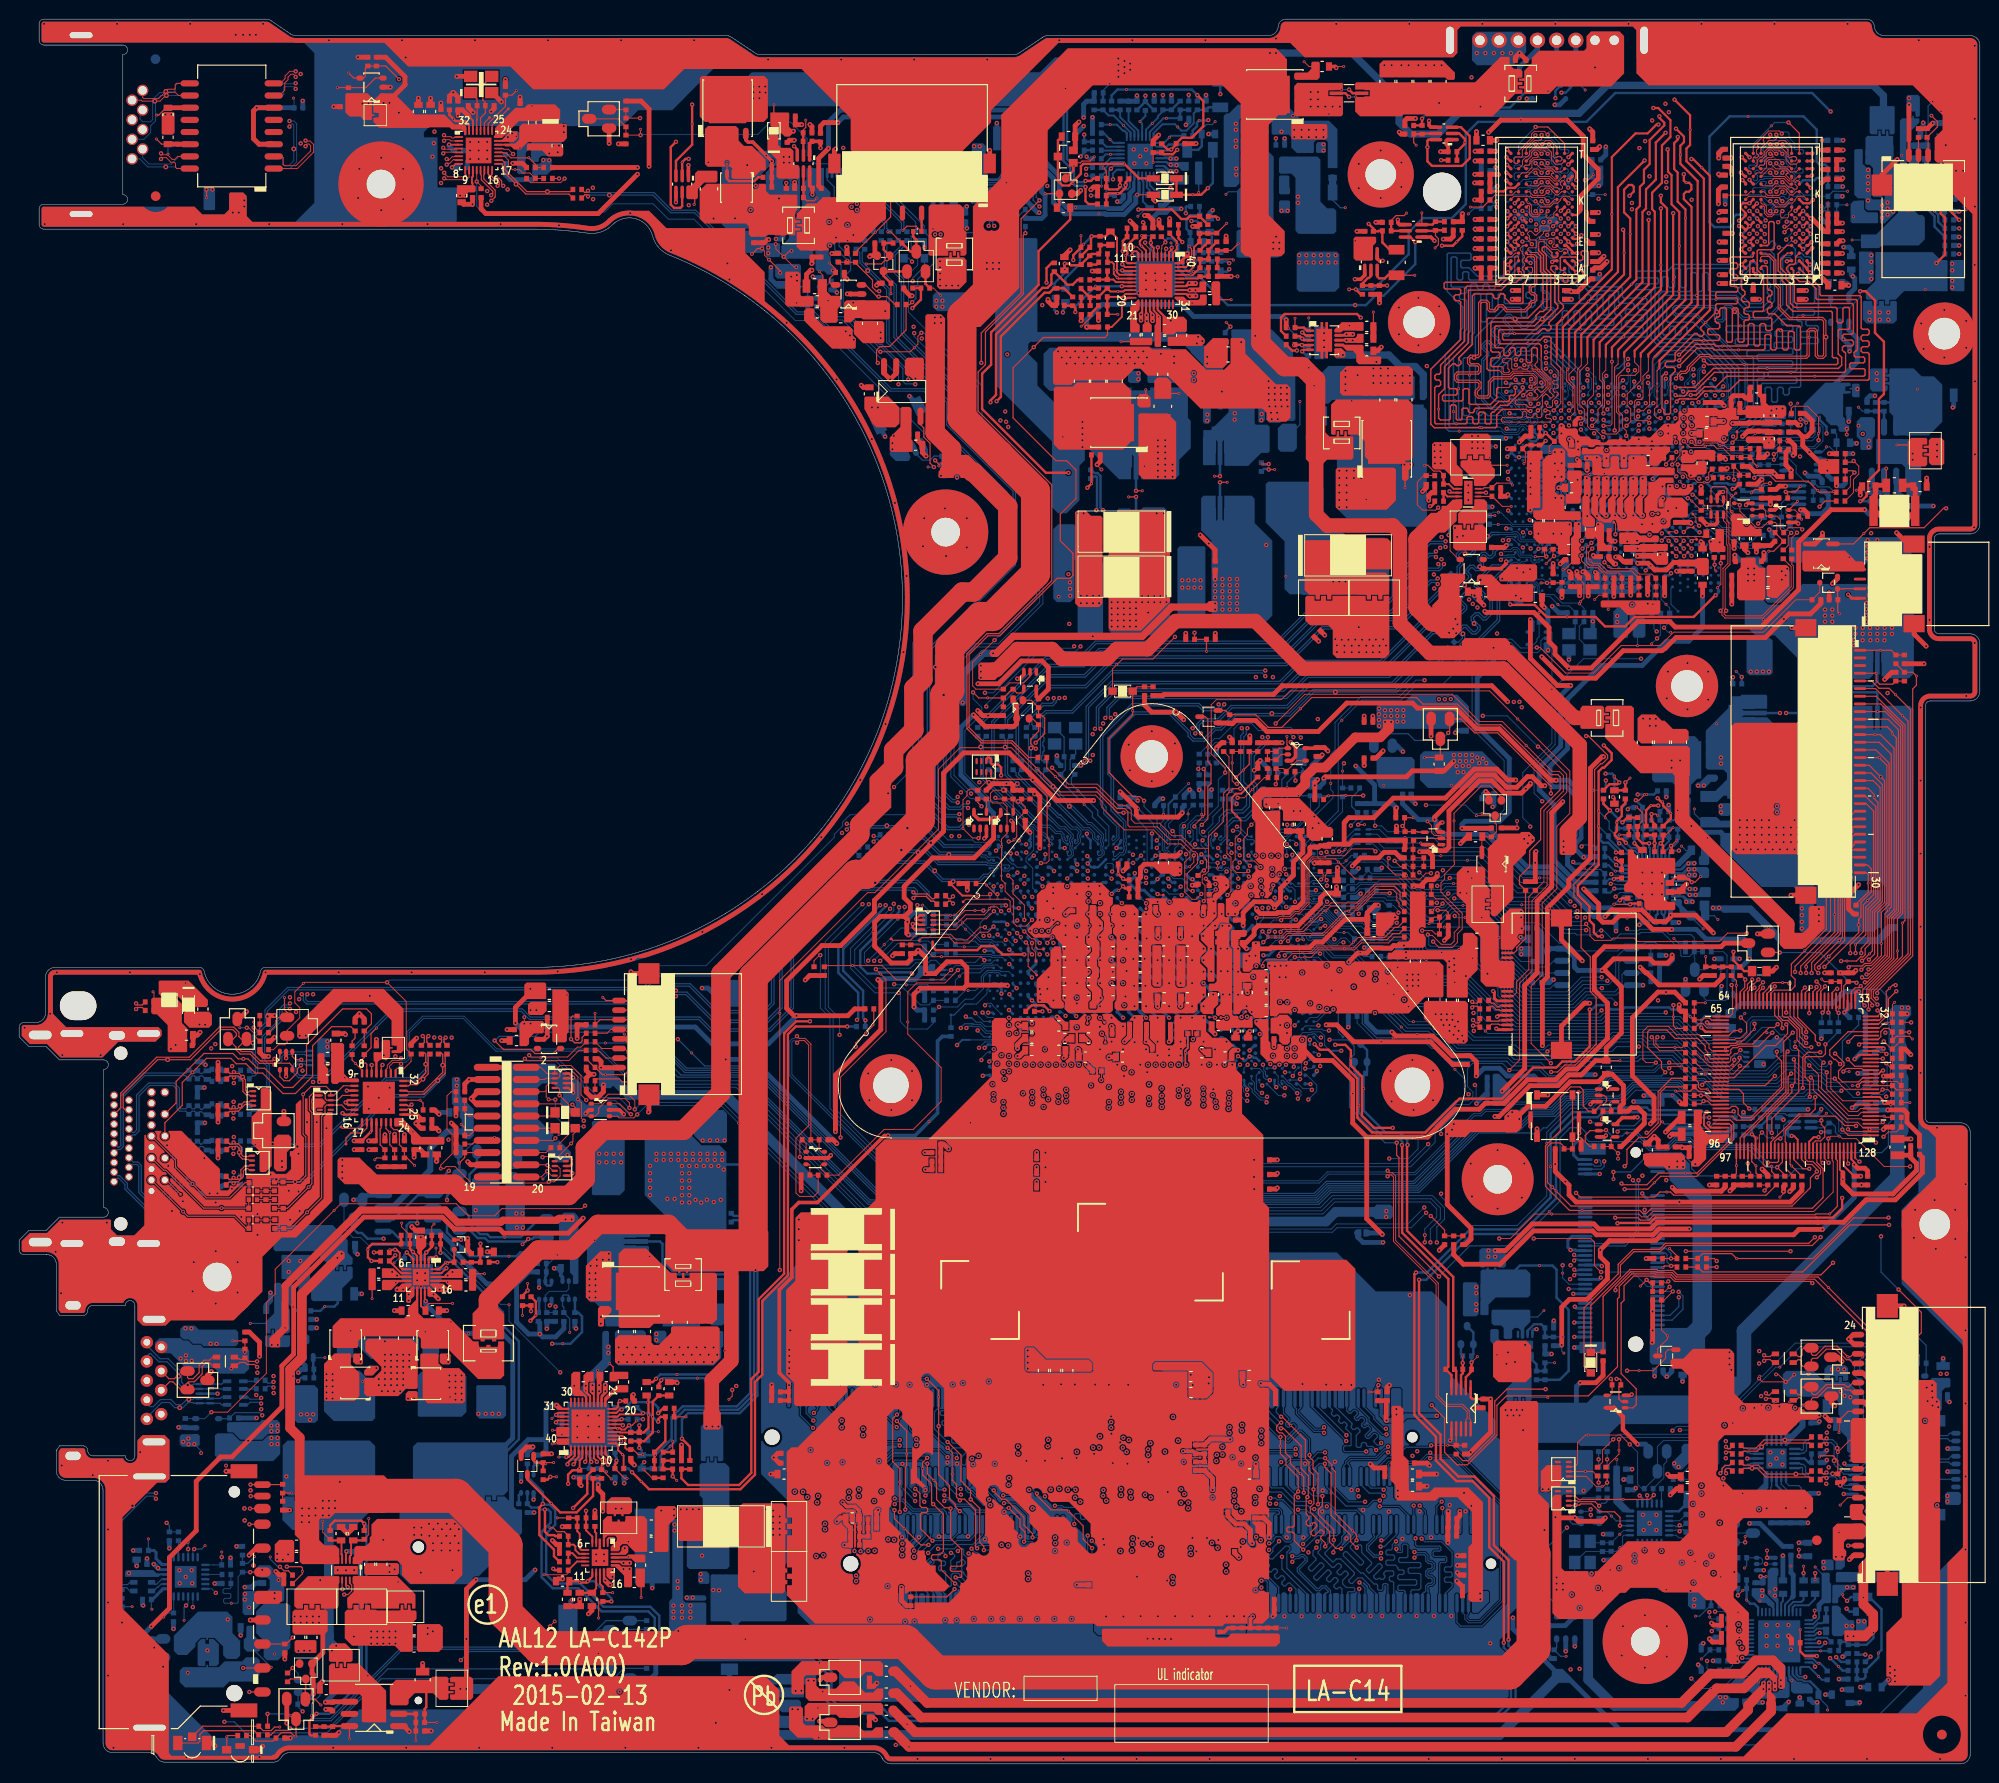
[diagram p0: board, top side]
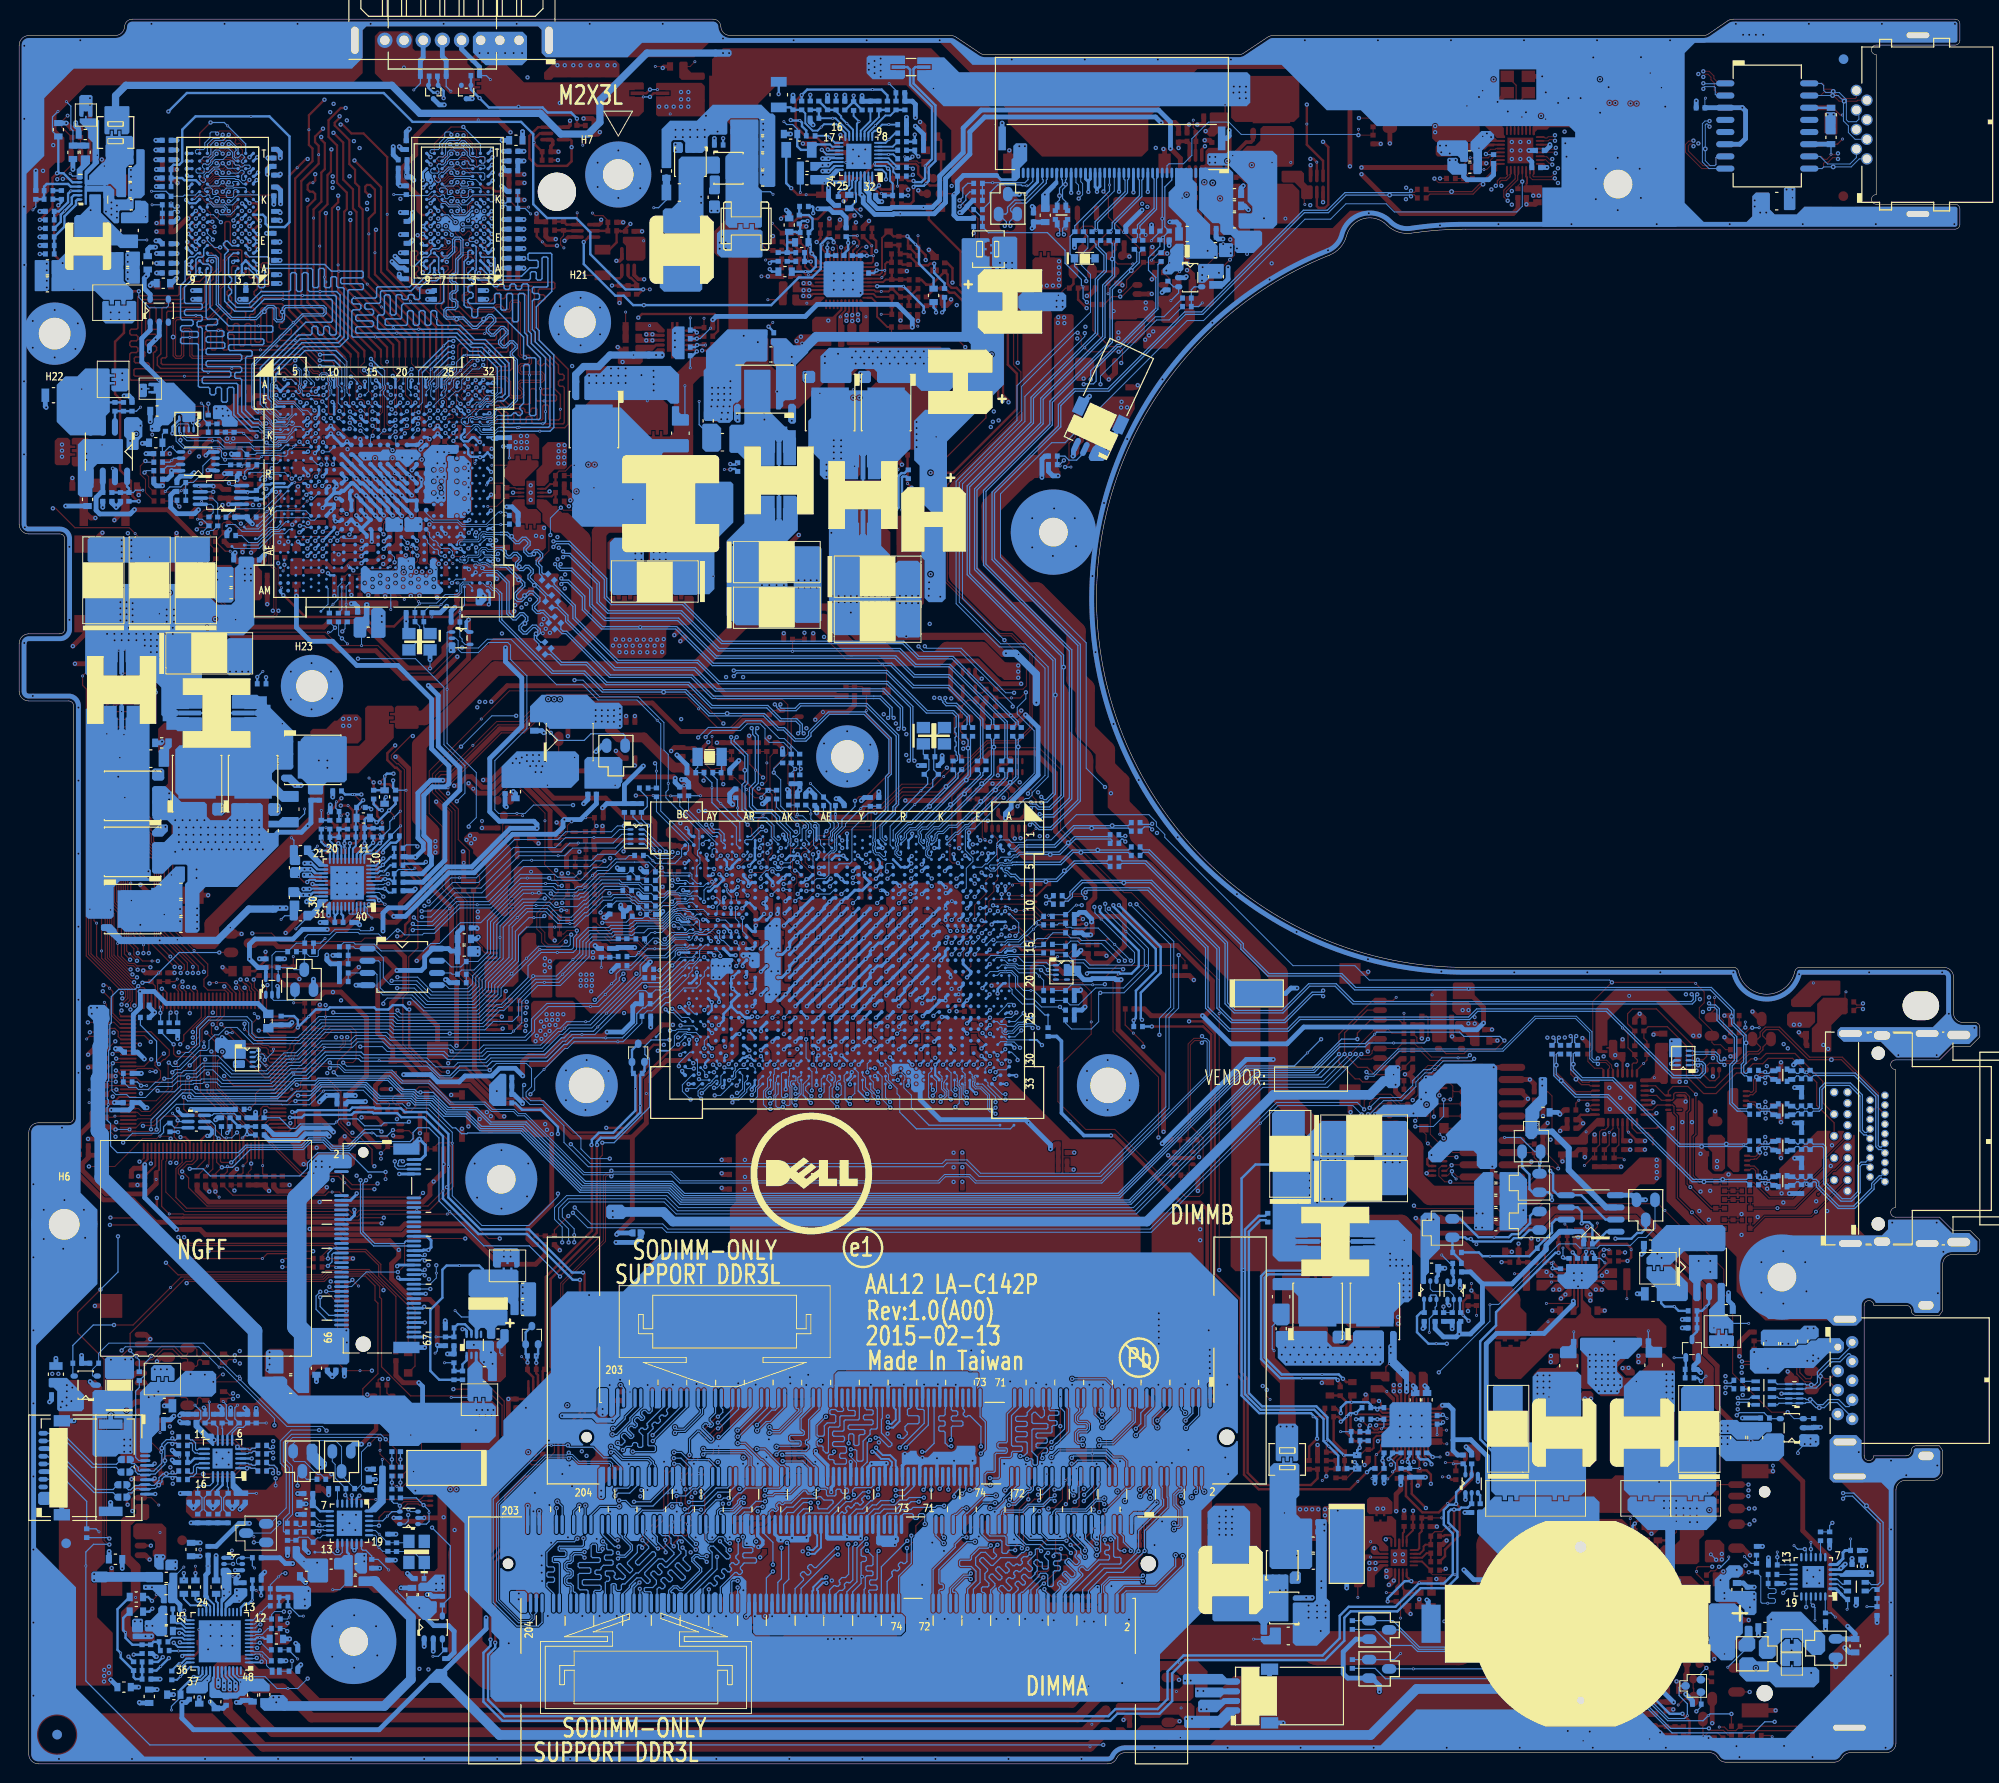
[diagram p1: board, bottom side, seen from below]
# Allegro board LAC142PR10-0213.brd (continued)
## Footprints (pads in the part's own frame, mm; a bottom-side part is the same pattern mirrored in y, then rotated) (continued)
ACES_50208-01001-001_10P
  oval 0.508x0.991 smd: 1(0,0) 2(0.8,0) 3(1.6,0) 4(2.4,0) 5(3.2,0) 6(4,0) 7(4.8,0) 8(5.6,0) 9(6.4,0) 10(7.2,0)
  rect 1.194x1.702 smd: 11(-1.3,-1.95) 12(8.5,-1.95)
ACES_50224-0030N-001_3P-T
  oval 0.61x1.549 smd: 1(0,0) 2(1,0) 3(2,0)
  rect 1.194x1.803 smd: 4(3.3,-3.875) 5(-1.3,-3.875)
ACES_50224-0040N-001_4P-T
  oval 0.61x1.549 smd: 1(0,0) 2(1,0) 3(2,0) 4(3,0)
  rect 1.194x1.803 smd: 5(-1.3,-3.875) 6(4.3,-3.875)
ACES_50458-00601-001_6P-T
  oval 0.559x1.6 smd: 1(0,0) 2(2,0) 3(4,0) 4(6,0) 5(8,0) 6(10,0)
  rect 1.295x2.057 smd: 7(-3.1,-5.175) 8(13.1,-5.175)
ACES_50524-00401-P01_4P
  oval 0.305x1.295 smd: 1(0,0) 2(1,0) 3(2,0) 4(3,0)
  rect 1.803x2.21 smd: 5(5.65,-5.65) 6(-2.65,-5.65)
ACES_51510-0304N-P01_30P
  oval 0.305x1.295 smd: 1(0,0) 2(0.8,0) 3(1.6,0) 4(2.4,0) 5(3.2,0) 6(4,0) 7(4.8,0) 8(5.6,0) 9(6.4,0) 10(7.2,0) 11(8,0) 12(8.8,0) 13(9.6,0) 14(10.4,0) 15(11.2,0) 16(12,0) 17(12.8,0) 18(13.6,0) 19(14.4,0) 20(15.2,0) 21(16,0) 22(16.8,0) 23(17.6,0) 24(18.4,0) 25(19.2,0) 26(20,0) 27(20.8,0) 28(21.6,0) 29(22.4,0) 30(23.2,0)
  rect 1.803x2.21 smd: 31(25.55,-5.65) 32(-2.35,-5.65)
ACES_51519-02001-001_20P-T
  oval 0.305x1.295 smd: 1(0,0) 2(0.5,0) 3(1,0) 4(1.5,0) 5(2,0) 6(2.5,0) 7(3,0) 8(3.5,0) 9(4,0) 10(4.5,0) 11(5,0) 12(5.5,0) 13(6,0) 14(6.5,0) 15(7,0) 16(7.5,0) 17(8,0) 18(8.5,0) 19(9,0) 20(9.5,0)
  rect 1.803x2.21 smd: 21(11.65,-5.65) 22(-2.15,-5.65)
ACES_51524-0240N-001_24P
  oval 0.61x1.295 smd: 1(0,0) 2(1,0) 3(2,0) 4(3,0) 5(4,0) 6(5,0) 7(6,0) 8(7,0) 9(8,0) 10(9,0) 11(10,0) 12(11,0) 13(12,0) 14(13,0) 15(14,0) 16(15,0) 17(16,0) 18(17,0) 19(18,0) 20(19,0) 21(20,0) 22(21,0) 23(22,0) 24(23,0)
  rect 2.489x2.21 smd: 25(-3,-3.05) 26(26,-3.05)
ACES_51540-04001-P01_40P-T
  oval 0.305x1.092 smd: 1(0,0) 2(0.5,0) 3(1,0) 4(1.5,0) 5(2,0) 6(2.5,0) 7(3,0) 8(3.5,0) 9(4,0) 10(4.5,0) 11(5,0) 12(5.5,0) 13(6,0) 14(6.5,0) 15(7,0) 16(7.5,0) 17(8,0) 18(8.5,0) 19(9,0) 20(9.5,0) 21(10,0) 22(10.5,0) 23(11,0) 24(11.5,0) 25(12,0) 26(12.5,0) 27(13,0) 28(13.5,0) 29(14,0) 30(14.5,0) 31(15,0) 32(15.5,0) 33(16,0) 34(16.5,0) 35(17,0) 36(17.5,0) 37(18,0) 38(18.5,0) 39(19,0) 40(19.5,0)
  rect 0.787x2.489 smd: 41(21.2,-3.6) 42(-1.7,-3.6)
ACES_51625-01201-001_12P-T
  oval 0.305x1.092 smd: 1(0,0) 2(0.5,0) 3(1,0) 4(1.5,0) 5(2,0) 6(2.5,0) 7(3,0) 8(3.5,0) 9(4,0) 10(4.5,0) 11(5,0) 12(5.5,0)
  rect 0.991x2.489 smd: 13(7.3,-3.6) 14(-1.8,-3.6)
ADM1032ARMZ_MSOP8
  oval 0.381x1.626 smd: 1(0,0) 2(0.65,0) 3(1.3,0) 4(1.95,0) 5(1.95,4.3) 6(1.3,4.3) 7(0.65,4.3) 8(0,4.3)
ALC3234-CG_MQFN48_6X6
  oval 0.203x0.889 smd: 1(0,0) 2(0.4,0) 3(0.8,0) 4(1.2,0) 5(1.6,0) 6(2,0) 7(2.4,0) 8(2.8,0) 9(3.2,0) 10(3.6,0) 11(4,0) 12(4.4,0) 25(4.4,6.1) 26(4,6.1) 27(3.6,6.1) 28(3.2,6.1) 29(2.8,6.1) 30(2.4,6.1) 31(2,6.1) 32(1.6,6.1) 33(1.2,6.1) 34(0.8,6.1) 35(0.4,6.1) 36(0,6.1)
  oval 0.889x0.203 smd: 13(5.25,0.85) 14(5.25,1.25) 15(5.25,1.65) 16(5.25,2.05) 17(5.25,2.45) 18(5.25,2.85) 19(5.25,3.25) 20(5.25,3.65) 21(5.25,4.05) 22(5.25,4.45) 23(5.25,4.85) 24(5.25,5.25) 37(-0.85,5.25) 38(-0.85,4.85) 39(-0.85,4.45) 40(-0.85,4.05) 41(-0.85,3.65) 42(-0.85,3.25) 43(-0.85,2.85) 44(-0.85,2.45) 45(-0.85,2.05) 46(-0.85,1.65) 47(-0.85,1.25) 48(-0.85,0.85)
  rect 4.394x4.394 smd: 49(2.2,3.05)
AO3416_SOT23-3
  oval 1.016x1.524 smd: 1(0,0) 2(0.965,2.083) 3(-0.965,2.083)
AO4430L_SO8
  oval 0.635x1.854 smd: 1(0,0) 2(1.27,0) 3(2.54,0) 4(3.81,0) 5(3.81,5.165) 6(2.54,5.165) 7(1.27,5.165) 8(0,5.165)
AON6970_DFN5X6D-8-7
  oval 0.66x0.635 smd: 1(0,0) 3(3.81,5.67) 4(2.54,5.67) 5(1.27,5.67) 6(0,5.67)
  custom 0.485x0.485 smd: 2(1.905,0.655)
  rect 3.988x2.667 smd: 7(1.905,3.62)
AP2138N-1P5TRG1_SOT23-3
  oval 1.016x1.524 smd: 1(0,0) 2(0.965,2.083) 3(-0.965,2.083)
APL3512ABI-TRG_SOT23-5
  oval 0.61x1.041 smd: 1(0,0) 2(0.95,0) 3(1.9,0) 4(1.9,2.7) 5(0,2.7)
APL5336KAI-TRL_SOP8P8
  oval 0.635x1.854 smd: 1(0,0) 2(1.27,0) 3(2.54,0) 4(3.81,0) 5(3.81,5.165) 6(2.54,5.165) 7(1.27,5.165) 8(0,5.165)
  rect 2.87x2.489 smd: 9(1.905,2.582)
APL5930KAI-TRG_SO8
  oval 0.635x1.854 smd: 1(0,0) 2(1.27,0) 3(2.54,0) 4(3.81,0) 5(3.81,5.165) 6(2.54,5.165) 7(1.27,5.165) 8(0,5.165)
  rect 2.87x2.489 smd: 9(1.905,2.582)
AZ5125-02SPR7G_SOT23-3
  oval 1.016x1.524 smd: 1(0,0) 2(0.965,2.083) 3(-0.965,2.083)
BAS40-04_SOT23-3
  oval 1.016x1.524 smd: 1(0,0) 2(0.965,2.083) 3(-0.965,2.083)
BAT54C-7-F_SOT23-3
  oval 1.016x1.524 smd: 1(0,0) 2(0.965,2.083) 3(-0.965,2.083)
C-K_80461-5K1-152_15P-T-S
  round 0.889 hole 0.61: 1(0,0) 2(2.29,0) 3(4.58,0) 4(6.87,0) 5(9.16,0) 6(-1.145,0) 7(1.145,0) 8(3.435,0) 9(5.725,0) 10(8.015,0) 11(0,1.4) 12(2.29,1.4) 13(4.58,1.4) 14(6.87,1.4) 15(9.16,1.4)
  oval 1.016x2.692 hole 0.711x2.388: 16(15.28,-8.3) 17(15.28,-0.3) 18(-6.62,-0.3) 19(-6.62,-8.3)
C-K_96067-3K28-192-124_19P-T
  round 1.397 hole 1.397 unplated: (-4.4,0.7) (13.4,0.7)
  round 0.813 hole 0.559: 1(0,0) 2(0.5,1.55) 3(1,0) 4(1.5,1.55) 5(2,0) 6(2.5,1.55) 7(3,0) 8(3.5,1.55) 9(4,0) 10(4.5,1.55) 11(5,0) 12(5.5,1.55) 13(6,0) 14(6.5,1.55) 15(7,0) 16(7.5,1.55) 17(8,0) 18(8.5,1.55) 19(9,0)
  oval 1.194x2.692 hole 0.889x2.388: 20(15.3,-7.7) 23(-6.3,-7.7)
  oval 1.194x2.007 hole 0.889x1.702: 21(15.25,0.3) 22(-6.25,0.3)
C_0402
  rect 0.508x0.559 smd: 1(0,0) 2(0.914,0)
C_0603
  rect 0.635x0.889 smd: 1(0,0) 2(1.397,0)
C_0805
  rect 0.813x1.397 smd: 1(0,0) 2(1.702,0)
C_1206
  rect 1.016x1.651 smd: 1(0,0) 2(2.667,0)
C_B15G
  rect 1.6x2.692 smd: 1(0,0) 2(3,0)
C_D2
  rect 2.388x2.794 smd: 1(0,0) 2(6.4,0)
C_D3
  rect 2.388x2.794 smd: 1(0,0) 2(6.4,0)
C_VSS330M1ETR-0604
  oval 3.505x1.6 smd: 1(0,0) 2(-5.4,0)
CHILI_SBY100505T-470Y-N_2P
  rect 0.457x0.508 smd: 1(0,0) 2(0.85,0)
CY7C65211-24LTXI_QFN24_4X4
  oval 0.254x0.889 smd: 1(0,0) 2(0.5,0) 3(1,0) 4(1.5,0) 5(2,0) 6(2.5,0) 13(2.5,4.1) 14(2,4.1) 15(1.5,4.1) 16(1,4.1) 17(0.5,4.1) 18(0,4.1)
  oval 0.889x0.254 smd: 7(3.3,0.8) 8(3.3,1.3) 9(3.3,1.8) 10(3.3,2.3) 11(3.3,2.8) 12(3.3,3.3) 19(-0.8,3.3) 20(-0.8,2.8) 21(-0.8,2.3) 22(-0.8,1.8) 23(-0.8,1.3) 24(-0.8,0.8)
  rect 2.642x2.642 smd: 25(1.25,2.05)
CYNTE_PCMB053T-1R0MS_2P
  rect 1.905x2.794 smd: 1(0,0) 2(4.1,0)
CYNTE_PCMB104T-1R0MH_2P
  rect 3.81x3.988 smd: 1(0,0) 2(9.2,0)
DAN05-67406-0100_67P-T
  round 1.092 hole 1.092 unplated: (-0.75,-5.275)
  round 1.6 hole 1.6 unplated: (19.25,-5.275)
  oval 0.305x1.549 smd: 1(0,0) 2(0.25,-7.55) 3(0.5,0) 4(0.75,-7.55) 5(1,0) 6(1.25,-7.55) 7(1.5,0) 8(3.75,-7.55) 9(4,0) 10(4.25,-7.55) 11(4.5,0) 12(4.75,-7.55) 13(5,0) 14(5.25,-7.55) 15(5.5,0) 16(5.75,-7.55) 17(6,0) 18(6.25,-7.55) 19(6.5,0) 20(6.75,-7.55) 21(7,0) 22(7.25,-7.55) 23(7.5,0) 24(7.75,-7.55) 25(8,0) 26(8.25,-7.55) 27(8.5,0) 28(8.75,-7.55) 29(9,0) 30(9.25,-7.55) 31(9.5,0) 32(9.75,-7.55) 33(10,0) 34(10.25,-7.55) 35(10.5,0) 36(10.75,-7.55) 37(11,0) 38(11.25,-7.55) 39(11.5,0) 40(11.75,-7.55) 41(12,0) 42(12.25,-7.55) 43(12.5,0) 44(12.75,-7.55) 45(13,0) 46(13.25,-7.55) 47(13.5,0) 48(13.75,-7.55) 49(14,0) 50(14.25,-7.55) 51(14.5,0) 52(14.75,-7.55) 53(15,0) 54(15.25,-7.55) 55(15.5,0) 56(15.75,-7.55) 57(16,0) 58(16.25,-7.55) 59(16.5,0) 60(16.75,-7.55) 61(17,0) 62(17.25,-7.55) 63(17.5,0) 64(17.75,-7.55) 65(18,0) 66(18.25,-7.55) 67(18.5,0)
  rect 1.194x2.743 smd: 68(-1.1,-0.775) 69(19.6,-0.775)
DB2J31400L_SOD323-2
  rect 0.991x1.092 smd: 1(0,0)
  rect 0.991x0.889 smd: 2(2.1,0)
DMN66D0LDW-7_SOT363-6
  oval 0.432x0.61 smd: 1(0,0) 2(0.65,0) 3(1.3,0) 4(1.3,1.9) 5(0.65,1.9) 6(0,1.9)
DTA144EUA_SC70-3
  rect 0.813x0.914 smd: 1(0,0) 2(0.65,1.6) 3(-0.65,1.6)
DTC115EUA_SC70-3
  oval 0.813x0.914 smd: 1(0,0) 2(0.65,1.6) 3(-0.65,1.6)
EMC1403-2-AIZL-TR_MSOP10
  oval 0.254x1.626 smd: 1(0,0) 2(0.5,0) 3(1,0) 4(1.5,0) 5(2,0) 6(2,4.3) 7(1.5,4.3) 8(1,4.3) 9(0.5,4.3) 10(0,4.3)
EMIST-SQ-26G_1P
  rect 5.105x2.794 smd: 1(0,0)
EMIST_SQ-55G_1P
  rect 7.798x3.658 smd: 1(0,0)
F_1206L150PR
  rect 0.991x1.803 smd: 1(0,0) 2(2.8,0)
F_1812L075-24DR
  rect 0.889x3.15 smd: 1(0,0) 2(4.35,0)
FDV301N_NL_SOT23-3
  oval 1.016x1.524 smd: 1(0,0) 2(0.965,2.083) 3(-0.965,2.083)
FIDUCIAL_C40M80
  round 1.016 smd: 1(0,0)
FOX_AS0A621-J4RB-7H_204P
  round 1.092 hole 1.092 unplated: (-65.05,-4.1)
  round 1.6 hole 1.6 unplated: (1.75,-4.1)
  oval 0.356x2.007 smd: 1(0,0) 2(-0.3,-8.2) 3(-0.6,0) 4(-0.9,-8.2) 5(-1.2,0) 6(-1.5,-8.2) 7(-1.8,0) 8(-2.1,-8.2) 9(-2.4,0) 10(-2.7,-8.2) 11(-3,0) 12(-3.3,-8.2) 13(-3.6,0) 14(-3.9,-8.2) 15(-4.2,0) 16(-4.5,-8.2) 17(-4.8,0) 18(-5.1,-8.2) 19(-5.4,0) 20(-5.7,-8.2) 21(-6,0) 22(-6.3,-8.2) 23(-6.6,0) 24(-6.9,-8.2) 25(-7.2,0) 26(-7.5,-8.2) 27(-7.8,0) 28(-8.1,-8.2) 29(-8.4,0) 30(-8.7,-8.2) 31(-9,0) 32(-9.3,-8.2) 33(-9.6,0) 34(-9.9,-8.2) 35(-10.2,0) 36(-10.5,-8.2) 37(-10.8,0) 38(-11.1,-8.2) 39(-11.4,0) 40(-11.7,-8.2) 41(-12,0) 42(-12.3,-8.2) 43(-12.6,0) 44(-12.9,-8.2) 45(-13.2,0) 46(-13.5,-8.2) 47(-13.8,0) 48(-14.1,-8.2) 49(-14.4,0) 50(-14.7,-8.2) 51(-15,0) 52(-15.3,-8.2) 53(-15.6,0) 54(-15.9,-8.2) 55(-16.2,0) 56(-16.5,-8.2) 57(-16.8,0) 58(-17.1,-8.2) 59(-17.4,0) 60(-17.7,-8.2) 61(-18,0) 62(-18.3,-8.2) 63(-18.6,0) 64(-18.9,-8.2) 65(-19.2,0) 66(-19.5,-8.2) 67(-19.8,0) 68(-20.1,-8.2) 69(-20.4,0) 70(-20.7,-8.2) 71(-21,0) 72(-21.3,-8.2) 73(-24,0) 74(-24.3,-8.2) 75(-24.6,0) 76(-24.9,-8.2) 77(-25.2,0) 78(-25.5,-8.2) 79(-25.8,0) 80(-26.1,-8.2) 81(-26.4,0) 82(-26.7,-8.2) 83(-27,0) 84(-27.3,-8.2) 85(-27.6,0) 86(-27.9,-8.2) 87(-28.2,0) 88(-28.5,-8.2) 89(-28.8,0) 90(-29.1,-8.2) 91(-29.4,0) 92(-29.7,-8.2) 93(-30,0) 94(-30.3,-8.2) 95(-30.6,0) 96(-30.9,-8.2) 97(-31.2,0) 98(-31.5,-8.2) 99(-31.8,0) 100(-32.1,-8.2) 101(-32.4,0) 102(-32.7,-8.2) 103(-33,0) 104(-33.3,-8.2) 105(-33.6,0) 106(-33.9,-8.2) 107(-34.2,0) 108(-34.5,-8.2) 109(-34.8,0) 110(-35.1,-8.2) 111(-35.4,0) 112(-35.7,-8.2) 113(-36,0) 114(-36.3,-8.2) 115(-36.6,0) 116(-36.9,-8.2) 117(-37.2,0) 118(-37.5,-8.2) 119(-37.8,0) 120(-38.1,-8.2) 121(-38.4,0) 122(-38.7,-8.2) 123(-39,0) 124(-39.3,-8.2) 125(-39.6,0) 126(-39.9,-8.2) 127(-40.2,0) 128(-40.5,-8.2) 129(-40.8,0) 130(-41.1,-8.2) 131(-41.4,0) 132(-41.7,-8.2) 133(-42,0) 134(-42.3,-8.2) 135(-42.6,0) 136(-42.9,-8.2) 137(-43.2,0) 138(-43.5,-8.2) 139(-43.8,0) 140(-44.1,-8.2) 141(-44.4,0) 142(-44.7,-8.2) 143(-45,0) 144(-45.3,-8.2) 145(-45.6,0) 146(-45.9,-8.2) 147(-46.2,0) 148(-46.5,-8.2) 149(-46.8,0) 150(-47.1,-8.2) 151(-47.4,0) 152(-47.7,-8.2) 153(-48,0) 154(-48.3,-8.2) 155(-48.6,0) 156(-48.9,-8.2) 157(-49.2,0) 158(-49.5,-8.2) 159(-49.8,0) 160(-50.1,-8.2) 161(-50.4,0) 162(-50.7,-8.2) 163(-51,0) 164(-51.3,-8.2) 165(-51.6,0) 166(-51.9,-8.2) 167(-52.2,0) 168(-52.5,-8.2) 169(-52.8,0) 170(-53.1,-8.2) 171(-53.4,0) 172(-53.7,-8.2) 173(-54,0) 174(-54.3,-8.2) 175(-54.6,0) 176(-54.9,-8.2) 177(-55.2,0) 178(-55.5,-8.2) 179(-55.8,0) 180(-56.1,-8.2) 181(-56.4,0) 182(-56.7,-8.2) 183(-57,0) 184(-57.3,-8.2) 185(-57.6,0) 186(-57.9,-8.2) 187(-58.2,0) 188(-58.5,-8.2) 189(-58.8,0) 190(-59.1,-8.2) 191(-59.4,0) 192(-59.7,-8.2) 193(-60,0) 194(-60.3,-8.2) 195(-60.6,0) 196(-60.9,-8.2) 197(-61.2,0) 198(-61.5,-8.2) 199(-61.8,0) 200(-62.1,-8.2) 201(-62.4,0) 202(-62.7,-8.2) 203(-63,0) 204(-63.3,-8.2)
  rect 3.505x4.597 smd: 205(1.15,7.9) 206(-64.45,7.9)
FOX_AS0A621-J4SB-7H_204P
  round 1.6 hole 1.6 unplated: (-1.75,4.1)
  round 1.092 hole 1.092 unplated: (65.05,4.1)
  oval 0.356x2.007 smd: 1(0,0) 2(0.3,8.2) 3(0.6,0) 4(0.9,8.2) 5(1.2,0) 6(1.5,8.2) 7(1.8,0) 8(2.1,8.2) 9(2.4,0) 10(2.7,8.2) 11(3,0) 12(3.3,8.2) 13(3.6,0) 14(3.9,8.2) 15(4.2,0) 16(4.5,8.2) 17(4.8,0) 18(5.1,8.2) 19(5.4,0) 20(5.7,8.2) 21(6,0) 22(6.3,8.2) 23(6.6,0) 24(6.9,8.2) 25(7.2,0) 26(7.5,8.2) 27(7.8,0) 28(8.1,8.2) 29(8.4,0) 30(8.7,8.2) 31(9,0) 32(9.3,8.2) 33(9.6,0) 34(9.9,8.2) 35(10.2,0) 36(10.5,8.2) 37(10.8,0) 38(11.1,8.2) 39(11.4,0) 40(11.7,8.2) 41(12,0) 42(12.3,8.2) 43(12.6,0) 44(12.9,8.2) 45(13.2,0) 46(13.5,8.2) 47(13.8,0) 48(14.1,8.2) 49(14.4,0) 50(14.7,8.2) 51(15,0) 52(15.3,8.2) 53(15.6,0) 54(15.9,8.2) 55(16.2,0) 56(16.5,8.2) 57(16.8,0) 58(17.1,8.2) 59(17.4,0) 60(17.7,8.2) 61(18,0) 62(18.3,8.2) 63(18.6,0) 64(18.9,8.2) 65(19.2,0) 66(19.5,8.2) 67(19.8,0) 68(20.1,8.2) 69(20.4,0) 70(20.7,8.2) 71(21,0) 72(21.3,8.2) 73(24,0) 74(24.3,8.2) 75(24.6,0) 76(24.9,8.2) 77(25.2,0) 78(25.5,8.2) 79(25.8,0) 80(26.1,8.2) 81(26.4,0) 82(26.7,8.2) 83(27,0) 84(27.3,8.2) 85(27.6,0) 86(27.9,8.2) 87(28.2,0) 88(28.5,8.2) 89(28.8,0) 90(29.1,8.2) 91(29.4,0) 92(29.7,8.2) 93(30,0) 94(30.3,8.2) 95(30.6,0) 96(30.9,8.2) 97(31.2,0) 98(31.5,8.2) 99(31.8,0) 100(32.1,8.2) 101(32.4,0) 102(32.7,8.2) 103(33,0) 104(33.3,8.2) 105(33.6,0) 106(33.9,8.2) 107(34.2,0) 108(34.5,8.2) 109(34.8,0) 110(35.1,8.2) 111(35.4,0) 112(35.7,8.2) 113(36,0) 114(36.3,8.2) 115(36.6,0) 116(36.9,8.2) 117(37.2,0) 118(37.5,8.2) 119(37.8,0) 120(38.1,8.2) 121(38.4,0) 122(38.7,8.2) 123(39,0) 124(39.3,8.2) 125(39.6,0) 126(39.9,8.2) 127(40.2,0) 128(40.5,8.2) 129(40.8,0) 130(41.1,8.2) 131(41.4,0) 132(41.7,8.2) 133(42,0) 134(42.3,8.2) 135(42.6,0) 136(42.9,8.2) 137(43.2,0) 138(43.5,8.2) 139(43.8,0) 140(44.1,8.2) 141(44.4,0) 142(44.7,8.2) 143(45,0) 144(45.3,8.2) 145(45.6,0) 146(45.9,8.2) 147(46.2,0) 148(46.5,8.2) 149(46.8,0) 150(47.1,8.2) 151(47.4,0) 152(47.7,8.2) 153(48,0) 154(48.3,8.2) 155(48.6,0) 156(48.9,8.2) 157(49.2,0) 158(49.5,8.2) 159(49.8,0) 160(50.1,8.2) 161(50.4,0) 162(50.7,8.2) 163(51,0) 164(51.3,8.2) 165(51.6,0) 166(51.9,8.2) 167(52.2,0) 168(52.5,8.2) 169(52.8,0) 170(53.1,8.2) 171(53.4,0) 172(53.7,8.2) 173(54,0) 174(54.3,8.2) 175(54.6,0) 176(54.9,8.2) 177(55.2,0) 178(55.5,8.2) 179(55.8,0) 180(56.1,8.2) 181(56.4,0) 182(56.7,8.2) 183(57,0) 184(57.3,8.2) 185(57.6,0) 186(57.9,8.2) 187(58.2,0) 188(58.5,8.2) 189(58.8,0) 190(59.1,8.2) 191(59.4,0) 192(59.7,8.2) 193(60,0) 194(60.3,8.2) 195(60.6,0) 196(60.9,8.2) 197(61.2,0) 198(61.5,8.2) 199(61.8,0) 200(62.1,8.2) 201(62.4,0) 202(62.7,8.2) 203(63,0) 204(63.3,8.2)
  rect 3.505x4.597 smd: 205(-1.15,16.1) 206(64.45,16.1)
FP4_BGA_968P-T
  round 0.406 smd: A2(0.9,0) A3(1.8,0) A31(24,0) A32(24.9,0) AB5(3.2,-16.9) AB6(4,-16.9) AB7(4.8,-16.9) AB8(5.6,-16.9) AB9(6.4,-16.9) AB10(7.5,-16.9) AB12(8.7,-16.9) AB13(9.9,-16.9) AB15(11.1,-16.9) AB16(12.3,-16.9) AB18(13.5,-16.9) AB19(14.7,-16.9) AB21(15.9,-16.9) AB22(17.1,-16.9) AB24(18.3,-16.9) AB25(19.4,-16.9) AB26(20.2,-16.9) AB27(21,-16.9) AB28(21.8,-16.9) AB29(22.6,-16.9) AD5(3.2,-18.1) AD6(4,-18.1) AD7(4.8,-18.1) AD8(5.6,-18.1) AD9(6.4,-18.1) AD10(7.5,-18.1) AD12(8.7,-18.1) AD13(9.9,-18.1) AD15(11.1,-18.1) AD16(12.3,-18.1) AD18(13.5,-18.1) AD19(14.7,-18.1) AD21(15.9,-18.1) AD22(17.1,-18.1) AD24(18.3,-18.1) AD25(19.4,-18.1) AD26(20.2,-18.1) AD27(21,-18.1) AD28(21.8,-18.1) AD29(22.6,-18.1) AE5(3.2,-19.3) AE6(4,-19.3) AE7(4.8,-19.3) AE8(5.6,-19.3) AE9(6.4,-19.3) AE10(7.5,-19.3) AE12(8.7,-19.3) AE13(9.9,-19.3) AE15(11.1,-19.3) AE16(12.3,-19.3) AE18(13.5,-19.3) AE19(14.7,-19.3) AE21(15.9,-19.3) AE22(17.1,-19.3) AE24(18.3,-19.3) AE25(19.4,-19.3) AE26(20.2,-19.3) AE27(21,-19.3) AE28(21.8,-19.3) AE29(22.6,-19.3) AG5(3.2,-20.5) AG6(4,-20.5) AG7(4.8,-20.5) AG8(5.6,-20.5) AG9(6.4,-20.5) AG10(7.5,-20.5) AG12(8.7,-20.5) AG13(9.9,-20.5) AG15(11.1,-20.5) AG16(12.3,-20.5) AG18(13.5,-20.5) AG19(14.7,-20.5) AG21(15.9,-20.5) AG22(17.1,-20.5) AG24(18.3,-20.5) AG25(19.4,-20.5) AG26(20.2,-20.5) AG27(21,-20.5) AG28(21.8,-20.5) AG29(22.6,-20.5) AH5(3.2,-21.7) AH6(4,-21.7) AH7(4.8,-21.7) AH8(5.6,-21.7) AH9(6.4,-21.7) AH10(7.5,-21.7) AH12(8.7,-21.7) AH13(9.9,-21.7) AH15(11.1,-21.7) AH16(12.3,-21.7) AH18(13.5,-21.7) AH19(14.7,-21.7) AH21(15.9,-21.7) AH22(17.1,-21.7) AH24(18.3,-21.7) AH25(19.4,-21.7) AH26(20.2,-21.7) AH27(21,-21.7) AH28(21.8,-21.7) AH29(22.6,-21.7) AK5(3.2,-22.9) AK6(4,-22.9) AK7(4.8,-22.9) AK8(5.6,-22.9) AK9(6.4,-22.9) AK10(7.5,-22.9) AK12(8.7,-22.9) AK13(9.9,-22.9) AK15(11.1,-22.9) AK16(12.3,-22.9) AK18(13.5,-22.9) AK19(14.7,-22.9) AK21(15.9,-22.9) AK22(17.1,-22.9) AK24(18.3,-22.9) AK25(19.4,-22.9) AK26(20.2,-22.9) AK27(21,-22.9) AK28(21.8,-22.9) AK29(22.6,-22.9) AL5(3.2,-24.1) AL6(4,-24.1) AL7(4.8,-24.1) AL8(5.6,-24.1) AL9(6.4,-24.1) AL10(7.5,-24.1) AL12(8.7,-24.1) AL13(9.9,-24.1) AL15(11.1,-24.1) AL16(12.3,-24.1) AL18(13.5,-24.1) AL19(14.7,-24.1) AL21(15.9,-24.1) AL22(17.1,-24.1) AL24(18.3,-24.1) AL25(19.4,-24.1) AL26(20.2,-24.1) AL27(21,-24.1) AL28(21.8,-24.1) AL29(22.6,-24.1) AN5(3.2,-25.3) AN6(4,-25.3) AN7(4.8,-25.3) AN8(5.6,-25.3) AN9(6.4,-25.3) AN10(7.5,-25.3) AN12(8.7,-25.3) AN13(9.9,-25.3) AN15(11.1,-25.3) AN16(12.3,-25.3) AN18(13.5,-25.3) AN19(14.7,-25.3) AN21(15.9,-25.3) AN22(17.1,-25.3) AN24(18.3,-25.3) AN25(19.4,-25.3) AN26(20.2,-25.3) AN27(21,-25.3) AN28(21.8,-25.3) AN29(22.6,-25.3) AP5(3.2,-26.5) AP6(4,-26.5) AP7(4.8,-26.5) AP8(5.6,-26.5) AP9(6.4,-26.5) AP10(7.5,-26.5) AP12(8.7,-26.5) AP13(9.9,-26.5) AP15(11.1,-26.5) AP16(12.3,-26.5) AP18(13.5,-26.5) AP19(14.7,-26.5) AP21(15.9,-26.5) AP22(17.1,-26.5) AP24(18.3,-26.5) AP25(19.4,-26.5) AP26(20.2,-26.5) AP27(21,-26.5) AP28(21.8,-26.5) AP29(22.6,-26.5) AR5(3.2,-27.7) AR6(4,-27.7) AR7(4.8,-27.7) AR8(5.6,-27.7) AR9(6.9,-27.4) AR11(8.1,-27.4) AR12(9.3,-27.4) AR14(10.5,-27.4) AR15(11.7,-27.4) AR17(12.9,-27.4) AR19(14.1,-27.4) AR20(15.3,-27.4) AR22(16.5,-27.4) AR23(17.7,-27.4) AR25(18.9,-27.4) AR26(20.2,-27.7) AR27(21,-27.7) AR28(21.8,-27.7) AR29(22.6,-27.7) AT9(6.9,-28.2) AT11(8.1,-28.2) AT12(9.3,-28.2) AT14(10.5,-28.2) AT15(11.7,-28.2) AT17(12.9,-28.2) AT19(14.1,-28.2) AT20(15.3,-28.2) AT22(16.5,-28.2) AT23(17.7,-28.2) AT25(18.9,-28.2) AU5(3.2,-28.9) AU6(4,-28.9) AU7(4.8,-28.9) AU8(5.7,-29) AU9(6.9,-29) AU11(8.1,-29) AU12(9.3,-29) AU14(10.5,-29) AU15(11.7,-29) AU17(12.9,-29) AU19(14.1,-29) AU20(15.3,-29) AU22(16.5,-29) AU23(17.7,-29) AU25(18.9,-29) AU26(20.1,-29) AU27(21,-28.9) AU28(21.8,-28.9) AU29(22.6,-28.9) AV5(3.2,-30.1) AV7(4.5,-29.8) AV8(5.7,-29.8) AV9(6.9,-29.8) AV11(8.1,-29.8) AV12(9.3,-29.8) AV14(10.5,-29.8) AV15(11.7,-29.8) AV17(12.9,-29.8) AV19(14.1,-29.8) AV20(15.3,-29.8) AV22(16.5,-29.8) AV23(17.7,-29.8) AV25(18.9,-29.8) AV26(20.1,-29.8) AV27(21.3,-29.8) AV29(22.6,-30.1) AW7(4.5,-30.6) AW8(5.7,-30.6) AW9(6.9,-30.6) AW11(8.1,-30.6) AW12(9.3,-30.6) AW14(10.5,-30.6) AW15(11.7,-30.6) AW17(12.9,-30.6) AW19(14.1,-30.6) AW20(15.3,-30.6) AW22(16.5,-30.6) AW23(17.7,-30.6) AW25(18.9,-30.6) AW26(20.1,-30.6) AW27(21.3,-30.6) B1(0,-0.9) B2(0.9,-0.9) B32(24.9,-0.9) B33(25.8,-0.9) BA1(0,-32) BA33(25.8,-32) BB1(0,-32.9) BB2(0.9,-32.9) BB32(24.9,-32.9) BB33(25.8,-32.9) BC2(0.9,-33.8) BC3(1.8,-33.8) BC31(24,-33.8) BC32(24.9,-33.8) C1(0,-1.8) C33(25.8,-1.8) E7(4.5,-3.2) E8(5.7,-3.2) E9(6.9,-3.2) E11(8.1,-3.2) E12(9.3,-3.2) E14(10.5,-3.2) E15(11.7,-3.2) E17(12.9,-3.2) E19(14.1,-3.2) E20(15.3,-3.2) E22(16.5,-3.2) E23(17.7,-3.2) E25(18.9,-3.2) E26(20.1,-3.2) E27(21.3,-3.2) F5(3.2,-3.7) F7(4.5,-4) F8(5.7,-4) F9(6.9,-4) F11(8.1,-4) F12(9.3,-4) F14(10.5,-4) F15(11.7,-4) F17(12.9,-4) F19(14.1,-4) F20(15.3,-4) F22(16.5,-4) F23(17.7,-4) F25(18.9,-4) F26(20.1,-4) F27(21.3,-4) F29(22.6,-3.7) G5(3.2,-4.9) G6(4,-4.9) G7(4.8,-4.9) G8(5.7,-4.8) G9(6.9,-4.8) G11(8.1,-4.8) G12(9.3,-4.8) G14(10.5,-4.8) G15(11.7,-4.8) G17(12.9,-4.8) G19(14.1,-4.8) G20(15.3,-4.8) G22(16.5,-4.8) G23(17.7,-4.8) G25(18.9,-4.8) G26(20.1,-4.8) G27(21,-4.9) G28(21.8,-4.9) G29(22.6,-4.9) H9(6.9,-5.6) H11(8.1,-5.6) H12(9.3,-5.6) H14(10.5,-5.6) H15(11.7,-5.6) H17(12.9,-5.6) H19(14.1,-5.6) H20(15.3,-5.6) H22(16.5,-5.6) H23(17.7,-5.6) H25(18.9,-5.6) J5(3.2,-6.1) J6(4,-6.1) J7(4.8,-6.1) J8(5.6,-6.1) J9(6.9,-6.4) J11(8.1,-6.4) J12(9.3,-6.4) J14(10.5,-6.4) J15(11.7,-6.4) J17(12.9,-6.4) J19(14.1,-6.4) J20(15.3,-6.4) J22(16.5,-6.4) J23(17.7,-6.4) J25(18.9,-6.4) J26(20.2,-6.1) J27(21,-6.1) J28(21.8,-6.1) J29(22.6,-6.1) K5(3.2,-7.3) K6(4,-7.3) K7(4.8,-7.3) K8(5.6,-7.3) K9(6.4,-7.3) K10(7.5,-7.3) K12(8.7,-7.3) K13(9.9,-7.3) K15(11.1,-7.3) K16(12.3,-7.3) K18(13.5,-7.3) K19(14.7,-7.3) K21(15.9,-7.3) K22(17.1,-7.3) K24(18.3,-7.3) K25(19.4,-7.3) K26(20.2,-7.3) K27(21,-7.3) K28(21.8,-7.3) K29(22.6,-7.3) L5(3.2,-8.5) L6(4,-8.5) L7(4.8,-8.5) L8(5.6,-8.5) L9(6.4,-8.5) L10(7.5,-8.5) L12(8.7,-8.5) L13(9.9,-8.5) L15(11.1,-8.5) L16(12.3,-8.5) L18(13.5,-8.5) L19(14.7,-8.5) L21(15.9,-8.5) L22(17.1,-8.5) L24(18.3,-8.5) L25(19.4,-8.5) L26(20.2,-8.5) L27(21,-8.5) L28(21.8,-8.5) L29(22.6,-8.5) N5(3.2,-9.7) N6(4,-9.7) N7(4.8,-9.7) N8(5.6,-9.7) N9(6.4,-9.7) N10(7.5,-9.7) N12(8.7,-9.7) N13(9.9,-9.7) N15(11.1,-9.7) N16(12.3,-9.7) N18(13.5,-9.7) N19(14.7,-9.7) N21(15.9,-9.7) N22(17.1,-9.7) N24(18.3,-9.7) N25(19.4,-9.7) N26(20.2,-9.7) N27(21,-9.7) N28(21.8,-9.7) N29(22.6,-9.7) P5(3.2,-10.9) P6(4,-10.9) P7(4.8,-10.9) P8(5.6,-10.9) P9(6.4,-10.9) P10(7.5,-10.9) P12(8.7,-10.9) P13(9.9,-10.9) P15(11.1,-10.9) P16(12.3,-10.9) P18(13.5,-10.9) P19(14.7,-10.9) P21(15.9,-10.9) P22(17.1,-10.9) P24(18.3,-10.9) P25(19.4,-10.9) P26(20.2,-10.9) P27(21,-10.9) P28(21.8,-10.9) P29(22.6,-10.9) T5(3.2,-12.1) T6(4,-12.1) T7(4.8,-12.1) T8(5.6,-12.1) T9(6.4,-12.1) T10(7.5,-12.1) T12(8.7,-12.1) T13(9.9,-12.1) T15(11.1,-12.1) T16(12.3,-12.1) T18(13.5,-12.1) T19(14.7,-12.1) T21(15.9,-12.1) T22(17.1,-12.1) T24(18.3,-12.1) T25(19.4,-12.1) T26(20.2,-12.1) T27(21,-12.1) T28(21.8,-12.1) T29(22.6,-12.1) U5(3.2,-13.3) U6(4,-13.3) U7(4.8,-13.3) U8(5.6,-13.3) U9(6.4,-13.3) U10(7.5,-13.3) U12(8.7,-13.3) U13(9.9,-13.3) U15(11.1,-13.3) U16(12.3,-13.3) U18(13.5,-13.3) U19(14.7,-13.3) U21(15.9,-13.3) U22(17.1,-13.3) U24(18.3,-13.3) U25(19.4,-13.3) U26(20.2,-13.3) U27(21,-13.3) U28(21.8,-13.3) U29(22.6,-13.3) W5(3.2,-14.5) W6(4,-14.5) W7(4.8,-14.5) W8(5.6,-14.5) W9(6.4,-14.5) W10(7.5,-14.5) W12(8.7,-14.5) W13(9.9,-14.5) W15(11.1,-14.5) W16(12.3,-14.5) W18(13.5,-14.5) W19(14.7,-14.5) W21(15.9,-14.5) W22(17.1,-14.5) W24(18.3,-14.5) W25(19.4,-14.5) W26(20.2,-14.5) W27(21,-14.5) W28(21.8,-14.5) W29(22.6,-14.5) Y5(3.2,-15.7) Y6(4,-15.7) Y7(4.8,-15.7) Y8(5.6,-15.7) Y9(6.4,-15.7) Y10(7.5,-15.7) Y12(8.7,-15.7) Y13(9.9,-15.7) Y15(11.1,-15.7) Y16(12.3,-15.7) Y18(13.5,-15.7) Y19(14.7,-15.7) Y21(15.9,-15.7) Y22(17.1,-15.7) Y24(18.3,-15.7) Y25(19.4,-15.7) Y26(20.2,-15.7) Y27(21,-15.7) Y28(21.8,-15.7) Y29(22.6,-15.7)
  round 0.305 smd: A4(2.5,-0.4) A5(3.3,0) A6(4.1,-0.4) A7(4.9,0) A8(5.7,-0.4) A9(6.5,0) A10(7.3,-0.4) A11(8.1,0) A12(8.9,-0.4) A13(9.7,0) A14(10.5,-0.4) A15(11.3,0) A16(12.1,-0.4) A17(12.9,0) A18(13.7,-0.4) A19(14.5,0) A20(15.3,-0.4) A21(16.1,0) A22(16.9,-0.4) A23(17.7,0) A24(18.5,-0.4) A25(19.3,0) A26(20.1,-0.4) A27(20.9,0) A28(21.7,-0.4) A29(22.5,0) A30(23.3,-0.4) AA1(0,-16.1) AA2(0.8,-16.1) AA3(1.6,-16.1) AA4(2.4,-16.1) AA30(23.4,-16.1) AA31(24.2,-16.1) AA32(25,-16.1) AA33(25.8,-16.1) AB1(0.4,-16.9) AB2(1.2,-16.9) AB4(2.4,-16.9) AB30(23.4,-16.9) AB32(24.6,-16.9) AB33(25.4,-16.9) AC1(0,-17.7) AC2(0.8,-17.7) AC3(1.6,-17.7) AC4(2.4,-17.7) AC30(23.4,-17.7) AC31(24.2,-17.7) AC32(25,-17.7) AC33(25.8,-17.7) AD1(0.4,-18.5) AD2(1.2,-18.5) AD4(2.4,-18.5) AD30(23.4,-18.5) AD32(24.6,-18.5) AD33(25.4,-18.5) AE1(0,-19.3) AE2(0.8,-19.3) AE3(1.6,-19.3) AE4(2.4,-19.3) AE30(23.4,-19.3) AE31(24.2,-19.3) AE32(25,-19.3) AE33(25.8,-19.3) AF1(0.4,-20.1) AF2(1.2,-20.1) AF4(2.4,-20.1) AF30(23.4,-20.1) AF32(24.6,-20.1) AF33(25.4,-20.1) AG1(0,-20.9) AG2(0.8,-20.9) AG3(1.6,-20.9) AG4(2.4,-20.9) AG30(23.4,-20.9) AG31(24.2,-20.9) AG32(25,-20.9) AG33(25.8,-20.9) AH1(0.4,-21.7) AH2(1.2,-21.7) AH4(2.4,-21.7) AH30(23.4,-21.7) AH32(24.6,-21.7) AH33(25.4,-21.7) AJ1(0,-22.5) AJ2(0.8,-22.5) AJ3(1.6,-22.5) AJ4(2.4,-22.5) AJ30(23.4,-22.5) AJ31(24.2,-22.5) AJ32(25,-22.5) AJ33(25.8,-22.5) AK1(0.4,-23.3) AK2(1.2,-23.3) AK4(2.4,-23.3) AK30(23.4,-23.3) AK32(24.6,-23.3) AK33(25.4,-23.3) AL1(0,-24.1) AL2(0.8,-24.1) AL3(1.6,-24.1) AL4(2.4,-24.1) AL30(23.4,-24.1) AL31(24.2,-24.1) AL32(25,-24.1) AL33(25.8,-24.1) AM1(0.4,-24.9) AM2(1.2,-24.9) AM4(2.4,-24.9) AM30(23.4,-24.9) AM32(24.6,-24.9) AM33(25.4,-24.9) AN1(0,-25.7) AN2(0.8,-25.7) AN3(1.6,-25.7) AN4(2.4,-25.7) AN30(23.4,-25.7) AN31(24.2,-25.7) AN32(25,-25.7) AN33(25.8,-25.7) AP1(0.4,-26.5) AP2(1.2,-26.5) AP4(2.4,-26.5) AP30(23.4,-26.5) AP32(24.6,-26.5) AP33(25.4,-26.5) AR1(0,-27.3) AR2(0.8,-27.3) AR3(1.6,-27.3) AR4(2.4,-27.3) AR30(23.4,-27.3) AR31(24.2,-27.3) AR32(25,-27.3) AR33(25.8,-27.3) AT1(0.4,-28.1) AT2(1.2,-28.1) AT4(2.4,-28.1) AT30(23.4,-28.1) AT32(24.6,-28.1) AT33(25.4,-28.1) AU1(0,-28.9) AU2(0.8,-28.9) AU3(1.6,-28.9) AU4(2.4,-28.9) AU30(23.4,-28.9) AU31(24.2,-28.9) AU32(25,-28.9) AU33(25.8,-28.9) AV1(0.4,-29.7) AV2(1.2,-29.7) AV4(2.4,-29.7) AV30(23.4,-29.7) AV32(24.6,-29.7) AV33(25.4,-29.7) AW1(0,-30.5) AW2(0.8,-30.5) AW3(1.6,-30.5) AW4(2.4,-30.5) AW30(23.4,-30.5) AW31(24.2,-30.5) AW32(25,-30.5) AW33(25.8,-30.5) AY1(0.4,-31.3) AY2(1.2,-31.3) AY4(2.5,-31.4) AY5(3.3,-31.4) AY6(4.1,-31.4) AY7(4.9,-31.4) AY8(5.7,-31.4) AY9(6.5,-31.4) AY10(7.3,-31.4) AY11(8.1,-31.4) AY12(8.9,-31.4) AY13(9.7,-31.4) AY14(10.5,-31.4) AY15(11.3,-31.4) AY16(12.1,-31.4) AY17(12.9,-31.4) AY18(13.7,-31.4) AY19(14.5,-31.4) AY20(15.3,-31.4) AY21(16.1,-31.4) AY22(16.9,-31.4) AY23(17.7,-31.4) AY24(18.5,-31.4) AY25(19.3,-31.4) AY26(20.1,-31.4) AY27(20.9,-31.4) AY28(21.7,-31.4) AY29(22.5,-31.4) AY30(23.3,-31.4) AY32(24.6,-31.3) AY33(25.4,-31.3) B4(2.5,-1.2) B5(3.3,-0.8) B6(4.1,-1.2) B7(4.9,-0.8) B8(5.7,-1.2) B9(6.5,-0.8) B10(7.3,-1.2) B11(8.1,-0.8) B12(8.9,-1.2) B13(9.7,-0.8) B14(10.5,-1.2) B15(11.3,-0.8) B16(12.1,-1.2) B17(12.9,-0.8) B18(13.7,-1.2) B19(14.5,-0.8) B20(15.3,-1.2) B21(16.1,-0.8) B22(16.9,-1.2) B23(17.7,-0.8) B24(18.5,-1.2) B25(19.3,-0.8) B26(20.1,-1.2) B27(20.9,-0.8) B28(21.7,-1.2) B29(22.5,-0.8) B30(23.3,-1.2) BA3(1.7,-32.2) BA5(3.3,-32.2) BA7(4.9,-32.2) BA9(6.5,-32.2) BA11(8.1,-32.2) BA13(9.7,-32.2) BA15(11.3,-32.2) BA17(12.9,-32.2) BA19(14.5,-32.2) BA21(16.1,-32.2) BA23(17.7,-32.2) BA25(19.3,-32.2) BA27(20.9,-32.2) BA29(22.5,-32.2) BA31(24.1,-32.2) BB4(2.5,-32.6) BB5(3.3,-33) BB6(4.1,-32.6) BB7(4.9,-33) BB8(5.7,-32.6) BB9(6.5,-33) BB10(7.3,-32.6) BB11(8.1,-33) BB12(8.9,-32.6) BB13(9.7,-33) BB14(10.5,-32.6) BB15(11.3,-33) BB16(12.1,-32.6) BB17(12.9,-33) BB18(13.7,-32.6) BB19(14.5,-33) BB20(15.3,-32.6) BB21(16.1,-33) BB22(16.9,-32.6) BB23(17.7,-33) BB24(18.5,-32.6) BB25(19.3,-33) BB26(20.1,-32.6) BB27(20.9,-33) BB28(21.7,-32.6) BB29(22.5,-33) BB30(23.3,-32.6) BC4(2.5,-33.4) BC5(3.3,-33.8) BC6(4.1,-33.4) BC7(4.9,-33.8) BC8(5.7,-33.4) BC9(6.5,-33.8) BC10(7.3,-33.4) BC11(8.1,-33.8) BC12(8.9,-33.4) BC13(9.7,-33.8) BC14(10.5,-33.4) BC15(11.3,-33.8) BC16(12.1,-33.4) BC17(12.9,-33.8) BC18(13.7,-33.4) BC19(14.5,-33.8) BC20(15.3,-33.4) BC21(16.1,-33.8) BC22(16.9,-33.4) BC23(17.7,-33.8) BC24(18.5,-33.4) BC25(19.3,-33.8) BC26(20.1,-33.4) BC27(20.9,-33.8) BC28(21.7,-33.4) BC29(22.5,-33.8) BC30(23.3,-33.4) C3(1.7,-1.6) C5(3.3,-1.6) C7(4.9,-1.6) C9(6.5,-1.6) C11(8.1,-1.6) C13(9.7,-1.6) C15(11.3,-1.6) C17(12.9,-1.6) C19(14.5,-1.6) C21(16.1,-1.6) C23(17.7,-1.6) C25(19.3,-1.6) C27(20.9,-1.6) C29(22.5,-1.6) C31(24.1,-1.6) D1(0.4,-2.5) D2(1.2,-2.5) D4(2.5,-2.4) D5(3.3,-2.4) D6(4.1,-2.4) D7(4.9,-2.4) D8(5.7,-2.4) D9(6.5,-2.4) D10(7.3,-2.4) D11(8.1,-2.4) D12(8.9,-2.4) D13(9.7,-2.4) D14(10.5,-2.4) D15(11.3,-2.4) D16(12.1,-2.4) D17(12.9,-2.4) D18(13.7,-2.4) D19(14.5,-2.4) D20(15.3,-2.4) D21(16.1,-2.4) D22(16.9,-2.4) D23(17.7,-2.4) D24(18.5,-2.4) D25(19.3,-2.4) D26(20.1,-2.4) D27(20.9,-2.4) D28(21.7,-2.4) D29(22.5,-2.4) D30(23.3,-2.4) D32(24.6,-2.5) D33(25.4,-2.5) E1(0,-3.3) E2(0.8,-3.3) E3(1.6,-3.3) E4(2.4,-3.3) E30(23.4,-3.3) E31(24.2,-3.3) E32(25,-3.3) E33(25.8,-3.3) F1(0.4,-4.1) F2(1.2,-4.1) F4(2.4,-4.1) F30(23.4,-4.1) F32(24.6,-4.1) F33(25.4,-4.1) G1(0,-4.9) G2(0.8,-4.9) G3(1.6,-4.9) G4(2.4,-4.9) G30(23.4,-4.9) G31(24.2,-4.9) G32(25,-4.9) G33(25.8,-4.9) H1(0.4,-5.7) H2(1.2,-5.7) H4(2.4,-5.7) H30(23.4,-5.7) H32(24.6,-5.7) H33(25.4,-5.7) J1(0,-6.5) J2(0.8,-6.5) J3(1.6,-6.5) J4(2.4,-6.5) J30(23.4,-6.5) J31(24.2,-6.5) J32(25,-6.5) J33(25.8,-6.5) K1(0.4,-7.3) K2(1.2,-7.3) K4(2.4,-7.3) K30(23.4,-7.3) K32(24.6,-7.3) K33(25.4,-7.3) L1(0,-8.1) L2(0.8,-8.1) L3(1.6,-8.1) L4(2.4,-8.1) L30(23.4,-8.1) L31(24.2,-8.1) L32(25,-8.1) L33(25.8,-8.1) M1(0.4,-8.9) M2(1.2,-8.9) M4(2.4,-8.9) M30(23.4,-8.9) M32(24.6,-8.9) M33(25.4,-8.9) N1(0,-9.7) N2(0.8,-9.7) N3(1.6,-9.7) N4(2.4,-9.7) N30(23.4,-9.7) N31(24.2,-9.7) N32(25,-9.7) N33(25.8,-9.7) P1(0.4,-10.5) P2(1.2,-10.5) P4(2.4,-10.5) P30(23.4,-10.5) P32(24.6,-10.5) P33(25.4,-10.5) R1(0,-11.3) R2(0.8,-11.3) R3(1.6,-11.3) R4(2.4,-11.3) R30(23.4,-11.3) R31(24.2,-11.3) R32(25,-11.3) R33(25.8,-11.3) T1(0.4,-12.1) T2(1.2,-12.1) T4(2.4,-12.1) T30(23.4,-12.1) T32(24.6,-12.1) T33(25.4,-12.1) U1(0,-12.9) U2(0.8,-12.9) U3(1.6,-12.9) U4(2.4,-12.9) U30(23.4,-12.9) U31(24.2,-12.9) U32(25,-12.9) U33(25.8,-12.9) V1(0.4,-13.7) V2(1.2,-13.7) V4(2.4,-13.7) V30(23.4,-13.7) V32(24.6,-13.7) V33(25.4,-13.7) W1(0,-14.5) W2(0.8,-14.5) W3(1.6,-14.5) W4(2.4,-14.5) W30(23.4,-14.5) W31(24.2,-14.5) W32(25,-14.5) W33(25.8,-14.5) Y1(0.4,-15.3) Y2(1.2,-15.3) Y4(2.4,-15.3) Y30(23.4,-15.3) Y32(24.6,-15.3) Y33(25.4,-15.3)
G993P1UF_SOP8
  oval 0.635x1.854 smd: 1(0,0) 2(1.27,0) 3(2.54,0) 4(3.81,0) 5(3.81,5.165) 6(2.54,5.165) 7(1.27,5.165) 8(0,5.165)
H_3P0
  round 3.505 hole 2.997: 1(0,0)
H_3P0X3P8N
  oval 2.997x3.81 hole 2.997x3.81 unplated: (0,0)
H_3P2
  round 3.708 hole 3.2: 1(0,0)
H_3P3
  round 3.81 hole 3.302: 1(0,0)
H_3P4
  round 3.912 hole 3.404: 1(0,0)
H_3P7
  round 4.216 hole 3.708: 1(0,0)
H_4P0N
  round 3.988 hole 3.988 unplated: (0,0)
INPAQ_HCM2012GA900AE_4P
  rect 0.762x0.508 smd: 1(0,0) 2(1.85,0) 3(1.85,-0.9) 4(0,-0.9)
IP4292CZ10-TBR_XSON10_2P5X1
  oval 0.254x0.889 smd: 1(0,0)
  oval 0.254x0.838 smd: 2(0.5,-0.025) 3(1,-0.025) 4(1.5,-0.025) 5(2,-0.025) 6(2,1.125) 7(1.5,1.125) 8(1,1.125) 9(0.5,1.125) 10(0,1.125)
ISL62771HRTZ-T_TQFN40_5X5
  oval 0.203x1.016 smd: 1(0,0) 2(0.4,0) 3(0.8,0) 4(1.2,0) 5(1.6,0) 6(2,0) 7(2.4,0) 8(2.8,0) 9(3.2,0) 10(3.6,0) 21(3.6,4.975) 22(3.2,4.975) 23(2.8,4.975) 24(2.4,4.975) 25(2,4.975) 26(1.6,4.975) 27(1.2,4.975) 28(0.8,4.975) 29(0.4,4.975) 30(0,4.975)
  oval 1.016x0.203 smd: 11(4.288,0.688) 12(4.288,1.088) 13(4.288,1.488) 14(4.288,1.888) 15(4.288,2.288) 16(4.288,2.688) 17(4.288,3.088) 18(4.288,3.488) 19(4.288,3.888) 20(4.288,4.288) 31(-0.688,4.288) 32(-0.688,3.888) 33(-0.688,3.488) 34(-0.688,3.088) 35(-0.688,2.688) 36(-0.688,2.288) 37(-0.688,1.888) 38(-0.688,1.488) 39(-0.688,1.088) 40(-0.688,0.688)
  rect 3.505x3.505 smd: 41(1.8,2.488)
ISL95812HRZ-T_QFN32_4X4
  oval 0.203x0.914 smd: 1(0,0) 2(0.4,0) 3(0.8,0) 4(1.2,0) 5(1.6,0) 6(2,0) 7(2.4,0) 8(2.8,0) 17(2.8,4.077) 18(2.4,4.077) 19(2,4.077) 20(1.6,4.077) 21(1.2,4.077) 22(0.8,4.077) 23(0.4,4.077) 24(0,4.077)
  oval 0.914x0.203 smd: 9(3.438,0.639) 10(3.438,1.039) 11(3.438,1.438) 12(3.438,1.838) 13(3.438,2.239) 14(3.438,2.639) 15(3.438,3.039) 16(3.438,3.438) 25(-0.639,3.438) 26(-0.639,3.039) 27(-0.639,2.639) 28(-0.639,2.239) 29(-0.639,1.838) 30(-0.639,1.438) 31(-0.639,1.039) 32(-0.639,0.639)
  rect 2.642x2.642 smd: 33(1.4,2.039)
JUMP_43X39
  custom 0.191x0.191 smd: 1(0,0) 2(0.914,0)
JUMP_43X79
  custom 0.188x0.188 smd: 1(0,0) 2(1.1,0)
JUMP_43X79-NPM
  custom 0.188x0.188 smd: 1(0,0) 2(1.1,0)
JUMP_43X118
  custom 0.187x0.187 smd: 1(0,0) 2(1.1,0)
JUMP_43X118-NPM
  custom 0.187x0.187 smd: 1(0,0) 2(1.1,0)
JXT_FP202DH-004M10M_4P
  oval 0.61x1.448 smd: 1(0,0) 2(1,0) 3(2,0) 4(3,0)
  rect 2.159x2.21 smd: 5(-2.825,-3.125) 6(5.825,-3.125)
JXT_FP202DH-008M10M_8P
  oval 0.61x1.448 smd: 1(0,0) 2(1,0) 3(2,0) 4(3,0) 5(4,0) 6(5,0) 7(6,0) 8(7,0)
  rect 2.159x2.21 smd: 9(-2.825,-3.125) 10(9.825,-3.125)
K4W1G1646E-HC12_FBGA_96P
  round 0.343 smd: A1(0,0) A2(0.8,0) A3(1.6,0) A7(4.801,0) A8(5.601,0) A9(6.401,0) B1(0,-0.8) B2(0.8,-0.8) B3(1.6,-0.8) B7(4.801,-0.8) B8(5.601,-0.8) B9(6.401,-0.8) C1(0,-1.6) C2(0.8,-1.6) C3(1.6,-1.6) C7(4.801,-1.6) C8(5.601,-1.6) C9(6.401,-1.6) D1(0,-2.4) D2(0.8,-2.4) D3(1.6,-2.4) D7(4.801,-2.4) D8(5.601,-2.4) D9(6.401,-2.4) E1(0,-3.2) E2(0.8,-3.2) E3(1.6,-3.2) E7(4.801,-3.2) E8(5.601,-3.2) E9(6.401,-3.2) F1(0,-4) F2(0.8,-4) F3(1.6,-4) F7(4.801,-4) F8(5.601,-4) F9(6.401,-4) G1(0,-4.801) G2(0.8,-4.801) G3(1.6,-4.801) G7(4.801,-4.801) G8(5.601,-4.801) G9(6.401,-4.801) H1(0,-5.601) H2(0.8,-5.601) H3(1.6,-5.601) H7(4.801,-5.601) H8(5.601,-5.601) H9(6.401,-5.601) J1(0,-6.401) J2(0.8,-6.401) J3(1.6,-6.401) J7(4.801,-6.401) J8(5.601,-6.401) J9(6.401,-6.401) K1(0,-7.201) K2(0.8,-7.201) K3(1.6,-7.201) K7(4.801,-7.201) K8(5.601,-7.201) K9(6.401,-7.201) L1(0,-8.001) L2(0.8,-8.001) L3(1.6,-8.001) L7(4.801,-8.001) L8(5.601,-8.001) L9(6.401,-8.001) M1(0,-8.801) M2(0.8,-8.801) M3(1.6,-8.801) M7(4.801,-8.801) M8(5.601,-8.801) M9(6.401,-8.801) N1(0,-9.601) N2(0.8,-9.601) N3(1.6,-9.601) N7(4.801,-9.601) N8(5.601,-9.601) N9(6.401,-9.601) P1(0,-10.401) P2(0.8,-10.401) P3(1.6,-10.401) P7(4.801,-10.401) P8(5.601,-10.401) P9(6.401,-10.401) R1(0,-11.201) R2(0.8,-11.201) R3(1.6,-11.201) R7(4.801,-11.201) R8(5.601,-11.201) R9(6.401,-11.201) T1(0,-12.002) T2(0.8,-12.002) T3(1.6,-12.002) T7(4.801,-12.002) T8(5.601,-12.002) T9(6.401,-12.002)
KB9012QF-A2_LQFP128_14X14
  oval 0.203x1.753 smd: 1(0,0) 2(0.4,0) 3(0.8,0) 4(1.2,0) 5(1.6,0) 6(2,0) 7(2.4,0) 8(2.8,0) 9(3.2,0) 10(3.6,0) 11(4,0) 12(4.4,0) 13(4.8,0) 14(5.2,0) 15(5.6,0) 16(6,0) 17(6.4,0) 18(6.8,0) 19(7.2,0) 20(7.6,0) 21(8,0) 22(8.4,0) 23(8.8,0) 24(9.2,0) 25(9.6,0) 26(10,0) 27(10.4,0) 28(10.8,0) 29(11.2,0) 30(11.6,0) 31(12,0) 32(12.4,0) 65(12.4,15.654) 66(12,15.654) 67(11.6,15.654) 68(11.2,15.654) 69(10.8,15.654) 70(10.4,15.654) 71(10,15.654) 72(9.6,15.654) 73(9.2,15.654) 74(8.8,15.654) 75(8.4,15.654) 76(8,15.654) 77(7.6,15.654) 78(7.2,15.654) 79(6.8,15.654) 80(6.4,15.654) 81(6,15.654) 82(5.6,15.654) 83(5.2,15.654) 84(4.8,15.654) 85(4.4,15.654) 86(4,15.654) 87(3.6,15.654) 88(3.2,15.654) 89(2.8,15.654) 90(2.4,15.654) 91(2,15.654) 92(1.6,15.654) 93(1.2,15.654) 94(0.8,15.654) 95(0.4,15.654) 96(0,15.654)
  oval 1.753x0.203 smd: 33(14.027,1.627) 34(14.027,2.027) 35(14.027,2.427) 36(14.027,2.827) 37(14.027,3.227) 38(14.027,3.627) 39(14.027,4.027) 40(14.027,4.427) 41(14.027,4.827) 42(14.027,5.227) 43(14.027,5.627) 44(14.027,6.027) 45(14.027,6.427) 46(14.027,6.827) 47(14.027,7.227) 48(14.027,7.627) 49(14.027,8.027) 50(14.027,8.427) 51(14.027,8.827) 52(14.027,9.227) 53(14.027,9.627) 54(14.027,10.027) 55(14.027,10.427) 56(14.027,10.827) 57(14.027,11.227) 58(14.027,11.627) 59(14.027,12.027) 60(14.027,12.427) 61(14.027,12.827) 62(14.027,13.227) 63(14.027,13.627) 64(14.027,14.027) 97(-1.627,14.027) 98(-1.627,13.627) 99(-1.627,13.227) 100(-1.627,12.827) 101(-1.627,12.427) 102(-1.627,12.027) 103(-1.627,11.627) 104(-1.627,11.227) 105(-1.627,10.827) 106(-1.627,10.427) 107(-1.627,10.027) 108(-1.627,9.627) 109(-1.627,9.227) 110(-1.627,8.827) 111(-1.627,8.427) 112(-1.627,8.027) 113(-1.627,7.627) 114(-1.627,7.227) 115(-1.627,6.827) 116(-1.627,6.427) 117(-1.627,6.027) 118(-1.627,5.627) 119(-1.627,5.227) 120(-1.627,4.827) 121(-1.627,4.427) 122(-1.627,4.027) 123(-1.627,3.627) 124(-1.627,3.227) 125(-1.627,2.827) 126(-1.627,2.427) 127(-1.627,2.027) 128(-1.627,1.627)
KC_FBMA-L11-160808-800LMT_2P
  rect 0.889x1.092 smd: 1(0,0) 2(1.5,0)
KC_FBMA-L11-201209-121LMA50_2P
  rect 0.991x1.702 smd: 1(0,0) 2(1.5,0)
KC_FBMA-L11-201209-221LMA30_2P
  rect 0.838x1.397 smd: 1(0,0) 2(1.65,0)
L30ESDL5V0C3-2_SOT23-3
  oval 1.016x1.524 smd: 1(0,0) 2(0.965,2.083) 3(-0.965,2.083)
L_5X5X3_M_2P
  rect 2.159x2.794 smd: 1(0,0) 2(4.35,0)
L_7X7X3_M_2P
  rect 2.362x3.505 smd: 1(0,0) 2(6.05,0)
LANKO_LF-H1201P-2_16P
  oval 0.635x1.905 smd: 1(0,0) 2(1.27,0) 3(2.54,0) 4(3.81,0) 5(5.08,0) 6(6.35,0) 7(7.62,0) 8(8.89,0) 9(8.89,8.763) 10(7.62,8.763) 11(6.35,8.763) 12(5.08,8.763) 13(3.81,8.763) 14(2.54,8.763) 15(1.27,8.763) 16(0,8.763)
LED_12-21C-T3D-CM2P1B18X-2C_3P
  rect 0.991x0.787 smd: 1(0,0) 2(-2.8,0)
  rect 0.991x0.61 smd: 3(-1.4,0.4)
LED_12-22A-S2ST3D-C30-2C_3P
  rect 0.991x1.499 smd: 1(0,0) 3(-3,0)
  rect 0.889x0.889 smd: 2(-1.5,-0.65)
LM393DR_SO8
  oval 0.635x1.854 smd: 1(0,0) 2(1.27,0) 3(2.54,0) 4(3.81,0) 5(3.81,5.165) 6(2.54,5.165) 7(1.27,5.165) 8(0,5.165)
LOTES_AAA-BAT-054-K01_2P
  round 0.787 hole 0.787 unplated: (-14.5,-8)
  round 1.194 hole 1.194 unplated: (-14.5,8)
  rect 2.007x3.988 smd: 1(0,0) 2(-30.1,0)
MC74VHC1G08DFT2G_SC70-5
  oval 0.381x0.711 smd: 1(0,0) 2(0.65,0) 3(1.3,0) 4(1.3,1.9) 5(0,1.9)
MC74VHC1G09DFT2G_SC70-5
  oval 0.406x0.508 smd: 1(0,0) 2(0.65,0) 3(1.3,0) 4(1.3,1.9) 5(0,1.9)
MESS138W-G_SOT323-3
  oval 0.711x0.889 smd: 1(0,0) 2(-0.65,-1.9) 3(0.65,-1.9)
MMBT3904_NL_SOT23-3
  oval 1.016x1.524 smd: 1(0,0) 2(0.965,2.083) 3(-0.965,2.083)
MMST3904-7-F_SOT323-3
  oval 0.711x0.889 smd: 1(0,0) 2(0.65,1.9) 3(-0.65,1.9)
MURAT_BLM15AG102SN1D_2P
  rect 0.457x0.508 smd: 1(0,0) 2(0.85,0)
MURAT_BLM15BB221SN1D_2P
  rect 0.508x0.762 smd: 1(0,0) 2(0.75,0)
MURAT_BLM18AG601SN1D_L0603_2P
  rect 0.66x1.041 smd: 1(0,0) 2(1.2,0)
MURAT_BLM41PG600SN1L_2P
  rect 1.194x2.108 smd: 1(0,0) 2(3.8,0)
MURAT_DLW21SN670HQ2L_4P
  rect 0.889x0.406 smd: 1(0,0) 2(1.7,0) 3(1.7,0.8) 4(0,0.8)
MURAT_LQM2MPN2R2NG0L_2P
  rect 0.787x1.803 smd: 1(0,0) 2(1.6,0)
NC7SZ08P5X_NL_SC70-5
  oval 0.457x0.711 smd: 1(-0.65,-0.925) 2(0,-0.925) 3(0.65,-0.925) 4(0.65,0.925) 5(-0.65,0.925)
PESD5V0U2BT_SOT23-3
  oval 1.016x1.524 smd: 1(0,0) 2(0.965,2.083) 3(-0.965,2.083)
PESD24VS2UT_SOT23-3
  oval 1.016x1.524 smd: 1(0,0) 2(0.965,2.083) 3(-0.965,2.083)
PS8520BTQFN20GTR2_TQFN20_4X4
  oval 0.254x1.194 smd: 1(0,0) 2(0.5,0) 3(1,0) 4(1.5,0) 5(2,0) 11(2,3.8) 12(1.5,3.8) 13(1,3.8) 14(0.5,3.8) 15(0,3.8)
  oval 1.194x0.254 smd: 6(2.9,0.9) 7(2.9,1.4) 8(2.9,1.9) 9(2.9,2.4) 10(2.9,2.9) 16(-0.9,2.9) 17(-0.9,2.4) 18(-0.9,1.9) 19(-0.9,1.4) 20(-0.9,0.9)
  rect 2.108x2.108 smd: 21(1,1.9)
R0402_0OHM
  rect 0.508x0.559 smd: 1(0,0) 2(0.914,0)
R0603_0OHM
  rect 0.635x0.889 smd: 1(0,0) 2(1.397,0)
R0805_0OHM
  rect 0.813x1.397 smd: 1(0,0) 2(1.702,0)
R_0402
  rect 0.508x0.559 smd: 1(0,0) 2(0.914,0)
R_0402-NPM
  rect 0.508x0.559 smd: 1(0,0) 2(0.914,0)
R_0603
  rect 0.635x0.889 smd: 1(0,0) 2(1.397,0)
R_0805
  rect 0.813x1.397 smd: 1(0,0) 2(1.702,0)
R_1206
  rect 1.016x1.651 smd: 1(0,0) 2(2.667,0)
R_1206_4P
  custom 0.476x0.476 smd: 1(0,0) 4(5.08,0)
  rect 1.397x0.381 smd: 2(1.206,0) 3(3.873,0)
RB551V-30_SOD323-2
  rect 0.559x0.813 smd: 1(0,0) 2(2.3,0)
RB751V-40_SOD323-2
  rect 0.787x0.889 smd: 1(0,0) 2(2.14,0)
RB751V-40TE17_SOD323-2
  rect 0.787x0.889 smd: 1(0,0) 2(0,-2.1)
RHU002N06_SOT323-3
  oval 0.813x0.914 smd: 1(0,0) 2(0.65,1.6) 3(-0.65,1.6)
RP_0804_8P4R
  oval 0.66x0.254 smd: 1(0,0) 2(0,-0.5) 3(0,-1) 4(0,-1.5) 5(1.15,-1.5) 6(1.15,-1) 7(1.15,-0.5) 8(1.15,0)
RT8207MZQW_WQFN20_3X3
  oval 0.203x0.889 smd: 1(0,0) 2(0.4,0) 3(0.8,0) 4(1.2,0) 5(1.6,0) 11(1.6,3.1) 12(1.2,3.1) 13(0.8,3.1) 14(0.4,3.1) 15(0,3.1)
  oval 0.889x0.203 smd: 6(2.35,0.75) 7(2.35,1.15) 8(2.35,1.55) 9(2.35,1.95) 10(2.35,2.35) 16(-0.75,2.35) 17(-0.75,1.95) 18(-0.75,1.55) 19(-0.75,1.15) 20(-0.75,0.75)
  rect 1.702x1.702 smd: 21(0.8,1.55)
RTD2168-CG_QFN32_5X5
  oval 0.889x0.254 smd: 1(0,0) 2(0,-0.5) 3(0,-1) 4(0,-1.5) 5(0,-2) 6(0,-2.5) 7(0,-3) 8(0,-3.5) 17(5.1,-3.5) 18(5.1,-3) 19(5.1,-2.5) 20(5.1,-2) 21(5.1,-1.5) 22(5.1,-1) 23(5.1,-0.5) 24(5.1,0)
  oval 0.254x0.889 smd: 9(0.8,-4.3) 10(1.3,-4.3) 11(1.8,-4.3) 12(2.3,-4.3) 13(2.8,-4.3) 14(3.3,-4.3) 15(3.8,-4.3) 16(4.3,-4.3) 25(4.3,0.8) 26(3.8,0.8) 27(3.3,0.8) 28(2.8,0.8) 29(2.3,0.8) 30(1.8,0.8) 31(1.3,0.8) 32(0.8,0.8)
  rect 3.353x3.353 smd: 33(2.55,-1.75)
RTL8106EUS-CG_QFN32_4X4
  oval 0.203x0.889 smd: 1(0,0) 2(0.4,0) 3(0.8,0) 4(1.2,0) 5(1.6,0) 6(2,0) 7(2.4,0) 8(2.8,0) 17(2.8,4.1) 18(2.4,4.1) 19(2,4.1) 20(1.6,4.1) 21(1.2,4.1) 22(0.8,4.1) 23(0.4,4.1) 24(0,4.1)
  oval 0.889x0.203 smd: 9(3.45,0.65) 10(3.45,1.05) 11(3.45,1.45) 12(3.45,1.85) 13(3.45,2.25) 14(3.45,2.65) 15(3.45,3.05) 16(3.45,3.45) 25(-0.65,3.45) 26(-0.65,3.05) 27(-0.65,2.65) 28(-0.65,2.25) 29(-0.65,1.85) 30(-0.65,1.45) 31(-0.65,1.05) 32(-0.65,0.65)
  rect 2.692x2.692 smd: 33(1.4,2.05)
RTS5179-GR_QFN24_4X4
  oval 0.254x0.889 smd: 1(0,0) 2(0.5,0) 3(1,0) 4(1.5,0) 5(2,0) 6(2.5,0) 13(2.5,4.1) 14(2,4.1) 15(1.5,4.1) 16(1,4.1) 17(0.5,4.1) 18(0,4.1)
  oval 0.889x0.254 smd: 7(3.3,0.8) 8(3.3,1.3) 9(3.3,1.8) 10(3.3,2.3) 11(3.3,2.8) 12(3.3,3.3) 19(-0.8,3.3) 20(-0.8,2.8) 21(-0.8,2.3) 22(-0.8,1.8) 23(-0.8,1.3) 24(-0.8,0.8)
  rect 2.261x2.261 smd: 25(1.25,2.05)
SAMTE_ASP-136446-07-B_20P-T
  oval 0.737x2.794 smd: 1(0,0) 2(0,4.07) 3(1.27,0) 4(1.27,4.07) 5(2.54,0) 6(2.54,4.07) 7(3.81,0) 8(3.81,4.07) 9(5.08,0) 10(5.08,4.07) 11(6.35,0) 12(6.35,4.07) 13(7.62,0) 14(7.62,4.07) 15(8.89,0) 16(8.89,4.07) 17(10.16,0) 18(10.16,4.07) 19(11.43,0) 20(11.43,4.07)
SANTA_130456-661_8P-T
  round 1.194 hole 0.889: 1(0,0) 2(1.02,1.1) 3(2.04,0) 4(3.06,1.1) 5(4.08,0) 6(5.1,1.1) 7(6.12,0) 8(7.14,1.1)
  oval 1.092x2.794 hole 0.61x2.388: 9(12.895,-5.32) 10(-5.755,-5.32)
SDMK0340L-7-F_SOD323-2
  rect 1.346x0.66 smd: 1(0,0) 2(2.4,0)
SHORTPADS
  custom 0.19x0.19 smd: 1(-0.483,0) 2(0.483,0)
SI3456BDV-T1-E3_TSOP6
  oval 0.508x1.448 smd: 1(0,0) 2(1,0) 3(2,0) 4(2,2.425) 5(1,2.425) 6(0,2.425)
SIR472DP-T1-GE3_POWERPAK8-5
  oval 0.61x1.27 smd: 1(0,0) 2(1.27,0) 3(2.54,0) 4(3.81,0)
  custom 1.105x1.105 smd: 5(1.905,3.36)
SIS412DN-T1-GE3_POWERPAK8-5
  oval 0.406x0.991 smd: 1(0,0) 2(0.66,0) 3(1.32,0) 4(1.98,0)
  custom 0.559x0.559 smd: 5(0.99,2.247)
SN74LVC1G06DCKR_SC70-5
  oval 0.381x0.864 smd: 1(0,0) 2(0.65,0) 3(1.3,0) 4(1.3,1.74) 5(0,1.74)
SN74LVC1G07DCKR_SC70-5
  oval 0.381x0.864 smd: 1(0,0) 2(0.65,0) 3(1.3,0) 4(1.3,1.74) 5(0,1.74)
SN74LVC2T45DCTR_SM8
  oval 0.381x0.914 smd: 1(0,0) 2(0.65,0) 3(1.3,0) 4(1.95,0) 5(1.95,3.6) 6(1.3,3.6) 7(0.65,3.6) 8(0,3.6)
SSM3K7002FU_SC70-3
  oval 0.508x0.991 smd: 1(0,0) 2(0.65,1.9) 3(-0.65,1.9)
SUYIN_020053GR009M221ZL_9P-T
  round 1.295 hole 0.711: 1(0,0) 2(-2.5,0) 3(-4.5,0) 4(-7,0) 5(-7.5,-1.5) 6(-5.5,-1.5) 7(-3.5,-1.5) 8(-1.5,-1.5) 9(0.5,-1.5)
  oval 1.295x2.997 hole 0.711x2.388: 10(2.9,-0.75) 11(-9.9,-0.75)
  oval 1.499x2.21 hole 0.889x1.6: 12(4.35,-9.2) 13(-11.35,-9.2)
SUYIN_200277GR008M270ZR_8P-T
  round 1.6 hole 0.991: 1(0,0) 2(2,0) 3(4,0) 4(6,0) 5(8,0) 6(10,0) 7(12,0) 8(14,0)
  oval 1.397x3.454 hole 0.787x2.845: 9(17.125,0) 10(-3.125,0)
SW_SMT1-05-A_4P
  rect 0.61x0.991 smd: 1(0,0) 2(0,-4.4) 3(3.7,0) 4(3.7,-4.4)
  rect 0.457x0.991 smd: 5(-0.675,-2.2) 6(4.375,-2.2)
SY6288C20AAC_SOT23-5
  oval 0.559x0.787 smd: 1(0,0) 2(0.95,0) 3(1.9,0) 4(1.9,2.4) 5(0,2.4)
SY6288D20AAC_SOT23-5
  oval 0.559x0.787 smd: 1(0,0) 2(0.95,0) 3(1.9,0) 4(1.9,2.4) 5(0,2.4)
SY8003DFC_DFN8_2X2
  oval 0.254x0.787 smd: 1(0,0) 2(0.5,0) 3(1,0) 4(1.5,0) 5(1.5,2.2) 6(1,2.2) 7(0.5,2.2) 8(0,2.2)
  rect 1.549x0.838 smd: 9(0.75,1.1)
SYX198DQNC_QFN10_3X3
  oval 0.254x0.61 smd: 1(0,0) 2(0.45,0) 3(0.9,0) 4(1.35,0) 5(1.8,0) 6(2.25,0)
  rect 1.168x0.254 smd: 7(2.19,-0.675)
  rect 0.914x2.007 smd: 8(2.065,-2)
  custom 0.482x0.482 smd: 9(1.103,-1.775)
  rect 0.787x1.143 smd: 10(0.113,-1.6)
TAI_PSDATG-11GLBS1NN4H0_11P-T
  round 1.194 hole 1.194 unplated: (-18.375,-2.925)
  round 1.702 hole 1.702 unplated: (2.625,-2.925)
  oval 0.991x1.753 smd: 1(0,0) 2(-2.5,0) 3(-5,0) 4(-7.5,0) 5(-10,0) 6(-12.5,0) 7(-15,0) 8(-16.63,0) 9(2.5,0)
  oval 0.711x1.753 smd: 10(-17.93,0) 11(-19.13,0)
  rect 1.473x2.794 smd: 12(-20.525,-1.925) 15(4.425,-1.925)
  oval 1.194x3.912 hole 0.61x3.404: 13(-19.975,-11.775) 14(6.225,-11.775)
TAIYO_NRS4018T1R0NDGJ_2P
  rect 1.194x3.708 smd: 1(0,0) 2(2.8,0)
TOKO_FDUM0640J-H-R36M-P3_4P
  custom 0.686x0.686 smd: 1(0,0) 4(8.509,0)
  rect 2.362x0.508 smd: 2(1.448,0) 3(7.061,0)
TPC12
  round 0.305 smd: 1(0,0)
TPS22966DPUR_SON14_2X3
  oval 0.203x0.762 smd: 1(0,0) 2(0.4,0) 3(0.8,0) 4(1.2,0) 5(1.6,0) 6(2,0) 7(2.4,0) 8(2.4,2.05) 9(2,2.05) 10(1.6,2.05) 11(1.2,2.05) 12(0.8,2.05) 13(0.4,2.05) 14(0,2.05)
  rect 2.489x0.889 smd: 15(1.2,1.025)
TPS51212DSCR_SON10_3X3
  oval 0.279x0.838 smd: 1(0,0) 2(0.5,0) 3(1,0) 4(1.5,0) 5(2,0) 6(2,2.95) 7(1.5,2.95) 8(1,2.95) 9(0.5,2.95) 10(0,2.95)
  custom 0.412x0.412 smd: 11(1,1.475)
TPS51285BRUKR_QFN20_3X3
  oval 0.203x1.016 smd: 1(0,0) 2(0.4,0) 3(0.8,0) 4(1.2,0) 5(1.6,0) 11(1.6,2.975) 12(1.2,2.975) 13(0.8,2.975) 14(0.4,2.975) 15(0,2.975)
  oval 1.016x0.203 smd: 6(2.288,0.688) 7(2.288,1.088) 8(2.288,1.488) 9(2.288,1.888) 10(2.288,2.288) 16(-0.688,2.288) 17(-0.688,1.888) 18(-0.688,1.488) 19(-0.688,1.088) 20(-0.688,0.688)
  rect 1.702x1.702 smd: 21(0.8,1.488)
TVNST52302AB0_SOT523-3
  oval 0.508x0.559 smd: 1(0,0) 2(-0.5,-1.4) 3(0.5,-1.4)
W25Q64DWSSIG_SO8
  oval 0.635x1.676 smd: 1(0,0) 2(1.27,0) 3(2.54,0) 4(3.81,0) 5(3.81,7.25) 6(2.54,7.25) 7(1.27,7.25) 8(0,7.25)
Y_7V25000014_4P
  rect 1.397x1.194 smd: 1(0,0) 2(2.2,0) 3(2.2,1.7) 4(0,1.7)
Y_7V27000011_4P
  rect 1.397x1.194 smd: 1(0,0) 2(2.2,0) 3(2.2,1.7) 4(0,1.7)
Y_CM31532768DZFT_2P
  rect 1.092x1.905 smd: 1(0,0) 2(2.5,0)
Y_CRG3201212_4P
  rect 1.397x1.194 smd: 1(0,0) 2(2.2,0) 3(2.2,1.6) 4(0,1.6)
Y_X3S048000D81H-W_4P
  rect 1.397x1.194 smd: 1(0,0) 2(2.2,0) 3(2.2,1.7) 4(0,1.7)

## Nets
0.95VS_GATE: C16.1 Q84.1 R1674.2 U4.4
0.95VS_PWR_EN#: Q83.2 Q84.2 UE1.99
0.95VSDGPU_ON: C983.2 R438.2 U15.3
0.95VSDGPU_OUT: J11.1 U15.13 U15.14
0.775VALW_GATE: Q2514.2 Q2515.2 R128.2 R130.2
0.775VALW_GATE_BUFF: R54.1 R128.1 U2.7
0.775VALW_GATE_CC: Q2507.2 Q2507.3 R130.1 R917.1
3VS: J511.2 U2301.8 U2301.9
3VS_GATE: C2322.1 R2318.2 U2301.5
5VS: J509.2 J510.2 U2301.13 U2301.14
5VS_GATE: C2309.1 R2313.2 U2301.3
+0.95VALW: C940.1 C1118.1 C1119.1 PJP301.2 PJP302.2 R645.2 U4.5 U4.6 U4.7 U4.8 U15.1 U15.2 UC1.AN12 UC1.AP12
+0.95VALW_ON: C987.2 R437.2 U15.5
+0.95VALWP: PC307.1 PC310.1 PJP301.1 PJP302.1 PL302.2 PR307.2
+0.95VS: C46.1 C934.1 C935.1 C939.1 L22.2 R96.2 R1671.1 U4.1 U4.2 U4.3
+0.95VS_APU_GFX: C203.1 C245.1 C949.1 C950.1 C951.1 C1080.1 C1083.1 C1099.1 C1147.1 C1148.1 L22.1 R73.2 R404.1 R542.1 UC1.AE5 UC1.AE6 UC1.AU17 UC1.AU19 UC1.AV17 UC1.AV19 UC1.AW17 UC1.AW19
+0.95VSDGPU: CV54.1 CV55.1 CV56.1 CV57.1 CV58.1 CV59.1 CV60.1 CV197.1 CV198.1 J11.2 LV8.1 RV1.2 RV3.2 RV30.1 RV31.2 UV1.L23 UV1.L24 UV1.L25 UV1.L26 UV1.M22 UV1.N22 UV1.N23 UV1.N24 UV1.R22 UV1.T22 UV1.U22 UV1.V22
+0.675VS: C124.1 C126.1 C130.2 C131.1 C132.2 C133.1 CD76.1 CD77.1 CD78.1 CD79.1 JDIMM1.203 JDIMM1.204 JDIMM2.203 JDIMM2.204 PJP203.1
+0.675VSP: PC205.1 PC211.1 PJP203.2 PU200.2 PU200.20
+0.775VALW: C2619.1 PJP802.1 Q2515.1 Q2516.6
+1.5VS: C1005.1 C1006.1 C1007.1 PJP402.2 PR508.1 PR1028.1 R11.2 RA8.1 UA1.9
+1.5VSP: PC404.1 PC405.1 PJP402.1 PR402.1 PU400.3 PU400.4
+1.8V_ALW: C24.2 C623.2 C1085.1 C1086.1 PJP602.2 R3.1 R346.1 R347.1 R1672.1 RE69.1 U15.6 U15.7 U75.5 UC1.AP10 UC1.AR9
+1.8V_ALWP: PC603.1 PC604.1 PC605.1 PJP602.1 PL601.2 PR604.1
+1.8VGS: C622.2 CV38.1 CV39.1 CV46.1 CV170.2 CV196.1 LV2.1 LV3.1 LV6.1 LV7.1 PJP1202.2 PR1113.1 RV8.1 RV11.1 RV15.1 RV27.1 RV28.1 RV81.2 RV82.2 RV84.2 RV87.2 RV152.2 U1.8 U75.1 UV1.AM30
+1.8VGSP: PC1204.1 PC1205.1 PJP1202.1 PR1202.1 PU1200.3 PU1200.4
+1.8VS: C26.2 C1100.1 C1101.1 C1102.1 J10.2 JHDT1.1 JHDT1.19 PR506.1 PR1023.1 Q79.2 Q79.5 Q2509.2 Q2509.5 QC1.2 R2.1 R4.1 R7.1 R9.1 R10.1 R13.1 R14.1 R15.1 R80.1 R82.1 R117.2 R155.2 R159.1 R955.1 R956.1 R1675.1 RC8.2 RH45.1 RP25.6 RP25.7 RP25.8 RP27.7 RP28.5 RP28.6 RP28.7 RP28.8 U64.5 U65.5 UC1.AP16 UC1.AP18
+1.8VS_LS: J10.1 U15.8 U15.9
+1.35V: C109.2 C110.2 C111.2 C112.1 C113.1 C114.2 C115.2 C116.1 C117.2 C118.1 C125.1 C127.1 C138.1 C144.1 C149.1 C150.1 C151.1 C152.1 C155.1 C156.1 C158.1 C162.1 C164.1 C165.1 C1008.1 C1057.1 C1058.1 C1059.1 C1060.1 C1061.1 C1062.1 C1063.1 C1064.1 C1065.1 C1066.1 C1087.1 C1088.1 C1089.1 C1090.1 C1091.1 C1092.1 C1093.1 C1111.1 C1112.1 C1113.1 C1114.1 C1115.1 C1116.1 CD66.1 CD67.1 CD68.1 CD69.1 CD70.1 CD71.1 CD72.1 CD73.1 CD74.1 CD75.1 JDIMM1.75 JDIMM1.76 JDIMM1.81 JDIMM1.82 JDIMM1.87 JDIMM1.88 JDIMM1.93 JDIMM1.94 JDIMM1.99 JDIMM1.100 JDIMM1.105 JDIMM1.106 JDIMM1.111 JDIMM1.112 JDIMM1.117 JDIMM1.118 JDIMM1.123 JDIMM1.124 JDIMM2.75 JDIMM2.76 JDIMM2.81 JDIMM2.82 JDIMM2.87 JDIMM2.88 JDIMM2.93 JDIMM2.94 JDIMM2.99 JDIMM2.100 JDIMM2.105 JDIMM2.106 JDIMM2.111 JDIMM2.112 JDIMM2.117 JDIMM2.118 JDIMM2.123 JDIMM2.124 PJP200.2 PJP201.2 R5.2 R6.1 R55.2 R57.2 R75.2 UC1.AB24 UC1.AB27 UC1.AB30 UC1.AB33 UC1.AD25 UC1.AD28 UC1.AD30 UC1.AE24 UC1.AE27 UC1.AF30 UC1.AF33 UC1.AG25 UC1.AG28 UC1.AH24 UC1.AH27 UC1.AH30 UC1.AK25 UC1.AK28 UC1.AK30 UC1.AK33 UC1.AL27 UC1.AM30 UC1.P25 UC1.P28 UC1.T24 UC1.T27 UC1.U25 UC1.U28 UC1.V30 UC1.V33 UC1.W24 UC1.W27 UC1.Y25 UC1.Y28 UC1.Y30
+1.35V_MEM_GFX: CV40.1 CV41.1 CV42.1 CV43.1 CV44.1 CV45.1 CV47.1 CV48.1 CV49.1 CV50.1 CV51.1 CV52.1 CV53.1 CV103.1 CV104.1 CV105.1 CV106.1 CV107.1 CV108.1 CV109.1 CV110.1 CV111.1 CV112.1 CV113.1 CV114.1 CV115.1 CV116.1 CV117.1 CV118.1 CV119.1 CV120.1 CV121.1 CV122.1 CV123.1 CV124.1 CV125.1 CV126.1 CV127.1 CV128.1 CV129.1 CV130.1 CV131.1 CV132.1 CV136.1 CV137.1 CV138.1 CV139.1 CV140.1 CV141.1 CV142.1 CV143.1 CV144.1 CV145.1 CV146.1 CV147.1 CV148.1 CV149.1 CV150.1 CV151.1 CV152.1 CV153.1 CV154.1 CV155.1 CV156.1 CV157.1 CV158.1 CV159.1 CV160.1 CV161.1 CV162.1 CV163.1 CV164.1 CV165.1 CV171.1 CV172.1 CV173.1 CV174.1 CV175.1 CV176.1 CV177.1 CV178.1 CV179.1 CV180.1 CV181.1 CV182.1 CV183.1 PJP1401.2 RV32.1 RV33.1 RV42.1 RV43.1 RV50.1 RV51.1 UV1.H13 UV1.H16 UV1.H19 UV1.J9 UV1.J10 UV1.J23 UV1.J24 UV1.K9 UV1.K10 UV1.K23 UV1.K24 UV1.L11 UV1.L12 UV1.L13 UV1.L20 UV1.L21 UV1.L22 UV5.A1 UV5.A8 UV5.B2 UV5.C1 UV5.C9 UV5.D2 UV5.D9 UV5.E9 UV5.F1 UV5.G7 UV5.H2 UV5.H9 UV5.K2 UV5.K8 UV5.N1 UV5.N9 UV5.R1 UV5.R9 UV6.A1 UV6.A8 UV6.B2 UV6.C1 UV6.C9 UV6.D2 UV6.D9 UV6.E9 UV6.F1 UV6.G7 UV6.H2 UV6.H9 UV6.K2 UV6.K8 UV6.N1 UV6.N9 UV6.R1 UV6.R9 UV7.A1 UV7.A8 UV7.B2 UV7.C1 UV7.C9 UV7.D2 UV7.D9 UV7.E9 UV7.F1 UV7.G7 UV7.H2 UV7.H9 UV7.K2 UV7.K8 UV7.N1 UV7.N9 UV7.R1 UV7.R9 UV8.A1 UV8.A8 UV8.B2 UV8.C1 UV8.C9 UV8.D2 UV8.D9 UV8.E9 UV8.F1 UV8.G7 UV8.H2 UV8.H9 UV8.K2 UV8.K8 UV8.N1 UV8.N9 UV8.R1 UV8.R9
+1.35VGPUP: PC1408.1 PC1409.1 PC1410.1 PC1411.1 PC1412.1 PJP1401.1 PL1402.2 PR1406.1
+1.35VP: PC213.1 PC214.2 PJP200.1 PJP201.1 PL200.1 PR207.2 PU200.5 PU200.19
+3VALW: C1124.1 C1126.1 C2316.1 C2318.1 CH14.1 CL39.1 JP3.2 JPWR.1 PC802.1 PJP100.2 PJP102.2 PJP401.1 PJP601.1 PJP801.1 PJP1201.1 PJP1402.1 PR3.2 PR16.2 PR28.1 PR37.1 PR756.2 PU800.5 PU800.6 PU800.7 PU800.8 R21.1 R151.1 R348.1 R654.2 R685.1 R686.1 R905.1 R916.2 R928.1 R930.1 R931.1 R932.1 R942.1 R943.1 R944.1 R949.1 R951.1 R954.1 R1673.1 R2634.2 RA10.1 RE13.1 RE17.2 RE19.1 RE20.2 RE21.1 RE23.2 RE61.1 RE62.1 RE63.1 RE70.1 RE75.1 RE330.1 RL40.1 RM10.1 RPE1.1 RPE1.2 RV94.1 U2301.6 U2301.7 UC1.AP15 UC1.AR15 UH1.5 UL3.5
+3VALW_EC: CE3.1 CE4.1 CE10.2 CE13.2 CE14.1 CE17.1 LE3.1 RE4.2 RE13.2 RE64.1 U61.5 U62.5 U63.5 UE1.9 UE1.22 UE1.33 UE1.96 UE1.125
+3VALWP: PC101.1 PC102.1 PJP100.1 PJP102.1 PL100.2 PR109.1 PR115.1
+3VGS: C621.2 CV10.1 CV166.2 JP2.1 LV4.1 PR1115.1 QV1.2 QV1.5 RP34.1 RP34.2 RP34.3 RV5.1 RV6.1 RV58.2 RV71.2 RV72.2 RV79.2 RV91.2 RV93.1 RV146.1 RV147.1 RV148.1 RV154.1 RV162.1 U1.1 U74.1 UV2.5 UV11.1
+3VLP: JP12.1 JP14.1 PC109.1 PU100.3 RE4.1 RE14.2 RE30.1 RE49.1
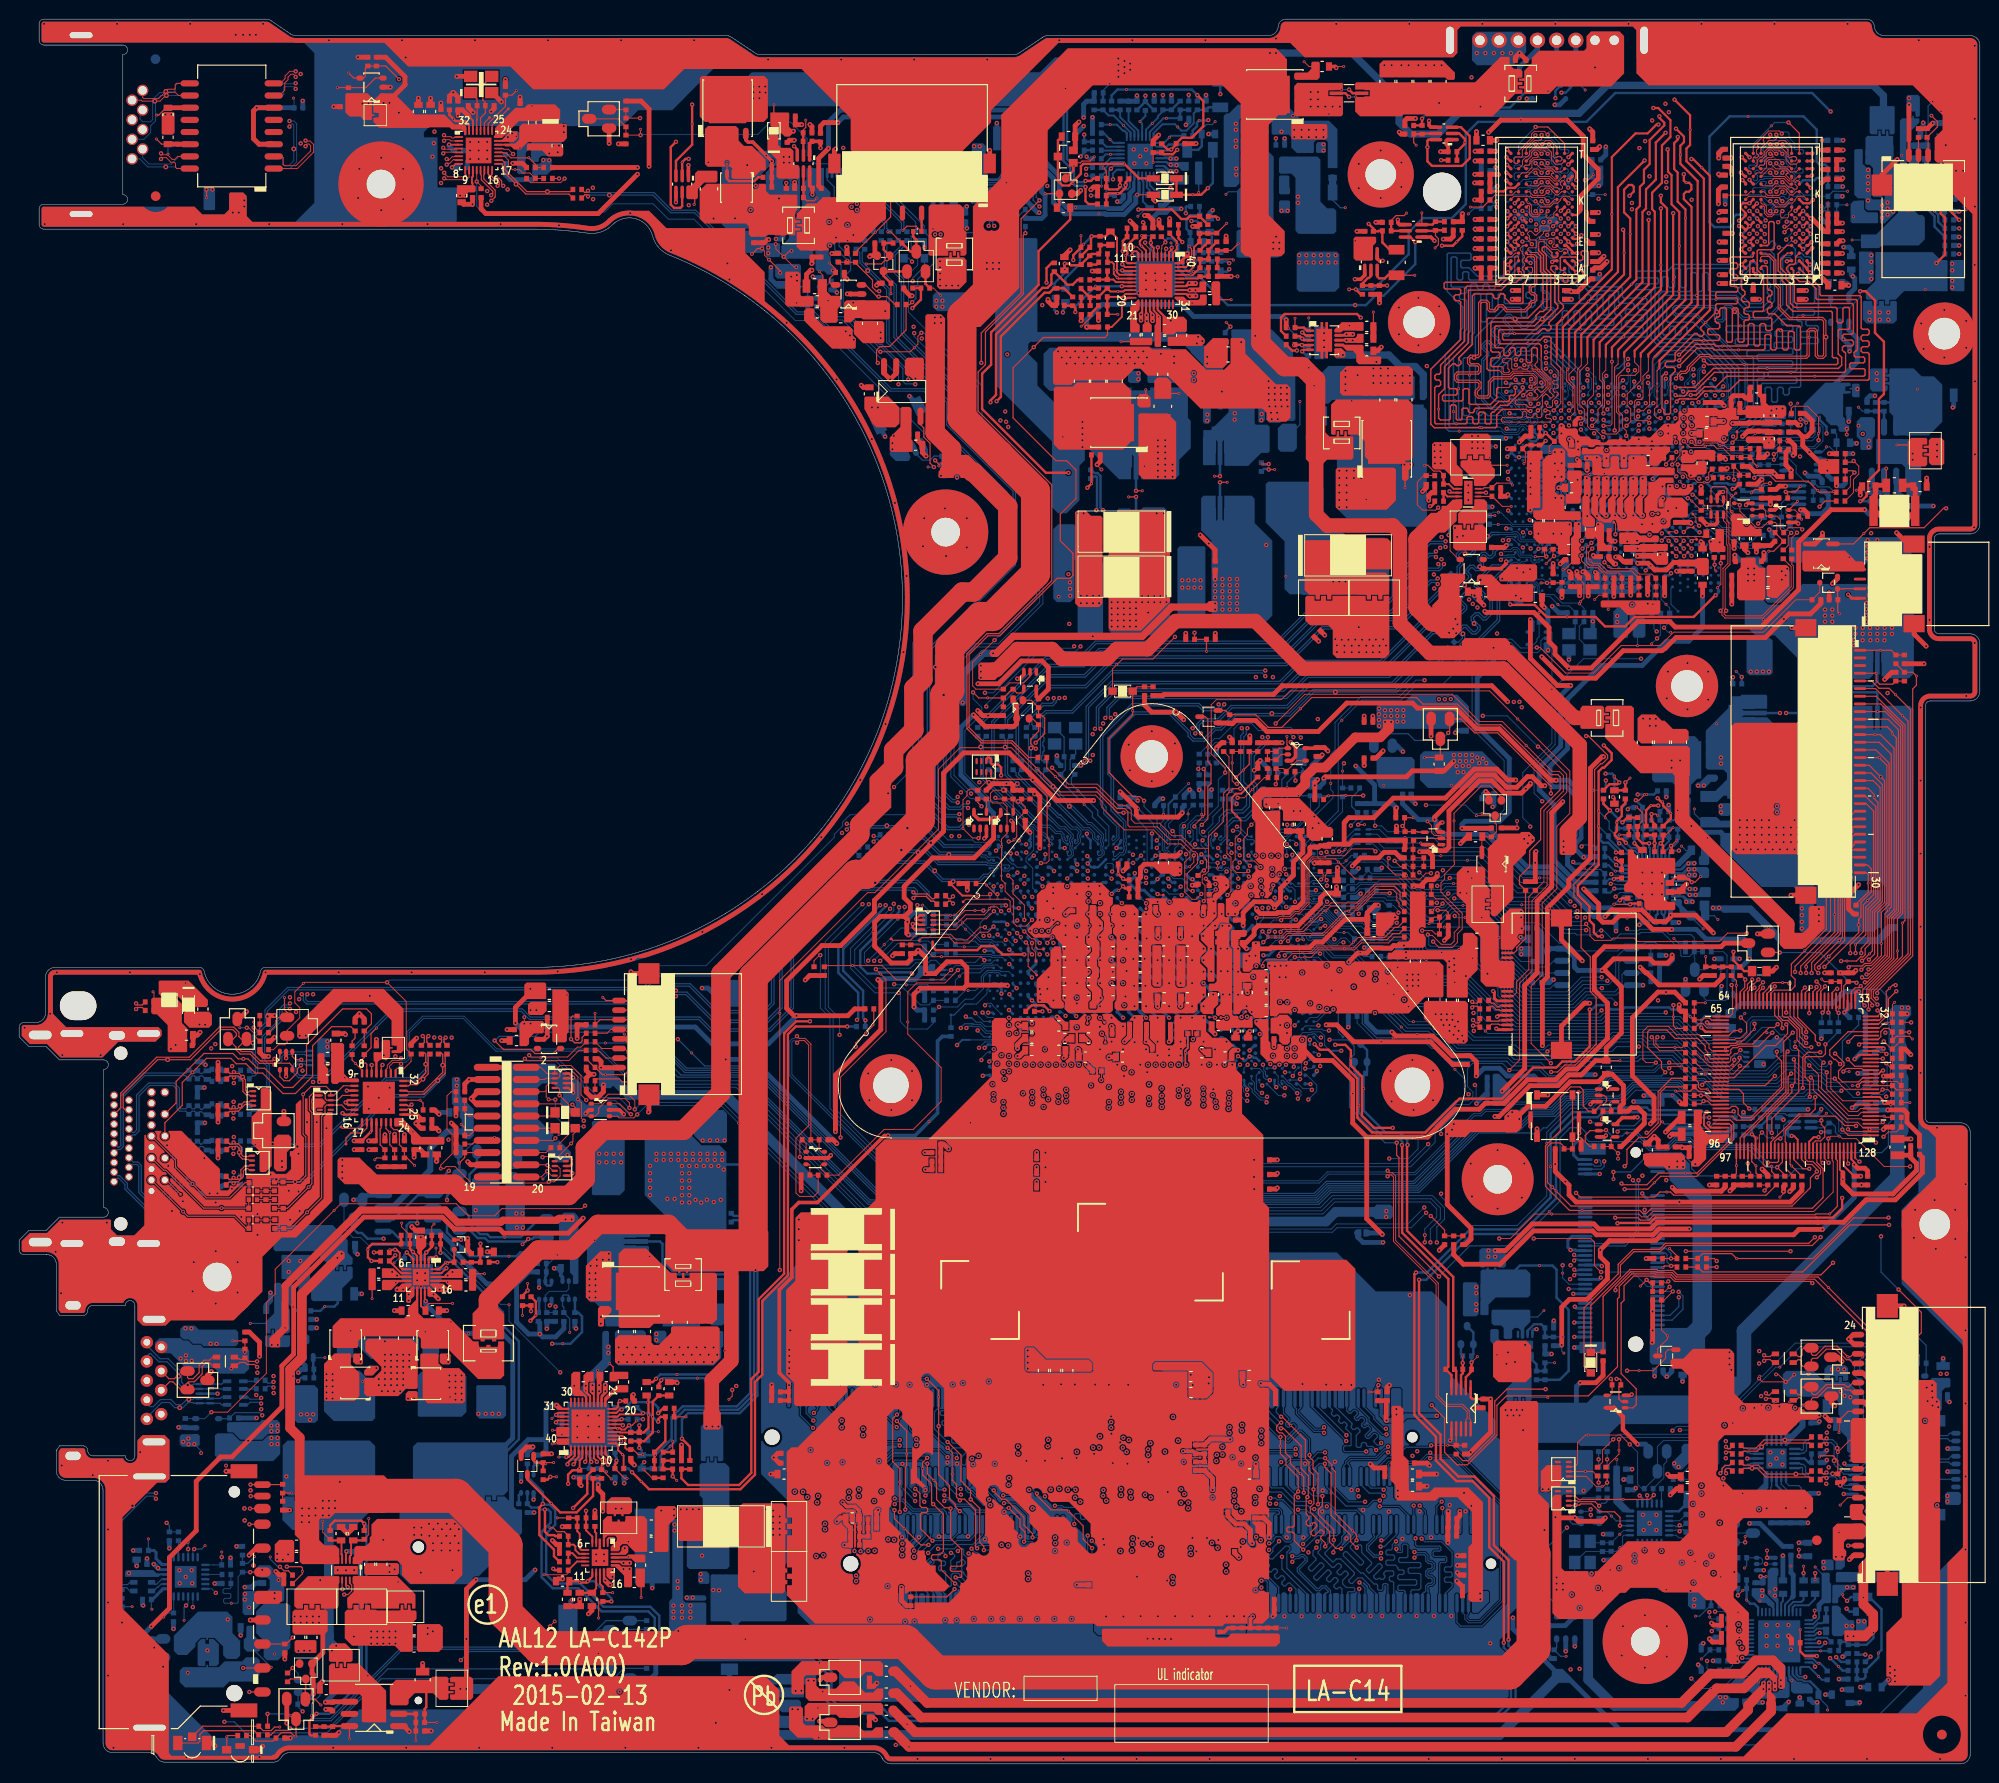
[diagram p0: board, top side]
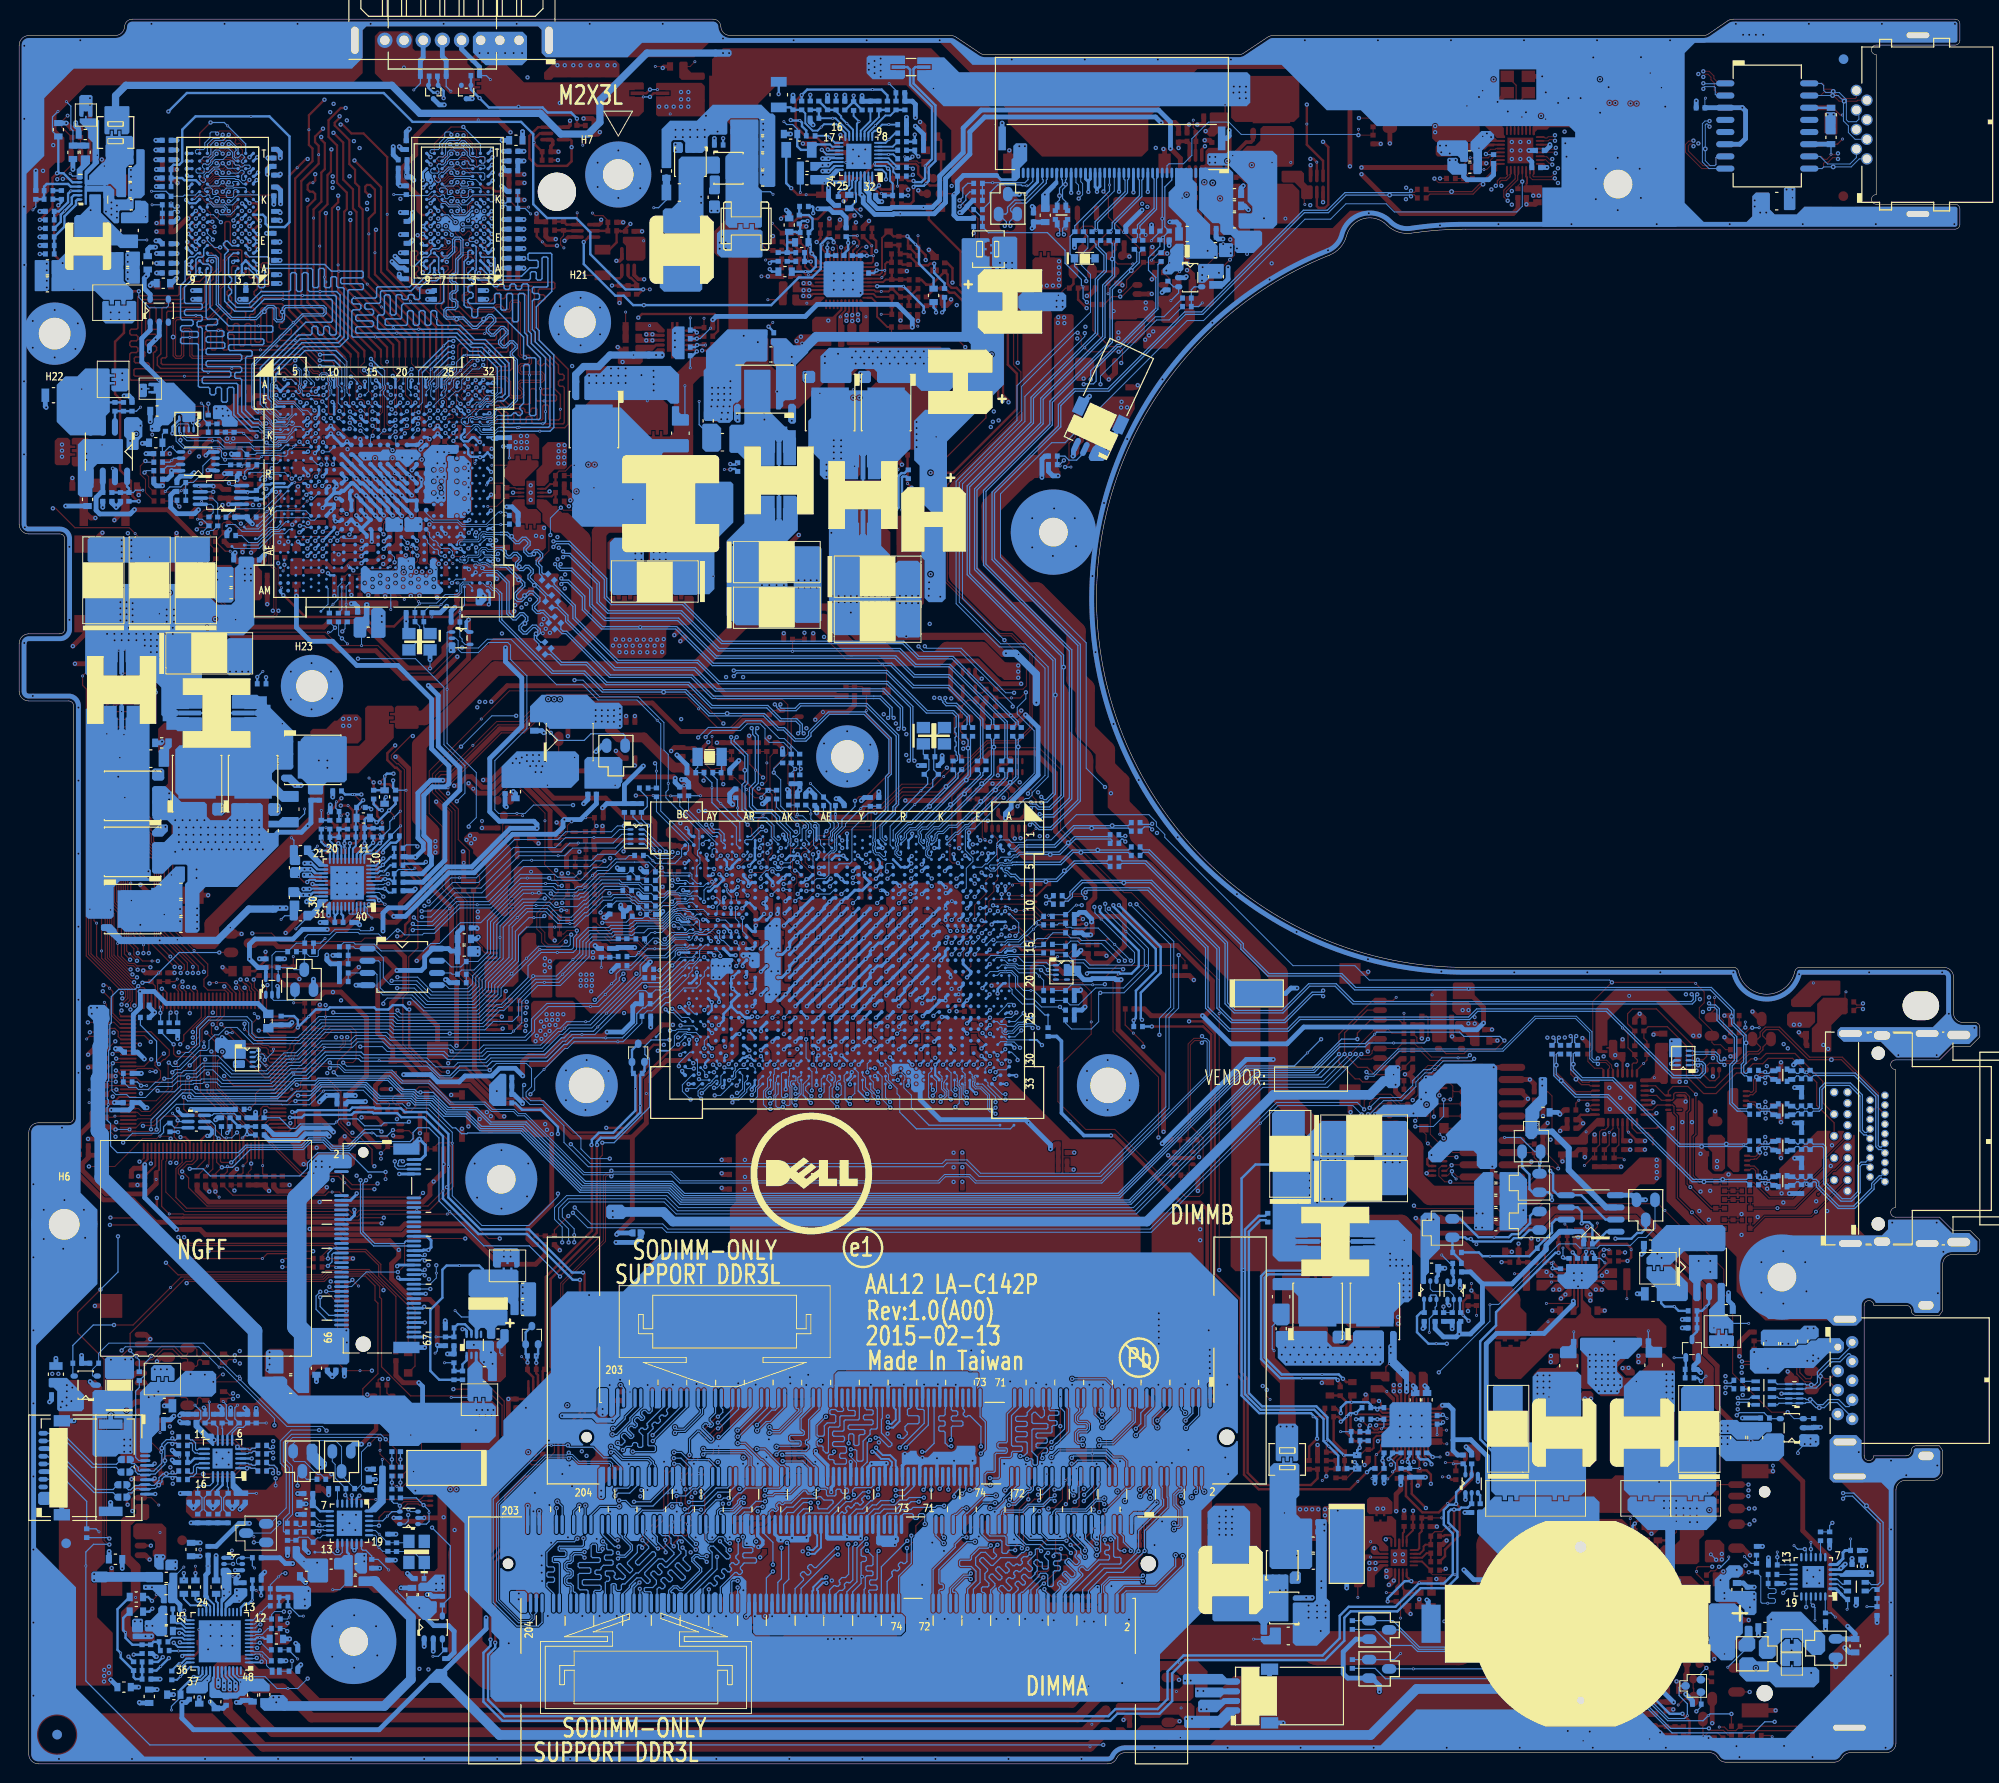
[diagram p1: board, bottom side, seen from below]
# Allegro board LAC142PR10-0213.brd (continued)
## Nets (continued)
+3VS: C136.1 C140.1 C620.2 C944.2 C945.2 C2323.1 C2324.1 C2498.1 CA57.1 CA58.1 CA59.1 CA60.1 CA66.1 CA70.1 CE45.1 CR1.1 CR2.1 CS27.1 CS42.1 CX1.1 CX7.1 J511.1 JDIMM1.199 JDIMM2.199 JP2.2 JP15.1 PR302.1 PR505.1 PR511.1 PR1021.1 PR1070.1 PR1112.1 PR1119.1 PR1407.1 Q87.2 Q2505.2 Q2505.5 Q6103.2 QH1.2 QM1.2 QX3.2 QX4.2 QX4.5 QX5.1 R16.1 R17.1 R119.1 R120.2 R134.1 R158.1 R160.1 R384.1 R618.1 R676.1 R677.1 R690.1 R693.2 R902.1 R904.1 R925.1 R934.1 R935.1 R936.1 R937.1 R938.1 R941.1 R1160.2 R1161.2 R2448.1 R6110.1 RA13.2 RC7.2 RE25.1 RE32.1 RE68.2 RE72.1 RE331.1 RH40.1 RH41.1 RH42.1 RH43.1 RH44.1 RH55.2 RL33.1 RL37.2 RM7.1 RP24.6 RP24.7 RP24.8 RP63.7 RP63.8 RPE1.3 RPE1.4 RS19.1 RS20.1 RS25.1 RS26.1 RS27.1 RS28.1 RS29.1 RS30.1 RS33.2 RS34.2 RS38.2 RX10.1 RX12.1 RX13.1 RX16.2 RX27.1 RX30.1 U5.5 U66.5 U74.5 U2407.1 UA1.1 UA1.36 UE3.5 UR1.4 UX4.5
+3VS_2168: CZ1.1 CZ2.1 JP15.2 R156.2 R157.2 RZ1.1 RZ3.1 RZ5.1 UZ1.5 UZ1.20
+3VS_2168_AV: CZ5.1 CZ24.1 R157.1 UZ1.24
+3VS_2168_DA: CZ3.1 CZ4.1 CZ26.1 R156.1 UZ1.9
+3VS_APU: C1137.1 R119.2 UC1.AP19 UC1.AP21
+3VS_CAM: JEDP.32 RX27.2
+3VS_TOUCH: C523.2 CE58.1 JTP.1 Q92.2 R18.2 R19.2 RE340.1 RE341.1 RP20.6 RP20.7 RP20.8 U78.1
+3VS_WLAN_NGFF: CM4.1 CM5.1 CM6.1 CM7.1 CM8.1 CM9.1 CM10.1 CM11.1 JNGFF.2 JNGFF.4 JNGFF.64 JNGFF.66 RM7.2 RM8.1 RM10.2
+5V_HDD: CS5.1 CS6.1 CS7.1 JHDD1.1 JHDD1.2 JHDD1.3 JHDD2.1 JHDD2.2 JP13.1
+5V_PVDD: CA53.1 CA54.1 CA55.1 CA56.1 RA1110.2 UA1.41 UA1.46
+5V_USB_PWR1: CI1.1 CI2.1 CI5.1 CI40.1 JUSB1.1 UI5.1
+5V_USB_PWR2: CI48.1 JIO1.11 JIO1.12 JIO1.13 JIO1.14 JIO1.15 UI7.1
+5VA: CA51.1 CA71.1 RA1111.2 UA1.26
+5VALW: C2305.1 C2306.1 CI12.1 CI14.1 CI18.1 CI44.1 CI45.1 PC306.1 PC402.1 PC1111.1 PC1202.1 PJP101.2 PJP103.2 PR8.1 PR206.1 PR210.2 PR1114.2 PU300.7 PU400.6 PU500.31 PU1100.26 PU1100.31 PU1200.6 Q6101.3 Q6102.3 R53.2 R54.2 R917.2 R918.2 R1674.1 R2635.2 RE504.2 RZ10.2 RZ19.2 U2.8 U15.4 U2301.1 U2301.2 U2301.4 UI5.5 UI7.5
+5VALWP: PC107.1 PC108.2 PJP101.1 PJP103.1 PL101.2 PR104.2 PU100.14
+5VS: C2307.1 C2308.1 CE27.1 CE56.1 CS15.1 D5501.2 FE1.2 J509.1 J510.1 JP7.1 JP13.2 PC503.1 PC1055.1 PR507.2 PR1026.2 PU500.12 PU500.26 PU1001.12 PU1001.26 Q20.2 Q6104.3 QS2.1 QS2.2 QS2.5 QS2.6 R138.1 R5409.1 RA1110.1 RA1111.1 RE26.1 RE59.1 RE60.1 RE73.2 RX29.1 UE6.1 UE6.2
+5VS_KBL: CE57.1 FE1.1 JKBBL.1 RE59.2
+5VS_ODD: CS10.1 CS11.1 CS12.1 JODD.10 JODD.11 JODD.12 JODD.13 JODD.14 JODD.15 JP7.2 QS2.4
+17.4V_BATT+: PC7.1 PC761.1 PC766.1 PC775.1 PC776.1 PC777.1 PJP3.2 PL3.1 PQ710.3 PR745.2 PR765.4 PR780.2
+17.4V_BATT++: PBATT1.7 PBATT1.8 PC8.1 PJP3.1 PL3.2
+19V_ADPIN: PC1.1 PC2.1 PJP1.2 PJPDC1.5 PJPDC1.6 PL1.1
+19V_VIN: PC3.1 PC4.1 PC742.2 PD704.2 PJP1.1 PL1.2 PQ740.5 PR5.1 PR7.2 PR31.2 PR721.1 PR729.1 PR739.2 PR744.2
+19VB: PD706.1 PJP104.1 PJP204.2 PJP303.1 PJP501.1 PJP701.1 PJP1001.1 PJP1101.1 PJP1403.2 PL102.1 PL201.1 PL301.2 PL501.2 PL704.1 PL1001.2 PL1101.2 PL1401.1 PQ709.4 PQ717.5 PR34.2 PR703.4 RS6.2 RX4.1
+19VB_1.35V: PC201.1 PC206.1 PC208.1 PC212.1 PJP204.1 PL201.2 PQ200.5 PR208.1
+19VB_1.35VGPU: PC1401.1 PC1405.1 PC1406.1 PC1407.1 PJP1403.1 PL1401.2 PU1400.8
+19VB_3/5V: PC105.1 PC112.1 PC113.1 PC114.1 PC115.1 PJP104.2 PL102.2 PQ101.5 PQ103.5 PU100.12
+19VB_APU: PC1000.1 PC1001.1 PC1002.1 PC1003.1 PC1005.1 PC1039.1 PC1056.1 PC1067.1 PC1069.1 PC1070.1 PC1071.1 PC1072.1 PJP1001.2 PL1001.1 PQ1001.2 PQ1007.5
+19VB_GPU: PC1103.1 PC1104.1 PC1105.1 PC1106.1 PC1107.1 PC1112.1 PC1113.1 PC1114.1 PC1115.1 PC1116.1 PJP1101.2 PL1101.1 PQ1101.5 PQ1104.5
+19VB_VDDP_ALWP: PC302.1 PC303.1 PC304.1 PC308.1 PJP303.2 PL301.1 PQ301.5
+V18R: CE44.1 RE64.2 RE69.2 UE1.124
+VBUS: C666.2 C831.2 R138.2 R149.2 U69.15
+VCC_3IN1: CR7.1 CR8.1 JREAD.4 UR1.5
+VCCK_V12: CZ6.1 CZ7.1 CZ8.1 UZ1.19 UZ1.25
+VDD_CT: CV61.1 CV62.1 CV63.1 LV3.2 UV1.AA20 UV1.AA21 UV1.AB20 UV1.AB21
+VDD_TOUCH: CX49.1 CX50.1 JEDP.40 RX28.1 RX35.1 UX3.1
+VDDCI: CV87.1 CV88.1 CV89.1 CV90.1 LV25.1 LV26.1 UV1.M13 UV1.M15 UV1.M16 UV1.M17 UV1.M18 UV1.M20 UV1.M21 UV1.N20
+VDDCR_FCH_ALW: C431.1 C432.1 C1108.1 C1109.1 C1110.1 C2620.1 C2621.1 C2622.1 Q2513.1 Q2514.1 UC1.AP13 UC1.AR12
+VDDD: C665.2 C828.2 R153.1 U69.24
+VDDD_M: R139.1 R146.2 U69.2
+VDDD_M_M: C836.1 R146.1 U69.7
+VDDR3: CV64.1 CV65.1 CV66.1 CV192.1 LV4.2 UV1.AA17 UV1.AA18 UV1.AB17 UV1.AB18
GND: C16.2 C24.1 C26.1 C27.2 C29.2 C30.1 C31.1 C32.1 C33.2 C34.2 C41.2 C43.2 C46.2 C62.2 C73.2 C109.1 C110.1 C111.1 C112.2 C113.2 C114.1 C115.1 C116.2 C117.1 C118.2 C119.2 C120.2 C124.2 C125.2 C126.2 C127.2 C130.1 C131.2 C132.1 C133.2 C134.2 C135.2 C136.2 C137.2 C138.2 C139.2 C140.2 C141.2 C142.2 C143.2 C144.2 C145.2 C146.2 C147.2 C148.2 C149.2 C150.2 C151.2 C152.2 C155.2 C156.2 C157.2 C158.2 C159.2 C160.2 C161.2 C162.2 C163.2 C164.2 C165.2 C166.2 C167.1 C168.2 C174.1 C179.1 C180.1 C183.2 C186.2 C203.2 C228.2 C229.2 C245.2 C343.1 C349.1 C431.2 C432.2 C523.1 C551.2 C553.2 C615.2 C620.1 C621.1 C622.1 C623.1 C635.2 C636.2 C665.1 C666.1 C667.2 C668.1 C682.2 C686.2 C796.2 C797.2 C828.1 C831.1 C836.2 C912.2 C923.2 C934.2 C935.2 C936.2 C939.2 C940.2 C944.1 C945.1 C949.2 C950.2 C951.2 C983.1 C987.1 C999.1 C1000.1 C1005.2 C1006.2 C1007.2 C1008.2 C1009.2 C1010.2 C1011.2 C1015.2 C1016.2 C1052.2 C1053.2 C1054.2 C1055.2 C1056.2 C1057.2 C1058.2 C1059.2 C1060.2 C1061.2 C1062.2 C1063.2 C1064.2 C1065.2 C1066.2 C1067.2 C1068.2 C1069.2 C1070.2 C1071.2 C1072.2 C1073.2 C1074.2 C1075.2 C1076.2 C1077.2 C1078.2 C1079.2 C1080.2 C1081.2 C1082.2 C1083.2 C1084.2 C1085.2 C1086.2 C1087.2 C1088.2 C1089.2 C1090.2 C1091.2 C1092.2 C1093.2 C1095.2 C1096.2 C1097.2 C1098.2 C1099.2 C1100.2 C1101.2 C1102.2 C1108.2 C1109.2 C1110.2 C1111.2 C1112.2 C1113.2 C1114.2 C1115.2 C1116.2 C1117.2 C1118.2 C1119.2 C1120.2 C1121.2 C1122.2 C1123.2 C1124.2 C1125.2 C1126.2 C1127.2 C1128.2 C1129.2 C1130.2 C1131.2 C1132.2 C1133.2 C1134.2 C1135.2 C1136.2 C1137.2 C1138.2 C1139.2 C1140.2 C1141.2 C1142.2 C1143.2 C1144.2 C1145.2 C1146.2 C1147.2 C1148.2 C1149.2 C1274.2 C1275.2 C1280.2 C2305.2 C2306.2 C2307.2 C2308.2 C2309.2 C2316.2 C2318.2 C2322.2 C2323.2 C2324.2 C2498.2 C2618.2 C2619.2 C2620.2 C2621.2 C2622.2 C5216.2 C5217.2 CA21.2 CA22.2 CA25.1 CA29.2 CA30.2 CA31.2 CA32.2 CA53.2 CA54.2 CA55.2 CA56.2 CA57.2 CA58.2 CA59.2 CA60.2 CA64.1 CA66.2 CA69.2 CA70.2 CD66.2 CD67.2 CD68.2 CD69.2 CD70.2 CD71.2 CD72.2 CD73.2 CD74.2 CD75.2 CD76.2 CD77.2 CD78.2 CD79.2 CE3.2 CE4.2 CE10.1 CE13.1 CE14.2 CE17.2 CE20.2 CE23.2 CE24.2 CE25.2 CE26.2 CE27.2 CE28.2 CE29.2 CE30.2 CE33.2 CE37.2 CE39.2 CE40.1 CE41.2 CE42.2 CE44.2 CE45.2 CE46.2 CE47.2 CE56.2 CE57.2 CE58.2 CH14.2 CH15.2 CH16.2 CH23.2 CI1.2 CI2.2 CI5.2 CI12.2 CI13.2 CI14.2 CI15.2 CI18.2 CI40.2 CI44.2 CI45.2 CI46.2 CI47.2 CI48.2 CL3.2 CL4.2 CL5.2 CL6.2 CL7.2 CL8.2 CL9.2 CL10.2 CL12.2 CL13.2 CL14.2 CL15.2 CL16.2 CL17.2 CL19.2 CL33.2 CL36.2 CL37.2 CL39.2 CL41.1 CLIP1.1(TP-1) CLIP2.1(TP-1) CLIP4.1(TP-1) CLRP1.2 CM4.2 CM5.2 CM6.2 CM7.2 CM8.2 CM9.2 CM10.2 CM11.2 CR1.2 CR2.2 CR3.1 CR4.1 CR5.2 CR6.2 CR7.2 CR8.2 CR9.2 CR11.2 CS5.2 CS6.2 CS7.2 CS10.2 CS11.2 CS12.2 CS15.2 CS16.2 CS27.2 CS42.2 CV10.2 CV11.2 CV15.2 CV17.2 CV18.2 CV19.2 CV20.2 CV21.2 CV22.2 CV26.2 CV27.2 CV28.2 CV29.2 CV30.2 CV33.2 CV34.2 CV35.2 CV38.2 CV39.2 CV40.2 CV41.2 CV42.2 CV43.2 CV44.2 CV45.2 CV46.2 CV47.2 CV48.2 CV49.2 CV50.2 CV51.2 CV52.2 CV53.2 CV54.2 CV55.2 CV56.2 CV57.2 CV58.2 CV59.2 CV60.2 CV61.2 CV62.2 CV63.2 CV64.2 CV65.2 CV66.2 CV67.2 CV68.2 CV69.2 CV70.2 CV71.2 CV72.2 CV73.2 CV74.2 CV75.2 CV76.2 CV77.2 CV78.2 CV79.2 CV80.2 CV81.2 CV82.2 CV84.2 CV85.2 CV86.2 CV87.2 CV88.2 CV89.2 CV90.2 CV91.2 CV92.2 CV93.2 CV94.2 CV95.2 CV96.2 CV97.2 CV100.2 CV101.2 CV102.2 CV103.2 CV104.2 CV105.2 CV106.2 CV107.2 CV108.2 CV109.2 CV110.2 CV111.2 CV112.2 CV113.2 CV114.2 CV115.2 CV116.2 CV117.2 CV118.2 CV119.2 CV120.2 CV121.2 CV122.2 CV123.2 CV124.2 CV125.2 CV126.2 CV127.2 CV128.2 CV129.2 CV130.2 CV131.2 CV132.2 CV133.2 CV134.2 CV135.2 CV136.2 CV137.2 CV138.2 CV139.2 CV140.2 CV141.2 CV142.2 CV143.2 CV144.2 CV145.2 CV146.2 CV147.2 CV148.2 CV149.2 CV150.2 CV151.2 CV152.2 CV153.2 CV154.2 CV155.2 CV156.2 CV157.2 CV158.2 CV159.2 CV160.2 CV161.2 CV162.2 CV163.2 CV164.2 CV165.2 CV166.1 CV167.1 CV168.1 CV169.1 CV170.1 CV171.2 CV172.2 CV173.2 CV174.2 CV175.2 CV176.2 CV177.2 CV178.2 CV179.2 CV180.2 CV181.2 CV182.2 CV183.2 CV192.2 CV193.2 CV194.1 CV195.2 CV196.2 CV197.2 CV198.2 CV199.2 CV200.2 CV201.2 CV202.2 CV203.2 CV204.2 CV205.2 CV206.2 CV207.2 CV208.2 CV209.2 CV210.2 CV211.2 CV212.2 CV213.2 CV214.2 CV215.2 CV216.2 CV217.2 CV218.2 CV357.2 CV358.2 CV359.2 CV360.2 CV361.2 CV362.2 CV363.2 CV364.2 CVT90.1 CX1.2 CX2.2 CX3.2 CX5.2 CX6.2 CX7.2 CX8.2 CX11.2 CX20.2 CX21.2 CX22.2 CX23.2 CX24.2 CX25.2 CX26.2 CX27.2 CX28.2 CX29.2 CX30.2 CX49.2 CX50.2 CX51.2 CX52.2 CZ1.2 CZ2.2 CZ3.2 CZ4.2 CZ5.2 CZ6.2 CZ7.2 CZ8.2 CZ18.2 CZ19.2 CZ20.2 CZ21.2 CZ22.2 CZ23.2 CZ24.2 CZ26.2 CZ27.2 CZ28.2 CZ29.2 CZ33.2 CZ34.2 D20.1 DA13.1 DA14.1 DI1.3 DI1.8 DI2.1 DI3.1 DI4.1 DX2.1 EC6104.2 H1.1(TP-1) H2.1(TP-1) H4.1(TP-1) H5.1(TP-1) H6.1(TP-1) H7.1(TP-1) H14.1(TP-1) H21.1(TP-1) H22.1(TP-1) H23.1(TP-1) H31.1(TP-1) H32.1(TP-1) H33.1(TP-1) HDLED1.1 JCRT.5 JCRT.6 JCRT.7 JCRT.8 JCRT.10 JCRT.16 JCRT.17 JCRT.18 JCRT.19 JDIMM1.2 JDIMM1.3 JDIMM1.8 JDIMM1.9 JDIMM1.13 JDIMM1.14 JDIMM1.19 JDIMM1.20 JDIMM1.25 JDIMM1.26 JDIMM1.31 JDIMM1.32 JDIMM1.37 JDIMM1.38 JDIMM1.43 JDIMM1.44 JDIMM1.48 JDIMM1.49 JDIMM1.54 JDIMM1.55 JDIMM1.60 JDIMM1.61 JDIMM1.65 JDIMM1.66 JDIMM1.71 JDIMM1.72 JDIMM1.127 JDIMM1.128 JDIMM1.133 JDIMM1.134 JDIMM1.138 JDIMM1.139 JDIMM1.144 JDIMM1.145 JDIMM1.150 JDIMM1.151 JDIMM1.155 JDIMM1.156 JDIMM1.161 JDIMM1.162 JDIMM1.167 JDIMM1.168 JDIMM1.172 JDIMM1.173 JDIMM1.178 JDIMM1.179 JDIMM1.184 JDIMM1.185 JDIMM1.189 JDIMM1.190 JDIMM1.195 JDIMM1.196 JDIMM1.197 JDIMM1.201 JDIMM1.205 JDIMM1.206 JDIMM2.2 JDIMM2.3 JDIMM2.8 JDIMM2.9 JDIMM2.13 JDIMM2.14 JDIMM2.19 JDIMM2.20 JDIMM2.25 JDIMM2.26 JDIMM2.31 JDIMM2.32 JDIMM2.37 JDIMM2.38 JDIMM2.43 JDIMM2.44 JDIMM2.48 JDIMM2.49 JDIMM2.54 JDIMM2.55 JDIMM2.60 JDIMM2.61 JDIMM2.65 JDIMM2.66 JDIMM2.71 JDIMM2.72 JDIMM2.127 JDIMM2.128 JDIMM2.133 JDIMM2.134 JDIMM2.138 JDIMM2.139 JDIMM2.144 JDIMM2.145 JDIMM2.150 JDIMM2.151 JDIMM2.155 JDIMM2.156 JDIMM2.161 JDIMM2.162 JDIMM2.167 JDIMM2.168 JDIMM2.172 JDIMM2.173 JDIMM2.178 JDIMM2.179 JDIMM2.184 JDIMM2.185 JDIMM2.189 JDIMM2.190 JDIMM2.195 JDIMM2.196 JDIMM2.201 JDIMM2.205 JDIMM2.206 JEDP.13 JEDP.16 JEDP.19 JEDP.23 JEDP.24 JEDP.25 JEDP.26 JEDP.29 JEDP.36 JEDP.41 JEDP.42 JFAN.3 JFAN.4 JFAN.5 JHDD1.6 JHDD1.9 JHDD1.12 JHDD1.13 JHDD1.14 JHDD2.5 JHDD2.8 JHDD2.11 JHDD2.12 JHDMI.2 JHDMI.5 JHDMI.8 JHDMI.11 JHDMI.17 JHDMI.20 JHDMI.21 JHDMI.22 JHDMI.23 JHDT1.3 JHDT1.5 JHDT1.7 JHDT1.17 JIO1.17 JIO1.20 JIO1.23 JIO1.24 JIO1.25 JIO1.26 JKB.31 JKB.32 JKBBL.5 JKBBL.6 JLAN.9 JLAN.10 JNGFF.1 JNGFF.7 JNGFF.10 JNGFF.18 JNGFF.25 JNGFF.31 JNGFF.37 JNGFF.43 JNGFF.49 JNGFF.55 JNGFF.61 JNGFF.67 JNGFF.68 JNGFF.69 JODD.1 JODD.4 JODD.7 JODD.18 JODD.19 JODD.20 JODD.21 JODD.22 JPWR.4 JPWR.5 JPWR.6 JREAD.3 JREAD.6 JREAD.12 JREAD.13 JREAD.14 JREAD.15 JRTC.2 JSPK.5 JSPK.6 JTP.4 JTP.9 JTP.10 JUSB1.4 JUSB1.7 JUSB1.10 JUSB1.11 JUSB1.12 JUSB1.13 LE4.1 LED1.3 PBATT1.1 PBATT1.2 PBATT1.3 PBATT1.9 PBATT1.10 PC1.2 PC2.2 PC3.2 PC4.2 PC5.2 PC6.2 PC7.2 PC8.2 PC13.1 PC15.2 PC100.2 PC101.2 PC103.2 PC105.2 PC106.2 PC107.2 PC109.2 PC111.2 PC112.2 PC113.2 PC114.2 PC115.2 PC201.2 PC202.2 PC203.2 PC204.1 PC205.2 PC206.2 PC208.2 PC209.2 PC210.2 PC211.2 PC212.2 PC213.2 PC301.2 PC302.2 PC303.2 PC304.2 PC306.2 PC307.2 PC308.2 PC309.2 PC310.2 PC401.2 PC402.2 PC403.2 PC405.2 PC501.2 PC502.2 PC503.2 PC504.2 PC505.2 PC506.2 PC507.2 PC508.2 PC509.1 PC511.2 PC514.2 PC518.2 PC519.2 PC521.2 PC522.2 PC523.2 PC601.2 PC602.2 PC604.2 PC605.2 PC606.2 PC705.2 PC711.1 PC745.1 PC746.1 PC748.2 PC749.1 PC751.1 PC752.1 PC753.1 PC757.1 PC758.2 PC759.2 PC760.2 PC761.2 PC762.2 PC763.2 PC764.2 PC765.2 PC766.2 PC767.2 PC768.1 PC769.1 PC775.2 PC776.2 PC777.2 PC801.1 PC802.2 PC803.2 PC804.2 PC805.2 PC836.2 PC837.2 PC838.2 PC839.2 PC953.2 PC954.2 PC955.2 PC956.2 PC959.2 PC960.2 PC967.2 PC968.2 PC969.2 PC1000.2 PC1001.2 PC1002.2 PC1003.2 PC1004.1 PC1005.2 PC1010.1 PC1013.2 PC1014.2 PC1018.1 PC1037.2 PC1039.2 PC1054.2 PC1055.2 PC1056.2 PC1058.2 PC1059.2 PC1062.1 PC1063.2 PC1064.2 PC1065.2 PC1067.2 PC1069.2 PC1070.2 PC1071.2 PC1072.2 PC1101.2 PC1103.2 PC1104.2 PC1105.2 PC1106.2 PC1107.2 PC1109.2 PC1110.2 PC1111.2 PC1112.2 PC1113.2 PC1114.2 PC1115.2 PC1116.2 PC1117.1 PC1121.2 PC1124.2 PC1128.2 PC1129.2 PC1131.2 PC1201.2 PC1202.2 PC1203.2 PC1205.2 PC1401.2 PC1402.2 PC1403.2 PC1405.2 PC1406.2 PC1407.2 PC1409.2 PC1410.2 PC1411.2 PC1412.2 PC1413.2 PC1414.2 PD2.1 PD3.1 PD101.1 PH501.1 PH1001.1 PH1002.1 PH1101.1 PJP2.1 PJPDC1.7 PJPDC1.8 PL4.2 PQ1.1 PQ1.4 PQ2.1 PQ2.4 PQ3.1 PQ3.4 PQ4.1 PQ4.4 PQ5.3 PQ102.1 PQ102.2 PQ102.3 PQ104.1 PQ104.2 PQ104.3 PQ201.1 PQ201.2 PQ201.3 PQ302.1 PQ302.2 PQ302.3 PQ502.1 PQ502.2 PQ502.3 PQ503.1 PQ503.2 PQ503.3 PQ504.3 PQ707.1 PQ707.4 PQ708.1 PQ708.2 PQ708.3 PQ711.3 PQ801.3 PQ1001.3 PQ1001.4 PQ1001.5 PQ1008.1 PQ1008.2 PQ1008.3 PQ1009.1 PQ1009.2 PQ1009.3 PQ1102.1 PQ1102.2 PQ1102.3 PQ1103.1 PQ1103.2 PQ1103.3 PQ1105.1 PQ1105.2 PQ1105.3 PQ1106.1 PQ1106.2 PQ1106.3 PR2.2 PR9.1 PR10.1 PR26.1 PR29.2 PR32.2 PR33.1 PR35.2 PR105.2 PR106.2 PR107.1 PR108.2 PR110.2 PR114.2 PR203.2 PR204.2 PR304.1 PR306.2 PR308.2 PR403.2 PR404.2 PR501.1 PR502.1 PR503.1 PR504.1 PR510.1 PR512.1 PR515.1 PR520.2 PR531.2 PR602.2 PR605.2 PR727.2 PR731.2 PR732.2 PR738.2 PR746.1 PR751.1 PR752.1 PR753.1 PR755.1 PR779.1 PR803.2 PR1005.2 PR1018.1 PR1067.2 PR1076.1 PR1078.2 PR1081.1 PR1086.1 PR1087.1 PR1101.1 PR1105.1 PR1106.1 PR1111.1 PR1117.1 PR1120.1 PR1130.2 PR1203.2 PR1204.2 PR1403.2 PR1408.2 PR1410.2 PU100.21 PU200.1 PU200.3 PU200.14 PU200.21 PU300.11 PU400.1 PU500.41 PU600.4 PU600.8 PU600.9 PU703.33 PU800.2 PU800.9 PU1001.41 PU1100.41 PU1200.1 PU1400.9 Q52.1 Q52.4 Q83.3 Q84.3 Q89.3 Q91.3 Q93.3 Q2507.1 Q2507.4 Q2516.4 QE4.3 QE5.4 QS3.3 QV8.1 QV8.4 QX3.3 R8.1 R28.1 R30.1 R40.1 R41.1 R42.1 R49.1 R51.1 R52.1 R56.1 R59.1 R90.2 R118.2 R148.2 R154.2 R365.2 R366.2 R400.2 R401.2 R452.1 R541.2 R616.1 R637.2 R638.2 R641.2 R644.2 R688.1 R689.1 R691.1 R692.1 R694.1 R695.1 R696.1 R709.1 R903.2 R926.2 R927.2 R929.2 R950.2 R952.2 R953.2 R1563.2 R2636.1 RA19.2 RA29.2 RA30.2 RA31.2 RA32.2 RA81.1 RA1113.1 RE22.1 RE24.1 RE46.2 RE48.2 RE58.2 RE67.1 RH1.1 RH26.1 RH46.1 RI1.2 RI2.2 RL27.1 RL31.1 RL35.2 RM9.2 RP27.5 RP27.6 RP30.1 RP30.2 RP30.3 RP30.4 RP34.4 RP45.1 RP45.2 RP62.1 RP62.2 RP62.3 RR1.2 RS18.2 RS21.2 RS22.1 RS23.2 RS24.2 RS31.2 RS35.2 RS36.2 RS37.2 RV2.1 RV4.2 RV9.2 RV12.2 RV13.2 RV16.2 RV17.1 RV21.1 RV29.1 RV34.2 RV35.2 RV38.2 RV39.1 RV40.1 RV41.1 RV44.2 RV45.2 RV46.2 RV47.2 RV52.2 RV53.2 RV56.2 RV57.2 RV59.1 RV73.1 RV74.1 RV83.2 RV88.1 RV89.1 RV151.1 RV160.2 RV163.2 RX9.2 RX11.2 RX13.2 RX14.2 RX24.1 RX26.2 RX34.2 RX36.2 RZ2.2 RZ4.2 RZ6.2 RZ21.2 RZ42.2 RZ45.2 RZ591.2 SW1.1 SW1.2 SW1.5 SW1.6 U1.4 U2.4 U5.3 U15.11 U15.15 U56.4 U61.3 U62.3 U63.3 U64.3 U65.3 U66.3 U69.3 U69.13 U69.16 U69.17 U69.25 U74.2 U75.2 U78.2 U101.2 U2301.11 U2301.15 U2407.6 UA1.49 UC1.A8 UC1.A12 UC1.A16 UC1.A20 UC1.A24 UC1.A28 UC1.A32 UC1.AB1 UC1.AB2 UC1.AB4 UC1.AB10 UC1.AB13 UC1.AB16 UC1.AB19 UC1.AB22 UC1.AD4 UC1.AD9 UC1.AD12 UC1.AD15 UC1.AD18 UC1.AD21 UC1.AD24 UC1.AE10 UC1.AE13 UC1.AE16 UC1.AE19 UC1.AE22 UC1.AF1 UC1.AF4 UC1.AG9 UC1.AG12 UC1.AG15 UC1.AG18 UC1.AG21 UC1.AH4 UC1.AH10 UC1.AH13 UC1.AH16 UC1.AH19 UC1.AH22 UC1.AK1 UC1.AK4 UC1.AK12 UC1.AK15 UC1.AK18 UC1.AK21 UC1.AL10 UC1.AL16 UC1.AL19 UC1.AL22 UC1.AM4 UC1.AN9 UC1.AN10 UC1.AN15 UC1.AN18 UC1.AN21 UC1.AN25 UC1.AN28 UC1.AP1 UC1.AP2 UC1.AP4 UC1.AP7 UC1.AP22 UC1.AP27 UC1.AP30 UC1.AP33 UC1.AR6 UC1.AR25 UC1.AR28 UC1.AT4 UC1.AT19 UC1.AT22 UC1.AT30 UC1.AU5 UC1.AU8 UC1.AU11 UC1.AU14 UC1.AU20 UC1.AU23 UC1.AU27 UC1.AV4 UC1.AV7 UC1.AV9 UC1.AV12 UC1.AV15 UC1.AV25 UC1.AV30 UC1.AV33 UC1.AW22 UC1.AY4 UC1.AY6 UC1.AY8 UC1.AY10 UC1.AY12 UC1.AY14 UC1.AY16 UC1.AY20 UC1.AY22 UC1.AY24 UC1.AY26 UC1.AY28 UC1.AY30 UC1.B2 UC1.B8 UC1.B12 UC1.B33 UC1.BB1 UC1.BB33 UC1.BC4 UC1.BC8 UC1.BC12 UC1.BC16 UC1.BC20 UC1.BC24 UC1.BC28 UC1.BC32 UC1.C3 UC1.D4 UC1.D6 UC1.D8 UC1.D10 UC1.D12 UC1.D14 UC1.D16 UC1.D18 UC1.D20 UC1.D22 UC1.D24 UC1.D26 UC1.D28 UC1.D30 UC1.F1 UC1.F2 UC1.F4 UC1.F9 UC1.F19 UC1.F22 UC1.F25 UC1.F30 UC1.F33 UC1.G7 UC1.G17 UC1.G20 UC1.G23 UC1.G26 UC1.H4 UC1.H30 UC1.J5 UC1.J15 UC1.J19 UC1.J22 UC1.J25 UC1.J28 UC1.K1 UC1.K2 UC1.K4 UC1.K10 UC1.K22 UC1.K27 UC1.K30 UC1.K33 UC1.L5 UC1.L12 UC1.L15 UC1.L18 UC1.L21 UC1.L24 UC1.L25 UC1.L28 UC1.M4 UC1.M30 UC1.N10 UC1.N13 UC1.N16 UC1.N19 UC1.N22 UC1.N27 UC1.P1 UC1.P2 UC1.P4 UC1.P5 UC1.P12 UC1.P15 UC1.P18 UC1.P21 UC1.P30 UC1.P33 UC1.T4 UC1.T10 UC1.T13 UC1.T16 UC1.T19 UC1.T22 UC1.T30 UC1.U5 UC1.U12 UC1.U15 UC1.U18 UC1.U21 UC1.U24 UC1.V1 UC1.V2 UC1.V4 UC1.W10 UC1.W13 UC1.W16 UC1.W19 UC1.W22 UC1.Y4 UC1.Y5 UC1.Y12 UC1.Y15 UC1.Y18 UC1.Y21 UC1.Y24 UE1.11 UE1.24 UE1.35 UE1.94 UE1.113 UE3.3 UE6.5 UE6.6 UE6.7 UE6.8 UH1.3 UI5.2 UI7.2 UL1.33 UL3.2 UL4.2 UR1.25 US2.3 US2.21 UV1.A3 UV1.A30 UV1.AA11 UV1.AA13 UV1.AA16 UV1.AA27 UV1.AB6 UV1.AB10 UV1.AB15 UV1.AB24 UV1.AB32 UV1.AC9 UV1.AC17 UV1.AC24 UV1.AC26 UV1.AC27 UV1.AD6 UV1.AD8 UV1.AD25 UV1.AD32 UV1.AE7 UV1.AE14 UV1.AE27 UV1.AF32 UV1.AG12 UV1.AG27 UV1.AH10 UV1.AH28 UV1.AH32 UV1.B6 UV1.B8 UV1.B10 UV1.B12 UV1.B14 UV1.B16 UV1.B18 UV1.B20 UV1.B22 UV1.B24 UV1.B26 UV1.C1 UV1.C32 UV1.E28 UV1.F2 UV1.F6 UV1.F8 UV1.F10 UV1.F12 UV1.F14 UV1.F16 UV1.F18 UV1.F20 UV1.F22 UV1.F24 UV1.F26 UV1.G8 UV1.G10 UV1.G27 UV1.G31 UV1.H2 UV1.H6 UV1.H14 UV1.H17 UV1.H20 UV1.J7 UV1.J27 UV1.J31 UV1.K2 UV1.K6 UV1.K11 UV1.K22 UV1.K28 UV1.K32 UV1.L27 UV1.M6 UV1.M12 UV1.M32 UV1.N11 UV1.N13 UV1.N16 UV1.N18 UV1.N21 UV1.N25 UV1.N27 UV1.P6 UV1.P9 UV1.P25 UV1.P32 UV1.R11 UV1.R12 UV1.R15 UV1.R17 UV1.R20 UV1.R27 UV1.T6 UV1.T11 UV1.T13 UV1.T16 UV1.T18 UV1.T21 UV1.T25 UV1.T32 UV1.U9 UV1.U15 UV1.U17 UV1.U20 UV1.U25 UV1.U27 UV1.V11 UV1.V13 UV1.V16 UV1.V18 UV1.V32 UV1.W25 UV1.W26 UV1.W27 UV1.Y10 UV1.Y15 UV1.Y17 UV1.Y20 UV1.Y25 UV1.Y32 UV2.3 UV4.3 UV5.A9 UV5.B1 UV5.B3 UV5.B9 UV5.D1 UV5.D8 UV5.E1 UV5.E2 UV5.E8 UV5.F9 UV5.G1 UV5.G8 UV5.G9 UV5.J2 UV5.J8 UV5.M1 UV5.M9 UV5.P1 UV5.P9 UV5.T1 UV5.T9 UV6.A9 UV6.B1 UV6.B3 UV6.B9 UV6.D1 UV6.D8 UV6.E1 UV6.E2 UV6.E8 UV6.F9 UV6.G1 UV6.G8 UV6.G9 UV6.J2 UV6.J8 UV6.M1 UV6.M9 UV6.P1 UV6.P9 UV6.T1 UV6.T9 UV7.A9 UV7.B1 UV7.B3 UV7.B9 UV7.D1 UV7.D8 UV7.E1 UV7.E2 UV7.E8 UV7.F9 UV7.G1 UV7.G8 UV7.G9 UV7.J2 UV7.J8 UV7.M1 UV7.M9 UV7.P1 UV7.P9 UV7.T1 UV7.T9 UV8.A9 UV8.B1 UV8.B3 UV8.B9 UV8.D1 UV8.D8 UV8.E1 UV8.E2 UV8.E8 UV8.F9 UV8.G1 UV8.G8 UV8.G9 UV8.J2 UV8.J8 UV8.M1 UV8.M9 UV8.P1 UV8.P9 UV8.T1 UV8.T9 UV11.5 UX3.2 UX4.2 UZ1.11 UZ1.13 UZ1.14 UZ1.16 UZ1.33 YL2.2 YL2.4 YV1.2 YV1.4
GNDA: CA23.1 CA51.2 CA61.2 CA62.1 CA63.1 CA71.2 CA74.2 JIO1.1 JIO1.9 QA6.1 QA6.4 RA12.1 RA29.1 RA30.1 RA31.1 RA32.1 RA83.2 RA84.2 UA1.25 UA1.38
V18: CR4.2 UR1.24
VCCSENSE_VGA: PR1138.2 RV159.2 RV161.1
VDD_1.35V: PC209.1 PR205.1 PR206.2 PU200.11
VDD_CHG: PC768.2 PR741.1 PR749.2 PR750.2 PR760.1 PU703.19
VDDCR_FCH_S5: PC804.1 PJP802.2 PU800.4
VDDIO_APU: PC1064.1 PR1023.2 PR1028.2 PU1001.6
VDDIO_AUDIO: R11.1 UC1.AR19
VDDIO_GFX: PC501.1 PR506.2 PR508.2 PU500.6
VDDIO_VGA: PC1101.1 PR1113.2 PR1115.2 PU1100.6
VDDP_CHG: PC769.2 PR760.2 PU703.20
VDDR4: UV1.U12 UV1.V12 UV1.Y12
VSS_MECH: UV1.A32 UV1.AM1 UV1.AM32
VSSSENSE_VGA: PR1139.2 RV158.2 RV160.1
0.95_1.8VALW_PWREN: PR301.1 PR601.2 RE46.1 UE1.127
0.775PW_EN: PR801.1 UE1.17
32K_X1: C686.1 R914.2 UC1.AT1 Y3.1
32K_X2: C682.1 R914.1 UC1.AT2 Y3.2
48M_X1: C797.1 R939.2 UC1.T2 Y2.1
48M_X2: C796.1 R939.1 UC1.T1 Y2.3
+0.775MOS: Q2516.1 R2636.2 U2.2 U2.5
+A_VCC: RA10.2 UA1.20
+APU_CORE: C1009.1 C1010.1 C1011.1 C1015.1 C1016.1 C1052.1 C1053.1 C1054.1 C1055.1 C1068.1 C1117.1 C1120.1 C1121.1 C1122.1 C1123.1 C1125.1 C1127.1 C1128.1 PC953.1 PC954.1 PC955.1 PC956.1 PL1004.4 PR1051.2 UC1.AB7 UC1.AB9 UC1.AB12 UC1.AB15 UC1.AB18 UC1.AB21 UC1.AD6 UC1.AD10 UC1.AD13 UC1.AD16 UC1.AD19 UC1.AD22 UC1.AE7 UC1.AE12 UC1.AE15 UC1.AE18 UC1.AE21 UC1.AG6 UC1.AG10 UC1.AG13 UC1.AG16 UC1.AG19 UC1.AG22 UC1.AH7 UC1.AH12 UC1.AH15 UC1.AH18 UC1.AH21 UC1.AK6 UC1.AK9 UC1.AK10 UC1.AK13 UC1.AK16 UC1.AK19 UC1.AK22 UC1.AL7 UC1.AN6 UC1.U8 UC1.W7 UC1.W12 UC1.W15 UC1.W18 UC1.W21 UC1.Y8 UC1.Y10 UC1.Y13 UC1.Y16 UC1.Y19 UC1.Y22
+APU_CORE_GFX: C1056.1 C1069.1 C1070.1 C1071.1 C1072.1 C1073.1 C1074.1 C1075.1 C1076.1 C1077.1 C1130.1 C1131.1 C1132.1 C1133.1 C1134.1 C1135.1 C1136.1 C1138.1 C1149.1 PC967.1 PC968.1 PC969.1 PL502.4 PR527.2 UC1.F12 UC1.F15 UC1.G11 UC1.G14 UC1.J8 UC1.J9 UC1.J11 UC1.K7 UC1.K12 UC1.K13 UC1.K15 UC1.K16 UC1.K19 UC1.L8 UC1.L13 UC1.L16 UC1.L19 UC1.L22 UC1.N7 UC1.N12 UC1.N15 UC1.N18 UC1.N21 UC1.P8 UC1.P13 UC1.P16 UC1.P19 UC1.P22 UC1.T7 UC1.T12 UC1.T15 UC1.T18 UC1.T21 UC1.U13 UC1.U16 UC1.U19 UC1.U22
+APU_CORE_NB: C1067.1 C1078.1 C1079.1 C1081.1 C1082.1 C1084.1 C1095.1 C1096.1 C1097.1 C1098.1 C1139.1 C1140.1 C1141.1 C1142.1 C1143.1 C1144.1 C1145.1 C1146.1 C2618.1 PC959.1 PC960.1 PL1002.4 PR1002.1 Q135.1 U2.3 UC1.AL12 UC1.AL13 UC1.AL15 UC1.AL18 UC1.AL21 UC1.AN13 UC1.AN16 UC1.AN19 UC1.AN22
+BIF_VDDC: CV168.2 CV194.2 CV195.1 RV31.1 UV1.R21 UV1.U21
+CHGRTC: D101.3 JP12.2
+CODEC_AVDD2: CA61.1 RA8.2 UA1.40
+DP_VDDC: CV30.1 CV33.1 CV34.1 RV30.2 UV1.AD14
+DP_VDDR: CV26.1 CV27.1 CV35.1 RV27.2 UV1.AF14
+EC_VCCA: CE21.1 LE3.2 PR24.2 UE1.67
+FAN_POWER: CE28.1 CE29.1 JFAN.1 UE6.3
+FBA_VREF0: CV100.1 RV42.2 RV44.1 UV5.H1 UV5.M8
+FBA_VREF1: CV101.1 RV43.2 RV45.1 UV6.H1 UV6.M8
+FBA_VREF2: CV133.1 RV50.2 RV52.1 UV7.H1 UV7.M8
+FBA_VREF3: CV134.1 RV51.2 RV53.1 UV8.H1 UV8.M8
+INV_PWR_SRC: CX5.1 CX6.1 JEDP.1 JEDP.2 RX4.2
+LAN_REGOUT: CL3.1 LL1.1 RL1.2 UL1.24
+LAN_VDD10: CL4.1 CL5.1 CL6.1 CL7.1 CL8.1 CL9.1 CL10.1 LL1.2 RL1.1 UL1.3 UL1.8 UL1.22 UL1.30
+LAN_VDD33: CL12.1 CL13.1 CL14.1 CL15.1 CL19.1 JP3.1 RL6.1 RL34.1 RL38.2 RL39.1 UL1.11 UL1.32 UL3.1
+LAN_VDDREG: CL16.1 CL17.1 RL6.2 UL1.23
+LCDVDD: LX1.1 UX4.1
+LCDVDD_CONN: CX2.1 CX3.1 CX8.1 CX11.1 JEDP.4 JEDP.5 JEDP.6 JEDP.7 LX1.2
+MEM_VREF: C29.1 C30.2 R5.1 R8.2 UC1.T32
+MIC2-VREFO: RA53.2 RA1109.2 UA1.29
+MPLL_PVDD: CV81.1 CV82.1 CV193.1 LV6.2 UV1.L8
+MVREFDA: CV94.1 RV33.2 RV34.1 UV1.K26
+MVREFSA: CV95.1 RV32.2 RV35.1 UV1.J26
+RTC_APU: C119.1 R93.2 U101.3
+RTC_APU_R: C166.1 C923.1 C1129.1 CLRP1.1 Q91.1 R93.1 UC1.AR17
+RTCBATT: JRTC.1 R31.2
+RTCVCC: C120.1 D101.1 JP14.2 RA5.1 U101.1
+SPI_VCC: C635.1 R634.2 R635.2 R636.2 R639.2 R640.2 R642.2 R1672.2 R1673.2 R1675.2 U56.8
+SPLL_PVDD: CV84.1 CV85.1 CV86.1 LV7.2 UV1.H7
+SPLL_VDDC: CV91.1 CV92.1 CV93.1 LV8.2 UV1.H8
+TPUSB_VCC: R147.1 R149.1 R152.1 R153.2 UL4.1
+TPUSB_VCC_IN: C41.1 R44.1 R151.2 R152.2 R160.2 UL4.5
+TSVDD: CV19.1 CV20.1 CV21.1 LV2.2 UV1.AD17
+V_DAC: CL41.2 TL1.3 TL1.6 TL2.3 TL2.6
+V_EC: RE25.2 RE26.2 RE27.1 RE28.1
+V_TP: C1280.1 RE330.2 RE331.2 U78.5
+V_TS: CX51.1 RX28.2 RX29.2 RX30.2 UX3.5
+V_UV4: CV22.1 RV93.2 RV94.2 UV4.5
+VDISPLAY_VCC: CX21.1 CX22.1 FX1.1 JCRT.9 JHDMI.18 RP63.5 RP63.6 RZ54.1 RZ55.1
+VGA_CORE: CV67.1 CV68.1 CV69.1 CV70.1 CV71.1 CV72.1 CV73.1 CV74.1 CV75.1 CV76.1 CV77.1 CV78.1 CV79.1 CV80.1 CV199.1 CV200.1 CV201.1 CV202.1 CV203.1 CV204.1 CV205.1 CV206.1 CV207.1 CV208.1 CV209.1 CV210.1 CV211.1 CV212.1 CV213.1 CV214.1 CV215.1 CV216.1 CV217.1 CV218.1 LV25.2 LV26.2 PC836.1 PC837.1 PC838.1 PC839.1 PL1102.4 PL1103.4 RV60.2 RV161.2 RV254.1 RV255.1 UV1.AA12 UV1.AA15 UV1.AB13 UV1.AC14 UV1.M11 UV1.N12 UV1.N15 UV1.N17 UV1.R13 UV1.R16 UV1.R18 UV1.T10 UV1.T12 UV1.T15 UV1.T17 UV1.T20 UV1.U10 UV1.U11 UV1.U13 UV1.U16 UV1.U18 UV1.V15 UV1.V17 UV1.V20 UV1.V21 UV1.W9 UV1.W10 UV1.Y9 UV1.Y13 UV1.Y16 UV1.Y18 UV1.Y21
+VREF_CA: C134.1 C139.1 C145.1 C147.1 C148.1 C159.1 C167.2 C174.2 C186.1 JDIMM1.126 JDIMM2.126 R55.1 R56.2
+VREF_DQ: C135.1 C137.1 C142.1 C143.1 C146.1 C161.1 C179.2 C180.2 C183.1 JDIMM1.1 JDIMM2.1 R57.1 R59.2 RZ1049.1
A_MIC_CLK: CA22.1 JEDP.27 LA1.2
A_MIC_DATA: JEDP.28 UA1.2
ACIN: CE40.2 PQ707.5 PR1.1 PR731.1 PR741.2 PU703.2 RV149.1 UE1.110 UV4.1
ACIN_65W: QV8.2 RE80.2 RV92.2 RV149.2 UV4.2
ACIN_CHG: PC711.2 PD706.2 PR729.2 PR732.1 PU703.1
ACLIM: PR722.1 PR749.1 PR751.2 PU703.16
ACOFF: PQ707.2 UE1.27
AD_BID0: CE39.1 RE20.1 RE22.2 UE1.66
AD_I_HW1: PQ4.2 UE1.117
AD_I_HW2: PQ4.5 UE1.107
ADP_I: PC748.1 PR23.2 PR774.1 UE1.65
AGPIO4: R931.2 UC1.AL6
AGPIO8: R22.1 R932.2 UC1.AJ4
AGPIO11: R953.1 R954.2 UC1.AN5
AGPIO25: R661.1 UC1.BC2
AGPIO64: R934.2 UC1.AW15
AGPIO65: R692.2 R693.1 UC1.AU15
AGPIO66: R935.2 UC1.AT15
AGPIO69: R936.2 UC1.AT14
APU_ALERT#: R134.2 RP25.2 UC1.B17
APU_COREGFX_SEN_H: PR527.1 PR529.2 UC1.H11
APU_COREGFX_SEN_L: PR530.2 PR531.1 R20.2
APU_DBRDY: JHDT1.14 UC1.C13
APU_DBREQ#: R672.2 RP28.4 UC1.A11
APU_DBREQ#_R: JHDT1.16 R672.1
APU_DP1_TXN0: CZ30.1 UC1.A3
APU_DP1_TXN0_VGA: CV185.1 CZ30.2 RZ1046.2
APU_DP1_TXN1: CZ31.1 UC1.A4
APU_DP1_TXN1_VGA: CV187.1 CZ31.2 RZ1048.2
APU_DP1_TXN2: CV189.1 UC1.C5
APU_DP1_TXN3: CV191.1 UC1.B5
APU_DP1_TXP0: CZ25.1 UC1.A2
APU_DP1_TXP0_VGA: CV184.1 CZ25.2 RZ1045.2
APU_DP1_TXP1: CZ32.1 UC1.B4
APU_DP1_TXP1_VGA: CV186.1 CZ32.2 RZ1047.2
APU_DP1_TXP2: CV188.1 UC1.D5
APU_DP1_TXP3: CV190.1 UC1.A5
APU_FCH_POK: RH52.1 UE1.32
APU_FCH_PWRGD: C1000.2 CH23.1 R347.2 R348.2 RH51.2 RH52.2 RH53.2 U61.2
APU_FCH_PWRGD_R: R3.2 R21.2 RH53.1 U61.4 UC1.BC9
APU_HDMI_CLK: QX4.1 R704.2 RP63.1
APU_HDMI_CLK_C: CZ17.2 R704.1 UC1.F7
APU_HDMI_DATA: QX4.4 R705.2 RP63.2
APU_HDMI_DATA_C: CZ16.2 R705.1 UC1.E7
APU_I2C0_SCL_TP: Q2509.4 R709.2 R955.2 UC1.BB10
APU_I2C0_SDA_TP: Q2509.1 R691.2 R956.2 UC1.BB9
APU_I2C1_SCL: R689.2 UC1.BB7
APU_I2C1_SDA: R688.2 UC1.BC7
APU_MAB_VREFDQ: RZ1049.2 T45.1(TP-1) UC1.A19
APU_PCIE_RST#: RH27.1 RH28.2 RH30.1 RH31.1 RH32.1 UH1.4 UV2.1
APU_PCIE_RST#_C: C912.1 R907.1 RH25.1 RH30.2
APU_PCIE_RST#_R: R907.2 UC1.AN7
APU_PCIE_WAKE#: R930.2 RE56.1 RL34.2 UC1.AG2 UL1.21
APU_PWRGD: D31.2 PU500.9 PU1001.9 R4.2 R82.2 R663.2 RH54.1 U62.4 UC1.C19
APU_PWRGD_BUF: D31.1 JHDT1.10
APU_PWRGD_EC: RH54.2 U62.2 UE1.108
APU_PWRGD_R: C32.2 R663.1 UC1.AH1
APU_RST#: D32.2 R7.2 R80.2 R662.2 RH57.1 U63.4 UC1.D15
APU_RST#_BUF: D32.1 JHDT1.12
APU_RST#_EC: RH57.2 U63.2 UE1.118
APU_RST#_R: C31.2 R662.1 UC1.AJ3
APU_SCLK0: JDIMM1.202 JDIMM2.202 R676.2 UC1.BA15
APU_SCLK1: R135.1 R685.2 UC1.AG5
APU_SDATA0: JDIMM1.200 JDIMM2.200 R677.2 UC1.AY17
APU_SDATA1: R136.1 R686.2 UC1.AG4
APU_SIC: Q79.4 R679.2 RP25.3 UC1.B18
APU_SID: Q79.1 R680.2 RP25.1 UC1.C17
APU_SPI_CLK: C27.1 R106.1 R617.1 R1691.2 U56.6
APU_SPI_CLK_R: R106.2 UC1.BC6
APU_SPI_CS1#: R107.1 R636.1 R637.1 R639.1 R1693.2 U56.1 UC1.BB8
APU_SPI_CS1#_R: R107.2 UC1.AW7
APU_SPI_HOLD#: R634.1 R642.1 U56.7 UC1.BA7
APU_SPI_MISO: R1692.2 U56.2 UC1.BA9
APU_SPI_MOSI: R1694.2 U56.5 UC1.AY7
APU_SPI_TPMCS#: R638.1 UC1.AW12
APU_SPI_WP#: R635.1 R640.1 U56.3 UC1.AW11
APU_SPKR: CH15.1 DA8.3 UC1.BA17
APU_SVC: PU1001.3 R9.2 R669.1
APU_SVC_R: R669.2 UC1.D17
APU_SVD: PU1001.5 R10.2 R670.1
APU_SVD_R: R670.2 UC1.D19
APU_SVT: PU1001.7 R2.2 R673.1
APU_SVT_R: R673.2 UC1.C15
APU_TCK: JHDT1.2 RP28.1 UC1.D13
APU_TDI: JHDT1.6 RP28.3 UC1.H15
APU_TDO: JHDT1.8 UC1.H14
APU_TEST0: R40.2 UC1.AH6
APU_TEST1: R41.2 UC1.AK8
APU_TEST2: R42.2 UC1.AE3
APU_TEST4: T34.1(TP-1) UC1.P24
APU_TEST5: T35.1(TP-1) UC1.N24
APU_TEST6: T36.1(TP-1) UC1.AN24
APU_TEST9: T38.1(TP-1) UC1.AB8
APU_TEST10: T39.1(TP-1) UC1.Y9
APU_TEST11: RP30.5 UC1.B11
APU_TEST14: RP30.8 UC1.B10
APU_TEST15: T40.1(TP-1) UC1.D11
APU_TEST16: RP30.7 UC1.A10
APU_TEST17: RP30.6 UC1.C11
APU_TEST18: JHDT1.20 RP27.4 UC1.A14
APU_TEST19: JHDT1.18 RP27.3 UC1.B14
APU_TEST28_H: T43.1(TP-1) UC1.A13
APU_TEST28_L: T42.1(TP-1) UC1.B13
APU_TEST31: T41.1(TP-1) UC1.P26
APU_TEST36: R120.1 R154.1 R155.1 UC1.E11
APU_TEST37: R117.1 R118.1 UC1.A17
APU_TEST410: T32.1(TP-1) UC1.AK24
APU_TEST411: T33.1(TP-1) UC1.AL24
APU_TMS: JHDT1.4 RP28.2 UC1.G15
APU_TRST#: C141.1 R671.1 RP27.2 UC1.J14
APU_TRST#_R: C936.1 JHDT1.9 R671.2
APU_VDD_RUN_FB_L: PR1067.1 PR1069.2 R20.1 UC1.H12
APU_VDD_SEN: PR1051.1 PR1075.2 T46.1(TP-1) UC1.G12
APU_VDDNB_SEN: PR1002.2 PR1006.1 T44.1(TP-1) UC1.J12
ASGATE: PR762.2 PU703.30
AUD_HP_OUT_L_CN: JIO1.8 LA8.1
AUD_HP_OUT_R_CN: JIO1.7 LA9.1
BA: PD705.2 PQ710.1 PR780.1
BAT_AMBER: LED1.1 R6103.1
BAT_WHITE: LED1.2 R6107.1
BATT_I: PC749.2 PR775.1 UE1.75
BATT_LOW_LED: Q6101.1 R6103.2
BATT_LOW_LED#: R6105.1 UE1.93
BATT_LOW_LED_R#: Q6101.2 R6105.2
BATT_PRS: PBATT1.4 PR15.1
BATT_TEMP: CE43.2 PC14.1 PC753.2 PD3.2 PR15.2 PR16.1 PR37.2 PR756.1 PR764.1 UE1.63
BEEP#: DA8.2 UE1.23
BKOFF#: DX1.2 U5.1 UE1.105
BP_0: RV82.1 UV1.U1
BP_1: RV81.1 UV1.U3
BST1_APU: PR1082.1 PU1001.21
BST1_GFX: PR514.1 PU500.21
BST1_VGA: PR1123.1 PU1100.21
BST2_VGA: PR1103.1 PU1100.30
BST_1.35V: PR200.2 PU200.18
BST_1.35V_R: PC200.1 PR200.1
BST_1.35VGPU: PR1405.1 PU1400.6
BST_3V: PR103.2 PU100.9
BST_5V: PR111.1 PU100.17
BST_NB: PR1008.1 PU1001.31
BST_VDDP_ALWP: PR303.1 PU300.10
BT_ON#: JNGFF.46 RH41.2 UC1.AU12
CAPS_LED: R27.1 R29.1 UE1.91
CAPS_LED_R: JKB.1 R27.2 R28.2
CCLIM: PR750.1 PR752.2 PU703.11
CLK_PCIE_LAN: UC1.U1 UL1.15
CLK_PCIE_LAN#: UC1.U2 UL1.16
CLK_PCIE_WLAN: JNGFF.39 UC1.W4
CLK_PCIE_WLAN#: JNGFF.41 UC1.W3
CLK_PEG_VGA: UC1.U4 UV1.AK30
CLK_PEG_VGA#: UC1.U3 UV1.AK32
CLK_SMB: PBATT1.6 PR18.1
CMSRC: PR763.2 PU703.29
COMP: PC751.2 PR754.2 PU703.10
CORE_NB_GATE: Q135.2 Q2513.2 R127.2 R129.2
CORE_NB_GATE_BUFF: R53.1 R127.1 U2.1 U2.6
CORE_NB_GATE_CC: Q93.1 Q2507.6 R129.1 R918.1
CORETYPE: R654.1 UC1.K24
CPU_DPB_CTRLCLK_R: D20.3 JHDMI.15 QX4.6 RP63.4
CPU_DPB_CTRLDAT_R: D20.2 JHDMI.16 QX4.3 RP63.3
CRT_B: CZ29.1 RP62.8 RZ53.1 UZ1.10
CRT_B_2: CZ23.1 JCRT.3 LZ3.2
CRT_B_C: CZ20.1 LZ3.1 RZ53.2
CRT_CLK: JCRT.15 RZ54.2 UZ1.4
CRT_DATA: JCRT.12 RZ55.2 UZ1.6
CRT_G: CZ28.1 RP62.7 RZ52.1 UZ1.12
CRT_G_2: CZ22.1 JCRT.2 LZ2.2
CRT_G_C: CZ19.1 LZ2.1 RZ52.2
CRT_HSYNC: CZ34.1 JCRT.13 RZ47.2
CRT_R: CZ27.1 RP62.6 RZ51.1 UZ1.15
CRT_R_2: CZ21.1 JCRT.1 LZ1.2
CRT_R_C: CZ18.1 LZ1.1 RZ51.2
CRT_VSYNC: CZ33.1 JCRT.14 RZ49.2
CS1_5V: PR105.1 PU100.1
CS2_3V: PR108.1 PU100.5
CS_1.35V: PR205.2 PU200.13
DAT_SMB: PBATT1.5 PR20.1
DBC_EN: RX23.1 UE1.89
DBC_EN_R: JEDP.8 RX23.2 RX36.1
DDI1_AUX_C_DN: CZ16.1 UZ1.27
DDI1_AUX_C_DP: CZ17.1 UZ1.26
DDRA_CLK0: JDIMM1.101 UC1.AE33
DDRA_CLK0#: JDIMM1.103 UC1.AE32
DDRA_CLK1: JDIMM1.102 UC1.AE30
DDRA_CLK1#: JDIMM1.104 UC1.AE31
DDRA_ODT0: JDIMM1.116 UC1.AL30
DDRA_ODT1: JDIMM1.120 UC1.AM32
DDRA_SCS0#: JDIMM1.114 UC1.AJ33
DDRA_SCS1#: JDIMM1.121 UC1.AL32
DDRAB_CKE0: JDIMM1.73 JDIMM2.73 UC1.U32
DDRAB_CKE1: JDIMM1.74 JDIMM2.74 UC1.U33
DDRAB_SBS0#: JDIMM1.109 JDIMM2.109 UC1.AH32
DDRAB_SBS1#: JDIMM1.108 JDIMM2.108 UC1.AG33
DDRAB_SBS2#: JDIMM1.79 JDIMM2.79 UC1.W31
DDRAB_SCAS#: JDIMM1.115 JDIMM2.115 UC1.AK32
DDRAB_SDM0: JDIMM1.11 JDIMM2.11 UC1.D25
DDRAB_SDM1: JDIMM1.28 JDIMM2.28 UC1.D29
DDRAB_SDM2: JDIMM1.46 JDIMM2.46 UC1.E33
DDRAB_SDM3: JDIMM1.63 JDIMM2.63 UC1.J33
DDRAB_SDM4: JDIMM1.136 JDIMM2.136 UC1.AR30
DDRAB_SDM5: JDIMM1.153 JDIMM2.153 UC1.AW30
DDRAB_SDM6: JDIMM1.170 JDIMM2.170 UC1.BC30
DDRAB_SDM7: JDIMM1.187 JDIMM2.187 UC1.BC26
DDRAB_SDQ0: JDIMM1.5 JDIMM2.5 UC1.A25
DDRAB_SDQ1: JDIMM1.7 JDIMM2.7 UC1.C25
DDRAB_SDQ2: JDIMM1.15 JDIMM2.15 UC1.C27
DDRAB_SDQ3: JDIMM1.17 JDIMM2.17 UC1.D27
DDRAB_SDQ4: JDIMM1.4 JDIMM2.4 UC1.B24
DDRAB_SDQ5: JDIMM1.6 JDIMM2.6 UC1.B25
DDRAB_SDQ6: JDIMM1.16 JDIMM2.16 UC1.B27
DDRAB_SDQ7: JDIMM1.18 JDIMM2.18 UC1.A27
DDRAB_SDQ8: JDIMM1.21 JDIMM2.21 UC1.A29
DDRAB_SDQ9: JDIMM1.23 JDIMM2.23 UC1.C29
DDRAB_SDQ10: JDIMM1.33 JDIMM2.33 UC1.B32
DDRAB_SDQ11: JDIMM1.35 JDIMM2.35 UC1.D32
DDRAB_SDQ12: JDIMM1.22 JDIMM2.22 UC1.B28
DDRAB_SDQ13: JDIMM1.24 JDIMM2.24 UC1.B29
DDRAB_SDQ14: JDIMM1.34 JDIMM2.34 UC1.A31
DDRAB_SDQ15: JDIMM1.36 JDIMM2.36 UC1.C31
DDRAB_SDQ16: JDIMM1.39 JDIMM2.39 UC1.E30
DDRAB_SDQ17: JDIMM1.41 JDIMM2.41 UC1.E31
DDRAB_SDQ18: JDIMM1.51 JDIMM2.51 UC1.G33
DDRAB_SDQ19: JDIMM1.53 JDIMM2.53 UC1.G32
DDRAB_SDQ20: JDIMM1.40 JDIMM2.40 UC1.C33
DDRAB_SDQ21: JDIMM1.42 JDIMM2.42 UC1.D33
DDRAB_SDQ22: JDIMM1.50 JDIMM2.50 UC1.G30
DDRAB_SDQ23: JDIMM1.52 JDIMM2.52 UC1.G31
DDRAB_SDQ24: JDIMM1.57 JDIMM2.57 UC1.J30
DDRAB_SDQ25: JDIMM1.59 JDIMM2.59 UC1.J31
DDRAB_SDQ26: JDIMM1.67 JDIMM2.67 UC1.L33
DDRAB_SDQ27: JDIMM1.69 JDIMM2.69 UC1.L32
DDRAB_SDQ28: JDIMM1.56 JDIMM2.56 UC1.H32
DDRAB_SDQ29: JDIMM1.58 JDIMM2.58 UC1.H33
DDRAB_SDQ30: JDIMM1.68 JDIMM2.68 UC1.L30
DDRAB_SDQ31: JDIMM1.70 JDIMM2.70 UC1.L31
DDRAB_SDQ32: JDIMM1.129 JDIMM2.129 UC1.AN31
DDRAB_SDQ33: JDIMM1.131 JDIMM2.131 UC1.AP32
DDRAB_SDQ34: JDIMM1.141 JDIMM2.141 UC1.AT32
DDRAB_SDQ35: JDIMM1.143 JDIMM2.143 UC1.AU32
DDRAB_SDQ36: JDIMM1.130 JDIMM2.130 UC1.AN33
DDRAB_SDQ37: JDIMM1.132 JDIMM2.132 UC1.AN32
DDRAB_SDQ38: JDIMM1.140 JDIMM2.140 UC1.AR31
DDRAB_SDQ39: JDIMM1.142 JDIMM2.142 UC1.AT33
DDRAB_SDQ40: JDIMM1.147 JDIMM2.147 UC1.AU30
DDRAB_SDQ41: JDIMM1.149 JDIMM2.149 UC1.AV32
DDRAB_SDQ42: JDIMM1.157 JDIMM2.157 UC1.BA33
DDRAB_SDQ43: JDIMM1.159 JDIMM2.159 UC1.AY32
DDRAB_SDQ44: JDIMM1.146 JDIMM2.146 UC1.AU33
DDRAB_SDQ45: JDIMM1.148 JDIMM2.148 UC1.AU31
DDRAB_SDQ46: JDIMM1.158 JDIMM2.158 UC1.AW31
DDRAB_SDQ47: JDIMM1.160 JDIMM2.160 UC1.AY33
DDRAB_SDQ48: JDIMM1.163 JDIMM2.163 UC1.BC31
DDRAB_SDQ49: JDIMM1.165 JDIMM2.165 UC1.BB30
DDRAB_SDQ50: JDIMM1.175 JDIMM2.175 UC1.BB28
DDRAB_SDQ51: JDIMM1.177 JDIMM2.177 UC1.AY27
DDRAB_SDQ52: JDIMM1.164 JDIMM2.164 UC1.BB32
DDRAB_SDQ53: JDIMM1.166 JDIMM2.166 UC1.BA31
DDRAB_SDQ54: JDIMM1.174 JDIMM2.174 UC1.BC29
DDRAB_SDQ55: JDIMM1.176 JDIMM2.176 UC1.BB29
DDRAB_SDQ56: JDIMM1.181 JDIMM2.181 UC1.BB27
DDRAB_SDQ57: JDIMM1.183 JDIMM2.183 UC1.BB26
DDRAB_SDQ58: JDIMM1.191 JDIMM2.191 UC1.BB24
DDRAB_SDQ59: JDIMM1.193 JDIMM2.193 UC1.AY23
DDRAB_SDQ60: JDIMM1.180 JDIMM2.180 UC1.BA27
DDRAB_SDQ61: JDIMM1.182 JDIMM2.182 UC1.BC27
DDRAB_SDQ62: JDIMM1.192 JDIMM2.192 UC1.BC25
DDRAB_SDQ63: JDIMM1.194 JDIMM2.194 UC1.BB25
DDRAB_SDQS0: JDIMM1.12 JDIMM2.12 UC1.B26
DDRAB_SDQS0#: JDIMM1.10 JDIMM2.10 UC1.A26
DDRAB_SDQS1: JDIMM1.29 JDIMM2.29 UC1.B30
DDRAB_SDQS1#: JDIMM1.27 JDIMM2.27 UC1.A30
DDRAB_SDQS2: JDIMM1.47 JDIMM2.47 UC1.F32
DDRAB_SDQS2#: JDIMM1.45 JDIMM2.45 UC1.E32
DDRAB_SDQS3: JDIMM1.64 JDIMM2.64 UC1.K32
DDRAB_SDQS3#: JDIMM1.62 JDIMM2.62 UC1.J32
DDRAB_SDQS4: JDIMM1.137 JDIMM2.137 UC1.AR32
DDRAB_SDQS4#: JDIMM1.135 JDIMM2.135 UC1.AR33
DDRAB_SDQS5: JDIMM1.154 JDIMM2.154 UC1.AW32
DDRAB_SDQS5#: JDIMM1.152 JDIMM2.152 UC1.AW33
DDRAB_SDQS6: JDIMM1.171 JDIMM2.171 UC1.BA29
DDRAB_SDQS6#: JDIMM1.169 JDIMM2.169 UC1.AY29
DDRAB_SDQS7: JDIMM1.188 JDIMM2.188 UC1.BA25
DDRAB_SDQS7#: JDIMM1.186 JDIMM2.186 UC1.AY25
DDRAB_SMA0: JDIMM1.98 JDIMM2.98 UC1.AG31
DDRAB_SMA1: JDIMM1.97 JDIMM2.97 UC1.AC30
DDRAB_SMA2: JDIMM1.96 JDIMM2.96 UC1.AC31
DDRAB_SMA3: JDIMM1.95 JDIMM2.95 UC1.AB32
DDRAB_SMA4: JDIMM1.92 JDIMM2.92 UC1.AA32
DDRAB_SMA5: JDIMM1.91 JDIMM2.91 UC1.AA33
DDRAB_SMA6: JDIMM1.90 JDIMM2.90 UC1.AA31
DDRAB_SMA7: JDIMM1.86 JDIMM2.86 UC1.Y33
DDRAB_SMA8: JDIMM1.89 JDIMM2.89 UC1.AA30
DDRAB_SMA9: JDIMM1.85 JDIMM2.85 UC1.W32
DDRAB_SMA10: JDIMM1.107 JDIMM2.107 UC1.AG32
DDRAB_SMA11: JDIMM1.84 JDIMM2.84 UC1.Y32
DDRAB_SMA12: JDIMM1.83 JDIMM2.83 UC1.W33
DDRAB_SMA13: JDIMM1.119 JDIMM2.119 UC1.AL31
DDRAB_SMA14: JDIMM1.80 JDIMM2.80 UC1.W30
DDRAB_SMA15: JDIMM1.78 JDIMM2.78 UC1.V32
DDRAB_SRAS#: JDIMM1.110 JDIMM2.110 UC1.AH33
DDRAB_SWE#: JDIMM1.113 JDIMM2.113 UC1.AJ31
DDRB_CLK0: JDIMM2.101 UC1.AD32
DDRB_CLK0#: JDIMM2.103 UC1.AD33
DDRB_CLK1: JDIMM2.102 UC1.AC33
DDRB_CLK1#: JDIMM2.104 UC1.AC32
DDRB_ODT0: JDIMM2.116 UC1.AJ32
DDRB_ODT1: JDIMM2.120 UC1.AM33
DDRB_SA0: JDIMM2.197 R690.2
DDRB_SCS0#: JDIMM2.114 UC1.AJ30
DDRB_SCS1#: JDIMM2.121 UC1.AL33
DEVSLP0_HDD: RH40.2 RS8.1 RS45.1 UC1.AT17
DEVSLP0_HDD_R: JHDD2.4 RS45.2
DEW1: RS34.1 RS36.1 US2.16
DEW2: RS33.1 RS35.1 US2.6
DGPU_PWROK: PR1122.2 UE1.18
DIR: CV167.2 CV169.2 RV79.1 U1.5
DISPOFF#: DX1.1 JEDP.21 RD16.1 RX9.1 U5.4
DP0_HPD: Q20.3 R384.2 R407.1 RC10.2 U66.2
DP1_HPD: QX5.3 RX14.1 RZ42.1 UC1.F5 UZ1.1
DP1_TXN0_C: CV185.2 CX18.2
DP1_TXN0_CRT: RZ1046.1 UZ1.30
DP1_TXN1_C: CV187.2 CX16.2
DP1_TXN1_CRT: RZ1048.1 UZ1.32
DP1_TXN2_C: CV189.2 CX14.2
DP1_TXN3_C: CV191.2 CX12.2
DP1_TXP0_C: CV184.2 CX19.2
DP1_TXP0_CRT: RZ1045.1 UZ1.29
DP1_TXP1_C: CV186.2 CX17.2
DP1_TXP1_CRT: RZ1047.1 UZ1.31
DP1_TXP2_C: CV188.2 CX15.2
DP1_TXP3_C: CV190.2 CX13.2
DP_AUX_ZVSS: R401.1 UC1.B9
DP_VSSR: UV1.AF19 UV1.AF20 UV1.AF23 UV1.AG14 UV1.AG23 UV1.AH14 UV1.AM14 UV1.AM16 UV1.AM18 UV1.AM20 UV1.AM22 UV1.AM24
DP_ZVSS: R400.1 UC1.A9
DRAM_RST: RV36.1 UV5.T2 UV6.T2 UV7.T2 UV8.T2
DRAM_RST_G: CV97.1 RV37.1 RV38.1 UV1.L10
E51_RX1: JNGFF.32 R24.2
E51_RX2: JNGFF.60 R26.2
E51_TX1: JNGFF.30 R23.2 RM9.1
E51_TX2: JNGFF.58 R25.2
EC_ENVDD: RX8.2 UE1.71
EC_I2C_TPCLK: R124.1 UE1.85
EC_I2C_TPDAT: R125.1 UE1.86
EC_LID_OUT#: CE42.1 R943.2 RE71.2 UC1.AK5
EC_LID_OUT#_R: RE71.1 UE1.101
EC_MUTE#: UA1.47 UE1.83
EC_ON: PR102.1 UE1.112
EC_PME#: RE21.2 RE56.2 UE1.29
EC_RSMRST#: CE41.1 D3.1 RE48.1 UE1.100
EC_RSMRST#_R: C999.2 D3.2 R346.2 UC1.AE4
EC_RST#: CE23.1 RE17.1 UE1.37
EC_RX: R24.1 R26.1 UE1.31
EC_SCI#: RE32.2 RE61.2 UC1.AD7 UE1.20
EC_SMB_CK1: PD2.3 PR18.2 PR770.1 RE31.1
EC_SMB_CK1_R: RE31.2 RPE1.8 UE1.77
EC_SMB_CK2: Q79.3 QV1.6 R16.2 R679.1 RE42.1 RV166.1 U2407.10 UZ1.2
EC_SMB_CK2_R: RE42.2 RPE1.6 UE1.79
EC_SMB_DA1: PD2.2 PR20.2 PR769.1 RE33.1
EC_SMB_DA1_R: RE33.2 RPE1.7 UE1.78
EC_SMB_DA2: Q79.6 QV1.3 R17.2 R680.1 RE35.1 RV167.1 U2407.9 UZ1.3
EC_SMB_DA2_R: RE35.2 RPE1.5 UE1.80
EC_SMI#: RE19.2 RE55.1 UC1.BB13
EC_SMI#_R: RE55.2 UE1.15
EC_SPI_CLK: R1691.1 UE1.126
EC_SPI_CS1#: R1693.1 UE1.128
EC_SPI_MISO: R1692.1 UE1.119
EC_SPI_MOSI: R1694.1 UE1.120
EC_TP_INT#: RE338.1 RE340.2 UE1.106
EC_TX: R23.1 R25.1 UE1.30
ECAGND: CE21.2 CE43.1 LE4.2 PH1.2 UE1.69
EDP_AUXN: C4322.2 UC1.E8
EDP_AUXN_C: C4322.1 JEDP.12 R618.2
EDP_AUXP: C4321.2 UC1.F8
EDP_AUXP_C: C4321.1 JEDP.11 R616.2
EDP_HPD: JEDP.9 Q20.1 R365.1 R407.2
EDP_HPD_R: R366.1 RC8.1 RC10.1 U66.4 UC1.G8
EDP_TXN0: C4311.2 UC1.E1
EDP_TXN0_C: C4311.1 JEDP.14
EDP_TXN1: C4313.2 UC1.E4
EDP_TXN1_C: C4313.1 JEDP.17
EDP_TXP0: C4312.2 UC1.E2
EDP_TXP0_C: C4312.1 JEDP.15
EDP_TXP1: C4314.2 UC1.E3
EDP_TXP1_C: C4314.1 JEDP.18
EN_0.675VSP: PC203.1 PR202.2 PU200.7
EN_1.8V_ALWP: PC601.1 PR601.1 PR602.1 PU600.7
EN_1.35V: PC202.1 PR201.2 PU200.8
EN_1.35VGPU: PC1402.1 PR1402.1 PR1403.1 PU1400.1
EN_3V: PD101.2 PR100.1 PU100.6
EN_5V: PD101.3 PR101.1 PU100.20
EN_DFAN1: UE1.70 UE6.4
EN_GFX: PQ504.1 PR509.1 PR532.2
EN_VDDP_ALWP: PC301.1 PR301.2 PU300.3
ENABLE_APU: PR1085.2 PU1001.8
ENABLE_GFX: PR509.2 PU500.8
ENABLE_VGA: PR1116.2 PU1100.8
ENVDD: R683.2 R1160.1 RX7.2 U64.4
ENVDD_R: R683.1 RP45.7 U64.2 UC1.G6
ENVDD_RE: RX7.1 RX8.1 UX4.4
ERP_LOT6: PC5.1 PQ1.2 PR1.2 PR2.1 UE1.73
FAN_SPEED1: CE26.1 CE37.1 JFAN.2 RE72.2 UE1.28
FB_1.8V_ALWP: PC603.2 PR604.2 PR605.1 PU600.1
FB_1.35V: PC214.1 PR204.1 PR207.1 PU200.6
FB_1.35VGPU: PR1406.2 PR1409.2 PR1410.1 PU1400.4
FB_3V: PC102.2 PR107.2 PR109.2 PU100.4
FB_5V: PC108.1 PR104.1 PR106.1 PU100.2
FB_GND: RV158.1 UV1.AD20
FB_VDDC: RV159.1 UV1.AC20
FB_VDDCI: T222.1(TP-1) UV1.W1
FB_VDDP_ALWP: PR307.1 PR308.1 PU300.4
GATEA20: R937.2 UC1.BC19 UE1.1
GFX_PWRGD: PR511.2 PR1070.2 PU500.20 PU1001.20 Q93.2 R664.2 RH51.1 UE1.74
GFX_PWRGD_APU: R664.1 UC1.AG8
GFX_SVC: PU500.3 R14.2 R675.1
GFX_SVC_R: R675.2 UC1.B16
GFX_SVD: PU500.5 R15.2 R681.1
GFX_SVD_R: R681.2 UC1.A18
GFX_SVT: PU500.7 R13.2 R682.1
GFX_SVT_R: R682.2 UC1.B15
GFX_VR_ON: PR533.1 UC1.AD8
GPIO19_CTF: RV151.2 RV152.1 UV1.M2
GPIO28: RV21.2 UV1.R5
GPU_AC_LIGHT: RE80.1 UE1.68
GPU_VID1: RV76.1 RV168.1 UV1.P8
GPU_VID1_GPIO_20: RV72.1 RV74.2 RV76.2 U1.3
GPU_VID3: RV75.1 RV169.1 UV1.N1
GPU_VID3_GPIO_15: RV71.1 RV73.2 RV75.2 U1.2
H_PROCHOT#: CE46.1 PQ2.6 PQ3.3 PQ3.6 PR505.2 PR777.1 PR1021.2 PU500.4 PU1001.4 Q89.1 R158.2 R159.2 R661.2 R1690.2 RE66.2 UC1.A15 UE3.4
HDA_BITCLK: RP13.5 UC1.AU6
HDA_BITCLK_AUDIO: RA1112.1 RP13.4 UA1.6
HDA_RST#: RP13.8 UC1.AU9
HDA_RST#_AUDIO: RA6.1 RP13.1 UA1.11
HDA_SDIN0: RA130.1 UC1.AR8
HDA_SDIN1: R695.2 UC1.AP6
HDA_SDIN2: R696.2 UC1.AR5
HDA_SDOUT: RP13.6 UC1.AR7
HDA_SDOUT_AUDIO: RP13.3 UA1.5
HDA_SYNC: RP13.7 UC1.AT9
HDA_SYNC_AUDIO: RP13.2 UA1.10
HDD_A0_PRE0: RS24.1 RS27.2 US2.9
HDD_A0_PRE1: RS23.1 RS30.2 US2.19
HDD_B0_EQ: RS37.1 RS38.1 US2.13
HDD_B0_PRE0: RS21.1 RS28.2 US2.8
HDD_B0_PRE1: RS18.1 RS29.2 US2.17
HDD_REXT_SATA0: RS26.2 RS31.1 US2.20
HDMI_HPLUG: CX20.1 JHDMI.19 RX15.2 RX34.1
HPOUT-L: RA55.1 UA1.32
HPOUT-R: RA56.1 UA1.33
HPOUT-R-L: LA8.2 RA55.2 RA80.2 RA83.1 RA165.2
HPOUT-R-R: LA9.2 RA56.2 RA82.2 RA84.1 RA166.2
HSYNC: RZ47.1 UZ1.8
HVB_FUNCTION: RH44.2 RH45.2 RH46.2 UC1.BB14
I2C1_SCL_TP_R: JTP.3 R142.2 R145.2 RE337.2
I2C1_SDA_TP_R: JTP.2 R143.2 R144.2 RE336.2
I2C_CLK: Q2505.6 R122.2 R135.2 R145.1 RP20.2
I2C_CLK_TP: Q2509.3 RE337.1
I2C_DAT: Q2505.3 R123.2 R136.2 R144.1 RP20.1
I2C_DAT_TP: Q2509.6 RE336.1
ILMT_1.35VGPU: PR1401.2 PR1408.1 PU1400.3
IMON_APU: PC1062.2 PR1076.2 PU1001.10
IMON_GFX: PC509.2 PR510.2 PU500.10
IMON_NB: PC1018.2 PR1018.2 PU1001.2
IMON_VGA: PC1117.2 PR1117.2 PU1100.10
INT-SPK-L+: LA5.1 UA1.42
INT-SPK-L-: LA6.1 UA1.43
INT-SPK-R+: LA3.1 UA1.45
INT-SPK-R-: LA4.1 UA1.44
INVTPWM: JEDP.20 R703.2 R1161.1 RX26.1 U65.4
INVTPWM_R: R703.1 U65.2 UC1.F11
ISEN1_VGA: PC1120.2 PR1124.1 PU1100.13
ISEN2_VGA: PC1119.2 PR1104.1 PU1100.12
ISOLATEB: RL33.2 RL35.1 UL1.20
JACK_SENSE#: JIO1.2 RA34.2
JHDD_P10: JHDD1.5 RS8.2
JTAG_TCK: RP34.5 UV1.L3
JTAG_TDI: RP34.7 UV1.L5
JTAG_TDO: T86.1(TP-1) UV1.K4
JTAG_TMS: RP34.6 UV1.L1
JTAG_TRSTB: RP34.8 UV1.L6
KB_BL_PWM: JKBBL.4 QE5.1 QE5.2 QE5.5 QE5.6
KB_CAPS_PWR: JKB.4 R29.2 RE73.1
KB_DET: JKBBL.2 QE4.2 RE58.1
KB_DET#: QE4.1 RE68.1 UC1.BB2
KB_LED_PWM: QE5.3 UE1.25
KB_RST#: R941.2 UC1.AY15 UE1.2
KSI0: JKB.22 UE1.55
KSI1: JKB.24 UE1.56
KSI2: JKB.26 UE1.57
KSI3: JKB.23 UE1.58
KSI4: JKB.27 UE1.59
KSI5: JKB.25 UE1.60
KSI6: JKB.28 UE1.61
KSI7: JKB.29 UE1.62
KSO0: JKB.13 UE1.39
KSO1: JKB.15 RE62.2 UE1.40
KSO2: JKB.14 RE63.2 UE1.41
KSO3: JKB.16 UE1.42
KSO4: JKB.20 UE1.43
KSO5: JKB.21 UE1.44
KSO6: JKB.18 UE1.45
KSO7: JKB.19 UE1.46
KSO8: JKB.17 UE1.47
KSO9: JKB.7 UE1.48
KSO10: JKB.5 UE1.49
KSO11: JKB.6 UE1.50
KSO12: JKB.12 UE1.51
KSO13: JKB.9 UE1.52
KSO14: JKB.8 UE1.53
KSO15: JKB.10 UE1.54
KSO16: JKB.11 UE1.81
LAN_CLKREQ#: RL37.1 UC1.BC15 UL1.12
LCD_TEST: RX2.1 UE1.72
LCD_TST_C: JEDP.10 RX2.2
LDO_3V_1.35VGPU: PC1413.1 PR1401.1 PU1400.5
LDO_EN: RZ5.2 RZ6.1 UZ1.21
LG1_APU: PQ1008.4 PQ1009.4 PU1001.24
LG1_GFX: PQ502.4 PQ503.4 PU500.24
LG1_VGA: PQ1105.4 PQ1106.4 PU1100.24
LG2_VGA: PQ1102.4 PQ1103.4 PU1100.27
LG_1.35V: PQ201.4 PU200.15
LG_3V: PQ102.4 PU100.11
LG_5V: PQ104.4 PU100.15
LG_NB: PQ1001.6 PU1001.34
LG_VDDP_ALWP: PQ302.4 PU300.6
LGATE_CHG: PQ708.4 PU703.21
LID_SW#: C33.1 D4.1 JPWR.3 RE75.2 UE1.115
LINE1-L: CA67.1 UA1.22
LINE1-R: CA68.1 UA1.21
LINE1-VREFO-L: RA165.1 UA1.31
LINE1-VREFO-R: RA166.1 UA1.30
LPC_AD0: UC1.BB11 UE1.10
LPC_AD1: UC1.BA11 UE1.8
LPC_AD2: UC1.AY11 UE1.7
LPC_AD3: UC1.BA13 UE1.5
LPC_CLK0_EC: CE30.1 R449.1 R904.2 R926.1 RE16.1 UE1.12
LPC_CLK1: R450.1 R925.2 R927.1
LPC_FRAME#: R902.2 R903.1 UC1.AV14 UE1.4
LPC_RST_A#: R602.2 UC1.BB12
LX1_APU: PC1038.2 PL1004.1 PQ1007.1 PQ1007.2 PQ1007.3 PQ1008.5 PQ1009.5 PR1074.1 PU1001.23
LX1_GFX: PC510.2 PL502.1 PQ501.1 PQ501.2 PQ501.3 PQ502.5 PQ503.5 PR516.1 PU500.23
LX1_VGA: PC1118.2 PL1103.1 PQ1104.1 PQ1104.2 PQ1104.3 PQ1105.5 PQ1106.5 PR1125.1 PU1100.23
LX2_VGA: PC1108.2 PL1102.1 PQ1101.1 PQ1101.2 PQ1101.3 PQ1102.5 PQ1103.5 PR1107.1 PU1100.28
LX_1.8V_ALWP: PL601.1 PR603.1 PU600.6
LX_1.35V: PC200.2 PC207.1 PL200.2 PQ200.1 PQ200.2 PQ200.3 PQ201.5 PU200.16
LX_1.35VGPU: PC1404.2 PL1402.1 PR1404.1 PU1400.10
LX_3V: PC104.1 PL100.1 PQ101.1 PQ101.2 PQ101.3 PQ102.5 PR113.1 PU100.8
LX_5V: PC110.2 PL101.1 PQ103.1 PQ103.2 PQ103.3 PQ104.5 PR112.1 PU100.18
LX_NB: PC1009.2 PL1002.1 PQ1001.7 PR1010.1 PU1001.33
LX_VDDP_ALWP: PC305.2 PL302.1 PQ301.1 PQ301.2 PQ301.3 PQ302.5 PR305.1 PU300.8
M_BA0: UV1.J16 UV5.M2 UV6.M2 UV7.M2 UV8.M2
M_BA1: UV1.L15 UV5.N8 UV6.N8 UV7.N8 UV8.N8
M_BA2: UV1.G11 UV5.M3 UV6.M3 UV7.M3 UV8.M3
M_CAS#0: UV1.G19 UV5.K3 UV6.K3
M_CAS#1: UV1.G16 UV7.K3 UV8.K3
M_CKE0: UV1.K20 UV5.K9 UV6.K9
M_CKE1: UV1.J17 UV7.K9 UV8.K9
M_CLK0: RV48.1 UV1.H26 UV5.J7 UV6.J7
M_CLK1: RV54.1 UV1.G9 UV7.J7 UV8.J7
M_CLK#0: RV49.1 UV1.H25 UV5.K7 UV6.K7
M_CLK#1: RV55.1 UV1.H9 UV7.K7 UV8.K7
M_CS#0: UV1.H22 UV5.L2 UV6.L2
M_CS#1: UV1.G13 UV7.L2 UV8.L2
M_DA0: UV1.K27 UV5.A2
M_DA1: UV1.J29 UV5.C2
M_DA2: UV1.H30 UV5.A3
M_DA3: UV1.H32 UV5.C3
M_DA4: UV1.G29 UV5.C8
M_DA5: UV1.F28 UV5.D7
M_DA6: UV1.F32 UV5.A7
M_DA7: UV1.F30 UV5.B8
M_DA8: UV1.C30 UV6.D7
M_DA9: UV1.F27 UV6.C8
M_DA10: UV1.A28 UV6.A7
M_DA11: UV1.C28 UV6.B8
M_DA12: UV1.E27 UV6.C2
M_DA13: UV1.G26 UV6.A3
M_DA14: UV1.D26 UV6.C3
M_DA15: UV1.F25 UV6.A2
M_DA16: UV1.A25 UV5.G2
M_DA17: UV1.C25 UV5.E3
M_DA18: UV1.E25 UV5.H3
M_DA19: UV1.D24 UV5.H8
M_DA20: UV1.E23 UV5.H7
M_DA21: UV1.F23 UV5.F2
M_DA22: UV1.D22 UV5.F8
M_DA23: UV1.F21 UV5.F7
M_DA24: UV1.E21 UV6.F8
M_DA25: UV1.D20 UV6.H7
M_DA26: UV1.F19 UV6.H8
M_DA27: UV1.A19 UV6.F7
M_DA28: UV1.D18 UV6.G2
M_DA29: UV1.F17 UV6.H3
M_DA30: UV1.A17 UV6.E3
M_DA31: UV1.C17 UV6.F2
M_DA32: UV1.E17 UV7.H8
M_DA33: UV1.D16 UV7.H7
M_DA34: UV1.F15 UV7.G2
M_DA35: UV1.A15 UV7.F8
M_DA36: UV1.D14 UV7.F7
M_DA37: UV1.F13 UV7.F2
M_DA38: UV1.A13 UV7.E3
M_DA39: UV1.C13 UV7.H3
M_DA40: UV1.E11 UV7.B8
M_DA41: UV1.A11 UV7.D7
M_DA42: UV1.C11 UV7.A7
M_DA43: UV1.F11 UV7.C8
M_DA44: UV1.A9 UV7.C3
M_DA45: UV1.C9 UV7.C2
M_DA46: UV1.F9 UV7.A2
M_DA47: UV1.D8 UV7.A3
M_DA48: UV1.E7 UV8.G2
M_DA49: UV1.A7 UV8.E3
M_DA50: UV1.C7 UV8.H3
M_DA51: UV1.F7 UV8.F2
M_DA52: UV1.A5 UV8.H7
M_DA53: UV1.E5 UV8.F7
M_DA54: UV1.C3 UV8.F8
M_DA55: UV1.E1 UV8.H8
M_DA56: UV1.G7 UV8.C2
M_DA57: UV1.G6 UV8.A2
M_DA58: UV1.G1 UV8.A3
M_DA59: UV1.G3 UV8.C3
M_DA60: UV1.J6 UV8.D7
M_DA61: UV1.J1 UV8.B8
M_DA62: UV1.J3 UV8.A7
M_DA63: UV1.J5 UV8.C8
M_DQM0: UV1.E32 UV5.D3
M_DQM1: UV1.E30 UV6.D3
M_DQM2: UV1.A21 UV5.E7
M_DQM3: UV1.C21 UV6.E7
M_DQM4: UV1.E13 UV7.E7
M_DQM5: UV1.D12 UV7.D3
M_DQM6: UV1.E3 UV8.E7
M_DQM7: UV1.F4 UV8.D3
M_DQS0: UV1.H28 UV5.C7
M_DQS1: UV1.C27 UV6.C7
M_DQS2: UV1.A23 UV5.F3
M_DQS3: UV1.E19 UV6.F3
M_DQS4: UV1.E15 UV7.F3
M_DQS5: UV1.D10 UV7.C7
M_DQS6: UV1.D6 UV8.F3
M_DQS7: UV1.G5 UV8.C7
M_DQS#0: UV1.H27 UV5.B7
M_DQS#1: UV1.A27 UV6.B7
M_DQS#2: UV1.C23 UV5.G3
M_DQS#3: UV1.C19 UV6.G3
M_DQS#4: UV1.C15 UV7.G3
M_DQS#5: UV1.E9 UV7.B7
M_DQS#6: UV1.C5 UV8.G3
M_DQS#7: UV1.H4 UV8.B7
M_MA0: UV1.K17 UV5.N3 UV6.N3 UV7.N3 UV8.N3
M_MA1: UV1.J20 UV5.P7 UV6.P7 UV7.P7 UV8.P7
M_MA2: UV1.H23 UV5.P3 UV6.P3 UV7.P3 UV8.P3
M_MA3: UV1.G23 UV5.N2 UV6.N2 UV7.N2 UV8.N2
M_MA4: UV1.G24 UV5.P8 UV6.P8 UV7.P8 UV8.P8
M_MA5: UV1.H24 UV5.P2 UV6.P2 UV7.P2 UV8.P2
M_MA6: UV1.J19 UV5.R8 UV6.R8 UV7.R8 UV8.R8
M_MA7: UV1.K19 UV5.R2 UV6.R2 UV7.R2 UV8.R2
M_MA8: UV1.J14 UV5.T8 UV6.T8 UV7.T8 UV8.T8
M_MA9: UV1.K14 UV5.R3 UV6.R3 UV7.R3 UV8.R3
M_MA10: UV1.J11 UV5.L7 UV6.L7 UV7.L7 UV8.L7
M_MA11: UV1.J13 UV5.R7 UV6.R7 UV7.R7 UV8.R7
M_MA12: UV1.H11 UV5.N7 UV6.N7 UV7.N7 UV8.N7
M_MA13: UV1.G20 UV5.T3 UV6.T3 UV7.T3 UV8.T3
M_MA14: UV1.G14 UV5.T7 UV6.T7 UV7.T7 UV8.T7
M_MA15: UV1.L17 UV5.M7 UV6.M7 UV7.M7 UV8.M7
M_RAS#0: UV1.G22 UV5.J3 UV6.J3
M_RAS#1: UV1.G17 UV7.J3 UV8.J3
M_WE#0: UV1.G25 UV5.L3 UV6.L3
M_WE#1: UV1.H10 UV7.L3 UV8.L3
MCT0: RL19.1 TL1.11
MCT1: RL20.1 TL1.14
MCT2: RL41.1 TL2.14
MCT3: RL42.1 TL2.11
MDI0+: TL1.8 UL1.1
MDI0-: TL1.7 UL1.2
MDI1+: TL1.2 UL1.4
MDI1-: TL1.1 UL1.5
MDI2+: TL2.1 UL1.6
MDI2-: TL2.2 UL1.7
MDI3+: TL2.7 UL1.9
MDI3-: TL2.8 UL1.10
MDO0+: JLAN.1 TL1.9
MDO0-: JLAN.2 TL1.10
MDO1+: JLAN.3 TL1.15
MDO1-: JLAN.6 TL1.16
MDO2+: JLAN.4 TL2.16
MDO2-: JLAN.5 TL2.15
MDO3+: JLAN.7 TL2.10
MDO3-: JLAN.8 TL2.9
MEM_MAB_EVENT#: JDIMM1.198 JDIMM2.198 R6.2 UC1.AG30
MEM_MAB_RST#: C1274.1 C1275.1 JDIMM1.30 JDIMM2.30 UC1.T33
MEM_MAB_ZVDDIO: R75.1 UC1.AF32
MEM_VOLT_SEL: R928.2 R929.1 UC1.AL5
MIC1-L: CA74.1 UA1.19
MIC_CLK_C: LA1.1 UA1.3
MS_CLK_SD_WP: CR5.1 JREAD.11 R810.1 RR3.2
MS_CLK_SD_WP_R: RR3.1 UR1.8
MS_D1_SD_D3: JREAD.1 UR1.20
MS_D2_SD_CLK: CR6.1 JREAD.5 R809.1 RR2.2
MS_D2_SD_CLK_R: RR2.1 UR1.15
OCP_L: PR1112.2 PU1100.4 RV90.2
ODD_DA#: C229.1 JODD.17 QH1.3 RH55.1
ODD_DA#_FCH: QH1.1 UC1.AJ1
ODD_DETECT#: C228.1 JODD.8 UC1.AG3
ODD_EN: CS16.1 QS2.3 QS3.1 RS6.1
ODD_EN#: QS3.2 UC1.AY5
ON/OFF: C34.1 CE20.1 JPWR.2 RE49.2 SW1.3 SW1.4 UE1.114
P_ZVDDP: R404.2 R542.2 UC1.U7
P_ZVSS: R73.1 R541.1 UC1.U6
PACIN#: QV8.5 QV8.6 RV147.2
PANEL_BKLEN: QC1.1 RC7.1 RC9.2 RD16.2 U5.2 UE1.76
PANEL_BKLEN_EC: QC1.3 RC9.1 RP45.8 UC1.G5
PANEL_SIZE_ID: RX3.1 RX11.1 RX16.1 UC1.BC13
PANEL_SIZE_ID_CONN: JEDP.22 RX3.2
PBTN_OUT#: R942.2 UC1.AE1 UE1.122
PC_BEEP: DA8.1 RA19.1 RA79.2
PCC_GPIO_6: CVT90.2 RV90.1 RV91.1 UV1.T8
PCIE_ARX_DTX_N0: CL31.1 UC1.U9
PCIE_ARX_DTX_N0_C: CL31.2 UL1.18
PCIE_ARX_DTX_N1: JNGFF.35 UC1.T5
PCIE_ARX_DTX_P0: CL30.1 UC1.U10
PCIE_ARX_DTX_P0_C: CL30.2 UL1.17
PCIE_ARX_DTX_P1: JNGFF.33 UC1.T6
PCIE_ATX_C_DRX_N0: C225.2 UL1.14
PCIE_ATX_C_DRX_N1: C227.2 JNGFF.29
PCIE_ATX_C_DRX_P0: C224.2 UL1.13
PCIE_ATX_C_DRX_P1: C226.2 JNGFF.27
PCIE_ATX_DRX_N0: C225.1 UC1.R2
PCIE_ATX_DRX_N1: C227.1 UC1.R3
PCIE_ATX_DRX_P0: C224.1 UC1.R1
PCIE_ATX_DRX_P1: C226.1 UC1.R4
PEG_CLKREQ#: RH56.2 RV153.1
PEG_CLKREQ#_G: RV153.2 UV1.N7
PEG_CLKREQ#_R: RH56.1 UC1.BB16
PEG_GTX_C_HRX_N0: CV2.1 UC1.P9
PEG_GTX_C_HRX_N1: CV4.1 UC1.N5
PEG_GTX_C_HRX_N2: CV6.1 UC1.N8
PEG_GTX_C_HRX_N3: CV8.1 UC1.L6
PEG_GTX_C_HRX_P0: CV1.1 UC1.P10
PEG_GTX_C_HRX_P1: CV3.1 UC1.N6
PEG_GTX_C_HRX_P2: CV5.1 UC1.N9
PEG_GTX_C_HRX_P3: CV7.1 UC1.L7
PEG_GTX_HRX_N0: CV2.2 UV1.AG31
PEG_GTX_HRX_N1: CV4.2 UV1.AF28
PEG_GTX_HRX_N2: CV6.2 UV1.AF26
PEG_GTX_HRX_N3: CV8.2 UV1.AD26
PEG_GTX_HRX_P0: CV1.2 UV1.AH30
PEG_GTX_HRX_P1: CV3.2 UV1.AG29
PEG_GTX_HRX_P2: CV5.2 UV1.AF27
PEG_GTX_HRX_P3: CV7.2 UV1.AD27
PEG_HTX_C_GRX_N0: C176.2 UV1.AE31
PEG_HTX_C_GRX_N1: C178.2 UV1.AD28
PEG_HTX_C_GRX_N2: C177.2 UV1.AC31
PEG_HTX_C_GRX_N3: C175.2 UV1.AB28
PEG_HTX_C_GRX_P0: C185.2 UV1.AF30
PEG_HTX_C_GRX_P1: C215.2 UV1.AE29
PEG_HTX_C_GRX_P2: C223.2 UV1.AD30
PEG_HTX_C_GRX_P3: C196.2 UV1.AC29
PEG_HTX_GRX_N0: C176.1 UC1.M1
PEG_HTX_GRX_N1: C178.1 UC1.L2
PEG_HTX_GRX_N2: C177.1 UC1.L3
PEG_HTX_GRX_N3: C175.1 UC1.J2
PEG_HTX_GRX_P0: C185.1 UC1.M2
PEG_HTX_GRX_P1: C215.1 UC1.L1
PEG_HTX_GRX_P2: C223.1 UC1.L4
PEG_HTX_GRX_P3: C196.1 UC1.J1
PGOOD_1.35VGPU: PR1407.2 PU1400.2
PHASE_CHG: PC721.2 PL700.1 PQ704.1 PQ704.2 PQ704.3 PQ708.5 PR766.1 PU703.22
PID0: CE47.1 RE23.1 RE24.2 UE1.97
PLL_ANALOG_IN: T221.1(TP-1) UV1.AA1
PLL_ANALOG_OUT: RV83.1 UV1.AA3
PLT_RST#: C615.1 R602.1 RH1.2 RH27.2 RH29.1 RM6.2 UE1.13
PLT_RST#_R: RH29.2 RH31.2 UL1.19
PLT_RST#_RW: JNGFF.44 RH32.2 RM6.1
PLT_RST_VGA#: RV4.1 UV1.AL27 UV2.4
PM_SLP_S3#: CE25.1 RE53.1 UC1.AK7
PM_SLP_S3#_R: RE53.2 UE1.6
PM_SLP_S5#: CE33.1 PR781.1 RE54.1 UC1.AH5
PM_SLP_S5#_R: RE54.2 UE1.14
POK: PR115.2 PU100.7 UE1.34
POL1_SDA: RZ1.2 RZ2.1 UZ1.22
POL2_SCL: RZ3.2 RZ4.1 UZ1.23
PROG: PR753.2 PU703.9
PS_0: CV29.1 RV8.2 RV9.1 UV1.AC19
PS_1: CV28.1 RV11.2 RV12.1 UV1.AD19
PS_2: CV11.1 RV13.1 RV28.2 UV1.AE17
PS_3: CV15.1 RV15.2 RV16.1 UV1.AE20
PS_ID: PR3.1 PR4.2 UE1.16
PSID: PJPDC1.3 PL2.2
PSID-1: PQ5.2 PR6.1 PR9.2
PSID-2: PQ5.1 PQ6.2 PR8.2
PSID-3: PQ6.3 PR4.1
PTP_DIS#: JTP.6 RE15.2 RE341.2
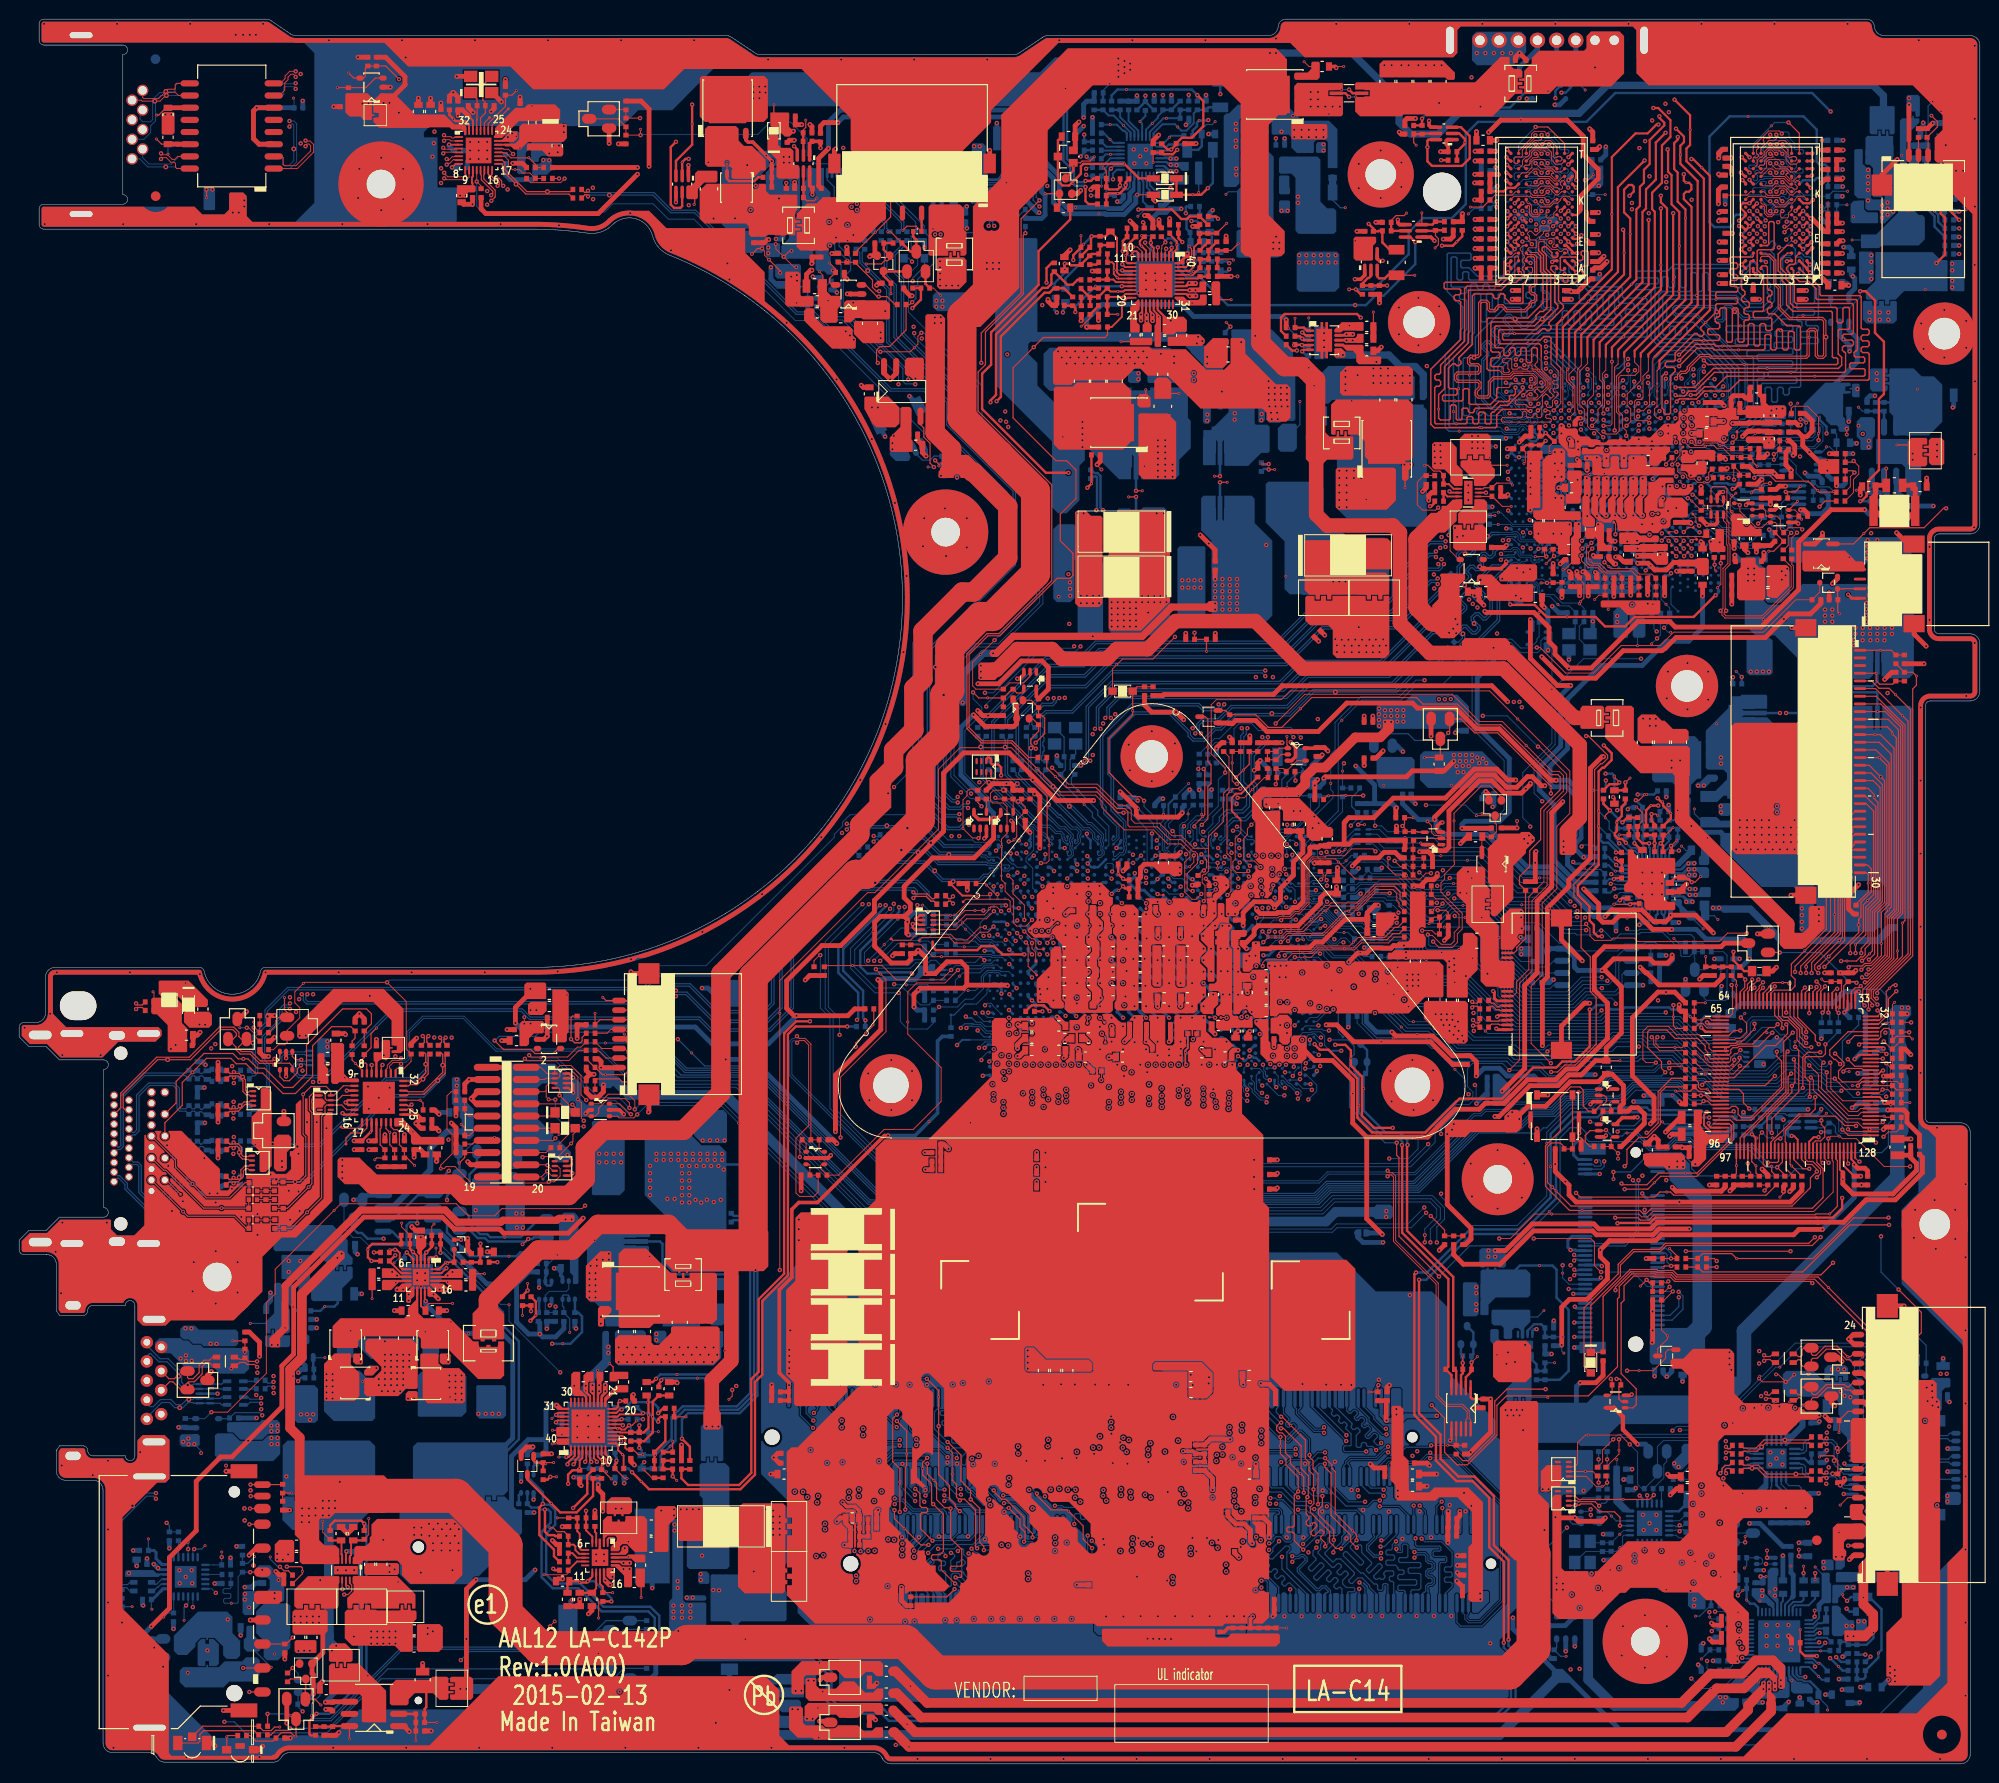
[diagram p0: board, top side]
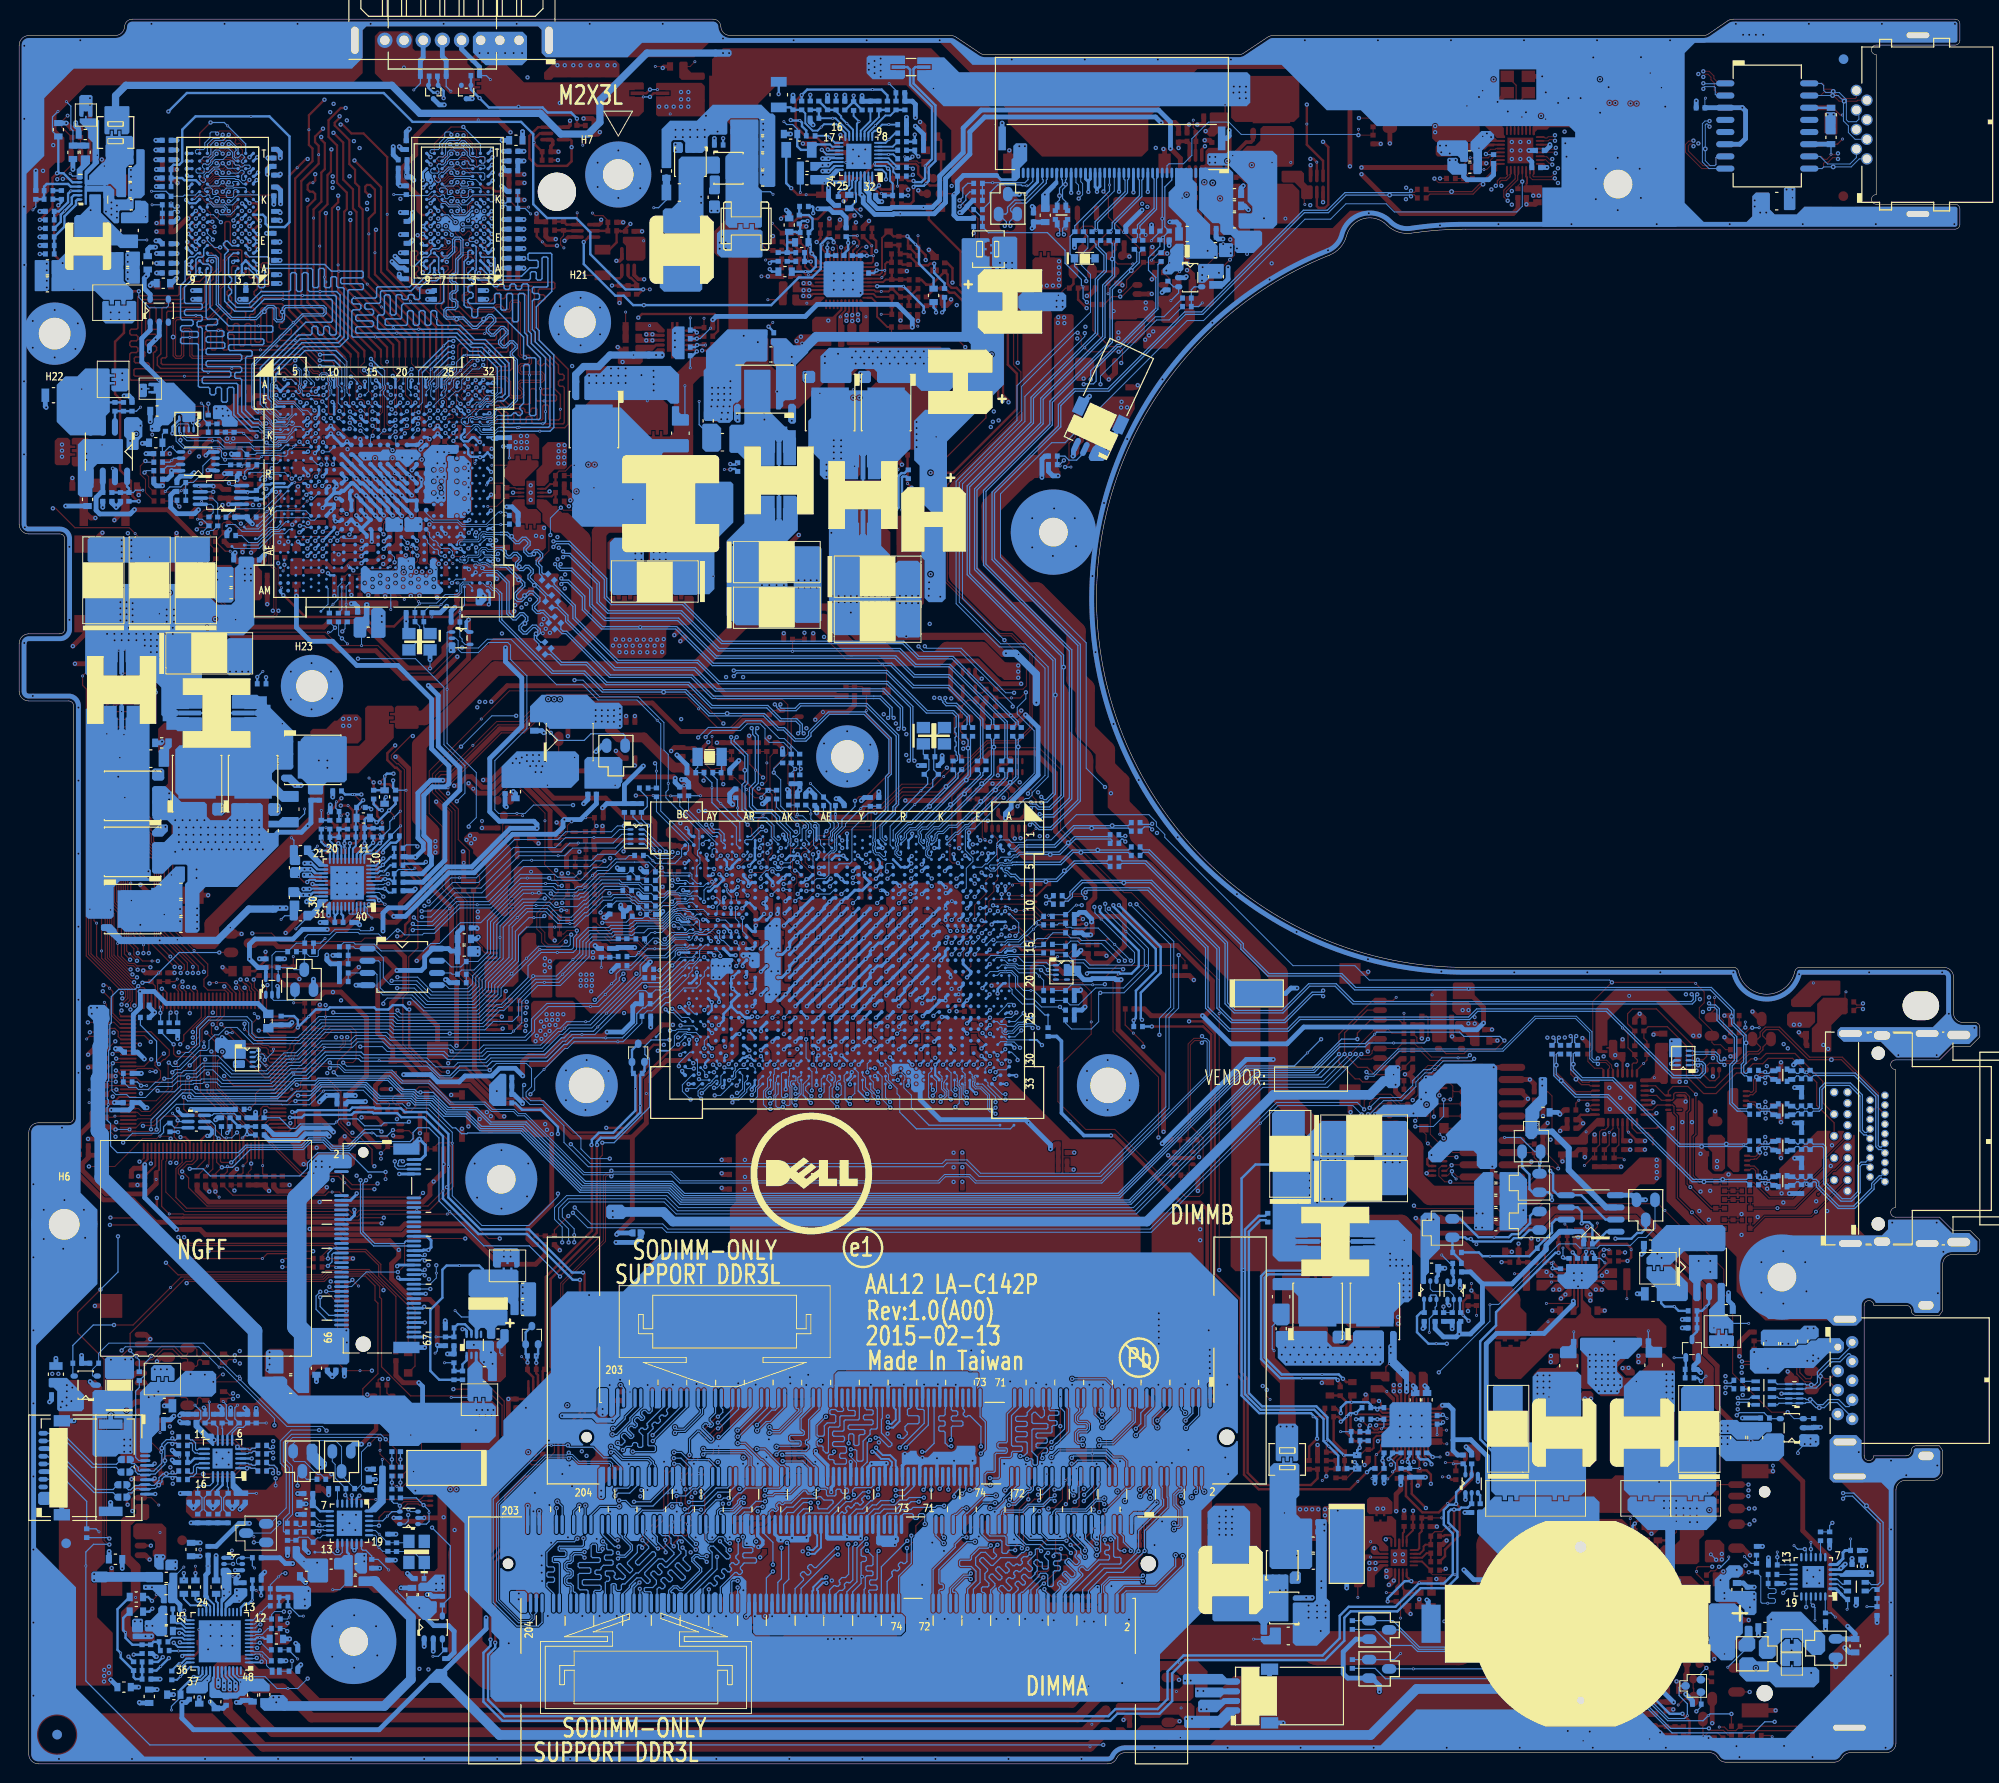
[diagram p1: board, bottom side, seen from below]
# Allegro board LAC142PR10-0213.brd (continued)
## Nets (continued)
PTP_DIS#_R: RE15.1 UE1.38
PWR_PWM_LED: Q6102.1 R6107.2
PWR_PWM_LED#: R6104.1 UE1.92
PWR_PWM_LED_R#: Q6102.2 Q6105.1 R6104.2
PWRGD_VGA: PR1119.2 PR1122.1 PU1100.9 PU1100.20 UC1.BC17
PX_EN: T218.1(TP-1) UV1.AB16
PXS_PWREN: PR1116.1 PR1201.1 PR1402.2 R438.1 R938.2 U74.4 U75.4 UC1.BB6
PXS_RST#: UC1.AR14 UV2.2
REMOTE1+: C2500.1 C2502.1 Q2407.1 Q2407.2 U2407.2
REMOTE1-: C2500.2 C2502.2 Q2407.3 U2407.3
REMOTE2+: C2504.1 C2505.1 Q2408.1 Q2408.2 U2407.4
REMOTE2-: C2504.2 C2505.2 Q2408.3 U2407.5
RF_VDDP_ALWP: PR306.1 PU300.5
RING2: LA10.2 RA1109.1 UA1.17
RING2_R: JIO1.3 JIO1.4 LA10.1
RREF: RR1.1 UR1.1
RTC_CLK: R949.2 R950.1 UC1.AG7
RTC_DIS: Q91.2 R1563.1 UE1.36
S0A3: R694.2 R944.2 UC1.AE8
S5_MUX_CTRL: Q2507.5 Q2516.5 R916.1 R2634.1 UC1.AH8
SATA_ACT#: Q6103.3 Q6105.3 R6106.1 RD19.1 RH43.2 UC1.BB15
SATA_ACT#_RR: RD15.2 RD19.2 UE1.26
SATA_ARX_C_DTX_N0: CS33.2 US2.4
SATA_ARX_C_DTX_P0: CS35.2 US2.5
SATA_ARX_DTX_N0: CS33.1 RS44.1 UC1.AV1
SATA_ARX_DTX_N1: CS14.1 UC1.AW4
SATA_ARX_DTX_N1_C: CS14.2 JODD.5
SATA_ARX_DTX_P0: CS35.1 RS43.1 UC1.AV2
SATA_ARX_DTX_P1: CS13.1 UC1.AW3
SATA_ARX_DTX_P1_C: CS13.2 JODD.6
SATA_ARX_RC_DTX_N0: CS31.1 US2.12
SATA_ARX_RC_DTX_N0_C: CLRP4.1 CS31.2 CS41.2 JHDD1.8
SATA_ARX_RC_DTX_N0_C_R: CLRP4.2 JHDD2.9
SATA_ARX_RC_DTX_P0: CS34.1 US2.11
SATA_ARX_RC_DTX_P0_C: CLRP5.1 CS34.2 CS40.2 JHDD1.7
SATA_ARX_RC_DTX_P0_C_R: CLRP5.2 JHDD2.10
SATA_ATX_C_DRX_N0: CS36.2 US2.2
SATA_ATX_C_DRX_P0: CS37.2 US2.1
SATA_ATX_DRX_N0: CS36.1 RS42.1 UC1.AU4
SATA_ATX_DRX_N1: CS9.1 UC1.AY1
SATA_ATX_DRX_N1_C: CS9.2 JODD.3
SATA_ATX_DRX_P0: CS37.1 RS41.1 UC1.AU3
SATA_ATX_DRX_P1: CS8.1 UC1.AY2
SATA_ATX_DRX_P1_C: CS8.2 JODD.2
SATA_ATX_RC_DRX_N0: CS32.1 US2.14
SATA_ATX_RC_DRX_N0_C: CLRP3.1 CS32.2 CS39.2 JHDD1.10
SATA_ATX_RC_DRX_N0_C_R: CLRP3.2 JHDD2.7
SATA_ATX_RC_DRX_P0: CS30.1 US2.15
SATA_ATX_RC_DRX_P0_C: CLRP2.1 CS30.2 CS38.2 JHDD1.11
SATA_ATX_RC_DRX_P0_C_R: CLRP2.2 JHDD2.6
SATA_LED: EC6104.1 Q6104.1 R6108.1
SATA_LED#_B: Q6103.1 Q6104.2 R6106.2
SATA_LED#_R: Q6105.2 R6110.2 RD15.1
SATA_LED_R: HDLED1.2 R6108.2
SATA_RX_N0: CS41.1 RS44.2
SATA_RX_P0: CS40.1 RS43.2
SATA_TX_N0: CS39.1 RS42.2
SATA_TX_P0: CS38.1 RS41.2
SATA_ZVDD: R96.1 UC1.AW2
SATA_ZVSS: R90.1 UC1.AW1
SD_CD#: CR9.1 JREAD.10 UR1.13
SD_CMD: CR11.1 JREAD.2 UR1.18
SD_D0: JREAD.7 UR1.11
SD_D1: JREAD.8 UR1.10
SD_D2: JREAD.9 UR1.21
SERIRQ: UC1.BC14 UE1.3
SLEEVE: LA7.2 QA6.3 RA53.1 UA1.18
SLEEVE_R: JIO1.5 JIO1.6 LA7.1
SNB_1.35VGPU: PC1403.1 PR1404.2
SPK_L+_CONN: CA30.1 DA13.3 JSPK.3 LA5.2
SPK_L-_CONN: CA29.1 DA13.2 JSPK.4 LA6.2
SPK_R+_CONN: CA32.1 DA14.3 JSPK.1 LA3.2
SPK_R-_CONN: CA31.1 DA14.2 JSPK.2 LA4.2
SUSP: Q52.6 RZ10.1
SUSP#: PR202.1 PR401.1 Q52.2 R437.1 R2313.1 R2318.1 RZ591.1 UE1.116
SVI2_SVC: PU1100.3 RV78.2 RV84.1 RV89.2 RV157.2 RV168.2
SVI2_SVD: PU1100.5 RV77.2 RV87.1 RV88.2 RV155.2 RV169.2
SVI2_SVT: PU1100.7 RV156.2
SYS_RESET_L: R951.2 R952.1 UC1.AF2
SYSON: PR201.1 Q52.5 RZ21.1 UE1.95
SYSON#: Q52.3 RZ19.1
T-GND_L: CL33.1 RL19.2 RL20.2 RL41.2 RL42.2
TEMPIN0: T28.1(TP-1) UC1.E15
TEMPIN1: T29.1(TP-1) UC1.E14
TEMPIN2: T30.1(TP-1) UC1.E12
TEMPINRETURN: T31.1(TP-1) UC1.F14
TESTEN: RV17.2 RV154.2 UV1.K7
THM_ALERT#: RV146.2 UV1.R6 UV11.6
TMDS_L_TX0N: CX25.1 JHDMI.9 LX3.2 RX37.2 RX44.1
TMDS_L_TX0P: CX26.1 JHDMI.7 LX3.3 RX38.2 RX44.2
TMDS_L_TX1N: CX27.1 JHDMI.6 LX4.2 RX39.2 RX45.1
TMDS_L_TX1P: CX28.1 JHDMI.4 LX4.3 RX40.2 RX45.2
TMDS_L_TX2N: CX29.1 JHDMI.3 LX5.2 RX42.2 RX46.2
TMDS_L_TX2P: CX30.1 JHDMI.1 LX5.3 RX41.2 RX46.1
TMDS_L_TXCN: CX23.1 JHDMI.12 LX2.2 RX31.2 RX43.1
TMDS_L_TXCP: CX24.1 JHDMI.10 LX2.3 RX32.2 RX43.2
TMDS_TX0N: CV359.1 CX14.1 LX3.1 RP59.1 RX37.1
TMDS_TX0P: CV360.1 CX15.1 LX3.4 RP59.2 RX38.1
TMDS_TX1N: CV361.1 CX16.1 LX4.1 RP58.1 RX39.1
TMDS_TX1P: CV362.1 CX17.1 LX4.4 RP58.2 RX40.1
TMDS_TX2N: CV363.1 CX18.1 LX5.1 RP58.3 RX42.1
TMDS_TX2P: CV364.1 CX19.1 LX5.4 RP58.4 RX41.1
TMDS_TXCN: CV357.1 CX12.1 LX2.1 RP59.3 RX31.1
TMDS_TXCP: CV358.1 CX13.1 LX2.4 RP59.4 RX32.1
TON_1.35V: PR208.2 PU200.9
TP_CLK: C553.1 JTP.8 R18.1 RE28.2 UE1.87
TP_DATA: C551.1 JTP.7 R19.1 RE27.2 UE1.88
TP_EN: U78.4 UE1.82
TP_I2C_CLK: Q2505.1 R122.1 R124.2 RP24.1 U69.21
TP_I2C_DAT: Q2505.4 R123.1 R125.2 RP24.2 U69.22
TP_I2C_EN: R30.2 UE1.123 UL4.4
TP_I2C_INT#: JTP.5 Q87.1 Q92.3 R126.2 R150.2 RE338.2 RP20.3
TP_I2C_INT#_APU: Q92.1 R12.2 R22.2 R150.1
TP_I2C_INT#_D: Q87.3 R126.1 RP24.3 U69.4
TPUSB_X1: C62.1 R452.2 R940.1 U69.19 Y9.1
TPUSB_X2: C73.1 R940.2 U69.20 Y9.3
TRIP_VDDP_ALWP: PR304.2 PU300.2
TS_EN: RX20.1 UE1.19 UX3.3
TS_EN_R: D4.2 RX18.2 RX20.2 RX25.2 RX35.2
TS_EN_RR: JEDP.37 RX25.1
TS_INT#: RX18.1 UC1.AD5
TS_RST#: RX17.1 UC1.AL8
TS_RST#_EC: RX19.1 UE1.21
TS_RST#_R: JEDP.38 RX17.2 RX19.2 RX24.2
UG1_APU: PQ1007.4 PU1001.22
UG1_GFX: PQ501.4 PU500.22
UG1_VGA: PQ1104.4 PU1100.22
UG2_VGA: PQ1101.4 PU1100.29
UG_1.35V: PQ200.4 PU200.17
UG_3V: PQ101.4 PU100.10
UG_5V: PQ103.4 PU100.16
UG_NB: PQ1001.1 PU1001.32
UG_VDDP_ALWP: PQ301.4 PU300.9
UGATE_CHG: PR761.1 PU703.23
USB3RN1_JUSB1: LI1.1 UC1.Y7
USB3RN1_JUSB1_R: DI1.1 DI1.10 JUSB1.5 LI1.2
USB3RP1_JUSB1: LI1.4 UC1.Y6
USB3RP1_JUSB1_R: DI1.2 DI1.9 JUSB1.6 LI1.3
USB3TN1_JUSB1: CI3.2 UC1.AC2
USB3TN1_JUSB1_C: CI3.1 LI3.1
USB3TN1_JUSB1_R: DI1.4 DI1.7 JUSB1.8 LI3.2
USB3TP1_JUSB1: CI4.2 UC1.AC1
USB3TP1_JUSB1_C: CI4.1 LI3.4
USB3TP1_JUSB1_R: DI1.5 DI1.6 JUSB1.9 LI3.3
USB20_CAM_N7: LX6.4 RX21.1 UC1.AJ2
USB20_CAM_N7_R: JEDP.30 LX6.3 RX21.2
USB20_CAM_P7: LX6.1 RX22.1 UC1.AK2
USB20_CAM_P7_R: JEDP.31 LX6.2 RX22.2
USB20_CR_N0: LR2.1 R808.1 UC1.AR1
USB20_CR_N0_R: LR2.2 UR1.2
USB20_CR_P0: LR2.4 UC1.AR2
USB20_CR_P0_R: LR2.3 UR1.3
USB20_JUSB1_N6: LI2.4 R811.1 UC1.AL4
USB20_JUSB1_N6_R: DI2.2 JUSB1.2 LI2.3
USB20_JUSB1_P6: LI2.1 UC1.AL3
USB20_JUSB1_P6_R: DI2.3 JUSB1.3 LI2.2
USB20_JUSB2_N1: LI7.1 UC1.AR4
USB20_JUSB2_N1_R: DI3.2 JIO1.22 LI7.2
USB20_JUSB2_P1: LI7.4 UC1.AR3
USB20_JUSB2_P1_R: DI3.3 JIO1.21 LI7.3
USB20_JUSB3_N2: LI8.4 UC1.AN1
USB20_JUSB3_N2_R: DI4.3 JIO1.18 LI8.3
USB20_JUSB3_P2: LI8.1 UC1.AN2
USB20_JUSB3_P2_R: DI4.2 JIO1.19 LI8.2
USB20_MINI1_N4: JNGFF.5 UC1.AM2
USB20_MINI1_P4: JNGFF.3 UC1.AM1
USB20_N3: R141.1 U69.11 UC1.AN4
USB20_N3_R: R141.2 R142.1
USB20_P3: R140.1 U69.10 UC1.AN3
USB20_P3_R: R140.2 R143.1
USB20_TOUCH_N5: DX2.3 JEDP.34 UC1.AL1
USB20_TOUCH_P5: DX2.2 JEDP.35 UC1.AL2
USB_EN#: CI13.1 CI46.1 RE504.1 UE1.84 UI5.4 UI7.4
USB_OC0#: CI15.1 R905.2 UC1.AH9 UI5.3
USB_OC1#: CI47.1 UC1.AG1 UI7.3
USB_ZVSS: R641.1 UC1.AP5
USBSS_ZVDD: R645.1 UC1.AD1
USBSS_ZVSS: R644.1 UC1.AD2
VCIN0_PH: PH1.1 PR24.1 UE1.109
VCIN1_BATT_DROP: PR36.2 UE1.64
VCIN1_PH: PC13.2 PR23.1 PR26.2 PR27.2 PR38.2 RE30.2 UE1.102
VCOUT0: RE39.2 UE1.104
VCOUT0_PH#: PC100.1 PR100.2 PR101.2 PR102.2 PR110.1 R2450.2 RE39.1
VCOUT1_PH: PR30.1 Q89.2 R1690.1 RE65.2 RE67.2 UE1.103 UE3.2
VGA_AC__BATT: QV8.3 RV92.1 RV148.2 UV1.T9 UV4.4
VGA_DMINUS: CV9.2 UV1.T2 UV11.3
VGA_DPLUS: CV9.1 UV1.T4 UV11.2
VGA_SMB_CK3: QV1.1 RV6.2 RV164.2 RV166.2 UV1.U7
VGA_SMB_CK3_R: RV164.1 UV11.8
VGA_SMB_DA3: QV1.4 RV5.2 RV165.2 RV167.2 UV1.U8
VGA_SMB_DA3_R: RV165.1 UV11.7
VL: PC106.1 PU100.13
VR_ON: PR532.1 PR1085.1 UE1.121
VRAM_ODT0: UV1.L18 UV5.K1 UV6.K1
VRAM_ODT1: UV1.K16 UV7.K1 UV8.K1
VSUM+_APU: PC1053.1 PC1066.1 PR1071.1 PR1079.1 PR1084.1 PU1001.14
VSUM+_GFX: PC516.1 PC517.1 PR517.1 PR523.1 PR524.1 PU500.14
VSUM+_VGA: PC1125.1 PC1126.1 PR1108.1 PR1126.1 PR1131.1 PR1132.1 PU1100.14
VSUM-_APU: PC1053.2 PC1065.1 PC1066.2 PH1003.2 PR1066.1 PR1068.1 PR1071.2 PR1072.1
VSUM-_GFX: PC516.2 PC517.2 PC519.1 PH502.2 PR518.1 PR524.2 PR526.1 PR528.1
VSUM-_VGA: PC1119.1 PC1120.1 PC1125.2 PC1126.2 PC1129.1 PH1102.2 PR1110.1 PR1128.1 PR1132.2 PR1136.1 PR1137.1
VSUMN_NB: PC1011.2 PC1012.2 PC1014.1 PH1000.2 PR1011.2 PR1013.1 PR1014.1 PR1015.1
VSUMP_NB: PC1011.1 PC1012.1 PR1009.1 PR1011.1 PR1012.1 PU1001.40
VSYNC: RZ49.1 UZ1.7
VTTREF_1.35V: PC210.1 PU200.4
WAKEB: RV162.2 RV163.1 UV1.AJ27
WL_OFF#: QM1.3 RH42.2 UC1.AT12
WL_OFF#_R: JNGFF.48 QM1.1 RM8.2
WLAN_CLKREQ#: JNGFF.45 UC1.BB17
WLAN_WAKE#: JNGFF.47 RE70.2 UE1.90
WOL_EN: RL27.2 RL38.1 UE1.98 UL3.4
XTALIN: CV17.1 RV20.1 UV1.AM28 YV1.1
XTALIN_2168: T4933.1(TP-1) UZ1.17
XTALOUT: CV18.1 RV20.2 UV1.AK28 YV1.3
XTALOUT_2168: T4934.1(TP-1) UZ1.18
XTLI: CL36.1 UL1.29 YL2.1
XTLO: CL37.1 UL1.28 YL2.3
N71037: RA130.2 UA1.8
N71249: CA62.2 RA12.2 UA1.27
N71261: CA63.2 UA1.39
N71273: CA64.2 UA1.7
N71383: CA24.1 UA1.37
N71395: CA24.2 UA1.35
N71399: CA25.2 UA1.34
N71447: CA23.2 UA1.28
N71539: CA65.2 CA69.1 RA79.1 RA81.2
N71593: CA65.1 UA1.12
N76526: RA1113.2 UA1.4
N16741803: RV29.2 UV1.AC22
N16751834: T203.1(TP-1) UV1.AE9
N16751842: T211.1(TP-1) UV1.AB9
N16751844: T207.1(TP-1) UV1.AC10
N16751854: T210.1(TP-1) UV1.AC7
N16751856: T204.1(TP-1) UV1.Y11
N16754176: T212.1(TP-1) UV1.AB8
N16754178: T209.1(TP-1) UV1.AC8
N16754180: T205.1(TP-1) UV1.AE8
N16754182: T208.1(TP-1) UV1.AD7
N16754186: T201.1(TP-1) UV1.N9
N16754188: T215.1(TP-1) UV1.AB2
N16754190: T214.1(TP-1) UV1.AB4
N16754196: T206.1(TP-1) UV1.AD9
N16754198: T202.1(TP-1) UV1.L9
N16754200: T216.1(TP-1) UV1.Y8
N16754202: T213.1(TP-1) UV1.AB7
N16754208: T217.1(TP-1) UV1.Y7
N16754270: RV59.2 UV1.AB22
N16784339: RV77.1 U1.7
N16784342: RV78.1 U1.6
N16808781: RV157.1 UV1.AJ11
N16808782: RV155.1 UV1.AK12
N16808783: RV156.1 UV1.AL11
N16814221: RV60.1 UV1.AC11 UV1.AC13
N16855208: R2448.2 R2450.1 U2407.7
N17019894: RV56.1 UV7.L8
N17020058: RV57.1 UV8.L8
N17040769: JIO1.10 RI2.1
N17072999: C5216.1 U2301.12
N17073002: C5217.1 U2301.10
N17205184: RS19.2 US2.7
N17205187: RS20.2 RS22.2 US2.18
N17205206: RS25.2 US2.10
N17242539: RV58.1 UV11.4
N17253873: R12.1 UC1.BC3
N17283477: PC204.2 PR210.1 PU200.12
N17382836: PC803.1 PQ801.1 PR802.2 PR803.1 PU800.3
N17382859: PC801.2 PJP801.2 PR802.1 PU800.1
N17384371: RX10.2 UX4.3
N17415515: PJP2.2 PJPDC1.1 PJPDC1.2 PL4.1
N17438484: CA21.1 RA1112.2
N17446620: RZ45.1 UZ1.28
N17451409: PC504.1 PC505.1 PC506.1 PC507.1 PC508.1 PC522.1 PJP501.2 PL501.1 PQ501.5
N17481633: PC705.1 PC760.1 PC762.1 PC763.1 PC764.1 PC765.1 PJP701.2 PL704.2 PQ704.5
N17485857: PC523.1 PQ504.2 PR533.2
N17511335: RA13.1 RA34.1 UA1.13
N17511724: C168.1 R811.2
N17580597: CX52.1 UX3.4
N17734490: Q135.3 Q2513.3
N17734492: Q2514.3 Q2515.3
N17735595: Q2516.2 Q2516.3 R2635.1
N17854431: T4935.1(TP-1) UV1.AL9
N17885105: T223.1(TP-1) UV1.R1
N17885106: T224.1(TP-1) UV1.R3
N18390627: PQ710.2 PQ711.1
N18459489: PQ4.3 PR38.1
N19105477: JCRT.11 T27.1(TP-1)
N19198957: D5501.1 FX1.2 R5409.2
N19609367: QX5.2 RX15.1
N19646239: QA6.2 RA6.2
N19800719: QA6.5 QA6.6 RA5.2
N20135010: PC1130.2 PR1136.2 PU1100.15
N20135022: PC1130.1 PR1137.2
N20135024: PC1110.1 PR1114.1 PU1100.25
N20135039: PR1121.2 PU1100.11
N20135040: PC1122.1 PC1124.1 PR1133.1 PR1138.1 PU1100.16
N20135043: PC1131.1 PR1139.1 PU1100.17
N20135074: PC1121.1 PR1125.2
N20135096: PL1103.2 PR1124.2 PR1126.2
N20135098: PL1103.3 PR1128.2
N20135126: PH1101.2 PR1120.2 PR1121.1
N20135134: PC1123.1 PR1129.2 PR1133.2 PR1134.1 PR1135.1 PU1100.18
N20135137: PC1122.2 PR1129.1
N20135139: PC1128.1 PR1135.2
N20135141: PC1123.2 PC1127.2 PR1130.1 PU1100.19
N20135144: PC1127.1 PR1134.2
N20135171: PH1102.1 PR1131.2
N20135184: PL1102.2 PR1104.2 PR1108.2
N20135197: PC1109.1 PR1107.2
N20135219: PL1102.3 PR1110.2
N20135248: PU1100.39 PU1100.40
N20135251: PU1100.36 PU1100.37 PU1100.38
N20135257: PR1101.2 PU1100.1
N20135258: PR1111.2 PU1100.2
N20135263: PR1105.2 PU1100.34
N20135264: PR1106.2 PU1100.32 PU1100.33
N20141258: PR1016.2 PU1001.1
N20141272: PH1002.2 PR1080.1 PR1087.2
N20141325: PC1007.2 PR1007.1
N20141337: PC1008.1 PR1000.2 PR1003.2 PR1004.1 PR1007.2 PU1001.37
N20141361: PC1007.1 PC1010.2 PR1003.1 PR1006.2 PU1001.38
N20141372: PC1061.2 PR1066.2 PU1001.15
N20141380: PC1015.1 PR1015.2
N20141402: PC1061.1 PR1072.2
N20141406: PC1063.1 PR1026.1 PU1001.25
N20141448: PC1015.2 PR1013.2 PU1001.39
N20141457: PL1002.2 PR1012.2
N20141459: PL1002.3 PR1014.2
N20141467: PL1004.3 PR1068.2
N20141469: PL1004.2 PR1084.2
N20141477: PC1013.1 PR1010.2
N20141501: PR1080.2 PU1001.11
N20141511: PC1059.1 PC1060.1 PR1047.1 PR1075.1 PU1001.16
N20141517: PC1058.1 PR1069.1 PU1001.17
N20141713: PC1006.2 PC1008.2 PR1005.1 PU1001.36
N20141719: PC1054.1 PR1074.2
N20141862: PC1006.1 PR1004.2
N20141864: PC1004.2 PR1000.1
N20141906: PC1068.1 PR1047.2 PR1065.1 PR1073.2 PR1077.1 PU1001.18
N20141912: PC1060.2 PR1073.1
N20141916: PC1037.1 PR1065.2
N20141920: PC1057.2 PC1068.2 PR1078.1 PU1001.19
N20141926: PC1057.1 PR1077.2
N20142021: PH1000.1 PR1009.2
N20142108: PH1003.1 PR1079.2
N20142189: PH1001.2 PR1016.1 PR1086.2
N20265233: T173.1(TP-1) UC1.U30
N20265234: T12.1(TP-1) UC1.U31
N20265235: T13.1(TP-1) UC1.AN30
N20272982: PC520.2 PR526.2 PU500.15
N20272994: PC520.1 PR528.2
N20272996: PC502.1 PR507.1 PU500.25
N20273008: PL502.3 PR518.2
N20273009: PL502.2 PR517.2
N20273011: PR513.2 PU500.11
N20273012: PC512.1 PC514.1 PR521.1 PR529.1 PU500.16
N20273015: PC521.1 PR530.1 PU500.17
N20273032: PR515.2 PU500.13
N20273046: PC511.1 PR516.2
N20273098: PH501.2 PR512.2 PR513.1
N20273106: PC513.1 PR519.2 PR521.2 PR522.1 PR525.1 PU500.18
N20273109: PC512.2 PR519.1
N20273111: PC518.1 PR525.2
N20273113: PC513.2 PC515.2 PR520.1 PU500.19
N20273116: PC515.1 PR522.2
N20273143: PH502.1 PR523.2
N20273220: PU500.39 PU500.40
N20273223: PU500.36 PU500.37 PU500.38
N20273229: PR501.2 PU500.1
N20273230: PR504.2 PU500.2
N20273235: PR502.2 PU500.34
N20273236: PR503.2 PU500.32 PU500.33
N20277821: PR302.2 PU300.1
N20277901: PC309.1 PR305.2
N20355294: R449.2 UC1.AW14
N20391319: PC401.1 PR401.2 PR403.1 PU400.8
N20391329: PC404.2 PR402.2 PR404.1 PU400.2
N20391331: PC403.1 PJP401.2 PU400.5 PU400.9
N20394063: PC1201.1 PR1201.2 PR1203.1 PU1200.8
N20394073: PC1204.2 PR1202.2 PR1204.1 PU1200.2
N20394075: PC1203.1 PJP1201.2 PU1200.5 PU1200.9
N20395535: PC602.1 PJP601.2 PU600.3
N20395548: PC606.1 PR603.2
N20557240: R44.2 UL4.3
N20623473: D101.2 R31.1
N20654206: JKB.30 RE60.2
N21016181: PR769.2 PU703.3
N21016217: PR770.2 PU703.4
N21016253: PR777.2 PU703.5
N21016293: PR774.2 PU703.6
N21016335: PR775.2 PU703.7
N21017384: PC721.1 PR771.2
N21017467: PQ711.2 PR781.2
N21021316: PC305.1 PR303.2
N21022260: PC1009.1 PR1008.2
N21022300: PC1038.1 PR1082.2
N21023084: PC510.1 PR514.2
N21023991: PC1404.1 PR1405.2
N21024525: PC1108.1 PR1103.2
N21024549: PC1118.1 PR1123.2
N23700319: PL2.1 PQ6.1 PR6.2
N26062389: CA68.2 RA82.1
N26062391: CA67.2 RA80.1
N26148842: RL40.2 UL3.3
N26156452: RL39.2 UL1.26
N26156532: T94.1(TP-1) UL1.25
N26156534: T95.1(TP-1) UL1.27
N26156585: RL31.2 UL1.31
N27266810: PC742.1 PC744.1 PQ709.6 PQ718.4 PR762.1 PR778.2
N27284163: PQ709.5 PR739.1 PR746.2
N27286227: PD704.1 PD705.1 PR743.2
N27352133: JHDT1.13 R49.2
N27352135: JHDT1.15 R51.2
N27352149: JHDT1.11 R52.2
N27367990: C636.1 R617.2
N27535100: RE14.1 UE1.111
N27535635: CE24.1 RE16.2
N27539530: CH16.1 RH25.2 RH26.2 RH28.1 UH1.1 UH1.2
N27594046: RE65.1 RE66.1
N27653670: RV254.2 UV1.AB12
N27653677: RV255.2 UV1.AB11
N27700813: QX3.1 RP58.5 RP58.6 RP58.7 RP58.8 RP59.5 RP59.6 RP59.7 RP59.8
N27705118: Q83.1 R1671.2
N27707965: C349.2 U15.10
N27708054: C343.2 U15.12
N27738679: C43.1 R139.2 R147.2 U69.12
N27738786: C668.2 U69.6
N27738791: T26.1(TP-1) U69.14
N27738995: R148.1 U69.18
N27739014: C667.1 U69.9
N27920326: PR1081.2 PU1001.13
N28237059: PC1414.1 PJP1402.2 PU1400.7
N28237408: PC1408.2 PR1409.1
N28407026: UC1.AY18 VDDP_SENSE.1(TP-1)
N28452649: C157.1 R808.2
N28452851: C160.1 R809.2
N28452956: C163.1 R810.2
N28483985: PQ1.3 PR5.2
N28484391: PC16.1 PQ2.3 PR28.2
N28484395: PC16.2 PQ2.2 PR29.1
N28484412: PQ2.5 PR31.1 PR33.2
N28484439: PC14.2 PQ3.5 PR32.1
N28484451: PQ1.5 PQ1.6 PR7.1 PR10.2
N28484508: PC15.1 PQ3.2 PR30.2
N28484561: PQ4.6 PR27.1
N28484610: PC6.1 PR34.1 PR35.1 PR36.1
N28714507: PC744.2 PQ709.1 PQ718.1 PQ718.2 PQ718.3 PQ740.1 PQ740.2 PQ740.3 PR737.1 PR763.1
N28714524: PC750.1 PU703.27
N28714534: PC752.2 PR754.1
N28714554: PR727.1 PU703.8
N28714572: PC757.2 PR743.1 PU703.18
N28714582: PR755.2 PU703.12
N28714583: PC708.1 PC759.1 PR776.1 PU703.14
N28714585: PC708.2 PC758.1 PR742.1 PU703.15
N28714598: PC746.2 PC747.1 PR740.2 PU703.31
N28714599: PC745.2 PC747.2 PR772.2 PU703.32
N28714601: PC750.2 PU703.28
N28714604: PR773.1 PU703.25
N28714606: PQ704.4 PR761.2
N28714608: PR745.1 PU703.26
N28714612: PR771.1 PU703.24
N28714614: PR757.2 PU703.17
N28714617: PQ718.5 PR703.1
N28714625: PR757.1 PR779.2
N28714637: PC779.2 PQ717.4 PR773.2
N28714684: PQ707.6 PR721.2
N28714693: PC779.1 PL700.2 PQ717.1 PQ717.2 PQ717.3 PR765.1
N28714721: PR742.2 PR765.2
N28714724: PR765.3 PR776.2
N28714743: PQ709.2 PR737.2 PR738.1
N28714752: PR703.2 PR772.1
N28714753: PR703.3 PR740.1
N28714782: PC767.1 PR766.2
N28858046: PQ709.3 PR744.1
N28858050: PQ707.3 PR722.2
N28895147: PC805.1 PQ801.2 PR801.2
N29144266: JIO1.16 RI1.1
N29189918: PR764.2 PU703.13
N37640332: RV2.2 UV1.N10
N37640410: RV3.1 UV1.AA22
N37817724: RV1.1 UV1.Y22
N38023415: CV96.1 RV36.2 RV37.2
N38028869: CV98.2 UV1.K8
N38028873: CV99.2 UV1.L7
N38028878: CV98.1 RV40.2
N38028880: CV99.1 RV41.2
N38039273: RV46.1 UV5.L8
N38046520: CV102.1 RV48.2 RV49.2
N38049955: RV47.1 UV6.L8
N38097860: CV135.1 RV54.2 RV55.2
N38342282: RV39.2 UV1.K25
N40812716: CR3.2 UR1.6
N43437408: R450.2 UC1.AY13
N47415217: PC104.2 PR103.1
N47415258: PC103.1 PR113.2
N47415272: PC111.1 PR112.2
N47415370: PC110.1 PR111.2
N47420895: PC207.2 PR203.1
N47445410: PR114.1 PU100.19
N55201771: JHDMI.13 RX12.2
N208512623: PQ740.4 PR778.1

Pads without a net: FD1 1; FD2 1; FD3 1; FD4 1; FD5 1; FD6 1; HDLED1 3; JCRT 4; JDIMM1 77 122 125; JDIMM2 77 122 125; JEDP 3 33 39; JHDD1 4; JHDD2 3; JHDMI 14; JKB 2 3; JKBBL 3; JNGFF 6 8 9 11 12 13 14 15 16 17 19 20 21 22 23 24 26 28 34 36 38 40 42 50 51 52 53 54 56 57 59 62 63 65; JODD 9 16; PD3 3; PJPDC1 4; PU200 10; PU400 7; PU500 27 28 29 30 35; PU600 2 5; PU1001 27 28 29 30 35; PU1100 35; PU1200 7; RP20 4 5; RP24 4 5; RP25 4 5; RP27 1 8; RP45 3 4 5 6; RP62 4 5; TL1 4 5 12 13; TL2 4 5 12 13; U61 1; U62 1; U63 1; U64 1; U65 1; U66 1; U69 1 5 8 23; U74 3; U75 3; U78 3; U2407 8; UA1 14 15 16 23 24 48; UC1 A6 A7 A21 A22 A23 AA1 AA2 AA3 AA4 AB5 AB6 AB25 AB26 AB28 AB29 AC3 AC4 AD26 AD27 AD29 AE2 AE9 AE25 AE26 AE28 AE29 AG24 AG26 AG27 AG29 AH2 AH25 AH26 AH28 AH29 AK26 AK27 AK29 AL9 AL25 AL26 AL28 AL29 AN8 AN26 AN27 AN29 AP8 AP9 AP24 AP25 AP26 AP28 AP29 AR11 AR20 AR22 AR23 AR26 AR27 AR29 AT11 AT20 AT23 AT25 AU1 AU2 AU7 AU22 AU25 AU26 AU28 AU29 AV5 AV8 AV11 AV20 AV22 AV23 AV26 AV27 AV29 AW8 AW9 AW20 AW23 AW25 AW26 AW27 AY9 AY19 AY21 B1 B6 B7 B19 B20 B21 B22 B23 BA1 BA3 BA5 BA19 BA21 BA23 BB4 BB5 BB18 BB19 BB20 BB21 BB22 BB23 BC5 BC10 BC11 BC18 BC21 BC22 BC23 C1 C7 C9 C21 C23 D1 D2 D7 D9 D21 D23 E9 E17 E19 E20 E22 E23 E25 E26 E27 F17 F20 F23 F26 F27 F29 G1 G2 G3 G4 G9 G19 G22 G25 G27 G28 G29 H1 H2 H9 H17 H19 H20 H22 H23 H25 J3 J4 J6 J7 J17 J20 J23 J26 J27 J29 K5 K6 K8 K9 K18 K21 K25 K26 K28 K29 L9 L10 L26 L27 L29 M32 M33 N1 N2 N3 N4 N25 N26 N28 N29 N30 N31 N32 N33 P6 P7 P27 P29 P32 R30 R31 R32 R33 T8 T9 T25 T26 T28 T29 U26 U27 U29 W1 W2 W5 W6 W8 W9 W25 W26 W28 W29 Y1 Y2 Y26 Y27 Y29; UE3 1; UR1 7 9 12 14 16 17 19 22 23; UV1 AA5 AA6 AA29 AA31 AB23 AB25 AB26 AB27 AB30 AC1 AC3 AC5 AC6 AC16 AC23 AC25 AD2 AD4 AD10 AD11 AD13 AD16 AD22 AD23 AD24 AE1 AE3 AE5 AE6 AE10 AE11 AE13 AE16 AE19 AE22 AE23 AE24 AE25 AE26 AF2 AF4 AF6 AF7 AF8 AF9 AF10 AF11 AF13 AF16 AF17 AF22 AF24 AF25 AG1 AG3 AG5 AG6 AG7 AG8 AG9 AG10 AG11 AG13 AG15 AG16 AG17 AG18 AG19 AG20 AG21 AG22 AG24 AG25 AG26 AH1 AH3 AH5 AH6 AH8 AH12 AH16 AH18 AH20 AH22 AH24 AH26 AJ7 AJ9 AJ13 AJ15 AJ17 AJ19 AJ21 AJ23 AJ25 AK1 AK3 AK5 AK6 AK8 AK10 AK14 AK16 AK18 AK20 AK22 AK24 AK26 AL7 AL13 AL15 AL17 AL19 AL21 AL23 AL25 AM3 AM5 AM6 AM8 AM10 AM12 AM26 J8 J22 J25 K13 K30 L16 L29 L31 M4 M27 M28 M30 N3 N5 N6 N8 N26 N29 N31 P2 P4 P7 P10 P23 P24 P26 P27 P28 P30 R29 R31 T7 T23 T24 T26 T27 T28 T30 U5 U6 U23 U24 U26 U29 U31 V2 V4 V6 V27 V28 V30 W3 W5 W6 W7 W8 W23 W24 W29 W31 Y2 Y4 Y6 Y23 Y24 Y26 Y27 Y28 Y30; UV5 J1 J9 L1 L9; UV6 J1 J9 L1 L9; UV7 J1 J9 L1 L9; UV8 J1 J9 L1 L9; Y2 2 4; Y9 2 4

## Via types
v1: diameter 0.305, hole 0.152, TOP to BOTTOM, 787 vias
v2: diameter 0.457, hole 0.203, TOP to BOTTOM, 5057 vias
v3: diameter 0.508, hole 0.254, TOP to BOTTOM, 80 vias
v4: diameter 0.406, hole 0.203, TOP to BOTTOM, 140 vias

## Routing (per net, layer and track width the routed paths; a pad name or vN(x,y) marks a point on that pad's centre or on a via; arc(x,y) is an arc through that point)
0.95VS_GATE:
  vias: v1(142.37,102.06)
0.95VS_PWR_EN#: length 80.1
  TOP w0.127: UE1.99 179.95,65.39 184.55,69.99 184.55,71.68 v2(184.87,72) ; v2(159.8,101.22) v1(159.8,101.8) 159.8,101.97 154.25,107.53 151.86,107.53 150.4,108.99 Q83.2 149.23,107.67 v2(149.09,107.53)
  IN1 w0.127: v2(159.8,101.22) 159.8,99.69 161.55,97.94 161.55,94.77 161.25,94.47 161.25,88.55 169.73,80.07 173.28,80.07 175.62,77.74 176.28,77.74 178.53,75.49 179.95,75.49 180.97,74.46 180.97,73.18 181.75,72.4 183.61,72.4 184.02,72 v2(184.87,72)
  BOTTOM w0.127: v2(149.09,107.53) 148.3,106.74 145.6,106.74 144.9,107.44 141.53,107.44 141.33,107.24 Q84.2
0.95VSDGPU_ON: length 5.1
  TOP w0.127: v1(146.64,135.43) 146.97,135.43 147.57,134.84 148.23,134.84 148.6,134.47 R438.2
  TOP w0.203: C983.2 149.15,133.48 149.64,132.99 U15.3
  TOP w0.254: R438.2 C983.2
0.95VSDGPU_OUT: length 1.8
  TOP w0.102: 154.33,135.45 v1(155.24,135.45)
  TOP w0.127: 153.41,135.45 154.33,135.45
0.775VALW_GATE: length 13.7
  TOP w0.102: v4(52.52,54.19) 53.07,54.74 v2(53.1,54.74)
  BOTTOM w0.254: Q2514.2 47,55.68 47.84,54.83 48.6,54.83 48.95,54.48 52.85,54.48 v2(53.1,54.74) 53.52,54.74 53.7,54.91 Q2515.2 55.02,53.37 R128.2 54.08,52.43 R130.2
0.775VALW_GATE_BUFF: length 13.3
  BOTTOM w0.254: R128.1 52.27,53.34 51.87,52.95 v1(51.09,52.95) 47,52.95 R54.1 46.17,53.89 44.63,55.42 44.63,56.39 44.25,56.77 U2.7
0.775VALW_GATE_CC: length 4.8
  BOTTOM w0.127: v1(56.14,53.07) 55.26,52.2 R130.1
  BOTTOM w0.254: Q2507.3 55.54,50 55.43,49.89 55.07,49.89 54.89,50.07 Q2507.2 54.89,50.82 55,50.93 R917.1 R130.1
3VS:
  vias: v4(31.4,19.15)
3VS_GATE: length 5.5
  TOP w0.102: R2318.2 32.4,23.42 31.67,24.16 v1(31.67,25.3)
  TOP w0.203: U2301.5 33.69,21.79 33.62,21.86 33.62,23.27 C2322.1
  TOP w0.254: C2322.1 32.56,23.3 R2318.2
5VS:
  vias: v1(39.53,18.97)
5VS_GATE: length 5.8
  TOP w0.102: v1(36.47,25.58) 36.47,23.9 36,23.43 R2313.2
  TOP w0.203: C2309.1 34.63,23.08 34.63,21.78 34.49,21.65 U2301.3
  TOP w0.254: R2313.2 35.88,23.3 C2309.1
+0.95VALW: length 46
  TOP w1.016: 129.28,98.68 129.11,98.84 129.11,100.74 129.72,101.35 133.34,101.35 134.17,102.17 134.17,102.92 135.16,103.91 136.24,103.91 139.39,107.06 141.99,107.06 142.79,107.86
  IN1 w0.508: v2(119.32,100.66) 122.37,103.71 122.37,105.14 127.17,109.94 138.18,109.94
  BOTTOM w0.254: UC1.AN12 126.13,88.45 v2(126.13,88.65) ; v2(126.84,88.65) 126.84,88.62 127.45,88.02 UC1.AP12
  BOTTOM w0.508: R645.2 118.51,99.99 118.51,100.15 119.02,100.66 v2(119.32,100.66)
  vias: v2(137.31,117.31) v2(137.47,116.65) v2(137.47,115.96) v2(137.98,117.25) v2(138.26,116.62) v2(138.26,115.94) v2(138.68,117.25) v2(139.02,116.62) v2(139.02,115.94) v2(139.39,117.26) v2(139.78,116.62) v2(139.78,115.94) v2(140.1,117.25) v2(140.54,116.62) v2(140.54,115.94) v2(140.86,117.25) v2(141.24,116.61) v2(141.23,115.94) v2(141.53,117.26) v2(141.88,110.06) v2(141.87,109.47) v2(141.87,108.89) v2(141.88,108.25) v2(141.93,116.61) v2(141.92,115.95) v2(142.31,117.28) v2(142.49,109.89) v2(142.5,109.3) v2(142.5,108.67) v2(142.6,116.64) v2(143.13,109.89) v2(143.14,109.3) v2(143.14,108.67) v2(143.76,109.89) v2(143.77,109.3) v2(143.77,108.71) v2(144.41,109.91) v2(144.41,109.3) v2(144.41,108.71) v2(147.66,137.54) v2(147.66,136.91) v2(147.69,136.27) v2(147.69,135.64) v2(148.27,137.54) v2(148.27,136.91) v2(148.3,136.27) v2(148.3,135.64) v4(139.76,118.55)
+0.95VALW_ON: length 2.6
  TOP w0.203: C987.2 149,132.19 U15.5
  TOP w0.254: C987.2 R437.2
+0.95VALWP: length 28.5
  TOP w0.254: PR307.2 132.8,147.41 v2(133.3,147.41)
  IN2 w0.254: v2(137.09,127.13) 132.49,127.13 131.44,128.18 131.44,136.07 134.6,139.23 134.6,145.88 133.3,147.19 v2(133.3,147.41)
  vias: v1(132.15,123.86) v2(137.09,126.36) v2(137.09,125.6) v2(137.09,124.84) v2(137.09,124.08) v2(137.09,123.32) v2(137.72,127.13) v2(137.72,126.36) v2(137.72,125.6) v2(137.72,124.84) v2(137.72,124.08) v2(137.72,123.32) v2(138.36,127.13) v2(138.36,126.36) v2(138.36,125.6) v2(138.36,124.84) v2(138.36,124.08) v2(138.36,123.32)
+0.95VS: length 15.4
  TOP w0.508: v2(136.11,102.79) 136.26,102.95 144.72,102.95 145.34,103.57 R1671.1 148.66,103.57 v2(149.68,104.58)
  BOTTOM w0.508: v2(136.11,102.79) 136.11,102.36 R96.2
  vias: v1(149.43,102.07) v2(147.78,78.18) v2(148.36,78.18) v2(148.36,77.6) v2(148.6,77.05) v2(148.95,78.18) v2(148.95,77.6) v2(149.22,77.06) v2(149.22,76.44) v2(149.53,78.18) v2(149.53,77.6) v2(149.68,105.22) v2(149.65,76.04) v2(149.79,76.9) v2(149.97,104.05) v2(150.08,103.43) v2(150.07,75.62) v2(150.11,77.42) v2(150.17,76.45) v2(150.31,105.22) v2(150.31,104.58) v2(150.55,75.95) v2(150.61,104.08) v2(150.68,103.44) v2(150.68,75.37) v2(150.95,105.22) v2(150.95,104.58) v2(151.24,104.06) v2(151.58,105.22) v2(151.58,104.58) v2(152.11,104.97) v2(152.33,104.39) v2(152.7,104.84) v2(153.07,104.38)
+0.95VS_APU_GFX: length 6
  TOP w0.508: R404.1 R542.1 R73.2 116.98,92.47 116.98,93.43 117.38,93.83 118.55,93.83
  BOTTOM w0.254: v2(121.09,92.9) 120.91,92.72 UC1.AE6 ; UC1.AE5 121.07,93.52 v2(121.11,93.48)
  vias: v2(130.42,83.25) v2(131.01,83.18) v2(131.5,82.04) v2(131.6,83.25) v2(132.14,82.04) v2(132.2,83.25) v2(144.8,82.32) v2(144.8,81.74) v2(144.8,81.15) v2(144.87,80.57) v2(145.38,82.32) v2(145.38,81.74) v2(145.38,81.15) v2(145.97,82.32) v2(145.97,81.74) v2(145.97,81.15) v4(136.92,80.67)
+0.95VSDGPU: length 41.3
  TOP w0.508: v2(185.84,139.65) 185.58,139.65 185.32,139.91 LV8.1 ; RV30.1 167.39,125.38 166.89,125.87 v2(166.56,125.87)
  IN2 w0.508: v2(160.89,132.02) 160.89,131.96 163.7,129.16 163.7,128.59 166.41,125.87 v2(166.56,125.87) ; v2(185.84,139.65) 185.31,139.65 183.31,137.64 180.14,137.64 179.2,136.69 175.38,136.69 173.6,134.91 172.18,134.91 170.55,133.29 161.31,133.29
  BOTTOM w0.508: v2(153.69,131.1) 153.13,131.1 152.5,130.47 RV1.2 152.5,129.31 RV3.2
  vias: v1(160.55,134.89) v2(151.57,138.49) v2(151.58,137.86) v2(151.58,137.22) v2(152.16,137.86) v2(152.16,137.22) v2(152.2,138.49) v2(152.75,137.86) v2(152.75,137.22) v2(160.22,136.82) v2(160.22,135.62) v2(160.22,134.23) v2(160.26,132.04) v2(160.91,136.83) v2(160.92,135.65) v2(160.91,134.23)
+0.675VS: length 103.6
  IN2 w1.016: 63.81,26.61 65.53,26.61 67.2,28.28 71.94,28.28 73.45,26.77 73.45,22.52 79.77,16.2 94.03,16.2 98.56,11.67 149.65,11.67 152.46,14.48 152.46,16.26
  BOTTOM w0.356: JDIMM1.203 v2(151.5,26.9)
  vias: v2(62.25,26.62) v2(62.85,26.62) v2(143.68,37.01) v2(143.68,36.42) v2(143.83,28.5) v2(143.84,27.88) v2(152.42,17.77) v2(152.44,17.16) v4(150.74,28.26)
+0.675VSP:
  vias: v1(63.56,23.16)
+0.775VALW: length 38.4
  TOP w0.762: 26.66,44.39 v1(27.74,45.47) 27.74,49.86 35.64,57.76 44.44,57.76 45.7,56.5 50.27,56.5 50.46,56.69 56.08,56.69 56.24,56.86
  vias: v2(26.35,43.69) v2(26.98,43.69) v2(57,56.78) v2(57.64,56.78)
+1.5VS: length 393.9
  TOP w0.508: v2(154.72,70.17) 157.06,72.51 157.06,81.19 158.36,82.49 158.36,89.98 159.89,91.5 159.89,99.2 v2(161.04,100.35) ; v2(60.89,26.35) 60.89,28.13 60.41,28.61 v2(60.41,29.1) ; v2(47.64,19.2) 46.67,18.22 v4(46.67,13.02) v2(46.67,7.81)
  IN1 w0.508: v2(121.23,162.19) 121.78,162.74 125.2,162.74 126.93,161.01 126.93,158.09 133.53,151.49 140.17,151.49 142.28,149.38 142.28,148.65 144.33,146.61 146.04,146.61 v2(146.86,145.79) ; v2(187.57,6.4) 184.51,9.46 179.6,9.46 178.56,10.5 178.56,13.03 v2(179.44,13.92) ; v2(154.72,70.17) 154.68,70.13 154.68,66.81 150.26,62.39 150.26,59.58 151.28,58.57 151.28,44.68 157.6,38.36 157.6,35.88 157.08,35.36 157.08,16.48 v2(155.84,15.24)
  IN2 w0.508: v2(53.83,20.23) 54.77,20.23 v2(60.89,26.35) ; v2(146.86,145.79) 148.8,143.85 148.8,140.37 150.29,138.89 150.29,134.57 150.46,134.39 150.46,131 147.01,127.55 147.01,122.35 147.4,121.96 147.95,121.96 148.49,122.5 152.14,122.5 157.42,117.22 157.42,115.89 159.73,113.58 159.73,102.25 160.39,101.59 160.39,101.01 v2(161.04,100.35)
  BOTTOM w0.203: UA1.9 179.59,13.78 v2(179.44,13.92)
  BOTTOM w0.508: 160.27,9.65 155.84,14.08 v2(155.84,15.24) ; PR508.1 60.41,29.87 v2(60.41,29.1) ; PR1028.1 118.28,161.27 118.8,161.8 119.63,161.8 120.02,162.19 v2(121.23,162.19) ; v2(53.83,20.23) 52.8,19.2 v2(47.64,19.2) ; RA8.1 187.14,6.4 v2(187.57,6.4) 187.57,4.76 186.37,3.56 167,3.56 161.41,9.14
  BOTTOM w1.016: 160.27,8.83 154.45,3.01 63.56,3.01 58.76,7.81 47.62,7.81
  vias: v2(46.03,7.81)
+1.5VSP: length 5.1
  TOP w0.102: v1(43.59,4.32) PR402.1
  TOP w0.254: PR402.1 PC404.1 42.3,5.73 42.48,5.91 42.48,7.53 PC405.1
+1.8V_ALW: length 207.6
  TOP w0.508: v2(153.98,53.53) 155.06,53.53 157.84,56.31 164.28,56.31 164.81,55.79 170.21,55.79 170.9,56.49 187.68,56.49 187.68,56.49 190.34,56.49 192.68,58.83 195.74,58.83 198.56,61.65 198.56,63.26 RE69.1 ; 138.23,95.92 138.76,95.92 139.16,96.32 C24.2 R3.1 144.58,95.45 R347.1 ; 138.23,95.92 138.23,98.16 138.33,98.26 138.33,98.3 138.73,98.69 141.33,98.69 143.36,100.72 148.79,100.72 151.82,103.75 154.15,103.75 155.29,102.62 v2(156.14,102.62) ; 138.23,95.92 136.61,95.92 C1085.1 135.71,95.76 135.57,95.62 C1086.1 134.72,95.62 134.65,95.55 134.65,94.92 133.95,94.22 133.95,89.93 133.34,89.32 132.95,89.32 132.43,88.8 131.31,88.8 131.2,88.68 129.47,88.68 129.11,89.05 v2(129.11,89.22) ; v2(155.29,110.78) 153.63,112.45 131.77,112.45 130.85,111.53 119.43,111.53 119.33,111.43 R346.1
  TOP w2.032: 148.32,119.13 147.43,119.13 145.94,120.61 145.94,127.7 147.71,129.46
  IN1 w1.524: 155.38,83.21 156,82.59 156.01,82.59 157.74,80.86 157.74,69.33 159.94,67.13 159.94,54.81 158.44,53.31 155.42,53.31 155.37,53.37
  IN1 w2.032: 156.14,101.04 156.14,100.32 153.57,97.75 153.57,91.22 ; 156.09,103.96 156.09,108.9
  IN2 w2.032: 150.84,117.35 155.96,112.23 155.96,111.95
  BOTTOM w0.254: v2(129.11,89.22) 128.67,89.66 UC1.AR9 128.64,89.79 128.34,89.79 UC1.AP10
  vias: v2(149.18,117.97) v2(149.61,118.39) v2(149.84,119.41) v2(150.04,118.85) v2(153.28,53.53) v2(153.28,52.9) v2(153.98,52.9) v2(155.94,110.76) v2(156.52,110.77) v2(156.76,110.2) v2(156.71,85.03) v2(156.71,84.44) v4(149.92,117.92)
+1.8V_ALWP: length 20
  BOTTOM w0.254: 156.17,50.93 156.17,51.57 156.56,51.97 v1(158.62,51.97) 159.96,51.97 160.39,51.54 160.39,48.62 161.65,47.36 161.65,40.98 160.72,40.06 PR604.1 PC603.1
+1.8VGS: length 122.4
  TOP w0.508: LV3.1 161.21,125.59 v2(160.77,125.15) ; RV27.1 v2(175.62,121.81) ; v2(178.03,136.07) 177.83,136.27 LV6.1 ; 187.95,135.61 v4(186.77,136.8) 186.07,137.49 186.07,138.42 ; RV152.2 186.31,140.85 187.06,140.09 187.06,139 186.48,138.42 186.07,138.42 ; 186.07,138.42 185.58,138.91 LV7.1
  IN1 w0.508: v2(188.65,134.88) 188.65,134.89 187.89,135.65 181.19,135.65 180.78,136.07 v2(178.03,136.07)
  IN2 w0.508: 176.55,122.68 177.42,122.68 179.67,124.94 179.67,127.44 180.25,128.02 180.25,129.29 v2(180.22,129.32) 180.22,129.4 178.89,130.73 178.89,132.21 179.56,132.88 179.56,134.94 178.43,136.07 v2(178.03,136.07)
  IN2 w1.016: 192.59,144.4 190.66,144.4 189.59,143.33 189.59,138.61 187.42,136.44 187.42,132.89 186.98,132.45 186.98,127.9 184.43,125.36 183.1,125.36 181.96,124.22 181.96,123.09 180.94,122.07 177.97,122.07
  BOTTOM w0.381: v2(188.65,134.88) U1.8
  BOTTOM w0.508: PR1113.1 162.49,92.84 161.54,93.79 161.54,94.63 161.72,94.81 161.72,96.2 162.34,96.82 162.34,101 161.44,101.9 160.04,101.9 159.71,102.24 159.71,104.07 161.52,105.88 161.52,111.05 165.04,114.57 169.33,114.57 171.85,117.08 174.17,117.08 175.62,118.53 v2(175.62,121.81) ; v2(188.65,134.88) 188.65,134.43 189.1,133.98 CV170.2 ; LV2.1 169.24,120.68 169.56,121.01 v2(169.91,121.01) ; RV82.2 182.05,130.04 RV81.2 180.74,129.85 v2(180.22,129.32)
  vias: v2(156.14,121.85) v2(156.67,121.54) v2(193.8,145.03) v2(193.8,144.34)
+1.8VGSP: length 1.6
  BOTTOM w0.254: 195.28,142 PC1204.1 PR1202.1
  vias: v1(198.02,143.38)
+1.8VS: length 440.2
  TOP w0.254: RP28.8 57.37,72 v2(57.79,71.58) 57.71,71.5 RP28.7 ; RP28.6 57.67,71 57.83,70.84 57.83,70.05 v2(57.79,70.02) 57.31,70.5 RP28.5 ; v2(57.21,63.5) 57.64,63.07 57.64,62.53 57.46,62.35 RP27.7
  TOP w0.381: U65.5 102.4,98.96 102.09,98.64 v2(101.66,98.64) 101.52,98.5 100.11,98.5 99.61,99 U64.5 ; Q2509.5 62.64,68.2 v2(63.08,67.75)
  TOP w0.406: v2(59.09,67.83) 59.45,68.2 Q2509.2
  TOP w0.432: Q79.2 Q79.5 84.38,63.18 v2(84.68,63.47)
  TOP w0.508: PR1023.1 118.28,160.99 117.77,161.49 v2(117.4,161.49) ; 129.09,84.96 129.13,85 130.49,85 130.61,85.13 134.63,85.13 135.21,85.71 135.97,85.71 138.33,88.07 C1101.1 ; 98.86,81.22 103.05,81.22 v2(103.1,81.17) ; 98.86,81.22 98.55,80.9 93.99,80.9 v2(93.81,80.72) 93.35,80.26 v2(93.35,78.94) ; 98.86,81.22 98.86,83.06 98.27,83.65 96.8,83.65 95.56,82.42 v2(94.56,82.42) 94.56,84.14 93.85,84.85 v2(93.78,84.85) 93.44,84.51 R117.2 93.02,83.92 92.63,83.53 91,83.53 89.25,85.28 89.25,87.8 89.85,88.39 92.35,88.39 ; v2(106.48,95.5) 106.48,100.9 105.84,101.55 R155.2 ; 92.35,88.39 92.39,88.39 92.97,88.98 92.97,89.7 92.33,90.34 92.33,91.51 95.31,94.49 99.62,94.49 101.66,96.52 v2(101.66,98.64) ; 92.35,88.39 92.67,88.07 v2(92.67,87.82) 92.6,87.76 92.6,86.63 v2(92.77,86.46) ; v2(50.86,62.29) 50.86,61.72 50.35,61.21 JHDT1.19 ; RH45.1 150.88,54.15 151.47,54.74 151.47,55.87 148.99,58.34 v2(148.99,65.68) ; RC8.2 103.69,110.81 104.05,110.44 QC1.2 104.05,108.48 103.78,108.2 100.77,108.2 v2(99.56,109.41) ; C1101.1 140.65,88.77 141.44,89.57 v2(141.79,89.57) ; C1101.1 C1100.1 ; R4.1 167.15,64.39 169.55,66.79 169.55,67.77 168.89,68.43 168.19,68.43 167.84,68.07 R7.1 167.01,68.53 167.37,68.89 167.37,70.75 166.17,71.95 R1675.1 164.78,71.15 161.81,71.15 159.24,68.58 157.41,68.58 156.51,67.68 v2(156.51,67.25) ; JHDT1.1 v2(50.72,72.64) ; v2(89.59,81.79) 89.6,81.79 89.9,81.5 89.9,76.58 85.16,71.84 v2(85.16,65.93)
  TOP w1.27: 155.59,66.52 150.73,66.52
  IN1 w0.508: v2(57.84,29.9) 57.41,29.9 56.33,30.98 56.33,34.86 57.4,35.93 57.4,37.21 55.84,38.77 55.84,42.91 56.19,43.27 56.19,46.1 54.78,47.51 54.78,48.09 55.59,48.91 55.59,50.89 54.95,51.53 54.95,57.72 55.96,58.73 55.96,62.26 v2(57.21,63.5) ; v2(63.08,67.75) 63.08,68.74 67.75,73.41 67.75,76.2 68.93,77.38 70.69,77.38 88.91,95.61 89.39,95.61 91.13,97.35 100.36,97.35 v2(101.66,98.64) 102.2,98.64 103.74,97.1 104.54,97.1 105.15,96.49 105.49,96.49 v2(106.48,95.5)
  IN1 w1.27: 146.54,76.86 146.54,75.8 149.34,73 149.34,68.03 149.64,67.73 ; 148.63,109.99 146.22,107.58 146.22,104.38 149.52,101.08 149.52,96.71 146.87,94.06 145.74,94.06 145,93.32 145,92.49 146.83,90.67 146.83,88.81 147.58,88.06 148.75,88.06 149.47,87.34 150.84,87.34 152.65,85.53 152.65,83.17 155.78,80.04 155.78,73.55
  IN2 w0.508: v2(117.4,161.49) 118.13,162.22 118.17,162.18 120.33,162.18 121,161.51 121,160.76 123.32,158.43 128.23,158.43 133.84,152.82 139.74,152.82 142.77,149.79 142.77,149.16 145.5,146.43 147.08,146.43 149.41,144.11 149.41,140.65 150.89,139.17 150.89,134.9 151.82,133.98 151.82,130.94 v2(149.79,128.91) ; v2(84.68,63.47) 84.14,64.01 84.14,65.16 84.91,65.93 v2(85.16,65.93) ; v2(103.1,81.17) 103.46,81.17 105.52,83.22 106.94,83.22 108.13,84.42 115.77,84.42 115.98,84.63 116.92,84.63 117.14,84.85 120.9,84.85 121.32,84.43 126.54,84.43 127.2,83.76 v2(128.02,83.76)
  BOTTOM w0.508: 141.5,88.95 141.79,89.24 v2(141.79,89.57) ; 141.5,88.95 141.2,88.95 R956.1 ; 141.5,88.95 R955.1 ; v2(99.56,109.41) 98.25,108.1 98.25,103.13 101.06,100.32 101.06,99.74 101.66,99.14 v2(101.66,98.64) ; v2(89.59,81.79) 90.14,81.79 90.25,81.9 92.6,81.9 92.72,81.79 93.47,81.79 93.97,82.3 93.97,82.42 ; v2(92.77,86.46) 93.45,86.46 93.67,86.68 R159.1 ; R80.1 R82.1 93.68,78.61 v2(93.35,78.94) ; v2(92.67,87.82) 92.66,87.82 92.66,88.11 93.35,88.8 93.94,88.8 94.16,88.57 R2.1 R13.1 ; v2(93.81,80.72) 93.88,80.64 R15.1 R10.1 ; v2(93.78,84.85) 94.23,84.4 R9.1 R14.1 ; PR506.1 v2(57.84,29.9)
  vias: v2(128.33,84.27) v2(128.99,84.29) v2(148.12,111.03) v2(148.74,111.04) v2(149.36,111.05) v2(149.49,66.13) v2(149.68,66.73) v2(150.02,127.97) v2(150.63,128.08) v2(151.26,121.44) v2(151.66,120.98) v2(152.14,120.61) v2(155.34,67.55) v2(155.76,67.97) v4(129.01,85.59)
+1.8VS_LS: length 1.1
  TOP w0.102: 152.84,130.2 v1(153.96,130.2)
+1.35V: length 90.7
  TOP w0.508: C1112.1 v2(107.07,62.22) ; C1114.1 v2(128.83,62.99) ; C1116.1 v2(128.85,59.94) ; C1111.1 v2(107.07,63.74) ; C1115.1 129.08,61.47 v2(128.83,61.21) ; C1113.1 v2(107.07,60.69)
  BOTTOM w0.229: v2(119.97,73.89) 119.77,73.69 UC1.AD30 ; v2(115.26,71.74) 115.25,71.74 115.25,71.75 114.97,71.48 UC1.V33 ; UC1.AF30 121.37,73.68 v2(121.17,73.89) ; v2(126.56,72.92) 126.17,73.32 UC1.AM30 ; v2(123.36,72.92) 122.97,73.32 UC1.AH30 ; UC1.Y30 116.57,73.32 v2(116.96,72.92) ; UC1.V30 114.97,73.32 v2(114.57,72.92) ; v2(124.96,72.92) 124.57,73.32 UC1.AK30 ; v2(118.77,73.89) 118.2,73.32 UC1.AB30 ; UC1.AB33 117.79,71.7 117.79,72.04 v2(117.68,72.14) ; v2(121.37,70.8) UC1.AF33 ; UC1.AK33 124.57,70.37 v2(124.58,70.36)
  BOTTOM w0.254: UC1.AH24 v2(122.37,77.82)
  BOTTOM w0.305: UC1.U25 114.77,77.32 v2(115.17,76.92) ; v2(124.77,74.52) 124.37,74.92 UC1.AK28 ; v2(113.97,77.82) 113.37,78.42 UC1.T24 ; UC1.AG28 121.55,74.92 v2(121.2,74.57) ; UC1.W24 115.77,78.42 v2(116.37,77.82) 116.87,77.32 UC1.Y25 ; v2(118.77,75.32) 118.37,75.72 UC1.AB27 ; UC1.W27 115.92,75.72 v2(116.37,75.27) ; v2(117.57,74.52) 117.17,74.92 UC1.Y28 ; UC1.P28 112.37,74.92 v2(112.77,74.52) ; v2(112.75,76.87) 112.74,76.87 112.74,76.94 112.37,77.32 UC1.P25 ; UC1.AE24 120.57,78.42 v2(121.17,77.82) 121.66,77.32 UC1.AG25 ; UC1.AE27 120.77,75.72 v2(121.17,75.32) ; UC1.AB24 118.17,78.42 v2(118.77,77.82) 119.26,77.32 UC1.AD25 ; v2(123.57,77.82) 124.06,77.32 UC1.AK25 ; UC1.T27 113.57,75.72 v2(113.97,75.32) ; UC1.AL27 125.57,75.72 v2(125.97,75.32) ; UC1.AD28 119.57,74.92 v2(119.97,74.52) ; UC1.AH27 123.17,75.72 v2(123.57,75.32) ; UC1.U28 114.77,74.92 v2(115.17,74.52)
  BOTTOM w0.356: v2(112.15,32.33) 112.15,31.37 112.4,31.12 JDIMM2.100 ; JDIMM2.123 119.3,39.46 119.23,39.52 ; JDIMM1.118 v2(126,15.39) ; v2(106.84,39.54) 106.7,39.4 JDIMM2.81 ; JDIMM1.105 122.1,23.88 v2(122.41,23.57) ; 105.21,39.57 104.9,39.26 JDIMM2.75 ; v2(114.09,31.36) 114.2,31.25 JDIMM2.106 ; JDIMM2.124 119.6,29.05 119.83,28.82 v2(119.83,28.35) ; v2(105.08,31.6) 105.2,31.48 JDIMM2.76 ; JDIMM1.124 v2(127.8,15.39) ; JDIMM1.88 v2(117,15.39) ; v2(115.62,31.31) 116,30.93 JDIMM2.112 ; v2(127.44,22.62) 127.25,22.62 126.97,22.9 126.97,23.28 127.5,23.81 JDIMM1.123 ; v2(123.92,23.56) 123.9,23.58 JDIMM1.111 ; JDIMM1.100 v2(120.6,15.39) ; JDIMM1.81 114.9,23.38 114.36,22.85 v2(113.19,22.85) ; v2(115.2,15.37) JDIMM1.82 ; v2(108.71,39.59) 108.5,39.38 JDIMM2.87 ; JDIMM1.87 116.7,23.6 v2(116.77,23.53) ; JDIMM2.94 110.6,31.09 110.32,31.37 v2(110.32,31.92) ; JDIMM1.112 v2(124.2,15.39) ; JDIMM1.106 v2(122.4,15.39) ; JDIMM2.105 113.9,39.32 v2(113.68,39.54) ; JDIMM1.99 120.3,23.79 120.07,23.56 118.28,23.56 v2(118.18,23.65) 118.5,23.97 JDIMM1.93 ; v2(110.14,39.56) 110.3,39.4 JDIMM2.93 ; JDIMM2.99 112.1,39.4 v2(112.26,39.56) ; JDIMM2.88 v2(108.8,31.87) ; JDIMM2.117 117.5,39.54 ; JDIMM1.94 v2(118.8,15.39) ; v2(125.1,23.34) 125.7,23.94 JDIMM1.117 ; v2(113.1,23.44) JDIMM1.75 ; JDIMM1.76 v2(113.4,15.37) ; JDIMM2.118 v2(117.8,31.48) ; JDIMM2.82 107,31.59 v2(107.02,31.61) ; JDIMM2.111 v2(115.7,39.54)
  vias: v2(113.93,36.23) v2(113.95,34.43) v2(114.86,33.53) v2(119.77,19.12) v2(122.8,22.16) v2(126.72,15.41) v4(116.62,19.52)
+1.35V_MEM_GFX: length 136.4
  TOP w0.229: v2(187.13,163.12) 186.79,162.77 186.12,162.77 UV7.K2 ; UV6.K8 v2(156.03,162.77) ; UV7.K8 v2(180.52,162.77) 179.83,162.77 179.63,162.57 179.63,162.23 180.12,161.74 UV7.H9
  TOP w0.254: UV6.N1 v2(161.64,165.19) ; v2(155.15,165.97) 155.23,165.97 UV6.N9 ; UV7.E9 180.02,159.17 v2(179.63,159.56) ; UV7.B2 185.72,156.77 186.52,155.98 UV7.A1 186.52,155.85 v2(186.84,155.54) ; UV7.N1 186.93,165.57 v2(187.04,165.68) ; v2(155.15,157.97) 155.55,157.57 UV6.C9 ; UV7.N9 180.03,165.57 v2(179.63,165.97) ; UV7.C9 180.03,157.57 v2(179.63,157.97) 180.04,158.37 UV7.D9 ; v2(162.54,157.57) UV6.C1 162.03,157.75 161.41,158.37 UV6.D2 ; v2(187.06,167.18) 187.06,167.17 UV7.R1 ; UV7.D2 185.72,158.36 v2(186.11,157.97) ; UV6.H2 161.23,161.58 v2(161.62,161.97) ; v2(156.58,155.49) 156.43,155.64 UV6.A8 ; v2(155.24,159.56) UV6.E9 ; v2(155.17,167.57) 155.57,167.17 UV6.R9 ; UV7.G7 v2(181.32,161.17) ; v2(179.43,160.96) 179.58,160.96 180.12,161.49 UV7.H9 ; UV6.H9 v2(155.25,161.19) ; UV7.H2 185.72,161.58 v2(186.11,161.97) ; UV6.B2 161.24,156.77 162.03,155.98 UV6.A1 162.04,155.97 v2(162.45,155.56) ; v2(161.62,166.81) 161.98,167.17 UV6.R1 ; v2(156.02,157.98) 155.64,158.37 UV6.D9 ; UV7.A8 180.92,155.62 v2(181.2,155.34) ; v2(179.72,167.57) UV7.R9 ; UV6.F1 v2(162.43,159.57) ; UV7.F1 v2(186.92,159.57) ; UV7.C1 187.05,158.1 v2(187.06,158.1) ; UV6.G7 v2(156.83,161.17) ; v2(161.63,162.77) UV6.K2
  TOP w0.508: v2(155.77,153.67) 155.77,153.67 CV172.1 ; v2(177.35,158.74) 177.36,158.72 CV148.1 ; CV142.1 177.45,161.92 v2(177.33,161.8) ; v2(164.89,168.67) 164.6,168.37 CV129.1 ; CV136.1 188.72,154.36 v2(188.14,154.93) ; v2(178.59,167.5) 178.58,167.48 CV149.1 ; v2(154.03,168.2) CV128.1 ; v2(154.03,167.18) CV173.1 ; v2(190.22,159.81) RV50.1 ; CV118.1 154.14,169.34 v2(154.16,169.35) ; v2(164.79,157.6) CV119.1 ; v2(186.46,153.67) CV147.1 ; CV51.1 178.6,140.97 CV49.1 178.6,142.45 178.85,142.7 179.86,142.7 180.11,142.45 CV44.1 180.56,143.49 CV174.1 ; v2(154.03,156) CV125.1 CV121.1 ; v2(154.03,159.05) CV127.1 ; v2(177.35,157.73) CV141.1 ; CV124.1 161.81,153.67 v2(161.92,153.55) 162.59,153.55 v1(162.95,153.92) 163.92,154.89 CV122.1 ; v2(188.1,168.32) CV138.1 ; v2(154.03,157.02) CV130.1 ; v2(154.03,161.08) CV117.1 ; v2(154.03,158.04) CV126.1 ; v2(188.08,167.31) CV144.1 ; v2(188.1,166.29) CV145.1 ; v2(188.03,164.88) 188.42,165.28 CV139.1 ; RV33.1 v2(155.25,137.16) ; v2(188.08,156.51) CV146.1 ; v2(163.52,158.92) 163.84,158.59 CV179.1 ; v2(188.08,157.53) CV150.1 ; v2(188.08,155.56) 188.64,155.56 CV181.1 ; v2(180.9,154.29) CV140.1 ; v2(178.66,165.81) 178.66,166.38 178.42,166.62 CV143.1 ; v2(151.86,165.78) RV43.1 ; v2(154.03,160.07) CV131.1 ; v2(164.78,161.82) 164.75,161.8 CV132.1 ; v2(177.34,154.4) CV137.1 ; v2(188.08,158.54) CV180.1
  IN1 w0.254: v2(164.1,140.23) 164.05,140.23 163.62,139.8 163.62,138.44 163.09,137.92 v2(162.62,137.92) ; v2(180.52,162.77) 180.95,163.2 181.48,163.2 181.77,162.91 181.77,161.63 v2(181.32,161.17) ; v2(184.4,160.85) 184.65,161.1 184.65,162.23 184.97,162.54 185.54,162.54 v2(186.11,161.97)
  IN1 w0.508: v2(156.03,162.77) 156.03,163.04 156.35,163.37 157.12,163.37 157.43,163.05 157.43,161.66 156.95,161.17 v2(156.83,161.17)
  BOTTOM w0.229: v2(187.13,163.12) 186.79,162.77 186.12,162.77 UV7.K2 ; UV7.K8 v2(180.52,162.77) ; UV6.K8 v2(156.03,162.77)
  BOTTOM w0.254: v2(186.92,159.57) 186.52,159.18 UV8.E9 ; UV7.N1 186.93,165.57 v2(187.04,165.68) ; v2(155.24,159.56) 155.22,159.56 UV5.F1 ; UV1.K10 171.69,138.41 v2(172.04,138.76) ; v2(162.43,159.57) 162.03,159.18 UV5.E9 ; v2(161.23,155.38) UV5.A8 ; UV5.D2 156.41,158.37 v2(156.02,157.98) 155.63,157.59 UV6.C9 155.55,157.57 v2(155.15,157.97) ; v2(155.33,155.57) 155.63,155.87 UV5.A1 UV5.B2 ; v2(186.11,161.97) 186.51,161.57 UV8.H9 ; UV7.C9 180.03,157.57 v2(179.63,157.97) ; v2(179.63,159.56) 179.77,159.56 180.12,159.91 UV8.F1 ; UV5.D9 162.37,158.37 v2(162.54,158.54) ; UV5.H2 v2(156.83,161.17) ; UV7.N9 180.03,165.57 v2(179.63,165.97) ; v2(187.06,158.1) 187.05,158.1 UV7.C1 ; UV1.J10 171.69,139.21 v2(172.04,139.56) ; UV8.D9 186.51,158.37 v2(186.11,157.97) ; v2(179.63,155.56) 180.05,155.97 UV8.A1 UV8.B2 181.32,156.37 181.32,155.46 v2(181.2,155.34) ; UV8.A8 185.72,155.55 v2(185.58,155.41) ; v2(187.06,167.18) 187.06,167.17 UV7.R1 ; v2(180.52,157.97) 180.92,158.36 UV8.D2 ; UV8.H2 v2(181.32,161.17) ; UV1.H13 169.49,140.01 169.92,140.44 v2(170.05,140.44) ; UV6.R1 161.98,167.17 v2(161.62,166.81) ; UV6.R9 155.57,167.17 v2(155.17,167.57) ; UV1.J24 160.49,139.16 v2(160.89,139.56) UV1.J23 ; UV6.C1 v2(162.54,157.57) ; v2(179.72,167.57) UV7.R9 ; UV6.N9 155.23,165.97 v2(155.15,165.97) ; v2(184.4,160.85) 184.84,160.85 UV8.G7 ; UV6.N1 v2(161.64,165.19) ; UV5.H9 162.02,161.57 v2(161.62,161.97) ; v2(161.63,162.77) UV6.K2
  BOTTOM w0.305: v2(172.04,138.76) 172.44,138.36 UV1.K9 ; UV1.L12 169.96,137.56 v2(170.34,137.94) 170.72,137.56 UV1.L11 UV1.K10 ; v2(168.97,138.16) 168.89,138.08 UV1.L13 ; UV1.H16 167.09,140.03 167.29,140.23 v2(167.7,140.23) ; UV1.J9 172.44,139.16 v2(172.04,139.56) ; UV1.H19 164.42,140.23 v2(164.1,140.23) ; UV1.K24 160.49,138.36 v2(160.89,138.76) UV1.K23
  BOTTOM w0.381: v2(162.66,137.09) 162.18,137.56 UV1.L22 ; UV1.L20 UV1.L21 162.97,137.56 v2(162.62,137.92)
  BOTTOM w0.508: v2(155.77,153.67) 155.77,153.67 CV172.1 ; v2(154.03,168.2) CV128.1 ; v2(188.08,169.34) CV165.1 ; v2(188.08,156.51) CV146.1 ; v2(165.53,168.67) 165.53,167.83 RV42.1 ; CV181.1 188.64,155.56 v2(188.08,155.56) ; v2(163.52,158.92) 163.84,158.59 CV179.1 ; v2(154.03,157.02) CV130.1 ; CV149.1 178.58,167.48 v2(178.59,167.5) ; v2(154.03,156) CV125.1 ; CV143.1 178.34,166.62 178.66,166.31 v2(178.66,165.81) ; v2(154.03,161.08) CV117.1 ; CV142.1 177.45,161.92 v2(177.33,161.8) ; v2(161.92,153.55) 161.36,153.55 CV124.1 ; v2(164.9,155.38) 164.9,155.13 164.66,154.89 CV122.1 ; v2(164.79,157.6) CV119.1 ; v2(180.9,154.29) CV140.1 ; CV148.1 177.36,158.72 v2(177.35,158.74) ; v2(154.03,159.05) CV127.1 ; v2(164.89,168.67) 164.6,168.37 CV129.1 ; v2(177.34,154.4) CV137.1 ; v2(177.35,157.73) CV141.1 ; v2(188.08,157.53) CV150.1 ; v2(164.78,161.82) 164.75,161.8 CV132.1 ; v2(154.03,167.18) CV173.1 ; v2(190.24,166.29) RV51.1 ; v2(186.46,153.67) CV147.1 ; v2(188.1,168.32) CV138.1 ; v2(154.03,158.04) CV126.1 ; CV118.1 154.14,169.34 v2(154.16,169.35) ; v2(177.98,162.66) CV164.1 ; CV151.1 188.65,154.43 v2(188.14,154.93) ; v2(154.03,160.07) CV131.1 ; v2(188.08,167.31) CV144.1 ; v2(188.08,158.54) CV180.1 ; v2(154.04,166.51) 154.04,166.39 153.82,166.16 CV109.1
  vias: v2(159.68,160.85) v2(193.05,151.38) v2(193.05,150.62) v2(194.11,151.38) v2(194.11,150.62) v2(195,151.38) v2(195,150.62)
+1.35VGPUP: length 8.2
  TOP w0.254: v2(200.02,156.53) 200.91,157.42 200.91,161.26 200.46,161.71 v2(200.46,162.56)
  BOTTOM w0.254: v2(200.46,162.56) 200.15,162.88 PC1408.1 201.02,163.18 PR1406.1
  vias: v1(198.85,153.8)
+1.35VP: length 43.3
  TOP w0.203: v2(59.14,26.39) PR207.2 PC214.2 59.14,24.36 59.8,23.7 PU200.5
  IN1 w0.762: v2(63.18,22.49) 63.18,24.69 65.77,27.28 77.21,27.28 v2(77.93,26.56)
  IN2 w0.254: v2(59.14,26.39) 59.99,27.25 60.5,27.25 62.07,28.82 63.3,28.82 64.01,29.53 73.91,29.53 76.88,26.56 v2(77.93,26.56)
  vias: v2(78.02,25.78) v2(78.02,25.15) v2(78.02,24.51) v2(78.02,23.88) v2(78.66,26.42) v2(78.66,25.78) v2(78.66,25.15) v2(78.66,24.51) v2(78.66,23.88) v2(79.34,25.79) v2(79.34,25.16) v2(79.34,24.52) v2(79.34,23.89) v4(76.64,20.07)
+3VALW: length 1205.3
  TOP w0.305: JPWR.1 197.15,169.36 197.16,169.37
  TOP w0.381: CH14.1 135.25,105.93 UH1.5
  TOP w0.508: v2(162.86,39.75) 164.49,39.75 165.25,40.51 RE75.1 ; C1124.1 137.43,90.77 ; 137.43,90.77 v2(137.43,91.48) ; 137.43,90.77 137.39,90.8 136.25,90.8 135.76,90.31 135.76,89.76 133.41,87.41 129.25,87.41 128.83,86.99 128.83,86.49 128.01,85.66 C1126.1 127.6,85.47 v2(128.05,85.02) ; v2(124.92,105.91) 124.92,105.98 125.44,106.5 R905.1 ; RE20.2 172.73,80.49 v2(171.81,80.49) 170.97,80.49 168.31,77.83 168.31,71.75 170.57,69.49 170.57,67.13 v2(170.19,66.75) ; v2(136.53,105.64) 136.18,105.99 CH14.1 ; R654.2 87.17,78.74 86.45,78.03 v2(81.1,78.03) 80.84,78.03 80.07,78.8 80.07,81.67 83.74,85.34 85.72,85.34 89.23,88.85 89.23,90.06 96.44,97.27 96.44,103.34 98.55,105.45 103.29,105.45 108.26,100.48 v2(112.1,100.48) ; v2(197.36,72.63) 197.29,72.69 RE61.1 ; 53.59,80.25 53.13,80.25 51.77,78.89 v2(51.77,77.27) ; v2(93.16,153.11) 92.97,153.11 92.3,153.78 PR3.2 ; v2(128.39,107.23) 128.39,106.57 R928.1 R954.1 ; RE21.1 v2(196.97,78.23) ; PR37.1 144.57,171.4 144.78,171.61 v2(145.67,171.61) ; R21.1 143.62,99.63 v2(143.69,99.71) ; 197.16,169.37 v2(197.16,173.04) ; v2(139.09,93.64) 139.94,94.49 141.81,94.49 142.4,95.07 143.54,95.07 144.13,94.49 R348.1 ; v2(150.58,161.68) 150.55,161.66 PR16.2 150.54,160.85 PR28.1 ; v2(121.34,99.19) 120.9,98.74 116.81,98.74 116.55,99 116.55,99.69 v2(114.86,101.38) ; v2(171.76,65.9) 173.3,67.44 RE13.1 ; RE23.2 177.98,60.13 177.58,59.73 172.87,59.73 v2(172.46,60.13) ; RV94.1 179.98,126.7 v2(180.36,126.32) ; RE17.2 v2(188.35,82.5) ; R944.1 v2(124.78,117.92)
  TOP w1.016: 29.27,29.34 29.27,34.02 28.26,35.03 28.26,41.14 29.5,42.37 29.5,49 32.57,52.07
  TOP w3.556: 157.83,22.01 157.99,21.84 157.99,12.08 155.44,9.52 95.61,9.52 92.42,12.71 69.73,12.71 69.08,12.06 54.39,12.06 50.74,15.71 50.74,22.77 45.56,27.95 37.39,27.95
  IN1 w0.508: 145.67,172.97 v2(145.67,171.61) ; 145.67,172.97 149.43,176.73 193.07,176.73 196.77,173.04 v2(197.16,173.04) ; 145.67,172.97 140.94,177.7 122.06,177.7 v2(118.42,174.05) 117.69,173.33 110.2,173.33 109.34,172.47 109.34,169.1 104.7,164.47 96.5,164.47 93.85,161.81 93.85,153.8 v2(93.16,153.11) ; v2(121.34,99.19) 121.97,99.19 v2(124.4,101.62) 124.4,102.54 124.26,102.68 124.26,105.26 124.91,105.91 ; v2(193.21,128.36) 189.62,128.36 188.65,127.39 183.98,127.39 183.78,127.6 181.63,127.6 v2(180.36,126.32) ; v2(180.52,25.08) 179.66,25.95 179.66,33.53 180.42,34.29 180.42,38.11 177.53,41 177.53,42.64 173.88,46.29 173.88,52.18 172.46,53.61 v2(172.46,60.13) 172.46,61.09 171.6,61.95 171.6,65.74 v2(171.76,65.9) 171.76,65.99 170.99,66.76 170.2,66.76 v2(170.19,66.75) 170.17,66.76 168.63,66.76 167.38,68.01 167.25,68.01 164.6,70.66 163.54,70.66 161.22,72.98 161.22,76.33 158.97,78.58 158.97,81.21 157.3,82.88 157.3,85.59 v2(156.65,86.23) ; v2(51.77,77.27) 47.67,77.27 44.39,73.99 44.39,65.67 44.2,65.48 44.2,62.59 41.87,60.26 41.87,58.24 40.01,56.39 36.39,56.39 33.65,53.64 v2(33.65,53.21) ; 124.91,105.91 125.14,106.13 127.3,106.13 v2(128.39,107.23) 128.78,107.62 128.78,108.62 129.5,109.33 135.12,109.33 v2(135.49,108.97) 135.49,106.68 v2(136.53,105.64) 138.22,105.64 139.43,104.42 v2(139.43,104.08) ; 124.91,105.91 v2(124.92,105.91) ; v2(139.09,93.64) 139.09,93.78 141.9,96.6 144.21,96.6 145.09,97.47 145.09,98.31 v2(143.69,99.71) ; v2(196.97,78.23) 196.59,77.85 196.59,72.9 196.84,72.64 197.34,72.64 v2(197.36,72.63)
  IN1 w1.016: 139.06,91.54 139.06,89.95 139.49,89.52 140.13,89.52 140.98,88.67 142.12,88.67 143.32,89.88 144.24,89.88 144.84,89.28 144.84,87.22 147.19,84.87 150.05,84.87 150.56,84.35 150.56,81.72 152.48,79.81 152.48,78.68 152.62,78.54 152.62,74.63 152.88,74.37 152.88,68.07 151.49,66.69 151.49,64.84 149.4,62.74 149.4,59.23 150.21,58.41 150.21,44.53 155.07,39.66 155.07,37.91
  IN2 w0.508: 190.18,75.21 190.18,75.02 190.76,74.43 191.86,74.43 192.26,74.04 192.26,72.47 v2(191.81,72.03) ; 190.18,75.21 189.76,75.63 v2(188.02,75.63) 187.51,76.14 187.51,76.72 ; 190.18,75.21 190.18,75.67 192.04,77.53 194.16,77.53 194.68,78.05 196.08,78.05 ; 187.51,76.72 187.51,79.06 189.03,80.58 189.03,81.81 v2(188.35,82.5) 188.68,82.5 189.08,82.91 189.08,84.54 188.4,85.23 186.7,85.23 186.52,85.41 180,85.41 178.14,87.27 174.68,87.27 173.15,85.74 173.15,83.96 171.81,82.63 v2(171.81,80.49) ; 187.51,76.72 187.12,77.11 185.93,77.11 185.67,76.85 185.67,75.9 185.3,75.53 183.63,75.53 v2(183.38,75.78) ; v2(193.21,128.36) 193.8,128.94 193.8,131.38 198.75,136.33 v2(200.08,136.33) ; v2(124.78,117.92) 129.13,117.92 135.49,111.56 v2(135.49,108.97) ; v2(164.71,18.35) 162.62,18.35 160.27,20.7 160.27,23.24 v2(159.12,24.38) ; v2(150.58,161.68) 150.96,162.06 150.96,167.91 148.66,170.21 146.67,170.21 145.67,171.2 v2(145.67,171.61) ; v2(33.65,53.21) 33.67,53.21 37.62,57.16 48.94,57.16 53.65,52.45 53.65,48.53 55.05,47.13 v2(55.05,45.38) ; v2(114.86,101.38) 113.01,101.38 v2(112.1,100.48)
  IN2 w1.016: 36.63,174.12 39.99,177.47 69.22,177.47 70.91,175.78 78.52,175.78 79.36,174.94 115.69,174.94 118.29,177.55 134.03,177.55 134.71,178.23 139.15,178.23 141.23,176.15 150.36,176.15 150.98,176.77 151.94,176.77 152.34,176.36 195.23,176.36 196.97,174.62 ; 196.43,172.31 191.97,167.84 191.97,156.69 192.33,156.32 192.33,154.53 193.63,153.24 195.75,153.24 195.88,153.24 197.14,151.98 197.14,151.85 197.14,151.85 197.14,151.2 197.14,147.24 200.08,144.3 200.08,138.56
  IN2 w1.524: 196.85,81.03 196.85,115.32 197.76,116.24 197.76,130.97 200.59,133.79 200.59,135.32
  BOTTOM w0.305: UC1.AP15 127.77,85.31 v2(128.05,85.02) UC1.AR15
  BOTTOM w0.508: R930.1 124.9,105.68 124.92,105.71 v2(124.92,105.91) ; R943.1 R931.1 R932.1 ; R943.1 141.41,102.1 v2(139.43,104.08) ; R943.1 143.25,100.15 v2(143.69,99.71) ; RE70.1 178.83,66.47 177.99,65.63 175.7,65.63 175.01,66.32 172.18,66.32 v2(171.76,65.9) ; R2634.2 R916.2 v2(55.05,45.38) ; v2(124.4,101.62) 124.26,101.48 R951.1 ; v2(188.02,75.63) RE63.1 RE62.1 ; v2(162.86,39.75) 162.46,39.36 162.46,37.07 ; v2(191.81,72.03) 191.83,72.01 RE19.1 ; R151.1 v2(164.71,18.35) ; v2(51.77,77.27) 52.47,76.57 53.83,76.57 54.11,76.85 70.53,76.85 72.28,75.1 78.16,75.1 v2(81.1,78.03) ; RA10.1 184,22.68 181.6,25.08 v2(180.52,25.08) ; v2(156.65,86.23) 156.84,86.04 R1673.1 ; v2(121.34,99.19) 121.34,99.75 R942.1 ; PR756.2 v2(118.42,174.05) ; R949.1 v2(114.86,101.38)
  BOTTOM w1.016: 32.31,13.14 32.31,24.76
  BOTTOM w1.524: 179.63,39.69 179.94,39.99 179.94,45.15 195.94,61.15 195.94,65.63 196.34,66.02 196.34,71.45 196.14,71.64 196.14,74.79 196.02,74.92 196.02,77.48 196.08,77.55 195.87,77.76
  vias: v2(29.48,25.21) v2(29.52,26.64) v2(29.52,25.88) v2(30.23,26.63) v2(30.23,25.87) v2(30.24,25.21) v2(30.92,26.67) v2(30.92,25.91) v2(31.68,27.43) v2(31.68,26.67) v2(31.68,25.91) v2(32.31,27.43) v2(32.31,26.67) v2(32.31,25.91) v2(32.63,11.81) v2(32.95,27.43) v2(32.95,26.67) v2(33.08,12.32) v2(33.2,52.77) v2(35.81,173.16) v2(36.44,173.18) v2(155.07,36.91) v2(155.26,36.33) v2(155.66,36.91) v2(155.9,36.33) v2(156.24,36.91) v2(156.53,36.33) v2(156.83,36.91) v2(196.42,78.87) v2(197.06,78.85) v2(197.16,173.74) v2(200.08,137.6) v2(200.08,136.97) v4(33.46,29.4) v4(53.33,80.84) v4(156.9,34.8)
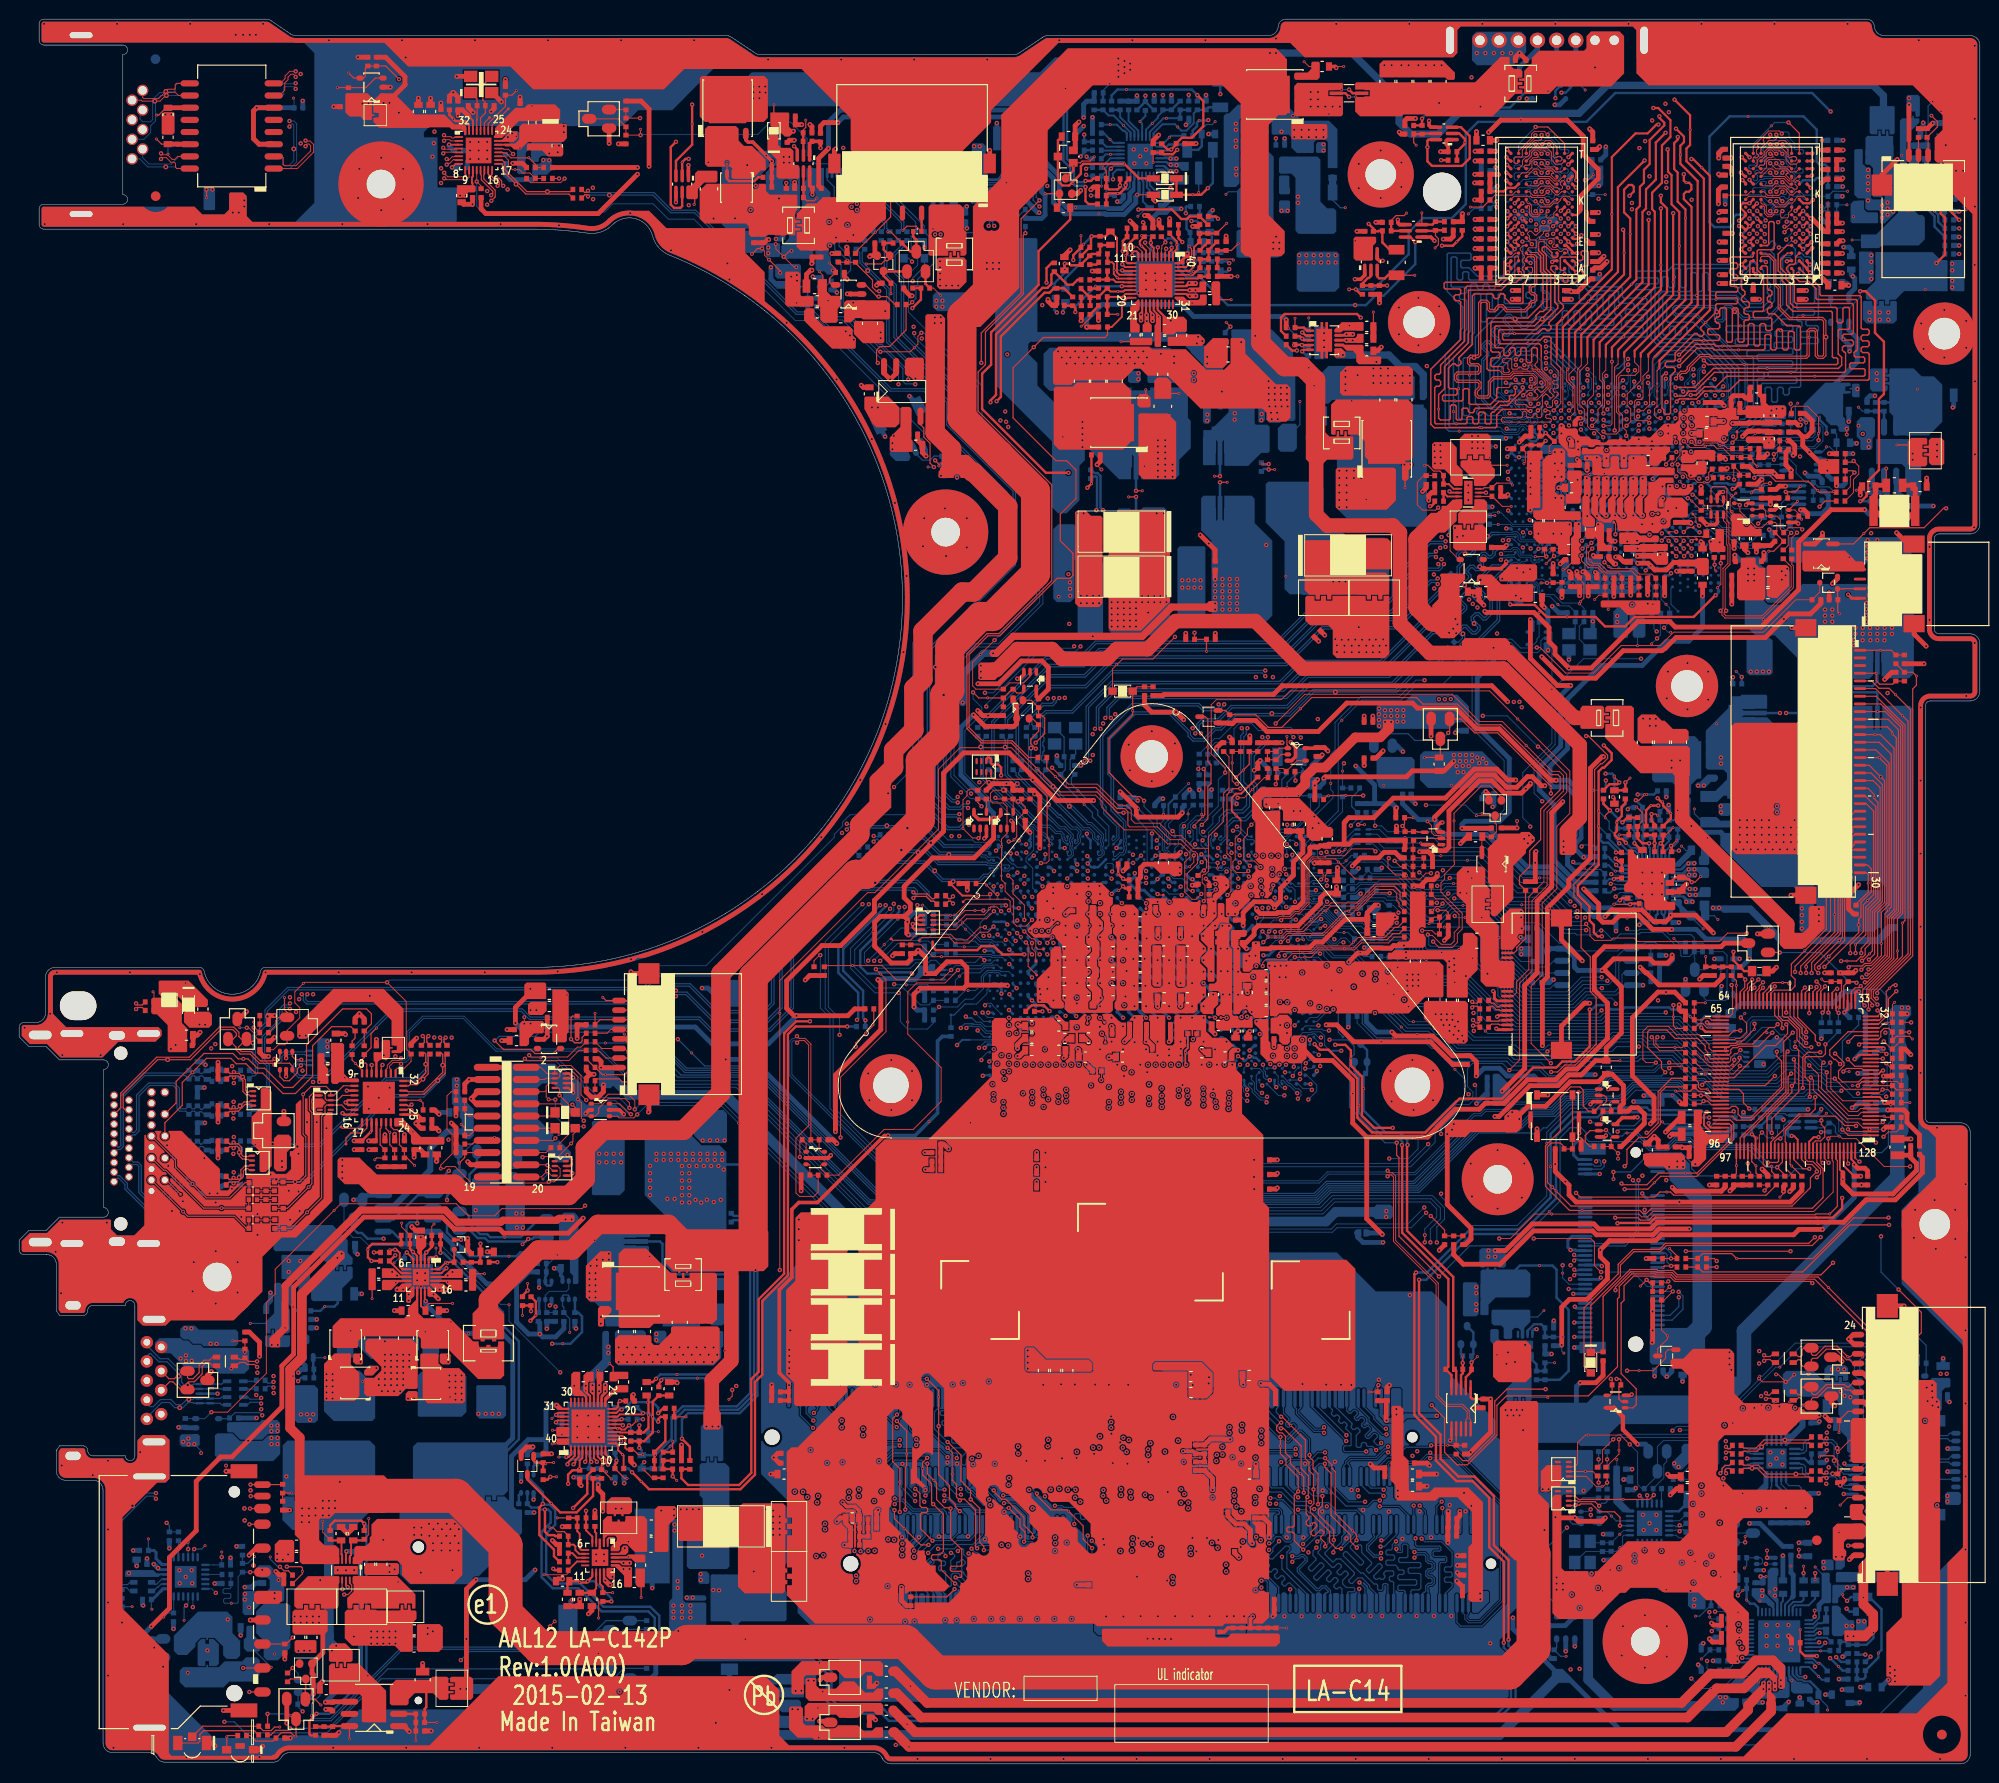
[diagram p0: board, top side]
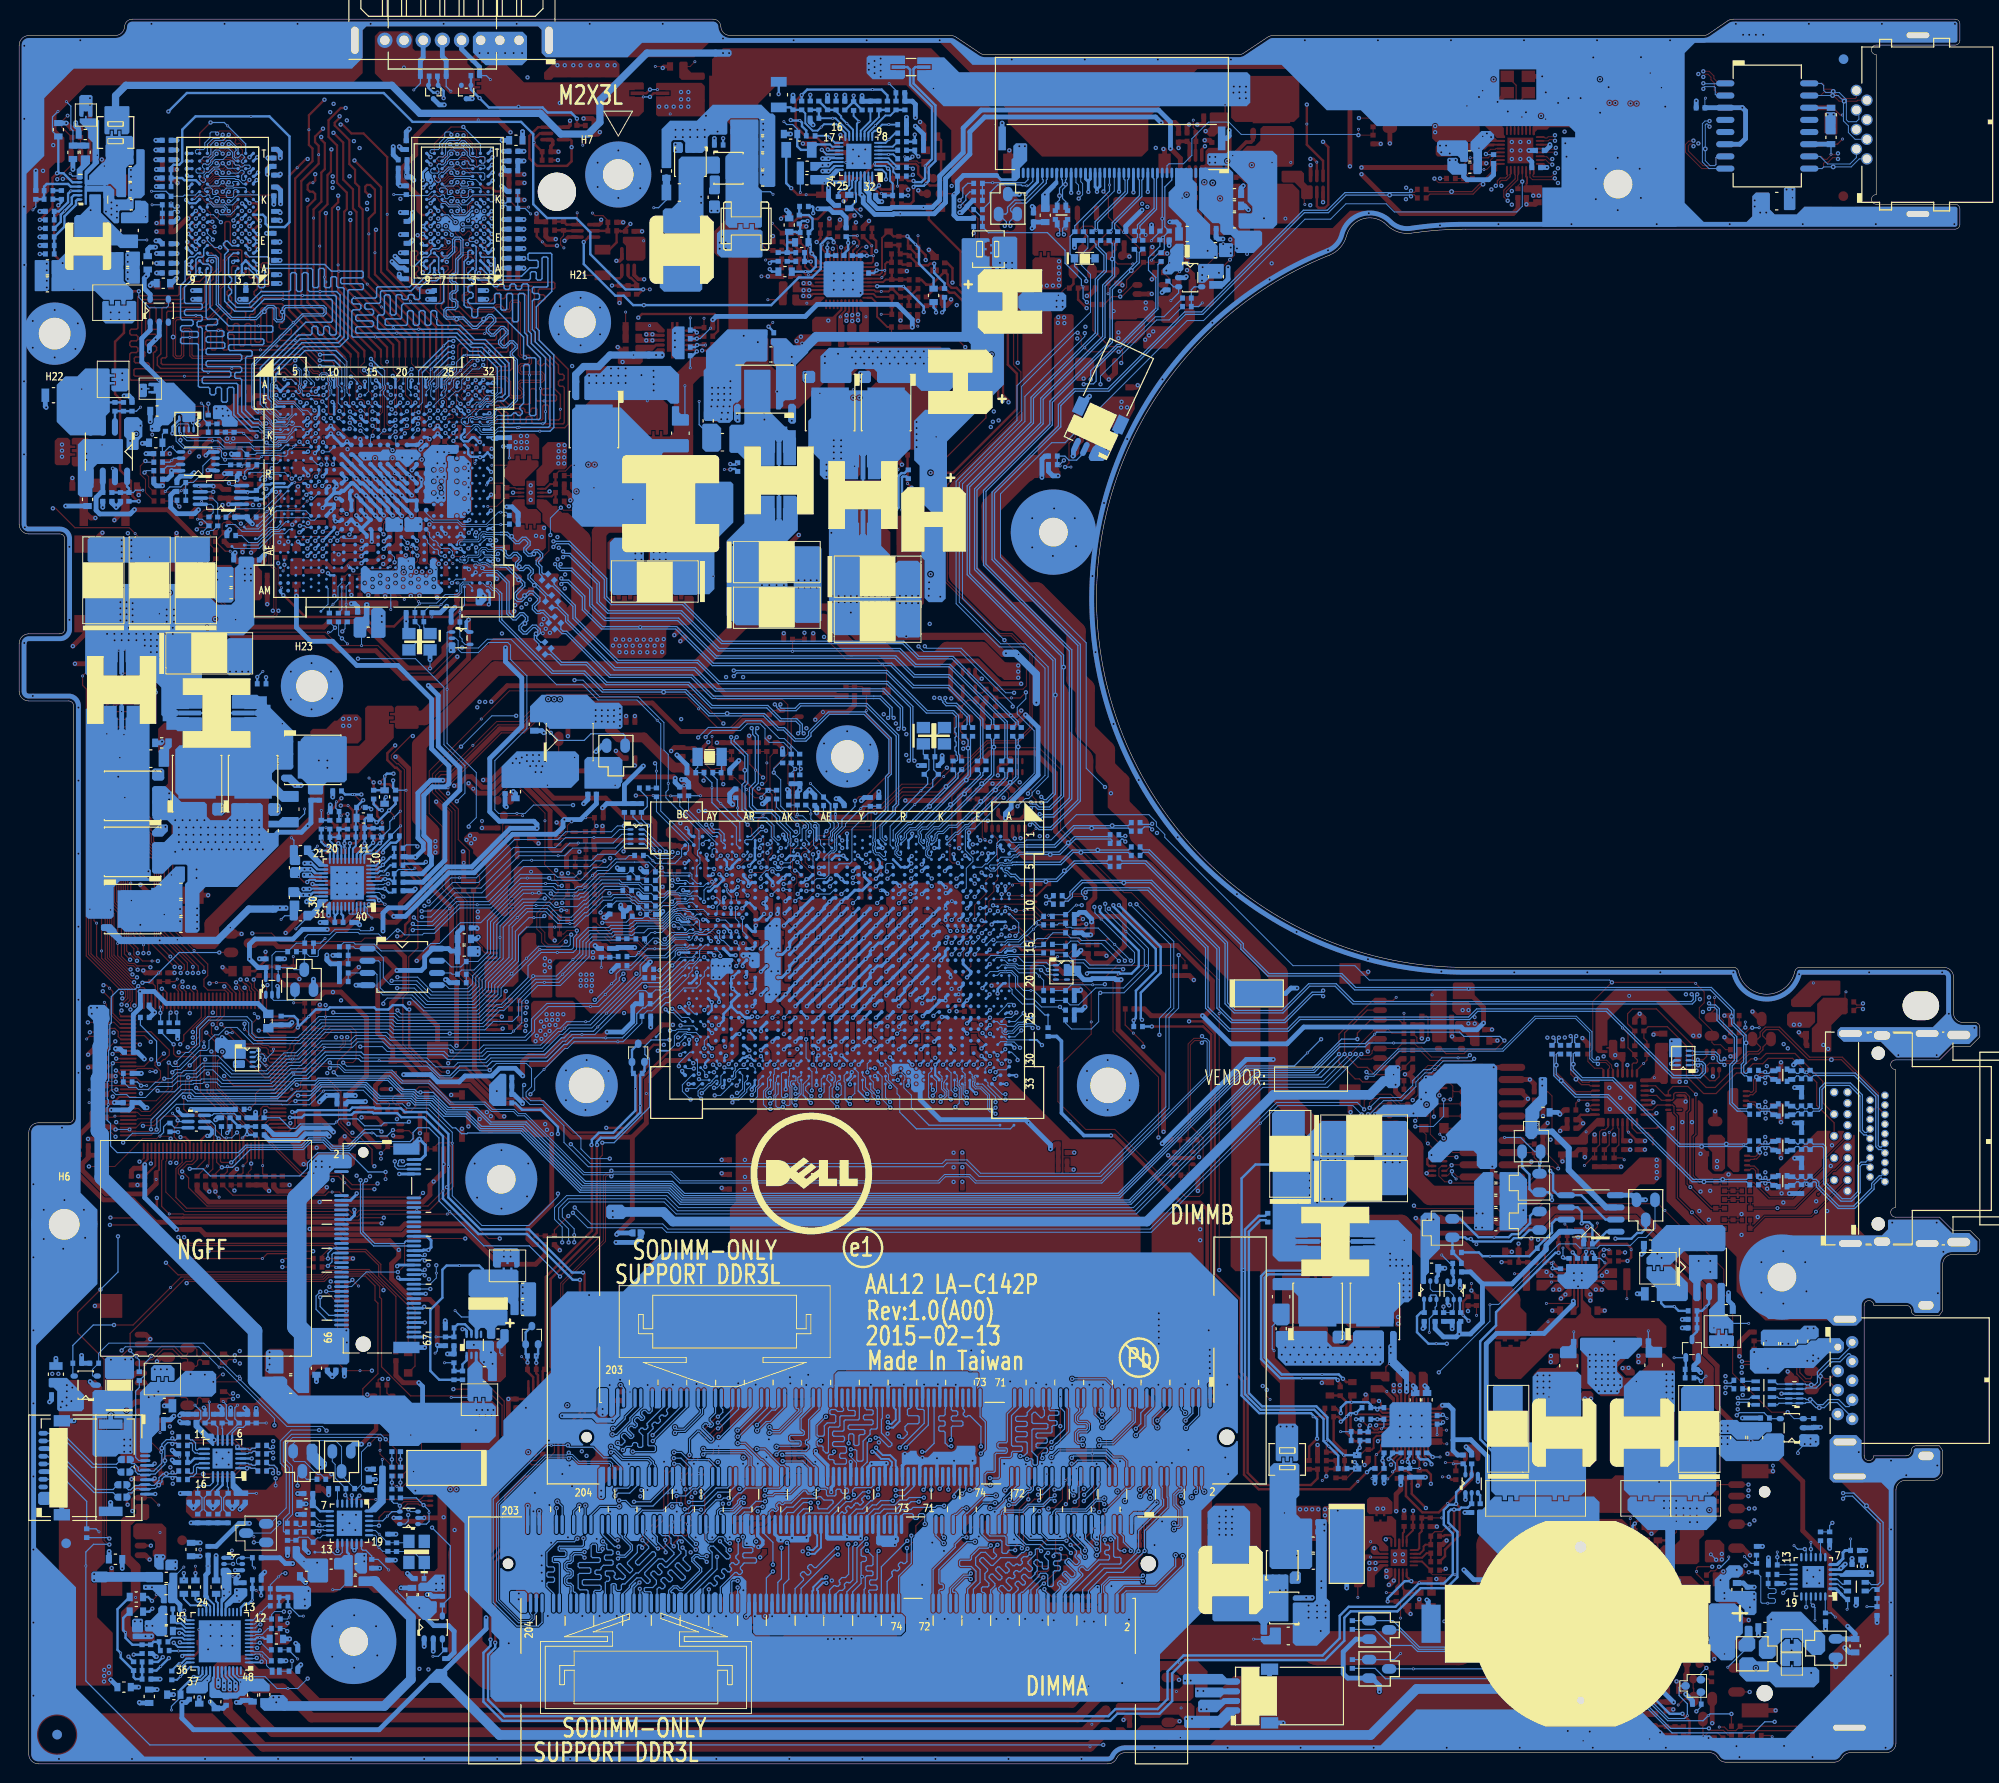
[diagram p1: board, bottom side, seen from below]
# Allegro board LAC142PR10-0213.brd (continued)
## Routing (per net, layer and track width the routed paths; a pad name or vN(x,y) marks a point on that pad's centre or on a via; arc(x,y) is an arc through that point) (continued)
+3VALW_EC: length 159.5
  TOP w0.203: UE1.125 190.35,62.39 CE3.1 ; v2(191.93,80.56) 191.65,80.56 191.55,80.46 UE1.33 ; UE1.22 191.94,73.96 v2(191.49,73.51) ; v2(191.22,68.43) 191.54,68.76 UE1.9
  TOP w0.381: U62.5 167.25,67.4 168.46,67.4 168.5,67.44 168.82,67.44 v2(168.83,67.43) ; U61.5 147.45,95.87 148.07,95.25 ; U63.5 v2(165.77,70.37)
  TOP w0.508: 148.07,95.25 148.82,95.25 149.16,95.59 149.16,99.37 152.32,102.53 153.65,102.53 154.94,101.24 156.72,101.24 v4(157.18,101.7) 157.66,102.19 v2(157.66,102.27) ; RE64.1 198.25,65.61 196.96,66.9 196.96,67.86 196.62,68.2 v2(194.94,68.2) ; CE3.1 v2(192.13,61.29)
  IN1 w0.508: v2(191.22,68.43) 191.22,69.29 190.94,69.57 190.94,72.36 191.49,72.92 v2(191.49,73.51) ; v2(168.83,67.43) 167.9,68.36 167.9,68.59 166.12,70.37 v2(165.77,70.37) 164.87,71.27 163.79,71.27 161.97,73.09 161.97,76.71 159.63,79.04 159.63,81.41 157.91,83.14 157.91,85.84 157.41,86.33 157.41,89.92 155.29,92.04 155.29,97.53 157.51,99.75 157.51,102.03 157.66,102.19 v2(157.66,102.27)
  IN2 w0.508: v2(168.83,67.43) 168.87,67.46 170.55,67.46 171.1,66.92 171.1,65.73 173.22,63.61 173.81,63.61 v2(174.87,62.55) 175.44,62.55 177.01,60.99 177.01,59.64 179.91,56.74 190.34,56.74 195.08,61.49 195.08,68.06 v2(194.94,68.2) ; v2(191.22,68.43) 192.58,67.06 192.58,61.74 v2(192.13,61.29)
  BOTTOM w0.508: v2(194.94,68.2) 193.1,68.2 192.77,68.53 CE13.2 191.95,68.96 191.42,68.43 v2(191.22,68.43) ; LE3.1 179.65,79.31 189.22,79.31 190.47,80.56 v2(191.93,80.56) 191.9,80.53 CE4.1 191.9,78.89 192.64,78.15 CE10.2 192.21,74.23 v2(191.49,73.51)
+3VALWP: length 33.7
  TOP w0.254: PR115.1 v2(36.76,52.45) 36.38,52.83 v1(36.38,53.62) 36.38,53.78 36.82,54.23 PC102.1 PR109.1
  IN2 w0.254: v2(27.87,29.97) 27.87,36.58 30.54,39.24 30.54,47.12 35.87,52.45 v2(36.76,52.45)
+3VGS: length 115.8
  TOP w0.102: v2(190.67,139.25) v4(190.67,138.64)
  TOP w0.381: v2(177.76,132.66) 177.5,132.66 177.16,132.32 QV1.2 ; v2(176.06,129.24) 176.96,129.24 177.16,129.44 QV1.5
  TOP w0.508: v2(182.71,131.37) 182.7,131.38 CV10.1 ; RV154.1 184.32,136.81 184.32,135.48 v2(184.87,134.93) 184.85,134.91 CV166.2 ; CV10.1 182.7,132.01 RV58.2 ; CV10.1 183.58,132.01 RV146.1 ; v2(181.24,126.38) RV93.1 182.73,127.08 RV148.1 ; v2(161.87,112.47) 160.48,112.47 157.66,115.29 v2(157.66,119.34) ; RV91.2 181.25,133.47 181.72,133.93 v2(181.81,133.93) ; v2(185.85,130.8) 186.2,130.8 186.58,130.42 RV147.1 ; v2(164.22,126.05) 164.35,125.91 LV4.1 ; RV5.1 175.49,129.82 v2(176.06,129.24) ; RV6.1 175.48,133.21 v2(175.46,133.23) ; v2(160.95,121.65) RV162.1
  IN1 w0.508: v2(185.79,136.36) 187.5,136.36 190.39,139.25 v2(190.67,139.25) ; v2(177.76,132.66) 177.76,132.21 179.29,130.68 182.03,130.68 v2(182.71,131.37) ; v2(164.22,126.05) 163.72,125.54 163.72,123.51 163.28,123.08 162.38,123.08 v2(160.95,121.65) 158.83,121.65 157.68,120.5 157.68,119.35 v2(157.66,119.34)
  IN2 w0.508: 177.26,129.68 178.12,128.82 178.12,124.53 177.18,123.6 166.22,123.6 164.22,125.6 v2(164.22,126.05)
  BOTTOM w0.381: U1.1 184.11,134.93 v2(184.87,134.93) ; v2(157.66,119.34) 157.9,119.1 157.9,118.25 157.71,118.05 UV2.5 ; UV11.1 v2(182.71,131.37)
  BOTTOM w0.508: v2(181.81,133.93) 181.81,134.36 RV71.2 ; PR1115.1 162.44,91.95 160.14,94.24 160.14,100.01 158.58,101.57 158.58,103.89 160.83,106.13 160.83,111.43 v2(161.87,112.47) ; 189.2,143.66 191.19,145.66 191.2,145.66 191.76,146.22 191.76,148.67 190.88,149.55 U74.1 ; v2(185.85,130.8) 186.25,130.39 188.08,130.39 188.74,131.05 188.74,132.32 188.35,132.71 RV72.2
+3VLP: length 313
  TOP w0.508: RE4.1 172.41,65.66 v2(172.21,65.46) ; RE49.1 v4(160.25,62.55) 160.25,61.79 v2(161.31,60.73) 161.7,60.34 161.7,59.34 162.44,58.6 v2(173.21,58.6) 184.78,58.6 185.98,59.8 RE14.2
  IN1 w0.508: v2(172.21,65.46) 172.32,65.34 172.32,62.09 173.48,60.93 173.48,58.86 v2(173.21,58.6) ; v2(41.9,54.93) 42.94,55.97 47.58,55.97 51.36,52.18 51.36,45.99 52.15,45.2 52.15,30.76 55.53,27.38 63.51,27.38 64.17,28.04 78.03,28.04 80.17,25.91 80.17,18.53 82.53,16.17 99.47,16.17 101.47,14.17 155.94,14.17 157.69,15.93 157.69,34.84 158.53,35.68 158.53,39.56 158.98,40.02 158.98,51.92 161.31,54.24 v2(161.31,60.73)
  IN2 w0.508: v2(41.9,54.93) 39.2,54.93 38.4,54.13 35.45,54.13 29.81,48.49 29.81,39.34 27.35,36.88 27.07,36.88 25.48,35.29 24.28,35.29 15.59,26.61 12.95,26.61 10.56,24.22 10.56,16.37 13.58,13.35 18.12,13.35 v2(19.64,11.82)
  BOTTOM w0.508: RE30.1 178.42,65.02 175.37,65.02 174.68,65.71 172.46,65.71 v2(172.21,65.46)
+3VS: length 1156.4
  TOP w0.254: C2498.1 151.62,38.05 151.42,38.24 U2407.1
  TOP w0.381: QX4.2 v2(27.85,71.69) ; RC7.2 106.12,111.31 U66.5 ; QX4.5 v2(27.85,73.61)
  TOP w0.457: U5.5 166.39,37.13 167.32,36.21 167.32,34.86 v2(168.84,33.34)
  TOP w0.508: v2(65.72,166.62) 65.72,172.59 64.88,173.43 R384.1 ; RX12.1 26.23,75.37 v2(26.64,75.79) ; v2(143.22,76.33) 143.62,75.92 147.46,75.92 149.52,73.86 R119.1 151.39,73.86 152.04,73.22 152.04,71.78 v2(152.01,71.75) ; R134.1 R158.1 82.47,82.22 v2(82,81.76) ; QH1.2 125.1,108.56 126.24,108.56 RH55.2 126.6,108.51 126.92,108.83 129.01,108.83 130.17,107.67 135.53,107.67 138.5,110.64 145.36,110.64 145.89,110.11 149.87,110.11 152.03,107.95 154.42,107.95 159.78,102.59 v2(160.35,102.59) ; v2(30.68,7.26) 30.68,9.31 30.55,9.43 Q6103.2 31.68,11.58 31.68,13.84 ; C944.2 149.97,23.78 C136.1 150,24.7 C945.2 150.3,25.87 v2(150.3,26.34) ; R120.2 R1161.2 103.69,102.03 103.48,102.24 v2(103,102.24) 101.58,102.24 R1160.2 ; PR1021.1 118.91,160.45 v2(118.91,161.05) ; RH44.1 149.66,53.11 150.67,52.11 154.5,52.11 157.98,55.59 164.15,55.59 164.55,55.18 170.46,55.18 171.07,55.79 v2(174.24,55.79) ; v2(100.02,112.65) 102.16,112.65 104.55,115.03 106.71,115.03 107.37,114.36 107.37,112.09 RC7.2 ; R690.1 141.75,37.88 C140.1 142.61,37.78 142.61,35.86 v2(142.65,35.81) ; RX16.2 86.37,158.17 v2(86.33,158.2) ; v2(64.08,38.51) 64,38.44 64,38.05 PR511.1 ; R2448.1 151.24,32.31 v2(151.44,32.51) 153.51,34.58 v2(153.51,38.05) C2498.1 ; R16.1 v2(81.58,59.76) ; R938.1 146.79,133.1 v2(146.41,132.71) ; v2(172.41,87.03) 170.42,87.03 168.99,88.46 166.92,88.46 166.25,87.78 165.22,87.78 164.79,88.21 164.79,89.69 v2(163.23,91.25) ; R17.1 84.92,65.09 v2(85.3,64.71) ; v2(138.7,83.63) 139.63,84.56 140.57,84.56 141.1,85.09 143.14,85.09 143.39,85.35 v2(144.47,85.35) ; PR505.1 58.48,29.17 v2(58.63,29.02) ; v2(165.47,25.65) 165.11,25.29 162.66,25.29 v2(162.3,25.65) 160.33,25.65 v2(160.27,25.72) ; RL33.1 v2(64.51,166.5) ; RE68.2 187.97,121.03 186.87,119.94 184.64,119.94 v2(184.11,119.41) 182.17,117.47 172.85,117.47 171.7,116.33 171.37,116.1 167.34,116.1 164.47,113.23 161.08,113.23 v2(158.84,115.47) ; RE32.1 RH43.1 196.77,74.55 v2(197.36,73.96) ; PR302.1 v2(132.19,150.62) ; RL37.2 48.19,162.19 48.69,161.7 60.41,161.7 v2(64.51,165.8) ; PR1070.1 111.36,149.86 v2(111.37,149.85)
  TOP w2.032: 97.28,136.1 97.28,137.16 95.56,138.87 95.56,148.95 ; 89.78,102.49 91.23,103.94 91.23,105.71 93.34,107.82 93.34,112.17 94.29,113.12 94.29,118.12 98.39,122.23 99.58,122.23 103.14,125.79 103.14,131.16 99.57,134.72 99.43,134.72 ; 73.21,77.22 73.21,82.42 87.69,96.9 87.69,97.93 89.78,100.02 ; 73.21,71.88 73.21,69.98 69.31,66.08 60.9,66.08 59.06,64.24 59.06,61.01 57.33,59.28 46.59,59.28 45.42,60.45 36.89,60.45 36,61.34
  IN1 w0.508: v2(100.17,102.37) 93.29,102.37 92.14,101.23 v2(90.65,101.23) ; v2(192.33,138.72) 192.33,141.88 191.78,142.44 v2(191.78,143.4) 191.78,152.5 191.37,152.91 191.37,153.86 191.51,154 191.51,154.43 191.31,154.64 v2(191.31,155.14) 192.03,155.14 193.29,153.89 198.96,153.89 200.78,155.7 200.78,158.53 v2(202.39,160.15) ; v2(150.3,26.34) 150.3,27.37 151.44,28.51 v2(151.44,32.51) 151.44,34.29 149.43,36.3 v2(147.9,36.3) ; v2(179.25,10.67) 179.51,10.41 180.46,10.41 181.1,11.05 185.73,11.05 186.56,10.22 187.27,10.22 v2(187.36,10.13) ; v2(98.88,160.16) 100.03,160.16 103.69,163.82 106.51,163.82 v2(107.27,164.58) ; v2(178.43,42.93) 174.72,46.63 174.72,53.45 174.21,53.96 174.21,55.77 v2(174.24,55.79) 174.21,55.82 174.21,62.28 174.29,62.36 174.29,64.34 170.62,68.01 169.5,68.01 v2(168.43,69.08) 168.43,69.44 166,71.88 v2(164.43,71.88) 162.58,73.74 162.58,77.15 160.9,78.83 160.9,81.98 158.51,84.37 158.51,86.09 158.02,86.59 158.02,90.17 155.9,92.29 155.9,96.38 157.02,97.5 157.02,98.39 158.21,99.59 158.21,101.88 159.15,102.82 160.12,102.82 v2(160.35,102.59) ; v2(158.84,115.47) 158.54,115.77 157.39,115.77 154.64,118.52 151.56,118.52 149.73,120.35 147.29,120.35 145.68,121.96 145.68,130.81 146.41,131.55 v2(146.41,132.71) ; v2(163.23,94.58) v2(163.23,91.25) ; v2(64.08,38.51) 65.38,37.21 74.8,37.21 77.51,39.93 77.51,48.76 80.24,51.49 80.24,58.43 v2(81.58,59.76)
  IN1 w1.016: 31.3,75.44 31.3,76.2 34.73,79.63 51.49,79.63 52.51,78.61
  IN1 w2.54: 160.58,16.51 160.58,14.54 156.05,10.01 98,10.01 95.71,12.29 59.83,12.29 55.18,16.94 35.47,16.94 34.53,16 32.99,16
  IN1 w3.048: 30.28,61.85 31.24,60.9 31.24,51.45 22.88,43.09 22.88,33 26.01,29.88 26.01,25.49 29.9,21.59 29.9,17.4
  IN2 w0.508: v2(181.98,72.96) 181.98,77.9 179.5,80.39 179.5,82.92 v2(180.52,83.95) ; v2(81.58,59.76) 83.96,62.14 84.96,62.14 85.8,62.98 85.8,63.86 85.3,64.36 v2(85.3,64.71) ; 118.01,160.15 116.78,158.92 116.78,156.38 116.77,156.36 116.77,153.89 114.89,152.01 112.68,152.01 111.37,150.7 v2(111.37,149.85) ; 118.01,160.15 111.69,160.15 v2(107.27,164.58) ; 118.01,160.15 v2(118.91,161.05) ; v2(188.83,35.19) 189.01,35.19 190.15,36.33 190.15,37.52 188.5,39.16 188.5,52.71 196.64,60.84 196.64,73.25 v2(197.36,73.96) ; v2(103,102.24) 102.96,102.28 100.27,102.28 v2(100.17,102.37) ; v2(192.33,138.72) 192.33,134.37 191.38,133.41 191.38,127.6 184.11,120.32 v2(184.11,119.41) ; v2(143.22,76.33) 143.26,76.37 143.26,80.21 143.52,80.47 143.52,85.03 143.84,85.35 v2(144.47,85.35) ; v2(58.63,29.02) 58.63,29.4 59.71,30.48 62.28,30.48 62.99,31.19 62.99,32.55 61.92,33.62 61.92,34.05 62.35,34.48 65.14,34.48 65.84,35.18 65.84,36.7 64.08,38.47 v2(64.08,38.51) ; v2(150.3,26.34) 150.3,26.07 150.65,25.72 v2(160.27,25.72) ; v2(100.02,112.65) 99.99,112.67 99.09,112.67 90.65,104.23 v2(90.65,101.23) ; v2(158.84,115.47) 160.34,113.97 160.34,102.59 v2(160.35,102.59) ; v2(73.72,73.47) v2(82,81.76) ; v2(168.84,33.34) 167.02,35.15 155.39,35.15 153.51,37.04 v2(153.51,38.05)
  IN2 w0.762: 28.06,15.05 25.3,15.05 24.42,15.94 23.55,15.94 21.67,17.82 21.67,19.2 19.72,21.15 16.31,21.15 14.79,19.62 11.72,19.62 v2(11.45,19.89)
  BOTTOM w0.203: v2(179.25,10.67) 179.35,10.58 UA1.1 ; UA1.36 187.07,10.58 187.36,10.29 v2(187.36,10.13)
  BOTTOM w0.254: 32.22,73.01 v2(32.21,73.01) ; 32.22,73.01 32.22,73.01 31.86,73.37 RP63.7 ; 32.22,73.01 32.08,72.87 RP63.8 ; PR1407.1 v2(202.39,160.15)
  BOTTOM w0.356: JDIMM2.199 142.1,36.37 v2(142.65,35.81) ; JDIMM1.199 v2(150.3,26.34)
  BOTTOM w0.381: UE3.5 178.82,82.55 178.81,82.56 CE45.1 ; Q2505.2 v2(162.3,25.65) ; Q2505.5 v2(165.47,25.65)
  BOTTOM w0.508: v2(87.41,162.06) 89.1,160.38 R618.1 ; v2(73.72,73.47) 76.53,73.47 85.29,64.71 v2(85.3,64.71) ; v2(168.84,33.34) 169.66,33.34 169.95,33.05 Q87.2 ; v2(111.37,149.85) 111.37,150.63 112.96,152.22 121.28,152.22 122.54,150.96 131.84,150.96 v2(132.19,150.62) ; v2(188.59,31.69) 188.33,31.43 RS38.2 ; v2(183.64,37.27) 183.38,37.02 RS28.1 RS27.1 ; v2(98.88,160.16) 98.74,160.3 CX1.1 98.71,160.81 RX27.1 ; v2(160.35,102.59) 161.62,102.59 162.95,101.26 162.95,96.57 162.39,96.01 162.39,95.36 163.18,94.58 v2(163.23,94.58) 163.24,94.59 164.14,94.59 164.17,94.61 PR1119.1 ; PR1112.1 163.42,91.06 v2(163.23,91.25) ; v2(164.43,71.88) 161.64,71.88 160.89,71.13 158.64,71.13 158.03,71.74 155.24,71.74 154.44,72.54 152.8,72.54 v2(152.01,71.75) ; v2(187.8,36.33) 187.65,36.49 187.41,36.49 187.38,36.46 CS42.1 RS25.1 ; RS26.1 181.86,27.1 v2(182.31,26.64) 182.75,27.08 RS30.1 ; R925.1 144.16,85.04 v2(144.47,85.35) ; v2(147.9,36.3) 144.67,36.3 144.21,35.84 142.68,35.84 v2(142.65,35.81) ; v2(181.02,37.12) 180.71,36.82 RS33.2 RS19.1 ; R676.1 139.28,83.06 v2(138.7,83.63) ; v2(30.68,7.26) 29.98,6.57 R6110.1 ; RS20.1 183.89,27.11 v2(184.33,26.67) 184.78,27.11 RS29.1 ; v2(85.31,153.47) 85.05,153.73 RX10.1 ; RE25.1 170.25,69.06 168.45,69.06 v2(168.43,69.08) ; RS34.2 185.92,27.11 v2(186.37,26.67) 186.81,27.11 CS27.1 ; C620.2 191.14,155.31 v2(191.31,155.14) 191.5,154.95 191.5,153.87 190.88,153.26 U74.5 ; RA13.2 179.3,19.63 v2(178.94,20) ; CE45.1 179.62,83.05 v2(180.52,83.95) 180.52,85.47 179.97,86.03 175.98,86.03 174.97,87.03 v2(172.41,87.03) ; v2(96.17,134.34) 96.7,134.34 97.16,134.8 RE72.1 ; R941.1 R937.1 140.24,79.28 140.54,78.99 140.54,77.4 141.61,76.33 v2(143.22,76.33)
  vias: v2(27.41,62.87) v2(27.43,62.24) v2(28.73,15.37) v2(28.73,14.73) v2(29.27,75.95) v2(29.37,15.37) v2(29.37,14.73) v2(29.9,75.95) v2(30,15.37) v2(30,14.73) v2(30.64,15.37) v2(30.64,14.73) v2(31.29,15.35) v2(31.29,14.72) v2(33.7,61.72) v2(33.71,62.99) v2(33.71,62.36) v2(33.71,61.09) v2(53.35,78.61) v2(53.96,78.61) v2(80.55,155.12) v2(81.13,155.28) v2(81.15,154.7) v2(86.85,162.39) v2(87.39,162.71) v2(95.54,150.86) v2(95.51,150.27) v2(96.15,150.89) v2(96.18,150.29) v2(160.39,19.43) v2(160.39,18.8) v2(160.39,18.16) v2(161.05,18.8) v2(161.05,18.16) v2(178.43,42.29) v2(178.43,41.66) v2(178.63,41.1) v4(36.58,80.1)
+3VS_2168: length 7.2
  TOP w0.254: UZ1.20 37.27,65.1 CZ1.1
  TOP w0.508: CZ1.1 v2(36.46,64.97) ; R157.2 43.57,62.86 v2(43.54,62.84) ; v2(34.04,76.06) 33.94,76.16 R156.2 ; v2(37.42,62.28) RZ5.1 RZ1.1 RZ3.1
  vias: v2(38.04,73.91)
+3VS_2168_AV:
  vias: v1(41.08,65.91)
+3VS_2168_DA:
  vias: v1(33.97,71.56)
+3VS_APU: length 32.7
  TOP w0.508: C1137.1 128.11,80.47 v2(128.14,80.44) ; R119.2 149.57,72.95 147.21,75.31 v1(142.09,75.31) 139.24,75.31 137.47,77.08 v2(136.35,77.08)
  IN2 w0.508: v2(136.35,77.08) 136.33,77.08 135.74,77.66 130.74,77.66 129.79,76.71 128.95,76.71 128.44,77.22 127.25,77.22 126.87,77.6 126.87,78.93 128.14,80.21 v2(128.14,80.44)
  BOTTOM w0.305: v2(128.14,80.44) 128.12,80.46 128.12,80.46 UC1.AP21 UC1.AP19
+3VS_CAM:
  vias: v4(97.54,163.68)
+3VS_TOUCH: length 140.3
  TOP w0.102: v2(52.7,77.2) v4(52.7,77.88)
  TOP w0.508: JTP.1 60.71,72.61 v2(60.71,72.61) 60.71,73.24 60.42,73.53 R19.2 ; RE341.1 59.15,77.08 RE340.1 v2(58.21,75.65) ; R18.2 59.16,70.08 59.7,69.55 60.41,69.55 60.95,70.09 v2(60.95,70.83)
  IN2 w1.016: 158.38,29.18 156.98,29.18 150.31,35.85 150.31,39.69 143.15,46.85 143.15,55.36 ; 171.65,31.75 167.51,31.75 166.29,30.53 162.13,30.53 161.26,29.65
  BOTTOM w1.016: 61.79,71.21 62.2,71.21 63.63,69.77 73.68,69.77 86.9,56.56 136.34,56.56 137.34,57.56 141.46,57.56
  vias: v2(53.36,77.22) v2(142.63,57.66) v2(142.61,57.04) v2(158.93,28.64) v2(159.57,28.64) v2(172.66,31.34) v2(173.12,30.96)
+3VS_WLAN_NGFF: length 21.6
  TOP w0.508: v2(170.36,43.95) 170.41,44 v4(170.41,45.2) v4(170.41,47.18) RM8.1
  BOTTOM w2.032: 174.68,44.7 175.58,45.61 175.58,58.94 173.77,60.76
  vias: v2(172.98,62.84) v2(172.98,62.26) v2(173.59,62.86) v2(173.59,62.26) v4(172.14,62.26)
+5V_HDD: length 42.3
  TOP w0.102: v2(184.3,39.84) 183.52,40.61 v4(183.29,40.61) ; v2(184.3,39.84) 181.86,39.84 v4(181.51,40.18) ; v2(184.3,39.84) 184.43,39.84 v4(185.18,40.59)
  IN1 w0.508: v2(200.46,40.68) v2(201.1,40.68) 201.99,39.79 201.99,27.89 201.45,27.36 v2(201.17,27.36)
  IN2 w0.508: v2(201.17,27.94) 201.99,28.75 201.99,39.79 v2(201.1,40.68)
  IN2 w1.524: 199.21,40.98 192.45,40.98 191.12,39.66
  vias: v2(190.04,38.84) v2(190.44,38.39) v2(191.04,38.24) v4(186.67,40.64)
+5V_PVDD:
  vias: v1(181.45,8.53)
+5V_USB_PWR1: length 1.2
  BOTTOM w0.102: v4(18.98,32.41) 18.98,32.64 v2(18.27,33.35)
  vias: v2(16.85,42.28) v2(17.11,33.59) v2(17.39,42.61) v2(17.41,42.01) v2(17.66,33.92) v2(17.67,33.32) v2(18,42.04) v4(22.12,41.22) v4(23.54,42.95)
+5V_USB_PWR2: length 2.6
  TOP w0.102: JIO1.13 190.98,33.76 v4(189.73,32.51)
  vias: v2(192.96,33.82) v2(192.96,33.19) v2(192.96,32.55) v2(193.59,33.82) v2(193.59,33.19) v2(193.59,32.55)
+5VA: length 5.3
  BOTTOM w0.102: RA1111.2 188.45,19.44 v1(187.37,20.52)
  BOTTOM w0.203: UA1.26 187.15,14.58 187.78,15.2 187.78,16.07
  BOTTOM w0.508: CA51.1 188.27,17.07 187.78,16.58 187.78,16.07
+5VALW: length 627.6
  TOP w0.203: v2(34.14,22.16) 34.09,22.11 U2301.4 ; v2(149.22,132.71) 149.35,132.59 U15.4
  TOP w0.508: v2(165.47,88.39) 166.14,89.07 169.31,89.07 170.52,87.86 171.8,87.86 172.27,88.33 v2(172.27,88.52) 174.9,88.52 v2(176.75,86.66) ; v2(58.49,17.17) 58.48,17.16 PR210.2 PR206.1 ; v2(173.95,91.76) 173.41,91.23 173.41,91.06 173.28,90.93 PC1111.1 ; v2(159.17,102.01) 158.8,102.01 157.86,102.96 157.35,102.96 156.24,101.85 155.19,101.85 153.9,103.14 152.07,103.14 147.67,98.74 v2(147.67,98.49) ; v2(152.9,120.22) 153.03,120.09 158.03,120.09 159.61,118.52 159.61,117.04 160.23,116.42 160.23,115.73 161.66,114.3 164.03,114.3 168.87,119.14 172.21,119.14 172.78,118.57 181.74,118.57 185.64,122.47 185.64,127.42 189.03,130.81 v2(192.53,130.81) ; PR8.1 89.67,154.43 v2(89.45,154.22) ; v2(31.95,6.43) PC1202.1 32.75,6.48 PU400.6
  IN1 w0.508: v2(43.17,22.25) 42.26,21.34 39.93,21.34 39.11,22.16 v2(34.14,22.16) ; v2(58.49,17.17) 57.51,18.15 57,18.15 56.24,18.91 52.99,18.91 49.65,22.25 v2(45.84,22.25) ; v2(56.06,37.4) 54.31,39.15 v2(54.31,44.83) ; v2(172.27,88.52) 172.27,90.09 v2(173.95,91.76) ; v2(141.6,146.22) 142.99,146.22 143.82,145.39 145.34,145.39 149.22,141.52 v2(149.22,132.71) 148.62,132.12 148.62,130.69 146.91,128.97 146.91,122.45 147.79,121.56 150.23,121.56 151.83,119.96 152.65,119.96 v2(152.9,120.22) ; v2(154.18,117.89) 154.04,117.89 153.46,117.31 149.01,117.31 144.29,122.03 137.45,122.03 136.21,123.27 136.21,125.03 135.15,126.09 130.31,126.09 128.82,127.58 112.38,127.58 111.75,128.21 111.75,131.99 111.28,132.47 107.17,132.47 104.26,135.38 104.26,145.83 v2(103.09,147)
  IN1 w1.524: v2(186.62,68.26) 186.63,68.25 186.63,63.59 185.67,62.63 185.67,61.07 186.26,60.47 186.26,55.35 186.25,55.34 186.25,52.63 198.37,40.52 198.37,40.32
  IN1 w2.032: 39.81,24.64 39.05,24.64 30.45,33.24 28.59,33.24
  IN2 w0.508: v2(186.62,68.26) 181.85,68.26 174.43,75.68 174.43,83.31 176.75,85.64 v2(176.75,86.66) ; v2(89.45,154.22) 89.97,154.22 94.38,149.81 94.94,149.81 95.64,149.11 100.91,149.11 103.02,147 v2(103.09,147) ; v2(152.9,120.22) 154.18,118.94 v2(154.18,117.89) 154.26,117.89 159.04,113.12 159.04,102.15 v2(159.17,102.01)
  IN2 w4.064: 44.34,19.35 44.34,18 54.81,7.53 v2(62.64,7.53) 69.23,7.53 72.26,10.55 80.1,10.55 80.93,11.38 90.22,11.38 98.3,3.3 193.34,3.3 194.71,4.67
  BOTTOM w0.203: PU1100.26 173.86,91.68 v2(173.95,91.76)
  BOTTOM w0.508: R2635.2 56.83,45.39 55.96,44.53 54.62,44.53 v2(54.31,44.83) ; R917.2 53.14,51.31 51.89,50.06 ; 51.89,50.06 51.89,46.08 53.14,44.83 v2(54.31,44.83) ; 51.89,50.06 48.81,50.06 45.26,53.61 R54.2 45.26,54.1 43.86,55.5 U2.8 42.28,55.5 42.26,55.52 41.56,55.52 41.29,55.26 41.29,54.56 41.33,54.52 R53.2 ; 54.96,33.76 54.91,33.81 53.1,33.81 51.36,32.07 51.36,26.9 ; 54.96,33.76 54.96,32.69 54.48,32.21 RZ10.2 ; 54.96,33.76 54.96,36.92 55.44,37.4 v2(56.06,37.4) ; v2(186.62,68.26) 186.61,68.25 182.01,68.25 RE504.2 ; R918.2 54.31,46 v2(54.31,44.83) ; v2(34.14,22.16) 34.85,22.16 35.62,21.4 35.62,10.1 v2(31.95,6.43) ; R1674.1 144.33,100.14 145.98,98.49 v2(147.67,98.49) 147.81,98.35 147.81,97.73 148.58,96.95 153.07,96.95 157.08,92.94 159.72,92.94 164.27,88.39 v2(165.47,88.39) ; v2(192.53,130.81) 192.97,130.37 196.14,130.37 196.53,130.75 196.53,132.08 196.01,132.6 PC402.1 PU1200.6 ; Q6102.3 65.09,13 66.41,11.68 66.41,9.41 65.94,8.94 Q6101.3 63.4,8.94 62.64,8.18 v2(62.64,7.53)
  vias: v2(26.32,33.99) v2(26.32,33.35) v2(26.96,33.99) v2(26.96,33.35) v2(41.2,24.64) v2(41.2,23.88) v2(41.97,24.64) v2(41.97,23.88) v2(42.75,25.03) v2(42.79,23.77) v2(43.17,23.01) v2(43.21,24.47) v2(43.68,25.06) v2(43.68,23.77) v2(44.06,23.01) v2(44.06,22.25) v2(44.1,24.47) v2(44.57,23.77) v2(44.61,25.03) v2(44.99,24.47) v2(44.95,23.01) v2(44.95,22.25) v2(45.45,25.04) v2(45.46,23.77) v2(45.88,24.47) v2(45.84,23.01) v2(195.18,10.15) v2(195.18,9.47) v2(195.67,9.79) v2(195.69,9.17) v2(195.7,8.59) v2(199,39.24) v2(199.1,37.83) v2(199.57,39.5) v2(199.57,38.86) v2(199.6,38.21) v2(199.61,37.38) v2(200.06,37.78) v2(200.21,37.2) v4(37.99,23.36) v4(41.9,19.94) v4(45.21,20.19)
+5VALWP: length 49.7
  TOP w0.203: PU100.14 42.32,48.35 v2(42.41,48.26)
  TOP w0.254: v2(43.95,53.3) 43.96,53.31 PC108.2 PR104.2
  BOTTOM w0.254: v2(43.95,53.3) 44.28,53.3 50.47,47.11 50.47,45.73 52.13,44.07 52.13,33.85 50.86,32.58
  BOTTOM w0.508: v2(42.41,48.26) 42.41,47.94 45.46,44.89 v1(46.87,44.89) 50.41,44.89 51.49,43.81 51.49,33.97 50.79,33.27
+5VS: length 485.1
  TOP w0.203: v2(62.79,33.66) 62.63,33.82 PU500.12 ; v2(115.09,156.4) 115.37,156.11 PU1001.12
  TOP w0.508: v2(196.6,129.95) 197.08,129.95 FE1.2 197.81,133.02 CE56.1 197.48,133.35 RE59.1 ; RE60.1 191.4,88.63 190.86,89.17 190.86,90.65 v2(191.9,91.69) ; Q20.2 v2(61.55,169.01) ; Q6104.3 v2(27.92,4.24) ; RE73.2 195.36,113.85 v2(194.62,113.11)
  TOP w1.524: 161.51,97.36 162.81,98.66 162.81,106.26 154.84,114.24 133.91,114.24 128.96,119.19 120.64,119.19 117.72,116.27 114.48,116.27 113.47,115.25 108.77,115.25 107.75,116.27 104.13,116.27 101.97,114.11 101.53,114.11
  IN1 w0.508: v2(120.14,150.53) 119.79,150.53 116.22,154.1 116.22,155.73 115.55,156.4 v2(115.09,156.4) ; v2(85.97,168.54) 85.93,168.54 82.77,171.7 78.5,171.7 77.5,170.7 63.24,170.7 v2(61.55,169.01) 61.55,166.42 64.18,163.79 72.98,163.79 75.76,161.01 75.76,157.76 81.02,152.5 85.3,152.5 85.96,151.84 85.96,150.18 ; v2(62.79,33.66) 62.03,34.42 62.03,36.83 61.46,37.4 58.54,37.4 57.91,38.04 v2(57.91,39.43)
  IN1 w1.016: 20.26,77.14 22,77.14 24,75.14 24,61.82 26.17,59.65 26.17,50.85 24.95,49.63 24.95,48.18 22.36,45.59 20.33,45.59 19.13,44.4 19.13,30.68 10.53,22.08 10.53,19.19 11.68,18.05 11.68,9.65 18.52,2.81 20.58,2.81
  IN1 w1.524: 90.34,140.5 90.41,140.5 92.26,138.65 92.26,134.75 94.98,132.03 98.54,132.03 101.02,129.54 101.02,120.37 99.85,119.2 99.85,115.63 99.87,115.62
  IN2 w0.508: v2(39.26,13.8) 39.26,15.06 36.67,17.65 36.67,22.99 39.41,25.73 50.01,25.73 51.7,24.03 54.09,24.03 58.06,28 60.37,28 61.25,28.88 61.25,29.19 61.92,29.86 62.52,29.86 63.6,30.94 63.6,32.85 v2(62.79,33.66) ; v2(170.97,79.63) 170.97,84.51 174.35,87.88 183.79,87.88 185.85,89.94 190.15,89.94 v2(191.9,91.69) 192.42,92.21 194.32,92.21 195.6,93.5 195.6,112.13 v2(194.62,113.11) 195.6,114.08 195.6,116.34 196.65,117.39 196.65,129.9 v2(196.6,129.95) ; v2(115.09,156.4) 115.09,156.41 113.12,158.37 111.09,158.37 110.22,159.25 110.22,160.76 101.99,168.99 101.13,168.99 100.61,169.51 86.85,169.51 85.97,168.63 v2(85.97,168.54)
  BOTTOM w0.508: v2(57.91,39.43) 57.67,39.2 PC503.1 ; RE26.1 169.52,69.72 v2(169.49,69.69)
  BOTTOM w1.016: 167.76,19.05 167.38,19.05 167.38,18.94 163.68,15.24 163.68,8.8 166.45,6.03 176.85,6.03 ; 190.94,19.49 195.66,19.49
  vias: v2(18.8,77.1) v2(19.4,77.09) v2(36.72,13.8) v2(36.72,13.17) v2(36.72,12.53) v2(37.36,13.8) v2(37.36,13.17) v2(37.36,12.53) v2(37.99,13.8) v2(37.99,13.17) v2(37.99,12.53) v2(38.63,13.8) v2(38.63,13.17) v2(38.63,12.53) v2(39.26,13.17) v2(39.26,12.53) v2(86.24,149.4) v2(86.67,148.98) v2(87.08,148.54) v2(88.97,141.48) v2(89.54,142.06) v2(89.59,141.47) v2(100.32,114.55) v2(100.32,113.92) v2(100.32,113.28) v2(157.02,96.47) v2(157.4,96.01) v2(157.51,96.82) v2(157.88,96.37) v2(161.12,96.23) v2(161.12,95.65) v2(161.12,95.06) v2(177.45,6.95) v2(177.73,6.41) v2(178.03,6.93) v2(189.13,41.15) v2(189.77,41.15) v2(190.4,41.15) v2(196.73,19.79) v2(196.73,19.16) v4(34.92,13.27)
+5VS_KBL: length 19.3
  TOP w0.102: v4(194.79,135.1) RE59.2
  TOP w0.305: v2(190.81,121.95) 191.19,121.57 JKBBL.1
  TOP w0.508: RE59.2 193.8,133.35 CE57.1 193.67,132.38 193.46,132.18 FE1.1 193.66,130.68 v2(194.62,129.72)
  IN2 w0.508: v2(190.81,121.95) 190.81,123.89 191.57,124.65 194.01,124.65 194.62,125.26 v2(194.62,129.72)
+5VS_ODD:
  vias: v4(150.34,90.86) v4(151.15,93.05) v4(153.18,82.41)
+17.4V_BATT+: length 60.4
  TOP w0.508: PQ710.3 110.17,168.48 PR780.2 110.17,170.85 v2(110.56,171.25)
  IN1 w0.508: v2(110.56,171.25) 110.28,171.53 110.28,172.09 110.66,172.47 117.49,172.47 118.18,171.78 118.18,169.37 118.64,168.91 118.64,165.2 119.47,164.36 v2(120.11,164.36)
  IN2 w0.508: v2(120.11,164.36) 120.83,163.64 124.39,163.64 127.35,160.68 134.44,160.68 137.43,163.68 137.43,167.28 140.6,170.45 142.21,170.45 144.99,173.23 v2(148.14,173.23)
  BOTTOM w0.508: PR745.2 119.48,162.55 120.11,163.18 v2(120.11,164.36)
  vias: v4(152.46,172.85)
+17.4V_BATT++:
  vias: v4(164.41,176.94)
+19V_ADPIN:
  vias: v4(85.3,161.16) v4(85.22,159.19) v4(87.03,159.46)
+19V_VIN: length 81.1
  TOP w0.102: PD704.2 v4(116.63,163.66)
  TOP w0.254: v2(140.79,160.62) 141.28,160.12 PR7.2 141.8,159.84 141.85,159.89 PR31.2 142.22,158.69 142.98,157.92 PR5.1
  TOP w0.508: v2(80.87,169.34) 80.36,169.34 PR729.1 ; v2(118.53,162.99) 118.34,163.18 PD704.2
  IN1 w0.508: v2(79.27,163.27) 79.17,163.37 79.17,168.63 79.86,169.33 80.85,169.33 v2(80.87,169.34)
  IN2 w0.254: v2(118.53,162.99) 118.68,163.14 121.84,163.14 124.58,160.4 126.41,160.4 126.74,160.07 134.69,160.07 135.23,160.62 v2(140.79,160.62)
  IN2 w0.508: v2(118.53,162.99) 116.29,162.99 115.59,162.29 113.3,162.29 113.14,162.13 110.58,162.13 103.11,169.6 101.38,169.6 100.86,170.12 86.6,170.12 85.94,169.46 84.69,169.46 84.66,169.43 83.05,169.43 82.96,169.34 v2(80.87,169.34)
  vias: v4(72.45,161.18) v4(74.68,161.2)
+19VB: length 362.7
  TOP w0.508: RS6.2 153.56,97.57 v2(150.53,97.57) ; PR34.2 177.73,82.07 176.9,81.24 171.08,81.24 169.82,82.5 169.71,82.5 v2(169.12,83.09)
  TOP w1.524: 72.26,36.39 72.26,39.99 74.29,42.03 74.29,52.7 74.26,52.73 ; 151.8,115.86 147.16,115.86 144.05,118.97 144.05,128.42 143.31,129.16 136.45,129.16 135.31,130.3 135.31,136.08 ; 163.69,109.09 162.28,109.09 155.41,115.96 154.83,115.96
  TOP w2.032: PL102.1 48.95,48.39 54.16,53.59 57.71,53.59 60.38,56.26 67.75,56.26 69.23,54.78 ; 135.25,138.18 135.25,144.34 133.85,145.73 132.01,145.73 129.55,148.2 129.55,157.4 128.71,158.24
  TOP w3.048: 98.71,151.42 98.35,151.07 98.35,140.39 102.21,136.54 106.04,132.71 106.04,124.17 101.53,119.66 100.29,119.66 97.08,116.46 97.08,111.98 96.56,111.46 96.56,107.18 94.01,104.62 94.01,98.43 88.35,92.77 87.3,92.77 76.57,82.05 76.57,55.18
  IN2 w0.508: v2(166.59,86.86) 166.59,85.62 v2(169.12,83.09)
  BOTTOM w0.508: v2(153.82,116.41) 153.82,114.97 152.11,113.27 152.11,108.2 155.45,104.86 155.45,99.3 154.46,98.31 150.84,98.31 150.53,97.99 v2(150.53,97.57) 153.31,97.57 157.33,93.55 159.97,93.55 164.24,89.28 166.05,89.28 166.59,88.73 v2(166.59,86.86)
  BOTTOM w0.762: 131.88,178.44 139.06,178.44 143.96,173.53 143.96,171.21 145.18,169.99 148.04,169.99 150.2,172.15 162.74,172.15 165.66,175.07 193.41,175.07 194.49,173.99 PL1401.1
  vias: v2(71.68,35.18) v2(72.32,35.18) v2(72.95,35.18) v2(79.76,167.6) v2(79.77,167) v2(80.35,167.6) v2(80.36,167) v2(100.96,156.55) v2(100.96,155.92) v2(101.59,156.55) v2(101.59,155.92) v2(102.23,156.55) v2(102.23,155.92) v2(114.67,177.86) v2(114.67,177.23) v2(114.67,176.59) v2(114.67,175.96) v2(115.31,177.61) v2(115.31,176.97) v2(115.31,176.34) v2(115.91,177.33) v2(115.91,176.7) v2(130.49,178.44) v2(130.84,158.67) v2(130.83,158.03) v2(131.12,178.44) v2(131.13,159.28) v2(131.46,158.66) v2(131.46,158.03) v4(76.83,51.5)
+19VB_1.35V: length 19.1
  TOP w0.254: PR208.1 55.87,20.19 v2(55.72,20.35)
  IN2 w0.254: v2(55.72,20.35) 59.89,24.51 66.99,24.51 67.82,23.67 69.28,23.67 v2(71.24,21.72)
  vias: v1(72.55,26.16)
+19VB_1.35VGPU:
  vias: v1(195.66,166.65)
+19VB_3/5V:
  vias: v1(45.05,46.1)
+19VB_APU: length 17.7
  BOTTOM w1.016: 122.87,147.38 121.41,148.84 105.78,148.84
  vias: v1(108.88,138.4) v2(110.93,139.95) v2(110.93,139.32) v2(110.93,138.68) v2(110.93,138.05) v2(110.93,137.34) v2(123.95,146.75) v2(123.95,146.05)
+19VB_GPU: length 21.6
  TOP w1.524: 173.48,103.31 173.48,98.55 184.46,87.57 184.46,86.23
  vias: v1(188.66,92.71) v2(172.4,104.65) v2(172.4,103.89) v2(173.28,104.65) v2(187.76,89.15) v2(187.76,88.52) v2(187.76,87.88)
+19VB_VDDP_ALWP:
  vias: v1(139.02,142.16)
+V18R: length 16.9
  TOP w0.203: 190.26,61.67 189.95,61.98 UE1.124
  TOP w0.508: RE69.2 197.25,63.47 CE44.1 ; RE69.2 RE64.2 ; RE69.2 197.34,63.22 197.95,62.61 197.95,61.9 195.48,59.44 191.32,59.44 190.26,60.5 v1(190.26,60.96) 190.26,61.67
+VBUS: length 3.8
  BOTTOM w0.102: v1(171.84,18.16) 171.09,18.16 170.2,19.05 R138.2
  BOTTOM w0.254: C666.2 170.15,21.88 170.34,22.07 U69.15
+VCC_3IN1: length 13.4
  IN1 w1.016: 22.66,17.78 19.93,20.51 19.93,22.48 18.62,23.8 15.47,23.8 14.25,22.58 14.25,21.7
  vias: v2(14.04,20.82) v2(14.49,20.42) v2(23.55,17.72) v2(23.54,17.13) v2(26.65,17.82) v2(26.64,17.23) v4(23.98,16.32) v4(25.36,20.23) v4(27.06,19.16)
+VCCK_V12: length 14.6
  TOP w0.254: CZ7.1 41.64,67.69 40.57,67.69 40.54,67.72 UZ1.25 ; CZ6.1 v1(36.66,65.89) 36.77,66 UZ1.19
  TOP w0.508: CZ7.1 41.78,67.18 v2(41.4,66.8) 41.9,66.29 CZ8.1 ; v2(34.93,64.97) CZ6.1
  IN2 w0.508: v2(41.4,66.8) 36.76,66.8 v2(34.93,64.97)
+VDD_CT: length 1.6
  TOP w0.102: LV3.2 161.25,124.56 v1(161.07,124.56)
  vias: v2(162.71,129.3)
+VDD_TOUCH: length 13.2
  BOTTOM w0.305: JEDP.40 100.3,165.58 100.65,165.23 102.12,165.23 102.56,165.67
  BOTTOM w0.508: RX35.1 105.01,161.19 106.67,161.19 107.03,161.55 107.03,163.6 106.67,163.96 106.67,165.04 106.04,165.67 102.56,165.67
  vias: v2(87.01,152.41) v2(87.01,151.79) v2(99.62,168.72) v2(100.21,168.72) v4(90.35,151.52)
+VDDCI:
  vias: v1(165.39,134.58) v2(163.59,136.19) v2(164.59,136.25) v2(168.42,136.19)
+VDDCR_FCH_ALW: length 244.5
  TOP w0.508: C1108.1 C1109.1 133.66,96.58 133.93,96.32 133.93,95.06 132.94,94.07 132.94,92.67 v4(132.27,92) 131.59,91.33 131.59,90.03 131.08,89.52 130.96,89.52 ; 127.69,88.01 v2(127.69,87.44) ; 127.69,88.01 C1110.1 ; 127.69,88.01 127.69,88.77 128.83,89.92 130.56,89.92 130.96,89.52 ; 130.96,89.52 v2(130.96,89.29)
  IN1 w0.508: 132.91,89 136.02,89 138.13,86.89 143.93,86.89 148.01,82.81 148.01,81.72 150.55,79.18 150.55,77.98 150.97,77.57 150.97,76.74 151.14,76.57 151.14,76.19 151.57,75.76 151.57,75.26 150.33,74.02 150.33,68.5 150.63,68.2 150.63,65.38 147.57,62.32 147.57,59.05 148.99,57.63 148.99,38.65 152.33,35.31 152.33,20.07 149.17,16.9 82.84,16.9 80.9,18.84 80.9,26.21 78.34,28.78 63.86,28.78 63.32,28.23 55.72,28.23 52.89,31.06 52.89,45.51 52.1,46.3 52.1,52.49 47.62,56.97 v2(47.62,57.75)
  BOTTOM w0.305: UC1.AR12 128.07,86.82 UC1.AP13 127.77,87.36 v2(127.69,87.44)
+VDDD: length 1
  BOTTOM w0.102: R153.1 v1(166.67,31.75)
+VDDD_M: length 16.5
  IN1 w0.508: v2(175.5,28.19) 174.29,28.19 173.53,27.42 169.6,27.42 169.06,27.97 v2(169.06,27.97)
  IN2 w0.508: v2(174.36,22.02) 174.8,22.46 174.8,26.15 175.51,26.86 175.51,28.18 v2(175.5,28.19)
  BOTTOM w0.254: v2(169.06,27.97) 169.34,27.69 U69.2
  BOTTOM w0.508: v2(174.36,22.02) 174.8,22.46 R139.1 ; R146.2 v2(175.5,28.19)
+VDDD_M_M: length 3.2
  BOTTOM w0.254: U69.7 173.15,26.34 C836.1
  BOTTOM w0.508: R146.1 173.92,28.19 C836.1
+VDDR3:
  vias: v2(164.73,129.28)
GND: length 2388.6
  TOP w0.102: 179.6,140.96 CV51.2 ; v4(112.91,135) 112.45,135.46 v2(112.45,135.51) ; v2(156.27,97.61) v4(156.27,98.34) ; v2(126.43,155.14) v4(127.11,155.14)
  TOP w0.203: UE1.94 176.5,66.36 176.26,66.6 v2(176.26,66.83) ; v2(61.98,23.41) 61.83,23.56 61.54,23.56 61.4,23.42 PU200.1 ; v2(34.27,18.44) 34.09,18.62 U2301.11 ; UE1.24 194.33,74.75 v2(194.49,74.59) ; v2(184.92,65.49) 185.16,65.49 185.55,65.1 UE1.113 ; U15.11 v2(153.03,132.59) ; UE1.11 194.1,69.56 194.62,69.04 v2(194.62,68.97) ; UE1.35 190.75,78.7 v2(190.42,78.37)
  TOP w0.254: UV6.M9 155.52,164.77 v2(155.15,165.15) ; UV7.E8 v2(180.52,158.77) UV7.D8 ; v2(187,158.73) 186.64,158.37 UV7.D1 ; UV7.G9 180.14,160.77 v2(180.53,160.38) ; RP30.1 93.96,88.51 v2(93.57,88.11) 93.67,88.01 RP30.2 ; v2(186.92,164.37) UV7.M1 ; v2(149.28,33.72) 149.42,33.86 U2407.6 ; UV6.P1 162.44,165.97 v2(162.44,165.19) ; v2(161.63,160.37) UV6.G1 ; v2(160.83,161.97) UV6.J2 ; v2(161.64,167.58) 162.03,167.97 UV6.T1 ; v2(184.41,156.72) 184.47,156.77 UV7.B3 ; UV6.F9 155.68,159.97 v2(156.04,160.34) 156.43,160.72 UV6.G8 ; RP27.5 57.47,61.35 v2(57.71,61.59) 57.46,61.85 RP27.6 ; UZ1.14 34.32,68.72 v2(34.05,68.99) 34.29,69.22 UZ1.13 ; RP30.4 93.45,87.01 93.22,87.24 v2(93.22,87.59) 93.25,87.62 93.74,87.62 93.86,87.51 RP30.3 ; UV6.E8 v2(156.03,158.77) UV6.D8 ; v2(179.78,165.19) 180.12,164.85 UV7.M9 ; v2(33.74,67.87) 33.89,67.72 UZ1.16 ; UV6.E1 162.15,159.05 162.59,159.05 v2(162.98,159.44) ; UV6.A9 155.63,156.05 v2(155.32,156.36) 155.63,156.68 UV6.B9 ; v2(186.12,160.37) UV7.G1 ; v2(156.83,162.77) UV6.J8 ; v2(181.29,162.75) UV7.J8 ; RP45.2 100.89,104.81 101.03,104.95 101.23,104.95 101.39,104.79 RP45.1 101.39,104.37 101.52,104.24 102.14,104.24 102.44,103.94 v2(102.44,103.1) ; UV7.E1 v2(186.12,158.77) UV7.E2 ; v2(162.4,164.41) UV6.M1 ; UV7.B9 180.09,156.77 v2(179.7,156.38) 179.71,156.38 UV7.A9 ; v2(180.52,165.97) 180.12,166.37 UV7.P9 ; v2(185.32,161.97) UV7.J2 ; UV7.P1 187.06,166.37 v2(187.07,166.37) ; UV7.G8 v2(180.53,160.38) ; v2(180.53,160.38) UV7.F9 179.69,160.4 v2(179.43,160.4) ; UV6.D1 162.03,158.37 v2(161.63,158.77) UV6.E2 ; v2(159.94,156.65) 160.06,156.77 UV6.B3 ; v2(187.06,167.97) UV7.T1 ; RP62.1 30.82,69.71 30.69,69.58 v2(30.69,69.08) ; v2(180.52,167.57) UV7.T9 ; v2(155.23,160.37) UV6.G9 ; UV6.B1 162.16,156.77 v2(162.5,156.43) ; R41.1 124.15,91.98 123.81,92.32 v2(123.81,92.32) ; v2(186.82,156.37) 186.52,156.68 UV7.B1 ; v2(155.23,168.37) UV6.T9 ; v2(155.23,166.77) UV6.P9 ; UZ1.11 v2(34.18,70.22)
  TOP w0.305: v2(154.2,77.93) 154.34,78.08 JODD.4 ; JODD.1 154.22,76.57 v2(154.11,76.68) ; JODD.7 154.17,79.57 153.9,79.84 153.9,80.47 v2(153.78,80.59)
  TOP w0.381: UV4.3 180.33,131.48 v2(180.16,131.3) ; PQ1.4 141.68,157.01 141.92,156.77 v2(142.25,156.77) ; v2(165.54,65.53) 165.4,65.39 U62.3 ; U61.3 148.1,97.17 147.94,97.33 147.94,97.8 148.32,98.18 v2(148.48,98.18) ; v2(147.08,171.37) 147.08,170.89 147.27,170.7 PQ3.4 ; U66.3 104.82,113.61 104.39,113.18 v2(104.13,113.18) ; UH1.3 132.76,104.63 133.15,105.03 133.15,106.07 v2(132.66,106.57) ; v2(163.92,68.79) 164.21,69.07 U63.3 ; v2(168.23,38.52) 168.15,38.43 U5.3 ; PQ2.4 144.01,160.54 143.83,160.72 v2(143.83,161.05) ; PQ3.1 149,169.4 148.89,169.29 148.89,168.91 149.08,168.72 PC15.2 ; v2(147.66,158.85) 147.26,159.24 PQ2.1 ; PQ707.4 v2(68.52,162.88) ; v2(183.34,131.3) 183.34,130.96 183.16,130.78 QV8.1 ; U75.2 154.6,124.66 155.14,125.2 v2(155.14,125.41) ; PQ707.1 v2(69.82,166.74) ; v2(103.5,98.36) 103.7,98.16 U65.3 ; v2(139.35,154.84) 139.95,154.84 140.38,155.27 PQ1.1 ; QV8.4 185.48,129.48 v2(185.6,129.36) ; U64.3 100.91,96.74 v2(100.68,96.51)
  TOP w0.457: v2(148.68,85.88) 149.09,86.29 CE30.2 ; SW1.6 162.73,65.79 v2(162.74,65.78) ; CV47.2 162.32,140.04 162.64,140.36 v2(162.89,140.36) ; SW1.5 v2(157.68,66.48)
  TOP w0.508: EC6104.2 v2(28.3,2.69) ; C2322.2 33.58,24.68 v2(34.26,24) 34.85,24.6 C2309.2 ; v2(130.1,100.08) 130.42,100.39 C1118.2 ; C523.1 v2(50.34,75.44) ; DA14.1 84.49,4.44 v2(83.5,4.44) ; v2(53.6,33.06) 52.95,33.06 52.37,32.47 PQ504.3 ; v2(41.46,75.69) 40.89,75.12 RZ42.2 ; 59.56,71.92 59.16,72.31 C551.2 ; 59.56,71.92 59.16,71.53 C553.2 ; 59.56,71.92 v2(59.98,71.92) ; v2(127.16,76.42) 126.91,76.17 C1098.2 ; PC106.2 v2(44.61,47.27) ; v2(68.64,39.74) 68.57,39.81 PC519.2 ; CE23.2 R1563.2 191.37,82.5 191.61,82.74 v2(191.61,82.75) ; U78.2 54.76,75.56 v2(55.06,75.87) 55.1,75.91 C1280.2 ; CV89.2 163.58,134.94 v2(163.58,134.93) ; v2(100.01,109.85) 100.53,109.33 v4(101.09,109.33) R366.2 ; C1089.2 118.22,74.9 117.8,75.32 v2(117.57,75.32) 117.6,75.36 117.6,76.09 117.61,76.1 C1093.2 ; CV133.2 RV52.2 v2(190.22,160.7) ; v2(124.5,28.57) 124.5,29.78 123.69,30.6 C139.2 122.74,30.6 C174.1 ; RX34.2 CX20.2 v2(26.65,78.04) ; CA66.2 172.91,28.7 v2(172.26,28.05) ; v2(121.49,108.9) v4(120.69,109.7) 118.14,109.7 117.4,110.44 C999.1 ; v2(131.26,61.59) 131.13,61.47 C1115.2 ; v2(69.09,33.26) PC518.2 PC514.2 ; C1138.2 109.52,88.98 v2(109.17,88.62) ; PR2.2 PC5.2 v2(141.92,152.37) ; C159.2 122.75,33.26 C186.2 123.66,33.27 124.28,33.88 125.67,33.88 125.71,33.84 v2(126.33,33.84) ; JHDT1.7 47.68,68.83 v2(47.15,69.37) 47.89,70.1 JHDT1.5 ; CV142.2 177.38,161.01 v2(177.3,160.93) ; v2(118.82,86.21) 118.81,86.22 C1121.2 ; CZ1.2 v2(36.48,64.06) ; CD77.2 146.87,31.37 v2(147.12,31.11) ; v2(175.46,127.48) 175.62,127.31 CV27.2 ; v2(161.94,152.75) CV124.2 ; PC210.2 v2(60.06,26.42) ; CV49.2 179.52,141.86 CV51.2 ; v2(165.65,156.68) 165,156.03 164.4,156.03 CV122.2 ; v2(89.34,4.58) 89.05,4.88 CA32.2 CA31.2 ; v2(159.11,120.62) 158.87,120.86 CV38.2 ; v2(123.22,128.17) v4(124.1,127.29) 124.77,126.62 C1082.2 ; CD75.2 79.15,32.38 v2(78.72,31.95) 79.3,31.37 CD74.2 ; v2(40.7,3.37) 40.13,3.94 PU400.1 ; v2(115.32,75.35) 115.85,75.87 C1090.2 115.85,77.1 C1091.2 ; CV29.2 168.13,122.77 RV9.2 v2(168.13,121.9) ; v2(20.75,73.16) CV359.2 CV360.2 ; v2(107.33,152.74) 107.33,152.57 107.78,152.12 PC1058.2 108.26,152.27 PR1067.2 ; v2(150.37,96) 151.08,96.71 CS16.2 ; v2(155.76,152.75) CV172.2 ; RX13.2 v2(29.14,63.63) ; R400.2 R401.2 v2(98.91,91.12) ; v2(104.15,74.62) 104.15,75.02 104.82,75.69 104.96,75.69 ; C1057.2 123.75,74.17 v2(123.37,74.55) ; v2(156.5,137.86) 157.13,138.49 CV95.2 RV35.2 ; v2(63.81,82.61) 63.99,82.43 JTP.10 ; PC8.2 157.21,177.75 v2(156.52,178.44) 156.09,178 PC7.2 ; C131.2 v2(146.87,28.96) ; v2(190.21,155.5) CV181.2 ; v2(151.9,156.01) 151.9,156 CV125.2 CV121.2 ; v2(151.9,161.09) 151.9,161.08 CV117.2 ; C144.2 129.03,31.29 v2(129.03,31.29) ; CZ19.2 25.71,57.96 CZ22.2 v2(24.86,57.34) ; UX3.2 86.76,153.3 86.75,153.31 v2(86.39,153.31) ; C1128.2 123.55,89.29 123.55,88.6 v2(123.5,88.56) ; RZ2.2 v2(39.17,65.67) ; CV119.2 164.79,156.69 v2(165.33,157.24) ; v2(130.42,23.64) 130.42,25.07 C113.2 C118.2 ; CR11.2 v2(27.71,10.93) ; CV129.2 164.16,170.21 v2(163.85,170.52) ; CA58.2 CA60.2 176.66,12.7 v2(176.33,13.03) ; JPWR.5 194.32,165.73 v2(195.93,167.34) ; CA25.1 184.89,13.03 v2(184.59,13.33) ; v2(25.39,1.84) 25.02,1.46 HDLED1.1 ; v2(109.09,75.32) 109.44,75.67 C1008.2 ; UL3.2 v2(38.73,174.88) ; v2(127.25,21.54) 126.8,21.98 C109.1 ; v2(142.3,105.65) 141.55,104.9 C1081.2 ; v2(124.77,76.12) 124.41,76.48 C1097.2 ; C983.1 C987.1 147.35,132.59 147.05,132.28 v2(147.05,131.79) ; C1078.2 v2(141.23,109.28) ; R365.2 v2(62.5,168.96) ; JREAD.3 24.11,15 v2(24.11,14.99) ; RE58.2 v2(188.83,122.15) ; v2(43.81,67.75) 43.36,68.2 RZ45.2 ; v2(118.77,79.02) 118.76,79.02 C1053.2 ; CE58.2 v2(50.89,76.58) ; v2(195.87,128.41) 197.06,127.22 JKBBL.5 ; v2(142.11,147.76) 141.73,147.38 PC306.2 ; CV45.2 177.8,140.01 v2(177.82,140.03) ; CA30.2 CA29.2 89.13,8.08 v2(89.48,8.42) ; CZ2.2 v2(37.27,75.56) ; v2(129.47,104.65) 129.22,104.39 R641.2 ; v2(190.42,29.77) 190.42,29.57 190.17,29.32 RI2.2 ; PC745.1 PC746.1 112.08,164.47 v2(111.8,164.19) ; CE27.2 88.07,143.57 v2(87.85,143.79) ; v2(178.74,159.64) CV148.2 ; C168.2 24.01,45.03 25.08,43.97 v2(25.08,42.51) ; v2(148.29,168.15) PC15.2 ; CE20.2 162.95,65.01 v2(162.79,65.16) ; CZ7.2 CZ8.2 43.53,66.29 43.78,66.04 v2(43.78,66.01) ; CV22.2 178.91,126.78 v2(178.92,126.77) ; CL39.2 v2(32.82,172.85) ; v2(26.76,20.07) 27.13,19.7 27.59,19.7 C5216.2 C5217.2 ; PR403.2 PC401.2 33.06,2.97 v2(33.36,3.26) ; CV43.2 174.51,138.77 v2(174.48,138.79) ; PC1.2 PC2.2 82.72,157.14 82.72,156.51 v2(82.68,156.48) ; v2(155.31,132.37) 155.14,132.21 C349.1 C343.1 ; v2(24.86,55.17) 24.87,55.18 CZ21.2 25.7,55.86 CZ18.2 ; v2(178.67,120.95) CV213.2 CV206.2 CV204.2 ; C1116.2 131.13,59.94 v2(131.26,60.07) ; v2(105.45,97.14) 104.96,97.64 R154.2 ; CE33.2 195.36,71.73 v2(194.49,71.73) ; RL27.1 v2(35.35,178) ; v2(121.17,86.22) 121.15,86.23 C1120.2 ; CV212.2 178.99,125.49 v2(178.99,126.07) ; v2(126.27,107.09) 126.55,106.81 R953.2 ; v2(190.29,167.31) CV144.2 CV145.2 ; C126.2 v2(150.04,21.72) ; v2(23.72,78.46) 22.94,77.68 D20.1 ; CV168.1 CV194.1 162.74,135.83 v2(162.55,136.03) ; CL6.2 45.78,173.84 v2(45.28,174.33) 44.89,173.94 RL31.1 ; 179.6,140.96 180.33,140.96 CV92.2 ; RI1.2 188.86,35.81 v2(188.41,36.26) ; PR746.1 v2(80.91,164.96) ; v2(150.04,19.94) 150.3,19.69 C124.2 ; JIO1.17 192.42,37.76 v2(193.35,36.83) ; CZ33.2 36,77.72 v2(35.49,78.23) 35.05,77.79 CZ34.2 ; v2(151.9,157.02) 151.9,157.02 CV130.2 ; CV210.2 182.03,125.68 v2(182.03,126.33) ; v2(190.21,156.51) CV146.2 ; CV126.2 151.9,158.04 v2(151.9,158.04) ; PC403.2 31.36,8.32 v2(31.64,8.6) ; 104.96,74.42 104.36,73.82 v2(104.15,73.82) ; RE46.2 v2(192.21,60.38) CE3.2 ; CD78.2 150.58,17.55 CD79.2 v2(150,19.07) ; CE57.2 192.08,133.03 v2(192.08,132.33) ; C229.2 C228.2 v4(158.17,93.98) 158.17,95.08 v2(158.25,95.16) ; RZ6.2 v2(38.16,65.62) ; v2(115.89,160.92) 116.49,160.32 PR1087.1 ; PR204.2 v2(56.65,24.74) ; v2(111.57,75.29) 111.16,75.7 C1062.2 ; v2(178.48,59.75) 178.87,60.15 CE47.2 RE48.2 CE41.2 ; CL13.2 46.37,162.66 v2(47.3,162.66) CL12.2 ; v2(148.57,159.03) 149.33,159.03 149.61,159.31 PR29.2 ; CV166.1 183.45,134.25 v2(183.13,134.57) 182.91,134.8 181.02,134.8 180.49,135.34 CVT90.1 ; v2(113.7,73.69) 113.73,73.72 C1064.2 ; CX51.2 82.14,155.36 82.57,155.79 v2(82.71,155.79) ; RX11.2 v2(84.78,157.53) ; v2(163.52,161.8) 163.52,161.17 163.81,160.88 CV132.2 ; PH1002.1 112.78,135.84 v2(112.45,135.51) ; JODD.21 160.9,85.93 v2(163.07,83.76) ; CE25.2 194.75,66.42 v2(194.49,66.17) ; CV363.2 CV364.2 v2(20.68,59.5) ; v2(177.31,167.49) 177.31,167.98 177.73,168.4 CV149.2 ; v2(118.88,169.89) 118.31,169.32 PC769.1 ; PR738.2 82.71,170.76 v2(82.49,170.98) ; v2(86.38,154.84) 86.09,155.13 CX52.2 ; v2(128.64,22.99) 128.64,23.03 128.45,23.22 128.45,24.38 127.81,25.03 126.9,25.03 126.1,25.83 C112.2 ; CV357.2 CV358.2 v2(20.75,66.93) ; v2(137.53,93.47) 137.53,92.24 C1124.2 ; R28.1 v2(198.73,114.74) ; C30.1 v2(94.48,63.75) ; v2(111.37,72.92) 111.99,72.3 C1274.2 ; C1088.2 120.11,76.06 C1087.2 120.11,75.47 v2(119.97,75.32) ; v2(88.73,157.21) 88.82,157.3 PQ5.3 89.27,157.54 PR9.1 ; v2(109.65,157.91) 109.05,157.31 PC1065.2 ; JIO1.23 191.41,43.76 v2(190.87,44.3) 191.34,44.76 JIO1.24 ; v2(181.83,62.04) 182.43,61.44 CE42.2 ; v2(86.1,22.82) R59.1 86.74,22.82 C146.2 C137.2 86.22,25.12 C135.2 85.68,25.65 v2(85.31,25.29) ; v2(190.29,168.32) CV138.2 ; v2(45.09,66.84) 45.57,66.36 R52.1 R49.1 R51.1 ; CV11.2 171.65,122.78 RV13.2 171.67,121.84 v2(171.67,121.83) ; v2(110.78,150.51) 110.81,150.55 PC1037.2 ; v2(122.43,160.35) 122.97,160.35 PC1010.1 ; RV17.1 184.73,138.01 185.24,137.5 185.24,136.63 v2(185.08,136.47) ; v2(108.29,77.9) 109.15,77.04 C1066.2 ; v2(181.55,152.75) CV140.2 ; SW1.1 v2(159.48,69.76) ; QE5.4 187.35,127.24 188.13,128.02 v2(188.13,128.37) ; PC100.2 v2(48.82,53.4) ; v2(189.19,123.1) 189.7,123.62 QE4.3 ; v2(177.35,155.32) CV137.2 ; C26.1 154.95,126.87 v2(155.16,127.09) ; CM8.2 CM5.2 171,65.03 v2(170.59,65.44) 169.86,64.71 CM6.2 ; v2(171.98,30.21) 172.22,29.97 CA70.2 ; PR1005.2 126.44,155.15 v2(126.43,155.14) ; CV361.2 CV362.2 v2(20.75,63.18) ; C2498.2 v2(151.68,37.13) ; v2(136.2,117.73) 135.76,118.17 C1084.2 ; CV118.2 152.04,170.23 v2(152.04,170.23) ; JTP.9 65.7,68.03 v2(65.65,67.97) ; C1112.2 v2(106.15,62.23) ; CL19.2 v2(41.65,173.74) ; v2(199.64,171.13) 199.07,170.56 C33.2 199.03,170.55 C34.2 ; v2(49.24,172.34) 49.55,172.64 CL37.2 ; v2(118.77,88.62) 118.57,88.81 C1127.2 ; v2(148.15,53.57) 148.71,54.13 RH46.1 ; v2(63.85,74.31) 63.85,75.1 63.33,75.61 JTP.4 ; v2(163.86,79.34) 163.29,79.34 160.9,76.95 JODD.22 ; C1063.2 109.15,73.8 v2(108.98,73.63) ; PC1059.2 v2(111.94,155.7) ; CD68.2 CD69.2 131.07,38.96 130.44,39.6 129.62,39.6 v2(129.53,39.69) ; CZ27.2 v2(28.27,56.75) ; v2(115.17,93.12) 115.58,93.53 R541.2 ; CH14.2 135.79,105.08 v2(135.93,105.23) ; C125.2 v2(78.42,30.23) ; R8.1 C29.2 v2(94.54,61.98) ; v2(91.12,84.28) 91.34,84.51 R118.2 ; CE24.2 194.63,68.96 v2(194.62,68.97) ; CE44.2 v2(197.36,65.18) ; v2(83.55,8.76) 83.8,9.02 DA13.1 ; v2(143.97,170.19) 144.17,169.99 PR32.2 ; v2(190.87,154.2) 190.85,154.23 CV136.2 ; PQ711.3 110.41,163.77 v2(110.75,164.11) ; PR1078.2 v2(112.6,150.55) ; v2(151.9,159.05) 151.9,159.05 CV127.2 ; PC1004.1 v2(125.91,159.35) ; CV66.2 165.85,125.71 166.42,125.15 v2(166.57,125.15) ; JREAD.15 v2(21.31,5.57) ; C163.2 v2(28.21,26.47) ; CZ6.2 v2(34.94,64.06) ; v2(149.1,26.34) 149.09,26.33 C945.1 149.09,24.7 C136.2 149.05,24.66 C944.1 v2(149.05,23.06) ; v2(59.39,15.63) 59.75,15.99 PC204.1 ; v2(190.25,165.4) 190.13,165.28 CV139.2 ; CV35.2 CV26.2 v2(172.91,124.39) ; LED1.3 20.12,2.17 v2(20.43,1.87) ; v2(56.7,19.28) 56.23,19.28 PC209.2 ; v2(164.44,124.28) 164.59,124.13 RV160.2 ; v2(40.96,56.02) 40.97,56.02 41.36,55.63 PC109.2 ; v2(169.89,121.91) RV12.2 CV28.2 ; PR110.2 46.79,53.61 PD101.1 v2(46.79,54.8) ; v2(184.93,118.5) JKB.32 ; CL14.2 v2(42.92,173.74) ; CV175.2 161.95,137.95 v2(161.74,138.16) ; JHDT1.3 v2(46.95,71.37) 46.49,70.92 C141.2 ; PC1202.2 32.53,5.68 v2(31.98,5.68) ; v2(78.51,39.54) C161.2 78.51,37.93 C183.2 ; v2(151.9,160.07) 151.9,160.07 CV131.2 ; CE56.2 v2(199,134.11) ; v2(121.16,95.08) 120.77,94.69 C1148.2 119.39,94.69 C1147.2 ; RL35.2 52.5,166.94 v2(51.49,166.94) ; RV21.1 178.1,135.04 v2(178.19,135.13) ; v2(189.41,37.34) 189.06,37.69 DI4.1 ; CV195.2 v2(160.61,133.1) ; v2(198.95,116.57) 197.7,117.83 JKBBL.6 ; v2(151.89,167.18) CV173.2 ; PC405.2 v2(42.09,10.48) ; CZ28.2 27.52,58.88 CZ29.2 v2(28.13,59.77) ; v2(184.71,59.69) 185.1,60.07 CE40.1 ; v2(151.84,164.89) RV45.2 ; v2(127.17,74.43) 126.69,74.43 126.49,74.23 C1061.2 ; UE6.7 91.5,145.02 v2(90.87,144.4) 90.23,145.05 UE6.8 ; CD70.2 CD71.2 130.94,15.53 v2(130.8,15.39) ; CV15.2 166.37,122.78 RV16.2 v2(166.37,121.77) ; v2(18.88,76.3) 18.58,76 CX22.2 18.14,75.03 CX21.2 ; v2(78.2,158.98) 78.06,158.98 77.73,158.65 PC4.2 PC3.2 ; v2(47.35,172.26) 46.86,172.75 CL36.2 ; v2(177.34,156.82) CV141.2 ; v2(41.2,63.27) CZ5.2 41.85,64.06 CZ24.2 ; JIO1.25 v2(194.9,20.42) ; CM11.2 173.44,64.34 v2(173.51,64.26) CE17.2 CE14.2 ; QS3.3 153.33,101.08 v2(153,101.41) ; R40.1 122.9,91.65 v2(122.38,91.65) ; CL15.2 v2(44,173.23) ; YL2.4 v2(45.66,176) ; v2(46.79,62.8) 47.11,62.48 JHDT1.17 ; v2(171.49,131.97) 171.3,131.78 CV201.2 ; CL3.2 v2(52.25,173.85) ; SW1.2 v2(158.35,66.23) ; RM9.2 v2(169.73,52.7) ; v2(135.45,102.65) 135.17,102.37 v4(135.17,102.04) R695.1 ; QX3.3 v2(27.62,68.06) ; RZ4.2 v2(40.19,65.63) ; CE39.2 RE22.1 173.36,78.49 173.18,78.66 v2(173.18,79.17) ; v2(92.04,18.41) 92.04,17.03 92.58,16.5 C1275.2 ; PR732.2 PC711.1 v2(81.64,170.97) ; v2(147.94,92.86) 147.94,92.58 147.57,92.21 146.84,92.21 146.41,91.78 R903.2 R692.1 ; RV88.1 v2(189.59,133.3) ; v2(94.61,136.4) 94.23,136.78 CE29.2 93.73,138.04 CE28.2 ; v2(142.94,39.5) 142.71,39.27 C140.2 ; v2(176.56,14.68) 176.76,14.48 CA57.2 CA59.2 ; PR1086.1 v2(120.03,161.17) ; v2(131.76,106.5) CH16.2 RH26.1 R929.2 ; C936.2 v2(45.57,67.58) ; v2(20.05,40.92) 19.64,40.51 DI2.1 ; R926.2 CE30.2 ; v2(135.12,93.94) 135.16,93.98 R689.1 R688.1 ; PC105.2 v2(39.14,47.27) ; C1095.2 128.21,76.23 v2(128.39,76.41) ; v2(89.61,26.48) 89.46,26.33 C179.1 89.46,24.61 C142.2 ; C24.1 v2(143.69,97.82) ; PR33.1 v2(141.53,160.78) ; v2(140.95,31.27) 141.36,30.86 CD76.2 C132.1 ; v2(177.27,162.71) 177.27,164.17 177.56,164.46 RV56.2 ; C1059.2 110.55,74.43 v2(110.46,74.52) ; v2(151.84,163.12) RV47.2 CV101.2 ; Q83.3 v2(147.3,107.19) ; v2(85.17,168.43) 85.05,168.3 PJPDC1.8 ; C130.1 v2(150.04,20.7) ; CV205.2 CV211.2 174.32,129.49 174.39,129.41 v2(174.42,129.41) ; CV65.2 165.88,128.61 CV64.2 166.07,127.52 v2(166.5,127.52) ; PC202.2 PC203.2 56.06,22.86 v2(55.63,23.29) ; JIO1.20 192.34,40.76 193.21,39.89 v2(193.21,39.67) ; RV89.1 v2(188.84,136.65) ; PC523.2 v2(55.54,32.33) ; CV180.2 189.92,158.85 v2(190.28,158.85) ; C1113.2 v2(106.15,60.71) ; RV41.1 181.5,136.26 RV40.1 182.03,136.26 v2(182.41,136.63) ; v2(175.32,81.85) 175.69,82.22 PC6.2 PR35.2 ; 104.96,76.96 104.32,76.96 v2(104.2,77.09) ; PR515.1 63.81,31.54 v2(64.18,31.17) ; C623.1 152.28,122.26 C622.1 152.29,121.36 v2(152.8,120.85) ; JREAD.12 v2(21.59,30.52) ; Q91.3 v2(181.35,86.56) ; PJPDC1.7 v2(101.25,168.29) ; C133.2 v2(147.88,30.23) ; v2(177.88,141.67) 177.56,142 CV48.2 175.94,142 CV50.2 ; v2(156.27,97.61) CS15.2 ; PR404.2 v2(42.98,3.43) ; PC768.1 v2(122.78,168.99) ; YL2.2 49.35,174.3 v2(50.31,173.34) ; v2(190.21,157.53) CV150.2 ; CV91.2 181.96,141.9 CV44.2 181.56,142.85 CV174.2 ; v2(177.3,165.81) 177.4,165.71 CV143.2 ; v2(121.17,79.02) 121.2,79.05 C1054.2 ; C1111.2 v2(106.15,63.75) ; C114.1 v2(110.34,18.67) ; LE4.1 182.92,82.68 v2(183.33,83.08) ; v2(184.28,133.26) 183.63,133.26 183.29,132.92 CV10.2 ; v2(26.01,73.79) 25.5,73.79 25.1,74.18 RX14.2 ; v2(164.78,159.51) CV179.2 ; v2(23.98,21.76) 24.72,22.5 JREAD.6 ; v2(146.11,95.14) 147.02,95.14 147.45,94.7 C1000.1 CH23.2 ; C150.2 127.63,39.63 v2(127.71,39.55) ; RV163.2 v2(160.03,125.19) ; v2(190.18,41.97) 189.73,42.42 DI3.1 ; v2(151.89,168.2) CV128.2 ; JIO1.26 v2(196.65,47.76) ; PR10.1 v2(139.57,159.84) ; R694.1 v2(121.71,117.92) ; RE24.1 v2(176.35,60.38) ; C1114.2 v2(131.26,62.99) ; JKB.31 v2(184.84,90.6) ; v2(186.44,152.75) CV147.2 ; v2(113.97,76.92) 114.02,76.87 C1092.2
  VCC w0.203: H7.1 143.54,167.26 ; H7.1 144.08,165.77 ; H7.1 140.02,165.77 ; H7.1 142.05,167.8 ; H7.1 143.54,164.28 ; H7.1 140.56,164.28 ; H7.1 142.05,163.74 ; H7.1 140.56,167.26 ; 198.77,149.17 H22.1 ; H22.1 202.37,150.69 ; H22.1 202.93,149.17 ; H22.1 200.85,147.09 ; H22.1 199.33,147.65 ; H22.1 199.33,150.69 ; H22.1 200.85,151.25 ; H22.1 202.37,147.65 ; H2.1 22.07,49.35 ; H2.1 20.65,52.7 ; H2.1 18.72,50.77 ; H2.1 22.07,52.19 ; H2.1 22.58,50.77 ; H2.1 19.23,52.19 ; H2.1 20.65,48.84 ; H2.1 19.23,49.35 ; JHDMI.22 11.38,54.47 ; JHDMI.22 9.02,55.25 ; JHDMI.22 11.38,55.25 ; JHDMI.22 10.2,53.69 ; JHDMI.22 9.02,53.69 ; JHDMI.22 11.38,53.69 ; JHDMI.22 9.02,54.47 ; JHDMI.22 10.2,55.25 ; 2.2,53.64 JHDMI.23 ; JHDMI.23 0.68,53.64 ; JHDMI.23 2.2,55.2 ; JHDMI.23 3.72,54.42 ; JHDMI.23 3.72,55.2 ; JHDMI.23 3.72,53.64 ; JHDMI.23 0.68,54.42 ; 14.18,37.11 JUSB1.4 ; JUSB1.4 15.45,35.84 ; JUSB1.4 15.65,36.47 ; JUSB1.4 14.82,37.3 ; JUSB1.4 15.45,37.11 ; JUSB1.4 14.18,35.84 ; JUSB1.4 14.82,35.64 ; 171.92,112.42 H23.1 ; H23.1 175.52,113.94 ; H23.1 175.52,110.9 ; H23.1 172.48,113.94 ; H23.1 176.08,112.42 ; H23.1 174,110.34 ; H23.1 172.48,110.9 ; H4.1 171.07,11.35 ; H4.1 168.23,11.35 ; H4.1 171.07,14.19 ; H4.1 169.65,10.84 ; H4.1 167.72,12.77 ; H4.1 168.23,14.19 ; H4.1 169.65,14.7 ; H4.1 171.58,12.77 ; 198.36,54.78 H6.1 ; H6.1 201.88,56.27 ; H6.1 201.34,54.78 ; H6.1 197.82,56.27 ; H6.1 201.34,57.76 ; H6.1 199.85,58.3 ; H6.1 199.85,54.24 ; H6.1 198.36,57.76 ; 10.99,61.68 JHDMI.2 ; JHDMI.2 12.03,61.22 ; JHDMI.2 11.45,60.64 ; JHDMI.2 10.87,61.22 ; JHDMI.2 11.91,60.76 ; JHDMI.2 10.99,60.76 ; JHDMI.2 11.91,61.68 ; 9.02,75.97 JHDMI.21 ; JHDMI.21 11.38,75.97 ; JHDMI.21 10.2,75.19 ; JHDMI.21 9.02,75.19 ; JHDMI.21 11.38,75.19 ; JHDMI.21 11.38,76.75 ; JHDMI.21 10.2,76.75 ; JHDMI.21 9.02,76.75 ; JCRT.17 15.02,75.48 ; JCRT.17 13.5,76.86 ; JCRT.17 15.02,76.86 ; JCRT.17 15.02,76.17 ; JCRT.17 11.98,75.48 ; JCRT.17 11.98,76.86 ; JCRT.17 11.98,76.17 ; JCRT.17 13.5,75.48 ; 4.34,32.12 JUSB1.13 ; JUSB1.13 6.9,31.19 ; JUSB1.13 6.9,32.12 ; JUSB1.13 4.34,31.19 ; JUSB1.13 5.62,31.19 ; 4.88,161.65 JLAN.10 ; JLAN.10 6.46,160.92 ; JLAN.10 8.04,160.92 ; JLAN.10 8.04,161.65 ; JLAN.10 4.88,160.92 ; 153.42,179.77 PBATT1.2 ; PBATT1.2 154.4,178.79 ; PBATT1.2 154.4,180.75 ; PBATT1.2 153.66,179.03 ; PBATT1.2 155.14,179.03 ; PBATT1.2 155.14,180.51 ; PBATT1.2 153.66,180.51 ; PBATT1.2 155.38,179.77 ; 146.05,148.29 H21.1 ; H21.1 147.57,148.85 ; H21.1 147.57,151.89 ; H21.1 143.97,150.37 ; H21.1 144.53,148.85 ; H21.1 146.05,152.45 ; H21.1 144.53,151.89 ; 4.88,180.3 JLAN.9 ; JLAN.9 6.46,181.02 ; JLAN.9 8.04,180.3 ; JLAN.9 4.88,181.02 ; JLAN.9 8.04,181.02 ; JCRT.10 14.29,69.4 ; JCRT.10 13.18,68.9 ; JCRT.10 14.29,68.41 ; JCRT.10 13.31,69.4 ; JCRT.10 14.42,68.9 ; JCRT.10 13.31,68.41 ; JHDMI.8 11.91,64.68 ; JHDMI.8 11.91,63.76 ; JHDMI.8 10.99,63.76 ; JHDMI.8 12.03,64.22 ; JHDMI.8 10.99,64.68 ; JHDMI.8 10.87,64.22 ; JUSB1.10 14.07,47.2 ; JUSB1.10 14.07,45.54 ; JUSB1.10 15.75,45.54 ; JUSB1.10 15.75,46.37 ; JUSB1.10 15.75,47.2 ; JUSB1.7 13.32,40.8 ; JUSB1.7 13.95,40.6 ; JUSB1.7 13.95,39.33 ; JUSB1.7 12.49,39.97 ; JUSB1.7 12.68,39.33 ; JUSB1.7 13.32,39.14 ; JUSB1.7 14.15,39.97 ; JUSB1.7 12.68,40.6 ; 148.4,177.86 PBATT1.10 ; PBATT1.10 150.15,179.77 ; PBATT1.10 148.4,179.77 ; PBATT1.10 150.15,177.86 ; PBATT1.10 149.27,177.86 ; PBATT1.3 157.14,179.03 ; PBATT1.3 155.66,179.03 ; PBATT1.3 155.66,180.51 ; PBATT1.3 155.42,179.77 ; PBATT1.3 157.38,179.77 ; PBATT1.3 156.4,178.79 ; PBATT1.3 157.14,180.51 ; PBATT1.3 156.4,180.75 ; H1.1 39.17,166.19 ; H1.1 37.75,162.84 ; H1.1 36.33,166.19 ; H1.1 37.75,166.7 ; H1.1 35.82,164.77 ; H1.1 39.68,164.77 ; H1.1 39.17,163.35 ; H1.1 36.33,163.35 ; JUSB1.11 15.75,33.57 ; JUSB1.11 15.75,34.4 ; JUSB1.11 14.07,32.74 ; JUSB1.11 14.07,34.4 ; JUSB1.11 15.75,32.74 ; 9.44,68.26 JHDMI.17 ; JHDMI.17 10.36,69.18 ; JHDMI.17 10.48,68.72 ; JHDMI.17 10.36,68.26 ; JHDMI.17 9.44,69.18 ; JHDMI.17 9.32,68.72 ; 4.34,47.82 JUSB1.12 ; JUSB1.12 4.34,48.75 ; JUSB1.12 5.62,48.75 ; JUSB1.12 6.9,47.82 ; JUSB1.12 6.9,48.75 ; 13.31,70.54 JCRT.5 ; JCRT.5 13.18,70.05 ; JCRT.5 13.31,69.56 ; JCRT.5 14.42,70.05 ; JCRT.5 13.8,70.67 ; JCRT.5 14.29,69.56 ; JCRT.5 14.29,70.54 ; 13.31,64.82 JCRT.8 ; JCRT.8 13.18,64.32 ; JCRT.8 14.29,63.83 ; JCRT.8 14.42,64.32 ; JCRT.8 13.31,63.83 ; JCRT.8 14.29,64.82 ; 143.06,70.77 H33.1 ; H33.1 147.02,72.44 ; H33.1 145.35,68.48 ; H33.1 147.64,70.77 ; H33.1 143.68,72.44 ; H33.1 145.35,73.06 ; H33.1 143.68,69.1 ; H33.1 147.02,69.1 ; JCRT.18 13.5,54.96 ; JCRT.18 13.5,53.58 ; JCRT.18 11.98,53.58 ; JCRT.18 11.98,54.96 ; JCRT.18 15.02,53.58 ; JCRT.18 11.98,54.27 ; JCRT.18 15.02,54.96 ; JCRT.18 15.02,54.27 ; JREAD.13 15.73,29.2 ; JREAD.13 11.47,29.2 ; JREAD.13 11.47,30.75 ; JREAD.13 13.6,29.2 ; JREAD.13 13.6,30.75 ; JREAD.13 15.73,29.97 ; JREAD.13 11.47,29.97 ; JREAD.13 15.73,30.75 ; JCRT.19 5.5,54.96 ; JCRT.19 7.02,53.58 ; JCRT.19 5.5,53.58 ; JCRT.19 7.02,54.27 ; JCRT.19 3.98,53.58 ; JCRT.19 3.98,54.96 ; JCRT.19 3.98,54.27 ; JCRT.19 7.02,54.96 ; 152.32,60.97 H5.1 ; H5.1 152.83,62.39 ; H5.1 154.25,62.9 ; H5.1 154.25,59.04 ; H5.1 152.83,59.55 ; H5.1 155.67,59.55 ; H5.1 155.67,62.39 ; H5.1 156.18,60.97 ; 13.18,62.03 JCRT.7 ; JCRT.7 14.29,61.54 ; JCRT.7 14.29,62.53 ; JCRT.7 13.31,62.53 ; JCRT.7 13.31,61.54 ; JCRT.7 14.42,62.03 ; H14.1 96.65,130.4 ; H14.1 98.58,128.47 ; H14.1 94.72,128.47 ; H14.1 98.07,127.05 ; H14.1 98.07,129.89 ; H14.1 95.23,129.89 ; H14.1 95.23,127.05 ; H14.1 96.65,126.54 ; 9.44,63.18 JHDMI.5 ; JHDMI.5 10.36,62.26 ; JHDMI.5 9.44,62.26 ; JHDMI.5 10.36,63.18 ; JHDMI.5 9.32,62.72 ; JHDMI.5 10.48,62.72 ; 9.44,65.26 JHDMI.11 ; JHDMI.11 10.36,66.18 ; JHDMI.11 9.44,66.18 ; JHDMI.11 9.32,65.72 ; JHDMI.11 10.48,65.72 ; JHDMI.11 10.36,65.26 ; H32.1 93.24,70.77 ; H32.1 89.28,69.1 ; H32.1 92.62,72.44 ; H32.1 90.95,68.48 ; H32.1 88.66,70.77 ; H32.1 90.95,73.06 ; H32.1 92.62,69.1 ; H32.1 89.28,72.44 ; 168.65,179.77 PBATT1.9 ; PBATT1.9 170.4,179.77 ; PBATT1.9 168.65,177.86 ; PBATT1.9 170.4,177.86 ; PBATT1.9 169.52,177.86 ; 3.98,76.86 JCRT.16 ; JCRT.16 3.98,76.17 ; JCRT.16 5.5,75.48 ; JCRT.16 7.02,76.17 ; JCRT.16 5.5,76.86 ; JCRT.16 7.02,76.86 ; JCRT.16 3.98,75.48 ; JCRT.16 7.02,75.48 ; PBATT1.1 153.14,180.51 ; PBATT1.1 151.66,179.03 ; PBATT1.1 153.38,179.77 ; PBATT1.1 153.14,179.03 ; PBATT1.1 152.4,180.75 ; PBATT1.1 151.42,179.77 ; PBATT1.1 152.4,178.79 ; PBATT1.1 151.66,180.51 ; 11.47,2.99 JREAD.14 ; JREAD.14 15.73,3.77 ; JREAD.14 11.47,3.77 ; JREAD.14 11.47,4.55 ; JREAD.14 13.6,2.99 ; JREAD.14 15.73,2.99 ; JREAD.14 15.73,4.55 ; JREAD.14 13.6,4.55 ; 2.2,75.24 JHDMI.20 ; JHDMI.20 0.68,76.8 ; JHDMI.20 3.72,76.02 ; JHDMI.20 2.2,76.8 ; JHDMI.20 0.68,76.02 ; JHDMI.20 3.72,76.8 ; JHDMI.20 3.72,75.24 ; JCRT.6 14.29,59.25 ; JCRT.6 14.29,60.24 ; JCRT.6 13.31,59.25 ; JCRT.6 13.8,59.12 ; JCRT.6 13.18,59.74 ; JCRT.6 13.31,60.24 ; JCRT.6 14.42,59.74
  GND w0.203: JCRT.17 15.02,75.48 ; JCRT.17 13.5,75.48 ; JCRT.17 11.98,75.48 ; JCRT.17 11.98,76.86 ; JCRT.17 15.02,76.17 ; JCRT.17 15.02,76.86 ; JCRT.17 13.5,76.86 ; JCRT.17 11.98,76.17 ; H7.1 144.08,165.77 ; H7.1 140.56,167.26 ; H7.1 143.54,164.28 ; H7.1 140.56,164.28 ; H7.1 140.02,165.77 ; H7.1 142.05,167.8 ; H7.1 142.05,163.74 ; H7.1 143.54,167.26 ; 10.2,75.19 JHDMI.21 ; JHDMI.21 9.02,75.97 ; JHDMI.21 11.38,76.75 ; JHDMI.21 10.2,76.75 ; JHDMI.21 11.38,75.19 ; JHDMI.21 9.02,76.75 ; JHDMI.21 11.38,75.97 ; JHDMI.21 9.02,75.19 ; PBATT1.1 152.4,180.75 ; PBATT1.1 151.42,179.77 ; PBATT1.1 152.4,178.79 ; PBATT1.1 151.66,180.51 ; PBATT1.1 153.14,179.03 ; PBATT1.1 153.14,180.51 ; PBATT1.1 151.66,179.03 ; PBATT1.1 153.38,179.77 ; 199.85,54.24 H6.1 ; H6.1 199.85,58.3 ; H6.1 198.36,54.78 ; H6.1 201.88,56.27 ; H6.1 197.82,56.27 ; H6.1 198.36,57.76 ; H6.1 201.34,54.78 ; H6.1 201.34,57.76 ; H1.1 39.68,164.77 ; H1.1 39.17,163.35 ; H1.1 39.17,166.19 ; H1.1 36.33,166.19 ; H1.1 37.75,166.7 ; H1.1 35.82,164.77 ; H1.1 37.75,162.84 ; H1.1 36.33,163.35 ; JCRT.16 5.5,76.86 ; JCRT.16 7.02,75.48 ; JCRT.16 3.98,76.86 ; JCRT.16 5.5,75.48 ; JCRT.16 7.02,76.17 ; JCRT.16 7.02,76.86 ; JCRT.16 3.98,75.48 ; JCRT.16 3.98,76.17 ; JCRT.10 14.42,68.9 ; JCRT.10 13.31,68.41 ; JCRT.10 14.29,68.41 ; JCRT.10 14.29,69.4 ; JCRT.10 13.18,68.9 ; JCRT.10 13.31,69.4 ; H5.1 155.67,62.39 ; H5.1 154.25,62.9 ; H5.1 152.32,60.97 ; H5.1 152.83,62.39 ; H5.1 155.67,59.55 ; H5.1 156.18,60.97 ; H5.1 152.83,59.55 ; H5.1 154.25,59.04 ; 11.47,2.99 JREAD.14 ; JREAD.14 15.73,3.77 ; JREAD.14 13.6,2.99 ; JREAD.14 15.73,4.55 ; JREAD.14 15.73,2.99 ; JREAD.14 13.6,4.55 ; JREAD.14 11.47,4.55 ; JREAD.14 11.47,3.77 ; H31.1 118.15,107.2 ; H31.1 116.59,106.63 ; H31.1 118.15,102.94 ; H31.1 116.59,103.51 ; H31.1 120.28,105.07 ; H31.1 119.71,103.51 ; H31.1 119.71,106.63 ; H31.1 116.02,105.07 ; 148.4,177.86 PBATT1.10 ; PBATT1.10 149.27,177.86 ; PBATT1.10 148.4,179.77 ; PBATT1.10 150.15,179.77 ; PBATT1.10 150.15,177.86 ; JCRT.19 7.02,54.96 ; JCRT.19 5.5,53.58 ; JCRT.19 7.02,53.58 ; JCRT.19 7.02,54.27 ; JCRT.19 5.5,54.96 ; JCRT.19 3.98,54.96 ; JCRT.19 3.98,53.58 ; JCRT.19 3.98,54.27 ; JUSB1.11 14.07,34.4 ; JUSB1.11 15.75,34.4 ; JUSB1.11 15.75,32.74 ; JUSB1.11 15.75,33.57 ; JUSB1.11 14.07,32.74 ; JUSB1.4 15.45,37.11 ; JUSB1.4 14.82,35.64 ; JUSB1.4 14.18,37.11 ; JUSB1.4 14.82,37.3 ; JUSB1.4 14.18,35.84 ; JUSB1.4 15.45,35.84 ; JUSB1.4 15.65,36.47 ; 4.34,32.12 JUSB1.13 ; JUSB1.13 6.9,32.12 ; JUSB1.13 4.34,31.19 ; JUSB1.13 6.9,31.19 ; JUSB1.13 5.62,31.19 ; H14.1 98.07,129.89 ; H14.1 95.23,127.05 ; H14.1 94.72,128.47 ; H14.1 96.65,130.4 ; H14.1 98.58,128.47 ; H14.1 95.23,129.89 ; H14.1 98.07,127.05 ; H14.1 96.65,126.54 ; 9.02,53.69 JHDMI.22 ; JHDMI.22 11.38,53.69 ; JHDMI.22 9.02,54.47 ; JHDMI.22 11.38,55.25 ; JHDMI.22 11.38,54.47 ; JHDMI.22 10.2,53.69 ; JHDMI.22 9.02,55.25 ; JHDMI.22 10.2,55.25 ; JHDMI.2 12.03,61.22 ; JHDMI.2 10.99,60.76 ; JHDMI.2 11.91,60.76 ; JHDMI.2 11.45,60.64 ; JHDMI.2 10.99,61.68 ; JHDMI.2 10.87,61.22 ; JHDMI.2 11.91,61.68 ; JHDMI.20 3.72,76.8 ; JHDMI.20 3.72,75.24 ; JHDMI.20 3.72,76.02 ; JHDMI.20 2.2,76.8 ; JHDMI.20 2.2,75.24 ; JHDMI.20 0.68,76.8 ; JHDMI.20 0.68,76.02 ; JCRT.8 14.42,64.32 ; JCRT.8 14.29,63.83 ; JCRT.8 13.31,63.83 ; JCRT.8 13.18,64.32 ; JCRT.8 14.29,64.82 ; JCRT.8 13.31,64.82 ; JLAN.9 8.04,181.02 ; JLAN.9 6.46,181.02 ; JLAN.9 8.04,180.3 ; JLAN.9 4.88,180.3 ; JLAN.9 4.88,181.02 ; JUSB1.10 15.75,45.54 ; JUSB1.10 14.07,45.54 ; JUSB1.10 15.75,47.2 ; JUSB1.10 15.75,46.37 ; JUSB1.10 14.07,47.2 ; 143.68,72.44 H33.1 ; H33.1 145.35,68.48 ; H33.1 147.02,72.44 ; H33.1 143.68,69.1 ; H33.1 145.35,73.06 ; H33.1 143.06,70.77 ; H33.1 147.02,69.1 ; H33.1 147.64,70.77 ; JCRT.6 14.29,60.24 ; JCRT.6 13.8,59.12 ; JCRT.6 14.29,59.25 ; JCRT.6 13.31,59.25 ; JCRT.6 13.18,59.74 ; JCRT.6 14.42,59.74 ; JCRT.6 13.31,60.24 ; 10.99,63.76 JHDMI.8 ; JHDMI.8 11.91,64.68 ; JHDMI.8 10.87,64.22 ; JHDMI.8 11.91,63.76 ; JHDMI.8 12.03,64.22 ; JHDMI.8 10.99,64.68 ; JHDMI.17 10.36,68.26 ; JHDMI.17 9.32,68.72 ; JHDMI.17 10.48,68.72 ; JHDMI.17 9.44,68.26 ; JHDMI.17 10.36,69.18 ; JHDMI.17 9.44,69.18 ; PBATT1.9 170.4,177.86 ; PBATT1.9 170.4,179.77 ; PBATT1.9 168.65,177.86 ; PBATT1.9 169.52,177.86 ; PBATT1.9 168.65,179.77 ; JLAN.10 8.04,161.65 ; JLAN.10 8.04,160.92 ; JLAN.10 4.88,160.92 ; JLAN.10 6.46,160.92 ; JLAN.10 4.88,161.65 ; 9.44,62.26 JHDMI.5 ; JHDMI.5 9.44,63.18 ; JHDMI.5 9.32,62.72 ; JHDMI.5 10.36,62.26 ; JHDMI.5 10.36,63.18 ; JHDMI.5 10.48,62.72 ; 153.42,179.77 PBATT1.2 ; PBATT1.2 153.66,179.03 ; PBATT1.2 153.66,180.51 ; PBATT1.2 155.14,180.51 ; PBATT1.2 155.14,179.03 ; PBATT1.2 154.4,178.79 ; PBATT1.2 155.38,179.77 ; PBATT1.2 154.4,180.75 ; H2.1 20.65,52.7 ; H2.1 20.65,48.84 ; H2.1 22.58,50.77 ; H2.1 22.07,49.35 ; H2.1 19.23,52.19 ; H2.1 18.72,50.77 ; H2.1 22.07,52.19 ; H2.1 19.23,49.35 ; PBATT1.3 157.14,180.51 ; PBATT1.3 157.14,179.03 ; PBATT1.3 155.66,180.51 ; PBATT1.3 155.66,179.03 ; PBATT1.3 156.4,178.79 ; PBATT1.3 156.4,180.75 ; PBATT1.3 155.42,179.77 ; PBATT1.3 157.38,179.77 ; JHDMI.23 3.72,55.2 ; JHDMI.23 3.72,54.42 ; JHDMI.23 0.68,53.64 ; JHDMI.23 2.2,53.64 ; JHDMI.23 3.72,53.64 ; JHDMI.23 2.2,55.2 ; JHDMI.23 0.68,54.42 ; H32.1 92.62,72.44 ; H32.1 92.62,69.1 ; H32.1 88.66,70.77 ; H32.1 89.28,69.1 ; H32.1 89.28,72.44 ; H32.1 93.24,70.77 ; H32.1 90.95,68.48 ; H32.1 90.95,73.06 ; 169.65,10.84 H4.1 ; H4.1 171.07,11.35 ; H4.1 171.58,12.77 ; H4.1 171.07,14.19 ; H4.1 169.65,14.7 ; H4.1 167.72,12.77 ; H4.1 168.23,11.35 ; H4.1 168.23,14.19 ; 4.34,48.75 JUSB1.12 ; JUSB1.12 6.9,47.82 ; JUSB1.12 5.62,48.75 ; JUSB1.12 4.34,47.82 ; JUSB1.12 6.9,48.75 ; H23.1 175.52,110.9 ; H23.1 174,114.5 ; H23.1 175.52,113.94 ; H23.1 171.92,112.42 ; H23.1 172.48,110.9 ; H23.1 174,110.34 ; H23.1 172.48,113.94 ; H23.1 176.08,112.42 ; JCRT.7 14.42,62.03 ; JCRT.7 13.31,62.53 ; JCRT.7 13.18,62.03 ; JCRT.7 13.31,61.54 ; JCRT.7 14.29,62.53 ; JCRT.7 14.29,61.54 ; 146.05,148.29 H21.1 ; H21.1 144.53,148.85 ; H21.1 147.57,148.85 ; H21.1 146.05,152.45 ; H21.1 143.97,150.37 ; H21.1 147.57,151.89 ; H21.1 148.13,150.37 ; H21.1 144.53,151.89 ; JUSB1.7 13.95,39.33 ; JUSB1.7 12.68,39.33 ; JUSB1.7 12.49,39.97 ; JUSB1.7 13.32,40.8 ; JUSB1.7 13.95,40.6 ; JUSB1.7 12.68,40.6 ; JUSB1.7 13.32,39.14 ; JUSB1.7 14.15,39.97 ; H22.1 200.85,151.25 ; H22.1 200.85,147.09 ; H22.1 199.33,150.69 ; H22.1 199.33,147.65 ; H22.1 202.37,147.65 ; H22.1 202.93,149.17 ; H22.1 202.37,150.69 ; H22.1 198.77,149.17 ; JREAD.13 13.6,30.75 ; JREAD.13 15.73,29.97 ; JREAD.13 15.73,29.2 ; JREAD.13 13.6,29.2 ; JREAD.13 11.47,30.75 ; JREAD.13 11.47,29.97 ; JREAD.13 15.73,30.75 ; JREAD.13 11.47,29.2 ; 11.98,54.96 JCRT.18 ; JCRT.18 15.02,54.27 ; JCRT.18 15.02,53.58 ; JCRT.18 15.02,54.96 ; JCRT.18 13.5,54.96 ; JCRT.18 11.98,54.27 ; JCRT.18 11.98,53.58 ; JCRT.18 13.5,53.58 ; 9.44,65.26 JHDMI.11 ; JHDMI.11 10.36,65.26 ; JHDMI.11 10.48,65.72 ; JHDMI.11 9.44,66.18 ; JHDMI.11 10.36,66.18 ; JHDMI.11 9.32,65.72 ; 13.18,70.05 JCRT.5 ; JCRT.5 14.29,69.56 ; JCRT.5 14.42,70.05 ; JCRT.5 13.31,70.54 ; JCRT.5 14.29,70.54 ; JCRT.5 13.8,70.67 ; JCRT.5 13.31,69.56
  BOTTOM w0.102: v2(177.79,29.78) v4(177.79,29.02) ; v2(161.68,115.17) v4(161.68,114.26) ; v4(28.06,21.84) 27.51,21.3 v2(27.51,21.29) ; v2(21.59,30.52) 21.58,30.52 v4(21.58,31.1) ; v2(194.49,66.17) v4(193.03,66.17)
  BOTTOM w0.203: v2(155.49,140.87) 155.6,140.76 UV1.G31
  BOTTOM w0.229: UC1.K2 UC1.K1 ; UC1.F4 105.78,94.73 v2(105.85,94.73) ; v2(100.53,71.76) 100.59,71.82 UC1.A32 ; UC1.D22 103.31,80.18 v2(103.31,80.26) ; v2(101.55,70.89) 101.76,70.89 101.79,70.92 UC1.B33 ; UC1.BC4 134.95,93.94 v2(135.12,93.94) ; UC1.AM4 125.87,94.61 v2(125.79,94.61) ; v2(103.27,78.62) 103.67,78.22 UC1.D24 ; UC1.V1 114.88,96.24 114.88,96.04 114.48,95.64 v2(114.48,95.52) ; UC1.AP33 127.82,71.27 127.82,70.78 128.12,70.49 v2(128.12,70.32) ; UC1.D6 103.81,92.62 v2(104.15,92.96) ; UC1.AY14 132.67,86.09 132.39,85.81 v2(132.38,85.81) ; v2(132.27,74.62) 132.66,75.02 UC1.AY28 ; UC1.U5 114.76,93.71 114.76,94.11 UC1.V4 ; v2(104.72,69.93) 104.79,69.93 105.37,70.52 105.37,71.26 105.37,71.26 105.37,71.26 105.37,71.27 UC1.F33 ; UC1.D30 103.72,73.42 104.12,73.82 v2(104.15,73.82) ; v2(104.15,74.62) 103.75,75.02 UC1.D28 ; UC1.P2 UC1.P1 111.39,96.7 v2(111.39,97.01) ; UC1.M30 110.17,73.32 v2(110.57,72.92) ; UC1.AV33 130.97,70.81 131.15,70.63 v2(131.15,70.58) ; v2(121.16,95.08) 121.16,94.53 UC1.AF4 ; UC1.AY30 132.67,73.42 132.97,73.12 v2(132.97,72.7) ; UC1.AF1 121.37,97.64 v2(121.53,97.8) ; UC1.BB33 134.69,70.92 v2(134.71,70.89) ; v2(135.65,78.94) 135.5,78.94 134.79,78.22 UC1.BC24 ; UC1.K33 108.57,71.41 108.98,71.82 108.98,72.91 v2(108.97,72.92) UC1.K30 ; v2(124.85,96.91) 124.73,96.78 124.73,96.48 UC1.AK1 ; UC1.A28 101.06,75.02 v2(100.72,74.68) ; v2(111.83,70.76) 111.77,70.82 UC1.P33 ; v2(101.09,78.35) 101.54,78.35 UC1.A24 ; UC1.F2 105.54,95.7 105.54,96.14 UC1.F1 105.51,96.47 105.51,97.08 v2(105.45,97.14) ; v2(103.27,77.06) 103.67,76.66 UC1.D26 ; UC1.H4 107.03,94.38 107.03,94.83 v2(107.07,94.87) ; UC1.K4 108.57,94.32 v2(108.17,94.72) ; v2(103.96,85.83) 103.67,86.13 UC1.D14 ; UC1.Y4 116.64,94.32 v2(117.04,94.72) ; v2(130.8,73.85) 130.8,73.85 130.97,73.68 UC1.AV30 ; UC1.AP30 127.9,73.32 v2(128.37,73.78) ; v2(134.66,75.51) 134.65,75.51 134.65,75.04 UC1.BC28 ; UC1.H30 v2(107.37,72.92) ; v2(104.06,80.9) 104.06,80.94 103.67,81.33 UC1.D20 ; UC1.F30 v2(105.77,72.92) ; v2(104.1,91.45) 104.1,91.45 UC1.D8 ; v2(135.28,91.12) 135.18,91.02 UC1.BC8 ; v2(132.04,84.33) 132.33,84.62 UC1.AY16 ; UC1.G7 106.37,91.92 v2(106.77,91.52) ; v2(132.29,79.43) 132.29,78.59 UC1.AY24 ; UC1.AB2 UC1.AB1 118.17,97.01 v2(118.18,97.03) ; v2(132.27,76.22) 132.63,76.59 UC1.AY26
  BOTTOM w0.254: v2(155.25,136.33) 155.68,136.76 UV1.M32 156.12,136.33 156.42,136.33 v2(156.47,136.28) 156.47,136.28 156.52,136.33 157.42,136.33 157.71,136.61 157.71,137.18 UV1.L27 ; v2(172.33,124.18) 172.11,123.96 UV1.AH10 ; UC1.A20 101.87,81.42 102.48,80.81 v2(102.48,80.34) ; UC1.N22 110.67,79.91 v2(110.34,79.91) 109.77,80.49 UC1.L21 ; v2(128.4,93.66) 127.77,94.3 UC1.AP4 127.79,94.35 127.79,95.49 UC1.AP2 UC1.AP1 ; UC1.D16 103.6,84.62 103.29,84.92 v2(103.29,84.92) ; UV1.F18 165.21,141.56 164.81,141.96 v2(164.81,141.97) ; v2(111.37,72.92) 111.76,73.32 UC1.P30 ; UC1.AB4 118.17,94.32 v2(118.56,94.72) 119.37,94.72 UC1.AD4 ; v2(161.72,141.88) 162.04,141.56 UV1.F22 ; v2(181.29,162.75) 181.26,162.75 180.93,162.42 180.93,162.35 180.92,162.36 UV7.J8 ; v2(186.12,160.37) UV8.G8 ; UV1.P32 155.69,135.12 v2(155.31,134.75) ; v2(158.79,144.07) 158.89,143.97 UV1.B26 ; UV7.M9 180.12,164.85 v2(179.78,165.19) ; UV1.F14 168.58,141.56 168.92,141.91 168.91,141.91 168.91,141.9 v2(168.92,141.9) ; UV1.AB10 171.69,128.76 UV1.AC9 172.86,127.59 v2(172.88,127.59) ; v2(168.86,125.96) 168.46,126.36 UV1.AE14 ; v2(160.35,142.03) 160.35,141.7 UV1.F24 ; UV1.AD8 173.29,127.12 v2(173.66,126.76) ; UV1.AG27 157.79,124.76 v2(157.63,124.6) ; v2(187.07,166.37) 187.06,166.37 UV7.P1 ; v2(167.38,141.95) 166.99,141.56 UV1.F16 ; v2(155.19,139.26) 155.29,139.16 UV1.J31 ; v2(128.37,73.78) 128.66,73.78 128.8,73.64 129.05,73.64 UC1.AT30 ; v2(155.23,168.37) UV6.T9 ; UC1.AY4 132.82,94.38 v2(132.82,94.81) ; UC1.AU8 130.03,91.02 v2(129.58,91.47) ; UV8.D8 v2(186.12,158.77) 185.72,159.17 UV7.E2 ; v2(161.74,138.16) 161.94,138.36 UV1.K22 ; UV5.B3 157.28,156.77 157.51,156.54 v2(157.69,156.54) ; v2(174.45,140.35) 174.84,139.96 UV1.H6 ; v2(163.21,141.97) 163.21,141.95 163.61,141.56 UV1.F20 ; UC1.AT4 129.51,94.32 130.17,93.66 UC1.AU5 130.35,93.33 130.72,93.33 v2(130.72,93.34) 130.72,94.07 UC1.AV4 ; UV1.Y32 155.69,130.37 v2(155.34,130.72) ; U69.3 v2(169.84,28.01) ; v2(185.32,161.97) UV7.J2 ; UV1.B20 163.69,144.19 163.61,144.27 163.61,144.28 v2(163.6,144.29) ; UV1.AH32 155.08,123.96 154.72,123.61 v2(154.72,123.6) ; UV1.J27 158.09,138.88 158.46,138.51 158.46,138.21 158.19,137.94 157.71,137.94 UV1.K28 157.09,138.36 156.58,137.86 v2(156.5,137.86) ; v2(160.89,128.29) 160.55,127.96 UV1.AC24 ; UV1.H17 165.51,139.96 v2(165.3,140.17) ; UV1.F2 177.77,141.56 v2(177.88,141.67) ; UC1.T4 112.57,93.52 UC1.P5 111.87,93.52 v2(111.48,93.91) 111.77,94.2 UC1.P4 111.77,94.35 v2(111.44,94.68) ; v2(100.72,84.81) 101.48,84.81 UC1.A16 ; UC1.C3 102.93,94.96 v2(103.44,94.96) 103.44,94.44 UC1.D4 ; v2(162.44,165.19) 162.44,165.97 UV6.P1 ; v2(131.5,92.77) 131.07,92.34 UC1.AV7 131.74,91.54 131.96,91.54 132.48,91.02 UC1.AY8 ; v2(103.29,83.42) 103.67,83.04 UC1.D18 ; UV1.AG12 169.98,124.76 v2(169.69,124.47) ; UV1.AC27 158.15,127.96 v2(158.49,128.3) 158.84,127.96 UV1.AC26 ; UC1.AY22 132.67,79.81 v2(132.29,79.43) ; UC1.G26 106.07,76.58 v2(105.66,76.17) ; UV6.M9 155.52,164.77 v2(155.15,165.15) ; v2(155.14,125.41) 155.47,125.41 155.62,125.56 UV1.AF32 ; UC1.AV12 130.99,87.42 v2(130.4,86.83) 130.27,86.7 UC1.AU14 ; UV1.B16 166.91,143.58 166.91,143.89 v2(167.32,144.3) ; v2(157.6,129.74) 157.77,129.56 UV1.AA27 ; UC1.B2 102.17,95.51 v2(101.91,95.25) ; v2(174.54,141.91) 174.89,141.56 UV1.F6 ; UV1.K32 155.22,138.36 v2(155.11,138.25) ; UV7.P9 180.12,166.37 v2(180.52,165.97) ; UC1.AK4 124.17,94.72 123.48,94.72 v2(123.33,94.86) 122.99,94.52 122.99,94.34 UC1.AH4 ; v2(175.32,128.45) 175.2,128.45 UV1.AB6 ; v2(135.72,84.51) 135.61,84.62 UC1.BC16 ; UV1.AE27 158.15,126.36 v2(158.51,126.72) 158.54,126.75 159.06,126.75 159.47,127.16 UV1.AD25 ; UV8.F9 186.52,159.99 v2(186.9,160.37) 186.52,160.76 UV7.G1 ; U69.13 v2(171.34,22.2) ; UC1.T30 113.71,73.66 113.71,73.67 v2(113.7,73.69) ; UC1.AY20 131.87,80.62 UC1.AW22 131.54,79.89 v2(131.54,79.46) ; v2(131.56,77.06) 131.07,77.54 UC1.AV25 131.07,78.22 UC1.AU23 129.61,78.36 129.36,78.36 128.82,77.82 UC1.AR25 ; v2(20.69,38.61) DI1.8 DI1.3 ; UC1.B8 v2(102.47,91.52) ; UV1.B6 174.7,143.75 v2(174.7,144.1) ; UV6.G1 162.03,160.76 v2(162.42,160.37) 162.03,159.99 UV5.F9 ; v2(160.83,161.97) UV6.J2 ; UV1.J7 174.11,139.16 v2(174.48,138.79) 174.89,138.38 UV1.K6 ; UV7.B1 186.52,156.68 v2(186.82,156.37) 186.52,156.07 UV8.A9 ; v2(174.4,134.38) 174.4,134.53 174.89,135.02 UV1.P6 ; UV1.F12 170.13,141.56 v2(170.49,141.92) ; v2(128.48,91.55) 128.48,92.08 128.97,92.56 UC1.AR6 ; UC1.D12 103.98,87.82 v2(104.13,87.96) ; v2(156.13,144.36) 156.13,144.32 UV1.A30 ; UV1.AH28 157.25,123.96 v2(156.93,124.28) ; U69.17 169.34,22.5 v2(169.58,22.26) 169.84,22.53 U69.16 ; v2(162.09,144.52) 162.16,144.45 162.16,143.63 UV1.B22 ; UV1.AB32 155.6,128.85 v2(155.15,128.85) ; US2.3 v2(180.29,31.85) ; UV1.AD32 155.68,127.17 155.24,127.17 v2(155.16,127.09) ; RP34.4 187.85,140.18 188.56,139.47 v2(188.56,138.77) ; UV1.F26 158.49,141.16 v2(158.45,141.16) 158.45,141.12 UV1.G27 ; UV1.F8 173.26,141.53 173.26,140.79 UV1.G8 173.29,140.7 v2(173.64,140.35) ; UV8.D1 v2(179.72,158.77) UV8.E1 ; v2(132.18,92.79) 132.35,92.62 UC1.AY6 ; v2(187.06,167.97) UV7.T1 ; v2(133.19,88.05) 133.19,88.06 132.88,88.06 132.67,87.84 UC1.AY12 ; v2(155.23,166.77) UV6.P9 ; UV1.AB24 160.49,128.74 v2(160.06,128.31) ; UC1.M4 110.17,94.03 v2(110.39,93.81) ; v2(155.33,134.01) 155.69,133.65 UV1.T32 ; v2(174.47,125.99) 174.1,126.36 UV1.AE7 ; v2(135.83,88.11) 135.72,88.11 135.41,87.81 134.68,87.81 UC1.BC12 ; v2(165.58,144.77) 165.58,144.73 165.29,144.44 UV1.B18 ; v2(158.3,45.34) 158.04,45.34 157.87,45.16 PU600.8 ; UV1.T6 174.69,133.56 v2(174.4,133.27) ; UC1.AP27 127.77,75.78 v2(128.39,76.41) ; v2(104.28,89.25) 103.84,89.25 UC1.D10 ; UV6.B1 162.16,156.77 v2(162.5,156.43) 162.04,155.97 UV5.A9 ; v2(171.8,144.47) 171.8,144.47 171.69,144.37 UV1.B10 ; v2(169.94,144.04) 170.07,143.9 170.07,143.58 UV1.B12 ; UC1.A12 UC1.B12 102.82,87.82 v2(103.1,87.54) ; v2(174.42,136.87) 174.52,136.76 UV1.M6 ; UV1.B8 173.29,143.44 v2(173.6,143.13) ; UC1.BB1 134.36,96.72 134.7,97.07 134.7,97.36 v2(134.94,97.6) ; v2(171.86,142.04) 171.69,141.87 UV1.F10 UV1.G10 ; v2(179.7,156.38) 180.09,156.77 UV7.B9 ; UV6.B9 155.63,156.68 v2(155.32,156.36) ; UV5.E1 v2(155.23,158.77) UV5.D1 ; UC1.BC20 134.43,81.42 133.86,82 v2(133.86,82.54) ; UC1.A8 v2(101.67,91.53) ; v2(175.46,127.48) 175.14,127.16 UV1.AD6 ; v2(166.5,127.52) 166.02,128.01 165.84,128.01 UV1.AC17 ; UV1.K2 177.75,138.36 v2(177.87,138.24) ; v2(156.83,162.77) UV6.J8 ; UV5.D8 v2(161.63,158.77) 161.23,159.17 UV6.E2 ; v2(155.31,132.37) 155.69,131.99 UV1.V32 ; v2(114.48,95.52) UC1.V2 ; UV1.C32 155.2,143.16 v2(155.15,143.11) ; v2(161.63,160.37) UV5.G8 ; v2(160.18,144.78) 160.17,144.79 160.17,144.8 160.49,144.47 UV1.B24 ; v2(177.78,143.67) 177.29,143.17 UV1.C1 UV1.A3 ; UV1.H2 177.75,139.96 v2(177.82,140.03) ; UV7.G9 180.14,160.77 v2(180.53,160.38) ; UV1.E28 157.29,142.26 v2(157.69,141.86) ; UV7.T9 v2(180.52,167.57) ; v2(180.52,158.77) UV7.E8 ; UC1.AY10 132.63,89.38 v2(132.19,89.38) ; UV6.T1 162.03,167.97 v2(161.64,167.58) ; v2(182.23,156.64) 182.1,156.77 UV8.B3 ; v2(156.03,158.77) UV6.E8 ; v2(162.4,164.41) UV6.M1 ; v2(186.92,164.37) UV7.M1 ; v2(109.07,95.52) UC1.K2 ; UC1.AT19 129.53,82.62 v2(130.1,82.04) 130.27,81.88 UC1.AU20 130.27,81 v2(130.1,80.84) 129.49,80.22 UC1.AT22 ; UV1.B14 v2(168.49,144.17) ; v2(155.23,160.37) UV6.G9
  BOTTOM w0.305: UC1.K10 v2(109.17,88.62) UC1.L12 v2(110.37,87.42) 110.97,86.82 UC1.N13 v2(111.57,86.22) 112.17,85.62 UC1.P15 UC1.T16 v2(113.97,83.82) 114.57,83.22 UC1.U18 115.01,83.22 v2(115.53,82.7) 115.77,82.46 UC1.W19 116.32,81.46 v2(116.32,81.15) 116.65,80.82 UC1.Y21 116.97,80.82 UC1.AB22 118.17,79.62 v2(118.77,79.02) UC1.AD24 119.37,78.42 v2(119.97,77.82) ; 93,165.02 93,165.09 92.8,165.3 JEDP.25 ; 93,165.02 93.3,165.32 JEDP.26 ; 93,165.02 v2(93,163.96) ; v2(110.28,77.99) 109.85,78.42 UC1.L24 109.61,78.42 108.57,79.47 UC1.K22 108.57,79.62 v2(107.9,79.62) 107.9,79.99 UC1.J22 ; 92.11,164.22 91.8,164.53 JEDP.23 ; 92.11,164.22 92.11,164.29 92.3,164.48 JEDP.24 ; 92.11,164.22 v2(92.11,163.97) ; UC1.AV9 131.08,89.83 131.08,90.27 131.01,90.35 v2(130.98,90.35) ; UC1.K27 108.69,75.72 v2(109.09,75.32) ; UC1.AL10 125.37,88.74 v2(125.46,88.65) ; v2(128.48,91.55) 128.12,91.92 UC1.AP7 ; UC1.Y5 117.17,93.52 v2(117.57,93.12) ; v2(129.81,84.33) 130.38,84.33 UC1.AV15 ; v2(128.36,74.41) 128.88,74.92 UC1.AR28 ; v2(130.33,89.29) 130.27,89.22 UC1.AU11 ; UC1.AN28 126.68,74.92 v2(127.17,74.43) ; v2(169.58,57.78) 169.58,57.21 170.01,56.78 JNGFF.18 ; UC1.G20 106.07,81.22 v2(106.47,80.82) ; JHDD1.6 190.61,31.13 v2(190.42,31.32) ; UC1.AL19 124.97,82.02 v2(124.36,82.63) 124.17,82.82 UC1.AK18 123.57,83.82 v2(123.57,83.82) 122.97,84.42 UC1.AH16 122.97,84.42 121.77,85.62 UC1.AG15 v2(121.17,86.22) 120.57,86.82 UC1.AE13 120.57,86.82 UC1.AD12 v2(118.77,88.62) UC1.AB10 ; UV1.H14 168.48,139.96 168.9,140.38 v2(168.9,140.54) ; v2(110.46,74.52) 110.06,74.92 UC1.L28 ; v2(190.42,29.77) 190.56,29.63 JHDD1.9 ; UC1.F22 105.27,80.02 v2(105.67,79.62) 106.07,79.22 UC1.G23 ; UC1.J25 107.75,77.9 v2(108.29,77.9) ; v2(128.09,77.94) 128.21,77.82 UC1.AR25 ; UC1.AN9 126.57,90.09 v2(126.9,89.75) 126.57,89.42 UC1.AN10 ; v2(105.67,77.22) 105.27,77.62 UC1.F25 ; JNGFF.55 162.45,47.52 v2(162.29,47.68) ; UC1.N27 111.14,75.72 v2(111.57,75.29) ; JNGFF.25 162,55.03 161.58,54.6 161.58,53.87 v2(161.85,53.59) 162.38,53.59 162.44,53.52 JNGFF.31 ; JEDP.29 v2(94.8,163.87) ; JNGFF.37 165,52.03 v2(165.12,51.9) ; UC1.L25 109.97,77.32 110.33,76.96 v2(110.33,76.82) ; UC1.T10 v2(113.97,88.62) 114.57,88.02 UC1.U12 v2(115.17,87.42) UC1.W13 115.77,86.79 v2(116.44,86.12) 116.94,85.62 UC1.Y15 116.97,85.62 UC1.AB16 118.17,84.42 v2(118.77,83.82) UC1.AD18 119.37,83.22 120.57,82.02 UC1.AE19 120.57,82.02 v2(121.17,81.42) UC1.AG21 121.77,80.82 122.96,79.62 UC1.AH22 122.97,79.62 v2(123.57,79.02) ; JEDP.16 v2(88.3,163.91) ; UV1.P9 172.49,134.68 v2(172.88,134.29) ; UV1.AA11 171.06,129.59 v2(171.54,129.59) 171.69,129.74 UV1.Y10 ; JNGFF.49 v2(162.14,49.03) ; UC1.L15 UC1.N16 v2(111.57,83.82) 112.17,83.22 UC1.P18 UC1.T19 113.37,82.02 v2(113.97,81.42) 114.57,80.82 UC1.U21 114.63,80.82 v2(115.41,80.04) 115.77,79.68 UC1.W22 115.77,79.62 v2(116.37,79.02) 116.97,78.42 UC1.Y24 116.97,78.42 v2(117.57,77.82) ; UC1.AD9 119.61,90.32 v2(120.02,89.91) 120.57,89.36 UC1.AE10 v2(121.17,88.62) UC1.AG12 121.77,88.02 122.97,86.82 UC1.AH13 123.04,86.82 v2(123.51,86.35) 124.17,85.69 UC1.AK15 124.17,85.19 v2(124.34,85.01) 124.94,84.42 UC1.AL16 ; JEDP.13 v2(86.8,163.96) ; UV1.K11 171.09,138.76 v2(171.24,138.76) ; UC1.AN15 126.57,85.62 v2(127.17,85.02) ; JNGFF.67 v2(162.24,44.52) ; UC1.BC32 135.38,72.14 v2(135.38,72.26) ; UC1.AL22 125.21,79.62 v2(124.58,80.25) 124.17,80.66 UC1.AK21 124.16,80.82 v2(123.57,81.42) 122.97,82.02 UC1.AH19 122.97,82.02 121.77,83.22 UC1.AG18 v2(121.17,83.82) 120.57,84.42 UC1.AE16 120.57,84.42 119.37,85.62 UC1.AD15 119.31,85.62 118.82,86.12 v2(118.82,86.21) 118.72,86.21 118.17,86.77 UC1.AB13 UC1.Y12 116.97,88.02 v2(116.37,88.62) UC1.W10 ; JHDD1.12 190.37,28.13 v2(190.35,28.14) ; UC1.U24 114.57,78.42 v2(115.17,77.82) ; v2(127.16,76.42) 127.16,76.73 UC1.AN25 ; UC1.F9 105.27,89.62 v2(105.67,89.22) ; JNGFF.10 169.97,58.78 169.34,59.41 v2(169.34,59.5) ; JEDP.36 98.3,164.99 v2(99.57,163.72) ; UC1.J19 107.38,82.33 v2(107.38,82.05) ; UC1.AG9 121.82,90.32 122.92,89.22 UC1.AH10 122.97,89.09 v2(123.5,88.56) 123.5,88.56 124.04,88.02 UC1.AK12 124.17,88.02 v2(124.77,87.42) ; UC1.T22 113.09,79.62 v2(112.82,79.89) 112.17,80.54 UC1.P21 112.17,80.82 v2(111.57,81.42) 110.97,82.02 UC1.N19 110.97,82.02 UC1.L18 ; JNGFF.1 162.65,63.03 162.17,63.5 162.17,64.54 v2(162.79,65.16) ; UC1.J15 107.67,85.02 107.93,84.76 107.93,84.32 108.36,83.89 v2(108.36,83.81) ; UC1.AT22 130.27,79.42 UC1.AU23 ; v2(105.67,82.02) 105.27,82.42 UC1.F19 106.07,83.42 UC1.G17 ; UC1.AP22 127.77,79.31 v2(128.05,79.02) ; UV1.H20 163.49,140.12 163.25,140.36 v2(162.89,140.36) ; v2(110.37,93.12) 109.97,93.52 UC1.L5 ; JEDP.19 89.8,163.99 v2(89.81,163.98) ; v2(107,74.52) 107,74.56 UC1.J28 ; UC1.AN18 126.57,83.22 v2(127.17,82.62) ; JNGFF.61 v2(162.24,46.03) ; v2(107.97,93.12) 107.57,93.52 UC1.J5 ; v2(127.17,80.22) 126.57,80.82 UC1.AN21 ; v2(129.42,76.12) 129.73,76.12 130.13,75.72 UC1.AU27 ; UC1.U5 114.77,93.52 v2(115.17,93.12) ; UC1.N10 v2(111.57,88.62) UC1.P12 v2(112.77,87.42) UC1.T13 v2(113.97,86.22) 114.57,85.62 UC1.U15 114.9,85.62 v2(115.51,85.01) 115.77,84.75 UC1.W16 115.77,84.42 v2(116.24,83.95) UC1.Y18 UC1.AB19 118.17,82.02 v2(118.77,81.42) UC1.AD21 120.57,79.62 UC1.AE22 120.57,79.62 v2(121.17,79.02) ; JNGFF.43 164.82,50.52 v2(165.01,50.71)
  BOTTOM w0.33: JNGFF.7 v2(164.9,61.52) ; v2(185.29,37.15) 185.16,37.02 RS24.2
  BOTTOM w0.356: JDIMM1.31 97.5,24.08 97.06,23.63 96.04,23.63 v2(95.96,23.71) 95.7,23.97 JDIMM1.25 ; JDIMM2.139 v2(124.1,39.68) 124.15,39.73 125.53,39.73 125.9,39.36 JDIMM2.145 ; JDIMM2.2 80.6,31.32 79.96,31.95 v2(78.72,31.95) ; v2(89.7,31.56) 89.6,31.46 JDIMM2.32 ; v2(97.4,39.56) 96.89,39.56 96.5,39.17 JDIMM2.55 ; JDIMM1.178 v2(144,15.42) ; JDIMM1.196 v2(149.4,15.42) ; JDIMM1.38 v2(99.6,15.11) ; JDIMM2.134 122.6,29.09 123.91,27.77 v2(124.5,27.77) ; v2(96.84,31.42) 96.6,31.42 96.2,31.02 JDIMM2.54 ; JDIMM2.201 142.7,39.26 v2(142.94,39.5) ; JDIMM2.127 120.5,39.33 v2(120.71,39.54) ; JDIMM1.72 v2(109.8,15.11) ; v2(93.88,23.64) 93.9,23.66 JDIMM1.19 ; JDIMM1.189 v2(147.3,23.62) ; v2(132.24,23.62) 132.3,23.68 JDIMM1.139 ; JDIMM1.20 94.2,15.63 v2(93.42,14.85) ; JDIMM2.3 80.9,40.11 v2(80.32,40.69) ; JDIMM2.150 127.4,31.23 v2(127.49,31.31) ; JDIMM2.133 122.3,39.38 v2(122.43,39.51) ; JDIMM1.133 130.5,23.71 v2(130.42,23.64) ; JDIMM2.66 99.8,30.97 v2(99.52,31.24) ; JDIMM1.9 90.9,26.02 90.58,26.34 89.75,26.34 v2(89.61,26.48) 89.53,26.48 89.1,26.05 JDIMM1.3 ; v2(97.85,31.3) 97.85,31.31 98,31.15 JDIMM2.60 ; v2(126.59,31.98) 126.59,31.83 125.6,30.84 JDIMM2.144 ; JDIMM1.168 v2(141,15.42) ; v2(91.47,39.56) 91.1,39.19 JDIMM2.37 ; JDIMM2.26 87.8,30.96 87.31,31.46 v2(85.9,31.46) 86,31.36 JDIMM2.20 ; JDIMM2.161 130.7,39.26 130.27,39.69 v2(129.53,39.69) ; JDIMM1.150 v2(135.6,15.39) ; JDIMM1.61 106.5,23.96 106.94,23.52 ; JDIMM2.13 83.9,39.27 84.17,39.54 v2(85.7,39.54) JDIMM2.19 ; JDIMM2.179 136.1,39.29 v2(136.36,39.55) ; JDIMM2.151 127.71,38.18 v2(127.71,39.55) 128.53,39.55 128.9,39.18 JDIMM2.155 ; JDIMM1.172 v2(142.2,15.42) ; JDIMM1.138 v2(132,15.39) ; JDIMM1.2 88.8,15.08 v2(88.77,15.05) ; JDIMM1.144 v2(133.8,15.39) ; JDIMM1.55 104.7,23.97 v2(104.44,23.71) ; v2(138.98,39.51) 139.09,39.51 139.1,39.51 JDIMM2.189 ; v2(139.01,28.56) 139.01,28.66 139.4,29.06 JDIMM2.190 ; v2(136,28.51) 136,28.54 135.8,28.73 JDIMM2.178 ; JDIMM2.9 82.7,39.4 v2(82.9,39.6) ; JDIMM1.145 134.1,23.73 v2(133.98,23.61) ; JDIMM1.190 v2(147.6,15.42) ; v2(140.21,26.48) 140.7,25.99 JDIMM1.167 ; JDIMM1.185 v2(146.1,26.34) ; v2(102.77,26.29) 102.9,26.16 JDIMM1.49 ; JDIMM1.14 92.4,14.87 v2(92.43,14.83) ; JDIMM1.66 v2(108,15.11) ; JDIMM2.61 98.3,39.56 v2(98.46,39.72) 98.97,39.72 99.5,39.18 JDIMM2.65 ; JDIMM2.25 87.5,39.61 v2(87.5,39.61) ; JDIMM2.172 134,30.83 134.16,30.99 v2(134.16,31.29) 134.07,31.38 133.03,31.38 132.8,31.16 JDIMM2.168 ; JDIMM1.155 137.1,25.91 136.71,26.3 v2(135.95,26.3) 135.9,26.26 JDIMM1.151 ; JDIMM1.54 v2(104.4,15.11) ; JDIMM1.37 99.3,24.04 v2(98.99,23.73) ; JDIMM1.48 v2(102.6,15.11) ; v2(121.5,31.5) 121.36,31.5 120.8,30.94 JDIMM2.128 ; JDIMM2.31 v2(89.3,39.54) ; JDIMM1.71 109.5,23.29 v2(109.29,23.08) ; JDIMM2.14 84.2,31.29 v2(84.29,31.38) ; v2(138.48,23.51) 138.9,23.94 JDIMM1.161 ; JDIMM1.134 v2(130.8,15.39) ; JDIMM2.184 137.6,31.18 v2(137.27,31.51) ; JDIMM1.60 v2(106.2,15.11) ; JDIMM1.128 v2(129,18.1) ; JDIMM2.173 134.3,39.37 134.05,39.61 v2(133.89,39.61) 132.71,39.61 132.5,39.4 JDIMM2.167 ; JDIMM1.13 92.1,23.66 v2(92.12,23.64) ; v2(82.57,32.74) 82.4,32.57 JDIMM2.8 ; JDIMM2.38 91.4,31.02 91.66,31.28 v2(92.14,31.28) 92.95,31.28 93.2,31.04 JDIMM2.44 ; JDIMM2.156 129.2,30.95 129.03,31.12 v2(129.03,31.29) 129.05,31.32 130.77,31.32 131,31.08 JDIMM2.162 ; v2(142.89,26.3) 142.5,25.91 JDIMM1.173 ; v2(124.5,28.57) 124.31,28.57 123.8,29.09 JDIMM2.138 ; JDIMM2.195 140.9,39.93 141.03,40.06 v2(141.86,40.06) ; JDIMM2.43 v2(92.9,39.54) ; JDIMM1.179 v2(144.3,23.46) ; JDIMM1.8 v2(90.6,18.54) ; 107.7,24.09 JDIMM1.65 ; v2(101.16,39.88) 101.3,39.74 JDIMM2.71 ; v2(108.07,22.2) 107.38,22.89 ; JDIMM1.44 v2(101.4,15.11) ; v2(94.54,28.54) 94.4,28.69 JDIMM2.48 ; v2(150.9,26.34) JDIMM1.201 ; JDIMM2.72 101.6,31.11 v2(101.78,31.29) ; JDIMM1.32 v2(97.8,14.97) ; JDIMM1.195 v2(149.1,26.34) ; JDIMM2.49 v2(94.7,39.54) ; v2(140.95,31.27) 141.2,31.02 JDIMM2.196 ; JDIMM1.156 v2(137.4,15.39) ; JDIMM2.185 v2(137.9,39.54) ; JDIMM1.43 101.1,23.75 v2(100.76,23.41) ; JDIMM1.26 96,15.59 v2(96.61,14.97) ; JDIMM1.162 v2(139.2,15.39) ; JDIMM1.184 v2(145.8,15.42)
  BOTTOM w0.381: v2(169.37,130.21) 168.92,129.76 UV1.AA13 ; PQ4.1 187.51,67.64 188,68.14 v2(188,68.29) ; v2(169.36,132.29) 168.89,131.81 UV1.V13 UV1.Y15 167.89,130.69 167.39,130.19 v2(167.37,130.19) 167.37,130.17 166.96,129.76 UV1.AA16 ; C2619.2 56.51,50.93 56.68,50.75 Q2516.4 ; PQ4.4 184.67,66.34 184.44,66.1 184.44,65.75 184.69,65.49 v2(184.92,65.49) ; Q2507.1 v2(54.24,49.66) ; v2(167.77,127.49) 167.77,128.64 UV1.AB15 ; v2(163.58,132.31) 164.04,132.76 UV1.U20 164.89,133.56 UV1.T18 165.14,133.56 v2(165.63,134.05) 166.09,134.51 UV1.R17 166.89,135.36 UV1.N16 ; v2(185.08,136.47) 184.73,136.83 U1.4 ; v2(163.6,130.14) 163.6,130.27 UV1.Y20 UV1.V18 v2(165.62,132.29) UV1.U17 UV1.T16 v2(167.35,134.02) UV1.R15 UV1.N13 168.89,135.71 169.74,136.56 UV1.M12 ; UV1.U9 172.49,132.96 v2(172.23,133.23) ; UV1.T11 170.87,133.56 v2(170.42,134.01) 170.89,134.48 UV1.R11 ; v2(163.58,134.93) 163.09,135.42 UV1.N21 ; v2(165.58,130.2) 166.09,130.72 UV1.Y17 166.09,130.96 UV1.V16 166.9,131.76 v2(167.39,132.24) 167.89,132.75 UV1.U15 168.69,133.56 UV1.T13 168.89,133.56 v2(169.38,134.05) UV1.R12 UV1.N11 ; v2(184.28,133.26) 184.34,133.32 UV11.5 ; Q2507.4 55.54,48 v2(55.36,47.82) ; v2(177.61,81.12) 177.52,81.03 UE3.3 ; v2(171.49,131.97) 171.1,131.97 UV1.V11 ; UV1.T21 163.09,133.63 v2(163.55,134.08) 164.02,134.56 UV1.R20 UV1.N18
  BOTTOM w0.432: Q52.1 v2(53.67,27.56) ; Q52.4 v2(52.37,29.44)
  BOTTOM w0.508: PC1109.2 189.77,106.49 v2(189.64,106.62) ; v2(192.02,6.4) 191.96,6.34 RA31.2 ; v2(162.79,65.16) 163.83,64.13 JNGFF.68 ; v2(153,101.41) 152.77,101.18 C939.2 ; CV117.2 151.9,161.08 v2(151.9,161.09) ; CM4.2 v2(173.54,39.88) ; v2(149.82,107.54) 150.03,107.76 C940.2 ; v2(153.73,99.81) 153.85,99.94 C46.2 ; v2(198.04,42.6) CI46.2 CI47.2 ; v2(143.54,88.29) 143.37,88.29 143.03,88.63 R691.1 ; v2(89.48,8.42) 89.03,8.87 JDIMM1.205 ; CV135.2 188.36,160.83 v2(187.98,161.21) ; CV132.2 163.92,160.88 163.52,161.27 v2(163.52,161.8) ; JSPK.5 v2(72.68,4.27) ; C160.2 v2(22.68,22.68) ; v2(190.28,158.85) 189.92,158.85 CV180.2 ; CV102.2 153.65,164.01 v2(154.2,164.55) ; v2(14.09,12.12) 13.6,11.62 C119.2 ; C32.1 123.12,102.22 C31.1 123.11,101.6 v2(123.12,101.59) 123.37,101.33 R952.2 ; CV131.2 151.9,160.07 v2(151.9,160.07) ; CE26.2 97.53,136.4 97.85,136.08 v2(97.85,134.18) ; C27.2 141.98,93.29 v2(142.15,93.46) ; v2(165.65,156.68) 164.99,156.02 164.38,156.02 CV122.2 ; v2(23.54,18.43) CR7.2 24.68,18.86 CR8.2 ; PR779.1 v2(132.02,169.53) ; v2(194.95,36.4) 195,36.36 JHDD1.14 ; v2(142.28,54.39) 142.27,54.38 140.2,54.38 139.66,54.93 CLRP1.2 ; v2(186.62,25.13) RS36.2 RS18.2 RS22.1 RS23.2 ; CV109.2 CV173.2 v2(151.89,167.18) ; v2(111.05,170.81) 110.2,169.96 PC749.1 PC748.2 ; PC759.2 v2(120.21,174.05) ; C828.1 v2(167.38,29.65) ; v2(168.65,28.77) 168.46,28.57 C665.1 ; C686.2 130.41,103.71 v2(129.47,104.65) ; C635.2 156.81,87.19 v2(156.76,87.13) ; CV149.2 177.63,168.4 177.31,168.08 v2(177.31,167.49) ; RV151.1 182.36,136.58 v2(182.41,136.63) ; CX23.2 CX26.2 v2(19.32,70.54) ; R638.2 142.18,83.25 v2(142.79,82.64) ; CX27.2 CX24.2 v2(19.37,66.85) ; v2(181.9,6.41) 181.48,6.41 181.27,6.62 CA56.2 180.32,6.62 CA55.2 ; v2(12.93,16.52) 12.87,16.59 RR1.2 ; CX1.2 98.74,162.31 v2(98.86,162.43) ; CS42.2 186.96,35.57 187.66,35.57 v2(187.8,35.71) ; RA29.2 v2(185.67,23.05) ; JSPK.6 v2(74.1,7.71) ; JFAN.5 v2(90.34,138.43) ; PC1121.2 177.53,97.17 175.1,97.17 v4(174.45,97.82) 174.11,98.16 PC1115.2 PC1106.2 ; v2(189.59,133.3) 190.25,133.3 190.51,133.55 CV170.1 ; v2(169.03,87.5) 169.28,87.76 PR1105.1 ; v2(178.99,126.07) 179.09,125.97 179.09,125.97 CV214.2 ; R148.2 v2(166.94,20.41) ; v2(84.51,160.82) 83.81,160.82 83.55,160.55 CX8.2 ; v2(197.15,39.87) 196.78,39.5 UI7.2 ; v2(71.24,80.91) 71.86,80.91 72.41,80.36 CLIP1.1 ; JEDP.41 v2(102,171.13) ; v2(151.9,157.02) 151.9,157.02 CV130.2 ; v2(188.41,36.26) 188.77,35.9 CS6.2 189.51,35 CS5.2 ; v2(13.34,21.41) 13.33,21.41 CR1.2 ; CE45.2 v2(179.48,83.96) ; C1007.2 C1006.2 C1005.2 152.94,69.82 152.04,68.92 v2(152.04,68.86) ; R950.2 116.38,100.79 v2(116.69,100.47) ; v2(153.47,12.57) 152.95,12.05 JDIMM1.206 ; PR731.2 115.2,163.27 114.86,162.94 v2(114.56,162.94) ; v2(19.32,63.17) CX28.2 CX29.2 ; CL41.1 29.58,172.73 v2(29.58,173.44) ; PC802.2 35.05,53.4 v2(35.3,53.15) ; PC1203.2 v2(199.7,131.19) ; v2(181.55,152.75) CV140.2 ; Q89.3 v2(173.84,81.84) ; v2(165.33,157.24) 164.79,156.69 CV119.2 ; CX6.2 76.71,162.5 v2(76.31,162.09) ; CV18.2 v2(164.18,119.16) 164.18,118.18 YV1.2 ; PC801.1 v2(35.74,49.02) ; C2618.2 44,67.94 v2(43.81,67.75) ; CV127.2 151.9,159.05 v2(151.9,159.05) ; PR602.2 160.09,45.96 160.1,45.97 v2(160.1,46.22) ; v2(187.74,28.22) 187.72,28.21 CS27.2 ; CI44.2 v2(200.72,42.29) ; v2(177.35,155.32) CV137.2 ; v2(178.74,159.64) CV148.2 ; C912.2 126.93,100.13 v2(127.02,100.13) ; v2(159.94,120.74) 160.62,120.06 CV17.2 ; RA1113.1 v2(176.71,10.74) ; v2(159.87,42.75) PR605.2 PC601.2 ; CL7.2 46.74,167.08 v2(47.05,167.39) ; JFAN.3 94.56,136.92 94.56,136.45 v2(94.61,136.4) ; C621.1 v2(190.87,139.99) ; PC803.2 v2(31.04,46.35) ; CR6.2 v2(20.4,18.81) ; CX2.2 CX11.2 79.47,159.04 v2(78.96,159.04) ; CR9.2 v2(22.05,21.49) ; v2(78.43,156.1) 78.43,154.85 79.03,154.25 CX7.2 ; v2(193.6,142.68) 193.1,142.68 192.78,142.37 PR1204.2 ; v2(190.21,157.53) CV150.2 ; v2(176.55,21.72) C43.2 ; v2(164.04,19.85) 163.51,19.32 R452.1 ; C797.2 v2(110.77,104.12) ; v2(190.29,167.31) CV144.2 ; v2(19.87,59.49) CX30.2 ; v2(190.96,147.33) 190.96,147.93 v4(190.32,148.58) 189.93,148.96 U74.2 ; v2(124.52,162.05) 124.22,161.75 PC1014.2 ; CL8.2 v2(47.05,168.27) ; JHDD2.11 v2(200.1,26.97) ; v2(130.1,100.08) 130.14,100.08 130.42,100.36 130.42,101.16 129.91,101.68 R696.1 ; v2(179.89,67.97) PC13.1 PR26.1 ; CLIP4.1 v2(66.05,18.33) ; C73.2 v2(165.24,23.96) ; CE4.2 190.99,78.94 v2(190.42,78.37) 190.94,77.85 CE37.2 ; v2(121.72,170.94) 122.04,171.25 PC758.2 ; v2(194.49,74.59) 194.46,74.56 194.02,74.56 193.69,74.23 CE10.1 ; v2(194.62,68.97) 194.61,68.96 CE13.1 ; CR3.1 v2(11.89,22.25) ; v2(164.78,159.51) CV179.2 ; RA30.2 195.17,21.36 v2(195.17,22.15) ; PC1205.2 201.82,141.57 v2(201.73,141.48) ; U2.4 36.3,59.31 Q93.3 v2(34.88,58.83) ; JHDD2.5 v2(201.18,30.48) ; RV44.2 CV100.2 165,164.79 v2(164.8,164.59) RV46.2 ; C668.1 v2(172.26,28.05) ; CV216.2 182.16,126.19 v2(182.03,126.33) ; PR1106.1 v2(173.16,87.76) ; v2(135.45,102.65) 135.03,102.65 134.71,102.34 R90.2 ; v2(190.33,158.19) 190.9,158.19 191.14,157.95 C620.1 ; RX26.2 RX9.2 94.46,158.85 v2(94.46,158.15) ; C667.2 v2(175.55,26.01) ; v2(151.9,158.04) 151.9,158.04 CV126.2 ; RS21.2 v2(182.49,37.13) ; PR727.2 PR753.1 v2(111.98,171.74) ; v2(161.98,17.65) 161.66,17.65 161.49,17.48 C41.2 R30.1 ; PC1402.2 v2(202.39,159.26) ; v2(177.3,160.93) 177.38,161.01 CV142.2 ; PC1128.2 v2(172.09,100.01) ; v2(181.51,26.56) 180.97,27.1 RS31.2 ; v2(111.05,171.72) 111.05,173.09 111.37,173.42 PC751.1 112.14,174.26 PC752.1 ; CV118.2 152.04,170.23 v2(152.04,170.23) ; v2(82.8,155.12) 82.91,155.01 UX4.2 ; CV151.2 190.65,154.43 v2(190.87,154.2) ; CV125.2 151.9,156 v2(151.9,156.01) ; v2(190.21,156.51) CV146.2 ; JEDP.42 78.57,169.53 78.31,169.79 v2(78.31,170.36) ; PR751.1 v2(123.82,174.05) ; v2(182.58,128.73) 182.88,128.43 RV83.2 ; CA64.1 v2(176.33,13.03) ; RE67.1 183.84,67.39 v2(184.05,67.17) ; v2(177.34,156.82) CV141.2 ; PR531.2 v2(63.11,29.27) ; CV143.2 177.4,165.71 v2(177.3,165.81) ; C62.2 v2(165.3,21.25) ; R42.1 122.48,101.22 v2(122.1,101.6) 121.55,101.04 R644.2 ; PC804.2 25.77,47.85 26.22,48.3 v2(26.22,49.14) ; v2(186.44,152.75) CV147.2 ; v2(57.69,17.09) 57.55,16.95 57.55,16.55 57.25,16.25 JRTC.2 ; v2(177.27,162.71) 177.27,164.1 177.64,164.46 RV56.2 ; C2619.2 v2(55.81,51.69) ; PC1201.2 193.99,131.51 v2(194.43,131.06) 194.87,131.51 PR1203.2 ; PH1101.1 v2(171.84,100.84) ; R709.1 137.72,88.59 v2(137.4,88.91) ; PC1413.2 v2(199.64,171.13) ; C157.2 v2(10.72,14.73) ; CM10.2 v2(170.62,40.44) ; R616.1 v2(86.42,160.52) ; RV73.1 v2(183.13,134.57) ; CX25.2 19.11,73.23 v2(19.44,72.9) ; v2(191.7,137.73) 191.06,137.73 CV169.1 ; v2(155.76,152.75) CV172.2 ; JDIMM2.205 79.15,44.37 v2(80.34,43.18) ; C120.2 v2(23.11,13.4) ; PC402.2 v2(195.83,131.06) ; v2(198.65,171.17) 198.65,170.81 198.34,170.51 PC1414.2 ; C796.2 108.26,104.52 v2(108.26,105.16) ; JHDD1.13 195,27.23 v2(195.03,27.25) ; CM7.2 171.51,40.77 v2(171.89,40.39) 172.4,40.89 CM9.2 ; v2(135.93,105.23) 134.88,104.17 C682.2 ; v2(195,8.76) 194.3,8.06 RA32.2 ; JFAN.4 v2(92.88,142.65) ; JHDD2.12 v2(198.84,35.78) ; CE46.2 v2(176.85,83.96) ; C636.2 159.63,81.47 159.95,81.79 v2(160.08,81.79) ; RZ591.2 v2(53.73,26.21) ; v2(175.7,12.57) 175.48,12.36 CA21.2 ; v2(186.3,134.66) 186.66,134.3 187.72,134.3 188.09,133.93 RV74.1 ; v2(190.29,168.32) CV138.2 ; CR5.2 v2(15.67,22.48) ; RX36.2 v2(84.58,158.37) ; PR1408.2 v2(202.39,161.92) ; RS37.2 188.21,32.32 v2(188.59,32.7) ; CV165.2 v2(190.29,169.34) ; v2(16.63,35.1) CI15.2 17.38,35.05 UI5.2 ; CX5.2 77.07,164.36 v2(76.84,164.59) ; v2(12.27,20.64) 12.25,20.66 CR2.2 ; CR4.1 v2(16.1,14.07) ; PR803.2 v2(31.04,45.47) ; PD3.1 v2(157.28,173.67) ; RX24.1 105.06,163.07 105.66,162.47 105.66,162.39 106.25,161.8 v2(106.42,161.8) ; PR1403.2 v2(202.39,158.37) ; C16.2 145.22,100.58 v2(145.66,100.14) ; v2(151.89,168.2) CV128.2 ; v2(190.22,163.5) RV57.2 ; v2(53.6,33.06) 53.02,32.47 RZ21.2 ; v2(161.94,152.75) CV124.2 ; RS35.2 v2(179.83,37.08) ; RV4.2 159.49,120.24 v2(159.11,120.62) ; PC757.1 v2(124.07,169.99) ; U101.2 v2(15.02,10.12) ; v2(190.21,155.5) CV181.2 ; CA22.2 175.48,10.02 v2(175.16,10.34) ; v2(201.38,37.74) 201.17,37.95 CI45.2 ; JHDD2.8 v2(201.19,32.88) ; v2(144.37,105.58) 143.74,106.2 Q84.3 ; R2636.1 57.97,45.53 v2(58.1,45.4) ; CV129.2 164.16,170.21 v2(163.85,170.52) ; CH15.2 v2(138.66,76.83) ; U56.4 v2(169.41,81.22) ; R927.2 142.14,85.04 C615.2 RH1.1 v2(140.33,85.14) ; JNGFF.69 v2(162.24,43.43) ; UL4.2 v2(161.35,11.75) ; CA54.2 183.27,5.79 CA53.2 184.03,5.89 v2(184.61,6.46) ; CV167.1 v2(191.32,136.65) ; v2(29.11,40.81) 29.46,41.15 PC805.2 29.83,41.54 29.38,41.99 PQ801.3 ; v2(100.21,163.72) 100.21,163.73 DX2.1 ; CI13.2 v2(24.77,36.07) ; R637.2 v2(171.82,84.33) ; v2(190.25,164.51) CV134.2 ; JDIMM2.206 144.75,48.55 v2(145.09,48.89) ; v2(190.25,165.4) RV53.2 ; RV39.1 154.67,138.32 154.73,138.25 v2(155.11,138.25) ; YV1.4 v2(161.68,115.17) ; C836.2 v2(174.62,27.11) ; PR1410.2 v2(202.81,166.15) ; PD2.1 160.71,173.04 v2(160.2,173.04) ; v2(116.61,174) PC753.1 115.75,173.41 PR755.1 115.74,173.42 PR752.1 ; CS7.2 v2(189.41,37.34) ; PH501.1 v2(62.16,29.27)
  vias: v2(0.56,76.77) v2(2.6,181.48) v2(2.66,160.59) v2(3.23,78.23) v2(3.8,53.4) v2(3.93,82.55) v2(4.37,49.09) v2(4.44,31.11) v2(4.5,73.91) v2(4.5,56.45) v2(7.68,30.1) v2(8.5,73.91) v2(9.14,56.45) v2(9.26,31.62) v2(9.26,24.45) v2(9.26,16.83) v2(9.26,9.21) v2(9.84,1.68) v2(10.22,181.48) v2(10.85,160.59) v2(11.55,82.55) v2(12.63,32.51) v2(15.42,64.52) v2(15.55,62.36) v2(15.93,57.66) v2(16.71,20.19) v2(16.75,18.84) v2(17.07,58.67) v2(17.34,45.43) v2(17.37,19.5) v2(17.46,0.7) v2(17.84,181.48) v2(17.96,45.42) v2(18,20.2) v2(18.09,49.28) v2(18.05,18.83) v2(18.22,52.32) v2(18.47,160.59) v2(18.85,82.36) v2(19.97,43.81) v2(20.5,58.55) v2(20.5,53.47) v2(20.5,48.01) v2(20.59,43.8) v2(22.19,59.98) v2(22.28,161.8) v2(22.22,72.77) v2(22.4,71.01) v2(22.37,69.05) v2(22.35,67.31) v2(22.4,65.38) v2(22.35,63.63) v2(22.38,61.7) v2(22.6,180.34) v2(22.79,52.32) v2(22.79,49.15) v2(22.92,161.8) v2(23.17,57.04) v2(23.36,180.34) v2(23.49,163.07) v2(23.49,162.43) v2(23.5,26.64) v2(23.53,25.39) v2(24.06,180.34) v2(24.14,28.53) v2(24.44,20.69) v2(24.69,180.34) v2(24.73,38.47) v2(24.85,40.79) v2(25.08,0.7) v2(25.25,36.98) v2(25.46,181.48) v2(25.71,82.55) v2(26.09,160.59) v2(26.22,61.47) v2(26.3,35.28) v2(26.31,34.7) v2(26.54,40.44) v2(26.55,38.67) v2(26.94,35.29) v2(26.96,34.71) v2(26.92,21.89) v2(26.92,21.31) v2(28.12,52.45) v2(28.12,51.31) v2(28.25,79.95) v2(28.89,78.42) v2(29.14,59.69) v2(29.13,11.77) v2(29.2,79.76) v2(29.27,57.66) v2(29.37,176.25) v2(29.37,169.01) v2(29.33,52.45) v2(29.39,36.45) v2(29.56,72.3) v2(29.72,11.8) v2(30.03,66.93) v2(30.03,36.45) v2(30.35,35.88) v2(30.32,11.8) v2(30.66,80.26) v2(30.66,71.12) v2(30.66,36.45) v2(31.04,66.93) v2(31.32,71.13) v2(32.06,66.29) v2(32.31,179.77) v2(32.76,1.68) v2(33.23,20.21) v2(33.33,82.55) v2(33.71,160.59) v2(34.09,20.19) v2(34.94,20.21) v2(35.36,163.32) v2(35.49,166.37) v2(36.39,70.64) v2(36.48,68.33) v2(37.52,69.47) v2(37.52,40.13) v2(37.52,39.5) v2(37.78,167.51) v2(37.78,162.05) v2(37.84,38.86) v2(38.16,42.67) v2(38.16,42.04) v2(38.16,41.4) v2(38.16,40.77) v2(38.16,40.13) v2(38.16,39.5) v2(38.47,38.86) v2(38.65,70.52) v2(38.6,68.29) v2(38.65,20.66) v2(38.64,20) v2(38.79,42.67) v2(38.79,42.04) v2(38.79,41.4) v2(38.79,40.77) v2(38.79,40.13) v2(38.79,39.5) v2(39.11,38.86) v2(39.17,20.28) v2(39.25,73.79) v2(39.43,42.67) v2(39.43,42.04) v2(39.43,41.4) v2(39.43,40.77) v2(39.43,40.13) v2(39.43,39.5) v2(39.74,38.86) v2(39.93,179.77) v2(40.06,166.37) v2(40.06,163.19) v2(40.06,42.67) v2(40.06,42.04) v2(40.06,41.4) v2(40.06,40.77) v2(40.06,40.13) v2(40.06,39.5) v2(40.38,1.68) v2(40.7,42.67) v2(40.7,42.04) v2(40.7,41.4) v2(40.95,82.55) v2(41.52,51.18) v2(41.52,50.42) v2(42.35,51.18) v2(42.35,50.42) v2(42.6,160.59) v2(42.63,14.16) v2(42.61,13.54) v2(43.12,167.63) v2(43.15,13.82) v2(43.25,169.02) v2(43.33,170.24) v2(43.3,75.76) v2(44.01,166.42) v2(44.01,164.88) v2(45.12,75.74) v2(47.05,169.16) v2(47.55,179.77) v2(47.94,169.16) v2(47.94,168.27) v2(47.94,167.39) v2(47.91,36.51) v2(48,1.68) v2(48.57,82.55) v2(48.67,36.51) v2(48.82,169.16) v2(48.82,168.27) v2(48.82,167.39) v2(48.82,164.05) v2(48.82,162.62) v2(49.37,36.51) v2(50.04,36.5) v2(50.22,160.59) v2(50.96,164.21) v2(51.87,57.4) v2(51.92,55.93) v2(52.51,57.4) v2(52.56,55.93) v2(55.17,179.77) v2(55.3,167.96) v2(55.68,168.78) v2(55.62,1.68) v2(56.18,82.64) v2(56.32,168.78) v2(56.32,160.46) v2(58.22,36.32) v2(58.22,35.18) v2(58.22,34.04) v2(59.37,36.32) v2(59.37,35.18) v2(59.37,34.04) v2(59.85,164.39) v2(59.87,163.19) v2(60.19,21.84) v2(60.19,21.15) v2(60.51,63.63) v2(60.51,62.74) v2(60.51,36.32) v2(60.51,35.18) v2(60.51,34.04) v2(61.02,21.84) v2(61.02,21.15) v2(61.14,19.11) v2(61.27,63.63) v2(61.27,62.74) v2(61.65,18.67) v2(62.03,63.63) v2(62.03,62.74) v2(62.54,43.43) v2(62.54,41.91) v2(62.79,179.77) v2(62.79,63.63) v2(62.79,62.74) v2(63.05,42.67) v2(63.24,1.68) v2(63.43,43.43) v2(63.43,41.91) v2(63.75,161.73) v2(63.84,83.92) v2(63.94,42.67) v2(64.32,43.43) v2(64.32,41.91) v2(64.83,42.67) v2(65.21,43.43) v2(65.21,41.91) v2(65.72,42.67) v2(66.1,41.91) v2(66.6,42.67) v2(66.99,41.91) v2(67.49,42.67) v2(67.87,41.91) v2(68,157.86) v2(68,43.43) v2(68.26,16.51) v2(68.26,15.88) v2(68.26,15.24) v2(68.38,42.67) v2(68.32,26.54) v2(68.32,25.91) v2(68.38,24.96) v2(68.38,24.32) v2(68.76,41.91) v2(68.7,19.05) v2(68.7,18.35) v2(68.89,43.43) v2(69.02,26.54) v2(69.14,16.51) v2(69.14,15.88) v2(69.14,15.24) v2(69.27,42.67) v2(69.65,41.91) v2(69.65,26.54) v2(69.78,43.43) v2(70.03,16.51) v2(70.03,15.88) v2(70.03,15.24) v2(70.16,42.67) v2(70.29,26.54) v2(70.41,179.77) v2(70.54,41.91) v2(70.67,43.43) v2(70.86,1.68) v2(70.92,26.54) v2(71.05,42.67) v2(71.28,86.77) v2(71.3,65.02) v2(71.43,41.91) v2(71.56,43.43) v2(71.94,42.67) v2(72.07,65.02) v2(72.32,41.91) v2(72.45,43.43) v2(72.83,65.02) v2(72.83,42.67) v2(73.59,65.02) v2(73.88,156.5) v2(74.1,154.81) v2(77.5,90.72) v2(78.14,177.76) v2(78.15,158.15) v2(78.15,157.56) v2(78.48,1.68) v2(80.07,150.3) v2(80.34,42.54) v2(80.34,41.91) v2(80.34,41.27) v2(81.34,56.77) v2(81.34,55.75) v2(81.34,54.61) v2(83.69,96.65) v2(85.27,144.4) v2(85.65,46.99) v2(85.65,46.35) v2(85.65,45.72) v2(85.65,45.08) v2(85.65,44.45) v2(85.65,43.81) v2(85.76,177.76) v2(85.85,97.09) v2(86.1,1.68) v2(87.75,102.62) v2(88.58,72.01) v2(88.7,69.21) v2(88.96,138.18) v2(89.87,149.3) v2(89.87,148.69) v2(90.38,108.46) v2(90.99,73.41) v2(90.99,68.2) v2(91.37,131.51) v2(92.26,115.95) v2(92.58,123.89) v2(93.15,72.26) v2(93.15,69.21) v2(93.38,177.76) v2(93.5,144.49) v2(93.72,0.51) v2(94.29,127) v2(94.42,129.92) v2(95.69,152.6) v2(95.69,151.97) v2(96.07,156.72) v2(96.07,156.08) v2(96.07,155.45) v2(96.07,154.81) v2(96.07,154.18) v2(96.32,152.6) v2(96.32,151.97) v2(96.58,130.94) v2(96.7,154.18) v2(96.7,125.98) v2(97.34,154.18) v2(97.97,154.18) v2(98.86,129.92) v2(98.86,126.87) v2(101,177.76) v2(101.34,0.51) v2(105.22,43.12) v2(105.22,42.48) v2(105.22,41.85) v2(105.22,41.21) v2(106.48,79.63) v2(107.27,80.84) v2(107.31,111.12) v2(108.39,147.32) v2(108.51,179.77) v2(108.77,146.69) v2(108.96,0.51) v2(109.09,111.19) v2(109.28,147.32) v2(109.28,146.05) v2(109.66,146.69) v2(109.62,123.23) v2(109.63,122.55) v2(109.66,121.83) v2(110.17,147.32) v2(110.17,146.05) v2(110.42,130.43) v2(110.55,146.69) v2(110.76,121.82) v2(110.76,121.06) v2(111.05,147.32) v2(111.05,146.05) v2(111.05,130.43) v2(111.4,121.82) v2(111.4,121.06) v2(111.44,146.69) v2(111.94,147.32) v2(111.94,146.05) v2(111.99,107.39) v2(112.03,121.82) v2(112.03,121.06) v2(112.01,105.22) v2(112.32,146.69) v2(112.67,121.82) v2(112.67,121.06) v2(112.83,147.32) v2(112.83,146.05) v2(113.09,108.51) v2(113.21,146.69) v2(113.72,147.32) v2(113.72,146.05) v2(114.1,146.69) v2(114.36,109.47) v2(114.61,147.32) v2(114.61,146.05) v2(114.99,146.69) v2(115.5,147.32) v2(115.5,146.05) v2(115.75,106.3) v2(115.88,146.69) v2(115.88,103.63) v2(116.13,179.77) v2(116.28,168.38) v2(116.35,166.92) v2(116.39,147.32) v2(116.39,146.05) v2(116.58,0.51) v2(116.77,146.69) v2(116.95,167.67) v2(117.28,147.32) v2(117.28,146.05) v2(117.55,168.37) v2(117.56,155.48) v2(117.55,154.74) v2(117.57,153.78) v2(117.6,166.92) v2(117.66,146.69) v2(117.72,13.06) v2(118.17,107.7) v2(118.17,102.49) v2(118.32,13.04) v2(118.5,155.47) v2(118.56,154.71) v2(118.54,153.76) v2(118.93,13.03) v2(119.55,155.45) v2(119.56,154.69) v2(119.57,153.75) v2(119.55,13.02) v2(120.17,13.02) v2(120.33,103.5) v2(120.49,146.79) v2(120.49,146.1) v2(120.58,106.43) v2(121.34,123.44) v2(121.34,122.68) v2(121.98,123.44) v2(121.98,122.68) v2(122.23,40.58) v2(122.42,108.01) v2(122.61,123.44) v2(122.61,122.68) v2(122.99,148.84) v2(123.25,123.44) v2(123.25,122.68) v2(123.44,148.4) v2(123.75,179.77) v2(124.14,40.32) v2(124.2,0.51) v2(126.93,171.07) v2(126.93,170.43) v2(126.93,169.29) v2(126.93,168.66) v2(126.97,166.38) v2(126.97,165.75) v2(127.49,148.29) v2(128.58,78.42) v2(129.03,113.35) v2(130.35,144.21) v2(130.36,143.52) v2(130.36,142.89) v2(130.36,142.25) v2(130.44,141.58) v2(130.6,140.92) v2(130.68,140.25) v2(130.8,113.35) v2(130.99,143.52) v2(130.99,142.89) v2(130.99,142.25) v2(131.07,141.58) v2(131.12,179.96) v2(131.24,140.92) v2(131.31,140.25) v2(131.69,170.24) v2(131.63,143.52) v2(131.63,142.89) v2(131.63,142.25) v2(131.71,141.58) v2(131.82,0.51) v2(132.26,143.52) v2(132.26,142.89) v2(132.26,142.25) v2(132.34,141.58) v2(132.96,99.38) v2(133.03,170.43) v2(133.03,169.67) v2(133.66,99.38) v2(133.79,170.43) v2(133.79,169.67) v2(134.55,170.43) v2(134.55,169.67) v2(135.31,170.43) v2(135.31,169.67) v2(135.57,98.11) v2(136.07,170.43) v2(136.07,169.67) v2(136.14,149.22) v2(136.14,148.46) v2(136.14,147.76) v2(136.44,91.59) v2(137.41,181.48) v2(138.37,145.3) v2(138.36,144.65) v2(138.36,143.89) v2(138.36,143.24) v2(139.44,0.51) v2(139.63,127.51) v2(139.63,126.87) v2(139.63,126.24) v2(139.63,125.6) v2(139.76,166.88) v2(139.76,164.34) v2(140.26,127.51) v2(140.26,126.87) v2(140.26,126.24) v2(140.26,125.6) v2(141.28,145.54) v2(141.28,144.78) v2(141.28,144.02) v2(142.04,168.27) v2(142.04,163.32) v2(142.04,145.54) v2(142.04,144.78) v2(142.04,144.02) v2(142.42,177.16) v2(142.8,145.54) v2(142.8,144.78) v2(142.8,144.02) v2(143.06,72.26) v2(143.19,177.16) v2(143.19,69.09) v2(143.57,144.78) v2(143.57,144.02) v2(143.95,151.89) v2(143.95,149.1) v2(144.2,177.16) v2(144.2,167) v2(144.2,164.47) v2(144.33,144.78) v2(144.33,144.02) v2(144.68,84.66) v2(144.68,84.07) v2(144.96,177.16) v2(145.03,181.48) v2(145.09,144.78) v2(145.09,144.02) v2(145.34,73.41) v2(145.47,68.2) v2(145.98,177.16) v2(145.98,152.91) v2(145.98,147.95) v2(146.74,177.16) v2(147.06,0.51) v2(147.59,124.05) v2(147.5,72.33) v2(147.5,69.21) v2(147.63,177.16) v2(147.63,122.59) v2(148.14,152.02) v2(148.27,149.1) v2(148.25,126.83) v2(148.39,177.16) v2(148.39,127.95) v2(148.38,125.64) v2(149.19,83.71) v2(149.19,83.08) v2(149.24,26.99) v2(149.7,84.01) v2(149.73,83.32) v2(149.71,82.66) v2(151.19,133.35) v2(151.19,132.59) v2(151.19,131.83) v2(151.44,62.61) v2(151.57,59.18) v2(151.73,78.31) v2(151.76,76.44) v2(152.08,178.44) v2(152.01,49.72) v2(152.01,49.09) v2(152.01,47.94) v2(152.01,47.31) v2(152.65,181.48) v2(152.96,178.44) v2(153.85,178.44) v2(154.23,64.01) v2(154.23,57.91) v2(154.68,0.51) v2(154.74,178.44) v2(155.16,41.72) v2(155.33,42.91) v2(155.63,178.44) v2(156.06,41.91) v2(156.7,88.89) v2(156.7,88.29) v2(156.77,59.05) v2(157.03,62.61) v2(157.12,43.7) v2(157.66,134.84) v2(157.66,134.11) v2(157.66,133.14) v2(157.68,132.45) v2(157.65,130.77) v2(157.7,135.61) v2(159.51,116.17) v2(160.27,181.48) v2(161.75,129.27) v2(161.8,50.55) v2(161.85,52.01) v2(162.3,0.51) v2(163.21,28.49) v2(165.6,136.17) v2(166.72,119.72) v2(166.72,119.1) v2(167.19,11.3) v2(167.32,14.35) v2(167.43,136.19) v2(167.89,181.48) v2(167.95,61.28) v2(168.55,21.72) v2(168.55,21.12) v2(168.79,127.57) v2(169.35,92.96) v2(169.35,91.82) v2(169.35,90.68) v2(169.35,61.34) v2(169.41,25.97) v2(169.47,24.38) v2(169.6,15.49) v2(169.6,10.03) v2(169.92,0.51) v2(170.09,25.09) v2(170.12,108.99) v2(170.11,108.27) v2(170.3,137.11) v2(170.36,92.96) v2(170.36,91.82) v2(170.36,90.68) v2(170.76,108.99) v2(170.74,108.27) v2(170.81,25.97) v2(170.81,24.38) v2(171.22,126.14) v2(171.38,92.96) v2(171.38,91.82) v2(171.38,90.68) v2(171.49,75.78) v2(171.89,111.12) v2(171.89,14.35) v2(171.89,11.18) v2(172.01,113.92) v2(172.41,72.05) v2(174.05,114.81) v2(174.05,109.98) v2(174.77,17.14) v2(174.73,16.48) v2(175.51,181.48) v2(176.21,113.92) v2(176.21,111) v2(177.54,0.51) v2(178.05,33.66) v2(178.05,31.88) v2(179.13,95.38) v2(179.51,98.42) v2(179.51,97.66) v2(179.51,96.9) v2(179.51,96.14) v2(179.89,95.38) v2(180.27,98.42) v2(180.27,97.66) v2(180.27,96.9) v2(180.27,96.14) v2(180.65,113.92) v2(180.65,95.38) v2(181.03,98.42) v2(181.03,97.66) v2(181.03,96.9) v2(181.03,96.14) v2(181.29,113.92) v2(181.41,95.38) v2(181.54,43.05) v2(181.53,41.76) v2(181.79,98.42) v2(181.79,97.66) v2(181.79,96.9) v2(181.79,96.14) v2(181.73,38.35) v2(181.92,113.92) v2(182.17,95.38) v2(182.21,138.23) v2(182.3,14.48) v2(182.3,13.33) v2(182.3,12.32) v2(182.56,113.92) v2(182.56,98.42) v2(182.56,97.66) v2(182.56,96.9) v2(182.56,96.14) v2(182.69,32.48) v2(182.69,31.21) v2(182.7,140.61) v2(182.85,138.23) v2(182.94,95.38) v2(183.13,181.48) v2(183.29,140.59) v2(183.34,141.34) v2(183.32,97.66) v2(183.32,96.9) v2(183.32,96.14) v2(183.33,31.85) v2(183.44,14.48) v2(183.44,13.33) v2(183.44,12.32) v2(183.7,95.38) v2(183.89,124.38) v2(183.89,123.51) v2(183.97,141.35) v2(183.96,32.48) v2(183.96,31.21) v2(184.08,97.66) v2(184.08,96.9) v2(184.08,96.14) v2(184.28,123.95) v2(184.46,95.38) v2(184.59,14.48) v2(184.84,97.66) v2(184.84,96.9) v2(184.84,96.14) v2(184.84,11.94) v2(185.16,0.51) v2(185.22,98.42) v2(185.22,95.38) v2(185.6,97.66) v2(185.6,96.9) v2(185.6,96.14) v2(185.98,98.42) v2(185.98,95.38) v2(185.98,89.22) v2(185.98,88.52) v2(185.98,87.82) v2(185.98,87.12) v2(186.05,93.28) v2(186.05,92.39) v2(186.37,97.66) v2(186.37,96.9) v2(186.37,96.14) v2(186.75,98.42) v2(186.75,95.38) v2(187.13,97.66) v2(187.13,96.9) v2(187.13,96.14) v2(187.51,98.42) v2(187.51,95.38) v2(187.89,97.66) v2(187.89,96.9) v2(187.89,96.14) v2(188.27,98.42) v2(188.59,34.54) v2(188.52,29.21) v2(188.78,30.92) v2(188.91,101.22) v2(188.91,100.58) v2(188.91,99.95) v2(190.75,181.48) v2(192.78,0.51) v2(192.89,166.24) v2(192.88,165.54) v2(192.88,164.85) v2(192.88,164.15) v2(192.88,163.06) v2(192.84,127.63) v2(192.84,127) v2(192.84,126.36) v2(192.84,125.73) v2(192.86,42.19) v2(192.97,137.99) v2(192.96,137.34) v2(193.22,157.35) v2(193.22,156.65) v2(193.22,155.57) v2(193.22,154.88) v2(193.49,42.18) v2(193.86,127.63) v2(193.86,127) v2(193.86,126.36) v2(193.86,125.73) v2(194.35,162.53) v2(194.35,161.9) v2(194.35,161.26) v2(194.93,162.85) v2(194.93,162.22) v2(194.93,161.58) v2(194.98,42.15) v2(195.5,161.9) v2(197.67,54.86) v2(197.8,57.78) v2(198.18,179.77) v2(198.37,110.17) v2(198.37,102.55) v2(198.37,94.93) v2(198.37,87.31) v2(198.37,79.69) v2(198.37,72.07) v2(198.43,150.24) v2(198.68,147.57) v2(199.31,126.94) v2(199.31,119.32) v2(199.83,58.8) v2(199.95,53.72) v2(200.08,66.36) v2(200.4,0.51) v2(200.84,151.64) v2(200.84,146.69) v2(201,168.83) v2(201.67,156.46) v2(201.67,155.77) v2(201.67,154.69) v2(201.67,153.99) v2(201.99,57.78) v2(201.99,54.74) v2(202.06,166.15) v2(203.07,60.45) v2(203.07,52.83) v2(203.07,45.21) v2(203.07,37.59) v2(203.07,29.97) v2(203.07,22.35) v2(203.07,14.73) v2(203.07,7.11) v2(203.13,150.5) v2(203.13,147.7) v2(203.13,111.38) v2(203.96,128.97) v2(204.02,179.2) v2(204.02,171.58) v2(204.04,162.42) v2(204.02,156.34) v2(204.04,144.2) v2(204.04,136.58) v2(204.02,116.9) v4(38.16,44.07) v4(40.33,177.98) v4(41.92,49.8) v4(56.19,168.08) v4(66.99,26.42) v4(68.76,13.86) v4(80.45,45.21) v4(106.55,80.26) v4(108.45,121.73) v4(116.77,153.42) v4(119.12,147.07) v4(122.87,148.15) v4(125.47,143.13) v4(128.96,148.95) v4(132.9,171.89) v4(135.12,98.81) v4(139.63,144.84) v4(150.93,82.17) v4(156.27,124.71) v4(169.42,109.02) v4(174.36,18.03) v4(182.81,141.16) v4(184.46,124.65) v4(188.27,95.12) v4(191.89,139.57)
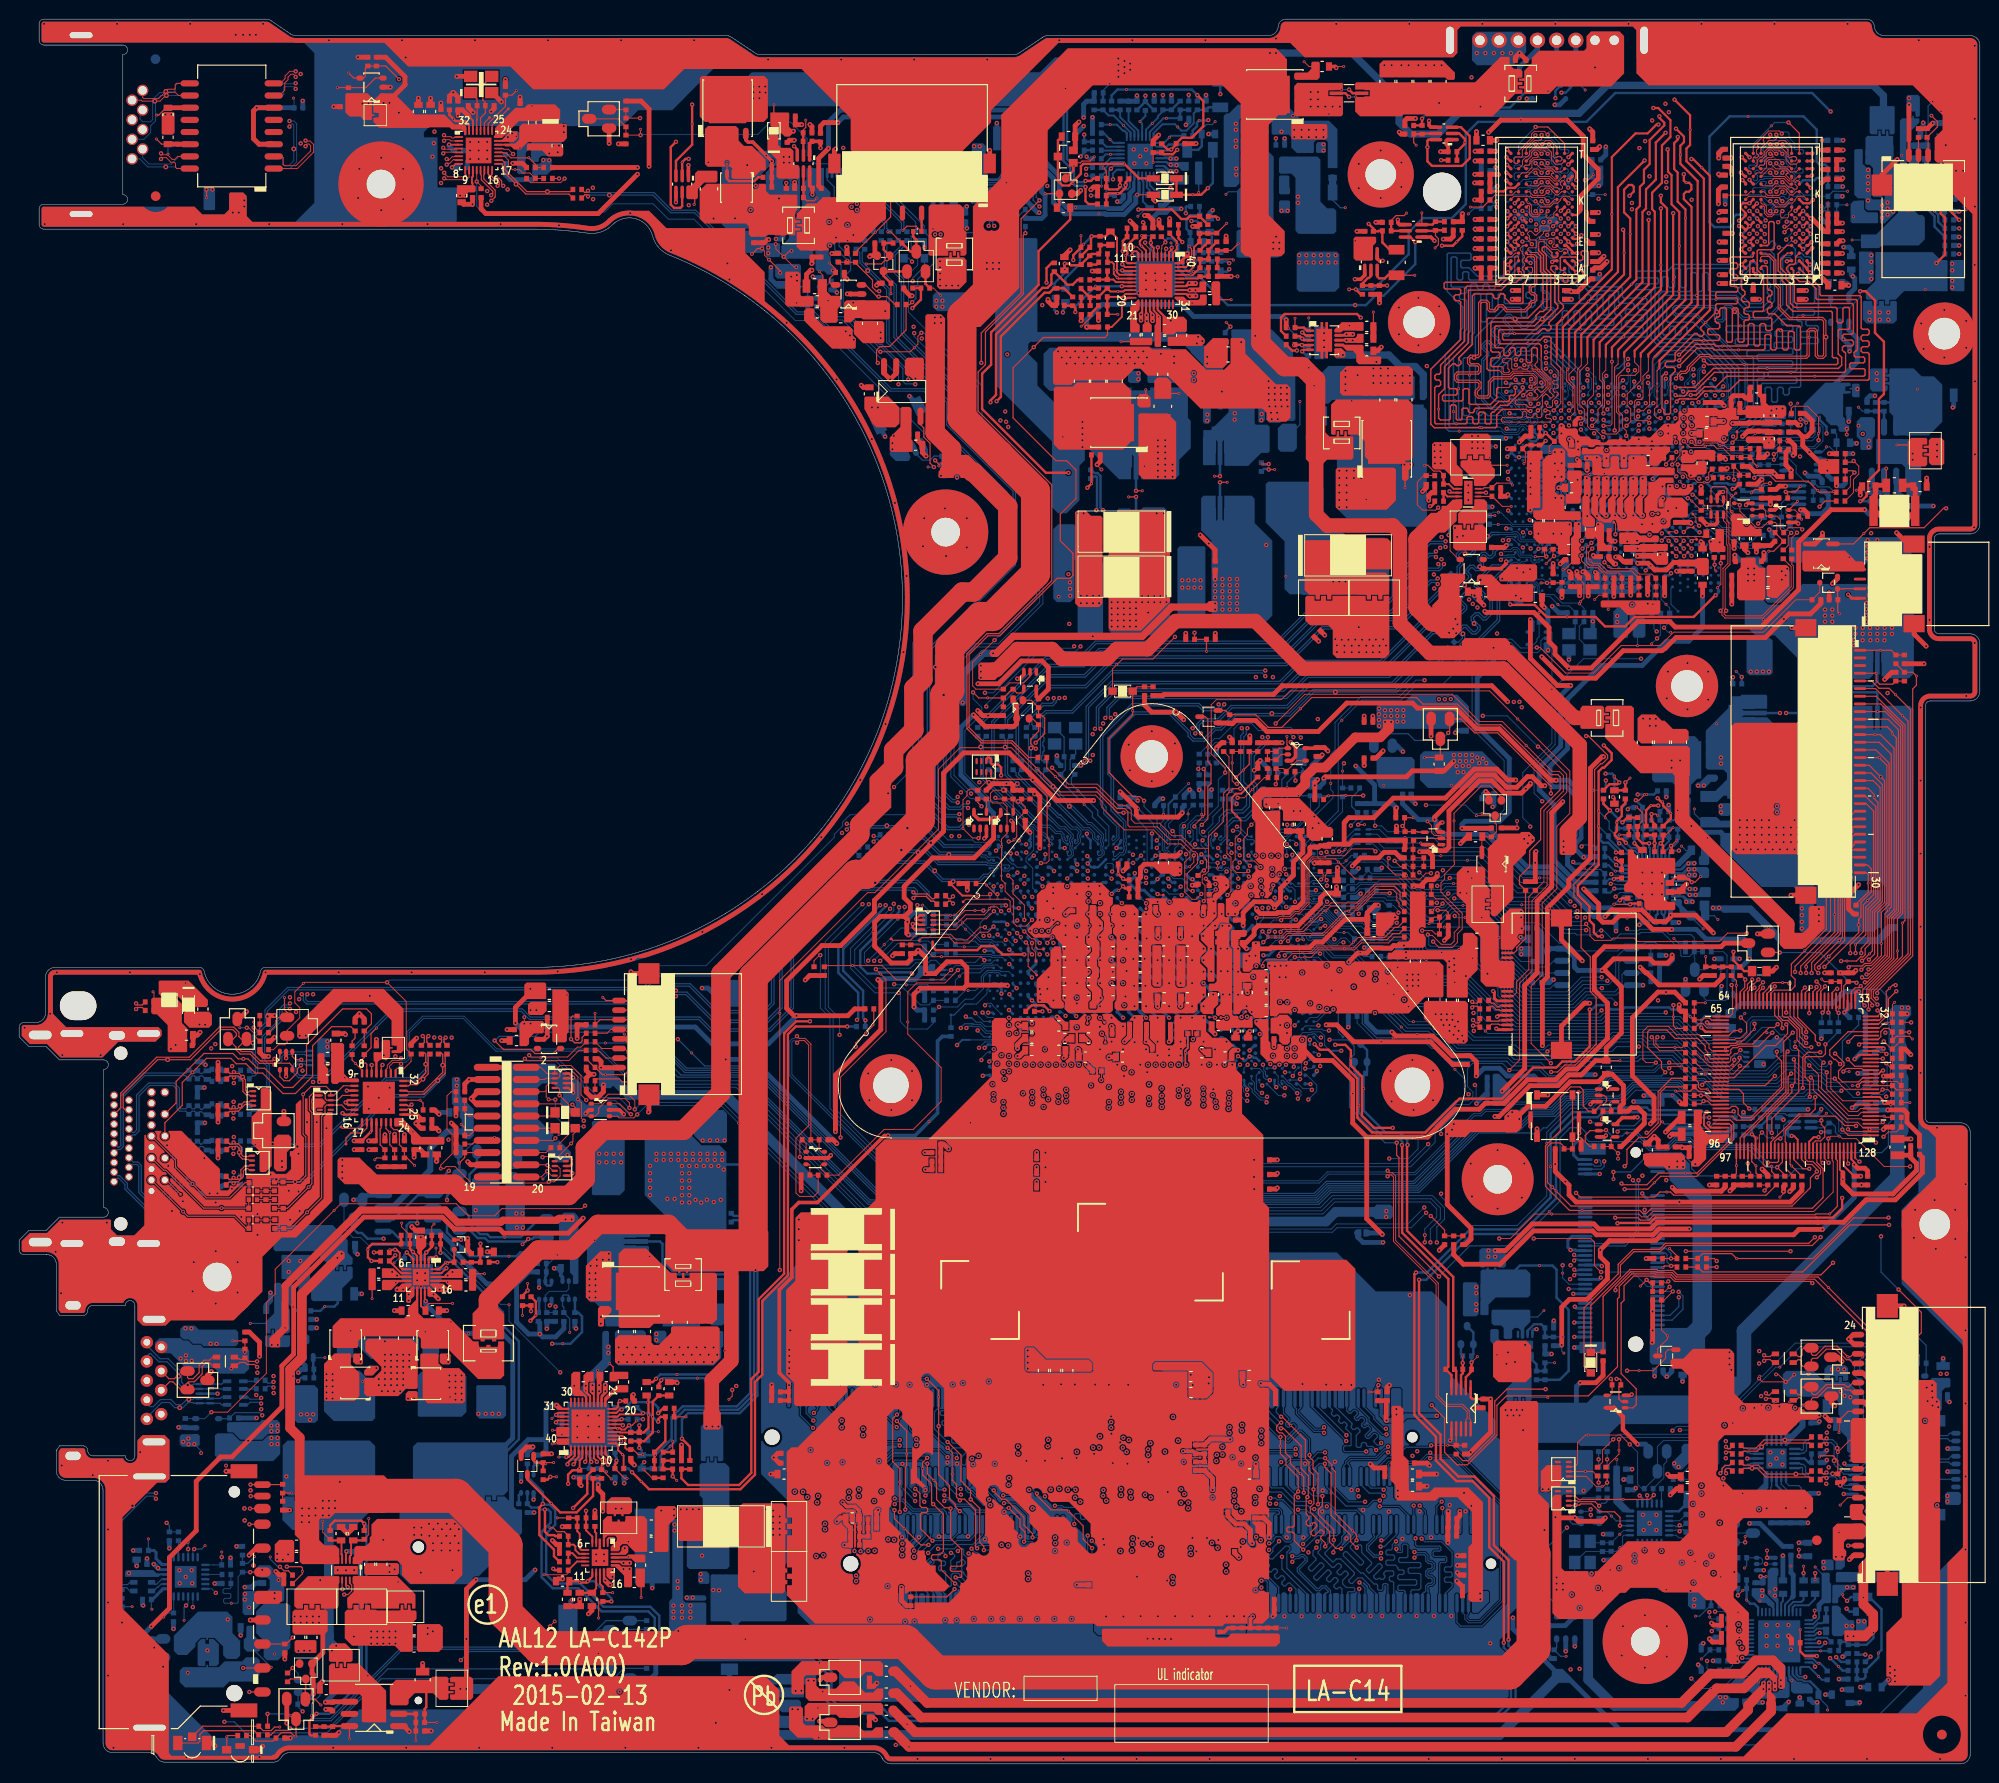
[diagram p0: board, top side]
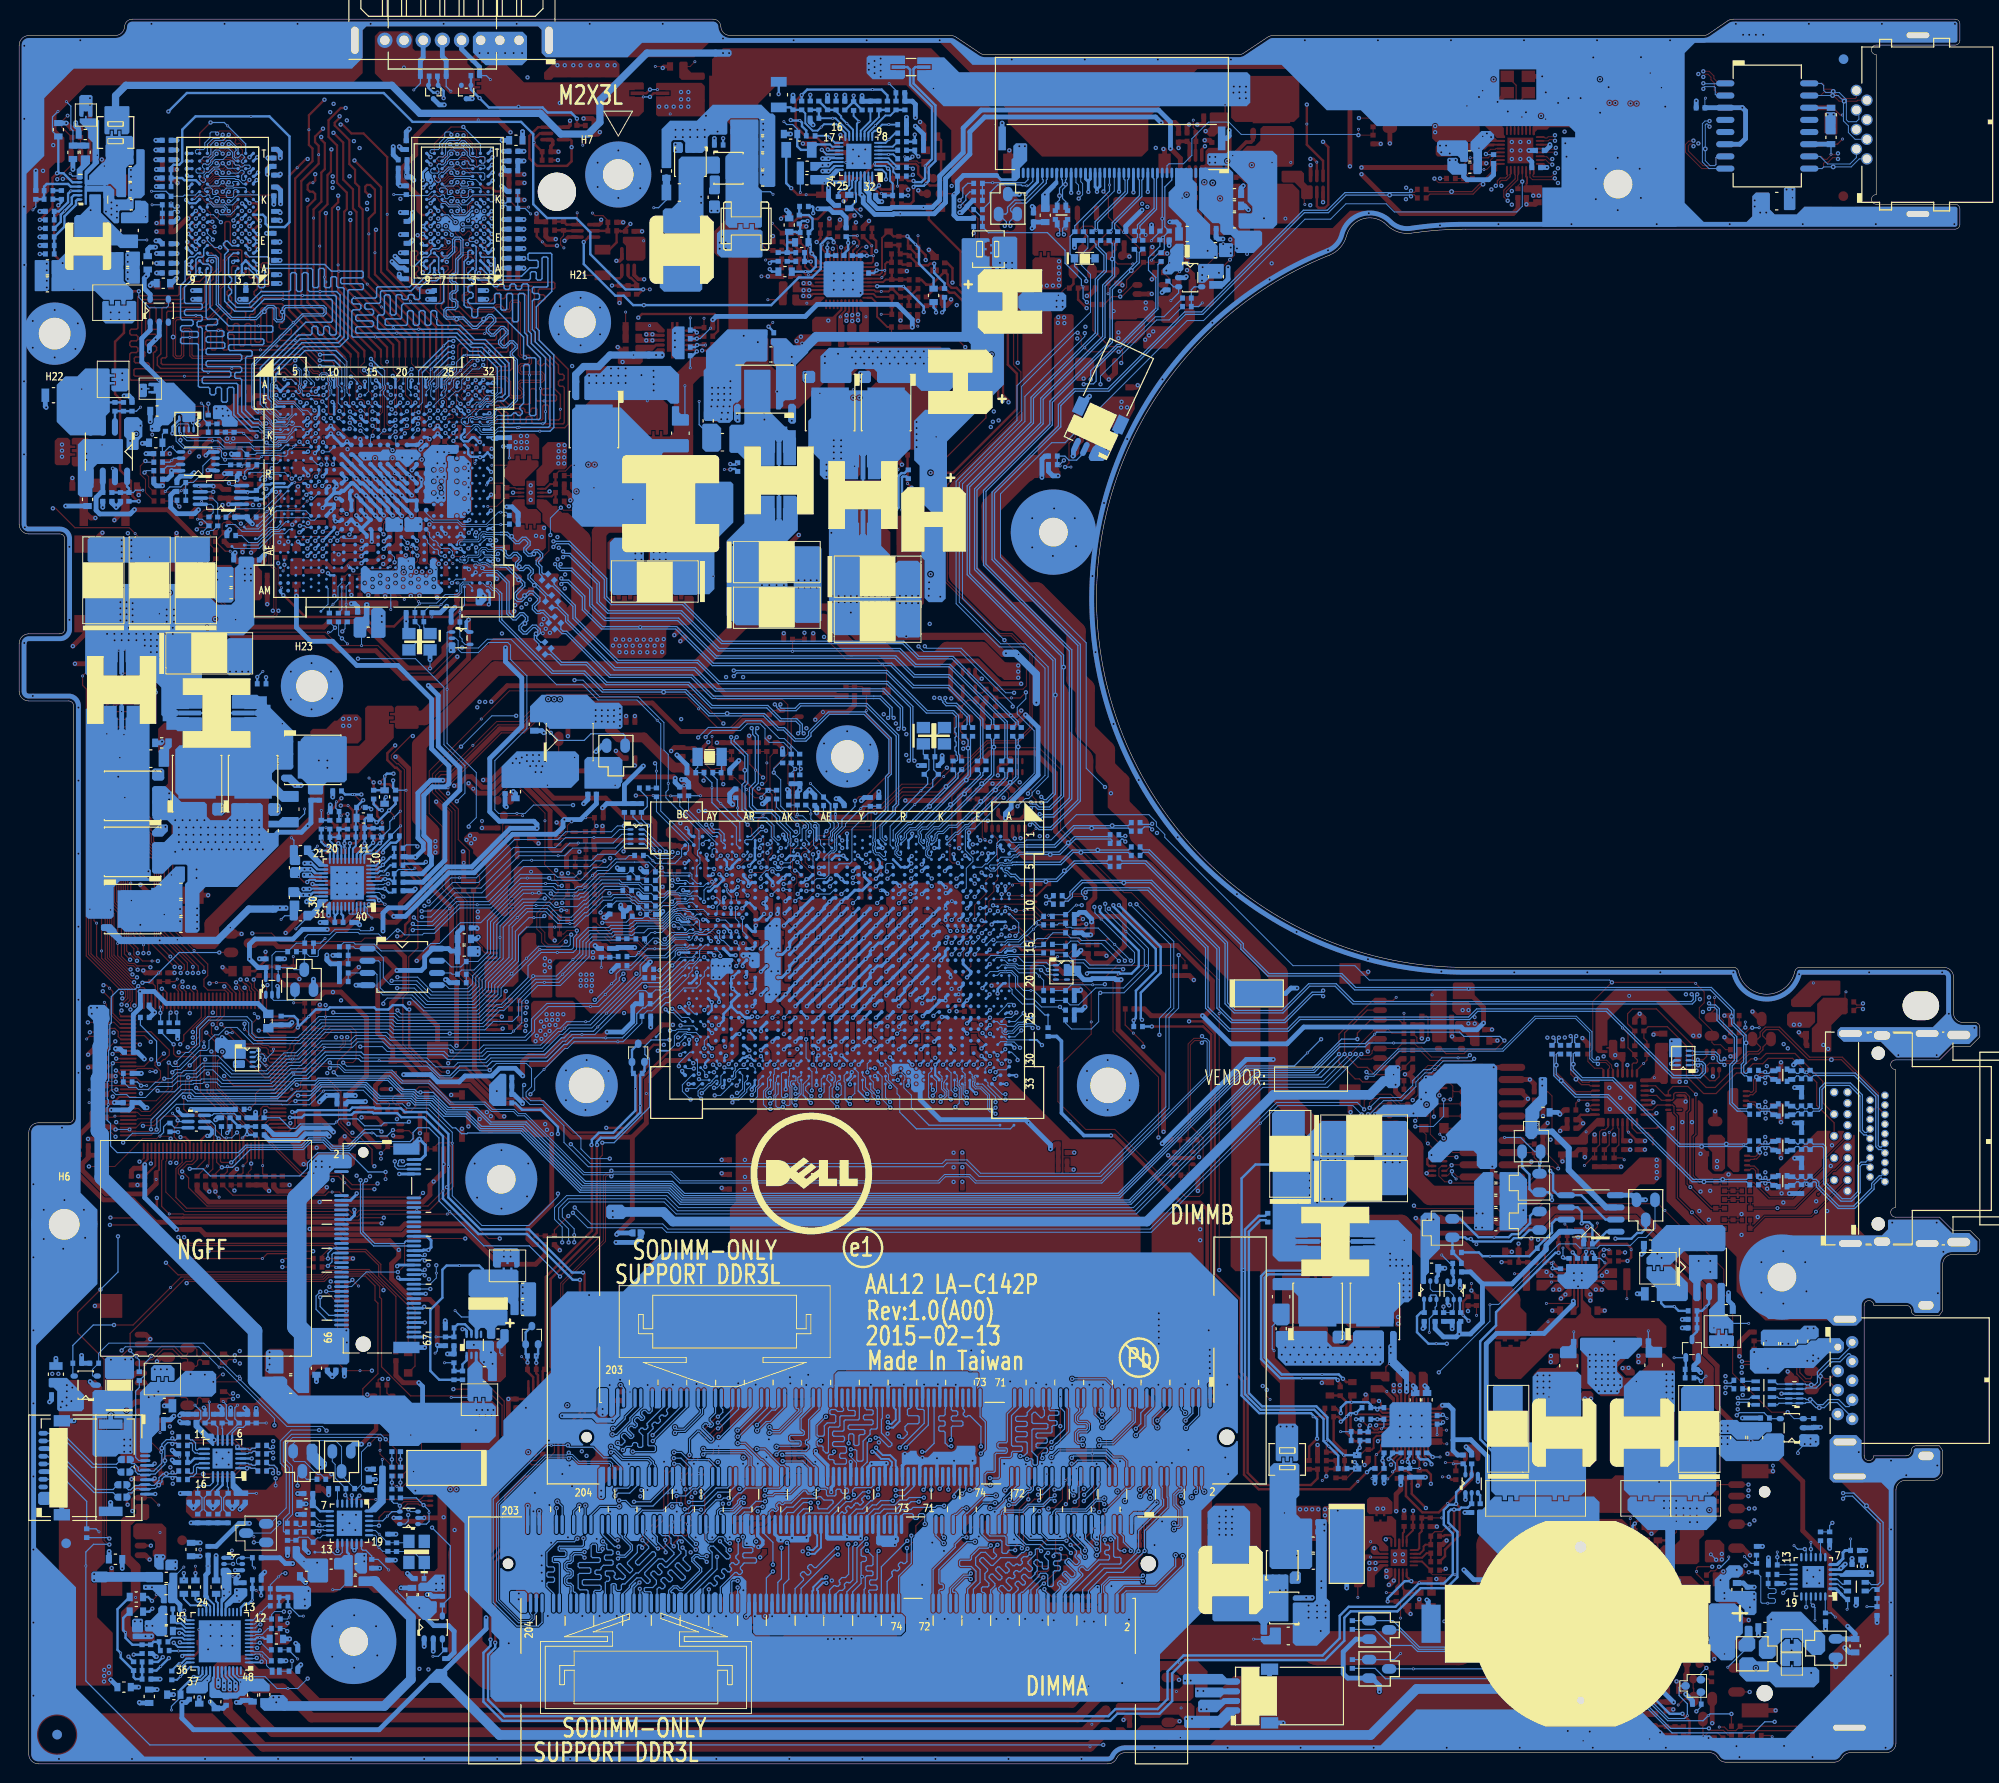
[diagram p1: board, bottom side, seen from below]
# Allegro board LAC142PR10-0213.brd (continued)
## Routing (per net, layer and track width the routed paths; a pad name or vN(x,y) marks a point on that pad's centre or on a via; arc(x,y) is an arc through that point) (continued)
GNDA: length 17.2
  TOP w0.102: v2(182.35,21.49) v4(182.35,22.25) ; v2(187.32,15.35) v4(187.32,15.99) ; v2(185.67,21.65) v4(185.67,22.34)
  TOP w0.508: JIO1.9 192.71,29.76 192.78,29.69 v2(192.83,29.69) ; JIO1.1 191.39,21.76 v2(190.94,21.31)
  BOTTOM w0.203: UA1.38 185.42,9.35 185.7,9.08 186.32,9.08 v2(186.34,9.06) ; v2(187.32,15.35) 187.32,15.28 187.02,14.98 UA1.25
  BOTTOM w0.406: QA6.1 v2(182.35,21.49) ; QA6.4 v2(182.02,20.19)
  BOTTOM w0.457: RA84.2 190.64,11.51 190.31,11.18 v2(190.23,11.18)
  BOTTOM w0.508: RA29.1 v2(185.67,21.65) ; CA74.2 v2(184,21.72) ; RA30.1 v2(193.8,20.38) ; CA61.2 v2(185.76,6.93) ; RA32.1 v2(192.08,8) ; RA83.2 v2(189.85,8.84) ; RA31.1 v2(190.16,7.74) ; CA63.1 v2(188.44,7.22)
  vias: v2(190.7,18.41) v2(190.65,14.39) v2(191.24,14.39) v2(191.33,18.41)
V18: length 2.9
  BOTTOM w0.102: UR1.24 16.12,15.76 CR4.2
  BOTTOM w0.127: v1(15.08,15.3) 15.51,15.74 CR4.2
VCCSENSE_VGA: length 30.5
  TOP w0.254: v2(171,99.95) v1(170.24,99.95) 169.73,99.44 PR1138.2
  TOP w0.508: RV161.1 161.9,122.77 RV159.2 v2(162.79,121.85)
  IN1 w0.254: v2(162.79,121.85) 163.68,120.96 163.68,120.87 167.96,116.59 167.96,103.42 170.48,100.91 170.48,100.09 170.62,99.95 v2(171,99.95)
VDD_1.35V: length 8.8
  TOP w0.203: PU200.11 59.8,19.53 59.62,19.35
  TOP w0.254: PR205.1 v2(61.78,16.94) ; PR206.2 57.21,18.86 PC209.1 58.35,19.05 v1(58.49,18.91) 59.18,18.91 v2(59.32,19.05) 59.62,19.35
  BOTTOM w0.254: v2(61.78,16.94) 61.78,17.27 60,19.05 v2(59.32,19.05)
VDD_CHG: length 34.8
  TOP w0.254: v2(122.91,174.05) 123.54,173.43 123.54,170.8 122.34,169.6 121.31,169.6 PC768.2 120.69,168.88 v2(120.19,168.38) 119.8,168.38 PR760.1
  IN2 w0.254: v2(111.82,163.58) 112.07,163.58 113.16,164.67 113.16,167.94 114.52,169.3 118.56,169.3 119.49,168.38 v2(120.19,168.38)
  BOTTOM w0.203: v2(120.19,168.38) 120.08,168.27 PU703.19
  BOTTOM w0.254: PR749.2 v2(122.91,174.05) 122.34,174.62 v1(115.53,174.62) 114.57,174.62 113.97,174.02 PR750.2 ; PR741.1 v2(111.82,163.58)
VDDCR_FCH_S5: length 1.9
  BOTTOM w0.127: 25.96,45.94 v1(24.11,45.94)
VDDIO_APU: length 5.8
  TOP w0.203: PU1001.6 118.36,158.12 118.06,158.42 v2(118.06,158.64) 118.06,159.07 PR1023.2
  BOTTOM w0.127: PR1028.2 118.18,159.38 v1(117.1,159.38)
  BOTTOM w0.254: PR1028.2 118.06,159.07 v2(118.06,158.64) 118.06,157.94 118.5,157.5 PC1064.1
VDDIO_AUDIO: length 38.2
  TOP w0.254: v2(143.3,66.33) 141.34,66.33 140.09,67.59 140.09,71.68 138.93,72.83 v1(138.93,73.58) 138.93,74.41 138.35,74.99 v2(137.29,74.99)
  IN1 w0.254: v2(143.3,66.33) 147.71,66.33 v2(148.34,65.7)
  IN2 w0.254: v2(137.29,74.99) 137.29,77.2 136.38,78.12 136.15,78.12 136,78.27 134.37,78.27 131.22,81.42 129.42,81.42 v2(128.75,82.09)
  BOTTOM w0.254: v2(148.34,65.7) 148.34,66.43 150.14,68.22 152.09,68.22 152.8,68.94 R11.1
  BOTTOM w0.305: UC1.AR19 128.65,82.61 128.65,82.19 v2(128.75,82.09)
VDDIO_GFX: length 5
  TOP w0.203: v2(59.68,31.5) 59.56,31.62 PU500.6
  BOTTOM w0.127: PR506.2 v1(58.44,30.81)
  BOTTOM w0.254: PC501.1 59.49,32.07 59.68,31.88 v2(59.68,31.5) 59.49,31.31 PR506.2 PR508.2
VDDIO_VGA: length 6.8
  TOP w0.254: PC1101.1 166.49,92.39 v2(166.38,92.28)
  BOTTOM w0.127: PR1113.2 164.98,93.28 163.4,93.28 v1(163.26,93.42)
  BOTTOM w0.203: PR1113.2 PR1115.2 165.55,91.95 165.88,92.28 v2(166.38,92.28) 166.58,92.28 166.78,92.08 PU1100.6
VDDP_CHG: length 5.8
  TOP w0.127: PC769.2 v1(118.31,167.03)
  TOP w0.254: v2(120.81,168.34) 120.36,167.88 119.38,167.88 PR760.2 PC769.2
  BOTTOM w0.203: v2(120.81,168.34) 120.34,167.87 PU703.20
VDDR4: length 2.1
  BOTTOM w0.381: UV1.U12 170.05,132.6 170.05,131.92 UV1.V12 UV1.Y12
VSS_MECH: length 51.3
  TOP w0.254: v2(176.99,121.89) 176.96,121.89 174.69,119.62 168.54,119.62 167.55,118.64 165.44,118.64 164.46,119.62 v1(161.5,119.62) 159.37,119.62 158.11,120.88 155.61,120.88 v2(155.56,120.93)
  IN1 w0.254: v2(155.56,120.93) 155.44,121.04 155.44,122.11 156.33,123 156.33,134.87 155.82,135.38 155.31,135.38 154.54,136.16 154.54,143.5 v2(155.1,144.06)
  BOTTOM w0.254: v2(155.56,120.93) 155.47,121.02 155.47,122.14 UV1.AM32 ; v2(176.99,121.89) 177.29,122.18 UV1.AM1 ; UV1.A32 155.2,143.96 v2(155.1,144.06)
VSSSENSE_VGA: length 29.8
  TOP w0.254: PR1139.2 172.31,98.6 v1(172.31,99.15) 171.51,99.95 171.51,100.14 v2(170.94,100.71)
  TOP w0.508: RV160.1 164.59,122.77 RV158.2 v2(163.69,121.81)
  IN1 w0.254: v2(170.94,100.71) 170.94,100.96 168.32,103.57 168.32,116.79 164.2,120.91 164.2,121.31 v2(163.69,121.81)
0.95_1.8VALW_PWREN: length 179.7
  TOP w0.203: v2(191.45,62.5) 191.45,62.75 191.15,63.05 UE1.127
  TOP w0.254: PR301.1 131.64,149.45 131.64,150.84 132.02,151.22 139.58,151.22 v2(139.96,150.84)
  TOP w0.508: RE46.1 192.84,61.84 192.56,62.12 191.82,62.12 v2(191.45,62.5) ; v2(160.93,43.69) 160.93,47.64 161.73,48.44 163.56,48.44 165.7,50.58 165.7,52.15 164.95,52.89 v2(164.95,53.61) 165.92,54.57 170.71,54.57 171.32,55.18 185.12,55.18 185.68,55.74 v2(188.13,55.74) ; v2(165.29,105.04) 165.12,105.04 163.93,103.84 163.93,94.45 161.66,92.19 161.66,91.5 159.44,89.27 159.44,82.06 158.92,81.54 v2(158.92,74.9)
  IN1 w0.508: v2(164.95,53.61) 164.95,59.19 163.84,60.31 163.84,63.13 164.47,63.77 164.47,67.35 164.08,67.74 162.75,67.74 158.86,71.63 158.86,74.84 v2(158.92,74.9) ; v2(139.96,150.84) 141.52,149.28 141.52,147.52 142.22,146.82 143.25,146.82 144.07,146 145.6,146 149.83,141.77 149.83,135.9 151.91,133.82 151.91,130.94 153.13,129.72 153.13,121.75 155.07,119.82 155.66,119.82 157.23,118.25 158.94,118.25 160.6,116.6 160.6,114.74 166.11,109.23 166.11,105.85 v2(165.29,105.04)
  BOTTOM w0.127: v1(161.16,42.84) 160.93,43.07 v2(160.93,43.69)
  BOTTOM w0.508: v2(188.13,55.74) 191.45,59.05 v2(191.45,62.5) ; PR601.2 160.85,43.61 v2(160.93,43.69)
0.775PW_EN: length 261
  TOP w0.203: v2(194.46,72.31) 194.34,72.31 193.98,71.96 UE1.17
  TOP w0.254: v2(190.18,59.02) 190.18,57.92 189.24,56.97 187.48,56.97 187.48,56.97 170.7,56.97 170.15,56.41 166.78,56.41 v2(166.74,56.38)
  IN1 w0.254: v2(29.1,39.92) 28.63,40.39 28.63,46.01 34.55,51.93 43.68,51.93 44.43,52.68 48.41,52.68 50.2,50.89 50.2,45.51 50.98,44.72 50.98,24.72 54.37,21.34 55.68,21.34 60,17.02 60,15.59 61.52,14.07 96.38,14.07 98.72,11.73 155.15,11.73 158.86,15.44 158.86,23.12 160.89,25.15 160.89,32.31 163.99,35.4 163.99,46.04 166.07,48.12 166.07,50.32 166.74,50.99 v2(166.74,56.38) ; v2(190.18,59.02) 190.18,62.67 192.97,65.46 192.97,69.98 193.34,70.35 193.34,71.3 194.35,72.31 v2(194.46,72.31)
  BOTTOM w0.127: v1(28.57,40.44) 29.09,39.92 v2(29.1,39.92)
  BOTTOM w0.254: PR801.1 29.44,40.26 v2(29.1,39.92)
32K_X1: length 10.8
  BOTTOM w0.102: 129.63,98.43 129.37,98.17 UC1.AT1
  BOTTOM w0.127: 129.63,98.43 v1(131.34,100.15) 131.73,100.53 131.73,102.65 132.19,103.11 R914.2 C686.1 131.27,103.43 Y3.1
32K_X2: length 12
  BOTTOM w0.102: UC1.AT2 129.72,95.88 129.72,97.71 130.44,98.43
  BOTTOM w0.127: 130.44,98.43 132.28,100.27 v1(132.28,101.8) 132.28,102.32 133.1,103.15 R914.1 C682.1 133.97,103.74 133.77,103.94 Y3.2
48M_X1: length 13.2
  BOTTOM w0.102: UC1.T2 113.68,95.84 113.68,97.79 113.04,98.43
  BOTTOM w0.127: Y2.1 110.22,105.33 R939.2 109.65,104.75 109.65,103.7 C797.1 109.77,102.85 109.77,102.2 v1(110.47,101.5) 112.53,99.44 112.53,98.95 113.04,98.43
48M_X2: length 14.4
  BOTTOM w0.102: UC1.T1 113.37,97.37 112.31,98.43
  BOTTOM w0.127: 112.31,98.43 111.97,98.77 111.97,99.2 v1(111.11,100.06) 109.24,101.93 109.24,102.63 C796.1 109.14,103.69 109.14,104.92 R939.1 109.02,107.08 Y2.3
+0.775MOS: length 40.6
  IN1 w0.254: v2(55.61,43.81) 55.61,46 54.29,47.31 54.29,48.29 54.7,48.69 54.7,51.1 54.47,51.33 54.47,52.71 45.33,61.85 v2(44.82,61.85)
  BOTTOM w0.254: v2(44.82,61.85) 44.52,61.54 44.52,59.83 44,59.31 U2.5 41.59,59.31 39.05,56.77 U2.2 ; Q2516.1 57.98,47.08 R2636.2 58.32,47.07 58.72,46.67 58.72,45.02 57.51,43.81 v1(56.71,43.81) v2(55.61,43.81)
+A_VCC: length 6.4
  BOTTOM w0.203: UA1.20 184.22,16.61 184.98,17.37
  BOTTOM w0.508: RA10.2 v1(184.84,20.62) 184.84,19.94 185.08,19.7 185.08,17.48 184.98,17.37
+APU_CORE: length 106.7
  TOP w0.254: v2(107.18,154.5) 107.18,156.01 107.73,156.55 PR1051.2
  IN2 w0.254: v2(109.56,118.9) 110.17,119.51 110.17,129.86 109.92,130.1 109.92,130.91 110.62,131.61 110.62,134.27 109.38,135.51 109.38,143.39 106.4,146.36 106.4,149.39 107.45,150.43 107.45,151.8 107.92,152.27 107.92,153.76 v2(107.18,154.5)
  BOTTOM w0.254: v2(119.88,92.33) 120.29,91.92 UC1.AE7 ; UC1.AH7 122.75,91.92 v2(122.4,92.27)
  BOTTOM w0.305: UC1.AK6 124.5,92.72 v2(124.83,92.38) 124.9,92.38 UC1.AL7 ; UC1.AD6 119.19,92.72 v2(118.76,92.28) 118.39,91.92 UC1.AB7 ; v2(122.4,92.27) 122.22,92.27 UC1.AG6 ; v2(116.39,92.9) 116.39,92.54 UC1.W7 116.57,91.12 UC1.Y8 117.37,91.12 UC1.AB9 118.36,90.32 v2(118.77,89.91) 119.37,89.31 UC1.AD10 119.42,89.22 v2(120.02,88.63) 120.57,88.08 UC1.AE12 120.57,88.02 UC1.AG13 121.87,86.82 v2(122.37,86.32) 122.97,85.72 UC1.AH15 122.97,85.62 v2(123.57,85.02) UC1.AK16 ; UC1.W21 115.77,80.82 116.97,79.62 UC1.Y22 116.97,79.62 v2(117.57,79.02) ; UC1.AG10 v2(122.37,88.62) UC1.AH12 122.97,88.02 v2(123.57,87.42) UC1.AK13 ; v2(122.37,79.02) 121.77,79.62 UC1.AG22 121.76,79.62 120.57,80.82 UC1.AE21 120.57,80.82 v2(119.97,81.42) 119.37,82.02 UC1.AD19 118.17,83.22 UC1.AB18 v2(117.41,83.97) UC1.Y16 116.97,84.42 UC1.W15 ; UC1.AK19 v2(123.57,82.62) 122.97,83.22 UC1.AH18 122.97,83.22 v2(122.37,83.82) 121.77,84.42 UC1.AG16 120.57,85.62 UC1.AE15 120.57,85.62 v2(119.97,86.22) 119.37,86.82 UC1.AD13 UC1.AB12 v2(117.57,88.62) UC1.Y10 ; v2(119.97,79.02) 119.37,79.62 UC1.AD22 118.17,80.82 UC1.AB21 117.83,80.82 v2(117.49,81.15) 117.49,81.49 UC1.Y19 116.97,82.02 115.77,83.22 UC1.W18 ; UC1.W12 116.97,86.82 UC1.Y13 116.97,86.8 117.63,86.14 v2(117.63,86.09) 118.09,85.62 UC1.AB15 118.17,85.62 UC1.AD16 119.37,84.42 v2(119.97,83.82) 120.57,83.22 UC1.AE18 120.57,83.22 UC1.AG19 121.77,82.02 v2(122.37,81.42) 122.96,80.82 UC1.AH21 122.97,80.82 v2(123.57,80.22) 123.57,80.22 UC1.AK22 ; v2(124.6,89.97) 124.24,90.32 UC1.AK9 ; UC1.AN6 126.57,92.65 125.93,92.02 v2(125.93,91.64) ; UC1.U8 114.37,91.12 v2(113.99,90.74) ; UC1.AK10 v2(124.68,88.7)
  vias: v2(113.98,122.43) v2(113.98,121.79) v2(113.98,121.16) v2(113.98,120.52) v2(113.98,119.89) v2(113.98,119.25) v2(113.98,118.62) v2(114.61,122.43) v2(114.61,121.79) v2(114.61,121.16) v2(114.61,120.52) v2(114.61,119.89) v2(114.61,119.25) v2(114.61,118.62) v2(115.25,122.43) v2(115.25,121.79) v2(115.25,121.16) v2(115.25,120.52) v2(115.25,119.89) v2(115.25,119.25) v2(115.25,118.62) v2(115.88,122.43) v2(115.88,121.79) v2(115.88,121.16) v2(115.88,120.52) v2(115.88,119.89) v2(115.88,119.25) v2(115.88,118.62) v2(116.52,121.79) v2(116.52,121.16) v2(116.52,120.52) v2(116.52,119.89) v2(116.52,119.25) v2(116.52,118.62) v2(117.15,121.79) v2(117.15,121.16) v2(117.79,121.79) v2(117.79,121.16) v2(118.42,121.79) v2(118.42,121.16) v2(118.67,130.43) v2(119.06,121.79) v2(119.06,121.16) v2(119.44,130.43) v2(119.69,121.79) v2(119.69,121.16) v2(119.82,129.16) v2(119.82,128.4) v4(117.79,120.08)
+APU_CORE_GFX: length 70.6
  TOP w0.254: PR527.2 69.97,33.08 v2(69.14,33.91)
  BOTTOM w0.254: v2(69.14,33.91) 69.14,35.94 69.78,36.58 75.18,36.58 77.02,38.42 77.02,61.06 75.57,62.51 73.7,62.51 ; UC1.L22 109.36,79.62 v2(109.09,79.89) ; v2(111.57,80.22) 110.97,80.82 UC1.N21
  BOTTOM w0.305: UC1.P13 v2(112.77,86.22) ; UC1.L19 v2(110.37,81.42) ; UC1.T21 113.4,80.82 v2(114.08,80.14) ; UC1.U13 v2(115.17,86.22) ; UC1.P16 v2(112.77,83.82) ; UC1.J8 107.67,90.82 v2(107.88,90.82) ; v2(115.29,79.12) 114.8,79.62 UC1.U22 ; UC1.L13 v2(110.37,86.22) ; UC1.N12 v2(111.57,87.42) ; UC1.K7 108.39,91.92 v2(107.89,91.42) ; v2(105.48,86.88) 105.27,87.09 UC1.F12 ; UC1.L8 109.97,91.12 v2(110.37,90.72) ; UC1.K19 v2(109.17,81.42) ; UC1.F15 105.27,84.82 v2(105.67,84.42) ; v2(114.09,82.62) 113.49,83.22 UC1.T18 ; v2(107.9,88.02) 107.9,88.42 107.7,88.62 UC1.J11 ; v2(115.17,81.42) 114.57,82.02 UC1.U19 ; v2(114.09,85.02) 113.49,85.62 UC1.T15 ; UC1.P19 112.17,82.02 v2(112.77,81.42) ; v2(112.71,91.57) 113.06,91.92 UC1.T7 ; UC1.P22 112.17,79.62 v2(112.77,79.02) ; UC1.J9 107.9,89.59 v2(107.9,89.22) ; v2(115.17,83.82) 114.57,84.42 UC1.U16 ; v2(109.03,85) 108.57,85.47 UC1.K15 ; UC1.G11 106.07,88.42 v2(106.47,88.02) ; v2(109.17,86.43) 108.78,86.82 UC1.K13 ; UC1.N18 v2(111.57,82.62) ; UC1.G14 106.07,86.02 v2(106.47,85.62) ; UC1.N15 v2(111.57,85.02) ; UC1.L16 v2(110.37,83.82) ; v2(112.77,90.72) 112.37,91.12 UC1.P8 ; UC1.T12 v2(113.97,87.42) ; v2(111.57,91.52) 111.17,91.92 UC1.N7 ; UC1.K12 v2(109.17,87.42) ; UC1.K16 v2(109.17,83.82)
  vias: v2(65.82,62.37) v2(65.82,61.61) v2(65.82,60.85) v2(65.82,60.08) v2(65.82,59.32) v2(66.48,63.63) v2(66.48,62.99) v2(67.24,63.63) v2(67.24,62.99) v2(67.62,58.93) v2(68,63.63) v2(68,62.99) v2(68.38,58.93) v2(68.76,63.63) v2(68.76,62.99) v2(69.14,62.36) v2(69.14,61.59) v2(69.14,60.83) v2(69.14,60.07) v2(69.14,59.31) v2(69.14,58.55) v2(69.53,63.63) v2(69.53,62.99) v2(69.91,62.36) v2(69.91,61.59) v2(69.91,60.83) v2(69.91,60.07) v2(69.91,59.31) v2(69.91,58.55) v2(70.29,63.63) v2(70.29,62.99) v2(70.55,58.83) v2(70.67,62.36) v2(71.05,63.63) v2(71.05,62.99) v2(71.15,58.53) v2(71.43,62.36) v2(71.75,58.83) v2(71.81,63.63) v2(71.81,62.99) v2(72.19,62.36) v2(72.47,58.6) v2(72.57,63.63) v2(72.57,62.99) v2(72.95,62.36) v2(73.2,58.83) v2(73.34,63.63) v2(73.34,62.99) v2(73.5,61.99) v2(110.34,79.31) v4(107.24,89.98)
+APU_CORE_NB: length 164.4
  TOP w0.254: v2(125.07,161.16) 124.84,161.4 PR1002.1
  TOP w0.508: v2(135.57,117.09) 135.13,117.53 C1084.1 ; C1078.1 v2(140.32,109.28) ; C1081.1 140.32,104.14 v2(140.33,104.13) ; C1082.1 v2(124.77,123.57)
  TOP w0.762: v2(101.61,115.83) 101.94,115.83 103.71,117.6 v4(112.01,117.6) 117.18,117.6 120.22,120.65 124.01,120.65
  IN1 w0.254: v2(125.07,161.16) 125.07,158.72 131.53,152.26 131.53,148.29 135.44,144.37 135.44,135.92 130.1,130.58 v2(130.1,127.13)
  IN1 w0.508: v2(126.28,80.23) 126.28,80.1
  IN1 w0.762: 46.48,70.61 50.22,70.61 50.41,70.8 58.1,70.8 58.86,70.04 61.44,70.04 61.89,70.5 61.89,76.7 66.86,81.66 71.56,81.66 87.06,97.17 87.06,97.7 88.83,99.47 88.83,102.22 95.56,108.95 96.69,108.95 v2(98.43,110.69)
  BOTTOM w0.635: Q135.1 44.62,65.94 42.89,64.2 42.89,61.94 38.98,58.04 U2.3
  BOTTOM w0.762: v2(101.61,115.83) 100.6,115.83 98.43,113.67 v2(98.43,110.69)
  vias: v2(45.65,71.37) v2(45.65,70.74) v2(124.77,122.94) v2(124.77,122.3) v2(124.77,121.67) v2(124.77,121.03) v2(124.77,120.4) v2(125.35,85.04) v2(125.38,82.68) v2(125.53,123.57) v2(125.53,122.94) v2(125.53,122.3) v2(125.53,121.67) v2(125.53,121.03) v2(125.53,120.4) v2(125.52,87.41) v2(125.58,80.25) v2(126.05,85.02) v2(126.08,82.66) v2(126.29,123.57) v2(126.29,122.94) v2(126.29,122.3) v2(126.29,121.67) v2(126.29,121.03) v2(126.29,120.4) v2(126.22,87.4) v2(127.06,123.57) v2(127.06,122.94) v2(127.06,122.3) v2(127.06,121.67) v2(127.06,121.03) v2(127.06,120.4)
+BIF_VDDC: length 3.3
  TOP w0.102: CV194.2 163.81,134.52 v1(163.85,134.48)
  BOTTOM w0.254: UV1.U21 162.58,133.27 v2(162.58,133.92) 162.58,134.05 UV1.R21
+CHGRTC:
  vias: v4(17.6,9.49)
+CODEC_AVDD2:
  vias: v1(184.93,8.69)
+DP_VDDC: length 0.7
  BOTTOM w0.305: UV1.AD14 168.43,127.16 v2(168.85,126.74)
+DP_VDDR: length 6.1
  TOP w0.508: CV26.1 172.62,125.31 171.84,124.52 170.64,124.52 v1(170.22,124.95) 169.94,125.22 v2(168.84,125.22)
  BOTTOM w0.305: UV1.AF14 168.51,125.56 v2(168.84,125.22)
+EC_VCCA: length 27.9
  TOP w0.102: v2(184.08,59.69) 184.08,59.5 v1(183.69,59.11)
  TOP w0.203: v2(176.09,77.32) 176.26,77.16 UE1.67
  TOP w0.508: PR24.2 184.08,60.25 v2(184.08,59.69)
  IN1 w0.508: v2(176.09,77.32) 178.34,75.07 179.77,75.07 180.56,74.29 180.56,73.01 184.64,68.92 184.64,66.85 184.32,66.53 184.32,64.81 184.09,64.58 184.09,59.7 v2(184.08,59.69)
  BOTTOM w0.508: LE3.2 178.2,77.08 CE21.1 176.34,77.08 v2(176.09,77.32)
+FAN_POWER:
  vias: v2(91.1,137.74) v2(91.1,137.11) v4(91.26,138.51)
+FBA_VREF0: length 17.9
  TOP w0.102: v2(163.38,165.18) 163.66,165.18 v1(164.23,165.75)
  IN1 w0.254: 160.43,164.72 160.09,164.72 159.82,164.45 157.47,164.45 157.24,164.68 157.24,165.2 157.49,165.44 160.19,165.44 160.43,165.2 160.43,164.72 ; 160.43,164.72 160.45,164.72
  IN1 w0.508: 157.24,164.68 156.42,164.68 155.26,163.53 v2(155.26,161.94) ; v2(161.61,164.4) 160.76,164.4 160.45,164.72
  BOTTOM w0.254: UV5.H1 v2(155.26,161.94) ; UV5.M8 161.6,164.4 v2(161.61,164.4)
  BOTTOM w0.508: RV42.2 RV44.1 CV100.1 163.73,165.53 v2(163.38,165.18)
+FBA_VREF1: length 32.4
  TOP w0.254: UV6.H1 162.06,161.54 162.52,161.54 162.87,161.89 162.87,162.06 ; CV101.1 154.88,164.01 155.25,164.37 156.03,164.37 UV6.M8
  TOP w0.508: v2(154.31,165.75) 154.28,165.78 RV43.2 RV45.1 CV101.1 ; v2(153.3,170.17) 154.59,171.46 v1(156.66,171.46) 161.47,171.46 163.18,169.76 163.18,167.86 164.74,166.29 164.74,165.35 162.87,163.49 162.87,162.06
  IN1 w0.508: v2(153.3,170.17) 153.3,166.36 153.9,165.75 v2(154.31,165.75)
+FBA_VREF2: length 15.3
  TOP w0.102: CV133.1 v1(188.7,162.8)
  TOP w0.254: v2(180.52,165.21) 180.52,165.17 UV7.M8 ; v2(186.92,161.17) UV7.H1
  TOP w0.508: v2(186.92,161.17) 187.03,161.17 188.39,159.81 RV50.2 RV52.1 CV133.1
  IN1 w0.254: v2(186.92,161.17) 186.92,162.44 184.87,164.49 182.2,164.49 181.49,165.21 v2(180.52,165.21)
+FBA_VREF3: length 36.5
  BOTTOM w0.254: RV53.1 RV51.2 188.7,166.52 188.44,166.79 187.85,166.79 187.53,167.11 187.53,170.45 186.15,171.83 v1(180.37,171.83) 178.44,171.83 176.35,169.74 176.35,160.79 176.85,160.29 178.5,160.29 178.85,160.63 178.85,161.29 179.13,161.57 UV8.H1 ; RV53.1 187.54,165.4 187.32,165.17 186.12,165.17 UV8.M8 ; RV53.1 CV134.1
+INV_PWR_SRC: length 4.6
  TOP w0.102: v4(78.23,156.88) 77.77,157.34 77.77,157.78 v2(77.5,158.05)
  TOP w0.127: v4(78.23,156.88) 79.38,155.73 v4(79.38,155.51) ; v2(77.5,158.05) 77.02,158.05 v4(76.45,157.48)
+LAN_REGOUT:
  vias: v1(53.51,172.92)
+LAN_VDD10: length 7.3
  TOP w0.203: v2(44.85,168.88) 44.86,168.87 UL1.3 ; v2(45.17,166.51) 45.53,166.87 UL1.8 ; UL1.30 47.34,171.41 46.92,171.83
  TOP w0.508: v2(45.78,171.88) CL6.1 46.23,172.52 46.92,171.83
  BOTTOM w0.508: v2(44.85,168.88) 44.85,168.73 45.3,168.27 CL8.1 ; CL7.1 45.18,166.5 v2(45.17,166.51)
  vias: v1(52.25,168.52) v2(56.83,170.81) v2(56.83,170.18)
+LAN_VDD33: length 47.4
  TOP w0.203: UL1.11 47.34,165.57 47.24,165.47 47.24,164.9 47.3,164.83 CL12.1
  TOP w0.508: 39.05,173.91 40.25,175.12 40.25,175.97 38.22,178 RL38.2 ; RL39.1 v2(50.73,175.69)
  IN1 w1.016: 46.37,164.52 46.37,165.19 47.17,165.99 53.77,165.99 54.28,166.5
  IN2 w0.508: v2(50.73,175.69) 51.11,175.31 51.11,171.58 50.41,170.88 47.17,170.88 45.97,169.67
  IN2 w1.016: 39.55,173.23 40.9,173.23 41.26,172.87 42.4,172.87 43.05,172.22 43.87,172.22 45.97,170.13 45.97,166.9 46.35,166.51 46.35,164.43
  BOTTOM w0.508: RL34.1 50.73,165.73 51.24,165.23 53.52,165.23 53.84,165.54 53.84,166.31
  vias: v2(38.03,173.23) v2(38.63,173.24) v2(46.01,163.56) v2(46.6,163.56) v2(54.69,167.28) v2(55.3,167.26) v4(39.62,172.21)
+LAN_VDDREG:
  vias: v1(51.86,169.75) v2(50.98,169.67) v2(51.43,170.05)
+LCDVDD:
  vias: v4(84.87,155.75)
+LCDVDD_CONN: length 4.5
  TOP w0.102: v2(79.76,157.19) 80.38,157.81 v4(80.56,157.81) ; v2(79.76,157.19) 78.94,158.01 v4(78.94,158.51) ; v2(79.76,157.19) 80.84,156.11 v4(81.08,156.11)
+MEM_VREF: length 20.9
  TOP w0.508: C29.1 R8.2 C30.2 R5.1 96.45,64.64 v2(96.96,64.13)
  BOTTOM w0.508: v2(96.96,64.13) 96.96,64.58 v1(99.24,66.87) 99.56,67.18 108.45,67.18 110.55,69.28 110.55,70.49
+MIC2-VREFO: length 15.1
  TOP w0.102: v2(181.68,19.55) v1(182.25,19.55)
  IN2 w0.508: v2(187.84,13.64) 187.84,13.89 185.89,15.84 181.83,15.84 180.65,17.02 180.65,18.52 v2(181.68,19.55)
  BOTTOM w0.203: v2(187.84,13.64) 187.55,13.64 187.28,13.38 UA1.29
  BOTTOM w0.508: RA1109.2 RA53.2 181.93,19.29 v2(181.68,19.55)
+MPLL_PVDD: length 0.8
  BOTTOM w0.254: UV1.L8 173.29,137.11 v2(173.69,136.71)
+MVREFDA: length 5
  TOP w0.102: RV33.2 157.13,136.88 157.13,135.78 v1(156.99,135.64)
  TOP w0.254: v2(159.25,137.99) 158.82,137.55 CV94.1 RV34.1 157.24,137.55 RV33.2
  BOTTOM w0.089: UV1.K26 158.89,138.35 v2(159.25,137.99)
+MVREFSA: length 4.8
  TOP w0.102: v1(159.71,136.78) 159.63,136.86 159.63,137.4 160.17,137.94 RV32.2
  TOP w0.254: RV32.2 160.12,137.94 v2(159.25,138.81) 158.93,138.49 CV95.1 RV35.1
  BOTTOM w0.254: UV1.J26 158.9,139.16 v2(159.25,138.81)
+RTC_APU: length 167.1
  TOP w0.508: v2(58.85,56.92) 57.27,55.35 50.55,55.35 50.13,55.76 45.4,55.76 44.14,57.02 35.95,57.02 28.63,49.7 28.63,42.73 27.4,41.5 27.4,37.21 v4(23.89,33.7) 22.2,32.02 21.02,32.02 18.47,29.46 18.47,24.32 15.68,21.53 15.68,16.23 v2(13.79,14.34) ; R93.2 v2(130.91,74.8)
  IN2 w0.508: v2(130.91,74.8) 128.8,74.8 128.58,75.02 126.51,75.02 126.17,74.68 125.74,74.68 125,75.41 124.45,75.41 123.55,76.31 121.62,76.31 121.24,75.93 113.66,75.93 113.26,75.54 112.5,75.54 112.03,76.01 106.68,76.01 105.97,75.31 99.84,75.31 98.67,74.14 92.79,74.14 92.79,74.15 87.47,74.15 77.72,64.39 59.49,64.39 58.32,63.22 58.32,57.44 v2(58.85,56.92)
  BOTTOM w0.508: v2(13.79,14.34) 13.01,13.56 C119.1 13.85,13.02 13.86,13.03 U101.3
+RTC_APU_R: length 88.3
  TOP w0.508: Q91.1 177.93,85.6 177.56,85.23 165.41,85.23 164.33,84.15 164.33,80.72 165.7,79.35 165.7,75.65 162.52,72.47 161.4,72.47 160.29,71.35 157.36,71.35 154.91,68.9 152.95,68.9 152.33,68.28 149.84,68.28 146.93,65.37 140.58,65.37 ; 140.58,65.37 139.12,66.83 v1(139.12,69.91) 139.12,71.27 137.04,73.36 135.15,73.36 133.86,74.65 ; 140.58,65.37 140.58,56.85 v2(142.21,55.22)
  IN2 w0.508: v2(129.07,83.2) 128.76,83.2 128.15,82.58 128.15,81.3 129.17,80.28 129.17,77.49 v2(129.09,77.42)
  BOTTOM w0.254: v2(129.07,83.2) 129.07,83.42 UC1.AR17
  BOTTOM w0.508: CLRP1.1 142.06,55.37 v2(142.21,55.22)
+RTCBATT:
  vias: v1(26.64,11.46)
+RTCVCC: length 168.4
  TOP w0.102: v4(55.87,14.86) 55.39,14.37 v2(55.39,14.34)
  IN1 w0.508: v2(161.85,9.84) 163.61,11.6 163.61,12.96 171.02,20.37 175.49,20.37 v2(176.02,20.89) ; v2(55.39,14.34) 50.99,14.34 50.01,15.32 36.15,15.32 34.69,13.86 24.26,13.86 23.06,15.06 v2(21.76,15.06)
  IN2 w0.508: v2(55.39,14.34) 56.53,13.2 79.01,13.2 79.84,14.02 91.31,14.02 96.06,9.27 161.28,9.27 v2(161.85,9.84)
  BOTTOM w0.508: v2(176.02,20.89) 176.78,20.89 177.38,21.49 RA5.1
+SPI_VCC: length 88.9
  TOP w0.127: v1(167,73.34) R1675.2
  TOP w0.508: v2(172.45,84.35) 172.45,84 171.96,83.52 170.58,83.52 170.13,83.96 166.35,83.96 v2(165.14,82.75) 165.45,82.75 167.15,81.05 167.15,76.24 165.58,74.66 R1675.2 164.45,73.34 162.96,71.86 162.44,71.86 162.18,71.86 161.66,71.86 160.54,70.74 157.61,70.74 154.4,67.53 v2(153.96,67.53)
  IN1 w0.508: v2(139.73,93.4) 139.95,93.18 v2(139.95,90.75) 140.28,90.75 141.17,91.64 143.7,91.64 145.7,89.64 145.7,88.49 147.14,87.06 148.33,87.06 149.05,86.33 149.98,86.33 151.59,84.72 151.59,81.93 153.34,80.18 153.34,79.04 153.49,78.9 153.49,75.12 153.74,74.87 153.74,67.74 v2(153.96,67.53)
  BOTTOM w0.508: R1672.2 158.82,84.76 R642.2 ; R1672.2 159.51,84.77 159.76,85.03 U56.8 161.39,85.03 162.25,84.17 162.25,83.11 162.61,82.75 v2(165.14,82.75) ; R1672.2 R1673.2 158.81,86.69 C635.1 ; R634.2 139.37,93.03 v2(139.73,93.4) ; v2(139.95,90.75) 139.56,90.37 R636.2 ; v2(172.45,84.35) 172.45,83.83 172.05,83.44 R639.2 R640.2 R635.2
+SPLL_PVDD: length 10.5
  TOP w0.508: LV7.2 183.69,138.91 CV84.1 182.48,139 CV85.1 181.46,139 CV86.1 180.35,139 v2(179.8,138.45)
  IN2 w0.508: v2(179.8,138.45) 179.08,139.17 174.94,139.17 v2(174.5,139.61)
  BOTTOM w0.254: UV1.H7 174.16,139.96 v2(174.5,139.61)
+SPLL_VDDC: length 9.7
  TOP w0.508: LV8.2 CV91.1 182.51,139.87 CV93.1 180.51,139.87 CV92.1 180.46,139.82 178.79,139.82 v2(178.77,139.8)
  IN1 w0.508: 175.23,140.43 175.6,140.79 178.02,140.79 178.79,140.03 178.79,139.82 v2(178.77,139.8)
  BOTTOM w0.254: UV1.H8 173.29,139.91 v2(173.64,139.56)
+TPUSB_VCC: length 30.1
  IN1 w0.508: v2(162.3,12.25) 162.3,12.51 170.77,20.98 v2(173.47,20.98)
  IN2 w0.508: v2(168.27,30.73) 167.96,30.43 167.96,23.81 168.79,22.99 171.46,22.99 v2(173.47,20.98)
  BOTTOM w0.508: UL4.1 v2(162.3,12.25) ; R153.2 v2(168.27,30.73)
  vias: v1(174.83,21.11)
+TPUSB_VCC_IN: length 23.2
  IN2 w0.508: v2(162.81,16.26) 164.15,17.6 166.06,17.6 167.36,18.9 v2(174.68,18.9)
  BOTTOM w0.127: R151.2 164.1,16.95 v1(165.18,18.03)
  BOTTOM w0.508: UL4.5 161.29,14.41 159.76,14.41 159.17,13.83 159.17,11.61 159.81,10.97 R44.1 ; R152.2 175.25,19.47 v2(174.68,18.9)
+TSVDD: length 9.3
  IN1 w0.508: v2(168.29,120.9) 165.97,123.21 165.97,126.4 166.29,126.72 v2(166.52,126.72)
  BOTTOM w0.102: CV19.1 v1(168.83,116.63)
  BOTTOM w0.254: UV1.AD17 166.08,127.16 v2(166.52,126.72)
+V_DAC: length 18.2
  TOP w0.508: TL2.3 25.03,168.93 24.44,169.52 24.44,172.4 v2(24.78,172.74) TL2.6
  BOTTOM w0.102: v1(28.62,173.74) 28.68,173.67 CL41.2
  BOTTOM w0.508: CL41.2 28.67,172.74 TL2.6 v2(24.78,172.74) 24.44,172.4 24.44,169.52 25.03,168.93 TL2.3
+V_EC: length 4.6
  TOP w0.508: RE28.1 RE27.1 173.41,68.83 v2(173.21,69.04)
  BOTTOM w0.508: RE25.2 RE26.2 v1(172.46,69.72) 172.52,69.72 v2(173.21,69.04)
+V_TP:
  vias: v1(57.14,80.2)
+V_TS: length 1.6
  TOP w0.102: CX51.1 83.84,155.27 v1(83.48,155.63)
+V_UV4: length 2.8
  TOP w0.102: v1(179.1,132.54) 178.5,131.94 178.5,130.6 178.92,130.18 UV4.5
+VDISPLAY_VCC: length 16.6
  TOP w0.102: RZ54.1 14.06,80.42 v1(13.96,80.52)
  IN1 w1.016: 15.1,73.74 12.54,71.19 12.54,70.17
  IN2 w1.016: 31.24,76.33 30.54,77.04 26.51,77.04 25.24,75.77 21.18,75.77
  vias: v2(15.83,74.56) v2(16.33,74.98) v2(20.03,74.63) v2(20.47,75.07) v2(32.15,75.36) v2(32.15,74.78)
+VGA_CORE: length 46.3
  TOP w0.508: RV161.2 161.89,124.17 v2(161.69,124.37)
  IN1 w0.508: v2(161.69,124.37) 161.69,127.22 v2(164.61,130.15)
  BOTTOM w0.305: v2(172.88,130.99) 172.51,131.36 UV1.W9
  BOTTOM w0.381: UV1.N17 UV1.R18 165.09,134.53 v2(164.62,134.06) 164.12,133.56 UV1.T20 ; UV1.U10 171.69,132.98 v2(171.44,133.23) 171.44,133.51 UV1.T10 ; UV1.U10 172.49,131.76 UV1.W9 UV1.W10 171.69,131 v2(172.02,130.67) 172.49,130.2 UV1.Y9 ; UV1.U10 171.09,132.56 UV1.U11 170.69,132.76 UV1.T12 169.69,133.56 UV1.U13 168.83,132.76 168.39,132.32 v2(168.39,132.28) 168.35,132.28 167.89,131.82 UV1.V15 UV1.Y16 166.89,130.59 v2(166.5,130.21) ; UV1.N15 UV1.R16 166.89,134.46 v2(166.49,134.06) 166.09,133.66 UV1.T17 165.29,132.76 UV1.U18 v2(164.63,132.3) UV1.V20 UV1.V21 UV1.Y21 ; v2(170.38,129.32) 169.94,129.76 UV1.AA12 169.41,129.28 v2(169.3,129.28) 168.89,128.87 UV1.AB13 ; UV1.Y13 168.89,130.69 168.41,130.21 v2(168.4,130.21) 168.4,130.2 167.96,129.76 UV1.AA15 UV1.AB13 ; UV1.AB13 168.29,128.16 UV1.AC14 ; v2(164.61,130.15) 165.09,130.62 UV1.Y18 UV1.V17 166.09,131.89 v2(166.5,132.29) 166.89,132.69 UV1.U16 167.09,132.76 UV1.T15 167.91,133.56 v2(168.39,134.03) 168.89,134.54 UV1.R13 UV1.N12 UV1.M11
  vias: v1(181.97,119.34) v2(176.48,127.47) v2(177.41,127.41) v2(180.37,124.68) v2(180.37,124.04) v2(180.37,123.41) v2(181.01,124.68) v2(181.01,124.04) v2(181.01,123.41) v2(186.04,115.76) v2(186.04,115.11) v2(188.4,120.4) v2(188.4,119.76) v2(188.4,119.13) v2(188.52,118.49) v2(188.52,117.86) v2(189.16,120.4) v2(189.16,119.76) v2(189.16,119.13) v2(189.29,118.49) v2(189.29,117.86) v2(189.54,117.22) v2(189.54,116.59) v2(189.54,115.95) v2(189.86,115.37) v2(190.05,118.49) v2(190.05,117.86) v2(190.18,117.22) v2(190.18,116.59) v2(190.18,115.95) v2(190.53,115.38) v2(190.81,118.49) v2(190.81,117.86) v2(190.81,117.22) v2(190.81,116.59) v2(190.81,115.95) v2(191.45,117.22) v2(191.45,116.64) v2(191.57,118.49) v2(191.57,117.86) v2(192.33,118.49) v2(192.33,117.86) v2(192.32,117.2) v2(192.72,121.06) v2(192.72,120.43) v2(192.72,119.79) v2(192.72,119.13) v2(192.97,121.92) v2(193.05,122.68) v2(193.1,118.49) v2(193.1,117.86) v2(193.13,117.2) v2(193.35,121.16) v2(193.35,120.52) v2(193.35,119.89) v2(193.35,119.25) v2(193.73,122.68) v2(193.73,121.92) v2(193.86,118.49) v2(193.86,117.86) v2(193.86,117.2) v2(193.99,121.16) v2(193.99,120.52) v2(193.99,119.89) v2(193.99,119.25) v2(194.37,122.68) v2(194.37,121.92) v2(194.6,117.18) v2(194.62,118.49) v2(194.62,117.86) v2(195.13,122.68) v2(195.13,121.92) v2(195.38,118.49) v2(195.38,117.86) v2(195.89,122.68) v2(195.89,121.92)
+VREF_CA: length 39.3
  TOP w0.102: v1(132.24,14.17) C147.1
  TOP w0.381: C148.1 R56.2 C145.1 126.12,14.17 125.71,13.77 R55.1 ; C148.1 128.45,15.11 v2(128.71,15.37) ; C148.1 C134.1 C167.2 C147.1 ; C174.2 123.64,31.51 C139.1 123.66,31.53 C186.1 122.75,32.35 C159.1 122.47,32.61 121.44,32.61 v2(121.44,32.61)
  IN2 w0.381: v2(128.71,15.37) 128.2,15.88 128.2,19.69 126.23,21.65 124.45,21.65 123.4,22.71 123.4,24.81 122.49,25.72 122.49,28.94 122.04,29.39 121.47,29.39 120.82,30.04 120.82,32 v2(121.44,32.61)
  BOTTOM w0.381: v2(121.44,32.61) 121.44,32.38 120.2,31.14 JDIMM2.126 ; JDIMM1.126 128.4,15.67 v2(128.71,15.37)
+VREF_DQ: length 80.1
  TOP w0.381: C183.1 80.29,37.9 ; 80.29,37.9 80.29,37.91 C180.2 ; 80.29,37.9 C143.1 ; C146.1 C137.1 87.66,25.61 C135.1 87.62,26.42 87.19,26.85 86.32,26.85 v2(85.9,27.26) ; C146.1 88.52,23.71 R57.1 88.56,24.59 C142.1 88.55,24.61 C179.2 ; C146.1 87.66,22.82 R59.2 ; C161.1 80.27,38.79 C180.2 ; C180.2 80.29,39.47 v2(80.32,39.5) 80.32,39.75 79.3,40.77 79.3,49.45 80.61,50.75 80.61,57.82 81.34,58.55 83.28,58.55 90.27,65.53 v2(90.65,65.53)
  IN2 w0.381: v2(80.32,39.5) 81.39,39.5 84.97,35.93 84.97,32.12 85.15,31.94 85.15,27.94 85.82,27.26 v2(85.9,27.26)
  BOTTOM w0.356: v2(85.9,27.26) 87.05,26.11 88.19,26.11 88.5,25.81 JDIMM1.1 ; JDIMM2.1 80.3,39.48 v2(80.32,39.5)
  BOTTOM w0.381: v2(90.65,65.53) 93.47,65.53 v1(94.92,66.99) 95.81,67.88 95.81,75.37 96.31,75.87 RZ1049.1
A_MIC_CLK: length 307
  IN1 w0.102: v2(74.81,39.41) 74.22,39.41 73.37,38.56 66.15,38.56 63.56,41.15 58.21,41.15 57.59,41.77 57.59,53.02 56.25,54.36 56.25,57.29 58.63,59.68 58.63,64.86 61.74,67.97 61.74,68.73 63.04,70.02 63.04,76.22 65.66,78.84 70.41,78.84 88.2,96.63 88.2,97.23 90.02,99.04 90.02,101.79 95.95,107.72 97.3,107.72 100.34,110.76 100.34,111.84 102.55,114.05 102.55,130.17 99.17,133.55 95.61,133.55 93.78,135.38 93.78,139.28 90.04,143.03 90.04,144.38 88.65,145.76 88.65,148.85 88.86,149.06 88.86,154.22 92.54,157.9 92.54,161.79 v2(94.01,163.26)
  IN2 w0.102: v2(74.81,39.41) 75.96,39.41 80.06,35.31 80.06,33.07 79.65,32.66 79.65,26.97 81.22,25.39 81.22,21.47 84.72,17.98 96.07,17.98 100.21,13.84 148.39,13.84 150.21,15.66 150.21,17.26 151.88,18.94 155.37,18.94 158.65,15.65 163.08,15.65 164.43,16.99 171.47,16.99 174.92,13.54 174.92,11.9 v2(176.09,10.73)
  BOTTOM w0.102: JEDP.27 93.8,165.02 93.61,164.82 93.61,163.66 v2(94.01,163.26) ; LA1.2 CA22.1 176.09,9.97 v2(176.09,10.73)
A_MIC_DATA: length 312.1
  TOP w0.102: v1(74.05,38.01) 74.39,38.35 v2(74.39,39)
  IN1 w0.102: v2(74.39,39) 73.54,38.15 65.99,38.15 63.4,40.74 58.04,40.74 57.18,41.6 57.18,52.85 55.84,54.19 55.84,57.46 58.22,59.84 58.22,65.02 61.33,68.14 61.33,68.9 62.63,70.19 62.63,76.39 65.49,79.25 70.24,79.25 87.8,96.8 87.8,97.4 89.57,99.17 89.57,101.91 95.85,108.19 97.08,108.19 99.9,111.02 99.9,111.99 102.14,114.22 102.14,130.01 99,133.15 95.44,133.15 93.38,135.21 93.38,139.11 89.63,142.86 89.63,144.21 88.25,145.59 88.25,149.02 88.45,149.22 88.45,154.41 92.13,158.09 92.13,161.98 v2(94.02,163.87)
  IN2 w0.102: v2(179.76,11.05) 179.61,11.2 179.09,11.2 177.54,9.65 176.54,9.65 174.51,11.67 174.51,13.37 171.3,16.59 164.6,16.59 163.25,15.24 158.49,15.24 155.2,18.53 152.05,18.53 150.62,17.09 150.62,15.49 148.56,13.44 100.04,13.44 95.91,17.57 84.55,17.57 80.82,21.31 80.82,25.22 79.24,26.8 79.24,32.83 79.65,33.24 79.65,35.14 76.1,38.7 75.79,39 v2(74.39,39)
  BOTTOM w0.102: v2(179.76,11.05) 179.83,10.98 UA1.2 ; v2(94.02,163.87) 94.02,164.66 94.3,164.93 JEDP.28
ACIN: length 311.5
  TOP w0.102: v2(181.42,129.36) 181.76,129.7 RV149.1 181.18,130.18 181.18,130.18 UV4.1
  TOP w0.127: CE40.2 184.35,62.04 UE1.110 184.35,64.77 184.24,64.87 184.24,66.01 185.78,67.55 189.49,67.55 190.47,66.57 191.6,66.57 v2(191.64,66.54) ; v2(139.45,153.78) v4(138.75,153.78)
  TOP w0.254: v2(68.52,169.18) 67.98,168.63 67.98,162.64 68.32,162.29 68.99,162.29 69.17,162.47 PQ707.5 ; v2(139.45,153.78) 139.96,153.28 PR1.1
  IN1 w0.127: v2(191.64,66.54) 192.22,67.12 192.22,68.88 191.36,69.74 191.36,72.19 191.94,72.78 191.94,73.77 191.32,74.4 191.32,75.31 194.26,78.26 194.26,80.52 194.2,80.58 194.2,82.81 194.26,82.87 194.26,111.97 196.84,114.55 196.84,126.51 194.32,129.03 187.34,129.03 186.13,127.81 184.15,127.81 182.6,129.36 v2(181.42,129.36)
  IN1 w0.254: v2(139.45,153.78) 132.33,153.78 127.81,158.31 127.81,161.61 125.91,163.5 118.34,163.5 115.46,166.38 v2(113.9,166.38)
  IN2 w0.127: v2(181.42,129.36) 181.42,130.6 180.33,131.69 180.33,134.92 181.03,135.62 182.72,135.62 184.97,137.86 186.52,137.86 187.76,139.1 187.76,147.73 189.11,149.08 189.11,172.21 v2(188.98,172.34)
  IN2 w0.254: v2(113.9,166.38) 113.9,166.34 114.62,165.62 114.62,165.13 114.18,164.68 114.18,164.49 112.31,162.62 110.76,162.62 103.28,170.1 101.57,170.1 101.08,170.6 86.4,170.6 85.74,169.94 82.87,169.94 82.77,169.84 79.98,169.84 79.32,169.18 v2(68.52,169.18)
  BOTTOM w0.203: PR741.2 113.42,164.83 113.69,165.1 113.69,166.17 v2(113.9,166.38) 114.19,166.67 PU703.2
  BOTTOM w0.254: v2(188.98,172.34) 187.05,174.27 166.52,174.27 163.51,171.26 152.19,171.26 150.92,169.99 150.92,162.67 149.47,161.23 146.44,161.23 144.96,159.75 144.96,157.45 141.29,153.78 v2(139.45,153.78) ; PR731.1 PR741.2
ACIN_65W: length 109.2
  TOP w0.102: UV4.2 181.49,130.83 RV149.2 182.21,130.64 182.21,130.25 182.33,130.13 QV8.2 183.39,130.13 183.74,129.78 183.74,128.77 RV92.2 184.6,128.93 185.85,128.93 v2(186.02,128.75)
  TOP w0.127: v2(172.58,79.14) v1(172.58,77.9) 172.58,76.95 172.83,76.71 RE80.2
  IN1 w0.127: v2(191.84,69.91) 192.42,70.5 192.42,73.62 191.55,74.49 191.55,75.22 194.49,78.16 194.49,80.62 194.43,80.68 194.43,82.71 194.49,82.77 194.49,111.81 197.07,114.38 197.07,126.61 194.41,129.26 187.25,129.26 186.74,128.75 v2(186.02,128.75)
  IN2 w0.127: v2(172.58,79.14) 172.58,76.94 181.71,67.81 188.46,67.81 190.57,69.91 v2(191.84,69.91)
ACIN_CHG: length 41.1
  TOP w0.127: PD706.2 78.73,173.02 v1(78.75,173.04)
  IN2 w0.381: v2(80.77,170.29) 80.88,170.41 85.62,170.41 86.23,171.02 101.25,171.02 101.75,170.52 103.54,170.52 111.02,163.04 112.13,163.04 113.7,164.6 113.7,164.85 v2(114.12,165.27)
  BOTTOM w0.203: PU703.1 114.51,166.27 114.1,165.86 114.1,165.29 v2(114.12,165.27)
ACLIM: length 9.6
  BOTTOM w0.203: PU703.16 118.35,170.09 119.28,171.01 120.58,171.01 v1(120.88,170.72) 121.25,170.35 121.77,170.35 122.54,171.11 122.54,172.14 PR749.1
  BOTTOM w0.254: PR749.1 123.81,172.51 PR751.2 124.07,172.77 PR722.1
ACOFF: length 182.6
  TOP w0.127: UE1.27 191.48,75.96 v2(190.82,75.3)
  TOP w0.254: PQ707.2 v1(69.17,167.06) 69.51,167.4 v2(69.84,167.4)
  IN1 w0.127: v2(93.31,149.89) 94.06,149.89 94.71,149.24 94.71,143.69 111.69,126.71 128.46,126.71 134.15,121.02 144.07,121.02 150.27,114.81 157.53,114.81 164.34,108 164.34,99.35 165.65,98.05 165.65,91.07 165.88,90.84 166.9,90.84 167.51,90.23 167.51,89.6 168.27,88.84 168.75,88.84 169.42,88.16 169.42,86.52 170.83,85.12 173.72,85.12 176.6,82.24 177.41,82.24 178.01,81.64 178.01,80.99 178.55,80.45 179.54,80.45 182.12,77.87 182.12,76.48 183.22,75.39 184.11,75.39 185.1,74.4 185.81,74.4 186.42,73.79 188.25,73.79 189.76,75.3 v2(190.82,75.3)
  IN2 w0.127: v2(69.84,167.4) 70.29,166.95 70.29,166.17 76.17,160.29 79.68,160.29 80.96,159 80.96,157.01 82.28,155.69 82.28,154.24 86.02,150.5 90.78,150.5 91.39,149.89 v2(93.31,149.89)
AD_BID0: length 5.9
  TOP w0.127: UE1.66 176.58,77.56 176.35,77.79 175.81,77.79 175.62,77.6 CE39.1 RE22.2 RE20.1 v1(175.91,79.37)
AD_I_HW1: length 6.3
  TOP w0.127: v2(188.02,67.11) 188.02,66.69 188.37,66.33 188.37,65.39 187.95,64.97 187.39,64.97 187.15,64.73 UE1.117
  BOTTOM w0.127: v1(188.55,67.86) 188.02,67.32 v2(188.02,67.11) 187.9,66.99 PQ4.2
AD_I_HW2: length 4.5
  TOP w0.127: v2(183.74,65.21) 183.44,65.21 183.15,64.92 UE1.107
  BOTTOM w0.127: v2(183.74,65.21) 184.08,65.56 184.08,66.56 184.51,66.99 PQ4.5
ADP_I: length 174.3
  TOP w0.127: v2(182.85,65.8) 182.85,67.3 185.65,70.1 185.65,74.41 v2(185.27,74.79) ; v2(178.65,81.23) 178.75,81.13 178.75,78.23 178.47,77.96 UE1.65
  IN1 w0.127: v2(110.74,167.65) 109.17,167.65 108.25,166.73 108.25,160.66 99.97,152.38 99.97,139.08 111.88,127.17 128.65,127.17 134.34,121.48 144.26,121.48 150.46,115.27 157.72,115.27 164.8,108.19 164.8,99.54 166.17,98.17 166.17,93.64 166.44,93.37 167.05,93.37 167.38,93.04 167.38,91.26 169.88,88.76 169.88,86.71 171.02,85.57 173.91,85.57 176.51,82.98 177.32,82.98 178.65,81.64 v2(178.65,81.23) 179.45,81.23 182.68,77.99 182.68,77.03 184.09,75.63 184.44,75.63 v2(185.27,74.79)
  BOTTOM w0.127: v2(185.27,74.79) v1(185.27,75.31)
  BOTTOM w0.254: PR23.2 182.56,66.09 v2(182.85,65.8) ; v2(110.74,167.65) 111.12,168.03 PC748.1 PR774.1
AGPIO4: length 19.9
  TOP w0.127: v2(139.69,97.96) v1(140.35,97.96)
  IN1 w0.102: 136.73,96.78 130.61,96.78 129.37,95.53 129.37,94.42 129.15,94.21 128.26,94.21 128.02,93.97 128.02,93.48 127.43,92.89 126.9,92.89 126.71,93.08 v2(125.97,93.08)
  IN1 w0.107: 136.73,96.78 137.74,96.78 138.42,97.46 139.24,97.46 139.69,97.91 v2(139.69,97.96)
  BOTTOM w0.102: v2(125.97,93.08) 125.61,92.72 UC1.AL6
  BOTTOM w0.127: R931.2 140.52,98.78 v2(139.69,97.96)
AGPIO8: length 24.5
  TOP w0.102: v2(125.03,93.97) v1(125.03,93.43)
  IN1 w0.102: 136.73,97.66 135.59,97.66 135.08,97.15 128.9,97.15 127.72,95.97 127.72,93.46 127.35,93.09 126.98,93.09 126.61,93.46 125.54,93.46 v2(125.03,93.97)
  IN1 w0.127: 136.73,97.66 137.85,97.66 138.04,97.85 v2(138.93,97.85)
  BOTTOM w0.102: UC1.AJ4 124.11,93.97 v2(125.03,93.97)
  BOTTOM w0.127: R22.1 139.85,101.61 139.02,100.79 139.02,99.85 R932.2 139.63,98.55 v2(138.93,97.85)
AGPIO11: length 15
  TOP w0.102: v2(127.05,102.21) 126.87,102.21 126.55,102.53 v1(126.55,104.39) R953.1 R954.2
  IN1 w0.102: v2(127.05,102.21) 126.55,101.71 126.55,98.42 125.76,97.63 125.76,95.28 126.1,94.93 126.1,94.86 126.63,94.34 126.63,93.99 v2(127.13,93.49)
  BOTTOM w0.102: UC1.AN5 127.09,93.52 v2(127.13,93.49)
AGPIO25: length 6
  BOTTOM w0.102: UC1.BC2 135.44,95.45 135.44,94.61 136.12,93.93 138.17,93.93 138.22,93.98
  BOTTOM w0.127: 138.22,93.98 v1(138.43,94.19) 138.98,94.74 R661.1
AGPIO64: length 15.8
  TOP w0.102: 140.12,86.19 139.69,86.19 v1(139.19,85.69) 138.8,85.31 135.39,85.31 134.8,84.72 131.58,84.72 131.4,84.55 v2(131.4,84.25)
  TOP w0.127: R934.2 144.51,87.92 143.83,87.25 143.51,87.25 142.45,86.19 140.12,86.19
  BOTTOM w0.102: v2(131.4,84.25) 131.4,84.56 UC1.AW15
AGPIO65: length 18.4
  TOP w0.102: v2(131.59,86.78) 131.82,87.01 133.74,87.01 v1(134.82,88.09) 136.26,89.53 136.61,89.53 136.87,89.8 139.56,89.8 140.44,90.68 140.44,90.74 141.45,91.76 142.15,91.76
  TOP w0.127: 142.15,91.76 144.32,91.76 R692.2 R693.1
  BOTTOM w0.102: v2(131.59,86.78) 131.48,86.66 131.48,86.12 131.22,85.86 131.08,85.86 130.27,85.05 UC1.AU15
AGPIO66: length 19.4
  TOP w0.102: R935.2 143.95,89.46 143.95,89.86 143.72,90.09 143.72,90.78 143.31,91.19 141.52,91.19 139.59,89.26 139.04,89.26 138.72,88.93 v1(138.72,88.93) 138.31,88.93 135.98,86.6 132.29,86.6 131.83,86.14 130.25,86.14 v2(129.8,85.7)
  BOTTOM w0.102: v2(129.8,85.7) 129.47,85.36 UC1.AT15
AGPIO69: length 19
  TOP w0.102: v2(129.71,86.82) 130.19,86.35 131.71,86.35 132.16,86.8 133.97,86.8 136.11,88.95 v1(136.31,88.95) 136.82,89.46 139.51,89.46 141.58,91.53 142.15,91.53
  TOP w0.127: 142.15,91.53 143.45,91.53 144.06,90.92 144.06,90.23 R936.2
  BOTTOM w0.102: UC1.AT14 129.47,86.58 v2(129.71,86.82)
APU_ALERT#: length 20.4
  TOP w0.102: R134.2 84.13,83.26 v1(86.94,83.26) 90.02,83.26 91.51,81.78 96.21,81.78 v2(97.23,82.8)
  BOTTOM w0.102: RP25.2 v2(97.23,82.8) 97.68,83.25 100.27,83.25 100.46,83.44 101.37,83.44 101.46,83.53 101.75,83.82 UC1.B17
APU_COREGFX_SEN_H: length 91.2
  TOP w0.254: PR527.1 69.96,30.73 PR529.2 69.09,29.77 69.78,29.08 75.11,29.08 76.38,30.35 76.38,40.13 77.15,40.89 77.15,48.45 79.81,51.12 79.81,76.2 81.06,77.44 v2(82.5,77.44)
  IN2 w0.102: 100.23,87.92 100.27,87.96 103.48,87.96 103.93,87.5 106.75,87.5 v2(107.27,88.02)
  IN2 w0.254: 100.23,87.92 99.79,87.48 99.18,87.48 95.14,83.44 93.29,83.44 92.45,82.6 92.45,81.84 91.47,80.86 90.71,80.86 90.6,80.98 86.26,80.98 82.73,77.44 v2(82.5,77.44)
  BOTTOM w0.102: v2(107.27,88.02) 106.87,88.42 UC1.H11
APU_COREGFX_SEN_L: length 78
  TOP w0.254: v2(86.38,76.9) 81.02,76.9 80.19,76.08 80.19,50.93 77.53,48.26 77.53,40.58 76.76,39.81 76.76,30.16 75.24,28.64 65.72,28.64 v1(64.89,29.46) v2(63.94,30.42)
  IN1 w0.254: v2(65.08,35.94) 64.57,35.94 64.19,35.56 64.19,34.16 63.84,33.81 63.84,32.61 64.75,31.69 64.75,30.78 64.38,30.42 v2(63.94,30.42)
  BOTTOM w0.254: R20.2 87.35,76.9 v2(86.38,76.9) ; PR531.1 63.54,30.81 v2(63.94,30.42) ; PR530.2 v2(65.08,35.94)
APU_DBRDY: length 63.3
  TOP w0.102: v2(55.94,65.24) 55.72,65.02 JHDT1.14
  IN2 w0.102: v2(55.94,65.24) 55.89,65.29 55.89,67.68 56.37,68.17 57.48,69.28 58.53,69.28 58.86,69.61 59.35,69.61 60.17,68.79 75.36,68.79 78.57,72 80.47,72 87.35,78.88 92.19,78.88 93.32,80.01 94.11,80.01 94.82,80.72 95.28,80.72 95.57,81.01 98.68,81.01 100.67,83 100.67,83.14 103.3,85.78 v2(103.3,86.59)
  BOTTOM w0.102: v1(56.34,65.67) 55.94,65.27 v2(55.94,65.24) ; UC1.C13 102.87,87.02 v2(103.3,86.59)
APU_DBREQ#: length 63.5
  TOP w0.102: R672.2 56.39,64.73 57.33,65.67 57.33,68.77 v2(56.38,69.72) 56.38,70.36 56.24,70.5 RP28.4
  IN2 w0.102: v2(56.38,69.72) 57.51,70.85 59.56,70.85 60.64,69.78 74.95,69.78 78.16,72.99 80.06,72.99 86.94,79.87 91.77,79.87 93.62,81.71 94.86,81.71 95.15,82 98.27,82 99.83,83.56 99.83,85.13 100.62,85.92 v2(100.62,86.36)
  BOTTOM w0.102: UC1.A11 101.16,88.62 100.27,87.73 100.27,86.71 v2(100.62,86.36)
APU_DBREQ#_R: length 2.8
  TOP w0.102: JHDT1.16 54.97,63.75 R672.1
APU_DP1_TXN0: length 14.1
  BOTTOM w0.102: UC1.A3 101.27,95.09 101.18,95.18 100.63,95.18 100.2,95.62 99.41,95.62 99.4,95.61 99.39,95.61
  BOTTOM w0.127: 99.39,95.61 96.43,95.61 94.44,97.6 v3(92.67,97.6) 88.84,97.6 CZ30.1
APU_DP1_TXN0_VGA: length 65.3
  TOP w0.127: RZ1046.2 44.06,75.26 44.06,75.59 v2(43.91,75.74)
  IN2 w0.127: v2(86.35,97.46) 86.35,97.49 86.65,97.79 89.85,97.79 90.49,97.14 90.49,95.01 86.23,90.74 80.64,90.74 71.62,81.73 67.83,81.73 67.27,81.17 67.27,81.13 66.96,80.83 48.13,80.83 44.12,76.81 44.12,75.96 43.91,75.75 v2(43.91,75.74)
  BOTTOM w0.127: v2(43.91,75.74) 44.06,75.59 44.06,75.26 RZ1046.2 ; CZ30.2 87.17,97.72 86.61,97.72 v2(86.35,97.46)
APU_DP1_TXN1: length 12.8
  BOTTOM w0.102: 99.39,94.84 99.43,94.84 99.44,94.86 100.13,94.86 100.42,94.57 100.73,94.57 101.13,94.17 101.28,94.17 101.31,94.2 101.31,94.29 101.36,94.35 101.61,94.35 101.67,94.29 UC1.A4
  BOTTOM w0.127: 99.39,94.84 v3(96.98,94.84) 95.97,94.84 94.93,95.89 94.35,96.46 90.66,96.46 90.54,96.34 90.54,96.2 CZ31.1
APU_DP1_TXN1_VGA: length 61
  TOP w0.127: v2(42.11,75.91) 42.27,75.74 42.27,75.25 RZ1048.2
  IN2 w0.127: v2(42.11,75.91) 42.28,76.08 42.28,76.59 47.43,81.74 66.46,81.74 67.27,82.55 71.07,82.55 80.22,91.7 85.99,91.7 89.7,95.4 89.7,96.37 89.61,96.45 89.41,96.45 v2(89.15,96.19)
  BOTTOM w0.127: v2(89.15,96.19) 89.41,96.45 89.53,96.45 89.82,96.16 CZ31.2 ; RZ1048.2 42.27,75.24 42.27,75.74 v2(42.11,75.91)
APU_DP1_TXN2: length 16.3
  BOTTOM w0.102: 101.02,93.96 101.49,93.96 101.55,93.9 101.77,93.9 101.86,93.98 102.28,93.98 102.51,93.75 103.22,93.75 103.3,93.67 103.3,93.53 103.12,93.35 102.94,93.35 UC1.C5
  BOTTOM w0.127: 101.02,93.96 100.93,94.04 100.47,94.04 95.96,94.04 94.69,95.31 v3(92.03,95.31) 88.84,95.31 CV189.1
APU_DP1_TXN3: length 12.9
  BOTTOM w0.102: 101.03,92.53 101.05,92.53 101.05,92.52 101.14,92.52 101.14,92.52 101.55,92.94 101.71,92.94 101.93,93.15 101.93,93.28 UC1.B5
  BOTTOM w0.127: CV191.1 91.05,93.92 94.38,93.92 95.33,92.96 96.27,92.02 v3(97.44,92.02) 100.23,92.02 100.73,92.53 101.03,92.53
APU_DP1_TXP0: length 14.2
  BOTTOM w0.102: 99.39,95.86 99.4,95.85 100.29,95.85 100.73,95.42 101.07,95.42 101.27,95.61 UC1.A2
  BOTTOM w0.127: 99.39,95.86 96.54,95.86 94.55,97.85 v3(90.52,97.85) 88.84,97.85 CZ25.1
APU_DP1_TXP0_VGA: length 65.4
  TOP w0.127: v2(44.49,75.74) 44.32,75.57 44.32,75.26 RZ1045.2
  IN2 w0.127: v2(44.49,75.74) 44.38,75.86 44.38,76.71 48.24,80.57 67.07,80.57 67.53,81.03 67.53,81.06 67.94,81.47 71.73,81.47 80.75,90.49 86.34,90.49 90.75,94.9 90.75,97.25 89.95,98.04 v2(86.35,98.04)
  BOTTOM w0.127: v2(44.49,75.74) 44.32,75.57 44.32,75.26 RZ1045.2 ; v2(86.35,98.04) 86.41,97.98 87.42,97.98 CZ25.2
APU_DP1_TXP1: length 12.8
  BOTTOM w0.102: 99.39,95.1 99.4,95.1 99.41,95.09 100.23,95.09 100.51,94.8 100.83,94.8 101.07,94.56 102.12,94.56 UC1.B4
  BOTTOM w0.127: CZ32.1 90.92,96.71 94.46,96.71 v3(95.11,96.07) 96.07,95.1 99.39,95.1
APU_DP1_TXP1_VGA: length 61.1
  TOP w0.127: v2(42.69,75.91) 42.53,75.74 42.53,75.27 RZ1047.2
  IN2 w0.127: v2(89.15,96.77) 89.21,96.71 89.72,96.71 89.96,96.47 89.96,95.3 86.1,91.44 80.32,91.44 71.18,82.29 67.38,82.29 66.56,81.48 47.54,81.48 42.54,76.48 42.54,76.06 v2(42.69,75.91)
  BOTTOM w0.127: v2(42.69,75.91) 42.53,75.74 42.53,75.27 RZ1047.2 ; v2(89.15,96.77) 89.21,96.71 89.63,96.71 CZ32.2
APU_DP1_TXP2: length 16.3
  BOTTOM w0.102: UC1.D5 103.51,93.42 103.21,93.12 102.74,93.12 102.42,93.44 102.42,93.51 102.34,93.59 102.18,93.75 101.95,93.75 101.87,93.67 101.45,93.67 101.39,93.72 100.93,93.72
  BOTTOM w0.127: CV188.1 88.84,95.06 v3(93.78,95.06) 94.58,95.06 95.86,93.79 100.58,93.79 100.58,93.79 100.86,93.79 100.93,93.72
APU_DP1_TXP3: length 12.9
  BOTTOM w0.102: 101.03,92.78 101.04,92.79 101.06,92.79 101.12,92.85 101.13,92.85 101.45,93.17 101.62,93.17 101.69,93.24 101.69,93.37 101.61,93.46 101.31,93.46 UC1.A5
  BOTTOM w0.127: 101.03,92.78 100.62,92.78 100.12,92.28 96.38,92.28 v3(95.51,93.15) 94.49,94.17 91.05,94.17 CV190.1
APU_FCH_POK: length 65.3
  TOP w0.102: v2(193.87,78.57) 193.99,78.57 194.09,78.47 194.09,78.19 193.85,77.96 UE1.32 ; v2(143.49,94.18) 144.08,93.6 RH52.1 ; v2(180.23,86.61) 180.2,86.65 178.23,86.65 177.34,85.76 168.86,85.76 168.49,86.13 166.31,86.13 166.07,85.89 164.34,85.89 163.87,86.36 163.87,87.11 163.48,87.5 v2(163.48,87.6)
  IN2 w0.102: v2(180.23,86.61) 180.41,86.44 180.41,86.42 180.89,85.94 192.54,85.94 194.48,84 194.48,79.19 v2(193.87,78.57)
  BOTTOM w0.102: v2(163.48,87.6) 163.32,87.44 161.41,87.44 v1(159.62,89.23) 158.92,89.93 155.6,89.93 151.94,93.58 145.01,93.58 144.41,94.18 v2(143.49,94.18)
APU_FCH_PWRGD: length 11.4
  TOP w0.102: R348.2 R347.2 145.42,96.27 RH53.2 145.68,96.52 U61.2 148.37,96.72 148.27,96.82 147.66,96.82 147.35,97.13 147.35,97.87 v4(146.92,98.3) ; R348.2 RH52.2 RH51.2 ; R348.2 C1000.2 CH23.1
APU_FCH_PWRGD_R: length 18.6
  TOP w0.127: U61.4 145.94,97.17 145.88,97.23 RH53.1 R3.2 144.58,97.55 v2(144.32,97.82) 144.53,98.03 R21.2 v1(145.43,98.68)
  IN1 w0.102: v2(136.45,89.92) 136.45,91.05 136.84,91.44 136.84,92.05 137.86,93.07 137.86,93.28 138.56,93.98
  IN1 w0.127: v2(144.32,97.82) 144.32,97.5 143.96,97.14 141.73,97.14 138.56,93.98
  BOTTOM w0.102: v2(136.45,89.92) 136.45,89.93 136.16,90.22 UC1.BC9
APU_HDMI_CLK: length 88.8
  TOP w0.127: v2(29.39,72.85) 29.04,72.5 29.04,72.1 28.19,71.25 27.63,71.25 27.2,71.68 QX4.1 ; v2(93.3,90.31) 93.46,90.47 94.64,90.47 95.14,89.98 95.42,89.98 R704.2
  BOTTOM w0.112: v2(29.39,72.85) 29.54,73 29.79,73 29.91,72.87 RP63.1
  BOTTOM w0.127: v2(93.3,90.31) 93.72,90.74 93.72,91.06 93.4,91.38 86.7,91.38 80.52,85.21 80.52,78.93 78.26,76.66 72.24,76.66 71.01,77.89 53.34,77.89 52.49,78.74 38.86,78.74 31.92,71.81 29.26,71.81 28.89,72.18 28.89,72.84 29.04,73 29.25,73 v2(29.39,72.85)
APU_HDMI_CLK_C: length 12
  TOP w0.127: v2(97.42,89.73) 97.17,89.98 96.97,89.98 R704.1
  IN2 w0.114: v2(104.86,91.8) 104.57,92.09 104.57,92.1 103.9,92.1 103.63,91.82 102.76,91.82 102.48,92.1 99.39,92.1
  IN2 w0.127: 99.39,92.1 99.09,92.1 98.23,91.24 98.23,90.21 97.97,89.95 97.64,89.95 v2(97.42,89.73)
  BOTTOM w0.102: UC1.F7 105.27,92.21 v2(104.86,91.8)
  BOTTOM w0.127: R704.1 96.97,89.98 97.17,89.98 v2(97.42,89.73)
APU_HDMI_DATA: length 85.9
  TOP w0.127: R705.2 95.42,90.23 95.24,90.23 94.75,90.73 93.46,90.73 v2(93.3,90.9) ; v2(29.43,73.44) 28.84,73.44 28.5,73.78 QX4.4
  BOTTOM w0.112: RP63.2 29.91,73.37 29.79,73.25 29.61,73.25 v2(29.43,73.44)
  BOTTOM w0.127: v2(93.3,90.9) 93.07,91.12 86.8,91.12 80.78,85.1 80.78,78.82 78.37,76.4 72.13,76.4 70.9,77.64 53.24,77.64 52.39,78.49 38.96,78.49 32.03,71.55 29.16,71.55 28.63,72.08 28.63,72.95 28.94,73.25 29.25,73.25 v2(29.43,73.44)
APU_HDMI_DATA_C: length 12
  TOP w0.127: R705.1 96.96,90.25 97.19,90.25 v2(97.42,90.48)
  IN2 w0.114: v2(104.87,92.62) 104.59,92.34 103.8,92.34 103.52,92.06 102.86,92.06 102.58,92.34 99.5,92.34 99.49,92.35 99.42,92.35 99.41,92.36 99.39,92.36
  IN2 w0.127: v2(97.42,90.48) 97.42,90.47 97.68,90.21 97.87,90.21 97.97,90.32 97.97,91.35 98.98,92.36 99.39,92.36
  BOTTOM w0.102: UC1.E7 104.47,92.22 v2(104.87,92.62)
  BOTTOM w0.127: v2(97.42,90.48) 97.18,90.24 96.97,90.24 R705.1
APU_I2C0_SCL_TP: length 138.1
  TOP w0.102: Q2509.4 62.4,67.55 62.58,67.37 64.13,67.37 v2(64.48,67.73)
  IN2 w0.102: v2(143.72,87.72) 143.72,87.72 143.94,87.5 143.94,87.13 145.48,85.59 145.48,83.68 144.86,83.06 144.38,82.58 144.38,80.11 144.12,79.85 144.12,76.49 148.57,72.05 148.57,69.07 146.61,67.12 146.61,64.44 147.05,64.01 147.05,58.8 146.98,58.73 146.98,57.68 v2(146.78,57.47)
  BOTTOM w0.102: v2(146.78,57.47) 145.23,55.92 137.48,55.92 137.01,55.45 86.43,55.45 v1(75.06,66.81) 73.22,68.66 65.41,68.66 v2(64.48,67.73) ; UC1.BB10 133.87,89.42 134.3,89.85 134.72,89.85 134.86,89.71 135.82,89.71 136.21,89.32 136.33,89.32 137.52,88.14 138.64,88.14 R709.2 139.51,88.17 140.36,88.17 R955.2 141.2,87.78 143.66,87.78 v2(143.72,87.72)
APU_I2C0_SDA_TP: length 142.1
  TOP w0.102: v2(64.23,68.26) 64.23,68.26 64.23,69.17 63.56,69.84 61.45,69.84 60.46,68.85 Q2509.1
  IN2 w0.102: v2(146.59,58.03) 146.6,58.03 146.65,58.08 146.65,63.83 146.14,64.34 146.14,65.39 141.96,69.58 141.96,73.4 143.79,75.24 143.79,79.99 144.05,80.25 144.05,82.72 145.15,83.82 145.15,85.45 143.6,86.99 143.6,87.12 142.94,87.78 142.94,88.54 143.19,88.79 v2(143.9,88.79)
  BOTTOM w0.102: v2(143.9,88.79) 143.9,88.99 143.34,89.55 R691.2 142.7,89.55 142.26,89.99 140.8,89.99 140.56,89.75 140.41,89.75 R956.2 139.65,89.29 139.41,89.04 137.85,89.04 137.37,89.53 136.3,89.53 135.91,89.92 134.94,89.92 134.64,90.22 UC1.BB9 ; v2(146.59,58.03) 144.87,56.31 137.41,56.31 136.87,55.78 86.57,55.78 73.36,68.99 64.96,68.99 v2(64.23,68.26)
APU_I2C1_SCL: length 2.8
  TOP w0.102: R689.2 136.04,92.79 136.04,92.45 v2(135.82,92.23)
  BOTTOM w0.102: v2(135.82,92.23) 135.72,92.13 134.92,92.13 134.61,91.82 UC1.BB7
APU_I2C1_SDA: length 2.6
  TOP w0.102: R688.2 136.26,92.68 136.26,92.31 v2(136.4,92.17)
  BOTTOM w0.102: UC1.BC7 136.05,91.82 v2(136.4,92.17)
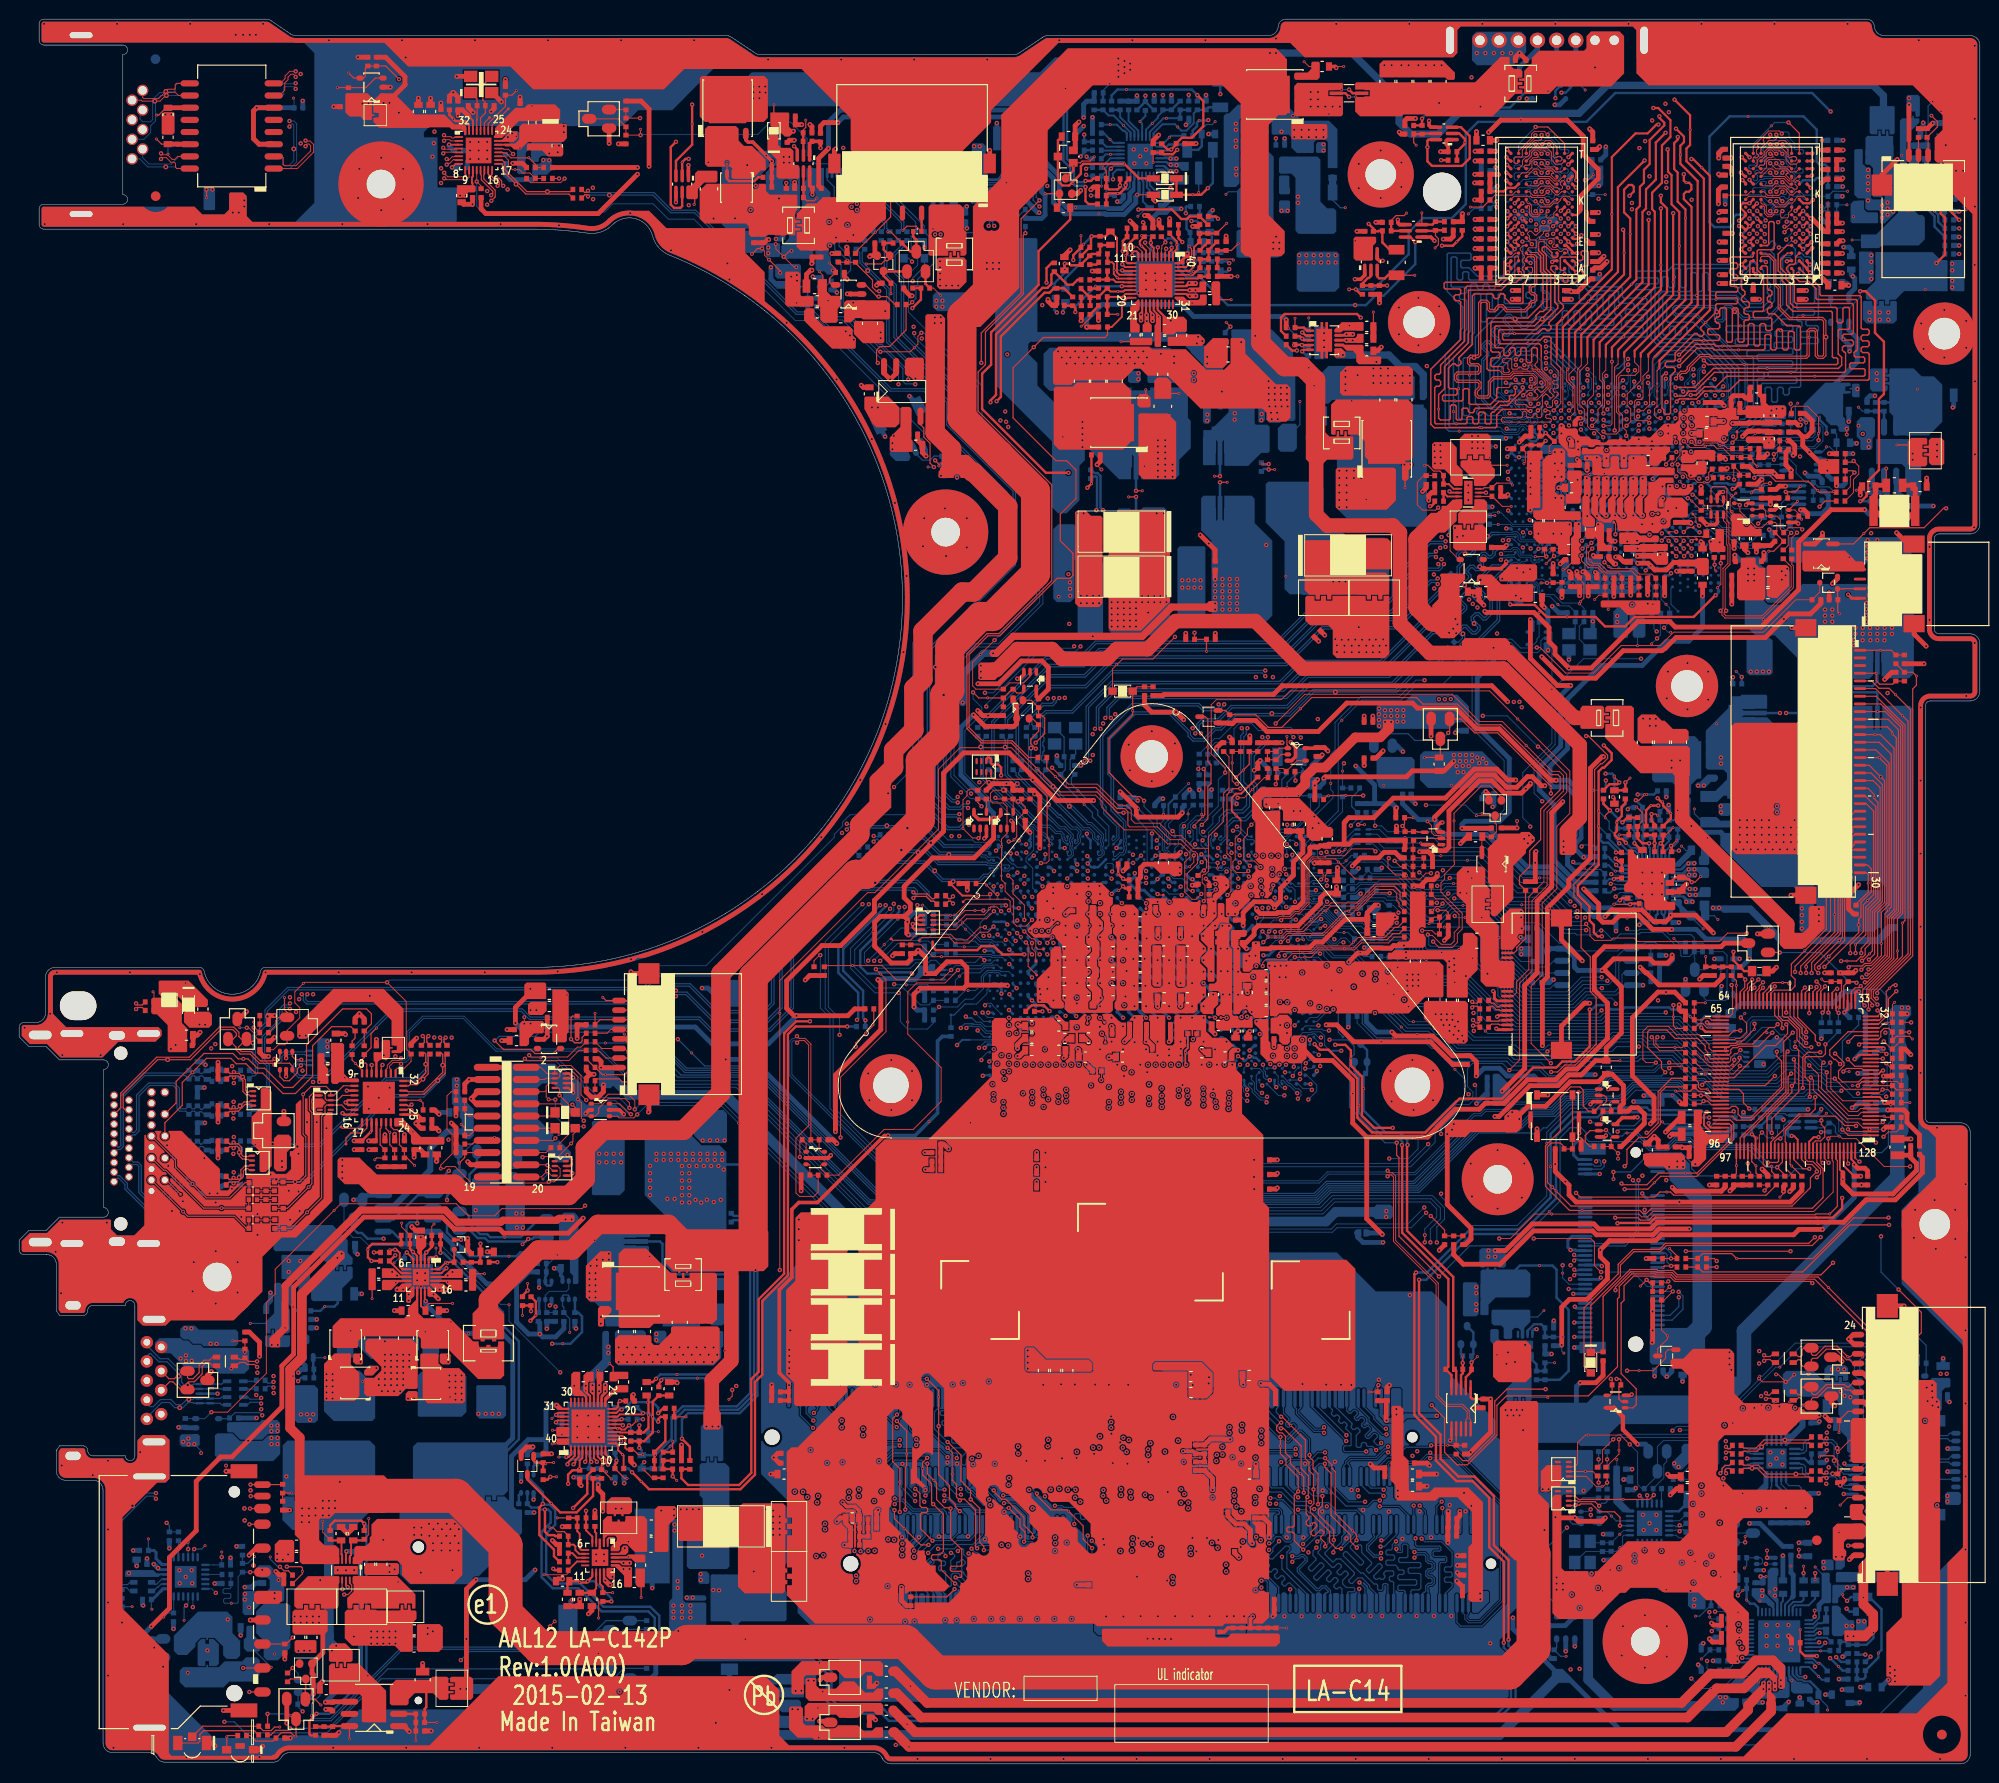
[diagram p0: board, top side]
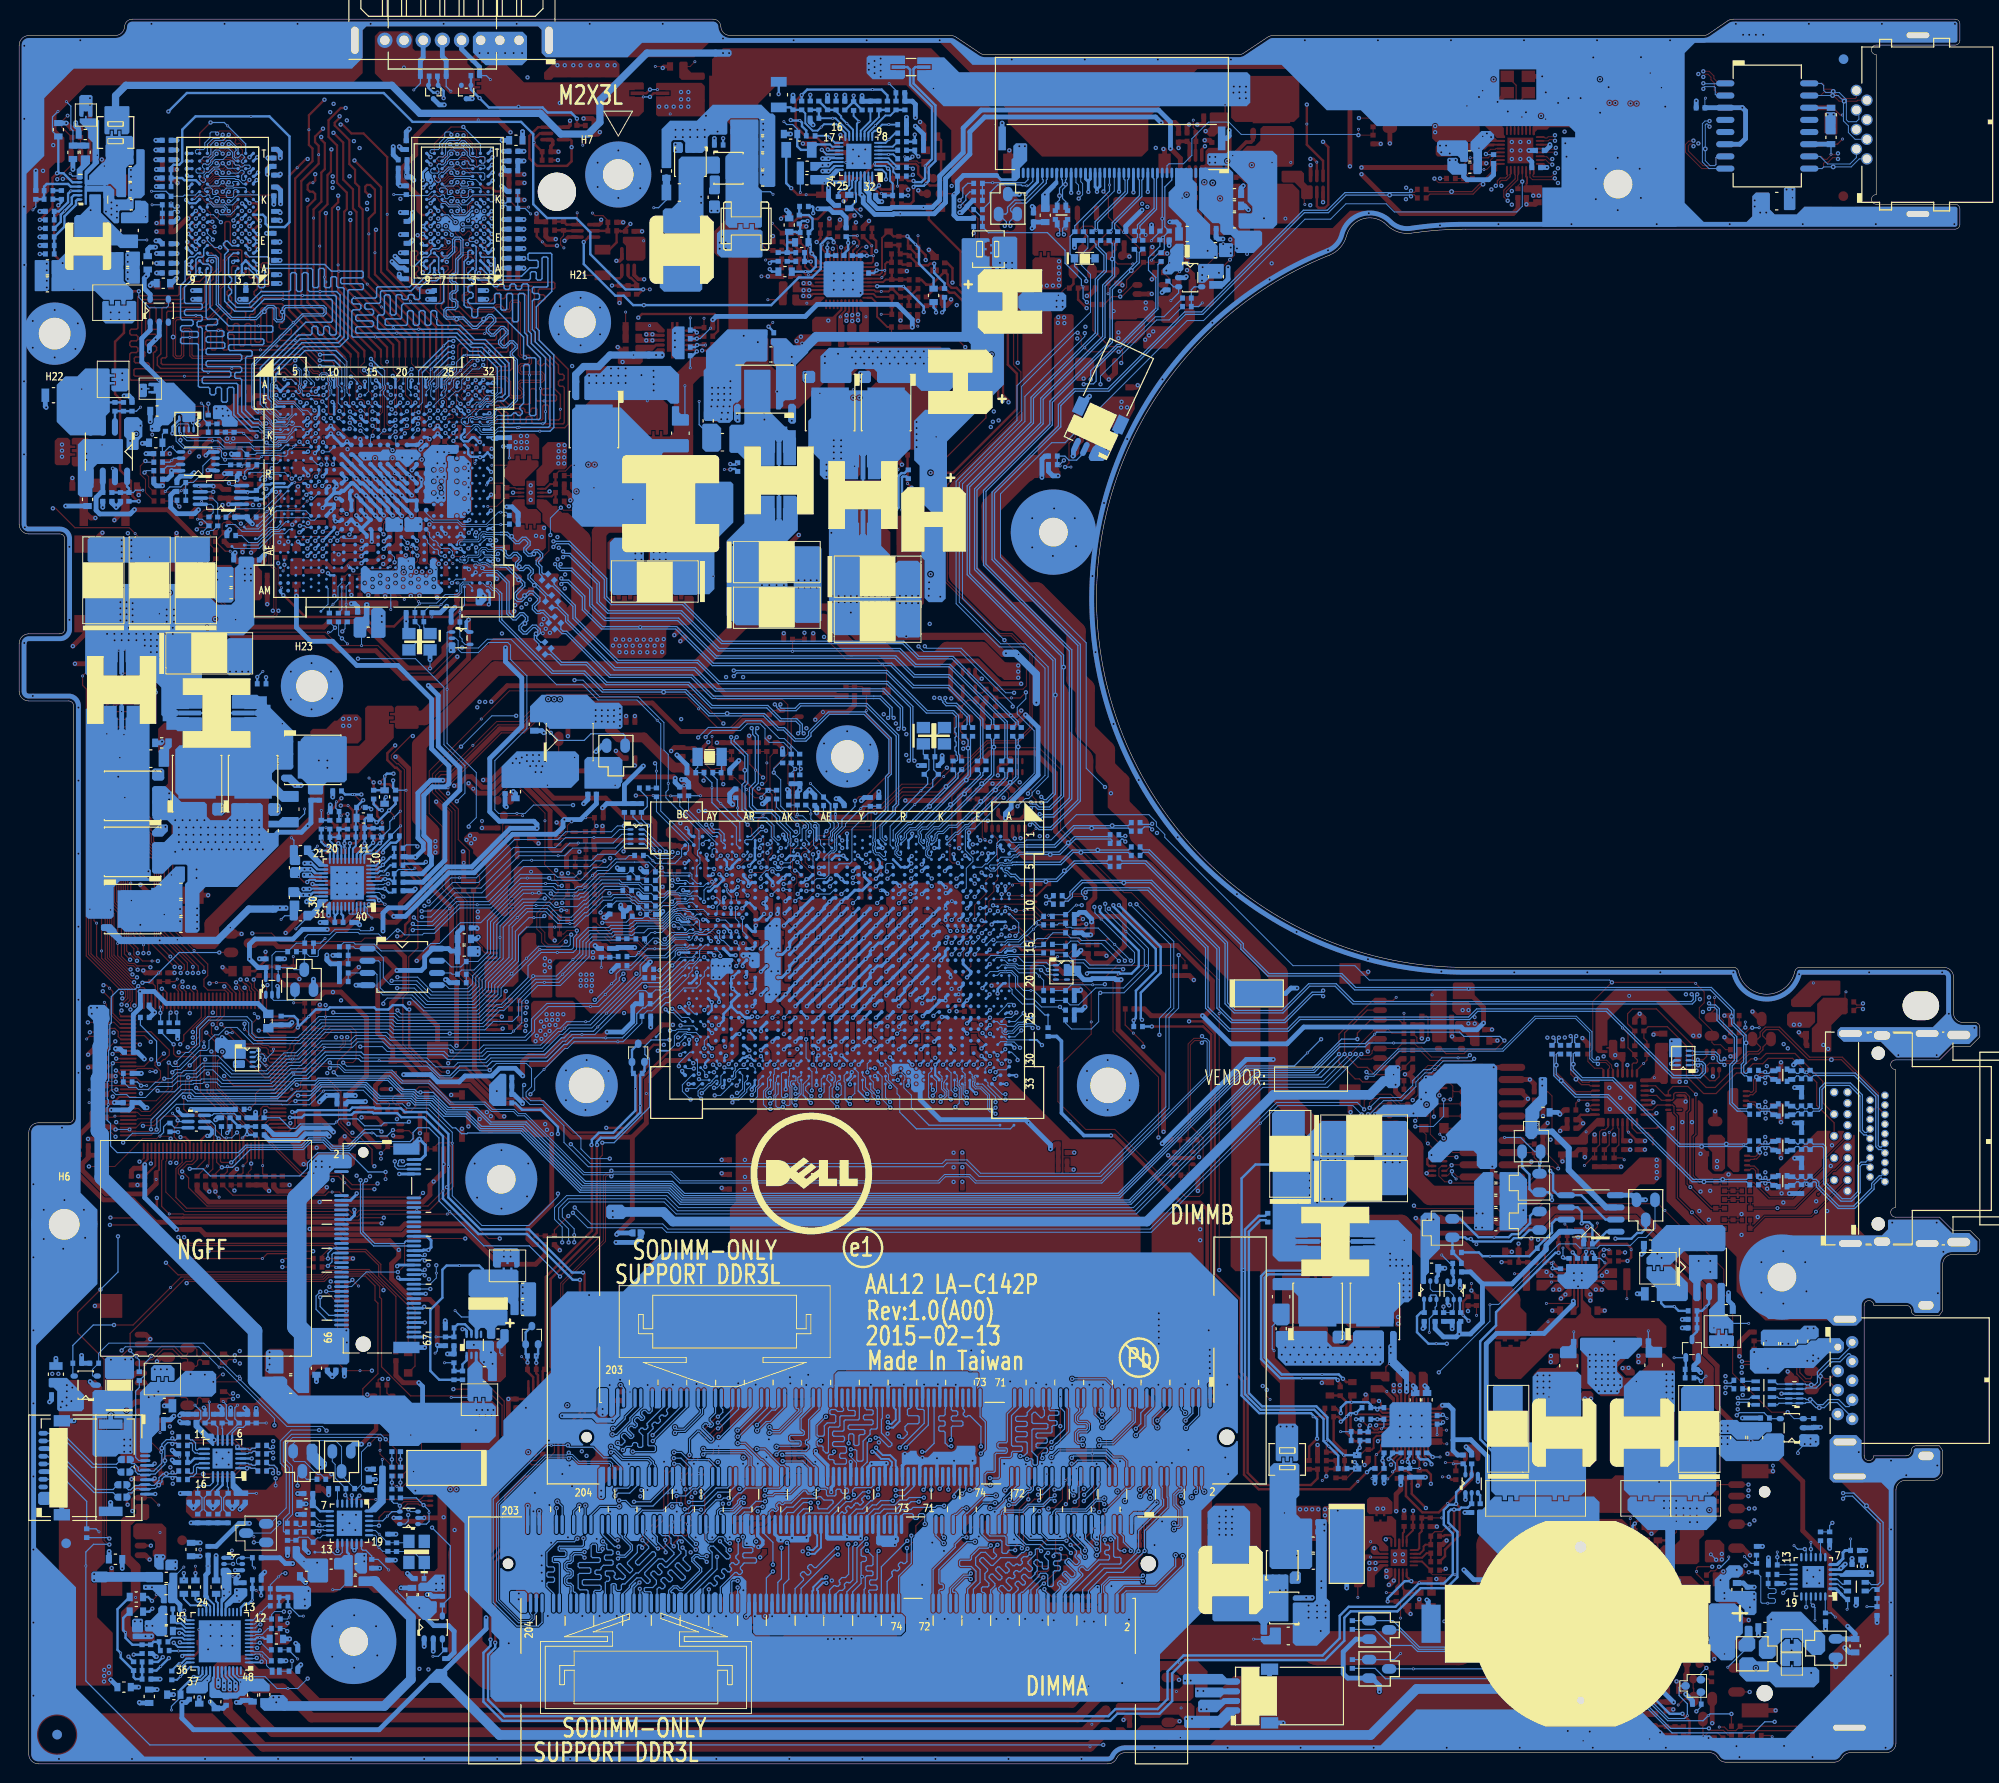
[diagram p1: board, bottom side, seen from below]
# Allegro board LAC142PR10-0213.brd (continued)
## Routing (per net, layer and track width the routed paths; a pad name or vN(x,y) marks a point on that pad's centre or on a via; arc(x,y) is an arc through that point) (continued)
APU_MAB_VREFDQ: length 8
  BOTTOM w0.102: UC1.A19 101.27,81.05 100.96,80.75 100.96,80.33 99.88,79.25 99.39,79.25
  BOTTOM w0.127: 99.39,79.25 98.68,79.25 97.54,78.1 T45.1 RZ1049.2
APU_PCIE_RST#: length 241.6
  TOP w0.102: v2(172.18,49.75) 171.71,49.28 RH32.1 ; v2(131.1,102.18) 131.2,102.29 RH30.1 131.12,102.95 RH28.2 131.88,103.81 RH27.1 133.32,104.63 UH1.4 ; v2(56.9,165.34) 56.48,164.92 53.37,164.92 RH31.1
  IN2 w0.102: v2(172.18,49.75) 173.12,50.69 173.12,54.9 167.82,60.2 167.82,60.71 167.07,61.46 167.07,62.88 163.8,66.16 163.8,66.24 163.51,66.54 163.51,68.02 161.51,70.01 161.51,70.82 160.22,72.11 160.22,79.13 159.45,79.9 159.45,90.01 158.98,90.48 158.98,96.69 157.92,97.75 v2(157.65,97.75) 157.65,97.89 154.13,101.42 154.13,105.04 152.7,106.46 148.18,106.46 146.91,105.19 136.82,105.19 136.46,104.84 135.4,104.84 134.45,103.89 133.85,103.89 132.66,102.69 131.6,102.69 v2(131.1,102.18) 128.87,102.18 128.39,102.67 128.39,106.48 127.05,107.82 127.05,110.68 123.7,114.03 109.57,114.03 106.55,117.06 106.55,142.13 100.63,148.05 87.02,148.05 79.28,155.78 79.28,156.51 78.67,157.12 77.88,157.12 69.81,165.19 57.05,165.19 v2(56.9,165.34)
  BOTTOM w0.102: UV2.1 159.85,118.05 159.91,117.99 v1(159.91,112.08) 159.91,106.44 156.86,103.39 156.86,98.69 157.65,97.9 v2(157.65,97.75)
APU_PCIE_RST#_C: length 7
  TOP w0.102: RH25.1 130.28,103.76 RH30.2 129.91,102.87 v1(128.68,101.63) 127.81,100.76 v2(127.12,100.76)
  BOTTOM w0.102: R907.1 C912.1 127.12,100.85 v2(127.12,100.76)
APU_PCIE_RST#_R: length 13
  IN2 w0.102: v2(123.52,97.21) 123.52,96.9 123.84,96.57 123.84,95.61 124.08,95.38 124.08,94.19 124.77,93.49 124.77,93.22 125.77,92.22 126.55,92.22 127.17,91.6 v2(127.17,91.45)
  BOTTOM w0.102: v2(123.52,97.21) 123.69,97.21 124.53,98.06 124.53,98.8 125.53,99.8 R907.2 ; UC1.AN7 126.85,91.92 127.17,91.6 v2(127.17,91.45)
APU_PCIE_WAKE#: length 283.8
  TOP w0.102: v2(125.82,103.39) 125.82,103.89 124.36,105.35 124.36,110.46 124.9,111 131.68,111 132.59,111.91 153.4,111.91 v1(156.34,108.98) 161.77,103.55 161.77,99.13 160.42,97.78 160.42,91.28 158.9,89.76 158.9,82.27 157.74,81.12 157.74,75.13 v2(159.8,73.08) ; RE56.1 197.37,77.34 v2(197.38,77.33) ; UL1.21 50.48,168.48 50.55,168.4 51.04,168.4 v2(51.53,167.91)
  IN1 w0.102: v2(159.8,73.08) 159.84,73.08 161.83,71.08 162.36,71.08 163.32,70.13 164.36,70.13 167,67.49 167.15,67.49 168.41,66.23 170.02,66.23 170.17,66.09 170.17,64.91 170.54,64.53 170.54,62.18 v2(171.84,60.88) ; v2(69.86,162.57) 69.74,162.46 67.57,162.46 66.77,163.26 63.91,163.26 58.83,168.34 51.96,168.34 v2(51.53,167.91)
  IN2 w0.102: v2(125.82,103.39) 125.85,103.39 126.21,103.75 126.21,106.37 125.88,106.7 125.88,108.48 122.31,112.05 108.75,112.05 104.57,116.23 104.57,141.3 100.25,145.62 86.99,145.62 70.06,162.55 69.83,162.55 v2(69.86,162.57) ; v2(171.84,60.88) 175.01,60.88 179.69,56.21 190.56,56.21 195.61,61.27 195.61,72.27 195.19,72.69 194.25,72.69 193.92,73.02 193.92,74.59 194.31,74.98 196.43,74.98 197.55,76.1 197.55,77.16 v2(197.38,77.33)
  BOTTOM w0.102: UC1.AG2 122.17,96.09 122.47,96.39 122.47,97.31 122.2,97.58 122.2,97.92 122.7,98.42 123.63,98.42 125.1,99.9 125.1,102.64 125.82,103.37 v2(125.82,103.39) 125.82,103.77 125.2,104.39 R930.2 ; v2(51.53,167.91) 51.47,167.84 RL34.2
APU_PWRGD: length 325.6
  TOP w0.102: U62.4 166.16,65.39 166.05,65.28 166.05,64.95 166.1,64.9 R4.2 ; v2(116.17,158.22) 116.65,158.22 117.16,157.7 PU1001.9 ; R4.2 166.81,63.68 ; R4.2 RH54.1 ; v2(166.81,63.69) 166.81,63.68 ; 166.81,63.68 v4(166.81,63.12) ; v2(57.71,68.76) 58.01,68.47 58.01,67.94 D31.2
  TOP w0.203: PU500.9 60.76,32.2 61.18,31.78 61.18,31.46 v2(61.44,31.2)
  IN1 w0.102: v2(106.74,152.15) 106.74,152.88 108.08,154.23 108.08,157.05 111.05,160.02 114.36,160.02 v2(116.17,158.22)
  IN2 w0.102: v2(106.74,152.15) 105.43,150.84 105.43,146.27 108.69,143.01 108.69,117.94 v2(110.06,116.56) 110.46,116.17 124.82,116.17 132.14,108.85 132.14,107.88 v2(132.94,107.09) 133.69,106.34 134.65,106.34 134.96,106.03 147.28,106.03 148.04,106.79 152.83,106.79 154.46,105.17 154.46,101.68 159.31,96.83 159.31,90.61 159.78,90.14 159.78,82.66 160.55,81.9 160.55,72.25 161.84,70.95 161.84,70.15 163.02,68.97 164.28,67.71 164.28,66.25 166.81,63.73 v2(166.81,63.69) ; v2(100.76,111.71) 100.15,111.71 99.71,112.14 99.32,112.14 91.66,104.48 91.66,94.18 88.64,91.17 v2(88.64,89.66) ; v2(61.44,31.2) 60.66,31.98 58.58,31.98 55.4,35.15 55.4,41.19 57.66,43.44 57.66,52.63 54.55,55.74 54.55,60.88 54.91,61.24 55.32,61.24 55.93,61.85 55.93,64.5 56.37,64.94 56.37,65.49 56.22,65.65 56.22,67.55 56.6,67.93 57.43,68.76 v2(57.71,68.76) 57.8,68.85 59.12,68.85 61.13,66.84 74.34,66.84 78.84,71.34 80.89,71.34 v2(85.59,76.03) 86.05,76.03 86.52,76.5 93.53,76.5 v2(95.97,78.94)
  BOTTOM w0.102: v2(110.06,116.56) 109.86,116.36 106.27,116.36 101.62,111.71 v2(100.76,111.71) ; v2(88.64,89.66) 84.42,85.44 84.42,78.92 85.59,77.76 v2(85.59,76.03) ; v2(132.94,107.09) 132.25,107.77 129.3,107.77 128.61,108.47 127.24,108.47 126.74,107.97 126.74,106.97 126.31,106.54 124.8,106.54 124.01,105.75 R663.2 ; UC1.C19 102.85,82.23 102.48,82.23 102.19,82.52 101.94,82.52 101.93,82.51 101.46,82.51 101.44,82.53 101.07,82.53 100.61,82.07 100.61,80.87 99.5,79.76 98.7,79.76 97.89,78.94 v2(95.97,78.94) 95.63,78.61 95.39,78.61 R82.2
APU_PWRGD_BUF: length 3.2
  TOP w0.102: D31.1 55.52,67.56 JHDT1.10
APU_PWRGD_EC: length 25.7
  TOP w0.127: RH54.2 163.89,64.39 163.38,64.9 163.38,65.53 163.89,66.04 U62.2 165.49,66.04 v2(165.55,66.1) ; v2(182.43,62.73) 183.43,62.73 183.55,62.84 UE1.108
  BOTTOM w0.127: v2(165.55,66.1) 166.18,65.48 167.24,65.48 167.56,65.8 v1(167.75,65.8) 168.56,65.8 170.16,64.2 171.91,64.2 172.77,65.06 174.24,65.06 175.01,64.3 180.82,64.3 182.39,62.73 v2(182.43,62.73)
APU_PWRGD_R: length 9.7
  TOP w0.102: 123.12,98.43 122.6,97.91 v2(122.6,97.77)
  TOP w0.127: v2(123.58,103.77) 123.69,103.65 123.69,99 v1(123.49,98.79) 123.12,98.43
  BOTTOM w0.102: UC1.AH1 122.87,96.42 122.87,97.51 v2(122.6,97.77)
  BOTTOM w0.127: R663.1 124.01,104.19 v2(123.58,103.77) 124,103.35 C32.2
APU_RST#: length 237.8
  TOP w0.102: U63.4 166.09,69.07 165.92,68.9 165.92,68.64 166.1,68.47 R7.2 RH57.1 165.14,67.97 v2(165.14,67.25) ; v2(54.6,63.27) 54.68,63.35 56.23,63.35 v4(57.59,64.71) 57.77,64.89 57.77,65.64 58,65.87 D32.2
  IN2 w0.102: v2(165.14,67.25) 164.66,67.72 164.66,68.6 160.88,72.39 160.88,82.04 160.11,82.8 160.11,90.28 159.64,90.75 159.64,96.96 154.79,101.82 154.79,105.31 152.97,107.12 147.91,107.12 147.14,106.36 135.1,106.36 134.79,106.67 134.09,106.67 v2(133.71,107.05) 133.71,107.75 124.91,116.55 v2(110.72,116.55) ; v2(102.92,85.93) 102.92,86.36 102.4,86.88 100.45,86.88 100.12,86.55 100.12,85.71 99.62,85.22 99.62,83.83 98.13,82.33 95.01,82.33 94.72,82.04 93.39,82.04 v2(91.76,80.42) 87.02,80.42 79.92,73.32 78.02,73.32 74.81,70.11 60.77,70.11 59.7,71.18 57.3,71.18 54.6,68.48 v2(54.6,63.27) ; v2(90.87,89.18) 90.87,91.43 93.03,93.6 93.03,102.21 100.89,110.07 v2(100.89,110.27)
  BOTTOM w0.102: v2(110.72,116.55) 110.2,116.03 106.41,116.03 100.89,110.52 v2(100.89,110.27) ; UC1.D15 103.66,85.42 103.15,85.93 v2(102.92,85.93) ; v2(90.87,89.18) 90.87,89.18 86.73,85.05 86.73,82.97 89.29,80.42 v2(91.76,80.42) 91.93,80.25 91.93,77.41 92.69,76.64 94.76,76.64 95.38,77.27 R80.2 ; R662.2 123.12,105.33 124.73,106.95 125.25,106.95 127.1,108.8 128.74,108.8 129.44,108.1 132.66,108.1 v2(133.71,107.05)
APU_RST#_BUF: length 3
  TOP w0.102: JHDT1.12 D32.1
APU_RST#_EC: length 54.9
  TOP w0.127: U63.2 165.35,69.72 165.6,69.47 165.6,69.09 165.22,68.71 164.95,68.71 RH57.2 163.71,68.07 163.18,68.61 163.18,70.27 162.84,70.6 161.86,70.6 160.79,69.53 160.79,66.03 159.24,64.48 159.24,60.22 161.74,57.72 v1(163.06,57.72) 169.08,57.72 169.41,57.39 169.74,57.39 170.3,57.95 187.08,57.95 188.19,59.07 188.19,62.08 187.55,62.73 UE1.118
APU_RST#_R: length 11.2
  IN2 w0.102: 122.03,98.43 122.03,97.79 123.46,96.37 v2(123.46,96.33)
  IN2 w0.127: 122.03,98.43 122.03,100.13 122.7,100.8 122.7,103.46 v2(123.01,103.77)
  BOTTOM w0.102: UC1.AJ3 123.77,95.35 123.31,95.81 123.31,96.18 v2(123.46,96.33)
  BOTTOM w0.127: C31.2 123.11,103.68 v2(123.01,103.77) 123.12,103.88 R662.1
APU_SCLK0: length 94.4
  IN2 w0.102: v2(147.21,31.87) 147.41,32.07 148.08,32.07 148.67,32.66 148.67,38.88 139.38,48.18 139.38,54.93 139.15,55.16 139.15,75.67 138.28,76.53 138.28,77.33 138.46,77.51 138.46,79.54 137.75,80.25 v2(137.75,82.78)
  BOTTOM w0.102: R676.2 138.27,82.78 v2(137.75,82.78) 137.59,82.78 136.11,84.26 136.11,84.68 135.87,84.91 134.76,84.91 134.61,85.06 133.82,85.06 UC1.BA15 ; JDIMM1.202 151.2,15.67 151.04,15.51 151.04,15.19 151.3,14.94 152.38,14.94 154.52,17.09 154.52,27.05 149.59,31.99 147.33,31.99 v2(147.21,31.87) 147.03,32.04 146.92,32.04 146.21,31.33 142.98,31.33 142.86,31.2 142.86,31.05 143,30.91 JDIMM2.202
APU_SCLK1: length 114.2
  IN2 w0.102: 146.83,88.71 145.35,90.2 142.51,90.2 142.43,90.28 141.46,90.28 140.49,89.31 137.26,89.31 136.87,88.93 135.12,88.93 134.91,88.71 132.81,88.71 132.53,88.43 130.9,88.43 130.32,87.86 128.64,87.86 127.42,89.08 126.53,89.08 126.4,89.2 124.37,89.2 124.01,89.56 124.01,90.59 122.87,91.73 122.87,93.65 121.73,94.79 v2(121.73,94.87)
  IN2 w0.127: v2(164.78,31.75) 165.7,32.68 169.09,32.68 169.53,33.11 169.53,37.86 162.83,44.56 162.83,53.31 160.77,55.36 151.44,55.36 147.72,59.08 147.72,66.81 149.57,68.66 149.57,72.46 145.13,76.91 145.13,79.29 146.69,80.85 146.69,84.26 148.06,85.62 148.06,87.33 146.83,88.56 146.83,88.71
  BOTTOM w0.102: UC1.AG5 121.73,93.55 v2(121.73,94.87)
  BOTTOM w0.127: R685.2 v2(164.78,31.75) R135.1
APU_SDATA0: length 105.7
  TOP w0.102: v2(133.09,84.14) 133.1,84.13 v1(134.13,84.13) 134.79,84.13 135.57,84.9 139.3,84.9 140.02,85.62 142.84,85.62 143.45,86.23 R677.2
  IN2 w0.102: v2(147.21,32.45) 147.36,32.3 147.99,32.3 148.44,32.76 148.44,38.79 139.15,48.08 139.15,54.83 138.92,55.06 138.92,75.57 138.06,76.44 138.06,77.43 138.23,77.6 138.23,79.45 133.54,84.14 v2(133.09,84.14)
  BOTTOM w0.102: UC1.AY17 132.77,83.82 v2(133.09,84.14) ; JDIMM1.200 150.6,15.75 150.81,15.54 150.81,15.1 151.2,14.71 152.47,14.71 154.75,16.99 154.75,27.15 149.69,32.21 147.45,32.21 v2(147.21,32.45) 147.03,32.27 146.83,32.27 146.11,31.56 142.89,31.56 142.63,31.3 142.63,31.05 142.4,30.82 JDIMM2.200
APU_SDATA1: length 113.4
  TOP w0.102: v1(122.11,93.58) 122.54,94.02 v2(122.54,94.75)
  IN2 w0.102: v2(122.54,94.75) 122.54,94.34 123.07,93.81 123.07,91.82 124.21,90.68 124.21,89.65 124.45,89.41 126.49,89.41 126.61,89.28 127.77,89.28 128.42,88.64 132.45,88.64 132.72,88.91 134.82,88.91 135.03,89.13 136.79,89.13 137.17,89.52 140.31,89.52 141.28,90.48 142.12,90.48 142.15,90.51
  IN2 w0.127: v2(165.66,31.75) 166.36,32.45 169.19,32.45 169.75,33.01 169.75,37.95 163.06,44.65 163.06,53.4 160.87,55.59 151.53,55.59 147.95,59.17 147.95,66.71 149.8,68.56 149.8,72.56 145.35,77 145.35,79.19 146.92,80.76 146.92,84.16 148.29,85.53 148.29,87.51 147.09,88.7 147.09,88.77 145.45,90.41 142.6,90.41 142.5,90.51 142.15,90.51
  BOTTOM w0.102: v2(122.54,94.75) 122.17,94.38 UC1.AG4
  BOTTOM w0.127: R686.2 v2(165.66,31.75) R136.1
APU_SIC: length 42.5
  TOP w0.102: Q79.4 83.76,62.53 83.6,62.37 83.6,62.08 R679.2 85.47,61.4 90.24,66.17 93.27,66.17 96.18,69.08 96.18,72.63 92.7,76.11 v1(92.7,77.38) 92.7,80.52 93.63,81.45 96.59,81.45 v2(97.94,82.8)
  BOTTOM w0.102: UC1.B18 102.35,83.02 102.04,83.32 101.54,83.32 101.45,83.24 100.67,83.24 100.36,82.92 98.07,82.92 v2(97.94,82.8) 97.44,82.3 RP25.3
APU_SID: length 45.4
  TOP w0.102: Q79.1 82.1,64.67 R680.2 81.45,64.86 v2(81.45,63.29) ; v2(85.69,65.33) 85.69,71.62 90.43,76.36 90.43,81.83 v1(89.88,82.37) v2(89.38,82.88)
  IN2 w0.102: v2(81.45,63.29) 82.06,62.67 84.74,62.67 85.27,63.2 85.27,63.64 84.68,64.23 84.68,64.94 85.06,65.33 v2(85.69,65.33)
  BOTTOM w0.102: v2(89.38,82.88) 89.48,82.98 92.97,82.98 93.53,83.54 94.83,83.54 95.09,83.81 95.64,83.81 96.14,83.3 RP25.1 97.1,83.3 97.39,83.6 99.74,83.6 100.35,84.2 101.37,84.2 101.46,84.11 101.88,84.11 101.89,84.12 102.24,84.12 102.26,84.11 102.57,84.11 UC1.C17
APU_SPI_CLK: length 29.3
  BOTTOM w0.102: U56.6 159.51,82.49 159.38,82.36 R617.1 158.39,82.79 157.11,82.79 155.38,84.52 155.38,87.81 152.03,91.16 148.94,91.16 148.64,90.86 146.48,90.86 146.17,91.16 145.78,91.16 v1(145.51,91.43) 144.1,92.85 141.09,92.85 C27.1 140.65,93.03 R1691.2 139.34,92.4 R106.1
APU_SPI_CLK_R: length 3.7
  BOTTOM w0.102: UC1.BC6 137.7,92.62 R106.2
APU_SPI_CS1#: length 50.8
  BOTTOM w0.102: R639.1 R637.1 R107.1 169.67,85.22 169.47,85.03 U56.1 167.53,85.03 166.56,84.05 166.56,82 165.85,81.29 163.15,81.29 161.72,79.86 157.37,79.86 156.25,80.97 156.25,81.77 154.06,83.97 154.06,87.26 151.78,89.53 v1(150.63,89.53) 149.32,89.53 148.08,88.3 146.96,88.3 145.59,89.68 145.4,89.68 143.55,91.53 141.09,91.53 R1693.2 140.48,91.27 139.88,91.27 139.41,90.8 138.61,90.8 R636.1 137.29,90.37 136.81,90.84 135.66,90.84 135.56,90.74 134.82,90.74 134.77,90.7 134.56,90.7 134.24,91.02 UC1.BB8
APU_SPI_CS1#_R: length 46
  IN2 w0.102: v2(147.94,91.58) 146.49,91.58 145.76,92.31 140.56,92.31 138.61,90.36 137.12,90.36 136.96,90.51 136.21,90.51 135.84,90.14 133.34,90.14 v2(133.1,89.9)
  BOTTOM w0.102: v2(133.1,89.9) 133.1,91.13 132.79,91.44 132.47,91.44 131.87,92.05 UC1.AW7 ; v2(147.94,91.58) 148.35,91.58 148.6,91.82 v1(149.64,91.82) 152.3,91.82 156.39,87.73 158.52,87.73 160.69,85.56 161.61,85.56 162.39,84.79 166.78,84.79 167.49,85.5 169.49,85.5 169.64,85.65 170.71,85.65 R107.2
APU_SPI_HOLD#: length 35.8
  BOTTOM w0.102: U56.7 160.1,83.76 159.47,83.12 158.46,83.12 R642.1 156.68,83.68 155.71,84.66 155.71,87.95 152.16,91.49 148.8,91.49 148.5,91.19 146.61,91.19 146.31,91.49 145.92,91.49 v1(144.74,92.67) 144.23,93.18 143.07,93.18 142.2,94.05 140.35,94.05 140.35,94.05 138.86,94.05 138.17,93.36 R634.1 137.3,93.03 137.19,92.92 134.54,92.92 134.36,92.75 134.36,92.35 133.84,91.82 UC1.BA7
APU_SPI_MISO: length 47.5
  BOTTOM w0.102: U56.2 167.06,83.76 166.89,83.58 166.89,80.94 166.47,80.53 163.41,80.53 162.08,79.2 157.09,79.2 155.59,80.7 155.59,81.5 153.12,83.98 153.12,87.27 151.51,88.87 149.59,88.87 148.36,87.64 v1(147.08,87.64) 146.69,87.64 145.56,88.77 145.37,88.77 143.72,90.42 142.82,90.42 142.59,90.66 140.9,90.66 140.66,90.42 140.34,90.42 139.84,89.92 138.62,89.92 R1692.2 137.83,89.48 136.67,90.64 135.74,90.64 135.64,90.54 134.9,90.54 134.86,90.49 134.43,90.49 134.39,90.52 133.77,90.52 UC1.BA9
APU_SPI_MOSI: length 37.1
  BOTTOM w0.102: U56.5 160.06,81.22 159.7,80.85 157.78,80.85 157.24,81.38 157.24,82.18 155.05,84.38 155.05,87.67 151.92,90.8 v1(151.01,90.8) 149.7,90.8 149.09,90.2 146.13,90.2 145.93,90.4 145.61,90.4 143.82,92.19 141.93,92.19 141.68,91.93 139.77,91.93 139.54,91.7 138.61,91.7 R1694.2 137.63,90.73 137.21,90.73 136.89,91.05 136.07,91.05 135.61,91.52 133.16,91.52 132.85,91.82 UC1.AY7
APU_SPI_TPMCS#: length 11.3
  BOTTOM w0.102: UC1.AW12 131.87,87.33 132.48,86.72 132.61,86.72 132.82,86.5 133.67,86.5 133.75,86.58 134,86.58 134.32,86.25 134.32,86.12 134.54,85.9 134.84,85.9 134.94,86 136.07,86 137.06,85.01 v1(138.25,85.01) 138.99,85.01 140.75,83.25 R638.1
APU_SPI_WP#: length 53.9
  IN2 w0.102: v2(149.76,88.43) 149.52,88.67 149.52,89.81 148.33,91 148.33,91.77 148.08,92.02 146.52,92.02 145.9,92.64 140.45,92.64 138.37,90.56 137.2,90.56 137.05,90.71 136.12,90.71 135.77,90.36 v2(132.19,90.36)
  BOTTOM w0.102: v2(132.19,90.36) 131.76,90.36 131.44,90.04 131.44,89.73 131.74,89.42 131.74,88.74 UC1.AW11 ; R635.1 R640.1 U56.3 167.38,82.49 167.22,82.33 167.22,80.81 166.61,80.2 163.55,80.2 162.22,78.87 156.96,78.87 155.26,80.56 155.26,81.36 152.79,83.84 152.79,86.83 151.36,88.26 v1(150.86,88.26) 149.93,88.26 v2(149.76,88.43)
APU_SPKR: length 90.6
  IN2 w0.109: v2(173.26,34.81) 170.95,37.12 170.95,38.92 164.15,45.72 164.15,53.92 161.34,56.73 151.92,56.73 149.48,59.18 149.48,64.04 151.21,65.78 v2(151.21,69.84)
  BOTTOM w0.099: DA8.3 178.35,25.03 176.69,26.69 176.69,30.75 177.31,31.37 177.31,33.67 176.17,34.81 v2(173.26,34.81) ; v2(151.21,69.84) 150.77,70.28 150.77,71.45 v1(149.79,72.43) 147.61,74.61 147.35,74.61 146.65,75.31 141.55,75.31 139.58,77.28 CH15.1 139.02,78.54 138.55,78.54 137.14,79.95 136.86,79.95 134.69,82.12 134.69,82.37 134.33,82.73 134.33,83.04 133.55,83.82 UC1.BA17
APU_SVC: length 108.6
  TOP w0.102: v2(119.66,158.03) 119.66,157.91 119.56,157.81 PU1001.3
  IN1 w0.102: v2(102.96,139.98) 102.96,140.27 102.49,140.75 102.49,142.2 101.78,142.9 101.78,152.55 110.24,161.01 114.78,161.01 116.4,159.38 118.44,159.38 118.85,158.97 118.85,158.84 v2(119.66,158.03)
  IN2 w0.102: v2(92.38,89.37) 92.38,91.22 94.23,93.07 94.23,101.72 103.14,110.63 103.14,138.29 102.8,138.63 102.8,139.81 v2(102.96,139.98)
  BOTTOM w0.102: v2(92.38,89.37) 92.33,89.32 92.33,88.76 v1(91.67,88.11) 88.18,84.62 88.18,83.6 88.47,83.31 92.83,83.31 93.39,83.87 94.69,83.87 95.22,84.4 R9.2 95.56,84.58 R669.1
APU_SVC_R: length 6.3
  BOTTOM w0.102: UC1.D17 103.17,84.32 102.34,84.32 102.33,84.33 101.81,84.33 101.79,84.32 101.54,84.32 101.45,84.4 97.85,84.4 R669.2
APU_SVD: length 110.3
  TOP w0.102: PU1001.5 118.76,158.14 v2(118.8,158.17)
  IN1 w0.102: v2(102.87,141.05) 102.87,142.34 102.11,143.09 102.11,152.37 110.42,160.68 114.64,160.68 116.27,159.05 118.3,159.05 118.52,158.83 118.52,158.44 v2(118.8,158.17)
  IN2 w0.102: v2(102.87,141.05) 102.6,141.05 101.92,140.37 101.92,138.16 102.28,137.81 102.28,110.99 93.36,102.08 93.36,93.46 91.25,91.34 v2(91.25,89.7)
  BOTTOM w0.102: v2(91.25,89.7) 91.25,88.99 v1(89.09,86.84) 87.17,84.91 87.17,83.08 89.33,80.92 92.25,80.92 92.69,80.48 92.7,80.48 94.02,79.16 94.91,79.16 R10.2 R670.1
APU_SVD_R: length 8
  BOTTOM w0.102: UC1.D19 103.26,82.63 102.42,82.63 102.32,82.73 101.81,82.73 101.79,82.72 101.54,82.72 101.52,82.73 100.98,82.73 100.37,82.12 100.37,81.26 99.76,80.66 v1(99,80.66) 98.7,80.66 R670.2
APU_SVT: length 91.8
  TOP w0.102: v2(117.46,158.67) 117.46,158.48 117.96,157.98 PU1001.7
  IN1 w0.102: v2(103.18,139.43) 103.69,139.94 103.69,142 102.44,143.24 102.44,152.18 110.61,160.35 114.5,160.35 116.18,158.67 v2(117.46,158.67)
  IN2 w0.102: v2(103.18,139.43) 103.47,139.14 103.47,110.5 94.56,101.58 94.56,90.42 v2(93.69,89.56)
  BOTTOM w0.102: R673.1 96.58,88.57 R2.2 95.33,88.57 94.34,89.56 v1(94.25,89.56) v2(93.69,89.56)
APU_SVT_R: length 6.4
  BOTTOM w0.102: R673.2 98.09,87.97 98.28,87.97 99.66,86.59 99.7,86.59 100.31,85.98 101.45,85.98 101.7,85.72 102.56,85.72 UC1.C15
APU_TCK: length 65.1
  TOP w0.102: v4(104.51,86.23) 104.11,86.63 v2(104.11,86.64) ; JHDT1.2 54.41,72.64 55.06,72 RP28.1 55.87,72.28 56.42,72.83 57.58,72.83 58.62,71.79 58.62,69.77 v2(59.16,69.23)
  IN2 w0.102: v2(59.16,69.23) 59.21,69.23 61.2,67.24 74.27,67.24 78.7,71.67 80.61,71.67 87.49,78.55 92.33,78.55 93.46,79.68 94.25,79.68 94.96,80.39 95.43,80.39 95.73,80.68 98.82,80.68 100.87,82.74 100.87,83.06 103.5,85.69 103.5,86.03 v2(104.11,86.64)
  BOTTOM w0.102: UC1.D13 103.74,87.02 v2(104.11,86.64)
APU_TDI: length 69.4
  TOP w0.102: 54.98,70.23 54.98,69.56 v4(55.24,69.3) 55.26,69.28 v2(55.94,69.28) ; 54.98,70.23 54.86,70.1 JHDT1.6 ; 54.98,70.23 54.98,70.69 55.29,71 RP28.3
  IN2 w0.102: v2(58.89,66.48) 59.94,65.43 74.87,65.43 79.45,70.02 81.9,70.02 87.07,75.18 96.04,75.18 98.09,77.23 100.89,77.23 101.85,78.19 101.85,80.74 103.49,82.38 103.68,82.38 104.85,83.55 105.21,83.55 105.46,83.8 106.65,83.8 v2(107.27,84.42)
  BOTTOM w0.102: v2(107.27,84.42) 106.87,84.82 UC1.H15 ; v2(55.94,69.28) 55.94,67.55 57.01,66.48 v2(58.89,66.48)
APU_TDO: length 66.5
  TOP w0.102: v4(107.8,86.21) 107.27,85.67 v2(107.27,85.62) ; JHDT1.8 56.49,68.83 56.97,68.35 56.97,67.51 v2(56.95,67.5)
  IN2 w0.102: v2(107.27,85.62) 106.65,85 105.42,85 105.22,84.8 104.71,84.8 104.49,84.58 104.49,84.05 103.43,82.99 102.94,82.99 98.77,78.83 98.09,78.83 95.43,76.17 86.66,76.17 81.49,71.01 78.98,71.01 74.48,66.51 60.99,66.51 58.98,68.52 58.1,68.52 57.08,67.5 v2(56.95,67.5)
  BOTTOM w0.102: UC1.H14 106.87,86.02 v2(107.27,85.62)
APU_TEST0: length 3.1
  TOP w0.102: R40.2 123.5,93.17 v2(123.6,93.17) 123.87,93.43 123.87,94.29 v1(123.69,94.46)
  BOTTOM w0.102: v2(123.6,93.17) 123.42,93.17 UC1.AH6
APU_TEST1: length 1.6
  TOP w0.102: R41.2 124.32,90.69 v2(124.83,91.2)
  BOTTOM w0.102: v2(124.83,91.2) 124.25,91.2 UC1.AK8
APU_TEST2: length 5.8
  BOTTOM w0.102: UC1.AE3 120.57,95.49 120.94,95.87 120.94,96.33 121.1,96.48 121.1,97.91 121.37,98.18 121.58,98.18 121.95,98.55 v1(121.95,99.07) 121.95,99.47 R42.2
APU_TEST4: length 1.5
  TOP w0.102: v2(112.77,77.82) 113.21,77.37 T34.1
  BOTTOM w0.102: v2(112.77,77.82) 112.17,78.42 UC1.P24
APU_TEST5: length 1.5
  TOP w0.102: T35.1 111.44,77.7 v2(111.57,77.82)
  BOTTOM w0.102: v2(111.57,77.82) 110.97,78.42 UC1.N24
APU_TEST6: length 1.9
  TOP w0.102: T36.1 127.53,78 v2(127.53,77.89)
  BOTTOM w0.102: v2(127.53,77.89) 127.1,77.89 UC1.AN24
APU_TEST9: length 1.4
  TOP w0.102: T38.1 118.87,90.61 v2(118.77,90.72)
  BOTTOM w0.102: UC1.AB8 118.37,91.12 v2(118.77,90.72)
APU_TEST10: length 1.4
  TOP w0.102: T39.1 117.55,89.76 v2(117.57,89.77)
  BOTTOM w0.102: UC1.Y9 117.02,90.32 v2(117.57,89.77)
APU_TEST11: length 7.6
  TOP w0.102: RP30.5 97.72,87.01 v1(98.41,87.7) 98.85,88.14 100.89,88.14 v2(101.69,88.94)
  BOTTOM w0.102: UC1.B11 102.02,88.62 101.69,88.95 v2(101.69,88.94)
APU_TEST14: length 8.6
  TOP w0.102: RP30.8 v1(97.15,88.51) 97.62,88.51 98.78,89.67 102.82,89.67 v2(102.94,89.54)
  BOTTOM w0.102: v2(102.94,89.54) 102.83,89.42 UC1.B10
APU_TEST15: length 6.7
  TOP w0.102: T40.1 98.74,90.17 103.18,90.17 103.38,89.97 103.38,89.14 v2(103.27,89.02)
  BOTTOM w0.102: UC1.D11 103.27,89.02 v2(103.27,89.02)
APU_TEST16: length 6.9
  TOP w0.102: RP30.7 97.67,88.01 98.66,89 v1(99.71,89) v2(100.59,89)
  BOTTOM w0.102: UC1.A10 101.39,89.42 100.97,89 v2(100.59,89)
APU_TEST17: length 8.7
  TOP w0.102: RP30.6 97.69,87.51 98.74,88.56 100.69,88.56 101.23,89.09 v1(101.23,89.2) 101.4,89.38 102,89.38 v2(102.44,88.94)
  BOTTOM w0.102: UC1.C11 102.76,88.62 102.44,88.94 v2(102.44,88.94)
APU_TEST18: length 67
  TOP w0.102: RP27.4 55.53,61.35 v2(55.07,61.81) 54.48,61.21 JHDT1.20
  IN2 w0.102: v2(101.2,86.39) 100.98,86.17 100.98,85.97 100.03,85.01 100.03,83.3 98.41,81.67 95.29,81.67 95,81.38 93.75,81.38 91.91,79.54 87.08,79.54 80.2,72.66 78.29,72.66 75.09,69.45 60.44,69.45 59.5,70.4 57.63,70.4 55.07,67.84 55.07,63.16 54.72,62.8 54.72,62.17 v2(55.07,61.81)
  BOTTOM w0.102: v1(54.64,61) 55.07,61.43 v2(55.07,61.81) ; v2(101.2,86.39) 101.37,86.22 UC1.A14
APU_TEST19: length 65.4
  TOP w0.102: RP27.3 55.69,61.85 v2(55.11,62.43) 55.11,62.45 55.07,62.48 JHDT1.18
  IN2 w0.102: v2(102.07,86.5) 101.85,86.5 101.19,85.83 101.14,85.83 100.23,84.93 100.23,83.04 98.54,81.34 95.43,81.34 95.14,81.05 94.68,81.05 93.97,80.34 93.19,80.34 92.05,79.21 87.22,79.21 80.33,72.33 78.43,72.33 75.22,69.12 60.31,69.12 59.49,69.94 58.58,69.94 58.25,69.61 57.34,69.61 55.56,67.82 55.56,62.88 v2(55.11,62.43)
  BOTTOM w0.102: v2(102.07,86.5) 102.07,86.5 102.35,86.22 UC1.B14
APU_TEST28_H: length 11.5
  TOP w0.102: T43.1 91.12,85.9 92.98,85.9 93.61,86.53 97.17,86.53 97.76,85.94 98.91,85.94 100.23,87.26 v2(100.75,87.26)
  BOTTOM w0.102: v2(100.75,87.26) 100.99,87.02 UC1.A13
APU_TEST28_L: length 9.4
  TOP w0.102: v2(101.65,87.33) 101.06,86.74 100.21,86.74 99.08,85.61 97.62,85.61 97.03,86.19 94.21,86.19 T42.1
  BOTTOM w0.102: UC1.B13 101.96,87.02 101.65,87.33 v2(101.65,87.33)
APU_TEST31: length 2
  TOP w0.102: v2(112.96,76.16) 113.32,75.8 T41.1
  BOTTOM w0.102: v2(112.96,76.16) 112.6,76.52 UC1.P26
APU_TEST36: length 25.2
  TOP w0.102: v2(103.18,92.65) 103.69,92.14 103.69,90.74 104.87,89.56 v2(104.87,88.02) ; v2(103.24,96.2) 103.59,96.2 v1(103.8,96.41) 104.07,96.69 104.07,98.42 104.96,99.31 R154.1 104.96,99.82 104.58,100.2 R120.1 R155.1
  IN1 w0.102: v2(103.24,96.2) 103.12,96.08 98.76,96.08 v2(98.08,96.76)
  IN2 w0.102: v2(103.18,92.65) 103.03,92.8 101.38,92.8 98.08,96.1 v2(98.08,96.76)
  BOTTOM w0.102: v2(104.87,88.02) 104.47,88.42 UC1.E11
APU_TEST37: length 9.8
  TOP w0.102: R118.1 R117.1 94.09,85.42 95.32,84.19 v1(96.22,84.19) 100.33,84.19 v2(100.69,83.82)
  BOTTOM w0.102: UC1.A17 v2(100.69,83.82)
APU_TEST410: length 1.5
  TOP w0.102: v2(124.77,77.82) 124.72,77.87 T32.1
  BOTTOM w0.102: UC1.AK24 124.17,78.42 v2(124.77,77.82)
APU_TEST411: length 1.5
  TOP w0.102: v2(125.97,77.82) 125.95,77.84 T33.1
  BOTTOM w0.102: v2(125.97,77.82) 125.37,78.42 UC1.AL24
APU_TMS: length 69.4
  TOP w0.102: JHDT1.4 54.82,71.37 54.94,71.5 RP28.2 56.21,71.5 56.41,71.69 56.41,72.15 56.76,72.5 57.44,72.5 58.29,71.66 v4(58.29,69.31) 58.65,68.95 58.65,67.32 v2(58.91,67.07)
  IN2 w0.102: v2(58.91,67.07) 60.19,65.79 74.76,65.79 79.31,70.35 81.77,70.35 86.94,75.51 95.91,75.51 97.95,77.56 100.93,77.56 101.64,78.27 101.64,80.83 103.4,82.59 103.6,82.59 104.77,83.76 105.13,83.76 105.37,84 106.05,84 v2(106.47,84.42)
  BOTTOM w0.102: v2(106.47,84.42) 106.07,84.82 UC1.G15
APU_TRST#: length 92.2
  TOP w0.102: R671.1 C141.1 45.08,70.1 44.63,69.66 44.63,66.19 45.17,65.66 45.17,63.63 43.99,62.45 v4(43.99,62.09) 44.34,62.09 44.54,62.29 45.47,62.29 47.19,60.58 55.12,60.58 v2(55.25,60.71) 55.82,60.71 56.43,61.32 56.43,62.09 56.17,62.35 RP27.2
  IN2 w0.102: v2(55.25,60.71) 56.42,61.87 56.42,64.52 56.88,64.97 56.88,65.66 58.67,67.45 59.35,67.45 60.62,66.18 74.62,66.18 79.11,70.68 81.63,70.68 86.8,75.84 95.57,75.84 98.23,78.5 99.03,78.5 103.32,82.79 103.52,82.79 104.68,83.96 105.04,83.96 105.29,84.2 105.29,84.58 105.51,84.8 107.08,84.8 v2(107.9,85.62)
  BOTTOM w0.102: UC1.J14 107.67,85.85 v2(107.9,85.62)
APU_TRST#_R: length 3.7
  TOP w0.102: JHDT1.9 46.91,67.56 46.49,67.98 C936.1 R671.2
APU_VDD_RUN_FB_L: length 114.7
  TOP w0.254: v2(101.97,142.13) 102.42,142.57 102.42,148.89 106.97,153.44 107.49,153.44 107.95,153.9 PR1067.1 109.01,153.9 PR1069.2
  IN2 w0.102: 104.6,85.23 104.6,85.84 104.93,86.17 105.97,86.17 106.69,86.88 v2(106.69,86.88)
  IN2 w0.254: v2(101.97,142.13) 101.97,141.04 101.44,140.51 101.44,125.3 101.15,125.01 101.15,115.09 101.85,114.4 101.85,111.34 101.24,110.73 99.83,110.73 92.6,103.5 92.6,93.78 90.39,91.57 90.39,89.57 v2(90.4,89.56) ; v2(88.28,77.55) 93.61,77.55 95.56,79.49 95.89,79.49 96.06,79.65 98.91,79.65 101.9,82.64 101.9,83.02 102.94,84.06 103.68,84.06 104.16,84.55 104.16,84.8 104.59,85.23 104.6,85.23
  BOTTOM w0.102: v2(106.69,86.88) 106.69,87.25 UC1.H12
  BOTTOM w0.254: R20.1 88.27,77.53 v2(88.28,77.55) 88.06,77.77 88.06,77.86 88.04,77.87 88.04,80.64 85.97,82.71 85.97,85 90.39,89.42 90.39,89.55 v2(90.4,89.56)
APU_VDD_SEN: length 117.4
  TOP w0.254: PR1075.2 110.42,154.79 T46.1 109.35,154.28 PR1051.1 107.69,155.33 107.69,154.36 107.28,153.95 106.76,153.95 101.91,149.1 101.91,142.78 101.34,142.21 v2(101.34,142.01)
  IN2 w0.102: v2(106.07,86.87) 105.63,86.44 104.76,86.44 104.34,86.02 104.34,85.54 104.05,85.25 104.05,85.22
  IN2 w0.254: v2(87.41,77.6) 87.88,78.07 93.41,78.07 95.31,79.96 95.65,79.96 95.85,80.16 98.91,80.16 101.47,82.72 101.47,83.2 102.69,84.42 103.49,84.42 103.81,84.74 103.81,84.98 104.05,85.22 ; v2(101.34,142.01) 101.47,141.88 101.47,141.25 100.93,140.72 100.93,125.51 100.64,125.22 100.64,114.88 101.34,114.18 101.34,111.55 101.03,111.24 99.62,111.24 92.09,103.71 92.09,93.99 89.81,91.71 89.81,89.56 v2(89.81,89.56)
  BOTTOM w0.102: v2(106.07,86.87) UC1.G12
  BOTTOM w0.254: v2(89.81,89.56) 85.46,85.21 85.46,82.5 87.53,80.43 87.53,77.72 v2(87.41,77.6)
APU_VDDNB_SEN: length 129
  TOP w0.102: v2(107.39,86.86) 108.21,87.68 T44.1
  TOP w0.254: v2(116.77,162.12) 116.78,162.13 120.25,162.13 121.25,161.13 121.86,161.13 122.13,161.4 PR1002.2 123.16,161.4 PR1006.1
  IN1 w0.254: v2(116.77,162.12) 116.1,161.44 110.03,161.44 101.35,152.77 101.35,143.01 100.83,142.49 100.83,141.5 102.22,140.12 v2(102.37,140.12)
  IN2 w0.102: v2(107.39,86.86) 106.95,87.3 103.8,87.3 103.66,87.16 102.8,87.16 102.23,87.73 100.58,87.73 100.01,87.16 100.01,87.13 99.96,87.08
  IN2 w0.254: v2(102.37,140.12) 102.37,138.44 102.71,138.1 102.71,110.81 93.8,101.9 93.8,93.26 91.79,91.25 v2(91.79,89.34) ; 99.96,87.08 99.78,86.91 99.32,86.91 95.35,82.93 93.66,82.93 v2(93.15,82.42)
  BOTTOM w0.102: UC1.J12 107.67,87.14 v2(107.39,86.86)
  BOTTOM w0.254: v2(93.15,82.42) 93.02,82.55 89.81,82.55 89.68,82.42 88.49,82.42 87.75,83.16 87.75,84.81 91.79,88.85 v2(91.79,89.34)
ASGATE: length 47.6
  TOP w0.508: PR762.2 83.41,164.59 83.41,167.46 v2(84.44,168.49)
  BOTTOM w0.508: v2(84.44,168.49) 84.44,171.25 85.68,172.49 104.18,172.49 106.06,170.61 106.06,168.06 108.51,165.61 108.51,163.11 109.28,162.34 v1(110.22,162.34) 113.51,162.34 113.63,162.22 115.03,162.22 115.87,163.06 115.87,163.7
AUD_HP_OUT_L_CN: length 16.2
  TOP w0.102: v2(190.7,16.99) 190.25,17.44 v1(190.25,17.64)
  TOP w0.254: JIO1.8 192.33,28.76 193.31,27.77 193.31,27.1 v2(193.24,27.03)
  IN1 w0.254: v2(190.7,16.99) 191.47,16.99 193.15,18.68 193.15,26 193.31,26.16 193.31,26.95 v2(193.24,27.03)
  BOTTOM w0.254: v2(190.7,16.99) 191.1,17.4 LA8.1
AUD_HP_OUT_R_CN: length 17.4
  TOP w0.102: JIO1.7 190.76,27.76 v1(189.99,26.99)
  TOP w0.254: v2(192.74,26.37) 192.78,26.4 192.78,27.55 192.57,27.76 JIO1.7
  IN1 w0.254: v2(190.66,16.18) 190.18,16.66 190.18,17.25 190.44,17.51 191.27,17.51 192.58,18.82 192.58,26.19 192.74,26.35 v2(192.74,26.37)
  BOTTOM w0.254: LA9.1 190.96,15.88 v2(190.66,16.18)
BA: length 17
  TOP w0.254: PR780.1 108.38,169.33 PQ710.1 108.38,165.1 108.86,164.62 109.54,164.62 110.76,165.84 110.76,166.62 111.02,166.88 v1(115.31,166.88) 116.82,165.37 PD705.2
BAT_AMBER: length 9.6
  TOP w0.127: LED1.1 18.66,2.17 18.85,2.36 18.85,3.06 19.25,3.45 24.54,3.45 R6103.1
BAT_WHITE: length 9.9
  TOP w0.127: LED1.2 19.16,3.92 R6107.1 25.46,3.47 26.28,3.47 26.65,3.84 v1(27.18,3.84)
BATT_I: length 164.5
  TOP w0.127: UE1.75 178.38,73.96 178.56,74.14 178.56,74.48 178.78,74.7 179.26,74.7 179.41,74.84 181.49,74.84 v2(182.9,76.26)
  IN1 w0.127: v2(182.9,76.26) 182.35,76.81 182.35,77.96 179.48,80.83 178.49,80.83 178.24,81.08 178.24,81.73 177.22,82.75 176.41,82.75 173.82,85.34 170.93,85.34 169.65,86.62 169.65,88.67 167.15,91.17 167.15,92.95 166.96,93.14 166.35,93.14 165.94,93.54 165.94,98.08 164.57,99.45 164.57,108.1 157.63,115.04 150.37,115.04 144.16,121.25 134.24,121.25 128.55,126.94 111.79,126.94 99.74,138.98 99.74,152.48 108.02,160.76 108.02,166.83 v2(111.12,169.93)
  BOTTOM w0.127: v2(182.9,76.26) v1(182.32,76.26)
  BOTTOM w0.254: v2(111.12,169.93) PC749.2 PR775.1
BATT_LOW_LED: length 38.6
  TOP w0.127: R6103.2 26.27,3.01 26.75,3.49 28.06,3.49 v2(28.26,3.7)
  BOTTOM w0.127: Q6101.1 v1(59.1,9.91) 38.47,9.91 32.26,3.7 v2(28.26,3.7)
BATT_LOW_LED#: length 263.3
  TOP w0.127: v2(167.16,60.53) 167.29,60.4 169.82,60.4 171.02,61.61 v1(173.82,61.61) 175.04,61.61 178.62,65.19 178.62,66.55 178.41,66.76 UE1.93
  IN1 w0.127: v2(21.41,4.38) 22.26,4.38 28.61,10.73 32.16,10.73 36.29,14.86 46.55,14.86 50.55,10.86 95.12,10.86 97.4,8.57 156.65,8.57 165.96,17.88 165.96,26.95 165.21,27.7 165.21,33.11 165.07,33.25 165.07,45.42 167.67,48.03 167.67,58.44 166.76,59.35 166.76,60.12 v2(167.16,60.53)
  BOTTOM w0.127: R6105.1 63.09,9.96 62.01,8.88 37.77,8.88 32.12,3.23 23.59,3.23 22.43,4.38 v2(21.41,4.38)
BATT_LOW_LED_R#: length 5.3
  BOTTOM w0.127: R6105.2 Q6101.2 61.07,10.87 v1(60.43,11.51)
BATT_PRS: length 5.8
  BOTTOM w0.127: v1(155.39,175.67) 155.81,176.09 PR15.1
  BOTTOM w0.508: PBATT1.4 158.4,178.85 156.52,176.97 156.52,176.1 PR15.1
BATT_TEMP: length 190.7
  TOP w0.127: UE1.63 179.55,80.51 180.02,80.98 180.02,81.73 v2(180.08,81.8) 180.08,81.85 179.71,82.22 CE43.2
  TOP w0.254: v2(148.44,158.34) 149.57,158.34 v1(149.97,158.74) 150.55,159.32 PR16.1 ; PR37.2 145.5,170.89 PC14.1 v2(146.36,171.59)
  IN1 w0.127: v2(180.08,81.8) 180.08,81.81 175.63,86.26 171.31,86.26 170.57,87 170.57,89.8 169.84,90.53 169.84,91.01 169.55,91.3 168.85,91.3 168.4,91.76 168.4,93.77 169.63,95 169.63,98.97 170.19,99.53 170.19,100.79 167.67,103.3 167.67,116.23 164.16,119.74 163.56,119.74 162.72,118.9 157.5,118.9 155.93,120.47 155.46,120.47 153.78,122.15 153.78,129.99 152.56,131.21 152.56,134.09 150.48,136.17 150.48,143.09 146.31,147.26 144.59,147.26 142.93,148.92 142.93,151.73 148.45,157.25 148.45,158.35 v2(148.44,158.34)
  IN1 w0.254: v2(156.52,173.74) 155.38,173.74 152.58,170.94 152.58,164.57 149.1,161.09 149.1,160.53 148.11,159.54 148.11,158.67 v2(148.44,158.34)
  IN2 w0.254: v2(117.49,173.99) 119.89,176.39 139.33,176.39 141.28,174.43 149.42,174.43 150.12,173.74 v2(156.52,173.74)
  BOTTOM w0.254: PR764.1 116.62,172.5 PC753.2 ; PR764.1 v2(117.49,173.99) ; PR764.1 118.37,172.5 PR756.1 ; PR15.2 157.42,176.08 PD3.2 157.42,174.63 v2(156.52,173.74) 155.54,172.76 149.94,172.76 149.42,172.24 146.97,172.24 146.36,171.63 v2(146.36,171.59)
BEEP#: length 65.7
  TOP w0.099: v2(180.07,23.1) v1(180.07,23.7) ; UE1.23 194,74.36 194.14,74.22 194.63,74.22 v2(194.81,74.04)
  IN2 w0.109: v2(194.81,74.04) 195.32,73.53 195.32,73.14 196.03,72.43 196.03,61.1 187.89,52.96 187.89,37.4 188.82,36.47 188.82,36.07 187.75,35 187.75,29.26 188.13,28.88 188.13,26.1 186.3,24.27 181.24,24.27 v2(180.07,23.1)
  BOTTOM w0.099: DA8.2 v2(180.07,23.1)
BKOFF#: length 214.3
  TOP w0.127: U5.1 168.37,37.13 168.7,37.47 168.7,39.12 167.13,40.69 167.13,48.04 167.43,48.35 167.43,49.87 168.43,50.87 170.56,50.87 170.66,50.77 172.26,50.77 172.72,50.32 186.9,50.32 v2(187.08,50.14) ; v2(185.15,73.47) 185.26,73.36 185.26,71.03 v2(184.94,70.71) 184.94,70.06 182.35,67.46 UE1.105
  IN1 w0.127: v2(184.94,70.71) 185.29,70.37 185.29,66.01 185.56,65.73 185.56,63.83 184.74,63.02 184.74,60.68 184.89,60.53 185.34,60.09 185.34,57.64 185.32,57.63 185.32,51.89 v2(187.08,50.14) ; v2(185.15,73.47) 184.98,73.63 183.45,73.63 180.65,76.44 180.65,77.69 179.04,79.3 177.58,79.3 175.65,81.23 175.06,81.23 174.47,81.82 174.47,82.19 173.41,83.25 170.71,83.25 167.12,86.84 167.12,87.99 164.33,90.78 164.33,97.43 162.97,98.79 162.97,106.11 162.57,106.51 162.57,107.84 156.97,113.44 149.7,113.44 143.5,119.65 133.58,119.65 127.89,125.34 111.11,125.34 99.58,136.87 93.29,143.15 93.29,143.15 92.36,144.09 92.36,155.89 v2(93.15,156.68)
  BOTTOM w0.127: v2(93.15,156.68) 92.8,157.02 DX1.2
BP_0: length 6.9
  BOTTOM w0.102: RV82.1 182.09,130.91 178.96,130.91 177.29,132.58 UV1.U1
BP_1: length 4.5
  BOTTOM w0.102: RV81.1 179.29,130.04 v1(178.7,130.63) 176.57,132.76 UV1.U3
BST1_APU:
  vias: v1(116.21,150.93)
BST1_GFX:
  vias: v1(61.87,38.85)
BST1_VGA: length 1.2
  BOTTOM w0.127: PR1123.1 173.91,95.25 v1(173.44,95.72)
BST2_VGA: length 1.9
  BOTTOM w0.127: PR1103.1 174.49,88.28 v1(175.69,87.08)
BST_1.35V:
  vias: v1(63.56,21.56)
BST_1.35V_R: length 1.6
  TOP w0.127: PC200.1 v1(64.89,17.35)
BST_1.35VGPU: length 0.9
  BOTTOM w0.127: 198.48,165.61 198.99,165.61 199.23,165.85 v1(199.23,165.86)
BST_3V:
  vias: v1(39.29,50.19)
BST_5V:
  vias: v1(44.7,50.24)
BST_NB:
  vias: v1(122.37,152.35)
BST_VDDP_ALWP:
  vias: v1(138.78,150.01)
BT_ON#: length 84.9
  TOP w0.102: v2(131.66,88) 131.84,88.19 132.68,88.19 133.2,88.71 133.6,88.71 134.26,89.38 134.56,89.67 134.56,93.97 134.98,94.39 137.32,94.39 v1(137.63,94.08) 139.43,92.28 146.15,92.28 146.77,92.9 v2(147.29,92.9) ; v2(158.01,54.79) 158.01,54.79 163.96,54.79 164.34,54.41 164.34,51.97 165.02,51.3 v2(165.04,51.3) ; RH41.2 147.9,89.79 v2(147.91,89.8)
  IN1 w0.102: v2(158.01,54.79) 158.64,55.42 158.64,63.93 157.22,65.35 157.22,68.38 156.7,68.9 156.7,80.42 153.56,83.55 153.56,86.09 150.45,89.2 148.37,89.2 147.91,89.66 v2(147.91,89.8) 147.91,90.96 147.3,91.57 147.3,92.89 v2(147.29,92.9)
  BOTTOM w0.102: JNGFF.46 169.86,49.78 168.34,51.3 v2(165.04,51.3) ; v2(131.66,88) 130.85,88 UC1.AU12
CAPS_LED: length 62.8
  TOP w0.127: UE1.91 178.72,67.56 179.14,67.13 180.7,67.13 184.09,70.53 184.09,75.32 v2(185.03,76.26) ; v2(193.84,80.39) 193.84,80.56 197.55,84.27 197.55,112.11 197.94,112.5 v1(197.94,113.46) 197.55,113.85 R29.1 195.8,114.73 R27.1
  IN1 w0.127: v2(193.84,80.39) 192.38,80.39 191.51,79.51 191.51,78.54 190.02,77.05 185.82,77.05 v2(185.03,76.26)
CAPS_LED_R: length 4.8
  TOP w0.127: JKB.1 v1(194.15,116.15) 195.3,116.15 R27.2 R28.2
CCLIM: length 4.3
  BOTTOM w0.203: PR752.2 114.86,171.76 116.35,170.27 PU703.11
  BOTTOM w0.254: PR750.1 PR752.2
CLK_PCIE_LAN: length 143.4
  TOP w0.127: v2(49.92,164.59) 50.08,164.75 50.08,164.99 49.92,165.15 49.39,165.15 49,165.54 49,165.72 49,165.73 49,165.77 48.94,165.84 UL1.15
  IN2 w0.127: v2(125.13,110.5) 125.27,110.64 125.27,110.87 123.21,112.93 109.11,112.93 105.44,116.6 105.44,141.67 100.55,146.56 86.86,146.56 69.45,163.97 61.71,163.97 60.26,162.51 51.68,162.51 50.04,164.15 50.04,164.46 v2(49.92,164.59)
  BOTTOM w0.102: UC1.U1 114.01,96.57 114.01,96.38 114.1,96.29 114.18,96.29 114.51,96.62 114.51,97.76 114.16,98.11 114.11,98.16 114.09,98.16 114.08,98.17
  BOTTOM w0.127: v2(125.13,110.5) 125.26,110.37 125.26,110.3 125.06,110.1 123.6,110.1 123.1,110.59 116.1,110.59 112.8,107.29 112.8,100.06 113.15,99.71 113.15,99.11 114.08,98.17
CLK_PCIE_LAN#: length 143.4
  TOP w0.127: UL1.16 49.34,165.8 49.26,165.72 49.26,165.64 49.5,165.4 50.03,165.4 50.34,165.1 50.34,164.75 v2(50.5,164.59)
  IN2 w0.127: v2(125.72,110.5) 125.53,110.69 125.53,110.97 123.32,113.18 109.22,113.18 105.7,116.7 105.7,141.77 100.66,146.81 86.97,146.81 69.56,164.22 61.61,164.22 60.15,162.77 51.79,162.77 50.3,164.25 50.3,164.39 v2(50.5,164.59)
  BOTTOM w0.102: 114.19,98.43 114.28,98.34 114.28,98.32 114.33,98.27 114.74,97.86 114.74,96.53 114.17,95.95 UC1.U2
  BOTTOM w0.127: v2(125.72,110.5) 125.52,110.3 125.52,110.2 125.16,109.84 123.5,109.84 123,110.34 116.2,110.34 113.05,107.18 113.05,100.17 113.4,99.82 113.4,99.22 114.19,98.43
CLK_PCIE_WLAN: length 83.4
  IN2 w0.127: v2(116.21,93.97) 116.35,94.11 116.35,94.3 116.24,94.41 115.87,94.41 115.64,94.18 115.64,93.89 115.97,93.55 116.88,93.55 117.14,93.81 118.32,93.81 119.44,92.69 119.44,87.99 120.71,86.72 120.71,86.1 121.11,85.7 128.32,85.7 129.04,84.99 134.05,84.99 135.04,84 137.78,84 138.56,83.22 138.56,80.95 139.92,79.59 139.92,67.26 144.51,62.68 144.51,56.62 145.81,55.32 148.07,55.32 152.01,51.37 162.07,51.37 v2(162.24,51.54)
  BOTTOM w0.102: v2(116.21,93.97) 116.17,93.93 115.86,93.93 115.68,94.11 115.68,94.23 UC1.W4
  BOTTOM w0.127: v2(162.24,51.54) 162.39,51.39 162.52,51.39 162.66,51.52 JNGFF.39
CLK_PCIE_WLAN#: length 83.4
  IN2 w0.127: v2(162.24,50.96) 162.08,51.12 151.9,51.12 147.96,55.06 145.71,55.06 144.25,56.51 144.25,62.57 139.67,67.16 139.67,79.49 138.31,80.85 138.31,83.11 137.67,83.74 134.93,83.74 133.94,84.73 128.93,84.73 128.22,85.45 121,85.45 120.45,86 120.45,86.62 119.18,87.89 119.18,92.59 118.21,93.56 117.25,93.56 116.99,93.29 115.87,93.29 115.38,93.78 115.38,94.29 115.76,94.67 116.05,94.67 v2(116.2,94.82)
  BOTTOM w0.102: UC1.W3 115.9,95.12 v2(116.2,94.82)
  BOTTOM w0.127: JNGFF.41 162.66,51.03 162.55,51.13 162.42,51.13 v2(162.24,50.96)
CLK_PEG_VGA: length 67.7
  BOTTOM w0.089: UV1.AK30 156.17,123.16 155.78,122.78 155.57,122.78 155.37,122.58 155.18,122.39 154.86,122.39 154.76,122.29 154.56,122.09 154.56,122.06 154.55,122.05
  BOTTOM w0.102: 115.13,98.58 115.14,98.57 115.14,98.56 115.19,98.5 115.45,98.24 115.45,96.58 115.5,96.54 115.5,96.1 115.45,96.05 115.45,95.79 115.5,95.74 115.5,95.3 115.45,95.25 115.45,95.05 115.19,94.8 114.88,94.8 114.4,94.32 UC1.U4
  BOTTOM w0.127: 115.13,98.58 114.17,99.54 114.17,102.98 113.82,103.33 113.82,106.87 116.41,109.46 120.02,109.46 121.94,107.54 121.94,107.19 122.46,106.66 123.66,106.66 124.81,107.82 125.42,107.82 126.9,109.3 132.58,109.3 135.07,111.79 v3(137.32,111.79) 143.72,111.79 145.66,113.73 148.96,113.73 154.45,119.22 154.45,121.95 154.55,122.05
CLK_PEG_VGA#: length 67.7
  BOTTOM w0.089: 154.37,122.23 154.38,122.24 154.4,122.24 154.45,122.29 154.61,122.44 154.61,122.45 154.77,122.61 155.09,122.61 155.35,122.87 155.35,122.97 155.28,123.04 155.28,123.2 155.39,123.31 155.55,123.31 UV1.AK32
  BOTTOM w0.102: 114.95,98.4 114.96,98.39 114.97,98.39 115.03,98.34 115.22,98.14 115.22,96.49 115.27,96.44 115.27,96.2 115.22,96.14 115.22,95.7 115.27,95.64 115.27,95.4 115.22,95.34 115.22,95.14 115.1,95.03 114.78,95.03 114.38,94.62 114.26,94.62 114.17,94.72 UC1.U3
  BOTTOM w0.127: 154.37,122.23 154.19,122.06 154.19,119.33 148.85,113.98 145.55,113.98 143.61,112.04 134.97,112.04 132.48,109.55 v3(130.69,109.55) 126.79,109.55 125.32,108.08 124.71,108.08 123.55,106.92 122.57,106.92 122.2,107.29 122.2,107.64 120.12,109.72 116.3,109.72 113.56,106.97 113.56,103.22 113.91,102.87 113.91,99.44 114.95,98.4
CLK_SMB: length 5.6
  BOTTOM w0.127: PR18.1 162.69,175.27 v1(163.38,174.59)
  BOTTOM w0.508: PR18.1 162.69,177.67 162.4,177.97 PBATT1.6
CMSRC: length 42.2
  TOP w0.508: PR763.2 83.6,170.81 83.97,171.18 v2(85.41,171.18)
  BOTTOM w0.508: v2(85.41,171.18) 86,171.77 103.82,171.77 105.37,170.22 105.37,167.9 107.91,165.36 107.91,162.85 109.09,161.67 v1(112.63,161.67) 113.32,161.67 113.38,161.61 115.28,161.61 116.49,162.82 116.49,163.42
COMP: length 5.2
  BOTTOM w0.203: PU703.10 115.95,170.14 v1(115.22,170.88) 114.18,171.92 113.66,171.92 PR754.2
  BOTTOM w0.254: PC751.2 112.14,172.51 PR754.2
CORE_NB_GATE: length 27
  TOP w0.102: R127.2 v1(52.51,46.77)
  TOP w0.254: R127.2 R129.2 53.4,47.22 v2(53.4,47.22)
  IN1 w0.254: v2(53.4,47.22) 53.5,47.32 53.5,53.18 47.88,58.8 v2(44.63,58.8)
  BOTTOM w0.254: v2(44.63,58.8) 44.63,59.25 45,59.61 Q2513.2 46.65,59.61 46.98,59.94 46.98,61.47 47.76,62.24 Q135.2
CORE_NB_GATE_BUFF: length 27.2
  TOP w0.127: v2(53.04,49.36) v1(53.04,50.1)
  TOP w0.254: R127.1 52.51,48.83 v2(53.04,49.36)
  IN2 w0.254: v2(41.54,56.38) 41.84,56.68 48.74,56.68 53.04,52.38 v2(53.04,49.36)
  BOTTOM w0.254: U2.6 41.97,58.04 41.54,57.61 v2(41.54,56.38) 41.42,56.49 40.76,56.49 40.42,56.15 R53.1 40.21,54.23 38.94,55.5 U2.1
CORE_NB_GATE_CC: length 33.4
  TOP w0.254: R129.1 53.9,48.21 v1(53.9,46.78) v2(53.34,46.21)
  IN2 w0.254: v2(38.02,54.78) 38.65,55.41 41.43,55.41 42.35,56.32 48.59,56.32 52.58,52.33 52.58,46.97 v2(53.34,46.21)
  BOTTOM w0.254: Q2507.6 54.24,47.15 R918.1 54.16,47.03 v2(53.34,46.21) ; v2(38.02,54.78) 36.34,54.78 35.74,55.37 35.3,55.37 34.85,55.82 Q93.1
CORETYPE: length 29
  TOP w0.127: v2(87.27,74.79) 87.27,75.18 v1(88.32,76.22) 89.16,77.06 R654.1
  IN2 w0.102: 99.13,75.92 100.31,75.92 101.03,76.64 106,76.64 106.52,77.17 108.78,77.17 109.17,77.55 v2(109.17,78.01)
  IN2 w0.127: 99.13,75.92 97.59,75.92 96.46,74.79 87.27,74.79 v2(87.27,74.79)
  BOTTOM w0.102: UC1.K24 108.76,78.42 v2(109.17,78.01)
CPU_DPB_CTRLCLK_R: length 31
  TOP w0.112: 26.79,73.38 v2(26.64,73.53)
  TOP w0.127: JHDMI.15 10.47,68.29 10.47,68.31 10.6,68.43 10.6,69.96 14.34,73.7 17.75,73.7 20.89,76.84 22.39,76.84 22.92,76.31 22.92,75.85 23.17,75.6 D20.3 22.88,74.76 22.88,74.58 23.17,74.29 24.19,74.29 25.16,73.32 26.43,73.32 v2(26.64,73.53) ; QX4.6 27.2,73.53 27.04,73.38 26.79,73.38
  BOTTOM w0.112: v2(26.64,73.53) 26.86,73.31 27.04,73.31 27.15,73.42 27.15,73.85 27.55,74.25 29.79,74.25 29.91,74.37 RP63.4
CPU_DPB_CTRLDAT_R: length 31.2
  TOP w0.127: QX4.3 28.5,72.78 28.2,73.08 26.82,73.08 v2(26.64,72.9) 26.48,73.06 25.06,73.06 24.08,74.04 23.06,74.04 22.63,74.48 22.63,74.76 D20.2 22.31,75.6 22.66,75.95 22.66,76.2 22.28,76.58 21.01,76.58 17.87,73.44 v3(15.49,73.44) 14.45,73.44 10.85,69.85 10.85,68.44 11.07,68.22 JHDMI.16
  BOTTOM w0.112: v2(26.64,72.9) 26.8,73.05 27.14,73.05 27.41,73.32 27.41,73.75 27.65,74 29.79,74 29.91,73.87 RP63.3
CRT_B: length 18.9
  TOP w0.127: RZ53.1 CZ29.1 29.26,60.68 29.9,61.33 29.9,65.39 29.62,65.67 v4(29.62,69.83) 30.44,70.65 32.02,70.65 32.51,70.16 RP62.8 32.82,69.71 33.83,70.72 UZ1.10
CRT_B_2: length 14.8
  TOP w0.127: JCRT.3 16.31,62.96 16.31,62.24 v4(18.08,60.48) 19.53,59.03 21.98,59.03 23.58,60.63 CZ23.1 23.98,60.63 LZ3.2
CRT_B_C: length 1.8
  TOP w0.127: RZ53.2 CZ20.1 25.74,59.76 LZ3.1
CRT_CLK: length 57.7
  TOP w0.127: UZ1.4 37.77,72.77 v2(37.9,72.9) ; RZ54.2 12.83,79.15 12.36,79.15 v2(12.19,79.31)
  IN2 w0.127: JCRT.15 15.97,69.28 15.97,67.12 16.2,66.89 16.83,66.89 17.13,67.19 17.13,75.88 15.2,77.8 11.69,77.8 11.32,78.17 11.32,78.79 11.6,79.07 11.95,79.07 v2(12.19,79.31) 12.36,79.15 13.16,79.15 13.72,79.71 19.5,79.71 20.4,78.81 21.14,78.07 24.25,78.07 27.4,81.22 33.69,81.22 34.79,80.12 34.79,76.7 37.39,74.09 37.39,73.41 v2(37.9,72.9)
CRT_DATA: length 57.4
  TOP w0.127: v2(12.19,78.73) 12.36,78.89 12.83,78.89 RZ55.2 ; UZ1.6 v2(36.77,72.89)
  IN2 w0.127: JCRT.12 15.94,63.92 15.94,66.41 16.17,66.64 16.94,66.64 17.38,67.08 17.38,75.98 15.31,78.05 11.8,78.05 11.58,78.27 11.58,78.69 11.7,78.82 12.1,78.82 v2(12.19,78.73) 12.36,78.89 13.26,78.89 13.82,79.45 19.4,79.45 21.04,77.81 24.35,77.81 27.5,80.96 33.58,80.96 34.54,80.01 34.54,76.59 37.14,73.99 37.14,73.26 v2(36.77,72.89)
CRT_G: length 19.9
  TOP w0.127: RZ52.1 27.54,57.94 CZ28.1 27.99,57.94 v4(30.2,60.15) 30.54,60.49 30.54,67.94 30.28,68.2 30.28,69.59 30.71,70.02 31.77,70.02 31.93,69.85 31.93,69.37 32.09,69.21 RP62.7 33.22,69.21 33.72,69.72 UZ1.12
CRT_G_2: length 13.2
  TOP w0.127: LZ2.2 23.96,57.97 CZ22.1 v4(21.11,57.96) 19.25,57.96 15.3,61.91 15.07,61.91 JCRT.2
CRT_G_C: length 1.8
  TOP w0.127: LZ2.1 25.73,58.84 CZ19.1 26.63,58.85 RZ52.2
CRT_HSYNC: length 33.6
  TOP w0.127: JCRT.13 15.2,66.86 17.01,68.67 17.01,71.06 v4(18.08,72.12) 19.54,73.58 22.08,73.58 22.64,73.02 23.66,73.02 24.64,72.04 25.39,72.04 27.52,69.91 28.81,69.91 30.15,71.26 30.61,71.72 30.61,74.89 32.1,76.38 32.6,76.89 34.6,76.89 CZ34.1 35.05,75.69 34.73,75.37 RZ47.2
CRT_R: length 19.2
  TOP w0.127: UZ1.15 34.15,68.22 33.66,68.71 RP62.6 32.06,68.71 31.91,68.55 31.91,67.89 31.55,67.54 31.55,59.04 v4(30.04,57.52) 28.35,55.84 CZ27.1 27.59,55.84 RZ51.1
CRT_R_2: length 13.1
  TOP w0.127: LZ1.2 23.96,55.87 CZ21.1 23.69,55.86 22.45,57.11 17.58,57.11 v4(17.1,57.59) JCRT.1
CRT_R_C: length 1.9
  TOP w0.127: LZ1.1 25.74,56.73 CZ18.1 26.65,56.73 RZ51.2
CRT_VSYNC: length 36
  TOP w0.127: JCRT.14 16.38,68.94 16.38,71.18 19.28,74.09 22.29,74.09 22.85,73.53 v4(23.39,73.53) 23.87,73.53 24.85,72.55 25.6,72.55 27.61,70.55 28.55,70.55 29.98,71.98 29.98,74.98 33.74,78.74 36.24,78.74 36.75,78.23 36.75,77.19 CZ33.1 RZ49.2
CS1_5V: length 2.9
  TOP w0.203: PU100.1 42.72,52.69 42.86,52.84 v2(43.49,52.84)
  BOTTOM w0.127: v2(43.49,52.84) v1(43.49,53.8)
  BOTTOM w0.254: v2(43.49,52.84) 43.37,52.72 PR105.1
CS2_3V: length 3.4
  TOP w0.203: PU100.5 41.12,52.66 v2(40.44,53.34)
  BOTTOM w0.127: v1(39.11,52.25) 39.58,52.72 PR108.1
  BOTTOM w0.254: v2(40.44,53.34) 40.19,53.09 PR108.1
CS_1.35V: length 3.2
  TOP w0.127: PR205.2 v1(61.92,17.86)
  TOP w0.203: PU200.13 60.6,18.77 60.89,18.48 PR205.2
DAT_SMB: length 5.7
  BOTTOM w0.127: PR20.1 160,174.96 v1(159.51,174.46)
  BOTTOM w0.508: PBATT1.5 160.4,178.07 160,177.67 PR20.1
DBC_EN: length 158.7
  TOP w0.127: UE1.89 178.43,68.36 178.66,68.58 179.09,68.58 179.33,68.34 179.33,67.76 179.69,67.4 180.64,67.4 183.86,70.62 183.86,73.29 183.37,73.79 v2(183.37,74.28)
  IN1 w0.127: v2(93.49,143.89) 93.49,143.61 111.3,125.79 128.08,125.79 133.77,120.1 143.69,120.1 149.89,113.9 157.15,113.9 163.04,108.01 163.04,106.81 163.43,106.42 163.43,98.98 164.79,97.62 164.79,90.97 168.18,87.58 168.18,86.8 171.27,83.71 174.16,83.71 176.59,81.28 176.59,80.94 177.77,79.76 179.26,79.76 181.44,77.58 181.44,76.14 183.03,74.54 183.1,74.54 v2(183.37,74.28)
  BOTTOM w0.127: v2(93.49,143.89) 93.45,143.93 92.47,143.93 92.2,144.21 92.2,145.53 89.91,147.82 89.65,147.82 85.74,151.72 85.74,156.38 RX23.1
DBC_EN_R: length 10.5
  BOTTOM w0.127: v1(86.4,156.83) 85.62,157.62 RX23.2 85.08,157.95 85.08,159.36 RX36.1 85.03,160.32 85.03,164.47 84.3,165.2 JEDP.8
DDI1_AUX_C_DN: length 75.4
  TOP w0.127: UZ1.27 40.47,68.72 40.58,68.61 40.79,68.61 v2(40.94,68.76)
  IN2 w0.127: v2(40.94,68.76) 41.1,68.59 43.85,68.59 44.65,69.39 44.65,73.63 51.01,80 67.59,80 68.08,80.49 68.35,80.49 v2(68.51,80.65)
  BOTTOM w0.127: v2(68.51,80.65) 68.68,80.49 69.66,80.49 72.58,77.57 77.98,77.57 79.34,78.94 79.34,85.1 86.39,92.15 93.72,92.15 94.93,90.95 94.93,90.53 95.22,90.23 95.42,90.23 CZ16.1
DDI1_AUX_C_DP: length 75.4
  TOP w0.127: UZ1.26 40.46,68.22 40.6,68.35 40.76,68.35 v2(40.94,68.17)
  IN2 w0.127: v2(68.51,80.07) 68.35,80.23 68.18,80.23 67.7,79.74 51.12,79.74 44.9,73.53 44.9,69.29 43.95,68.34 41.1,68.34 v2(40.94,68.17)
  BOTTOM w0.127: CZ17.1 95.42,89.98 95.12,89.98 94.67,90.43 94.67,90.85 93.62,91.9 v3(89.31,91.9) 86.5,91.9 79.6,85 79.6,78.83 78.08,77.32 72.47,77.32 69.56,80.23 68.68,80.23 v2(68.51,80.07)
DDRA_CLK0: length 74.3
  IN2 w0.102: 121.79,68.08 121.82,68.11 121.82,68.2 121.21,68.8 121.21,69.21 120.98,69.44 v2(120.98,69.66)
  IN2 w0.216: v2(122.23,21.9) 122.16,21.97 121.93,21.97 121.47,22.43 121.47,24.69 120.31,25.84 120.31,28.49 120.06,28.75 118.45,30.35 118.45,38.87 118.31,39.02 118.31,48.51 118.09,48.73 116.41,48.73 116.02,49.12 116.02,50.16 116.41,50.54 118.09,50.54 118.31,50.76 118.31,51.34 118.09,51.55 116.4,51.55 115.92,52.03 115.92,52.89 116.4,53.37 118.09,53.37 118.31,53.58 118.31,54.08 118.09,54.3 116.4,54.3 115.92,54.77 115.92,55.64 116.4,56.11 118.09,56.11 118.31,56.33 118.31,56.82 118.09,57.04 116.4,57.04 115.92,57.51 115.92,58.38 116.4,58.85 118.09,58.85 118.31,59.07 118.31,59.57 118.09,59.78 117.45,59.78 117.06,60.17 117.06,61.21 117.45,61.6 118.09,61.6 118.31,61.81 118.31,62.4 121.79,65.88 121.79,68.08
  BOTTOM w0.102: v2(120.98,69.66) 120.57,70.08 UC1.AE33
  BOTTOM w0.196: JDIMM1.101 120.9,22.56 121.56,21.9 v2(122.23,21.9)
DDRA_CLK0#: length 74.1
  IN2 w0.102: v2(120.98,70.27) 121.42,69.83 121.42,69.47 121.55,69.34 121.55,68.83 121.55,68.83 121.55,68.79 121.8,68.54 121.91,68.54 122.23,68.22 122.23,68.08
  IN2 w0.216: v2(122.23,22.49) 122.16,22.42 122.11,22.42 121.91,22.61 121.91,24.87 120.76,26.03 120.76,28.68 120.5,28.93 118.9,30.54 118.9,39.06 118.75,39.2 118.75,48.7 118.27,49.17 116.59,49.17 116.47,49.3 116.47,49.97 116.59,50.1 118.27,50.1 118.75,50.58 118.75,51.52 118.27,52 116.58,52 116.36,52.21 116.36,52.71 116.58,52.92 118.27,52.92 118.75,53.4 118.75,54.26 118.27,54.74 116.58,54.74 116.36,54.96 116.36,55.45 116.58,55.67 118.27,55.67 118.75,56.14 118.75,57.01 118.27,57.48 116.58,57.48 116.36,57.7 116.36,58.19 116.58,58.41 118.27,58.41 118.75,58.89 118.75,59.75 118.27,60.23 117.63,60.23 117.51,60.35 117.51,61.03 117.63,61.15 118.27,61.15 118.75,61.63 118.75,62.22 122.23,65.7 122.23,68.08
  BOTTOM w0.102: v2(120.98,70.27) 120.87,70.38 120.87,71.41 UC1.AE32
  BOTTOM w0.196: v2(122.23,22.49) 122.05,22.3 121.72,22.3 121.3,22.73 121.3,23.83 121.5,24.03 JDIMM1.103
DDRA_CLK1: length 76.6
  IN2 w0.102: v2(120.96,72.92) 120.67,72.62 120.67,70.79 120.6,70.72 120.6,68.96 120.86,68.7 120.86,68.08
  IN2 w0.216: v2(120.34,18.87) 120.4,18.92 121.13,18.92 121.58,19.38 121.58,20.96 120.54,22 120.54,24.3 119.13,25.71 119.13,28.16 117.29,30 117.29,38.66 116.86,39.09 115.23,39.09 115.11,39.22 115.11,40.36 115.23,40.48 116.9,40.48 117.38,40.96 117.38,41.82 116.9,42.3 115.2,42.3 114.98,42.51 114.98,43.01 115.2,43.23 116.9,43.23 117.38,43.7 117.38,44.57 116.9,45.04 115.2,45.04 114.98,45.26 114.98,45.75 115.2,45.97 116.9,45.97 117.38,46.44 117.38,47.31 116.9,47.78 115.2,47.78 114.98,48 114.98,60.48 120.86,66.36 120.86,68.08
  BOTTOM w0.102: UC1.AE30 120.57,73.32 v2(120.96,72.92)
  BOTTOM w0.196: v2(120.34,18.87) 120.38,18.91 120.66,18.91 121.3,18.27 121.3,18.11 121.2,18.01 JDIMM1.102
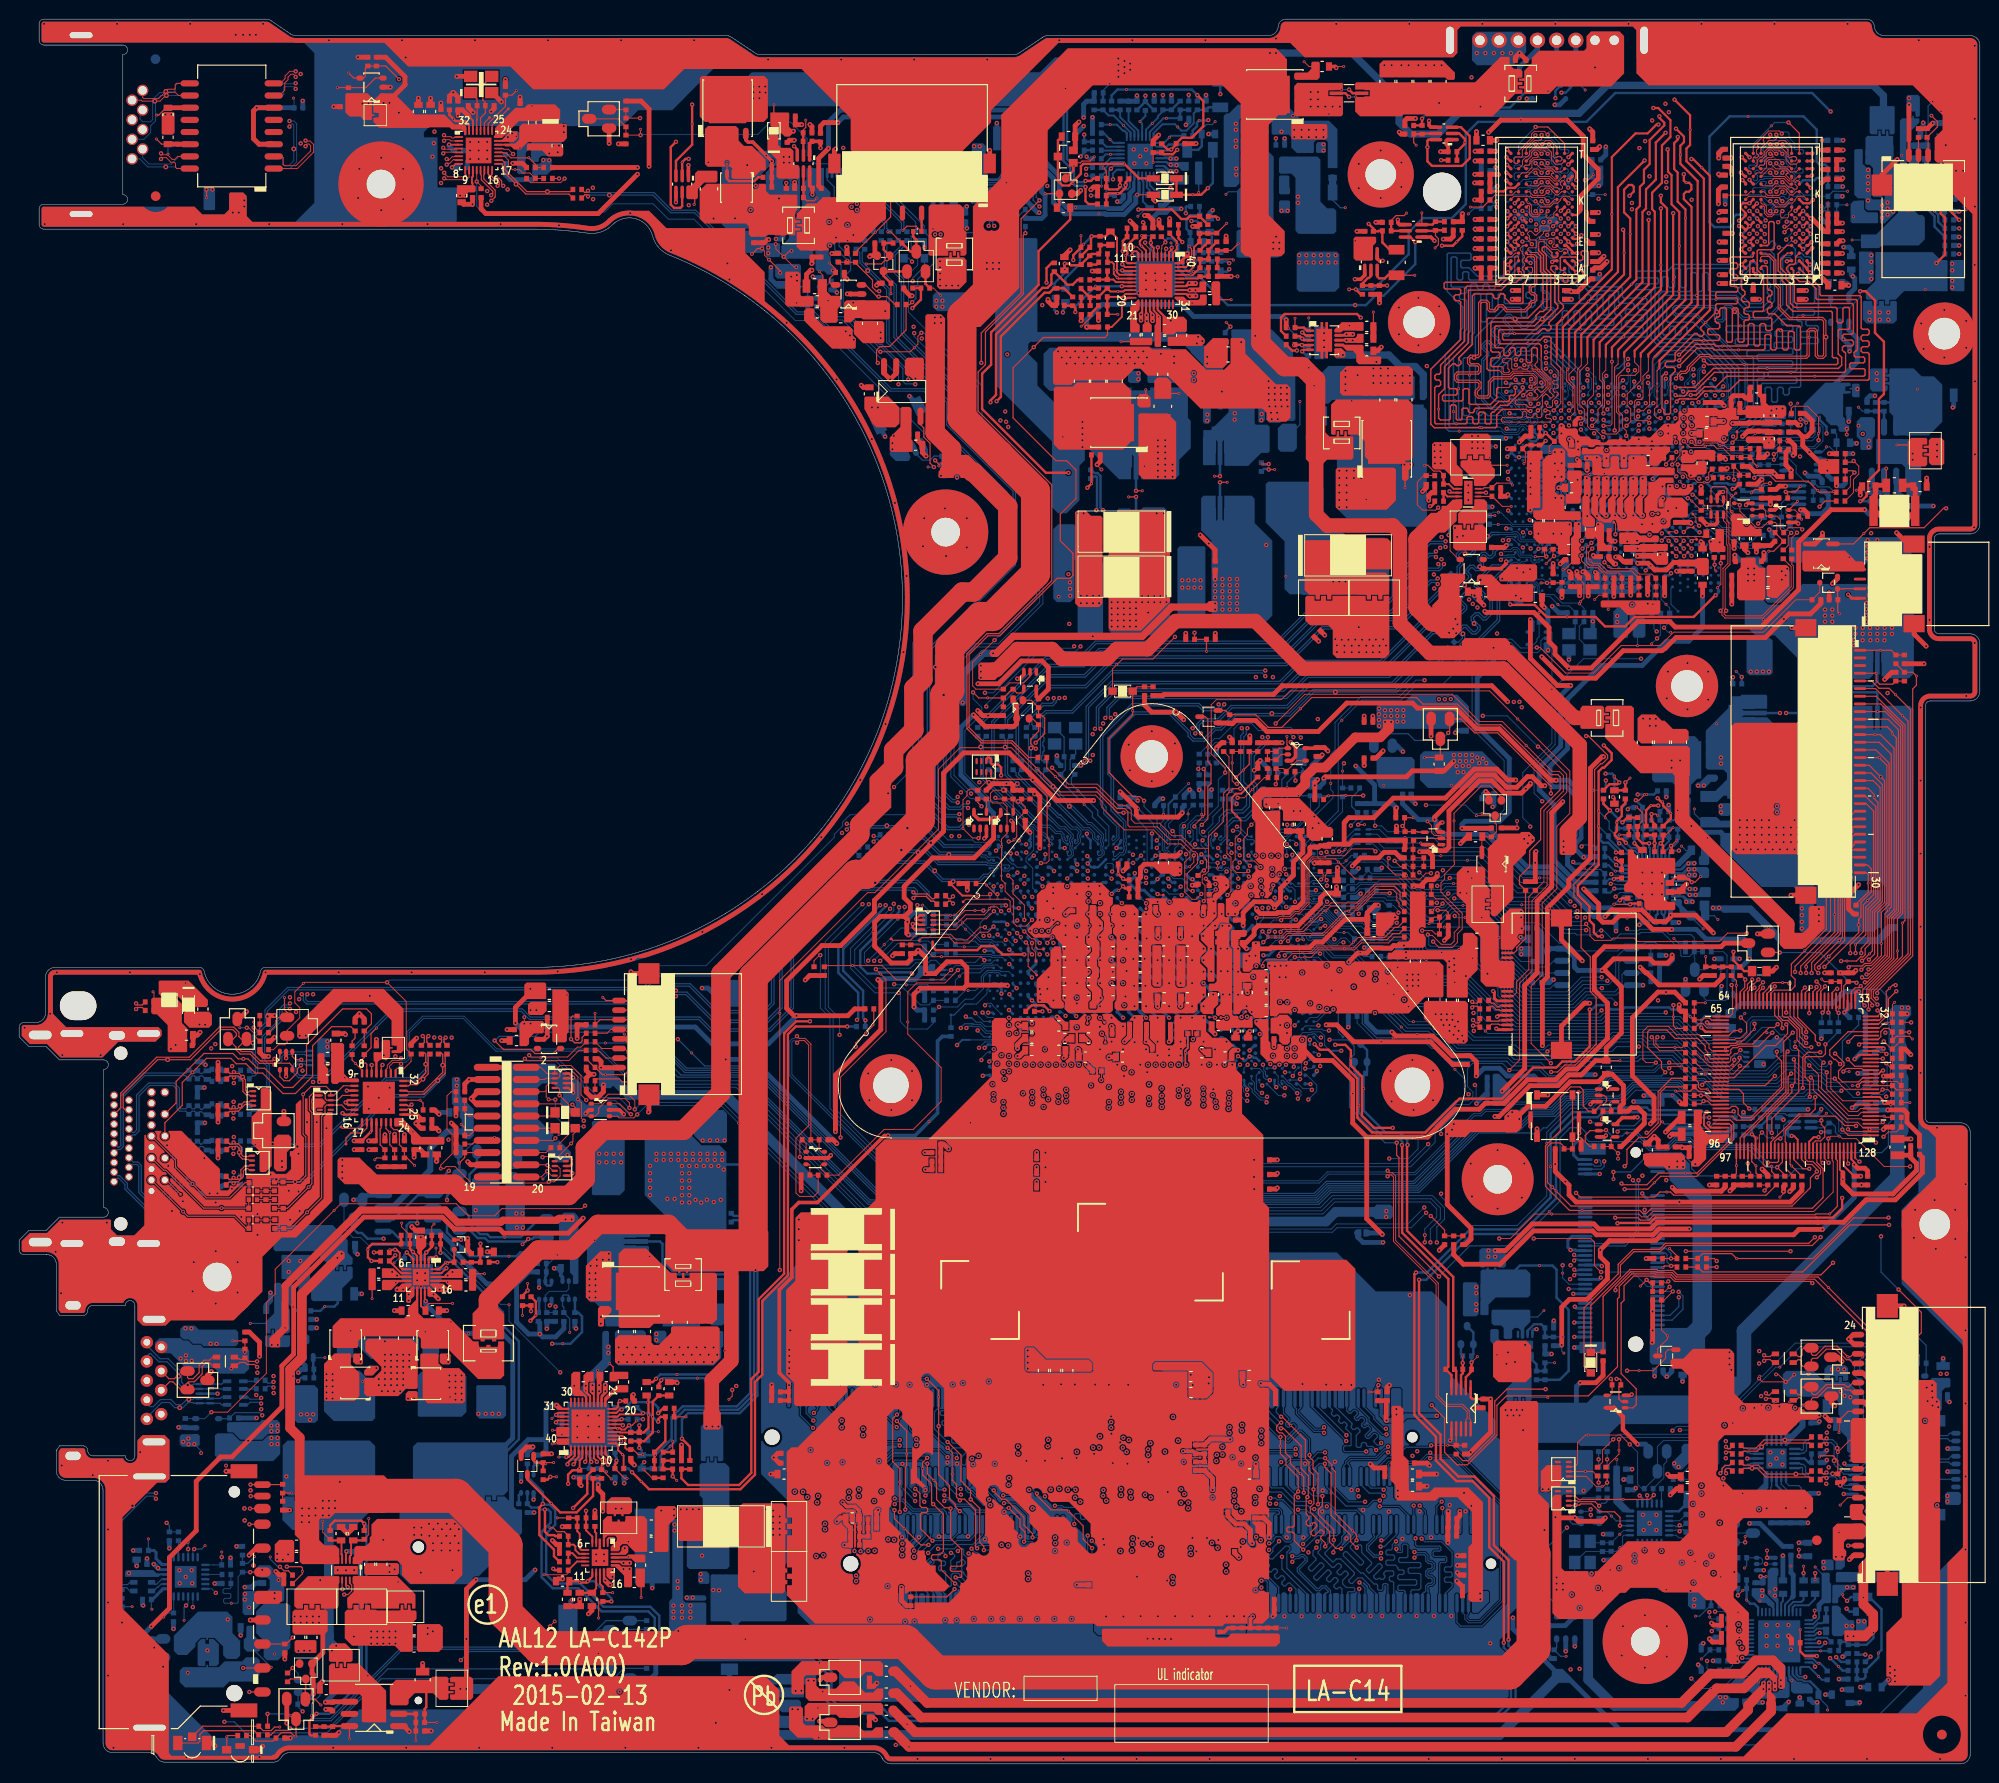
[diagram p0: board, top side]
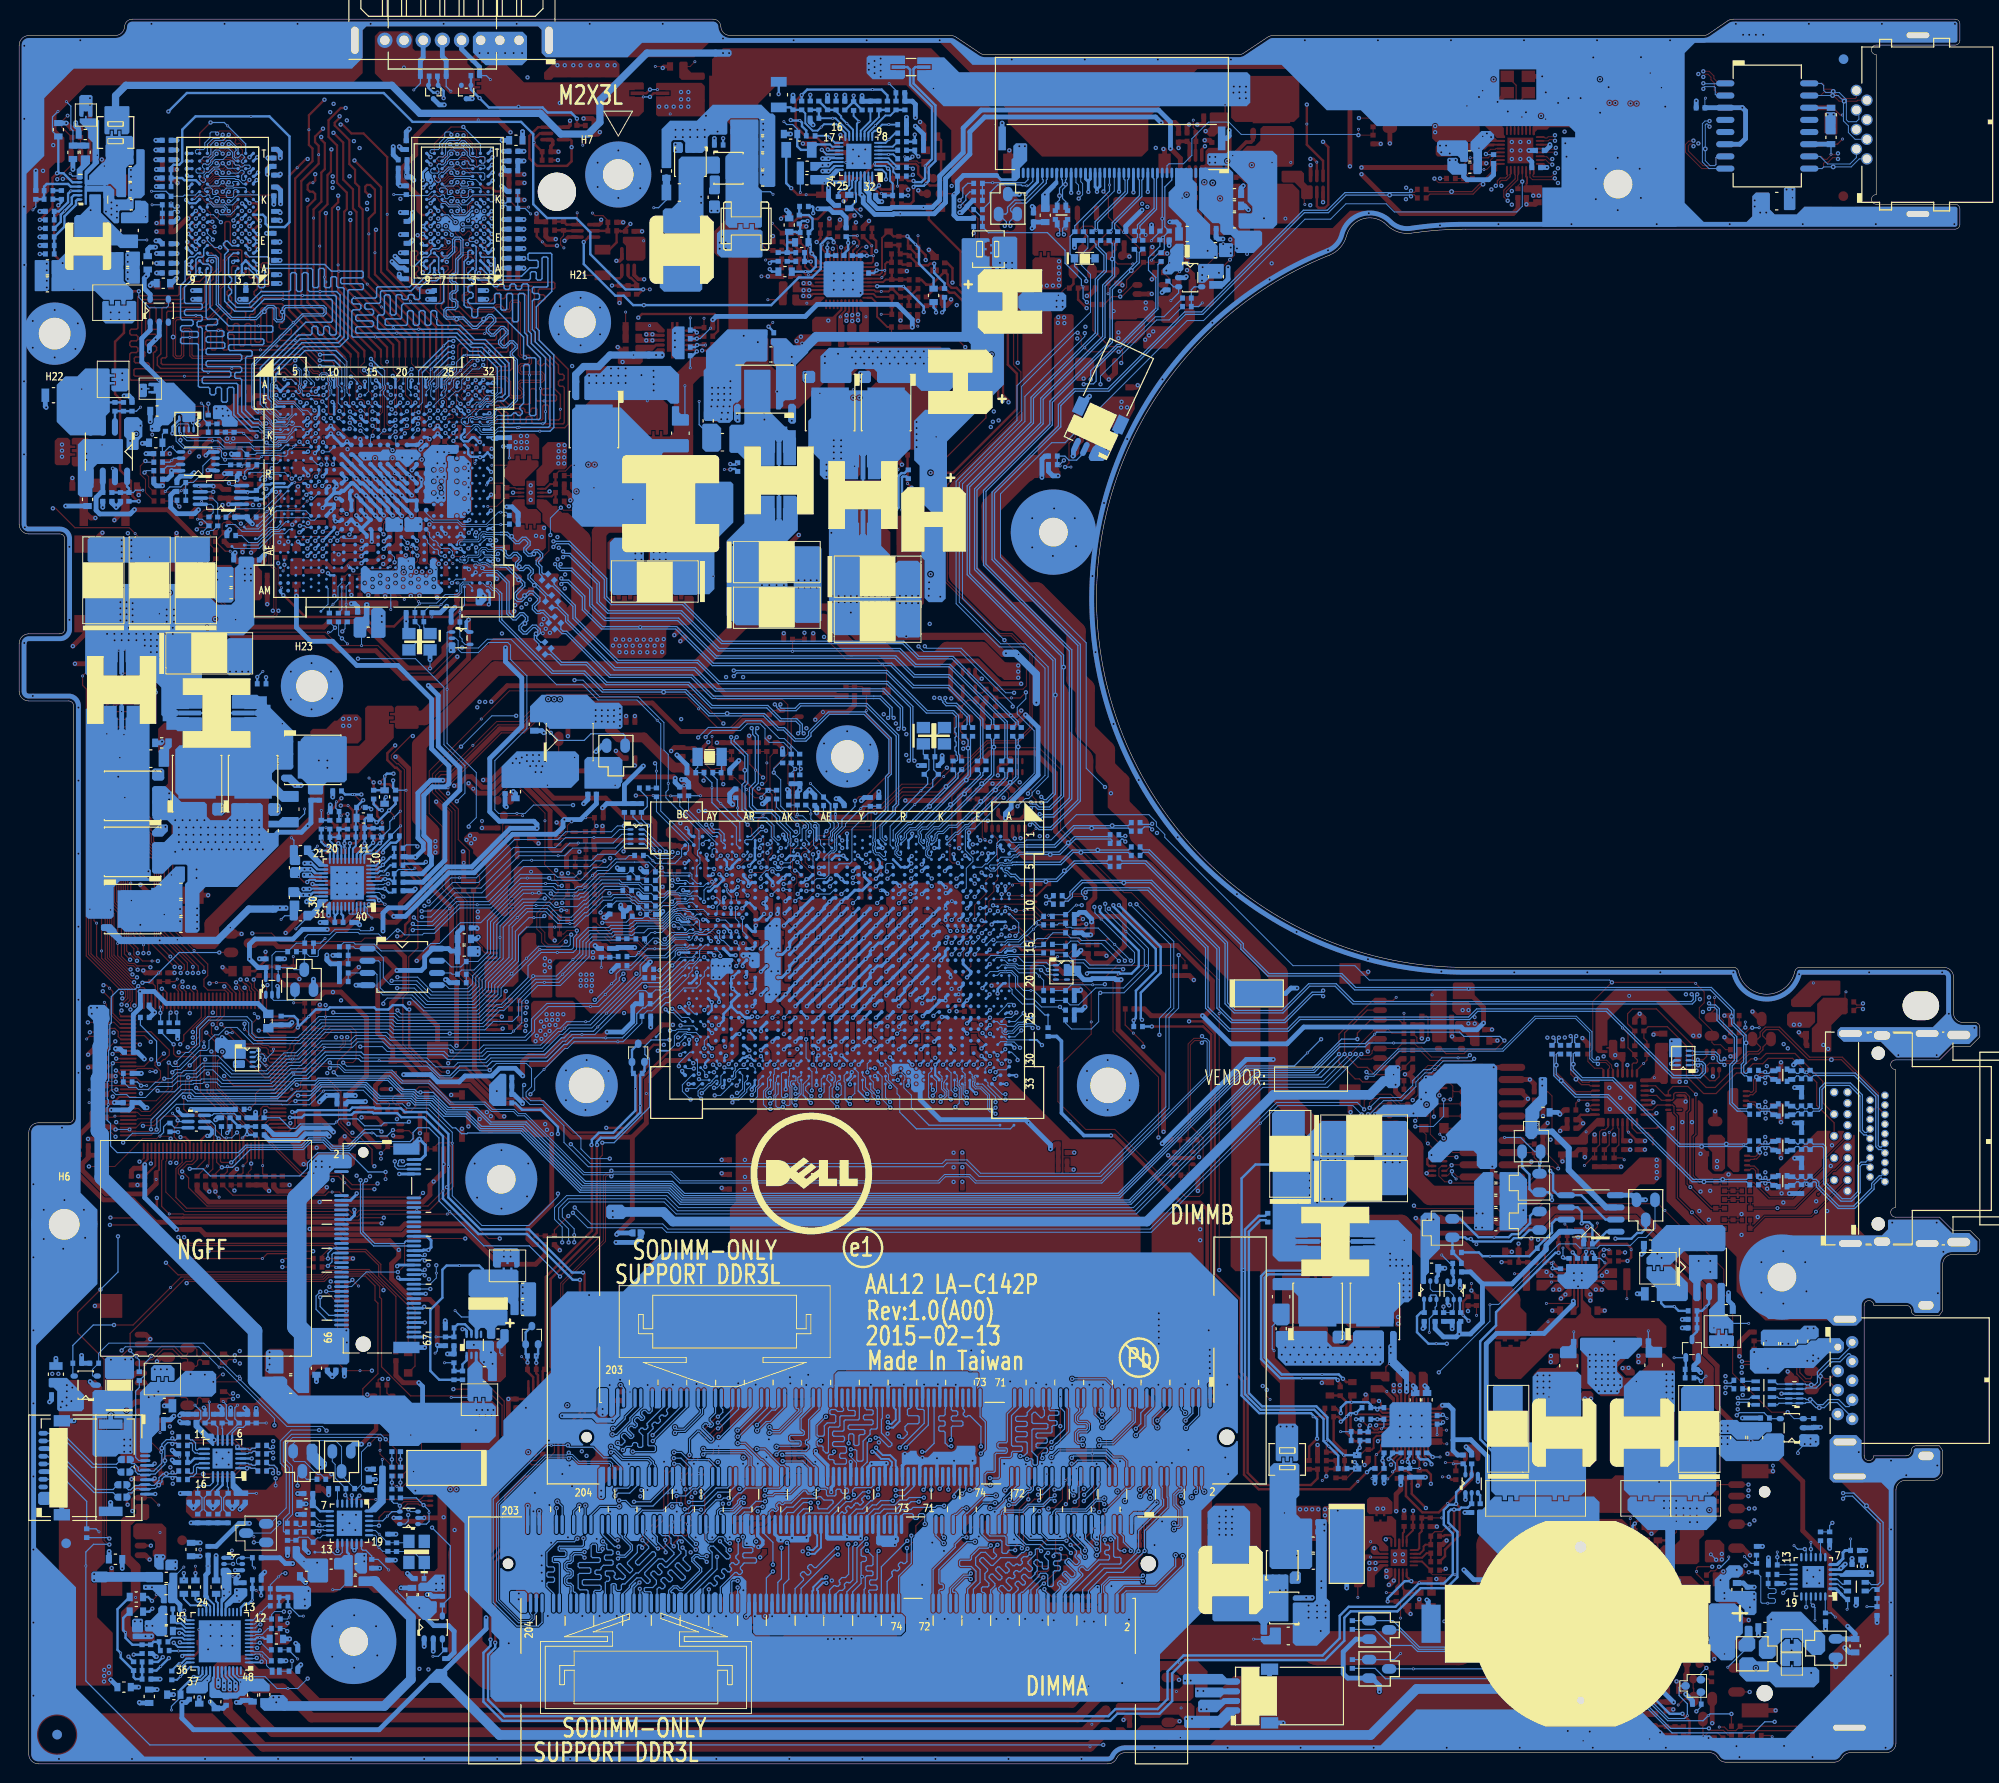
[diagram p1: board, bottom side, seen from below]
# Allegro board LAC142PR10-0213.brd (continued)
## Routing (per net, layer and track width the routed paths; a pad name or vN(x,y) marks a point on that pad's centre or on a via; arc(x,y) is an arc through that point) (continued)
DDRA_CLK1#: length 76.5
  IN2 w0.102: 120.41,68.19 120.53,68.3 120.53,68.64 120.39,68.78 120.39,70.81 120.46,70.88 120.46,72.62 v2(120.16,72.92)
  IN2 w0.216: v2(120.34,19.45) 120.42,19.37 120.94,19.37 121.14,19.56 121.14,20.78 120.1,21.82 120.1,24.12 118.69,25.53 118.69,27.98 116.85,29.82 116.85,38.47 116.67,38.65 115.05,38.65 114.66,39.03 114.66,40.54 115.05,40.93 116.72,40.93 116.93,41.14 116.93,41.64 116.72,41.85 115.01,41.85 114.53,42.33 114.53,43.19 115.01,43.67 116.72,43.67 116.93,43.89 116.93,44.38 116.72,44.6 115.01,44.6 114.53,45.07 114.53,45.94 115.01,46.41 116.72,46.41 116.93,46.63 116.93,47.12 116.72,47.34 115.01,47.34 114.53,47.82 114.53,60.66 120.41,66.54 120.41,68.19
  BOTTOM w0.102: v2(120.16,72.92) 120.56,72.52 UC1.AE31
  BOTTOM w0.196: v2(120.34,19.45) 120.49,19.31 120.83,19.31 121.7,18.43 121.7,18.11 121.8,18.01 JDIMM1.104
DDRA_ODT0: length 72.8
  IN1 w0.216: v2(125.76,72.92) 125.76,72.09 127.26,70.59 127.26,69.39 128.16,68.49 128.18,68.49 129.3,67.37 129.3,59.18 129.61,58.87 129.61,46.5 129.48,46.38 128.34,46.38 128.15,46.19 128.15,45.94 128.34,45.75 129.48,45.75 129.61,45.63 129.61,45.33 129.43,45.15 128.31,45.15 128.12,44.97 128.12,44.71 128.31,44.53 129.43,44.53 129.61,44.34 129.61,44.09 129.43,43.9 128.31,43.9 128.12,43.72 128.12,43.46 128.31,43.28 129.43,43.28 129.61,43.1 129.61,42.84 129.43,42.66 128.31,42.66 128.12,42.48 128.12,42.22 128.31,42.04 129.43,42.04 129.61,41.85 129.61,41.6 129.43,41.41 128.5,41.41 128.3,41.21 128.3,38.01 125.85,35.56 125.85,35.24 124.06,33.45 124.06,26 124.3,25.76 125.04,25.76 125.6,25.2 125.6,23.11 v2(125.02,22.54)
  BOTTOM w0.102: v2(125.76,72.92) 125.37,73.32 UC1.AL30
  BOTTOM w0.127: JDIMM1.116 125.4,18.93 125.02,19.3 v2(125.02,22.54)
DDRA_ODT1: length 69.8
  IN1 w0.216: v2(126.18,68.31) 126.78,68.31 127.35,67.75 127.35,58.92 128.05,58.22 128.05,50.84 127.92,50.71 126.65,50.71 126.52,50.58 126.52,40.75 126.22,40.45 126.22,38.14 125.07,36.99 124.29,36.21 124.29,35.89 122.5,34.1 122.5,25.44 120.86,23.8 120.86,22.67 120.68,22.49 120.08,22.49 119.96,22.36 119.96,21.99 120.08,21.87 120.68,21.87 120.86,21.68 120.86,21.39 120.68,21.2 119.75,21.2 119.63,21.08 119.63,20.71 119.75,20.58 120.68,20.58 120.86,20.4 120.86,20.19 120.99,20.07 v2(125.91,20.07)
  BOTTOM w0.102: v2(126.18,68.31) 126.45,68.31 126.9,68.77 126.9,70.17 126.47,70.6 126.47,71.49 126.17,71.79 UC1.AM32
  BOTTOM w0.127: v2(125.91,20.07) 126.6,19.38 JDIMM1.120
DDRA_SCS0#: length 73.1
  IN1 w0.216: v2(123.55,70.44) 124.01,70.89 126.51,70.89 126.94,70.46 126.94,69.2 127.97,68.17 128.05,68.17 128.39,67.83 128.39,59.35 129.09,58.65 129.09,49.66 128.91,49.48 127.77,49.48 127.59,49.3 127.59,49.04 127.77,48.86 128.96,48.86 129.09,48.73 129.09,48.36 128.96,48.23 127.77,48.23 127.59,48.05 127.59,47.7 127.77,47.52 128.96,47.52 129.09,47.39 129.09,47.02 128.96,46.9 127.77,46.9 127.59,46.71 127.59,40.35 127.26,40.02 127.26,37.71 126.42,36.86 125.33,35.78 125.33,35.46 123.54,33.67 123.54,25.33 123.67,25.2 124.51,25.2 124.98,24.73 124.98,23.91 124.83,23.76 124.49,23.76 124.33,23.91 124.33,24.47 124.21,24.58 123.11,24.58 122.92,24.38 122.92,24.07 123.1,23.89 123.24,23.89 123.42,23.71 123.42,23.27 123.64,23.05 v2(124.45,23.05)
  BOTTOM w0.102: UC1.AJ33 123.55,70.7 v2(123.55,70.44)
  BOTTOM w0.127: v2(124.45,23.05) 124.26,22.86 124.26,19.24 124.8,18.7 JDIMM1.114
DDRA_SCS1#: length 70.8
  IN1 w0.216: v2(126.19,68.87) 126.71,68.87 127.87,67.72 127.87,59.13 128.57,58.44 128.57,50.3 128.39,50.12 127.25,50.12 127.07,49.94 127.07,40.56 126.74,40.23 126.74,37.92 125.52,36.7 125.52,36.7 124.81,35.99 124.81,35.68 123.02,33.88 123.02,25.22 121.99,24.19 121.99,23.88 121.89,23.77 121.57,23.77 121.38,23.58 121.38,23.27 121.56,23.09 121.6,23.09 121.79,22.9 121.79,22.65 121.6,22.46 121.56,22.46 121.38,22.28 121.38,20.74 121.53,20.59 121.95,20.59 122.13,20.77 122.13,21.28 122.32,21.46 122.57,21.46 122.76,21.28 122.76,20.77 122.94,20.59 123.2,20.59 123.38,20.77 123.38,21.41 123.51,21.54 123.87,21.54 124,21.41 124,20.77 124.18,20.59 124.44,20.59 124.62,20.77 124.62,21.54 124.75,21.67 125.12,21.67 125.25,21.54 125.25,20.71 125.37,20.59 125.79,20.59 125.91,20.71 v2(125.91,20.76)
  BOTTOM w0.102: UC1.AL32 125.55,71.54 125.55,71.17 125.67,71.05 125.67,69.85 125.81,69.71 125.81,69.25 v2(126.19,68.87)
  BOTTOM w0.127: v2(125.91,20.76) 125.91,23.1 126.9,24.09 JDIMM1.121
DDRAB_CKE0: length 75
  IN1 w0.102: v2(113.68,70.6) 112.83,69.75 112.39,69.75 110.57,67.93
  IN1 w0.127: v2(110.08,25.02) 109.25,25.85 109.25,25.85 108.61,26.49 107.25,26.49 105.77,27.97 105.77,28.74 104.23,30.28 v2(104.23,32.36)
  IN1 w0.216: v2(104.23,32.36) 103.69,32.36 103.55,32.22 103.55,31.38 103.38,31.22 103.05,31.22 102.91,31.36 102.91,31.95 102.17,32.7 102.17,49.44 102.39,49.65 103.1,49.65 103.23,49.78 103.23,50.15 103.1,50.27 102.39,50.27 102.2,50.45 102.2,50.71 102.39,50.89 103.38,50.89 103.56,51.08 103.56,51.33 103.38,51.52 102.39,51.52 102.2,51.7 102.2,52.07 102.34,52.2 103.37,52.2 103.59,52.43 103.59,53.61 107.61,57.63 107.61,64.97 110.57,67.93
  BOTTOM w0.102: UC1.U32 114.17,71.35 113.69,70.87 113.69,70.6 v2(113.68,70.6)
  BOTTOM w0.127: v2(104.23,32.36) 103.75,32.84 103.75,35.65 104.3,36.2 JDIMM2.73 ; v2(110.08,25.02) 110.08,25.96 110.22,26.1 110.61,26.1 110.74,25.97 110.74,25.62 110.87,25.49 111.14,25.49 111.27,25.62 111.27,25.97 111.4,26.1 112.26,26.1 112.5,25.86 JDIMM1.73
DDRAB_CKE1: length 81.4
  IN1 w0.102: v2(113.7,69.03) 113.68,69.02 113.52,69.02 113.28,68.78 112.45,67.95
  IN1 w0.216: v2(111.47,23.8) 111.25,23.8 110.89,24.16 110.89,24.41 111.08,24.6 111.08,25.43 108.08,28.44 108.08,28.91 108.2,29.03 108.2,29.16 107.84,29.51 107.68,29.51 107.45,29.29 107.27,29.29 106.97,29.58 106.97,29.76 107.19,29.98 107.19,30.16 106.89,30.47 106.71,30.47 106.51,30.26 106.27,30.26 106.04,30.49 106.04,30.71 106.24,30.91 106.24,31.03 106.04,31.23 106.04,32.62 105.78,32.88 105.78,33.73 105.31,34.2 103.88,34.2 103.74,34.34 103.74,45.3 103.95,45.51 104.97,45.51 105.16,45.69 105.16,52.96 109.85,57.66 109.85,58.67 109.98,58.8 110.95,58.8 111.07,58.93 111.07,59.36 110.95,59.49 109.98,59.49 109.85,59.62 109.85,59.99 109.98,60.11 110.95,60.11 111.07,60.24 111.07,60.61 110.95,60.73 109.98,60.73 109.85,60.86 109.85,61.23 109.98,61.36 110.89,61.36 111.07,61.54 111.07,66.22 112.45,67.6 112.45,67.95
  IN2 w0.127: v2(105.37,28.57) 107,28.57 107.44,28.14 107.84,28.14 108.16,27.83 108.32,27.83 110.06,26.09 110.44,26.09 111.47,25.06 v2(111.47,23.8)
  BOTTOM w0.102: v2(113.7,69.03) 114.17,69.5 UC1.U33
  BOTTOM w0.127: v2(105.37,28.57) 105.02,28.57 104.6,29 JDIMM2.74 ; v2(111.47,23.8) 111.47,20.89 112.8,19.57 JDIMM1.74
DDRAB_SBS0#: length 81.2
  IN1 w0.127: v2(121.96,26.65) 121.96,25.58 121.59,25.2 121.15,25.2 121.02,25.07 121.02,24.85 120.38,24.2 120.38,23.15 120.25,23.03 119.88,23.03 119.75,23.15 119.75,24.47 119.01,25.21 119.01,28.75 118.63,29.12 118.63,29.46 118.42,29.68 118.42,30.52 118.22,30.71 118.22,32.36 v2(117.79,32.8)
  IN1 w0.216: v2(117.79,32.8) 117.49,33.1 117.49,34 117.6,34.11 118.03,34.11 118.15,34.24 118.15,34.57 118.03,34.7 117.82,34.7 117.7,34.82 117.7,35.17 117.82,35.29 118.78,35.29 118.91,35.42 118.91,35.75 118.78,35.88 118.15,35.88 118.02,36.01 118.02,36.38 118.15,36.5 119.01,36.5 119.2,36.69 119.2,36.94 119.01,37.13 118.35,37.13 118.17,37.31 118.17,37.57 118.35,37.75 119.08,37.75 119.21,37.87 119.21,38.24 119.08,38.37 118.35,38.37 118.17,38.55 118.17,38.83 118.35,39.01 119.08,39.01 119.21,39.14 119.21,39.51 119.08,39.64 118.35,39.64 118.17,39.82 118.17,40.12 118.31,40.26 119.19,40.26 119.32,40.39 119.32,40.76 119.19,40.89 118.95,40.89 118.76,41.07 118.76,41.5 118.92,41.66 119.34,41.66 119.72,41.27 119.93,41.27 120.14,41.48 120.14,42.27 123.39,45.52 123.39,67.4 123.63,67.64 123.63,68.14 124.01,68.52 124.01,69.87 123.88,70 123.67,70 v2(123.55,69.88)
  BOTTOM w0.102: UC1.AH32 122.97,71.78 123.09,71.65 123.22,71.65 123.32,71.56 123.32,71.09 123.17,70.95 123.17,69.96 123.26,69.88 v2(123.55,69.88)
  BOTTOM w0.127: v2(121.96,26.65) 122.02,26.59 122.73,26.59 123.3,26.02 JDIMM1.109 ; v2(117.79,32.8) 117.75,32.77 117.29,32.77 117.16,32.64 117.16,31.7 117.04,31.57 116.63,31.57 116.5,31.7 116.5,33.66 115.78,34.38 115.78,34.39 115.78,34.79 115.65,34.92 115.15,34.92 115.02,35.05 115.02,37.08 115.1,37.15 JDIMM2.109
DDRAB_SBS1#: length 80
  IN1 w0.216: v2(119.13,21.83) 118.79,21.49 117.39,21.49 117.27,21.36 117.27,20.13 117.14,20 116.76,20 116.63,20.13 116.63,22.09 116.76,22.21 118.15,22.21 118.65,22.71 118.65,23.85 117.56,24.94 117.56,25.24 116.99,25.81 116.99,29.92 116.07,30.84 116.07,31.53 115.79,31.81 115.6,31.81 114.56,32.86 114.56,33.17 114.34,33.39 114.34,34.15 114.5,34.3 114.5,36.28 113.42,37.36 113.42,37.89 114.69,39.16 114.69,46.23 119.81,51.35 119.81,55.66 120.77,56.62 120.77,68.38 121.89,69.5 v2(121.89,69.64)
  IN2 w0.127: v2(119.13,21.83) 118.59,22.38 118.59,23.82 115.39,27.02 115.39,28.7 115.26,28.83 115.08,28.83 114.95,28.7 v2(114.95,28.65)
  BOTTOM w0.102: UC1.AG33 122.5,70.58 122.5,70.25 v2(121.89,69.64)
  BOTTOM w0.127: v2(114.95,28.65) 114.8,28.8 JDIMM2.108 ; v2(119.13,21.83) 119.44,21.83 122.98,18.29 122.98,17.55 123,17.53 JDIMM1.108
DDRAB_SBS2#: length 78.7
  IN1 w0.102: 111.07,67.7 112.86,69.48 113.11,69.48 114.55,70.93 114.55,71.81 v2(115.28,72.54)
  IN1 w0.127: v2(108.05,26.92) 107.42,26.92 106.61,27.74 106.61,28.51 104.67,30.46 104.67,31.92 104.82,32.07 104.82,32.49 v2(104.21,33.1)
  IN1 w0.216: v2(104.21,33.1) 104.05,32.94 102.95,32.94 102.69,33.2 102.69,47.04 102.91,47.26 103.98,47.26 104.11,47.38 104.11,48.06 103.98,48.18 102.91,48.18 102.69,48.4 102.69,49 102.82,49.13 103.99,49.13 104.11,49.26 104.11,53.39 108.13,57.41 108.13,57.91 108.38,58.15 108.67,58.15 108.79,58.28 108.79,58.96 108.67,59.09 108.26,59.09 108.13,59.21 108.13,59.89 108.26,60.01 108.69,60.01 108.81,60.14 108.81,60.81 108.69,60.94 108.26,60.94 108.13,61.07 108.13,61.74 108.26,61.87 109,61.87 109.13,61.99 109.13,62.67 109,62.8 108.26,62.8 108.13,62.93 108.13,63.62 108.26,63.75 109.8,63.75 110.01,63.97 110.01,64.46 109.8,64.68 109.02,64.68 108.9,64.81 108.9,65.52 109.02,65.65 109.91,65.65 110.03,65.77 110.03,66.66 111.07,67.7
  BOTTOM w0.102: UC1.W31 115.31,72.52 v2(115.28,72.54)
  BOTTOM w0.127: JDIMM1.79 114.3,25.83 113.99,26.14 112.83,26.14 112.44,26.53 111.5,26.53 111.28,26.75 109,26.75 108.82,26.92 v2(108.05,26.92) ; JDIMM2.79 106.1,37.06 105.93,36.88 105.93,36.7 106.05,36.58 106.05,36.4 105.85,36.2 105.67,36.2 105.55,36.33 105.37,36.33 104.21,35.17 v2(104.21,33.1)
DDRAB_SCAS#: length 86.4
  IN1 w0.102: 125.19,68.08 125.28,68.17 125.28,69.2 124.75,69.73 v2(124.52,69.73)
  IN1 w0.127: v2(119.54,32.56) 119.2,32.56 119.09,32.45 119.09,31.07 119.25,30.91 120.31,30.91 120.47,30.75 120.47,30.47 120.34,30.34 119.63,30.34 119.5,30.21 119.5,29.51 119.63,29.39 119.86,29.39 119.98,29.51 119.98,29.69 120.11,29.82 120.34,29.82 120.47,29.69 120.47,29.19 120.31,29.03 120.31,28.1 120.19,27.97 120,27.97 119.87,27.84 119.87,26.82 120,26.7 120.34,26.7 120.47,26.82 120.47,27.5 120.59,27.62 120.78,27.62 121.18,27.23 v2(121.2,27.23)
  IN1 w0.216: 125.19,68.08 125.19,66.99 124.95,66.76 124.95,44.87 124.61,44.53 124.61,44.22 124.95,43.87 124.95,43.26 124.55,42.86 124.55,42.41 124.95,42.01 124.95,41.39 124.66,41.1 124.66,39.57 124.5,39.42 124.5,39.16 124.64,39.02 124.64,38.77 124.45,38.58 124.2,38.58 124.01,38.76 123.83,38.76 123.57,38.5 123.57,38.32 123.76,38.14 123.76,37.88 123.57,37.7 123.32,37.7 123.17,37.85 122.99,37.85 122.73,37.59 122.73,37.41 122.88,37.26 122.88,37 121.81,35.94 121.55,35.94 121.42,36.08 121.16,36.08 121,35.92 121,34.81 120.26,34.07 120.26,33.27 120,33.01 120,32.74 119.82,32.56 v2(119.54,32.56)
  BOTTOM w0.102: UC1.AK32 124.9,72.12 125.02,71.99 125.02,69.62 124.9,69.49 124.64,69.49 124.52,69.62 v2(124.52,69.73)
  BOTTOM w0.127: v2(121.2,27.23) 121.23,27.2 121.23,26.7 121.13,26.59 120.25,26.59 119.63,27.22 119.63,27.39 119.74,27.51 120.58,27.51 120.94,27.86 121.19,27.86 121.37,27.69 122.9,27.69 123.82,26.77 124.49,26.77 125.1,26.16 JDIMM1.115 ; JDIMM2.115 116.9,35.99 117.02,35.87 118.37,35.87 118.5,35.74 118.5,34.82 118.62,34.7 119.56,34.7 119.69,34.57 119.69,34.29 119.56,34.16 118.57,34.16 118.45,34.04 118.45,33.73 118.57,33.6 119.56,33.6 119.69,33.48 119.69,33.23 119.56,33.1 118.37,33.1 118.24,32.98 118.24,32.52 118.37,32.4 118.83,32.4 118.95,32.27 118.95,31.99 118.83,31.86 118.37,31.86 118.24,31.74 118.24,31.38 118.36,31.27 119.41,31.27 119.54,31.39 119.54,31.6 119.67,31.73 120,31.73 120.12,31.85 120.12,32.13 120,32.26 119.67,32.26 119.54,32.39 v2(119.54,32.56)
DDRAB_SDM0: length 96.6
  IN1 w0.216: v2(103.27,77.82) 103.27,77.8 102.63,77.16 99.85,77.16 99.64,77.37 98.04,77.37 96.34,75.67 96.34,67.34 93.92,64.92 93.92,59.41 85.15,50.64 85.15,43.92 84.96,43.74 83.37,43.74 83.24,43.61 83.24,43.24 83.37,43.11 84.18,43.11 84.31,42.99 84.31,42.62 84.18,42.49 83.53,42.49 83.35,42.31 83.35,32.14 83.08,31.88 83.08,30.72 83.35,30.45 83.35,27.93 v2(83.34,27.94)
  IN2 w0.127: v2(82.91,36.6) 83.86,35.65 83.86,33.88 83.99,33.75 84.04,33.75 84.17,33.63 84.17,33.35 84.04,33.22 83.99,33.22 83.86,33.09 83.86,32.81 83.99,32.69 84.04,32.69 84.17,32.56 84.17,32.28 84.04,32.15 83.99,32.15 83.34,31.51 83.34,31.06 83.47,30.93 84.26,30.93 84.38,30.8 84.38,30.52 84.26,30.4 83.47,30.4 83.34,30.27 83.34,29.99 83.47,29.86 84.26,29.86 84.38,29.74 84.38,29.46 84.26,29.33 83.47,29.33 83.34,29.2 83.34,28.92 83.47,28.8 84.26,28.8 84.38,28.67 84.38,28.39 84.26,28.26 83.47,28.26 83.34,28.14 v2(83.34,27.94) 84.97,26.31 86.16,26.31 89.16,23.31 89.16,22.95 90.35,21.76 v2(92.13,21.76)
  BOTTOM w0.102: UC1.D25 103.67,77.42 v2(103.27,77.82)
  BOTTOM w0.127: JDIMM2.11 83.3,36.99 v2(82.91,36.6) ; JDIMM1.11 91.5,24.03 91.73,23.8 91.73,22.15 92.12,21.76 v2(92.13,21.76)
DDRAB_SDM1: length 80.8
  TOP w0.127: v2(94.86,22.83) 94.06,22.83 93.44,23.45 v1(92.32,24.57) 91.32,25.57 v2(91.32,26.45)
  IN1 w0.102: v2(103.27,73.82) 103.27,73.62 102.16,72.52 102.16,71.53 103.22,70.47 103.22,67.95
  IN1 w0.216: v2(94.86,22.83) 94.86,23 94.35,23.52 94.35,23.79 92.96,25.17 92.96,28.89 93.15,29.09 93.15,35.73 95.83,38.41 95.83,51.59 102.87,58.63 102.87,66.34 103.22,66.7 103.22,67.95
  BOTTOM w0.102: UC1.D29 103.66,74.22 v2(103.27,73.82)
  BOTTOM w0.127: JDIMM2.28 88.4,29.02 88.68,28.74 89.07,28.74 89.8,28.02 89.8,27.91 91.26,26.45 v2(91.32,26.45) ; JDIMM1.28 96.6,17.68 95.99,18.29 95.99,18.47 96.22,18.69 96.22,18.87 96.02,19.07 95.84,19.07 95.53,18.76 95.35,18.76 95.15,18.96 95.15,19.14 95.71,19.69 95.71,19.87 95.51,20.07 95.33,20.07 94.78,19.52 94.58,19.52 94.42,19.69 94.42,19.94 95.44,20.96 95.44,21.14 95.16,21.42 94.98,21.42 94.35,20.79 94.17,20.79 93.98,20.99 93.98,21.17 94.39,21.58 94.39,21.76 94.24,21.91 94.24,22.21 v2(94.86,22.83)
DDRAB_SDM2: length 82
  IN1 w0.127: v2(94.42,27.33) 94.42,26.73 97.55,23.6 97.55,22.58 v2(97.94,22.2)
  IN2 w0.216: v2(97.94,22.2) 97.94,22.69 97.51,23.12 97.51,24.31 94.9,26.92 94.9,27.55 95.22,27.87 95.22,28.92 93.47,30.67 93.47,31.56 92.46,32.57 92.46,33.92 93.11,34.57 93.11,36.35 92.72,36.74 92.72,38.98 92.43,39.26 92.43,39.96 92.21,40.18 92.21,55.17 98.53,61.49 98.53,61.75 98.13,62.15 98.13,62.41 98.31,62.59 98.57,62.59 98.97,62.19 99.23,62.19 99.41,62.37 99.41,62.63 99.01,63.03 99.01,63.29 99.19,63.47 99.45,63.47 99.85,63.07 99.85,63.07 100.07,63.28 100.07,66.95 102.13,69.02 v2(102.69,69.02)
  BOTTOM w0.102: UC1.E33 104.55,70.91 104.05,70.91 102.69,69.55 v2(102.69,69.02)
  BOTTOM w0.127: v2(94.42,27.33) 93.97,27.78 93.97,28.93 93.8,29.1 JDIMM2.46 ; JDIMM1.46 102,17.82 102.36,18.18 102.36,18.36 102.12,18.6 101.94,18.6 101.39,18.05 101.21,18.05 101,18.26 101,18.4 101.57,18.96 101.57,19.18 101.33,19.42 101.15,19.42 101.05,19.32 100.83,19.32 100.67,19.48 100.67,19.66 100.79,19.78 100.79,19.96 100.59,20.15 100.41,20.15 100.29,20.04 100.11,20.04 99.76,20.39 99.76,20.42 99.58,20.42 99.22,20.06 99.04,20.06 98.84,20.26 98.84,20.44 99.29,20.89 99.29,21.08 98.54,21.84 98.54,22.33 98.43,22.44 98.18,22.44 v2(97.94,22.2)
DDRAB_SDM3: length 77.5
  IN1 w0.127: v2(100.09,32.11) 100.4,31.8 100.4,31.18 102.98,28.6 103.77,28.6 v2(105.72,26.64)
  IN2 w0.102: 107.51,67.95 107.51,69.14 v2(107.35,69.3)
  IN2 w0.216: 107.51,67.95 107.51,66.06 105.63,64.18 105.63,56.15 104.48,55 104.48,52.22 100.98,48.72 100.98,48.32 100.86,48.21 100.42,48.21 100.3,48.33 100.3,48.68 100.17,48.81 99.73,48.81 99.61,48.68 99.61,47.71 99.73,47.58 100.79,47.58 100.97,47.4 100.97,47.14 100.79,46.96 99.79,46.96 99.61,46.78 99.61,46.52 99.79,46.34 100.79,46.34 100.97,46.16 100.97,45.9 100.79,45.72 99.79,45.72 99.61,45.53 99.61,45.28 99.79,45.09 100.79,45.09 100.97,44.91 100.97,44.65 100.79,44.47 99.79,44.47 99.61,44.29 99.61,44.03 99.79,43.85 100.79,43.85 100.97,43.67 100.97,43.41 100.79,43.23 99.79,43.23 99.61,43.04 99.61,40.91 99.94,40.58 99.94,32.26 v2(100.09,32.11)
  BOTTOM w0.102: UC1.J33 107.77,70.41 107.57,70.21 107.57,69.52 v2(107.35,69.3)
  BOTTOM w0.127: v2(105.72,26.64) 106.14,26.64 106.76,26.02 106.93,26.02 107.1,25.85 JDIMM1.63 ; v2(100.09,32.11) 99.73,32.11 99.38,32.45 99.38,33.46 99.51,33.58 100.46,33.58 100.59,33.71 100.59,33.99 100.46,34.12 99.51,34.12 99.38,34.24 99.38,34.52 99.51,34.65 100.46,34.65 100.59,34.78 100.59,35.06 100.46,35.18 99.51,35.18 99.38,35.31 99.38,35.59 99.51,35.72 100.46,35.72 100.59,35.84 100.59,36.12 100.46,36.25 99.51,36.25 99.38,36.38 99.38,36.64 98.9,37.12 JDIMM2.63
DDRAB_SDM4: length 85.3
  IN1 w0.127: v2(126.79,27.97) 126.79,27.95 128.67,26.07 128.67,24.05 v2(129.05,23.67)
  IN2 w0.102: v2(128.96,72.92) 128.96,68.02 128.77,67.82 128.77,67.57
  IN2 w0.216: 128.77,67.57 128.77,64.9 123.67,59.8 123.67,51.01 123.48,50.83 122.21,50.83 122.03,50.65 122.03,50.39 122.21,50.21 123.48,50.21 123.67,50.02 123.67,49.77 123.48,49.58 122.21,49.58 122.03,49.4 122.03,48.86 122.21,48.68 123.24,48.68 123.42,48.49 123.42,48.24 123.24,48.05 122.21,48.05 122.03,47.87 122.03,42.14 123.27,40.89 124.18,40.89 124.63,40.45 124.63,35.23 125.53,34.33 125.53,33.81 126.06,33.28 126.06,31.67 126.28,31.45 126.28,30.6 127.74,29.14 127.74,27.48 129.03,26.19 129.03,23.7 v2(129.05,23.67)
  BOTTOM w0.102: v2(128.96,72.92) 128.57,73.32 UC1.AR30
  BOTTOM w0.127: v2(129.05,23.67) 129.05,22.67 128.93,22.55 128.14,22.55 128.01,22.42 128.01,22.14 128.14,22.01 128.93,22.01 129.05,21.89 129.05,21.61 128.93,21.48 127.76,21.48 127.63,21.35 127.63,21.07 127.76,20.95 128.93,20.95 129.05,20.82 129.05,20.77 129.31,20.52 129.31,20.34 129.1,20.13 129.1,19.95 129.3,19.75 129.48,19.75 129.69,19.96 129.87,19.96 131.4,18.43 JDIMM1.136 ; v2(126.79,27.97) 126.78,27.97 125.94,27.97 125.72,28.18 124.1,28.18 123.2,29.08 JDIMM2.136
DDRAB_SDM5: length 81.5
  TOP w0.127: v2(133.97,22.34) 133.03,23.28 133.03,24.03 132.9,24.16 132.39,24.16 132.26,24.29 132.26,24.57 132.39,24.69 132.9,24.69 133.03,24.82 133.03,28 v2(133.43,28.41) 133.43,29.89 132.16,31.16 132.16,31.78 131.58,32.36 v1(131.58,33.15) v2(131.58,34.09)
  IN2 w0.102: v2(131.48,72.93) 131.48,72.15 131.9,71.74 132.05,71.74 133.39,70.4 133.94,70.4 135.23,69.1 135.23,67.6 135.2,67.57
  IN2 w0.216: 135.2,67.57 135.2,59.85 133.13,57.78 133.13,55.14 133.27,55 134.88,55 135.01,54.88 135.01,54.51 134.88,54.38 133.21,54.38 133.09,54.25 133.09,53.89 133.21,53.76 134.87,53.76 135,53.63 135,53.26 134.87,53.14 133.21,53.14 133.09,53.01 133.09,52.64 133.21,52.51 133.44,52.51 133.57,52.39 133.57,51.4 134.37,50.6 134.37,40.11 134.59,39.88 134.59,34.22 134.41,34.04 134.25,34.04 134.07,33.86 134.07,33.6 134.25,33.42 134.41,33.42 134.59,33.24 134.59,32.9 134.16,32.46 134.16,31.91 134.59,31.47 134.59,31.11 134.29,30.81 133.7,30.81 133.43,30.54 133.43,28.42 v2(133.43,28.41)
  BOTTOM w0.102: v2(131.48,72.93) 131.77,73.21 UC1.AW30
  BOTTOM w0.127: v2(133.97,22.34) 135.43,23.8 136.22,23.8 136.5,24.08 JDIMM1.153 ; v2(131.58,34.09) 131.39,34.09 128.3,37.17 JDIMM2.153
DDRAB_SDM6: length 78.5
  TOP w0.127: v2(135.97,27.94) 135.96,27.93 135.96,26.91 135.54,26.49 135.54,26.01 v1(136.33,25.21) 137.14,24.41 137.14,23.36 v2(137.15,23.34)
  IN1 w0.102: 133.42,67.57 133.42,68.4 133.65,68.63 134.38,68.63 134.94,69.2 134.94,69.46 134.21,70.19 134.21,71.08 134.55,71.42 134.55,72.75 v2(134.22,73.08)
  IN1 w0.216: 133.42,67.57 133.42,53.75 133.24,53.57 132.76,53.57 132.58,53.39 132.58,53.13 132.76,52.95 133.24,52.95 133.42,52.76 133.42,52.51 133.24,52.32 132.76,52.32 132.58,52.14 132.58,51.88 132.76,51.7 133.24,51.7 133.42,51.52 133.42,51.26 133.24,51.08 132.76,51.08 132.58,50.9 132.58,37.55 133.76,36.37 133.76,34.82 135.65,32.93 135.65,29.5 136.54,28.61 136.54,27.7 137.21,27.04 137.21,23.39 v2(137.15,23.34)
  BOTTOM w0.102: UC1.BC30 134.57,73.42 v2(134.22,73.08)
  BOTTOM w0.127: JDIMM2.170 133.4,29.09 133.81,28.68 134.25,28.68 134.98,27.94 v2(135.97,27.94) ; v2(137.15,23.34) 137.15,22.95 136.24,22.04 136.24,21.85 137.01,21.08 137.12,21.08 137.41,21.37 137.87,21.37 139.29,19.95 139.29,19.74 138.73,19.18 138.73,19 138.91,18.82 139.09,18.82 139.66,19.4 140.1,19.4 140.89,18.61 140.89,18.43 141.6,17.71 JDIMM1.170
DDRAB_SDM7: length 85.1
  IN1 w0.216: v2(136.65,76.48) 137.31,76.48 139.16,74.63 139.16,53.89 138.98,53.7 138.98,52.95 139.16,52.76 140.06,52.76 140.19,52.64 140.19,52.27 140.06,52.14 139.16,52.14 138.98,51.96 138.98,51.56 139.16,51.38 141.55,51.38 141.68,51.26 141.68,50.89 141.55,50.76 139.16,50.76 138.98,50.58 138.98,50.32 139.16,50.14 141.55,50.14 141.68,50.01 141.68,49.64 141.55,49.52 139.16,49.52 138.98,49.33 138.98,49.02 139.12,48.87 141.21,48.87 141.34,48.74 141.34,48.39 141.16,48.21 140.51,48.21 140.33,48.02 140.33,47.77 140.51,47.58 141.16,47.58 141.34,47.4 141.34,39.35 142.09,38.6 v2(142.09,33.46)
  IN2 w0.127: v2(142.09,33.46) 142.13,33.5 142.94,33.5 144.35,32.1 144.35,31.36 145.93,29.78 145.93,27.11 v2(146.11,26.94)
  BOTTOM w0.102: UC1.BC26 135.93,76.62 136.07,76.48 v2(136.65,76.48)
  BOTTOM w0.127: v2(142.09,33.46) 141.88,33.25 141.67,33.25 141.36,33.57 141.36,33.73 141.71,34.08 141.71,34.26 141.51,34.46 141.33,34.46 140.81,33.94 140.63,33.94 140.44,34.13 140.44,34.31 140.96,34.84 140.96,35.01 140.76,35.21 140.58,35.21 140.44,35.06 140.26,35.06 140.06,35.26 140.06,35.44 140.35,35.73 140.35,35.91 140.15,36.11 139.97,36.11 139.68,35.82 139.5,35.82 139.3,36.02 139.3,36.19 139.6,36.49 139.6,36.67 139.4,36.87 139.22,36.87 138.93,36.57 138.75,36.57 138.5,36.82 JDIMM2.187 ; v2(146.11,26.94) 146.7,26.34 JDIMM1.187
DDRAB_SDQ0: length 93.4
  IN1 w0.216: v2(99.75,78.3) 99.59,78.47 97.65,78.47 95.3,76.12 95.3,67.77 92.88,65.35 92.88,59.84 84.08,51.04 84.08,47.56 83.95,47.43 82.01,47.43 81.88,47.31 81.88,46.87 82.01,46.75 83.94,46.75 84.07,46.62 84.07,46.29 83.89,46.11 82.07,46.11 81.88,45.93 81.88,37.34 81.51,36.97 81.51,29.26 82.23,28.55 v2(82.23,27.81)
  IN2 w0.127: v2(82.82,35.04) 81.92,35.04 81.77,34.89 81.77,33.31 81.9,33.18 82.87,33.18 83,33.06 83,32.38 82.87,32.26 81.84,32.26 81.72,32.13 81.72,31.85 81.84,31.72 82.18,31.72 82.23,31.67 v2(82.23,27.81) 82.23,27.47 84.98,24.71 86.08,24.71 88.24,22.55 88.59,22.21 v2(88.59,22.2)
  BOTTOM w0.102: UC1.A25 100.63,77.42 v2(99.75,78.3)
  BOTTOM w0.127: JDIMM2.5 81.5,36.36 v2(82.82,35.04) ; JDIMM1.5 89.7,24.03 89.35,23.69 89.35,23.11 88.59,22.35 v2(88.59,22.2)
DDRAB_SDQ1: length 94.7
  IN1 w0.216: v2(83.25,27.27) 82.75,27.77 82.75,28.77 82.04,29.48 82.04,36.75 82.4,37.12 82.4,44.12 82.59,44.31 84.42,44.31 84.6,44.49 84.6,44.75 84.42,44.93 82.7,44.93 82.57,45.06 82.57,45.42 82.7,45.55 84.42,45.55 84.6,45.73 84.6,50.83 93.4,59.63 93.4,65.13 95.82,67.55 95.82,75.89 97.88,77.95 v2(98.77,77.95)
  IN2 w0.127: v2(82.86,35.8) 82.86,35.76 83.43,35.19 83.43,34.73 83.31,34.61 82.37,34.61 82.24,34.48 82.24,33.74 82.37,33.62 82.71,33.62 82.81,33.72 82.81,34.02 82.86,34.07 83.31,34.07 83.43,33.94 83.43,32.21 82.82,31.6 82.82,27.7 v2(83.25,27.27) 84.64,25.88 85.96,25.88 88.67,23.17 88.67,22.8 v2(89.25,22.22)
  BOTTOM w0.102: 99.39,77.79 99.84,77.35 100.35,77.35 100.78,76.92 101.44,76.92 101.63,77.11 102.2,77.11 102.51,77.42 UC1.C25
  BOTTOM w0.127: v2(89.25,22.22) 89.72,22.22 89.93,22.43 89.93,23.65 90.3,24.01 JDIMM1.7 ; v2(82.86,35.8) 82.1,36.56 JDIMM2.7
  BOTTOM w0.196: 99.39,77.79 98.92,77.79 v2(98.77,77.95)
DDRAB_SDQ2: length 91.9
  IN1 w0.216: v2(86.58,28.37) 86.86,28.65 86.86,31.34 87.51,31.99 87.51,35.34 87.96,35.79 87.96,37.48 89.92,39.45 89.92,40.28 89.76,40.45 89.33,40.45 89.2,40.58 89.2,41.11 89.33,41.24 90.82,41.24 90.94,41.37 90.94,41.74 90.82,41.86 89.33,41.86 89.2,41.99 89.2,42.36 89.33,42.48 91.27,42.48 91.4,42.61 91.4,42.98 91.27,43.11 89.33,43.11 89.2,43.23 89.2,43.6 89.33,43.73 91.27,43.73 91.4,43.86 91.4,44.22 91.27,44.35 90.54,44.35 90.42,44.48 90.42,44.85 90.54,44.97 91.21,44.97 91.4,45.16 91.4,52.36 99.32,60.28 99.32,69.01 99.2,69.13 99.2,74.19 99.6,74.59 99.6,75.04 99.88,75.32 102.78,75.32 103.27,75.81 v2(103.27,76.15)
  IN2 w0.127: v2(92.14,22.97) 92.11,22.94 90.53,22.94 90.05,23.41 90.05,23.64 87.16,26.53 87.16,27.79 v2(86.58,28.37) 86.58,28.65 86.81,28.88 86.81,32.25 86.68,32.37 86.37,32.37 86.24,32.5 86.24,32.78 86.37,32.91 86.68,32.91 86.81,33.03 86.81,33.31 86.68,33.44 86.37,33.44 86.24,33.57 86.24,33.85 86.37,33.97 86.68,33.97 86.81,34.1 86.81,35.64 86.64,35.8 v2(85.81,35.8)
  BOTTOM w0.102: UC1.C27 102.94,75.82 v2(103.27,76.15)
  BOTTOM w0.127: JDIMM1.15 92.7,23.53 v2(92.14,22.97) ; JDIMM2.15 84.5,37.11 v2(85.81,35.8)
DDRAB_SDQ3: length 93.1
  IN1 w0.216: v2(104.04,76.23) 103.68,76.59 102.9,76.59 102.69,76.8 101.75,76.8 100.77,75.82 99.74,75.82 99.2,75.27 99.2,74.82 98.8,74.42 98.8,60.5 90.87,52.58 90.87,48.22 90.69,48.04 90.25,48.04 90.13,47.91 90.13,47.54 90.25,47.41 90.75,47.41 90.87,47.29 90.87,46.92 90.75,46.79 89.12,46.79 88.99,46.66 88.99,46.3 89.12,46.17 90.75,46.17 90.87,46.04 90.87,45.67 90.75,45.55 88.86,45.55 88.68,45.36 88.68,45.06 88.86,44.87 89.77,44.87 89.9,44.75 89.9,44.38 89.77,44.25 88.86,44.25 88.68,44.07 88.68,38.94 86.99,37.25 86.99,32.21 86.34,31.56 86.34,29.98 85.99,29.63 85.99,28.04 86.28,27.75 v2(86.54,27.75)
  IN2 w0.127: v2(92.13,22.39) 92.01,22.5 90.35,22.5 89.62,23.23 89.62,23.46 86.73,26.35 86.73,27.54 86.54,27.72 v2(86.54,27.75) 85.99,28.31 85.99,29.64 86.1,29.76 86.25,29.76 86.38,29.88 86.38,30.22 86.25,30.34 86.04,30.34 85.91,30.47 85.91,30.75 86.04,30.88 86.25,30.88 86.38,31 86.38,31.75 85.81,32.32 85.81,34.27 85.93,34.4 86.24,34.4 86.37,34.52 86.37,35.24 86.24,35.37 85.93,35.37 85.81,35.24 v2(85.81,35.09)
  BOTTOM w0.102: UC1.D27 103.67,75.82 104.04,76.2 v2(104.04,76.23)
  BOTTOM w0.127: v2(92.13,22.39) 92.22,22.39 93.3,23.47 JDIMM1.17 ; v2(85.81,35.09) 86.24,35.52 86.24,36.03 85.1,37.17 JDIMM2.17
DDRAB_SDQ4: length 90.6
  IN1 w0.216: v2(83.17,21.67) 81.9,22.93 81.9,26.63 80.47,28.05 80.47,37.4 80.84,37.77 80.84,49.28 91.84,60.27 91.84,65.78 94.26,68.2 94.26,76.55 97.22,79.51 100.38,79.51 v2(100.77,79.12)
  IN2 w0.127: v2(83.17,21.67) 82.49,22.34 82.49,25.98 80.91,27.56 v2(80.91,28.38)
  BOTTOM w0.102: UC1.B24 102.44,78.22 101.57,79.08 101.57,79.15 101.39,79.32 100.97,79.32 v2(100.77,79.12)
  BOTTOM w0.127: JDIMM1.4 89.4,17.69 89.06,18.03 85.85,18.03 83.17,20.71 v2(83.17,21.67) ; v2(80.91,28.38) 81.2,28.67 JDIMM2.4
DDRAB_SDQ5: length 89.4
  IN1 w0.216: v2(83.9,21.76) 82.45,23.21 82.45,26.82 81.35,27.91 81.35,28.69 80.99,29.04 80.99,37.19 81.36,37.55 81.36,49.06 92.36,60.06 92.36,65.56 94.78,67.98 94.78,76.33 97.43,78.99 99.89,78.99 v2(100.51,78.36)
  IN2 w0.127: v2(83.9,21.76) 82.92,22.73 82.92,26.16 81.53,27.55 81.53,28.11 v2(81.79,28.36)
  BOTTOM w0.102: v2(100.51,78.36) 100.51,78.36 101.02,77.85 101.64,77.85 UC1.B25
  BOTTOM w0.127: JDIMM1.6 90,17.73 89.22,18.51 85.98,18.51 83.9,20.59 v2(83.9,21.76) ; v2(81.79,28.36) 81.64,28.51 81.64,28.92 81.8,29.08 JDIMM2.6
DDRAB_SDQ6: length 90.2
  IN1 w0.216: v2(97.84,74.97) 97.76,74.88 97.76,60.93 87.6,50.77 87.6,45.67 87.47,45.54 87.1,45.54 86.97,45.42 86.97,45.05 87.1,44.92 87.51,44.92 87.64,44.79 87.64,44.43 87.51,44.3 87.1,44.3 86.97,44.17 86.97,43.8 87.1,43.68 87.42,43.68 87.6,43.49 87.6,42.99 87.42,42.8 86.53,42.8 86.4,42.68 86.4,42.31 86.53,42.18 87.51,42.18 87.64,42.06 87.64,41.69 87.51,41.56 85.53,41.56 85.4,41.43 85.4,41.06 85.53,40.94 87.51,40.94 87.64,40.81 87.64,40.44 87.51,40.32 86.36,40.32 86.18,40.13 86.18,37.91 84.9,36.63 84.9,26.78 87.14,24.54 v2(87.14,22.2)
  BOTTOM w0.102: 99.13,75.51 101.43,75.51 101.74,75.82 UC1.B27
  BOTTOM w0.127: JDIMM2.16 84.8,27.82 84.72,27.74 84.72,26.74 87.14,24.32 v2(87.14,22.2) 89.37,19.97 91.08,19.97 93,18.05 JDIMM1.16
  BOTTOM w0.196: v2(97.84,74.97) 98.38,75.51 99.13,75.51
DDRAB_SDQ7: length 90.5
  IN1 w0.216: v2(87.78,22.17) 88.44,22.83 88.44,23.98 85.42,27 85.42,32.16 86.47,33.21 86.47,37.47 88.16,39.15 88.16,47.33 88.34,47.51 89.42,47.51 89.6,47.69 89.6,47.95 89.42,48.13 88.25,48.13 88.12,48.26 88.12,48.63 88.25,48.75 90.23,48.75 90.35,48.88 90.35,49.24 90.23,49.37 88.31,49.37 88.19,49.5 88.19,49.86 88.31,49.99 90.17,49.99 90.35,50.17 90.35,50.52 90.17,50.7 89.65,50.7 89.52,50.83 89.52,51.2 89.65,51.32 90.17,51.32 90.35,51.51 90.35,52.79 98.28,60.72 98.28,74.68 98.65,75.05 98.65,75.48 99.44,76.27 99.77,76.27 v2(99.99,76.49)
  BOTTOM w0.102: UC1.A27 100.67,75.82 v2(99.99,76.49)
  BOTTOM w0.127: JDIMM2.18 85.4,28.93 85.3,28.83 85.3,27.71 85.15,27.56 85.15,26.92 87.78,24.3 v2(87.78,22.17) 89.55,20.4 91.37,20.4 93.6,18.17 JDIMM1.18
DDRAB_SDQ8: length 80.3
  IN1 w0.102: v2(100.39,73.41) 100.07,73.09 100.07,70.32 101.4,69 101.4,68.2
  IN1 w0.216: 101.4,68.2 101.4,59.31 94.41,52.31 94.41,50.53 94.19,50.32 93.61,50.32 93.48,50.19 93.48,49.77 93.61,49.65 94.28,49.65 94.41,49.52 94.41,49.15 94.28,49.02 93.66,49.02 93.48,48.84 93.48,48.58 93.66,48.4 94.28,48.4 94.41,48.27 94.41,47.91 94.28,47.78 93.66,47.78 93.48,47.6 93.48,39.47 93.2,39.19 93.2,38.75 93.34,38.61 93.34,38.43 93.03,38.13 92.85,38.13 92.51,38.47 92.49,38.47 92.47,38.49 92.29,38.49 92.03,38.23 92.03,38.05 92.46,37.63 92.46,37.45 92.2,37.19 92.02,37.19 91.54,37.67 91.36,37.67 91.1,37.41 91.1,37.23 91.17,37.15 91.17,36.89 90.66,36.38 90.66,31.15 89.97,30.47 v2(89.97,28.41)
  IN2 w0.127: v2(88.06,34.28) 88.06,31.74 89.97,29.82 v2(89.97,28.41) 89.97,26.93 90.21,26.7 90.21,25.93 91.57,24.56 92.36,24.56 93.36,23.56 v2(93.36,22.23)
  BOTTOM w0.102: UC1.A29 101.01,74.22 100.39,73.59 v2(100.39,73.41)
  BOTTOM w0.127: JDIMM2.21 86.3,37.16 87.1,36.36 87.1,35.23 v2(88.06,34.28) ; v2(93.36,22.23) 93.36,22.57 94.5,23.7 JDIMM1.21
DDRAB_SDQ9: length 80.6
  IN1 w0.102: 100.88,68.2 100.88,68.98 99.87,69.99 99.87,73.44 100.23,73.79 102.38,73.79 v2(102.48,73.9)
  IN1 w0.216: 100.88,68.2 100.88,59.52 92.96,51.6 92.96,40.27 90.14,37.45 90.14,37.03 89.96,36.85 89.82,36.85 89.69,36.72 89.69,36.35 89.82,36.23 90.01,36.23 90.14,36.1 90.14,35.73 90.01,35.6 89.82,35.6 89.69,35.48 89.69,35.11 89.82,34.98 90.01,34.98 90.14,34.85 90.14,34.49 90.01,34.36 89.82,34.36 89.69,34.23 89.69,33.86 89.82,33.74 89.96,33.74 90.14,33.55 90.14,31.37 89.15,30.38 89.15,28.05 89.2,28 v2(89.2,27.41)
  IN2 w0.127: v2(88.06,34.95) 87.6,34.49 87.6,31.21 89.2,29.61 v2(89.2,27.41) 89.2,26.33 91.4,24.13 92.18,24.13 92.75,23.56 92.75,22.19 93.36,21.59 v2(93.36,21.59)
  BOTTOM w0.102: v2(102.48,73.9) 102.8,74.22 UC1.C29
  BOTTOM w0.127: JDIMM2.23 86.9,37.24 87.53,36.6 87.53,35.47 v2(88.06,34.95) ; JDIMM1.23 95.1,23.69 94.3,22.9 93.81,22.4 93.81,22.03 v2(93.36,21.59)
DDRAB_SDQ10: length 79.4
  TOP w0.127: v2(95.29,23.27) 95.3,23.26 94.03,24.53 94.03,26.07 94.16,26.2 94.65,26.2 94.77,26.33 94.77,26.61 94.65,26.74 94.16,26.74 93.97,26.92 93.97,28.2 v2(93.49,28.68)
  IN1 w0.102: v2(102.8,71.44) 103.75,70.48 103.75,68.53 103.74,68.52 103.74,67.95
  IN1 w0.216: v2(93.49,28.68) 93.92,28.68 95.22,29.98 95.22,32.05 94.28,32.99 94.28,36.12 96.35,38.19 96.35,48.92 96.48,49.05 98.09,49.05 98.22,49.17 98.22,49.61 98.09,49.74 96.51,49.74 96.39,49.86 96.39,50.23 96.51,50.36 98.95,50.36 99.08,50.49 99.08,50.88 98.9,51.07 97.79,51.07 97.61,51.25 97.61,51.51 97.79,51.69 98.9,51.69 99.08,51.87 99.08,53.92 103.39,58.23 103.39,66.13 103.74,66.48 103.74,67.95
  IN2 w0.127: v2(93.49,28.68) 93.49,29.13 91.75,30.86 91.75,31.81 90.85,32.72 90.85,34.42 v2(91.55,35.12)
  BOTTOM w0.102: v2(102.8,71.44) 102.42,71.82 UC1.B32
  BOTTOM w0.127: v2(91.55,35.12) 89.9,36.76 JDIMM2.33 ; v2(95.29,23.27) 95.31,23.29 97.2,23.29 98.1,24.19 JDIMM1.33
DDRAB_SDQ11: length 81
  TOP w0.127: v2(98.13,26.35) 97.68,26.8 97.68,27.01 97.05,27.64 97.05,29.03 95.93,30.15 v2(95.93,35.22) v1(95.93,38.29) 95.93,38.93 v2(94.7,40.16)
  IN1 w0.102: v2(103.27,73.02) 105.31,70.98 105.31,67.95
  IN1 w0.216: v2(95.93,35.22) 99.26,38.55 99.26,40.04 99.13,40.17 98.48,40.17 98.35,40.3 98.35,40.75 98.48,40.88 100.2,40.88 100.32,41.01 100.32,41.41 100.2,41.54 98.48,41.54 98.35,41.67 98.35,42.04 98.48,42.16 100.53,42.16 100.71,42.35 100.71,42.6 100.53,42.79 98.48,42.79 98.35,42.91 98.35,43.28 98.48,43.41 100.53,43.41 100.71,43.59 100.71,43.85 100.53,44.03 98.48,44.03 98.35,44.16 98.35,44.52 98.48,44.65 100.53,44.65 100.71,44.83 100.71,53.34 104.95,57.58 104.95,65.48 105.31,65.84 105.31,67.95
  BOTTOM w0.102: UC1.D32 103.77,72.52 v2(103.27,73.02)
  BOTTOM w0.127: JDIMM1.35 98.7,25.94 98.29,26.35 v2(98.13,26.35) ; v2(94.7,40.16) 91.19,40.16 90.5,39.46 JDIMM2.35
DDRAB_SDQ12: length 79.4
  IN1 w0.102: v2(100.14,74.68) 99.46,74.01 99.46,69.38 99.84,69 99.84,68.2
  IN1 w0.216: 99.84,68.2 99.84,60.07 91.92,52.15 91.92,41.61 90.44,40.13 90.44,39.23 88.65,37.44 88.65,32.08 88.11,31.54 88.11,26.6 90.67,24.05 v2(90.67,23.41)
  IN2 w0.127: v2(90.67,23.41) 90.67,23.64 88,26.31 88,27.53 v2(87.6,27.93)
  BOTTOM w0.102: UC1.B28 102.16,75.32 101.54,75.32 101.51,75.29 100.75,75.29 v2(100.14,74.68)
  BOTTOM w0.127: v2(87.6,27.93) 86.6,28.92 JDIMM2.22 ; JDIMM1.22 94.8,17.8 91.77,20.83 89.73,20.83 89.6,20.96 89.6,21.41 89.73,21.54 90.24,21.54 90.37,21.67 90.37,23.28 90.49,23.41 v2(90.67,23.41)
DDRAB_SDQ13: length 79
  IN1 w0.102: 100.36,68.2 100.36,68.99 99.67,69.68 99.67,73.52 100.14,74 101.13,74 v2(101.68,74.54)
  IN1 w0.216: 100.36,68.2 100.36,59.85 92.44,51.93 92.44,41.39 90.96,39.92 90.96,39.01 89.17,37.22 89.17,31.86 88.63,31.32 88.63,26.82 91.29,24.16 91.29,23.38 v2(91.28,23.37)
  IN2 w0.127: v2(91.28,23.37) 91.28,23.63 88.43,26.49 88.43,27.82 v2(87.63,28.62)
  BOTTOM w0.102: v2(101.68,74.54) 101.68,74.48 101.94,74.22 UC1.B29
  BOTTOM w0.127: v2(91.28,23.37) 91.28,22.94 91.15,22.82 90.93,22.82 90.8,22.69 90.8,22.41 90.93,22.28 91.17,22.28 91.29,22.16 91.29,21.93 91.17,21.81 90.93,21.81 90.8,21.68 90.8,21.39 90.93,21.26 91.95,21.26 93.04,20.18 93.22,20.18 93.57,20.53 93.75,20.53 93.95,20.33 93.95,20.15 93.59,19.8 93.59,19.62 95.4,17.81 JDIMM1.24 ; JDIMM2.24 87.2,29.05 v2(87.63,28.62)
DDRAB_SDQ14: length 82.8
  TOP w0.127: v2(97.64,18.8) 96.2,20.25 96.2,21.15 96.07,21.27 95.31,21.27 95.18,21.4 95.18,21.68 95.31,21.81 96.07,21.81 96.42,22.16 96.42,26.02 v2(95.35,27.09) 95.19,27.25 95.19,29.19 94.25,30.13 v1(94.25,30.78) 94.25,31.43 v2(94.74,31.92)
  IN1 w0.102: v2(102.69,72.14) 102.82,72.14 103.96,70.99 103.96,69.2 104.26,68.89 104.26,67.95
  IN1 w0.216: v2(95.35,27.09) 95.33,27.11 95.33,28.61 95.74,29.02 95.74,32.27 94.8,33.21 94.8,35.91 96.87,37.97 96.87,47.13 97,47.26 99,47.26 99.13,47.38 99.13,47.78 99,47.9 97,47.9 96.87,48.03 96.87,48.4 97,48.52 99.5,48.52 99.62,48.65 99.62,53.73 103.91,58.01 103.91,65.91 104.26,66.27 104.26,67.95
  BOTTOM w0.102: UC1.A31 101.6,72.39 102.43,72.39 v2(102.69,72.14)
  BOTTOM w0.127: JDIMM2.34 90.2,31.11 91.19,32.11 94.54,32.11 v2(94.74,31.92) ; JDIMM1.34 98.4,18.13 97.72,18.8 v2(97.64,18.8)
DDRAB_SDQ15: length 81.2
  TOP w0.127: v2(97.69,19.44) 98.25,19.44 98.33,19.52 98.33,19.95 98.21,20.08 97.28,20.08 97.15,20.21 97.15,20.49 97.28,20.61 98.21,20.61 98.33,20.74 98.33,22.36 97.17,23.52 v2(97.17,26.63) 97.09,26.71 96.56,26.71 95.71,27.56 95.71,29.28 v1(95.43,29.56) 94.75,30.24 v2(94.75,31.31)
  IN1 w0.102: v2(103.27,72.22) 103.42,72.38 103.63,72.38 105.1,70.9 105.1,68.27 104.79,67.95
  IN1 w0.216: 104.79,67.95 104.79,66.05 104.43,65.7 104.43,57.8 100.16,53.52 100.16,46.86 100.03,46.74 97.96,46.74 97.83,46.61 97.83,46.21 98.02,46.03 99.36,46.03 99.49,45.9 99.49,45.53 99.36,45.4 98.02,45.4 97.83,45.22 97.83,38.2 95.41,35.78 95.41,33.33 96.26,32.48 96.26,29.76 97.02,28.99 97.02,26.78 v2(97.17,26.63)
  BOTTOM w0.102: UC1.C31 102.87,72.62 v2(103.27,72.22)
  BOTTOM w0.127: v2(97.69,19.44) 99,18.14 JDIMM1.36 ; v2(94.75,31.31) 94.51,31.31 94.14,31.68 91.37,31.68 90.8,31.1 JDIMM2.36
DDRAB_SDQ16: length 83.9
  TOP w0.127: v2(91.57,36.42) 91.55,36.42 91.13,36.01 91.13,31.53 91.88,30.78 v1(91.88,29.4) v2(91.88,26.26)
  IN1 w0.127: v2(94.82,22) 94.32,22 91.87,24.45 91.87,26.26 91.87,26.26 v2(91.88,26.26)
  IN2 w0.102: v2(104.97,72.92) 104.97,72.65 102.8,70.48 101.97,70.48 101.79,70.31 100.92,70.31 99.13,68.52
  IN2 w0.216: v2(91.88,26.26) 91.88,28.14 91.13,28.88 91.13,30.07 90.15,31.05 90.15,31.93 89.38,32.7 89.38,38.54 89.92,39.08 89.92,56.45 90.66,57.19 90.92,57.19 91.02,57.09 91.28,57.09 91.46,57.28 91.46,57.53 91.36,57.63 91.36,57.89 91.54,58.07 91.8,58.07 91.9,57.97 92.16,57.97 92.34,58.16 92.34,58.42 92.24,58.51 92.24,58.77 92.42,58.95 92.68,58.95 92.78,58.86 93.04,58.86 93.22,59.04 93.22,59.3 93.12,59.39 93.12,59.65 93.3,59.83 93.56,59.83 93.66,59.74 93.92,59.74 94.1,59.92 94.1,60.18 94,60.27 94,60.53 94.18,60.71 94.44,60.71 94.54,60.62 94.8,60.62 94.98,60.8 94.98,61.06 94.88,61.16 94.88,61.41 98.51,65.04 98.51,67.89 99.13,68.52
  BOTTOM w0.102: UC1.E30 v2(104.97,72.92)
  BOTTOM w0.127: JDIMM2.39 91.7,37.2 91.87,37.03 91.87,36.66 91.64,36.42 v2(91.57,36.42) ; JDIMM1.39 99.9,24.02 99.18,23.3 97.83,23.3 97.38,22.86 95.66,22.86 94.82,22.02 v2(94.82,22)
DDRAB_SDQ17: length 83.5
  TOP w0.127: v2(91.56,35.75) 92.59,34.72 v1(92.59,32.32) 92.59,31.08 92.45,30.94 v2(92.45,26.52)
  IN1 w0.127: v2(92.45,26.52) 92.45,24.47 94.5,22.43 95.18,22.43 95.24,22.49 95.8,22.49 v2(95.87,22.43)
  IN2 w0.102: v2(104.09,72.97) 104.09,72.06 102.77,70.74 101.93,70.74 101.7,70.51 100.32,70.51 99.13,69.32
  IN2 w0.216: v2(92.45,26.52) 92.45,26.12 92.06,25.73 91.12,25.73 90.75,26.1 90.75,26.93 90.61,27.06 90.61,29.86 88.86,31.6 88.86,56.91 97.95,66 97.95,68.14 99.13,69.32
  BOTTOM w0.102: UC1.E31 104.53,72.52 v2(104.09,72.97)
  BOTTOM w0.127: v2(91.56,35.75) 91.57,35.75 92.3,36.48 JDIMM2.41 ; JDIMM1.41 100.5,23.89 99.49,22.87 98,22.87 97.56,22.43 96.77,22.43 96.76,22.42 95.87,22.42 v2(95.87,22.43)
DDRAB_SDQ18: length 83
  TOP w0.127: v2(99.94,22.48) 99.78,22.64 99.78,26.45 98.62,27.61 98.27,27.61 v2(98.14,27.48) 97.78,27.84 97.78,29.13 97.34,29.58 v1(97.34,30.23) 97.34,32.47 v2(96.86,32.95)
  IN2 w0.216: v2(98.14,27.48) 98.51,27.48 98.75,27.73 98.75,29.01 96.92,30.83 96.81,30.83 96.41,31.24 96.41,36.51 95.66,37.26 95.66,40.61 95.32,40.94 95.32,52.92 98.23,55.83 98.49,55.83 98.82,55.49 99,55.49 99.26,55.76 99.26,55.94 98.93,56.27 98.93,56.53 99.11,56.71 99.37,56.71 100.18,55.89 100.44,55.89 100.62,56.08 100.62,56.33 99.81,57.15 99.81,57.41 99.99,57.59 100.25,57.59 101.06,56.77 101.32,56.77 101.5,56.96 101.5,57.21 100.69,58.03 100.69,58.29 100.87,58.47 101.13,58.47 101.97,57.63 102.15,57.63 102.41,57.89 102.41,58.07 101.57,58.91 101.57,59.17 102.51,60.11 102.51,65.47 104.33,67.3 104.33,68.17 105.65,69.48 v2(105.69,69.48)
  BOTTOM w0.102: UC1.G33 106.17,70.92 106.07,70.82 106.07,69.87 v2(105.69,69.48)
  BOTTOM w0.127: JDIMM1.51 103.5,23.99 103.27,23.76 101.72,23.76 101.59,23.63 101.59,22.9 101.47,22.77 100.09,22.77 99.94,22.62 v2(99.94,22.48) ; JDIMM2.51 95.3,37.25 95.06,37.01 95.06,34.68 96.3,33.44 96.37,33.44 v2(96.86,32.95)
DDRAB_SDQ19: length 83.2
  TOP w0.127: v2(96.86,33.56) 96.9,33.56 98.25,32.21 98.25,29.53 99.26,28.52 99.26,27.72 99.27,27.71 v2(99.27,27.58) 100.21,26.64 100.21,23.11 100.64,22.68 v2(100.64,22.29)
  IN2 w0.216: v2(105.69,68.9) 104.85,68.07 104.85,67.08 103.03,65.26 103.03,57.49 99.72,54.19 99.47,54.19 98.99,54.66 98.81,54.66 98.55,54.4 98.55,54.22 99.02,53.75 99.02,53.49 98.84,53.31 98.58,53.31 97.71,54.19 97.45,54.19 97.27,54 97.27,53.75 98.14,52.87 98.14,52.61 97.96,52.43 97.7,52.43 96.83,53.31 96.57,53.31 96.39,53.12 96.39,52.87 97.26,51.99 97.26,51.73 97.08,51.55 96.82,51.55 96.28,52.09 96.1,52.09 95.84,51.83 95.84,51.65 96.38,51.11 96.38,50.85 96.08,50.55 96.08,40.92 96.18,40.82 96.18,37.47 97.3,36.35 97.3,31.19 99.27,29.22 99.27,27.59 v2(99.27,27.58)
  BOTTOM w0.102: v2(105.69,68.9) 106.27,69.48 106.27,70.41 106.28,70.42 106.28,70.6 106.49,70.81 106.49,71.08 106.46,71.11 106.46,71.23 106.17,71.52 UC1.G32
  BOTTOM w0.127: JDIMM2.53 95.9,37.13 95.49,36.72 95.49,34.93 v2(96.86,33.56) ; JDIMM1.53 104.1,23.98 103.45,23.33 102.15,23.33 102.03,23.2 102.03,22.07 101.9,21.95 101.53,21.95 101.4,22.07 101.4,22.16 101.28,22.29 v2(100.64,22.29)
DDRAB_SDQ20: length 81.6
  IN1 w0.127: v2(96.64,21.67) 96.64,22.48 95.57,23.55 93.47,25.65 93.47,27.42 v2(93.48,27.41)
  IN2 w0.216: v2(96.64,21.67) 96.64,22.38 96.47,22.55 96.47,23.88 94.25,26.09 93.49,26.09 93.01,26.57 93.01,28.18 92.27,28.93 92.27,29.67 90.67,31.27 90.67,32.14 89.9,32.91 89.9,38.32 90.8,39.22 90.8,55.87 95.83,60.9 95.83,61.04 95.67,61.21 95.67,61.46 99.03,64.82 99.03,67.58 100.08,68.63 100.08,68.77 101.15,69.84 v2(101.66,69.84)
  BOTTOM w0.102: v2(101.66,69.84) 101.98,69.84 UC1.C33
  BOTTOM w0.127: JDIMM1.40 100.2,17.67 99.97,17.9 99.85,17.9 98.14,19.6 98.14,19.73 98,19.88 97.43,19.88 97.24,19.69 97.24,18.62 97.11,18.49 96.79,18.49 96.67,18.62 96.67,20.01 96.54,20.13 96.06,20.13 95.93,20.26 95.93,20.54 96.06,20.67 96.51,20.67 96.64,20.79 96.64,21.03 96.51,21.16 95.98,21.16 95.85,21.29 95.85,21.86 95.98,21.98 96.51,21.98 96.64,21.86 v2(96.64,21.67) ; v2(93.48,27.41) 92.77,28.12 92.77,28.13 92,28.9 JDIMM2.40
DDRAB_SDQ21: length 82.2
  IN1 w0.127: v2(93.45,28.06) 93.9,27.61 93.9,26.43 97.12,23.2 97.12,22.09 v2(97.21,22)
  IN2 w0.216: v2(101.66,69.28) 99.55,67.17 99.55,64.61 97.31,62.37 97.31,62.11 97.73,61.69 97.73,61.44 97.54,61.25 97.29,61.25 96.87,61.67 96.61,61.67 96.43,61.49 96.43,61.23 96.85,60.81 96.85,60.56 96.66,60.37 96.19,60.37 91.33,55.51 91.33,40.33 91.91,39.74 91.91,39.05 92.2,38.76 92.2,34.81 91.33,33.94 91.33,32.97 92.95,31.34 92.95,30.46 93.97,29.43 93.97,27.11 96.99,24.09 96.99,22.9 97.21,22.68 v2(97.21,22)
  BOTTOM w0.102: UC1.D33 103.48,71.03 103.48,70.74 102.01,69.28 v2(101.66,69.28)
  BOTTOM w0.127: v2(97.21,22) 97.35,22 97.59,21.76 97.59,21.59 97.19,21.18 97.19,20.45 97.31,20.32 97.68,20.32 97.81,20.45 97.81,20.98 97.86,21.03 98.04,21.03 98.3,21.29 98.48,21.29 98.69,21.07 98.69,20.9 98.34,20.55 98.34,20.14 98.58,19.91 98.58,19.78 98.98,19.38 99.22,19.38 99.6,19.76 99.78,19.76 99.98,19.56 99.98,19.38 99.57,18.98 99.57,18.8 99.71,18.66 99.89,18.66 100.26,19.03 100.44,19.03 100.64,18.83 100.64,18.65 100.33,18.34 100.33,18.16 100.8,17.68 JDIMM1.42 ; JDIMM2.42 92.6,28.91 v2(93.45,28.06)
DDRAB_SDQ22: length 81.9
  IN1 w0.127: v2(99.04,21.95) 97.99,23 97.99,23.78 94.86,26.91 94.86,27.68 v2(94.55,27.99)
  IN2 w0.216: v2(99.04,21.95) 99,21.95 98.6,22.35 98.6,22.76 98.03,23.33 98.03,24.52 96.73,25.83 96.73,26.81 97.1,27.18 97.1,29.07 95.36,30.81 95.36,32.25 94.86,32.75 94.86,36.59 94.11,37.34 94.11,53.21 101.47,60.57 101.47,65.9 103.17,67.6 103.17,69.52 v2(106.57,72.92)
  BOTTOM w0.102: UC1.G30 v2(106.57,72.92)
  BOTTOM w0.127: JDIMM2.50 95,28.44 94.55,27.99 v2(94.55,27.99) ; JDIMM1.50 103.2,18.12 102.75,18.56 102.75,18.81 103.35,19.41 103.35,19.59 103.16,19.79 102.98,19.79 102.38,19.18 102.2,19.18 102.02,19.35 102.02,19.53 102.65,20.16 102.65,20.34 102.46,20.54 102.28,20.54 101.65,19.91 101.47,19.91 101.27,20.11 101.27,20.29 101.63,20.65 101.63,20.83 101.43,21.03 101.25,21.03 100.89,20.66 100.71,20.66 100.55,20.83 100.37,20.83 100.27,20.72 100.09,20.72 99.89,20.92 99.89,21.1 100,21.2 100,21.38 99.78,21.6 99.38,21.6 v2(99.04,21.95)
DDRAB_SDQ23: length 81.1
  IN1 w0.127: v2(99.36,22.44) 99.32,22.44 98.42,23.34 98.42,24.32 96.11,26.63 96.11,28.17 v2(96.54,28.6)
  IN2 w0.216: v2(105.69,70.07) 105.57,70.07 103.81,68.31 103.81,67.51 101.99,65.69 101.99,60.32 94.8,53.14 94.8,40.73 95.14,40.39 95.14,37.04 95.38,36.8 95.38,32.97 95.88,32.46 95.88,31.02 97.62,29.29 97.62,26.73 97.68,26.67 97.68,25.95 97.85,25.77 98.44,25.77 98.57,25.9 98.57,26.12 98.69,26.25 99.12,26.25 99.25,26.12 99.25,25.25 99.12,25.12 98.69,25.12 98.56,24.98 98.56,23.55 99.36,22.74 v2(99.36,22.44)
  BOTTOM w0.102: v2(105.69,70.07) 105.81,70.07 105.87,70.12 105.87,70.79 105.86,70.79 105.86,71.05 105.87,71.05 105.87,71.59 105.86,71.59 105.86,71.85 105.87,71.85 105.87,71.95 106.17,72.25 UC1.G31
  BOTTOM w0.127: JDIMM1.52 103.8,17.76 103.9,17.86 104.03,17.86 104.16,17.99 104.16,18.33 104.03,18.45 103.52,18.45 103.39,18.58 103.39,18.83 103.8,19.24 103.8,19.85 103.52,20.13 103.52,20.31 104.34,21.13 104.34,21.31 104.14,21.51 103.96,21.51 103.14,20.69 102.96,20.69 102.15,21.5 100.49,21.5 99.96,22.03 99.76,22.03 v2(99.36,22.44)
  BOTTOM w0.196: JDIMM2.52 95.6,28.95 95.95,28.6 v2(96.54,28.6)
DDRAB_SDQ24: length 79.1
  IN1 w0.127: v2(97.81,31.89) 97.83,31.89 101.19,28.54 101.19,28.37 101.77,27.79 101.77,27.56 102.14,27.19 v2(102.74,27.19)
  IN2 w0.102: 105.43,67.95 105.43,68.1 106.08,68.75 106.08,70.64 108.17,72.73 v2(108.17,72.92)
  IN2 w0.216: 105.43,67.95 105.43,66.92 103.55,65.04 103.55,57.28 97.47,51.19 97.47,48.1 97.28,47.92 96.88,47.92 96.7,47.74 96.7,47.48 96.88,47.3 97.28,47.3 97.47,47.11 97.47,46.86 97.28,46.67 96.88,46.67 96.7,46.49 96.7,46.23 96.88,46.05 97.28,46.05 97.47,45.87 97.47,45.61 97.28,45.43 96.88,45.43 96.7,45.25 96.7,44.99 96.88,44.81 97.28,44.81 97.47,44.63 97.47,44.37 97.28,44.19 96.88,44.19 96.7,44 96.7,43.75 96.88,43.56 97.28,43.56 97.47,43.38 97.47,43.12 97.28,42.94 96.88,42.94 96.7,42.76 96.7,42.5 96.88,42.32 97.28,42.32 97.47,42.14 97.47,41.88 97.28,41.7 96.88,41.7 96.7,41.51 96.7,41.26 96.88,41.07 97.28,41.07 97.47,40.89 97.47,40.63 97.28,40.45 96.88,40.45 96.7,40.27 96.7,39.56 97.82,38.44 97.82,31.9 v2(97.81,31.89)
  BOTTOM w0.102: UC1.J30 v2(108.17,72.92)
  BOTTOM w0.127: JDIMM1.57 105.3,25.87 103.98,27.19 v2(102.74,27.19) ; v2(97.81,31.89) 97.88,31.97 97.88,32.3 97.76,32.42 97.4,32.42 97.27,32.55 97.27,32.83 97.4,32.96 98.34,32.96 98.46,33.08 98.46,33.32 98.34,33.45 97.42,33.45 97.29,33.58 97.29,33.86 97.42,33.99 98.34,33.99 98.46,34.11 98.46,34.38 98.34,34.51 96.91,34.51 96.8,34.62 96.8,35.17 96.67,35.29 96.39,35.29 96.27,35.42 96.27,35.67 96.39,35.8 97.05,35.8 97.18,35.93 97.18,36.22 97.05,36.35 96.21,36.35 96.08,36.48 96.08,36.7 96.21,36.83 96.97,36.83 97.1,36.96 JDIMM2.57
DDRAB_SDQ25: length 78.5
  IN1 w0.127: v2(102.66,27.99) 102.24,28.41 102.24,28.73 99.97,31 99.97,31.35 99.51,31.81 v2(99.41,31.81)
  IN2 w0.102: v2(106.87,69.74) 106.84,69.71 106.84,69.15 107.26,68.73 107.26,68.22 106.99,67.95
  IN2 w0.216: 106.99,67.95 106.99,66.27 105.11,64.39 105.11,56.59 103.96,55.44 103.96,52.51 103.71,52.25 103.45,52.25 102.92,52.78 102.74,52.78 102.48,52.52 102.48,52.34 103.01,51.81 103.01,51.56 102.83,51.37 102.57,51.37 101.43,52.51 101.25,52.51 100.99,52.25 100.99,52.07 102.13,50.93 102.13,50.67 101.95,50.49 101.69,50.49 100.55,51.63 100.37,51.63 100.11,51.37 100.11,51.19 101.25,50.05 101.25,49.79 101.07,49.61 100.81,49.61 100.43,49.99 100.18,49.99 99.09,48.89 99.09,40.7 99.42,40.36 99.42,35.02 99.38,34.99 99.38,31.84 v2(99.41,31.81)
  BOTTOM w0.102: UC1.J31 107.77,72.52 107.33,72.08 107.33,70.27 106.87,69.81 v2(106.87,69.74)
  BOTTOM w0.127: JDIMM1.59 105.9,25.94 105.72,26.12 105.66,26.12 105.13,26.65 105.13,26.65 103.79,27.99 v2(102.66,27.99) ; v2(99.41,31.81) 98.92,31.81 98.79,31.69 98.79,31.28 98.67,31.16 98.44,31.16 98.32,31.28 98.32,32 98.89,32.58 98.89,34.81 98.77,34.94 97.36,34.94 97.23,35.06 97.23,35.37 97.36,35.5 98.76,35.5 98.89,35.62 98.89,36.46 98.69,36.66 98.51,36.66 97.96,36.11 97.82,36.11 97.59,36.33 97.59,36.88 97.7,36.99 JDIMM2.59
DDRAB_SDQ26: length 77.6
  IN2 w0.216: v2(109.23,70.3) 109.28,70.3 110.55,69.03 110.55,56.49 107.5,53.44 107.5,46.63 107.32,46.45 106.16,46.45 105.97,46.27 105.97,46.01 106.16,45.83 107.32,45.83 107.5,45.65 107.5,45.27 107.32,45.09 104.53,45.09 104.35,44.91 104.35,44.65 104.53,44.47 107.32,44.47 107.5,44.29 107.5,44.03 107.32,43.85 104.53,43.85 104.35,43.66 104.35,40.24 102.94,38.83 102.94,32.35 103.28,32.01 v2(103.28,29.8) 103.92,29.16 103.92,28.84 105.28,27.48 105.28,26.39 v2(108.07,23.6)
  BOTTOM w0.102: v2(109.23,70.3) 109.37,70.43 UC1.L33
  BOTTOM w0.127: v2(108.07,23.6) 108.3,23.83 JDIMM1.67 ; v2(103.28,29.8) 102.42,29.8 102.29,29.93 102.29,31.83 102.16,31.95 101.2,31.95 101.02,32.13 101.02,32.47 100.89,32.59 100.01,32.59 99.88,32.72 99.88,33 100.01,33.13 100.89,33.13 101.02,33.25 101.02,36.32 100.1,37.24 JDIMM2.67
DDRAB_SDQ27: length 78.5
  IN2 w0.216: v2(108.1,23.01) 107.92,23.01 104.76,26.17 104.76,27.27 103.4,28.63 103.4,28.95 v2(103.23,29.11) 102.75,29.59 102.75,31.8 102.42,32.13 102.42,39.05 103.42,40.05 103.42,45.63 103.6,45.81 105.27,45.81 105.45,45.99 105.45,46.25 105.27,46.43 103.89,46.43 103.77,46.56 103.77,46.93 103.89,47.05 106.85,47.05 106.98,47.18 106.98,47.55 106.85,47.68 105.56,47.68 105.43,47.8 105.43,48.23 105.56,48.36 106.73,48.36 106.91,48.54 106.91,53.59 110,56.68 110,68.96 109.27,69.69 v2(109.23,69.69)
  BOTTOM w0.102: v2(109.23,69.69) 109.23,69.76 108.85,70.14 108.85,71.2 UC1.L32
  BOTTOM w0.127: JDIMM2.69 100.7,37.25 101.45,36.5 101.45,33.61 101.58,33.48 102.32,33.48 102.44,33.36 102.44,33.08 102.32,32.95 101.58,32.95 101.45,32.82 101.45,32.55 101.62,32.38 102.6,32.38 102.72,32.26 102.72,30.53 102.85,30.4 103.55,30.4 103.78,30.18 103.78,29.2 103.69,29.11 v2(103.23,29.11) ; JDIMM1.69 108.9,23.82 v2(108.1,23.01)
DDRAB_SDQ28: length 75.5
  IN1 w0.127: v2(102.5,22.85) 102.5,23.71 98.55,27.66 98.55,27.78 v2(98.25,28.08)
  IN2 w0.216: v2(106.87,68.51) 106.47,68.11 106.47,66.49 104.59,64.61 104.59,56.85 101.94,54.19 101.94,53.94 102.38,53.49 102.38,53.31 102.12,53.05 101.94,53.05 101.5,53.5 101.24,53.5 98.56,50.82 98.56,40.48 98.89,40.15 98.89,39.48 98.86,39.45 98.86,31.1 100.31,29.65 100.31,25.49 102.5,23.3 v2(102.5,22.85)
  BOTTOM w0.102: UC1.H32 106.97,72.1 106.69,71.82 106.69,71.48 106.66,71.45 106.66,71.19 106.69,71.16 106.69,70.73 106.48,70.51 106.48,70.33 106.48,70.33 106.48,68.91 v2(106.87,68.51)
  BOTTOM w0.127: v2(98.25,28.08) 97.75,28.08 96.8,29.02 JDIMM2.56 ; JDIMM1.56 105,18.21 104.3,18.91 104.3,20.27 104.77,20.74 104.77,21.49 104.2,22.06 103.74,22.06 103.07,21.39 102.88,21.39 102.58,21.68 102.58,21.79 102.89,22.1 102.89,22.45 v2(102.5,22.85)
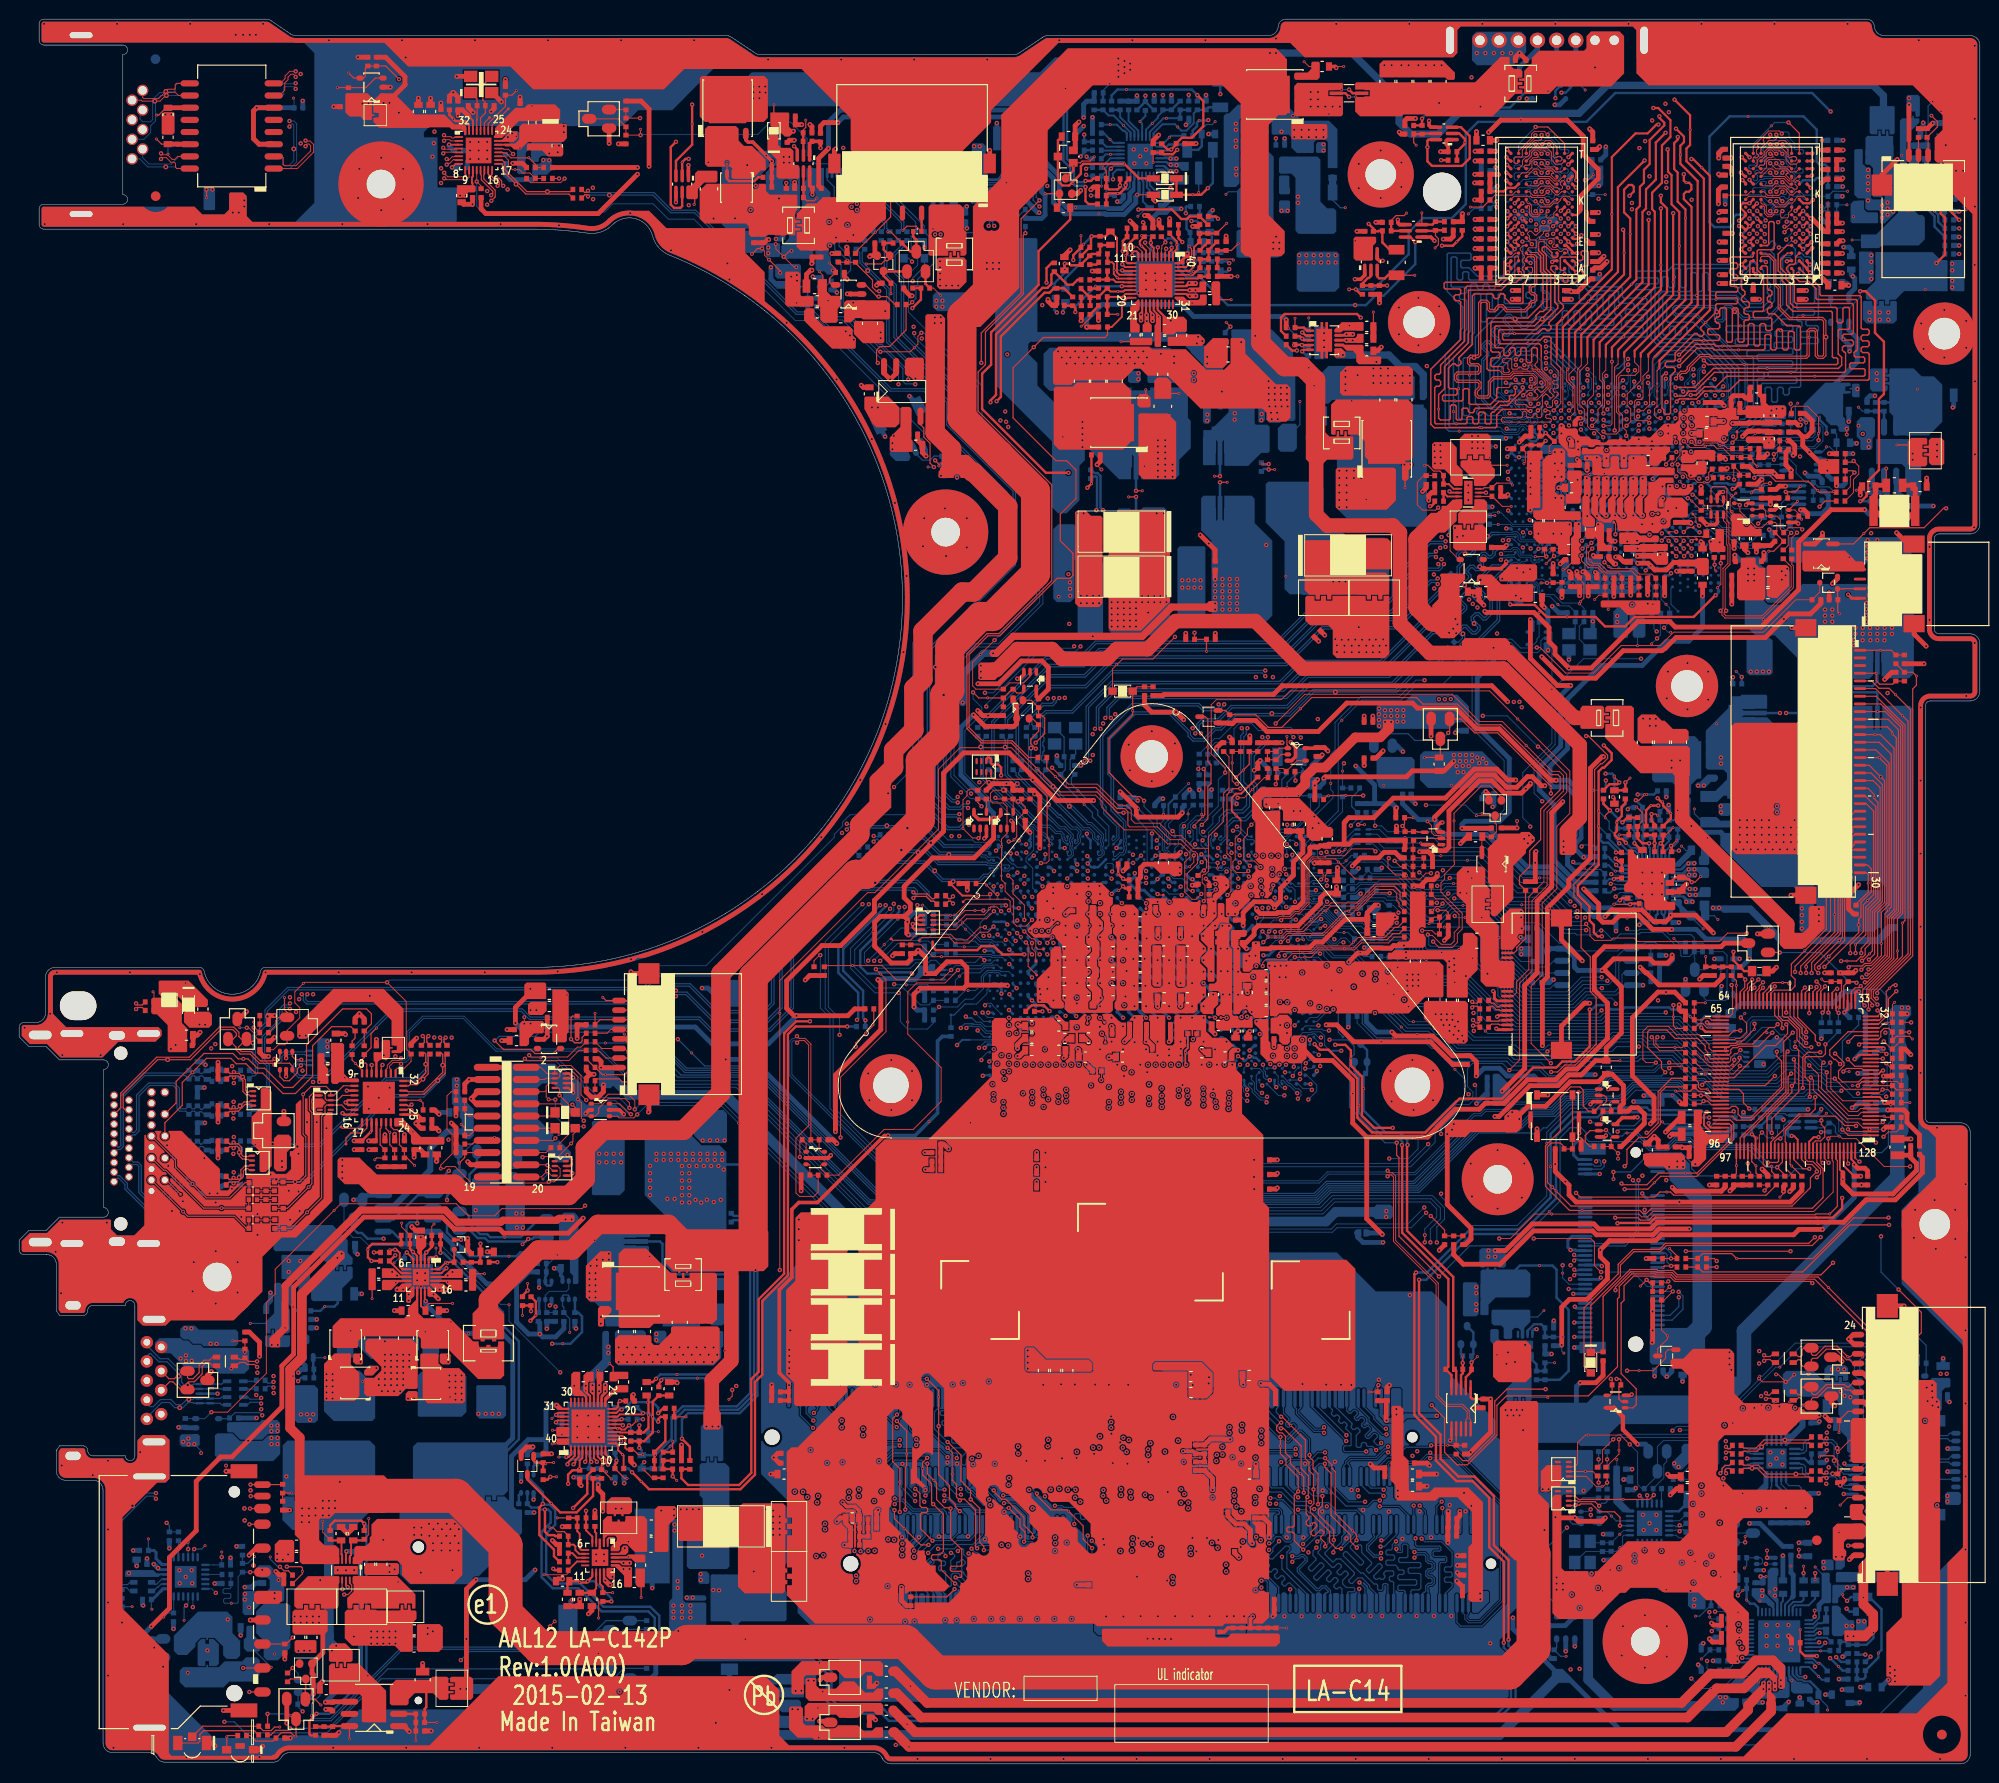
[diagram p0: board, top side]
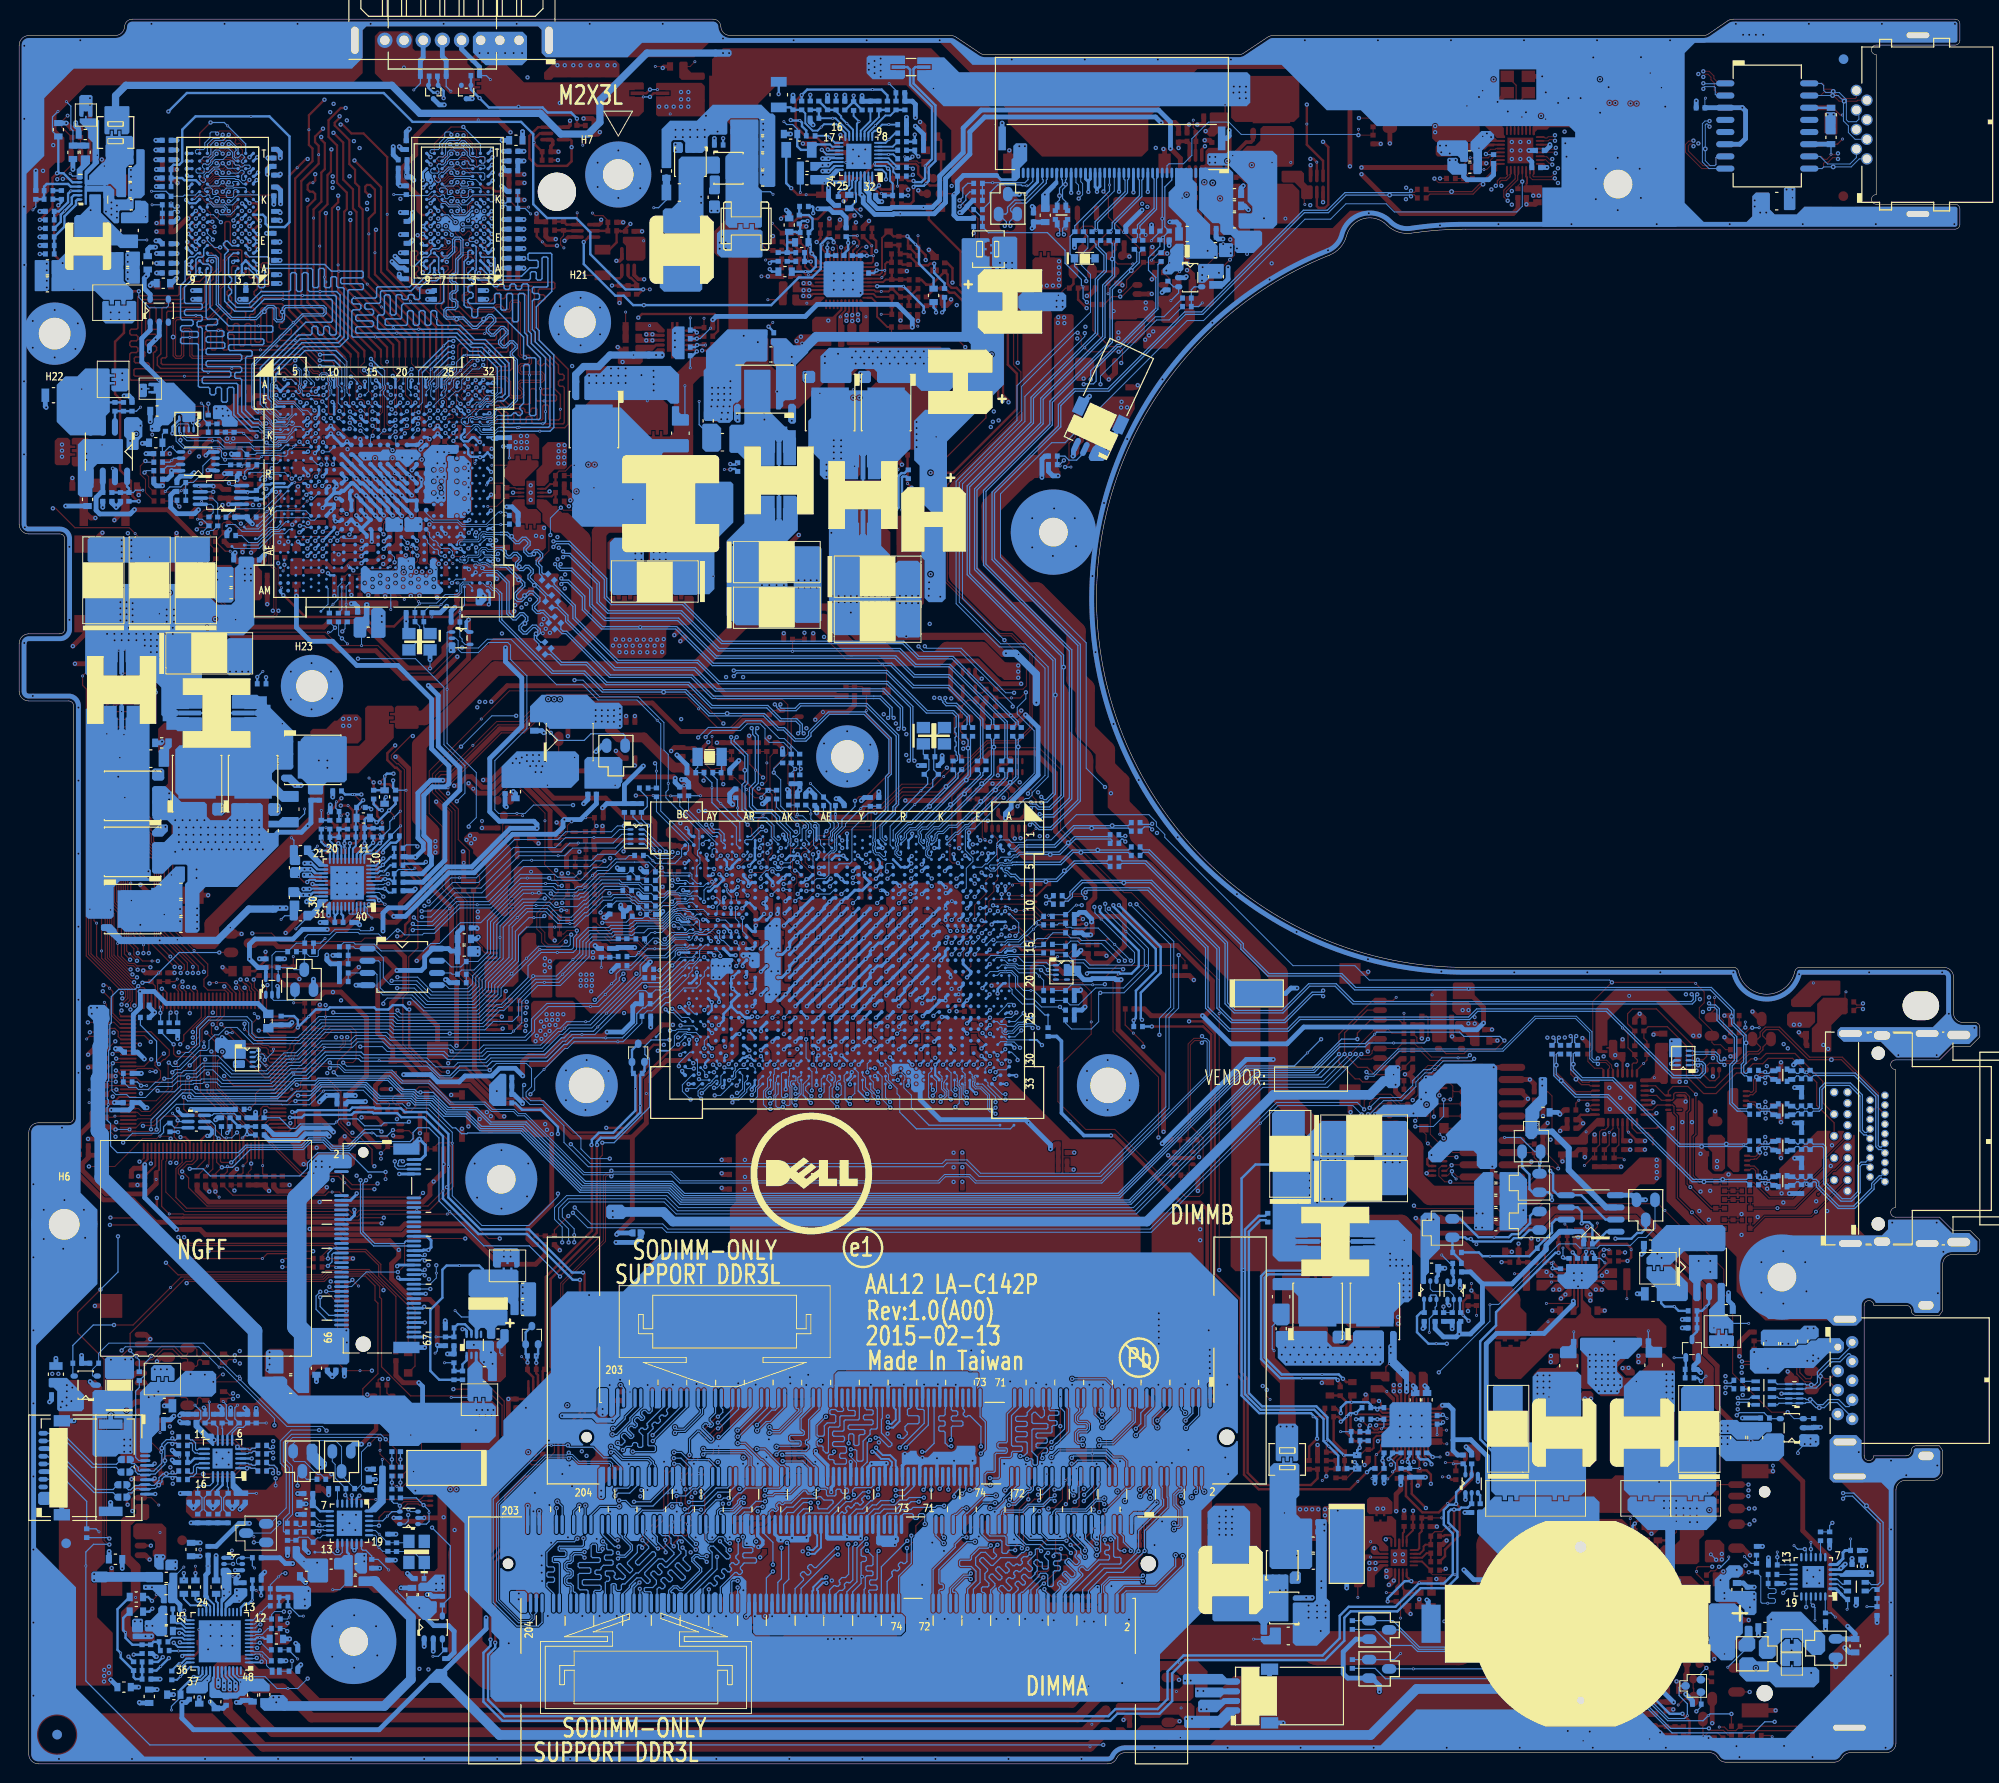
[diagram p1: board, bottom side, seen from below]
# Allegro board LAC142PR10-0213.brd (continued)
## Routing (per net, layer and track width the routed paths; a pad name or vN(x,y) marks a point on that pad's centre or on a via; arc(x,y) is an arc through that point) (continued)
DDRAB_SDQ29: length 75.9
  IN1 w0.127: v2(103.18,22.78) 103.18,24.27 98.77,28.68 v2(98.23,28.68)
  IN2 w0.102: 105.95,67.95 105.95,68.34 106.28,68.67 106.28,69.76 v2(106.86,70.34)
  IN2 w0.216: 105.95,67.95 105.95,66.7 104.07,64.82 104.07,57.06 98.02,51.01 98.02,39.53 98.34,39.21 98.34,30.89 99.79,29.44 99.79,25.18 101.31,23.66 101.31,23.29 102.28,22.33 102.74,22.33 103.18,22.77 v2(103.18,22.78)
  BOTTOM w0.102: v2(106.86,70.34) 106.97,70.45 UC1.H33
  BOTTOM w0.127: v2(103.18,22.78) 103.47,22.49 104.38,22.49 104.93,21.94 105.2,21.67 105.2,21.36 105.33,21.23 106.32,21.23 106.44,21.11 106.44,20.71 106.32,20.59 105.23,20.59 104.73,20.09 104.73,19.09 105.6,18.22 JDIMM1.58 ; v2(98.23,28.68) 97.77,28.68 97.4,29.05 JDIMM2.58
DDRAB_SDQ30: length 75.4
  TOP w0.127: v2(103.23,26.68) 104.4,25.51 104.4,24.71 104.94,24.17 104.94,23.27 v2(104.83,23.17)
  IN2 w0.102: 108.93,67.95 108.93,68.63 108.81,68.76 108.81,71.84 109.77,72.8 v2(109.77,72.92)
  IN2 w0.216: v2(104.83,23.17) 104.94,23.27 104.94,24.04 103.94,25.03 102.9,25.03 102.18,25.75 102.18,28.63 101.71,29.1 101.71,30.72 101.33,31.1 101.33,39.43 102.38,40.48 102.38,48.16 103.73,49.5 105.75,49.5 105.87,49.63 105.87,54.11 108.93,57.18 108.93,67.95
  BOTTOM w0.102: UC1.L30 v2(109.77,72.92)
  BOTTOM w0.127: JDIMM1.68 108.6,18.08 108.47,18.2 108.26,18.2 108.13,18.33 108.13,18.61 108.26,18.74 108.47,18.74 108.6,18.86 108.6,20.26 105.7,23.17 v2(104.83,23.17) ; JDIMM2.68 100.4,29.07 101.85,27.62 101.85,27.47 102.64,26.68 v2(103.23,26.68)
DDRAB_SDQ31: length 74.7
  TOP w0.127: v2(105.72,23.62) 105.72,24 104.83,24.89 104.83,25.69 102.93,27.59 102.5,27.59 101.67,28.42 v2(101.67,28.52)
  IN2 w0.216: v2(109.23,69.11) 109.48,68.86 109.48,56.9 106.39,53.81 106.39,49.11 106.27,48.98 103.94,48.98 103.82,48.85 103.82,48.49 103.94,48.36 104.62,48.36 104.81,48.18 104.81,47.92 104.62,47.74 103.08,47.74 102.9,47.55 102.9,40.27 101.9,39.26 101.9,31.92 102.23,31.58 102.23,29.32 102.79,28.76 102.79,28.5 104.23,27.05 104.23,25.81 105.72,24.32 v2(105.72,23.62)
  BOTTOM w0.102: v2(109.23,69.11) 109.68,69.55 109.68,71.95 109.37,72.26 UC1.L31
  BOTTOM w0.127: v2(105.72,23.62) 106.16,23.62 106.89,22.89 106.89,22.59 109.2,20.27 JDIMM1.70 ; v2(101.67,28.52) 101.56,28.52 101,29.08 JDIMM2.70
DDRAB_SDQ32: length 83
  IN1 w0.127: v2(126.99,26.82) 126.7,26.82 125.76,27.76 125.76,32.03 v2(125.54,32.25)
  IN2 w0.102: v2(127.36,72.92) 127.36,72.74 128.56,71.54 128.56,68.56 127.72,67.72
  IN2 w0.216: 127.72,67.72 127.72,65.35 122.09,59.72 121.83,59.72 121.47,60.08 121.21,60.08 120.99,59.86 120.99,40.68 121.74,39.93 121.74,39.2 121.86,39.07 123.21,39.07 123.34,38.94 123.34,38.54 123.21,38.42 121.91,38.42 121.79,38.29 121.79,37.92 121.91,37.8 123.46,37.8 123.59,37.67 123.59,37.16 123.46,37.03 123.04,37.03 122.92,36.91 122.92,36.51 123.04,36.39 123.46,36.39 123.59,36.26 123.59,35.85 123.46,35.73 123.04,35.73 122.91,35.6 122.91,35.24 123.04,35.12 123.46,35.12 123.59,34.99 123.59,34.65 123.46,34.52 123.04,34.52 122.92,34.39 122.92,34.13 123.04,34.01 124.33,34.01 124.45,33.88 124.45,33.51 124.33,33.38 123.52,33.38 123.34,33.2 123.34,32.88 123.52,32.7 124.14,32.7 124.26,32.57 124.26,32.2 124.14,32.08 123.78,32.08 123.62,31.92 123.62,31.56 125.55,29.63 125.73,29.63 126.03,29.93 126.03,30.11 125.48,30.67 125.48,32.2 v2(125.54,32.25)
  BOTTOM w0.102: v2(127.36,72.92) 126.97,72.52 UC1.AN31
  BOTTOM w0.127: JDIMM2.129 121.1,36.98 122.19,35.9 122.19,33.93 122.31,33.81 122.4,33.81 122.52,33.68 122.52,33.4 122.4,33.27 122.31,33.27 122.19,33.14 122.19,32.94 122.47,32.66 125.14,32.66 v2(125.54,32.25) ; JDIMM1.129 129.3,25.85 128.88,26.26 128.16,26.26 127.6,26.82 v2(126.99,26.82)
DDRAB_SDQ33: length 84.1
  IN1 w0.127: v2(126.74,27.39) 126.19,27.94 126.19,32.42 125.55,33.07 v2(125.53,33.07)
  IN2 w0.102: v2(128.16,72.92) 128.16,72.22 128.76,71.63 128.76,68.19 128.42,67.85
  IN2 w0.216: v2(125.53,33.07) 125.01,33.6 125.01,34.11 124.11,35.01 124.11,39.05 123.35,39.81 123.35,40.07 121.51,41.92 121.51,51.28 121.69,51.47 122.94,51.47 123.12,51.65 123.12,51.91 122.94,52.09 121.69,52.09 121.51,52.27 121.51,52.53 121.69,52.71 122.94,52.71 123.12,52.89 123.12,53.15 122.94,53.33 121.69,53.33 121.51,53.52 121.51,53.77 121.69,53.96 122.94,53.96 123.12,54.14 123.12,54.4 122.94,54.58 121.69,54.58 121.51,54.76 121.51,55.02 121.69,55.2 122.94,55.2 123.12,55.38 123.12,55.64 122.94,55.82 121.69,55.82 121.51,56 121.51,56.26 121.69,56.44 122.94,56.44 123.12,56.63 123.12,56.95 122.94,57.14 121.73,57.14 121.55,57.32 121.55,57.58 121.73,57.76 122.94,57.76 123.12,57.94 123.12,58.2 122.94,58.38 121.98,58.38 121.85,58.51 121.85,58.88 121.98,59 122.94,59 123.12,59.18 123.12,60.01 128.24,65.13 128.24,67.67 128.42,67.85
  BOTTOM w0.102: v2(128.16,72.92) 127.77,72.52 UC1.AP32
  BOTTOM w0.127: v2(126.74,27.39) 126.75,27.38 127.68,27.38 128.36,26.7 129.06,26.7 129.9,25.86 JDIMM1.131 ; JDIMM2.131 121.7,37.27 122.97,36 122.97,34.91 122.84,34.79 122.76,34.79 122.64,34.66 122.64,34.38 122.76,34.25 124.05,34.25 124.17,34.13 124.17,33.82 124.05,33.69 123.07,33.69 122.97,33.59 122.97,33.27 123.12,33.12 125.48,33.12 v2(125.53,33.07)
DDRAB_SDQ34: length 85.2
  IN1 w0.127: v2(127.56,34.76) 127.56,33.56 128.31,32.8 128.31,29.78 v2(129.41,28.68) 129.97,28.12 129.97,24.76 130.09,24.64 130.69,24.64 130.82,24.51 130.82,23.13 130.69,23 v2(130.41,23)
  IN2 w0.102: 130.17,67.57 130.17,68.02 130.73,68.58 130.73,69.58 130.33,69.97 v2(129.66,69.97)
  IN2 w0.216: v2(129.41,28.68) 129.41,29.44 128.09,30.76 128.09,35.46 127.53,36.03 127.53,37.54 127.4,37.67 126.33,37.67 126.21,37.8 126.21,38.24 126.39,38.42 126.85,38.42 127.03,38.61 127.03,38.86 126.85,39.05 126.45,39.05 126.24,39.26 126.24,41.08 125.72,41.6 125.72,54.37 125.91,54.55 127.03,54.55 127.21,54.73 127.21,54.99 127.03,55.17 125.91,55.17 125.72,55.36 125.72,55.61 125.91,55.8 127.03,55.8 127.21,55.98 127.21,56.24 127.03,56.42 125.91,56.42 125.72,56.6 125.72,56.86 125.91,57.04 127.03,57.04 127.21,57.22 127.21,57.48 127.03,57.66 125.91,57.66 125.72,57.85 125.72,58.1 125.91,58.29 127.03,58.29 127.21,58.47 127.21,58.73 127.03,58.91 125.91,58.91 125.72,59.09 125.72,59.47 125.85,59.6 126.88,59.6 127.04,59.77 127.04,60.1 126.86,60.28 126.73,60.28 126.6,60.41 126.6,60.78 126.73,60.9 126.86,60.9 127.04,61.08 127.04,61.22 128.29,62.47 128.93,62.47 129.53,63.07 129.53,63.57 130.17,64.2 130.17,67.57
  BOTTOM w0.102: v2(129.66,69.97) 129.5,69.97 129.08,70.39 129.08,70.93 129.08,70.93 129.08,71.17 129.06,71.19 129.06,71.82 UC1.AT32
  BOTTOM w0.127: JDIMM1.141 132.9,23.41 132.63,23.14 132.14,23.14 131.59,23.69 131.13,23.69 130.92,23.47 130.92,23.27 130.65,23 v2(130.41,23) ; v2(127.56,34.76) 126.62,35.7 126.22,35.7 124.7,37.22 JDIMM2.141
DDRAB_SDQ35: length 82.3
  IN1 w0.127: v2(127.59,35.34) 128,35.34 128.09,35.26 128.09,34.38 128.21,34.25 128.99,34.25 129.11,34.12 129.11,33.8 128.99,33.67 128.62,33.67 128.49,33.54 128.49,33.26 128.62,33.14 128.86,33.14 128.99,33.01 v2(128.99,31.94) 130.55,30.38 130.55,27.79 130.54,27.78 v2(130.54,27.72)
  IN2 w0.102: v2(129.76,72.92) 129.18,72.34 129.18,70.64 129.46,70.36 130.23,70.36 130.93,69.66 130.93,68.35 130.69,68.11 130.69,67.57
  IN2 w0.216: 130.69,67.57 130.69,63.98 130.05,63.35 130.05,62.85 129.14,61.95 128.51,61.95 127.74,61.18 127.74,54.18 127.56,54 126.43,54 126.24,53.81 126.24,53.56 126.43,53.37 127.56,53.37 127.74,53.19 127.74,52.93 127.56,52.75 126.43,52.75 126.24,52.57 126.24,52.31 126.43,52.13 127.56,52.13 127.74,51.95 127.74,51.6 127.56,51.42 126.43,51.42 126.24,51.24 126.24,50.98 126.43,50.8 127.56,50.8 127.74,50.61 127.74,50.36 127.56,50.17 126.43,50.17 126.24,49.99 126.24,49.73 126.43,49.55 127.56,49.55 127.74,49.37 127.74,49.11 127.56,48.93 126.43,48.93 126.24,48.75 126.24,48.49 126.43,48.31 127.56,48.31 127.74,48.13 127.74,47.87 127.56,47.69 126.43,47.69 126.24,47.5 126.24,47.25 126.43,47.06 127.56,47.06 127.74,46.88 127.74,46.62 127.56,46.44 126.43,46.44 126.24,46.26 126.24,41.81 126.76,41.29 126.76,39.88 128.05,38.6 128.05,36.24 128.61,35.68 128.61,32.73 128.99,32.35 v2(128.99,31.94)
  BOTTOM w0.102: UC1.AU32 130.03,71.86 130.03,72.18 129.84,72.36 129.84,72.84 v2(129.76,72.92)
  BOTTOM w0.127: JDIMM1.143 133.5,25.82 132.95,26.37 132.95,26.44 131.86,27.53 131.25,27.53 131.07,27.72 v2(130.54,27.72) ; v2(127.59,35.34) 126.04,36.89 125.66,36.89 125.3,37.25 JDIMM2.143
DDRAB_SDQ36: length 87
  IN1 w0.127: v2(124.95,32.23) 125.33,31.85 125.33,27.58 126.57,26.34 v2(127.5,26.34) 128.18,25.66 128.18,23.93 128.29,23.83 128.29,23.28 128.15,23.14 128.15,22.82 128.23,22.74 128.23,22.56 127.93,22.27 127.93,22.09 128.13,21.89 128.31,21.89 128.6,22.19 128.78,22.19 129.04,21.93 129.22,21.93 129.6,22.31 129.78,22.31 129.98,22.11 129.98,21.93 129.6,21.55 129.6,21.37 129.73,21.24 129.73,20.9 130.28,20.35 130.28,20.22 129.84,19.77 129.84,19.49 130.8,18.53 130.8,18.35 130.31,17.86 130.13,17.86 v2(129.6,18.39)
  IN2 w0.102: 127.2,67.76 128.12,68.67 v2(128.12,69.16)
  IN2 w0.216: 127.2,67.76 127.2,65.56 125.8,64.16 125.54,64.16 125.29,64.41 125.11,64.41 124.85,64.15 124.85,63.97 125.1,63.72 125.1,63.46 124.92,63.28 124.66,63.28 124.3,63.64 124.04,63.64 123.86,63.46 123.86,63.2 124.22,62.84 124.22,62.58 124.04,62.4 123.78,62.4 123.42,62.76 123.16,62.76 122.97,62.58 122.97,62.32 123.34,61.96 123.34,61.7 123.16,61.52 122.9,61.52 122.53,61.88 122.28,61.88 122.09,61.7 122.09,61.44 122.46,61.08 122.46,60.82 122.28,60.64 122.02,60.64 121.65,61 121.4,61 120.38,59.98 120.38,40.49 121.22,39.65 121.22,39.2 121.03,39.02 120.89,39.02 120.71,38.84 120.71,38.58 120.89,38.4 121.03,38.4 121.22,38.21 121.22,37.59 122.39,36.42 122.39,33.69 122.76,33.31 122.76,31.67 125.74,28.7 126.09,28.7 126.5,29.11 126.8,29.11 127.22,28.68 127.22,27.26 127.5,26.98 v2(127.5,26.34)
  BOTTOM w0.102: UC1.AN33 127.53,70.35 127.53,69.59 127.96,69.16 v2(128.12,69.16)
  BOTTOM w0.127: v2(129.6,18.39) 129.6,18.39 JDIMM1.130 ; v2(124.95,32.23) 124.84,32.12 122.71,32.12 121.66,31.06 121.53,31.06 121.4,30.93 JDIMM2.130
DDRAB_SDQ37: length 87.5
  IN1 w0.127: v2(129.6,19.09) 129.6,19 129.33,18.73 129.04,18.73 128.94,18.83 128.94,19.49 129.64,20.2 129.64,20.38 129.42,20.6 129.24,20.6 128.61,19.98 128.43,19.98 128.23,20.17 128.23,20.35 129.03,21.15 129.03,21.33 128.83,21.53 128.65,21.53 127.86,20.73 127.68,20.73 127.48,20.93 127.48,21.11 127.75,21.38 127.75,21.56 127.75,21.66 126.84,22.57 126.84,23.05 127.11,23.32 127.25,23.32 127.37,23.19 v2(127.67,23.19) 127.67,23.37 127.69,23.39 127.69,24.61 124.9,27.4 v2(124.9,31.58)
  IN2 w0.102: v2(128.12,69.77) 127.63,69.28 127.63,68.61 126.68,67.66
  IN2 w0.216: v2(127.67,23.19) 127.75,23.27 127.75,25.51 127.46,25.8 127.38,25.8 126.46,26.73 126.46,27.05 126.05,27.46 126.05,27.65 124.13,29.57 123.87,29.57 123.7,29.41 123.45,29.41 123.26,29.59 123.26,29.85 123.43,30.01 123.43,30.27 123.25,30.45 122.99,30.45 122.82,30.29 122.56,30.29 122.38,30.47 122.38,30.73 122.55,30.89 122.55,31.15 122.24,31.46 122.24,33.1 121.87,33.47 121.87,36.2 119.86,38.21 119.86,60.2 124.96,65.3 125.22,65.3 125.57,64.94 125.83,64.94 126.01,65.12 126.01,65.38 125.66,65.74 125.66,66 125.84,66.18 126.1,66.18 126.24,66.03 126.42,66.03 126.68,66.3 126.68,66.47 126.54,66.62 126.54,66.88 126.68,67.02 126.68,67.66
  BOTTOM w0.102: v2(128.12,69.77) 127.74,70.15 127.74,70.49 127.39,70.84 127.39,71.3 UC1.AN32
  BOTTOM w0.127: JDIMM1.132 130.2,18.99 130.1,19.09 v2(129.6,19.09) ; JDIMM2.132 122,30.8 122.79,31.58 v2(124.9,31.58)
DDRAB_SDQ38: length 91.1
  IN1 w0.127: v2(132.6,18.2) 132.26,17.86 132.08,17.86 131.82,18.11 131.82,18.29 133.72,20.19 133.72,20.37 133.5,20.6 133.32,20.6 131.52,18.79 131.17,18.79 130.47,19.48 130.47,19.66 130.67,19.86 130.85,19.86 131.23,19.48 131.45,19.48 132.56,20.59 132.56,20.77 132.33,21.01 132.15,21.01 131.3,20.16 131.12,20.16 130.93,20.36 130.93,20.54 131.46,21.07 131.46,21.25 131.26,21.45 131.08,21.45 130.54,20.91 130.36,20.91 130.17,21.11 130.17,21.29 130.7,21.83 130.7,22.01 v2(130.4,22.31) 129.98,22.73 129.98,24.08 129.53,24.52 129.53,27.91 127.88,29.56 127.88,32.55 v2(127.59,32.84)
  IN2 w0.102: 131.73,67.57 131.73,69.44 130.48,70.69 v2(130.48,71.3)
  IN2 w0.216: 131.73,67.57 131.73,62.7 131.39,62.36 131.07,62.36 129.95,61.24 129.95,60.95 129.33,60.32 129.33,59.81 128.82,59.3 128.82,40.28 129.09,40.02 129.09,36.67 129.65,36.11 129.65,35.34 130.08,34.91 130.08,30.24 130.47,29.85 130.47,28.27 130.07,27.87 130.07,25.21 130.86,24.41 130.86,22.78 v2(130.4,22.31)
  BOTTOM w0.102: v2(130.48,71.3) 130.38,71.4 130.02,71.4 129.79,71.63 129.79,72.13 129.4,72.52 UC1.AR31
  BOTTOM w0.127: JDIMM2.140 124.4,30.76 124.78,31.14 125.11,31.14 126.1,32.13 126.1,32.19 126.75,32.84 v2(127.59,32.84) ; JDIMM1.140 v2(132.6,18.2)
DDRAB_SDQ39: length 83.9
  IN1 w0.127: v2(129.53,23.33) 129.54,23.33 129.55,23.34 129.55,23.9 129.1,24.35 129.1,26.3 126.85,28.56 v2(126.73,28.56)
  IN2 w0.102: v2(129.69,70.74) 130.14,70.74 131.21,69.67 131.21,67.57
  IN2 w0.216: v2(129.53,23.33) 129.57,23.37 129.57,25.04 129.55,25.07 129.55,28.08 129.95,28.49 129.95,29.63 129.56,30.03 129.56,32.52 129.13,32.94 129.13,35.89 128.57,36.46 128.57,39.8 128.12,40.25 127.49,40.25 127.31,40.43 127.31,40.69 127.49,40.87 128.12,40.87 128.3,41.05 128.3,41.31 128.12,41.49 127.3,41.49 127.17,41.62 127.17,41.99 127.3,42.12 128.12,42.12 128.3,42.3 128.3,42.56 128.12,42.74 126.89,42.74 126.76,42.86 126.76,43.23 126.89,43.36 128.12,43.36 128.3,43.54 128.3,43.8 128.12,43.98 126.92,43.98 126.79,44.11 126.79,44.48 126.92,44.6 128.12,44.6 128.3,44.79 128.3,45.12 128.17,45.25 126.97,45.25 126.84,45.38 126.84,45.74 126.97,45.87 128.17,45.87 128.3,46 128.3,60.03 129.43,61.16 129.43,61.46 130.57,62.6 130.57,63.13 131.21,63.77 131.21,67.57
  BOTTOM w0.102: UC1.AT33 129.37,71.07 v2(129.69,70.74)
  BOTTOM w0.127: v2(126.73,28.56) 126.53,28.75 125.25,28.75 125,29.01 JDIMM2.142 ; JDIMM1.142 133.2,18.24 132.58,18.86 132.4,18.86 132.1,18.56 131.92,18.56 131.73,18.76 131.73,18.94 132.02,19.24 132.02,19.42 131.83,19.61 131.65,19.61 131.35,19.32 131.17,19.32 130.97,19.52 130.97,19.7 131.27,19.99 131.27,20.17 131.11,20.33 130.93,20.33 130.61,20.02 130.43,20.02 130.23,20.22 130.23,20.4 130.42,20.58 130.42,20.76 130.22,20.97 130.04,20.97 129.84,20.78 129.66,20.78 129.46,20.97 129.46,21.15 129.79,21.47 129.79,21.65 129.53,21.91 v2(129.53,23.33)
DDRAB_SDQ40: length 80.9
  IN1 w0.127: v2(129.58,34.12) 130.02,33.69 130.02,32.15 131.52,30.66 v2(131.52,27.93) 131.52,27.61 133.06,26.06 133.06,23.24 132.38,22.55 132.38,22.19 132.51,22.06 133.01,22.06 133.52,21.55 133.7,21.55 133.84,21.7 133.84,21.88 133.48,22.24 133.48,22.48 v2(133.94,22.94)
  IN2 w0.102: v2(130.53,72.99) 130.5,72.96 130.5,72.07 131.59,70.98 131.59,70.33 131.81,70.12 132.24,70.12 132.45,69.9 132.45,68.57 132.77,68.25 132.77,67.57
  IN2 w0.216: v2(131.52,27.93) 131.52,30.28 131.12,30.68 131.12,36.35 130.71,36.75 130.71,37.14 130.9,37.32 131.15,37.32 131.27,37.45 131.27,37.82 131.15,37.95 130.9,37.95 130.71,38.13 130.71,38.39 130.9,38.57 131.13,38.57 131.26,38.7 131.26,39.06 131.13,39.19 130.83,39.19 130.69,39.33 130.69,39.72 130.87,39.91 131.08,39.91 131.26,40.09 131.26,40.35 131.08,40.53 130.05,40.53 129.86,40.71 129.86,41.05 130.05,41.23 131.08,41.23 131.26,41.41 131.26,41.67 131.08,41.85 130.05,41.85 129.86,42.03 129.86,42.29 130.05,42.47 131.08,42.47 131.26,42.66 131.26,42.91 131.08,43.1 130.05,43.1 129.86,43.28 129.86,49.35 130.66,50.15 130.66,58.75 132.77,60.86 132.77,67.57
  BOTTOM w0.102: UC1.AU30 130.49,72.99 v2(130.53,72.99)
  BOTTOM w0.127: JDIMM1.147 134.7,23.7 v2(133.94,22.94) ; JDIMM2.147 126.5,37.13 129.52,34.11 129.57,34.11 v2(129.58,34.12)
DDRAB_SDQ41: length 76.5
  IN1 w0.127: v2(129.61,34.76) 130.45,33.92 130.45,32.69 v2(131.66,31.48) 131.95,31.19 131.95,27.98 v2(133.42,26.5)
  IN2 w0.102: 133.29,67.57 133.29,68.16 132.66,68.8 132.66,70.09 132.24,70.5 v2(132.06,70.5)
  IN2 w0.216: v2(131.66,31.48) 131.66,33.52 132.1,33.96 132.1,36.38 131.79,36.69 131.79,42.89 131.92,43.01 132.26,43.01 132.39,43.14 132.39,43.56 132.26,43.69 130.88,43.69 130.7,43.87 130.7,44.13 130.88,44.31 132.23,44.31 132.35,44.44 132.35,44.8 132.23,44.93 130.88,44.93 130.7,45.11 130.7,45.37 130.88,45.55 132.21,45.55 132.34,45.68 132.34,46.05 132.21,46.17 130.88,46.17 130.7,46.36 130.7,46.61 130.88,46.8 132.2,46.8 132.33,46.92 132.33,47.29 132.2,47.42 130.88,47.42 130.7,47.6 130.7,47.86 130.88,48.04 132.21,48.04 132.34,48.17 132.34,48.54 132.21,48.66 130.88,48.66 130.7,48.85 130.7,49.1 130.88,49.29 132.21,49.29 132.34,49.41 132.34,49.78 132.21,49.91 131.42,49.91 131.18,50.15 131.18,58.53 133.29,60.64 133.29,67.57
  BOTTOM w0.102: UC1.AV32 131.34,71.74 131.34,70.92 131.46,70.8 131.46,70.79 131.75,70.5 v2(132.06,70.5)
  BOTTOM w0.127: v2(133.42,26.5) 134.26,26.5 134.62,26.14 134.99,26.14 135.3,25.83 JDIMM1.149 ; JDIMM2.149 127.1,37.14 129.5,34.75 129.6,34.75 v2(129.61,34.76)
DDRAB_SDQ42: length 82
  TOP w0.127: v2(136.26,22.68) 136.26,23.03 135.79,23.5 135.79,23.68 136.12,24.01 136.12,24.19 135.93,24.39 135.75,24.39 135.15,23.79 134.97,23.79 134.77,23.99 134.77,24.17 135.37,24.77 135.37,24.95 135.18,25.15 135,25.15 v1(134.84,24.99) 134.66,24.81 134.48,24.81 134.27,25.02 134.27,25.27 134.55,25.56 134.55,25.77 134.27,26.06 134.27,27.7 v2(134.4,27.83) 134.49,27.91 134.49,30.06 133.75,30.79 133.75,33.14 131.9,34.99 v2(131.64,34.99)
  IN2 w0.216: v2(134.87,70.29) 136.24,68.92 136.24,57.04 136.11,56.91 135.74,56.91 135.62,56.78 135.62,56.31 135.74,56.18 136.11,56.18 136.24,56.06 136.24,55.02 136.11,54.89 136.11,52.18 135.98,52.05 135.01,52.05 134.88,51.93 134.88,51.56 135.01,51.43 135.98,51.43 136.11,51.3 136.11,50.96 135.93,50.77 135.6,50.77 135.41,50.59 135.41,50.33 135.6,50.15 135.93,50.15 136.11,49.97 136.11,49.71 135.93,49.53 135.6,49.53 135.41,49.35 135.41,49.09 135.6,48.91 135.93,48.91 136.11,48.72 136.11,48.47 135.93,48.28 135.6,48.28 135.41,48.1 135.41,47.84 135.6,47.66 135.93,47.66 136.11,47.48 136.11,47.22 135.93,47.04 135.6,47.04 135.41,46.86 135.41,46.6 135.6,46.42 135.93,46.42 136.11,46.23 136.11,45.98 135.93,45.79 135.6,45.79 135.41,45.61 135.41,40.53 135.64,40.31 135.64,39.23 136.25,38.61 136.25,35.98 135.69,35.42 135.69,34.08 135.88,33.9 136.21,33.9 136.34,33.77 136.34,33.4 136.21,33.28 135.88,33.28 135.76,33.15 135.76,30.98 135.88,30.85 136.25,30.85 136.37,30.73 136.37,30.36 136.25,30.23 135.19,30.23 135.06,30.1 135.06,29.73 135.19,29.6 135.39,29.6 135.52,29.48 135.52,28.14 135.2,27.83 v2(134.4,27.83)
  BOTTOM w0.102: v2(134.87,70.29) 134.74,70.43 133.93,70.43 133.44,70.92 UC1.BA33
  BOTTOM w0.127: v2(131.64,34.99) 131.5,34.99 129.5,36.99 JDIMM2.157 ; v2(136.26,22.68) 136.55,22.97 136.55,23.52 136.83,23.8 137.46,23.8 137.7,24.04 JDIMM1.157
DDRAB_SDQ43: length 80.8
  TOP w0.127: v2(134.02,28.28) 134.02,29.92 v1(133.65,30.28) 132.62,31.31 132.62,31.93 132.11,32.44 132.11,34.17 131.76,34.52 131.46,34.52 131.2,34.79 131.2,35.23 131.56,35.59 v2(131.66,35.59)
  IN2 w0.102: 135.72,67.57 135.72,68.9 134.01,70.61 133.46,70.61 132.06,72.01 v2(132.06,72.14)
  IN2 w0.127: v2(134.02,28.28) 133.9,28.17 133.9,27.31 134.28,26.93 134.28,24.56 134.85,24 134.85,22.36 135.18,22.02 137.06,22.02 v2(137.1,22.06)
  IN2 w0.216: 135.72,67.57 135.72,59.03 135.41,58.72 134.82,58.72 134.64,58.54 134.64,58.28 134.82,58.1 135.59,58.1 135.72,57.97 135.72,57.56 135.59,57.43 133.88,57.43 133.7,57.25 133.7,56.99 133.88,56.81 134.97,56.81 135.1,56.68 135.1,56.31 134.97,56.19 133.88,56.19 133.7,56 133.7,55.75 133.88,55.56 135.41,55.56 135.59,55.38 135.59,54.5 135.52,54.43 135.52,53.05 135.09,52.62 134.22,52.62 134.09,52.49 134.09,51.61 134.89,50.82 134.89,40.32 135.12,40.09 135.12,38.44 135.3,38.26 135.45,38.26 135.58,38.13 135.58,37.76 135.45,37.64 135.3,37.64 135.12,37.46 135.12,30.9 134.02,29.8 v2(134.02,28.28)
  BOTTOM w0.102: UC1.AY32 132.55,72.14 v2(132.06,72.14)
  BOTTOM w0.127: v2(131.66,35.59) 131.56,35.59 130.1,37.05 JDIMM2.159 ; JDIMM1.159 138.3,24.02 137.97,23.69 137.97,23.16 137.1,22.29 v2(137.1,22.06)
DDRAB_SDQ44: length 82.9
  IN1 w0.127: v2(131.74,21.59) 131.74,22.53 132.63,23.42 132.63,24.06 132.51,24.18 131.81,24.18 131.68,24.31 131.68,24.59 131.81,24.72 132.51,24.72 132.63,24.84 132.63,25.18 132.51,25.31 131.27,25.31 130.94,25.65 130.94,26.93 v2(131.13,27.13) 131.02,27.24 131.02,30.54 129.59,31.97 v2(129.59,33.44)
  IN2 w0.102: v2(131.99,69.72) 132.25,69.46 132.25,67.57
  IN2 w0.216: v2(131.13,27.13) 131,27.27 131,30.06 130.6,30.46 130.6,35.12 130.19,35.53 130.19,37.03 129.91,37.31 129.74,37.31 129.61,37.44 129.61,37.82 129.74,37.95 130.07,37.95 130.19,38.07 130.19,38.44 130.07,38.57 129.74,38.57 129.61,38.7 129.61,39.14 129.97,39.51 129.97,39.87 129.34,40.5 129.34,50.47 129.53,50.65 129.91,50.65 130.09,50.84 130.09,51.09 129.91,51.28 129.53,51.28 129.34,51.46 129.34,51.72 129.53,51.9 129.91,51.9 130.09,52.08 130.09,52.34 129.91,52.52 129.53,52.52 129.34,52.7 129.34,52.96 129.53,53.14 129.91,53.14 130.09,53.33 130.09,53.58 129.91,53.77 129.53,53.77 129.34,53.95 129.34,54.21 129.53,54.39 129.91,54.39 130.09,54.57 130.09,54.83 129.91,55.01 129.53,55.01 129.34,55.19 129.34,55.45 129.53,55.63 129.91,55.63 130.09,55.81 130.09,56.07 129.91,56.25 129.53,56.25 129.34,56.44 129.34,58.93 129.83,59.42 130.09,59.42 130.21,59.3 130.46,59.3 130.65,59.48 130.65,59.74 130.28,60.11 130.28,60.29 131.02,61.03 131.2,61.03 131.61,60.62 131.79,60.62 132.05,60.88 132.05,61.06 131.89,61.22 131.89,61.48 132.25,61.84 132.25,67.57
  BOTTOM w0.102: v2(131.99,69.72) 131.37,69.72 130.52,70.57 130.52,70.57 130.3,70.79 130.29,70.79 130.17,70.92 UC1.AU33
  BOTTOM w0.127: JDIMM1.146 134.4,17.65 131.74,20.31 v2(131.74,21.59) ; JDIMM2.146 126.2,30.93 127.01,31.74 127.12,31.74 128.81,33.43 129.58,33.43 v2(129.59,33.44)
DDRAB_SDQ45: length 78.8
  IN1 w0.127: v2(130.51,27.13) 130.51,25.47 131.25,24.73 131.25,23.41 v2(131.44,23.22)
  IN2 w0.102: 133.81,67.57 133.81,67.93 132.86,68.89 132.86,70.64 131.96,71.53 131.48,71.53 130.98,72.03 v2(130.98,72.64)
  IN2 w0.216: v2(131.44,23.22) 131.44,25.13 131.59,25.29 131.91,25.29 132.04,25.41 132.04,25.79 131.91,25.91 130.83,25.91 130.7,26.04 130.7,26.41 130.83,26.54 131.85,26.54 132.04,26.72 132.04,31.12 132.18,31.26 132.18,33.31 132.62,33.75 132.62,36.6 132.31,36.9 132.31,42.27 132.98,42.93 132.98,50.02 132.57,50.43 131.89,50.43 131.7,50.62 131.7,58.31 133.81,60.43 133.81,67.57
  BOTTOM w0.102: v2(130.98,72.64) 130.9,72.56 130.2,72.56 UC1.AU31
  BOTTOM w0.127: JDIMM1.148 135,17.66 132.26,20.41 132.26,22.07 132.57,22.38 132.57,22.56 132.42,22.71 132.11,22.71 130.77,21.37 130.52,21.37 130.37,21.52 130.37,21.73 130.79,22.14 130.79,22.53 131.44,23.18 v2(131.44,23.22) ; JDIMM2.148 126.8,29.1 127.13,28.77 128.72,28.77 129.24,28.24 129.5,28.24 130.11,27.63 130.11,27.52 v2(130.51,27.13)
DDRAB_SDQ46: length 83.2
  IN1 w0.127: v2(135.34,22.56) 135.71,22.56 135.86,22.71 135.86,25.82 v2(135.11,26.57)
  IN2 w0.102: v2(132.16,72.92) 132.76,72.32 133.21,72.32 133.28,72.39 133.76,72.39 133.97,72.18 134.39,71.75 135.27,71.75
  IN2 w0.216: 135.27,71.75 137.36,69.66 137.36,54.66 137.15,54.46 137.15,43.04 137.32,42.88 137.32,39.34 137.54,39.12 137.54,33.04 138.23,32.35 138.23,25.32 135.46,22.56 v2(135.34,22.56)
  BOTTOM w0.102: UC1.AW31 131.77,72.52 v2(132.16,72.92)
  BOTTOM w0.127: JDIMM2.158 129.8,29.03 130.49,28.35 131.65,28.35 133.07,26.93 134.44,26.93 134.8,26.57 135.11,26.57 v2(135.11,26.57) ; JDIMM1.158 138,18.23 137.83,18.4 137.69,18.4 137.55,18.26 137.37,18.26 137.17,18.46 137.17,18.64 137.58,19.05 137.58,19.23 137.39,19.43 137.21,19.43 136.78,18.99 136.6,18.99 136.4,19.19 136.4,19.37 136.86,19.83 136.86,20.01 136.66,20.21 136.48,20.21 135.44,19.17 135.26,19.17 135.06,19.36 135.06,19.54 136.1,20.58 136.1,20.76 135.91,20.96 135.73,20.96 134.9,20.13 134.72,20.13 134.52,20.33 134.52,20.51 135.28,21.27 135.28,21.44 134.98,21.74 134.98,22.2 v2(135.34,22.56)
DDRAB_SDQ47: length 80.2
  IN1 w0.127: v2(135.43,23.19) 135.43,25.62 134.68,26.37 v2(134.68,27.3)
  IN2 w0.216: v2(135.43,23.19) 135.43,23.41 137.71,25.69 137.71,32.13 137.02,32.82 137.02,38.81 136.8,39.03 136.8,40.61 136.67,40.74 136.15,40.74 135.97,40.92 135.97,41.18 136.15,41.36 136.67,41.36 136.8,41.48 136.8,41.85 136.67,41.98 136.15,41.98 135.97,42.16 135.97,42.42 136.15,42.6 136.51,42.6 136.63,42.73 136.63,43.1 136.51,43.22 136.06,43.22 135.93,43.35 135.93,43.72 136.06,43.85 136.45,43.85 136.63,44.03 136.63,44.29 136.45,44.47 136.06,44.47 135.93,44.6 135.93,44.96 136.06,45.09 136.45,45.09 136.63,45.27 136.63,54.67 136.76,54.8 136.76,69.52 134.87,71.42 v2(133.63,71.42)
  BOTTOM w0.102: v2(133.63,71.42) 133.53,71.32 UC1.AY33
  BOTTOM w0.127: v2(134.68,27.3) 134.61,27.37 133.25,27.37 131.83,28.78 130.66,28.78 130.4,29.04 JDIMM2.160 ; JDIMM1.160 138.6,17.87 138.68,17.95 139.24,17.95 139.34,18.05 139.34,18.29 139.24,18.39 138.45,18.39 138.07,18.77 138.07,19.13 138.65,19.71 138.65,19.89 138.45,20.09 138.27,20.09 137.9,19.72 137.7,19.72 137.5,19.92 137.5,20.08 137.94,20.51 137.94,20.69 137.74,20.89 137.56,20.89 137.16,20.49 136.98,20.49 135.52,21.96 135.52,22.12 135.77,22.38 135.77,22.89 135.9,23.01 135.9,23.18 135.72,23.36 135.59,23.36 v2(135.43,23.19)
DDRAB_SDQ48: length 78.9
  TOP w0.127: v2(131.65,36.21) 131.74,36.21 v1(132.64,35.31) 134.18,33.77 134.18,31.82 134.55,31.45 134.55,30.6 135.03,30.12 v2(135.03,28.63) 135.03,27.64 135.07,27.6 135.07,27.14 134.7,26.77 134.7,26.23 136.71,24.23 136.71,23.15 137.41,22.45 v2(137.9,22.45)
  IN1 w0.102: v2(134.17,72.52) 133.6,72.52 133.25,72.17 133.25,71.59 133.03,71.36 132.44,70.77 132.44,69.63 130.82,68.01 130.82,67.57
  IN1 w0.216: v2(135.03,28.63) 134.77,28.89 133.07,28.89 132.94,29.02 132.94,29.4 133.07,29.53 134.18,29.53 134.31,29.66 134.31,30.02 134.18,30.15 133.07,30.15 132.94,30.28 132.94,31.86 132.08,32.72 132.08,34.3 131.83,34.54 131.45,34.54 130.98,35.01 130.98,35.91 130.8,36.09 129.21,36.09 129.03,36.28 129.03,36.53 129.21,36.72 130.8,36.72 130.98,36.9 130.98,37.22 130.8,37.4 130.48,37.4 130.3,37.59 130.3,37.84 130.48,38.03 130.8,38.03 130.98,38.21 130.98,59.44 130.82,59.59 130.82,67.57
  BOTTOM w0.102: UC1.BC31 134.87,72.52 v2(134.17,72.52)
  BOTTOM w0.127: v2(137.9,22.45) 138.04,22.45 139.5,23.91 JDIMM1.163 ; v2(131.65,36.21) 131.6,36.21 131.15,36.66 131.15,36.98 131.3,37.13 JDIMM2.163
DDRAB_SDQ49: length 79.5
  TOP w0.127: v2(135.5,27.08) v1(135.5,29.59) 135.5,30.26 134.98,30.78 134.98,31.63 134.61,32 v2(134.61,32.21)
  IN1 w0.102: 132.38,68.48 132.38,68.95 132.64,69.21 132.64,69.89 134.04,71.29 134.04,71.57 v2(133.63,71.98)
  IN1 w0.216: 132.38,68.48 132.38,68.08 132.2,67.9 131.56,67.9 131.37,67.72 131.37,67.46 131.56,67.28 132.2,67.28 132.38,67.09 132.38,66.84 132.2,66.65 131.56,66.65 131.37,66.47 131.37,66.22 131.56,66.03 132.2,66.03 132.38,65.85 132.38,65.59 132.2,65.41 131.56,65.41 131.37,65.23 131.37,64.97 131.56,64.79 132.2,64.79 132.38,64.61 132.38,64.35 132.2,64.17 131.47,64.17 131.34,64.04 131.34,63.67 131.47,63.54 132.2,63.54 132.38,63.36 132.38,62.76 132.2,62.58 131.56,62.58 131.37,62.4 131.37,62.14 131.56,61.96 132.2,61.96 132.38,61.78 132.38,61.3 132.2,61.11 131.56,61.11 131.37,60.93 131.37,60.67 131.56,60.49 131.91,60.49 132.04,60.37 132.04,59.86 131.91,59.73 131.64,59.73 131.51,59.6 131.51,37.15 132.23,36.44 132.23,34.89 132.6,34.51 132.6,34.17 133.76,33.01 133.76,31.92 133.72,31.88 133.72,30.98 133.85,30.85 134.49,30.85 134.61,30.98 v2(134.61,32.21)
  BOTTOM w0.102: v2(133.63,71.98) 133.79,72.13 133.79,73.34 UC1.BB30
  BOTTOM w0.127: v2(134.61,32.21) 134.61,33.86 133.77,34.7 133.59,34.7 132.47,33.58 132.29,33.58 132.09,33.78 132.09,33.96 133.21,35.08 133.21,35.26 133.01,35.46 132.83,35.46 132.49,35.12 132.31,35.12 132.12,35.32 132.12,35.49 132.46,35.84 132.46,36.02 131.9,36.57 JDIMM2.165 ; JDIMM1.165 140.1,25.87 139.51,26.46 137.37,26.46 136.58,27.24 135.67,27.24 v2(135.5,27.08)
DDRAB_SDQ50: length 79.6
  IN1 w0.102: v2(133.86,75.52) 133.86,74.95 134.28,74.52 135.83,74.52 136.56,73.79 136.56,67.57
  IN1 w0.216: 136.56,67.57 136.51,67.52 136.51,54.91 136.37,54.78 136.37,46.51 136.02,46.16 136.02,45.89 136.37,45.54 136.37,45.21 136.19,45.02 135.75,45.02 135.57,44.84 135.57,44.58 135.75,44.4 136.19,44.4 136.37,44.22 136.37,43.96 136.19,43.78 135.75,43.78 135.55,43.58 135.55,40.97 135.89,40.63 135.89,38.75 139.49,35.15 139.49,29.84 140.26,29.06 140.26,28.3 139.87,27.9 v2(139.74,27.9)
  IN2 w0.127: v2(138.45,33.67) 138.45,33.41 140.07,31.79 140.07,28.23 v2(139.74,27.9) 139.74,25.68 140.17,25.25 140.17,25.07 139.68,24.59 139.68,24.41 139.88,24.21 140.06,24.21 141.05,25.2 141.23,25.2 141.37,25.05 141.37,24.87 140.69,24.19 140.69,24.01 140.89,23.81 141.07,23.81 141.64,24.38 141.82,24.38 142.06,24.14 142.06,23.96 141.81,23.71 141.81,23.61 v2(142.12,23.3)
  BOTTOM w0.102: v2(133.86,75.52) 133.87,75.51 UC1.BB28
  BOTTOM w0.127: v2(142.12,23.3) 142.39,23.3 143.1,24.02 JDIMM1.175 ; v2(138.45,33.67) 134.9,37.22 JDIMM2.175
DDRAB_SDQ51: length 79.3
  IN1 w0.102: v2(133.07,74.62) 133.37,74.32 135.74,74.32 136.31,73.75 136.31,68.45 135.98,68.13 135.98,67.57
  IN1 w0.216: 135.98,67.57 135.98,55.13 135.85,54.99 135.85,49.67 135.67,49.48 135.21,49.48 135.03,49.3 135.03,49.04 135.21,48.86 135.67,48.86 135.85,48.68 135.85,48.42 135.67,48.24 135.21,48.24 135.03,48.06 135.03,47.8 135.21,47.62 135.67,47.62 135.85,47.43 135.85,47.18 135.67,46.99 135.21,46.99 135.03,46.81 135.03,46.55 135.21,46.37 135.34,46.37 135.46,46.25 135.46,45.88 135.34,45.75 135.21,45.75 135.03,45.57 135.03,40.75 135.37,40.42 135.37,38.53 138.93,34.97 138.93,29.66 139.64,28.95 v2(139.64,28.55)
  IN2 w0.127: v2(138.47,34.28) 138.02,33.83 138.02,33.24 139.64,31.61 v2(139.64,28.55) 139.25,28.16 139.25,24.16 139.86,23.54 140.04,23.54 140.19,23.68 140.37,23.68 140.57,23.49 140.57,23.31 140.42,23.16 140.42,22.98 140.75,22.66 v2(142.03,22.66)
  BOTTOM w0.102: UC1.AY27 133.07,75.42 v2(133.07,74.62)
  BOTTOM w0.127: JDIMM1.177 143.7,23.92 142.44,22.66 v2(142.03,22.66) ; v2(138.47,34.28) 135.5,37.24 JDIMM2.177
DDRAB_SDQ52: length 80.8
  IN1 w0.102: 132.9,67.57 132.9,68.67 133.07,68.85 134.05,68.85 v2(134.5,69.29)
  IN1 w0.127: v2(139.8,18.25) 139.44,18.61 139.44,20.31 139.09,20.66 138.91,20.66 138.75,20.5 138.57,20.5 138.37,20.7 138.37,20.88 138.53,21.04 138.53,21.22 138.33,21.41 138.15,21.41 137.82,21.09 137.64,21.09 137.45,21.28 137.45,21.46 137.77,21.79 137.77,21.97 136.42,23.33 136.42,24.23 136.54,24.36 136.57,24.36 136.7,24.48 136.7,24.76 136.57,24.89 136.48,24.89 136.35,25.02 136.35,25.3 136.48,25.42 136.57,25.42 136.7,25.55 136.7,25.83 136.57,25.96 136.54,25.96 136.42,26.08 v2(136.42,26.85)
  IN1 w0.216: v2(136.42,26.85) 135.53,27.74 135.53,28.89 135.13,29.29 135.13,32.58 133.11,34.6 133.12,34.6 133.12,34.73 132.9,34.95 132.9,36.5 132.06,37.34 132.06,53.97 132.24,54.15 132.72,54.15 132.9,54.33 132.9,54.59 132.72,54.77 132.24,54.77 132.06,54.95 132.06,55.21 132.24,55.39 132.72,55.39 132.9,55.58 132.9,55.83 132.72,56.02 132.24,56.02 132.06,56.2 132.06,56.46 132.24,56.64 132.72,56.64 132.9,56.82 132.9,57.08 132.72,57.26 132.24,57.26 132.06,57.44 132.06,57.7 132.24,57.88 132.72,57.88 132.9,58.07 132.9,58.32 132.72,58.51 132.24,58.51 132.06,58.69 132.06,58.95 132.24,59.13 132.72,59.13 132.9,59.31 132.9,67.57
  IN2 w0.127: v2(136.42,26.85) 136.86,27.29 136.86,31.88 136.26,32.48 v2(136.23,32.48)
  BOTTOM w0.102: UC1.BB32 134.36,71.82 135.36,70.81 135.36,70.16 134.51,69.3 134.51,69.29 v2(134.5,69.29)
  BOTTOM w0.127: v2(136.23,32.48) 135.49,32.48 134.74,31.72 132.57,31.72 131.6,30.76 JDIMM2.164 ; v2(139.8,18.25) JDIMM1.164
DDRAB_SDQ53: length 77.3
  IN1 w0.102: v2(132.87,71.74) 131.72,71.74 131.53,71.55 131.53,69.25 130.3,68.03 130.3,67.57
  IN1 w0.216: 130.3,67.57 130.3,59.38 130.46,59.22 130.46,38.79 128.5,36.83 128.5,35.61 128.63,35.49 129.75,35.49 131.1,34.14 131.1,32.97 132.42,31.64 132.42,28.17 133.29,27.3 133.81,27.3 134.2,26.92 134.2,24.24 134.55,23.89 134.55,22.11 v2(134.5,22.06)
  IN2 w0.127: v2(133.43,27.8) 133.43,27.17 133.85,26.75 133.85,24.38 134.42,23.82 134.42,22.14 v2(134.5,22.06) 135.34,21.22 135.52,21.22 135.86,21.57 136.04,21.57 136.24,21.37 136.24,21.19 135.9,20.85 135.9,20.67 136.09,20.47 136.27,20.47 136.68,20.87 136.86,20.87 137.05,20.67 137.05,20.49 136.65,20.09 136.65,19.91 136.9,19.66 139.08,19.66 v2(139.83,18.91)
  BOTTOM w0.102: UC1.BA31 133.03,72.18 133.03,71.9 v2(132.87,71.74)
  BOTTOM w0.127: v2(133.43,27.8) 133.08,28.14 132.2,29.02 JDIMM2.166 ; v2(139.83,18.91) 140.4,18.34 JDIMM1.166
DDRAB_SDQ54: length 82.4
  TOP w0.127: v2(139.53,23.32) 139.53,23.89 v1(139.11,24.31) 137.3,26.12 137.3,30.48 136.95,30.82 136.95,31.18 v2(136.25,31.88)
  IN1 w0.102: v2(135.59,73.94) 136.11,73.42 136.11,68.93 135.46,68.29 135.46,67.57
  IN1 w0.216: 135.46,67.57 135.46,58.15 135.33,58.02 135.33,50.47 134.51,49.65 134.51,40.54 134.85,40.2 134.85,38.31 137.97,35.19 137.97,32.34 138.4,31.91 138.4,29.45 138.54,29.32 138.54,28.41 139.12,27.83 139.12,24.54 139.55,24.1 139.55,23.34 v2(139.53,23.32)
  BOTTOM w0.102: UC1.BC29 135.3,74.22 v2(135.59,73.94)
  BOTTOM w0.127: v2(139.53,23.32) 139.52,23.32 138.88,22.68 138.88,22.5 140.25,21.12 140.25,20.94 140.05,20.74 139.87,20.74 138.5,22.12 138.32,22.12 138.16,21.96 138.16,21.69 139.94,19.91 140.2,19.91 141.34,18.76 141.6,18.76 141.72,18.63 141.72,18.22 141.85,18.1 142.13,18.1 142.26,18.22 142.26,18.67 142.39,18.8 142.67,18.8 142.8,18.67 JDIMM1.174 ; JDIMM2.174 134.6,30.97 135.51,31.88 v2(136.25,31.88)
DDRAB_SDQ55: length 82.5
  TOP w0.127: v2(139.55,22.54) 138.91,23.19 138.91,23.86 136.87,25.9 v1(136.87,28.26) 136.87,30.3 136.22,30.94 v2(136.22,31.3)
  IN1 w0.102: 134.81,67.57 134.81,67.95 135.76,68.9 135.76,72.73 v2(135.73,72.77)
  IN1 w0.216: v2(139.55,22.54) 138.97,23.13 138.97,23.76 138.59,24.14 138.59,27.62 138.02,28.2 138.02,29.1 137.88,29.23 137.88,31.69 137.45,32.12 137.45,34.97 134.33,38.1 134.33,39.79 133.97,40.15 133.97,49.85 134.81,50.69 134.81,67.57
  BOTTOM w0.102: v2(135.73,72.77) 135.73,73.08 134.59,74.22 UC1.BB29
  BOTTOM w0.127: JDIMM2.176 135.2,30.87 135.63,31.3 v2(136.22,31.3) ; JDIMM1.176 143.4,18.91 143.27,19.04 143.07,19.04 142.94,19.17 142.94,19.44 143.07,19.57 143.27,19.57 143.4,19.7 143.4,20.02 143.3,20.12 142.58,20.12 142.37,19.9 142.37,19.72 142.48,19.61 142.48,19.43 142.28,19.24 142.1,19.24 141.99,19.35 141.81,19.35 141.7,19.24 141.52,19.24 141.33,19.44 141.33,19.62 142.19,20.48 142.19,20.66 142,20.86 141.82,20.86 140.88,19.93 140.79,19.93 140.56,20.16 140.56,20.31 141.09,20.84 141.09,21.01 140.06,22.03 140.06,22.71 139.93,22.83 139.68,22.83 139.55,22.71 v2(139.55,22.54)
DDRAB_SDQ56: length 84.8
  IN1 w0.216: v2(135.81,75.76) 135.93,75.64 135.93,75.63 137.6,73.96 137.6,54.53 137.41,54.35 137.41,42.89 137.24,42.72 136.78,42.72 136.59,42.54 136.59,42.28 136.78,42.1 139.65,42.1 139.78,41.97 139.78,41.61 139.65,41.48 137.14,41.48 137.01,41.35 137.01,40.93 137.14,40.81 139.65,40.81 139.78,40.68 139.78,40.1 139.65,39.98 137.54,39.98 137.41,39.85 137.41,39.23 137.68,38.96 139.65,38.96 139.78,38.84 139.78,38.42 139.65,38.29 138.55,38.29 138.37,38.11 138.37,37.85 138.55,37.67 140.35,37.67 140.53,37.49 140.53,37.14 140.35,36.96 139.8,36.96 139.62,36.77 139.62,36.52 139.8,36.33 140.35,36.33 140.53,36.15 v2(140.53,32.58)
  IN2 w0.127: v2(141.94,26.85) 141.08,27.71 141.08,29.22 140.53,29.77 v2(140.53,32.58)
  BOTTOM w0.102: v2(135.81,75.76) 135.56,75.76 135.18,76.14 134.96,76.14 134.88,76.07 134.51,76.07 UC1.BB27
  BOTTOM w0.127: v2(141.94,26.85) 143.96,26.85 144.9,25.91 JDIMM1.181 ; v2(140.53,32.58) 140.52,32.56 138.3,32.56 138.17,32.69 138.17,33.05 138.3,33.17 138.87,33.17 138.95,33.26 138.95,34.42 138.41,34.96 138.41,35.14 138.52,35.25 138.52,35.43 138.32,35.62 138.14,35.62 138.04,35.52 137.86,35.52 137.66,35.71 137.66,35.89 137.76,36 137.76,36.18 137.57,36.38 137.39,36.38 137.28,36.27 137.1,36.27 136.9,36.47 136.9,36.65 137.01,36.75 137.01,36.93 136.7,37.24 JDIMM2.181
DDRAB_SDQ57: length 84.5
  IN1 w0.216: v2(135.55,77.01) 135.55,76.9 136.49,75.96 137.08,75.96 138.64,74.4 138.64,54.1 138.45,53.92 138.45,48.53 138.64,48.35 139.64,48.35 139.77,48.22 139.77,47.85 139.64,47.72 138.64,47.72 138.45,47.54 138.45,47.18 138.58,47.06 140.59,47.06 140.77,46.87 140.77,46.62 140.59,46.43 138.58,46.43 138.45,46.31 138.45,45.88 138.59,45.75 140.69,45.75 140.82,45.62 140.82,45.21 140.69,45.08 138.67,45.08 138.49,44.9 138.49,44.64 138.67,44.46 140.64,44.46 140.82,44.28 140.82,44.02 140.64,43.84 138.67,43.84 138.49,43.65 138.49,43.4 138.67,43.21 140.64,43.21 140.82,43.03 140.82,39 141.57,38.25 v2(141.57,32.73)
  IN2 w0.127: v2(145.48,26.94) 145.48,28.82 v2(141.57,32.73)
  BOTTOM w0.102: UC1.BB26 133.87,76.65 134.19,76.97 135.51,76.97 v2(135.55,77.01)
  BOTTOM w0.127: v2(141.57,32.73) 141.19,33.11 140.69,33.11 140.56,33.24 140.56,33.38 140.43,33.5 140.15,33.5 140.03,33.38 140.03,33.13 139.9,33.01 139.62,33.01 139.49,33.13 139.49,34.25 139.87,34.63 139.87,34.81 139.67,35.02 139.49,35.02 139.34,34.87 139.16,34.87 138.96,35.07 138.96,35.25 139.05,35.33 139.05,35.51 137.3,37.25 JDIMM2.183 ; v2(145.48,26.94) 145.5,26.92 JDIMM1.183
DDRAB_SDQ58: length 82.9
  IN1 w0.216: v2(145.36,32.12) 146.2,32.12 146.81,32.73 146.81,40.94 146.62,41.12 144.84,41.12 144.66,41.31 144.66,41.56 144.84,41.75 146.62,41.75 146.81,41.93 146.81,42.19 146.62,42.37 144.84,42.37 144.63,42.58 144.63,42.88 144.81,43.07 145.56,43.07 145.74,43.25 145.74,43.51 145.56,43.69 144.81,43.69 144.63,43.87 144.63,54.16 142.11,56.68 142.11,76.46 138.32,80.25 135.62,80.25 v2(134.68,79.32)
  IN2 w0.127: v2(148.41,27.36) 148.41,28.4 146.29,30.51 146.11,30.51 146.07,30.47 145.89,30.47 145.69,30.67 145.69,30.85 145.73,30.89 145.73,31.07 145.36,31.45 v2(145.36,32.12) 145.36,32.17 144.82,32.7 144.82,32.7 143.16,34.37 v2(142.65,34.37)
  BOTTOM w0.102: UC1.BB24 134.09,78.22 134.68,78.81 v2(134.68,79.32)
  BOTTOM w0.127: JDIMM1.191 147.9,26.85 v2(148.41,27.36) ; v2(142.65,34.37) 142.23,34.37 140.84,35.76 140.84,36.09 139.7,37.23 JDIMM2.191
DDRAB_SDQ59: length 82.8
  IN1 w0.216: v2(145.85,32.6) 146.28,33.03 146.28,34.88 146.1,35.06 145.4,35.06 145.22,35.24 145.22,35.5 145.4,35.68 146.1,35.68 146.28,35.86 146.28,36.12 146.1,36.3 145.4,36.3 145.22,36.48 145.22,36.74 145.4,36.92 146.1,36.92 146.28,37.11 146.28,37.36 146.1,37.55 145.4,37.55 145.22,37.73 145.22,37.99 145.4,38.17 146.1,38.17 146.28,38.35 146.28,38.61 146.1,38.79 145.4,38.79 145.22,38.97 145.22,39.23 145.4,39.41 146.1,39.41 146.28,39.6 146.28,40.37 146.16,40.5 144.23,40.5 144.11,40.63 144.11,53.95 141.59,56.46 141.59,76.24 138.11,79.73 135.81,79.73 134.7,78.62 v2(133.07,78.62)
  IN2 w0.127: v2(148.47,26.68) 148.85,27.06 148.85,28.65 145.85,31.65 v2(145.85,32.6) 145.59,32.87 145.27,32.87 143.88,34.26 143.88,34.44 143.98,34.53 143.98,34.71 143.78,34.91 143.6,34.91 143.5,34.81 143.32,34.81 143.19,34.95 v2(142.59,34.95)
  BOTTOM w0.102: UC1.AY23 v2(133.07,78.62)
  BOTTOM w0.127: v2(142.59,34.95) 142.35,34.95 141.32,35.98 141.32,36.22 140.3,37.24 JDIMM2.193 ; v2(148.47,26.68) 148.5,26.65 JDIMM1.193
DDRAB_SDQ60: length 88.6
  IN1 w0.216: v2(143.64,23.2) 141.5,25.35 141.5,27.6 141.48,27.61 141.48,31.36 141.05,31.79 141.05,37.94 140.3,38.7 140.3,42.49 140.17,42.62 138.06,42.62 137.93,42.75 137.93,54.13 138.12,54.32 138.12,74.18 v2(137.92,74.37)
  IN2 w0.127: v2(141.95,27.47) 142.42,27.01 142.42,26.18 143.64,24.96 v2(143.64,23.2)
  BOTTOM w0.102: UC1.BA27 133.92,76.27 134.8,76.27 134.87,76.34 135.77,76.34 136.19,75.92 136.19,74.94 136.76,74.37 136.98,74.37
  BOTTOM w0.127: JDIMM1.180 144.6,17.97 144.47,18.1 143.96,18.1 143.83,18.22 143.83,18.5 143.96,18.63 145.67,18.63 145.8,18.76 145.8,19.09 145.67,19.22 143.96,19.22 143.83,19.34 143.83,19.62 143.96,19.75 144.35,19.75 144.48,19.88 144.48,20.09 144.35,20.22 143.96,20.22 143.83,20.35 143.83,20.47 143.59,20.71 142.72,20.71 142.59,20.84 142.59,21.12 142.72,21.25 143.36,21.25 143.49,21.37 143.49,21.65 143.36,21.78 142.73,21.78 142.6,21.91 142.6,22.19 142.73,22.31 143.12,22.31 143.25,22.44 143.25,22.86 143.59,23.2 v2(143.64,23.2) ; JDIMM2.180 136.4,28.91 138.42,26.89 140.67,26.89 141.26,27.47 v2(141.95,27.47)
  BOTTOM w0.196: 136.98,74.37 v2(137.92,74.37)
DDRAB_SDQ61: length 87
  IN1 w0.216: v2(135.8,75.02) 137.08,73.75 137.08,54.75 136.89,54.56 136.89,43.39 136.78,43.28 136.33,43.28 136.07,43.02 136.07,41.19 136.45,40.81 136.45,40.33 136.89,39.89 136.89,38.48 140.01,35.36 140.01,30.05 140.96,29.1 140.96,26.1 140.78,25.92 139.92,25.92 139.79,25.8 139.79,25.43 139.92,25.3 140.78,25.3 140.96,25.12 140.96,24.03 141.17,23.83 142.27,23.83 142.66,23.44 142.66,22.54 142.79,22.42 v2(143.68,22.42)
  IN2 w0.127: v2(140.41,27.33) 140.62,27.12 140.62,26.52 143.03,24.11 143.03,23.07 v2(143.68,22.42)
  BOTTOM w0.102: v2(135.8,75.02) 135.07,75.76 UC1.BC27
  BOTTOM w0.127: v2(140.41,27.33) 138.66,27.33 137,29 JDIMM2.182 ; v2(143.68,22.42) 143.68,22.17 143.81,22.04 144.23,22.04 144.32,22.13 144.32,22.8 144.43,22.91 144.72,22.91 144.87,22.76 144.87,21.63 144.75,21.51 144.05,21.51 143.92,21.38 143.92,21.12 144.05,21 146.11,21 146.23,20.87 146.23,20.57 146.11,20.45 145.04,20.45 144.91,20.32 144.91,19.99 145.04,19.86 146.11,19.86 146.23,19.74 146.23,18.34 146.05,18.15 145.33,18.15 145.2,18.02 JDIMM1.182
DDRAB_SDQ62: length 85.8
  IN1 w0.216: v2(137.11,78.69) 137.43,78.69 140.55,75.57 140.55,54.35 143.07,51.83 143.07,40 144.16,38.91 144.16,35.27 143.92,35.04 143.92,31.97 143.74,31.79 143.18,31.79 143,31.61 143,31.35 143.18,31.17 143.74,31.17 143.92,30.98 143.92,30.73 143.74,30.54 143.18,30.54 143,30.36 143,30.1 143.18,29.92 143.74,29.92 143.92,29.74 143.92,29.26 144.35,28.83 144.35,26.67 145.68,25.34 v2(145.68,23.52)
  IN2 w0.127: v2(145.68,23.52) 145.68,24.29 143,26.97 143,27.29 v2(142.35,27.94)
  BOTTOM w0.102: UC1.BC25 135.39,77.42 136.33,78.36 136.72,78.36 136.73,78.36
  BOTTOM w0.127: v2(142.35,27.94) 142.06,28.23 140.85,28.23 140,29.08 JDIMM2.192 ; v2(145.68,23.52) 145.68,22.83 145.81,22.71 148.19,22.71 148.32,22.58 148.32,22.31 148.19,22.19 147.64,22.19 147.52,22.06 147.52,21.76 147.64,21.63 148.8,21.63 148.93,21.5 148.93,21.12 148.8,20.99 148.32,20.99 148.2,20.88 JDIMM1.192
  BOTTOM w0.196: v2(137.11,78.69) 136.79,78.36 136.73,78.36
DDRAB_SDQ63: length 85.1
  IN1 w0.102: v2(136.43,78.74) 136.73,79.04
  IN1 w0.216: 136.73,79.04 136.9,79.21 137.65,79.21 141.07,75.78 141.07,54.56 143.59,52.05 143.59,40.22 144.68,39.13 144.68,35.06 144.44,34.82 144.44,29.48 144.87,29.04 144.87,26.89 146.31,25.45 v2(146.31,23.48)
  IN2 w0.127: v2(146.31,23.48) 146.31,24.27 143.48,27.1 143.48,27.46 v2(142.36,28.58)
  BOTTOM w0.102: v2(136.43,78.74) 136.3,78.74 135.41,77.85 134.7,77.85 UC1.BB25
  BOTTOM w0.127: JDIMM1.194 148.8,17.79 149.5,18.49 149.5,18.81 149.37,18.94 148.82,18.94 148.7,19.06 148.7,19.34 148.82,19.47 149.37,19.47 149.5,19.6 149.5,19.88 149.37,20 148.82,20 148.7,20.13 148.7,20.41 148.82,20.54 149.37,20.54 149.5,20.66 149.5,22.06 148.39,23.16 146.63,23.16 v2(146.31,23.48) ; JDIMM2.194 140.6,29.19 141.04,28.75 142.19,28.75 v2(142.36,28.58)
DDRAB_SDQS0: length 88
  IN1 w0.127: v2(87.31,19.64) 87.17,19.5 86,19.5 84.81,20.68 84.81,24.54 84.45,24.9 84.22,24.9 v2(84.08,25.04) 83.86,24.82 83.72,24.82 83.62,24.92 83.62,26.24 84.19,26.8 84.19,30.77 83.9,31.06 83.9,31.54 84.16,31.81 84.16,38.02 84.29,38.15 84.81,38.15 85.08,38.41 85.08,38.89 84.81,39.15 84.29,39.15 84.16,39.28 84.16,39.56 84.29,39.68 84.96,39.68 85.23,39.95 85.23,40.42 84.96,40.68 84.29,40.68 84.16,40.81 84.16,41.25 86.39,43.48 86.39,50.48 96.05,60.14 96.05,65.79 97.16,66.9 97.16,75.1 97.9,75.84 98.13,75.84 98.59,76.29 98.59,76.52 v2(98.82,76.75)
  BOTTOM w0.102: 99.39,76.93 99.43,76.93 99.47,76.89 100.15,76.89 100.84,76.2 101.32,76.2 101.44,76.08 101.8,76.08 102.01,76.29 102.01,76.73 102.11,76.83 102.25,76.83 UC1.B26
  BOTTOM w0.124: v2(98.82,76.75) 99,76.93 99.39,76.93
  BOTTOM w0.127: JDIMM1.12 91.8,17.67 91.64,17.83 91.64,18.66 90.84,19.46 87.49,19.46 v2(87.31,19.64) ; v2(84.08,25.04) 83.93,24.89 83.64,24.89 83.57,24.96 83.57,26.49 84.08,27 84.08,28.08 83.6,28.56 83.35,28.56 83.23,28.68 83.23,28.82 83.31,28.89 83.47,28.89 83.6,29.02 JDIMM2.12
DDRAB_SDQS0#: length 87.9
  IN1 w0.127: v2(98.24,76.75) 98.35,76.63 98.35,76.39 98.04,76.07 97.8,76.07 96.93,75.2 96.93,67 95.81,65.89 95.81,60.24 86.16,50.58 86.16,43.58 83.93,41.35 83.93,40.71 84.19,40.45 84.87,40.45 84.99,40.32 84.99,40.04 84.87,39.92 84.19,39.92 83.93,39.65 83.93,39.18 84.19,38.92 84.72,38.92 84.84,38.79 84.84,38.51 84.72,38.38 84.19,38.38 83.93,38.12 83.93,31.9 83.66,31.64 83.66,30.96 83.95,30.67 83.95,26.9 83.39,26.34 83.39,24.82 83.62,24.59 83.95,24.59 v2(84.08,24.46) 84.28,24.66 84.36,24.66 84.58,24.45 84.58,20.59 85.9,19.26 87.1,19.26 v2(87.31,19.05)
  BOTTOM w0.102: UC1.A26 101.81,76.48 101.81,76.38 101.75,76.31 101.54,76.31 101.42,76.43 100.94,76.43 100.25,77.13 99.57,77.13 99.53,77.17 99.5,77.17 99.49,77.18 99.41,77.18 99.4,77.19 99.39,77.19
  BOTTOM w0.124: v2(98.24,76.75) 98.24,76.8 98.63,77.19 99.39,77.19
  BOTTOM w0.127: v2(84.08,24.46) 83.88,24.66 83.55,24.66 83.34,24.87 83.34,26.59 83.85,27.09 83.85,27.99 83.51,28.33 83.26,28.33 83,28.59 JDIMM2.10 ; v2(87.31,19.05) 87.49,19.23 90.74,19.23 91.41,18.57 91.41,17.92 91.2,17.71 JDIMM1.10
DDRAB_SDQS1: length 76
  IN1 w0.127: v2(91.34,27.67) 91.15,27.48 91.05,27.48 90.89,27.63 90.89,28.33 90.82,28.4 90.82,28.89 91.74,29.81 91.74,32.13 92.45,32.84 92.45,33.25 92.14,33.55 92.09,33.55 v2(91.87,33.78) 91.69,33.6 91.61,33.6 91.47,33.74 91.47,34.15 92.46,35.14 92.46,35.86 94.29,37.69 94.29,40.57 94.42,40.7 94.99,40.7 95.25,40.96 95.25,41.43 94.99,41.7 94.42,41.7 94.29,41.82 94.29,42.1 94.42,42.23 94.99,42.23 95.25,42.49 95.25,42.97 94.99,43.23 94.42,43.23 94.29,43.36 94.29,43.64 94.42,43.76 94.99,43.76 95.25,44.03 95.25,44.5 94.99,44.76 94.42,44.76 94.29,44.89 94.29,45.17 94.42,45.3 94.99,45.3 95.25,45.56 95.25,46.03 94.99,46.3 94.42,46.3 94.29,46.43 94.29,46.71 94.42,46.83 94.95,46.83 95.22,47.1 95.22,51.87 102.29,58.94 102.29,69.29 102.67,69.67 102.67,70.23 102.41,70.5 100.88,70.5 100.72,70.66 100.72,71.06 101.26,71.59 101.26,72.08 101.59,72.41 101.59,73.03 101.71,73.15 101.91,73.15 v2(102.04,73.02)
  BOTTOM w0.102: v2(102.04,73.02) 102.07,73.02 UC1.B30
  BOTTOM w0.127: v2(91.87,33.78) 91.69,33.6 90.48,33.6 88.33,35.76 88.33,36.89 88.43,36.99 88.59,36.99 88.7,37.09 JDIMM2.29 ; v2(91.34,27.67) 91.4,27.62 92.25,27.62 93.29,26.58 96.39,26.58 96.73,26.24 96.73,26.07 96.9,25.9 JDIMM1.29
DDRAB_SDQS1#: length 75.9
  IN1 w0.127: v2(91.34,27.09) 91.19,27.24 90.95,27.24 90.66,27.53 90.66,28.23 90.59,28.3 90.59,28.99 91.5,29.9 91.5,32.23 92.22,32.94 92.22,33.15 92.11,33.26 91.93,33.26 v2(91.87,33.2) 91.7,33.36 91.52,33.36 91.24,33.65 91.24,34.25 92.23,35.24 92.23,35.95 94.06,37.78 94.06,40.67 94.32,40.93 94.89,40.93 95.02,41.06 95.02,41.34 94.89,41.46 94.32,41.46 94.06,41.73 94.06,42.2 94.32,42.46 94.89,42.46 95.02,42.59 95.02,42.87 94.89,43 94.32,43 94.06,43.26 94.06,43.73 94.32,44 94.89,44 95.02,44.12 95.02,44.4 94.89,44.53 94.32,44.53 94.06,44.79 94.06,45.27 94.32,45.53 94.89,45.53 95.02,45.66 95.02,45.94 94.89,46.06 94.32,46.06 94.06,46.33 94.06,46.8 94.32,47.07 94.86,47.07 94.98,47.19 94.98,51.96 102.06,59.04 102.06,69.39 102.44,69.77 102.44,70.14 102.31,70.26 100.79,70.26 100.48,70.57 100.48,71.15 101.02,71.69 101.02,72.17 101.35,72.5 101.35,73.12 v2(101.21,73.26)
  BOTTOM w0.102: v2(101.21,73.26) 101.21,73.32 101.4,73.51 101.58,73.51 UC1.A30
  BOTTOM w0.127: v2(91.87,33.2) 91.69,33.38 90.39,33.38 88.1,35.66 JDIMM2.27 ; JDIMM1.27 96.3,25.94 96.42,26.06 96.42,26.22 96.29,26.35 93.19,26.35 92.15,27.39 91.62,27.39 91.34,27.12 v2(91.34,27.09)
DDRAB_SDQS2: length 78.7
  IN2 w0.127: v2(102.69,67.8) 102.49,68 102.35,68 100.89,66.54 100.89,62.7 99.21,61.02 99.21,60.84 99.55,60.51 99.55,60.13 99.21,59.8 98.84,59.8 98.5,60.13 98.32,60.13 98.12,59.94 98.12,59.76 98.77,59.11 98.77,58.74 98.43,58.41 98.06,58.41 97.42,59.05 97.24,59.05 96.89,58.7 96.89,58.52 97.55,57.86 97.55,57.48 97.21,57.15 96.84,57.15 96.18,57.81 96,57.81 95.8,57.61 95.8,57.43 96.46,56.77 96.46,56.4 96.13,56.06 95.75,56.06 95.09,56.72 94.91,56.72 94.71,56.53 94.71,56.35 95.37,55.69 95.37,55.31 95.04,54.98 94.67,54.98 94.01,55.64 93.83,55.64 93.53,55.34 93.53,55.16 94.13,54.56 94.13,54.14 93.53,53.54 93.53,37.1 94.28,36.35 94.28,33.65 94.02,33.4 93.73,33.4 v2(93.59,33.25) 93.55,33.29 93.37,33.29 93.28,33.2 93.28,32.9 94.29,31.89 94.29,31 96.03,29.26 96.03,28.03 96.23,27.83 96.35,27.83 v2(96.52,28)
  BOTTOM w0.102: UC1.F32 105.12,71.88 105.12,71.72 105.13,71.56 105.03,71.46 105.03,71.18 105.07,71.14 105.07,71.13 105.07,71.13 105.07,70.71 104.77,70.4 104.24,70.4 103.51,69.68 103.51,68.24 103.27,68 102.89,68 102.84,67.95
  BOTTOM w0.127: v2(93.59,33.25) 93.76,33.43 94.09,33.43 94.35,33.68 94.35,34.54 94.04,34.85 93.24,34.85 93.12,34.97 93.12,35.35 93.26,35.48 94.09,35.48 94.35,35.74 94.35,36.33 93.91,36.76 93.91,37.05 94.1,37.24 JDIMM2.47 ; JDIMM1.47 102.3,25.84 102.08,26.06 102.08,26.26 101.87,26.47 99.93,26.47 99.31,27.09 97.73,27.09 97.06,27.76 96.76,27.76 v2(96.52,28) ; 102.84,67.95 v2(102.69,67.8)
DDRAB_SDQS2#: length 78.4
  IN2 w0.127: v2(96.52,27.42) 96.34,27.6 96.13,27.6 95.8,27.93 95.8,29.16 94.06,30.9 94.06,31.79 93.05,32.8 93.05,33.29 v2(93.59,33.84) 93.8,33.63 93.92,33.63 94.04,33.75 94.04,36.25 93.29,37 93.29,53.64 93.89,54.24 93.89,54.46 93.29,55.06 93.29,55.44 93.73,55.87 94.1,55.87 94.76,55.21 94.94,55.21 95.14,55.41 95.14,55.59 94.48,56.25 94.48,56.62 94.81,56.96 95.19,56.96 95.85,56.3 96.03,56.3 96.23,56.5 96.23,56.68 95.57,57.34 95.57,57.71 95.9,58.04 96.27,58.04 96.93,57.38 97.11,57.38 97.31,57.58 97.31,57.76 96.65,58.42 96.65,58.8 97.14,59.28 97.51,59.28 98.15,58.64 98.33,58.64 98.53,58.84 98.53,59.02 97.89,59.66 97.89,60.03 98.22,60.37 98.6,60.37 98.94,60.03 99.11,60.03 99.31,60.23 99.31,60.41 98.98,60.75 98.98,61.12 100.65,62.8 100.65,66.64 102.25,68.24 102.49,68.24 v2(102.69,68.43)
  BOTTOM w0.102: UC1.E32 104.67,71.82 104.82,71.82 104.92,71.71 104.92,71.64 104.83,71.54 104.83,71.1 104.87,71.05 104.87,71.05 104.87,71.05 104.87,70.79 104.68,70.61 104.15,70.61 103.31,69.76 103.31,68.33 103.18,68.2 102.92,68.2 v2(102.69,68.43)
  BOTTOM w0.127: JDIMM1.45 101.7,25.89 101.85,26.03 101.85,26.17 101.78,26.24 99.84,26.24 99.21,26.86 97.64,26.86 96.96,27.53 96.63,27.53 v2(96.52,27.42) ; JDIMM2.45 93.5,37.18 93.69,36.99 93.69,36.67 94.12,36.23 94.12,35.84 94,35.71 93.16,35.71 92.89,35.45 92.89,34.87 93.15,34.62 93.94,34.62 94.12,34.44 94.12,33.78 94,33.65 93.77,33.65 v2(93.59,33.84)
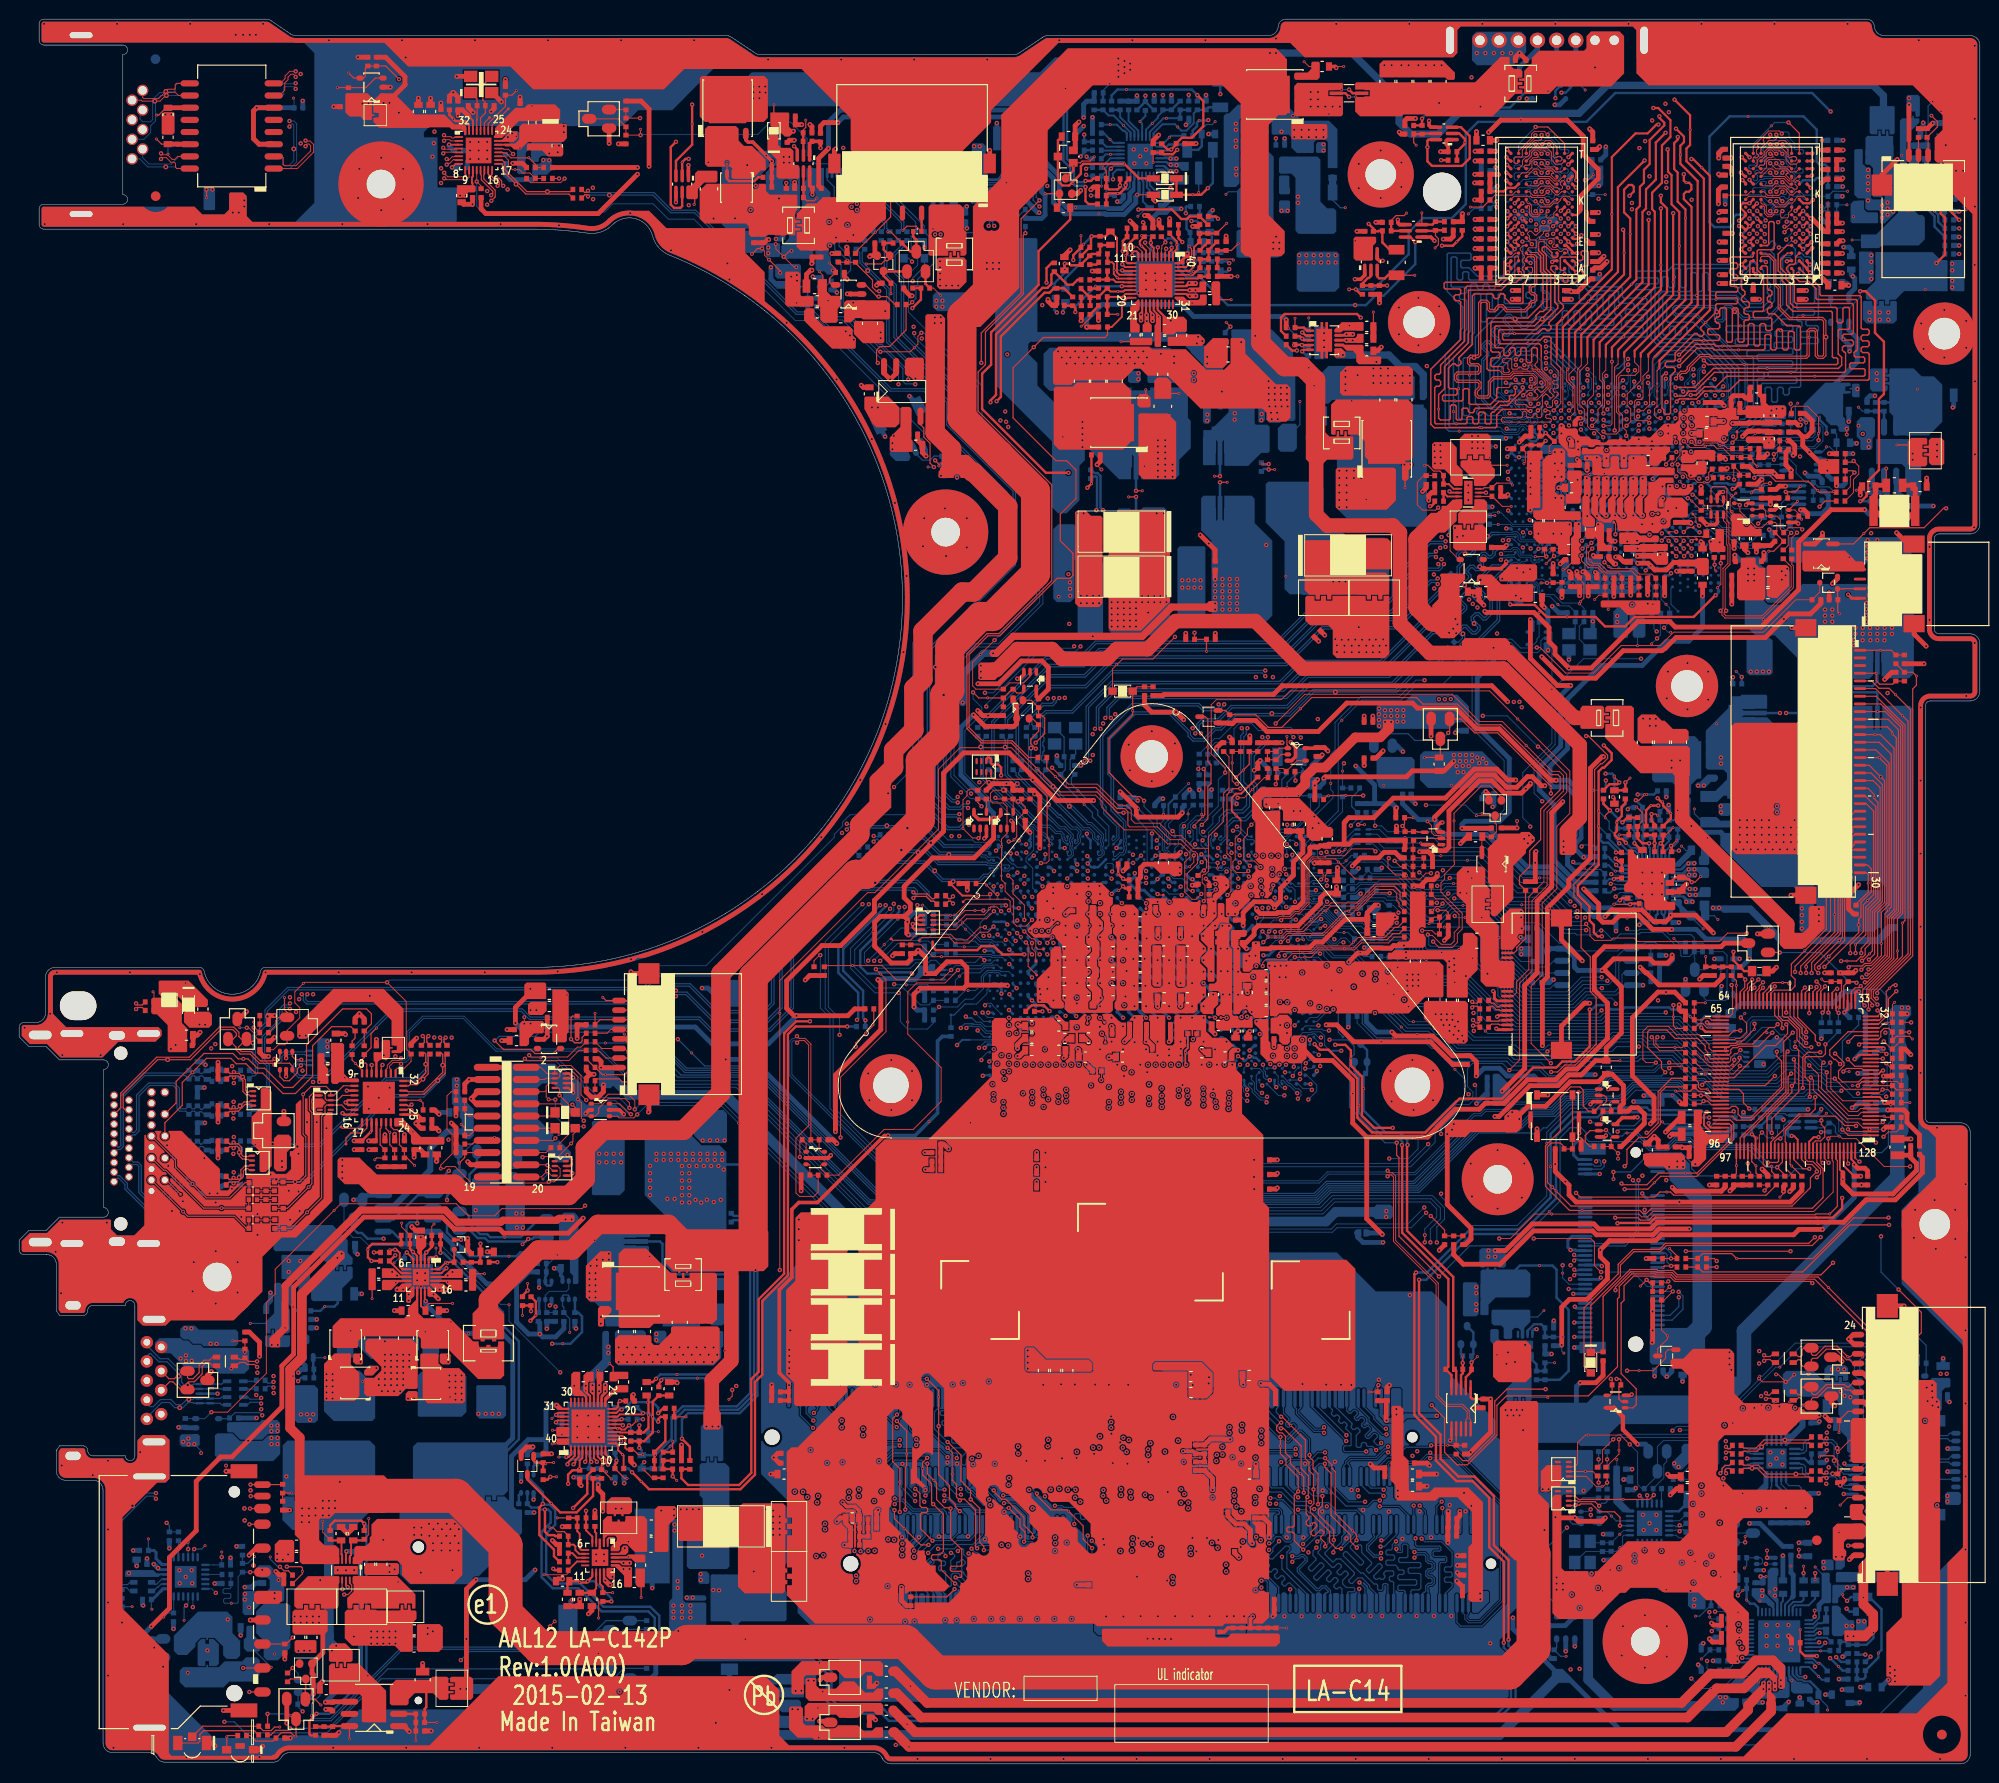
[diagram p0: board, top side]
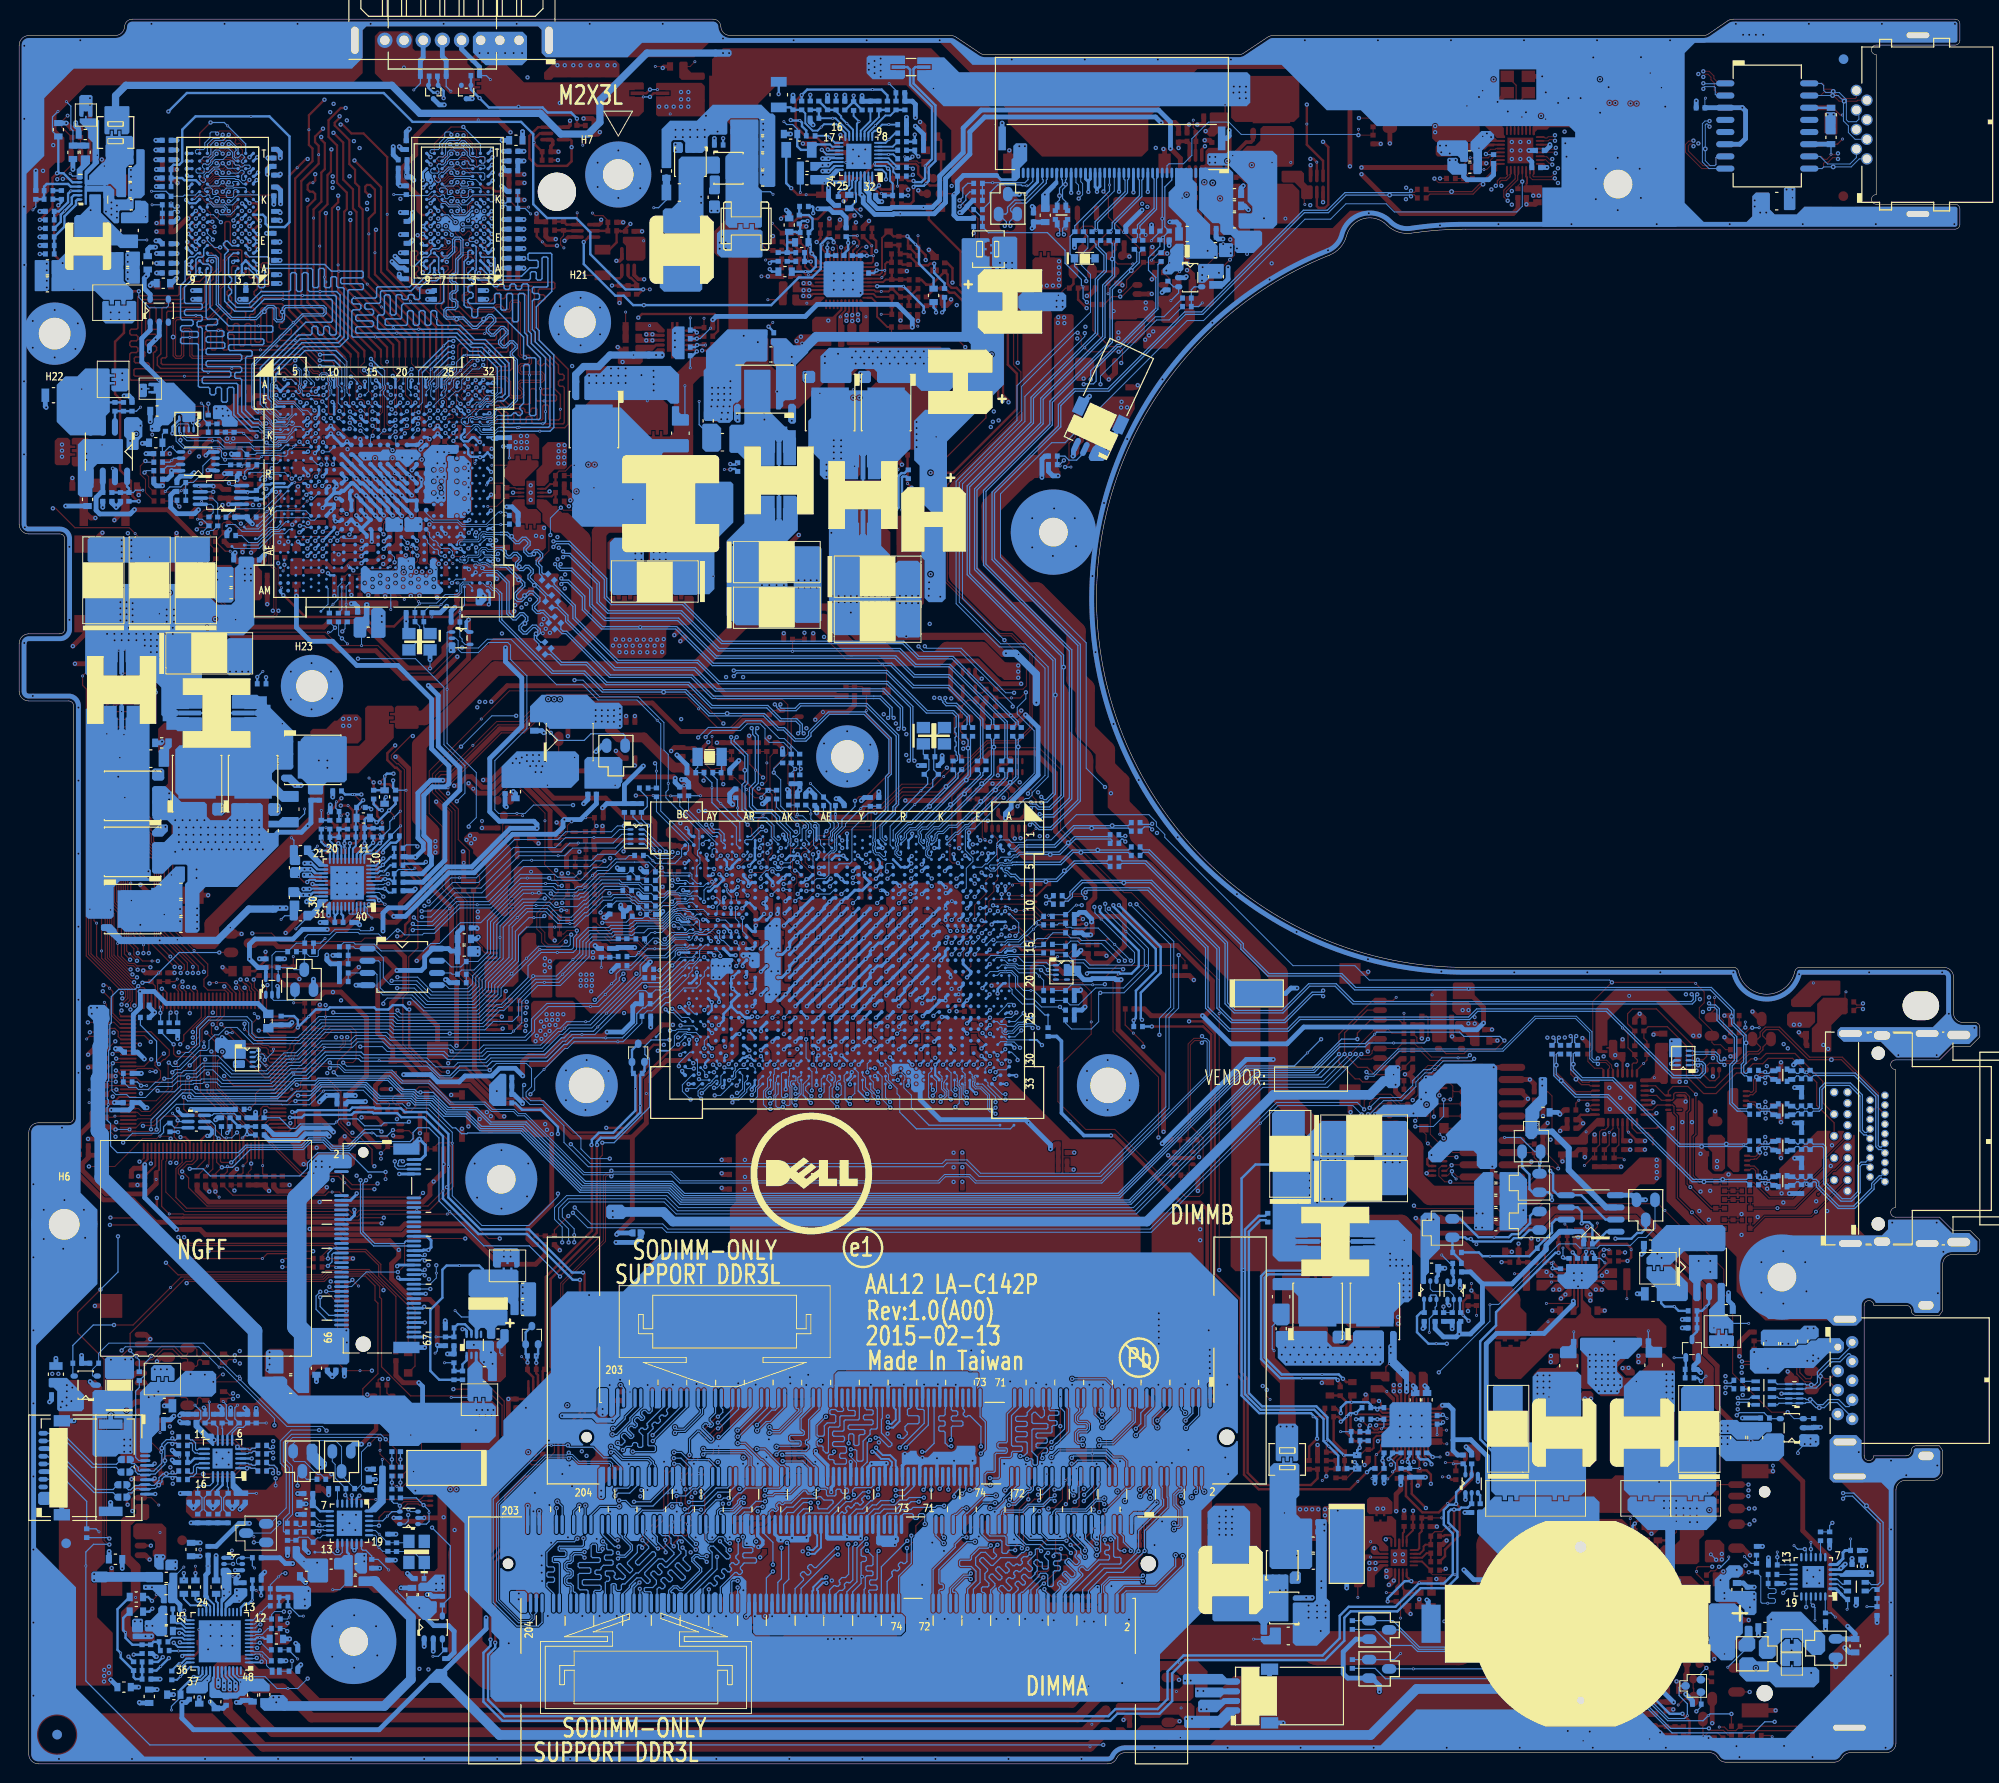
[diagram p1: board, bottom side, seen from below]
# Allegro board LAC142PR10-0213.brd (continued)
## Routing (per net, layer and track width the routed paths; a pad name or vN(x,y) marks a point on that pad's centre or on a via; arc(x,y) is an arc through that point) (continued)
DDRAB_SDQS3: length 70.4
  IN2 w0.127: v2(108.42,69.63) 108.25,69.45 108.07,69.45 107.79,69.18 107.79,68.48 108.1,68.17 108.1,65.83 107.84,65.56 107.84,57.54 105.06,54.76 105.06,51.98 101.56,48.48 101.56,42.78 101.42,42.65 100.78,42.65 100.52,42.38 100.52,41.91 100.78,41.65 101.42,41.65 101.55,41.52 101.55,41.24 101.42,41.11 100.78,41.11 100.52,40.85 100.52,30.77 100.89,30.4 100.89,28.4 101.3,28 101.3,27.68 v2(101.2,27.58) 100.89,27.28 100.89,25.89 105.77,21.01 105.77,19.85 105.6,19.68 105.44,19.68 v2(105.27,19.86)
  BOTTOM w0.102: UC1.K32 108.57,71.98 108.28,71.7 108.28,71.46 108.26,71.45 108.26,71.19 108.32,71.13 108.32,70.39 107.97,70.04 107.97,69.77 108.13,69.62 108.41,69.62 v2(108.42,69.63)
  BOTTOM w0.127: JDIMM2.64 99.2,29.03 98.96,28.79 98.96,28.67 99.12,28.51 99.39,28.51 100.65,27.25 101.02,27.25 101.2,27.43 v2(101.2,27.58) ; JDIMM1.64 107.4,18.29 106.01,19.68 105.44,19.68 v2(105.27,19.86)
DDRAB_SDQS3#: length 70.6
  IN2 w0.127: v2(108.42,69.04) 108.24,69.22 108.16,69.22 108.02,69.08 108.02,68.57 108.34,68.26 108.34,65.73 108.07,65.47 108.07,57.44 105.3,54.67 105.3,51.89 101.79,48.38 101.79,42.68 101.52,42.41 100.88,42.41 100.75,42.29 100.75,42.01 100.88,41.88 101.52,41.88 101.78,41.62 101.78,41.14 101.52,40.88 100.88,40.88 100.75,40.75 100.75,30.86 101.12,30.49 101.12,28.5 101.61,28.02 101.61,27.28 v2(101.31,26.98) 101.31,25.8 106.01,21.11 106.01,19.75 105.7,19.45 105.44,19.45 v2(105.27,19.27)
  BOTTOM w0.102: v2(108.42,69.04) 107.77,69.69 107.77,70.13 108.09,70.44 108.09,71.03 108.03,71.1 108.03,71.19 107.77,71.45 UC1.J32
  BOTTOM w0.127: JDIMM2.62 98.6,29.04 98.74,28.91 98.74,28.57 99.03,28.28 99.29,28.28 100.6,26.98 v2(101.31,26.98) ; v2(105.27,19.27) 105.44,19.45 105.91,19.45 107.17,18.19 107.17,17.97 107.09,17.89 106.89,17.89 106.8,17.8 JDIMM1.62
DDRAB_SDQS4: length 78.5
  IN2 w0.102: v2(130.19,69.58) 130.19,69.48 130.52,69.15 130.52,68.98 130.52,68.98 130.52,68.67 130.18,68.33 129.8,68.33 129.58,68.1 129.58,67.7 129.59,67.69 129.59,67.57
  IN2 w0.127: v2(128.95,27.79) 128.82,27.66 128.71,27.66 128.56,27.81 128.56,29.48 127.09,30.94 127.09,31.6 127.21,31.72 127.21,32.44 127.02,32.64 127.02,34.6 126.71,34.91 126.47,34.91 v2(126.27,35.11) 126.16,35 126.01,35 125.6,35.41 125.6,35.94 125.72,36.07 126.68,36.07 126.94,36.33 126.94,36.81 126.68,37.07 125.72,37.07 125.6,37.2 125.6,40.91 125.06,41.44 125.06,41.83 124.8,42.09 123.22,42.09 123.09,42.22 123.09,42.5 123.22,42.63 124.8,42.63 125.06,42.89 125.06,43.36 124.8,43.63 122.97,43.63 122.84,43.76 122.84,44.03 122.97,44.16 124.88,44.16 125.15,44.43 125.15,44.9 124.88,45.16 122.97,45.16 122.84,45.29 122.84,45.57 122.97,45.7 124.54,45.7 124.8,45.96 124.8,46.43 124.54,46.7 122.99,46.7 122.86,46.82 122.86,47.1 122.99,47.23 124.54,47.23 124.8,47.49 124.8,48.04 124.54,48.3 124.39,48.3 124.26,48.43 124.26,48.71 124.39,48.83 124.59,48.83 124.84,49.08 124.84,59.83 129.59,64.58 129.59,67.57
  BOTTOM w0.102: v2(130.19,69.58) 130.09,69.47 129.57,69.47 128.87,70.17 128.87,71.05 128.57,71.35 UC1.AR32
  BOTTOM w0.127: JDIMM2.137 123.5,37.12 123.44,37.06 123.28,37.06 123.21,36.98 123.21,36.82 125.28,34.76 125.94,34.76 126.27,35.08 v2(126.27,35.11) ; JDIMM1.137 131.7,26.37 131.44,26.63 130.17,26.63 129.61,27.19 129.61,27.41 129.35,27.67 129.06,27.67 v2(128.95,27.79)
DDRAB_SDQS4#: length 78.5
  IN2 w0.102: v2(130.14,68.99) 130.21,68.99 130.32,68.89 130.32,68.76 130.09,68.53 129.71,68.53 129.37,68.19 129.37,67.66 129.37,67.66 129.37,67.59 129.35,67.58 129.35,67.57
  IN2 w0.127: 129.35,67.57 129.35,64.67 124.61,59.93 124.61,49.18 124.49,49.07 124.29,49.07 124.03,48.8 124.03,48.33 124.29,48.07 124.44,48.07 124.57,47.94 124.57,47.59 124.44,47.46 122.89,47.46 122.63,47.2 122.63,46.73 122.89,46.46 124.44,46.46 124.57,46.34 124.57,46.06 124.44,45.93 122.87,45.93 122.61,45.67 122.61,45.19 122.87,44.93 124.78,44.93 124.91,44.8 124.91,44.52 124.78,44.4 122.87,44.4 122.61,44.13 122.61,43.66 122.87,43.39 124.7,43.39 124.83,43.27 124.83,42.99 124.7,42.86 123.12,42.86 122.86,42.6 122.86,42.12 123.12,41.86 124.7,41.86 124.83,41.73 124.83,41.34 125.36,40.81 125.36,37.1 125.63,36.84 126.58,36.84 126.71,36.71 126.71,36.43 126.58,36.3 125.63,36.3 125.36,36.04 125.36,35.31 125.91,34.76 126.03,34.76 v2(126.27,34.53) 126.42,34.68 126.61,34.68 126.79,34.51 126.79,32.54 126.98,32.35 126.98,31.81 126.86,31.69 126.86,30.84 128.32,29.38 128.32,27.72 128.61,27.43 128.73,27.43 v2(128.95,27.2)
  BOTTOM w0.102: UC1.AR33 128.48,71.01 128.33,71.01 128.22,70.9 128.22,70.76 128.64,70.34 128.64,70.07 129.47,69.24 129.97,69.24 130.14,69.07 v2(130.14,68.99)
  BOTTOM w0.127: JDIMM1.135 131.1,25.9 131.24,26.03 131.4,26.03 131.47,26.11 131.47,26.28 131.35,26.4 130.08,26.4 129.38,27.1 129.38,27.32 129.25,27.44 129.14,27.44 128.95,27.25 v2(128.95,27.2) ; v2(126.27,34.53) 125.18,34.53 122.98,36.73 122.98,37.13 122.9,37.21 JDIMM2.135
DDRAB_SDQS5: length 76.8
  IN2 w0.102: v2(133.41,69.38) 133.59,69.57 133.79,69.57 133.87,69.49 133.87,68.54 134.44,67.98 134.44,67.76 134.4,67.73 134.4,67.59 134.39,67.58 134.39,67.57
  IN2 w0.127: v2(132.82,21.65) 133.03,21.45 133.23,21.45 133.34,21.56 133.34,22.03 133.31,22.05 133.31,23.57 132.89,23.99 132.53,23.99 132.26,24.25 132.26,24.73 132.53,24.99 132.89,24.99 133.02,25.12 133.02,26.02 132.61,26.42 132.61,30.88 133.34,31.6 133.34,31.63 133.34,32.11 v2(133.18,32.27) 132.77,32.67 132.77,33.05 133.2,33.47 133.2,34.53 133.49,34.81 133.65,34.81 133.78,34.95 133.78,35.4 133.66,35.52 133.47,35.52 133.2,35.79 133.2,36.26 133.47,36.52 133.66,36.52 133.78,36.65 133.78,37.06 133.68,37.17 133.16,37.17 132.89,37.43 132.89,38.05 133.16,38.31 133.63,38.31 133.76,38.44 133.76,38.72 133.63,38.84 133.16,38.84 132.89,39.11 132.89,40.15 133.11,40.37 133.39,40.37 133.55,40.54 133.55,41.09 133.43,41.22 133.19,41.22 132.92,41.48 132.92,41.95 133.19,42.22 133.43,42.22 133.55,42.34 133.55,50.26 132.28,51.54 132.28,58.07 134.39,60.19 134.39,67.57
  BOTTOM w0.102: UC1.AW32 131.81,71.72 132.27,71.26 132.27,71.19 132.48,70.97 132.62,70.97 133.19,70.4 133.5,70.4 133.72,70.17 133.72,69.7 v2(133.41,69.38)
  BOTTOM w0.127: JDIMM1.154 136.8,18.09 136.32,18.57 135.87,18.57 135.59,18.29 135.42,18.29 133.57,20.13 133.57,20.32 134.37,21.12 134.37,21.49 134.03,21.83 133.66,21.83 133.47,21.64 132.83,21.64 v2(132.82,21.65) ; JDIMM2.154 128.6,30.96 128.41,31.14 128.41,31.94 128.92,32.44 133,32.44 v2(133.18,32.27)
DDRAB_SDQS5#: length 76.9
  IN2 w0.102: 134.62,67.57 134.62,67.65 134.65,67.68 134.65,68.07 134.08,68.63 134.08,69.57 133.88,69.77 133.51,69.77 v2(133.34,69.95)
  IN2 w0.127: v2(132.82,21.07) 132.97,21.22 133.33,21.22 133.57,21.46 133.57,22.12 133.55,22.15 133.55,23.67 132.99,24.22 132.62,24.22 132.5,24.35 132.5,24.63 132.62,24.76 132.99,24.76 133.25,25.02 133.25,26.11 132.85,26.52 132.85,30.78 133.57,31.51 133.57,31.53 133.57,32.46 v2(133.18,32.85) 133.18,33.12 133.43,33.38 133.43,34.43 133.58,34.58 133.74,34.58 134.02,34.85 134.02,35.49 133.75,35.76 133.56,35.76 133.44,35.88 133.44,36.16 133.56,36.29 133.75,36.29 134.02,36.55 134.02,37.16 133.78,37.4 133.25,37.4 133.13,37.53 133.13,37.95 133.25,38.08 133.73,38.08 133.99,38.34 133.99,38.81 133.73,39.08 133.25,39.08 133.13,39.2 133.13,40.05 133.21,40.14 133.49,40.14 133.79,40.44 133.79,41.19 133.52,41.45 133.28,41.45 133.16,41.58 133.16,41.86 133.28,41.98 133.52,41.98 133.79,42.25 133.79,50.36 132.51,51.64 132.51,57.98 134.62,60.09 134.62,67.57
  BOTTOM w0.102: UC1.AW33 131.65,71.04 131.65,71.23 131.72,71.3 131.85,71.3 132.05,71.11 132.05,71.08 132.39,70.74 132.52,70.74 133.21,70.05 133.24,70.05 v2(133.34,69.95)
  BOTTOM w0.127: v2(132.82,21.07) 133.17,21.41 133.57,21.41 133.76,21.6 133.94,21.6 134.14,21.4 134.14,21.22 133.34,20.41 133.34,20.04 135.32,18.06 135.68,18.06 135.96,18.34 136.23,18.34 136.57,17.99 136.57,17.93 136.48,17.84 136.32,17.84 136.2,17.73 JDIMM1.152 ; v2(133.18,32.85) 133,32.67 128.82,32.67 128.19,32.03 128.19,31.13 128,30.94 JDIMM2.152
DDRAB_SDQS6: length 72.4
  IN1 w0.102: v2(133.07,73.82) 132.92,73.96 132.81,73.96 132.67,73.83 132.67,73.52 132.87,73.32 133.4,73.32 133.74,73.66 134.6,73.66 134.96,73.3 134.96,71.48 135.46,70.98 135.46,69.07 134.23,67.85 134.23,67.57
  IN1 w0.127: 134.23,67.57 134.23,50.93 133.39,50.09 133.39,38 134.62,36.77 134.62,35.87 135.6,34.89 135.91,34.89 v2(136.13,35.11) 136.27,34.97 136.64,34.97 136.88,34.73 136.88,29.43 137.44,28.87 137.44,27.96 138.02,27.38 138.02,23.26 139.49,21.79 141.87,21.79 v2(142.08,22)
  BOTTOM w0.102: v2(133.07,73.82) 133.46,74.22 UC1.BA29
  BOTTOM w0.127: v2(142.08,22) 141.86,21.77 141.39,21.77 140.8,22.36 140.8,22.71 141.64,23.55 141.64,23.72 141.9,23.99 JDIMM1.171 ; v2(136.13,35.11) 135.93,34.9 135.2,34.9 133.49,36.61 133.49,36.91 133.7,37.12 JDIMM2.171
DDRAB_SDQS6#: length 73
  IN1 w0.102: v2(132.27,73.82) 132.46,73.63 132.46,73.43 132.78,73.11 133.49,73.11 133.49,73.11 133.49,73.12 133.83,73.46 134.51,73.46 134.75,73.21 134.75,71.39 135.25,70.89 135.25,69.16 134.02,67.93 134.02,67.67 134.01,67.66 134.01,67.59 134,67.58 134,67.57
  IN1 w0.127: v2(142.08,21.41) 141.94,21.55 139.4,21.55 137.78,23.16 137.78,27.28 137.2,27.86 137.2,28.77 136.64,29.33 136.64,34.64 136.54,34.73 136.34,34.73 v2(136.13,34.52) 136,34.65 135.51,34.65 134.38,35.78 134.38,36.67 133.16,37.9 133.16,50.18 134,51.02 134,67.57
  BOTTOM w0.102: v2(132.27,73.82) 132.27,73.82 132.67,74.22 UC1.AY29
  BOTTOM w0.127: v2(136.13,34.52) 136.13,34.53 136,34.66 135.62,34.66 135.6,34.67 135.1,34.67 133.26,36.52 133.26,37 133.27,37.01 133.1,37.18 JDIMM2.169 ; v2(142.08,21.41) 141.95,21.55 141.29,21.55 140.57,22.27 140.57,22.8 141.41,23.64 141.41,23.75 141.3,23.86 JDIMM1.169
DDRAB_SDQS7: length 82.4
  IN1 w0.127: v2(133.07,77.02) 133.07,77.04 132.94,77.17 132.8,77.17 132.67,77.04 132.67,76.73 132.94,76.46 133.84,76.46 135.59,78.2 136.74,78.2 139.97,74.97 139.97,54.11 142.49,51.59 142.49,39.4 143.16,38.73 143.16,36.21 143.33,36.04 143.33,33 143.02,32.7 v2(142.81,32.49) 142.64,32.66 142.48,32.66 142.39,32.56 142.39,29.44 143.43,28.39 143.43,28.33 143.44,28.32 143.44,26.67 144.45,25.66 144.45,24.34 144.95,23.84 144.95,22.02 145.07,21.9 145.38,21.9 v2(145.57,22.09)
  BOTTOM w0.102: UC1.BA25 v2(133.07,77.02)
  BOTTOM w0.127: v2(145.57,22.09) 145.62,22.03 146.67,22.03 146.97,21.73 146.97,21.25 147.1,21.12 147.37,21.12 147.63,20.86 147.63,20.39 147.37,20.13 147.1,20.13 146.97,20 146.97,19.72 147.1,19.6 147.38,19.6 147.64,19.34 147.64,18.87 147.38,18.61 147.1,18.61 146.97,18.48 146.97,18.03 147,18 JDIMM1.188 ; v2(142.81,32.49) 142.7,32.6 142.5,32.6 141.63,31.73 138.93,31.73 138.61,31.41 138.61,31.29 138.8,31.1 JDIMM2.188
DDRAB_SDQS7#: length 82.5
  IN1 w0.127: v2(132.27,77.02) 132.43,76.85 132.43,76.63 132.84,76.23 133.94,76.23 135.68,77.97 136.64,77.97 139.74,74.87 139.74,54.01 142.25,51.49 142.25,39.3 142.93,38.63 142.93,36.11 143.09,35.95 143.09,33.1 143,33.01 142.88,33.01 v2(142.81,33.08) 142.63,32.89 142.39,32.89 142.15,32.66 142.15,29.35 143.2,28.3 143.2,28.05 143.21,28.04 143.21,26.57 144.21,25.56 144.21,24.24 144.72,23.74 144.72,21.92 144.98,21.67 145.41,21.67 v2(145.57,21.51)
  BOTTOM w0.102: UC1.AY25 132.67,77.42 v2(132.27,77.02)
  BOTTOM w0.127: JDIMM2.186 138.2,31.1 138.39,31.29 138.39,31.51 138.84,31.96 141.54,31.96 142.41,32.83 142.57,32.83 v2(142.81,33.08) ; v2(145.57,21.51) 145.87,21.81 146.57,21.81 146.74,21.64 146.74,21.15 147,20.89 147.28,20.89 147.4,20.77 147.4,20.49 147.28,20.36 147,20.36 146.74,20.1 146.74,19.63 147,19.37 147.29,19.37 147.41,19.24 147.41,18.96 147.29,18.84 147,18.84 146.74,18.57 146.74,18.01 146.61,17.88 146.53,17.88 146.4,17.75 JDIMM1.186
DDRAB_SMA0: length 81.2
  IN1 w0.216: v2(121.85,70.23) 121.42,69.8 121.42,69.48 120.25,68.32 120.25,57.79 120.13,57.66 119.42,57.66 119.29,57.53 119.29,57.16 119.42,57.04 119.83,57.04 119.96,56.91 119.96,56.54 119.83,56.41 119.42,56.41 119.29,56.29 119.29,51.57 114.17,46.44 114.17,39.37 112.77,37.98 112.25,37.98 111.98,37.72 111.98,37.11 112.27,36.82 113.21,36.82 113.33,36.7 113.33,36.32 113.21,36.19 112.92,36.19 112.8,36.07 112.8,35.69 112.92,35.56 113.21,35.56 113.33,35.43 113.33,34.22 113.82,33.73 113.82,33.12 113.91,33.03 113.91,32.77 115.11,31.57 115.11,31.06 116.45,29.73 116.45,27.42 116.32,27.29 115.64,27.29 115.32,27.61 115.12,27.61 114.93,27.42 114.93,27.1 115.36,26.67 116.32,26.67 116.45,26.54 116.45,26.15 116.32,26.02 116.12,26.02 115.99,25.9 115.99,25.67 116.33,25.33 116.74,25.33 116.94,25.13 116.94,24.72 117.75,23.91 117.75,23.2 v2(118.05,22.9)
  IN2 w0.127: v2(113.12,28.55) 113.55,28.55 114.6,27.5 114.6,26.87 117.79,23.68 117.79,23.16 v2(118.05,22.9)
  BOTTOM w0.102: UC1.AG31 121.84,72.2 121.84,70.24 v2(121.85,70.23)
  BOTTOM w0.127: JDIMM2.98 111.8,28.97 112.23,28.55 v2(113.12,28.55) ; JDIMM1.98 120,18.14 119.56,18.59 119.38,18.59 119.3,18.51 119.12,18.51 118.92,18.71 118.92,18.89 119,18.97 119,19.15 118.71,19.43 118.34,19.43 118.01,19.76 118.01,22.86 v2(118.05,22.9)
DDRAB_SMA1: length 75.7
  IN1 w0.102: v2(119.36,72.92) 118.77,72.32 118.77,68.25 118.81,68.2 118.81,67.7
  IN1 w0.127: 112.76,34.16 112.76,34.09 113.35,33.5 113.35,32.93 113.44,32.84 113.44,32.57 114.64,31.37 114.64,30.87 115.94,29.57 v2(115.94,28.37)
  IN1 w0.216: v2(112.76,34.16) 112.76,34.16 112.74,34.15 112.74,35 112.06,35.68 112.06,36.29 111.46,36.89 111.46,37.93 112.03,38.5 112.56,38.5 113.25,39.19 113.25,39.72 113.65,40.12 113.65,46.66 113.87,46.89 113.87,47.19 113.66,47.4 113.66,47.7 114.01,48.06 114.27,48.06 114.48,47.85 114.83,47.85 115.18,48.19 115.18,48.5 114.19,49.49 114.19,49.79 114.54,50.14 114.84,50.14 115.83,49.15 116.14,49.15 116.49,49.5 116.49,49.81 116.36,49.93 116.36,50.11 116.84,50.59 117.02,50.59 117.14,50.46 117.45,50.46 118.77,51.78 118.77,58 118.95,58.18 119.55,58.18 119.73,58.36 119.73,58.92 119.51,59.14 118.99,59.14 118.78,59.35 118.78,59.85 118.99,60.06 119.51,60.06 119.73,60.28 119.73,60.77 119.51,60.99 118.99,60.99 118.78,61.21 118.78,61.7 118.99,61.92 119.51,61.92 119.73,62.13 119.73,62.63 119.51,62.84 118.99,62.84 118.78,63.06 118.78,63.55 118.99,63.77 119.51,63.77 119.73,63.99 119.73,64.48 119.51,64.7 118.99,64.7 118.78,64.91 118.78,65.41 118.99,65.62 119.51,65.62 119.73,65.84 119.73,66.43 119.6,66.56 118.94,66.56 118.81,66.69 118.81,67.7
  BOTTOM w0.102: UC1.AC30 118.97,73.32 v2(119.36,72.92)
  BOTTOM w0.127: JDIMM1.97 119.7,25.92 118.28,27.34 117.75,27.34 117.47,27.62 117.29,27.62 116.54,28.37 115.94,28.37 v2(115.94,28.37) ; v2(112.76,34.16) 112.54,33.95 112.31,33.95 111.89,34.36 111.89,34.57 112.13,34.81 112.13,35.17 111.84,35.47 110.79,35.47 110.66,35.6 110.66,36.18 110.79,36.31 111.75,36.31 111.88,36.43 111.88,36.93 111.75,37.06 111.63,37.06 111.5,37.19 JDIMM2.97
DDRAB_SMA2: length 80.5
  IN1 w0.102: v2(118.56,72.92) 118.56,70.87 118.11,70.41 117.63,70.41 117.17,69.96 117.17,69.18 116.93,68.94 116.93,68.5 117.21,68.22 117.21,67.7
  IN1 w0.216: v2(117.28,22.96) 117.21,23.03 117.21,23.71 115.34,25.58 115.34,25.95 114.41,26.89 114.41,27.86 114.08,28.19 114.08,29.53 111.71,31.9 111.71,32.58 111.5,32.79 111.5,33.13 111.18,33.45 111.18,34.35 110.5,35.03 110.5,35.64 108.43,37.72 108.43,38.02 108.64,38.24 108.89,38.24 109.43,37.71 109.61,37.71 109.86,37.96 109.86,38.14 109.45,38.55 109.45,38.81 109.64,38.99 110.31,38.99 112.08,40.76 112.08,48.6 111.96,48.73 111.07,48.73 110.94,48.86 110.94,52.12 117.21,58.38 117.21,67.7
  IN2 w0.127: v2(117.28,22.96) 117.36,23.05 117.36,23.5 114.17,26.69 114.17,27.32 113.39,28.09 113.22,28.09 v2(113.09,27.96)
  BOTTOM w0.102: UC1.AC31 118.96,72.52 v2(118.56,72.92)
  BOTTOM w0.127: JDIMM2.96 111.2,28.94 112.17,27.96 v2(113.09,27.96) ; v2(117.28,22.96) 117.58,22.66 117.58,19.17 117.86,18.89 118.04,18.89 118.08,18.93 118.26,18.93 118.46,18.73 118.46,18.55 118.42,18.51 118.42,18.33 118.66,18.08 118.98,18.08 119.4,17.66 JDIMM1.96
DDRAB_SMA3: length 82.1
  IN1 w0.127: v2(112.68,32.98) 113,32.66 113,31.89 115.35,29.55 115.35,28.35 115.91,27.78 v2(115.97,27.78)
  IN1 w0.216: v2(117.88,68.81) 118.25,68.45 118.25,56.64 118.03,56.43 117.66,56.43 117.53,56.3 117.53,55.93 117.66,55.8 118.03,55.8 118.25,55.59 118.25,54.62 118.08,54.45 117.89,54.45 116.87,55.47 116.69,55.47 116.42,55.2 116.42,55.03 118.25,53.2 118.25,53.02 117.99,52.76 117.75,52.76 115.96,54.56 115.78,54.56 115.46,54.24 115.46,54.06 117.75,51.76 117.75,51.51 117.57,51.32 117.31,51.32 115.74,52.89 115.56,52.89 115.27,52.61 115.27,52.43 116.47,51.23 116.47,50.96 115.77,50.25 115.51,50.25 115.3,50.47 115.3,50.69 115.63,51.01 115.63,51.19 115.32,51.5 115.14,51.5 113.35,49.72 113.35,49.5 113.86,49 113.86,48.64 113.12,47.9 113.12,40.33 112.72,39.93 112.72,39.4 112.34,39.02 111.81,39.02 110.94,38.15 110.94,37.55 110.64,37.25 110.64,36.98 111.54,36.07 111.54,35.47 112.22,34.79 112.22,33.93 112.68,33.48 v2(112.68,32.98)
  BOTTOM w0.102: 118.4,69.33 118.4,71.09 118.48,71.18 118.48,71.8 UC1.AB32
  BOTTOM w0.127: JDIMM2.95 110.9,37.1 110.77,36.97 110.26,36.97 110.13,36.84 110.13,35.51 112.66,32.98 v2(112.68,32.98) ; v2(115.97,27.78) 116.07,27.78 116.22,27.94 116.36,27.94 116.64,27.66 116.64,27.51 116.49,27.36 116.49,27.27 116.76,27 116.87,27 117.06,27.19 117.29,27.19 117.46,27.02 117.46,26.95 117.71,26.7 117.84,26.7 118.01,26.87 118.14,26.87 118.32,26.69 118.32,26.53 118.19,26.4 118.19,26.29 118.34,26.14 118.51,26.14 118.65,26.28 118.74,26.28 119.1,25.91 JDIMM1.95
  BOTTOM w0.157: 118.4,69.33 v2(117.88,68.81)
DDRAB_SMA4: length 77
  IN1 w0.102: 116.69,67.7 116.69,68.99 116.85,69.16 116.85,69.97 117.75,70.87 v2(117.88,70.87)
  IN1 w0.216: 116.69,67.7 116.69,58.6 110.42,52.33 110.42,48.33 110.55,48.21 111.44,48.21 111.56,48.08 111.56,41.32 110.45,40.21 110.05,40.21 108.95,39.1 108.5,39.1 107.91,38.51 107.91,37.5 109.98,35.43 109.98,34.82 110.66,34.14 110.66,33.24 110.98,32.92 110.98,32.58 111.19,32.37 111.19,31.68 113.17,29.7 113.17,29.15 113.29,29.03 113.42,29.03 113.56,28.89 113.56,27.97 113.89,27.64 113.89,27.19 113.71,27.01 113.71,26.85 113.93,26.63 113.93,26.37 114.07,26.23 114.32,26.23 114.82,25.74 114.82,25.37 114.97,25.21 114.97,24.97 114.78,24.78 114.78,24.65 115.12,24.31 115.24,24.31 115.47,24.54 115.65,24.54 115.91,24.28 115.91,24.09 115.68,23.86 115.68,23.75 115.92,23.51 v2(116.18,23.51)
  IN2 w0.127: v2(116.18,23.51) 116.18,24.07 111.66,28.59 v2(110.2,28.59)
  BOTTOM w0.102: UC1.AA32 117.88,71.21 v2(117.88,70.87)
  BOTTOM w0.127: JDIMM2.92 110,28.79 v2(110.2,28.59) ; JDIMM1.92 118.2,17.94 117.14,18.99 117.14,22.54 v2(116.18,23.51)
DDRAB_SMA5: length 76.9
  IN1 w0.127: v2(112.05,32.98) 112.57,32.46 112.57,31.71 114.55,29.73 114.55,28.44 v2(114.94,28.05)
  IN1 w0.163: v2(117.88,69.42) 117.83,69.42 117.44,69.04
  IN1 w0.216: 117.44,69.04 117.44,68.57 117.73,68.28 117.73,57.25 117.02,56.54 116.76,56.54 116.56,56.74 116.31,56.74 116.12,56.55 116.12,56.3 116.32,56.1 116.32,55.84 116.14,55.66 115.88,55.66 115.68,55.86 115.42,55.86 115.24,55.67 115.24,55.42 115.44,55.22 115.44,54.96 115.26,54.78 115,54.78 114.8,54.98 114.54,54.98 114.36,54.79 114.36,54.54 114.56,54.34 114.56,53.82 115.05,53.33 115.05,53.15 114.79,52.89 114.61,52.89 113.62,53.88 113.44,53.88 113.18,53.62 113.18,53.44 114.63,51.99 114.63,51.73 114.45,51.55 114.19,51.55 112.74,53 112.56,53 112.3,52.74 112.3,52.56 113.75,51.11 113.75,50.85 113.57,50.67 113.31,50.67 111.86,52.12 111.68,52.12 111.46,51.89 111.46,50.69 111.64,50.51 112.48,50.51 112.6,50.39 112.6,50.02 112.48,49.89 111.64,49.89 111.46,49.71 111.46,49.45 111.64,49.27 112.42,49.27 112.6,49.09 112.6,40.55 110.42,38.36 110.42,37.77 109.93,37.28 109.93,36.95 111.02,35.86 111.02,35.25 111.7,34.57 111.7,33.67 112.05,33.32 v2(112.05,32.98)
  BOTTOM w0.102: UC1.AA33 117.37,69.94 v2(117.88,69.42)
  BOTTOM w0.127: JDIMM1.91 117.9,25.9 117.23,26.57 116.58,26.57 115.72,27.43 115.56,27.43 v2(114.94,28.05) ; v2(112.05,32.98) 109.7,35.33 JDIMM2.91
DDRAB_SMA6: length 81.3
  IN1 w0.102: 115.64,67.7 115.64,68.83 v2(116.08,69.26)
  IN1 w0.216: 115.64,67.7 115.64,59.03 109.38,52.77 109.38,43.22 108.74,42.58 108.74,42.14 108.51,41.92 107.47,41.92 107.28,41.73 107.28,41.48 107.47,41.29 108.97,41.29 109.15,41.11 109.15,40.85 108.97,40.67 107.47,40.67 107.28,40.49 107.28,39.36 106.86,38.94 106.86,37.07 108.94,34.99 108.94,34.39 109.37,33.95 109.37,33.64 109.37,32.85 109.8,32.43 109.8,31.73 112.22,29.31 112.22,27.6 113.41,26.41 113.41,26.15 113.2,25.95 113.2,25.77 113.46,25.51 113.64,25.51 113.85,25.71 114.11,25.71 114.29,25.53 114.29,25.27 114,24.98 114,24.69 115.77,22.92 v2(116.13,22.92)
  IN2 w0.127: v2(109.4,28.59) 109.83,28.16 111.48,28.16 115.68,23.96 115.68,23.38 v2(116.13,22.92)
  BOTTOM w0.102: UC1.AA31 117.37,72.47 117.02,72.12 117.02,70.2
  BOTTOM w0.127: v2(116.13,22.92) 116.71,22.35 116.71,21.76 116.58,21.64 116.3,21.64 116.17,21.51 116.17,21.23 116.3,21.1 116.58,21.1 116.71,20.97 116.71,18.82 117.6,17.93 JDIMM1.90 ; JDIMM2.90 v2(109.4,28.59)
  BOTTOM w0.157: 117.02,70.2 v2(116.08,69.26)
DDRAB_SMA7: length 81.8
  IN1 w0.102: 115.12,67.7 115.12,68.59 115.39,68.86 115.39,69.18 v2(116.08,69.87)
  IN1 w0.216: 115.12,67.7 115.12,59.25 108.86,52.98 108.86,43.43 107.97,42.54 106.88,42.54 106.75,42.42 106.75,40.64 106.34,40.23 106.34,36.86 108.42,34.78 108.42,34.17 108.85,33.74 108.85,33.12 108.85,32.64 109.28,32.21 109.28,31.51 111.7,29.09 111.7,27.2 112.64,26.25 112.64,25.31 115.41,22.54 115.41,21.26 115.21,21.06 115,21.06 114.92,20.97 114.92,20.6 115.14,20.37 115.7,20.37 116.1,20.76 v2(116.1,22.24)
  IN2 w0.127: v2(116.1,22.24) 111.38,26.95 110.42,26.95 108.68,28.69 v2(108.51,28.69)
  BOTTOM w0.102: v2(116.08,69.87) 116.57,70.36 UC1.Y33
  BOTTOM w0.127: v2(116.1,22.24) 115.47,21.62 115.47,20.78 115.6,20.65 116.07,20.65 116.2,20.53 116.2,20.25 116.07,20.12 115.6,20.12 115.47,19.99 115.47,19.71 115.57,19.62 116.12,19.62 116.28,19.46 116.28,18.31 116.4,18.19 JDIMM1.86 ; v2(108.51,28.69) 108.2,29 JDIMM2.86
DDRAB_SMA8: length 76.9
  IN1 w0.102: v2(117.76,72.92) 117.19,72.34 117.19,71.11 116.65,70.58 116.65,69.25 116.17,68.76 116.17,67.7
  IN1 w0.127: v2(113.41,27.45) 113.05,27.45 112.69,27.8 112.69,29.5 110.71,31.49 110.71,32.17 v2(110.34,32.54)
  IN1 w0.216: v2(110.34,32.54) 110.34,32.82 110.14,33.02 110.14,33.92 109.46,34.6 109.46,35.21 107.38,37.29 107.38,38.73 107.8,39.15 107.8,40 107.95,40.15 109.26,40.15 109.67,40.56 109.67,40.66 109.85,40.84 110.34,40.84 110.47,40.97 110.47,41.33 110.34,41.46 109.54,41.46 109.42,41.59 109.42,41.96 109.54,42.09 110.92,42.09 111.04,42.21 111.04,42.53 110.86,42.71 110.08,42.71 109.9,42.89 109.9,43.15 110.08,43.33 110.86,43.33 111.04,43.51 111.04,43.77 110.86,43.95 110.08,43.95 109.9,44.14 109.9,44.39 110.08,44.58 110.86,44.58 111.04,44.76 111.04,45.02 110.86,45.2 110.08,45.2 109.9,45.38 109.9,45.64 110.08,45.82 110.86,45.82 111.04,46 111.04,46.26 110.86,46.44 110.08,46.44 109.9,46.62 109.9,46.88 110.08,47.06 110.86,47.06 111.04,47.25 111.04,47.5 110.86,47.69 110.08,47.69 109.9,47.87 109.9,52.55 116.17,58.82 116.17,67.7
  BOTTOM w0.102: UC1.AA30 117.37,73.32 v2(117.76,72.92)
  BOTTOM w0.127: v2(110.34,32.54) 109.99,32.54 109.1,33.43 JDIMM2.89 ; v2(113.41,27.45) 114.67,27.45 115.12,27 115.54,27 116.4,26.14 117.05,26.14 117.3,25.89 JDIMM1.89
DDRAB_SMA9: length 77.6
  IN1 w0.102: v2(114.95,70.11) 114.59,69.75 114.59,69.63 114.14,69.18 114.14,68.27 113.56,67.7
  IN1 w0.127: v2(110.16,27.76) 109.79,28.13 109.79,28.97 107.42,31.34 107.42,33.02 v2(107.31,33.13)
  IN1 w0.216: v2(107.31,33.13) 106.83,33.61 106.83,34.16 105.75,35.24 104.97,35.24 104.78,35.43 104.78,43.98 104.91,44.11 106.01,44.11 106.2,44.29 106.2,45.21 106.38,45.39 107.11,45.39 107.23,45.52 107.23,45.88 107.11,46.01 106.38,46.01 106.2,46.19 106.2,46.45 106.38,46.63 107.11,46.63 107.3,46.81 107.3,47.07 107.11,47.25 106.38,47.25 106.2,47.44 106.2,47.69 106.38,47.88 107.11,47.88 107.3,48.06 107.3,48.32 107.11,48.5 106.38,48.5 106.2,48.68 106.2,48.94 106.38,49.12 107.11,49.12 107.3,49.3 107.3,49.56 107.11,49.74 106.38,49.74 106.2,49.93 106.2,50.18 106.38,50.37 107.11,50.37 107.3,50.55 107.3,50.81 107.11,50.99 106.32,50.99 106.2,51.11 106.2,51.52 106.3,51.62 107.06,51.62 107.3,51.85 107.3,52.12 107.11,52.3 106.62,52.3 106.5,52.43 106.5,52.8 106.62,52.93 107.11,52.93 107.3,53.11 107.3,53.63 112.12,58.45 112.12,65.79 113.56,67.24 113.56,67.7
  BOTTOM w0.102: v2(114.95,70.11) 115.05,70.11 115.44,70.5 115.44,71.13 115.77,71.45 UC1.W32
  BOTTOM w0.127: JDIMM1.85 116.1,25.83 115.36,26.57 114.94,26.57 114.51,27 113.19,27 112.68,27.51 111.95,27.51 111.69,27.78 110.17,27.78 v2(110.16,27.76) ; v2(107.31,33.13) 107.61,33.13 107.95,33.46 107.95,34.57 108.07,34.7 108.49,34.7 108.62,34.82 108.62,35.1 108.49,35.23 108.07,35.23 107.95,35.36 107.95,35.64 108.07,35.76 108.49,35.76 108.62,35.89 108.62,36.17 108.49,36.3 108.07,36.3 107.95,36.42 107.95,37 107.9,37.05 JDIMM2.85
DDRAB_SMA10: length 76.6
  IN1 w0.127: v2(115.2,34.01) 115.2,33.76 115.97,32.98 115.97,32.31 116.55,31.73 116.55,31.04 117.47,30.12 117.47,28.94 118.05,28.36 v2(118.05,27.77)
  IN1 w0.216: v2(121.96,68.94) 121.29,68.28 121.29,56.11 121.11,55.93 120.82,55.93 120.69,55.8 120.69,55.43 120.82,55.31 121.11,55.31 121.29,55.12 121.29,54.87 121.11,54.68 120.53,54.68 120.35,54.5 120.35,54.25 120.53,54.06 121.11,54.06 121.29,53.88 121.29,53.62 121.11,53.44 120.53,53.44 120.35,53.26 120.35,53 120.53,52.82 121.11,52.82 121.29,52.64 121.29,52.27 121.17,52.15 120.46,52.15 120.33,52.02 120.33,51.14 120.33,50.88 121.28,49.93 121.28,49.67 121.1,49.49 120.84,49.49 119.89,50.44 119.63,50.44 119.45,50.25 119.45,50 120.4,49.05 120.4,48.79 120.22,48.61 119.96,48.61 119.01,49.56 118.75,49.56 118.57,49.37 118.57,49.12 119.52,48.17 119.52,47.91 119.34,47.73 119.08,47.73 118.13,48.68 117.87,48.68 115.21,46.01 115.21,38.94 113.99,37.72 113.99,37.53 115.02,36.5 115.02,34.19 v2(115.2,34.01)
  BOTTOM w0.102: 122.76,69.74 122.76,70.86 122.17,71.46 UC1.AG32
  BOTTOM w0.127: JDIMM1.107 122.7,25.92 122.46,26.16 120.07,26.16 118.46,27.77 v2(118.05,27.77) ; JDIMM2.107 114.5,36.02 114.59,35.93 114.59,34.51 113.51,33.43 113.51,33.25 113.68,33.08 113.86,33.08 114.84,34.06 115.14,34.06 v2(115.2,34.01)
  BOTTOM w0.157: 122.76,69.74 v2(121.96,68.94)
DDRAB_SMA11: length 81.4
  IN1 w0.216: v2(114.93,68.94) 114.6,68.61 114.6,60.3 114.45,60.15 114.45,59.92 114.6,59.77 114.6,59.46 114.4,59.26 114.14,59.26 113.6,59.79 113.42,59.79 113.16,59.53 113.16,59.35 113.7,58.82 113.7,58.56 108.34,53.2 108.34,43.65 107.75,43.07 106.47,43.07 106.23,42.82 106.23,40.86 105.82,40.45 105.82,36.64 107.9,34.56 107.9,33.95 108.33,33.52 108.33,31.72 111.18,28.88 111.18,26.98 112.12,26.03 112.12,25.1 113.66,23.56 113.66,21.87 113.86,21.67 114.69,21.67 114.89,21.87 v2(114.89,22.2)
  IN2 w0.127: v2(107.61,28.6) 107.99,28.6 108.34,28.26 108.5,28.26 110.24,26.52 110.62,26.52 114.94,22.2 v2(114.89,22.2)
  BOTTOM w0.102: UC1.Y32 116.57,71.82 116.25,71.51 116.25,70.59 115.58,69.92 115.58,69.59 v2(114.93,68.94)
  BOTTOM w0.127: JDIMM1.84 115.8,17.74 115.92,17.86 115.92,18.03 115.83,18.12 115.13,18.12 115.03,18.22 115.03,18.52 115.16,18.64 115.7,18.64 115.83,18.77 115.83,19.05 115.7,19.18 115.16,19.18 115.03,19.3 115.03,22.06 v2(114.89,22.2) ; v2(107.61,28.6) 107.6,28.61 JDIMM2.84
DDRAB_SMA12: length 77.9
  IN1 w0.102: 114.08,67.7 114.34,67.96 114.34,68.91 v2(114.96,69.52)
  IN1 w0.127: v2(110.7,27.34) 110.7,28.68 107.85,31.52 107.85,33.33 107.4,33.78 v2(107.36,33.78)
  IN1 w0.216: 114.08,67.7 114.08,66.74 113.9,66.56 113.62,66.56 113.49,66.43 113.49,66.07 113.62,65.94 113.9,65.94 114.08,65.76 114.08,65.5 113.9,65.32 112.84,65.32 112.66,65.13 112.66,64.88 112.84,64.69 113.9,64.69 114.08,64.51 114.08,64.25 113.9,64.07 112.84,64.07 112.66,63.89 112.66,63.63 112.84,63.45 113.9,63.45 114.08,63.27 114.08,63.01 113.9,62.83 112.84,62.83 112.66,62.64 112.66,62.39 112.84,62.2 113.9,62.2 114.08,62.02 114.08,61.76 113.9,61.58 112.84,61.58 112.66,61.4 112.66,61.14 112.84,60.96 113.9,60.96 114.08,60.78 114.08,60.52 113.9,60.34 112.84,60.34 112.64,60.14 112.64,58.23 107.82,53.41 107.82,44.99 107.69,44.87 106.98,44.87 106.8,44.68 106.8,44.43 106.98,44.24 107.52,44.24 107.65,44.12 107.65,43.71 107.52,43.59 105.84,43.59 105.71,43.46 105.71,41.07 105.3,40.67 105.3,35.97 105.5,35.76 105.96,35.76 107.36,34.37 v2(107.36,33.78)
  BOTTOM w0.102: v2(114.96,69.52) 115.38,69.94 115.38,70 115.71,70.33 115.71,70.86 UC1.W33
  BOTTOM w0.127: v2(110.7,27.34) 111.5,27.34 111.76,27.08 112.5,27.08 113.01,26.57 114.33,26.57 114.76,26.14 115.18,26.14 115.5,25.82 JDIMM1.83 ; JDIMM2.83 107.3,36.95 107.17,36.82 106.76,36.82 106.64,36.7 106.64,36.42 106.76,36.29 107.17,36.29 107.3,36.16 107.3,35.88 107.17,35.76 106.22,35.76 106.09,35.63 106.09,35.35 106.22,35.22 107.17,35.22 107.3,35.1 107.3,33.84 v2(107.36,33.78)
DDRAB_SMA13: length 84
  IN1 w0.102: 125.71,67.8 125.53,67.98 125.53,69.77 125.75,69.99 v2(126.25,69.99)
  IN1 w0.127: v2(120.91,33.71) 121.04,33.58 121.39,33.58 121.5,33.46 121.5,33.11 121.41,33.02 120.68,33.02 120.5,32.84 120.5,32.65 120.66,32.49 120.99,32.49 121.11,32.36 121.11,32.11 120.99,31.98 119.65,31.98 119.53,31.85 119.53,31.56 119.65,31.43 120.78,31.43 120.9,31.31 120.9,30.11 121.03,29.99 121.37,29.99 121.49,29.86 121.49,29.58 121.37,29.45 121.03,29.45 120.9,29.33 120.9,29.01 120.74,28.85 120.74,28.44 121.14,28.04 121.14,27.89 121.43,27.6 121.72,27.6 121.91,27.79 121.91,27.98 121.75,28.14 v2(121.55,28.14)
  IN1 w0.216: 125.71,67.8 125.89,67.62 125.95,67.62 126.13,67.44 126.13,67.18 125.95,67 125.89,67 125.71,66.81 125.71,66.55 125.9,66.36 126.11,66.36 126.29,66.17 126.29,65.92 126.11,65.73 125.66,65.73 125.47,65.55 125.47,65.29 125.66,65.11 126.11,65.11 126.29,64.93 126.29,64.67 126.11,64.49 125.66,64.49 125.47,64.31 125.47,64.05 125.66,63.87 126.11,63.87 126.29,63.69 126.29,63.43 126.11,63.25 125.66,63.25 125.47,63.06 125.47,62.81 125.66,62.62 126.11,62.62 126.29,62.44 126.29,62.18 126.11,62 125.66,62 125.47,61.82 125.47,61.56 125.66,61.38 126.11,61.38 126.29,61.2 126.29,60.94 126.11,60.76 125.66,60.76 125.47,60.57 125.47,60.32 125.66,60.13 126.11,60.13 126.29,59.95 126.29,59.69 126.11,59.51 125.66,59.51 125.47,59.33 125.47,59.07 125.66,58.89 126.11,58.89 126.29,58.71 126.29,58.45 126.11,58.27 125.66,58.27 125.47,58.08 125.47,57.81 125.66,57.63 126.16,57.63 126.28,57.5 126.28,57.13 126.16,57.01 125.66,57.01 125.47,56.82 125.47,41.18 125.18,40.88 125.18,38.57 123.6,37 123.25,36.64 123.25,36.32 120.91,33.99 v2(120.91,33.71)
  BOTTOM w0.102: v2(126.25,69.99) 125.87,70.37 125.87,71.16 125.85,71.19 125.85,71.86 125.77,71.93 125.77,72.46 125.71,72.52 UC1.AL31
  BOTTOM w0.127: JDIMM1.119 126.3,26.2 126.03,26.47 125.87,26.47 125.74,26.33 125.56,26.33 125.36,26.53 125.36,26.71 125.51,26.85 125.51,27.03 125.33,27.2 125.18,27.2 125.01,27.04 124.84,27.04 124.67,27.2 124,27.2 123.17,28.04 123.16,28.04 122.74,28.46 122.49,28.46 122.37,28.35 122.37,28.27 122.24,28.14 v2(121.55,28.14) ; v2(120.91,33.71) 121.16,33.71 121.29,33.58 121.29,33.27 121.16,33.15 120.81,33.15 120.68,33.02 120.68,32.72 120.39,32.42 120.21,32.42 120.12,32.51 120.12,35 120,35.13 119.07,35.13 118.93,35.27 118.93,36.17 118.8,36.3 117.4,36.3 117.33,36.37 117.33,36.76 117.43,36.86 118,36.86 118.1,36.96 JDIMM2.119
DDRAB_SMA14: length 79.8
  IN1 w0.102: v2(116.06,72.12) 116.06,71.95 111.81,67.7
  IN1 w0.216: v2(111.89,23.25) 111.05,23.25 110.27,24.04 110.27,24.52 110.56,24.82 110.56,25.22 107.63,28.14 107.4,28.14 107.11,28.44 107.11,28.69 105.52,30.28 105.52,32.4 105.26,32.66 105.26,33.26 104.84,33.68 103.61,33.68 103.21,34.08 103.21,45.84 103.41,46.04 104.49,46.04 104.64,46.18 104.64,53.18 109.33,57.88 109.33,61.46 109.75,61.88 110.43,61.88 110.55,62 110.55,62.39 110.43,62.51 110.15,62.51 110.03,62.64 110.03,63.14 110.15,63.26 110.43,63.26 110.55,63.39 110.55,66.44 111.81,67.7
  IN2 w0.127: v2(107.02,27.89) 107.19,27.71 107.66,27.71 107.98,27.39 108.14,27.39 109.88,25.65 110.04,25.65 111.04,24.65 111.04,23.62 111.41,23.25 v2(111.89,23.25)
  BOTTOM w0.102: v2(116.06,72.12) 116.07,72.14 116.07,73.02 UC1.W30
  BOTTOM w0.127: JDIMM2.80 106.4,28.77 107.02,28.16 v2(107.02,27.89) ; v2(111.89,23.25) 114.6,20.55 JDIMM1.80
DDRAB_SMA15: length 81.1
  TOP w0.127: v2(106.18,28.18) 106.18,27.98 107.68,26.48 109.34,26.48 v1(109.47,26.35) 111,24.82 111,23.43 v2(111.93,22.5)
  IN1 w0.102: 113.03,67.7 113.03,67.83 v2(113.66,68.46)
  IN1 w0.216: v2(111.93,22.5) 111.6,22.5 111.47,22.38 111.47,21.45 111.6,21.32 112.48,21.32 112.6,21.45 112.6,23.55 111.6,24.55 111.6,25.65 109.33,27.92 109.33,28.04 108.96,28.41 108.96,29.13 106.91,31.18 106.82,31.18 106.56,31.44 106.56,33.14 106.31,33.4 106.31,33.95 105.53,34.72 104.43,34.72 104.26,34.89 104.26,44.78 104.47,44.99 105.49,44.99 105.68,45.17 105.68,52.75 111.59,58.66 111.59,66.01 113.03,67.44 113.03,67.7
  BOTTOM w0.102: v2(113.66,68.46) 113.66,68.46 114.52,69.32 114.52,71.67 UC1.V32
  BOTTOM w0.127: JDIMM2.78 105.8,28.56 v2(106.18,28.18) ; JDIMM1.78 114,19.03 113.45,19.58 113.45,19.76 113.52,19.82 113.52,20 113.32,20.2 113.14,20.2 113.07,20.13 112.89,20.13 112.69,20.33 112.69,20.51 112.82,20.64 112.82,20.82 112.62,21.01 112.44,21.01 112.32,20.89 112.14,20.89 111.93,21.09 v2(111.93,22.5)
DDRAB_SRAS#: length 80.8
  IN1 w0.216: v2(119.17,22.49) 119.17,24.37 118.53,25.01 118.53,25.21 118.35,25.39 118.17,25.39 117.99,25.57 117.99,25.83 118.17,26.01 118.35,26.01 118.53,26.19 118.53,26.55 118.4,26.68 117.65,26.68 117.52,26.8 117.52,27.17 117.65,27.3 118.4,27.3 118.53,27.43 118.53,28.55 118.16,28.93 118.16,29.26 117.94,29.48 117.94,30.32 117.02,31.24 117.02,31.93 116.45,32.51 116.45,33.23 116.29,33.39 116.29,34.53 116.06,34.76 116.06,35.22 116.22,35.38 116.54,35.38 116.67,35.51 116.67,36.02 116.54,36.15 116.25,36.15 116.07,36.33 116.07,36.59 116.25,36.77 116.94,36.77 117.13,36.95 117.13,37.25 116.94,37.43 115.81,37.43 115.63,37.61 115.63,37.87 115.81,38.05 116.94,38.05 117.13,38.23 117.13,38.55 116.94,38.74 116.85,38.74 116.67,38.92 116.67,39.18 116.85,39.36 116.94,39.36 117.13,39.54 117.13,40.61 117.72,41.2 117.72,44.43 122.35,49.06 122.35,67.88 122.61,68.14 122.61,68.52 123.39,69.3 v2(123.55,69.3)
  IN2 w0.127: v2(119.17,22.49) 119.02,22.65 119.02,24.03 117.05,26 117.05,27.89 117.21,28.05 v2(117.47,28.05)
  BOTTOM w0.102: UC1.AH33 122.97,69.88 v2(123.55,69.3)
  BOTTOM w0.127: v2(117.47,28.05) 117.6,28.18 117.6,28.56 117.36,28.8 115.65,28.8 115.4,29.06 JDIMM2.110 ; JDIMM1.110 123.6,18.28 122.73,19.15 122.73,19.33 123.04,19.65 123.04,19.83 122.84,20.03 122.66,20.03 122.35,19.71 122.17,19.71 121.97,19.91 121.97,20.09 122.29,20.4 122.29,20.58 122.09,20.78 121.91,20.78 121.59,20.47 121.41,20.47 119.39,22.49 v2(119.17,22.49)
DDRAB_SWE#: length 83.2
  IN1 w0.102: v2(124.82,69.07) 124.38,69.07 124.31,68.99 124.31,68.23 124.15,68.08
  IN1 w0.127: v2(118.01,33.44) 118.26,33.19 118.26,32.94 118.65,32.54 118.65,30.89 118.85,30.69 118.85,29.85 119.07,29.64 119.07,29.3 119.44,28.93 119.44,26.37 119.56,26.24 120,26.24 120.12,26.11 120.12,25.83 120,25.71 119.56,25.71 119.44,25.58 119.44,25.39 120.03,24.79 120.35,24.79 120.54,24.98 120.54,25.39 120.78,25.63 121.38,25.63 121.51,25.76 121.51,26.07 121.38,26.2 121.13,26.2 121,26.32 121,26.6 121.05,26.66 121.32,26.66 121.61,26.95 121.61,27.05 121.71,27.15 121.88,27.15 v2(121.97,27.24)
  IN1 w0.216: 124.15,68.08 124.15,67.42 123.91,67.19 123.91,45.3 120.66,42.06 120.66,41 119.73,40.07 119.73,36.48 119.45,36.2 119.45,35.73 119.61,35.56 120.38,35.56 120.48,35.46 120.48,35.03 120.23,34.78 118.84,34.78 118.7,34.64 118.7,33.97 118.83,33.85 119.07,33.85 119.36,34.14 119.59,34.14 119.72,34.01 119.72,33.47 119.29,33.04 118.85,33.04 118.41,33.48 118.06,33.48 v2(118.01,33.44)
  BOTTOM w0.102: UC1.AJ31 124.09,72.52 124.17,72.44 124.17,71.77 124.26,71.68 124.26,71.19 124.27,71.18 124.27,70.71 124.14,70.57 124.14,68.77 124.25,68.66 124.49,68.66 124.82,68.99 v2(124.82,69.07)
  BOTTOM w0.127: v2(121.97,27.24) 121.99,27.26 122.72,27.26 123.77,26.21 124.38,26.21 124.5,26.09 JDIMM1.113 ; v2(118.01,33.44) 118.01,34.29 117.89,34.42 117.6,34.42 117.47,34.29 117.47,33.32 117.34,33.2 117.06,33.2 116.94,33.32 116.94,34.21 116.81,34.34 116.45,34.34 116.33,34.46 116.33,34.74 116.45,34.87 117.94,34.87 118.07,35 118.07,35.22 117.94,35.35 115.59,35.35 115.46,35.48 115.46,35.76 115.59,35.88 116.34,35.88 116.47,36.01 116.47,36.26 116.34,36.39 115.58,36.39 115.46,36.52 115.46,36.8 115.58,36.92 116.14,36.92 116.3,37.08 JDIMM2.113
DDRB_CLK0: length 68.7
  IN2 w0.102: 119.47,67.7 119.47,67.91 119.81,68.25 119.81,68.67 119.38,69.09 v2(119.2,69.09)
  IN2 w0.216: 119.47,67.7 119.47,66.98 113.56,61.07 113.56,48.57 113.08,48.09 112.36,48.09 112.24,47.96 112.24,47.29 112.36,47.16 113.08,47.16 113.56,46.69 113.56,45.82 113.08,45.35 110.9,45.35 110.78,45.22 110.78,44.55 110.9,44.42 113.08,44.42 113.56,43.94 113.56,43.08 113.08,42.6 110.89,42.6 110.76,42.48 110.76,41.8 110.89,41.68 113.08,41.68 113.56,41.2 113.56,40.22 113.18,39.84 113.18,39.15 112.6,38.58 111.16,38.58 111.03,38.46 111.03,35.06 111.16,34.93 111.84,34.93 111.97,35.06 111.97,37.03 112.3,37.36 115.44,37.36 115.83,36.98 115.83,35.52 115.37,35.06 v2(113.93,35.06)
  BOTTOM w0.102: v2(119.2,69.09) 119.73,69.63 119.73,70.44 119.55,70.62 119.55,71.08 119.4,71.23 119.4,71.76 UC1.AD32
  BOTTOM w0.196: JDIMM2.101 112.7,35.73 113.37,35.06 v2(113.93,35.06)
DDRB_CLK0#: length 68.8
  IN2 w0.102: 119.02,67.7 119.02,67.71 119.08,67.77 119.08,67.86 119.14,67.91 119.16,67.91 119.6,68.35 119.6,68.58 119.46,68.72 119.32,68.72 119.2,68.6 v2(119.2,68.51)
  IN2 w0.216: 119.02,67.7 119.02,67.16 113.11,61.25 113.11,48.75 112.9,48.54 112.18,48.54 111.79,48.15 111.79,47.11 112.18,46.72 112.9,46.72 113.11,46.5 113.11,46.01 112.9,45.79 110.72,45.79 110.33,45.4 110.33,44.36 110.72,43.98 112.9,43.98 113.11,43.76 113.11,43.26 112.9,43.05 110.71,43.05 110.32,42.66 110.32,41.62 110.71,41.23 112.9,41.23 113.11,41.02 113.11,40.41 112.73,40.02 112.73,39.34 112.42,39.03 110.97,39.03 110.58,38.64 110.58,34.88 110.97,34.49 112.03,34.49 112.41,34.88 112.41,36.85 112.48,36.92 115.26,36.92 115.39,36.79 115.39,35.71 115.19,35.51 114.06,35.51 v2(113.93,35.65)
  BOTTOM w0.102: v2(119.2,68.51) 120.04,69.35 120.04,70.57 119.86,70.75 119.86,70.9 120.3,71.35 120.3,71.49 120.22,71.56 120.22,71.79 120.14,71.88 119.96,71.88 119.65,71.57 119.65,71.43 UC1.AD33
  BOTTOM w0.196: JDIMM2.103 113.3,37.15 113.1,36.95 113.1,35.9 113.54,35.46 113.74,35.46 v2(113.93,35.65)
DDRB_CLK1: length 68.2
  IN2 w0.102: 118.01,67.7 118.01,67.71 117.89,67.83 117.89,67.96 118.69,68.76 118.69,69.9 118.85,70.07 119.51,70.07 119.59,69.99 119.59,69.79 119.47,69.68 v2(119.2,69.68)
  IN2 w0.216: 118.01,67.7 118.01,67.51 112.16,61.66 112.16,52.66 111.67,52.17 110.13,52.17 110,52.04 110,51.37 110.13,51.24 111.67,51.24 112.15,50.77 112.15,49.9 111.67,49.43 109.56,49.43 109.34,49.21 109.34,48.63 109.56,48.42 110.25,48.42 110.72,47.94 110.72,47.08 110.25,46.6 109.56,46.6 109.34,46.38 109.34,40.73 109.65,40.42 109.65,38.95 109.25,38.56 106.71,38.56 106.58,38.43 106.58,37.71 106.71,37.58 108.93,37.58 109.34,37.17 109.34,34.81 111.52,32.63 111.52,31.32 111.65,31.19 112.81,31.19 112.93,31.32 112.93,32.33 113.39,32.79 114.96,32.79 v2(115.15,32.97)
  BOTTOM w0.102: UC1.AC33 118.97,70.92 118.79,70.74 118.79,69.82 118.94,69.68 v2(119.2,69.68)
  BOTTOM w0.196: JDIMM2.102 113,30.95 113.1,31.05 113.1,31.63 113.67,32.2 114.46,32.2 115.15,32.89 v2(115.15,32.97)
DDRB_CLK1#: length 68.3
  IN2 w0.102: 117.57,67.7 117.57,67.71 117.69,67.83 117.69,68.04 118.48,68.84 118.48,70 118.8,70.32 119.06,70.32 v2(119.19,70.45)
  IN2 w0.216: 117.57,67.7 111.72,61.84 111.72,52.84 111.49,52.61 109.94,52.61 109.56,52.23 109.56,51.18 109.94,50.8 111.49,50.8 111.7,50.58 111.7,50.09 111.49,49.87 109.37,49.87 108.9,49.39 108.9,48.45 109.37,47.97 110.06,47.97 110.28,47.76 110.28,47.26 110.06,47.04 109.37,47.04 108.9,46.57 108.9,40.54 109.2,40.24 109.2,39.14 109.07,39 106.53,39 106.14,38.61 106.14,37.52 106.53,37.13 108.75,37.13 108.9,36.99 108.9,34.63 111.08,32.44 111.08,31.13 111.47,30.75 112.99,30.75 113.38,31.13 113.38,32.15 113.58,32.35 115.35,32.35 v2(115.54,32.55)
  BOTTOM w0.102: UC1.AC32 118.88,71.63 118.88,71.35 118.95,71.27 119.07,71.27 119.28,71.06 119.28,70.55 v2(119.19,70.45)
  BOTTOM w0.196: v2(115.54,32.55) 115.37,32.55 114.62,31.8 113.84,31.8 113.5,31.46 113.5,31.08 113.6,30.98 JDIMM2.104
DDRB_ODT0: length 65
  IN1 w0.216: v2(123.55,68.69) 123.48,68.76 123.3,68.76 123.11,68.57 123.11,67.87 122.87,67.63 122.87,48.75 122.73,48.62 122.73,48.45 122.84,48.34 122.84,48.06 122.64,47.85 122.45,47.85 122.29,48.01 122.04,48.01 121.85,47.83 121.85,47.57 122.87,46.56 122.87,46.2 122.69,46.03 122.51,46.03 121.41,47.13 121.15,47.13 120.97,46.95 120.97,46.69 122.31,45.35 122.31,45.17 122.05,44.91 121.87,44.91 120.53,46.25 120.27,46.25 120.09,46.07 120.09,45.81 121.43,44.47 121.43,44.29 121.17,44.03 120.99,44.03 119.59,45.43 119.45,45.43 119.16,45.13 119.16,44.98 120.55,43.59 120.55,43.41 120.29,43.15 120.11,43.15 118.72,44.54 118.56,44.54 118.24,44.22 118.24,44.04 118.42,43.87 118.42,43.58 118.24,43.4 118.24,43.1 118.46,42.89 118.61,42.89 118.99,43.27 119.12,43.27 119.42,42.96 119.42,42.81 118.88,42.27 118.41,42.27 118.24,42.1 118.24,40.99 117.65,40.39 117.65,36.74 117.19,36.28 117.19,35.29 116.97,35.06 116.97,32.73 117.48,32.22 v2(117.79,32.22)
  BOTTOM w0.102: v2(123.55,68.69) 123.7,68.69 123.93,68.92 123.93,70.65 124.07,70.79 124.07,71.12 123.96,71.23 123.58,71.23 123.52,71.29 123.52,71.68 123.55,71.72 UC1.AJ32 ; v2(117.79,32.22) 117.79,32.01 117.2,31.42 117.2,30.79
  BOTTOM w0.127: JDIMM2.116 117.2,30.79
DDRB_ODT1: length 67.1
  IN1 w0.102: 126.34,67.88 126,67.88 125.75,68.14 125.75,69.16 126.02,69.43 v2(126.23,69.43)
  IN1 w0.216: v2(121.22,28.63) 121.69,29.1 121.89,29.1 121.98,29.18 121.98,30.33 121.85,30.45 121.52,30.45 121.39,30.58 121.39,30.89 121.52,31.02 121.79,31.02 121.98,31.2 121.98,33.66 121.74,33.9 121.74,34.07 123.77,36.11 123.77,36.42 124.35,37.01 125.7,38.35 125.7,40.67 126,40.97 126,51.05 126.19,51.23 127.33,51.23 127.46,51.36 127.46,51.72 127.33,51.85 126.19,51.85 126,52.03 126,52.39 126.19,52.57 127.4,52.57 127.53,52.7 127.53,53.07 127.4,53.19 126.19,53.19 126,53.37 126,53.63 126.19,53.81 127.34,53.81 127.53,54 127.53,54.25 127.34,54.44 126.19,54.44 126,54.62 126,54.88 126.19,55.06 127.34,55.06 127.53,55.24 127.53,55.5 127.34,55.68 126.19,55.68 126,55.86 126,56.12 126.19,56.3 127.34,56.3 127.53,56.49 127.53,56.83 127.34,57.02 126.99,57.02 126.8,57.2 126.8,57.46 126.99,57.64 127.34,57.64 127.53,57.82 127.53,58 127.24,58.29 126.94,58.29 126.83,58.41 126.83,67.39 126.34,67.88
  BOTTOM w0.102: UC1.AM33 126.17,70.61 126.67,70.11 126.67,69.62 126.48,69.43 v2(126.23,69.43)
  BOTTOM w0.127: JDIMM2.120 118.4,28.83 118.31,28.74 118.15,28.74 118.03,28.61 118.03,28.32 118.14,28.21 118.64,28.21 118.8,28.37 118.8,28.54 118.91,28.65 119.21,28.65 119.34,28.52 119.34,28.07 119.46,27.94 120.2,27.94 120.33,28.07 120.33,28.51 120.45,28.63 v2(121.22,28.63)
DDRB_SA0: length 3.1
  TOP w0.127: v2(141.81,39.5) 141.75,39.44 R690.2 v1(140.82,38.79)
  BOTTOM w0.127: JDIMM2.197 141.5,39.2 v2(141.81,39.5)
DDRB_SCS0#: length 67
  IN1 w0.216: v2(115.77,33.78) 115.77,34.32 115.54,34.54 115.54,36.71 114.83,37.43 114.83,37.82 116.15,39.14 116.15,39.93 116.22,40 116.5,40 116.59,40.09 116.59,40.49 116.48,40.6 115.87,40.6 115.73,40.74 115.73,41.11 115.91,41.29 117.07,41.29 117.2,41.42 117.2,41.79 117.07,41.91 115.91,41.91 115.73,42.1 115.73,42.35 115.91,42.54 117.07,42.54 117.2,42.66 117.2,43.03 117.07,43.16 115.91,43.16 115.73,43.34 115.73,43.68 115.87,43.81 116.37,43.81 116.86,44.31 116.86,44.63 116.61,44.88 116.46,44.88 116.21,44.63 115.96,44.63 115.77,44.81 115.77,45.07 116.02,45.31 116.02,45.49 115.84,45.68 115.84,45.88 116.11,46.15 116.37,46.15 117.44,45.07 117.62,45.07 117.88,45.33 117.88,45.51 116.81,46.59 116.81,46.85 116.99,47.03 117.25,47.03 118.32,45.95 118.5,45.95 118.76,46.21 118.76,46.39 117.69,47.47 117.69,47.73 117.87,47.91 118.13,47.91 119.16,46.87 119.42,46.87 121.81,49.26 121.81,50.8 121.63,50.98 121.08,50.98 120.9,51.17 120.9,51.42 121.08,51.61 121.63,51.61 121.81,51.79 121.81,68.18 122.48,68.85 122.48,71.24 v2(124.16,72.92)
  BOTTOM w0.102: v2(124.16,72.92) 123.77,73.32 UC1.AJ30
  BOTTOM w0.127: JDIMM2.114 116.6,30.97 116.07,31.5 116.07,33.48 v2(115.77,33.78)
DDRB_SCS1#: length 72
  IN1 w0.216: v2(120.38,36.19) 120.25,36.32 120.25,36.65 120.43,36.84 121.96,36.84 122.09,36.96 122.09,37.33 121.96,37.46 120.36,37.46 120.25,37.57 120.25,38.06 120.35,38.17 122.55,38.17 122.75,38.37 122.75,38.65 122.61,38.79 120.43,38.79 120.25,38.97 120.25,39.85 120.54,40.14 120.79,40.14 121.57,39.36 121.75,39.36 122.01,39.62 122.01,39.8 121.16,40.65 121.16,40.76 121.42,41.02 121.42,41.28 121.2,41.51 121.2,41.69 121.46,41.95 121.64,41.95 122.91,40.68 122.91,39.28 123.06,39.13 123.44,39.13 123.6,39.29 123.6,40.45 123.72,40.57 123.72,40.75 122.03,42.43 122.03,42.69 122.22,42.87 122.47,42.87 123.99,41.35 124.17,41.35 124.43,41.61 124.43,41.79 122.91,43.31 122.91,43.57 123.1,43.75 123.35,43.75 123.94,43.17 124.12,43.17 124.43,43.48 124.43,43.66 123.87,44.22 123.87,44.53 124.43,45.09 124.43,66.97 124.67,67.21 124.67,68.29 v2(124.89,68.51)
  BOTTOM w0.102: v2(124.89,68.51) 124.96,68.44 125.43,68.44 125.61,68.62 125.61,69.62 125.37,69.86 UC1.AL33
  BOTTOM w0.127: JDIMM2.121 118.7,37.2 118.55,37.05 118.55,36.87 118.66,36.75 119.17,36.75 119.37,36.96 119.84,36.96 119.97,36.83 119.97,36.55 119.84,36.42 119.49,36.42 119.36,36.3 119.36,35.69 119.49,35.56 120.25,35.56 120.55,35.26 120.55,34.32 120.69,34.18 121.18,34.18 121.3,34.3 121.3,35.27 v2(120.38,36.19)
DEVSLP0_HDD: length 168.5
  TOP w0.102: v2(129.74,83.2) 129.74,83.58 130.03,83.87 132.19,83.87 132.84,84.52 134.89,84.52 135.48,85.1 139.2,85.1 140.06,85.97 140.12,85.97
  TOP w0.127: v2(195.14,23.5) 195.45,23.8 195.45,40.93 193.26,43.12 v2(192.97,43.12) 192.97,44.89 187.31,50.55 172.81,50.55 172.36,51 170.76,51 170.66,51.1 168.24,51.1 166.93,49.8 166.93,48.68 166.74,48.49 166.74,41.41 163.71,38.38 155.16,38.38 154.17,37.39 154.17,34.28 151.09,31.19 150.01,31.19 148.71,32.49 148.71,36.06 v2(147.36,37.4) ; RH40.2 143.97,86.59 143.32,86.59 142.7,85.97 140.12,85.97
  IN2 w0.127: v2(129.74,83.2) 130.45,82.49 133.21,82.49 133.64,82.06 135.13,82.06 137.89,79.3 137.89,77.75 137.71,77.57 137.71,76.21 138.58,75.35 138.58,54.91 138.8,54.69 138.8,47.94 147.36,39.38 v2(147.36,37.4)
  BOTTOM w0.102: v2(129.74,83.2) 129.47,83.48 UC1.AT17
  BOTTOM w0.127: v2(195.14,23.5) 195.24,23.6 RS45.1 ; v2(192.97,43.12) 192.97,43.07 v1(192.34,42.44) 192.02,42.11 RS8.1
DEVSLP0_HDD_R: length 9.8
  BOTTOM w0.127: JHDD2.4 199.81,29.68 197.5,27.37 RS45.2 196.54,24.51 v1(196.22,24.19)
DEW1: length 5.5
  BOTTOM w0.127: US2.16 184.33,29.34 184.65,29.02 185.67,29.02 185.92,28.77 RS34.1 185.48,27.76 185.48,26.49 RS36.1
DEW2: length 4.7
  BOTTOM w0.127: US2.6 182.33,34.5 181.74,35.09 181.17,35.09 RS33.1 RS35.1 v1(178.77,35.55)
DGPU_PWROK: length 48.1
  TOP w0.127: v2(190.31,72.2) 190.64,72.53 192.22,72.53 192.39,72.36 UE1.18
  IN1 w0.127: v2(190.31,72.2) 190.32,72.19 189.27,72.19 188.79,71.7 187.69,71.7 187.17,72.22 186.5,72.22 186.1,72.62 184.76,72.62 184.43,72.95 183.17,72.95 179.97,76.15 179.97,76.73 179.58,77.11 179.25,77.11 178.2,78.16 177.1,78.16 175.18,80.09 174.58,80.09 173.78,80.89 173.45,80.89 172.23,82.11 169.17,82.11 166.13,85.15 165.72,85.15 164.66,86.21 164.66,87.79 164.46,88 164.46,88.94 162.7,90.7 162.58,90.82 162.58,95.26 v2(163,95.68)
  BOTTOM w0.127: v2(190.31,72.2) v1(190.91,72.2) ; v2(163,95.68) 163.16,95.85 164.17,95.85 PR1122.2
DIR: length 5
  BOTTOM w0.127: RV79.1 189.6,138.67 CV169.2 189.6,136.66 CV167.2 188.88,137.36 v1(188.54,137.36) 188.54,137.25 188.12,136.83 U1.5
DISPOFF#: length 193.4
  TOP w0.127: v2(159.82,72.16) 160.51,72.16 161.23,72.88 162.34,72.88 164.52,75.06 164.52,79.94 163.91,80.55 163.91,84.15 162.96,85.11 162.96,89.7 162.2,90.45 162.2,91.77 164.36,93.93 164.36,103.68 164.98,104.31 165.15,104.31 165.72,104.87 165.72,105.2 163.72,107.2 v2(163.48,107.2) ; U5.4 165.94,38.43 166.19,38.68 RD16.1 166.19,40.02 v2(166.06,40.14)
  IN1 w0.127: v2(159.82,72.16) 159.82,71.91 162.17,69.56 164.12,69.56 166.76,66.92 166.92,66.92 168.17,65.66 168.28,65.66 169.74,64.2 169.74,60.79 168.59,59.63 168.59,47.65 166.06,45.12 v2(166.06,40.14) ; v2(93.22,154.65) 93.22,153.96 92.59,153.33 92.59,148.84 93.99,147.44 93.99,143.44 111.41,126.02 128.17,126.02 131.67,122.53 133.86,120.33 143.78,120.33 149.99,114.13 157.25,114.13 163.48,107.9 v2(163.48,107.2)
  BOTTOM w0.127: JEDP.21 v1(90.8,164.68) 90.8,164.03 94.42,160.42 RX9.1 94.91,159.31 94.91,157.49 DX1.1 94.45,156.19 93.22,154.97 v2(93.22,154.65)
DP0_HPD: length 96.3
  TOP w0.102: Q20.3 63.28,172.54 R384.2 R407.1 v2(64.78,171.65) ; U66.2 105.47,113.41 104.8,112.74 103.33,112.74 RC10.2 99.82,112.09 99.47,112.43 99.47,114.9 v1(100.29,115.72) 101.77,117.2 v2(101.76,117.2)
  IN2 w0.102: v2(93.38,149.22) 91.56,149.22 90.64,150.15 85.88,150.15 81.93,154.1 81.93,155.55 80.62,156.87 80.62,158.86 79.54,159.94 76.03,159.94 65.27,170.7 65.27,171.16 v2(64.78,171.65)
  BOTTOM w0.102: v2(101.76,117.2) 106.14,121.58 106.14,133.49 99.62,140.01 99.62,142.62 93.38,148.87 v2(93.38,149.22)
DP1_HPD: length 107.3
  TOP w0.102: RX14.1 26.52,74.48 27.05,75.01 27.72,75.01 27.95,75.24 QX5.3 27.95,76.49 29.27,77.81 29.27,78.87 28.76,79.37 28.76,80.52 v1(29.64,81.4) 29.75,81.51 v2(38.39,81.51) 40.38,79.51 40.38,74.55 40.89,74.04 RZ42.1 40.89,73.25 40.19,72.56 39.44,72.56 39.27,72.39 UZ1.1
  BOTTOM w0.102: v2(38.39,81.51) 38.63,81.75 63.7,81.75 65.2,83.25 71.65,83.25 85.03,96.63 85.03,96.94 85.91,97.82 85.91,98.22 86.68,99 94.25,99 96.89,96.36 99.47,96.36 99.71,96.11 101.02,96.11 101.27,96.36 102.21,96.36 102.56,96.01 102.56,94.85 103.55,93.86 103.76,93.86 104.1,93.52 UC1.F5
DP1_TXN0_C: length 27.5
  BOTTOM w0.127: CV185.2 43.87,74.16 44.02,74.16 44.19,73.99 44.19,71.88 42.11,69.8 38.75,69.8 29.91,60.96 v3(26.83,60.96) 24.33,60.96 CX18.2
DP1_TXN0_CRT: length 7.4
  TOP w0.127: RZ1046.1 43.85,74.13 44.05,74.13 44.19,73.99 v3(44.19,72.87) 44.19,72.14 42.15,70.1 40.58,70.1 40.46,70.22 UZ1.30
DP1_TXN1_C: length 23.9
  BOTTOM w0.127: CV187.2 42.12,74.18 42.28,74.18 42.41,74.05 42.41,72.52 41.46,71.57 38.21,71.57 31.29,64.64 v3(26.45,64.64) 24.33,64.64 CX16.2
DP1_TXN1_CRT: length 5.3
  TOP w0.127: RZ1048.1 42.12,74.18 42.26,74.18 42.41,74.03 v3(42.41,72.97) 42.41,72.05 41.45,71.1 40.77,71.1 40.65,71.22 UZ1.32
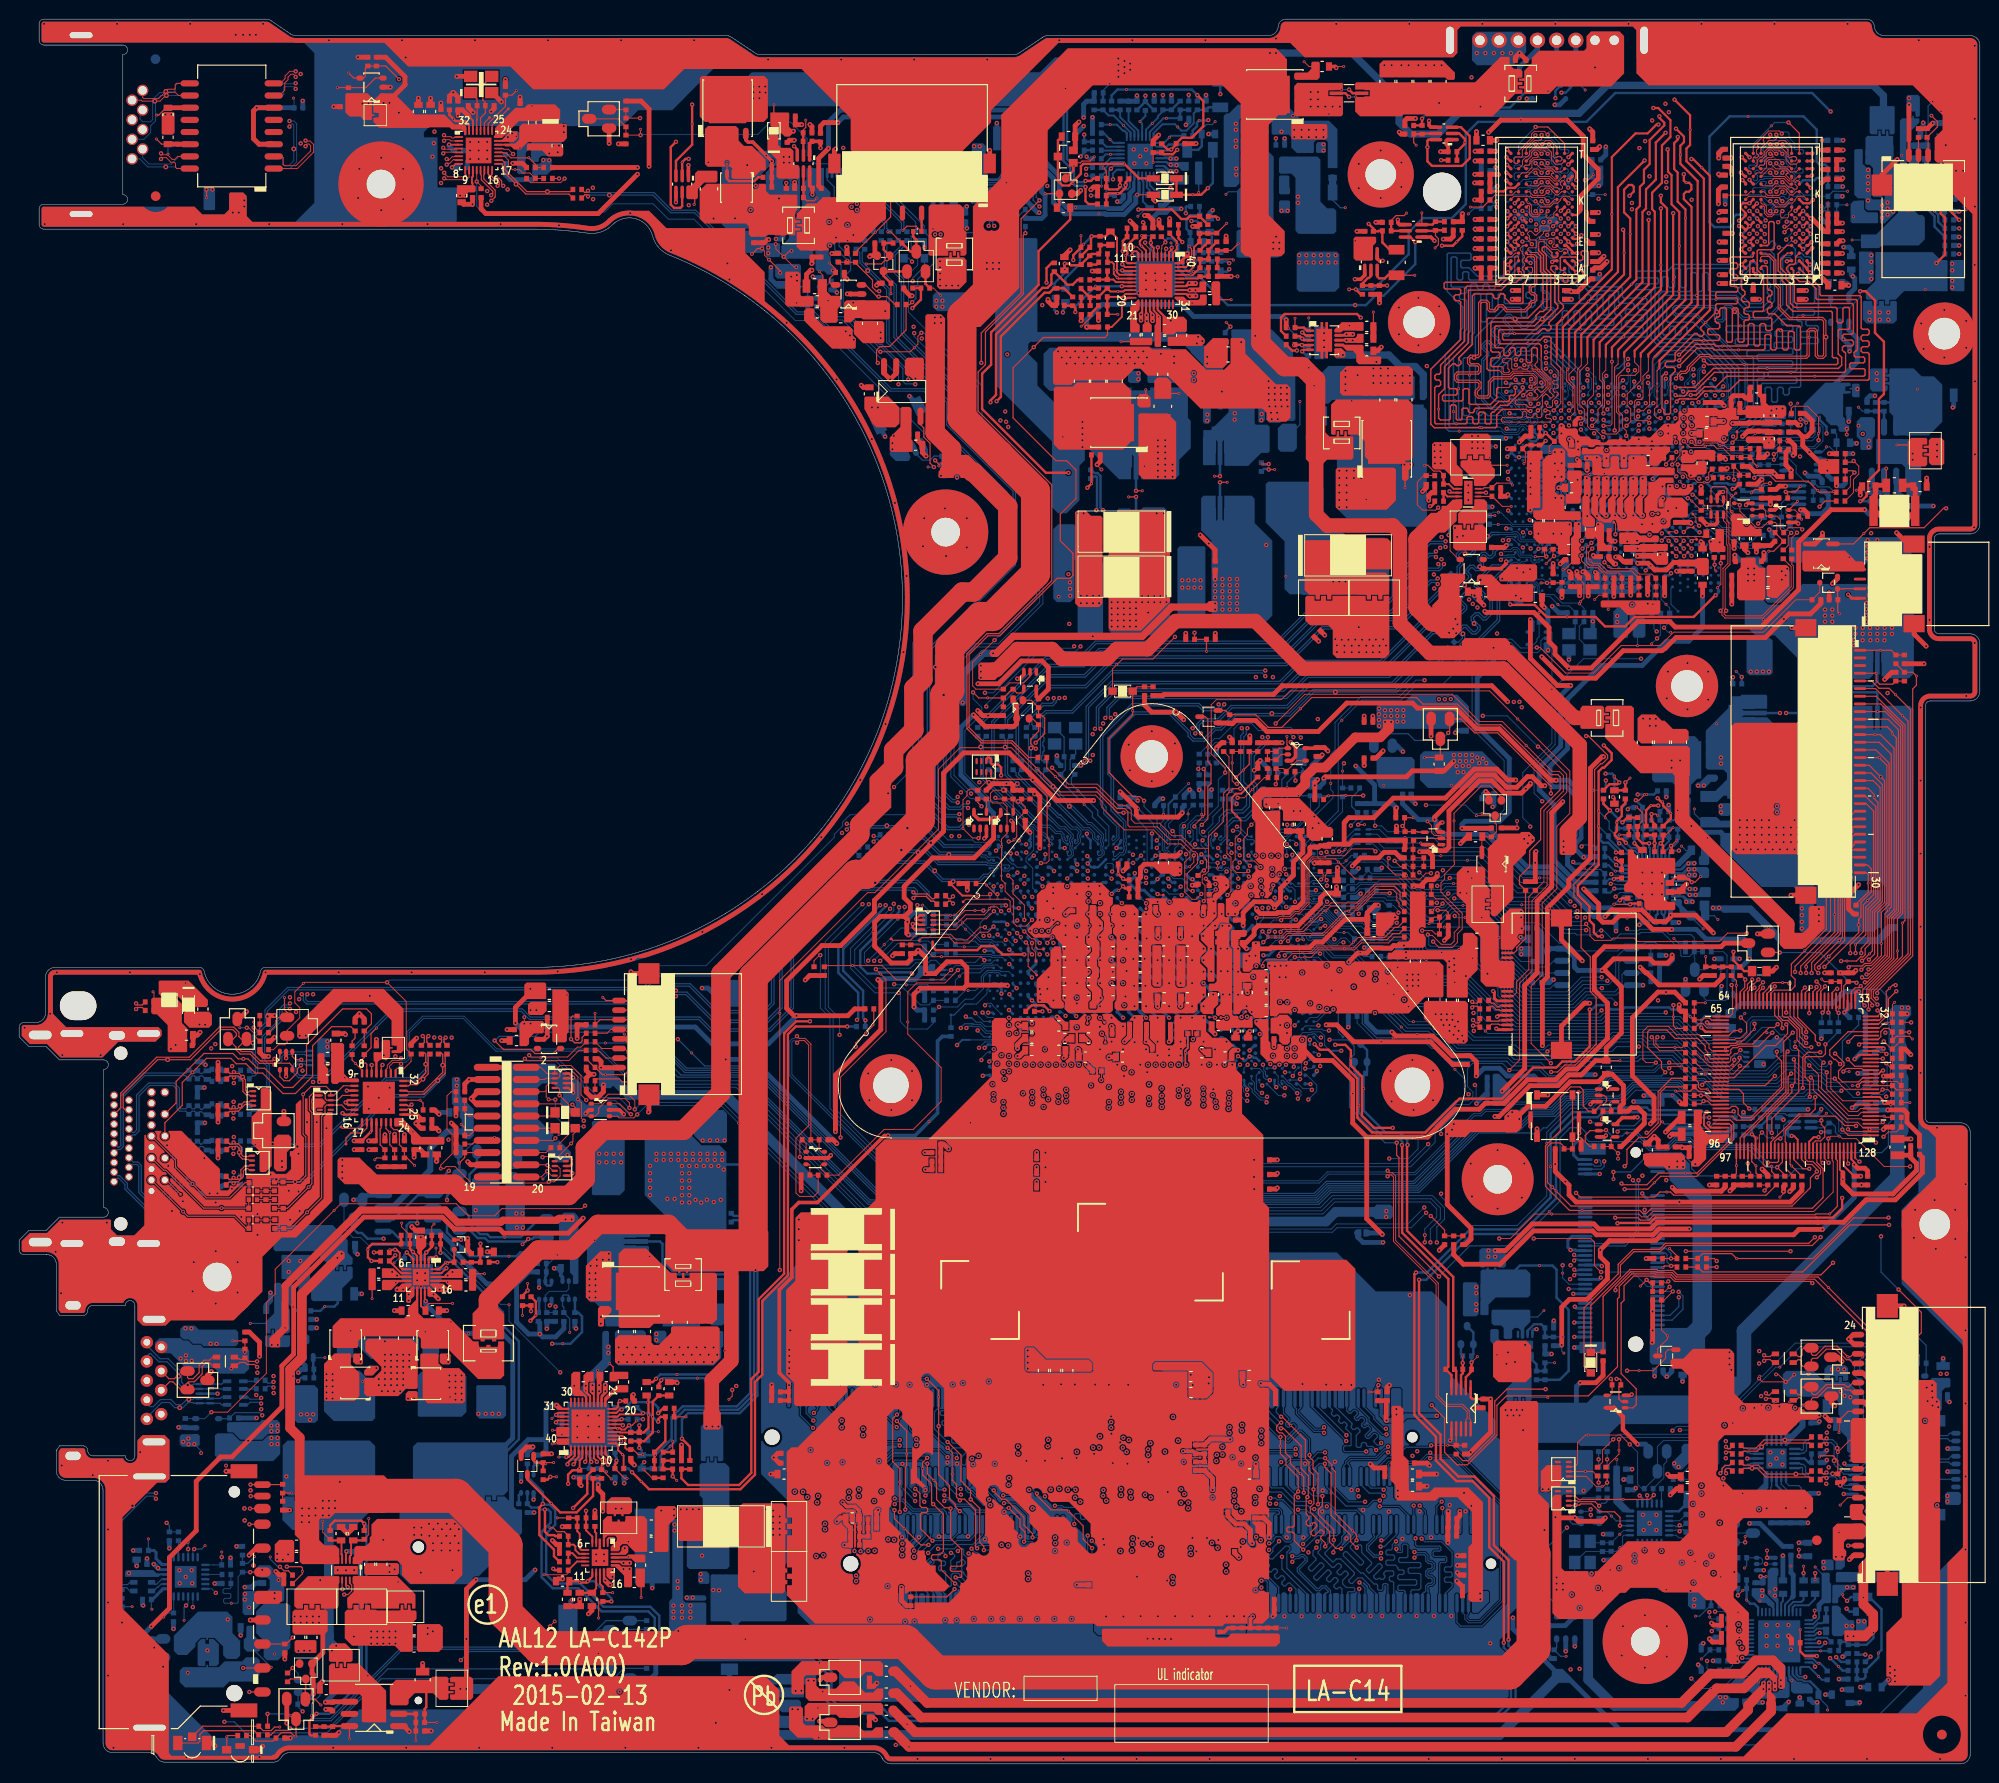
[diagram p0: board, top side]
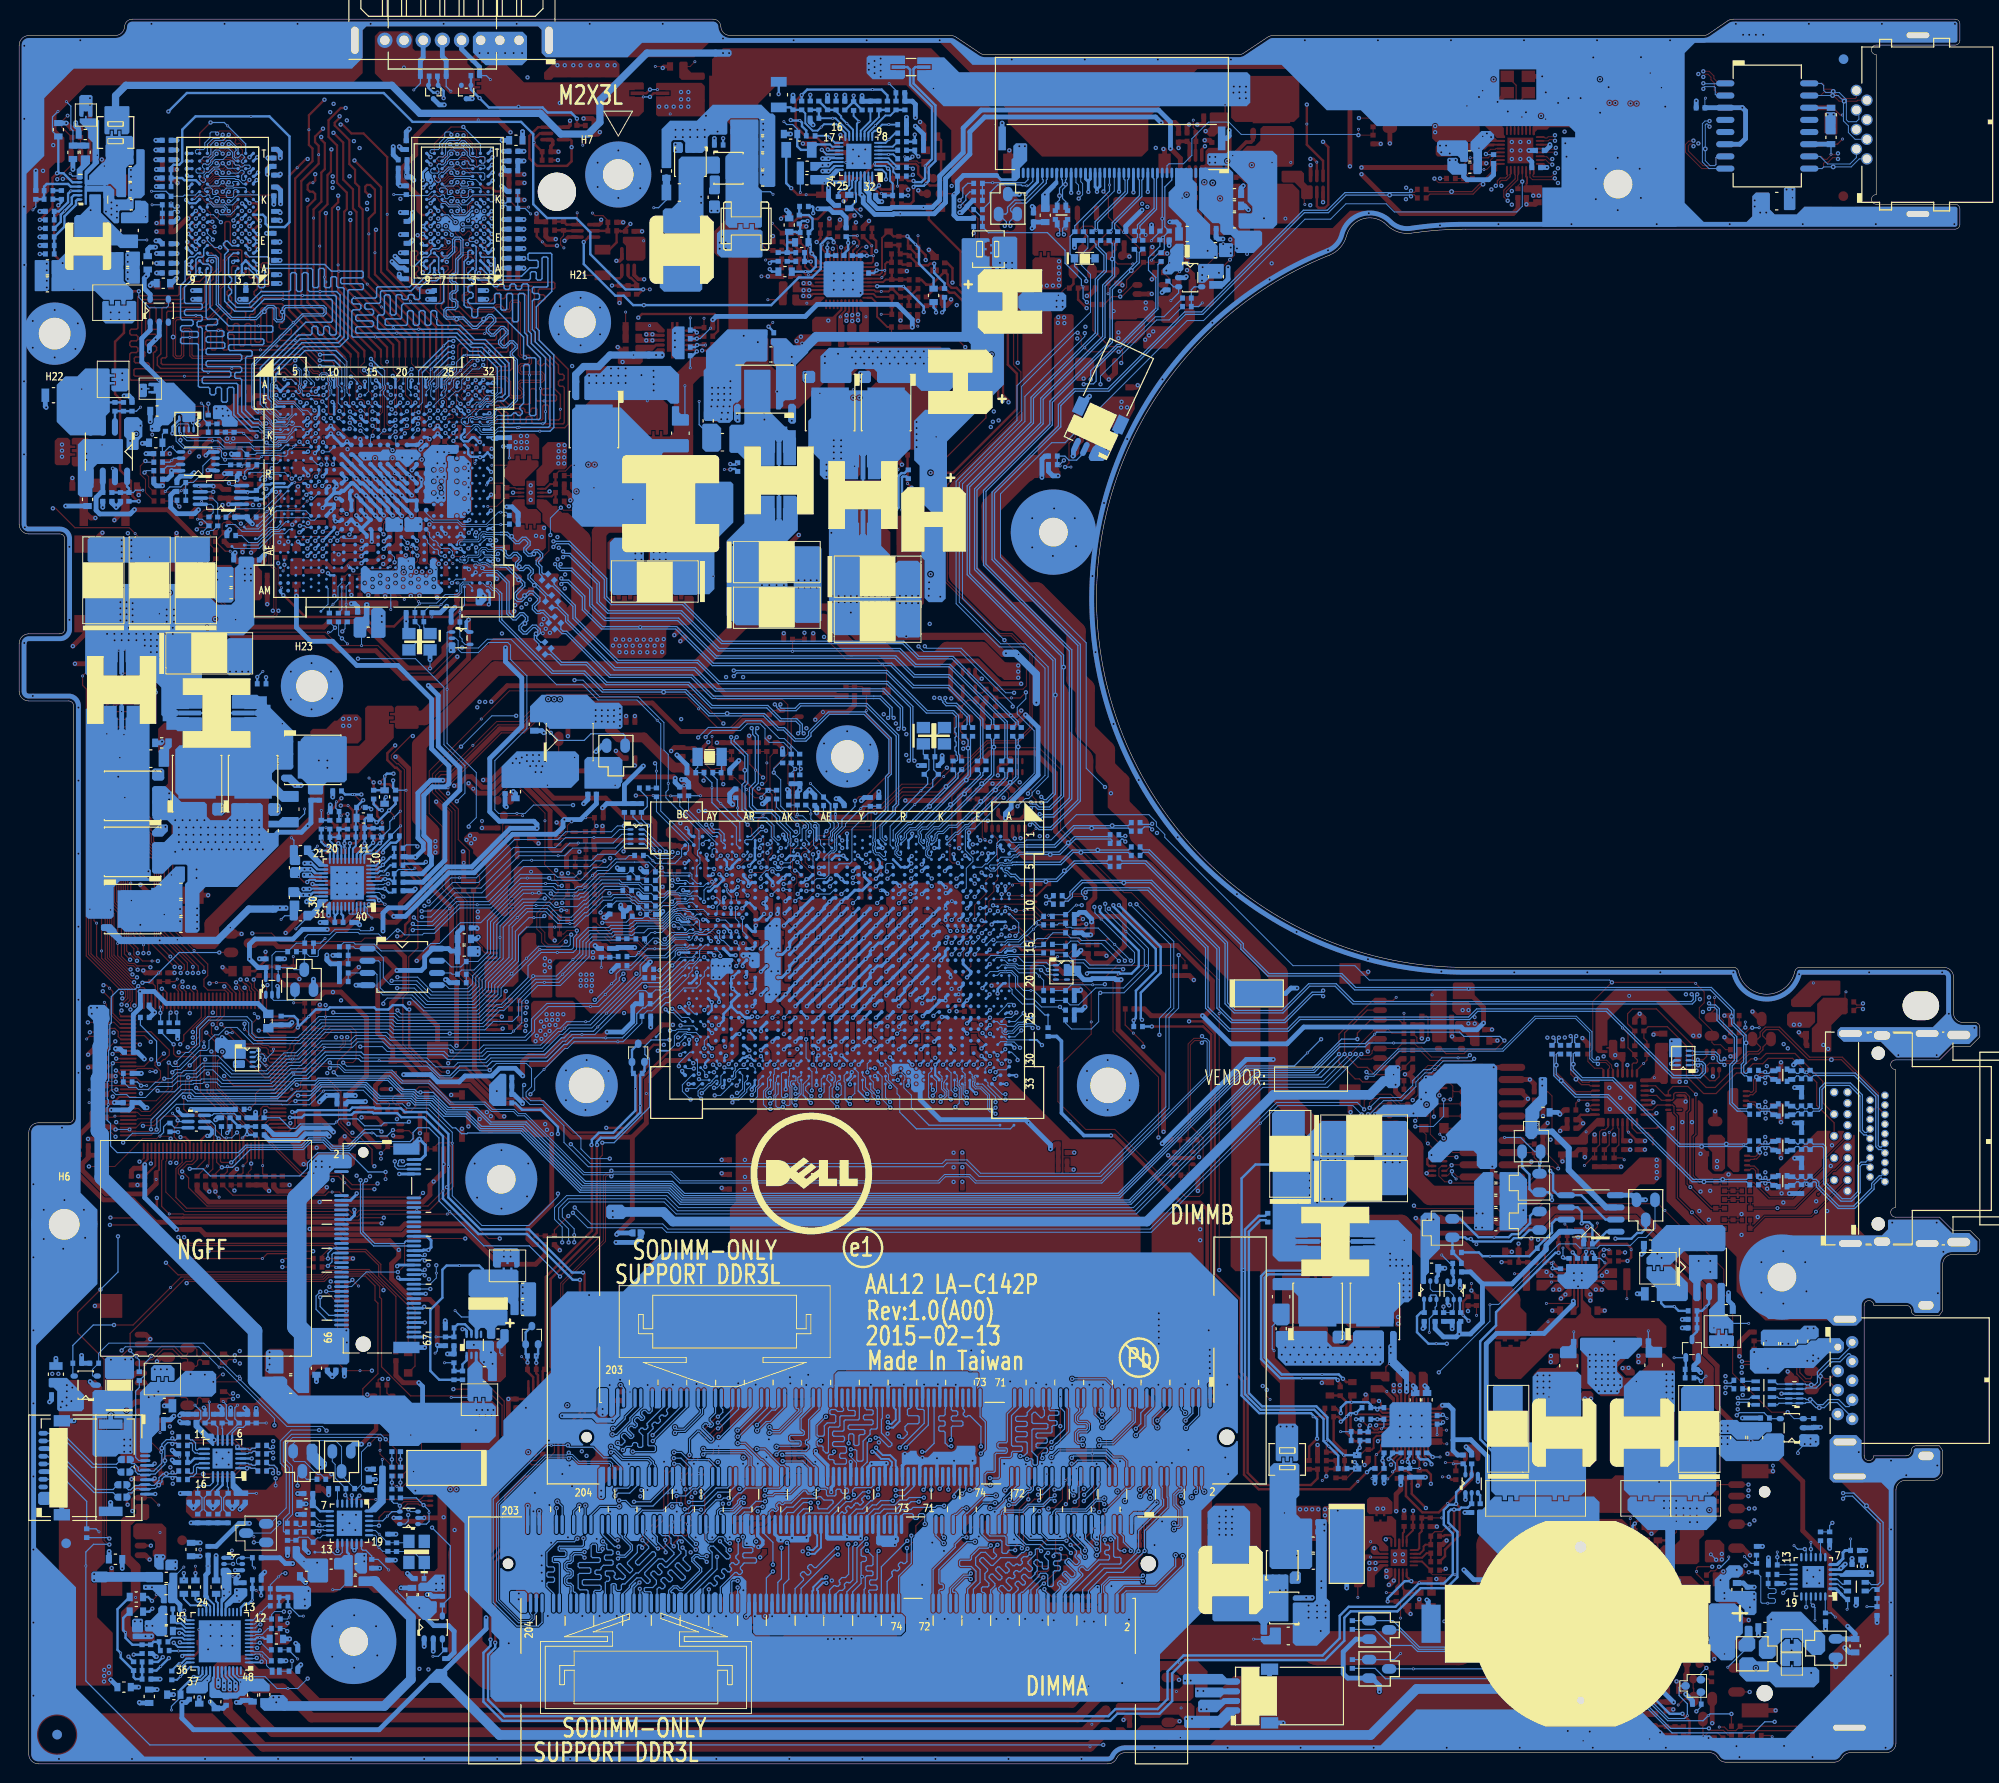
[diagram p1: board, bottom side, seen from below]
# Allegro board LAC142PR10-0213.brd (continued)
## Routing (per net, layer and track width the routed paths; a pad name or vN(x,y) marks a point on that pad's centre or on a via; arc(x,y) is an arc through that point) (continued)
DP1_TXN2_C: length 77.2
  BOTTOM w0.127: CV189.2 87.31,95.33 86.62,95.33 76.84,85.54 76.84,85.1 74.17,82.43 66.56,82.43 65.11,80.98 28,80.98 25.65,78.63 25.65,77.26 24.39,76 v3(24.39,75.2) 24.39,73.08 24.63,72.83 24.63,72.18 24.46,72.01 24.33,72.01 CX14.2
DP1_TXN3_C: length 90
  IN2 w0.127: v2(28.25,79.32) 28.45,79.12 29.3,79.12 29.65,79.46 29.65,80.1 v2(29.48,80.26)
  BOTTOM w0.127: CX12.2 24.33,68.33 25.2,68.33 25.84,68.96 25.84,72.79 25.36,73.27 25.36,75.84 27.17,77.66 27.17,78.75 27.58,79.16 28.09,79.16 v2(28.25,79.32) ; CV191.2 89.5,93.92 87.1,93.92 78.75,85.56 78.75,79.27 77.79,78.32 72.71,78.32 69.92,81.11 67.26,81.11 65.4,79.25 30,79.25 29.65,79.61 29.65,80.1 v2(29.48,80.26)
DP1_TXP0_C: length 27.5
  BOTTOM w0.127: CV184.2 44.45,73.84 44.45,71.78 42.21,69.54 38.85,69.54 30.01,60.7 v3(28.78,60.7) 24.33,60.7 CX19.2
DP1_TXP0_CRT: length 7.4
  TOP w0.127: UZ1.29 40.48,69.72 40.6,69.84 42.26,69.84 v3(43.67,71.26) 44.45,72.03 44.45,73.84 RZ1045.1
DP1_TXP1_C: length 23.8
  BOTTOM w0.127: CX17.2 24.33,64.39 v3(29.03,64.39) 31.4,64.39 38.32,71.31 41.57,71.31 42.67,72.41 42.67,73.84 CV186.2
DP1_TXP1_CRT: length 5.3
  TOP w0.127: RZ1047.1 42.67,73.84 42.67,71.95 v3(42.13,71.41) 41.56,70.84 40.77,70.84 40.65,70.72 UZ1.31
DP1_TXP2_C: length 77.2
  BOTTOM w0.127: CV188.2 87.28,95.07 86.73,95.07 77.1,85.44 77.1,84.99 74.27,82.17 66.67,82.17 65.22,80.72 28.11,80.72 25.9,78.52 v3(25.9,77.95) 25.9,77.16 24.64,75.89 24.64,73.19 24.89,72.94 24.89,72.08 24.57,71.75 24.33,71.75 CX15.2
DP1_TXP3_C: length 90
  IN2 w0.127: v2(28.25,78.74) 28.38,78.86 29.41,78.86 29.9,79.36 29.9,80.1 v2(30.07,80.26)
  BOTTOM w0.127: CX13.2 24.33,68.07 25.31,68.07 26.09,68.85 26.09,72.9 25.61,73.38 25.61,75.74 27.43,77.55 27.43,78.65 27.68,78.9 28.09,78.9 v2(28.25,78.74) ; CV190.2 89.5,94.17 86.99,94.17 78.49,85.67 78.49,79.38 77.69,78.58 72.81,78.58 70.02,81.37 67.15,81.37 65.3,79.51 30.11,79.51 29.9,79.72 29.9,80.1 v2(30.07,80.26)
DP_AUX_ZVSS: length 3.2
  TOP w0.102: v2(102.06,90.7) 101.87,90.7 v1(100.92,91.66) 100.76,91.82 R401.1
  BOTTOM w0.102: UC1.B9 102.07,90.69 v2(102.06,90.7)
DP_VSSR: length 1.9
  BOTTOM w0.089: 165.78,122.33 165.78,121.17
  BOTTOM w0.127: 165.78,121.17 v1(165.78,120.4)
DP_ZVSS: length 5.3
  TOP w0.102: v2(101.3,90.71) 101.14,90.55 v1(99.92,90.55) 99.39,90.55
  TOP w0.203: 99.39,90.55 98.41,90.55 R400.1
  BOTTOM w0.102: v2(101.3,90.71) 101.27,90.67 UC1.A9
DRAM_RST: length 81.8
  TOP w0.127: UV6.T2 161.23,168.99 159.49,170.73 v2(158.21,170.73) ; UV7.T2 185.72,170.06 v2(184.59,171.19)
  IN2 w0.127: v2(158.21,170.73) 158.52,170.73 162,174.21 181.57,174.21 v2(184.59,171.19) 186.91,171.19 188.77,169.34 188.77,149.3 184.82,145.36 184.82,141.87 v2(184.82,141.86)
  BOTTOM w0.102: RV36.1 184.82,141.85 v2(184.82,141.86)
  BOTTOM w0.127: v2(158.21,170.73) 156.43,168.95 UV5.T2 ; UV8.T2 180.92,168.96 v1(182.8,170.84) 183.15,171.19 v2(184.59,171.19)
DRAM_RST_G: length 14.3
  IN2 w0.102: v2(178.81,138.45) 178.1,137.73 176.5,137.73 175.91,138.32 174.26,138.32 174.07,138.13 174.07,137.81 173.1,136.84 v2(172.88,136.84)
  BOTTOM w0.102: v2(178.81,138.45) 179.21,138.05 180.41,138.05 v1(181.11,138.75) 181.24,138.88 CV97.1 183.03,138.88 RV38.1 183.91,138.89 RV37.1 ; v2(172.88,136.84) 172.21,136.84 UV1.L10
E51_RX1: length 4
  TOP w0.127: R24.2 172.8,51.97 172.38,51.97 v2(172.34,51.93) 171.63,51.93 v1(171.48,51.78)
  BOTTOM w0.127: JNGFF.32 171.76,53.27 171.91,53.12 171.91,52.36 v2(172.34,51.93)
E51_RX2: length 11.2
  TOP w0.127: R26.2 v2(177.09,51.82)
  IN2 w0.127: v2(177.09,51.82) 175.71,51.82 v2(173.13,49.24)
  BOTTOM w0.127: JNGFF.60 172.44,46.27 173.58,47.41 173.58,48.79 v2(173.13,49.24)
E51_TX1: length 5
  TOP w0.127: v1(172.18,53.75) 172.95,52.97 R23.2 v2(172.33,52.7) RM9.1
  BOTTOM w0.127: JNGFF.30 171.8,53.78 172.33,53.24 v2(172.33,52.7)
E51_TX2: length 11.5
  TOP w0.127: v2(177.09,52.45) 176.84,52.7 R25.2
  IN2 w0.127: v2(177.09,52.45) 177.6,51.94 177.6,51.61 177.36,51.37 175.88,51.37 173.17,48.67 v2(173.15,48.67)
  BOTTOM w0.127: v2(173.15,48.67) 173.15,47.69 172.23,46.78 JNGFF.58
EC_ENVDD: length 143.8
  TOP w0.102: UE1.71 178.99,75.56 179.07,75.64 179.53,75.64 180.21,76.32 180.21,77.26 v2(179.62,77.84)
  IN1 w0.102: v2(179.62,77.84) 178.73,78.73 177.34,78.73 175.42,80.66 174.82,80.66 174.02,81.46 173.69,81.46 172.47,82.68 170.15,82.68 167.27,85.56 166.85,85.56 165.86,86.56 165.86,87.41 165.03,88.23 165.03,89.27 163.76,90.54 163.76,97.19 162.4,98.55 162.4,105.65 161.93,106.12 161.93,107.66 156.73,112.87 149.47,112.87 143.26,119.08 133.34,119.08 127.65,124.76 110.88,124.76 99.34,136.3 98.19,136.3 91.74,142.74 v2(91.74,143.89)
  BOTTOM w0.102: v2(91.74,143.89) 91.74,144.74 85.88,150.6 84.57,150.6 RX8.2 ; v1(180.03,78.27) 179.62,77.86 v2(179.62,77.84)
EC_I2C_TPCLK: length 3.7
  TOP w0.127: UE1.85 176.52,69.96 v1(176.1,70.37) 175.41,70.37 175.19,70.59 175.19,71.07 R124.1
EC_I2C_TPDAT: length 5.3
  TOP w0.127: v1(172.81,70.17) 174.33,70.17 174.76,70.6 R125.1 175.27,70.1 175.83,70.1 176.38,69.56 UE1.86
EC_LID_OUT#: length 86.8
  TOP w0.102: v2(182.09,59.8) 182.43,60.13 CE42.1 RE71.2
  IN1 w0.102: v2(127.18,92.33) 127.37,92.14 128.71,92.14 129.09,92.52 129.8,92.52 130.26,92.98 130.26,93.55 130.52,93.81 132.73,93.81 134.74,95.82 138.45,95.82 139.38,96.75 140.37,96.75 v2(141.46,97.84)
  IN2 w0.102: v2(182.09,59.8) 181.79,59.8 166.94,74.64 166.94,81.59 163.94,84.6 163.94,88.48 162.47,89.95 v2(161.83,89.95)
  BOTTOM w0.102: 141.46,97.83 141.41,97.88 R943.2 ; 141.46,97.83 142.14,97.83 142.75,97.22 147.54,97.22 148.35,96.41 152.86,96.41 156.86,92.41 v1(158.62,92.41) 159.5,92.41 161.83,90.07 v2(161.83,89.95) ; 141.46,97.83 v2(141.46,97.84) ; UC1.AK5 124.75,93.52 125.1,93.16 125.51,93.16 125.82,93.47 126.11,93.47 126.42,93.16 126.63,93.16 127.18,92.61 v2(127.18,92.33)
EC_LID_OUT#_R: length 3
  TOP w0.127: UE1.101 180.75,62.82 v1(181.2,62.37) 181.2,61.63 RE71.1
EC_MUTE#: length 96.5
  TOP w0.127: v2(183.17,71.74) 182.18,70.76 UE1.83 ; v2(173.88,53.47) v2(184.8,53.47)
  IN1 w0.127: v2(174.45,8.89) 174.45,14.88 178.43,18.86 178.43,22.03 181.03,24.64 181.03,25.4 180.9,25.53 180.9,34.35 181.55,35 181.55,37.59 178.01,41.14 178.01,42.75 174.3,46.46 174.3,53.05 v2(173.88,53.47) ; v2(184.8,53.47) 185.1,53.76 185.1,57.72 185.11,57.73 185.11,59.99 184.51,60.59 184.51,63.11 185.33,63.93 185.33,65.64 185.06,65.91 185.06,69.1 183.17,70.99 v2(183.17,71.74)
  BOTTOM w0.102: v2(174.45,8.89) 175.49,7.86 v1(176.52,7.86) 177.66,7.86 178.89,9.09 181.59,9.09 181.82,9.33 UA1.47
EC_ON: length 220.4
  TOP w0.127: v2(186.76,62.06) 186.1,62.06 185.15,63.01 UE1.112 ; v2(166.33,61.73) v4(166.33,60.99)
  TOP w0.254: PR102.1 v2(49.89,52.32)
  IN1 w0.127: v2(49.89,52.32) 50.72,51.5 50.72,45.72 51.5,44.93 51.5,25.21 54.81,21.91 57.14,21.91 60.64,18.41 60.64,15.81 61.86,14.59 86,14.59 86.93,15.52 98.31,15.52 101.45,12.38 125.87,12.38 127.01,13.53 156.21,13.53 158.34,15.66 158.34,24.76 160.21,26.64 160.21,32.37 163.47,35.62 163.47,51.31 165.37,53.21 165.37,60.78 v2(166.33,61.73)
  BOTTOM w0.127: v2(166.33,61.73) 168.15,61.73 170.15,63.73 173.41,63.73 174.48,62.66 174.48,62.1 175.27,61.32 184.61,61.32 185.36,62.06 v2(186.76,62.06)
EC_PME#: length 4.7
  TOP w0.102: v1(195.66,79.43) 195.43,79.2 RE21.2 RE56.2 194.65,77.34 194.07,76.75 UE1.29
EC_RSMRST#: length 110.9
  TOP w0.102: RE48.1 CE41.1 180.65,61.69 180.35,62 v2(180.35,62.61) UE1.100 ; D3.1 114.07,114.2 v1(114.52,114.65) 115.09,115.23 118.27,115.23 v2(120.58,117.54)
  IN2 w0.102: v2(120.58,117.54) 120.73,117.39 128.7,117.39 133.11,112.97 133.11,110.54 135.79,107.86 145.87,107.86 146.06,108.05 146.06,108.05 146.45,108.45 146.82,108.82 153.45,108.82 156.52,105.75 156.52,102.21 161.63,97.11 161.63,91.26 164.27,88.62 164.27,84.73 167.27,81.73 167.27,74.78 172.06,69.99 172.8,69.99 175.46,67.32 175.46,66.59 179.44,62.61 v2(180.35,62.61)
EC_RSMRST#_R: length 24.4
  TOP w0.127: v2(117.35,100.44) 116.92,100.88 116.2,100.88 113.7,103.38 113.7,106.93 116.17,109.41 v1(116.17,109.85) D3.2 116.63,112.34 C999.2 R346.2
  BOTTOM w0.102: UC1.AE4 120.57,94.54 119.89,95.22 119.64,95.22 119.46,95.39 119.46,95.7 119.47,95.71 119.47,96.13 119.46,96.14 119.46,96.45 119.49,96.48 119.49,97 118.71,97.78 118.71,98.43
  BOTTOM w0.127: v2(117.35,100.44) 117.35,99.86 118.71,98.5 118.71,98.43
EC_RST#: length 4.1
  TOP w0.127: UE1.37 189.95,80.42 190.11,80.58 190.11,81.39 CE23.1 RE17.1 188.32,81.58 v1(188.05,81.85)
EC_RX: length 54.6
  TOP w0.127: R24.1 R26.1 175.62,51.31 186.07,51.31 190.98,56.21 v2(195.08,56.21) ; UE1.31 194.06,77.56 194.79,78.28 194.79,80.56 v1(195.13,80.9) 195.45,81.22 v2(195.76,81.22)
  IN1 w0.127: v2(195.08,56.21) 196.01,57.15 196.01,79.31 196.34,79.63 196.34,80.64 v2(195.76,81.22)
EC_SCI#: length 94.3
  TOP w0.102: RE32.2 RE61.2 195.16,72.69 v2(194.78,73.07) 194.7,73.16 UE1.20
  IN2 w0.102: v2(140.15,82.41) 139.13,83.43 139.13,83.74 138.28,84.59 136.39,84.59 135.68,85.31 129.44,85.31 128.54,86.21 124.28,86.21 123.69,86.79 122.23,86.79 120.72,88.3 120.72,89.78 119.97,90.54 v2(119.97,91.52)
  BOTTOM w0.102: v2(194.78,73.07) 194.87,72.98 194.87,70.22 194.46,69.8 193.33,69.8 193.02,69.49 191.38,69.49 190.23,70.64 188.58,70.64 188.02,71.21 186.59,71.21 186.52,71.29 185.65,71.29 185.51,71.43 183.86,71.43 183.4,70.97 178.23,70.97 176.37,72.83 176.05,72.83 176.04,72.84 175.13,72.84 172.9,75.07 169.9,75.07 169.34,75.63 166.47,75.63 165.81,74.97 159.52,74.97 159.03,74.47 156.58,74.47 156.09,74.97 150.15,74.97 148.4,76.72 148.12,76.72 147.43,77.41 v1(145.45,77.41) 145.08,77.41 140.19,82.3 140.19,82.33 140.15,82.37 v2(140.15,82.41) ; UC1.AD7 119.57,91.92 v2(119.97,91.52)
EC_SMB_CK1: length 218
  TOP w0.102: v2(170.91,75.79) 170.76,75.64 170.76,75.1 171.13,74.73 v1(172.74,74.73) 173.51,74.73 RE31.1
  IN2 w0.102: v2(111.31,166.37) 111.54,166.14 111.65,166.14 111.87,166.36 111.87,168.67 115.71,172.52 128.18,172.52 129.17,171.53 141.69,171.53 144.19,174.03 149.15,174.03 149.99,173.19 158.6,173.19 159.23,173.82 159.65,174.24 160.84,174.24 v2(160.9,174.31) 161.75,175.16 163.21,175.16 163.43,174.94 187.39,174.94 189.7,172.63 189.7,154.09 191.67,152.12 195.29,152.12 196.02,151.39 196.02,144.21 191.5,139.69 191.5,139.12 190.89,138.51 190.89,137.38 190.2,136.69 190.2,135.02 189.01,133.83 189.01,127.38 181.02,119.39 170.64,119.39 163.01,111.76 163.01,107.02 163.58,106.44 163.58,99.02 164.27,98.34 164.27,96.97 164.73,96.51 164.73,91.26 167.35,88.63 167.35,86.92 167.67,86.6 167.67,85.73 170.11,83.29 170.11,77.03 170.71,76.43 170.71,76 v2(170.91,75.79)
  BOTTOM w0.102: v2(111.31,166.37) 111.46,166.52 PR770.1
  BOTTOM w0.254: v2(160.9,174.31) 161.35,174.31 161.85,174.81 PD2.3 161.78,175.14 PR18.2
EC_SMB_CK1_R: length 7.2
  TOP w0.102: v2(179.57,74.45) 179.21,74.09 179,74.09 178.55,73.64 178.55,73.34 178.37,73.16 UE1.77 176.39,73.16 v1(176.04,73.51) 175.82,73.72 175.82,73.99 RE31.2
  BOTTOM w0.102: v2(179.57,74.45) 179.71,74.45 179.94,74.22 RPE1.8
EC_SMB_CK2: length 301.5
  TOP w0.102: v2(81.16,75.21) 81.39,75.44 81.91,75.44 82.37,74.98 82.37,66.56 81.04,65.23 81.04,59.55 81.4,59.18 82.91,59.18 83.36,59.63 R679.1 R16.2 82.49,62.43 82.39,62.53 Q79.3 ; RV166.1 184.93,125.13 185.1,124.96 185.1,122.68 181.93,119.51 177.97,119.51 177.64,119.84 177.64,120.13 v2(177.5,120.27) 177.76,120.52 177.76,124.68 178.26,125.19 178.26,127.03 178.14,127.16 178.14,129.32 177.81,129.66 QV1.6 ; v2(142.77,61.86) 142.98,61.65 143.27,61.65 143.6,61.31 143.6,54.58 148.05,50.13 148.05,38.39 148.93,37.5 150.58,37.5 151.29,36.8 151.29,36.01 151.42,35.87 U2407.10 ; v2(172.14,73.14) 172.27,73.01 173.58,73.01 RE42.1 ; v2(39.84,73) 39.69,73.15 39.02,73.15 38.64,72.77 38.64,72.58 38.77,72.45 UZ1.2
  IN2 w0.102: v2(177.5,120.27) 177.68,120.45 177.68,120.63 177.53,120.78 177.22,120.78 176.4,119.95 170.41,119.95 162.45,111.99 162.45,106.78 163.02,106.21 163.02,98.74 163.71,98.05 163.71,96.7 164.17,96.25 164.17,91.03 166.66,88.54 166.66,87.83 166.06,87.24 166.06,85.37 169.03,82.4 169.03,81.06 169.55,80.54 169.55,76.76 169.58,76.73 169.58,74.89 170.36,74.1 170.65,74.1 171.37,73.38 171.37,73.37 171.81,72.93 171.93,72.93 v2(172.14,73.14) ; v2(81.16,75.21) 81.15,75.21 80.94,75.43 79.32,75.43 75.67,71.78 64.19,71.78 v2(63.99,71.57)
  BOTTOM w0.102: v2(81.16,75.21) 80.96,75.41 80.75,75.41 80.61,75.27 80.61,71.88 85.01,67.49 91.69,60.81 104.7,60.81 105.37,61.47 108.01,61.47 108.67,60.81 135.55,60.81 136.48,61.73 142.64,61.73 v2(142.77,61.86) 142.96,61.67 145.58,61.67 151.72,67.82 152.44,67.82 152.89,68.26 155.19,68.26 155.95,69.02 159.54,69.02 161.73,71.22 164.53,71.22 165.66,72.35 170.54,72.35 171.11,72.93 171.93,72.93 v2(172.14,73.14) ; v2(63.99,71.57) 63.87,71.69 63.87,71.69 63.85,71.71 63.21,71.71 60.59,74.33 49.73,74.33 46.32,77.75 42.19,77.75 40.7,76.26 40.7,73.53 40.34,73.18 40.02,73.18 v2(39.84,73)
EC_SMB_CK2_R: length 7.9
  TOP w0.102: RE42.2 175.68,72.36 UE1.79 178.53,72.36 179.48,73.31 v2(179.48,73.65)
  BOTTOM w0.102: RPE1.6 179.91,73.22 v2(179.48,73.65) 179.48,73.42 178.9,72.83 v1(178.78,72.83)
EC_SMB_DA1: length 218
  TOP w0.102: v2(170.33,75.79) 170.53,75.59 170.53,75 171.15,74.38 173.63,74.38 RE33.1
  IN2 w0.102: v2(170.33,75.79) 170.48,75.94 170.48,76.33 169.88,76.93 169.88,83.19 167.44,85.63 167.44,86.51 167.13,86.82 167.13,88.53 164.5,91.16 164.5,96.42 164.04,96.88 164.04,98.24 163.35,98.93 163.35,106.35 162.78,106.92 162.78,111.85 170.55,119.62 180.92,119.62 188.78,127.48 188.78,133.92 189.97,135.12 189.97,136.78 190.66,137.47 190.66,138.6 191.27,139.21 191.27,139.78 195.79,144.3 195.79,151.3 195.19,151.89 191.57,151.89 189.47,154 189.47,172.54 187.29,174.71 161.88,174.71 160.9,173.74 v2(160.27,173.74) 160.19,173.66 159.39,173.66 158.69,172.96 149.89,172.96 149.05,173.8 144.28,173.8 141.78,171.3 129.08,171.3 128.09,172.29 115.8,172.29 112.1,168.58 112.1,166.27 111.72,165.89 111.46,165.89 v2(111.31,165.73)
  BOTTOM w0.102: v2(111.31,165.73) 111.44,165.61 PR769.1
  BOTTOM w0.254: v2(160.27,173.74) 160.27,174.49 PD2.2 160.85,175.62 160.92,175.69 PR20.2
EC_SMB_DA1_R: length 8.6
  TOP w0.102: v2(178.93,73.43) 178.93,73.23 178.46,72.75 UE1.78 176.33,72.75 174.91,74.17 RE33.2
  BOTTOM w0.102: RPE1.7 179.97,73.72 179.66,74.03 179.14,74.03 178.93,73.82 v2(178.93,73.43) 178.86,73.43 178.02,74.27 v1(178.02,74.55)
EC_SMB_DA2: length 298.7
  TOP w0.102: v2(142.77,61.28) 142.91,61.42 143.17,61.42 143.38,61.21 143.38,54.48 147.82,50.04 147.82,38.29 148.84,37.27 150.49,37.27 151.06,36.7 151.06,36.01 150.92,35.87 U2407.9 ; RV167.1 184.56,125.17 184.63,125.1 184.63,125.1 184.87,124.87 184.87,122.77 181.83,119.74 178.07,119.74 177.87,119.93 177.87,120.05 v2(178.09,120.27) 177.98,120.37 177.98,124.59 178.49,125.09 178.49,127.13 178.37,127.25 178.37,129.42 178.16,129.63 178.16,133.02 177.95,133.24 176.74,133.24 176.51,133 QV1.3 ; v2(81.15,75.9) 81.37,75.67 82,75.67 82.59,75.08 R680.1 R17.2 83.46,64.05 83.67,63.83 Q79.6 ; UZ1.3 38.27,72.43 38.41,72.56 38.41,72.86 38.93,73.38 39.64,73.38 v2(39.84,73.58) ; v2(172.14,72.56) 172.33,72.75 173.28,72.75 173.32,72.78 173.45,72.78 RE35.1
  IN2 w0.102: v2(178.09,120.27) 177.91,120.45 177.91,120.73 177.63,121.01 177.13,121.01 176.3,120.18 170.32,120.18 162.22,112.09 162.22,106.69 162.79,106.12 162.79,98.64 163.48,97.96 163.48,96.61 163.94,96.15 163.94,90.93 166.43,88.44 166.43,87.93 165.83,87.33 165.83,85.27 168.8,82.3 168.8,80.96 169.32,80.44 169.32,76.66 169.35,76.64 169.35,74.8 170.27,73.88 170.55,73.88 171.14,73.29 171.14,73.28 171.72,72.7 172.01,72.7 v2(172.14,72.56) ; v2(63.99,72.16) 64.14,72.01 75.58,72.01 79.22,75.65 80.91,75.65 v2(81.15,75.9)
  BOTTOM w0.102: v2(39.84,73.58) 40.02,73.41 40.25,73.41 40.47,73.63 40.47,76.35 42.09,77.98 46.41,77.98 49.83,74.56 60.69,74.56 63.31,71.94 63.77,71.94 v2(63.99,72.16) ; v2(172.14,72.56) 172.01,72.7 171.21,72.7 170.63,72.12 165.75,72.12 164.62,70.99 161.83,70.99 159.63,68.8 156.04,68.8 155.28,68.03 152.98,68.03 152.54,67.59 151.82,67.59 145.67,61.44 142.93,61.44 v2(142.77,61.28) 142.54,61.51 136.58,61.51 135.65,60.58 108.57,60.58 107.91,61.24 105.46,61.24 104.8,60.58 91.59,60.58 84.85,67.33 80.38,71.79 80.38,75.37 80.66,75.64 80.89,75.64 v2(81.15,75.9)
EC_SMB_DA2_R: length 6.1
  TOP w0.102: v2(179.52,72.8) 179.52,72.65 178.82,71.96 UE1.80 v1(175.9,71.96) 175.19,71.96 RE35.2
  BOTTOM w0.102: v2(179.52,72.8) 179.6,72.72 RPE1.5
EC_SMI#: length 70.3
  IN2 w0.102: v2(137.21,86) 137.38,86.18 138.39,86.18 141.37,83.2 141.37,82.55 v2(141.51,82.41)
  BOTTOM w0.102: v2(137.21,86) 136.51,86.7 134.94,86.7 134.63,87.02 UC1.BB13 ; v2(141.51,82.41) 141.51,82.41 141.94,81.98 141.94,81.71 v1(143.41,80.25) 144.34,79.31 149.49,79.31 151.11,77.69 151.11,76.48 151.79,75.79 165.7,75.79 166.2,76.29 172.61,76.29 175.39,73.51 176.3,73.51 176.32,73.49 176.64,73.49 178.51,71.63 182.51,71.63 183.64,72.76 185.3,72.76 186.09,71.97 187.12,71.97 187.34,71.75 187.95,71.75 188.61,71.08 190.34,71.08 191.1,70.32 192.11,70.32 192.34,70.55 193.12,70.55 RE55.1 RE19.2
EC_SMI#_R: length 3.2
  TOP w0.127: UE1.15 192.25,71.16 v2(191.83,70.74)
  BOTTOM w0.127: RE55.2 192.22,71.12 v2(191.83,70.74) v1(191.25,70.74)
EC_SPI_CLK: length 75.6
  TOP w0.102: UE1.126 190.75,62.67 v2(190.81,62.61)
  IN2 w0.102: v2(165.09,82.05) 165.09,81.51 165.8,80.8 165.8,74.39 181.91,58.27 187.17,58.27 190.81,61.91 v2(190.81,62.61) ; v2(149.1,90.78) 149.1,90.78 149.21,90.78 v2(149.72,90.27)
  BOTTOM w0.102: R1691.1 141.05,92.52 143.96,92.52 145.7,90.78 146.04,90.78 146.3,90.53 v1(146.69,90.53) 148.84,90.53 v2(149.1,90.78) ; v2(149.72,90.27) 149.79,90.2 152.06,90.2 154.72,87.54 154.72,84.24 156.91,82.05 156.91,81.24 157.64,80.52 161.45,80.52 162.98,82.05 v2(165.09,82.05)
EC_SPI_CS1#: length 76
  TOP w0.102: v2(192,62.81) 191.93,62.81 191.55,63.19 UE1.128
  IN2 w0.102: v2(192,62.81) 192,62.51 187.43,57.94 181.78,57.94 165.47,74.25 165.47,80.56 v2(165.12,80.91)
  BOTTOM w0.102: v2(165.12,80.91) 163.32,80.91 161.94,79.53 157.23,79.53 155.92,80.83 155.92,81.64 153.45,84.11 153.45,87.4 v1(152.59,88.27) 151.65,89.2 149.45,89.2 148.22,87.97 146.83,87.97 145.45,89.35 145.26,89.35 143.41,91.2 141.68,91.2 R1693.1
EC_SPI_MISO: length 72.5
  TOP w0.102: UE1.119 187.95,62.88 v2(188.16,62.67)
  IN2 w0.102: v2(166.56,79.27) 166.56,74.56 181.81,59.31 187.27,59.31 188.16,60.2 v2(188.16,62.67)
  BOTTOM w0.102: v2(166.56,79.27) 166.56,79.46 166.15,79.87 163.68,79.87 162.35,78.54 156.78,78.54 154.93,80.39 154.93,81.23 152.46,83.7 152.46,86.42 151.61,87.27 v1(148.68,87.27) 146.59,87.27 145.42,88.44 145.23,88.44 143.6,90.08 142.7,90.08 142.45,90.33 140.86,90.33 140.6,90.08 140.34,90.08 139.98,89.72 139.33,89.72 R1692.1
EC_SPI_MOSI: length 76.1
  TOP w0.102: UE1.120 188.35,63.12 v2(188.78,62.7)
  IN2 w0.102: v2(165.69,81.67) 166.18,81.18 166.18,74.47 181.98,58.67 187.11,58.67 188.78,60.35 v2(188.78,62.7)
  BOTTOM w0.102: R1694.1 139.46,91.27 139.92,91.73 141.84,91.73 141.97,91.86 143.69,91.86 145.47,90.07 145.66,90.07 146.32,89.41 148.15,89.41 148.24,89.32 148.63,89.32 149.18,89.87 151.92,89.87 154.39,87.4 v1(154.39,86.19) 154.39,84.11 156.58,81.91 156.58,81.11 157.5,80.19 161.58,80.19 163.07,81.67 v2(165.69,81.67)
EC_TP_INT#: length 156.3
  TOP w0.127: RE340.2 57.73,77.99 57.57,77.84 v2(57.57,75.59) 57.94,75.22 58.57,75.22 58.73,75.39 58.73,75.77 RE338.1 ; UE1.106 182.75,64.84 185.69,67.78 186.86,67.78 187.38,68.29 v2(187.38,69.54)
  BOTTOM w0.127: v2(187.38,69.54) 186.97,69.14 176.64,69.14 175.62,70.16 174.07,70.16 173.17,71.06 168.31,71.06 166.9,69.64 163.57,69.64 163.11,69.18 161.48,69.18 160.06,67.77 157.91,67.77 156.4,66.26 152.06,66.26 145.86,60.06 136.66,60.06 135.41,58.81 88.76,58.81 75.46,72.1 69.43,72.1 66.74,74.79 64.12,74.79 63.73,75.18 v1(61.16,75.18) 57.98,75.18 v2(57.57,75.59)
EC_TX: length 52.3
  TOP w0.127: UE1.30 193.98,77.16 195.01,78.19 195.01,79.77 v2(195.83,80.58) ; R23.1 R25.1 175.62,53.21 178.67,53.21 v1(179.18,52.7) 187.15,52.7 191.38,56.93 194.99,56.93 v2(195.03,56.97)
  IN1 w0.127: v2(195.83,80.58) 195.76,80.52 195.76,57.71 v2(195.03,56.97)
ECAGND: length 104.8
  TOP w0.254: PH1.2 v2(106.75,78.49) ; v2(135.15,75.06) 135.12,75.06 135.12,75.06 135.69,74.48 136.6,74.48 139.6,71.48 139.6,67.39 141.14,65.85 146.73,65.85 150.26,69.38 154.7,69.38 157.94,72.62 160.36,72.62 160.99,73.25 162.29,73.25 163.86,74.82 v2(163.86,78.68) ; v2(175.48,76.8) 175.92,76.36 UE1.69 ; v2(178.85,84.7) 178.85,83.79 CE43.1 179.97,82.68 LE4.2
  IN2 w0.254: v2(106.75,78.49) 106.85,78.49 107.32,78.02 107.73,78.02 108.2,78.49 111.85,78.49 112.26,78.08 112.26,77.55 112.46,77.34 113.02,77.34 113.28,77.09 113.28,76.92 113.79,76.42 121.04,76.42 121.42,76.8 125.2,76.8 126.5,75.5 128.79,75.5 128.98,75.31 133.03,75.31 133.28,75.06 134.47,75.06 134.47,75.06 134.85,75.06 134.85,75.06 135.12,75.06 135.12,75.06 v2(135.15,75.06) ; v2(175.48,76.8) 175.48,80.78 178.85,84.15 v2(178.85,84.7)
  BOTTOM w0.254: v2(163.86,78.68) 164.09,78.68 164.55,79.13 165.58,79.13 166.03,78.68 167.29,78.68 167.5,78.89 172.14,78.89 172.36,78.68 173.6,78.68 v1(174.33,77.95) v2(175.48,76.8) 175.48,77.6 175.88,77.99 CE21.2
EDP_AUXN: length 86.7
  IN2 w0.127: v2(104.87,90.42) 105.11,90.42 105.27,90.59 105.27,91.52 105.43,91.68 105.43,92.62 104.68,93.37 102.07,93.37 101.28,94.16 98.93,96.51 97.37,98.06 97.37,98.79 97.59,99.01 98.04,99.01 v2(98.09,99.06)
  BOTTOM w0.102: UC1.E8 104.47,90.82 v2(104.87,90.42)
  BOTTOM w0.127: v2(98.09,99.06) 98.04,99.01 96.72,99.01 94.99,100.73 94.99,116.08 103.94,125.03 103.94,132.83 97.02,139.75 97.02,142.11 90.75,148.38 90.75,153.88 88.71,155.92 87.95,156.68 87.95,157.71 C4322.2
EDP_AUXN_C: length 8.2
  BOTTOM w0.127: JEDP.12 86.3,165.45 86.15,165.3 86.15,162.24 87.89,160.5 87.89,160.14 R618.2 87.88,159.54 87.88,159.2 C4322.1
EDP_AUXP: length 86.7
  IN2 w0.127: 102.18,93.63 102.18,93.63 102.18,93.63 ; 102.18,93.63 104.79,93.63 105.69,92.73 105.69,91.57 105.53,91.41 105.53,90.58 v2(105.69,90.42) ; 102.18,93.63 100.03,95.77 99.32,96.48 98.91,96.89 98.27,97.53 97.63,98.17 97.63,98.68 97.7,98.75 97.81,98.75 v2(98.09,98.47)
  BOTTOM w0.102: v2(105.69,90.42) 105.27,90.84 UC1.F8
  BOTTOM w0.127: v2(98.09,98.47) 97.81,98.75 96.61,98.75 94.74,100.63 94.74,116.19 103.69,125.14 103.69,132.72 96.76,139.64 96.76,142.01 90.5,148.28 90.5,153.77 v3(88.53,155.74) 87.7,156.57 87.7,157.62 C4321.2
EDP_AUXP_C: length 8.2
  BOTTOM w0.127: C4321.1 87.62,159.19 87.62,159.54 R616.2 87.33,159.84 87.63,160.14 87.63,160.4 85.89,162.13 85.89,165.34 85.8,165.44 JEDP.11
EDP_HPD: length 31.4
  TOP w0.102: Q20.1 62.46,171.58 R407.2 R365.1 v2(64.83,169.88) v1(64.83,170.48)
  BOTTOM w0.102: v2(64.83,169.88) 64.9,169.95 77.06,169.95 78.34,171.23 80.47,171.23 82.21,169.5 82.21,167.76 83.08,166.89 84.58,166.89 84.8,166.67 JEDP.9
EDP_HPD_R: length 33.7
  TOP w0.127: v2(99.52,111.76) 100.11,111.18 v1(101.03,111.18) RC10.1 ; U66.4 104.82,111.81 104.7,111.7 104.08,111.7 RC8.1 103.59,112.09 RC10.1 ; RC10.1 R366.1
  BOTTOM w0.102: 103.97,98.43 104.88,97.52 105.67,97.52 105.84,97.36 105.84,95.29 105.05,94.5 105.05,94.1 105.74,93.41 105.74,91.35 UC1.G8 ; v2(99.52,111.76) 99.52,111.09 100.42,110.19 100.42,109.51 98.66,107.75 98.66,103.3 101.6,100.36 102.04,100.36 103.88,98.52
  BOTTOM w0.127: 103.97,98.43 103.88,98.52
EDP_TXN0: length 80.9
  IN2 w0.127: v2(104.29,96.32) 104.68,96.32 104.73,96.37 104.73,96.68 104.22,97.19 103.68,97.19 102.67,98.2 102.67,98.51 100.88,100.3 100.09,100.3 99.65,99.86 99.16,99.86 v2(98.99,99.7)
  BOTTOM w0.102: v2(104.29,96.32) 104.57,96.6 UC1.E1
  BOTTOM w0.127: C4311.2 90.26,158.57 90.26,155.12 91.26,154.13 91.26,148.78 97.72,142.32 97.72,139.77 104.62,132.87 104.62,124.68 95.59,115.64 v3(95.59,114.39) 95.59,100.92 96.97,99.54 98.24,99.54 98.55,99.85 98.84,99.85 v2(98.99,99.7)
EDP_TXN0_C: length 7.5
  BOTTOM w0.127: C4311.1 90.26,160.12 90.26,160.63 87.42,163.47 87.42,165.18 87.3,165.31 JEDP.14
EDP_TXN1: length 80.5
  IN2 w0.102: 103.82,95.36 104.33,95.36 104.42,95.27 104.42,95.1 104.3,94.96 v2(104.08,94.96)
  IN2 w0.127: 103.82,95.36 103.16,95.36 102.58,95.94 102.58,96.44 100.01,99.01 98.7,99.01 98.33,99.38 98.33,100.22 98.17,100.38 98.03,100.38 v2(97.92,100.27)
  BOTTOM w0.102: UC1.E4 104.57,94.47 v2(104.08,94.96)
  BOTTOM w0.127: C4313.2 91.95,158.66 91.95,158.29 91.13,157.46 91.13,155.66 92.03,154.76 92.03,149.13 98.73,142.43 98.73,139.84 105.39,133.18 105.39,124.14 96.45,115.19 v3(96.45,111.48) 96.45,101.16 97.3,100.3 97.88,100.3 v2(97.92,100.27)
EDP_TXN1_C: length 7.6
  BOTTOM w0.127: JEDP.17 88.8,165.31 88.92,165.18 88.92,163.87 92.04,160.75 92.04,160.12 C4313.1
EDP_TXP0: length 81
  IN2 w0.127: v2(105.06,95.9) 104.98,95.97 104.98,96.79 104.32,97.45 103.79,97.45 102.93,98.31 102.93,98.62 100.99,100.56 99.99,100.56 99.54,100.12 99.16,100.12 v2(98.99,100.28)
  BOTTOM w0.102: v2(105.06,95.9) 105.04,95.92 UC1.E2
  BOTTOM w0.127: v2(98.99,100.28) 98.82,100.1 98.44,100.1 98.13,99.8 97.07,99.8 95.84,101.03 95.84,115.53 104.88,124.57 104.88,132.97 97.97,139.88 97.97,142.43 91.52,148.89 91.52,154.23 90.52,155.23 v3(90.52,156.96) 90.52,158.57 C4312.2
EDP_TXP0_C: length 7.5
  BOTTOM w0.127: C4312.1 90.52,160.12 90.52,160.74 87.68,163.58 87.68,165.18 87.8,165.31 JEDP.15
EDP_TXP1: length 80.4
  IN2 w0.102: 103.82,95.62 103.83,95.62 103.84,95.61 103.92,95.61 103.93,95.59 104.43,95.59 104.65,95.37 104.65,95.15 104.75,95.06 v2(105.06,95.06)
  IN2 w0.127: v2(97.92,100.85) 97.92,100.78 98.06,100.64 98.28,100.64 98.59,100.33 98.59,99.48 98.81,99.26 100.12,99.26 102.84,96.55 102.84,96.05 103.27,95.62 103.82,95.62
  BOTTOM w0.102: v2(105.06,95.06) 105.01,95.01 104.68,95.01 UC1.E3
  BOTTOM w0.127: v2(97.92,100.85) 97.63,100.56 97.41,100.56 96.7,101.26 96.7,115.09 105.64,124.03 105.64,133.29 98.99,139.94 98.99,142.53 92.28,149.24 92.28,154.87 91.38,155.77 91.38,157.36 92.21,158.19 92.21,158.49 C4314.2
EDP_TXP1_C: length 7.6
  BOTTOM w0.127: JEDP.18 89.3,165.31 89.18,165.18 89.18,163.97 92.3,160.85 92.3,160.12 C4314.1
EN_0.675VSP: length 5.6
  TOP w0.127: PR202.2 57.28,23.8 56.86,24.22 56.1,24.22 55.7,24.63 v1(55.37,24.63)
  TOP w0.203: PU200.7 58.42,21.9 58.03,22.29 58.03,22.67 57.84,22.86 PC203.1 PR202.2
EN_1.8V_ALWP: length 5.4
  BOTTOM w0.127: PR601.1 v1(161.05,44.53)
  BOTTOM w0.254: PR601.1 PC601.1 159.18,44.54 PR602.1 158.79,45.85 158.04,45.85 157.37,45.17 PU600.7
EN_1.35V: length 2.8
  TOP w0.203: PU200.8 58.19,21.5 57.71,21.97 PC202.1 PR201.2
EN_1.35VGPU: length 6.9
  BOTTOM w0.254: PR1402.1 PR1403.1 PC1402.1 199.83,160.32 199.83,161.4 198.62,162.61 198.62,163 198.47,163.16 PU1400.1
EN_3V: length 12.4
  TOP w0.203: PR100.1 38.89,53.62 v2(39.22,53.62) 39.36,53.62 39.71,53.28 39.71,51.85 39.98,51.58 PU100.6
  TOP w0.254: PD101.2 v2(46.09,54.67)
  IN2 w0.254: v2(39.22,53.62) 39.49,53.89 42.7,53.89 43.74,54.93 45.82,54.93 v2(46.09,54.67)
  BOTTOM w0.127: v2(39.22,53.62) v1(38.68,53.62)
EN_5V: length 3.7
  TOP w0.203: PD101.3 45.38,53.65 PR101.1 v1(44.51,52.32) 44.51,52.29 43.8,51.58 PU100.20
EN_DFAN1: length 128.1
  TOP w0.127: UE6.4 94.04,139.67 94.38,139.33 94.38,138.38 95.03,137.74 95.03,135.66 v2(95.43,135.25) ; UE1.70 178.36,75.96 178.89,76.48 v2(179.56,76.48)
  IN1 w0.127: v2(95.43,135.25) 99.55,135.25 110.61,124.19 127.42,124.19 133.1,118.5 143.02,118.5 149.23,112.3 156.49,112.3 161.36,107.43 161.36,105.78 161.78,105.37 161.78,98.36 162.01,98.13 162.01,94.51 161.73,94.23 161.73,91.34 164.23,88.84 164.23,87.85 164.43,87.65 164.43,86.11 165.63,84.92 166.04,84.92 169.08,81.88 172.13,81.88 173.35,80.66 173.68,80.66 176.14,78.2 176.75,78.2 177.01,77.93 178.11,77.93 179.56,76.48 v2(179.56,76.48)
  BOTTOM w0.127: v2(95.43,135.25) v1(94.82,135.25)
EN_GFX: length 12.2
  TOP w0.254: PQ504.1 53.02,29.65 v1(55.52,27.15) 56.44,26.23 58.16,26.23 59.87,27.94 PR532.2 PR509.1
EN_VDDP_ALWP: length 4.3
  TOP w0.254: PU300.3 134.03,148.48 v2(133.85,148.65) 133.6,148.91 PR301.2
  BOTTOM w0.127: v1(132.42,149.75) 133.51,148.65 v2(133.85,148.65)
  BOTTOM w0.254: PC301.1 v2(133.85,148.65)
ENABLE_APU: length 2.5
  TOP w0.203: PU1001.8 117.56,157.84 v1(117.11,158.29) 116.91,158.49 116.91,158.82 PR1085.2
ENABLE_GFX: length 3.6
  TOP w0.127: PR509.2 60.8,30.68 v1(61.77,29.72)
  TOP w0.203: PR509.2 60.76,31.11 60.8,31.15 60.8,31.61 60.36,32.05 PU500.8
ENABLE_VGA: length 2.8
  BOTTOM w0.203: PU1100.8 167.16,92.88 166.93,93.11 v1(166.54,93.11) 166.44,93.11 165.83,93.73 PR1116.2
ENVDD: length 79.3
  TOP w0.102: U64.4 100.91,100.62 R1160.1 R683.2 100.01,100.27 v2(100.4,99.87) ; v2(94.13,149.26) 93.76,148.89 93.76,148.07 v1(93.38,147.69) 92.97,147.28 v2(89.85,147.28)
  BOTTOM w0.102: v2(94.13,149.26) 94.37,149.26 99.96,143.68 99.96,140.15 106.47,133.63 106.47,121.14 102.15,116.82 99.61,116.82 97.2,114.42 97.2,102.96 98.88,101.28 98.88,101.04 99.23,100.69 99.59,100.69 v2(100.4,99.87) ; RX7.2 83.18,152.87 85.12,150.93 86.02,150.93 89.67,147.28 v2(89.85,147.28)
ENVDD_R: length 20
  TOP w0.102: RP45.7 100.89,102.43 R683.1 99.89,101.66 99.12,101.66 98.89,101.43 98.89,100.96 98.47,100.55 v1(98.47,97.55) 99.45,96.57 100.06,96.57 v2(100.08,96.55) 100.26,96.72 U64.2
  IN2 w0.107: v2(100.08,96.55) 100.08,96.39 102.48,93.99 105.09,93.99 v2(106.77,92.32)
  BOTTOM w0.102: v2(106.77,92.32) 106.37,92.72 UC1.G6
ENVDD_RE: length 4.3
  BOTTOM w0.127: v1(81.12,152.37) 81.5,151.99 RX8.1 RX7.1 82.26,153.75 81.95,154.06 UX4.4
ERP_LOT6: length 115
  TOP w0.127: UE1.73 178.38,74.75 178.56,74.93 179.17,74.93 179.31,75.07 180.84,75.07 182.57,76.8 183.11,76.8 v2(183.46,77.14)
  TOP w0.254: PQ1.2 141.03,155.18 140.82,154.98 140.71,154.98 140.14,154.41 PR1.2 PR2.1 PC5.1 v2(142.7,154.19)
  IN1 w0.102: 154.42,121.17 154.33,121.27
  IN1 w0.127: 154.42,121.17 155.36,120.24 155.84,120.24 157.4,118.67 164.74,118.67 167.44,115.96 167.44,103.15 169.93,100.66 169.93,99.64 169.37,99.08 169.37,95.11 168.14,93.88 168.14,91.25 170.34,89.05 170.34,86.9 171.21,86.03 175.51,86.03 179.25,82.29 179.25,82.07 183.33,77.99 183.33,77.27 v2(183.46,77.14) ; v2(142.7,154.19) 142.7,148.82 144.5,147.03 146.22,147.03 150.25,143 150.25,136.08 152.33,133.99 152.33,131.11 153.55,129.89 153.55,122.05 154.33,121.27
FAN_SPEED1: length 150.9
  TOP w0.127: v2(189.97,72.99) 189.49,73.47 189.35,73.47 188.89,73.93 188.89,74.45 190.8,76.36 UE1.28 ; v1(95.94,135.38) 95.94,135.57 v2(95.56,135.95)
  IN1 w0.127: v2(189.97,72.99) 189.5,72.52 187.31,72.52 187.24,72.45 186.59,72.45 186.2,72.85 184.85,72.85 184.52,73.18 183.26,73.18 180.19,76.25 180.19,76.83 179.68,77.34 179.34,77.34 178.3,78.39 177.2,78.39 175.27,80.31 174.68,80.31 173.88,81.11 173.54,81.11 172.32,82.33 169.27,82.33 168.15,83.45 168.15,83.77 165.51,86.41 165.51,87.27 164.69,88.09 164.69,89.13 162.81,91.01 162.81,94.75 163.39,95.33 163.39,97.07 162.06,98.41 162.06,105.41 161.59,105.88 161.59,107.52 156.59,112.53 149.33,112.53 143.12,118.73 133.2,118.73 127.51,124.42 110.73,124.42 99.2,135.95 v2(95.56,135.95)
  BOTTOM w0.127: v2(189.97,72.99) 190.21,73.23 190.21,75.37 191.9,77.06 CE37.1 ; JFAN.2 93.79,136.41 94.23,135.98 95.03,135.98 95.45,136.4 CE26.1 RE72.2 96.01,135.51 v2(95.56,135.95)
FB_1.8V_ALWP: length 4.5
  BOTTOM w0.127: v1(160.18,41.83) PR605.1
  BOTTOM w0.254: PU600.1 157.87,42.1 158.3,41.67 PC603.2 PR604.2 PR605.1
FB_1.35V: length 6
  TOP w0.127: v1(56.14,25.65) PR204.1
  TOP w0.203: PR204.1 PR207.1 PC214.1 58.22,24.26 58.48,24 58.48,22.48 58.66,22.3 PU200.6
FB_1.35VGPU: length 7.3
  BOTTOM w0.127: PR1410.1 202.81,162.38 v1(203.12,162.08)
  BOTTOM w0.254: PU1400.4 199.17,164.51 199.45,164.78 201.67,164.78 201.95,164.5 PR1409.2 PR1406.2 201.96,163.18 PR1410.1
FB_3V: length 5.5
  TOP w0.102: PR109.2 40.77,55.13 39.9,56.01 39.9,56.39 v1(39.91,56.4)
  TOP w0.203: v2(41.08,53.4) 41.52,52.96 PU100.4
  TOP w0.254: PR109.2 PC102.2 40.77,53.71 v2(41.08,53.4)
  BOTTOM w0.254: PR107.2 v2(41.08,53.4)
FB_5V: length 5.3
  TOP w0.102: PR104.1 43.05,56.06 v1(43.29,56.3)
  TOP w0.203: v2(42.47,53.34) 42.32,53.18 PU100.2
  TOP w0.254: v2(42.47,53.34) 43.05,53.91 PC108.1 PR104.1
  BOTTOM w0.254: v2(42.47,53.34) 41.97,52.83 PR106.1
FB_GND: length 4.5
  TOP w0.508: RV158.1 163.69,123.94 163.3,124.33 v2(163.13,124.33)
  IN2 w0.508: v2(163.09,126.75) 163.27,126.75 163.58,126.45 163.58,124.78 v2(163.13,124.33)
  BOTTOM w0.254: UV1.AD20 163.5,127.16 v2(163.09,126.75)
FB_VDDC: length 7.7
  TOP w0.102: v1(162.88,121.22) 163.24,121.58 163.24,123.1 162.79,123.55 RV159.1
  TOP w0.508: RV159.1 162.52,123.96 162.52,124.34 v2(162.51,124.35)
  IN2 w0.508: v2(163.04,127.57) 162.41,126.94 162.41,125.79 162.51,125.68 v2(162.51,124.35)
  BOTTOM w0.254: v2(163.04,127.57) 163.43,127.96 UV1.AC20
FB_VDDCI: length 3.3
  BOTTOM w0.102: UV1.W1 177.69,131.16 T222.1
FB_VDDP_ALWP: length 3.3
  TOP w0.254: PR307.1 133.79,148.02 v2(133.83,147.98) PU300.4
  BOTTOM w0.127: v2(133.83,147.98) v1(132.95,147.98)
  BOTTOM w0.254: v2(133.83,147.98) 134.04,147.76 PR308.1
GATEA20: length 68
  TOP w0.127: v2(190.21,66.15) 190.81,65.56 UE1.1
  BOTTOM w0.102: UC1.BC19 135.32,82.22 136.73,80.81
  BOTTOM w0.127: v2(190.21,66.15) 190.19,66.18 190.19,67.28 187.5,69.97 186.64,69.97 186.27,69.6 177.68,69.6 175.8,71.48 174.43,71.48 172.35,73.56 169.16,73.56 168.88,73.28 162.16,73.28 160.65,71.77 159.61,71.77 158.59,72.78 155.69,72.78 155.2,73.28 149.45,73.28 147.7,75.03 147.42,75.03 146.73,75.72 v1(143.35,75.72) 141.62,75.72 140.12,77.22 140.12,78.23 139.51,78.84 139.28,78.84 138.83,79.28 R937.2 138.39,79.28 137.3,80.37 137.17,80.37 136.73,80.81
GFX_PWRGD: length 480.8
  TOP w0.102: RH51.1 143.57,92.71 142.8,93.47 142.8,94.37 v2(142.89,94.46) ; UE1.74 176.6,74.36 176.29,74.66 176.29,75.03 175.28,76.05 172.93,76.05 172.05,76.92 169.92,76.92 169.4,76.4 169.4,73.47 169.73,73.14 v2(170.75,73.14) ; v2(158.45,106.09) 158.57,106.09 161.44,103.22 161.44,101.32 161,100.88 159.4,99.29 159.4,91.59 157.83,90.02 157.83,82.72 156.53,81.42 156.53,73.41 v2(155.47,72.35)
  TOP w0.127: R664.2 105.34,104.97 103.6,106.71 100.48,106.71 99.1,108.08 99.1,115.69 101.07,117.65 102.31,117.65 108.31,123.66 109.65,123.66 109.94,123.95 109.94,126.25 108.62,127.57 108.62,130.34 110.25,131.98 110.25,134.94 109.28,135.92 108.16,135.92 103.69,140.39 103.69,145.61 v2(105.85,147.76) 106.85,148.77 113.28,148.77 113.54,149.03 PR1070.2
  TOP w0.203: PU500.20 62.22,37.02 62.49,37.29 62.49,37.66 v2(62.68,37.85) ; PU1001.20 115.63,152.91 115.04,152.32 115.04,150.93 113.98,149.86 PR1070.2
  TOP w0.254: PR511.2 v2(62.68,37.85)
  IN1 w0.102: v2(148.53,93.2) 149.05,93.73 150.55,93.73 152.04,95.21 152.04,99.58 154.63,102.17 154.63,107.3 152.7,109.23 v2(152.7,109.31)
  IN2 w0.102: v2(148.53,93.2) 147.09,94.64 143.07,94.64 v2(142.89,94.46) ; v2(56.44,40.83) 56.44,38.86 57.46,37.85 v2(62.68,37.85)
  IN2 w0.127: v2(62.68,37.85) 63.89,39.05 69.91,39.05 70.8,39.94 76.02,39.94 80.48,35.48 80.48,32.8 80.07,32.38 80.07,27.14 81.64,25.56 81.64,21.65 84.33,18.96 85.98,18.96 86.4,18.54 88.8,18.54 89.43,19.16 95.7,19.16 99.17,15.7 110.6,15.7 112.03,14.26 147.52,14.26 149.31,16.05 149.31,17.17 150.83,18.69 150.83,24.26 149.77,25.32 149.77,34.75 149.52,34.99 149.52,39.36 141.45,47.44 141.45,57.75 143.5,59.8 143.5,62.55 v2(142.93,63.12) ; v2(105.85,147.76) 105.85,146.33 109.03,143.15 109.03,118.74 110.11,117.67 118.87,117.67 120.45,119.25 129.85,119.25 131.53,117.57 133.82,117.57 140.26,111.12 144.84,111.12 146.61,109.35 152.66,109.35 v2(152.7,109.31)
  BOTTOM w0.102: v2(170.75,73.14) 170.37,72.76 161.94,72.76 160.72,71.54 159.43,71.54 158.62,72.35 v2(155.47,72.35) 154.77,73.05 151.63,73.05 151.1,72.52 151.1,70.62 151.67,70.05 151.67,69.64 151.19,69.16 149.85,69.16 145.94,65.26 145.94,64.15 144.92,63.12 v2(142.93,63.12) ; v2(56.44,40.83) 51.11,46.16 v1(51.11,47.88) 51.07,47.92 50.2,47.92 43.89,54.23 42.14,54.23 41.71,53.8 39.91,53.8 39.63,54.08 36.44,54.08 35.62,54.9 34.83,54.9 33.89,55.84 Q93.2 ; v2(158.45,106.09) 155.24,109.31 v2(152.7,109.31)
GFX_PWRGD_APU: length 26.8
  TOP w0.102: 115.67,98.43 115.67,97.9 115.85,97.73 118.74,97.73 120.07,96.39 121.21,96.39 122.47,95.14 122.7,95.14 122.93,94.91 122.93,93.93 121.85,92.85 121.85,91.38 122.19,91.03 v2(122.43,91.03)
  TOP w0.127: R664.1 107.21,103.87 v1(108.1,102.98) 109.25,101.83 112.33,101.83 114.53,99.63 115.35,99.63 115.67,99.31 115.67,98.43
  BOTTOM w0.102: v2(122.43,91.03) 122.34,91.12 UC1.AG8
GFX_SVC: length 93.4
  TOP w0.203: v2(57.84,31.24) 58.03,31.43 58.03,31.69 58.36,32.02 PU500.3
  IN2 w0.102: v2(57.84,31.24) 57.84,31.78 54.73,34.89 54.73,41.47 57,43.73 57,52.34 53.89,55.45 53.89,68.71 58.5,73.32 61,73.32 61.33,72.99 72.01,72.99 82.59,83.57 88.24,83.57 88.43,83.38 89.45,83.38 v2(89.82,83.74)
  BOTTOM w0.102: R675.1 95.57,85.47 R14.2 94.85,85.81 94.11,85.81 93.85,85.55 91.62,85.55 v2(89.82,83.74)
GFX_SVC_R: length 5.2
  BOTTOM w0.102: UC1.B16 102.1,84.62 101.63,85.09 100.97,85.09 100.85,85.22 v1(98.6,85.22) 97.92,85.22 R675.2
GFX_SVD: length 92.5
  TOP w0.203: PU500.5 59.16,31.61 v2(59.05,31.5)
  IN2 w0.102: v2(59.05,31.5) 58.59,31.5 55.07,35.02 55.07,41.32 57.33,43.58 57.33,52.5 54.22,55.6 54.22,68.57 58.64,72.99 60.87,72.99 61.2,72.66 72.15,72.66 82.73,83.24 88.11,83.24 88.92,82.42 90.16,82.42 91.28,81.31 v2(91.28,81.32)
  BOTTOM w0.102: v2(91.28,81.32) 91.34,81.25 v1(92.55,81.25) 94.77,81.25 R15.2 R681.1
GFX_SVD_R: length 5.6
  BOTTOM w0.102: R681.2 97.67,81.72 v1(98.12,82.17) 98.46,82.5 100.23,82.5 100.76,83.03 101.65,83.03 UC1.A18
GFX_SVT: length 97.9
  TOP w0.203: PU500.7 59.96,31.88 60.27,31.57 v2(60.27,31.5)
  IN2 w0.102: v2(88.58,83.77) 88.45,83.9 82.45,83.9 71.88,73.32 61.47,73.32 61.14,73.65 58.37,73.65 53.56,68.84 53.56,55.31 56.67,52.2 56.67,43.87 54.4,41.6 54.4,34.76 56.57,32.58 56.57,31.25 56.96,30.86 58.45,30.86 58.66,31.07 59.84,31.07 v2(60.27,31.5)
  BOTTOM w0.102: R682.1 96.25,87.5 96.07,87.68 R13.2 95.38,87.33 95.31,87.25 94.79,87.25 94.72,87.17 91.98,87.17 v1(90.25,85.45) v2(88.58,83.77)
GFX_SVT_R: length 5.3
  BOTTOM w0.102: UC1.B15 101.7,85.42 101.39,85.72 100.28,85.72 99.64,86.36 99.42,86.36 v1(98.72,87.06) 98.28,87.5 R682.2
GFX_VR_ON: length 174.4
  TOP w0.127: v2(55.42,29.93) v1(56.06,29.93)
  TOP w0.254: v2(55.42,29.93) 55.12,29.64 PR533.1
  IN1 w0.127: v2(44.79,65.1) 44.79,62.59 42.28,60.08 42.28,58.78 42.65,58.41 47.86,58.41 52.65,53.62 52.65,47.4 53.24,46.8 53.46,46.8 53.77,46.49 53.77,45.28 53.64,45.15 53.64,34.73 54.18,34.19 54.18,31.17 v2(55.42,29.93)
  IN2 w0.102: v2(121.28,90.61) 121.57,90.91 121.57,91.67 121.49,91.75 121.49,93.64 119.88,95.25 119.88,98.43
  IN2 w0.127: 119.88,98.43 119.88,101.03 122.48,103.64 122.48,105.31 123.73,106.55 123.73,107.59 122.84,108.48 116.5,108.48 115.08,109.9 110.96,109.9 110.02,108.97 104.98,108.97 96.7,100.69 96.7,89.23 93.85,86.37 93.24,86.37 92.91,86.04 92.63,86.04 91.61,87.06 80.41,87.06 70.39,77.04 57.08,77.04 50.41,70.37 50.41,69.55 45.97,65.1 v2(44.79,65.1)
  BOTTOM w0.102: UC1.AD8 119.57,91.12 119.97,90.72 121.17,90.72 v2(121.28,90.61)
GPIO19_CTF: length 18
  TOP w0.102: v2(187.72,138.06) v1(187.72,138.76) 187.72,140.44 186.57,141.59 185.09,141.59 184.9,141.4 RV152.1
  BOTTOM w0.089: UV1.M2 176.89,136.72 178.71,136.72
  BOTTOM w0.102: v2(187.72,138.06) 187.72,137.86 187.24,137.37 183.56,137.37 183.33,137.14 181.35,137.14 RV151.2 179.89,136.58
  BOTTOM w0.127: 179.89,136.58 179.75,136.72 178.71,136.72
GPIO28: length 1.7
  TOP w0.102: v2(176.11,134.06) 176.27,134.21 176.27,134.68 RV21.2
  BOTTOM w0.089: v2(176.11,134.06) 175.99,134.06 UV1.R5
GPU_AC_LIGHT: length 3.2
  TOP w0.127: RE80.1 175.27,77.22 175.64,77.22 176.1,76.75 UE1.68
GPU_VID1: length 20.4
  TOP w0.127: RV168.1 188.41,131.71 v2(187.83,131.13)
  IN1 w0.102: 178.71,135.51 177.62,135.51 176.93,134.82 175.47,134.82 174.58,133.93 173.88,133.93 v2(173.57,134.25)
  IN1 w0.107: 178.71,135.51 178.85,135.51 179.12,135.25 183.3,135.25 187.42,131.13 v2(187.83,131.13)
  BOTTOM w0.102: v2(173.57,134.25) 173.29,134.53 UV1.P8 ; RV76.1 188.08,131.38 v2(187.83,131.13)
GPU_VID1_GPIO_20: length 9
  BOTTOM w0.102: RV76.2 187.18,131.8 RV72.1 RV74.2 186.39,133.64 185.39,134.64 185.39,135.37 184.58,136.18 U1.3
  BOTTOM w0.127: v1(189.31,132.7) 188.83,133.18 187.69,133.18 187.23,133.64 RV74.2
GPU_VID3: length 14.2
  TOP w0.127: RV169.1 187.79,132.64 v1(187.64,132.79) 186.65,133.78 183.24,133.78 182.66,134.37 181.25,134.37 v2(181.02,134.14)
  BOTTOM w0.089: 178.66,135.64 177.61,135.64 UV1.N1
  BOTTOM w0.102: RV75.1 179.6,135.64 178.66,135.64
  BOTTOM w0.127: v2(181.02,134.14) 181.02,134.77 180.75,135.04 180.21,135.04 179.76,135.49 RV75.1
GPU_VID3_GPIO_15: length 3.4
  BOTTOM w0.102: RV75.2 181.59,135.49 RV71.1 RV73.2 182.53,135.53 U1.2
H_PROCHOT#: length 430.1
  TOP w0.102: v2(83.58,84.35) 83.51,84.35 82.92,83.77 R158.2 ; PR1021.2 119.58,158.87 v2(119.58,158.7) 119.21,158.33 119.21,158.05 119.16,158 PU1001.4
  TOP w0.203: PR505.2 58.48,31.62 58.76,31.91 PU500.4
  TOP w0.254: v2(57.27,29.21) 57.27,30.16 57.73,30.62 PR505.2 ; PQ3.3 150.41,170.7 151.33,169.79 151.33,167.46 150.54,166.67 147.39,166.67 146.92,167.14 v2(146.92,168.62) 146.92,169.29 147.03,169.4 PQ3.6 ; PQ2.6 145.13,159.24 v2(145.65,158.72)
  IN1 w0.254: v2(119.58,158.7) 119.44,158.84 119.44,161.29 117.23,163.5 113.71,163.5 112.46,164.74 112.46,166.26 111.36,167.36 v2(111.36,167.63)
  IN2 w0.102: v2(139.38,152.15) 139.66,152.15 142.23,149.57 142.23,148.68 148.27,142.65 148.27,139.21 149.75,137.73 149.75,134.21 149.93,134.04 149.93,131.39 146.45,127.91 146.45,114.71 147.43,113.73 147.43,110.98 147.9,110.5 153.17,110.5 158.5,105.16 158.5,101.92 162.62,97.81 162.62,94.64 162.85,94.41 162.85,91 165.04,88.81 165.04,86.93 v2(165.06,86.92) ; v2(151.87,70.8) 151.62,71.05 151.62,73.31 147.4,77.54 147.4,78.51 149.98,81.09 149.98,82.32 150.28,82.62 150.28,84.38 150.58,84.68 150.58,91.26 149.46,92.38 v2(149.25,92.38) ; v2(89.2,83.76) 89.2,83.83 88.68,84.35 v2(83.58,84.35) 82.44,84.35 71.74,73.65 61.61,73.65 61.28,73.98 58.23,73.98 53.23,68.98 53.23,55.17 56.34,52.07 56.34,44.01 54.07,41.74 54.07,34.62 56.24,32.45 56.24,30.24 v2(57.27,29.21)
  IN2 w0.254: v2(145.65,158.72) 145.65,165.02 146.92,166.29 v2(146.92,168.62)
  BOTTOM w0.102: v2(83.58,84.35) 83.58,78.83 84.59,77.83 84.59,68.38 91.7,61.26 104.39,61.26 105.79,62.66 107.74,62.66 108.12,62.28 145.18,62.28 147.72,64.82 147.72,66.56 149.91,68.76 151.25,68.76 152,69.5 152,70.68 v2(151.87,70.8) ; RE66.2 174.25,84.2 173.45,84.2 173.35,84.3 173.35,84.83 171.46,86.72 169.2,86.72 169.05,86.56 167.05,86.56 166.41,85.93 166.27,85.93 165.28,86.92 v2(165.06,86.92) 164.8,86.92 164.34,86.46 162.49,86.46 162.32,86.63 161.22,86.63 158.58,89.27 155.32,89.27 152.21,92.38 v1(151.54,92.38) v2(149.25,92.38) 149.02,92.15 145.98,92.15 144.62,93.51 143.21,93.51 142.34,94.38 141.28,94.38 140.91,94.74 R661.2 ; RE66.2 R1690.2 ; RE66.2 174.76,84.07 174.81,84.02 Q89.1 175.86,82.83 176.08,83.05 CE46.1 177.54,82.63 177.52,82.61 UE3.4 ; UC1.A15 100.11,85.42 99.72,85.81 98.62,85.81 98.34,86.08 97.29,86.08 96.69,86.68 R159.2 94.85,86.14 93.98,86.14 93.71,85.88 91.26,85.88 89.2,83.82 v2(89.2,83.76)
  BOTTOM w0.254: v2(145.65,158.72) 145.65,156.43 142.35,153.12 141.47,153.12 140.49,152.15 v2(139.38,152.15) 126.09,152.15 123.21,155.03 121.82,155.03 120.92,155.93 120.92,158.47 120.29,159.11 119.82,159.11 119.58,158.86 v2(119.58,158.7) ; v2(111.36,167.63) 111.58,167.41 PR777.1
HDA_BITCLK: length 12.3
  IN2 w0.109: v2(135.82,95.01) 135.82,93.97 135.19,93.34 133.02,93.34 132.64,93.72 131.74,93.72 v2(130.74,92.72)
  BOTTOM w0.099: v2(135.82,95.01) 136.39,94.43 137.97,94.43 138.57,95.03 138.57,95.21 139.32,95.96 RP13.5 ; UC1.AU6 v2(130.74,92.72)
HDA_BITCLK_AUDIO: length 124
  IN2 w0.109: v2(179.44,12.62) 179.46,12.62 180.51,13.67 180.51,14.97 178.4,17.07 178.4,23.65 179.45,24.69 184.94,24.69 187.34,27.09 187.34,29.19 187.34,29.2 187.34,45.63 173.42,59.55 172.43,59.55 171.35,60.62 171.35,64.12 170.2,65.27 170.2,66.05 170.02,66.23 168.99,66.23 167.9,67.32 167.9,70.13 164.24,73.79 164.24,83.25 163.1,84.39 163.1,88 v2(163.37,88.28)
  BOTTOM w0.099: RP13.4 141.25,95.96 142.34,94.87 144.19,94.87 144.82,94.24 v1(151.09,94.24) 151.99,94.24 155.85,90.39 158.93,90.39 161.49,87.83 162.93,87.83 163.37,88.28 v2(163.37,88.28) ; RA1112.1 178.57,11.89 179.29,12.61 179.43,12.61 v2(179.44,12.62) 179.49,12.58 UA1.6
HDA_RST#: length 14.1
  TOP w0.099: v1(130.65,91.15) 130.83,91.33 v2(130.83,91.63)
  IN2 w0.109: v2(130.83,91.63) 131.12,91.92 132.65,91.92 133.65,92.92 135.37,92.92 137.09,94.64 v2(137.09,95.14)
  BOTTOM w0.099: RP13.8 139.36,97.46 137.09,95.19 v2(137.09,95.14) ; UC1.AU9 130.27,90.48 130.7,90.92 130.7,91.5 v2(130.83,91.63)
HDA_RST#_AUDIO: length 120.2
  IN2 w0.109: v2(162.27,89.48) 161.62,88.83 161.62,83.43 162.41,82.64 162.41,72.98 166.66,68.73 166.66,66.8 168.78,64.68 168.95,64.68 170.11,63.52 170.11,60.09 171.9,58.3 172.35,58.3 172.86,57.8 173.41,57.8 186.09,45.12 186.09,28.86 185.01,27.78 180.79,27.78 177.16,24.16 177.16,16.79 177.16,16.79 177.16,16.1 v2(176.93,15.88)
  BOTTOM w0.099: UA1.11 179.98,14.58 179.45,15.11 RA6.1 178.22,15.27 178.21,15.27 178.21,15.57 177.91,15.88 v2(176.93,15.88) ; RP13.1 141.92,97.46 142.75,96.63 v1(144.58,96.63) 147.54,96.63 148.6,95.57 152.99,95.57 156.64,91.92 159.32,91.92 161.76,89.48 v2(162.27,89.48)
HDA_SDIN0: length 126.2
  IN2 w0.109: v2(128.55,90.57) 128.91,90.21 129.75,90.21 130.08,90.54 130.08,90.74 130.36,91.02 133.24,91.02 133.91,91.69 135.3,91.69 135.87,91.12 137.22,91.12 137.37,90.97 137.91,90.97 140.93,93.98 142.55,93.98 143.03,93.5 146.33,93.5 146.77,93.07 146.77,92.71 147.05,92.43 148.4,92.43 150.15,90.69 150.15,85.2 148.79,83.85 148.79,80.48 146.99,78.68 146.99,77.37 151.21,73.14 151.21,70.69 151.63,70.27 151.63,65.61 149.89,63.87 149.89,59.35 152.09,57.15 161.52,57.15 164.57,54.1 164.57,45.89 171.38,39.08 171.38,37.59 173.76,35.21 173.76,30.51 171.82,28.57 171.82,23.51 175.57,19.76 175.57,14.86 v2(176.59,13.84)
  BOTTOM w0.099: RA130.1 176.85,14.11 v2(176.59,13.84) ; UC1.AR8 128.97,90.99 v2(128.55,90.57)
HDA_SDIN1: length 23.7
  TOP w0.127: R695.2 136.49,100.99 v1(138.41,100.99) v2(140.21,100.99)
  IN1 w0.102: v2(128.29,92.54) 128.34,92.54 128.52,92.72 129.67,92.72 130.04,93.09 130.04,93.62 130.44,94.02 131.41,94.02 131.78,94.4 131.78,96.19 132.02,96.43 136.73,96.43
  IN1 w0.127: v2(140.21,100.99) 140.25,100.95 140.25,97.56 139.78,97.09 139.19,97.09 138.52,96.43 136.73,96.43
  BOTTOM w0.102: v2(128.29,92.54) 128.11,92.72 UC1.AP6
HDA_SDIN2: length 9.9
  TOP w0.102: v2(128.55,97.95) 128.14,97.54 128.14,96.9 127.76,96.52 127.76,94.36 127.95,94.17 128.87,94.17 v2(129.5,93.54)
  BOTTOM w0.102: UC1.AR5 128.98,93.54 v2(129.5,93.54)
  BOTTOM w0.127: R696.2 129.6,100.57 v1(129.6,99.69) 129.6,99 v2(128.55,97.95)
HDA_SDOUT: length 13.5
  IN2 w0.109: v2(136.39,95.11) 136.39,94.25 135.28,93.13 133.56,93.13 132.57,92.14 v2(129.54,92.14)
  BOTTOM w0.099: RP13.6 139.32,96.46 138.24,95.39 138.24,95.17 137.83,94.76 136.74,94.76 v2(136.39,95.11) ; UC1.AR7 129.18,92.14 v2(129.54,92.14)
HDA_SDOUT_AUDIO: length 121.1
  IN2 w0.109: v2(179.72,12.09) 179.25,12.09 178.99,12.36 178.99,12.74 180.09,13.84 180.09,14.77 177.99,16.87 177.99,23.82 179.65,25.48 183.88,25.48 186.92,28.52 186.92,45.45 173.25,59.13 172.26,59.13 170.94,60.45 170.94,63.86 169.3,65.51 169.12,65.51 167.49,67.14 167.49,69.96 163.47,73.97 163.47,82.75 162.54,83.68 v2(162.54,88.32)
  BOTTOM w0.099: RP13.3 141.4,96.46 142.35,95.52 146.81,95.52 147.61,94.72 v1(148.32,94.72) 152.41,94.72 156.28,90.84 159.07,90.84 161.59,88.32 v2(162.54,88.32) ; UA1.5 179.81,12.18 v2(179.72,12.09)
HDA_SYNC: length 14.6
  TOP w0.099: v2(137.71,95.17) 138.12,95.17 v1(138.33,95.38)
  IN2 w0.109: v2(137.71,95.17) 137.71,94.67 135.74,92.71 133.74,92.71 132.26,91.23 130.2,91.23 v2(129.68,90.71)
  BOTTOM w0.099: v2(137.71,95.17) 137.71,95.34 139.32,96.96 RP13.7 ; UC1.AT9 129.7,90.05 129.7,90.7 v2(129.68,90.71)
HDA_SYNC_AUDIO: length 118.7
  IN2 w0.109: v2(162.56,88.94) 162.12,88.51 162.12,83.51 162.93,82.7 162.93,73.92 167.08,69.78 167.08,66.97 168.95,65.09 169.12,65.09 170.53,63.69 170.53,60.27 172.08,58.72 172.52,58.72 173.03,58.21 173.58,58.21 186.51,45.29 186.51,28.69 185.18,27.37 180.96,27.37 177.58,23.99 177.58,16.69 179.38,14.88 v2(179.38,14.54)
  BOTTOM w0.099: v2(162.56,88.94) 161.62,88.94 159.23,91.34 156.38,91.34 152.6,95.12 148.01,95.12 147.1,96.04 v1(146.22,96.04) 142.59,96.04 141.67,96.96 RP13.2 ; UA1.10 179.91,14.18 179.55,14.54 v2(179.38,14.54)
HDD_A0_PRE0: length 5.3
  BOTTOM w0.127: v1(184.71,37.74) 184.71,36.02 185.16,35.57 RS24.1 RS27.2 183.83,35.11 US2.9
HDD_A0_PRE1: length 4.3
  BOTTOM w0.127: RS23.1 183.22,26.52 183.22,27.74 RS30.2 182.74,28.21 182.74,28.82 182.83,28.91 US2.19
HDD_B0_EQ: length 2.8
  BOTTOM w0.254: RS37.1 RS38.1 186.68,31.43 186.27,31.85 US2.13
HDD_B0_PRE0: length 5.3
  BOTTOM w0.127: US2.8 183.33,34.94 183.38,34.99 RS28.2 RS21.1 182.94,35.99 182.94,37.47 v1(183.27,37.8)
HDD_B0_PRE1: length 4.7
  BOTTOM w0.127: RS18.1 185.25,26.52 185.25,27.74 RS29.2 183.83,29.16 US2.17
HDD_REXT_SATA0: length 1.2
  BOTTOM w0.127: RS31.1 v1(179.8,28.21)
HDMI_HPLUG: length 22.9
  TOP w0.102: CX20.1 RX34.1 RX15.2 24.57,76.8 v2(24.47,76.8)
  IN1 w0.102: JHDMI.19 10.32,70.14 10.32,70.37 15.69,75.74 15.69,76.38 18.14,78.83 20.64,78.83 21.14,78.33 22.93,78.33 v2(24.47,76.8)
  BOTTOM w0.102: v2(24.47,76.8) v1(24.47,77.37)
HPOUT-L: length 5.4
  IN2 w0.254: v2(189.57,11.13) 188.42,12.27 v2(188.42,12.62)
  BOTTOM w0.203: v2(188.42,12.62) 187.98,12.18 UA1.32
  BOTTOM w0.254: RA55.1 190.06,10.63 v2(189.57,11.13)
HPOUT-R: length 2.2
  BOTTOM w0.203: RA56.1 188.87,11.78 v1(187.93,11.78) UA1.33
HPOUT-R-L: length 12.3
  BOTTOM w0.254: RA55.2 RA165.2 RA83.1 192.41,8.84 192.61,9.04 RA80.2 193.96,11.07 v1(193.96,11.56) 194.29,11.89 194.29,16.13 LA8.2
HPOUT-R-R: length 8
  BOTTOM w0.254: LA9.2 193.69,15.2 193.69,13.93 v1(193.45,13.69) 193.45,13.13 192.74,12.42 RA82.2 RA84.1 190.53,12.73 RA166.2 189.95,11.94 RA56.2
HSYNC: length 2.4
  TOP w0.127: RZ47.1 34.73,73.41 v1(35.08,73.06) 35.77,72.36 UZ1.8
HVB_FUNCTION: length 50.3
  TOP w0.102: v2(133.38,85.95) v1(134,85.95)
  TOP w0.127: v2(147.26,57.14) 148.71,55.69 RH46.2 RH44.2 RH45.2
  IN1 w0.127: v2(147.26,57.14) 147.26,58.22 143.58,61.9 143.58,63.7 142.79,64.49 142.79,66.61 143.63,67.45 146.93,67.45 148.54,69.05 148.54,72.67 144.37,76.83 142.92,76.83 v2(141.45,78.31)
  IN2 w0.102: 140.12,83.28 138.6,84.8 136.48,84.8 135.32,85.95 v2(133.38,85.95)
  IN2 w0.127: v2(141.45,78.31) 140.8,78.96 140.8,80.32 140.63,80.48 140.63,82.77 140.12,83.28
  BOTTOM w0.102: UC1.BB14 133.87,86.21 133.61,85.95 v2(133.38,85.95)
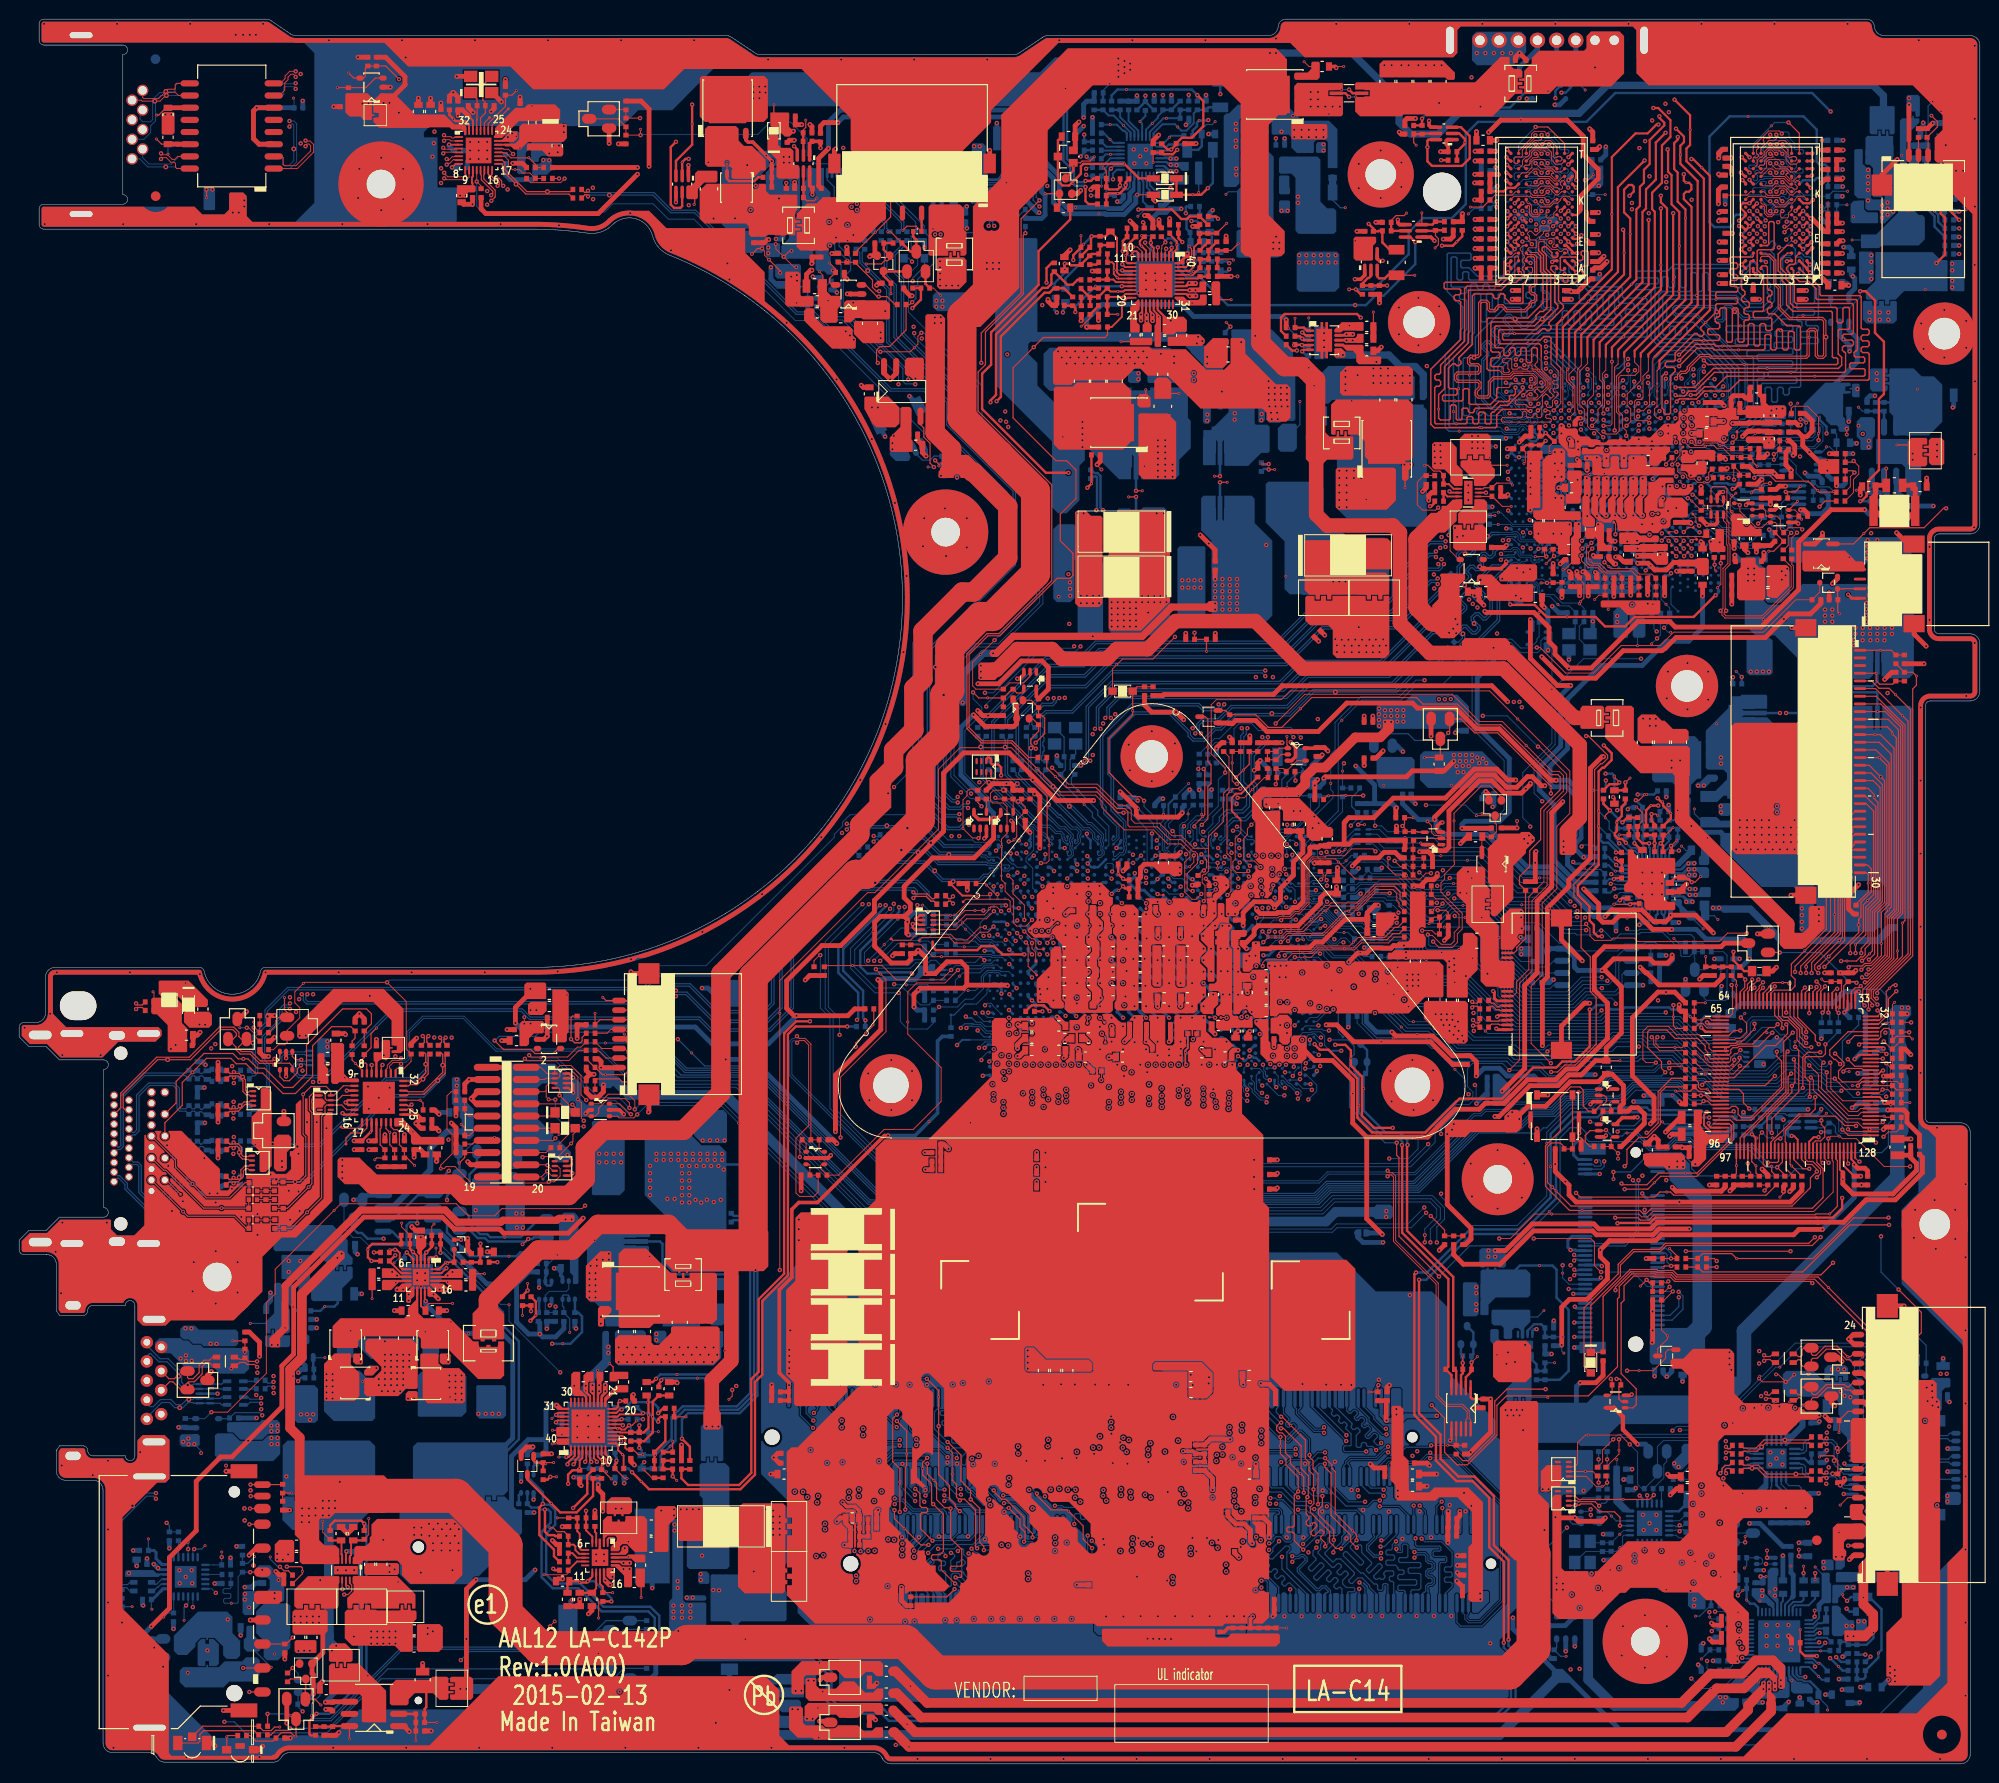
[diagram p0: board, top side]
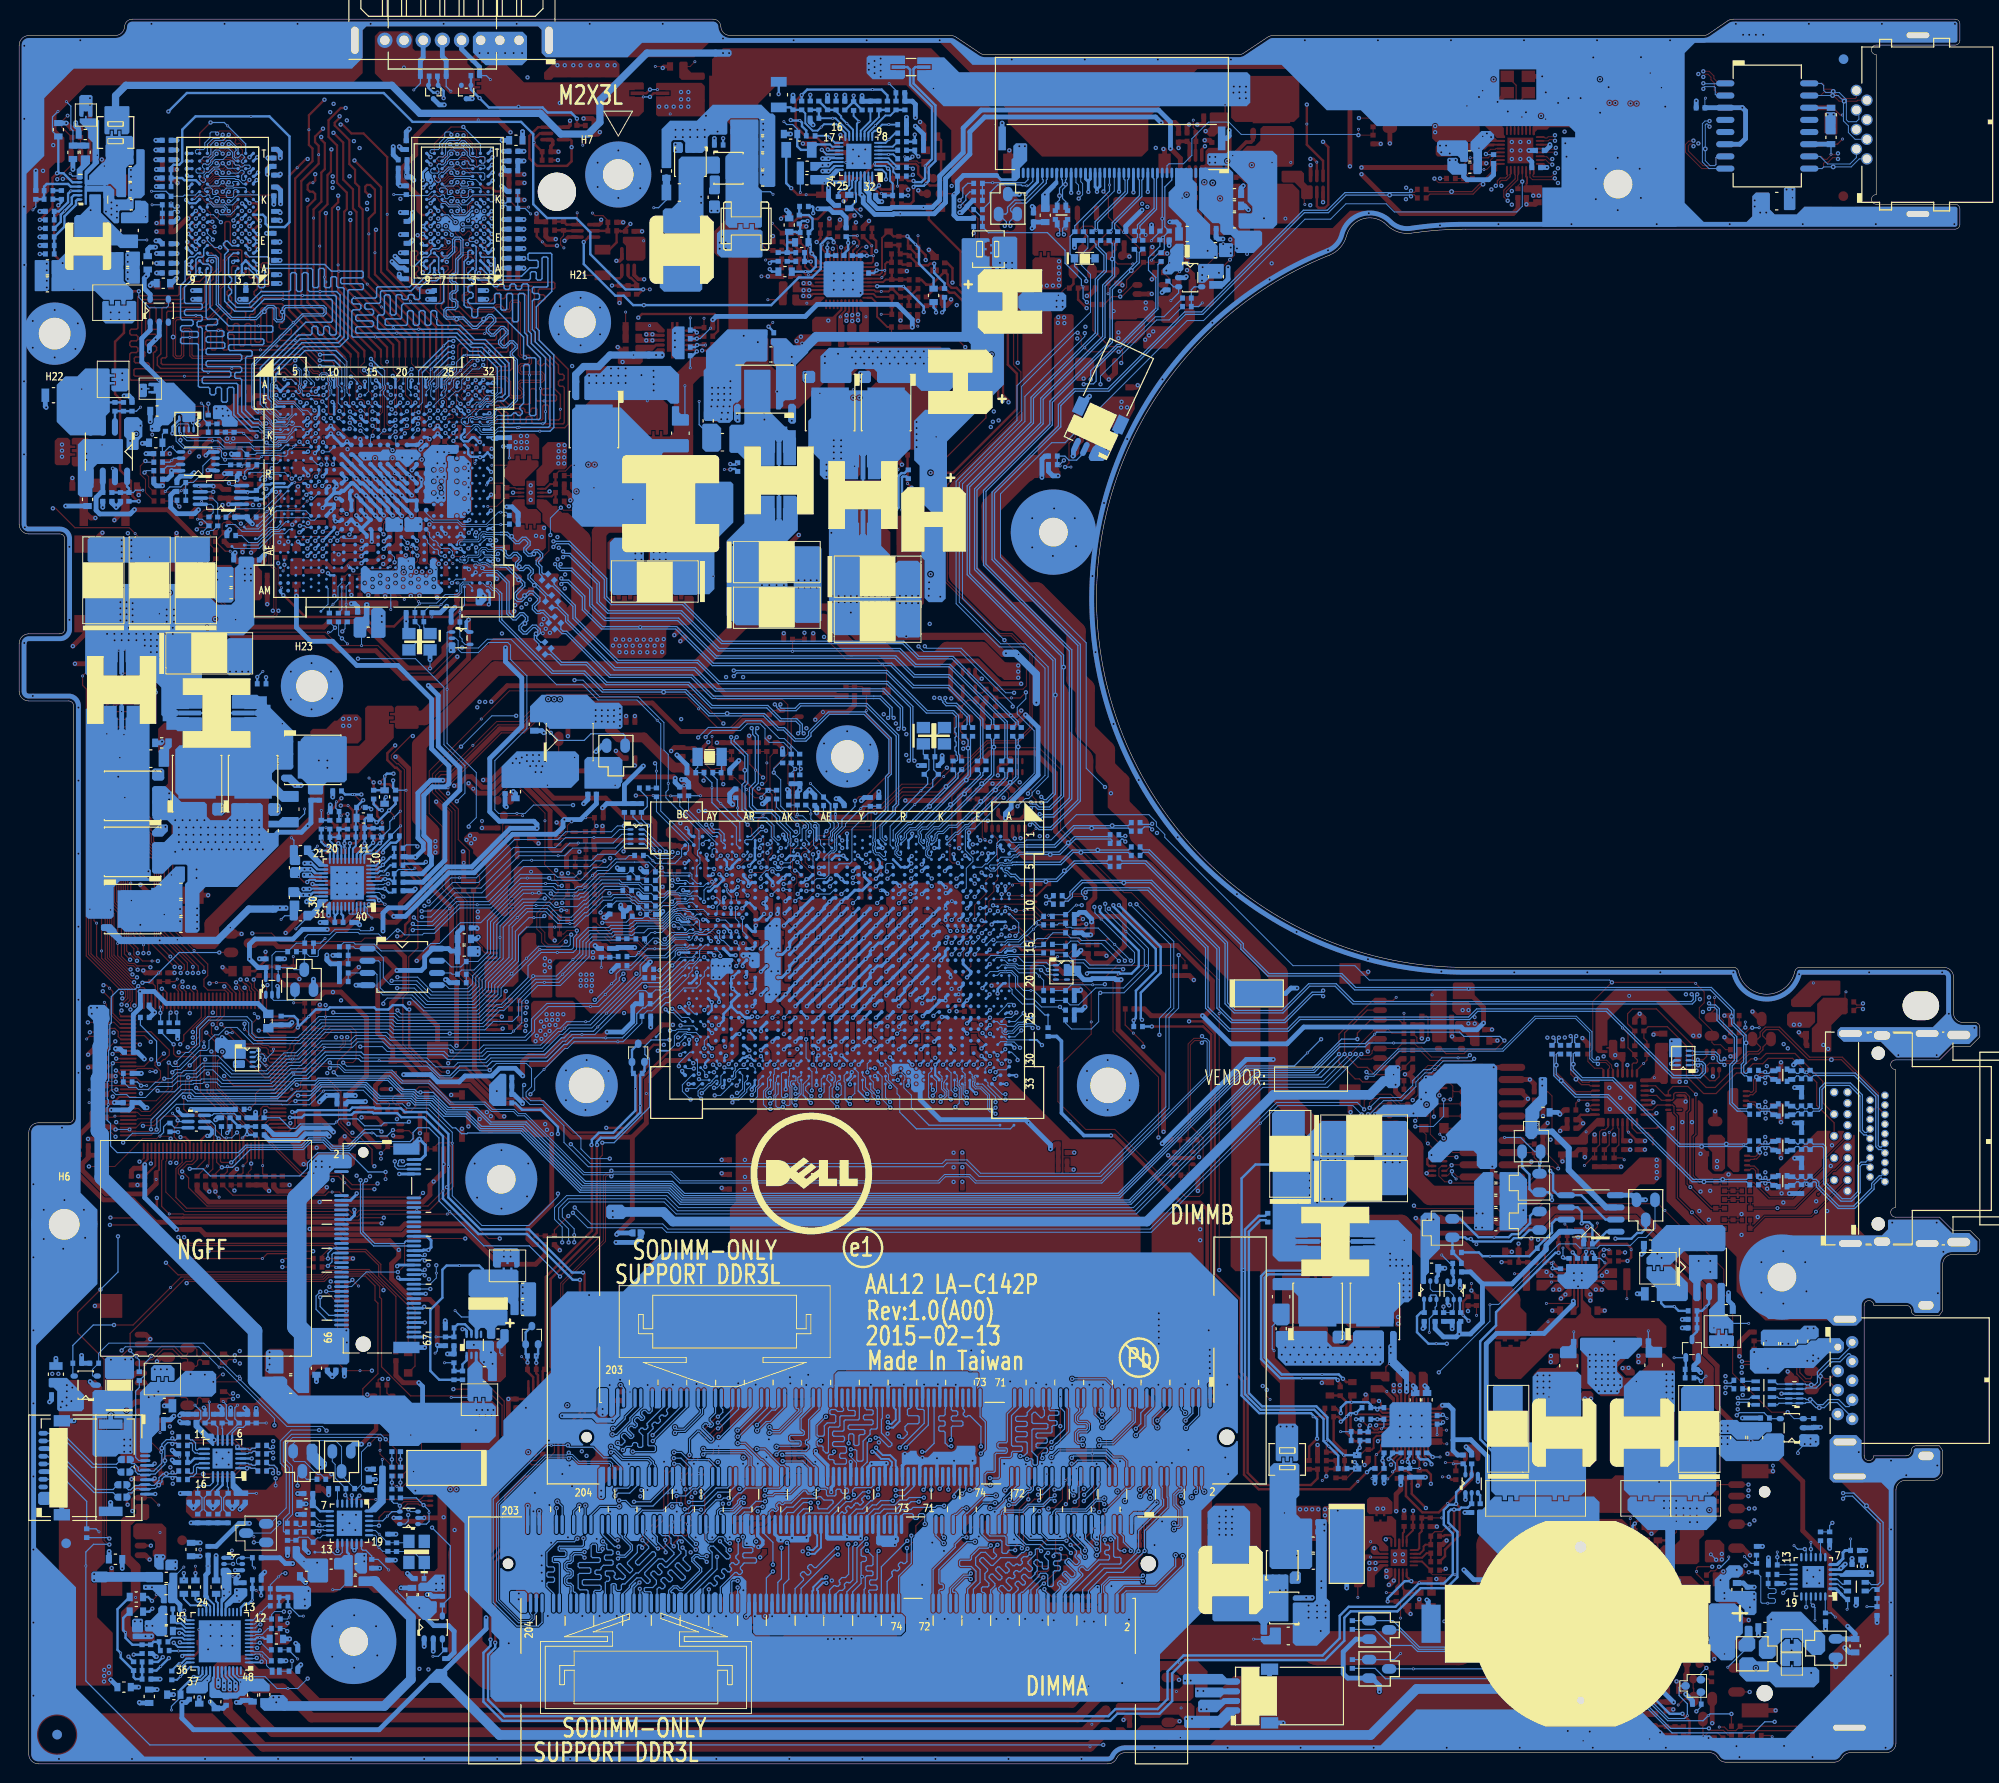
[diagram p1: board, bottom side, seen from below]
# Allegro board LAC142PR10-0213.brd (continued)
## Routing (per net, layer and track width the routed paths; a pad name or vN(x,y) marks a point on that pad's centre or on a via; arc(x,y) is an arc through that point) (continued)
I2C1_SCL_TP_R: length 161.5
  TOP w0.102: v2(166.31,33.85) 165.19,32.74 165.19,31.48 R145.2 ; RE337.2 60.78,74.61 JTP.3 63.15,74.61 63.4,74.36 63.4,74.13 63.66,73.88 64.37,73.88 v2(64.52,74.03) ; v2(146.65,54.39) v4(146.65,55.15)
  IN2 w0.102: v2(146.65,54.39) 146.65,44.5 152.32,38.83 152.32,36.54 155.01,33.85 v2(166.31,33.85)
  BOTTOM w0.102: v2(166.31,33.85) 166.83,34.37 176.15,34.37 176.99,33.53 176.99,31.51 176.36,30.89 176.36,26.15 176.99,25.53 176.99,24.26 176.9,24.18 R142.2 ; v2(146.65,54.39) 146.65,55.8 147.88,57.04 147.88,57.89 147.17,58.6 137.27,58.6 136.01,57.35 88,57.35 74.79,70.56 68.04,70.56 64.57,74.03 v2(64.52,74.03)
I2C1_SDA_TP_R: length 158.2
  TOP w0.102: R144.2 166.9,32.3 v1(166.9,32.7) v2(166.9,33.85) ; RE336.2 60.39,74.42 61.21,73.61 JTP.2 63.4,73.61 63.51,73.51 64.58,73.51 v2(65.11,74.03)
  IN2 w0.102: v2(147.23,54.39) 147.23,44.38 152.65,38.97 152.65,36.68 155.04,34.29 166.46,34.29 v2(166.9,33.85)
  BOTTOM w0.102: v2(65.11,74.03) 65.17,74.03 68.31,70.89 74.93,70.89 88.14,57.68 135.87,57.68 137.13,58.93 147.31,58.93 148.27,57.97 148.27,56.83 147.23,55.79 v2(147.23,54.39) ; v2(166.9,33.85) 167.1,34.04 176.01,34.04 176.63,33.42 176.63,31.62 176.03,31.02 176.03,26.02 176.58,25.47 R143.2
I2C_CLK: length 11
  TOP w0.102: v2(164.78,29.34) 164.78,29.9 R145.1 164.19,30.48 v1(163.4,30.48) RP20.2
  IN2 w0.102: v2(164.78,29.34) 163.57,28.13 163.57,26.36 v2(163.97,25.96)
  BOTTOM w0.102: Q2505.6 164.28,25 163.97,25.32 v2(163.97,25.96) ; R122.2 v2(164.78,29.34) R135.2
I2C_CLK_TP: length 25.4
  TOP w0.102: RE337.1 58.6,74.75 58.24,74.75 57.21,73.72 53.4,73.72 v2(53.21,73.91) ; Q2509.3 60.1,67.55 60.46,67.91 60.46,68.38 61.46,69.38 63.23,69.38 63.67,68.94 v2(63.67,68.41)
  BOTTOM w0.102: v2(63.67,68.41) 62.58,69.49 60.44,69.49 59.16,70.77 59.16,71.26 58.03,72.4 57.36,72.4 56.13,73.63 v1(54.43,73.63) 53.49,73.63 v2(53.21,73.91)
I2C_DAT: length 11.3
  TOP w0.102: RP20.1 163.47,29.98 164.51,28.94 v1(165.14,28.94) 165.27,28.94 v2(165.66,29.34) 165.66,29.9 R144.1
  IN2 w0.102: v2(163.95,26.54) 163.95,27.62 v2(165.66,29.34)
  BOTTOM w0.102: R136.2 v2(165.66,29.34) R123.2 ; v2(163.95,26.54) 163.71,26.3 Q2505.3
I2C_DAT_TP: length 23.3
  TOP w0.102: v2(52.76,73.53) 52.93,73.36 57.36,73.36 58.41,74.42 RE336.1 ; Q2509.6 62.65,68.85 63.75,67.75 v2(63.82,67.75)
  BOTTOM w0.102: v2(63.82,67.75) 63.62,67.75 62.21,69.16 60.31,69.16 58.83,70.64 58.83,71.12 57.89,72.07 57.23,72.07 v1(56.86,72.44) 55.99,73.3 52.99,73.3 v2(52.76,73.53)
ILMT_1.35VGPU: length 4.9
  BOTTOM w0.254: PR1401.2 PR1408.1 200.4,161.92 199.45,162.88 199.45,163.77 v1(199.16,164.06) PU1400.3
IMON_APU: length 3.7
  TOP w0.203: v2(116.12,157.3) 116.12,157.58 116.29,157.76 116.57,157.76 116.76,157.56 PU1001.10
  BOTTOM w0.127: v2(116.12,157.3) v1(115.43,157.3)
  BOTTOM w0.254: PR1076.2 116.78,157.31 PC1062.2 116.12,157.31 v2(116.12,157.3)
IMON_GFX: length 4.8
  TOP w0.203: v2(61.68,31.78) 61.68,31.8 61.16,32.32 PU500.10
  BOTTOM w0.127: v1(61.27,30.45) 60.98,30.75 60.98,31.37 61.39,31.78 v2(61.68,31.78)
  BOTTOM w0.254: PR510.2 PC509.2 61.27,32.27 61.68,31.86 v2(61.68,31.78)
IMON_NB: length 3.3
  TOP w0.203: v2(120.24,158.13) 120.24,157.95 119.96,157.68 PU1001.2
  BOTTOM w0.127: v1(120.16,158.64) 120.24,158.56 v2(120.24,158.13)
  BOTTOM w0.254: PR1018.2 119.38,157.32 PC1018.2 120.23,158.14 v2(120.24,158.13)
IMON_VGA: length 3.2
  TOP w0.254: PC1117.2 PR1117.2 166.82,94.17 v2(166.57,94.42)
  BOTTOM w0.203: v2(166.57,94.42) 166.88,94.11 166.9,94.11 167.32,93.68 PU1100.10
INT-SPK-L+: length 96
  TOP w1.016: LA5.1 91.43,9.65 v1(92.98,8.1) 94.73,6.35 173.42,6.35 176.47,9.4 179.76,9.4 181.16,10.79 182.94,10.79 183.7,10.03
  vias: v2(183.78,8.72) v2(183.78,8.1)
INT-SPK-L-: length 93.4
  TOP w1.016: LA6.1 91.56,7.37 94.1,4.83 174.06,4.83 177.1,7.87 179.93,7.87 181.58,9.52
  vias: v2(183.18,8.42) v2(183.18,7.81)
INT-SPK-R+: length 92.5
  TOP w1.016: 181.03,6.73 180.38,6.08 180.38,5.6 178.08,3.3 93.47,3.3 v1(92.64,4.13) LA3.1
  vias: v2(181.97,8.38) v2(181.97,7.8)
INT-SPK-R-: length 94.6
  TOP w1.016: LA4.1 91.31,3.3 v1(92.83,1.78) 179.09,1.78 182.77,5.46 182.77,6.29
  vias: v2(182.57,8.41) v2(182.56,7.79)
INVTPWM: length 84.8
  TOP w0.102: U65.4 103.7,100.62 R1161.1 R703.2 101.97,100.63 v2(101.85,100.76)
  IN2 w0.102: v2(99.31,101.19) 99.42,101.08 101.53,101.08 v2(101.85,100.76)
  BOTTOM w0.102: JEDP.20 90.3,164.05 93.53,160.82 RX26.1 93.06,159.33 93.06,158.1 93.73,157.43 93.73,156.31 92.78,155.36 92.78,151.41 100.45,143.74 100.45,140.12 106.8,133.77 106.8,121.01 102.29,116.49 99.74,116.49 97.53,114.28 97.53,103.09 99.27,101.35 99.27,101.23 v2(99.31,101.19)
INVTPWM_R: length 20.4
  TOP w0.102: v2(105.67,88.02) 105.02,87.38 104.07,87.38 103.75,87.7 103.75,90.11 102.86,91 102.86,91.82 102.48,92.2 v1(102.48,95.68) 102.48,96.46 103.05,97.03 U65.2 103.05,99.83 102.67,100.22 101.56,100.22 101.33,100.44 101.33,101.23 101.65,101.55 R703.1
  BOTTOM w0.102: v2(105.67,88.02) 105.27,88.42 UC1.F11
ISEN1_VGA: length 9
  TOP w0.254: PR1124.1 167.57,100.2 167.19,99.82 167.19,98.86 166.68,98.35 v1(166.68,98.16) 166.68,97.28 166.48,97.08 166.48,96.82 166.83,96.47 167.22,96.47 v2(167.63,96.07)
  BOTTOM w0.203: PC1120.2 v2(167.63,96.07) 168.15,95.54 168.68,95.54 169.34,94.89 PU1100.13
ISEN2_VGA: length 12.4
  IN2 w0.254: v2(166.72,99.47) 166.73,99.45 166.73,96.22 v2(166.93,96.01)
  BOTTOM w0.127: v1(164.79,99.36) 165.88,98.27 165.88,97.51 166.72,96.67 PC1119.2
  BOTTOM w0.203: PU1100.12 168.94,94.85 168.55,95.24 167.8,95.24 167.02,96.01 v2(166.93,96.01) 166.74,96.21 PC1119.2
  BOTTOM w0.254: PR1104.1 167.57,100.08 167,99.5 166.76,99.5 v2(166.72,99.47)
ISOLATEB: length 5.6
  TOP w0.127: UL1.20 50.43,168.08 50.49,168.02 50.78,168.02 51.29,167.51 v1(53.17,167.51) 53.85,166.83 RL35.1 RL33.2
JACK_SENSE#: length 17.3
  TOP w0.102: v1(179.83,18.1) 179.3,17.58 v2(179.3,17.56)
  TOP w0.254: JIO1.2 190.82,22.76 v2(190.81,22.76)
  IN2 w0.254: v2(190.81,22.76) 190.23,22.17 182,22.17 180.97,21.15 180.97,19.88 179.3,18.21 v2(179.3,17.56)
  BOTTOM w0.254: RA34.2 v2(179.3,17.56)
JHDD_P10: length 12.3
  BOTTOM w0.127: v1(190.77,42.46) 191.47,41.76 191.47,40.51 192,39.98 RS8.2 192.02,39.24 192.4,38.86 192.4,31.95 192.08,31.63 JHDD1.5
JTAG_TCK: length 12.7
  BOTTOM w0.102: RP34.5 187.85,138.8 187.05,138 v1(184.37,138) 183.81,138 183.16,137.35 180.36,137.35 179.98,136.97 177.32,136.97 176.73,137.56 UV1.L3
JTAG_TDI: length 17.9
  BOTTOM w0.102: RP34.7 186.85,139.65 186.96,139.75 187.88,139.75 188.18,139.45 188.18,137.96 187.39,137.17 183.65,137.17 183.45,136.98 183.45,136.34 183.23,136.12 179.48,136.12 v1(179.24,136.36) 179.14,136.46 177.41,136.46 177.34,136.39 176.73,136.39 176.52,136.59 176.52,136.96 176.33,137.16 176.09,137.16 UV1.L5
JTAG_TDO: length 4.4
  TOP w0.127: v2(178.74,137.81) 179.23,138.29 T86.1
  BOTTOM w0.102: v2(178.74,137.81) 178.52,137.58 177.69,137.58 177.42,137.85 176.63,137.85 176.13,138.36 UV1.K4
JTAG_TMS: length 11.2
  BOTTOM w0.102: UV1.L1 177.49,137.36 180.08,137.36 180.52,137.79 v1(182.53,137.79) 183.04,137.79 183.6,138.35 187.08,138.35 187.35,138.63 RP34.6
JTAG_TRSTB: length 14.4
  TOP w0.127: v4(186.43,139.89) 186.09,140.23 v2(185.84,140.23)
  IN2 w0.107: v2(175.3,137.9) 175.78,137.42 179.35,137.42 181.19,139.26 183.48,139.26 184.44,140.23 v2(185.84,140.23)
  BOTTOM w0.089: v2(175.3,137.9) 174.97,137.56 UV1.L6
  BOTTOM w0.102: v2(185.84,140.23) 186.35,139.71 RP34.8
KB_BL_PWM:
  vias: v1(190.94,125.86)
KB_CAPS_PWR: length 5.7
  TOP w0.127: R29.2 196.68,112.94 RE73.1 195.46,112.61 194.1,112.61 193.73,112.98 v1(193.73,113.75) JKB.4
KB_DET: length 5
  TOP w0.127: JKBBL.2 190.38,122.57 190.35,122.54 QE4.2 189.7,121.45 RE58.1 189.73,121.4 189.73,120.14 v1(189.92,119.95)
KB_DET#: length 74
  TOP w0.102: QE4.1 187.85,122.21 RE68.1 185.34,121.41 181.96,118.03 172.61,118.03 171.21,116.64 167.12,116.64 164.25,113.77 161.34,113.77 158.67,116.43 v2(158.34,116.43)
  BOTTOM w0.102: UC1.BB2 134.17,95.93 137.62,99.38 137.62,108.48 v1(137.99,108.85) 140.1,110.96 144.16,110.96 145.75,112.55 148.48,112.55 153.23,117.3 155.72,117.3 156.64,116.38 158.29,116.38 v2(158.34,116.43)
KB_LED_PWM: length 75.1
  TOP w0.127: QE5.3 191.37,127.24 v1(192.45,128.32) 193.06,128.93 198.74,128.93 200.75,130.95 v2(201.03,130.95) ; UE1.25 192.09,75.16 v2(191.95,75.02)
  IN1 w0.127: v2(191.95,75.02) 191.95,75.3 194.72,78.07 194.72,80.71 194.67,80.76 194.67,82.63 195.98,83.94 195.98,112.24 197.65,113.91 197.65,128.79 199.34,130.48 200.56,130.48 v2(201.03,130.95)
KB_RST#: length 71.3
  TOP w0.102: v2(190.79,66.18) 191.02,65.96 UE1.2
  BOTTOM w0.102: UC1.AY15 132.97,85.42 133.56,84.83 133.56,84.16 133.77,83.95 133.77,83.88 134.2,83.46 134.66,83.46 135.07,83.05 135.07,82.95 137.31,80.71 138.17,80.71 R941.2 139.2,80.64 139.91,80.64 144.5,76.06 v1(145.84,76.06) 146.87,76.06 147.56,75.37 147.84,75.37 149.59,73.62 155.34,73.62 155.83,73.13 158.78,73.13 159.22,72.69 161.09,72.69 162.01,73.62 168.74,73.62 169.02,73.9 172.49,73.9 174.57,71.82 175.95,71.82 177.83,69.94 186.12,69.94 186.5,70.31 187.64,70.31 190.79,67.16 v2(190.79,66.18)
KSI0: length 25.3
  TOP w0.127: UE1.55 182.75,80.37 183.08,80.7 184.85,80.7 185.27,81.11 185.27,81.83 184.88,82.22 184.88,83.41 v1(186.3,84.84) 188.52,87.06 188.52,94.23 190.53,96.24 190.53,97.13 190.81,97.41 190.81,98.62 191.55,99.35 JKB.22
KSI1: length 23.4
  TOP w0.127: UE1.56 182.35,80.33 183.11,81.09 v2(183.16,81.09) ; v2(185.86,82.49) 185.86,83.18 189.41,86.74 v1(189.41,88.58) 189.41,94.48 190.99,96.05 190.99,96.88 191.29,97.19 191.29,97.66 191.38,97.75 JKB.24
  IN1 w0.127: v2(183.16,81.09) 184.25,82.18 185.58,82.18 185.86,82.46 v2(185.86,82.49)
KSI2: length 23
  TOP w0.127: v2(187,82.49) 187,83.57 189.99,86.55 189.99,94.4 191.45,95.86 191.45,96.01 191.58,96.15 JKB.26 ; UE1.57 181.95,80.37 182.56,80.98 182.56,81.08 182.96,81.48 v1(183.98,81.48) 184.6,81.48 v2(184.69,81.39)
  IN1 w0.127: v2(184.69,81.39) 186.16,81.39 187,82.23 v2(187,82.49)
KSI3: length 24.7
  TOP w0.127: v2(185.27,82.6) 185.27,83.17 v1(188.05,85.95) 188.97,86.87 188.97,94.36 190.76,96.15 190.76,96.98 191.06,97.28 191.06,98.3 191.32,98.55 JKB.23 ; UE1.58 181.55,80.56 v2(181.93,80.94)
  IN1 w0.127: v2(185.27,82.6) 184.24,82.6 183.37,81.72 182.71,81.72 v2(181.93,80.94)
KSI4: length 24.3
  TOP w0.127: v2(181.93,81.51) 181.53,81.11 181.53,80.86 181.15,80.49 UE1.59 ; v2(187.7,82.49) 187.32,82.87 187.32,83.31 v4(189.89,85.88) 190.21,86.21 190.21,94.31 191.26,95.35 JKB.27
  IN1 w0.127: v2(181.93,81.51) 182.37,81.95 183.17,81.95 184.21,82.99 187.19,82.99 v2(187.7,82.49)
KSI5: length 25.2
  TOP w0.127: v2(186.43,82.49) v4(186.43,83.12) 186.43,83.38 189.76,86.7 189.76,94.5 191.22,95.96 191.22,96.67 191.49,96.95 JKB.25 ; UE1.60 180.75,80.67 v2(181.04,80.95)
  IN1 w0.127: v2(181.04,80.95) 181.66,80.33 182.99,80.33 184.59,81.93 185.87,81.93 v2(186.43,82.49)
KSI6: length 23.9
  TOP w0.127: JKB.28 190.78,94.55 190.44,94.21 190.44,85.86 v4(188.78,84.2) 187.76,83.18 v2(187.76,83.06) ; UE1.61 180.35,80.54 180.53,80.72 180.53,81 180.87,81.34 180.99,81.34 v2(181.45,81.81)
  IN1 w0.127: v2(187.76,83.06) 187.6,83.22 184.05,83.22 183.52,82.69 182.05,82.69 181.45,82.1 v2(181.45,81.81)
KSI7: length 24.6
  TOP w0.127: JKB.29 192.83,93.75 193.22,93.36 193.22,90.93 192.14,89.85 192.14,88.33 191.91,88.09 v4(191.91,87.5) 191.91,86.7 v2(188.33,83.12) ; v2(180.8,81.8) 180.3,81.3 180.3,80.87 179.95,80.52 UE1.62
  IN1 w0.127: v2(180.8,81.8) 181.41,82.41 182.57,83.57 187.83,83.57 188.27,83.12 v2(188.33,83.12)
KSO0: length 34.8
  TOP w0.127: v2(192.93,82.86) 193.17,82.86 194.66,84.35 194.66,88.68 195.01,89.04 v1(195.01,89.07) 195.31,89.36 195.31,105.31 194.07,106.55 JKB.13 ; UE1.39 189.15,80.44 189.54,80.84 v2(189.67,80.84)
  IN1 w0.127: v2(192.93,82.86) 192.74,82.86 192.23,83.37 192.1,83.37 191.76,83.71 190.6,83.71 190.14,83.24 190.14,81.31 v2(189.67,80.84)
KSO1: length 35.1
  TOP w0.127: JKB.15 v1(194.05,104.95) 194.85,104.15 194.85,89.75 193.88,88.79 193.88,84.23 193.14,83.48 192.54,83.48 192.27,83.22 191,83.22 v2(190.86,83.08) ; UE1.40 v2(188.75,78.36)
  IN1 w0.127: v2(190.86,83.08) 190.59,82.82 190.59,80.8 188.57,78.78 188.57,78.54 v2(188.75,78.36)
  BOTTOM w0.127: v2(188.75,78.36) 188.91,78.2 RE62.2
KSO2: length 37.1
  TOP w0.127: v2(188.14,78.36) 188.35,78.56 UE1.41 ; v2(192.19,82.82) 192.2,82.82 192.2,82.83 192.21,82.84 192.23,82.84 192.64,83.25 193.24,83.25 194.28,84.3 v1(194.28,85.57) 194.28,88.81 195.08,89.61 195.08,104.37 193.7,105.75 JKB.14
  IN1 w0.127: v2(188.14,78.36) 188.14,78.68 190.37,80.9 190.37,83.15 190.7,83.48 191.64,83.48 191.87,83.25 191.87,83.14 v2(192.19,82.82)
  BOTTOM w0.127: RE63.2 188.08,77.36 188.08,78.3 v2(188.14,78.36)
KSO3: length 31.6
  TOP w0.127: JKB.16 193.02,104.15 v4(194.21,102.96) 194.61,102.57 194.61,89.83 193.57,88.79 193.57,84.47 v2(192.98,83.88) ; v2(188.4,81.09) 188.4,81.02 187.95,80.57 UE1.42
  IN1 w0.127: v2(192.98,83.88) 192.69,84.16 190.53,84.16 190.33,84.36 189.82,84.36 189.45,83.99 189.45,82.02 188.52,81.09 v2(188.4,81.09)
KSO4: length 27.5
  TOP w0.127: JKB.20 192.59,100.95 193.69,99.85 193.69,90.39 192.65,89.34 192.65,86.49 v1(191.59,85.42) v2(191.59,84.56) ; v2(187.51,81.6) 187.95,81.15 187.95,80.9 187.55,80.5 UE1.43
  IN1 w0.127: v2(191.59,84.56) 191.59,84.62 191.26,84.95 189.64,84.95 188.97,84.28 188.97,82.23 188.53,81.79 187.7,81.79 v2(187.51,81.6)
KSO5: length 25.3
  TOP w0.127: v2(191.03,84.56) 191.03,85.43 192.4,86.8 192.4,89.6 v1(192.84,90.04) 193.47,90.67 193.47,99.38 192.69,100.15 JKB.21 ; v2(187.51,81.03) 187.51,80.9 187.15,80.54 UE1.44
  IN1 w0.127: v2(187.51,81.03) 188.04,81.56 188.63,81.56 189.22,82.16 189.22,84.1 189.71,84.58 191,84.58 v2(191.03,84.56)
KSO6: length 32.3
  TOP w0.127: v2(190.07,83.73) v1(190.68,83.73) 191.67,83.73 192.1,84.16 192.35,84.16 192.59,84.39 192.59,85.03 193.11,85.55 193.11,89.04 194.15,90.08 194.15,101.82 193.42,102.55 JKB.18 ; UE1.45 v2(186.75,78.3)
  IN1 w0.127: v2(186.75,78.3) 186.75,80.01 187.09,80.35 188.62,80.35 189.91,81.64 189.91,83.57 v2(190.07,83.73)
KSO7: length 29.7
  TOP w0.127: v2(186.94,81.03) 186.35,80.44 UE1.46 ; v2(192.17,84.56) 192.17,85.05 192.88,85.76 192.88,89.19 193.92,90.23 193.92,100.28 193.53,100.67 v1(193.53,100.79) 193.53,101.1 192.88,101.75 JKB.19
  IN1 w0.127: v2(186.94,81.03) 186.94,81.66 187.32,82.04 188.46,82.04 188.74,82.32 188.74,84.37 189.55,85.18 191.56,85.18 192.17,84.57 v2(192.17,84.56)
KSO8: length 32.7
  TOP w0.127: v2(186.3,80.96) 185.95,80.61 UE1.47 ; v2(192.26,83.76) 192.31,83.76 v1(193.02,84.47) 193.34,84.79 193.34,88.89 194.38,89.93 194.38,102.16 193.19,103.35 JKB.17
  IN1 w0.127: v2(186.3,80.96) 186.68,80.58 188.52,80.58 189.68,81.74 189.68,83.9 189.91,84.13 190.24,84.13 190.43,83.93 192.09,83.93 v2(192.26,83.76)
KSO9: length 50.3
  TOP w0.127: UE1.48 185.55,77.85 187.38,76.02 187.38,75.43 v2(187.75,75.06) ; JKB.7 193.73,111.35 196.74,108.34 196.74,87.95 v1(196.48,87.69) 196.48,84.23 192.99,80.74 192.99,79.64 193.32,79.31 v2(193.32,79.11)
  IN1 w0.127: v2(193.32,79.11) 193.34,79.09 193.34,78.52 192.8,77.98 192.79,77.98 190.63,75.82 189.9,75.82 188.69,74.61 188.19,74.61 v2(187.75,75.06)
KSO10: length 51.7
  TOP w0.127: v2(186.43,76.33) 186.43,76.64 185.15,77.92 UE1.49 ; v2(193.79,79.83) 193.61,79.83 193.44,80 193.44,80.55 197.31,84.42 197.31,109.96 v1(195.76,111.51) 195.09,112.18 194.04,112.18 193.27,112.95 JKB.5
  IN1 w0.127: v2(193.79,79.83) 193.77,79.85 192.17,79.85 191.74,79.42 191.74,78.45 190.11,76.82 186.92,76.82 v2(186.43,76.33)
KSO11: length 52.1
  TOP w0.127: v2(186.43,75.76) 185.98,76.2 185.98,76.71 184.75,77.94 UE1.50 ; v2(193.87,79.19) 193.22,79.85 193.22,80.65 197.06,84.49 197.06,108.75 v1(196.49,109.32) 193.66,112.15 JKB.6
  IN1 w0.127: v2(186.43,75.76) 187.27,76.59 190.21,76.59 191.97,78.35 191.97,79.33 192.26,79.62 193.44,79.62 v2(193.87,79.19)
KSO12: length 42
  TOP w0.127: UE1.51 v2(184.35,78.36) ; v2(192.73,82.34) 192.97,82.34 194.89,84.26 194.89,88.39 195.6,89.1 195.6,105.92 194.17,107.35 v1(193.62,107.35) JKB.12
  IN1 w0.127: v2(184.35,78.36) 184.92,77.79 188.74,77.79 189.16,78.21 189.16,79.05 190.82,80.71 190.82,81.87 191.31,82.35 191.76,82.35 191.84,82.43 192.64,82.43 v2(192.73,82.34)
KSO13: length 49.3
  TOP w0.127: v2(186.43,75.18) 185.76,75.86 185.76,76.61 184.52,77.85 184.14,77.85 183.95,78.04 UE1.52 ; v2(192.52,79.09) 192.33,79.28 192.33,80.74 195.57,83.97 195.57,88.11 196.28,88.82 196.28,108.15 194.68,109.75 v1(193.86,109.75) JKB.9
  IN1 w0.127: v2(186.43,75.18) 187.61,76.37 190.3,76.37 192.52,78.59 v2(192.52,79.09)
KSO14: length 51.6
  TOP w0.127: v2(186.96,74.74) 186.24,74.74 185.48,75.51 185.48,76.57 184.51,77.53 184.02,77.53 183.55,78 UE1.53 ; v2(192.94,78.68) 192.92,78.69 192.92,79.38 192.76,79.55 192.76,80.84 195.95,84.03 v1(195.95,84.79) 195.95,88.17 196.51,88.72 196.51,108.24 194.21,110.55 JKB.8
  IN1 w0.127: v2(192.94,78.68) 192.94,78.68 190.4,76.14 187.71,76.14 186.96,75.4 v2(186.96,74.74)
KSO15: length 48.2
  TOP w0.127: JKB.10 194.97,108.95 196.06,107.86 196.06,88.91 195.34,88.2 195.34,84.07 192.8,81.52 v2(192.56,81.52) ; UE1.54 183.15,78.08 183.9,77.32 183.9,76.79 v2(183.96,76.73)
  IN1 w0.127: v2(192.56,81.52) 192.21,81.52 191.83,81.9 191.5,81.9 191.28,81.68 191.28,78.68 189.88,77.28 185.39,77.28 184.84,76.73 v2(183.96,76.73)
KSO16: length 52.4
  TOP w0.127: v2(192.26,82.03) 192.26,82.03 192.38,81.91 192.87,81.91 195.12,84.16 195.12,88.3 195.83,89.01 195.83,107.01 v1(195.41,107.43) 195.41,107.65 194.9,108.15 JKB.11 ; UE1.81 178.91,71.56 182.26,74.9 183.23,74.9 184.49,76.16 184.49,77 v2(184.36,77.13)
  IN1 w0.127: v2(192.26,82.03) 192.16,82.13 191.4,82.13 191.05,81.78 191.05,80.61 189.39,78.95 189.39,78.07 188.87,77.56 184.85,77.56 184.42,77.13 v2(184.36,77.13)
LAN_CLKREQ#: length 240.4
  TOP w0.102: RL37.1 48.19,164.58 v2(47.74,165.03) UL1.12
  IN2 w0.102: v2(144.5,79.69) 144.45,79.64 144.45,76.63 148.9,72.18 148.9,68.93 147,67.03 v2(147,64.64) ; v2(91.27,101.88) 91.27,94.26 87.98,90.97 v2(87.98,89.66)
  BOTTOM w0.102: v2(87.98,89.66) 87.98,89.66 84.09,85.78 84.09,78.79 84.92,77.96 84.92,68.51 91.84,61.59 104.25,61.59 105.65,62.99 107.88,62.99 108.26,62.61 144.97,62.61 v2(147,64.64) ; v2(144.5,79.69) 144.43,79.69 v1(142.75,81.37) 142.27,81.85 142.27,82.38 141.84,82.82 140.72,82.82 139.25,84.29 137.2,84.29 136.09,85.4 135.08,85.4 UC1.BC15 ; v2(91.27,101.88) 93.23,103.84 93.23,116.92 102.17,125.86 102.17,132.45 96.83,137.79 95.43,137.79 82.7,150.53 80.98,150.53 70.4,161.11 67.74,161.11 66.13,162.71 61.93,162.71 61.08,161.86 48.32,161.86 47.74,162.44 v2(47.74,165.03)
LCD_TEST: length 150
  TOP w0.127: UE1.72 179.07,75.16 179.22,75.3 179.67,75.3 181.04,76.67 v2(181.04,77.19)
  IN1 w0.127: v2(181.04,77.19) 181.04,77.62 179.13,79.53 177.67,79.53 175.75,81.46 175.15,81.46 174.69,81.92 174.69,82.28 173.5,83.48 170.81,83.48 167.35,86.93 167.35,88.08 164.56,90.87 164.56,97.52 163.2,98.88 163.2,106.32 162.81,106.71 162.81,107.92 157.06,113.67 149.8,113.67 143.59,119.88 133.67,119.88 127.98,125.56 111.21,125.56 92.76,144.02 v2(92.76,144.39)
  BOTTOM w0.127: RX2.1 85.54,158.29 86.73,157.1 86.73,155.79 85.97,155.03 85.97,151.82 89.74,148.04 90.01,148.04 92.76,145.3 v2(92.76,144.39) ; v2(181.04,77.19) v1(181.04,76.61)
LCD_TST_C: length 7.5
  BOTTOM w0.127: v1(86.43,158.86) 86.43,158.92 85.54,159.8 RX2.2 85.3,160.11 JEDP.10
LDO_3V_1.35VGPU: length 16
  TOP w0.254: v2(202.39,161.04) 201.07,162.36 201.07,165.43 v2(200.6,165.9)
  BOTTOM w0.127: PC1413.1 200.54,169.74 201.07,170.27 201.07,171.78 v1(200.5,172.35)
  BOTTOM w0.254: PU1400.5 198.99,164.96 199.93,165.9 v2(200.6,165.9) 200.46,166.04 PC1413.1 ; PR1401.1 v2(202.39,161.04)
LDO_EN: length 5.1
  TOP w0.127: v1(37.1,63) 37.29,63.2 RZ5.2 RZ6.1 37.66,64.55 37.66,66.22 37.77,66.33 UZ1.21
LG1_APU: length 9.8
  IN1 w0.762: 122.42,145.8 122.42,146.43 118.8,150.05 ; 117.63,144.83 121.68,144.83
  vias: v2(116.77,145.03) v2(116.76,144.41) v2(118.23,151.1) v2(118.24,150.51) v2(122.55,145.03) v2(122.55,144.34)
LG1_GFX:
  vias: v1(60.33,41.03) v2(59.81,39.5) v2(59.81,38.86) v2(61.46,43.5) v2(61.46,42.86) v2(66.48,44.83) v2(66.48,44.2)
LG1_VGA: length 7.1
  IN2 w0.762: 177.54,98.49 177.54,93.98 176.14,92.58 175.57,92.58
  vias: v2(174.21,92.73) v2(174.82,92.72) v2(177.51,99.89) v2(177.54,99.25) v2(183.38,99.89) v2(183.38,99.25)
LG2_VGA: length 17.3
  IN2 w0.762: 189.54,97.03 189.54,95.12 188.65,94.23 180.59,94.23 177.79,91.44 175.63,91.44
  vias: v2(174.27,91.25) v2(174.87,91.24) v2(189.29,97.73) v2(189.73,103.57) v2(189.87,97.72) v2(190.32,103.56)
LG_1.35V: length 7.1
  IN1 w0.762: 68.89,17.53 65.08,17.53 63.05,19.56 62.6,19.56
  vias: v2(61.91,20.13) v2(61.91,19.49) v2(69.65,17.34) v2(70.28,17.34)
LG_3V: length 6.8
  IN1 w0.762: 40.63,47.4 37.14,43.91 37.14,42.04
  vias: v2(36.65,41.3) v2(37.27,41.27) v2(40.63,48.96) v2(40.63,48.32)
LG_5V: length 10
  IN1 w0.762: 41.01,38.86 41.01,40.13 41.97,41.08 41.97,45.02 43.36,46.42 43.36,47.88
  vias: v2(40.57,38.1) v2(41.2,38.1) v2(43.24,48.96) v2(43.69,48.54)
LG_NB: length 15.8
  IN1 w0.762: 123.44,154.62 123.75,154.62 124.87,153.5 124.87,152.69 128.77,148.79 128.77,142.37 129.6,141.54
  vias: v2(122.1,154.43) v2(122.71,154.43) v2(129.6,140.14) v2(129.62,140.78)
LG_VDDP_ALWP: length 9.2
  BOTTOM w0.762: 146.49,144.14 146.49,144.91 145.66,145.74 144.11,145.74 142.9,146.94 v1(140.46,146.94) 138.87,146.94
  vias: v2(137.47,146.94) v2(138.11,146.94)
LGATE_CHG: length 14.3
  IN2 w0.762: 121.44,167.58 127.5,167.58 128.45,168.53 135.31,168.53
  vias: v2(120.12,167.42) v2(120.72,167.43) v2(136.07,168.91) v2(136.07,168.27)
LID_SW#: length 210.1
  TOP w0.127: v4(199.5,171.91) 200.13,171.27 200.13,170.74 C33.1 199.15,169.54 JPWR.3 199.15,166.71 v2(200.58,165.28) ; v2(189.24,52.26) 187.98,51 173,51 172.55,51.46 170.95,51.46 170.85,51.56 168.05,51.56 165.25,48.75 RE75.2 165.2,42.92 D4.1 163.96,47.79 167.05,50.88 167.05,52 168.47,53.42 171.2,53.42 171.85,54.06 187.06,54.06 v2(187.94,54.94) ; v2(187.55,61.18) 187.94,61.57 187.94,62.01 187.13,62.83 186.58,62.83 186.35,63.06 UE1.115
  IN1 w0.127: v2(187.55,61.18) 187.57,61.15 187.57,55.31 v2(187.94,54.94) ; v2(200.58,165.28) 200.58,164.78 203.04,162.32 203.04,157.14 202.89,156.98 202.89,153.61 201.91,152.63 199.51,152.63 197.59,150.71 197.59,147.38 202.42,142.55 202.42,130.96 201.42,129.96 199.46,129.96 198.11,128.61 198.11,113.72 196.44,112.05 196.44,83.73 195.13,82.42 195.13,80.95 195.18,80.9 195.18,77.87 193.05,75.74 193.05,70.47 192.68,70.11 192.68,65.58 189.45,62.35 189.45,52.48 v2(189.24,52.26)
LINE1-L: length 3.7
  BOTTOM w0.203: CA67.1 187.37,17.21 186.7,16.54 185.24,16.54 185.02,16.32 UA1.22
LINE1-R: length 3
  BOTTOM w0.203: CA68.1 186.16,17.12 185.93,16.89 185.1,16.89 184.62,16.42 UA1.21
LINE1-VREFO-L: length 5.7
  IN2 w0.254: v2(187.79,12.67) 187.79,12.17 v2(188.93,11.02)
  BOTTOM w0.203: v2(187.79,12.67) 187.69,12.58 UA1.31
  BOTTOM w0.254: v2(188.93,11.02) v1(189.79,10.16) 190.23,9.73 RA165.1
LINE1-VREFO-R: length 2.6
  BOTTOM w0.203: UA1.30 187.35,12.98 187.53,13.16 188.6,13.16 RA166.1
LPC_AD0: length 73.8
  TOP w0.102: v2(188.94,73.14) 189.01,73.08 189.01,70.41 190.26,69.16 UE1.10
  BOTTOM w0.102: v2(188.94,73.14) 188.54,72.74 187.87,72.74 185.72,74.89 185.72,76.63 184.78,77.57 180.89,77.57 180.6,77.29 180.6,76.05 179.99,75.44 175.33,75.44 173.16,77.61 165.57,77.61 165.18,77.22 156.24,77.22 154.57,78.88 154.13,78.88 150.84,82.17 148.5,82.17 v1(146.77,83.89) 146.07,84.6 146.07,85.9 145.06,86.91 142.93,86.91 142.71,87.12 140.8,87.12 140.59,87.34 140.5,87.34 140.14,87.7 137.38,87.7 136.18,88.9 135.95,88.9 135.82,89.03 135.05,89.03 134.93,88.9 134.55,88.9 UC1.BB11
LPC_AD1: length 72.8
  TOP w0.102: UE1.8 192.1,68.36 191.78,68.03 190.91,68.03 188.58,70.37 v2(188.58,72.12)
  BOTTOM w0.102: UC1.BA11 133.84,88.62 134.15,88.3 134.38,88.3 134.49,88.4 134.84,88.4 134.94,88.3 135.18,88.3 135.58,88.7 136.1,88.7 137.43,87.37 140,87.37 140.36,87.01 140.45,87.01 140.65,86.8 140.67,86.8 140.67,86.79 142.57,86.79 142.79,86.58 144.93,86.58 145.74,85.76 145.74,84.46 v1(147.84,82.36) 148.36,81.84 150.7,81.84 153.99,78.55 154.43,78.55 156.1,76.89 165.32,76.89 165.71,77.28 173.02,77.28 175.19,75.11 180.13,75.11 181.82,76.81 182.96,76.81 183.74,76.03 184.16,76.03 184.75,75.44 184.75,74.64 184.98,74.41 185.73,74.41 187.73,72.41 188.29,72.41 v2(188.58,72.12)
LPC_AD2: length 77
  TOP w0.102: v2(188.25,73.14) 188.04,72.94 188.04,70.44 190.87,67.61 191.85,67.61 192.19,67.96 UE1.7
  BOTTOM w0.102: v2(188.25,73.14) 187.19,74.19 186.88,74.19 186.05,75.03 186.05,76.77 184.89,77.93 180.78,77.93 180.27,77.42 180.27,76.19 179.85,75.77 175.46,75.77 173.3,77.94 165.44,77.94 165.04,77.55 156.37,77.55 154.7,79.21 154.26,79.21 151.47,82.01 151.47,83.24 150.09,84.62 v1(148.41,84.62) 146.75,84.62 146.4,84.98 146.4,86.04 145.2,87.24 143.06,87.24 142.85,87.45 140.94,87.45 140.72,87.67 140.64,87.67 140.34,87.97 138.94,87.97 138.9,87.93 137.44,87.93 136.27,89.1 136.04,89.1 135.91,89.23 134.97,89.23 134.84,89.1 133.15,89.1 UC1.AY11
LPC_AD3: length 74.1
  TOP w0.102: v2(186.76,72.84) 187.71,71.89 187.71,70.28 190.71,67.28 192.18,67.28 192.31,67.16 UE1.5
  BOTTOM w0.102: v2(186.76,72.84) 185.75,73.85 183.8,73.85 182.24,72.29 178.78,72.29 176.91,74.16 176.59,74.16 176.58,74.17 175.66,74.17 172.88,76.95 165.85,76.95 165.45,76.56 155.96,76.56 155.09,77.43 153.08,77.43 152.44,78.07 152.44,79.63 150.57,81.51 v1(149.76,81.51) 148.22,81.51 145.41,84.32 145.41,85.63 144.79,86.25 142.65,86.25 142.44,86.46 140.81,86.46 140.74,86.39 140.62,86.39 140.53,86.47 140.52,86.47 140.31,86.68 139.38,86.68 138.94,87.11 137.4,87.11 136.01,88.49 135.67,88.49 135.27,88.1 134.85,88.1 134.75,88.2 134.58,88.2 134.47,88.1 134.07,88.1 133.97,88.2 133.82,88.2 133.56,87.95 133.56,87.12 UC1.BA13
LPC_CLK0_EC: length 68.6
  TOP w0.102: v2(146.37,86.91) 147.4,86.91 147.76,86.55 CE30.1 R926.1 R449.1 147.63,88.32 R904.2 ; UE1.12 194.04,69.96 v2(194.41,70.33) 194.96,70.33 RE16.1
  IN2 w0.102: v2(171.79,78.37) 171.79,76.89 179.39,69.28 179.39,67.91 180.27,67.03 183.57,67.03 183.94,66.66 188.41,66.66 190.72,68.97 192.02,68.97 193.37,70.33 v2(194.41,70.33)
  BOTTOM w0.102: v2(171.79,78.37) 171.69,78.27 165.3,78.27 164.9,77.88 156.51,77.88 154.27,80.11 154.27,80.9 v1(150.22,84.95) 146.89,84.95 146.73,85.11 146.73,86.18 146.37,86.53 v2(146.37,86.91)
LPC_CLK1: length 2.9
  BOTTOM w0.102: R450.1 142.13,84.12 R927.1 R925.2 v1(143.82,83.07)
LPC_FRAME#: length 102
  TOP w0.102: v2(146.96,86.49) 147.03,86.41 147.43,86.41 148.36,85.48 149.38,85.48 149.71,85.81 149.71,86.71 150.22,87.22 150.22,88.57 148.57,90.22 147.78,90.22 R902.2 R903.1 ; v2(194.43,66.93) 194.26,66.76 UE1.4
  IN2 w0.102: v2(194.43,66.93) 193.11,65.61 193.11,60.74 189.98,57.61 181.64,57.61 170.81,68.44 170.2,68.44 169.07,69.57 169.07,70.18 165.09,74.16 v2(165.09,78.59) ; v2(146.96,86.49) 146.94,86.5 146.18,86.5 145.8,86.88 145.8,87.58 144.18,89.2 143.12,89.2 142.21,88.29 140.45,88.29 139.04,86.88 136.11,86.88 135.83,87.16 131.38,87.16 v2(131.01,86.79)
  BOTTOM w0.102: v2(131.01,86.79) 130.99,86.77 130.99,86.3 UC1.AV14 ; v2(146.96,86.49) 147.06,86.39 147.06,85.43 147.21,85.28 150.36,85.28 v1(151.61,84.03) 154.6,81.04 154.6,80.25 156.65,78.21 164.71,78.21 v2(165.09,78.59)
LPC_RST_A#: length 6.5
  BOTTOM w0.102: R602.2 138.64,86.7 v1(138.22,86.7) 137.86,86.7 137.86,86.7 137.51,86.7 136.37,87.85 136.11,87.85 136,87.73 135.74,87.73 135.5,87.49 134.2,87.49 UC1.BB12
LX1_APU: length 11.9
  IN2 w0.762: 119.18,138.81 119.18,142.11 119.69,142.62 119.69,147.7 117.91,149.48 117.91,149.73
  vias: v1(117.39,135.34) v2(117.64,151.1) v2(117.65,150.48) v2(118.8,138.05) v2(118.8,137.41) v2(118.8,136.78) v2(118.8,136.14) v2(118.8,135.51) v2(118.8,134.87) v2(118.8,134.24) v2(119.56,138.05) v2(119.56,137.41) v2(119.56,136.78) v2(119.56,136.14) v2(119.56,135.51) v2(119.56,134.87) v2(119.56,134.24) v2(120.33,135.51) v2(120.33,134.87) v2(120.33,134.24)
LX1_GFX: length 8.6
  IN2 w0.762: 60.64,40.32 60.64,40.49 58.92,42.2 58.92,44.58 59.75,45.4 59.75,47.88
  vias: v1(60.05,54.6) v2(59.49,51.18) v2(59.49,50.55) v2(59.49,49.91) v2(59.49,49.28) v2(59.49,48.64) v2(59.62,51.94) v2(60.13,51.18) v2(60.13,50.55) v2(60.13,49.91) v2(60.13,49.28) v2(60.13,48.64) v2(60.25,52.58) v2(60.25,51.94) v2(60.51,39.5) v2(60.51,38.86) v2(60.89,52.58) v2(60.89,51.94) v2(61.52,53.21) v2(61.52,52.58) v2(61.52,51.94)
LX1_VGA: length 10.8
  IN2 w0.762: 177.54,103.63 177.54,102.04 175.57,100.08 175.57,93.6
  vias: v1(177.09,108.48) v2(174.18,93.3) v2(174.78,93.3) v2(177.54,104.97) v2(177.54,104.33)
LX2_VGA: length 15.5
  IN2 w0.762: 190.37,92.27 189.76,91.66 180.87,91.66 179.51,90.3 175.63,90.3
  vias: v1(197.17,89.14) v2(174.29,90.63) v2(174.91,90.63) v2(191.06,93.09) v2(191.06,92.46)
LX_1.8V_ALWP: length 3.7
  BOTTOM w0.127: PL601.1 158.41,46.61 v1(159.07,47.27)
LX_1.35V: length 8.1
  IN2 w0.762: 71.68,18.16 71.49,18.35 70.88,18.35 69.03,20.19 64.45,20.19
  vias: v2(63.05,20.32) v2(63.68,20.32) v2(72.41,18.12) v2(73.02,18.1)
LX_1.35VGPU: length 8.7
  IN2 w0.508: v2(198.94,166.31) 197.5,166.31 197.1,165.9 v2(197.1,162.05)
  BOTTOM w0.127: 193.03,158.94 v1(191.23,158.94)
  BOTTOM w0.508: PC1404.2 v2(198.94,166.31)
LX_3V: length 11.8
  IN2 w0.762: 38.66,50.61 38.54,50.48 38.54,49.4 32.44,43.31 32.44,41.4
  vias: v1(35.83,39.88) v2(32.06,40.64) v2(32.06,40) v2(32.06,39.37) v2(32.06,38.73) v2(32.06,38.1) v2(32.7,40.64) v2(32.7,40) v2(32.7,39.37) v2(32.7,38.73) v2(32.7,38.1) v2(38.92,51.31) v2(39.43,50.93)
LX_5V: length 10.1
  IN2 w0.762: 45.9,41.27 45.9,44.64 46.67,45.4 46.67,49.4 45.49,50.58
  vias: v1(44.95,38.27) v2(44.7,50.93) v2(44.89,40.51) v2(44.89,39.88) v2(44.89,39.24) v2(45.21,51.31) v2(45.52,40.51) v2(45.52,39.88) v2(45.52,39.24) v2(45.52,38.61) v2(45.52,37.97) v2(46.16,40.51) v2(46.16,39.88) v2(46.16,39.24) v2(46.16,38.61) v2(46.16,37.97)
LX_NB: length 12.6
  IN2 w0.762: 123.63,152.85 123.63,150.94 126.8,147.76 126.8,141.6
  vias: v2(122.13,153.7) v2(122.72,153.7) v2(126.82,140.87) v2(126.8,140.21)
LX_VDDP_ALWP: length 12.4
  IN2 w0.762: 139.44,135.64 139.44,147.19 138.87,147.76
  vias: v1(140.53,131.88) v2(137.72,134.87) v2(137.72,134.11) v2(137.72,133.35) v2(137.72,132.59) v2(137.72,131.83) v2(137.72,131.06) v2(138.49,148.46) v2(138.49,134.87) v2(138.49,134.11) v2(138.49,133.35) v2(138.49,132.59) v2(138.49,131.83) v2(138.49,131.06) v2(139.12,148.46) v2(139.25,134.87) v2(139.25,134.11) v2(140.01,134.87) v2(140.01,134.11)
M_BA0: length 75.4
  TOP w0.102: v2(183.95,164.96) 184.08,164.96 184.6,164.45 184.92,164.45 185.14,164.24 185.39,164.24 185.49,164.34 185.49,164.52 185.28,164.73 185.28,164.98 185.44,165.14 185.61,165.14 185.75,164.99 185.75,164.81 UV7.M2 ; v2(159.47,164.96) 159.6,164.96 160.11,164.45 160.44,164.45 160.65,164.24 160.9,164.24 161,164.34 161,164.52 160.79,164.73 160.79,164.98 160.95,165.14 161.12,165.14 161.26,164.99 161.26,164.81 UV6.M2 ; v2(167.69,139.56) 168.13,140 168.13,141.31 167.76,141.68 167.76,142.87 169.18,144.28 169.18,146.75
  TOP w0.234: v2(173.67,165.8) 173.67,165.14 v1(173.9,164.91) 174.22,164.91 174.45,164.68 174.45,164.21 174.22,163.97 173.9,163.97 173.67,163.74 173.67,163.2 174.48,162.39 174.48,152.43 169.18,147.13 169.18,146.75
  IN2 w0.102: 179.65,166.37 180.68,166.37 181.3,165.75 182.33,165.75 182.51,165.57 184.21,165.57 184.33,165.7 184.33,166.55 184.46,166.67 184.65,166.67 184.78,166.55 184.78,165.09 184.65,164.96 v2(183.95,164.96) ; v2(159.47,164.96) 160.42,164.96 161.25,165.79 162.25,165.79 162.48,166.01 162.57,166.01
  IN2 w0.127: 179.65,166.37 179.44,166.37 179.28,166.2 177.13,166.2 176.64,165.71 173.75,165.71 v2(173.67,165.8) 172.99,166.47 166.95,166.47 166.5,166.01 162.57,166.01
  BOTTOM w0.089: UV1.J16 167.2,139.27 167.4,139.27 v2(167.69,139.56)
  BOTTOM w0.102: v2(183.95,164.96) 183.57,165.34 182.06,165.34 181.96,165.25 181.66,165.25 181.19,164.77 UV8.M2 ; UV5.M2 156.91,165.25 157.47,165.25 157.57,165.34 159.08,165.34 v2(159.47,164.96)
M_BA1: length 83.9
  TOP w0.102: v2(183.95,166.95) 183.57,167.33 182.52,167.33 182.3,167.1 182.3,166.5 181.74,165.94 181.28,165.94 UV7.N8 ; UV6.N8 156.8,165.94 157.25,165.94 157.81,166.5 157.81,167.1 158.04,167.33 159.08,167.33 v2(159.47,166.95) ; v2(167.66,138.52) 167.66,139.03 167.28,139.42 167.28,140.65 166.87,141.05 166.87,144.61 167.09,144.82 168.57,144.82 168.97,145.22 168.97,145.75 168.54,146.19 168.54,146.75
  TOP w0.234: 168.54,146.75 168.54,147.39 173.84,152.7 v1(173.84,161.23) 173.84,162.13 173.03,162.94 173.03,165.97 172.67,166.33 172.67,169.04 173.04,169.42 v2(173.04,169.68)
  IN2 w0.102: v2(183.95,166.95) 184.74,166.95 184.87,167.07 184.87,167.83 184.74,167.96 184.52,167.96 184.4,167.83 184.4,167.68 184.27,167.55 181.65,167.55 180.84,168.36 180.66,168.36 180.02,169.01 ; 162.05,168.21 160.86,168.21 159.59,166.95 v2(159.47,166.95)
  IN2 w0.127: 180.02,169.01 179.8,169.23 173.94,169.23 173.48,169.68 v2(173.04,169.68) 165.51,169.68 165.14,169.32 164.46,169.32 163.75,168.61 162.44,168.61 162.05,168.21
  BOTTOM w0.089: UV1.L15 167.89,138.29 v2(167.66,138.52)
  BOTTOM w0.102: UV8.N8 185.72,165.25 185.42,164.95 185.24,164.95 185.1,165.1 185.1,165.28 185.26,165.44 185.26,165.72 184.98,166 184.78,166 184.24,166.54 183.8,166.54 183.68,166.66 183.68,166.83 183.8,166.95 v2(183.95,166.95) ; v2(159.47,166.95) 159.31,166.95 159.19,166.83 159.19,166.66 159.31,166.54 159.75,166.54 160.29,166 160.5,166 160.78,165.72 160.78,165.44 160.61,165.28 160.61,165.1 160.76,164.95 160.94,164.95 161.23,165.25 UV5.N8
M_BA2: length 67.8
  TOP w0.102: v2(158.2,164.96) 158.58,165.34 159.62,165.34 160.2,164.77 UV6.M3 ; UV7.M3 184.68,164.77 184.11,165.34 183.06,165.34 v2(182.68,164.96)
  IN1 w0.102: 170.44,146.75 170.44,145.31 170.77,144.98 170.77,142.71 171.14,142.34 v2(171.14,141.1)
  IN1 w0.26: v2(171.84,165.57) 172.4,165.57 174.02,163.96 174.02,162.52 174.15,162.39 174.15,152.7 170.44,148.99 170.44,146.75
  IN2 w0.102: 162.54,164.8 161.31,164.8 160.89,164.38 158.78,164.38 v2(158.2,164.96)
  IN2 w0.127: v2(182.68,164.96) 182.52,164.96 182.15,165.33 181.99,165.33 181.9,165.25 181.9,164.79 181.79,164.68 181.57,164.68 181.43,164.82 181.43,165.21 181.32,165.33 181.07,165.33 180.93,165.19 180.93,164.82 180.79,164.68 179.72,164.68 179.56,164.85 175.91,164.85 175.78,164.72 175.78,164.58 175.66,164.45 175.4,164.45 175.27,164.58 175.27,164.72 175.15,164.85 174.89,164.85 174.77,164.72 174.77,164.58 174.64,164.45 174.39,164.45 174.26,164.58 174.26,164.72 174.13,164.85 173.8,164.85 173.67,164.72 173.67,164.58 173.55,164.45 173.29,164.45 173.17,164.58 173.17,165.04 172.63,165.57 v2(171.84,165.57) 171.27,165.57 170.63,164.93 166.43,164.93 166.34,165.02 163.95,165.02 163.62,164.69 163,164.69 162.9,164.8 162.54,164.8
  BOTTOM w0.089: v2(171.14,141.1) 170.8,140.76 UV1.G11
  BOTTOM w0.102: v2(158.2,164.96) 158.34,164.96 158.48,164.82 158.48,164.66 158.38,164.56 157.77,164.56 157.68,164.65 157.68,164.74 157.79,164.86 157.79,164.97 157.73,165.04 157.26,165.04 157.17,164.95 157.17,164.84 UV5.M3 ; UV8.M3 181.66,164.84 181.66,164.95 181.74,165.04 182.21,165.04 182.28,164.97 182.28,164.86 182.16,164.74 182.16,164.65 182.26,164.56 182.86,164.56 182.96,164.66 182.96,164.82 182.82,164.96 v2(182.68,164.96)
M_CAS#0: length 47.5
  TOP w0.102: UV6.K3 160.2,163.17 159.62,162.6 159.21,162.6 v2(158.83,162.98)
  IN1 w0.102: 164.52,145.03 164.52,143.96 163.94,143.37 163.94,142.76 164.41,142.29 164.41,141.39 v2(164.09,141.08)
  IN1 w0.26: 164.52,145.03 164.98,145.5 164.98,147.77 165.92,148.7 165.92,150.88 166.58,151.53 166.58,151.9 166.18,152.3 166.18,152.66 166.55,153.03 166.92,153.03 167.31,152.64 167.68,152.64 168.15,153.11 168.15,153.47 167.75,153.87 167.75,154.23 168.4,154.89 168.4,158.17 168.01,158.57 168.01,159.12 168.4,159.52 168.4,162 v2(168.26,162.15)
  IN2 w0.102: v2(158.83,162.98) 158.68,162.98 158.56,162.86 158.56,162.72 158.68,162.6 160.92,162.6 161.47,163.15 161.81,163.15 162.05,162.91 162.05,162.57 162.25,162.37
  IN2 w0.127: v2(168.26,162.15) 168.04,162.37 167.82,162.37 167.7,162.24 167.7,161.57 167.57,161.44 167.32,161.44 167.19,161.57 167.19,162.24 167.06,162.37 166.81,162.37 166.68,162.24 166.68,161.57 166.55,161.44 166.3,161.44 166.17,161.57 166.17,162.24 166.05,162.37 165.79,162.37 165.67,162.24 165.67,161.57 165.54,161.44 165.3,161.44 165.17,161.57 165.17,162.24 165.04,162.37 164.51,162.37 164.38,162.24 164.38,161.57 164.26,161.44 164.04,161.44 163.92,161.57 163.92,162.24 163.79,162.37 162.25,162.37
  BOTTOM w0.089: UV1.G19 164.41,140.76 v2(164.09,141.08)
  BOTTOM w0.102: v2(158.83,162.98) 158.75,162.98 158.37,162.6 157.8,162.6 UV5.K3
M_CAS#1: length 48.5
  TOP w0.102: UV7.K3 184.68,163.17 184.11,162.6 183.7,162.6 v2(183.32,162.98)
  IN1 w0.26: v2(167.69,141.05) 167.62,141.05 166.81,141.87 166.81,147.19 167.61,148 167.61,150.16 170.46,153 170.46,153.58 170.12,153.91 170.12,154.43 170.46,154.77 170.46,155.48 170.12,155.81 170.12,156.52 170.46,156.85 170.46,157.56 170.12,157.89 170.12,158.6 170.46,158.93 170.46,161.29 v2(170.01,161.73)
  IN2 w0.102: v2(183.32,162.98) 183.32,163.05 183.01,163.36 181.87,163.36 181.67,163.56 180.48,163.56 179.93,163.01 179.93,162.66 179.84,162.57
  IN2 w0.127: 179.84,162.57 179.79,162.52 178.84,162.52 178.55,162.23 173.75,162.23 173.32,162.67 170.41,162.67 170.29,162.79 170.29,162.98 170.16,163.11 169.82,163.11 169.69,162.98 169.69,162.34 169.57,162.22 169.31,162.22 169.18,162.34 169.18,162.98 169.06,163.11 168.83,163.11 168.7,162.98 168.7,161.86 168.83,161.73 v2(170.01,161.73)
  BOTTOM w0.089: v2(167.69,141.05) 167.4,141.05 167.11,140.76 UV1.G16
  BOTTOM w0.102: v2(183.32,162.98) 183.23,162.98 182.85,162.6 182.29,162.6 UV8.K3
M_CKE0: length 52.3
  TOP w0.102: UV6.K9 155.95,163.5 157.69,163.5 157.81,163.38 159.07,163.38 v2(159.47,162.98)
  IN1 w0.102: 164.09,145.3 164.09,143.97 163.62,143.5 163.62,141.69 163.34,141.42 163.34,139.57 v2(162.93,139.17)
  IN1 w0.26: v2(168.26,162.8) 168.68,162.8 168.97,163.09 168.97,163.89 168.12,164.74 167.68,164.74 167.42,164.48 167.42,162.19 167.84,161.77 167.84,159.76 167.44,159.36 167.44,158.33 167.84,157.93 167.84,155.12 165.35,152.64 165.35,148.94 164.42,148 164.42,145.63 164.09,145.3
  IN2 w0.102: 162.6,162.8 162.45,162.8 161.89,163.36 160.95,163.36 160.85,163.26 160.85,162.9 160.75,162.8 160.55,162.8 160.45,162.9 160.45,163.25 160.34,163.35 160.14,163.35 160.04,163.25 160.04,162.9 159.94,162.8 159.65,162.8 v2(159.47,162.98)
  IN2 w0.127: v2(168.26,162.8) 166.77,162.8 166.64,162.93 166.64,163.11 166.51,163.24 166.26,163.24 166.13,163.11 166.13,162.93 166.01,162.8 165.8,162.8 165.68,162.93 165.68,163.04 165.55,163.17 165.29,163.17 165.17,163.04 165.17,162.93 165.04,162.8 162.6,162.8
  BOTTOM w0.089: v2(162.93,139.17) 163.49,138.61 UV1.K20
  BOTTOM w0.102: v2(159.47,162.98) 159.34,162.98 159.17,163.15 159.17,163.36 159.3,163.48 159.62,163.48 159.85,163.24 160.04,163.24 160.17,163.37 160.17,163.55 160.26,163.65 160.44,163.65 160.6,163.49 160.92,163.49 161.08,163.65 161.27,163.65 161.75,163.17 UV5.K9
M_CKE1: length 53.7
  TOP w0.102: UV7.K9 180.44,163.5 182.18,163.5 182.3,163.38 183.56,163.38 v2(183.95,162.98) ; 166.17,146.75 v4(166.17,146.24) 166.17,139.76 165.97,139.56 v2(165.29,139.56)
  TOP w0.234: 166.17,146.75 166.17,147.75 171.92,153.49 171.92,162.23 171.27,162.88 v2(171.27,163.56)
  IN2 w0.102: v2(183.95,162.98) 184.73,162.98 184.85,163.11 184.85,163.44 184.73,163.57 181.95,163.57 181.76,163.76 180.38,163.76 179.74,163.12
  IN2 w0.127: 179.74,163.12 176.98,163.12 176.52,162.66 173.93,162.66 173.5,163.1 170.78,163.1 170.66,163.23 170.66,163.43 170.78,163.56 v2(171.27,163.56)
  BOTTOM w0.089: v2(165.29,139.56) 165.48,139.56 165.83,139.21 165.84,139.21 UV1.J17
  BOTTOM w0.102: v2(183.95,162.98) 183.83,162.98 183.66,163.15 183.66,163.36 183.78,163.48 184.1,163.48 184.34,163.24 184.53,163.24 184.65,163.37 184.65,163.55 184.75,163.65 184.92,163.65 185.08,163.49 185.4,163.49 185.56,163.65 185.76,163.65 186.24,163.17 UV8.K9
M_CLK0: length 59.6
  TOP w0.102: v2(158.83,161.95) 158.65,161.77 158.65,161.57 158.44,161.36 157.89,161.36 157.56,161.69 157.56,162.46 157.5,162.53 157.38,162.53 UV6.J7
  IN1 w0.102: 160.91,145.56 160.91,145.53 160.92,145.52 160.92,144.45 158.93,142.46 157.25,142.46 156.92,142.13 156.92,140.87 157.28,140.51 159.17,140.51 159.66,140.02 159.66,139.51 159.51,139.36 159.3,139.36 159.22,139.44 v2(159.22,139.55) ; 159.93,162.38 159.91,162.38 159.9,162.39 158.64,162.39 158.56,162.31 158.56,162.07 158.68,161.95 v2(158.83,161.95)
  IN1 w0.127: 159.93,162.38 160.39,162.38 160.79,162.78 160.79,163.44 160.99,163.64 161.92,163.64 162.05,163.51 162.05,162.14 162.31,161.87 162.89,161.87 163.15,162.14 163.15,163.45 163.28,163.58 163.71,163.58 163.84,163.45 163.84,162.07 163.93,161.99 163.93,161.34 164.19,161.07 164.64,161.07 164.77,160.95 164.77,160.56 164.64,160.44 164.19,160.44 163.93,160.17 163.93,159.13 164.19,158.87 164.63,158.87 164.76,158.74 164.76,158.36 164.63,158.23 163.82,158.23 163.55,157.97 163.55,156.98 163.82,156.72 164.89,156.72 165.01,156.59 165.01,156.21 164.89,156.08 164.19,156.08 163.93,155.82 163.93,154.98 162.71,153.77 162.71,150.02 161.79,149.09 161.79,146.74 160.91,145.87 160.91,145.56
  IN2 w0.102: 155.02,162.55 155.05,162.55 155.06,162.57 155.28,162.57 155.87,163.16 157,163.16 157.28,162.87 157.28,161.93 157.91,161.3 158.39,161.3 158.63,161.54 158.63,161.75 v2(158.83,161.95)
  IN2 w0.127: 155.02,162.55 154.31,162.55 v2(154.14,162.38)
  BOTTOM w0.089: v2(159.22,139.55) 159.22,139.62 158.89,139.96 UV1.H26
  BOTTOM w0.102: UV5.J7 160.55,162.49 160.55,162.68 160.48,162.74 160.1,162.74 159.76,162.39 158.79,162.39 158.63,162.23 158.63,162.02 158.69,161.95 v2(158.83,161.95)
  BOTTOM w0.127: v2(154.14,162.38) 153.96,162.56 153.78,162.56 RV48.1
M_CLK1: length 59.6
  TOP w0.102: UV7.J7 181.83,162.48 181.99,162.48 182.07,162.4 182.07,161.71 182.42,161.37 182.84,161.37 183.08,161.61 183.08,161.79 183.25,161.95 v2(183.32,161.95)
  IN1 w0.102: v2(172.8,141.15) 172.88,141.07 172.88,140.87 172.75,140.74 172.55,140.74 172.37,140.92 172.37,141.51 172.46,141.6 172.46,142.41 172.31,142.56 172.31,143.62 172.46,143.78 172.46,145.52 172.47,145.53 172.47,145.56 ; v2(183.32,161.95) 183.1,161.74 183.1,161.48 182.9,161.28 182.44,161.28 182.05,161.67 182.05,163.03 181.19,163.89 179.55,163.89 179.53,163.88 179.51,163.88
  IN1 w0.127: 179.51,163.88 177.51,163.88 176.42,162.79 176.42,161.88 176.16,161.61 175.78,161.61 175.65,161.48 175.65,161.1 175.78,160.98 176.71,160.98 176.97,160.71 176.97,160.14 176.71,159.87 175.78,159.87 175.65,159.75 175.65,159.37 175.78,159.24 176.69,159.24 176.96,158.98 176.96,158.4 176.69,158.14 175.78,158.14 175.65,158.01 175.65,157.63 175.78,157.5 176.68,157.5 176.94,157.24 176.94,156.66 176.68,156.4 175.78,156.4 175.65,156.27 175.65,155.89 175.78,155.76 176.69,155.76 176.95,155.5 176.95,154.93 176.69,154.66 175.78,154.66 175.65,154.54 175.65,154.07 175.78,153.94 176.41,153.94 176.68,153.68 176.68,153.1 176.41,152.84 175.78,152.84 175.65,152.71 175.65,152.08 172.92,149.35 172.92,148.7 172.6,148.38 172.07,148.38 171.94,148.26 171.94,147.88 172.07,147.75 172.21,147.75 172.47,147.49 172.47,146.91 172.21,146.65 172.06,146.65 171.93,146.52 171.93,146.14 172.06,146.01 172.21,146.01 172.47,145.75 172.47,145.56
  IN2 w0.102: 187.18,162.27 187.15,162.27 187.14,162.26 186.66,162.26 186.36,162.56 185.07,162.56 184.53,162.02 184.53,161.73 184.24,161.44 183.2,161.44 183.12,161.53 183.12,161.76 v2(183.32,161.95)
  IN2 w0.127: 187.18,162.27 187.83,162.27 v2(188.01,162.46)
  BOTTOM w0.089: v2(172.8,141.15) 172.8,141.07 UV1.G9
  BOTTOM w0.102: v2(183.32,161.95) 183.18,161.95 183.06,162.07 183.06,162.24 183.21,162.39 184.28,162.39 184.6,162.7 184.88,162.7 184.97,162.61 184.97,162.42 UV8.J7
  BOTTOM w0.127: RV54.1 188.36,162.27 188.2,162.27 v2(188.01,162.46)
M_CLK#0: length 59.3
  TOP w0.102: v2(158.2,161.95) 158.25,161.95 158.44,161.76 158.44,161.65 158.36,161.57 157.97,161.57 157.76,161.77 157.76,162.55 157.58,162.73 157.43,162.73 157.23,162.93 UV6.K7
  IN1 w0.102: 159.93,162.61 159.91,162.61 159.9,162.6 158.56,162.6 158.35,162.39 158.35,162.11 v2(158.2,161.95) ; 161.14,145.56 161.14,145.53 161.13,145.52 161.13,144.36 159.02,142.25 157.33,142.25 157.13,142.04 157.13,140.95 157.36,140.72 159.25,140.72 159.87,140.1 159.87,139.72 v2(160.05,139.53)
  IN1 w0.127: 159.93,162.61 160.3,162.61 160.56,162.88 160.56,163.54 160.89,163.87 162.02,163.87 162.28,163.61 162.28,162.23 162.41,162.11 162.79,162.11 162.92,162.23 162.92,163.55 163.18,163.81 163.81,163.81 164.07,163.55 164.07,162.17 164.16,162.08 164.16,161.43 164.29,161.31 164.74,161.31 165,161.04 165,160.47 164.74,160.2 164.29,160.2 164.16,160.08 164.16,159.23 164.29,159.1 164.73,159.1 164.99,158.84 164.99,158.26 164.73,158 163.91,158 163.79,157.87 163.79,157.08 163.91,156.95 164.98,156.95 165.25,156.69 165.25,156.11 164.98,155.85 164.29,155.85 164.16,155.72 164.16,154.88 162.95,153.67 162.95,149.92 162.02,148.99 162.02,146.65 161.14,145.77 161.14,145.56
  IN2 w0.102: v2(158.2,161.95) 158.42,161.73 158.42,161.62 158.31,161.51 158,161.51 157.49,162.02 157.49,162.96 157.09,163.36 155.78,163.36 155.2,162.78 155.06,162.78 155.05,162.79 155.02,162.79
  IN2 w0.127: v2(154.14,162.96) 154.31,162.79 155.02,162.79
  BOTTOM w0.089: v2(160.05,139.53) 159.69,139.89 UV1.H25
  BOTTOM w0.102: UV5.K7 160.43,163.03 160.34,162.94 160.02,162.94 159.68,162.6 158.71,162.6 158.43,162.31 158.43,162.08 158.3,161.95 v2(158.2,161.95)
  BOTTOM w0.127: v2(154.14,162.96) 153.96,162.79 153.78,162.79 RV49.1
M_CLK#1: length 59.9
  TOP w0.102: UV7.K7 181.72,162.81 181.85,162.68 182.07,162.68 182.28,162.48 182.28,161.8 182.51,161.57 182.75,161.57 182.87,161.69 182.87,161.81 182.73,161.95 v2(182.68,161.95)
  IN1 w0.102: 172.24,145.56 172.24,145.53 172.25,145.52 172.25,143.87 172.1,143.71 172.1,142.47 172.25,142.32 172.25,141.69 172.16,141.6 172.16,140.84 172.47,140.53 172.59,140.53 v2(172.78,140.35) ; 179.51,164.11 179.53,164.11 179.55,164.1 181.27,164.1 182.26,163.12 182.26,161.75 182.53,161.49 182.81,161.49 182.89,161.57 182.89,161.74 v2(182.68,161.95)
  IN1 w0.127: 172.24,145.56 172.24,145.65 172.11,145.78 171.96,145.78 171.7,146.04 171.7,146.62 171.96,146.88 172.11,146.88 172.24,147.01 172.24,147.39 172.11,147.52 171.97,147.52 171.71,147.78 171.71,148.35 171.97,148.62 172.51,148.62 172.69,148.8 172.69,149.44 175.42,152.18 175.42,152.81 175.68,153.07 176.32,153.07 176.44,153.2 176.44,153.58 176.32,153.71 175.68,153.71 175.42,153.97 175.42,154.63 175.68,154.9 176.59,154.9 176.72,155.02 176.72,155.4 176.59,155.53 175.68,155.53 175.42,155.79 175.42,156.37 175.68,156.63 176.58,156.63 176.71,156.76 176.71,157.14 176.58,157.27 175.68,157.27 175.42,157.53 175.42,158.11 175.68,158.37 176.59,158.37 176.72,158.5 176.72,158.88 176.59,159.01 175.68,159.01 175.42,159.27 175.42,159.84 175.68,160.11 176.61,160.11 176.74,160.24 176.74,160.62 176.61,160.74 175.68,160.74 175.42,161.01 175.42,161.58 175.68,161.85 176.06,161.85 176.19,161.97 176.19,162.89 177.42,164.11 179.51,164.11
  IN2 w0.102: 187.18,162.04 187.15,162.04 187.14,162.05 186.57,162.05 186.27,162.35 185.16,162.35 184.74,161.93 184.74,161.65 184.33,161.23 183.12,161.23 182.91,161.44 182.91,161.73 v2(182.68,161.95)
  IN2 w0.127: 187.18,162.04 187.84,162.04 v2(188.01,161.87)
  BOTTOM w0.089: UV1.H9 172.53,139.96 172.78,140.21 v2(172.78,140.35)
  BOTTOM w0.102: UV8.K7 184.65,162.9 184.51,162.9 184.2,162.59 183.12,162.59 182.86,162.32 182.86,162.13 v2(182.68,161.95)
  BOTTOM w0.127: RV55.1 188.4,162.03 188.17,162.03 v2(188.01,161.87)
M_CS#0: length 51.8
  TOP w0.102: v2(161.69,140.36) 162.3,140.97 162.3,143.73 161.69,144.34 161.69,144.94 162.33,145.58 162.33,146.75 ; v2(158.83,163.97) 159.21,164.35 159.62,164.35 159.96,164.02 159.96,163.98 160.3,163.65 160.58,163.65 160.91,163.97 UV6.L2
  TOP w0.234: 162.33,146.75 162.33,149.34 168.08,155.08 v1(168.08,159.58) 168.08,161.18 167.44,161.82 167.44,164.19 167.93,164.68 168.27,164.68 168.44,164.51 168.44,163.99 v2(168,163.55)
  IN2 w0.102: 162.5,163.66 162.16,163.66 162.06,163.76 159.8,163.76 159.62,163.59 159.11,163.59 158.83,163.87 v2(158.83,163.97)
  IN2 w0.127: v2(168,163.55) 169.84,163.55 169.97,163.68 169.97,163.93 169.84,164.06 167.63,164.06 167.5,163.93 167.5,163.36 167.37,163.23 167.12,163.23 166.99,163.36 166.99,163.93 166.86,164.06 166.08,164.06 165.69,163.66 162.5,163.66
  BOTTOM w0.102: v2(161.69,140.36) 162.09,139.96 UV1.H22 ; v2(158.83,163.97) 158.45,164.35 157.69,164.35 157.65,164.39 156.5,164.39 156.36,164.26 156.36,164.04 UV5.L2
M_CS#1: length 48.4
  TOP w0.102: v2(183.32,163.97) 183.7,164.35 184.11,164.35 184.45,164.02 184.45,163.98 184.78,163.65 185.07,163.65 185.39,163.97 UV7.L2
  IN1 w0.102: v2(170.04,141.05) 170.08,141.09 170.08,142.14 169.82,142.41 169.82,142.72 170.08,142.99 170.08,143.33 169.37,144.05 169.37,145.87 169.31,145.94 169.31,146.75
  IN1 w0.26: 169.31,146.75 169.31,149.46 172.3,152.45 172.3,153.34 172.56,153.6 172.73,153.6 172.99,153.86 172.99,154.38 172.73,154.64 172.56,154.64 172.3,154.9 172.3,155.42 172.56,155.68 172.73,155.68 172.99,155.94 172.99,156.46 172.73,156.72 172.56,156.72 172.3,156.98 172.3,158.38 172.68,158.75 172.68,159.15 172.3,159.52 172.3,160.79 173.02,161.51 173.02,161.93 172.75,162.2 172.52,162.2 172.3,162.41 172.3,162.66 172.85,163.21 172.85,163.5 171.98,164.38 v2(171.85,164.38)
  IN2 w0.102: 180.06,164.22 182.31,164.22 182.47,164.38 183.23,164.38 183.32,164.29 v2(183.32,163.97)
  IN2 w0.127: 180.06,164.22 179.82,163.98 176.62,163.98 176.22,163.58 172.95,163.58 172.63,163.89 172.4,163.89 172.09,163.58 171.86,163.58 171.73,163.7 171.73,164.26 v2(171.85,164.38)
  BOTTOM w0.102: UV8.L2 180.85,164.04 180.85,164.26 180.99,164.39 182.14,164.39 182.18,164.35 182.94,164.35 v2(183.32,163.97) ; UV1.G13 169.77,140.76 170.06,141.05 v2(170.04,141.05)
M_DA0: length 42.2
  BOTTOM w0.089: 154.33,139.4 154.51,139.4 155.06,138.85 156.24,138.85 156.47,139.08 156.47,139.24 156.75,139.52 156.93,139.52 158.09,138.36 UV1.K27
  BOTTOM w0.152: 154.33,139.4 v1(152.39,139.4) 149.33,139.4 149.18,139.56 149.18,146.78 150.7,148.31 150.7,149.31 151.01,149.61 151.01,152.59 150.86,152.74 150.39,152.74 150.27,152.87 150.27,153.22 150.39,153.35 150.86,153.35 151.01,153.5 151.01,153.9 150.88,154.03 149.52,154.03 149.39,154.15 149.39,157.04 149.52,157.16 149.87,157.16 150,157.04 150,154.91 150.15,154.76 150.46,154.76 150.61,154.91 150.61,155.5 150.73,155.63 151.09,155.63 151.22,155.5 151.22,154.91 151.37,154.76 155.1,154.76 156.31,155.97 UV5.A2
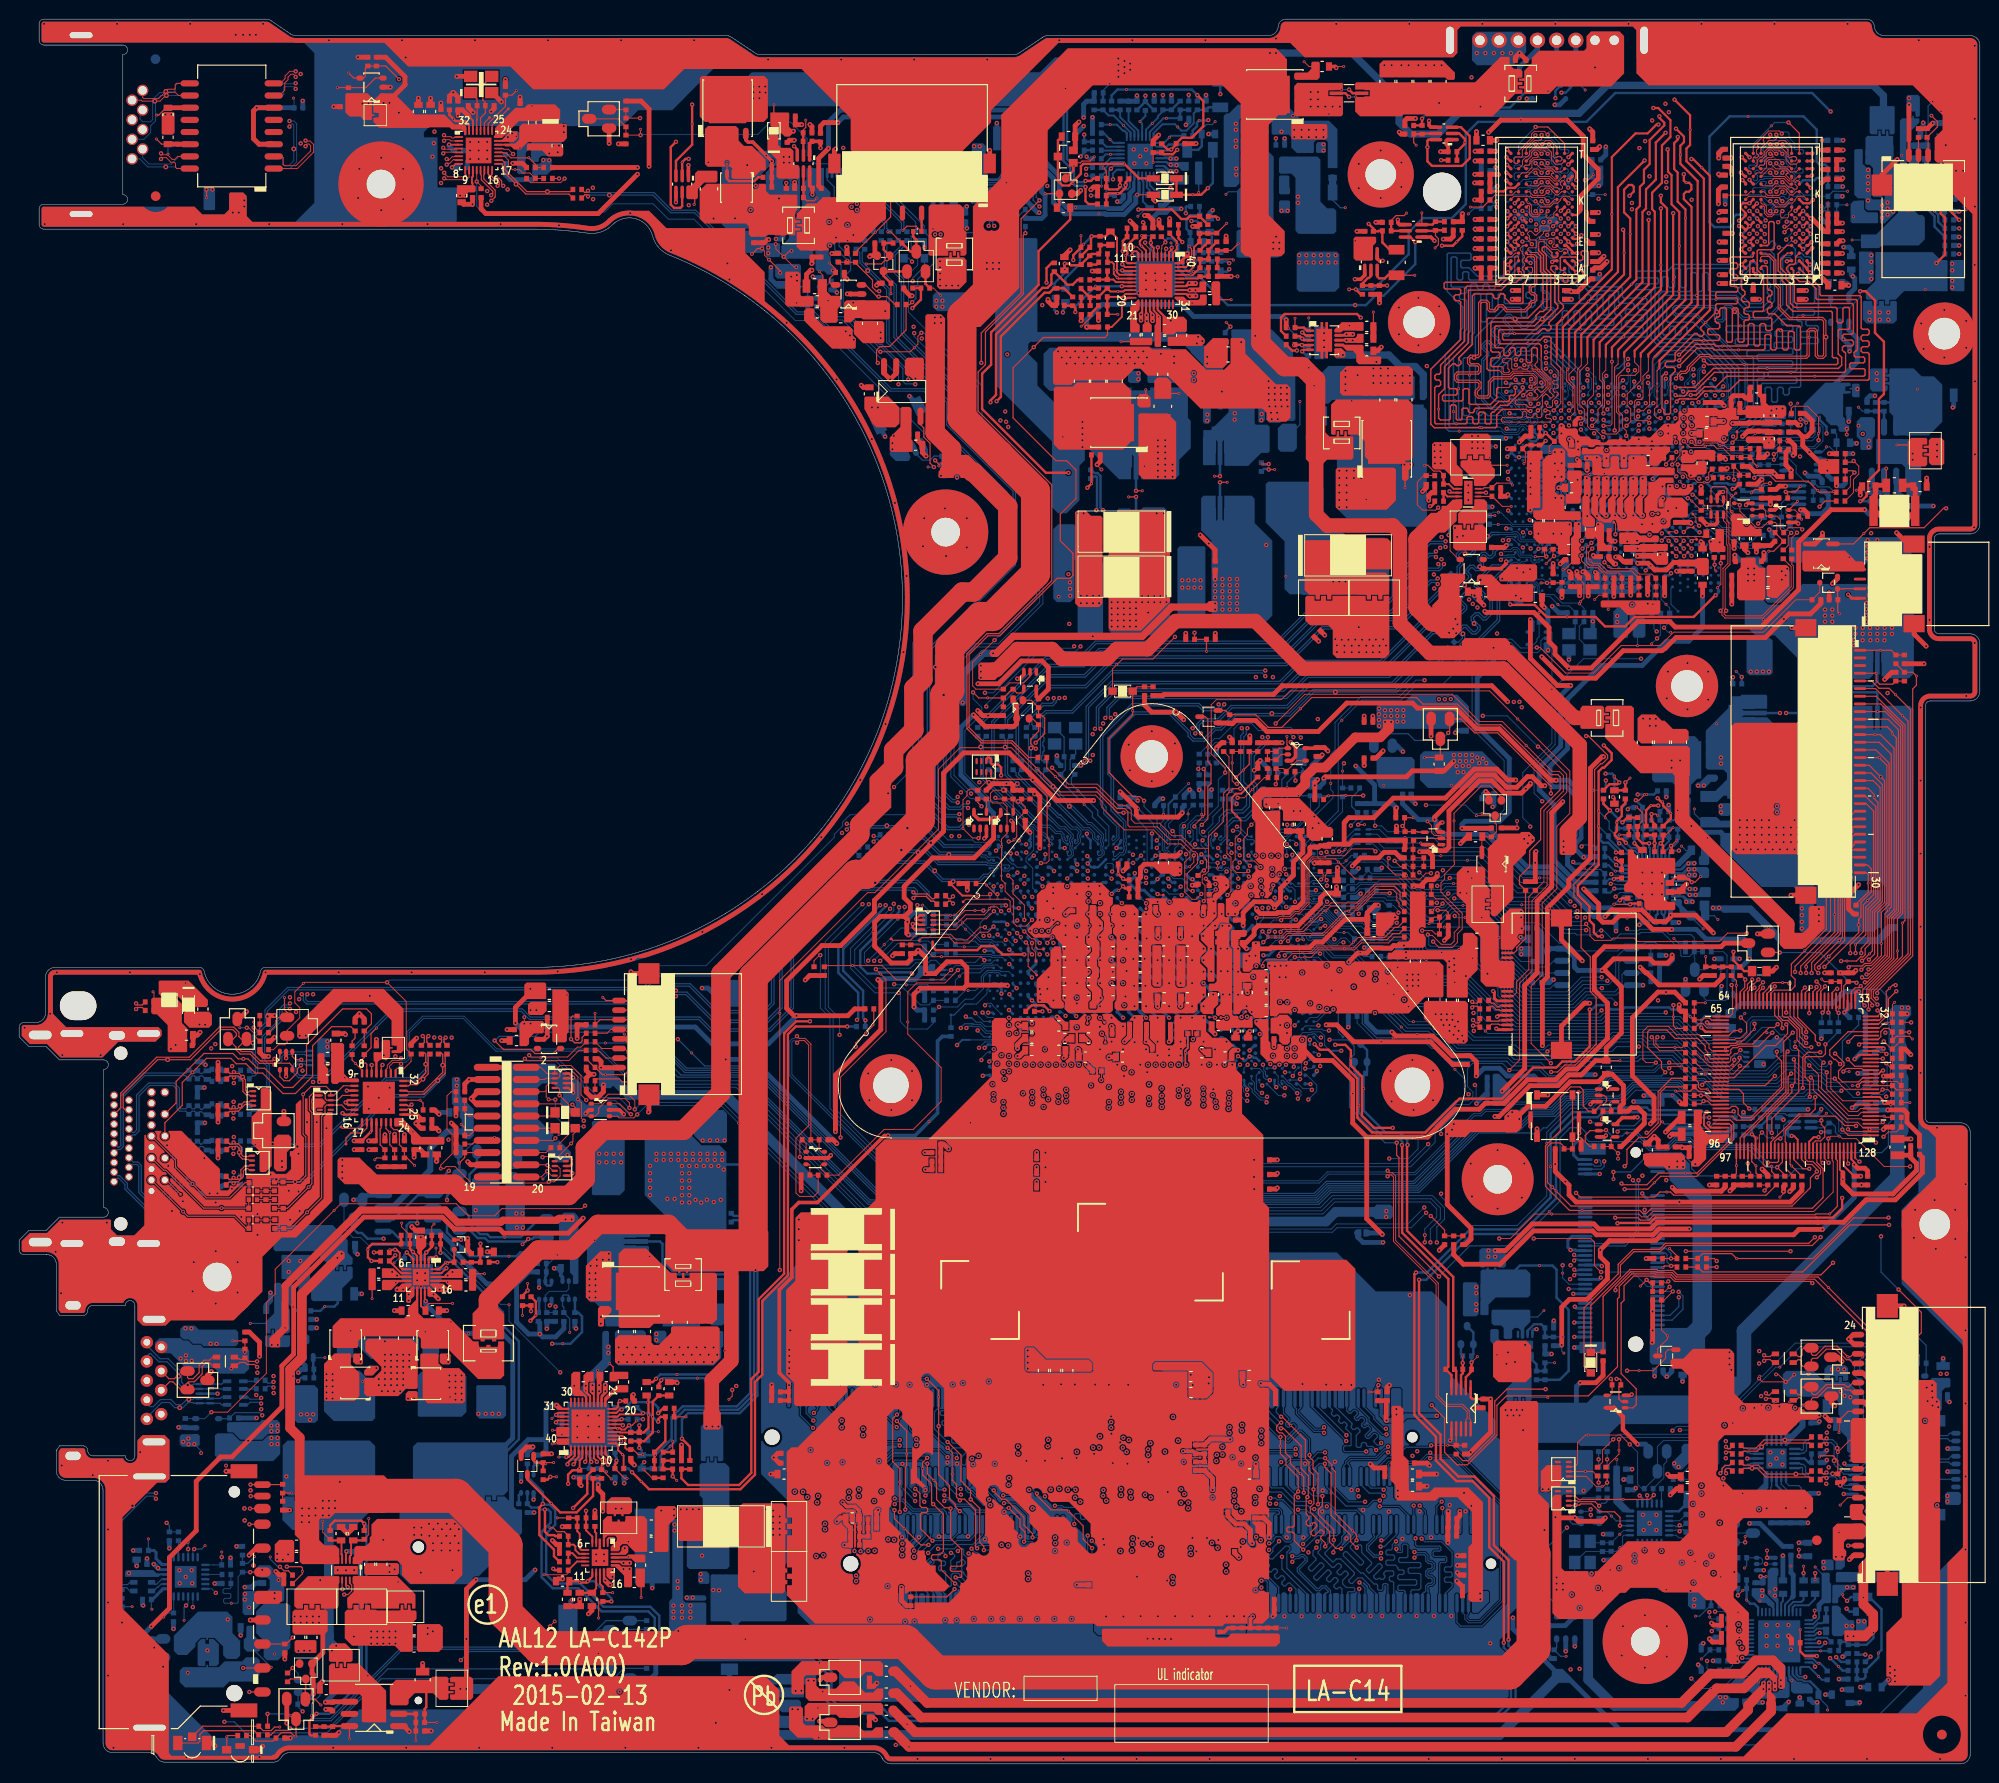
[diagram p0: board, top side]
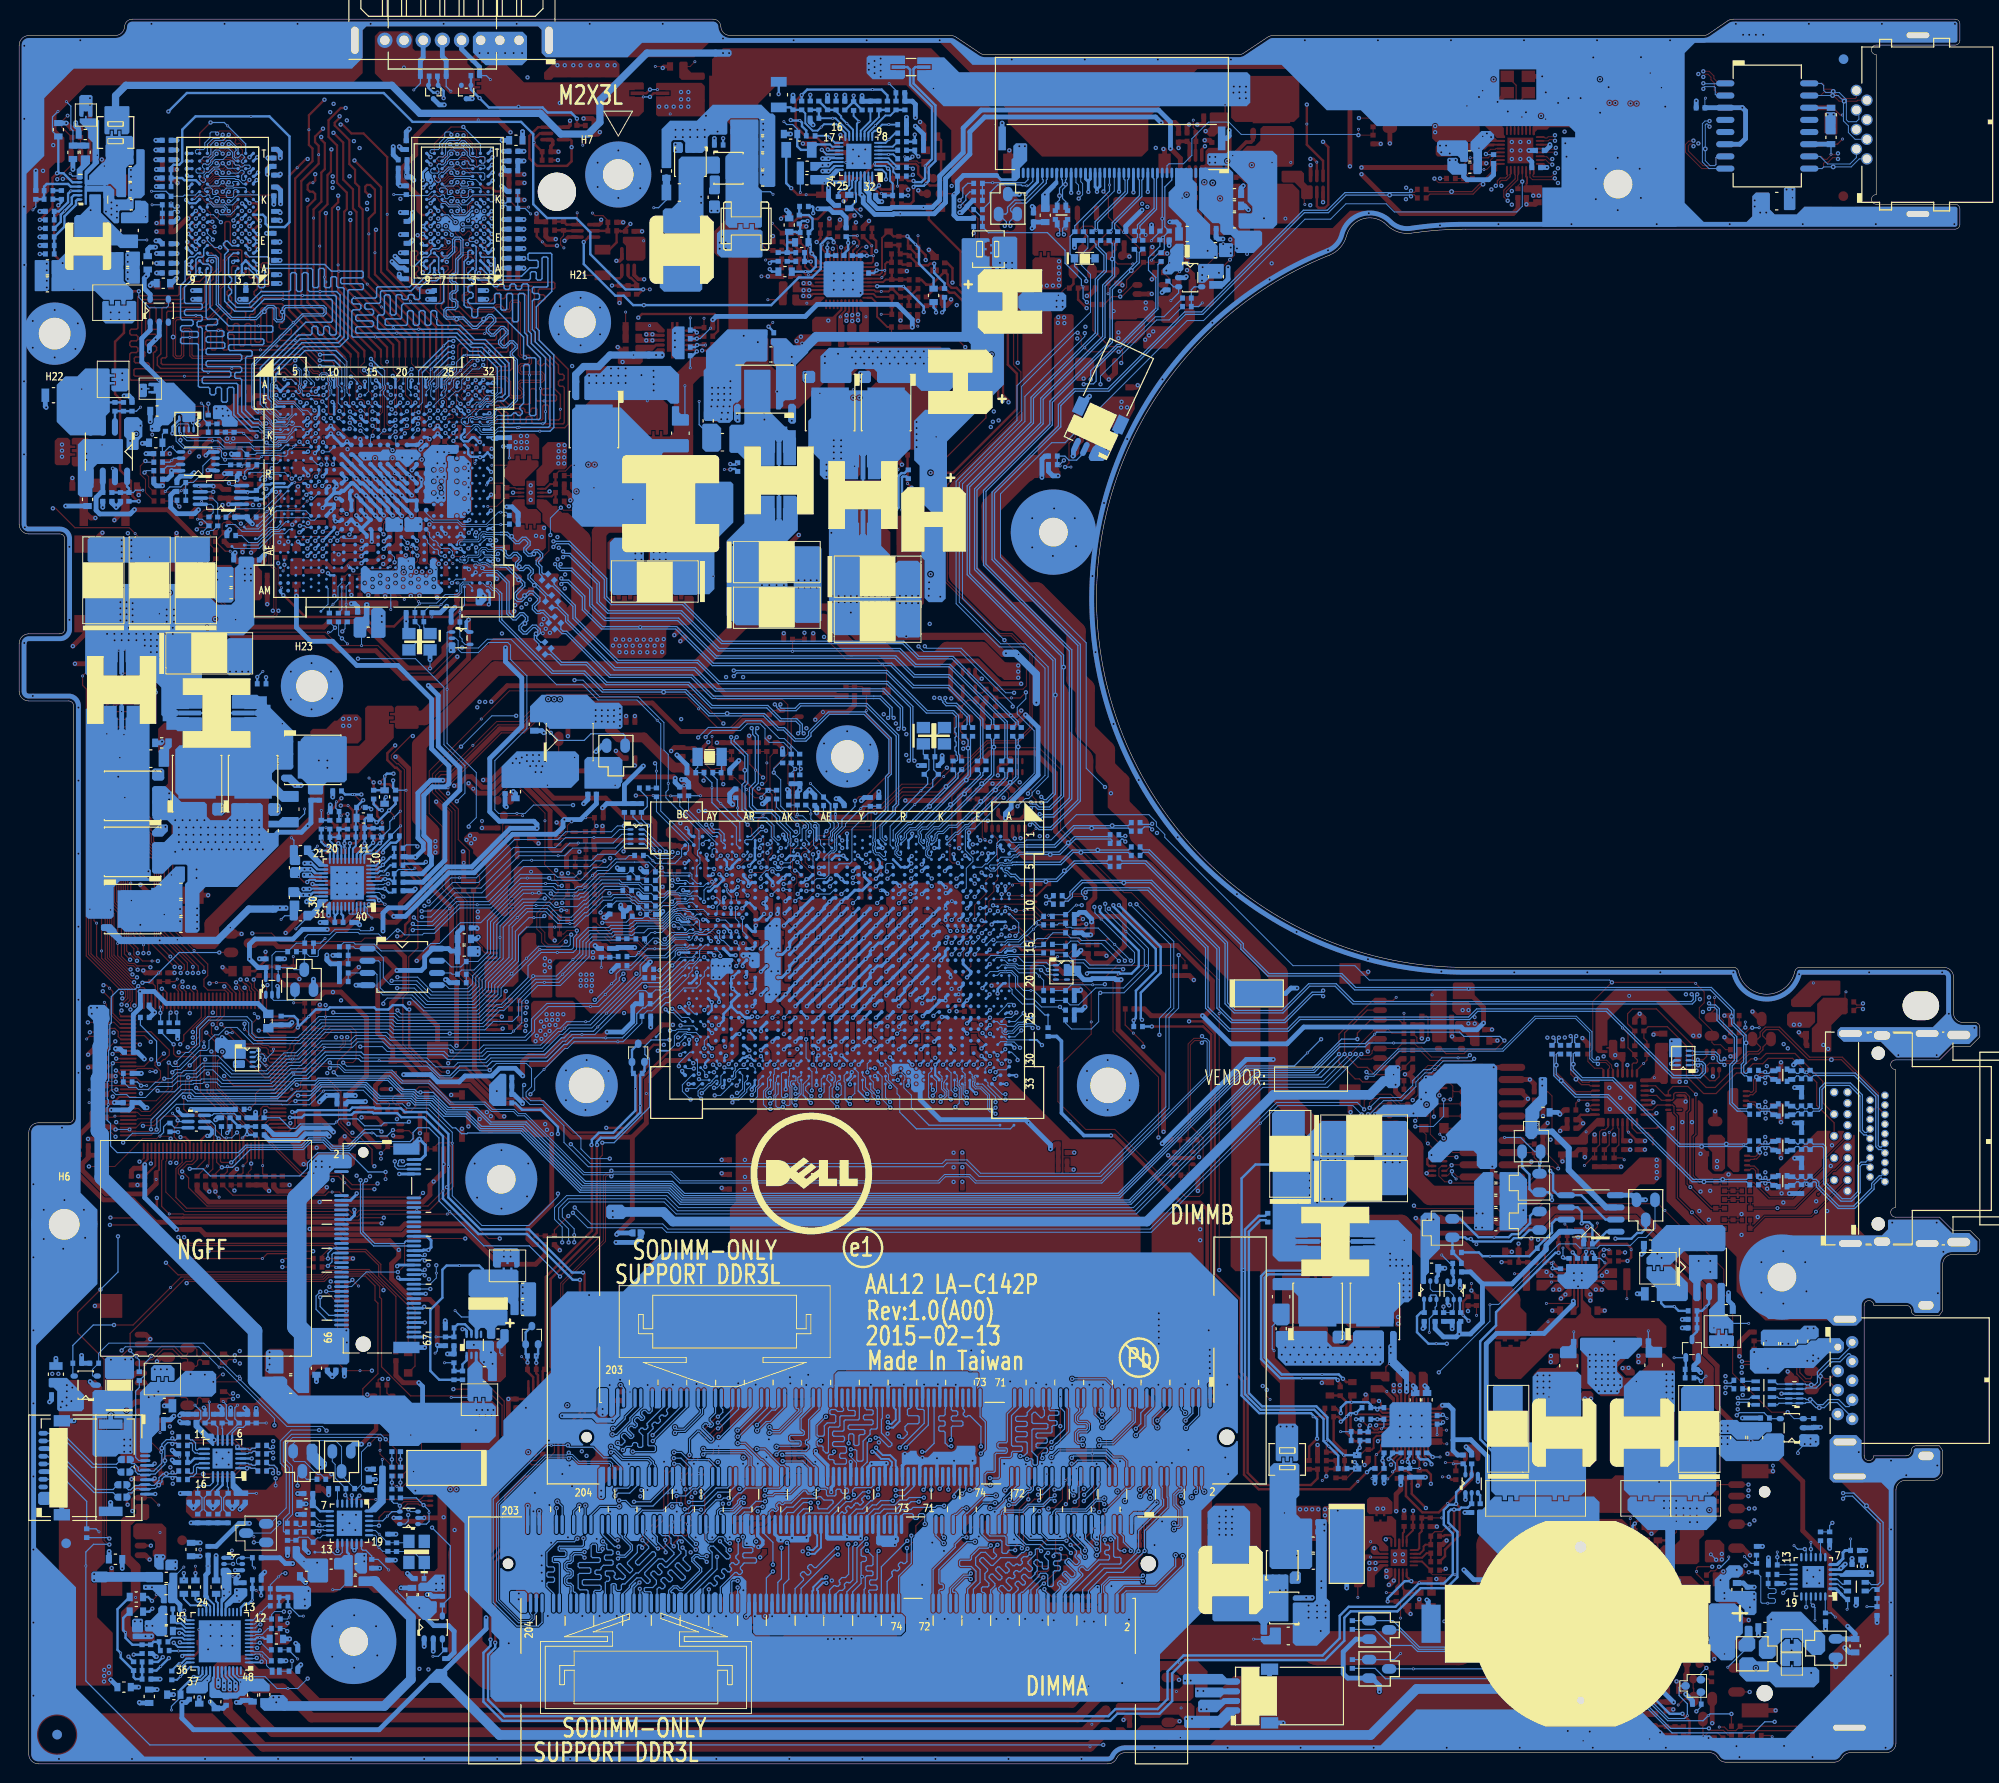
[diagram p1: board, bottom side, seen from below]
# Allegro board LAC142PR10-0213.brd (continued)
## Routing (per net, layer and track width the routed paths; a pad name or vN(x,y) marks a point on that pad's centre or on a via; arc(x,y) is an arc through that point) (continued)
M_DA1: length 41.5
  BOTTOM w0.089: UV1.J29 156.38,138.65 154.97,138.65 154.63,139 154.33,139
  BOTTOM w0.152: 154.33,139 v1(150.23,139) 149.16,139 148.77,139.39 148.77,146.95 150.3,148.48 150.3,149.48 150.6,149.78 150.6,151.96 148.98,153.58 148.98,157.44 149.11,157.57 151.34,157.57 151.47,157.44 151.47,156.95 151.34,156.82 150.53,156.82 150.4,156.69 150.4,156.16 150.53,156.04 151.26,156.04 152.13,155.17 154.71,155.17 154.91,155.36 154.91,157.02 155.04,157.15 156.3,157.15 156.43,157.28 UV5.C2
M_DA2: length 41.3
  BOTTOM w0.089: 154.33,140.22 154.74,140.22 155.03,139.93 155.3,139.93 155.58,139.65 156.18,139.65 UV1.H30
  BOTTOM w0.152: UV5.A3 157.73,155.48 157.73,154.94 157.57,154.79 157.28,154.79 157.13,154.64 157.13,154.33 157.28,154.18 157.57,154.18 157.73,154.03 157.73,153.63 157.57,153.48 157.35,153.48 157.19,153.33 157.19,153.02 157.35,152.87 157.57,152.87 157.73,152.72 157.73,152.46 157.57,152.31 155.06,152.31 154.93,152.44 154.93,153.24 154.8,153.37 154.43,153.37 154.3,153.24 154.3,151.76 154.17,151.63 153.82,151.63 153.69,151.76 153.69,153.24 153.56,153.37 153.21,153.37 153.08,153.24 153.08,150.54 152.95,150.41 152.6,150.41 152.47,150.54 152.47,153.24 152.34,153.37 151.95,153.37 151.82,153.24 151.82,149.28 151.52,148.97 151.52,147.97 150.17,146.62 v1(150.17,143.45) 150.17,140.37 150.32,140.22 154.33,140.22
M_DA3: length 41.1
  BOTTOM w0.089: 154.33,140.62 154.63,140.62 155.14,140.11 155.54,140.11 UV1.H32
  BOTTOM w0.152: UV5.C3 157.23,157.73 157.36,157.86 157.6,157.86 157.73,157.73 157.73,157.08 158.13,156.67 158.13,152.15 157.89,151.9 157.48,151.9 157.32,151.75 157.32,151.02 157.17,150.86 156.87,150.86 156.71,151.02 156.71,151.75 156.56,151.9 155.02,151.9 151.92,148.8 151.92,146.78 151.8,146.65 150.77,146.65 150.64,146.52 150.64,140.75 150.77,140.62 151.19,140.62 151.31,140.75 v1(151.31,144.84) 151.31,145.83 151.44,145.96 151.8,145.96 151.92,145.83 151.92,141.93 152.31,141.54 152.31,141.32 152.06,141.07 152.06,140.85 152.27,140.64 152.49,140.64 152.74,140.89 152.96,140.89 153.23,140.62 154.33,140.62
M_DA4: length 41
  BOTTOM w0.089: UV1.G29 156.89,140.89 156.51,141.27 156.34,141.27 156.09,141.53 156.09,141.6 155.8,141.9 155.27,141.9 154.6,142.56 154.33,142.56
  BOTTOM w0.152: UV5.C8 160.79,157.13 160.79,155.6 160.67,155.49 160.67,154.99 160.98,154.69 162.01,154.69 162.76,153.93 162.76,152.85 162.89,152.73 163.22,152.73 163.35,152.85 163.35,153.11 163.48,153.24 163.83,153.24 163.96,153.11 163.96,152.85 164.09,152.73 164.48,152.73 164.61,152.85 164.61,153.11 164.74,153.24 165.1,153.24 165.23,153.11 165.23,151.27 165.38,151.12 165.69,151.12 165.84,151.27 165.84,153.08 165.99,153.24 166.3,153.24 166.45,153.08 166.45,151.27 166.6,151.12 167.04,151.12 167.16,150.99 167.16,149.75 167.04,149.63 v1(162.87,149.63) 158.68,149.63 157.2,148.15 156.08,148.15 153.85,145.92 153.85,142.88 154.17,142.56 154.33,142.56
M_DA5: length 41.1
  BOTTOM w0.089: 154.67,143.82 154.67,143.04 155.01,142.7 155.81,142.7 156.06,142.45 156.06,142.39 156.42,142.02 156.83,142.02 UV1.F28
  BOTTOM w0.152: 154.67,143.82 154.67,145.58 156.42,147.33 157.54,147.33 159.02,148.81 v1(167.38,148.81) 169.72,148.81 169.84,148.94 169.84,151.51 169.69,151.66 169.06,151.66 168.9,151.81 168.9,152.12 169.06,152.27 169.69,152.27 169.84,152.42 169.84,152.73 169.69,152.88 167.39,152.88 167.26,153.01 167.26,153.92 167.13,154.05 163.82,154.05 163.33,154.54 163.33,156.18 162.36,157.15 161.96,157.15 161.6,157.51 161.6,157.82 161.4,158.02 160.78,158.02 UV5.D7
M_DA6: length 40.5
  BOTTOM w0.089: UV1.F32 155.53,141.72 155.1,141.72 154.67,142.15 154.33,142.15
  BOTTOM w0.152: UV5.A7 160.39,155.97 160.27,155.85 160.27,152.53 160.48,152.32 164.45,152.32 164.65,152.12 164.65,150.84 164.77,150.71 166.24,150.71 166.36,150.58 166.36,150.16 166.24,150.03 164.19,150.03 164.04,150.19 164.04,151.42 163.89,151.57 163.58,151.57 163.43,151.42 163.43,150.19 163.28,150.03 162.97,150.03 162.82,150.19 162.82,151.42 162.67,151.57 162.36,151.57 162.21,151.42 162.21,150.19 162.06,150.03 161.75,150.03 161.6,150.19 161.6,151.42 161.45,151.57 161.14,151.57 160.99,151.42 v1(160.99,150.75) 160.99,150.19 160.84,150.03 158.51,150.03 157.03,148.55 155.91,148.55 153.45,146.09 153.45,142.71 154.01,142.15 154.33,142.15
M_DA7: length 41
  BOTTOM w0.089: UV1.F30 156.38,141.56 155.87,142.07 155.37,142.07 154.46,142.99 154.33,142.99
  BOTTOM w0.152: 154.33,142.99 154.26,143.06 154.26,145.75 156.25,147.74 157.37,147.74 158.85,149.22 v1(165.16,149.22) 169.31,149.22 169.44,149.35 169.44,149.74 169.28,149.89 167.73,149.89 167.58,150.05 167.58,150.35 167.73,150.5 169.28,150.5 169.44,150.66 169.44,150.96 169.28,151.11 167.73,151.11 167.58,151.27 167.58,151.57 167.73,151.72 168.36,151.72 168.48,151.85 168.48,152.21 168.36,152.33 166.98,152.33 166.85,152.46 166.85,153.51 166.73,153.64 163.65,153.64 161.68,155.61 161.68,156.32 UV5.B8
M_DA8: length 39.8
  TOP w0.102: 156.92,155.24 157.02,155.33 157.02,155.61 156.81,155.82 156.81,156.03 157.05,156.27 157.05,156.46 156.81,156.71 156.81,156.87 157.03,157.09 157.03,157.28 156.81,157.49 156.81,157.7 156.6,157.91 156.6,158.06 156.91,158.37 UV6.D7
  TOP w0.152: 156.92,155.24 156.2,154.52 155.42,154.52 154.62,153.72 151.24,153.72 151.2,153.68 151.2,148.23 148.7,145.73 148.7,143.42 148.09,142.81 v1(148.09,141.29) 148.09,140.35 148.27,140.17 149.18,140.17 149.31,140.3 149.31,141.6 149.43,141.73 149.79,141.73 149.92,141.6 149.92,140.3 150.04,140.17 150.4,140.17 150.53,140.3 150.53,141.27 150.65,141.39 151.04,141.39 151.2,141.24 151.2,141.06 151.32,140.93 151.68,140.93 151.8,141.06 151.8,141.24 151.96,141.39 153.67,141.39 154.37,142.09 155.33,142.09 155.47,142.23 155.47,142.62 155.59,142.74 155.94,142.74 156.1,142.9 v2(156.1,143.55)
  BOTTOM w0.089: UV1.C30 v2(156.1,143.55)
M_DA9: length 41.3
  TOP w0.102: UV6.C8 156.09,157.57 155.69,157.18 155.43,157.18 155.02,156.76
  TOP w0.152: v2(157.66,141.1) 157.42,141.1 157.24,141.28 154.71,141.28 154.15,140.72 154.15,139.48 154.02,139.36 v1(152.58,139.36) 147.64,139.36 147.28,139.72 147.28,145.46 150.39,148.57 150.39,152.46 150.24,152.62 149.85,152.62 149.7,152.77 149.7,153.07 149.85,153.22 150.24,153.22 150.39,153.38 150.39,153.71 150.26,153.84 148.79,153.84 148.66,153.96 148.66,154.4 148.79,154.53 154.28,154.53 154.91,155.16 154.91,156.65 155.02,156.76
  BOTTOM w0.089: v2(157.66,141.1) 158.09,141.52 UV1.F27
M_DA10: length 39.8
  TOP w0.102: v2(156.93,144.32) 157,144.25 157,144.06 156.9,143.95 155.66,143.95 155.53,143.83 155.53,143.68 155.4,143.55 154.33,143.55 ; 157.45,155.24 157.45,155.4 157.54,155.49 157.79,155.49 157.88,155.57 157.88,156.02 157.79,156.11 157.37,156.11 UV6.A7
  TOP w0.152: 154.33,143.55 154.27,143.55 154.15,143.42 154.15,142.44 153.51,141.8 151.38,141.8 151.25,141.93 151.25,143.31 151.12,143.43 150.79,143.43 150.63,143.28 150.63,142.3 150.48,142.15 v1(149.79,142.15) 148.62,142.15 148.49,142.28 148.49,142.65 148.62,142.77 149.9,142.77 150.03,142.9 150.03,143.28 149.87,143.43 149.26,143.43 149.1,143.59 149.1,145.56 149.58,146.03 149.79,146.03 149.99,145.84 150.2,145.84 150.42,146.05 150.42,146.27 150.22,146.46 150.22,146.68 151.61,148.07 151.61,153.12 151.81,153.31 153.67,153.31 153.82,153.16 153.82,152.98 153.97,152.83 154.28,152.83 154.43,152.98 154.43,153.16 154.58,153.31 154.86,153.31 155.01,153.16 155.01,152.89 155.58,152.32 156.77,152.32 156.89,152.44 156.89,154.36 157.45,154.92 157.45,155.24
  BOTTOM w0.089: UV1.A28 v2(156.93,144.32)
M_DA11: length 40.4
  TOP w0.102: 156.04,155.24 156.04,157.15 156.15,157.27 156.32,157.27 156.43,157.15 UV6.B8
  TOP w0.152: 156.04,155.24 156.04,155.09 155.87,154.93 155.26,154.93 154.45,154.12 151.07,154.12 150.8,153.85 150.8,148.4 148.29,145.9 148.29,145.09 148.14,144.94 147.85,144.94 147.69,144.78 147.69,144.48 147.85,144.33 148.14,144.33 148.29,144.17 148.29,143.84 148.14,143.68 147.83,143.68 147.68,143.53 147.68,139.89 147.81,139.76 v1(149.92,139.76) 150.9,139.76 151.05,139.92 151.05,140.4 151.18,140.53 151.53,140.53 151.66,140.4 151.66,139.92 151.81,139.76 152.12,139.76 152.27,139.92 152.27,140.86 152.4,140.99 152.8,140.99 152.95,140.84 152.95,139.89 153.08,139.76 153.43,139.76 153.56,139.89 153.56,140.84 153.71,140.99 153.84,140.99 154.54,141.68 155.29,141.68 156.86,143.26 v2(156.86,143.56)
  BOTTOM w0.089: v2(156.86,143.56) 157.27,143.16 UV1.C28
M_DA12: length 40.8
  TOP w0.102: 154.33,145.74 154.69,145.74 154.83,145.59 154.83,145.21 154.94,145.1 155.36,145.1 155.45,145.2 155.45,145.39 155.31,145.53 155.31,146.01 155.19,146.14 154.86,146.14 154.73,146.27 154.73,146.47 154.86,146.6 155.62,146.6 155.72,146.49 155.72,145.57 155.82,145.47 156.28,145.47 156.5,145.68 156.69,145.68 156.9,145.47 157.32,145.47 157.43,145.57 157.43,145.8 157.53,145.9 157.73,145.9 157.83,145.8 157.83,145.57 157.93,145.47 158.22,145.47 159.4,144.28 159.4,143.61 158.86,143.07 158.71,143.07 158.4,143.38 158.26,143.38 158.11,143.23 158.11,143.09 158.42,142.78 158.42,142.63 158.25,142.46 157.42,142.46 157.3,142.58 157.3,142.72 157.42,142.85 v2(157.69,142.85) ; 158.53,158.01 158.53,158.64 158.65,158.76 159.09,158.76 159.89,157.96 160.5,157.96 160.71,157.75 160.93,157.75 161.14,157.96 161.42,157.96 161.54,157.85 161.54,157.68 161.43,157.57 UV6.C2
  TOP w0.152: 158.53,158.01 158.53,157.83 159.04,157.32 159.04,155.77 159.38,155.42 159.38,151.85 159.01,151.49 158.67,151.49 158.25,151.07 158.25,150.72 157.91,150.39 153.67,150.39 153.54,150.26 v1(153.54,148.08) 153.54,147.4 153.69,147.25 154.34,147.25 154.49,147.1 154.49,146.79 154.35,146.65 153.68,146.65 153.54,146.51 153.54,145.88 153.69,145.74 154.33,145.74
  BOTTOM w0.089: v2(157.69,142.85) 158.09,142.45 UV1.E27
M_DA13: length 42.2
  TOP w0.102: v2(159.23,141.16) 159.59,141.16 159.72,141.03 159.72,140.84 159.62,140.74 159.37,140.74 159.26,140.64 159.26,140.44 159.37,140.33 159.72,140.33 159.84,140.22 159.84,140.06 159.72,139.94 154.76,139.94 154.63,140.07 154.63,140.28 154.76,140.41 156.73,140.41 156.83,140.51 156.83,140.94 156.93,141.05 157.13,141.05 157.24,140.94 157.24,140.51 157.34,140.41 157.84,140.41 157.94,140.51 157.94,140.72 158.04,140.82 158.24,140.82 158.34,140.72 158.34,140.51 158.45,140.41 158.72,140.41 158.84,140.54 158.84,141.49 158.93,141.58 158.93,142.57 159.22,142.85 159.36,142.85 159.75,142.47 159.89,142.47 160.03,142.62 160.03,142.76 159.65,143.14 159.65,143.29 159.81,143.44 159.81,144.45 158.79,145.47 158.79,146.76
  TOP w0.152: 158.79,146.76 158.79,147.92 158.6,148.11 v1(157.41,148.11) 154.48,148.11 154.35,148.24 154.35,149.45 154.48,149.58 158.26,149.58 160.52,151.84 160.52,152.12 160.19,152.45 160.19,155.47 159.8,155.87 159.8,156.12 159.91,156.24 160.33,156.24 160.43,156.13 UV6.A3
  BOTTOM w0.089: UV1.G26 158.89,140.82 v2(159.23,141.16)
M_DA14: length 41.1
  TOP w0.102: 158.39,146.76 158.39,146.23 158.15,145.99 158.15,145.83 159.61,144.37 159.61,143.53 158.33,142.25 156.2,142.25 156.08,142.13 156.08,141.9 156.2,141.77 157.21,141.77 157.5,141.48 158.14,141.48 v2(158.5,141.85)
  TOP w0.152: UV6.C3 160.52,157.48 160.52,157.26 160.39,157.14 160.04,157.14 159.91,157.26 159.91,157.62 159.29,158.24 159.02,158.24 158.88,158.1 158.88,157.83 159.33,157.39 159.33,155.89 159.78,155.44 159.78,151.67 158.09,149.98 154.07,149.98 153.95,149.86 153.95,147.83 154.07,147.7 154.74,147.7 154.9,147.55 154.9,146.99 155.02,146.86 155.37,146.86 155.49,146.99 v1(155.49,147.32) 155.49,147.58 155.62,147.7 155.95,147.7 156.08,147.58 156.08,147.02 156.2,146.89 156.51,146.89 156.66,147.04 156.66,147.55 156.81,147.7 157.08,147.7 157.23,147.55 157.23,146.29 157.38,146.14 157.66,146.14 157.79,146.27 157.79,147.57 157.92,147.7 158.26,147.7 158.39,147.57 158.39,146.76
  BOTTOM w0.089: v2(158.5,141.85) 158.89,142.24 UV1.D26
M_DA15: length 42.2
  TOP w0.102: 159.81,146.75 159.81,146.04 160.56,145.29 160.56,144.41 160.46,144.31 160.11,144.31 160.01,144.21 160.01,144 160.11,143.9 160.46,143.9 160.56,143.8 160.56,143.58 160.46,143.47 160.15,143.47 160.05,143.37 160.05,143.17 160.15,143.07 160.46,143.07 160.56,142.97 160.56,142.78 159.96,142.18 159.96,141.6 159.84,141.48 159.45,141.48 159.34,141.59 v2(159.34,141.96)
  TOP w0.152: UV6.A2 161.23,155.9 161.1,155.77 160.91,155.77 160.78,155.9 160.78,157.04 160.91,157.17 162.4,157.17 162.53,157.04 162.53,156.94 162.65,156.81 163,156.81 163.12,156.94 163.12,157.24 162.96,157.4 162.96,157.67 163.09,157.8 163.58,157.8 163.71,157.67 163.71,156.32 163.58,156.2 162.99,156.2 162.86,156.07 162.86,155.79 163.15,155.5 163.15,155.3 162.35,154.51 162.16,154.51 162.03,154.63 162.03,155.17 161.91,155.29 161.7,155.29 161.58,155.17 161.58,154.63 161.45,154.51 161.22,154.51 161.09,154.63 161.09,154.95 160.97,155.07 160.72,155.07 160.6,154.95 160.6,152.61 161.11,152.11 161.11,151.85 159.6,150.34 159.6,150.12 159.81,149.91 159.81,149.7 159.59,149.48 159.38,149.48 159.17,149.69 158.95,149.69 158.43,149.17 v1(156,149.17) 154.89,149.17 154.76,149.04 154.76,148.64 154.89,148.52 158.71,148.52 159.07,148.88 159.63,148.88 159.81,148.7 159.81,146.75
  BOTTOM w0.089: v2(159.34,141.96) 159.69,141.61 UV1.F25
M_DA16: length 37.8
  IN1 w0.102: 155.02,158.39 156.32,158.39 156.44,158.52 156.44,160.76 v2(156.03,161.17)
  IN1 w0.165: 155.02,158.39 154.52,158.39 154.41,158.5 153.33,158.5 153.17,158.33 153.17,158.19 153,158.03 152.67,158.03 152.51,158.19 152.51,158.33 152.34,158.5 151.64,158.5 151.52,158.62 151.52,158.9 151.39,159.02 151,159.02 150.87,158.9 150.87,158.39 150.74,158.27 150.36,158.27 150.23,158.39 150.23,158.9 150.11,159.02 149.7,159.02 149.57,158.9 149.57,157.74 149.7,157.61 150.36,157.61 150.53,157.44 150.53,157.11 150.36,156.95 149.74,156.95 149.57,156.78 149.57,147.08 149.7,146.95 156.62,146.95 156.75,146.83 156.75,146.41 v2(156.72,146.38)
  BOTTOM w0.089: v2(156.72,146.38) 156.84,146.5 157.36,146.5 158.51,145.35 v1(158.51,145.35) 158.51,145.34 159.45,144.41 159.45,144.2 UV1.A25
  BOTTOM w0.102: UV5.G2 v2(156.03,161.17)
M_DA17: length 37.8
  IN1 w0.102: v2(156.83,158.77) 156.83,158.25 156.16,157.58 156.16,156.38 156.03,156.25 155.82,156.25 155.7,156.38 155.7,157.46
  IN1 w0.165: 155.7,157.46 155.59,157.56 155.24,157.56 155.11,157.43 155.11,156.83 154.98,156.71 154.58,156.71 154.46,156.83 154.46,157.43 154.33,157.56 153.53,157.56 153.37,157.39 153.37,157.18 153.2,157.01 152.87,157.01 152.71,157.18 152.71,157.39 152.54,157.56 151.18,157.56 151.02,157.4 151.02,156.55 150.89,156.42 150.17,156.42 150.04,156.3 150.04,155.89 150.17,155.76 150.83,155.76 150.95,155.64 150.95,155.23 150.83,155.1 150.21,155.1 150.04,154.94 150.04,147.55 150.17,147.42 157.11,147.42 157.23,147.3 157.23,146.09 v2(157.03,145.89)
  BOTTOM w0.089: UV1.C25 159.25,143.6 159.25,144.27 158.98,144.54 158.7,144.54 157.36,145.89 v2(157.03,145.89)
  BOTTOM w0.102: UV5.E3 157.5,159.17 157.62,159.06 157.62,158.89 157.5,158.77 v2(156.83,158.77)
M_DA18: length 37.8
  IN1 w0.102: v2(157.71,160.98) 157.62,160.98 157.23,160.59 157.23,158.37 156.53,157.67 156.53,156.1 156.41,155.97 155.02,155.97
  IN1 w0.165: 155.02,155.97 154.65,155.97 154.08,156.54 151.66,156.54 151.49,156.37 151.49,155.1 150.51,154.13 150.51,148.02 150.64,147.89 157.58,147.89 157.7,147.77 157.7,145.39 157.58,145.26 156.27,145.26 156.14,145.39 v2(156.14,145.9)
  BOTTOM w0.089: UV1.E25 159.69,142.48 159.01,143.17 158.71,143.17 158.38,143.5 158.38,144.33 157.23,145.48 156.56,145.48 v2(156.14,145.9)
  BOTTOM w0.102: v2(157.71,160.98) 157.71,161.09 UV5.H3
M_DA19: length 38.2
  IN1 w0.102: 162.64,157.11 162.08,157.11 161.96,156.98 161.96,155.74 161.83,155.61 161.58,155.61 161.45,155.74 161.45,157.96 162.02,158.53 162.02,160.64 161.89,160.77 160.22,160.77 160.09,160.9 160.09,161.46 160.22,161.58 161.5,161.58 161.63,161.46 v2(161.63,161.17)
  IN1 w0.165: 162.64,157.11 162.73,157.11 162.9,156.95 162.9,156.71 163.27,156.34 163.27,155.25 162.17,154.15 161.94,154.15 161.8,154.29 161.8,154.83 161.68,154.95 161.26,154.95 161.13,154.83 161.13,152.41 161.3,152.25 161.89,152.25 162.06,152.08 162.06,151.75 161.89,151.59 161.3,151.59 161.13,151.42 161.13,151.09 161.3,150.93 161.89,150.93 162.06,150.76 162.06,150.43 161.89,150.27 161.3,150.27 161.13,150.1 161.13,146.9 160.61,146.38 160.61,144.63 160.27,144.28 159.89,144.28 159.66,144.51 158.77,144.51 158.64,144.64 158.64,144.97 158.77,145.1 159.67,145.1 v2(159.78,145.21)
  BOTTOM w0.089: UV1.D24 160.49,143.08 160.16,143.41 160.16,143.65 160.21,143.7 160.21,144.21 159.78,144.64 v2(159.78,145.21)
  BOTTOM w0.102: v2(161.63,161.17) 161.63,161.17 UV5.H8
M_DA20: length 39
  IN1 w0.102: 160.66,155.24 160.66,155.6 161.23,156.17 161.23,159.74 160.98,159.99 159.19,159.99 159.02,160.16 v2(159.02,160.8)
  IN1 w0.165: 160.66,155.24 160.66,151.92 160.54,151.79 153.59,151.79 153.47,151.66 153.47,151.1 153.59,150.98 160.54,150.98 160.66,150.85 160.66,147.11 160.21,146.66 v2(159.29,146.66)
  BOTTOM w0.089: 161.25,145.13 161.25,144.48 161.66,144.07 161.66,143.9 161.56,143.8 161.56,143.32 161.61,143.27 161.61,142.67 161.3,142.36 UV1.E23
  BOTTOM w0.102: UV5.H7 159.8,161.57 v2(159.02,160.8)
  BOTTOM w0.152: 161.25,145.13 159.73,146.66 v2(159.29,146.66)
M_DA21: length 39.9
  IN1 w0.102: 155.02,159.17 155.62,159.17 v2(156.03,159.57)
  IN1 w0.165: 155.02,159.17 155,159.17 154.67,159.5 153.48,159.5 153.31,159.33 153.31,159.11 153.15,158.94 152.82,158.94 152.65,159.11 152.65,159.33 152.48,159.5 151.61,159.5 151.49,159.63 151.49,160.74 151.36,160.87 150.88,160.87 150.76,160.74 150.76,159.7 150.59,159.53 149.27,159.53 149.1,159.37 149.1,146.61 149.23,146.48 v2(156.14,146.48)
  BOTTOM w0.089: UV1.F23 161.29,141.68 160.53,142.44 160.37,142.44 160.11,142.7 160.11,143.17 159.96,143.32 159.96,143.76 160.01,143.81 160.01,144.12 158.92,145.21 158.92,146.2 158.36,146.76
  BOTTOM w0.102: UV5.F2 v2(156.03,159.57)
  BOTTOM w0.152: 158.36,146.76 158.19,146.93 v1(157.89,146.93) 156.59,146.93 v2(156.14,146.48)
M_DA22: length 39
  IN1 w0.102: v2(160.83,159.57) 160.53,159.57 160.42,159.46 160.42,158.55 161.03,157.94 161.03,156.44 160.19,155.6 160.19,155.24
  IN1 w0.165: 160.19,155.24 160.19,152.45 160.07,152.32 159.66,152.32 159.5,152.49 159.5,154.46 159.33,154.62 159,154.62 158.84,154.46 158.84,152.49 158.67,152.32 153.12,152.32 153,152.2 153,150.5 153.12,150.37 160.07,150.37 160.19,150.25 160.19,147.4 160.03,147.24 v2(159.29,147.24)
  BOTTOM w0.089: UV1.D22 162.09,143.11 161.76,143.43 161.76,143.71 161.84,143.79 161.84,143.79 161.86,143.82 161.86,144.17 161.66,144.38 161.66,145.36
  BOTTOM w0.102: v2(160.83,159.57) 160.83,159.57 UV5.F8
  BOTTOM w0.152: 161.66,145.36 v1(161.54,145.48) 159.78,147.24 v2(159.29,147.24)
M_DA23: length 39.9
  IN1 w0.102: 158.93,155.24 159.09,155.4 159.38,155.4 159.51,155.52 159.51,157.26 159.63,157.39 160.22,157.39 160.34,157.26 160.34,156.58 160.47,156.45 160.67,156.45 160.8,156.58 160.8,157.68 160.67,157.81 159.62,157.81 159.49,157.94 159.49,158.17 159.62,158.29 160.01,158.29 160.13,158.42 160.13,158.88 159.55,159.46 v2(159.41,159.46)
  IN1 w0.165: 158.93,155.24 158.37,154.68 158.37,152.92 158.24,152.79 156.38,152.79 155.94,153.23 155.38,153.23 154.95,152.79 152.65,152.79 152.53,152.67 152.53,150.03 152.65,149.9 159.6,149.9 159.72,149.78 159.72,148.11 159.44,147.82 v2(159.29,147.82)
  BOTTOM w0.089: UV1.F21 162.49,141.96 162.49,145.1
  BOTTOM w0.102: UV5.F7 159.81,159.97 159.41,159.58 v2(159.41,159.46)
  BOTTOM w0.152: v2(159.29,147.82) 159.77,147.82 v1(160.87,146.72) 162.49,145.1
M_DA24: length 39.1
  TOP w0.102: UV6.F8 v2(156.83,159.57)
  IN2 w0.102: 155.02,159.17 156.42,159.17 v2(156.83,159.57)
  IN2 w0.165: v2(163.19,142.76) 162.82,142.76 159.72,145.86 159.72,148.52 159.35,148.89 158.83,148.89 158.66,148.73 158.66,146.69 158.54,146.56 158.13,146.56 158,146.69 158,148.73 157.84,148.89 157.51,148.89 157.34,148.73 157.34,147.57 157.18,147.41 156.85,147.41 156.68,147.57 156.68,148.73 156.52,148.89 156.19,148.89 156.02,148.73 156.02,147.57 155.86,147.41 155.53,147.41 155.36,147.57 155.36,148.73 155.2,148.89 153.24,148.89 153.05,149.09 153.05,158.9 153.74,159.59 154.49,159.59 154.91,159.17 155.02,159.17
  BOTTOM w0.089: UV1.E21 162.89,142.46 v2(163.19,142.76)
M_DA25: length 39.6
  TOP w0.102: UV6.H7 v2(156.83,161.97)
  IN2 w0.102: v2(156.83,161.97) 156.44,161.59 156.44,160.17 156.64,159.98 157.03,159.98 157.22,159.8 157.22,158.01 156.75,157.54 155.02,157.54
  IN2 w0.165: 155.02,157.54 153.65,157.54 153.52,157.42 153.52,155.73 153.69,155.57 153.79,155.57 153.96,155.4 153.96,155.07 153.79,154.91 153.69,154.91 153.52,154.74 153.52,154.41 153.69,154.25 153.79,154.25 153.96,154.08 153.96,153.75 153.79,153.59 153.69,153.59 153.52,153.42 153.52,153.09 153.69,152.93 153.79,152.93 153.96,152.76 153.96,152.43 153.79,152.27 153.69,152.27 153.52,152.1 153.52,149.49 153.65,149.36 159.55,149.36 160.46,148.45 160.46,148.22 160.2,147.96 160.2,147.78 160.49,147.49 160.67,147.49 160.92,147.75 161.16,147.75 161.39,147.52 161.39,147.29 160.58,146.47 160.58,146.3 160.87,146.01 161.05,146.01 161.86,146.82 162.09,146.82 162.33,146.58 162.33,146.35 161.48,145.51 161.48,145.33 161.77,145.04 161.95,145.04 162.79,145.88 163.07,145.88 163.2,145.76 163.2,144.99 163.33,144.87 v2(163.63,144.87)
  BOTTOM w0.089: v2(163.63,144.87) 164.05,144.45 164.05,143.43 163.69,143.07 UV1.D20
M_DA26: length 39.6
  TOP w0.102: UV6.H8 v2(156.03,161.97)
  IN2 w0.102: v2(156.03,161.97) 155.63,161.57 155.63,160.92 155.49,160.78 155.02,160.78
  IN2 w0.165: v2(164.01,141.94) 163.61,141.54 163.02,141.54 160.27,144.3 159.48,144.3 156.86,146.91 155.72,146.91 155.55,146.75 155.55,146.19 155.39,146.02 155.05,146.02 154.89,146.19 154.89,146.75 154.72,146.91 154.32,146.91 154.16,146.75 154.16,146.29 153.99,146.13 153.66,146.13 153.5,146.29 153.5,146.75 153.33,146.91 152.72,146.91 152.6,147.04 152.6,147.51 152.72,147.64 154.7,147.64 154.87,147.8 154.87,148.13 154.7,148.3 152.75,148.3 152.58,148.46 152.58,160.25 152.91,160.58 154.39,160.58 154.59,160.78 155.02,160.78
  BOTTOM w0.089: v2(164.01,141.94) 164.06,141.94 164.45,141.56 UV1.F19
M_DA27: length 38.8
  TOP w0.102: v2(156.83,160.37) 157.23,159.97 UV6.F7
  IN2 w0.102: v2(156.83,160.37) 157.3,160.37 157.42,160.25 157.42,157.63 156.79,157 155.02,157 155.02,157
  IN2 w0.165: v2(163.62,145.46) 163.57,145.51 163.57,146.01 159.74,149.83 154.12,149.83 153.99,149.96 153.99,150.35 154.12,150.48 156.62,150.48 156.75,150.61 156.75,152.36 156.62,152.49 156.24,152.49 156.11,152.36 156.11,151.27 155.99,151.14 154.12,151.14 153.99,151.27 153.99,151.67 154.12,151.8 155.37,151.8 155.49,151.93 155.49,152.33 155.37,152.46 154.61,152.46 154.45,152.63 154.45,152.96 154.61,153.12 155.19,153.12 155.35,153.29 155.35,153.62 155.19,153.78 154.61,153.78 154.45,153.95 154.45,156.42 155.02,157
  BOTTOM w0.089: UV1.A19 164.49,144.59 v2(163.62,145.46)
M_DA28: length 39.1
  TOP w0.102: UV6.G2 v2(160.83,160.37)
  IN2 w0.102: v2(160.83,160.37) 160.83,160.32 161.19,159.96 161.83,159.96 162.05,159.74 162.05,159.14 162.19,159 162.64,159 ; v2(165.78,141.98) 165.43,141.98 165.29,142.11 165.29,142.26 165.42,142.39 166.18,142.39 166.43,142.64 166.43,145.03 166.75,145.35 166.75,145.49
  IN2 w0.165: 166.75,145.49 166.82,145.55 166.82,148.71 169.3,151.19 169.3,155.44 169.13,155.61 166.98,155.61 166.82,155.77 166.82,156.2 166.94,156.32 168.43,156.32 168.56,156.45 168.56,156.92 168.43,157.04 166.19,157.04 166.06,156.92 166.06,156.39 165.94,156.27 164.45,156.27 164.29,156.43 164.29,158.41 164.12,158.57 163.79,158.57 163.63,158.41 163.63,156.43 163.46,156.27 163.08,156.27 162.95,156.39 162.95,158.88 162.82,159 162.64,159
  BOTTOM w0.089: v2(165.78,141.98) 165.29,142.47 UV1.D18
M_DA29: length 39.5
  TOP w0.102: UV6.H3 v2(160.83,161.17)
  IN2 w0.102: v2(160.83,161.17) 160.83,161.12 161.18,160.77 162.64,160.77 ; 167.3,145.39 166.67,144.76 166.67,142.24 165.7,141.27 v2(165.69,141.27)
  IN2 w0.165: 167.3,145.39 167.3,148.53 169.77,150.99 169.77,156.03 169.6,156.19 169.16,156.19 169.03,156.32 169.03,156.73 169.16,156.85 169.6,156.85 169.77,157.02 169.77,157.35 169.6,157.51 165.64,157.51 165.52,157.64 165.52,158.05 165.64,158.17 169.6,158.17 169.77,158.34 169.77,158.76 169.61,158.92 164.49,158.92 162.64,160.77
  BOTTOM w0.089: UV1.F17 165.98,141.56 v2(165.69,141.27)
M_DA30: length 38.5
  TOP w0.102: UV6.E3 v2(160.83,158.77)
  IN2 w0.102: v2(165.78,143.59) 165.78,144.14 165.99,144.34 165.99,144.93 165.7,145.21 165.7,145.56
  IN2 w0.165: v2(160.83,158.77) 160.81,158.77 160.69,158.64 160.69,155.34 161.59,154.44 162.45,154.44 162.62,154.28 162.62,153.19 162.78,153.02 163.11,153.02 163.28,153.19 163.28,154.28 163.44,154.44 163.86,154.44 164.03,154.28 164.03,150.32 164.16,150.19 164.56,150.19 164.69,150.32 164.69,154.28 164.85,154.44 165.31,154.44 165.44,154.32 165.44,153.13 165.6,152.96 166.8,152.96 166.93,152.84 166.93,152.43 166.8,152.3 165.6,152.3 165.44,152.14 165.44,151.81 165.6,151.64 166.91,151.64 167.04,151.52 167.04,151.11 166.91,150.98 165.6,150.98 165.44,150.82 165.44,150.49 165.6,150.32 166.44,150.32 166.57,150.19 166.57,149.79 166.44,149.66 165.86,149.66 165.7,149.5 165.7,145.56
  BOTTOM w0.089: UV1.A17 166.09,143.89 v2(165.78,143.59)
M_DA31: length 39.1
  TOP w0.102: UV6.F2 v2(161.63,159.57)
  IN2 w0.102: 161.25,158.43 161.25,159.19 v2(161.63,159.57) ; v2(165.78,142.79) 165.62,142.62 165.37,142.62 165.27,142.72 165.27,142.87 165.6,143.2 166.08,143.2 166.19,143.31 166.19,145.52 166.28,145.61
  IN2 w0.165: 161.25,158.43 161.93,157.75 161.93,155.04 162.06,154.91 163.51,154.91 163.68,155.08 163.68,155.71 163.84,155.88 164.17,155.88 164.34,155.71 164.34,155.08 164.5,154.91 165.3,154.91 165.47,155.08 165.47,155.6 165.63,155.77 165.96,155.77 166.13,155.6 166.13,155.08 166.29,154.91 167.23,154.91 167.4,154.75 167.4,154.36 167.23,154.19 166.08,154.19 165.92,154.03 165.92,153.7 166.08,153.53 167.23,153.53 167.4,153.37 167.4,151.82 167.56,151.65 167.89,151.65 168.06,151.82 168.06,154.75 168.22,154.91 168.7,154.91 168.83,154.79 168.83,151.38 166.28,148.84 166.28,145.61
  BOTTOM w0.089: UV1.C17 166.09,143.09 v2(165.78,142.79)
M_DA32: length 39.9
  TOP w0.102: v2(180.52,161.97) 180.92,161.57 UV7.H8
  IN2 w0.165: v2(167.85,146.53) 167.88,146.57 167.88,148.45 170.24,150.8 170.24,157.4 170.36,157.53 172.03,157.53 172.15,157.66 172.15,158.1 172.03,158.23 170.36,158.23 170.24,158.36 170.24,158.79 170.36,158.92 174.01,158.92 174.18,159.09 174.18,159.78 174.34,159.94 174.68,159.94 174.84,159.78 174.84,159.09 175.01,158.92 175.34,158.92 175.5,159.09 175.5,159.78 175.67,159.94 176,159.94 176.16,159.78 176.16,159.09 176.33,158.92 176.71,158.92 176.88,159.09 176.88,159.79 177.04,159.96 177.74,159.96 177.87,159.83 177.87,159.26 178,159.13 179.05,159.13 179.18,159.26 179.18,159.72 179.44,159.98 179.72,159.98 180.05,160.31 180.05,161.51 v2(180.52,161.97)
  BOTTOM w0.089: UV1.E17 166.54,142.81 166.54,143.15 166.34,143.36 166.34,143.76 166.41,143.84 166.41,145.33 166.64,145.56
  BOTTOM w0.152: v2(167.85,146.53) 166.87,145.56 166.64,145.56
M_DA33: length 40.5
  TOP w0.102: UV7.H7 v2(181.32,161.97)
  IN2 w0.102: v2(181.32,161.97) 180.92,161.57 180.92,159.37 180.71,159.17 180.3,159.17 180.12,158.99 180.12,157.67 179.93,157.48 179.51,157.48
  IN2 w0.165: 179.51,157.48 177.88,157.48 177.67,157.26 177.06,157.26 176.94,157.39 176.94,158.32 176.81,158.45 172.75,158.45 172.62,158.32 172.62,157.9 172.75,157.77 176.09,157.77 176.22,157.65 176.22,157.19 176.09,157.06 170.94,157.06 170.71,156.83 170.71,150.6 168.37,148.27 168.37,146.46 v2(167.86,145.95)
  BOTTOM w0.089: UV1.D16 166.89,143.11 166.56,143.43 166.56,143.69 166.64,143.76 166.64,144.73
  BOTTOM w0.152: 166.64,144.73 v2(167.86,145.95)
M_DA34: length 40.6
  TOP w0.102: UV7.G2 v2(185.32,160.37)
  IN2 w0.102: v2(185.32,160.37) 185.73,159.96 187.13,159.96 ; v2(168.15,141.99) 168.62,141.52 170.63,141.52 170.99,141.87 170.99,142.33 171.5,142.84
  IN2 w0.165: 187.13,159.96 187.51,159.58 187.51,155.38 185.95,153.82 185.95,147.57 185.22,146.85 177.9,146.85 177.77,146.98 177.77,147.9 177.64,148.03 174.33,148.03 174.2,147.9 174.2,144.67 173.53,143.99 172.65,143.99 171.5,142.84
  BOTTOM w0.089: UV1.F15 167.71,141.56 168.14,141.99 v2(168.15,141.99)
M_DA35: length 39.2
  TOP w0.102: UV7.F8 181.29,159.6 v2(181.3,159.6)
  IN2 w0.102: v2(181.3,159.6) 181.3,159.3 180.9,158.9 180.9,157.11 180.6,156.81 179.54,156.81
  IN2 w0.165: 179.54,156.81 178.72,156.81 178.6,156.68 178.6,155.99 178.47,155.87 178.06,155.87 177.94,155.99 177.94,156.24 177.77,156.4 171.3,156.4 171.18,156.28 171.18,155.85 171.34,155.68 176.81,155.68 176.93,155.55 176.93,155.15 176.81,155.02 171.34,155.02 171.18,154.86 171.18,150.41 168.84,148.07 168.84,146.33 v2(167.86,145.35)
  BOTTOM w0.089: UV1.A15 167.86,144.13 v2(167.86,145.35)
M_DA36: length 40.1
  TOP w0.102: UV7.F7 182.11,159.58 v2(182.11,159.56)
  IN2 w0.102: 180.42,155.24 181.31,156.14 181.31,157.24 181.7,157.63 181.7,159.15 v2(182.11,159.56)
  IN2 w0.165: 180.42,155.24 180.32,155.15 179.37,155.15 179.24,155.02 179.24,153.94 179.11,153.82 178.71,153.82 178.59,153.94 178.59,155.22 178.42,155.38 178.09,155.38 177.92,155.22 177.92,153.98 177.76,153.82 177.32,153.82 176.59,154.55 171.8,154.55 171.65,154.4 171.65,153.99 171.81,153.83 174.6,153.83 174.73,153.7 174.73,153.3 174.6,153.17 171.81,153.17 171.65,153 171.65,152.67 171.81,152.51 172.83,152.51 172.95,152.38 172.95,151.98 172.83,151.85 171.81,151.85 171.65,151.68 171.65,150.22 169.31,147.88 169.31,146.1 v2(168.57,145.36)
  BOTTOM w0.089: v2(168.57,145.36) 168.09,144.88 168.09,143.16 UV1.D14
M_DA37: length 39.8
  TOP w0.102: UV7.F2 v2(185.32,159.57)
  IN2 w0.102: v2(185.32,159.57) 185.47,159.57 185.88,159.16 186.3,159.16 186.58,158.88 186.58,157.66 186.33,157.4 186.33,155.45 186.12,155.24
  IN2 w0.165: v2(169.69,141.92) 169.69,142.65 169.96,142.91 170.91,142.91 172.31,144.31 172.31,144.72 172.66,145.07 173.05,145.07 173.65,145.67 173.65,148.02 174.14,148.5 178.06,148.5 178.24,148.32 178.24,147.49 178.4,147.32 178.73,147.32 178.9,147.49 178.9,148.32 179.06,148.49 179.39,148.49 179.56,148.32 179.56,147.49 179.72,147.32 180.05,147.32 180.22,147.49 180.22,148.32 180.38,148.49 180.71,148.49 180.88,148.32 180.88,147.49 181.05,147.32 185.03,147.32 185.48,147.77 185.48,154.6 186.12,155.24
  BOTTOM w0.089: UV1.F13 169.33,141.56 v2(169.69,141.92)
M_DA38: length 39.2
  TOP w0.102: v2(185.32,158.77) 185.01,158.77 184.92,158.86 UV7.E3
  IN2 w0.165: v2(185.32,158.77) 184,157.46 184,154.13 184.49,153.65 184.49,149.67 184.26,149.44 183.91,149.44 183.75,149.61 183.75,150.2 183.58,150.37 183.25,150.37 183.09,150.2 183.09,149.61 182.92,149.44 182.59,149.44 182.43,149.61 182.43,150.2 182.26,150.37 181.93,150.37 181.77,150.2 181.77,149.61 181.6,149.44 181.27,149.44 181.11,149.61 181.11,150.2 180.94,150.37 180.61,150.37 180.45,150.2 180.45,149.61 180.28,149.44 179.95,149.44 179.79,149.61 179.79,150.2 179.62,150.37 179.29,150.37 179.13,150.2 179.13,149.61 178.96,149.44 178.54,149.44 178.38,149.61 178.38,150.2 178.21,150.37 177.88,150.37 177.72,150.2 177.72,149.61 177.55,149.44 177.22,149.44 177.06,149.61 177.06,150.2 176.89,150.37 176.56,150.37 176.39,150.2 176.39,149.61 176.23,149.44 175.9,149.44 175.73,149.61 175.73,150.2 175.57,150.37 175.24,150.37 175.07,150.2 175.07,149.61 174.91,149.44 173.72,149.44 171.34,147.06 171.34,145.95 170.07,144.68 v2(169.94,144.68)
  BOTTOM w0.089: UV1.A13 169.29,144.13 169.76,144.59 169.86,144.59 v2(169.94,144.68)
M_DA39: length 39.2
  TOP w0.102: UV7.H3 v2(185.32,161.17)
  IN2 w0.102: v2(185.32,161.17) 184.89,160.75 184.89,159.42 185.15,159.17 185.55,159.17 185.72,159 185.72,158.32 184.96,157.56 184.96,155.24
  IN2 w0.165: v2(169,143.56) 169.1,143.47 170.5,143.47 171.06,144.03 171.06,144.91 171.85,145.69 171.85,146.91 173.91,148.97 181.29,148.97 181.45,148.81 181.45,148.34 181.62,148.17 181.95,148.17 182.11,148.34 182.11,148.81 182.28,148.97 182.71,148.97 182.88,148.81 182.88,147.95 183.04,147.79 183.37,147.79 183.54,147.95 183.54,148.81 183.7,148.97 184.03,148.97 184.2,148.81 184.2,147.92 184.32,147.79 184.83,147.79 184.96,147.92 184.96,155.24
  BOTTOM w0.089: v2(169,143.56) 169.03,143.53 169.05,143.53 169.29,143.29 UV1.C13
M_DA40: length 41.9
  TOP w0.152: UV7.B8 180.68,156.77 180.56,156.65 180.56,155.11 180.43,154.99 179.83,154.99 179.7,154.86 179.7,153.85 179.85,153.7 179.89,153.7 180.04,153.55 180.04,153.24 179.89,153.09 179.85,153.09 179.7,152.94 179.7,152.66 179.85,152.51 180.37,152.51 180.49,152.38 180.49,151.99 180.37,151.86 180.1,151.86 179.95,151.71 179.95,151.35 180.1,151.19 180.36,151.19 180.51,151.04 180.51,150.74 180.36,150.58 180.1,150.58 179.95,150.43 179.95,148.41 179.82,148.29 179.46,148.29 179.34,148.41 179.34,151.71 179.19,151.86 178.88,151.86 178.73,151.71 178.73,148.41 178.6,148.29 178.25,148.29 178.12,148.41 178.12,151.71 177.97,151.86 177.56,151.86 177.41,151.71 177.41,151.04 177.26,150.89 177.09,150.89 176.94,150.74 176.94,150.43 177.09,150.28 177.26,150.28 177.41,150.13 177.41,149.82 177.26,149.67 176.29,149.67 176.16,149.55 176.16,149.19 176.29,149.06 177.26,149.06 177.41,148.91 177.41,148.59 177.29,148.47 v1(175.76,148.47) 174.71,148.47 173.22,146.98 v2(173.17,146.98)
  BOTTOM w0.089: UV1.E11 170.58,142.67 170.58,143.31 170.65,143.38 170.65,143.74 170.58,143.81 170.58,145.9 171.05,146.37
  BOTTOM w0.152: v2(173.17,146.98) 171.66,146.98 171.05,146.37
M_DA41: length 41.2
  TOP w0.152: v2(173.18,146.38) 173.2,146.38 174.88,148.06 176.81,148.06 176.99,147.88 v1(177.67,147.88) 180.23,147.88 180.38,148.03 180.38,150.06 180.54,150.22 180.84,150.22 180.99,150.06 180.99,148.03 181.15,147.88 181.45,147.88 181.6,148.03 181.6,150.06 181.76,150.22 182.06,150.22 182.21,150.06 182.21,149.62 182.34,149.49 182.72,149.49 182.85,149.62 182.85,150.7 182.72,150.83 181.04,150.83 180.92,150.95 180.92,151.36 181.04,151.49 181.86,151.49 181.98,151.61 181.98,155.17 181.32,155.83 181.32,157.79 181.45,157.92 182.96,157.92 183.09,158.05 183.09,160.73 182.96,160.86 182.65,160.86 182.52,160.73 182.52,158.49 182.4,158.36 181.73,158.36 UV7.D7
  BOTTOM w0.089: 171.05,145.76 170.89,145.6 UV1.A11
  BOTTOM w0.152: v2(173.18,146.38) 171.67,146.38 171.05,145.76
M_DA42: length 41.6
  TOP w0.152: v2(173.18,145.78) 175.05,147.65 176.64,147.65 176.82,147.47 v1(179.38,147.47) 181.98,147.47 182.13,147.63 182.13,148.96 182.26,149.09 182.62,149.09 182.74,148.96 182.74,147.63 182.9,147.47 183.2,147.47 183.35,147.63 183.35,149.52 183.48,149.64 183.84,149.64 183.96,149.52 183.96,147.63 184.11,147.47 184.42,147.47 184.57,147.63 184.57,149.28 184.7,149.4 185.05,149.4 185.18,149.28 185.18,147.63 185.33,147.47 185.71,147.47 185.83,147.6 185.83,149.86 185.71,149.98 184.41,149.98 183.16,151.23 182.54,151.23 182.39,151.38 182.39,151.72 182.54,151.87 182.71,151.87 182.86,152.02 182.86,152.33 182.71,152.48 182.54,152.48 182.39,152.63 182.39,152.94 182.54,153.09 182.71,153.09 182.86,153.24 182.86,153.55 182.71,153.7 182.54,153.7 182.39,153.85 182.39,156.11 182.26,156.23 181.84,156.23 181.72,156.11 UV7.A7
  BOTTOM w0.089: UV1.C11 170.89,143.49 171.21,143.81 171.21,145.33 171.44,145.56
  BOTTOM w0.152: 171.44,145.56 171.66,145.78 v2(173.18,145.78)
M_DA43: length 42.6
  TOP w0.152: UV7.C8 180.92,157.28 180.8,157.16 178.58,157.16 178.44,157.02 178.44,156.71 178.59,156.55 179.14,156.55 179.29,156.4 179.29,156.1 179.14,155.94 178.59,155.94 178.44,155.79 178.44,155.49 178.59,155.33 179.14,155.33 179.29,155.18 179.29,154.88 179.14,154.72 178.59,154.72 178.44,154.57 178.44,154.27 178.59,154.11 179.14,154.11 179.29,153.96 179.29,153.66 179.14,153.51 177.12,153.51 177,153.38 177,153.02 177.12,152.9 179.14,152.9 179.29,152.74 179.29,152.44 179.14,152.29 177.12,152.29 177,152.16 177,151.39 v1(175.96,150.36) 175.45,149.84 175.45,149.62 175.75,149.32 175.75,149.1 175.54,148.89 175.32,148.89 175.02,149.19 174.8,149.19 172.76,147.15 172.76,146.41 172.61,146.26 171.89,146.26 171.74,146.11 171.74,145.8 171.89,145.65 172.61,145.65 172.76,145.5 172.76,145.23 172.28,144.75 172.28,140.92 172.13,140.77 171.74,140.77 171.59,140.91 171.59,141.22 171.39,141.42 171.39,144.74 171.69,145.03 v2(171.81,145.03)
  BOTTOM w0.089: UV1.F11 171.26,141.93 171.26,143.56 171.42,143.71 171.42,144.64 v2(171.81,145.03)
M_DA44: length 41.6
  TOP w0.152: UV7.C3 184.48,157.57 183.76,156.86 183.76,156.01 184.32,155.45 184.32,154.86 184.79,154.39 184.79,152.33 185.21,151.91 189.5,151.91 189.66,151.76 189.66,150.43 189.78,150.3 190.14,150.3 190.27,150.43 190.27,151.76 190.42,151.91 190.82,151.91 190.95,151.79 190.95,149.75 190.82,149.62 189.9,149.62 189.77,149.49 189.77,147.05 190.14,146.69 190.14,145.89 189.79,145.54 v1(182.37,145.54) 176.75,145.54 174.77,143.56 v2(172.8,143.56)
  BOTTOM w0.089: v2(172.8,143.56) 172.49,143.87 UV1.A9
M_DA45: length 41.9
  TOP w0.152: UV7.C2 185.32,157.18 185.32,156.57 185.13,156.38 184.7,156.38 184.38,156.06 184.38,155.83 184.73,155.49 184.73,155.03 185.2,154.55 185.2,152.5 185.38,152.32 191.23,152.32 191.36,152.19 191.36,149.26 191.2,149.11 190.37,149.11 190.21,148.96 190.21,148.65 190.37,148.5 191.2,148.5 191.36,148.35 191.36,148.04 191.2,147.89 190.37,147.89 190.21,147.74 190.21,147.43 190.37,147.28 190.42,147.28 190.54,147.15 190.54,145.26 190.42,145.14 v1(184.84,145.14) 176.87,145.14 174.91,143.18 174.21,143.18 174.02,142.98 174.02,142.93 173.74,142.66 172.9,142.66 v2(172.8,142.76)
  BOTTOM w0.089: v2(172.8,142.76) 172.49,143.07 UV1.C9
M_DA46: length 41.8
  TOP w0.152: v2(172.93,142.09) 173.21,142.37 174.15,142.37 174.16,142.36 174.99,142.36 175.81,143.18 178.37,143.18 179.51,144.32 v1(189.99,144.32) 192.88,144.32 193.01,144.45 193.01,147.04 192.86,147.2 192.32,147.2 192.17,147.35 192.17,147.65 192.32,147.8 192.86,147.8 193.01,147.96 193.01,148.26 192.86,148.41 192.32,148.41 192.17,148.57 192.17,148.87 192.32,149.02 192.86,149.02 193.01,149.18 193.01,149.48 192.86,149.63 192.3,149.63 192.17,149.76 192.17,153.01 192.04,153.13 187.99,153.13 187.86,153.26 187.86,154.03 186.78,155.12 186.57,155.12 UV7.A2
  BOTTOM w0.089: v2(172.93,142.09) 172.49,141.65 UV1.F9
M_DA47: length 41.1
  TOP w0.152: v2(174.39,142.77) 174.97,142.77 175.82,143.62 177.03,143.62 178.14,144.73 v1(187.32,144.73) 192.45,144.73 192.58,144.86 192.58,145.39 192.45,145.51 191.12,145.51 190.96,145.67 190.96,145.97 191.12,146.12 192.41,146.12 192.54,146.25 192.54,146.6 192.41,146.73 191.56,146.73 191.43,146.86 191.43,147.21 191.56,147.34 191.61,147.34 191.76,147.49 191.76,152.6 191.64,152.73 187.58,152.73 187.46,152.85 187.46,153.86 186.72,154.6 185.73,154.6 185.13,155.19 185.13,155.76 UV7.A3
  BOTTOM w0.089: v2(174.39,142.77) 174.34,142.72 173.33,142.72 UV1.D8
M_DA48: length 37.7
  IN1 w0.102: 173.67,145.56 173.91,145.32 173.91,144.12 173.2,143.41 173.2,142.74 173.58,142.35 v2(173.58,141.96)
  IN1 w0.165: 173.67,145.56 173.67,149.17 177.76,153.26 177.76,153.86 177.93,154.02 178.47,154.02 178.63,154.19 178.63,154.52 178.47,154.68 177.93,154.68 177.76,154.85 177.76,155.18 177.93,155.34 178.47,155.34 178.63,155.51 178.63,155.84 178.47,156 177.93,156 177.76,156.17 177.76,156.5 177.93,156.66 178.47,156.66 178.63,156.83 178.63,157.16 178.47,157.32 177.93,157.32 177.76,157.49 177.76,157.82 177.93,157.98 178.47,157.98 178.63,158.15 178.63,158.48 178.47,158.65 177.93,158.65 177.76,158.81 177.76,159.14 177.93,159.31 178.2,159.31 178.33,159.43 178.33,159.84 178.2,159.97 177.75,159.97 177.63,160.09 177.63,160.57 177.75,160.7 178.89,160.7 179.02,160.83 179.02,161.24 178.85,161.41 177.93,161.41 177.77,161.57 177.77,161.9 177.93,162.07 178.85,162.07 179.02,162.23 179.02,163.1 179.15,163.23 179.72,163.23 179.85,163.1 179.85,161.54 180.02,161.38 180.31,161.38 v2(180.52,161.17)
  BOTTOM w0.089: v2(173.58,141.96) 173.98,142.36 UV1.E7
  BOTTOM w0.102: UV8.G2 v2(180.52,161.17)
M_DA49: length 37.8
  IN1 w0.165: v2(174.69,144.83) 175.04,144.83 175.16,144.96 175.16,146.67 175.29,146.8 181.87,146.8 182,146.92 182,147.43 181.83,147.6 180.78,147.6 180.61,147.76 180.61,148.09 180.78,148.26 181.83,148.26 182,148.42 182,148.75 181.83,148.92 180.78,148.92 180.61,149.08 180.61,149.41 180.78,149.58 181.83,149.58 182,149.74 182,150.07 181.83,150.24 180.78,150.24 180.61,150.4 180.61,150.73 180.78,150.9 181.83,150.9 182,151.06 182,151.39 181.83,151.56 180.78,151.56 180.61,151.72 180.61,152.05 180.78,152.22 181.83,152.22 182,152.39 182,153.06 181.83,153.22 181.02,153.22 180.85,153.39 180.85,153.72 181.02,153.88 181.83,153.88 182,154.05 182,154.69 181.87,154.81 180.73,154.81 180.6,154.94 180.6,155.73 180.77,155.89 181.54,155.89 181.7,156.06 181.7,156.39 181.54,156.55 180.77,156.55 180.6,156.72 180.6,157.15 180.73,157.28 181.19,157.28 181.32,157.4 v2(181.32,158.77)
  BOTTOM w0.089: UV1.A7 174.09,144.05 174.69,144.65 v2(174.69,144.83)
  BOTTOM w0.102: UV8.E3 v2(181.32,158.77)
M_DA50: length 38
  IN1 w0.102: 180.13,155.24 180.13,159 180.31,159.18 180.68,159.18 180.92,159.42 180.92,160.59 181.11,160.78 182.01,160.78 v2(182.2,160.98)
  IN1 w0.165: v2(174.67,145.45) 174.67,147.14 174.79,147.27 180,147.27 180.13,147.39 180.13,147.85 179.97,148.02 179.19,148.02 179.06,148.15 179.06,148.55 179.19,148.68 179.97,148.68 180.13,148.85 180.13,149.18 179.97,149.34 177.56,149.34 177.4,149.51 177.4,149.84 177.56,150 179.97,150 180.13,150.17 180.13,150.5 179.97,150.66 177.56,150.66 177.4,150.83 177.4,151.16 177.56,151.32 179.97,151.32 180.13,151.49 180.13,155.24
  BOTTOM w0.089: UV1.C7 174.09,143.4 173.73,143.76 173.73,144.04 174.31,144.63 174.31,145.16 174.6,145.45 v2(174.67,145.45)
  BOTTOM w0.102: UV8.H3 182.2,161.09 v2(182.2,160.98)
M_DA51: length 38.2
  IN1 w0.102: v2(173.74,141.16) 173.98,141.41 173.98,143.17 174.14,143.32 174.14,145.56 ; v2(180.52,159.57) 180.41,159.57 180,159.16 179.51,159.16
  IN1 w0.165: 174.14,145.56 174.14,148.97 174.26,149.1 174.73,149.1 174.86,148.97 174.86,147.86 174.99,147.74 175.42,147.74 175.59,147.9 175.59,150.43 175.72,150.55 176.12,150.55 176.25,150.43 176.25,147.9 176.41,147.74 178.47,147.74 178.59,147.86 178.59,148.29 178.47,148.41 177.04,148.41 176.91,148.54 176.91,151.75 177.4,152.23 177.68,152.23 178.04,151.87 179,151.87 179.13,152 179.13,152.43 178.96,152.59 178.39,152.59 178.23,152.76 178.23,153.09 178.39,153.25 178.96,153.25 179.13,153.42 179.13,158.9 179.38,159.16 179.51,159.16
  BOTTOM w0.089: v2(173.74,141.16) 174.09,141.51 UV1.F7
  BOTTOM w0.102: UV8.F2 v2(180.52,159.57)
M_DA52: length 36.8
  IN1 w0.165: v2(183.51,160.8) 183.51,158.86 185.14,157.23 185.14,156.37 184.98,156.21 184.42,156.21 184.3,156.08 184.3,155.67 184.42,155.55 184.98,155.55 185.14,155.38 185.14,154.64 186.01,153.77 186.01,152.34 186.18,152.17 187.03,152.17 187.19,152.01 187.19,151.68 187.03,151.51 186.18,151.51 186.01,151.35 186.01,151.02 186.18,150.85 187.03,150.85 187.19,150.69 187.19,150.36 187.03,150.19 186.18,150.19 186.01,150.03 186.01,149.7 186.18,149.53 187.03,149.53 187.19,149.37 187.19,149.04 187.03,148.87 186.18,148.87 186.01,148.71 186.01,144.67 185.88,144.55 177,144.55 v2(176.88,144.42)
  BOTTOM w0.089: v2(176.88,144.42) 176.85,144.4 176.13,144.4 UV1.A5
  BOTTOM w0.102: UV8.H7 184.28,161.57 v2(183.51,160.8)
M_DA53: length 37.8
  IN1 w0.165: v2(175.21,142.01) 176.05,142.01 176.47,142.43 176.47,143.41 177.14,144.08 187.47,144.08 187.67,144.28 187.67,144.91 187.5,145.07 186.66,145.07 186.49,145.24 186.49,145.57 186.66,145.73 187.5,145.73 187.67,145.9 187.67,146.23 187.5,146.39 186.66,146.39 186.49,146.56 186.49,146.89 186.66,147.05 187.5,147.05 187.67,147.22 187.67,147.55 187.5,147.71 186.66,147.71 186.49,147.88 186.49,148.21 186.66,148.37 187.5,148.37 187.67,148.54 187.67,153.07 186.19,154.55 186.19,157.1 184.35,158.94 v2(184.35,158.98)
  BOTTOM w0.089: UV1.E5 175.55,142.36 v2(175.21,142.01)
  BOTTOM w0.102: UV8.F7 184.92,159.64 184.35,159.07 v2(184.35,158.98)
M_DA54: length 37.1
  IN1 w0.102: 187.13,159.99 186.53,159.99 v2(186.12,159.57)
  IN1 w0.165: v2(176.93,142.72) 177.44,143.24 189.2,143.24 189.33,143.36 189.33,143.83 189.17,144 188.33,144 188.17,144.16 188.17,144.49 188.33,144.66 189.17,144.66 189.33,144.82 189.33,145.15 189.17,145.32 188.33,145.32 188.17,145.48 188.17,145.81 188.33,145.98 189.17,145.98 189.33,146.14 189.33,146.47 189.17,146.64 188.33,146.64 188.17,146.8 188.17,153.24 187.55,153.86 187.55,159.77 187.33,159.99 187.13,159.99
  BOTTOM w0.089: UV1.C3 176.93,142.72 v2(176.93,142.72)
  BOTTOM w0.102: UV8.F8 v2(186.12,159.57)
M_DA55: length 36.9
  IN1 w0.102: 187.13,160.79 186.5,160.79 v2(186.12,161.17)
  IN1 w0.165: 187.13,160.79 187.33,160.79 188.66,159.46 188.66,149.97 188.83,149.8 189.41,149.8 189.54,149.68 189.54,149.27 189.41,149.14 188.83,149.14 188.66,148.98 188.66,148.65 188.83,148.48 189.48,148.48 189.6,148.36 189.6,147.95 189.48,147.82 188.83,147.82 188.66,147.66 188.66,147.33 188.83,147.16 189.64,147.16 189.8,147 189.8,143.17 189.4,142.77 v2(177.73,142.77)
  BOTTOM w0.089: v2(177.73,142.77) 177.32,142.36 UV1.E1
  BOTTOM w0.102: UV8.H8 186.12,161.17 v2(186.12,161.17)
M_DA56: length 42.6
  BOTTOM w0.089: 177.77,144.22 178.16,143.83 178.16,142.64 177.88,142.35 177.75,142.35 177.46,142.06 175.86,142.06 174.97,141.17 174.5,141.17 UV1.G7
  BOTTOM w0.152: 177.77,144.22 177.77,144.94 174.9,147.82 171.09,147.82 170.25,148.66 170.25,153.63 170.12,153.76 168.76,153.76 168.64,153.89 168.64,154.25 168.76,154.38 170.88,154.38 171.01,154.51 171.01,154.86 170.88,154.99 168.79,154.99 168.66,155.12 168.66,155.56 168.79,155.69 v1(171.19,155.69) 171.97,155.69 172.67,156.39 178.37,156.39 178.5,156.51 178.5,157.06 178.63,157.19 180.53,157.19 UV8.C2
M_DA57: length 41.9
  BOTTOM w0.089: 178.17,144.36 178.17,144.07 178.34,143.9 178.34,142.56 177.95,142.18 177.83,142.18 177.54,141.89 175.94,141.89 174.89,140.84 UV1.G6
  BOTTOM w0.152: UV8.A2 180.62,155.97 179.58,154.93 179.58,154.1 179.46,153.97 179.06,153.97 178.94,154.1 178.94,155.85 178.81,155.98 174.08,155.98 173.93,155.83 173.93,154.1 173.8,153.97 173.44,153.97 173.32,154.1 173.32,155.85 173.19,155.98 172.83,155.98 172.71,155.85 v1(172.71,155.07) 172.71,154.1 172.58,153.97 172.19,153.97 172.04,154.12 172.04,154.98 171.91,155.11 171.56,155.11 171.43,154.98 171.43,154.12 171.28,153.97 170.78,153.97 170.66,153.85 170.66,148.82 171.26,148.22 175.07,148.22 178.17,145.11 178.17,144.36
M_DA58: length 40.8
  BOTTOM w0.089: UV1.G1 177.75,141.22 177.97,141.22 178.26,141.52 178.26,142.1
  BOTTOM w0.152: UV8.A3 181.98,155.71 181.98,152.57 181.73,152.32 180.55,152.32 179.31,153.57 176.39,153.57 176.24,153.72 176.24,155.38 176.08,155.54 175.78,155.54 175.63,155.38 175.63,153.72 175.48,153.57 175.17,153.57 175.02,153.72 175.02,155.38 174.87,155.54 174.56,155.54 174.41,155.38 174.41,153.72 174.26,153.57 v1(173.16,153.57) 171.43,153.57 171.06,153.2 171.06,148.99 171.43,148.63 175.23,148.63 178.58,145.28 178.58,142.42 178.26,142.1
M_DA59: length 40.9
  BOTTOM w0.089: UV1.G3 176.81,140.44 177.41,140.44 177.96,140.98 178.19,140.98 178.82,141.62 178.82,141.81
  BOTTOM w0.152: 178.82,141.81 178.99,141.98 178.99,145.45 175.4,149.03 174.16,149.03 174,149.19 174,149.78 173.85,149.94 173.55,149.94 173.39,149.78 173.39,149.19 173.24,149.03 172.94,149.03 172.78,149.19 172.78,149.78 172.63,149.94 172.33,149.94 172.17,149.78 172.17,149.19 172.02,149.03 171.6,149.03 171.47,149.16 171.47,153.03 171.6,153.16 v1(175,153.16) 179.14,153.16 180.38,151.91 181.9,151.91 182.71,152.73 182.71,153.1 182.56,153.26 182.54,153.26 182.39,153.41 182.39,153.71 182.54,153.87 182.56,153.87 182.71,154.02 182.71,154.32 182.56,154.48 182.54,154.48 182.39,154.63 182.39,154.93 182.54,155.09 182.56,155.09 182.71,155.24 182.71,157.07 182.21,157.57 UV8.C3
M_DA60: length 42
  BOTTOM w0.089: UV1.J6 175.23,139.5 175.84,139.5 176.12,139.22 176.12,139.04 176.47,138.68 178.17,138.68 178.49,139 179.18,139 179.6,139.42
  BOTTOM w0.152: UV8.D7 185.3,157.99 185.3,157.31 185.46,157.15 185.87,157.15 186.11,156.91 186.11,155.21 187.31,154.01 187.31,152.45 187.18,152.32 185.58,152.32 185.45,152.19 185.45,151.84 185.6,151.69 187.15,151.69 187.31,151.54 187.31,151.23 187.15,151.08 v1(186.11,151.08) 185.6,151.08 185.45,150.93 185.45,150.62 185.6,150.47 185.86,150.47 185.98,150.34 185.98,149.99 185.86,149.86 185.6,149.86 185.45,149.71 185.45,145.4 185.3,145.25 182.62,145.25 182.47,145.1 182.47,144.79 182.62,144.64 185.3,144.64 185.45,144.49 185.45,144.11 185.32,143.98 181.87,143.98 181.74,143.85 181.74,140.87 180.3,139.42 179.6,139.42
M_DA61: length 40.8
  BOTTOM w0.089: UV1.J1 178.12,139.16 178.32,139.36 178.88,139.36 179.23,139.71 179.23,139.86 179.6,140.24
  BOTTOM w0.152: 179.6,140.24 179.96,140.24 180.93,141.21 180.93,146.64 180.78,146.8 180.37,146.8 180.25,146.92 180.25,147.28 180.37,147.41 182.57,147.41 182.7,147.53 182.7,147.89 182.57,148.01 179.15,148.01 179.03,148.14 179.03,148.5 179.15,148.62 182.66,148.62 182.78,148.75 182.78,149.2 182.66,149.32 178.21,149.32 178.08,149.45 178.08,149.86 178.21,149.98 v1(179.57,149.98) 182.7,149.98 184.64,151.93 184.64,155.45 184.54,155.55 184.54,156.15 184.81,156.42 185.37,156.42 UV8.B8
M_DA62: length 41.6
  BOTTOM w0.089: UV1.J3 176.86,139.16 177.16,138.86 178.07,138.86 178.39,139.18 178.96,139.18 179.6,139.83
  BOTTOM w0.152: UV8.A7 185.05,155.85 185.05,150.85 184.89,150.69 183.98,150.69 183.86,150.57 183.86,150.21 183.98,150.08 184.89,150.08 185.05,149.93 185.05,149.63 184.89,149.48 v1(183.76,149.48) 183.32,149.48 183.19,149.35 183.19,148.99 183.32,148.87 184.89,148.87 185.05,148.71 185.05,148.41 184.89,148.26 183.23,148.26 183.1,148.13 183.1,147.77 183.23,147.65 184.89,147.65 185.05,147.49 185.05,147.13 184.92,147 181.46,147 181.34,146.87 181.34,146.49 181.49,146.34 184.89,146.34 185.05,146.19 185.05,145.88 184.89,145.73 181.49,145.73 181.34,145.58 181.34,145.27 181.49,145.12 181.93,145.12 182.06,144.99 182.06,144.64 181.93,144.51 181.49,144.51 181.34,144.36 181.34,141.04 180.13,139.83 179.6,139.83
M_DA63: length 41.6
  BOTTOM w0.089: UV1.J5 175.73,139.16 176.51,138.38 176.51,138.24 176.71,138.04 177.5,138.04 177.72,137.82 178.08,137.82 178.3,138.04 178.3,138.55 178.58,138.83 179.41,138.83 179.6,139.02
  BOTTOM w0.152: 179.6,139.02 180.47,139.02 182.15,140.7 182.15,143.45 182.28,143.57 182.67,143.57 182.83,143.42 182.83,142.15 182.95,142.02 183.31,142.02 183.44,142.15 183.44,143.42 183.59,143.57 183.89,143.57 184.05,143.42 184.05,142.94 184.2,142.79 184.5,142.79 184.66,142.94 184.66,143.42 184.81,143.57 185.73,143.57 185.86,143.7 185.86,148.01 185.98,148.13 187.59,148.13 187.71,148.26 187.71,148.63 187.56,148.78 v1(186.75,148.78) 185.98,148.78 185.86,148.91 185.86,149.26 185.98,149.39 187.56,149.39 187.71,149.54 187.71,149.85 187.56,150 186.56,150 186.4,150.15 186.4,150.46 186.56,150.61 187.56,150.61 187.71,150.76 187.71,154.18 187.24,154.65 187.24,156.71 186.76,157.19 186.32,157.19 185.93,157.57 UV8.C8
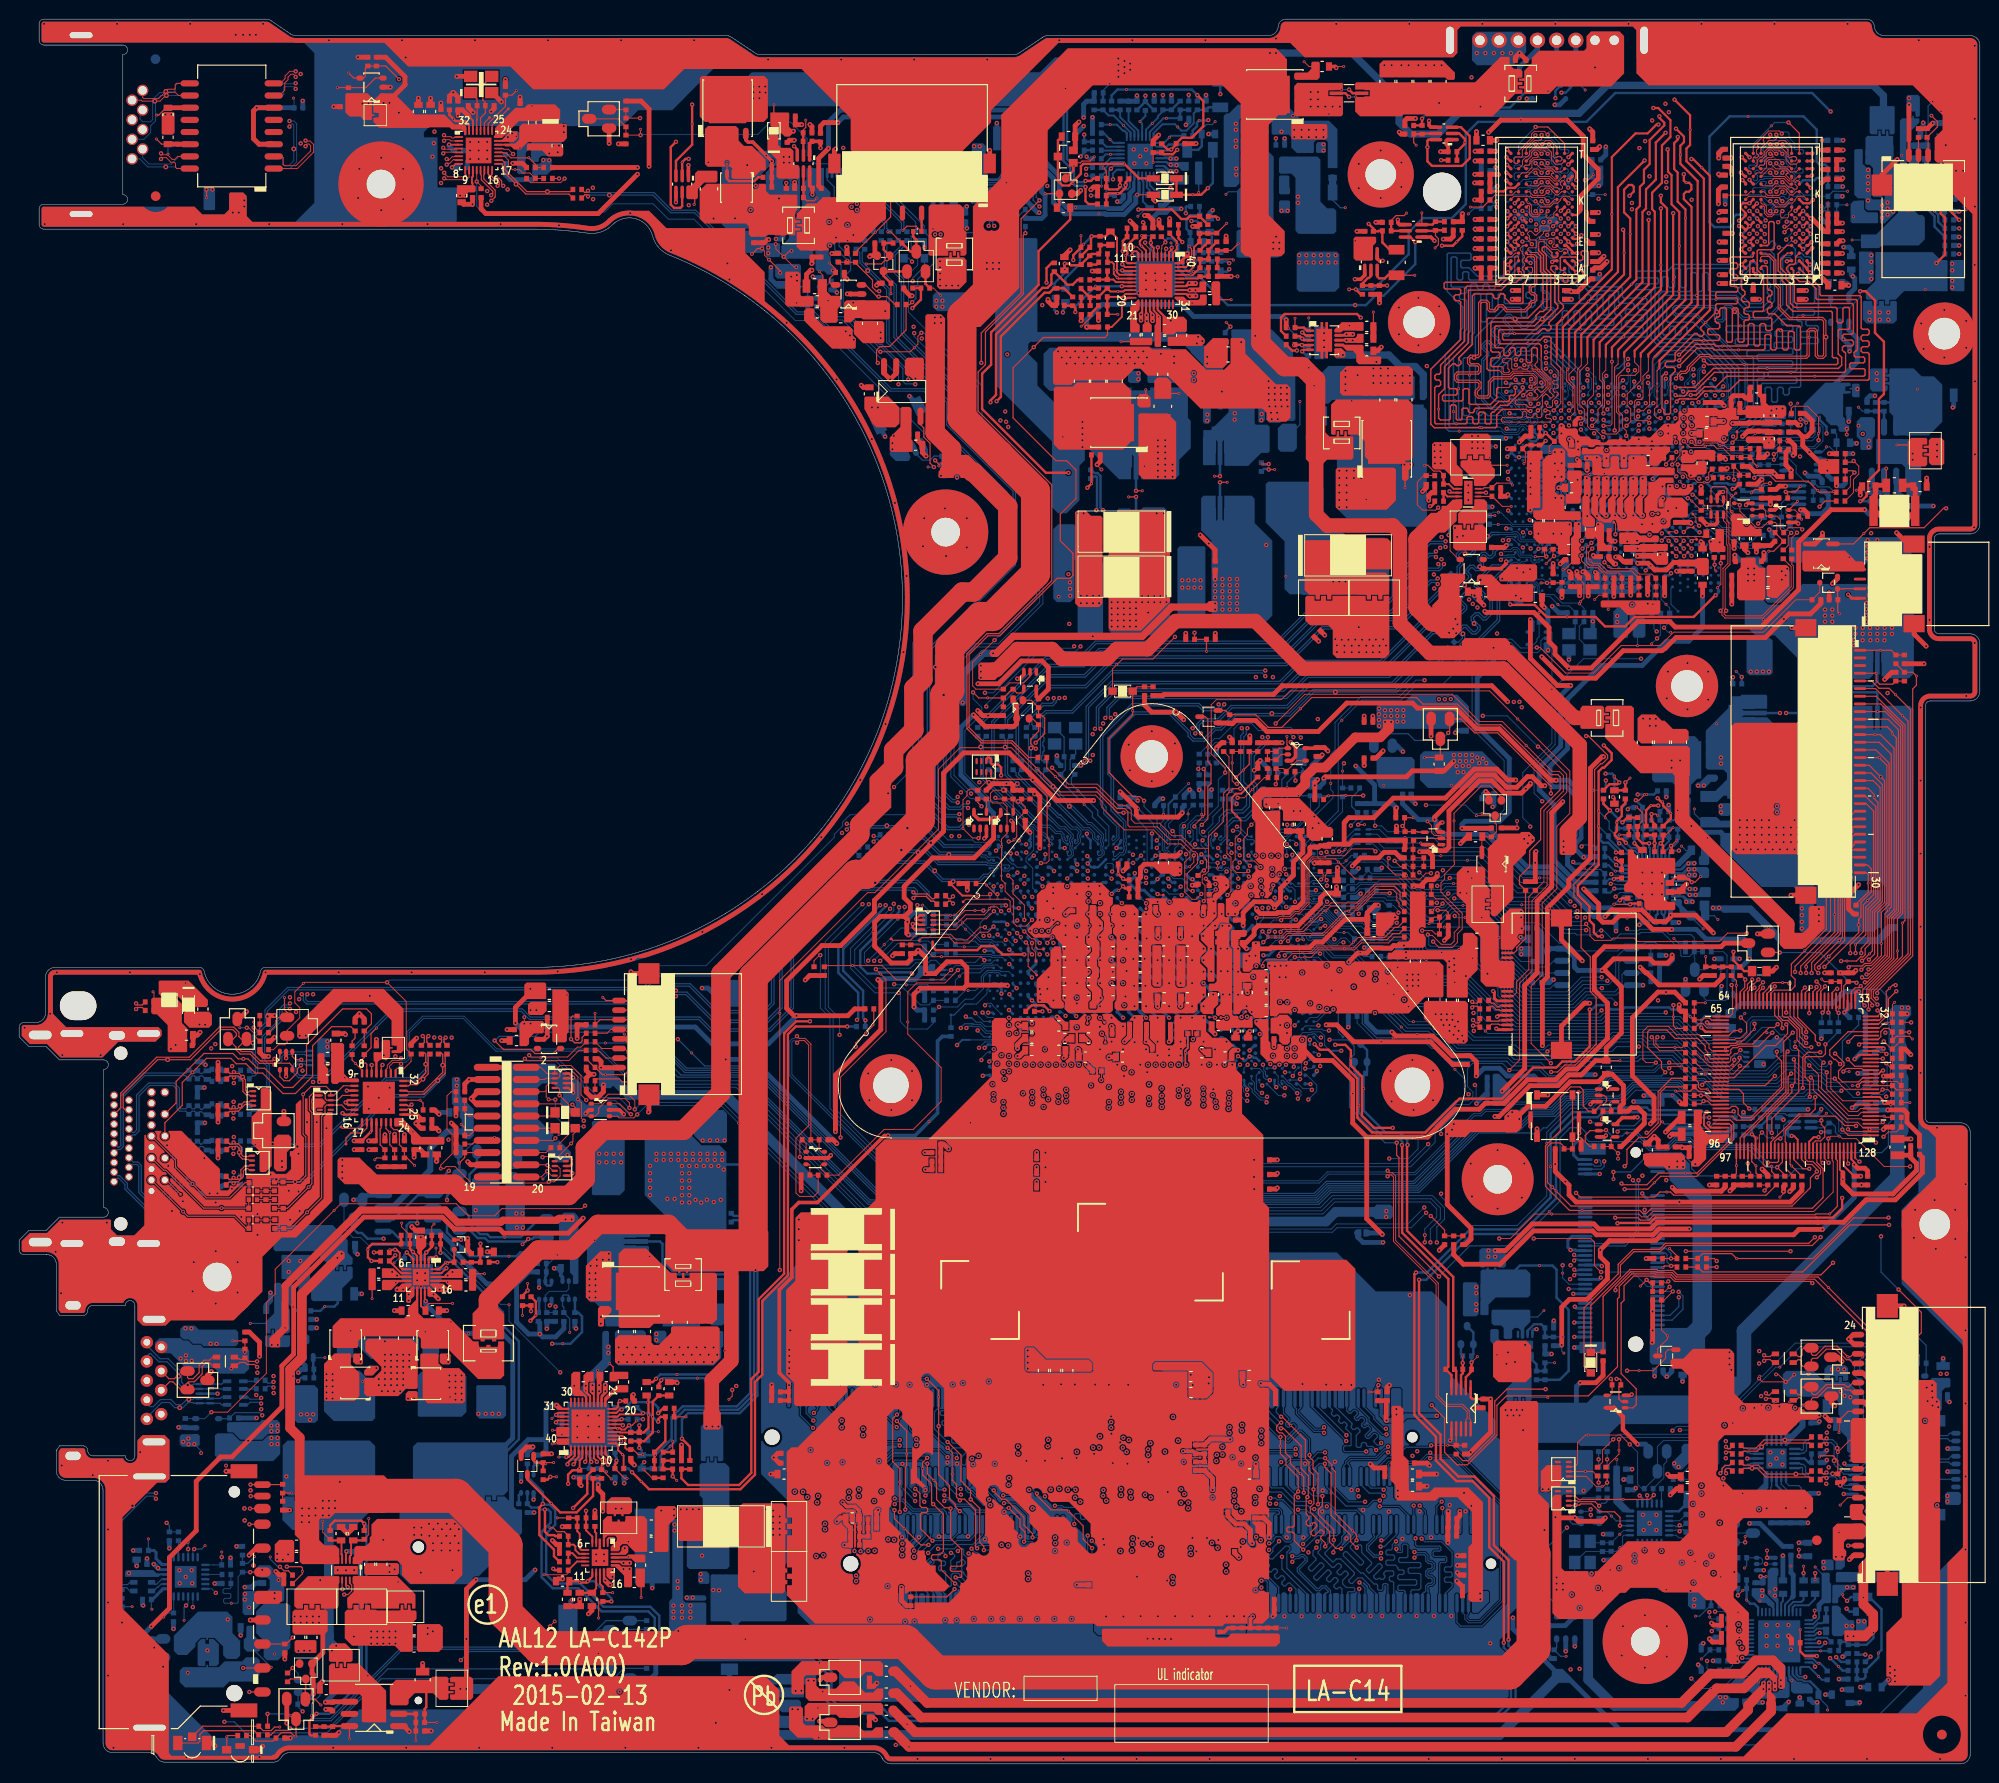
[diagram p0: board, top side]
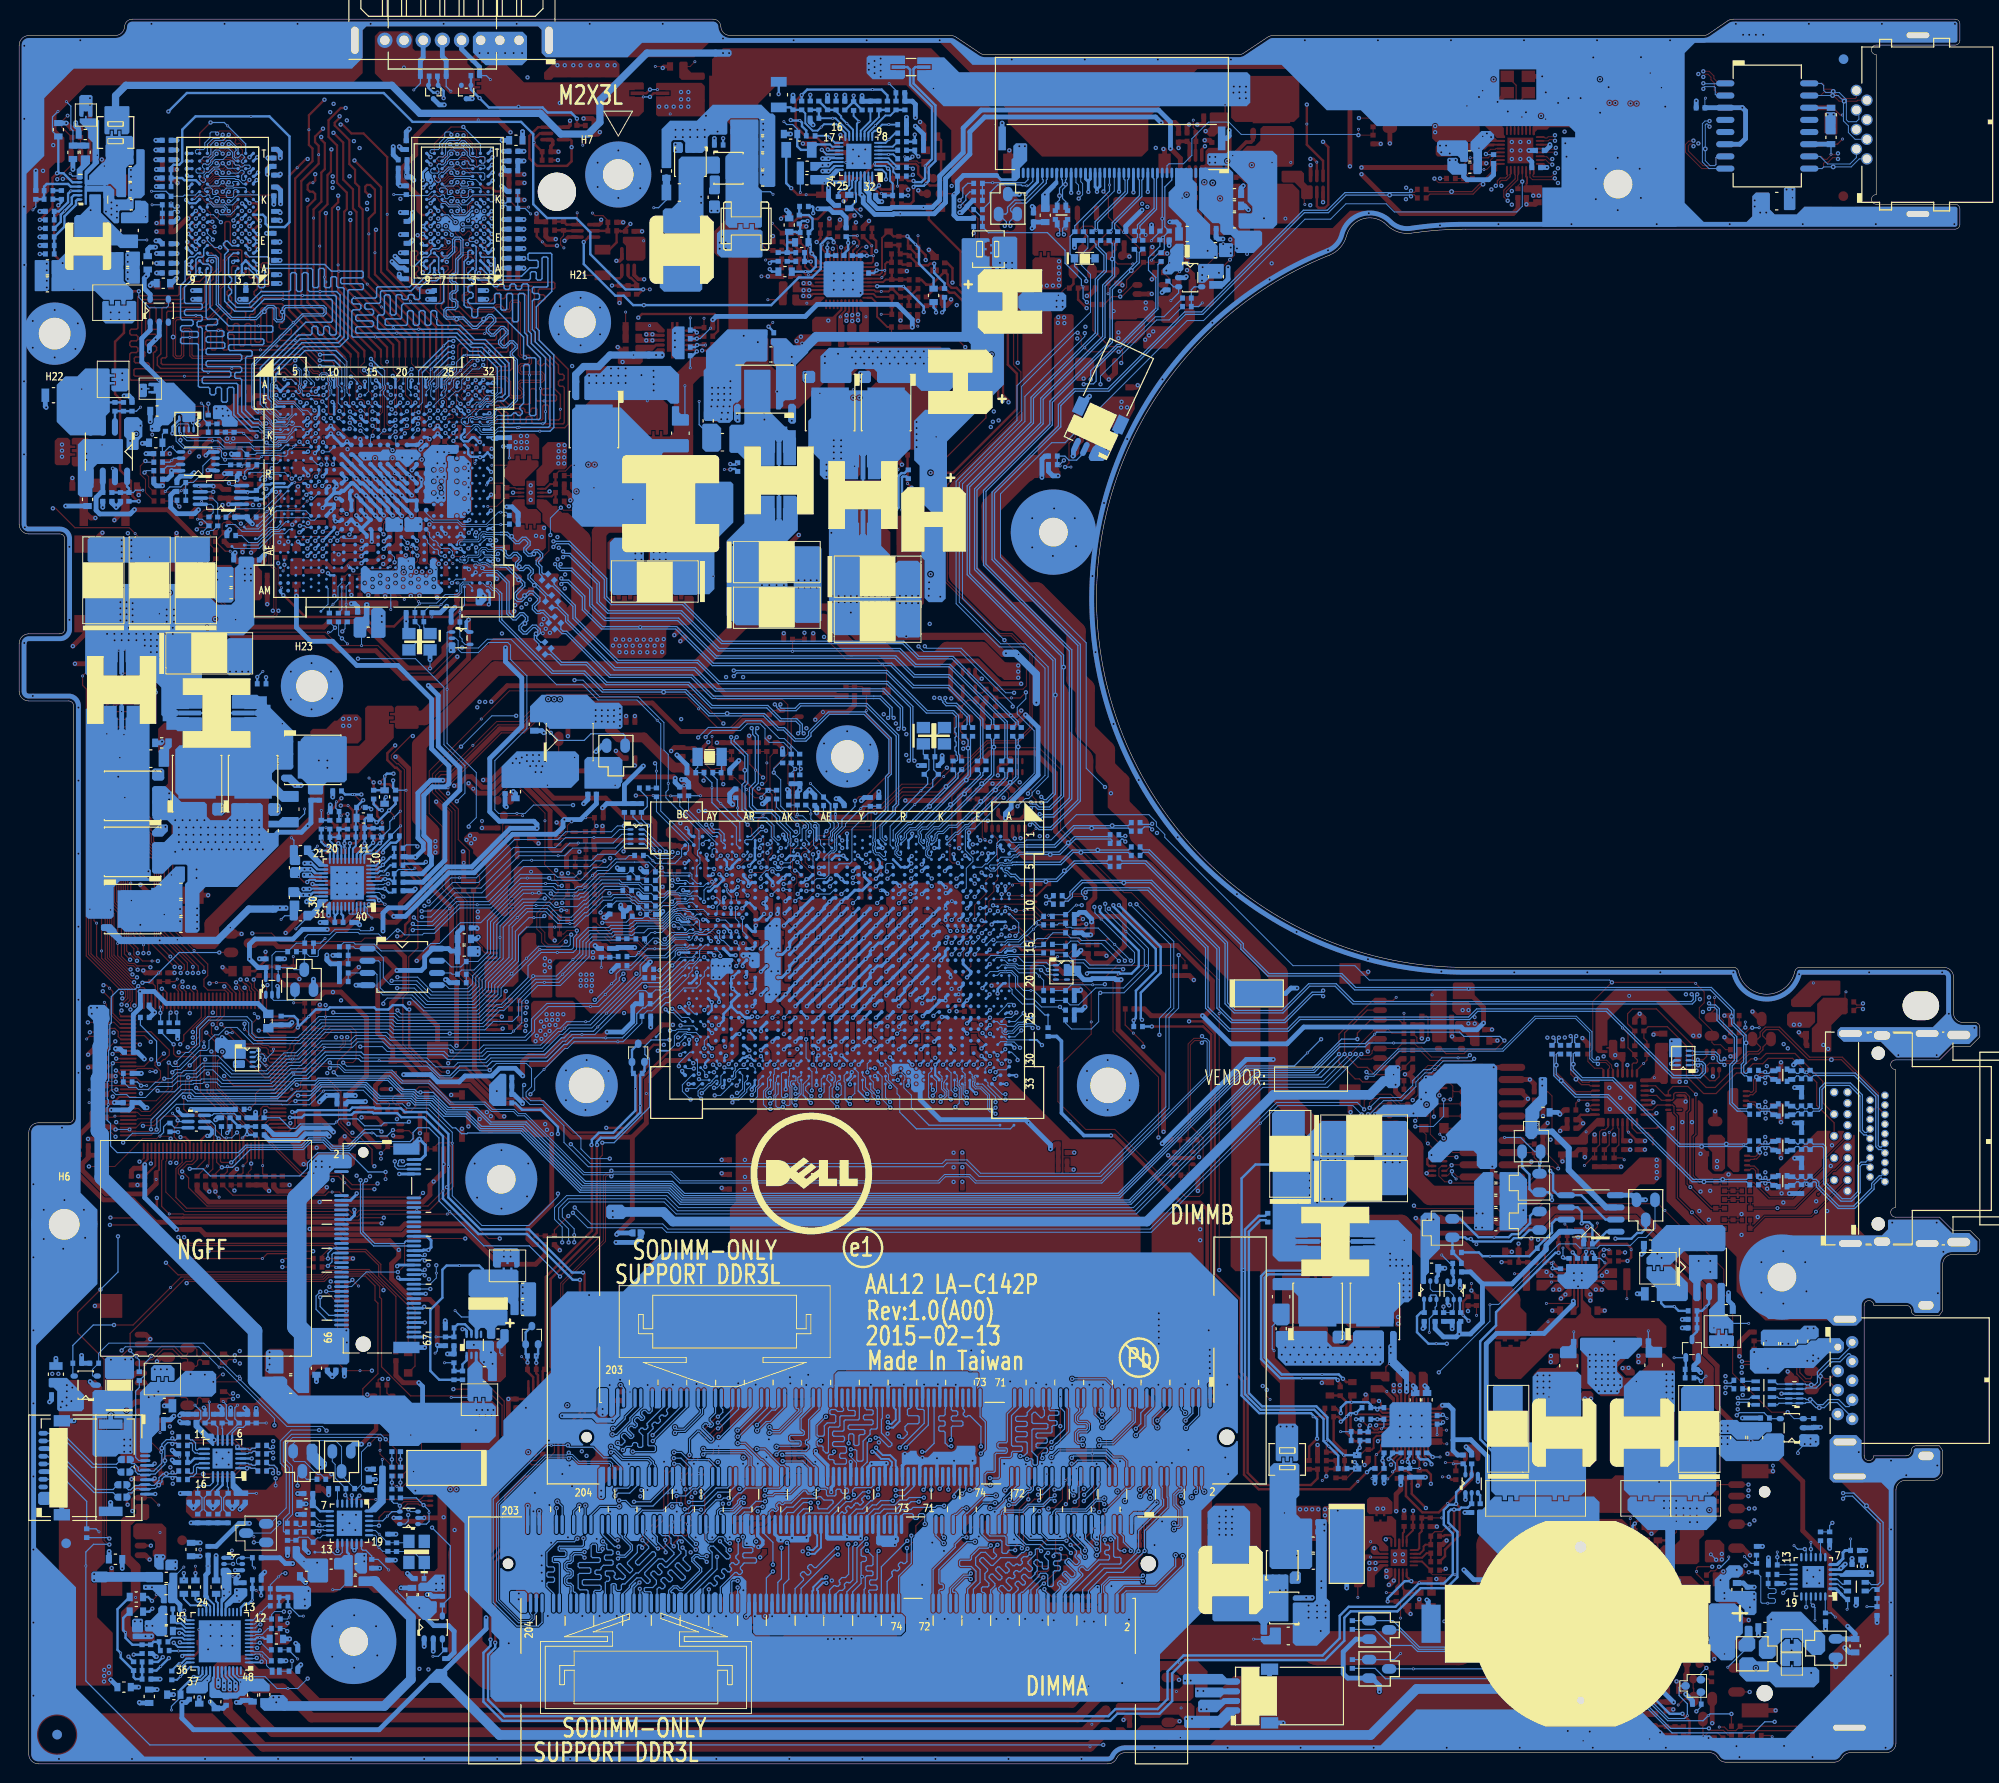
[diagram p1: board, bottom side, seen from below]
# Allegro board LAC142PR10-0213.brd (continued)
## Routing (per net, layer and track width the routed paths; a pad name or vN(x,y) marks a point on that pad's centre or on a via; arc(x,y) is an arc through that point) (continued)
M_DQM0: length 39.8
  BOTTOM w0.089: 154.33,139.81 154.87,139.81 154.95,139.73 155.25,139.73 155.51,139.47 156.42,139.47 156.65,139.7 157.13,139.7 157.36,139.47 157.96,139.47 158.16,139.67 158.21,139.67 158.38,139.84 158.38,139.89 158.44,139.95 158.44,140.21 158.29,140.36 157.95,140.36 157.6,140.71 157.51,140.71 156.89,141.33 156.89,141.6 156.64,141.85 156.35,141.85 155.83,142.36 UV1.E32
  BOTTOM w0.152: 154.33,139.81 149.79,139.81 149.64,139.96 v1(149.64,141.03) 149.64,146.67 151.11,148.14 151.11,149.14 151.42,149.45 151.42,154.22 151.55,154.35 151.98,154.35 152.13,154.2 152.13,153.94 152.28,153.78 152.59,153.78 152.74,153.94 152.74,154.2 152.89,154.35 153.2,154.35 153.35,154.2 153.35,153.94 153.5,153.78 153.81,153.78 153.96,153.94 153.96,154.2 154.11,154.35 154.39,154.35 154.67,154.08 154.99,154.08 155.67,154.76 156.66,154.76 156.99,155.09 156.99,155.71 156.88,155.83 156.88,158.23 157.02,158.37 UV5.D3
M_DQM1: length 40.5
  TOP w0.102: 158.51,157.48 158.36,157.63 157.65,157.63 157.41,157.87 157.41,158.04 157.5,158.12 158.22,158.12 158.31,158.22 158.31,158.81 158.18,158.94 157.69,158.94 157.57,159.05 157.57,159.33 157.37,159.54 157.37,159.66 157.58,159.87 157.73,159.87 158.15,159.45 158.28,159.45 158.65,159.82 158.65,160.31 158.76,160.42 159.48,160.42 159.68,160.21 159.68,160.01 159.56,159.88 159.12,159.88 159.03,159.79 159.03,159.64 158.62,159.22 158.62,159.05 158.71,158.97 159.44,158.97 159.59,159.12 160.04,159.12 160.13,159.02 160.13,158.54 159.95,158.36 159.95,158.25 160.04,158.17 160.32,158.17 160.43,158.28 UV6.D3 ; v2(156.91,142.74) 157.43,143.26 157.83,143.26 158.16,143.59 158.95,143.59 159.2,143.84 159.2,144.2 158.14,145.26 155.83,145.26 155.46,144.9 154.85,144.9 154.42,145.33
  TOP w0.152: 158.51,157.48 158.72,157.28 158.72,155.68 158.97,155.42 158.97,152.37 157.4,150.8 v1(156,150.8) 153.26,150.8 153.13,150.67 153.13,145.52 153.32,145.33 154.42,145.33
  BOTTOM w0.089: v2(156.91,142.74) 156.54,142.36 UV1.E30
M_DQM2: length 38.5
  IN1 w0.102: v2(159.75,158.71) 159.58,158.71 158.65,159.64 158.47,159.64 158.34,159.52 158.34,159.34 158.83,158.85 158.83,158.51 158.94,158.41 159.16,158.41 159.29,158.28 159.29,158.06 159.19,157.95 158.87,157.95 158.77,157.85 158.77,157.65 158.87,157.55 159.19,157.55 159.29,157.45 159.29,157.24 159.19,157.14 158.87,157.14 158.77,157.04 158.77,156.84 158.87,156.74 159.19,156.74 159.29,156.63 159.29,156.26 158.27,155.24
  IN1 w0.165: v2(159.25,148.41) 159.25,149.31 159.13,149.43 152.18,149.43 152.06,149.56 152.06,153.14 152.18,153.26 153.19,153.26 153.36,153.43 153.36,154.01 153.52,154.18 153.85,154.18 154.02,154.01 154.02,153.43 154.18,153.26 154.61,153.26 154.77,153.43 154.77,154.02 154.94,154.18 156.95,154.18 157.08,154.06 157.08,153.39 157.21,153.26 157.77,153.26 157.9,153.39 157.9,154.87 158.27,155.24
  BOTTOM w0.089: UV1.A21 162.89,145.28
  BOTTOM w0.102: UV5.E7 160.22,159.17 v2(159.75,158.71)
  BOTTOM w0.152: 162.89,145.28 v1(160.27,147.89) 159.76,148.41 v2(159.25,148.41)
M_DQM3: length 39.4
  TOP w0.102: v2(157.82,158.51) 157.23,159.1 UV6.E7
  IN2 w0.165: v2(157.82,158.51) 157.82,157.26 157.22,156.66 157.22,155.76 157.38,155.6 157.94,155.6 158.11,155.43 158.11,155.1 157.94,154.94 155.04,154.94 154.92,154.81 154.92,154.41 155.04,154.28 157.94,154.28 158.11,154.11 158.11,153.78 157.94,153.62 156.27,153.62 156.14,153.49 156.14,153.08 156.27,152.96 157.94,152.96 158.11,152.79 158.11,152.46 157.94,152.3 157.38,152.3 157.22,152.13 157.22,151.8 157.38,151.64 158.6,151.64 158.73,151.51 158.73,151.1 158.6,150.98 157.38,150.98 157.22,150.81 157.22,150.46 157.37,150.3 159.53,150.3 159.68,150.46 159.68,151.34 159.81,151.47 160.46,151.47 160.58,151.34 160.58,149.66 161.61,148.63 161.85,148.63 162.28,149.05 162.51,149.05 162.74,148.82 162.74,148.59 162.32,148.16 162.32,147.93 164.07,146.17 164.07,143.76 163.87,143.56 v2(163.18,143.56)
  BOTTOM w0.089: v2(163.18,143.56) 162.89,143.27 UV1.C21
M_DQM4: length 39.7
  TOP w0.102: UV7.E7 181.72,159.17 v2(182.12,158.77)
  IN2 w0.102: v2(168.98,142.73) 168.98,142.77 168.62,143.13 168.39,143.13 167.61,142.34 167.2,142.34 166.9,142.63 166.9,144.48 167.15,144.73 167.65,144.73 167.89,144.97 168.92,144.97 169.21,145.27 169.21,145.49
  IN2 w0.165: v2(182.12,158.77) 182.12,157.43 181.74,157.06 181.74,155.17 181.32,154.75 180.59,154.75 180.46,154.62 179.84,154.62 179.71,154.5 179.71,154.01 179.84,153.89 180.33,153.89 180.46,153.76 180.46,152.05 180.33,151.92 179.83,151.92 179.66,152.09 179.66,153.12 179.49,153.29 179.16,153.29 179,153.12 179,152.09 178.83,151.92 178.5,151.92 178.34,152.09 178.34,153.12 178.17,153.29 176.79,153.29 176.62,153.45 176.62,153.84 176.46,154 176.13,154 175.96,153.84 175.96,153.51 175.8,153.35 175.44,153.35 174.51,152.42 174.28,152.42 174,152.69 173.77,152.69 173.54,152.46 173.54,152.23 173.81,151.95 173.81,151.72 173.18,151.08 172.95,151.08 172.67,151.36 172.44,151.36 172.2,151.13 172.2,150.89 172.48,150.62 172.48,150.38 169.78,147.68 169.78,146.06 169.21,145.49
  BOTTOM w0.089: v2(168.98,142.73) 168.98,142.73 169.29,142.42 UV1.E13
M_DQM5: length 42.5
  TOP w0.152: UV7.D3 184.41,158.37 183.51,157.47 183.51,155.73 183.91,155.32 183.91,154.69 184.39,154.22 184.39,152.16 185.04,151.51 189.03,151.51 189.16,151.38 189.16,146.77 189.29,146.65 189.6,146.65 189.73,146.52 189.73,146.08 189.6,145.95 v1(179.95,145.95) 176.19,145.95 v2(175.76,146.38)
  BOTTOM w0.089: 170.84,146.75 170.35,146.27 170.35,143.73 170.42,143.66 170.42,143.46 170.35,143.38 170.35,143.02 UV1.D12
  BOTTOM w0.152: 170.84,146.75 171.49,147.41 174.73,147.41 v2(175.76,146.38)
M_DQM6: length 37.2
  IN1 w0.165: v2(175.99,142.75) 175.99,144.26 176.75,145.02 185.39,145.02 185.51,145.14 185.51,150.96 185.39,151.09 183.7,151.09 183.58,151.22 183.58,151.63 183.74,151.79 185.31,151.79 185.48,151.96 185.48,152.29 185.31,152.45 183.74,152.45 183.58,152.62 183.58,152.95 183.74,153.11 185.31,153.11 185.48,153.28 185.48,153.61 185.31,153.77 183.74,153.77 183.58,153.94 183.58,154.31 183.74,154.48 184.42,154.48 184.55,154.6 184.55,155.01 184.42,155.14 183.74,155.14 183.58,155.3 183.58,158.16 v2(183.58,158.16)
  BOTTOM w0.089: v2(175.99,142.75) 176.07,142.75 176.46,142.36 UV1.E3
  BOTTOM w0.102: UV8.E7 184.92,158.9 184.18,158.16 v2(183.58,158.16)
M_DQM7: length 40.9
  BOTTOM w0.089: UV1.F4 176.09,140.73 176.56,140.26 177.49,140.26 178.02,140.79 178.35,140.79 179.37,141.81
  BOTTOM w0.152: 179.37,141.81 179.39,141.83 179.39,145.62 175.57,149.44 174.65,150.37 172,150.37 171.88,150.49 171.88,152.63 172,152.75 v1(177.03,152.75) 178.97,152.75 180.22,151.51 182.07,151.51 183.11,152.56 183.11,157.4 182.76,157.76 182.76,157.92 183.23,158.4 183.23,158.58 183,158.82 182.82,158.82 182.33,158.33 181.76,158.33 UV8.D3
M_DQS0: length 42
  BOTTOM w0.089: 154.38,141.27 154.4,141.29 154.62,141.29 154.83,141.07 154.83,140.73 155.26,140.3 155.76,140.3 155.81,140.25 156.27,140.25 156.33,140.31 156.62,140.31 156.68,140.25 157.08,140.25 157.16,140.32 157.39,140.32 157.49,140.23 157.49,140.09 157.36,139.96 UV1.H28
  BOTTOM w0.127: 154.38,141.27 153.5,141.27 152.57,142.2 152.57,146.45 153.09,146.97 153.09,147.15 152.59,147.65 152.59,148.02 152.99,148.42 153.36,148.42 153.86,147.92 154.04,147.92 154.31,148.19 154.31,148.37 153.54,149.14 153.54,149.51 153.95,149.91 154.32,149.91 155.08,149.14 155.26,149.14 155.59,149.47 155.59,149.65 154.83,150.41 154.83,150.78 155.23,151.18 155.6,151.18 v3(156.09,150.69) 156.86,149.92 157.16,149.92 158.15,150.91 158.62,150.91 158.64,150.94 159.22,150.94 159.24,150.91 159.89,150.91 160.01,151.04 160.01,151.55 159.89,151.67 159.04,151.67 158.78,151.93 158.78,152.5 159.04,152.76 159.26,152.76 159.39,152.89 159.39,153.27 159.26,153.4 159.04,153.4 158.78,153.66 158.78,154.32 159.04,154.58 159.26,154.58 159.39,154.71 159.39,155.09 159.26,155.22 159.04,155.22 158.78,155.48 158.78,156.83 158.24,157.37 158.24,158.98 158.5,159.24 159.08,159.24 159.34,158.98 159.34,157.78 159.84,157.28 160.32,157.28 160.43,157.39 UV5.C7
M_DQS1: length 40.6
  TOP w0.102: 156.79,145.04 156.81,145.04 156.83,145.02 157.97,145.02 158.36,144.63 158.36,144.04 158.13,143.81 157.85,143.81 v2(157.68,143.64)
  TOP w0.127: 156.79,145.04 155.91,145.04 155.55,144.68 153.78,144.68 153.27,144.17 153.27,142.8 153.14,142.68 152.29,142.68 152.13,142.84 152.13,142.93 152.14,142.95 152.14,143.15 152.52,143.53 152.52,144.05 152.26,144.31 150.11,144.31 149.98,144.44 149.98,144.82 150.11,144.95 152.23,144.95 152.49,145.21 152.49,145.78 152.23,146.04 151.46,146.04 151.33,146.17 151.33,146.55 151.46,146.68 v3(151.78,146.68) 152.23,146.68 152.49,146.94 152.49,152.31 152.61,152.44 153.03,152.44 153.16,152.31 153.16,151.7 153.41,151.44 153.98,151.44 154.24,151.71 154.24,151.78 154.42,151.96 154.69,151.96 154.87,151.78 154.87,151.71 155.13,151.44 157.13,151.44 157.76,152.07 157.76,152.28 157.89,152.4 158.09,152.4 158.32,152.63 158.32,153.18 158.06,153.44 157.89,153.44 157.77,153.57 157.77,153.95 157.89,154.08 158.06,154.08 158.32,154.34 158.32,157.16 158.06,157.42 157.39,157.42 UV6.C7
  BOTTOM w0.089: UV1.C27 158.09,143.22 v2(157.68,143.64)
M_DQS2: length 38
  IN1 w0.127: v2(158.27,159.98) 158.27,160.01 157.95,160.33 157.83,160.33 157.74,160.24 157.74,159.54 158.49,158.78 158.49,158.14 158.23,157.88 157.38,157.88 157.26,157.75 157.26,157.3 157.38,157.18 158.22,157.18 158.49,156.9 158.49,156.39 156.94,154.84 153.6,154.84 153.35,155.09 153.35,155.53 153.22,155.65 152.65,155.65 152.53,155.53 152.53,154.18 152.26,153.92 151.56,153.92 151.4,153.76 151.4,148.91 151.53,148.78 158.33,148.78 158.59,148.52 158.59,145.86 158.7,145.75 158.94,145.75 v2(159.29,146.1)
  BOTTOM w0.089: v2(159.29,146.1) 159.48,145.91 159.88,145.91 160.97,144.83 160.97,143.73 161.08,143.61 161.28,143.61 161.36,143.69 161.36,143.89 UV1.A23
  BOTTOM w0.102: UV5.F3 157.23,160.08 157.36,160.2 158.14,160.2 158.27,160.08 v2(158.27,159.98)
M_DQS3: length 39.2
  TOP w0.102: UV6.F3 160.43,159.97 v2(160.03,159.57)
  IN2 w0.102: 159.04,159.18 159.04,159.21 159.02,159.22 159.02,159.63 159.26,159.87 159.58,159.87 159.69,159.76 159.84,159.76 v2(160.03,159.57)
  IN2 w0.127: 159.04,159.18 159.04,158.39 159.16,158.26 159.85,158.26 160.11,158 160.11,157.42 159.85,157.16 159.01,157.16 158.88,157.03 158.88,156.06 159.01,155.93 159.74,155.93 160,155.67 160,155.1 159.74,154.83 159.14,154.83 159.01,154.71 159.01,154.32 159.14,154.2 160.91,154.2 161.17,153.93 161.17,153.36 160.91,153.09 159.14,153.09 159.01,152.97 159.01,152.49 159.14,152.36 161.21,152.36 161.47,152.1 161.47,150.04 161.6,149.92 161.98,149.92 162.11,150.04 162.11,152.1 162.37,152.36 163.05,152.36 163.37,152.04 163.37,149.67 163.51,149.54 164.76,149.54 165.03,149.26 165.03,148.63 164.77,148.36 163.78,148.36 163.65,148.24 163.65,147.86 163.78,147.73 164.77,147.73 165.03,147.47 165.03,144.5 165.37,144.17 165.37,143.49 164.78,142.9 v2(164.78,142.76)
  BOTTOM w0.089: UV1.E19 164.49,142.48 v2(164.78,142.76)
M_DQS4: length 39.6
  TOP w0.102: v2(184.17,159.75) 184.53,160.12 184.77,160.12 UV7.F3
  IN2 w0.102: 170.67,146.75 170.67,146.73 170.66,146.72 170.66,146 169.84,145.18 169.84,145.17 169.23,144.56 168.27,144.56 168.09,144.39 168.09,143.42 167.83,143.16 167.82,143.16 167.77,143.1 167.5,143.1 167.38,142.98 v2(167.38,142.75)
  IN2 w0.127: 170.67,146.75 170.67,147.32 174.39,151.04 174.75,151.04 175.02,151.3 175.02,151.66 175.14,151.79 175.52,151.79 175.65,151.66 175.65,151.3 175.91,151.04 176.49,151.04 176.75,151.3 176.75,152.27 176.88,152.4 177.26,152.4 177.39,152.27 177.39,151.3 177.65,151.04 183.57,151.04 183.83,151.3 183.83,152.03 183.57,152.29 182.3,152.29 182.18,152.42 182.18,152.8 182.3,152.93 183.2,152.93 183.46,153.19 183.46,153.76 183.2,154.03 182.49,154.03 182.37,154.15 182.37,154.54 182.49,154.66 182.93,154.66 183.19,154.93 183.19,159.63 183.36,159.79 184.13,159.79 v2(184.17,159.75)
  BOTTOM w0.089: v2(167.38,142.75) 167.38,142.72 167.69,142.41 UV1.E15
M_DQS5: length 42.2
  TOP w0.127: UV7.C7 181.83,157.46 182.64,157.46 183.27,156.84 183.27,154.42 183.74,153.95 183.74,151.89 184.77,150.86 188.16,150.86 188.49,150.53 v3(188.49,148.82) 188.49,146.87 188.21,146.6 187.64,146.6 187.38,146.86 187.38,149.38 187.26,149.5 186.87,149.5 186.75,149.38 186.75,146.86 186.49,146.6 176.46,146.6 176.28,146.78 175.42,146.78 174.25,145.61 174.25,145.38 173.9,145.03 173.45,145.03 173.25,144.82 173.25,144.68 v2(173.44,144.49)
  BOTTOM w0.089: v2(173.44,144.49) 173.2,144.72 173.2,144.9 173.02,145.08 172.48,145.08 172.19,144.79 172.19,144.34 171.99,144.14 171.99,143.74 172.05,143.68 172.05,143.43 171.94,143.31 171.94,142.89 171.81,142.76 UV1.D10
M_DQS6: length 37.7
  IN1 w0.102: 182.69,159.54 182.69,159.71 182.43,159.97 181.82,159.97 v2(181.4,160.39)
  IN1 w0.127: 182.69,159.54 182.69,158.34 182.56,158.22 182.25,158.22 181.98,157.95 181.98,157.38 182.25,157.12 182.56,157.12 182.69,156.99 182.69,150.49 182.97,150.2 184.31,150.2 184.44,150.08 184.44,149.69 184.31,149.57 182.92,149.57 182.66,149.3 182.66,148.73 182.92,148.47 184.5,148.47 184.62,148.34 184.62,147.96 184.5,147.83 182.92,147.83 182.66,147.57 182.66,146.99 182.92,146.73 184.5,146.73 184.62,146.6 184.62,146.03 184.5,145.91 176.44,145.91 176.17,145.63 175.91,145.63 v2(175.76,145.78)
  BOTTOM w0.089: v2(175.76,145.78) 175.58,145.6 175.35,145.6 175.13,145.37 175.13,143.8 175.23,143.7 175.23,143.49 175.02,143.29 175.02,142.89 UV1.D6
  BOTTOM w0.102: v2(181.4,160.39) 181.72,160.07 UV8.F3
M_DQS7: length 41.7
  BOTTOM w0.089: 179.6,141.12 179.59,141.12 179.57,141.1 179.24,141.1 178.2,140.06 178.2,139.88 177.97,139.65 176.73,139.65 176.4,139.98 176.4,140.17 175.81,140.76 UV1.G5
  BOTTOM w0.127: 179.6,141.12 180.05,141.57 180.05,145.87 174.92,151.01 172.78,151.01 172.52,151.27 172.52,151.84 172.78,152.11 176.84,152.11 177.1,151.84 v3(177.1,151.43) 177.1,150.75 177.23,150.62 177.61,150.62 177.74,150.75 177.74,151.84 178,152.11 178.65,152.11 178.89,151.86 178.93,151.86 179.4,151.39 179.4,151.35 179.9,150.86 182.33,150.86 183.76,152.29 183.76,157.05 184.05,157.34 184.84,157.34 184.92,157.41 UV8.C7
M_DQS#0: length 42
  BOTTOM w0.089: 154.44,141.5 154.45,141.5 154.48,141.48 154.69,141.48 155.02,141.15 155.02,140.8 155.34,140.49 155.83,140.49 155.89,140.44 156.19,140.44 156.25,140.5 156.7,140.5 156.76,140.44 157.01,140.44 157.08,140.51 157.47,140.51 157.68,140.31 157.68,139.86 157.77,139.76 157.98,139.76 158.09,139.87 UV1.H27
  BOTTOM w0.127: UV5.B7 160.16,157.05 159.75,157.05 159.11,157.68 159.11,158.89 158.98,159.01 158.6,159.01 158.47,158.89 158.47,157.46 159.01,156.92 159.01,155.57 159.14,155.44 159.36,155.44 159.62,155.18 159.62,154.61 159.36,154.35 159.14,154.35 159.01,154.22 159.01,153.76 159.14,153.63 159.36,153.63 159.62,153.37 159.62,152.8 159.36,152.54 159.14,152.54 159.01,152.41 159.01,152.03 159.14,151.9 159.98,151.9 160.24,151.64 160.24,150.94 159.98,150.68 v3(158.91,150.68) 158.24,150.68 157.26,149.69 156.76,149.69 156.19,150.27 156.16,150.27 155.71,150.71 155.71,150.75 155.5,150.96 155.32,150.96 155.05,150.69 155.05,150.51 155.82,149.74 155.82,149.37 155.36,148.91 154.99,148.91 154.22,149.68 154.04,149.68 153.77,149.41 153.77,149.23 154.54,148.46 154.54,148.1 154.14,147.69 153.77,147.69 153.26,148.2 153.08,148.2 152.81,147.93 152.81,147.75 153.32,147.24 153.32,146.87 152.8,146.35 152.8,142.29 153.59,141.5 154.44,141.5
M_DQS#1: length 40.6
  TOP w0.102: 156.79,144.81 156.81,144.81 156.83,144.82 157.88,144.82 158.16,144.55 158.16,144.13 158.06,144.03 157.66,144.03 157.6,144.1 157.6,144.31 v2(157.73,144.44)
  TOP w0.127: 156.79,144.81 156,144.81 155.65,144.45 153.88,144.45 153.5,144.07 153.5,142.71 153.24,142.45 152.19,142.45 151.9,142.74 151.9,143.03 151.91,143.04 151.91,143.24 152.29,143.62 152.29,143.96 152.16,144.09 150.01,144.09 149.75,144.35 149.75,144.92 150.01,145.18 152.13,145.18 152.26,145.3 152.26,145.69 152.13,145.81 151.36,145.81 151.1,146.07 151.1,146.64 151.39,146.93 152.16,146.93 152.26,147.03 152.26,152.41 152.51,152.66 153.12,152.66 153.38,152.4 153.38,151.8 153.51,151.67 153.88,151.67 154.01,151.8 154.01,151.87 154.32,152.19 154.79,152.19 155.1,151.87 155.1,151.8 155.23,151.67 157.04,151.67 157.53,152.17 157.53,152.37 157.79,152.63 157.99,152.63 158.1,152.73 158.1,153.09 157.97,153.21 157.8,153.21 157.54,153.47 157.54,154.05 157.8,154.31 157.97,154.31 158.1,154.43 158.1,157.06 157.97,157.19 157.41,157.19 157.23,157.01 UV6.B7
  BOTTOM w0.089: v2(157.73,144.44) 158.09,144.07 UV1.A27
M_DQS#2: length 38.2
  IN1 w0.127: v2(158.27,160.56) 157.74,160.56 157.51,160.33 157.51,159.44 158.26,158.69 158.26,158.24 158.13,158.11 157.29,158.11 157.02,157.85 157.02,157.21 157.29,156.94 158.13,156.94 158.26,156.81 158.26,156.49 156.84,155.07 153.7,155.07 153.58,155.19 153.58,155.62 153.32,155.89 152.56,155.89 152.29,155.62 152.29,154.28 152.16,154.15 151.46,154.15 151.17,153.85 151.17,148.81 151.43,148.55 158.23,148.55 158.36,148.42 158.36,145.76 158.61,145.51 v2(159.29,145.51)
  BOTTOM w0.089: v2(159.29,145.51) 159.49,145.72 159.81,145.72 160.78,144.75 160.78,143.65 161.01,143.42 161.06,143.42 161.29,143.19 UV1.C23
  BOTTOM w0.102: UV5.G3 157.23,160.58 157.4,160.41 158.11,160.41 v2(158.27,160.56)
M_DQS#3: length 39.2
  TOP w0.102: UV6.G3 v2(160.03,160.37)
  IN2 w0.102: v2(160.03,160.37) 160.03,160.05 159.95,159.97 159.77,159.97 159.66,160.08 159.17,160.08 158.81,159.72 158.81,159.22 158.8,159.21 158.8,159.18
  IN2 w0.127: v2(164.78,143.56) 164.88,143.46 165,143.46 165.13,143.59 165.13,144.07 164.8,144.4 164.8,147.37 164.67,147.5 163.68,147.5 163.42,147.76 163.42,148.33 163.68,148.6 164.67,148.6 164.8,148.72 164.8,149.16 164.66,149.3 163.42,149.3 163.14,149.58 163.14,151.94 162.95,152.13 162.47,152.13 162.34,152 162.34,149.95 162.08,149.68 161.5,149.68 161.24,149.95 161.24,152 161.11,152.13 159.04,152.13 158.78,152.39 158.78,153.06 159.04,153.33 160.81,153.33 160.94,153.46 160.94,153.84 160.81,153.96 159.04,153.96 158.78,154.23 158.78,154.8 159.04,155.07 159.64,155.07 159.77,155.19 159.77,155.57 159.64,155.7 158.91,155.7 158.65,155.96 158.65,157.13 158.91,157.39 159.75,157.39 159.88,157.52 159.88,157.9 159.75,158.03 159.07,158.03 158.8,158.29 158.8,159.18
  BOTTOM w0.089: UV1.C19 164.49,143.23 164.8,143.54 164.78,143.56 v2(164.78,143.56)
M_DQS#4: length 39.6
  TOP w0.102: v2(184.17,160.32) 184.47,160.32 UV7.G3
  IN2 w0.102: 170.44,146.75 170.44,146.73 170.45,146.72 170.45,146.09 169.63,145.27 169.63,145.26 169.14,144.77 168.18,144.77 167.88,144.47 167.88,143.51 167.68,143.31 167.58,143.31 167.38,143.51 v2(167.38,143.56)
  IN2 w0.127: v2(184.17,160.32) 183.87,160.03 183.26,160.03 182.96,159.72 182.96,155.02 182.83,154.9 182.4,154.9 182.13,154.63 182.13,154.06 182.4,153.79 183.1,153.79 183.23,153.67 183.23,153.29 183.1,153.16 182.21,153.16 181.94,152.9 181.94,152.32 182.21,152.06 183.47,152.06 183.6,151.93 183.6,151.4 183.47,151.27 177.75,151.27 177.62,151.4 177.62,152.37 177.36,152.63 176.78,152.63 176.52,152.37 176.52,151.4 176.39,151.27 176.01,151.27 175.88,151.4 175.88,151.76 175.62,152.02 175.05,152.02 174.78,151.76 174.78,151.4 174.66,151.27 174.29,151.27 170.44,147.42 170.44,146.75
  BOTTOM w0.089: UV1.C15 167.67,143.16 167.38,143.46 v2(167.38,143.56)
M_DQS#5: length 41.9
  TOP w0.127: v2(172.85,144.49) 173.02,144.65 173.02,144.92 173.35,145.25 173.8,145.25 174.02,145.47 174.02,145.7 175.32,147.01 176.37,147.01 176.55,146.83 186.39,146.83 186.52,146.95 186.52,149.47 186.78,149.73 187.35,149.73 187.61,149.47 187.61,146.95 187.74,146.83 188.12,146.83 188.25,146.95 188.25,148.5 188.23,148.51 188.23,149.12 188.25,149.14 188.25,150.45 188.06,150.63 184.68,150.63 183.51,151.8 183.51,153.85 183.04,154.33 183.04,156.74 182.55,157.24 181.82,157.24 181.68,157.1 181.68,156.81 UV7.B7
  BOTTOM w0.089: UV1.E9 172.13,142.72 172.13,143.23 172.24,143.35 172.24,143.76 172.18,143.82 172.18,144.06 172.38,144.26 172.38,144.71 172.56,144.89 172.94,144.89 173.01,144.83 173.01,144.65 v2(172.85,144.49)
M_DQS#6: length 37.7
  IN1 w0.102: v2(182.12,160.37) 182.31,160.18 182.52,160.18 182.9,159.8 182.9,159.64 182.91,159.63 182.91,159.57 182.92,159.55 182.92,159.54
  IN1 w0.127: v2(175.76,145.2) 175.96,145.4 176.26,145.4 176.54,145.67 184.59,145.67 184.86,145.94 184.86,146.7 184.59,146.96 183.02,146.96 182.89,147.09 182.89,147.47 183.02,147.6 184.59,147.6 184.86,147.86 184.86,148.44 184.59,148.7 183.02,148.7 182.89,148.83 182.89,149.21 183.02,149.33 184.41,149.33 184.67,149.6 184.67,150.17 184.41,150.44 183.07,150.44 182.92,150.59 182.92,157.09 182.66,157.35 182.35,157.35 182.22,157.48 182.22,157.86 182.35,157.98 182.66,157.98 182.92,158.25 182.92,159.54
  BOTTOM w0.089: v2(175.76,145.2) 175.76,145.2 175.55,145.41 175.43,145.41 175.32,145.29 175.32,143.88 175.42,143.78 175.42,143.41 175.29,143.28 175.21,143.21 175.21,143.03 175.33,142.91 175.44,142.91 UV1.C5
  BOTTOM w0.102: UV8.G3 181.72,160.77 v2(182.12,160.37)
M_DQS#7: length 41.6
  BOTTOM w0.089: UV1.H4 176.06,139.99 175.93,139.99 175.84,139.89 175.84,139.76 175.99,139.61 176.17,139.61 176.27,139.71 176.4,139.71 176.65,139.46 178.05,139.46 178.39,139.8 178.39,139.98 179.32,140.91 179.57,140.91 179.59,140.89 179.6,140.89
  BOTTOM w0.127: UV8.B7 184.92,156.93 184.74,157.11 184.14,157.11 183.99,156.96 183.99,152.19 182.43,150.63 179.8,150.63 v3(178.97,151.47) 178.56,151.88 178.09,151.88 177.97,151.75 177.97,150.65 177.71,150.39 177.13,150.39 176.87,150.65 176.87,150.99 176.85,151.02 176.85,151.77 176.75,151.88 172.88,151.88 172.75,151.75 172.75,151.37 172.88,151.24 175.01,151.24 180.28,145.97 180.28,141.47 179.7,140.89 179.6,140.89
M_MA0: length 72.3
  TOP w0.102: v2(165.28,138.96) 165.55,138.7 166.61,138.7 166.92,139.01 166.92,140.71 166.65,140.98 166.65,144.72 167.45,145.52 167.45,146.75 ; v2(159.47,165.95) 159.43,165.99 159.43,166.09 159.5,166.16 159.9,166.16 160.06,166 160.06,165.92 159.99,165.86 159.89,165.86 159.84,165.8 159.84,165.71 160.24,165.3 160.4,165.3 160.51,165.4 160.51,165.5 UV6.N3 ; v2(183.95,165.95) 183.92,165.99 183.92,166.09 183.98,166.16 184.39,166.16 184.55,166 184.55,165.92 184.48,165.86 184.38,165.86 184.32,165.8 184.32,165.71 184.73,165.3 184.89,165.3 185,165.4 185,165.5 UV7.N3
  TOP w0.234: v2(171.98,168.39) 172.03,168.34 172.03,166.07 172.39,165.71 172.39,162.67 173.2,161.86 v1(173.2,158.31) 173.2,152.96 167.45,147.22 167.45,146.75
  IN2 w0.102: v2(183.95,165.95) 184.07,166.07 184.07,166.37 183.9,166.54 182.53,166.54 182.12,166.95 181.4,166.95 181.19,167.16 180.31,167.16 180.12,167.35 180.12,167.72 179.88,167.96 179.57,167.96 179.55,167.93 ; v2(159.47,165.95) 160.55,165.95 161.02,166.42 161.81,166.42 162.24,166.85 162.24,167.04 162.5,167.31
  IN2 w0.127: 162.5,167.31 165.96,167.31 166.75,168.1 169.21,168.1 169.51,168.39 v2(171.98,168.39) 172.94,168.39 173.4,167.93 179.55,167.93
  BOTTOM w0.089: UV1.K17 165.59,138.66 165.59,138.66 v2(165.28,138.96)
  BOTTOM w0.102: UV5.N3 159.08,165.57 v2(159.47,165.95) ; UV8.N3 183.57,165.57 v2(183.95,165.95)
M_MA1: length 76.6
  TOP w0.102: 163.61,146.75 163.61,146.05 162.8,145.24 162.8,141.75 163.29,141.27 163.29,140.11 v2(162.94,139.76) ; v2(158.2,167.94) 158.36,167.94 158.46,167.83 158.46,167.64 158.35,167.53 157.95,167.53 157.61,167.19 157.61,166.85 157.5,166.74 157.13,166.74 157.03,166.64 157.03,166.47 157.13,166.37 UV6.P7 ; UV7.P7 181.61,166.37 181.52,166.47 181.52,166.64 181.62,166.74 181.99,166.74 182.1,166.85 182.1,167.19 182.44,167.53 182.84,167.53 182.95,167.64 182.95,167.83 182.85,167.94 v2(182.68,167.94)
  TOP w0.234: 163.61,146.75 163.61,148.81 v1(166.75,151.95) 169.36,154.55 169.36,161.86 169.72,162.22 169.72,164.22 170.74,165.24 170.74,169.1 v2(171.76,170.12)
  IN2 w0.102: v2(158.2,167.94) 158.78,167.35 159.71,167.35 160.81,168.45 161.8,168.45 ; v2(182.68,167.94) 182.51,167.77 181.74,167.77 180.94,168.57 180.75,168.57 180.49,168.83 180.49,169.15
  IN2 w0.127: 180.49,169.15 179.98,169.66 178.02,169.66 177.89,169.78 177.89,169.99 177.77,170.12 177.52,170.12 177.39,169.99 177.39,169.79 177.26,169.66 177.01,169.66 176.88,169.79 176.88,169.99 176.76,170.12 176.5,170.12 176.38,169.99 176.38,169.79 176.25,169.66 175.99,169.66 175.87,169.79 175.87,169.99 175.74,170.12 175.49,170.12 175.36,169.99 175.36,169.79 175.23,169.66 174.98,169.66 174.85,169.79 174.85,169.99 174.72,170.12 174.47,170.12 174.34,169.99 174.34,169.83 174.24,169.72 174.06,169.72 173.86,169.93 173.86,170 173.75,170.12 v2(171.76,170.12) 165.33,170.12 164.96,169.75 164.28,169.75 163.57,169.04 162.39,169.04 161.8,168.45
  BOTTOM w0.089: v2(162.94,139.76) 163.49,139.21 UV1.J20
  BOTTOM w0.102: UV8.P7 184.36,166.93 184.36,167.08 184.11,167.33 183.29,167.33 v2(182.68,167.94) ; v2(158.2,167.94) 158.81,167.33 159.62,167.33 159.87,167.08 159.87,166.93 UV5.P7
M_MA2: length 70.4
  TOP w0.102: UV6.P3 160.24,166.56 159.21,166.56 v2(158.83,166.95) ; UV7.P3 184.73,166.56 183.7,166.56 v2(183.32,166.95)
  IN1 w0.26: v2(161.69,139.6) 162.41,140.32 162.41,143.46 163.13,144.18 163.13,145.63 163.85,146.35 163.85,148.23 164.79,149.17 164.79,152.87 167.24,155.32 167.24,157.58 166.86,157.97 166.86,165.55 169.63,168.32 v2(169.63,169.25)
  IN2 w0.102: 180.35,168.27 180.46,168.16 180.76,168.16 181.57,167.35 182.91,167.35 v2(183.32,166.95) ; 162.22,167.96 161.02,167.96 160.89,167.83 160.89,167.68 161.2,167.37 161.2,167.23 161.06,167.08 160.91,167.08 160.56,167.44 160.39,167.44 160.27,167.32 160.27,167.15 160.57,166.85 160.57,166.69 160.45,166.57 160.28,166.57 160.03,166.82 159.88,166.82 159.62,166.56 159.01,166.56 158.83,166.74 v2(158.83,166.95)
  IN2 w0.127: 180.35,168.27 179.83,168.79 173.76,168.79 173.3,169.25 v2(169.63,169.25) 166.13,169.25 165.96,169.08 165.96,168.53 165.6,168.17 162.44,168.17 162.22,167.96
  BOTTOM w0.089: UV1.H23 161.32,139.96 v2(161.69,139.6)
  BOTTOM w0.102: v2(158.83,166.95) 158.3,166.42 157.28,166.42 UV5.P3 ; v2(183.32,166.95) 182.79,166.42 181.76,166.42 UV8.P3
M_MA3: length 73
  TOP w0.102: UV6.N2 161.1,165.57 160.62,165.1 160.16,165.1 159.7,165.56 158.59,165.56 v2(158.2,165.95) ; v2(160.85,141.15) 161.05,141.35 161.05,146.75 ; UV7.N2 185.59,165.57 185.11,165.1 184.65,165.1 184.18,165.56 183.08,165.56 v2(182.68,165.95)
  TOP w0.234: v2(169.57,167.23) 166.8,164.46 166.8,155.61 v1(163.73,152.55) 161.05,149.87 161.05,146.75
  IN2 w0.102: v2(158.2,165.95) 157.52,165.95 157.4,165.83 157.4,165.5 157.52,165.37 160.54,165.37 161.17,166 162.05,166 162.49,166.45 162.53,166.45 ; 179.79,166.6 180.75,166.6 181.4,165.95 v2(182.68,165.95)
  IN2 w0.127: 179.79,166.6 179.58,166.8 179.27,166.8 179.1,166.64 176.96,166.64 176.46,166.14 173.93,166.14 172.84,167.23 v2(169.57,167.23) 167.11,167.23 166.32,166.45 162.53,166.45
  BOTTOM w0.089: UV1.G23 160.9,141.15 v2(160.85,141.15)
  BOTTOM w0.102: UV5.N2 156.43,165.32 156.3,165.19 156.1,165.19 155.97,165.32 155.97,165.83 156.1,165.95 v2(158.2,165.95) ; v2(182.68,165.95) 182.64,165.91 181.7,165.91 181.4,166.22 181.22,166.22 181.08,166.08 181.08,165.93 181.34,165.67 181.34,165.23 181.24,165.13 181.03,165.13 180.92,165.24 UV8.N2
M_MA4: length 83.3
  TOP w0.102: UV7.P8 181.33,166.78 181.33,167.24 181.66,167.58 181.78,167.58 182.04,167.84 182.04,168.12 182.45,168.53 182.92,168.53 183.13,168.32 183.57,168.32 v2(183.95,167.94) ; UV6.P8 156.84,166.78 156.84,167.24 157.18,167.58 157.29,167.58 157.55,167.84 157.55,168.12 157.96,168.53 158.47,168.53 158.68,168.32 159.08,168.32 v2(159.47,167.94) ; v2(160.09,141.16) 160.83,141.9 160.83,145.62 160.41,146.04 160.41,146.75
  TOP w0.234: v2(171.01,170.98) 170.81,170.98 169.89,170.05 168.62,170.05 166.16,167.58 v1(166.16,161.62) 166.16,155.88 160.41,150.13 160.41,146.75
  IN2 w0.102: v2(183.95,167.94) 183.34,168.55 182.49,168.55 181.62,169.42 181.62,169.6 ; 161,168.94 160.98,168.91 160.69,168.91 159.72,167.94 v2(159.47,167.94)
  IN2 w0.127: 161,168.94 161.29,168.94 162.64,170.28 162.82,170.28 163.12,169.98 163.29,169.98 163.47,170.16 163.47,170.34 163.18,170.64 163.18,170.82 163.34,170.98 164.09,170.98 164.22,170.85 164.22,170.74 164.35,170.61 164.6,170.61 164.73,170.74 164.73,170.85 164.86,170.98 v2(171.01,170.98) 180.24,170.98 181.62,169.6
  BOTTOM w0.089: v2(160.09,141.16) 160.28,141.16 160.49,140.95 UV1.G24
  BOTTOM w0.102: v2(183.95,167.94) 183.95,167.85 184.56,167.24 184.56,167.02 184.8,166.78 185,166.78 185.1,166.88 185.28,166.88 185.43,166.73 185.43,166.55 185.25,166.37 185.25,166.04 185.38,165.91 185.97,165.91 186.1,166.04 186.1,166.25 185.97,166.37 UV8.P8 ; UV5.P8 161.49,166.37 161.61,166.25 161.61,166.04 161.49,165.91 160.89,165.91 160.76,166.04 160.76,166.37 160.95,166.55 160.95,166.73 160.8,166.88 160.62,166.88 160.51,166.78 160.32,166.78 160.08,167.02 160.08,167.24 159.47,167.85 v2(159.47,167.94)
M_MA5: length 75.8
  TOP w0.102: v2(182.68,166.95) 183.27,166.36 184.47,166.36 184.78,166.05 185.39,166.05 UV7.P2 ; v2(158.2,166.95) 158.78,166.36 159.99,166.36 160.3,166.05 160.91,166.05 UV6.P2
  IN1 w0.102: 161.1,141.66 161.28,141.47 161.28,140.74 160.9,140.36 v2(160.87,140.36)
  IN1 w0.26: v2(169.03,168.53) 166.29,165.78 166.29,157.73 166.68,157.35 166.68,155.56 164.22,153.1 164.22,149.4 163.29,148.47 163.29,146.3 162.57,145.58 162.57,144.13 161.1,142.66 161.1,141.66
  IN2 w0.102: v2(158.2,166.95) 157.91,166.95 157.78,167.07 157.78,167.22 157.65,167.35 157.47,167.35 157.35,167.22 157.35,166.49 157.47,166.36 160.63,166.36 161.46,167.2 162.03,167.2 162.58,167.74 ; 180.22,167.96 180.68,167.96 181.49,167.15 182.48,167.15 v2(182.68,166.95)
  IN2 w0.127: 180.22,167.96 179.81,168.36 173.58,168.36 173.12,168.82 169.33,168.82 v2(169.03,168.53) 169.03,168.53 166.57,168.53 165.78,167.74 162.58,167.74
  BOTTOM w0.089: UV1.H24 160.49,139.98 v2(160.87,140.36)
  BOTTOM w0.102: UV8.P2 180.56,166.37 180.45,166.48 180.45,166.64 180.56,166.75 181.05,166.75 181.24,166.56 181.43,166.56 181.62,166.75 181.97,166.75 182.14,166.92 182.14,167.06 182.27,167.18 182.56,167.18 182.68,167.06 v2(182.68,166.95) ; UV5.P2 156.07,166.37 155.96,166.48 155.96,166.64 156.07,166.75 156.56,166.75 156.75,166.56 156.94,166.56 157.13,166.75 157.49,166.75 157.65,166.92 157.65,167.06 157.78,167.18 158.07,167.18 158.2,167.06 v2(158.2,166.95)
M_MA6: length 86.1
  TOP w0.102: 164.89,146.75 164.89,144.37 165.19,144.07 165.19,141.76 164.71,141.28 164.71,140.18 v2(164.09,139.56) ; v2(158.2,169.85) 158.2,169.7 156.83,168.33 156.83,167.7 156.7,167.58 156.08,167.58 155.95,167.45 155.95,167.06 156.08,166.93 156.3,166.93 156.43,167.06 UV6.R8 ; v2(182.68,169.92) 182.71,169.89 182.71,169.62 182.63,169.54 182.29,169.54 182.24,169.6 182.1,169.6 181.95,169.45 181.95,169.31 182.02,169.24 182.02,169.09 181.88,168.95 181.74,168.95 181.66,169.02 181.52,169.02 181.38,168.88 181.38,168.73 181.45,168.66 181.45,168.52 181.26,168.33 181.26,167.98 181.44,167.8 181.44,167.64 181.31,167.51 181.17,167.51 181.1,167.58 180.99,167.58 180.9,167.5 180.9,167.19 UV7.R8
  TOP w0.234: v2(170.49,172.71) 171,172.71 172.27,171.43 172.27,169.69 171.38,168.8 171.38,164.9 170.36,163.88 170.36,162.15 170.64,161.88 170.64,154.02 v1(169.53,152.92) 164.89,148.28 164.89,146.75
  IN2 w0.102: v2(158.2,169.85) 158.13,169.79 158.13,169.63 158.26,169.51 159.65,169.51 159.98,169.84
  IN2 w0.127: v2(182.68,169.92) 182.86,170.09 182.86,170.8 180.95,172.71 v2(170.49,172.71) 162.62,172.71 159.98,170.06 159.98,169.84
  BOTTOM w0.089: v2(164.09,139.56) 164.31,139.34 164.51,139.34 UV1.J19
  BOTTOM w0.102: v2(182.68,169.92) 183.27,169.33 184.09,169.33 184.55,168.87 184.55,167.88 184.83,167.6 185.29,167.6 UV8.R8 ; UV5.R8 160.8,167.6 160.34,167.6 160.06,167.88 160.06,168.99 159.73,169.33 158.72,169.33 v2(158.2,169.85)
M_MA7: length 81.6
  TOP w0.102: UV6.R2 160.91,166.85 160.3,166.85 159.85,167.3 159.85,168.09 159.42,168.52 158.76,168.52 158.38,168.91 v2(158.23,168.91) ; UV7.R2 185.39,166.85 184.78,166.85 184.34,167.3 184.34,168.09 183.91,168.52 183.22,168.52 182.81,168.93 v2(182.68,168.93)
  IN1 w0.26: v2(170.36,171.41) 170.24,171.29 170.24,167.25 168.97,165.98 168.97,164.68 169.53,164.12 169.53,162.86 168.97,162.3 168.97,153.12 166.48,150.63 166.48,148.47 165.55,147.53 165.55,145.39 165.07,144.91 165.07,144.39 165.28,144.17 165.28,141.66 164.78,141.15 164.78,139.3 164.31,138.83 v2(164.31,138.78)
  IN2 w0.102: 181.83,169.99 181.83,169.49 182.4,168.93 v2(182.68,168.93) ; v2(158.23,168.91) 158.82,168.32 159.81,168.32 160.63,169.14 160.89,169.14
  IN2 w0.127: 160.89,169.14 163.16,171.41 v2(170.36,171.41) 180.41,171.41 181.83,169.99
  BOTTOM w0.089: v2(164.31,138.78) 164.69,138.4 UV1.K19
  BOTTOM w0.102: v2(182.68,168.93) 182.43,168.93 181.92,168.42 181.92,168.26 182.1,168.08 182.1,167.62 181.98,167.5 181.73,167.5 181.4,167.83 181.25,167.83 181.06,167.64 181.06,167.51 181.39,167.18 181.39,167.07 181.26,166.94 181.15,166.94 UV8.R2 ; v2(158.23,168.91) 157.98,168.91 157.55,168.49 157.55,167.79 157.42,167.65 156.99,167.65 156.88,167.54 156.62,167.54 156.51,167.65 156.08,167.65 155.95,167.52 155.95,167.08 156.08,166.95 156.3,166.95 156.43,167.08 UV5.R2
M_MA8: length 82.7
  TOP w0.102: UV7.T8 180.92,168.71 182.52,170.31 183.62,170.31 v2(183.89,170.04) ; UV6.T8 156.43,168.22 157.78,169.57 157.78,169.97 158.08,170.27 159.11,170.27 v2(159.47,169.92)
  IN1 w0.102: 167.37,145.56 167.37,145.04 167.87,144.54 167.87,143.87 168.53,143.21 168.53,141.77 168.51,141.75 168.51,140.14 v2(168.99,139.66)
  IN1 w0.26: v2(171.75,173.14) 171.63,173.02 171.63,170.7 170.95,170.02 170.95,167.16 170.68,166.89 170.68,162.19 171.02,161.85 171.02,152.77 168.18,149.93 168.18,147.77 167.37,146.96 167.37,145.56
  IN2 w0.127: v2(183.89,170.04) 183.89,170.27 183.67,170.48 183.44,170.48 183.31,170.62 183.31,170.96 181.13,173.14 v2(171.75,173.14) 162.44,173.14 159.47,170.16 v2(159.47,169.92)
  BOTTOM w0.089: v2(168.99,139.66) 168.49,139.16 UV1.J14
  BOTTOM w0.102: v2(183.89,170.04) 184.06,170.21 184.51,170.21 184.64,170.08 184.64,169.61 185.19,169.06 185.19,168.49 185.32,168.36 186.05,168.36 186.16,168.25 186.16,168.04 186.05,167.92 185.77,167.92 UV8.T8 ; UV5.T8 161.56,167.97 161.68,168.09 161.68,168.25 161.56,168.36 160.83,168.36 160.7,168.49 160.7,169.06 160.15,169.61 160.15,170.08 160.03,170.21 159.59,170.21 159.47,170.08 v2(159.47,169.92)
M_MA9: length 78
  TOP w0.102: UV6.R3 160.81,167.17 160.93,167.3 160.93,167.52 160.81,167.65 160.52,167.65 160.38,167.52 160.18,167.52 160.05,167.64 160.05,168.47 v2(159.59,168.93) ; v2(183.95,168.93) 184.54,168.34 184.54,167.64 184.66,167.52 184.87,167.52 185.01,167.65 185.29,167.65 185.42,167.52 185.42,167.3 185.29,167.17 UV7.R3
  IN1 w0.102: 168.75,146.75 168.75,145.94 169.08,145.61 169.08,144.05 169.46,143.67 169.46,142.49 169.31,142.34 169.31,141.63 169.48,141.45 169.48,139.58 v2(168.95,139.04)
  IN1 w0.26: 168.75,146.75 168.75,149.69 171.74,152.68 171.74,163.74 171.24,164.24 171.24,166.66 171.52,166.93 171.52,169.19 172.23,169.9 172.23,172.15 v2(172.1,172.28)
  IN2 w0.102: 182.42,170.29 182.25,170.13 182.25,169.75 182.47,169.53 183.35,169.53 v2(183.95,168.93)
  IN2 w0.127: v2(159.59,168.93) 159.59,169.07 162.8,172.28 v2(172.1,172.28) 180.77,172.28 182.42,170.63 182.42,170.29
  BOTTOM w0.089: UV1.K14 168.29,138.39 v2(168.95,139.04)
  BOTTOM w0.102: UV5.R3 157.81,167.76 157.81,168.09 158.24,168.52 159.19,168.52 v2(159.59,168.93) ; v2(183.95,168.93) 183.95,168.85 183.63,168.52 182.73,168.52 182.3,168.09 182.3,167.54 181.94,167.17 UV8.R3
M_MA10: length 67.4
  TOP w0.102: v2(183.95,163.97) 183.57,163.59 182.42,163.59 182.04,163.97 UV7.L7 ; UV6.L7 157.55,163.97 157.93,163.59 159.08,163.59 v2(159.47,163.97)
  IN1 w0.102: v2(170.07,139.26) 170.7,139.89 170.7,141.35 170.91,141.55 170.91,142.1 170.43,142.58 170.43,144.82 169.88,145.37 169.88,146.75
  IN1 w0.26: v2(171.83,164.99) 172.19,164.99 173.45,163.73 173.45,162.29 173.58,162.16 173.58,160.77 173.32,160.51 173.15,160.51 172.89,160.25 172.89,159.73 173.15,159.47 173.32,159.47 173.58,159.21 173.58,158.69 173.32,158.43 173.15,158.43 172.89,158.17 172.89,157.65 173.15,157.39 173.32,157.39 173.58,157.13 173.58,152.93 169.88,149.23 169.88,146.75
  IN2 w0.102: v2(159.47,163.97) 159.47,163.97 162.14,163.97 162.15,163.97 162.52,163.97 162.64,164.1 ; 179.93,164.45 182.26,164.45 182.39,164.58 183.34,164.58 v2(183.95,163.97)
  IN2 w0.127: 162.64,164.1 165.51,164.1 165.9,164.49 170.52,164.49 170.62,164.39 171.23,164.39 171.38,164.54 171.38,164.78 171.58,164.99 v2(171.83,164.99) 172.15,164.99 173.13,164.01 176.04,164.01 176.44,164.41 179.89,164.41 179.93,164.45
  BOTTOM w0.089: UV1.J11 170.67,139.14 170.19,139.14 v2(170.07,139.26)
  BOTTOM w0.102: v2(183.95,163.97) 183.95,163.76 184.03,163.68 184.29,163.68 184.37,163.76 184.37,164.18 184.55,164.36 185.08,164.36 185.19,164.26 185.19,164.06 185.1,163.97 UV8.L7 ; UV5.L7 160.61,163.97 160.7,164.06 160.7,164.26 160.6,164.36 160.06,164.36 159.88,164.18 159.88,163.76 159.81,163.68 159.54,163.68 159.47,163.76 v2(159.47,163.97)
M_MA11: length 77.8
  TOP w0.102: 169.97,146.75 169.97,145.29 169.41,144.73 169.41,142.49 169.22,142.3 168.73,142.3 168.54,142.12 168.54,141.25 168.5,141.21 168.5,140.32 168.73,140.09 169.85,140.09 v2(170.07,139.88) ; UV6.R7 157.76,167.7 157.76,168.04 158.04,168.32 158.39,168.32 158.77,167.94 v2(158.83,167.94) ; v2(183.32,167.94) 183.23,167.94 182.84,168.32 182.52,168.32 182.24,168.04 182.24,167.7 UV7.R7
  TOP w0.234: v2(172.85,170.55) 173.68,169.72 173.68,169.14 173.31,168.77 v1(173.31,167.83) 173.31,166.9 175.12,165.08 175.12,152.17 169.97,147.02 169.97,146.75
  IN2 w0.102: v2(183.32,167.94) 183.39,168.01 183.39,168.19 183.26,168.32 182.25,168.32 182.17,168.24 182.17,168.05 182.09,167.97 181.83,167.97 181.66,168.14 181.66,168.29 181.98,168.61 181.98,168.75 181.84,168.9 181.7,168.9 181.37,168.57 181.23,168.57 181.08,168.72 181.08,168.86 181.41,169.18 181.41,169.33 181.18,169.56 ; v2(158.83,167.94) 159.21,167.55 159.62,167.55 160.76,168.69 161.25,168.69
  IN2 w0.127: 161.25,168.69 161.66,168.69 162.44,169.47 163.39,169.47 164.1,170.18 164.78,170.18 165.15,170.55 v2(172.85,170.55) 178.13,170.55 178.25,170.42 178.25,170.24 178.38,170.12 178.63,170.12 178.76,170.24 178.76,170.42 178.89,170.55 179.14,170.55 179.27,170.42 179.27,170.24 179.4,170.12 179.65,170.12 179.78,170.24 179.78,170.42 179.9,170.55 180.06,170.55 180.51,170.1 180.51,169.76 180.71,169.56 181.18,169.56
  BOTTOM w0.089: UV1.J13 169.49,139.3 v2(170.07,139.88)
  BOTTOM w0.102: UV8.R7 184.33,167.76 184.33,168.09 184.11,168.32 183.7,168.32 v2(183.32,167.94) ; v2(158.83,167.94) 159.21,168.32 159.62,168.32 159.85,168.09 159.85,167.76 UV5.R7
M_MA12: length 73.3
  TOP w0.102: UV6.N7 157.27,165.57 158.04,166.34 158.45,166.34 v2(158.83,165.95) ; v2(183.32,165.95) 182.94,166.34 182.52,166.34 181.76,165.57 UV7.N7 ; v2(171.24,140.36) 170.9,140.36 170.62,140.64 170.62,141.34 170.87,141.59 170.87,145.3 171.13,145.56
  TOP w0.234: v2(174.45,167.39) 174.63,167.39 v1(175.55,166.47) 176.4,165.62 176.4,151.63 171.13,146.36 171.13,145.56
  IN2 w0.102: 180.49,166.88 181.1,166.88 181.22,166.76 181.22,166.43 181.46,166.19 181.58,166.19 181.67,166.28 181.67,166.64 181.77,166.74 181.97,166.74 182.08,166.64 182.08,166.26 182.18,166.16 182.33,166.16 182.51,166.34 183.48,166.34 183.59,166.22 183.59,166.08 183.47,165.95 v2(183.32,165.95) ; v2(158.83,165.95) 159.21,165.57 160.46,165.57 161.1,166.22 161.89,166.22 162.55,166.88
  IN2 w0.127: 162.55,166.88 166.14,166.88 166.93,167.67 173.06,167.67 173.22,167.5 174.34,167.5 v2(174.45,167.39) 174.45,167.22 174.3,167.07 173.95,167.07 173.87,166.99 173.87,166.81 174.11,166.57 174.82,166.57 174.98,166.73 174.98,167.36 175.1,167.49 175.34,167.49 175.46,167.36 175.46,166.7 175.59,166.57 176.28,166.57 176.43,166.73 176.43,166.92 176.33,167.02 176.08,167.02 175.97,167.12 175.97,167.36 176.1,167.49 176.75,167.49 177.17,167.07 177.59,167.07 177.69,167.17 177.69,167.31 177.84,167.46 178.07,167.46 178.23,167.3 178.23,167.18 178.34,167.07 178.92,167.07 179.09,167.23 179.44,167.23 179.51,167.23 179.86,166.88 180.49,166.88
  BOTTOM w0.089: UV1.H11 170.84,139.96 v2(171.24,140.36)
  BOTTOM w0.102: UV8.N7 184.16,166.34 183.7,166.34 v2(183.32,165.95) ; v2(158.83,165.95) 159.21,166.34 159.67,166.34 UV5.N7
M_MA13: length 74
  TOP w0.102: 162.97,146.75 162.97,145.85 162.6,145.48 162.6,141.25 v2(162.88,140.97) ; UV6.T3 160.43,168.63 159.75,169.31 159.28,169.31 v2(158.9,168.93) ; UV7.T3 184.92,168.63 184.24,169.31 183.7,169.31 183.36,168.96 v2(183.36,168.93)
  TOP w0.234: 162.97,146.75 162.97,149.07 v1(168.24,154.34) 168.72,154.82 168.72,162.12 169.08,162.49 169.08,164.48 169.51,164.91 169.51,166.26 170.1,166.86 170.1,169.37 171.63,170.89 171.63,171.17 171.12,171.68 v2(171.12,171.84)
  IN2 w0.102: v2(183.36,168.93) 182.97,169.31 182.39,169.31 182.05,169.65 182.05,170.17 181.97,170.24 ; 160.31,169.17 160.31,169.1 159.75,168.55 159.11,168.55 158.9,168.76 v2(158.9,168.93)
  IN2 w0.127: 160.31,169.17 162.98,171.84 v2(171.12,171.84) 180.59,171.84 181.97,170.47 181.97,170.24
  BOTTOM w0.089: v2(162.88,140.97) 163.29,140.97 163.49,140.77 UV1.G20
  BOTTOM w0.102: v2(183.36,168.93) 183.25,168.93 182.85,169.33 182.54,169.33 181.72,168.5 UV8.T3 ; v2(158.9,168.93) 158.75,168.93 158.39,169.29 158.07,169.29 157.23,168.45 UV5.T3
M_MA14: length 80.8
  TOP w0.102: 170.61,146.75 170.44,146.58 170.44,143.65 170.09,143.31 170.09,141.77 169.46,141.13 v2(168.94,141.13) ; v2(158.83,169.89) 158.83,169.46 158.7,169.33 158.11,169.33 157.23,168.45 UV6.T7 ; v2(183.32,169.92) 183.32,169.48 183.17,169.33 182.55,169.33 181.72,168.5 UV7.T7
  TOP w0.234: v2(172.7,173.57) 174.32,171.95 v1(174.32,170.43) 174.32,168.86 173.95,168.48 173.95,167.16 175.76,165.35 175.76,151.9 170.61,146.75
  IN2 w0.127: v2(183.32,169.92) 183.63,169.61 184.56,169.61 184.69,169.74 184.69,170.42 184.56,170.55 184.33,170.55 181.31,173.57 v2(172.7,173.57) 162.27,173.57 158.83,170.14 v2(158.83,169.89)
  BOTTOM w0.089: UV1.G14 168.36,140.76 168.73,141.13 v2(168.94,141.13)
  BOTTOM w0.102: UV5.T7 160.43,168.91 159.81,169.53 159.19,169.53 v2(158.83,169.89) ; v2(183.32,169.92) 183.7,169.53 184.3,169.53 184.92,168.91 UV8.T7
M_MA15: length 69.1
  TOP w0.102: UV6.M7 157.42,164.58 158.45,164.58 v2(158.83,164.96) ; UV7.M7 181.91,164.58 182.94,164.58 v2(183.32,164.96)
  IN1 w0.26: v2(165.6,137.02) 166.69,137.02 167.01,137.34 167.01,140.69 166.24,141.46 166.24,147.43 167.05,148.23 167.05,150.4 169.54,152.88 169.54,159.14 169.88,159.49 169.88,160.18 169.54,160.53 169.54,162.06 169.77,162.3 169.86,162.3 170.1,162.53 170.1,164.4 169.84,164.66 169.8,164.66 169.54,164.92 169.54,165.36 169.75,165.58 v2(170.08,165.58)
  IN2 w0.102: 179.52,165.49 179.61,165.59 181.09,165.59 181.13,165.55 182.24,165.55 182.42,165.37 182.91,165.37 v2(183.32,164.96) ; v2(158.83,164.96) 159.21,164.58 160.41,164.58 161.41,165.58 162.55,165.58
  IN2 w0.127: 162.55,165.58 166.96,165.58 167.08,165.71 167.08,165.91 167.21,166.04 167.46,166.04 167.59,165.91 167.59,165.61 167.72,165.48 167.97,165.48 168.1,165.61 168.1,165.91 168.23,166.04 168.48,166.04 168.61,165.91 168.61,165.57 168.73,165.44 168.99,165.44 169.11,165.57 169.11,165.91 169.24,166.04 169.5,166.04 169.62,165.91 169.62,165.71 169.75,165.58 v2(170.08,165.58) 170.54,166.04 172.78,166.04 173.54,165.28 179.3,165.28 179.52,165.49
  BOTTOM w0.089: UV1.L17 166.09,137.51 v2(165.6,137.02)
  BOTTOM w0.102: UV8.M7 184.71,164.57 183.72,164.57 v2(183.32,164.96) ; UV5.M7 160.22,164.57 159.23,164.57 v2(158.83,164.96)
M_RAS#0: length 50.1
  TOP w0.102: v2(161.69,141.16) 161.75,141.16 162.1,141.5 162.1,143.59 161.45,144.24 161.45,145.28 161.69,145.52 161.69,146.75 ; UV6.J3 160.43,162.08 160.1,161.75 160.1,161.37 159.98,161.24 159.42,161.24 159.29,161.37 159.29,161.78 v2(159.47,161.95)
  TOP w0.234: 161.69,146.75 161.69,149.6 167.44,155.35 v1(167.44,157.61) 167.44,159.9 v2(167.33,160.01)
  IN2 w0.102: 162.08,161.58 159.84,161.58 v2(159.47,161.95)
  IN2 w0.127: 162.08,161.58 162.54,161.58 164.1,160.02 166.58,160.02 167.23,159.37 173.53,159.37 173.65,159.5 173.65,159.77 173.53,159.89 167.44,159.89 v2(167.33,160.01)
  BOTTOM w0.089: UV1.G22 162.09,140.76 v2(161.69,141.16)
  BOTTOM w0.102: UV5.J3 158.03,161.57 159.08,161.57 v2(159.47,161.95)
M_RAS#1: length 51.8
  TOP w0.102: v2(183.95,161.95) 183.78,161.78 183.78,161.37 183.9,161.24 184.46,161.24 184.59,161.37 184.59,161.75 184.92,162.08 UV7.J3 ; v2(165.28,140.84) 165.22,140.91 165.22,141.38 165.39,141.55 165.39,144.17 165.17,144.4 165.17,145 165.53,145.36 165.53,146.75
  TOP w0.234: v2(171.28,162.24) v1(171.28,156.34) 171.28,153.76 165.53,148.01 165.53,146.75
  IN2 w0.102: 179.63,161.64 180.35,162.36 181.78,162.36 181.97,162.54 183.57,162.54 183.95,162.16 v2(183.95,161.95)
  IN2 w0.127: 179.63,161.64 179.51,161.64 178.3,160.43 172.96,160.43 172.84,160.55 172.84,161.21 172.71,161.34 172.46,161.34 172.33,161.21 172.33,160.55 172.2,160.43 171.95,160.43 171.82,160.55 171.82,161.68 171.69,161.81 171.44,161.81 171.31,161.68 171.31,160.55 171.19,160.43 170.59,160.43 170.47,160.55 170.47,160.83 170.59,160.95 170.67,160.95 170.8,161.08 170.8,161.33 170.67,161.46 170.58,161.46 170.45,161.59 170.45,162.08 170.58,162.2 171.24,162.2 v2(171.28,162.24)
  BOTTOM w0.089: v2(165.28,140.84) 165.36,140.77 165.88,140.77 UV1.G17
  BOTTOM w0.102: UV8.J3 182.52,161.57 183.57,161.57 v2(183.95,161.95)
M_WE#0: length 50.2
  TOP w0.102: v2(158.2,163.97) 158.78,164.56 159.71,164.56 160.3,163.97 UV6.L3
  IN1 w0.102: v2(160.2,140.37) 160.11,140.37 159.62,140.86 159.62,141.46 159.89,141.72 159.89,142.19
  IN1 w0.26: v2(164.78,163.23) 164.78,163.96 164.27,164.47 164.27,167.39 164.5,167.61 166.07,167.61 166.41,167.27 166.41,166.73 165.73,166.05 165.73,157.5 166.11,157.11 166.11,155.79 163.66,153.34 163.66,149.64 162.72,148.7 162.72,146.25 161.58,145.1 161.58,144.19 159.89,142.5 159.89,142.19
  IN2 w0.102: 162.58,163.23 162.3,163.23 161.98,163.56 159.88,163.56 159.71,163.39 158.78,163.39 v2(158.2,163.97)
  IN2 w0.127: v2(164.78,163.23) 162.58,163.23
  BOTTOM w0.089: UV1.G25 159.73,140.76 160.12,140.37 v2(160.2,140.37)
  BOTTOM w0.102: v2(158.2,163.97) 158.33,163.97 158.46,163.85 158.46,163.5 158.33,163.38 157.81,163.38 157.69,163.5 157.69,164.06 157.56,164.19 157.36,164.19 157.23,164.06 UV5.L3
M_WE#1: length 50.9
  TOP w0.102: UV7.L3 184.79,163.97 184.2,164.56 183.27,164.56 v2(182.68,163.97)
  IN1 w0.102: v2(172.04,140.36) 172.04,140.4 171.52,140.92 171.52,141.58 171.39,141.71 171.39,142.5 171.01,142.88 171.01,146.75
  IN1 w0.26: v2(174.48,163.13) 174.59,163.25 174.59,165.1 174.38,165.32 173.46,165.32 172.62,166.15 172.62,166.57 172.86,166.8 175.2,166.8 175.47,166.54 175.47,162.8 174.71,162.04 174.71,152.46 171.01,148.76 171.01,146.75
  IN2 w0.102: v2(182.68,163.97) 182.67,163.99 180.23,163.99
  IN2 w0.127: 180.23,163.99 179.79,163.55 176.8,163.55 176.38,163.13 174.48,163.13 v2(174.48,163.13)
  BOTTOM w0.089: UV1.H10 171.69,140.01 v2(172.04,140.36)
  BOTTOM w0.102: v2(182.68,163.97) 182.82,163.97 182.94,163.85 182.94,163.5 182.82,163.38 182.3,163.38 182.17,163.5 182.17,164.06 182.05,164.19 181.84,164.19 181.72,164.06 UV8.L3
MCT0: length 3.3
  BOTTOM w0.127: RL19.1 v1(15.53,167.88)
  BOTTOM w0.508: TL1.11 17.79,168.94 RL19.1
MCT1: length 2.3
  BOTTOM w0.254: TL1.14 17.78,172.73 RL20.1
MCT2: length 3.7
  TOP w0.127: v1(14.32,169.47) 14.85,168.94 RL41.1
  TOP w0.508: TL2.14 16.55,168.93 16.54,168.94 RL41.1
MCT3: length 3.8
  TOP w0.127: v1(14.34,171.97) 14.56,171.97 15.32,172.73 RL42.1
  TOP w0.508: TL2.11 15.53,172.74 RL42.1
MDI0+: length 26.5
  TOP w0.102: v2(44.32,169.87) 44.48,169.71 45.03,169.71 45.16,169.58 45.35,169.58 45.45,169.68 UL1.1
  IN2 w0.102: v2(28.2,171.35) 28.29,171.26 28.59,171.26 29.09,171.75 40.42,171.75 40.72,171.45 41.31,171.45 43.03,169.73 44.18,169.73 v2(44.32,169.87)
  BOTTOM w0.102: TL1.8 28.25,166.39 28.95,167.08 28.95,171.07 28.67,171.35 v2(28.2,171.35)
MDI0-: length 26.5
  TOP w0.102: v2(44.32,169.28) 44.44,169.41 44.9,169.41 45.03,169.27 UL1.2
  IN2 w0.102: v2(44.32,169.28) 44.18,169.42 42.9,169.42 41.18,171.15 40.6,171.15 40.29,171.45 29.22,171.45 28.72,170.95 28.39,170.95 v2(28.2,170.76)
  BOTTOM w0.102: TL1.7 27.4,167.66 27.53,167.53 27.53,166.82 27.65,166.69 28.13,166.69 28.64,167.21 v3(28.64,168.44) 28.64,170.94 28.54,171.04 28.43,171.04 28.2,170.81 v2(28.2,170.76)
MDI1+: length 28.8
  TOP w0.102: v2(44.24,168.55) 44.39,168.4 45.37,168.4 45.45,168.48 UL1.4
  IN2 w0.102: v2(28.85,174.7) 28.72,174.83 27.7,174.83 27.36,174.49 27.36,170.61 27.93,170.04 29.04,170.04 29.57,170.57 39.91,170.57 40.2,170.28 40.71,170.28 42.59,168.4 44.09,168.4 v2(44.24,168.55)
  BOTTOM w0.102: v2(28.85,174.7) 28.85,174.78 28.7,174.93 27.69,174.93 27.6,174.84 27.6,174.13 27.48,174.01 TL1.2
MDI1-: length 28.9
  TOP w0.102: v2(44.24,167.97) 44.37,168.1 45.46,168.1 45.48,168.08 UL1.5
  IN2 w0.102: v2(28.85,175.29) 28.7,175.13 27.58,175.13 27.06,174.61 27.06,170.49 27.81,169.74 29.16,169.74 29.7,170.27 39.78,170.27 40.08,169.98 40.58,169.98 42.46,168.1 44.11,168.1 v2(44.24,167.97)
  BOTTOM w0.102: TL1.1 27.17,175.28 27.21,175.23 28.8,175.23 v2(28.85,175.29)
MDI2+: length 24
  TOP w0.102: v2(44.61,167.39) 44.74,167.25 44.8,167.25 45.18,167.63 45.41,167.63 45.46,167.68 UL1.6 ; TL2.1 29,166.39 30.71,168.1 30.71,168.9 30.36,169.25 29.93,169.25 v2(29.88,169.3)
  IN2 w0.102: v2(29.88,169.3) 29.94,169.24 30.37,169.24 30.54,169.41 38.84,169.41 39.25,169 40.07,169 41.92,167.16 44.38,167.16 v2(44.61,167.39)
MDI2-: length 24
  TOP w0.102: v2(29.88,168.72) 29.88,168.81 30.02,168.95 30.23,168.95 30.41,168.77 30.41,168.22 28.88,166.69 27.67,166.69 27.54,166.82 27.54,167.53 27.41,167.66 TL2.2 ; UL1.7 45.46,167.28 45.41,167.32 45.31,167.32 44.93,166.94 44.74,166.94 v2(44.61,166.8)
  IN2 w0.102: v2(29.88,168.72) 30.09,168.94 30.5,168.94 30.66,169.1 38.72,169.1 39.12,168.69 39.95,168.69 41.79,166.85 44.55,166.85 v2(44.61,166.8)
MDI3+: length 36.1
  TOP w0.102: UL1.9 46.54,165.81 46.63,165.71 46.63,165.61 46.55,165.53 44.71,165.53 44.5,165.75 44.43,165.75 44.34,165.84 v2(44.34,165.95) ; TL2.7 27.14,174.01 27.7,174.57 27.7,175.31 28.05,175.65 28.05,175.92 28.35,176.23 28.62,176.23 28.85,175.99 v2(28.85,175.95)
  IN2 w0.102: v2(44.34,165.95) 44.34,165.86 44.25,165.77 41.63,165.77 39.57,167.83 38.75,167.83 38.38,168.2 33.94,168.2 33.53,167.79 28.02,167.79 26.14,169.67 26.14,175.01 27.36,176.23 28.62,176.23 28.85,176 v2(28.85,175.95)
MDI3-: length 36.2
  TOP w0.102: TL2.8 27.24,175.28 27.74,175.78 27.74,176.05 28.23,176.53 v2(28.85,176.53) ; v2(44.34,165.37) 44.45,165.37 44.59,165.23 46.68,165.23 46.94,165.48 UL1.10
  IN2 w0.102: v2(44.34,165.37) 44.24,165.47 41.5,165.47 39.45,167.53 38.63,167.53 38.26,167.89 34.07,167.89 33.66,167.49 27.9,167.49 25.84,169.54 25.84,175.13 27.23,176.53 v2(28.85,176.53)
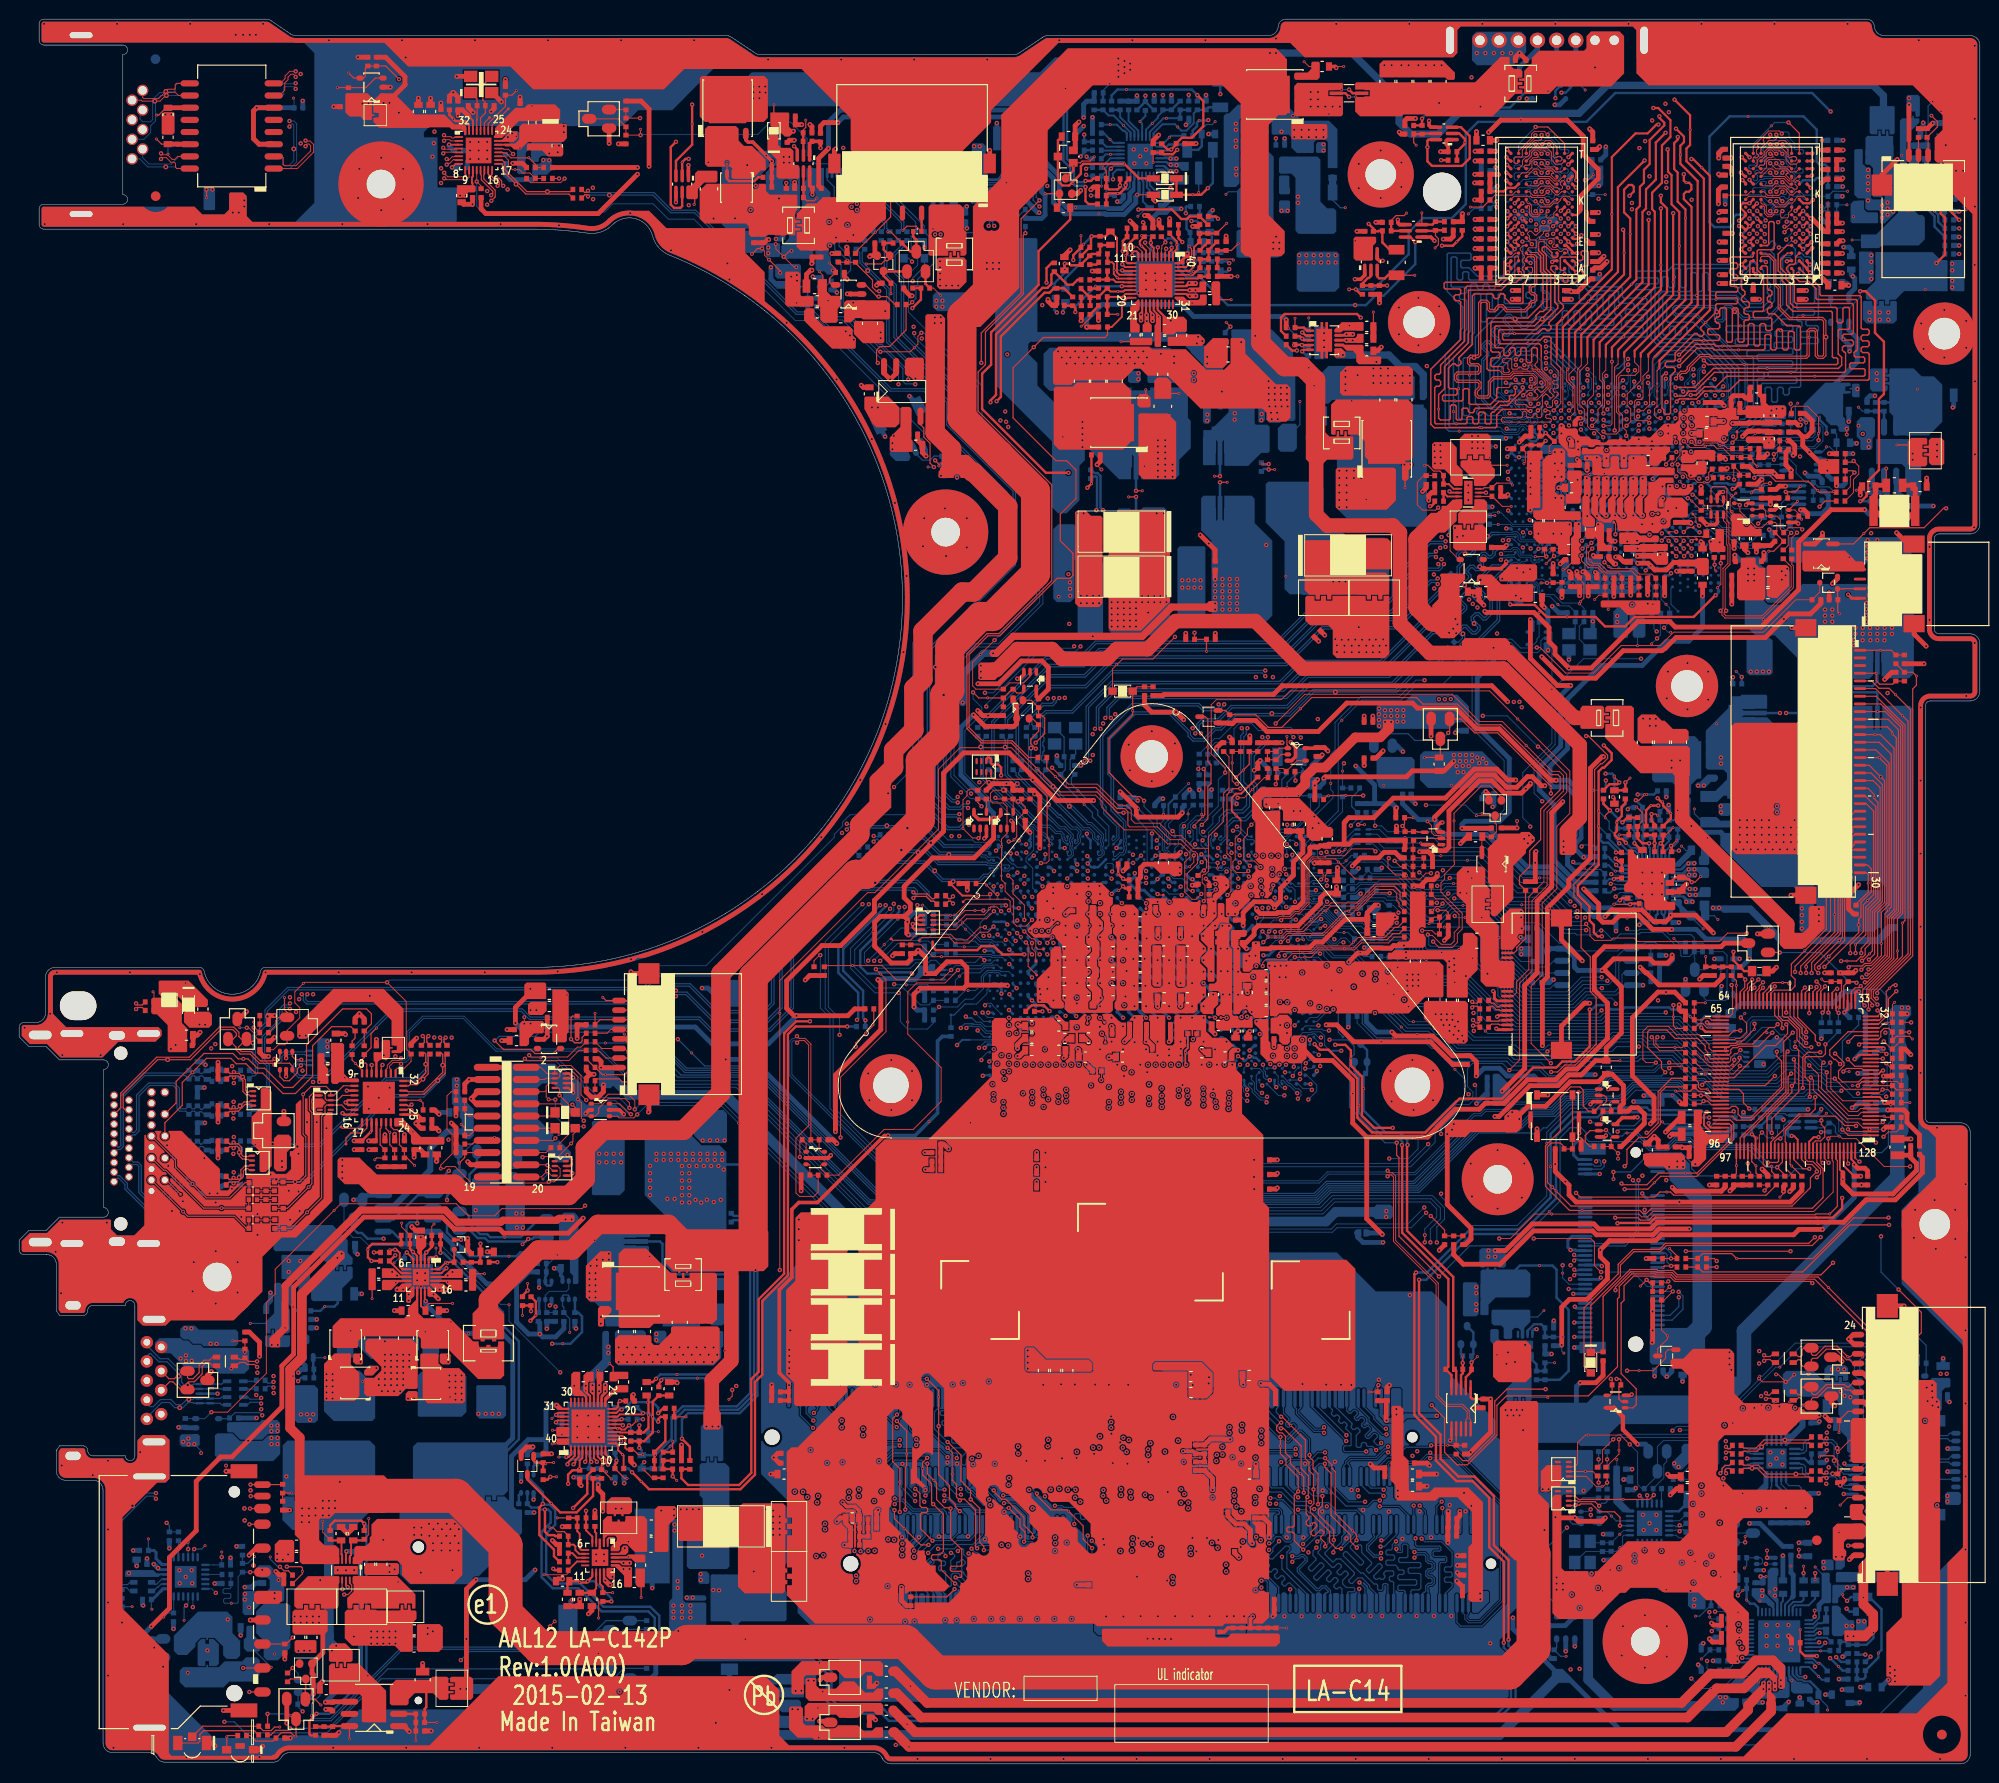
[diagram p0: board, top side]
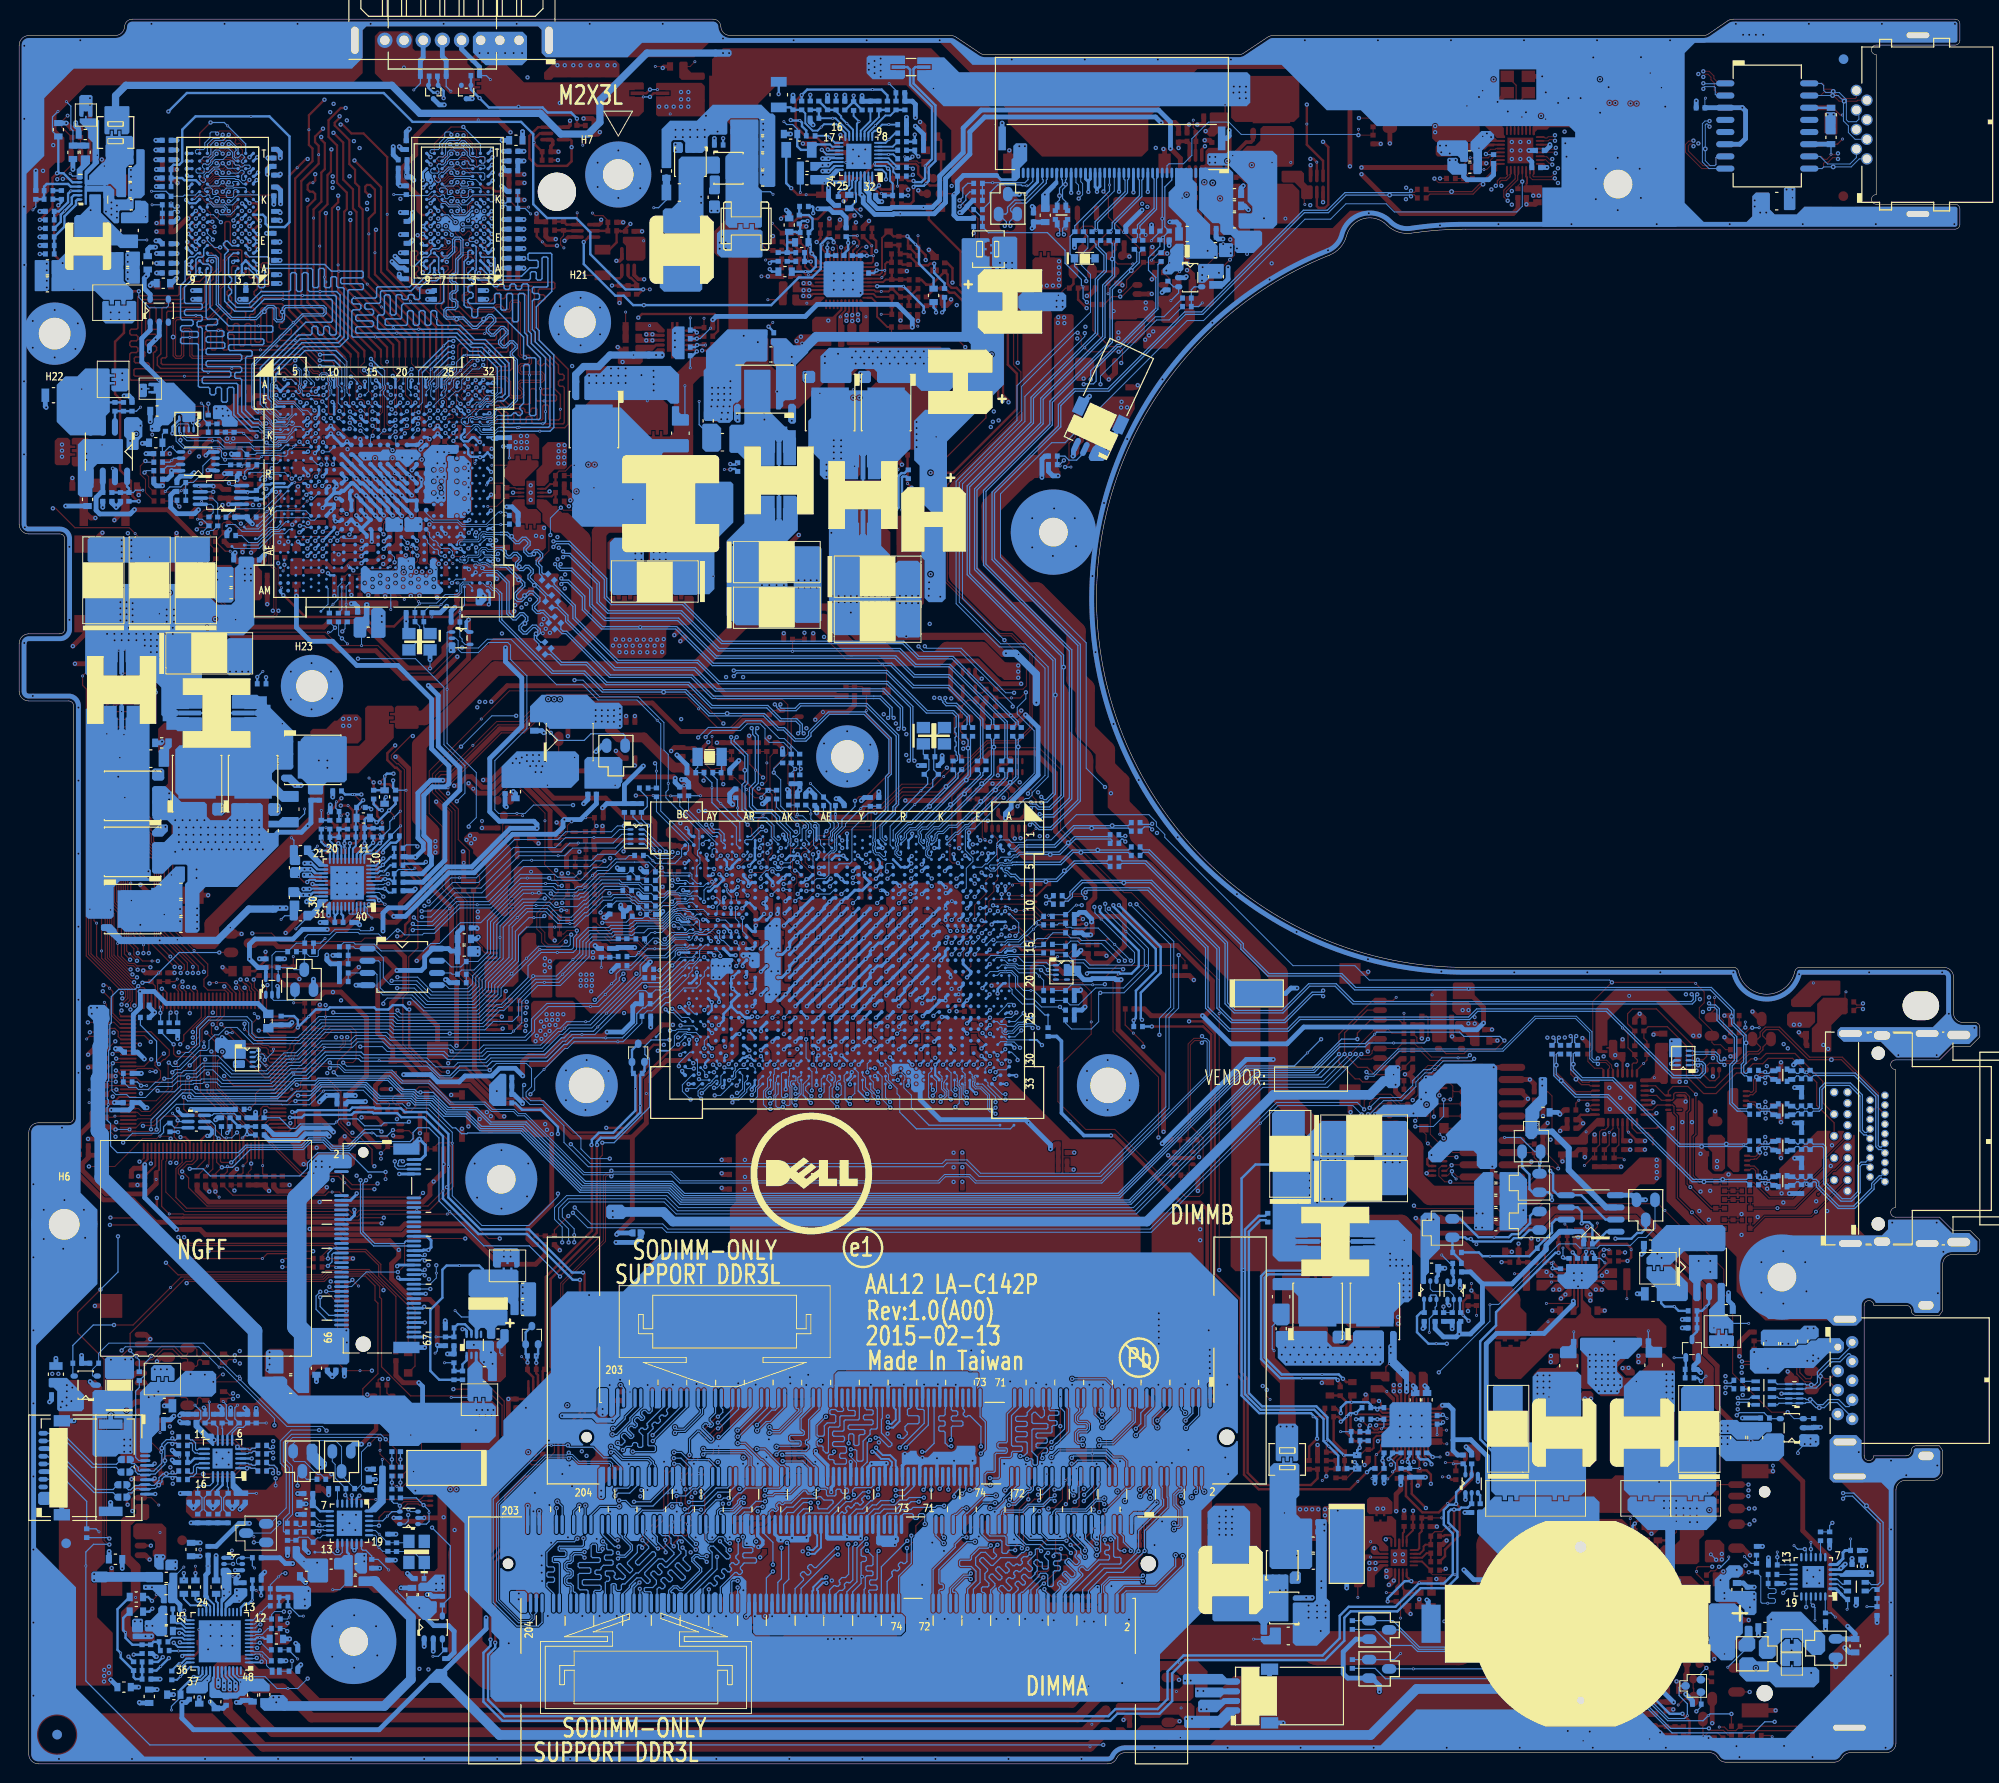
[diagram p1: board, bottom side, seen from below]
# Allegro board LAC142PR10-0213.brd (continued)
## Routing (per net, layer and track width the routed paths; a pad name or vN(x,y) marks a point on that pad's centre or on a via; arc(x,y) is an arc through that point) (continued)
MDO0+: length 6.4
  BOTTOM w0.102: TL1.9 16.46,166.39 16.29,166.56 v3(15.3,166.56) 13.42,166.56 12.58,167.4 JLAN.1
MDO0-: length 6.4
  BOTTOM w0.102: TL1.10 16.67,167.66 15.88,166.87 13.54,166.87 12.88,167.53 JLAN.2
MDO1+: length 9.5
  BOTTOM w0.102: TL1.15 v3(15.36,174.01) 14.78,174.01 14.23,173.46 14.23,171.36 13.71,170.85 13.71,170.15 13.01,169.44 JLAN.3
MDO1-: length 9.5
  BOTTOM w0.102: JLAN.6 12.62,172.24 12.62,171.54 12.88,171.27 13.71,171.27 13.93,171.49 13.93,173.58 14.65,174.31 16.06,174.31 16.29,174.54 16.29,175.04 16.52,175.28 TL1.16
MDO2+: length 9.8
  TOP w0.102: TL2.16 16.44,166.39 16.31,166.51 16.31,166.92 16.19,167.04 15.83,167.04 15.35,167.53 14.93,167.53 v2(14.8,167.39)
  IN2 w0.102: JLAN.4 12.88,171.15 13.02,171.3 13.53,171.3 13.91,170.92 13.91,167.95 14.33,167.53 14.66,167.53 v2(14.8,167.39)
MDO2-: length 9.8
  TOP w0.102: v2(14.8,167.97) 14.94,167.83 15.47,167.83 15.96,167.35 16.24,167.35 16.55,167.66 TL2.15
  IN2 w0.102: v2(14.8,167.97) 14.66,167.83 14.46,167.83 14.22,168.07 14.22,171.04 13.66,171.6 12.9,171.6 12.77,171.48 JLAN.5
MDO3+: length 6.6
  TOP w0.102: JLAN.7 12.73,173.52 12.83,173.42 v3(14.15,173.42) 14.69,173.42 15.63,174.36 16.27,174.36 16.62,174.01 TL2.10
MDO3-: length 6.6
  TOP w0.102: JLAN.8 12.88,173.8 13,173.69 14.55,173.69 v3(15.3,174.43) 15.53,174.66 16.2,174.66 16.29,174.75 16.29,175.15 16.41,175.28 TL2.9
MEM_MAB_EVENT#: length 99.5
  TOP w0.102: R6.2 122.86,75.98 v2(122.46,75.57)
  IN2 w0.102: v2(122.46,75.57) 122.46,74.87 123.32,74 126.32,74 126.99,73.33 129.63,73.33 129.72,73.42 133.56,73.42 133.71,73.57 134.58,73.57 134.8,73.34 135.77,73.34 136.98,72.13
  IN2 w0.127: 136.98,72.13 137.93,71.18 137.93,54.65 138.17,54.42 138.17,47.68 146.73,39.12 146.73,37.1 147.31,36.51 v2(147.31,33.21)
  BOTTOM w0.102: v2(122.46,75.57) 122.46,73.61 UC1.AG30
  BOTTOM w0.127: JDIMM1.198 150,14.75 150.38,14.37 152.61,14.37 155.1,16.85 155.1,27.61 149.5,33.21 v2(147.31,33.21) 147.12,33.02 144.68,33.02 143.58,31.92 142.76,31.92 141.8,30.96 JDIMM2.198
MEM_MAB_RST#: length 83.8
  TOP w0.102: C1274.1 112.91,71.35 v2(112.88,71.32)
  TOP w0.127: v2(97.59,18.22) 96.78,17.41 C1275.1
  IN1 w0.127: v2(112.88,71.32) 110.75,71.32 110.42,70.99 110.42,69.53 105.53,64.64 105.53,57.34 101.29,53.1 101.29,40.89 100.23,39.84 100.23,38.71 97.67,36.14 97.67,32.8 v2(96.86,31.99) 97.45,31.39 97.45,29.44 97.6,29.29 97.6,27.13 97.91,26.82 98.38,26.82 99.13,26.07 99.13,24.36 101.09,22.41 101.09,19.84 99.47,18.22 v2(97.59,18.22)
  BOTTOM w0.102: v2(112.88,71.32) UC1.T33
  BOTTOM w0.127: v2(97.59,18.22) 97.59,18.09 97.2,17.7 JDIMM1.30 ; JDIMM2.30 89,31.56 89.44,32 90.37,32 91.11,32.74 96.11,32.74 v2(96.86,31.99)
MEM_MAB_ZVDDIO: length 4.4
  TOP w0.203: v2(121.76,72.92) 121.66,73.02 v1(121.66,74.18) 121.66,74.4 121.93,74.67 R75.1
  BOTTOM w0.102: UC1.AF32 121.37,72.52 v2(121.76,72.92)
MEM_VOLT_SEL: length 14.4
  TOP w0.127: R929.1 R928.2 128.33,104.25 v1(127.72,103.64) v2(126.95,102.87)
  IN1 w0.102: 125.55,97.9 125.55,95.27 125.4,95.12 125.4,94.25 v2(125.69,93.96)
  IN1 w0.107: v2(126.95,102.87) 126.17,102.09 126.17,98.51 125.55,97.9
  BOTTOM w0.102: v2(125.69,93.96) 125.68,93.96 125.68,93.84 UC1.AL5
MIC1-L: length 2
  BOTTOM w0.203: CA74.1 184,16.97 183.82,16.79 UA1.19
MIC_CLK_C: length 3.5
  BOTTOM w0.102: LA1.1 178.75,10.25 178.75,10.76 v1(179.24,11.25) 179.44,11.46 179.93,11.46 180.01,11.38 UA1.3
MS_CLK_SD_WP: length 16.2
  TOP w0.127: R810.1 27.45,29.13 JREAD.11 v2(24.14,29.13)
  IN2 w0.107: v2(24.14,29.13) 23.42,28.41 23.42,28.07 22.42,27.06 20.76,27.06 18.56,24.86 15.65,24.86 15.39,25.13 v2(15.39,25.13)
  BOTTOM w0.102: CR5.1 15.67,24.19 RR3.2
  BOTTOM w0.127: v2(15.39,25.13) 15.67,24.85 CR5.1
MS_CLK_SD_WP_R: length 1.7
  BOTTOM w0.102: RR3.1 16.62,23.27 UR1.8
MS_D1_SD_D3: length 15.1
  TOP w0.127: JREAD.1 v2(23.36,10)
  IN2 w0.107: v2(18.12,16.34) 18.19,16.34 18.9,15.63 18.9,15.48 18.33,14.91 18.33,14.76 18.55,14.53 18.7,14.53 19.28,15.11 19.43,15.11 19.66,14.88 19.66,14.73 19.08,14.15 19.08,14 19.31,13.78 19.46,13.78 19.88,14.2 20.19,14.2 20.39,14 20.39,13.69 23.36,10.72 v2(23.36,10)
  BOTTOM w0.102: UR1.20 v2(18.12,16.34)
MS_D2_SD_CLK: length 11.9
  TOP w0.127: JREAD.5 24.11,20 v2(24.1,19.99)
  BOTTOM w0.102: RR2.2 22.08,19.75 CR6.1 22.08,18.37 21.98,18.27 21.39,18.27 21.26,18.15 21.26,17.89 21.39,17.76 21.98,17.76 22.08,17.66 22.08,17.36 21.98,17.26 21.45,17.26 21.32,17.13 21.32,16.88 21.45,16.75 v1(22.13,16.75) 22.72,16.75 22.85,16.88 22.85,19.54 R809.1
  BOTTOM w0.127: R809.1 24.1,19.99 v2(24.1,19.99)
MS_D2_SD_CLK_R: length 1.7
  BOTTOM w0.102: UR1.15 21.17,19.75 RR2.1
OCP_L: length 91.6
  TOP w0.254: RV90.2 179.44,133.47 178.95,132.98 v2(178.76,132.98)
  IN1 w0.254: v2(178.76,132.98) 179.29,132.98 180.16,132.12 183.73,132.12 185.51,130.34 194.8,130.34 197.36,127.78 197.36,114.12 v2(194.93,111.68)
  IN2 w0.254: v2(194.93,111.68) 195.12,111.49 195.12,93.7 194.14,92.72 192.23,92.72 189.93,90.42 185.65,90.42 183.59,88.37 174.35,88.37 173.42,89.29 169.21,89.29 167.23,91.27 166.43,91.27 v2(166.41,91.29)
  BOTTOM w0.203: PU1100.4 167.08,91.28 167.06,91.26 166.67,91.26 166.66,91.27 166.43,91.27 v2(166.41,91.29) 166,90.87 165.61,90.87 PR1112.2
ODD_DA#: length 62.7
  TOP w0.127: QH1.3 125.85,109.87 RH55.1 129.01,109.42 130.34,108.09 131.72,108.09 v1(133.67,110.04) 134.84,111.21 145.78,111.21 146.46,110.53 150.05,110.53 152.21,108.37 154.59,108.37 159.79,103.17 160.53,103.17 160.77,102.93 160.77,101.6 158.73,99.57 158.73,96.39 157.59,95.25 157.59,93.6 156.52,92.53 156.52,91.74 C229.1 157.16,86.08 156.24,85.17 156.24,84.86 155.95,84.57 JODD.17
ODD_DA#_FCH: length 14.3
  TOP w0.102: v2(123.38,97.93) 123.87,98.43
  TOP w0.127: 123.87,98.43 124.01,98.56 124.01,101.92 124.34,102.25 124.34,104.2 124.01,104.53 v1(124.01,106.04) 124.01,108.97 123.75,109.22 QH1.1
  BOTTOM w0.102: UC1.AJ1 123.47,96.72 123.11,97.08 123.11,97.67 v2(123.38,97.93)
ODD_DETECT#: length 79.3
  TOP w0.102: JODD.8 155.86,80.08 156.2,80.42 156.2,81.55 157.5,82.85 157.5,90.44 C228.1 159.07,92.01 159.07,99.43 161.11,101.46 161.11,103.08 160.67,103.52 159.93,103.52 v1(157.22,106.23) 154.74,108.71 152.35,108.71 149.5,111.56 134.13,111.56 v2(131.08,108.51)
  IN1 w0.102: v2(131.08,108.51) 130.28,108.51 129.38,107.61 129.38,107.38 126.56,104.57 126.56,103.08 125.83,102.35 125.83,99.04 124.33,97.54 124.33,96.14 123.75,95.57 123.18,95.57 122.84,95.91 v2(122.68,95.91)
  BOTTOM w0.102: UC1.AG3 122.17,95.23 122.68,95.74 v2(122.68,95.91)
ODD_EN: length 7
  TOP w0.102: v1(152.03,98.89) QS3.1 153.98,98.11 154.11,97.98 154.11,97.21 RS6.1 152.66,96.7 CS16.1 152.6,96.66 QS2.3
ODD_EN#: length 46.4
  TOP w0.102: QS3.2 154.63,100.79 153.42,102 152.54,102 149.69,99.15 v1(149.69,98.36) 149.69,94.11 149.74,94.07 149.74,93.81 148.71,92.79 148.71,92.28 148.33,91.9 148.33,90.93 150.55,88.71 150.55,87.08 150.04,86.57 150.04,85.67 149.52,85.15 148.13,85.15 v2(147.51,85.76)
  IN1 w0.102: v2(132.05,93.33) 132.45,93.33 136.4,89.38 137.75,89.38 138.47,88.67 v2(139.75,88.67)
  IN2 w0.102: v2(139.75,88.67) 139.96,88.87 141.86,88.87 142.85,89.87 144.95,89.87 147.72,87.09 147.72,85.97 v2(147.51,85.76)
  BOTTOM w0.102: UC1.AY5 132.14,93.42 v2(132.05,93.33)
ON/OFF: length 171.5
  TOP w0.127: C34.1 198.15,169.63 JPWR.2 198.15,165.75 198.6,165.3 v2(199.99,165.3) ; SW1.3 SW1.4 162.05,64.16 CE20.1 RE49.2 161.17,64.36 160.78,64.76 159.84,64.76 159.47,64.39 159.47,60.62 v4(159.94,60.14) 161.91,58.18 184.95,58.18 186.87,60.1 186.87,61.11 v2(187.55,61.79) 187.55,62 187.03,62.52 186.47,62.52 185.95,63.04 UE1.114
  IN1 w0.127: v2(187.55,61.79) 187.55,62.88 188.4,63.73 190.32,63.73 192.45,65.86 192.45,70.2 192.82,70.57 192.82,75.84 194.95,77.97 194.95,80.81 194.9,80.86 194.9,82.53 196.21,83.84 196.21,112.15 197.88,113.82 197.88,128.7 199.37,130.19 201.33,130.19 202.19,131.05 202.19,142.46 197.36,147.28 197.36,150.8 199.42,152.86 201.81,152.86 202.66,153.7 202.66,157.12 202.81,157.27 202.81,162.18 199.99,165 v2(199.99,165.3)
P_ZVDDP: length 3
  TOP w0.102: v2(115.17,91.52) 115.15,91.52 v1(114.71,91.08)
  TOP w0.254: R404.2 R542.2 115.37,91.31 v2(115.17,91.52)
  BOTTOM w0.203: v2(115.17,91.52) 114.77,91.92 UC1.U7
P_ZVSS: length 3.2
  TOP w0.254: R73.1 115.29,92.2 v2(115.17,92.32) v1(114.66,92.83) R541.1
  BOTTOM w0.203: v2(115.17,92.32) 114.77,92.72 UC1.U6
PACIN#: length 3.8
  TOP w0.102: QV8.5 185.67,130.13 RV147.2 185.67,130.37 185.25,130.78 QV8.6
  TOP w0.127: QV8.6 v1(185.51,131.67)
PANEL_BKLEN: length 227.1
  TOP w0.127: v2(171.74,72.14) 171.34,72.53 171.34,73.24 169.89,74.69 169.89,76.34 170.08,76.53 171.89,76.53 172.77,75.65 175.12,75.65 175.9,74.87 175.9,74.5 176.17,74.23 176.17,73.87 176.48,73.56 UE1.76 ; QC1.1 105.58,110.93 RC7.1 RC9.2 106.79,109.3 106.99,109.09 106.99,107.45 v2(106.04,106.5) ; v2(166.66,40.14) 166.99,40.14 167.1,40.03 RD16.2 166.9,39.32 166.9,38.06 167.17,37.78 U5.2
  IN1 w0.127: v2(162.69,70.03) 162.94,69.79 164.21,69.79 166.85,67.15 167.01,67.15 168.27,65.89 168.38,65.89 169.97,64.3 169.97,60.69 168.94,59.66 168.94,47.45 166.66,45.16 v2(166.66,40.14) ; v2(68.73,75.58) 70.11,76.97 70.86,76.97 89.08,95.19 89.56,95.19 91.14,96.76 v2(97.28,96.76)
  IN2 w0.127: v2(97.28,96.76) 96.93,97.1 96.93,100.57 102.86,106.5 v2(106.04,106.5)
  BOTTOM w0.127: v2(171.74,72.14) 171.34,71.74 165.89,71.74 164.48,70.33 163.29,70.33 162.99,70.03 v2(162.69,70.03) 161.36,70.03 159.78,68.45 156.83,68.45 155.32,66.94 151.66,66.94 145.47,60.75 136.38,60.75 135.12,59.5 89.91,59.5 76.62,72.79 71.51,72.79 v1(70.15,74.15) v2(68.73,75.58)
PANEL_BKLEN_EC: length 34.8
  TOP w0.102: 107.24,98.43 107.24,96.65 107.45,96.44 v1(107.45,95.78) 107.45,94.22 107.19,93.95 v2(106.61,93.95)
  TOP w0.127: RP45.8 101.39,102.97 101.67,102.69 105.45,102.69 107.24,100.9 107.24,98.43 ; QC1.3 105.71,109.03 RC9.1 106.36,107.7 105.53,106.87 105.53,106.41 v2(106.06,105.88)
  IN2 w0.102: v2(106.61,93.95) 106.86,93.95 108.08,95.17 108.08,98.43
  IN2 w0.127: v2(106.06,105.88) 106.06,104.85 106.39,104.52 108.1,104.52 108.63,103.99 108.63,101.99 108.08,101.44 108.08,98.43
  BOTTOM w0.102: v2(106.61,93.95) 106.18,93.52 UC1.G5
PANEL_SIZE_ID: length 113.8
  TOP w0.102: v2(136.25,87.41) 136.04,87.41 v1(135.73,87.11)
  TOP w0.127: RX11.1 RX16.1 RX3.1 87.26,156.53 89.02,154.76 89.02,153.99 89.41,153.61 v2(89.72,153.61)
  IN1 w0.102: 121.28,98.43 121.28,98.15 121.13,98 121.13,96.78 122.41,95.5 122.9,95.5 123.11,95.3 123.95,95.3 124.49,94.75 124.49,93.94 125.84,92.6 126.37,92.6 127.03,91.94 128.77,91.94 129.08,91.63 129.08,90.3 128.64,89.87 128.64,88.14 129.37,87.41 v2(136.25,87.41)
  IN1 w0.127: v2(89.72,153.61) 89.62,153.61 89.27,153.26 89.27,148.88 89.08,148.69 89.08,145.92 90.46,144.55 90.46,143.2 94.2,139.45 94.2,135.57 95.22,134.56 95.75,134.56 95.93,134.73 99.42,134.73 110.65,123.51 119.75,123.51 120.72,122.54 120.72,120.98 123.36,118.34 123.36,109.73 121.66,108.03 121.66,103.72 118.59,100.65 118.59,99.38 119.11,98.86 120.95,98.86 121.28,98.53 121.28,98.43
  BOTTOM w0.102: UC1.BC13 135.33,87.29 136.14,87.29 136.25,87.4 v2(136.25,87.41)
PANEL_SIZE_ID_CONN: length 10.2
  TOP w0.127: RX3.2 87.26,157.67 v1(89.34,159.75) 90.91,161.33 90.91,163.47 v2(91.43,164)
  BOTTOM w0.127: JEDP.22 91.3,164.13 v2(91.43,164)
PBTN_OUT#: length 121.6
  TOP w0.102: UE1.122 189.15,62.93 189.25,62.83 189.25,59.64 187.22,57.61 170.44,57.61 169.88,57.05 169.27,57.05 168.98,57.34 v1(159.89,57.34) 158.12,57.34 155.56,54.79 v2(154.41,54.79)
  IN2 w0.102: v2(154.41,54.79) 154.2,55.01 151.31,55.01 147.38,58.93 147.38,66.95 149.23,68.8 149.23,72.32 144.78,76.77 144.78,79.43 146.35,81 146.35,85.14 147.38,86.17 147.38,86.97 144.81,89.53 142.99,89.53 141.94,88.49 140.18,88.49 139.56,87.87 136.14,87.87 135.64,87.37 128.72,87.37 128.06,88.03 124.79,88.03 121.77,91.05 121.77,93.64 120.33,95.08 v2(120.33,97.29)
  BOTTOM w0.102: R942.2 120.63,98.74 119.92,98.03 119.92,97.7 v2(120.33,97.29) 120.57,97.05 UC1.AE1
PC_BEEP: length 12.9
  IN1 w0.109: v2(177.41,25.15) 177.35,25.08 177.35,20.45 v2(176.78,19.88)
  BOTTOM w0.099: RA79.2 RA19.1 178.35,18.66 v1(177.51,19.49) 177.13,19.88 v2(176.78,19.88) ; DA8.1 178.3,24.07 177.41,24.96 v2(177.41,25.15)
PCC_GPIO_6: length 10.3
  TOP w0.102: v1(173.23,133.74) 173.67,133.31 v2(173.67,133.29) ; v2(178.91,133.94) 178.87,133.97 CVT90.2 179.47,134.73 RV90.1 180.38,134.39 RV91.1
  IN1 w0.102: 178.71,133.75 178.59,133.62 174.58,133.62 174.52,133.68 174.06,133.68 v2(173.67,133.29)
  IN1 w0.107: v2(178.91,133.94) 178.71,133.75
  BOTTOM w0.102: v2(173.67,133.29) 173.29,133.67 UV1.T8
PCIE_ARX_DTX_N0: length 124.4
  TOP w0.127: v2(59.34,164.07) 59.18,163.91 58.98,163.91 CL31.1
  IN2 w0.127: v2(115.04,89.78) 115.17,89.65 115.17,89.37 115.08,89.28 114.8,89.28 114.42,88.9 114.42,88.38 114.22,88.18 111.32,88.18 111.13,88.36 111.13,89.08 108.9,91.32 108.9,91.42 107.58,92.73 107.03,93.28 106.65,93.28 105.38,94.55 103.02,94.55 102.75,94.81 102.75,95.4 99.8,98.36 99.27,98.36 v2(99.1,98.53)
  BOTTOM w0.102: UC1.U9 114.57,90.25 v2(115.04,89.78)
  BOTTOM w0.127: v2(99.1,98.53) 98.94,98.36 98.72,98.36 98.04,97.69 96.95,97.69 94.1,100.53 94.1,116.65 103.05,125.6 103.05,132.64 96.13,139.55 96.13,141.77 94.48,143.42 90.98,143.42 82.97,151.44 81.18,151.44 70.57,162.04 68.07,162.04 66.23,163.88 59.53,163.88 v2(59.34,164.07)
PCIE_ARX_DTX_N0_C: length 9.7
  TOP w0.127: UL1.18 50.4,167.28 50.67,167 50.67,166.29 52.35,164.61 52.97,163.98 v3(55.11,163.98) 57.54,163.98 CL31.2
PCIE_ARX_DTX_N1: length 91.7
  IN2 w0.127: v2(162.23,52.5) 162.08,52.64 161.69,52.64 160.38,53.95 151.05,53.95 148.54,56.46 146.53,56.46 145.7,57.3 145.7,63.44 145.24,63.9 145.24,65.05 141.08,69.21 141.08,73.79 142.13,74.85 142.13,84.04 140.57,85.6 139.58,85.6 138.77,86.41 132.33,86.41 132.04,86.12 129.34,86.12 128.79,86.66 124.6,86.66 124.02,87.24 124.02,87.57 123.77,87.82 123.26,87.82 122.78,88.3 122.78,88.82 122.49,89.1 121.82,89.1 120.45,90.47 120.45,92.31 119.2,93.57 119.2,96.6 118.37,97.43 115.82,97.43 113.75,95.36 113.75,93.16 113.85,93.07 v2(114.03,93.07)
  BOTTOM w0.102: UC1.T5 113.37,93.79 113.49,93.92 114.01,93.92 114.14,93.79 114.14,93.18 v2(114.03,93.07)
  BOTTOM w0.127: JNGFF.35 162.68,52.52 162.54,52.67 162.4,52.67 v2(162.23,52.5)
PCIE_ARX_DTX_P0: length 124.4
  TOP w0.127: CL30.1 59.01,163.65 59.18,163.65 v2(59.34,163.49)
  IN2 w0.127: v2(115.17,88.62) 115.17,88.97 115.11,89.02 114.91,89.02 114.68,88.79 114.68,88.27 114.33,87.92 111.21,87.92 110.87,88.25 110.87,88.98 108.64,91.21 108.64,91.31 107.48,92.48 106.93,93.03 106.54,93.03 105.27,94.29 102.91,94.29 102.5,94.71 102.5,95.3 99.69,98.1 99.26,98.1 v2(99.1,97.94)
  BOTTOM w0.102: UC1.U10 v2(115.17,88.62)
  BOTTOM w0.127: v2(59.34,163.49) 59.48,163.63 v3(61.58,163.63) 66.12,163.63 67.96,161.79 70.47,161.79 81.07,151.18 82.86,151.18 90.87,143.17 94.38,143.17 95.88,141.67 95.88,139.45 102.8,132.53 102.8,125.71 93.84,116.76 93.84,100.43 96.84,97.43 98.15,97.43 98.82,98.11 98.94,98.11 v2(99.1,97.94)
PCIE_ARX_DTX_P0_C: length 9.6
  TOP w0.127: CL30.2 57.36,163.73 52.87,163.73 v3(51.83,164.76) 50.41,166.18 50.41,166.83 50.37,166.87 UL1.17
PCIE_ARX_DTX_P1: length 91.7
  IN2 w0.127: v2(113.97,92.32) 113.49,92.79 113.49,95.47 115.72,97.69 118.48,97.69 119.46,96.71 119.46,93.67 120.71,92.42 120.71,90.57 121.93,89.36 122.6,89.36 123.03,88.92 123.03,88.41 123.37,88.08 123.88,88.08 124.28,87.68 124.28,87.35 124.71,86.92 128.9,86.92 129.44,86.38 131.93,86.38 132.22,86.67 138.87,86.67 139.69,85.85 140.68,85.85 142.39,84.14 142.39,74.74 141.33,73.69 141.33,69.32 145.5,65.16 145.5,64.01 145.96,63.55 145.96,57.4 146.64,56.72 148.65,56.72 151.16,54.21 160.49,54.21 161.8,52.9 162.05,52.9 v2(162.23,53.08)
  BOTTOM w0.102: v2(113.97,92.32) 113.57,92.72 UC1.T6
  BOTTOM w0.127: v2(162.23,53.08) 162.38,52.92 162.51,52.92 162.61,53.03 JNGFF.33
PCIE_ATX_C_DRX_N0: length 105.2
  TOP w0.127: UL1.14 48.54,165.79 48.47,165.72 48.47,165.32 49.66,164.13 49.66,163.44 v2(49.26,163.03)
  IN2 w0.127: v2(49.26,163.03) 49.42,163.19 49.8,163.19 51.27,161.72 60.58,161.72 61.89,163.03 67.31,163.03 68.63,161.71 69.88,161.71 86.68,144.91 99.94,144.91 103.89,140.95 103.89,115.81 107.93,111.77 v2(107.93,111.16)
  BOTTOM w0.127: v2(107.93,111.16) 107.93,110.81 107.74,110.62 106.74,110.62 105.4,109.28 105.4,109.28 105.4,108.41 C225.2
PCIE_ATX_C_DRX_N1: length 123.6
  IN2 w0.127: v2(168.94,60.87) 168.94,62.25 167.7,63.5 167.7,64.44 166.2,65.93 166.2,66.37 166.04,66.54 166.04,68.47 161.78,72.72 161.78,82.38 160.99,83.17 160.99,90.7 160.52,91.17 160.52,97.33 155.71,102.14 155.71,105.68 153.19,108.19 147.08,108.19 146.89,108.01 146.68,107.8 146.68,107.79 146.13,107.24 135.46,107.24 131.91,110.79 131.91,113.24 131.12,114.03 v2(130,114.03)
  BOTTOM w0.127: JNGFF.29 163.37,54.01 167.56,54.01 168.94,55.4 v2(168.94,60.87) ; v2(130,114.03) 130,114.04 113.98,114.04 109.8,109.85 107.06,109.85 106.54,109.34 106.54,105.35 106.42,105.22 106.42,104.79 C227.2
PCIE_ATX_C_DRX_P0: length 105.2
  TOP w0.127: v2(49.24,163.62) 49.41,163.78 49.41,164.02 48.22,165.21 48.22,165.69 48.14,165.77 UL1.13
  IN2 w0.127: v2(108.51,111.16) 108.19,111.49 108.19,111.88 104.15,115.92 104.15,141.06 100.05,145.16 86.79,145.16 69.99,161.96 68.74,161.96 67.42,163.28 61.78,163.28 60.48,161.98 51.38,161.98 49.9,163.45 49.41,163.45 v2(49.24,163.62)
  BOTTOM w0.127: C224.2 105.66,108.41 105.66,109.17 106.85,110.36 107.85,110.36 108.19,110.7 108.19,110.84 v2(108.51,111.16)
PCIE_ATX_C_DRX_P1: length 123.6
  IN2 w0.127: v2(168.36,60.87) 168.69,61.2 168.69,62.15 167.44,63.39 167.44,64.33 165.95,65.83 165.95,66.27 165.78,66.43 165.78,68.36 161.52,72.62 161.52,82.27 160.74,83.06 160.74,90.59 160.26,91.07 160.26,97.22 155.45,102.03 155.45,105.57 153.09,107.94 147.19,107.94 147.08,107.83 146.94,107.69 146.23,106.98 135.35,106.98 131.66,110.68 131.66,113.13 131.01,113.78 130.33,113.78 v2(130,113.45)
  BOTTOM w0.127: C226.2 106.75,104.6 106.67,104.67 106.67,105.11 106.8,105.24 106.8,105.54 106.92,105.66 106.92,106.05 106.8,106.17 106.8,106.57 106.91,106.68 106.91,107.06 106.8,107.18 106.8,107.49 106.93,107.62 106.93,108 106.8,108.13 106.8,109.23 107.17,109.6 109.9,109.6 114.08,113.78 129.67,113.78 v2(130,113.45) ; JNGFF.27 164.24,54.52 164.29,54.47 164.29,54.37 164.39,54.27 167.45,54.27 168.69,55.51 168.69,60.54 v2(168.36,60.87)
PCIE_ATX_DRX_N0: length 14.8
  BOTTOM w0.102: UC1.R2 112.57,96.06 112.5,96.13 112.4,96.13 111.98,96.55 111.98,96.97 111.54,97.41 110.97,97.41 110.39,97.99 110.14,98.24 110.11,98.24 109.91,98.43
  BOTTOM w0.127: 109.91,98.43 107.12,101.22 v3(105.74,102.61) 105.3,103.04 105.3,106.96 C225.1
PCIE_ATX_DRX_N1: length 12.7
  BOTTOM w0.102: UC1.R3 112.5,95.06 112.5,94.84 112.59,94.75 112.79,94.75 112.99,94.96 112.99,95.13 112.85,95.27 112.85,95.76 112.91,95.82 112.91,96 112.82,96.09 112.82,96.51 112.9,96.59 112.9,96.83 111.78,97.96 111.47,97.96 111.12,98.31
  BOTTOM w0.127: 111.12,98.31 111,98.43 109.67,99.76 v3(109.56,99.86) 108.13,101.3 106.6,102.83 106.6,103.31 C227.1
PCIE_ATX_DRX_P0: length 14.7
  BOTTOM w0.102: UC1.R1 112.62,96.67 112.62,96.41 112.57,96.36 112.49,96.36 112.21,96.63 112.21,97.06 111.63,97.64 111.07,97.64 110.28,98.43
  BOTTOM w0.127: 110.28,98.43 105.56,103.15 v3(105.56,105.94) 105.56,106.76 C224.1
PCIE_ATX_DRX_P1: length 12.8
  BOTTOM w0.102: UC1.R4 112.57,94.44 112.67,94.54 112.86,94.54 113.19,94.88 113.19,95.21 113.05,95.35 113.05,95.67 113.14,95.76 113.14,96.1 113.05,96.18 113.05,96.45 113.13,96.53 113.13,96.93 111.87,98.19 111.57,98.19 111.37,98.39 111.37,98.41 111.31,98.46 111.31,98.48 111.3,98.49
  BOTTOM w0.127: 111.3,98.49 109.78,100.01 v3(107.86,101.93) 106.85,102.94 106.85,103.42 C226.1
PEG_CLKREQ#: length 125.4
  TOP w0.102: v2(178.34,134.13) 178.33,134.14 RV153.1
  IN2 w0.102: v2(178.34,134.13) 178.34,129.67 178.53,129.48 178.53,124.36 177.35,123.19 162.86,123.19 162.07,123.98 162.07,125.19 161.47,125.78 160.53,125.78 160.34,125.59 159.73,125.59 159.29,125.15 157.13,125.15 154.91,122.92 154.91,120.75 158.94,116.72 158.94,116.17 161.49,113.63 161.49,112.12 161.89,111.71 161.89,106.55 162.46,105.98 162.46,98.43 163.11,97.78 163.11,96.51 163.61,96.01 163.61,90.79 166.03,88.37 166.03,88 165.5,87.47 165.5,85.14 168.47,82.17 168.47,80.83 168.88,80.42 168.88,74.89 v2(168.97,74.8)
  BOTTOM w0.102: RH56.2 139.57,81.98 v1(143.25,78.3) 144.81,76.75 147.15,76.75 147.84,76.06 148.13,76.06 149.88,74.31 155.72,74.31 156.21,73.81 159.72,73.81 160.22,74.31 166.16,74.31 166.66,74.8 v2(168.97,74.8)
PEG_CLKREQ#_G: length 6.6
  TOP w0.102: v2(173.03,135.52) 173.03,134.78 173.17,134.64 173.74,134.64 173.97,134.41 173.97,134.16 174.14,134 174.77,134 175.11,133.66 175.8,133.66 ; 175.8,133.66 176.28,133.66 RV153.2 ; 175.8,133.66 v1(175.8,133.67)
  BOTTOM w0.102: UV1.N7 173.45,135.52 v2(173.03,135.52)
PEG_CLKREQ#_R: length 5.6
  BOTTOM w0.102: UC1.BB16 133.87,84.59 134.33,84.12 135.55,84.12 v2(136.41,83.27) 137.69,81.98 RH56.1
PEG_GTX_C_HRX_N0: length 55.8
  IN2 w0.127: v2(112.77,89.77) 112.6,89.61 112.6,89.45 112.77,89.28 113.09,89.28 113.28,89.47 113.28,91.78 112.71,92.35 112.71,95.93 115.52,98.75 116.33,98.75 121.72,104.14 121.72,105.61 122.92,106.8 122.92,107.26 v2(122.71,107.48)
  BOTTOM w0.102: v2(112.77,89.77) 112.22,90.32 UC1.P9
  BOTTOM w0.127: v2(122.71,107.48) 122.84,107.62 122.84,108.43 123.42,109 125.06,109 126.44,110.39 132.23,110.39 134.65,112.81 143.23,112.81 145.31,114.88 147.94,114.88 149.06,116.01 CV2.1
PEG_GTX_C_HRX_N1: length 58.8
  IN2 w0.127: v2(111.49,93.13) 111.49,92.93 111.59,92.84 111.79,92.84 111.89,92.94 111.89,97.82 110.85,98.86 110.85,101.25 113.48,103.88 113.48,108.92 v2(113.32,109.09)
  BOTTOM w0.102: v2(111.49,93.13) 111.1,93.52 UC1.N5
  BOTTOM w0.127: v2(113.32,109.09) 113.48,109.25 113.48,110.18 114.66,111.37 115.39,111.37 132.13,111.37 134.33,113.57 142.86,113.57 147.42,118.14 147.82,118.14 148.04,118.36 CV4.1
PEG_GTX_C_HRX_N2: length 64.2
  IN2 w0.127: v2(111.57,90.72) 111.66,90.62 111.66,90.47 111.56,90.37 111.21,90.37 111.04,90.55 111.04,96.47 110.03,97.48 110.03,101.27 112.66,103.9 112.66,107.79 v2(112.82,107.95)
  BOTTOM w0.102: v2(111.57,90.72) 111.05,90.72 110.97,90.8 UC1.N8
  BOTTOM w0.127: v2(112.82,107.95) 112.63,108.14 112.63,110.1 114.41,111.87 131.92,111.87 134.12,114.08 142.47,114.08 147.55,119.16 147.55,119.68 148.46,120.59 CV6.1
PEG_GTX_C_HRX_N3: length 65.4
  IN2 w0.127: v2(109.34,92.34) 109.34,92.06 109.43,91.97 109.8,91.97 109.9,92.07 109.9,92.52 109.6,92.82 109.6,95.98 108.51,97.07 108.51,101.26 111.31,104.06 111.31,104.47 v2(111.16,104.62)
  BOTTOM w0.102: UC1.L6 109.72,92.72 v2(109.34,92.34)
  BOTTOM w0.127: CV8.1 148.73,123.03 146.53,120.83 146.53,119.58 142.05,115.1 133.7,115.1 131.5,112.9 113.93,112.9 111.31,110.28 111.31,104.77 v2(111.16,104.62)
PEG_GTX_C_HRX_P0: length 55.8
  IN2 w0.127: v2(123.29,107.48) 123.17,107.36 123.17,106.7 121.98,105.5 121.98,104.03 116.43,98.49 115.63,98.49 112.96,95.82 112.96,92.45 113.53,91.88 113.53,89.36 113.2,89.03 112.88,89.03 112.77,88.91 v2(112.77,88.62)
  BOTTOM w0.102: UC1.P10 v2(112.77,88.62)
  BOTTOM w0.127: v2(123.29,107.48) 123.1,107.67 123.1,108.32 123.52,108.75 125.16,108.75 126.55,110.13 132.34,110.13 134.76,112.55 143.34,112.55 145.42,114.63 148.04,114.63 149.13,115.71 CV1.1
PEG_GTX_C_HRX_P1: length 58.8
  IN2 w0.127: v2(113.9,109.09) 113.74,108.93 113.74,103.77 111.11,101.15 111.11,98.96 112.15,97.92 112.15,92.83 111.9,92.58 111.67,92.58 111.49,92.4 v2(111.49,92.33)
  BOTTOM w0.102: v2(111.49,92.33) 111.1,92.72 UC1.N6
  BOTTOM w0.127: CV3.1 148.4,118.36 147.92,117.88 147.53,117.88 142.96,113.31 134.44,113.31 132.23,111.11 115.39,111.11 115.39,111.11 114.77,111.11 113.73,110.08 113.73,109.25 v2(113.9,109.09)
PEG_GTX_C_HRX_P2: length 64.2
  IN2 w0.127: v2(111.57,89.96) 111.41,90.12 111.11,90.12 110.78,90.45 110.78,96.36 109.77,97.37 109.77,101.38 112.4,104.01 112.4,107.79 v2(112.24,107.95)
  BOTTOM w0.102: UC1.N9 111.21,90.32 v2(111.57,89.96)
  BOTTOM w0.127: v2(112.24,107.95) 112.38,108.09 112.38,110.21 114.3,112.13 131.81,112.13 134.02,114.34 142.36,114.34 147.29,119.26 147.29,119.79 148.35,120.85 CV5.1
PEG_GTX_C_HRX_P3: length 65.4
  IN2 w0.127: v2(111.74,104.62) 111.57,104.45 111.57,103.95 108.77,101.16 108.77,97.18 109.86,96.09 109.86,92.93 110.16,92.63 110.16,91.97 109.9,91.72 109.52,91.72 v2(109.34,91.54)
  BOTTOM w0.102: UC1.L7 109.72,91.92 v2(109.34,91.54)
  BOTTOM w0.127: CV7.1 148.89,122.83 146.78,120.72 146.78,119.47 142.15,114.84 133.81,114.84 131.61,112.65 114.03,112.65 111.57,110.18 111.57,104.8 v2(111.74,104.62)
PEG_GTX_HRX_N0: length 15.4
  BOTTOM w0.089: UV1.AG31 156.14,124.71 156.14,124.57 156.03,124.46 154.64,124.46 154.36,124.19 154.34,124.19 154.33,124.18
  BOTTOM w0.127: CV2.2 150.16,116.99 150.56,117.39 150.56,117.57 150.18,117.94 150.18,118.33 150.62,118.77 151.01,118.77 151.7,118.09 151.87,118.09 152.16,118.38 152.16,118.56 v3(151.78,118.94) 151.48,119.24 151.48,119.63 151.92,120.07 152.31,120.07 152.82,119.56 152.92,119.56 153.43,120.07 153.43,123.28 154.33,124.18
PEG_GTX_HRX_N1: length 15.5
  BOTTOM w0.089: UV1.AF28 157.11,125.38 156.75,125.38 156.6,125.22 156.48,125.22 arc(156.39,125.24) 156.31,125.28 arc(156.3,125.28) 156.29,125.29 arc(156.27,125.3) 156.26,125.32 156.25,125.33 155.93,125.33 155.89,125.28 arc(155.87,125.27) 155.85,125.25 arc(155.8,125.23) 155.74,125.22 155.67,125.22 155.48,125.03 154.98,125.03 154.97,125.04 154.37,125.04 154.35,125.06 154.33,125.06
  BOTTOM w0.127: 154.33,125.06 153.66,125.06 152.27,123.67 151.79,123.19 151.79,122.82 152.67,121.95 152.67,121.67 152.48,121.48 152.2,121.48 v3(151.83,121.85) 151.35,122.33 150.92,122.33 150.22,121.62 150.22,121.24 150.76,120.7 150.76,120.52 150.47,120.23 150.29,120.23 150.21,120.32 149.81,120.32 149.13,119.63 CV4.2
PEG_GTX_HRX_N2: length 15.8
  BOTTOM w0.089: 154.33,126.63 154.35,126.63 154.37,126.64 154.73,126.64 154.94,126.43 155.69,126.43 155.91,126.65 156.21,126.65 156.38,126.48 156.38,126.08 156.61,125.85 157.65,125.85 157.72,125.78 157.72,125.46 157.94,125.24 158.19,125.24 158.3,125.34 158.57,125.34 158.78,125.56 UV1.AF26
  BOTTOM w0.127: 154.33,126.63 154.22,126.63 153.99,126.4 153.99,126.12 153.63,125.75 153.24,125.75 152.88,126.11 152.71,126.11 152.42,125.82 152.42,125.64 152.77,125.29 152.77,124.89 152.56,124.68 152.33,124.46 151.94,124.46 151.64,124.75 151.47,124.75 151.18,124.46 151.18,124.28 151.47,123.99 151.47,123.59 v3(150.8,122.93) 149.63,121.75 CV6.2
PEG_GTX_HRX_N3: length 15.7
  BOTTOM w0.089: UV1.AD26 158.82,127.23 158.82,127.47 158.63,127.66 156.74,127.66 156.6,127.79 156.6,128.19 156.28,128.51 156.08,128.51 155.85,128.51 155.76,128.43 154.37,128.43 154.35,128.45 154.33,128.45
  BOTTOM w0.127: 154.33,128.45 153.6,128.45 v3(153.17,128.03) 152.67,127.52 152.49,127.52 152.06,127.94 151.67,127.94 151.23,127.5 151.23,127.11 151.66,126.69 151.66,126.51 151.37,126.22 151.19,126.22 150.77,126.64 150.37,126.64 149.94,126.21 149.94,125.81 150.36,125.39 150.36,125.21 150.02,124.87 150.02,124.24 149.87,124.1 149.38,124.1
PEG_GTX_HRX_P0: length 15.5
  BOTTOM w0.089: 154.51,124 154.52,124.01 154.52,124.03 154.57,124.08 154.73,124.25 156.2,124.25 UV1.AH30
  BOTTOM w0.127: 154.51,124 153.69,123.17 153.69,119.96 153.03,119.3 152.71,119.3 152.2,119.81 152.02,119.81 151.73,119.53 151.73,119.35 151.96,119.12 152.42,118.66 152.42,118.27 151.98,117.83 151.59,117.83 150.9,118.52 150.73,118.52 150.44,118.23 150.44,118.05 v3(150.62,117.87) 150.81,117.67 150.81,117.28 150.33,116.79 CV1.2
PEG_GTX_HRX_P1: length 15.5
  BOTTOM w0.089: 154.33,124.8 154.35,124.8 154.37,124.82 154.97,124.82 154.98,124.83 155.57,124.83 155.76,125.02 155.76,125.02 arc(155.86,125.03) 155.95,125.08 arc(155.96,125.08) 155.96,125.08 156.03,125.12 156.17,125.12 arc(156.18,125.12) 156.19,125.11 arc(156.3,125.04) 156.43,125.02 156.73,125.02 156.85,125.15 157.02,125.15 157.12,125.04 157.12,124.89 156.99,124.76 UV1.AG29
  BOTTOM w0.127: 154.33,124.8 153.77,124.8 v3(152.45,123.49) 152.05,123.09 152.05,122.93 152.92,122.06 152.92,121.56 152.58,121.22 152.1,121.22 151.65,121.67 151.25,122.07 151.03,122.07 150.48,121.52 150.48,121.35 151.02,120.81 151.02,120.42 150.58,119.98 150.19,119.98 150.1,120.06 149.92,120.06 149.31,119.45 CV3.2
PEG_GTX_HRX_P2: length 15.8
  BOTTOM w0.089: 154.33,126.88 154.35,126.88 154.37,126.86 154.82,126.86 155.03,126.65 155.6,126.65 155.82,126.86 156.3,126.86 156.59,126.57 156.59,126.17 156.71,126.06 157.74,126.06 157.94,125.87 158.47,125.87 158.57,125.78 158.57,125.65 158.47,125.56 UV1.AF27
  BOTTOM w0.127: CV5.2 149.39,121.88 150.62,123.11 151.22,123.7 151.22,123.88 150.92,124.18 150.92,124.57 151.36,125.01 151.75,125.01 152.05,124.71 152.23,124.71 v3(152.37,124.86) 152.51,125 152.51,125.18 152.16,125.53 152.16,125.92 152.6,126.36 152.99,126.36 153.34,126.01 153.52,126.01 153.74,126.22 153.74,126.5 154.12,126.88 154.33,126.88
PEG_GTX_HRX_P3: length 15.6
  BOTTOM w0.089: UV1.AD27 158.15,127.1 158.54,127.1 158.6,127.16 158.6,127.38 158.53,127.46 156.63,127.46 156.62,127.47 156.6,127.47 156.38,127.69 156.38,128.09 156.18,128.28 155.94,128.28 155.88,128.21 154.37,128.21 154.35,128.2 154.33,128.2
  BOTTOM w0.127: 150,123.47 150,123.87 150.27,124.14 150.27,124.76 150.61,125.11 150.61,125.5 150.19,125.92 150.19,126.1 150.48,126.39 150.66,126.39 v3(150.85,126.2) 151.08,125.97 151.47,125.97 151.91,126.4 151.91,126.8 151.49,127.22 151.49,127.4 151.78,127.69 151.96,127.69 152.38,127.26 152.77,127.26 153.35,127.84 153.7,128.2 154.33,128.2
PEG_HTX_C_GRX_N0: length 65
  IN2 w0.127: v2(147.99,123.64) 148.18,123.45 151.18,123.45 153.74,126.01 154.4,126.01 v2(154.6,126.2)
  BOTTOM w0.102: v2(154.6,126.2) 154.77,126.02 155.19,126.02 155.25,126.09 155.95,126.09 156.09,126.23 UV1.AE31
  BOTTOM w0.127: v2(147.99,123.64) 147.82,123.47 147.21,123.47 145.54,121.8 145.54,120.47 143.69,118.62 135.95,118.62 132.13,114.8 113.52,114.8 111.21,112.49 107.53,112.49 104.01,108.96 104.01,104.91 C176.2
PEG_HTX_C_GRX_N1: length 72.7
  IN2 w0.127: v2(157.69,126.76) 157.54,126.91 157.54,127.31 157.16,127.7 156.73,127.7 156.24,128.19 156.24,128.74 155.45,129.54 154.18,129.54 152.3,127.65 152.02,127.65 150.67,126.3 147.96,126.3 147.92,126.34 v2(147.81,126.46)
  BOTTOM w0.089: UV1.AD28 v2(157.69,126.76)
  BOTTOM w0.127: C178.2 101.47,104.91 101.47,108.71 107.44,114.68 110.99,114.68 112.64,116.33 131.5,116.33 135.43,120.27 143.06,120.27 144.01,121.22 144.01,123.19 147.07,126.25 147.61,126.25 v2(147.81,126.46)
PEG_HTX_C_GRX_N2: length 65.2
  IN2 w0.127: v2(148.06,125.14) 148.2,124.99 148.2,124.62 148.48,124.34 150.69,124.34 154.38,128.03 154.85,128.03 154.97,127.91 154.97,127.8 154.8,127.63 v2(154.8,127.61)
  BOTTOM w0.089: v2(154.8,127.61) 155.2,128.02 156.03,128.02 UV1.AC31
  BOTTOM w0.127: v2(148.06,125.14) 148.23,124.97 148.23,124.87 148.07,124.71 146.87,124.71 144.78,122.62 144.78,120.91 143.38,119.5 135.75,119.5 131.81,115.56 113.08,115.56 111.12,113.6 107.5,113.6 102.86,108.96 102.86,108.96 102.86,108.41 C177.2
PEG_HTX_C_GRX_N3: length 69.8
  IN2 w0.127: v2(148.81,127.51) 150.69,127.51 151.51,128.34 151.86,128.34 153.84,130.32 156.43,130.32 157.53,129.21 157.53,128.5 v2(157.64,128.4)
  BOTTOM w0.089: UV1.AB28 157.29,128.75 v2(157.64,128.4)
  BOTTOM w0.127: v2(148.81,127.51) 147.13,127.51 143.25,123.63 143.25,121.74 142.67,121.16 135.24,121.16 131.18,117.09 112.26,117.09 110.67,115.51 107.12,115.51 100.32,108.71 100.32,108.41 C175.2
PEG_HTX_C_GRX_P0: length 64.8
  IN2 w0.127: v2(147.99,123.05) 148.13,123.19 151.29,123.19 153.85,125.75 154.41,125.75 v2(154.58,125.58)
  BOTTOM w0.102: v2(154.58,125.58) 154.8,125.79 155.28,125.79 155.35,125.86 156,125.86 156.3,125.56 UV1.AF30
  BOTTOM w0.127: C185.2 104.26,104.91 104.26,108.86 107.64,112.23 111.32,112.23 113.63,114.54 132.24,114.54 136.05,118.36 143.8,118.36 145.8,120.36 145.8,121.69 147.32,123.22 147.82,123.22 v2(147.99,123.05)
PEG_HTX_C_GRX_P1: length 72.6
  IN2 w0.127: v2(147.81,125.87) 147.98,126.04 150.78,126.04 152.12,127.39 152.4,127.39 154.29,129.28 155.34,129.28 155.98,128.64 155.98,128.09 156.63,127.44 157.05,127.44 157.28,127.21 157.28,126.62 157.16,126.5 157,126.5 156.88,126.62 v2(156.88,126.87)
  BOTTOM w0.089: v2(156.88,126.87) 156.99,126.76 156.99,126.46 UV1.AE29
  BOTTOM w0.127: C215.2 101.72,104.91 101.72,108.6 107.54,114.42 111.1,114.42 112.75,116.07 131.6,116.07 135.54,120.01 143.17,120.01 144.27,121.12 144.27,123.09 147.18,126 147.68,126 v2(147.81,125.87)
PEG_HTX_C_GRX_P2: length 65.2
  IN2 w0.127: v2(155.39,127.63) 155.22,127.79 155.22,128.02 154.95,128.29 154.27,128.29 150.58,124.6 148.58,124.6 148.46,124.73 148.46,124.95 v2(148.64,125.14)
  BOTTOM w0.089: UV1.AD30 156.07,127.58 156.03,127.58 155.96,127.65 155.96,127.65 155.79,127.82 155.46,127.82 155.39,127.74 v2(155.39,127.63)
  BOTTOM w0.127: v2(148.64,125.14) 148.48,124.98 148.48,124.76 148.17,124.46 146.98,124.46 145.04,122.52 145.04,120.8 143.48,119.25 135.86,119.25 131.92,115.31 113.19,115.31 111.23,113.35 107.61,113.35 103.12,108.86 103.12,108.63 103.12,108.63 103.12,108.4 C223.2
PEG_HTX_C_GRX_P3: length 69.8
  IN2 w0.127: v2(156.89,128.45) 157.17,128.45 157.28,128.56 157.28,129.1 156.32,130.06 153.94,130.06 151.96,128.08 151.62,128.08 150.79,127.25 149.14,127.25 v2(148.81,126.93)
  BOTTOM w0.089: UV1.AC29 157.01,127.96 157.14,128.09 157.14,128.33 157.03,128.45 v2(156.89,128.45)
  BOTTOM w0.127: v2(148.81,126.93) 148.49,127.25 147.23,127.25 143.51,123.53 143.51,121.63 142.78,120.9 135.35,120.9 131.28,116.84 112.37,116.84 110.78,115.25 107.22,115.25 100.58,108.61 100.58,108.4 C196.2
PEG_HTX_GRX_N0: length 11.6
  BOTTOM w0.102: UC1.M1 110.1,96.26 110.1,96.06 110.18,95.99 110.27,95.99 110.48,96.2 110.48,96.43 110.41,96.5 110.41,96.94 110.54,97.07 110.54,97.2 110.26,97.48 109.76,97.48 108.99,98.25
  BOTTOM w0.127: C176.1 104,103.37 104,103.09 104.22,102.87 v3(105.93,101.16) 108.39,98.7 108.54,98.7 108.99,98.25
PEG_HTX_GRX_N1: length 12.1
  BOTTOM w0.102: UC1.L2 109.26,96.02 109.13,96.02 108.88,96.27 108.88,96.44 108.78,96.54 108.78,96.86 108.61,97.03 108.12,97.03 107.48,97.67 106.7,97.67 106.17,98.21 106.05,98.21 105.83,98.43
  BOTTOM w0.127: C178.1 101.47,103.37 101.47,102.8 v3(102.69,101.57) 104.06,100.2 104.35,99.91 105.61,98.65 105.83,98.43
PEG_HTX_GRX_N2: length 16.6
  BOTTOM w0.102: 107.75,98.25 107.79,98.25 108.52,97.51 109.04,97.51 109.73,96.82 109.73,96.65 109.6,96.51 109.6,96.12 109.67,96.05 109.67,95.79 109.63,95.75 109.63,95.34 109.77,95.2 109.77,94.84 109.63,94.69 109.47,94.69 109.37,94.8 UC1.L3
  BOTTOM w0.127: 107.75,98.25 103.29,102.71 103.27,102.71 103.13,102.85 102.86,103.12 v3(102.86,106.05) 102.86,106.86 C177.1
PEG_HTX_GRX_N3: length 14.8
  BOTTOM w0.102: 104.92,98.25 104.93,98.24 104.95,98.24 105.01,98.19 105.02,98.19 105.48,97.73 105.77,97.73 106.56,96.94 106.79,96.94 107.6,96.13 107.69,96.13 107.77,96.05 UC1.J2
  BOTTOM w0.127: 104.92,98.25 100.99,102.19 100.32,102.85 v3(100.32,106.07) 100.32,106.86 C175.1
PEG_HTX_GRX_P0: length 11.7
  BOTTOM w0.102: UC1.M2 110.17,95.56 110.71,96.1 110.71,96.53 110.65,96.6 110.65,96.85 110.78,96.98 110.78,97.29 110.36,97.71 109.89,97.71 109.17,98.43
  BOTTOM w0.127: 109.17,98.43 108.64,98.96 108.5,98.96 v3(107.39,100.07) 106.11,101.34 104.33,103.13 104.33,103.13 104.26,103.19 104.26,103.37 C185.1
PEG_HTX_GRX_P1: length 12.1
  BOTTOM w0.102: 106.27,98.43 106.8,97.9 107.58,97.9 108.22,97.26 108.71,97.26 109.01,96.95 109.01,96.64 109.11,96.53 109.11,96.37 109.22,96.26 109.32,96.26 109.39,96.33 109.39,96.56 109.37,96.58 UC1.L1
  BOTTOM w0.127: 106.27,98.43 106.23,98.47 106.15,98.47 105.8,98.83 v3(104.24,100.39) 102.87,101.76 101.72,102.9 101.72,103.37 C215.1
PEG_HTX_GRX_P2: length 16.7
  BOTTOM w0.102: 107.93,98.43 108.07,98.29 108.62,97.74 109.13,97.74 109.96,96.91 109.96,96.55 109.83,96.41 109.83,96.2 109.82,96.19 109.87,96.13 109.87,95.71 109.83,95.66 109.83,95.43 109.97,95.28 109.97,94.75 109.71,94.49 109.54,94.49 UC1.L4
  BOTTOM w0.127: C223.1 103.12,106.86 103.12,103.22 103.31,103.03 103.38,102.96 103.4,102.96 v3(104.13,102.23) 107.67,98.69 107.93,98.43
PEG_HTX_GRX_P3: length 14.8
  BOTTOM w0.102: 105.11,98.43 105.58,97.96 105.87,97.96 106.65,97.17 106.88,97.17 107.69,96.36 107.79,96.36 107.89,96.46 107.89,96.59 UC1.J1
  BOTTOM w0.127: 105.11,98.43 v3(101.17,102.37) 100.58,102.96 100.58,106.86 C196.1
PGOOD_1.35VGPU: length 4.9
  BOTTOM w0.254: PU1400.2 198.84,163.61 199.07,163.39 199.07,162.72 v1(199.82,161.96) 200.21,161.57 200.21,160.83 PR1407.2
PHASE_CHG: length 12.4
  IN2 w0.762: 121.74,166.55 124.95,166.55 128.3,163.19 132.71,163.19
  vias: v2(120.14,166.79) v2(120.74,166.75) v2(133.41,163.45) v2(133.41,162.81)
PID0: length 4.5
  TOP w0.127: RE24.2 RE23.1 CE47.1 179.15,61.57 v1(179.15,62.4) UE1.97
PLL_ANALOG_IN: length 3.5
  BOTTOM w0.102: 179.28,128.17 178.5,128.95 177.66,128.95 177.29,129.32 UV1.AA1
  BOTTOM w0.127: T221.1 179.68,127.77 179.28,128.17
PLL_ANALOG_OUT: length 6.7
  BOTTOM w0.102: UV1.AA3 176.72,129.56 177.53,128.75 178.32,128.75 179.69,127.38 180.61,127.38 181.34,128.11 RV83.1
PLT_RST#: length 274
  TOP w0.102: v2(189.41,71.46) 189.41,71.44 190.5,70.36 191.57,70.36 191.58,70.36 UE1.13 ; RH29.1 v2(56.32,165.35) ; v2(133.15,102.55) 133.1,102.6 RH27.2 ; RM6.2 171.9,50.16 v2(172.05,50.32)
  IN2 w0.102: v2(172.05,50.32) 172.78,51.04 172.78,54.04 166.74,60.07 166.74,62.74 163.47,66.02 163.47,66.08 163.18,66.37 163.18,67.88 161.17,69.89 161.17,70.25 159.35,72.07 159.35,73.68 159.89,74.21 159.89,75.92 v2(159.63,76.17) 159.12,76.68 159.12,89.87 158.65,90.34 158.65,96.55 157.91,97.29 157.44,97.29 153.8,100.94 153.8,104.82 152.49,106.13 148.32,106.13 147.05,104.86 136.96,104.86 136.6,104.5 135.54,104.5 134.59,103.56 134.16,103.56 v2(133.15,102.55) 132.85,102.25 131.7,102.25 131.13,101.68 128.9,101.68 128.06,102.51 128.06,106.34 126.72,107.68 126.72,110.54 123.56,113.7 109.44,113.7 106.22,116.92 106.22,141.99 100.49,147.72 86.88,147.72 78.95,155.65 78.95,156.37 78.53,156.79 77.74,156.79 69.67,164.86 56.81,164.86 v2(56.32,165.35)
  BOTTOM w0.102: v2(189.41,71.46) 188.7,71.46 188.08,72.08 187.6,72.08 187.37,72.3 186.23,72.3 185.44,73.09 183.51,73.09 182.38,71.96 178.64,71.96 176.78,73.83 176.46,73.83 176.44,73.84 175.53,73.84 172.75,76.62 165.98,76.62 165.54,76.17 v2(159.63,76.17) 153.22,76.17 v1(152.96,76.43) 152.11,77.28 152.11,79.5 150.43,81.18 148.09,81.18 145.08,84.19 145.08,85.49 144.65,85.92 142.18,85.92 C615.1 RH1.2 140.23,86.06 R602.1
PLT_RST#_R: length 6
  TOP w0.102: RH29.2 RH31.2 53.28,165.93 52.53,165.93 52.18,166.28 v1(51.73,166.28) 51.45,166.28 51.05,166.69 51.05,167.27 50.64,167.68 UL1.19
PLT_RST#_RW: length 3.8
  TOP w0.127: v1(169.14,49.83) v2(169.79,50.48) 170.1,50.16 RM6.1 RH32.2
  BOTTOM w0.127: JNGFF.44 169.99,50.27 v2(169.79,50.48)
PLT_RST_VGA#: length 7
  BOTTOM w0.102: UV2.4 158.02,116.75 158.34,117.07 158.34,117.32 158.57,117.56 RV4.1 v1(158.57,120.09) 158.57,120.37 158.09,120.85 UV1.AL27
PM_SLP_S3#: length 104
  TOP w0.102: RE53.1 CE25.1 195.84,65.91 195.01,65.91 v2(194.5,65.4)
  IN2 w0.102: v2(124.79,91.76) 125.05,92.02 126.12,92.02 126.51,91.63 126.51,91.44 127.94,90 129.92,90 130.09,90.17 130.21,90.17 130.78,90.74 135.44,90.74 135.61,90.91 137.13,90.91 137.28,90.76 138.09,90.76 140.4,93.07 145.98,93.07 v2(146.08,92.98) ; v2(194.5,65.4) 194.5,61.66 190.12,57.28 181.5,57.28 170.68,68.1 170.05,68.1 168.74,69.41 168.74,70.04 164.71,74.08 164.71,83.36 163.61,84.46 163.61,84.73 163.61,86.83 v2(163.48,86.96)
  BOTTOM w0.102: v2(124.79,91.76) 124.33,91.76 UC1.AK7 ; v2(146.08,92.98) 146.58,92.48 148.39,92.48 148.68,92.77 152.28,92.77 155.46,89.6 v1(156.76,89.6) 158.72,89.6 161.29,87.03 163.4,87.03 v2(163.48,86.96)
PM_SLP_S3#_R: length 2.3
  TOP w0.127: RE53.2 194.75,67.44 194.63,67.56 v1(194.56,67.56) UE1.6
PM_SLP_S5#: length 228.8
  TOP w0.102: v2(194.47,71.15) 194.49,71.17 195.92,71.17 RE54.1 CE33.1
  TOP w0.254: v2(109.47,134.66) 107.12,134.66 100.46,141.31 100.46,145 101.4,145.94 101.4,149.31 106.34,154.25 106.34,157.77 109.65,161.08 PR781.1
  IN1 w0.102: v2(194.47,71.15) 193.97,70.65 193.97,69.93 193.71,69.66 v2(193.71,64.8) ; v2(109.47,124.08) 110.38,123.16 119.61,123.16 120.38,122.4 120.38,120.84 123.02,118.2 123.02,109.87 121.32,108.17 121.32,103.86 118.2,100.75 118.2,98.75 118.63,98.32 119.5,98.32 119.63,98.45 120.57,98.45 120.93,98.09 120.93,96.7 122.39,95.24 122.74,95.24 122.93,95.05 122.93,94.59 123.37,94.15 v2(123.37,94.05)
  IN2 w0.102: v2(123.37,94.05) 123.64,94.05 124.21,93.48 124.21,91 124.59,90.62 125.08,90.62 125.51,91.05 126.29,91.05 128.5,88.84 132.37,88.84 132.64,89.12 134.73,89.12 134.94,89.33 136.7,89.33 137.11,89.74 139.9,89.74 141.48,91.32 145.35,91.32 147.25,89.42 148.14,89.42 148.49,89.06 148.49,87.78 149.08,87.2 149.08,85.65 147.26,83.83 147.26,80.62 145.7,79.05 145.7,77.15 150.14,72.7 150.14,66.22 148.34,64.42 v2(148.34,59.47) ; v2(109.47,124.08) v2(109.47,134.66)
  BOTTOM w0.102: v2(148.34,59.47) 148.34,59.17 151.36,56.15 156.27,56.15 159.37,59.25 v1(159.37,64.73) 159.37,65.87 161.88,68.38 164.11,68.38 164.57,68.84 167.23,68.84 168.64,70.26 172.74,70.26 174.25,68.75 177.13,68.75 177.18,68.8 188.17,68.8 189.83,67.14 189.83,66 190.05,65.77 192.73,65.77 v2(193.71,64.8) ; v2(123.37,94.05) 122.99,93.68 122.99,93.55 UC1.AH5
PM_SLP_S5#_R: length 4.3
  TOP w0.127: UE1.14 193.97,70.76 193.99,70.74 RE54.2 195.88,70.29 v1(197.25,70.29)
POK: length 263.4
  TOP w0.127: v2(192.12,81.12) 191.96,80.95 191.55,80.95 191.15,80.55 UE1.34
  TOP w0.203: PR115.2 38.61,52.44 39.88,51.18 PU100.7
  TOP w0.254: PR115.2 38.65,52.45 v2(39.24,53.04)
  IN1 w0.127: v2(39.24,53.04) 40.37,54.17 47.34,54.17 50.49,51.02 50.49,45.63 51.28,44.84 51.28,24.84 54.49,21.63 55.84,21.63 60.32,17.14 60.32,15.69 61.64,14.36 99.15,14.36 101.35,12.15 155.16,12.15 158.57,15.56 158.57,24.66 160.44,26.54 160.44,32.27 163.69,35.52 163.69,51.21 165.6,53.12 165.6,60.37 166.72,61.49 166.72,62.78 166.41,63.08 166.41,65.61 v2(166.75,65.94)
  BOTTOM w0.127: v2(192.12,81.12) 192.46,80.78 194.17,80.78 194.94,80.01 194.94,77.28 195.09,77.13 195.09,74.53 195.22,74.41 195.22,71.26 195.36,71.12 195.36,69.34 195.26,69.24 v1(195.26,68.77) 195.26,68.58 195.38,68.45 195.38,67.14 195.01,66.78 195.01,64.45 194.32,63.75 181.69,63.75 180.91,64.53 175.1,64.53 174.34,65.29 172.68,65.29 171.81,64.43 170.26,64.43 168.5,66.18 166.99,66.18 v2(166.75,65.94)
POL1_SDA: length 4.1
  TOP w0.127: UZ1.22 38.27,66.26 v1(38.66,65.86) 38.66,64.57 RZ2.1 RZ1.2
POL2_SCL: length 5.9
  TOP w0.127: UZ1.23 38.77,66.45 39.08,66.14 39.44,66.14 39.67,65.91 39.67,64.58 RZ4.1 RZ3.2 40.47,63.2 v1(41.26,62.41)
PROG: length 3.4
  BOTTOM w0.203: PR753.2 113.82,170.97 v1(113.82,170.98) 113.83,170.97 114.52,170.97 115.16,170.33 115.31,170.33 115.55,170.09 PU703.9
PS_0: length 9.5
  TOP w0.102: v2(164.03,127.35) v1(163.65,126.97) 163.51,126.82 163.51,125.34 163.83,125.01 164.73,125.01 165.54,124.2 166.92,124.2 167.22,123.91 CV29.1 167.22,122.77 RV9.1 RV8.2
  BOTTOM w0.102: UV1.AC19 164.64,127.96 v2(164.03,127.35)
PS_1: length 9.8
  TOP w0.102: RV11.2 168.98,121.91 RV12.1 CV28.1 168.24,124.4 165.72,124.4 164.9,125.22 164.2,125.22 v1(163.96,125.46) 163.73,125.68 163.73,126.37 v2(164.12,126.75)
  BOTTOM w0.102: UV1.AD19 164.52,127.16 v2(164.12,126.75)
PS_2: length 9.1
  TOP w0.102: v2(165.39,125.32) v1(165.85,124.86) 166.05,124.66 168.48,124.66 169.04,124.09 170.31,124.09 CV11.1 170.75,123.66 RV13.1 170.75,121.91 RV28.2
  BOTTOM w0.089: v2(165.39,125.32) 165.39,125.85 UV1.AE17
PS_3: length 7.6
  TOP w0.102: v2(162.99,126.02) 162.99,125.48 163.71,124.76 164.67,124.76 165.46,123.97 CV15.1 165.46,122.78 RV16.1 RV15.2 164.81,121.89 v1(164.37,121.45)
  BOTTOM w0.102: UV1.AE20 163.33,126.36 162.99,126.02 v2(162.99,126.02)
PS_ID: length 154.3
  TOP w0.127: v2(189.45,74.08) 190.38,73.15 190.38,72.84 189.81,72.26 189.81,71.53 190.21,71.13 191.91,71.13 192.33,71.56 UE1.16
  TOP w0.254: PR3.1 PR4.2 94.07,152.72 v2(93.19,151.83)
  IN1 w0.127: v2(189.45,74.08) 188.91,73.53 186.35,73.53 185.98,73.9 184.34,73.9 183.31,74.93 182.97,74.93 181.67,76.23 181.67,77.68 179.36,79.99 177.86,79.99 176.82,81.04 176.82,81.37 174.26,83.93 171.37,83.93 168.41,86.89 168.41,87.67 165.19,90.88 165.19,97.86 163.89,99.17 163.89,107.81 157.34,114.35 150.08,114.35 143.88,120.56 133.96,120.56 128.27,126.25 111.5,126.25 94.21,143.54 94.21,147.54 92.84,148.91 92.84,151.49 v2(93.19,151.83)
PSID: length 4.3
  TOP w0.127: PL2.2 93.58,160.38 92.61,160.38 v1(92.18,159.94)
  TOP w0.254: PJPDC1.3 94.15,159.85 PL2.2
PSID-1: length 5.4
  TOP w0.127: v1(88.37,156.44) 89.95,156.44 90.81,157.3 PQ5.2
  TOP w0.254: PQ5.2 90.19,157.93 PR9.2 PR6.1
PSID-2: length 5.2
  TOP w0.127: PR8.2 v1(90.95,153.33)
  TOP w0.254: PR8.2 90.16,155.22 PQ5.1 90.21,155.65 PQ6.2
PSID-3: length 3.4
  TOP w0.102: v1(96.13,153.17) 95.38,153.92 PR4.1
  TOP w0.254: PQ6.3 94.56,154.36 PR4.1
PTP_DIS#: length 151.6
  TOP w0.127: v2(64.94,75.59) 64.94,76.21 63.54,77.61 JTP.6 60.6,77.61 RE341.2 v1(60.08,78.28) ; v2(186.8,69.58) 186.8,71.14 186.31,71.64 186.31,73.61 186.46,73.76 188.14,73.76 188.44,74.05 v2(188.44,75.04)
  BOTTOM w0.127: v2(186.8,69.58) 186.59,69.37 177.59,69.37 175.71,71.25 173.63,71.25 173.36,71.51 165.99,71.51 164.57,70.1 163.38,70.1 162.92,69.64 161.29,69.64 159.87,68.22 156.93,68.22 155.42,66.71 151.75,66.71 145.56,60.52 136.47,60.52 135.22,59.27 89.82,59.27 76.52,72.56 69.62,72.56 66.59,75.59 v2(64.94,75.59) ; v2(188.44,75.04) 188.47,75.04 189.79,76.37 RE15.2
PTP_DIS#_R: length 3
  TOP w0.127: v2(189.82,78.32) 189.55,78.59 UE1.38
  BOTTOM w0.127: RE15.1 189.79,78.3 v2(189.82,78.32) v1(189.82,78.93)
PWR_PWM_LED: length 41.2
  TOP w0.127: R6107.2 v2(25.91,5.21)
  BOTTOM w0.127: v2(25.91,5.21) 28.15,5.21 v1(28.34,5.02) 28.86,4.5 32.56,4.5 40.02,11.95 58.57,11.95 60.59,13.97 Q6102.1
PWR_PWM_LED#: length 206.2
  TOP w0.127: UE1.92 178.52,67.16 178.87,66.8 178.87,65.12 175.03,61.28 171.25,61.28 v1(170.58,60.6) 169.91,59.94 v2(167.49,59.94)
  IN1 w0.127: v2(46.08,10.82) 46.27,10.63 95.02,10.63 97.31,8.34 156.74,8.34 166.19,17.79 166.19,32.56 165.29,33.45 165.29,45.33 167.9,47.93 167.9,59.53 v2(167.49,59.94)
  BOTTOM w0.127: R6104.1 63.13,14.02 61.45,12.34 59.28,12.34 58.66,11.72 46.98,11.72 v2(46.08,10.82)
PWR_PWM_LED_R#: length 43.4
  BOTTOM w0.127: Q6105.1 31.22,8.13 31.38,7.98 31.38,7.12 30.51,6.26 v1(30.51,5.02) 30.8,4.72 32.47,4.72 39.92,12.18 58.47,12.18 61.23,14.94 Q6102.2 R6104.2
PWRGD_VGA: length 107.7
  TOP w0.127: v2(186.08,70.5) 186.08,73.71 186.59,74.22 v2(187.9,74.22)
  IN1 w0.127: v2(166.61,93.76) 167.04,93.76 167.61,93.19 167.61,91.4 170.11,88.9 170.11,86.81 171.12,85.8 174.45,85.8 176.8,83.46 177.54,83.46 182.91,78.09 182.91,77.13 184.18,75.86 185.08,75.86 186.78,74.16 187.84,74.16 v2(187.9,74.22)
  IN2 w0.254: v2(173.16,95.25) 169.84,95.25 168.35,93.76 v2(166.61,93.76)
  BOTTOM w0.127: UC1.BC17 135.26,83.82 137.6,81.48 139.56,81.48 v1(144.19,76.86) 144.64,76.4 147.01,76.4 147.7,75.72 147.98,75.72 149.74,73.96 155.48,73.96 155.97,73.47 159.86,73.47 160.36,73.96 168.6,73.96 168.88,74.24 172.63,74.24 174.71,72.16 176.09,72.16 177.97,70.28 185.87,70.28 v2(186.08,70.5)
  BOTTOM w0.203: PU1100.9 167.21,93.28 166.97,93.53 166.84,93.53 v2(166.61,93.76) 165.98,94.38 165.98,94.42 165.79,94.61 PR1119.2 PR1122.1 ; v2(173.16,95.25) 172.36,95.25 172.14,95.02 PU1100.20
PX_EN: length 2
  TOP w0.102: T218.1 166.53,129.33 v2(166.53,128.24)
  BOTTOM w0.102: v2(166.53,128.24) 166.89,128.59 UV1.AB16
PXS_PWREN: length 194.1
  TOP w0.102: U75.4 150.2,125.61 149.28,126.53 149.28,128.02 v2(149.13,128.17) ; R438.1 R938.2 146.53,134.37 145.87,133.71 145.87,131.31 146.41,130.76 147.77,130.76 v2(148.04,131.03)
  TOP w0.254: v2(192.07,153.59) 192.65,153.59 193.62,152.63 193.62,149.25 194.54,148.32 194.54,142.88 194.02,142.35 194.02,134.94 192.89,133.81 192.89,132.68 192.73,132.51 192.73,132.23 192.18,131.69 v2(192.08,131.69)
  IN1 w0.254: v2(192.07,153.59) 192.39,153.28 201.64,153.28 202.24,153.88 202.24,157.33 v2(202.39,157.48)
  IN2 w0.102: v2(169.21,115.27) 169.37,115.27 172.17,118.06 183.51,118.06 184.74,119.29 184.74,120.2 192.08,127.55 v2(192.08,131.69) ; v2(162.12,94.07) 161.96,94.23 161.96,97.33 v2(158.9,100.39) 156.85,102.44 156.85,105.88 152.93,109.8 147.67,109.8 146.61,110.86 v2(146.61,113.03) 146.61,113.27 145.66,114.22 145.66,128.23 148.04,130.6 v2(148.04,131.03)
  BOTTOM w0.102: v2(149.13,128.17) 149.13,129.93 v2(148.04,131.03) ; v2(192.07,153.59) 192.07,152.97 190.96,151.87 189.19,151.87 188.98,152.07 U74.4 ; UC1.BB6 133.87,93.57 133.53,93.91 133.53,94.52 133.78,94.77 133.78,95.23 133.61,95.4 133.61,96.48 133.63,96.5 133.63,97.31 137.08,100.76 137.08,101.36 136.83,101.61 v1(136.83,102.25) 136.83,105.28 137.29,105.74 137.29,108.61 139.96,111.29 143.99,111.29 145.73,113.03 v2(146.61,113.03) ; v2(169.21,115.27) 163.2,115.27 160.24,112.3 160.24,106.3 158.04,104.11 158.04,101.24 v2(158.9,100.39)
  BOTTOM w0.254: PR1116.1 164.35,93.89 162.3,93.89 v2(162.12,94.07) ; PR1402.2 v2(202.39,157.48) ; PR1201.1 v2(192.08,131.69)
PXS_RST#: length 64.6
  TOP w0.102: v2(129.09,88.24) 129.09,88.24 131.33,88.24 131.48,88.39 132.6,88.39 133.12,88.91 133.51,88.91 134.12,89.52 134.36,89.76 134.36,94.05 134.89,94.59 136.23,94.59 136.35,94.72 138.28,94.72 138.99,95.43 141.24,95.43 v2(141.5,95.17)
  IN1 w0.102: v2(146.77,100) 146.37,99.61 146.37,97.26 144.29,95.17 v2(141.5,95.17)
  BOTTOM w0.102: v2(129.09,88.24) 129.09,86.86 128.67,86.44 UC1.AR14 ; v2(146.77,100) 150.89,100 151.76,99.13 v1(152.62,99.13) 154.53,99.13 154.92,99.52 154.92,104.64 151.58,107.98 151.58,113.49 153.28,115.19 153.28,116.67 153.56,116.95 155.6,116.95 156.65,115.9 158.41,115.9 158.76,116.24 158.76,117.14 159.01,117.4 UV2.2
REMOTE1+: length 7.9
  TOP w0.102: v2(151.52,41.86) v1(152.13,42.47)
  TOP w0.254: v2(151.52,41.86) C2502.1 151.52,40.92 150.92,40.33 U2407.2
  BOTTOM w0.254: Q2407.1 151.71,45 Q2407.2 151.71,42.74 C2500.1 v2(151.52,41.86)
REMOTE1-: length 5.4
  TOP w0.102: v2(150.6,41.82) v1(150.6,42.54)
  TOP w0.254: v2(150.6,41.82) C2502.2 150.6,41.15 150.6,40.73 150.42,40.55 U2407.3
  BOTTOM w0.254: Q2407.3 150.41,42.74 v1(150.6,42.54) v2(150.6,41.82)
REMOTE2+: length 41.2
  TOP w0.254: U2407.4 149.92,40.96 C2504.1 149.61,41.27 149.61,50.78 144.79,55.6 144.79,64.49 v2(144.84,64.55)
  BOTTOM w0.254: Q2408.1 140.62,74.45 Q2408.2 140.62,72.16 C2505.1 140.26,71.81 v1(140.26,70.42) 140.26,68.14 142.59,65.81 144.07,65.81 144.81,65.08 144.81,64.58 v2(144.84,64.55)
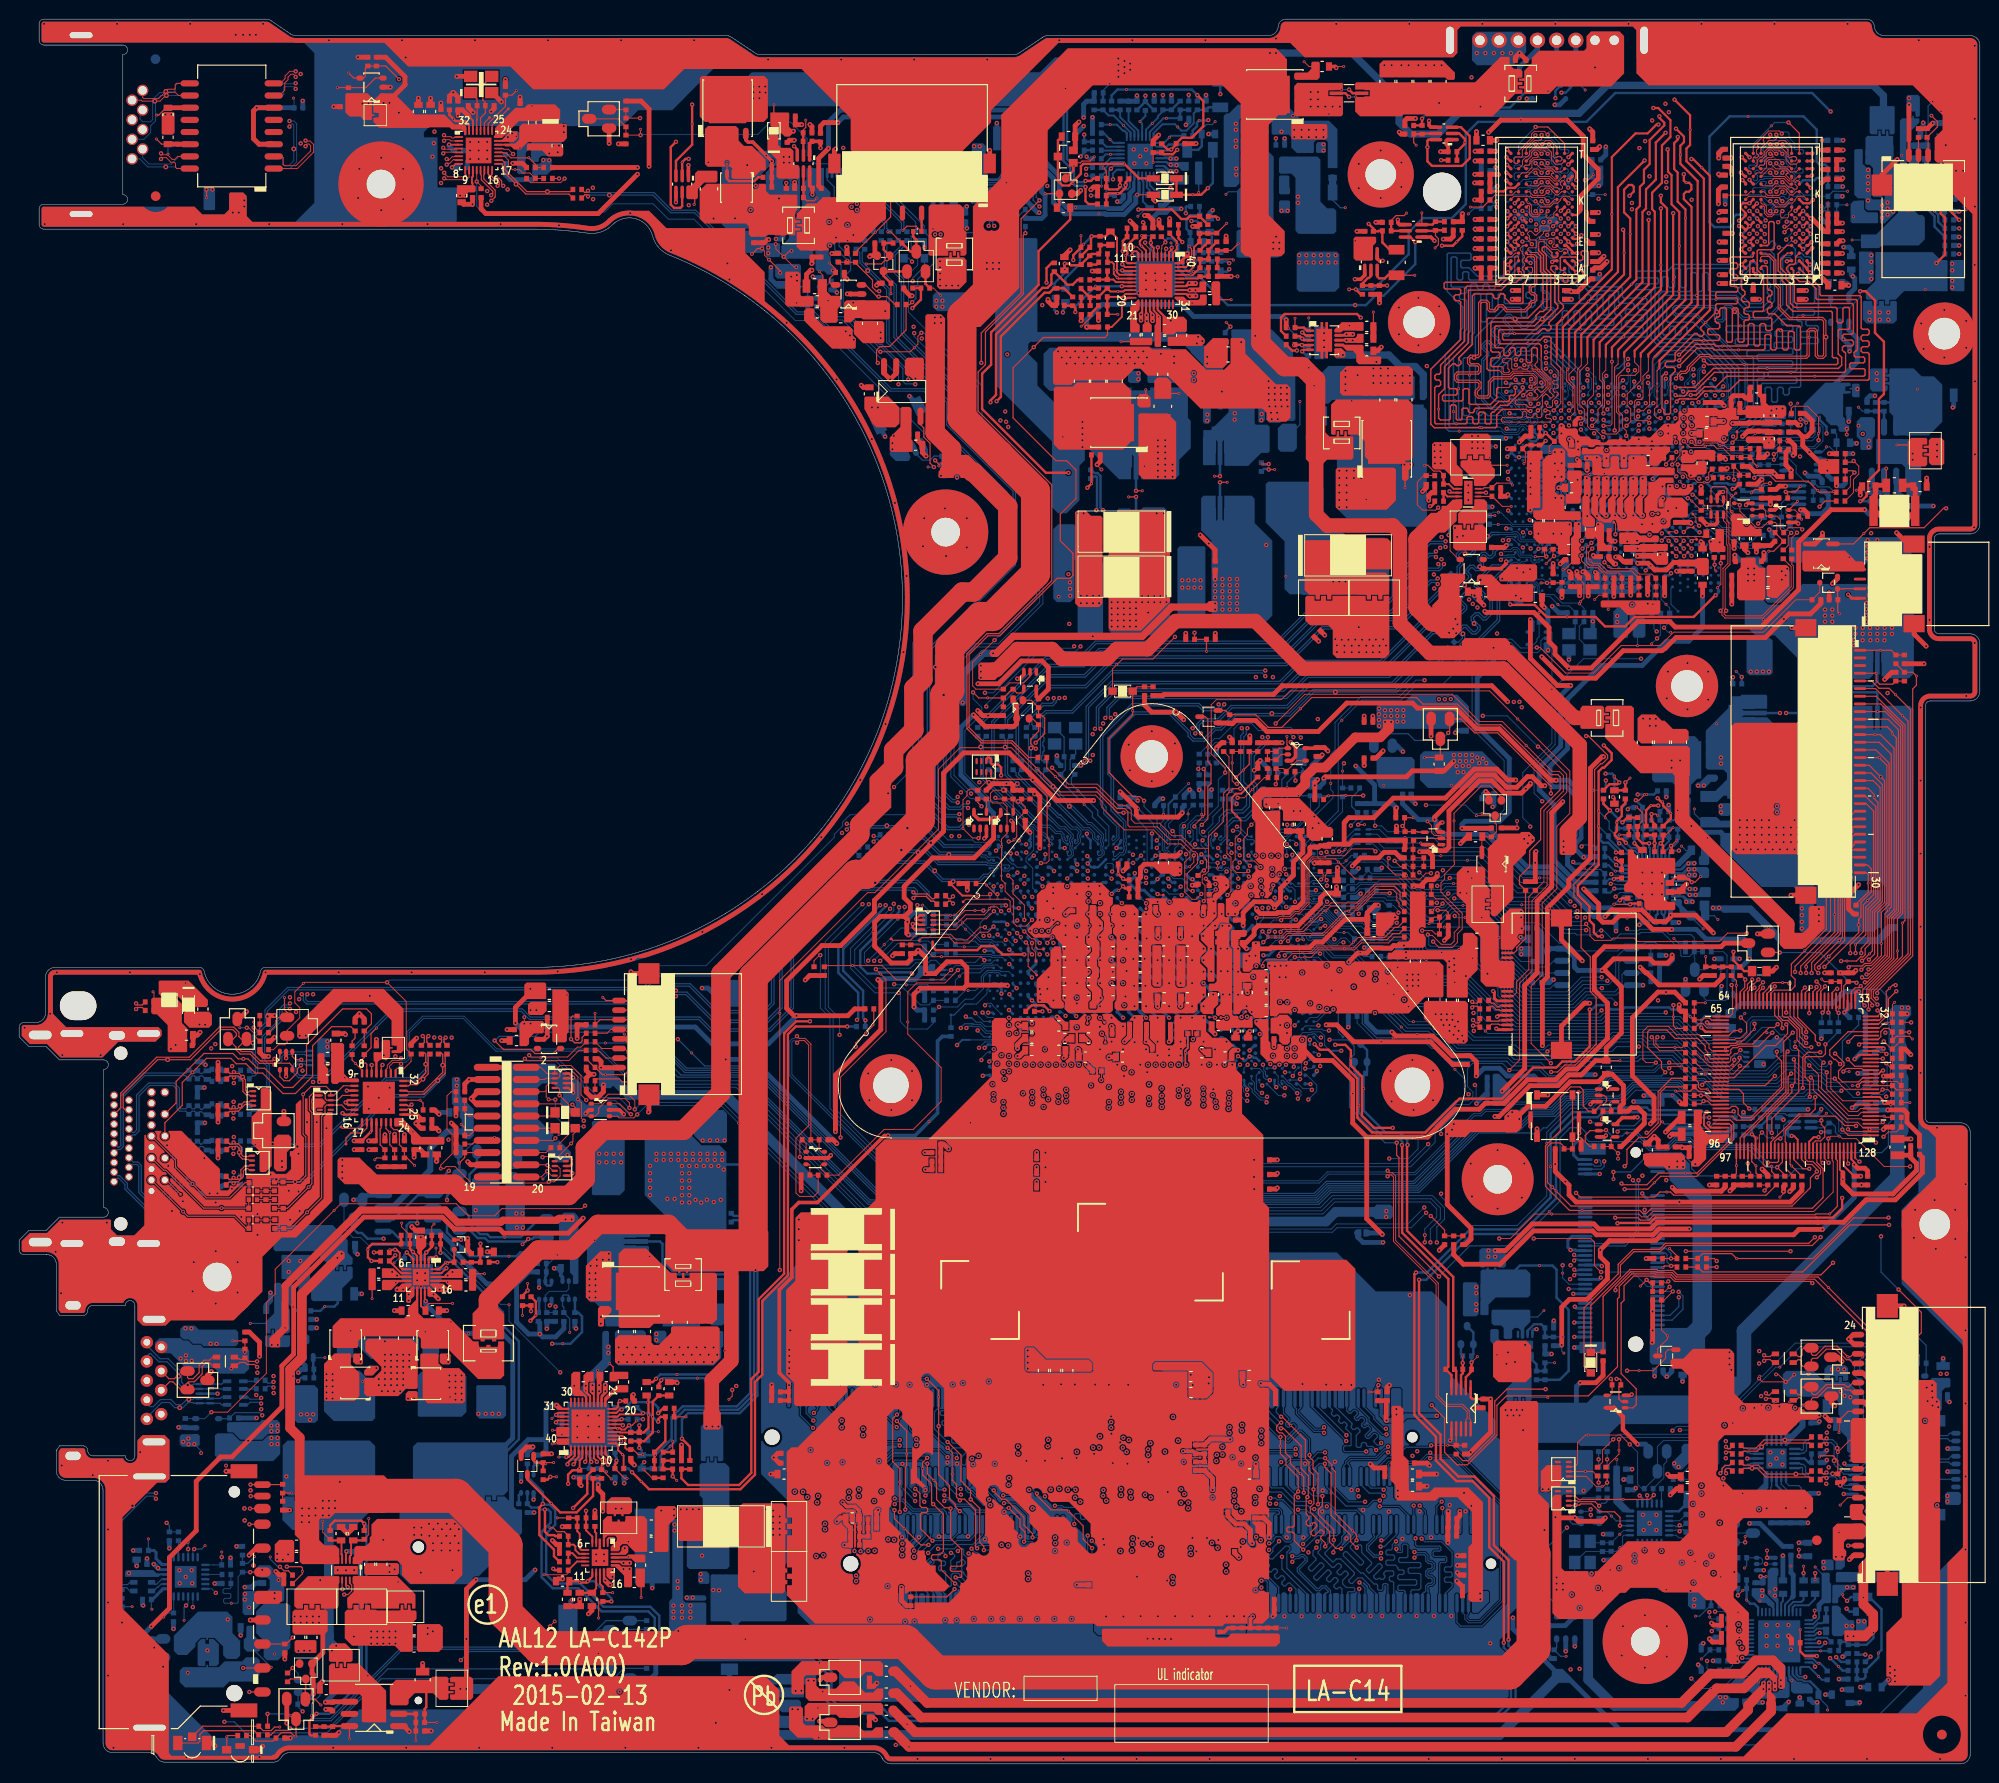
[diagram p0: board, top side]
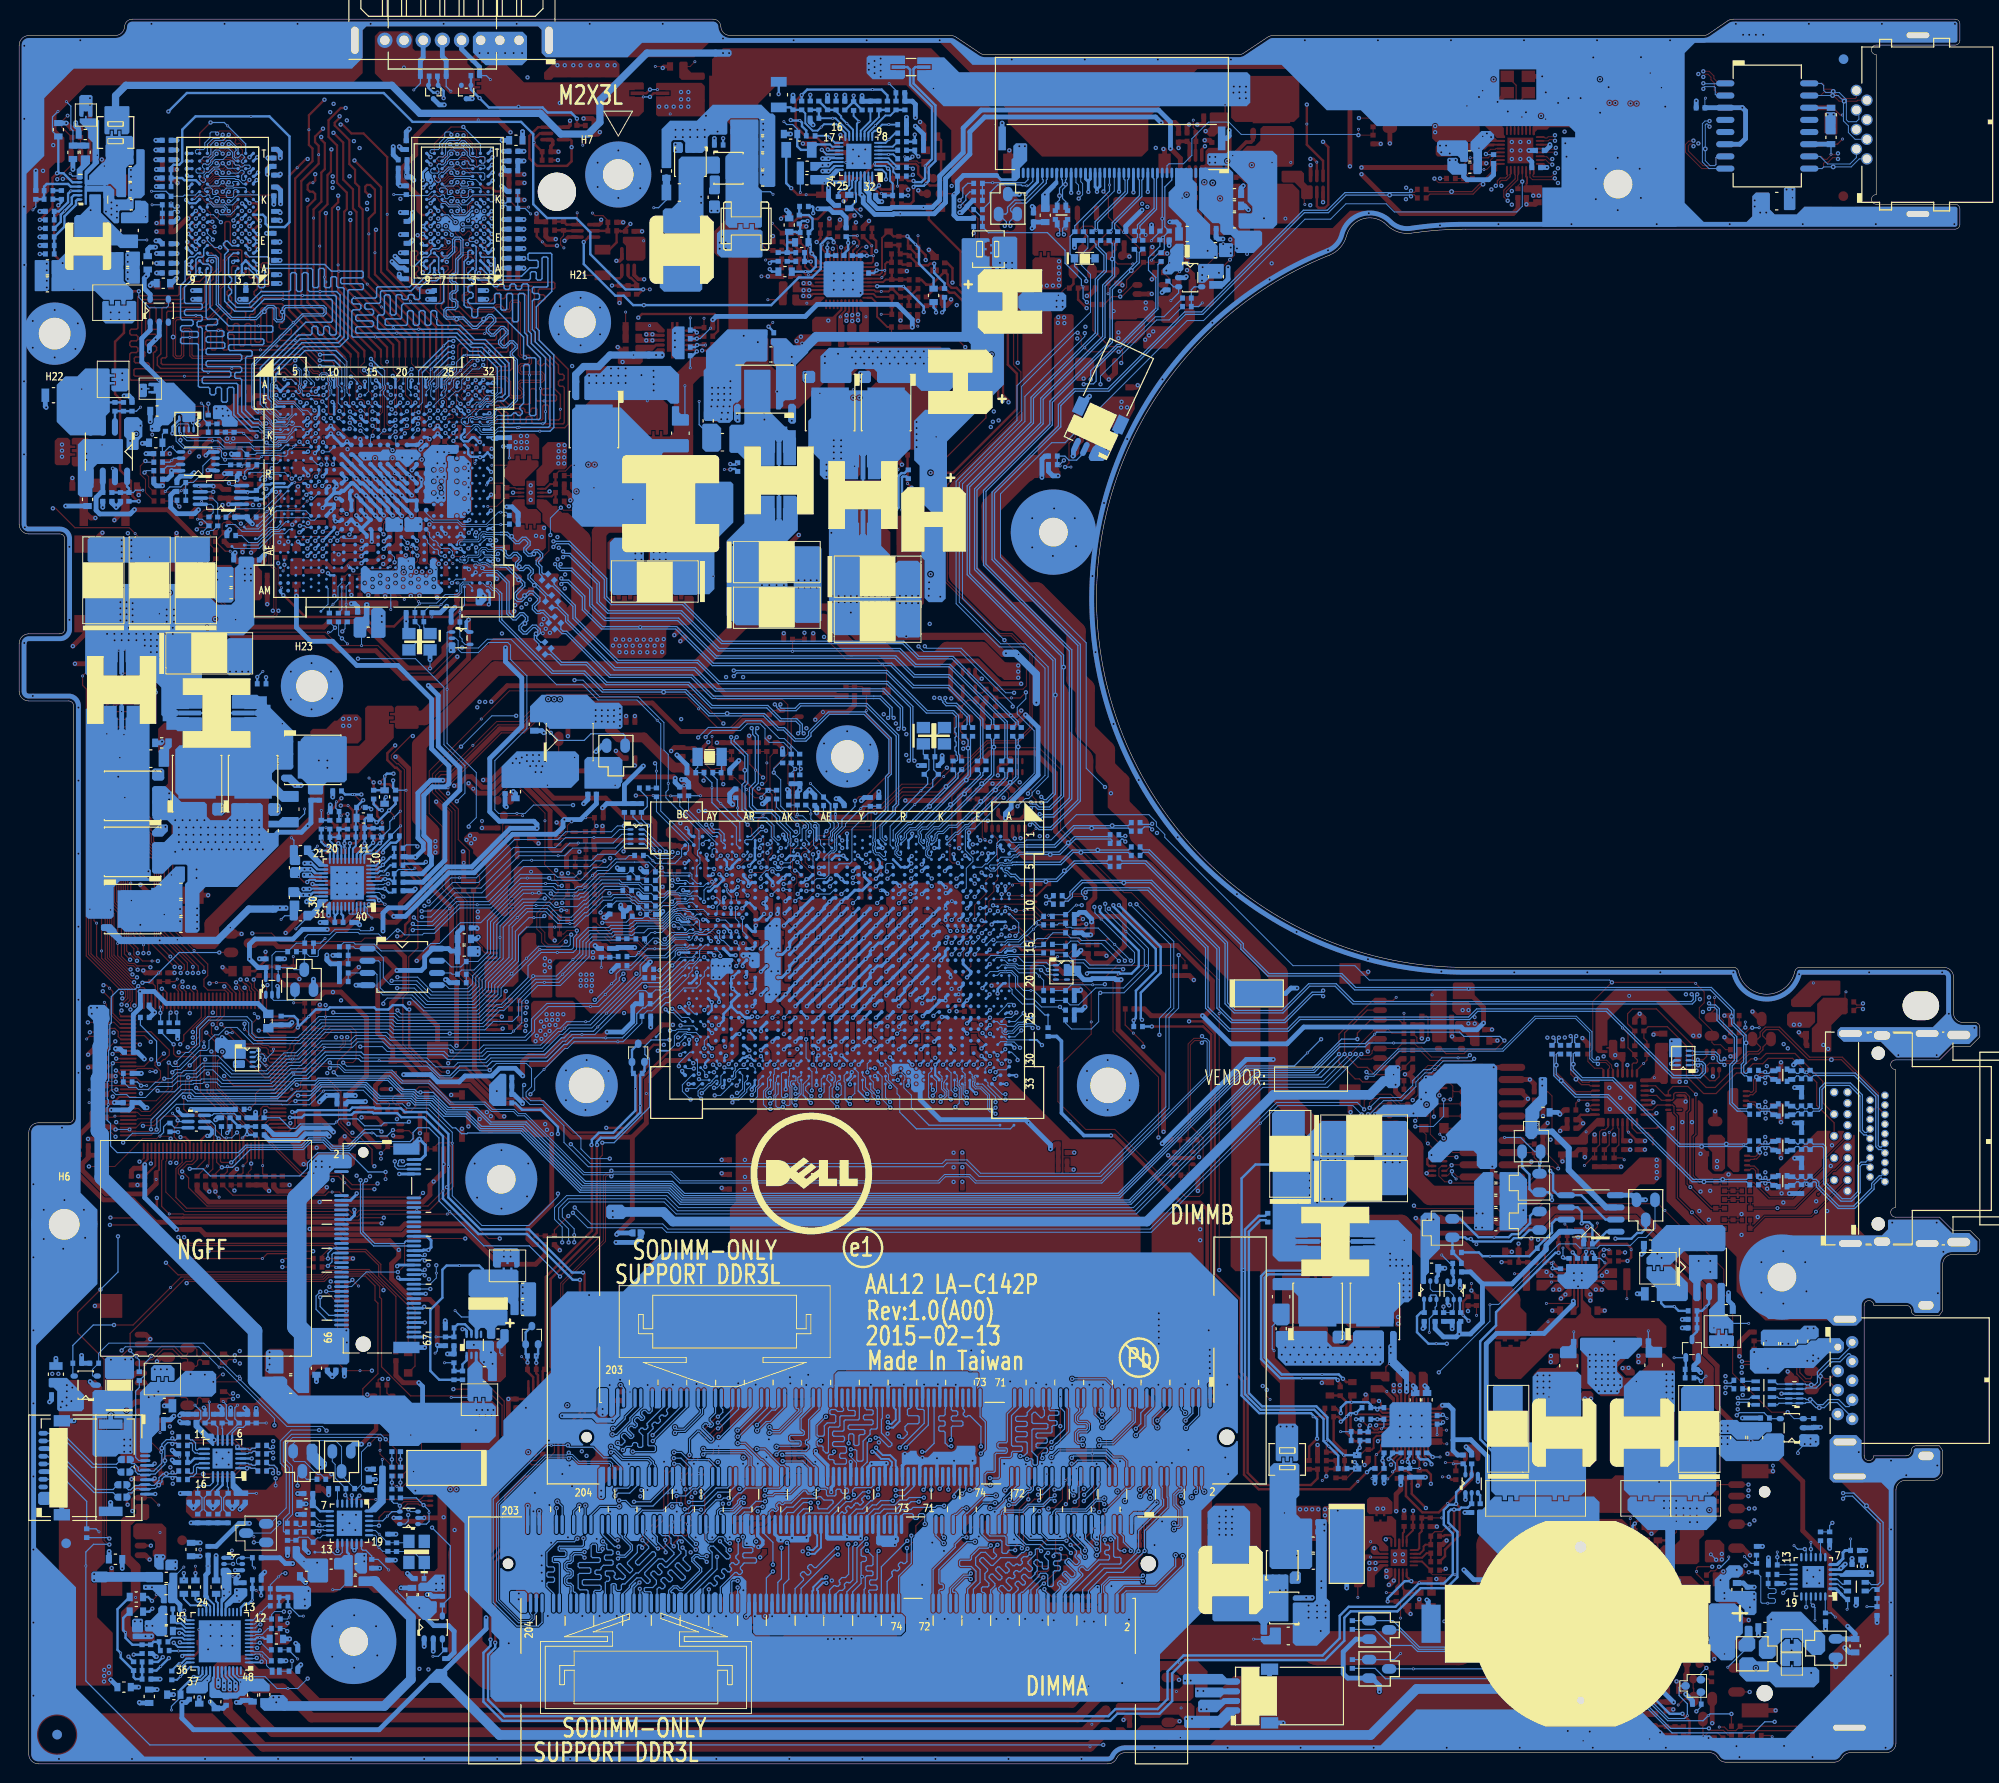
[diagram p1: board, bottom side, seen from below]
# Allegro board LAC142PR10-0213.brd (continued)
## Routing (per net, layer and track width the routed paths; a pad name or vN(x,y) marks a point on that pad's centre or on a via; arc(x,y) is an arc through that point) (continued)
REMOTE2-: length 39.3
  TOP w0.254: v2(144.26,64.55) 144.28,64.52 144.28,55.39 149.1,50.57 149.1,41.43 C2504.2 149.42,40.55 U2407.5
  BOTTOM w0.254: Q2408.3 139.32,72.25 C2505.2 139.76,71.81 v1(139.76,68.66) 139.76,67.92 142.38,65.3 143.86,65.3 144.3,64.87 144.3,64.58 v2(144.26,64.55)
RF_VDDP_ALWP: length 3
  TOP w0.254: v2(133.85,147.32) 134.01,147.48 PU300.5
  BOTTOM w0.127: PR306.1 v1(134.54,145.61)
  BOTTOM w0.254: PR306.1 134.3,146.88 v2(133.85,147.32)
RING2: length 5.8
  IN2 w1.016: 187.56,20.78 184.41,20.78 182.51,18.87
  vias: v1(181.6,16.99) v2(181.84,18.1) v2(181.84,17.51) v2(188.25,21.04) v2(188.27,20.41)
RING2_R:
  vias: v1(189.86,24.13) v2(189.54,21.59) v2(190.18,21.59)
RREF: length 2.3
  BOTTOM w0.127: v1(13.85,16.12) 13.79,16.18 RR1.1
  BOTTOM w0.305: RR1.1 13.92,17.14 14.42,17.64 14.42,17.66 14.73,17.97
RTC_CLK: length 12.5
  BOTTOM w0.102: UC1.AG7 121.36,92.33 120.45,92.33 120.07,92.71 120.07,94.75 119.81,95.01 119.56,95.01 119.26,95.31 119.26,95.78 119.27,95.79 119.27,96.05 119.26,96.06 119.26,96.53 119.27,96.54 119.27,96.86 118.34,97.79 118.34,98.05 117.96,98.43
  BOTTOM w0.127: R949.2 R950.1 116.52,99.87 v1(116.75,99.64) 117.96,98.43
RTC_DIS: length 13.7
  TOP w0.127: v2(191.69,81.47) 191.57,81.58 R1563.1 190.35,81.12 UE1.36 ; v2(183.67,84.62) 183.66,84.63 Q91.2
  BOTTOM w0.127: v2(183.67,84.62) 187.86,84.62 v1(189.99,82.49) 190.98,81.5 191.65,81.5 v2(191.69,81.47)
S0A3: length 38
  TOP w0.127: v2(122.62,117.97) R694.2 R944.2 v1(123.87,116.03)
  IN1 w0.102: 118.04,98.43 118.34,98.12 119.59,98.12 119.72,98.25 120.48,98.25 120.72,98.01 120.72,96.65 120.48,96.4 120.48,92.66 121.18,91.97 v2(121.18,91.49)
  IN1 w0.127: 118.04,98.43 117.86,98.6 117.86,100.56 114.69,103.73 114.69,106.95 122.62,114.88 v2(122.62,117.97)
  BOTTOM w0.102: UC1.AE8 120.81,91.12 v2(121.18,91.49)
S5_MUX_CTRL: length 147.3
  TOP w0.102: v2(79.36,51.5) v1(79.36,78.27) 79.36,81.71 88.51,90.87 89.28,90.87 95.9,97.49 95.9,103.73 98.15,105.98 103.51,105.98 108.47,101.03 112.3,101.03 112.97,100.36 112.97,99.73 115.29,97.41 118.34,97.41 119.81,95.95 121.19,95.95 122.14,95 122.14,94.59 121.6,94.04 121.6,90.93 122.36,90.17 122.77,90.17 v2(123.33,90.73)
  IN1 w0.102: v2(79.36,51.5) 79.36,51.36 76.98,48.98 76.98,40.27 74.45,37.74 65.82,37.74 63.23,40.34 57.87,40.34 56.78,41.43 56.78,46.87 v2(55.96,47.69)
  BOTTOM w0.102: v2(123.33,90.73) 122.97,91.09 UC1.AH8 ; Q2516.5 57.33,49.53 57.08,49.28 55.3,49.28 54.89,48.86 Q2507.5 54.89,47.43 55.05,47.27 R916.1 R2634.1 55.94,47.67 v2(55.96,47.69)
SATA_ACT#: length 287.7
  TOP w0.102: R6106.1 v2(28.52,10) 28.97,10.45 Q6103.3 ; v2(194.52,75.36) 195.33,74.55 RH43.2 196.32,75.44 RD19.1
  IN1 w0.102: v2(28.52,10) 28.58,10.06 32.42,10.06 36.65,14.29 40.49,14.29 44.49,10.29 94.88,10.29 97.17,8 156.88,8 166.53,17.65 166.53,32.83 165.64,33.72 165.64,45.18 168.24,47.79 168.24,60.06 167.44,60.86 167.44,61.66 167.98,62.19 167.98,63.25 167.13,64.1 167.13,66.22 166.77,66.57 166.62,66.57 164.92,68.28 163.15,68.28 162.22,69.2 162.04,69.2 159.39,71.85 159.39,74.26 v2(159.44,74.31)
  IN2 w0.102: v2(194.52,75.36) 194.02,75.36 193.11,74.45 193.11,71.92 192.44,71.25 191.15,71.25 v2(190.11,70.21)
  BOTTOM w0.102: UC1.BB15 134.59,85.42 134.89,85.12 135.96,85.12 137,84.07 138.99,84.07 139.77,83.3 139.77,82.25 143.82,78.2 144.95,77.08 147.29,77.08 v1(147.63,76.74) 147.98,76.39 148.26,76.39 150.01,74.64 155.86,74.64 156.35,74.14 159.28,74.14 v2(159.44,74.31) 159.77,74.64 165.95,74.64 166.61,75.3 169.2,75.3 169.77,74.74 172.62,74.74 174.85,72.5 176.23,72.5 178.11,70.62 183.52,70.62 183.85,70.95 184,71.1 185.28,71.1 185.43,70.95 186.33,70.95 186.41,70.88 187.54,70.88 188.33,70.09 190,70.09 v2(190.11,70.21) ; Q6105.3 29.1,9.42 v2(28.52,10)
SATA_ACT#_RR: length 6.4
  TOP w0.127: RD19.2 195.43,75.48 ; 195.43,75.48 RD15.2 195.05,76.71 194.56,76.71 194.22,76.37 194.22,75.84 193.93,75.56 UE1.26 ; 195.43,75.48 195.84,75.88 197.22,75.88 v1(197.5,75.6)
SATA_ARX_C_DTX_N0: length 2
  BOTTOM w0.127: US2.4 180.67,32.35 180.58,32.44 180.29,32.44 180.13,32.6 179.93,32.6 CS33.2
SATA_ARX_C_DTX_P0: length 2
  BOTTOM w0.127: CS35.2 179.94,32.92 180.26,32.92 180.43,32.75 180.58,32.75 180.67,32.85 US2.5
SATA_ARX_DTX_N0: length 104.1
  TOP w0.127: v2(178.07,32.47) 178.13,32.54 178.52,32.54 RS44.1
  IN2 w0.127: v2(132.29,97.95) 132.29,98.42 132.84,98.97 133.96,98.97 134.99,100.01 136.99,100.01 137.56,100.57 141.69,100.57 142.49,101.37 147.77,101.37 152.1,97.04 152.1,96.32 155.21,93.22 155.21,83.31 155.56,82.95 155.56,78.29 155.02,77.74 155.02,71.12 159.58,66.56 159.58,64.02 160.09,63.51 160.09,62.96 165.67,57.38 165.67,56.84 168.26,54.26 168.26,49.76 178.87,39.14 178.87,32.74 178.61,32.48 178.07,32.48 v2(178.07,32.47)
  BOTTOM w0.112: UC1.AV1 131,96.35 131,96.98 131.49,97.47 132.08,97.47 132.29,97.68 v2(132.29,97.95)
  BOTTOM w0.127: RS44.1 178.5,32.55 178.14,32.55 v2(178.07,32.47)
SATA_ARX_DTX_N1: length 39.4
  TOP w0.127: CS14.1 152.09,79.03 151.73,79.03 v2(151.59,78.89)
  IN2 w0.127: v2(151.59,78.89) 151.76,79.06 152.01,79.06 152.35,79.39 152.35,92 147.19,97.15 136.22,97.15 135.52,96.44 134.69,96.44 133.76,95.52 131.81,95.52 131.45,95.15 131.45,94.81 v2(131.36,94.72)
  BOTTOM w0.102: v2(131.36,94.72) 131.76,94.32 UC1.AW4
SATA_ARX_DTX_N1_C: length 2.3
  TOP w0.127: CS14.2 153.57,79.02 153.74,79.02 154.09,78.67 154.42,78.67 154.51,78.57 JODD.5
SATA_ARX_DTX_P0: length 104.2
  TOP w0.127: RS43.1 178.73,33.11 178.48,32.85 178.27,32.85 v2(178.07,33.06)
  IN2 w0.127: v2(178.07,33.06) 178.07,33.02 178.29,32.8 178.48,32.8 178.56,32.87 178.56,39.01 167.94,49.62 167.94,54.13 165.35,56.71 165.35,57.24 159.77,62.82 159.77,63.38 159.26,63.89 159.26,66.43 154.7,70.99 154.7,77.88 155.25,78.42 155.25,82.82 154.89,83.18 154.89,93.09 151.78,96.19 151.78,96.91 147.64,101.05 142.62,101.05 141.82,100.25 137.69,100.25 137.13,99.69 135.13,99.69 134.09,98.65 132.97,98.65 132.6,98.29 132.6,98.18 132.84,97.95 v2(132.87,97.95)
  BOTTOM w0.112: v2(132.87,97.95) 132.59,97.67 132.59,97.56 132.18,97.14 131.63,97.14 131.33,96.84 131.33,96.24 131.1,96.02 131.04,96.02 130.88,95.86 130.88,95.61 UC1.AV2
  BOTTOM w0.127: v2(178.07,33.06) 178.26,32.87 178.39,32.87 RS43.1
SATA_ARX_DTX_P1: length 39.4
  TOP w0.127: CS13.1 152.09,79.34 151.73,79.34 v2(151.59,79.48)
  IN2 w0.127: v2(132.23,94.72) 132.23,94.61 132.1,94.49 131.93,94.49 131.77,94.65 131.77,95.02 131.95,95.2 133.89,95.2 134.82,96.13 135.65,96.13 136.36,96.84 147.06,96.84 152.03,91.87 152.03,79.52 151.88,79.37 151.69,79.37 v2(151.59,79.48)
  BOTTOM w0.102: v2(132.23,94.72) 132.25,94.75 132.25,95.33 132.12,95.45 131.89,95.45 131.77,95.33 UC1.AW3
SATA_ARX_DTX_P1_C: length 2.3
  TOP w0.127: CS13.2 153.59,79.34 153.87,79.34 154.22,78.98 154.41,78.98 154.51,79.08 JODD.6
SATA_ARX_RC_DTX_N0: length 2.7
  BOTTOM w0.127: US2.12 185.87,32.35 185.93,32.41 186.19,32.41 186.47,32.69 186.47,33.33 186.6,33.46 186.73,33.46 CS31.1
SATA_ARX_RC_DTX_N0_C: length 9.7
  TOP w0.127: CS41.2 188.22,33.53 188.4,33.53 v2(188.57,33.36)
  BOTTOM w0.127: CLRP4.1 192.98,30.81 192.79,31 192.66,31 192.44,30.78 192.44,30.51 192.15,30.22 191.98,30.22 191.9,30.13 JHDD1.8 190.9,30.13 190.81,30.22 190.37,30.22 189.35,31.24 v3(189.35,31.62) 189.35,33.21 189.06,33.5 188.7,33.5 v2(188.57,33.36) 188.49,33.45 188.14,33.45 CS41.2
SATA_ARX_RC_DTX_N0_C_R: length 9.6
  BOTTOM w0.127: CLRP4.2 194.44,30.92 196.93,30.92 199.93,33.92 201.18,33.92 201.43,33.68 JHDD2.9
SATA_ARX_RC_DTX_P0: length 2.8
  BOTTOM w0.127: US2.11 185.8,32.85 185.92,32.73 186.06,32.73 186.15,32.82 186.15,33.46 186.47,33.78 186.67,33.78 CS34.1
SATA_ARX_RC_DTX_P0_C: length 9.5
  TOP w0.127: CS40.2 188.16,33.85 188.47,33.85 v2(188.57,33.95)
  BOTTOM w0.127: CLRP5.1 192.94,31.45 192.82,31.32 192.53,31.32 192.12,30.91 192.12,30.64 192.02,30.53 191.94,30.53 191.84,30.63 JHDD1.7 190.9,30.63 190.81,30.54 190.5,30.54 189.67,31.37 v3(189.67,32.92) 189.67,33.34 189.2,33.81 188.7,33.81 v2(188.57,33.95) 188.38,33.76 188.24,33.76 CS40.2
SATA_ARX_RC_DTX_P0_C_R: length 9.7
  BOTTOM w0.127: CLRP5.2 194.4,31.24 196.8,31.24 199.79,34.24 201.18,34.24 201.43,34.48 JHDD2.10
SATA_ATX_C_DRX_N0: length 2
  BOTTOM w0.127: CS36.2 179.94,31.14 180.22,31.14 180.33,31.25 180.58,31.25 180.67,31.35 US2.2
SATA_ATX_C_DRX_P0: length 2
  BOTTOM w0.127: US2.1 180.67,30.85 180.58,30.94 180.46,30.94 180.35,30.82 179.93,30.82 CS37.2
SATA_ATX_DRX_N0: length 108.4
  TOP w0.127: RS42.1 178.42,31.11 177.98,31.11 177.67,30.8 177.67,30.49 v2(177.49,30.31)
  IN2 w0.127: v2(130.63,94.72) 130.33,94.72 130.19,94.86 130.19,95.51 131.9,97.22 133.6,97.22 134.22,97.84 134.62,97.84 135.52,98.74 137.65,98.74 138.21,99.3 142.33,99.3 143.13,100.1 144.62,100.1 145.44,99.28 148.02,99.28 148.88,98.42 148.88,98.06 150.81,96.13 150.81,95.81 153.94,92.68 153.94,82.75 154.29,82.39 154.29,79.09 153.4,78.2 153.4,75.99 153.75,75.64 153.75,69.59 154.55,68.8 155.54,68.8 156.94,67.39 156.94,64.83 158.82,62.95 158.82,62.14 164.4,56.56 164.4,56.32 166.99,53.73 166.99,49.23 176.97,39.25 176.97,31.7 177.62,31.05 177.62,30.44 v2(177.49,30.31)
  BOTTOM w0.102: UC1.AU4 130.48,94.32 130.63,94.47 v2(130.63,94.72)
  BOTTOM w0.127: v2(177.49,30.31) 177.62,30.44 177.62,30.82 177.95,31.15 178.45,31.15 RS42.1
SATA_ATX_DRX_N1: length 43.1
  TOP w0.127: CS9.1 152.38,77.36 152.3,77.28 151.98,77.28 v2(151.68,77.58)
  IN2 w0.127: v2(151.68,77.58) 151.94,77.31 152.1,77.31 152.39,77.6 152.39,78.54 152.98,79.13 152.98,92.27 147.48,97.78 147.31,97.78 146.83,98.26 145.06,98.26 144.49,98.83 143.38,98.83 142.9,98.35 138.64,98.35 138.08,97.79 136.25,97.79 135.3,96.84 134.46,96.84 134.14,96.52 132.96,96.52 132.7,96.25 132.7,95.88 132.84,95.75 133.05,95.75 v2(133.23,95.93)
  BOTTOM w0.102: UC1.AY1 132.95,96.32 133.23,96.04 v2(133.23,95.93)
SATA_ATX_DRX_N1_C: length 2.1
  TOP w0.127: JODD.3 154.44,77.57 154.33,77.47 153.55,77.47 CS9.2
SATA_ATX_DRX_P0: length 107.9
  TOP w0.127: RS41.1 178.48,30.8 178.12,30.8 177.98,30.67 177.98,30.4 v2(178.07,30.31)
  IN2 w0.127: v2(178.07,30.31) 177.94,30.44 177.94,31.18 177.29,31.84 177.29,39.38 167.3,49.36 167.3,53.86 164.72,56.45 164.72,56.69 159.14,62.27 159.14,63.08 157.26,64.96 157.26,67.53 155.67,69.11 154.68,69.11 154.07,69.72 154.07,75.77 153.71,76.12 153.71,78.06 154.61,78.96 154.61,82.52 154.25,82.88 154.25,92.81 151.12,95.94 151.12,96.26 149.19,98.19 149.19,98.55 148.15,99.59 145.57,99.59 144.75,100.42 143,100.42 142.2,99.62 138.08,99.62 137.52,99.06 135.39,99.06 134.49,98.16 134.09,98.16 133.47,97.54 131.77,97.54 129.88,95.64 129.88,94.83 v2(129.76,94.71)
  BOTTOM w0.102: UC1.AU3 v2(129.76,94.71)
  BOTTOM w0.127: v2(178.07,30.31) 177.94,30.44 177.94,30.68 178.08,30.83 178.45,30.83 RS41.1
SATA_ATX_DRX_P1: length 43.1
  TOP w0.127: v2(151.68,76.99) 151.71,76.96 152.25,76.96 CS8.1
  IN2 w0.127: v2(132.26,95.92) 132.32,95.98 132.33,95.98 132.38,96.03 132.38,96.38 132.83,96.84 134.01,96.84 134.33,97.15 135.17,97.15 136.12,98.11 137.95,98.11 138.51,98.67 142.77,98.67 143.25,99.15 144.62,99.15 145.19,98.58 146.96,98.58 147.44,98.09 147.61,98.09 153.3,92.4 153.3,79 152.71,78.41 152.71,77.47 152.24,76.99 v2(151.68,76.99)
  BOTTOM w0.102: v2(132.26,95.92) 132.57,95.61 UC1.AY2
SATA_ATX_DRX_P1_C: length 2.1
  TOP w0.127: JODD.2 154.44,77.08 154.36,77.15 153.61,77.15 CS8.2
SATA_ATX_RC_DRX_N0: length 2.6
  BOTTOM w0.127: US2.14 185.77,31.35 185.87,31.24 186,31.24 186.12,31.24 186.37,30.99 186.37,30.45 186.51,30.3 186.75,30.3 CS32.1
SATA_ATX_RC_DRX_N0_C: length 7.9
  TOP w0.127: v2(188.55,30.39) 188.38,30.23 188.22,30.23 CS39.2
  BOTTOM w0.127: CS39.2 188.19,30.26 188.42,30.26 v2(188.55,30.39) 188.68,30.26 v3(189.2,30.26) 189.55,30.26 189.97,29.84 189.97,29.55 190.47,29.04 190.78,29.04 190.87,29.13 JHDD1.10 191.94,29.13 192.04,29.03 192.46,29.03 192.92,28.57 193.15,28.57 193.3,28.73 CLRP3.1
SATA_ATX_RC_DRX_N0_C_R: length 9.4
  BOTTOM w0.127: JHDD2.7 201.56,32.08 201.28,31.79 199.78,31.79 196.6,28.61 194.76,28.61 CLRP3.2
SATA_ATX_RC_DRX_P0: length 2.6
  BOTTOM w0.127: CS30.1 186.66,29.98 186.38,29.98 186.05,30.31 186.05,30.86 185.98,30.92 185.87,30.92 185.79,30.85 US2.15
SATA_ATX_RC_DRX_P0_C: length 7.7
  TOP w0.127: CS38.2 188.16,29.91 188.45,29.91 v2(188.55,29.81)
  BOTTOM w0.127: CLRP2.1 193.3,28.12 193.16,28.26 192.79,28.26 192.33,28.72 192.03,28.72 191.94,28.63 JHDD1.11 190.87,28.63 190.78,28.72 190.34,28.72 v3(189.99,29.07) 189.65,29.41 189.65,29.71 189.42,29.94 188.68,29.94 v2(188.55,29.81) 188.42,29.94 188.19,29.94 CS38.2
SATA_ATX_RC_DRX_P0_C_R: length 9.4
  BOTTOM w0.127: JHDD2.6 201.49,31.28 201.3,31.47 199.91,31.47 196.73,28.3 194.75,28.3 CLRP2.2
SATA_LED: length 7.7
  TOP w0.127: Q6104.1 28.89,2.92 v1(28.86,2.9) 28.7,2.9 28.33,3.26 27.36,3.26 EC6104.1 26.47,2.37 24.68,2.37 24.11,2.95 R6108.1
SATA_LED#_B: length 6
  TOP w0.127: R6106.2 28.29,8.85 Q6103.1 29.9,7.89 29.85,7.84 Q6104.2 30.85,6.76 v1(31.48,6.13)
SATA_LED#_R: length 252.4
  TOP w0.127: RD15.1 197.15,76.33 v2(197.17,76.3) ; v2(196.07,49.47) 198.44,47.09 198.44,44.96 195.69,42.2 195.69,23.33 195.23,22.87 v2(195.14,22.87)
  IN1 w0.127: v2(194.24,55.02) 194.4,55.18 194.4,57.23 195.23,58.06 195.23,66.89 194.05,68.07 194.05,69.41 195.52,70.88 195.52,75.44 v2(194.7,76.26)
  IN2 w0.127: v2(29.57,5.47) 30.91,4.14 34.42,4.14 35.99,2.58 90.85,2.58 v2(91.45,1.97) ; v2(197.17,76.3) 194.74,76.3 v2(194.7,76.26)
  BOTTOM w0.127: v2(91.45,1.97) 190.92,1.97 197.59,8.65 v1(197.59,20.64) 197.59,22.1 196.79,22.9 195.17,22.9 v2(195.14,22.87) ; v2(29.57,5.47) 29.06,5.98 R6110.2 29.1,6.26 Q6105.2 ; v2(194.24,55.02) 194.24,51.3 v2(196.07,49.47)
SATA_LED_R: length 2.6
  TOP w0.127: R6108.2 21.79,2.95 v1(21.66,2.82) 21.65,2.81 HDLED1.2
SATA_RX_N0: length 7.9
  TOP w0.127: CS41.1 186.73,33.46 182.18,33.46 v3(181.78,33.06) 181.32,32.61 179.93,32.61 RS44.2
SATA_RX_P0: length 7.9
  TOP w0.127: RS43.2 179.93,32.92 181.19,32.92 182.05,33.78 v3(184.21,33.78) 186.67,33.78 CS40.1
SATA_TX_N0: length 8
  TOP w0.127: RS42.2 179.93,31.15 181.45,31.15 182.37,30.23 v3(185.35,30.23) 186.67,30.23 CS39.1
SATA_TX_P0: length 7.9
  TOP w0.127: CS38.1 186.73,29.91 182.24,29.91 181.32,30.83 v3(180.79,30.83) 179.93,30.83 RS41.2
SATA_ZVDD: length 7.6
  BOTTOM w0.102: UC1.AW2 131.77,96.01 135.63,99.87 R96.1
  BOTTOM w0.127: R96.1 v1(136.59,100.96)
SATA_ZVSS: length 7
  BOTTOM w0.102: R90.1 134.71,99.46 133.7,98.45 133.7,98.23 132.19,96.72 UC1.AW1
  BOTTOM w0.127: R90.1 v1(133.48,100.97)
SD_CD#: length 14.8
  TOP w0.127: JREAD.10 v2(24.15,27.93)
  IN2 w0.107: v2(21.13,21.56) 21.13,24.32 21.26,24.45 24.95,24.45 25.08,24.58 25.08,27 v2(24.15,27.93)
  BOTTOM w0.102: v2(21.13,21.56) 21.13,21.56 CR9.1 20.31,20.75 20.31,20.75 UR1.13
  BOTTOM w0.127: v2(21.13,21.56) v1(21.13,22.09)
SD_CMD: length 14.6
  TOP w0.127: v2(28.53,13.16) 27.86,12.5 CR11.1 JREAD.2
  IN2 w0.107: v2(20.52,17.83) 20.52,17.83 25.19,13.16 v2(28.53,13.16)
  BOTTOM w0.102: v2(20.52,17.83) 20.52,17.83 20.1,18.25 UR1.18
SD_D0: length 14.6
  TOP w0.127: v2(24.02,24.98) 24.04,25 JREAD.7
  IN2 w0.107: v2(18.26,22.4) 20.75,22.4 20.88,22.52 20.88,22.95 20.77,23.06 19.43,23.06 19.32,23.16 19.32,23.48 19.43,23.59 20.77,23.59 20.88,23.7 20.88,24.85 21.01,24.98 v2(24.02,24.98)
  BOTTOM w0.102: UR1.11 18.12,22.26 v2(18.26,22.4)
  BOTTOM w0.127: v2(18.26,22.4) 19.02,22.4 v1(19.39,22.76)
SD_D1: length 14.9
  TOP w0.127: JREAD.8 24.08,26.63 v2(24.08,26.62)
  IN2 w0.107: v2(24.08,26.62) 23.44,25.98 20.56,25.98 20.44,25.85 20.44,25.24 20.31,25.11 19.4,25.11 19.29,25.01 19.29,24.69 19.4,24.58 20.31,24.58 20.44,24.45 20.44,24.13 20.31,24.01 17.75,24.01 17.62,23.88 v2(17.62,22.4)
  BOTTOM w0.102: v2(17.62,22.4) 17.62,22.4 UR1.10
  BOTTOM w0.127: v2(17.62,22.4) v1(17.62,23.1)
SD_D2: length 15.8
  TOP w0.127: v2(24.01,7.49) 24.01,7.5 JREAD.9
  IN2 w0.107: v2(17.41,16.51) 17.41,15.38 24.01,8.77 v2(24.01,7.49)
  BOTTOM w0.102: v2(17.41,16.51) 17.62,16.73 UR1.21
  BOTTOM w0.127: v2(17.41,16.51) 17.2,16.31 v1(17.2,14.96)
SERIRQ: length 70.2
  TOP w0.102: v2(186.92,71.59) 187.18,71.33 187.18,70.27 187.67,69.78 187.75,69.78 190.61,66.92 191.8,66.92 192.36,66.36 UE1.3
  IN2 w0.102: v2(141.47,81.83) 141.04,82.26 141.04,83.06 138.41,85.69 v2(138.16,85.69)
  BOTTOM w0.102: UC1.BC14 136.15,86.22 136.99,85.38 137.47,85.38 137.78,85.69 v2(138.16,85.69) ; v2(186.92,71.59) 186.89,71.62 185.98,71.62 185.22,72.38 184.34,72.38 183.26,71.3 178.37,71.3 176.5,73.16 176.18,73.16 176.17,73.18 175.25,73.18 173.04,75.4 170.04,75.4 169.48,75.96 166.34,75.96 165.84,75.46 151.66,75.46 150.78,76.34 150.78,77.55 149.35,78.98 v1(144.95,78.98) 144.08,78.98 141.47,81.59 v2(141.47,81.83)
SLEEVE: length 8
  IN1 w1.016: 184,17.86 186,17.86 188.59,15.27 190.94,15.27
  vias: v1(182.63,17.92) v2(183.18,17.54) v2(183.22,18.21) v2(191.88,14.86) v2(192.49,14.86)
SLEEVE_R: length 13.2
  TOP w1.016: 192.59,13.33 193.43,14.17 193.43,15.61 192.4,16.64 v1(192.4,17.35) 192.4,20.51 193.41,21.53 193.41,25.27 193.39,25.3
  vias: v2(190.76,13.31) v2(191.37,13.31)
SNB_1.35VGPU:
  vias: v1(191.36,161.37)
SPK_L+_CONN:
  vias: v1(83.5,10.53) v2(81.01,7.59) v2(81.6,7.62)
SPK_L-_CONN:
  vias: v1(83.83,7.54) v2(82.33,8.69) v2(82.91,8.67)
SPK_R+_CONN:
  vias: v1(83.33,5.83) v2(82.19,4.7) v2(82.77,4.69)
SPK_R-_CONN:
  vias: v1(83.41,2.73) v2(80.66,5.7) v2(81.25,5.68)
SUSP: length 2.3
  BOTTOM w0.102: RZ10.1 v1(54.93,31.29)
  BOTTOM w0.254: Q52.6 53.67,31.05 RZ10.1
SUSP#: length 371.4
  TOP w0.203: v2(187.72,65.36) 187.22,65.36 186.75,64.9 UE1.116
  TOP w0.254: v2(155.38,12.95) 155.38,21.27 153.85,22.8 153.85,27.94 151.82,29.97 150.13,29.97 148.29,31.81 148.29,34.33 146.04,36.58 v2(146.04,50.48) ; v2(54.85,26.52) 54.85,24.21 55.21,23.85 55.84,23.85 55.94,23.75 PR202.1 ; R2313.1 v2(36,25.06) 35.69,25.36 32.92,25.36 32.44,24.88 R2318.1 ; PR401.1 30.42,2.97 30.28,3.11 30.28,4.48 v2(31.02,5.22) ; v2(165.32,106.22) 166.13,105.41 166.13,104.69 165.33,103.89 165.16,103.89 164.78,103.5 164.78,93.75 162.62,91.59 162.62,90.63 163.83,89.41 163.83,87.95 164.28,87.5 164.28,86.72 164.69,86.31 v2(165.12,86.31) ; v2(147.19,131.17) 147.33,131.17 147.68,131.52 R437.1
  IN1 w0.254: v2(147.19,131.17) 146.3,130.28 146.3,122.2 147.54,120.95 149.98,120.95 151.73,119.21 155.41,119.21 156.98,117.64 158.69,117.64 159.99,116.35 159.99,113.61 165.32,108.28 v2(165.32,106.22)
  IN2 w0.254: v2(187.72,65.36) 187.22,65.36 186.52,64.67 178.42,64.67 176.83,66.27 176.83,66.94 176.36,67.41 v2(176.31,67.41) 176.59,67.69 176.59,68.2 176.21,68.58 175.25,68.58 173.1,70.73 172.4,70.73 168.01,75.12 168.01,82.06 165.09,84.97 165.09,86.28 v2(165.12,86.31) ; v2(36,25.06) 37.89,26.95 50.51,26.95 52.21,25.25 53.59,25.25 v2(54.85,26.52)
  BOTTOM w0.254: v2(176.31,67.41) 175.07,67.41 174.79,67.69 169.87,67.69 169.6,67.96 167.7,67.96 167.6,67.86 165.1,67.86 164.67,67.44 162.31,67.44 160.34,65.46 v1(160.34,59.75) 160.34,58.96 156.64,55.26 151.57,55.26 146.79,50.48 v2(146.04,50.48) ; Q52.2 RZ591.1 53.42,26.73 54.09,26.73 54.3,26.52 v2(54.85,26.52) 55.19,26.52 55.44,26.27 55.44,25.14 54.5,24.2 54.5,19.47 55.66,18.31 58.35,18.31 60.76,15.9 65.64,15.9 66.3,15.24 66.3,12.84 68.32,10.82 82.87,10.82 84.26,9.44 84.26,6.55 85.58,5.23 89.98,5.23 90.73,4.48 154.12,4.48 156.11,6.48 156.11,11.58 155.38,12.32 v2(155.38,12.95) ; v2(31.02,5.22) 32.36,5.22 36.23,9.08 36.23,24.83 v2(36,25.06)
SVI2_SVC: length 74.7
  TOP w0.102: RV168.2 191.37,132.6 191.37,133.97 191.92,134.52 191.92,135.36 v2(191.38,135.89) 191.26,135.76 RV84.1 RV89.2
  IN2 w0.102: v2(191.38,135.89) 191.06,135.57 191.06,134.95 190.38,134.26 190.38,127.82 181.29,118.73 171.83,118.73 v2(171.6,118.5) 170.69,118.5 164.24,112.05 164.24,99.3 164.93,98.61 164.93,97.24 165.39,96.79 165.39,91.53 166.28,90.64 166.36,90.64 v2(166.55,90.45)
  BOTTOM w0.102: RV84.1 191.26,135.76 v2(191.38,135.89) ; v1(172.29,118.02) 172.05,118.02 171.6,118.47 v2(171.6,118.5) 171.6,118.52 RV157.2 ; v2(166.55,90.45) 166.55,90.45 166.98,90.88 PU1100.3
SVI2_SVD: length 69.2
  TOP w0.102: RV88.2 RV87.1 191.28,134.87 v2(191.47,134.68) 191.04,134.25 191.04,133.2 RV169.2
  IN2 w0.102: v2(166.05,91.8) 166.05,91.85 165.72,92.18 165.72,96.92 165.26,97.38 165.26,98.75 164.57,99.43 164.57,111.84 v2(170.84,118.11) 171.75,118.11 172.03,118.39 181.42,118.39 190.81,127.78 190.81,134.02 v2(191.47,134.68)
  BOTTOM w0.102: v2(170.84,118.11) 170.55,118.4 170.55,118.87 RV155.2 ; v2(166.05,91.8) 166.44,91.8 166.54,91.7 167.1,91.7 167.12,91.68 PU1100.5 ; RV87.1 191.28,134.87 v2(191.47,134.68)
SVI2_SVT: length 32.3
  IN2 w0.102: v2(166.1,92.8) 166.05,92.85 166.05,97.06 165.59,97.52 165.59,98.88 164.9,99.57 164.9,111.71 170.58,117.38 v2(170.87,117.38)
  BOTTOM w0.102: RV156.2 171.22,119.08 171.22,117.73 v2(170.87,117.38) 170.87,117.38 v1(170.3,116.81) ; PU1100.7 167.02,92.48 166.82,92.68 166.21,92.68 v2(166.1,92.8)
SYS_RESET_L: length 6.4
  BOTTOM w0.102: R951.2 R952.1 v1(123.37,99.03) 123.22,98.88 122.81,98.88 122.28,98.36 121.93,98.01 121.93,97.63 121.67,97.37 121.67,95.82 UC1.AF2
SYSON: length 226
  TOP w0.203: UE1.95 176.42,65.96 175.77,66.6 175.77,67.69 v2(176.07,67.98)
  TOP w0.254: v2(145.73,51.24) 145.56,51.08 145.56,36.38 147.81,34.13 147.81,31.61 149.93,29.49 151.62,29.49 153.37,27.74 153.37,22.6 154.89,21.08 v2(154.89,12.64) ; v2(54.64,27.11) 54.27,26.75 54.27,23.86 55.8,22.34 55.8,21.65 PR201.1
  BOTTOM w0.254: v2(176.07,67.98) 175.66,67.98 175.47,68.17 170.07,68.17 169.79,68.45 167.51,68.45 167.42,68.36 164.71,68.36 164.33,67.98 162.05,67.98 159.77,65.7 v1(159.77,62.29) 159.77,59.08 156.43,55.74 151.37,55.74 146.87,51.24 v2(145.73,51.24) ; v2(154.89,12.64) 154.89,12.12 155.63,11.38 155.63,6.68 153.92,4.97 90.93,4.97 90.18,5.72 85.78,5.72 84.74,6.75 84.74,9.64 83.07,11.3 68.57,11.3 66.78,13.09 66.78,15.44 65.84,16.38 60.96,16.38 58.54,18.81 55.92,18.81 54.98,19.75 54.98,24 55.92,24.94 55.92,26.47 55.37,27.03 54.72,27.03 v2(54.64,27.11) 54.64,28.31 53.02,29.93 Q52.5 RZ21.1
SYSON#: length 1.2
  BOTTOM w0.254: RZ19.1 52.13,28.02 Q52.3
T-GND_L: length 8.1
  TOP w0.127: v2(19.55,164.2) v1(19.55,163.34)
  IN1 w1.016: 19.53,165.1 15.64,168.99 15.64,170.78
  vias: v2(15.26,172.03) v2(15.88,172.03) v2(20.16,164.2)
TEMPIN0: length 11.5
  TOP w0.254: v2(104.87,84.42) 102.57,84.42 101.71,85.28 100.37,85.28 99.97,84.87 95.62,84.87 95.31,85.19 T28.1
  BOTTOM w0.102: v2(104.87,84.42) 104.47,84.82 UC1.E15
TEMPIN1: length 4.8
  TOP w0.102: v2(105.03,85.67) 105.26,85.44 105.26,83.17 T29.1
  BOTTOM w0.102: v2(105.03,85.67) 104.82,85.67 104.47,86.02 UC1.E14
TEMPIN2: length 3.9
  TOP w0.102: v2(104.87,86.82) 105.63,86.06 105.84,86.06 106.06,85.83 106.06,85.18 106.28,84.96 T30.1
  BOTTOM w0.102: v2(104.87,86.82) 104.47,87.22 UC1.E12
TEMPINRETURN: length 2.9
  TOP w0.102: v2(105.67,85.62) 105.67,85.03 106.05,84.65 106.05,83.74 T31.1
  BOTTOM w0.102: UC1.F14 105.27,86.02 v2(105.67,85.62)
TESTEN: length 13.8
  TOP w0.102: v2(183.07,136.61) 183.2,136.61 RV154.2 183.67,137.09 RV17.2
  TOP w0.127: v2(183.07,136.61) v4(183.07,136.02)
  IN1 w0.102: v2(173.61,138.78) 174.07,138.32 174.07,137.62 174.39,137.3 178.71,137.3
  IN1 w0.107: v2(183.07,136.61) 182.38,137.3 178.71,137.3
  BOTTOM w0.102: UV1.K7 174.03,138.36 v2(173.61,138.78)
THM_ALERT#: length 14.4
  TOP w0.102: RV146.2 184.51,132.47 v2(184.31,132.67)
  TOP w0.127: v2(184.31,132.67) 185.28,132.67 v1(185.82,133.21)
  IN1 w0.102: 178.71,134.57 175.79,134.57 v2(175.28,134.05)
  IN1 w0.107: v2(184.31,132.67) 181.18,132.67 179.28,134.57 178.71,134.57
  BOTTOM w0.089: v2(175.28,134.05) 174.97,134.36 UV1.R6
  BOTTOM w0.102: UV11.6 v2(184.31,132.67)
TMDS_L_TX0N: length 17.3
  BOTTOM w0.127: JHDMI.9 10.29,64.33 10.45,64.33 10.6,64.48 10.6,69.67 12.98,72.05 17.42,72.05 RX44.1 18.04,72.01 18.29,72.01 CX25.1 18.9,72.01 19.11,72.01 19.38,72.28 LX3.2 19.94,72.28 RX37.2
TMDS_L_TX0P: length 17.4
  BOTTOM w0.127: RX38.2 19.91,71.38 LX3.3 19.48,71.38 19.11,71.75 18.9,71.75 CX26.1 18.3,71.75 18.04,71.75 RX44.2 17.34,71.79 13.09,71.79 10.85,69.56 10.85,64.37 10.55,64.07 10.25,64.07 JHDMI.7
TMDS_L_TX1N: length 17.3
  BOTTOM w0.127: JHDMI.6 11.9,62.77 12.39,62.77 12.73,62.42 12.73,59.69 13.48,58.94 14.37,58.94 16.03,60.6 16.03,64.32 16.35,64.64 17.38,64.64 RX45.1 18.04,64.64 18.29,64.64 CX27.1 18.62,64.95 18.92,64.64 19.04,64.64 19.32,64.92 LX4.2 20,64.92 RX39.2
TMDS_L_TX1P: length 17.2
  BOTTOM w0.127: RX40.2 19.98,64.02 LX4.3 19.54,64.02 19.17,64.39 18.9,64.39 CX28.1 18.3,64.39 18.04,64.39 RX45.2 17.38,64.39 16.46,64.39 16.29,64.22 16.29,60.5 14.48,58.69 13.37,58.69 12.48,59.58 12.48,62.31 12.28,62.51 11.74,62.51 JHDMI.4
TMDS_L_TX2N: length 14
  BOTTOM w0.127: RX42.2 20,61.23 LX5.2 19.38,61.23 19.11,60.96 18.92,60.96 18.61,61.26 CX29.1 18.27,60.94 18.06,60.94 RX46.2 17.38,60.96 17.08,60.96 16.8,60.68 16.8,60.28 14.69,58.18 13.16,58.18 11.29,60.05 11.29,60.54 10.48,61.34 10.28,61.34 JHDMI.3
TMDS_L_TX2P: length 14.1
  BOTTOM w0.127: JHDMI.1 10.26,61.08 10.38,61.08 11.03,60.43 11.03,59.95 13.05,57.92 14.8,57.92 17.05,60.18 17.05,60.57 17.18,60.7 17.38,60.7 RX46.1 18.01,60.68 18.32,60.68 CX30.1 18.9,60.7 19.11,60.7 19.48,60.33 LX5.3 19.98,60.33 RX41.2
TMDS_L_TXCN: length 16.2
  BOTTOM w0.127: RX31.2 19.88,68.6 LX2.2 19.44,68.6 19.11,68.27 18.96,68.27 CX23.1 18.3,68.33 18.04,68.33 RX43.1 17.38,68.33 16.85,68.33 16.72,68.45 16.72,70.46 16.17,71.01 13.5,71.01 12.25,69.76 12.25,66.1 11.99,65.85 11.82,65.85 JHDMI.12
TMDS_L_TXCP: length 16.1
  BOTTOM w0.127: JHDMI.10 11.82,65.59 12.1,65.59 12.51,66 12.51,69.65 13.6,70.75 16.06,70.75 16.46,70.35 16.46,68.35 16.74,68.07 17.38,68.07 RX43.2 18.04,68.07 18.29,68.07 CX24.1 18.84,68.01 19.04,68.01 19.35,67.7 LX2.3 19.98,67.7 RX32.2
TMDS_TX0N: length 6.9
  TOP w0.127: RP59.1 24.04,70.16 23.92,70.04 23.79,70.04 23.6,70.23 23.6,71.35 v3(23.31,71.64) 22.94,72.01 22.55,72.01 v2(22.4,72.16) 22.23,72 21.99,72 CV359.1
  BOTTOM w0.127: CX14.1 22.93,72.16 v2(22.4,72.16) 22.25,72.01 22.03,72.01 21.75,72.28 LX3.1 21.2,72.28 RX37.1
TMDS_TX0P: length 7
  TOP w0.127: CV360.1 21.96,71.74 22.23,71.74 v2(22.4,71.58) 22.58,71.75 22.83,71.75 23.13,71.46 23.35,71.24 23.35,70.12 23.68,69.79 23.97,69.79 24.1,69.66 RP59.2
  BOTTOM w0.127: CX15.1 22.95,71.58 v2(22.4,71.58) 22.22,71.75 22.03,71.75 21.66,71.38 LX3.4 21.22,71.38 RX38.1
TMDS_TX1N: length 6.4
  TOP w0.127: RP58.1 24.02,63.43 23.94,63.34 23.4,63.34 23.21,63.53 23.21,64.31 22.85,64.67 22.51,64.67 v2(22.37,64.81) 22.21,64.64 21.98,64.64 CV361.1
  BOTTOM w0.127: RX39.1 21.13,64.92 LX4.1 21.75,64.92 22.03,64.64 22.21,64.64 v2(22.37,64.81) 22.54,64.64 22.78,64.64 CX16.1
TMDS_TX1P: length 6.5
  TOP w0.127: RP58.2 24.02,62.93 23.91,63.04 23.57,63.04 23.52,63.09 23.29,63.09 22.95,63.42 v3(22.95,63.78) 22.95,64.2 22.75,64.41 22.56,64.41 v2(22.37,64.22) 22.22,64.38 21.97,64.38 21.66,64.07 CV362.1
  BOTTOM w0.127: RX40.1 21.16,64.02 LX4.4 21.59,64.02 21.96,64.39 22.21,64.39 v2(22.37,64.22) 22.53,64.38 22.79,64.38 CX17.1
TMDS_TX2N: length 6.5
  TOP w0.127: RP58.3 24.03,62.43 23.95,62.34 23.53,62.34 23.13,61.95 23.13,61.35 v3(22.94,61.16) 22.75,60.96 22.54,60.96 v2(22.37,61.13) 22.21,60.96 21.91,60.96 CV363.1
  BOTTOM w0.127: RX42.1 21.13,61.23 LX5.1 21.63,61.23 21.96,60.9 22.15,60.9 v2(22.37,61.13) 22.54,60.96 22.78,60.96 CX18.1
TMDS_TX2P: length 6.4
  TOP w0.127: RP58.4 24.01,61.93 23.85,62.09 23.63,62.09 23.39,61.84 23.39,61.24 22.85,60.71 22.54,60.71 v2(22.37,60.54) 22.22,60.69 21.9,60.69 CV364.1
  BOTTOM w0.127: CX19.1 22.79,60.69 22.53,60.69 v2(22.37,60.54) 22.27,60.64 21.9,60.64 21.59,60.33 LX5.4 21.16,60.33 RX41.1
TMDS_TXCN: length 5.9
  TOP w0.127: RP59.3 24.13,69.16 24.01,69.04 23.46,69.04 v3(23.04,68.62) 22.75,68.33 22.54,68.33 v2(22.37,68.49) 22.2,68.31 21.99,68.31 CV357.1
  BOTTOM w0.127: RX31.1 21.26,68.6 LX2.1 21.69,68.6 21.96,68.33 22.21,68.33 v2(22.37,68.49) 22.54,68.33 22.78,68.33 CX12.1
TMDS_TXCP: length 5.9
  TOP w0.127: RP59.4 24.11,68.66 23.99,68.78 23.57,68.78 22.86,68.07 22.54,68.07 v2(22.37,67.91) 22.23,68.05 21.97,68.05 21.67,67.75 CV358.1
  BOTTOM w0.127: RX32.1 21.16,67.7 LX2.4 21.59,67.7 21.96,68.07 22.21,68.07 v2(22.37,67.91) 22.53,68.06 22.79,68.06 CX13.1
TON_1.35V: length 5
  TOP w0.102: PR208.2 57.28,19.91 57.09,19.72 v1(54.76,19.72)
  TOP w0.203: PU200.9 58.19,21.1 PR208.2
TP_CLK: length 142.8
  TOP w0.127: v1(60.89,79.95) 61.23,79.61 JTP.8 63.35,79.61 66.86,76.1 v2(66.86,74.03) 66.86,73.13 65.17,71.44 64.72,71.44 64.4,71.12 62.92,71.12 62.6,71.44 60.27,71.44 C553.1 R18.1 ; RE28.2 175.44,69.72 v2(175.45,69.71) 175.9,69.71 176.46,69.16 UE1.87
  BOTTOM w0.127: v2(66.86,74.03) 69.04,71.84 75.4,71.84 88.66,58.58 135.5,58.58 136.75,59.84 145.96,59.84 152.15,66.03 156.49,66.03 158,67.54 160.23,67.54 161.65,68.96 163.21,68.96 163.66,69.41 166.99,69.41 168.41,70.83 173.08,70.83 174.2,69.71 v2(175.45,69.71)
TP_DATA: length 140.3
  TOP w0.127: RE27.2 175.44,68.83 v2(175.73,69.13) 176.16,69.13 176.53,68.76 UE1.88 ; JTP.7 63.9,78.61 66.28,76.24 v2(66.28,74.03) 64.89,72.64 63.91,72.64 63.15,71.88 v1(61.16,71.88) 60.84,71.88 C551.1 60.05,72.64 R19.1
  BOTTOM w0.127: v2(66.28,74.03) 66.3,74.03 68.71,71.62 75.3,71.62 88.57,58.35 135.6,58.35 136.85,59.61 146.05,59.61 152.25,65.8 157.75,65.8 157.83,65.72 158.4,65.72 159.01,66.33 159.35,66.33 161.74,68.73 163.3,68.73 163.76,69.18 167.09,69.18 168.5,70.6 172.98,70.6 174.37,69.21 175.64,69.21 v2(175.73,69.13)
TP_EN: length 148.5
  TOP w0.127: v2(49.6,75.44) 50.54,74.5 53.38,74.5 53.8,74.08 55.7,74.08 56.23,74.62 U78.4 ; v2(175.58,70.82) 175.92,71.16 UE1.82
  BOTTOM w0.127: v2(175.58,70.82) 173.74,70.82 173.27,71.29 166.08,71.29 164.67,69.87 163.48,69.87 163.02,69.41 161.38,69.41 159.97,68 157.81,68 156.3,66.49 151.96,66.49 145.77,60.29 136.56,60.29 135.31,59.04 89.72,59.04 76.43,72.33 69.53,72.33 66.74,75.12 64.12,75.12 v1(63.13,76.11) 62.92,76.31 54.27,76.31 53.83,75.87 50.07,75.87 49.64,75.44 v2(49.6,75.44)
TP_I2C_CLK: length 64.7
  TOP w0.127: R124.2 172.38,71.5 170.99,70.1 170.99,66.84 169.97,65.83 v2(169.78,65.83) ; RP24.1 162.31,26.94 v2(162.36,26.99) 162.79,26.99 162.92,27.11 164.05,27.11 164.88,26.29 166.43,26.29 167.01,25.71 v2(167.01,24.84)
  IN1 w0.127: v2(169.78,65.83) 169.82,65.79 169.82,64.77 170.2,64.39 170.2,59.39 169.18,58.37 169.18,47.26 167.35,45.43 167.35,30.49 166.87,30.01 166.87,24.98 v2(167.01,24.84)
  BOTTOM w0.127: R122.1 163.11,27.74 v2(162.36,26.99) 161.79,26.42 v1(161.79,26.2) 161.79,25.27 162.06,25 Q2505.1 ; U69.21 v2(167.01,24.84)
TP_I2C_DAT: length 59.8
  TOP w0.127: v2(164.84,26.91) 164.41,27.34 162.6,27.34 162.5,27.44 RP24.2 ; R125.2 171.82,70.61 171.21,70.01 171.21,66.7 169.85,65.34 168.99,65.34 167.73,64.08 167.73,62.57 v2(167.49,62.33)
  IN1 w0.127: v2(164.84,26.91) 163.7,28.05 163.7,33.27 164.84,34.41 164.84,45.52 167.44,48.12 167.44,58.34 166.5,59.28 166.5,60.95 166.95,61.4 166.95,61.73 167.49,62.28 v2(167.49,62.33)
  BOTTOM w0.127: U69.22 166.61,25.34 v1(166.12,25.84) 165.65,26.3 Q2505.4 v2(164.84,26.91) 165.1,27.18 165.47,27.18 165.66,27.37 R123.1
TP_I2C_EN: length 75.1
  TOP w0.127: v2(166.51,56.96) 168.87,56.96 169.13,56.71 170.02,56.71 170.58,57.26 187.36,57.26 187.45,57.35 v1(188.89,57.35) 189.68,58.14 189.68,62.93 189.55,63.06 UE1.123
  IN1 w0.127: v2(161.47,24.64) 161.47,32.15 164.61,35.29 164.61,45.61 167.14,48.14 167.14,56.54 166.72,56.96 v2(166.51,56.96)
  BOTTOM w0.127: UL4.4 160.4,16.56 R30.2 160.39,16.57 159.57,17.4 159.57,22.73 v2(161.47,24.64)
TP_I2C_INT#: length 169
  TOP w0.102: RE338.2 61.32,76.2 61.73,76.61 JTP.5 63.13,76.61 65.69,74.05 v2(65.69,74.05) ; RP20.3 162.27,30.98 162.58,31.3 162.58,33.48 163.39,34.29 v1(163.7,34.29) 167.06,34.29 v2(168.03,33.32)
  IN2 w0.102: v2(168.03,33.32) 166.73,34.62 155.17,34.62 152.98,36.82 152.98,41.05 147.68,46.34 147.68,54.17 v2(147.9,54.39)
  BOTTOM w0.102: v2(168.03,33.32) 168.84,32.51 168.84,29.15 169.28,28.71 R126.2 170.91,30.07 Q87.1 170.91,33.09 171.54,33.71 175.64,33.71 175.97,33.38 Q92.3 175.97,31.68 175.81,31.52 174.76,31.52 173.43,30.2 173.08,30.2 R150.2 ; v2(147.9,54.39) 147.9,55.99 148.7,56.79 148.7,58.01 147.44,59.26 136.99,59.26 135.74,58.01 88.3,58.01 75.07,71.24 68.5,71.24 v2(65.69,74.05)
TP_I2C_INT#_APU: length 128.4
  IN2 w0.102: v2(138.21,104.36) 138.39,104.53 147.18,104.53 148.45,105.8 152.35,105.8 153.47,104.69 153.47,100.72 155.49,98.69 155.49,97.33 158.32,94.5 158.32,90.2 158.79,89.73 158.79,75.76 159.32,75.23 159.32,74.76 159.02,74.46 159.02,71.93 160.84,70.11 160.84,69.75 162.85,67.74 162.85,66.23 163.09,65.98 163.09,65.93 165.86,63.16 165.86,60.49 167.25,59.1 171.3,55.04 171.3,49.92 175.89,45.34 183.76,45.34 185.67,43.43 185.67,29.02 184.84,28.19 176.9,28.19 176.08,29.02 v2(175.51,29.02)
  BOTTOM w0.102: R22.2 R12.2 v1(138.07,103.54) 138.07,104.21 v2(138.21,104.36) ; R150.1 174.57,29.68 175.01,30.11 Q92.1 175.51,30.02 v2(175.51,29.02)
TP_I2C_INT#_D: length 15.4
  TOP w0.127: RP24.3 162.33,27.94 162.69,27.57 v1(167.34,27.57) 170.08,27.57 v2(170.54,28.03)
  BOTTOM w0.102: Q87.3 171.88,31.53 171.58,31.23 171.58,29.82 R126.1 170.47,28.1 v2(170.54,28.03) 170.34,27.83 U69.4
TPUSB_X1: length 9.1
  BOTTOM w0.102: R452.2 162.29,19.34 Y9.1 163.43,22.14 R940.1 166.06,22.14 C62.1 166.62,22.16 v1(167,22.55) 167.28,22.82 167.28,23.7 167.42,23.84 U69.19
TPUSB_X2: length 4.8
  BOTTOM w0.102: Y9.3 164.04,23.06 R940.2 166.07,23.06 C73.1 v1(166.99,23.95) 167.39,24.34 U69.20
TRIP_VDDP_ALWP: length 3
  TOP w0.254: v2(133.85,149.29) 133.91,149.29 134.22,148.98 PU300.2
  BOTTOM w0.127: PR304.2 v1(134.54,150.81)
  BOTTOM w0.254: PR304.2 134.11,149.54 v2(133.85,149.29)
TS_EN: length 157.6
  TOP w0.127: UX3.3 88.3,154.25 89.52,153.03 v2(89.68,153.03) 90.54,153.03 91.37,152.21 RX20.1 ; UE1.19 191.5,72.75 v2(190.77,73.48)
  IN1 w0.127: v2(89.68,153.03) 89.68,150.24 92.13,147.79 92.13,142.84 98.33,136.64 99.48,136.64 111.02,125.11 127.79,125.11 133.48,119.42 143.4,119.42 149.61,113.21 156.87,113.21 162.28,107.81 162.28,106.28 162.74,105.82 162.74,98.69 164.1,97.33 164.1,90.68 166.2,88.59 166.2,86.7 166.99,85.9 167.41,85.9 170.29,83.02 173.31,83.02 174.24,82.09 174.24,81.73 174.96,81 175.56,81 177.48,79.08 178.94,79.08 180.42,77.6 180.42,76.34 183.36,73.41 184.62,73.41 184.95,73.08 185.82,73.08 185.98,73.24 187.4,73.24 187.89,72.75 189.11,72.75 189.84,73.48 v2(190.77,73.48)
TS_EN_R: length 222.6
  TOP w0.127: v2(93.16,152.45) 92.91,152.21 RX20.2 92.53,149.54 90.81,147.83 89.83,147.83 89.45,147.45 89.45,146.24 v2(89.58,146.11) ; D4.2 163.25,41.49 163.25,47.54 166.82,51.11 166.82,52.09 168.37,53.65 171.11,53.65 171.76,54.29 186.71,54.29 v2(187.34,54.93)
  IN1 w0.127: v2(89.58,146.11) 90.28,145.41 90.42,145.41 91.35,144.48 91.35,142.65 95.01,138.99 95.01,135.09 95.31,134.79 95.66,134.79 95.85,134.98 99.51,134.98 110.52,123.96 127.32,123.96 133.01,118.28 142.93,118.28 149.14,112.07 156.4,112.07 161.13,107.33 161.13,105.69 161.44,105.38 161.44,98.38 161.78,98.04 161.78,94.61 161.48,94.3 161.48,91.27 164,88.75 164,87.76 164.19,87.56 164.19,86.03 165.53,84.69 165.94,84.69 168.98,81.65 172.04,81.65 173.38,80.31 173.38,80.3 175.71,77.97 176.37,77.97 178.62,75.72 180.08,75.72 183.08,72.72 184.33,72.72 184.67,72.39 185.23,72.39 186.57,71.06 187.7,71.06 188.65,70.1 188.65,65.67 188.14,65.17 188.14,63.8 187.15,62.81 187.15,60.83 187.34,60.64 v2(187.34,54.93)
  BOTTOM w0.127: v2(93.16,152.45) 93.55,152.85 v1(93.55,154.05) 93.73,154.23 93.73,154.83 95.43,156.53 95.43,157.86 97.28,159.7 103.42,159.7 RX18.2 RX35.2 104.95,162.12 RX25.2
TS_EN_RR: length 8
  BOTTOM w0.127: RX25.1 103.27,162.9 103.27,163.88 102.47,164.68 100.01,164.68 99.92,164.59 v1(99.43,164.59) 99.27,164.59 98.8,165.06 JEDP.37
TS_INT#: length 90.4
  TOP w0.127: v2(115.22,99.2) 114.61,99.2 112.44,101.37 108.61,101.37 v1(106.17,103.81) 103.5,106.48 100.39,106.48 98.87,107.99 98.87,115.78 100.97,117.88 102.21,117.88 107.73,123.4 107.73,133.41 102.91,138.23 100.04,141.09 100.04,145.17 100.81,145.94 100.81,149.35 104.76,153.3 104.76,159.44 v2(104.97,159.65)
  BOTTOM w0.102: 116.73,98.43 117.67,97.49 117.67,94.11 117.9,93.88 119.01,93.88 UC1.AD5
  BOTTOM w0.127: v2(115.22,99.2) 115.96,99.2 116.73,98.43 ; RX18.1 v2(104.97,159.65)
TS_RST#: length 99.3
  TOP w0.102: v2(126.06,90.62) 126.42,90.98 126.42,94.55 126.33,94.64 126.33,94.64 126.1,94.86 126.1,94.87 126,94.97 126,98.43
  TOP w0.127: v2(100.37,146.13) 100.37,149.24 104.53,153.4 104.53,161.15 v2(106.44,163.07) ; 126,98.43 126,101.08 v1(126.36,101.44) 126.64,101.71 v2(127.4,101.71)
  IN2 w0.127: v2(127.4,101.71) 127.49,101.8 127.49,102.97 126.55,103.91 126.55,105.32 126.71,105.48 126.71,107.2 126.38,107.54 126.38,108.47 122.45,112.39 108.89,112.39 104.91,116.38 104.91,141.45 100.37,145.98 v2(100.37,146.13)
  BOTTOM w0.102: UC1.AL8 125.56,91.12 v2(126.06,90.62)
  BOTTOM w0.127: RX17.1 105.59,164.85 106.1,164.34 106.1,163.41 v2(106.44,163.07)
TS_RST#_EC: length 225.8
  TOP w0.127: UE1.21 v2(194.43,73.56)
  IN1 w0.127: v2(194.43,73.56) 194.05,73.94 194.05,76.42 195.41,77.77 195.41,81 195.36,81.04 195.36,82.33 196.67,83.64 196.67,111.96 198.34,113.63 198.34,128.51 199.56,129.73 201.52,129.73 202.65,130.86 202.65,142.65 197.82,147.47 197.82,150.61 199.61,152.4 202,152.4 203.12,153.51 203.12,156.89 203.27,157.04 203.27,162.41 201.29,164.39 201.29,167.92 192.9,176.31 149.61,176.31 147.57,174.27 147.57,171.2 147.19,170.81 146.74,170.81 146.42,171.13 145.47,171.13 145.22,171.39 145.22,172.83 140.76,177.28 122.23,177.28 119.75,174.8 119.75,173.74 118.93,172.91 110.51,172.91 109.76,172.16 109.76,168.89 107.79,166.92 107.79,163.78 v2(106.44,162.43)
  BOTTOM w0.127: v2(106.44,162.43) 105.78,163.09 105.78,163.54 105.37,163.96 RX19.1
TS_RST#_R: length 7.4
  BOTTOM w0.127: JEDP.38 99.3,165.23 99.62,164.91 v1(102.99,164.91) 103.99,164.91 RX17.2 RX19.2 RX24.2
UG1_APU: length 8.4
  TOP w0.127: v2(117.53,142.49) v1(117.53,143.32)
  IN2 w0.762: 116.9,149.73 116.9,148.97 118.55,147.32 118.55,143.38 118.17,143
  vias: v2(116.9,142.49) v2(117.04,151.17) v2(117.04,150.57)
UG1_GFX: length 5.8
  IN2 w0.762: 61.65,40.32 61.65,40.91 60,42.56 60,44.26 60.7,44.96 60.7,45.15
  vias: v2(60.7,46.61) v2(60.69,45.91) v2(61.14,39.5) v2(61.14,38.86)
UG1_VGA: length 6.9
  IN2 w0.762: 174.43,94.65 174.43,100.96 174.87,101.41
  vias: v2(174.14,93.92) v2(174.76,93.93) v2(175.16,102.02) v2(175.76,102.04)
UG2_VGA: length 18.1
  BOTTOM w0.762: 194.62,86.55 193.95,85.88 183.86,85.88 v1(182.52,87.22) 180.59,89.15 178.11,89.15
  vias: v2(173.92,89.92) v2(174.55,89.92) v2(176.71,89.28) v2(177.35,89.28)
UG_1.35V: length 6.5
  IN2 w0.762: 70.48,20.13 69.53,21.08 64.38,21.08
  vias: v2(63.05,20.95) v2(63.68,20.95) v2(71.1,19.8) v2(71.11,19.18)
UG_3V: length 7
  IN2 w0.762: 35.49,43.31 35.49,44.89 39.3,48.7
  vias: v2(35.62,42.54) v2(35.62,41.91) v2(39.44,49.45) v2(40.06,49.47)
UG_5V: length 6.5
  IN2 w0.762: 44.7,43.31 44.7,45.02 45.65,45.97 45.65,48.83 45.27,49.21
  vias: v2(43.87,49.47) v2(44.51,49.47) v2(44.75,42.54) v2(44.76,41.91)
UG_NB: length 13
  IN2 w0.762: 122.48,152.41 122.48,150.47 125.66,147.29 125.66,142.18 124.64,141.16
  vias: v2(122.13,153.09) v2(122.75,153.1) v2(123.96,140.73) v2(123.95,140.08)
UG_VDDP_ALWP: length 16.1
  TOP w0.127: PQ301.4 v1(144.58,133.1)
  IN2 w0.762: 139.88,149.03 140.46,148.46 140.46,140.35 144.52,136.28
  vias: v2(138.49,149.1) v2(139.12,149.1) v2(144.52,135.51) v2(145.17,135.51)
UGATE_CHG: length 11.1
  IN2 w0.762: 121.28,165.61 124.49,165.61 127.98,162.12 130.93,162.12
  vias: v2(120.11,166.12) v2(120.72,166.12) v2(131.69,161.99) v2(132.33,161.99)
USB3RN1_JUSB1: length 133.2
  IN2 w0.127: v2(117.57,91.87) 117.57,91.89 117.44,92.01 117.29,92.01 117.16,91.88 117.16,85.7 116.67,85.2 115.94,85.2 115.7,85.45 109.03,85.45 108.43,86.05 108.43,88.13 108.06,88.49 103.84,88.49 103.56,88.21 98.93,88.21 94.85,84.14 91.81,84.14 90.86,85.09 89.46,85.09 81.13,85.09 70.88,74.84 57.62,74.84 52.38,69.6 52.38,67.18 43.88,58.67 37.91,58.67 28.7,49.46 28.7,39.56 26.83,37.69 25.36,37.69 v2(25.24,37.58)
  BOTTOM w0.102: v2(117.57,91.87) 117.52,91.92 UC1.Y7
  BOTTOM w0.127: v2(25.24,37.58) 25.11,37.71 24.1,37.71 23.84,37.45 LI1.1
USB3RN1_JUSB1_R: length 9.7
  BOTTOM w0.127: LI1.2 21.11,37.45 20.95,37.61 DI1.10 DI1.1 18.21,37.61 18.14,37.68 17.62,37.68 17.09,37.15 v3(16.74,37.15) 16.24,37.15 15.7,37.68 14.87,37.68 13.32,36.14 JUSB1.5
USB3RP1_JUSB1: length 133.2
  IN2 w0.127: v2(117.57,92.43) 117.57,92.42 117.48,92.33 117.15,92.33 116.85,92.02 116.85,85.83 116.54,85.52 116.07,85.52 115.83,85.76 109.16,85.76 108.74,86.18 108.74,88.26 108.19,88.81 103.97,88.81 103.71,88.81 103.44,88.54 98.81,88.54 94.72,84.45 91.95,84.45 90.99,85.41 89.59,85.41 81,85.41 70.75,75.16 57.49,75.16 52.06,69.73 52.06,67.31 43.74,58.99 37.78,58.99 28.38,49.59 28.38,39.69 26.7,38.01 25.39,38.01 v2(25.24,38.16)
  BOTTOM w0.102: UC1.Y6 117.28,92.72 v2(117.57,92.43)
  BOTTOM w0.127: LI1.4 23.86,38.25 24.08,38.03 25.11,38.03 v2(25.24,38.16)
USB3RP1_JUSB1_R: length 9.7
  BOTTOM w0.127: JUSB1.6 13.32,37.59 13.65,37.26 14,37.26 14.73,38 15.83,38 16.37,37.47 16.96,37.47 17.49,38 v3(17.7,38) 18.12,38 18.23,38.11 DI1.2 DI1.9 20.98,38.11 21.11,38.25 LI1.3
USB3TN1_JUSB1: length 134.4
  IN2 w0.127: v2(26.53,39.26) 26.54,39.26 26.65,39.37 27.04,39.37 27.74,40.07 27.74,49.86 37.6,59.72 41.93,59.72 51.36,69.15 51.36,69.98 57.47,76.09 70.78,76.09 80.8,86.11 91.21,86.11 92.23,85.09 93.3,85.09 93.64,85.42 94.79,85.42 99.05,89.69 102.3,89.69 102.75,90.13 104.07,90.13 104.58,89.62 108.93,89.62 109.61,88.95 109.61,87.02 109.96,86.66 115.51,86.66 115.97,87.12 115.97,89.93 114.74,91.16 114.74,94.64 115.85,95.75 118.46,95.75 v2(118.69,95.53)
  BOTTOM w0.102: UC1.AC2 118.69,95.64 v2(118.69,95.53)
  BOTTOM w0.127: v2(26.53,39.26) 26.4,39.39 25.93,39.39 CI3.2
USB3TN1_JUSB1_C: length 1.4
  BOTTOM w0.127: CI3.1 24.73,39.1 LI3.1
USB3TN1_JUSB1_R: length 11.2
  BOTTOM w0.127: JUSB1.8 13.32,42.51 13.58,42.77 13.73,42.77 14.57,41.94 15.42,41.94 16.63,40.72 v3(16.63,40.42) 16.63,39.65 17.08,39.2 18.11,39.2 18.2,39.11 DI1.4 DI1.7 21.67,39.11 LI3.2
USB3TP1_JUSB1: length 134.5
  IN2 w0.127: v2(26.53,39.84) 26.68,39.69 26.91,39.69 27.43,40.2 27.43,49.99 37.47,60.03 41.8,60.03 51.05,69.28 51.05,70.11 57.34,76.4 70.65,76.4 80.67,86.42 91.34,86.42 92.36,85.41 93.17,85.41 93.5,85.74 94.65,85.74 98.92,90 102.17,90 102.62,90.45 104.2,90.45 104.71,89.94 109.06,89.94 109.92,89.08 109.92,87.15 110.09,86.98 115.38,86.98 115.65,87.25 115.65,89.8 114.42,91.03 114.42,94.77 115.72,96.07 118.44,96.07 v2(118.68,96.31)
  BOTTOM w0.102: v2(118.68,96.31) 118.97,96.59 UC1.AC1
  BOTTOM w0.127: v2(26.53,39.84) 26.4,39.71 25.96,39.71 CI4.2
USB3TP1_JUSB1_C: length 1.4
  BOTTOM w0.127: CI4.1 24.64,39.9 LI3.4
USB3TP1_JUSB1_R: length 11.2
  BOTTOM w0.127: JUSB1.9 13.32,43.64 14.7,42.25 15.55,42.25 16.95,40.86 16.95,39.78 17.21,39.52 v3(17.58,39.52) 18.11,39.52 18.2,39.61 DI1.5 DI1.6 21.14,39.61 21.42,39.9 LI3.3
USB20_CAM_N7: length 90.6
  IN2 w0.127: v2(127.55,108.03) 127.55,110.89 123.9,114.53 109.78,114.53 107.05,117.26 107.05,142.33 103.79,145.59 103.79,148.65 98.46,153.98 98.46,155.75 95.68,158.53 95.68,159.39 v2(95.55,159.51)
  BOTTOM w0.102: 125.2,98.41 125.2,98.38 125.22,98.37 125.22,98.27 124.11,97.16 124.11,96.58 124.03,96.5 124.03,96.08 124.12,95.99 124.12,95.84 124.02,95.73 123.87,95.73 123.77,95.84 UC1.AJ2
  BOTTOM w0.127: v2(95.55,159.51) 95.69,159.65 95.69,160.15 95.36,160.48 LX6.4 95.36,160.91 RX21.1 ; 125.2,98.41 125.2,98.74 125.95,99.49 127.56,99.49 128.05,99.98 128.05,101.67 127.44,102.28 127.44,107.23 127.7,107.5 127.7,107.87 v2(127.55,108.03)
USB20_CAM_N7_R: length 4.3
  BOTTOM w0.127: JEDP.30 95.3,165.28 95.39,165.18 v3(95.39,164.74) 95.39,164.51 95.7,164.2 95.7,163.27 95.36,162.93 LX6.3 95.36,162.18 RX21.2
USB20_CAM_P7: length 90.6
  IN2 w0.127: v2(128.13,108.03) 128.1,108.03 127.86,108.26 127.86,111.02 124.04,114.85 109.91,114.85 107.36,117.39 107.36,142.46 104.11,145.72 104.11,148.78 98.77,154.11 98.77,155.88 95.99,158.66 95.99,159.37 v2(96.14,159.51)
  BOTTOM w0.102: UC1.AK2 124.34,95.74 124.34,96.08 124.26,96.17 124.26,96.44 124.4,96.58 124.4,97.04 125.51,98.15 125.51,98.37 125.52,98.38 125.52,98.41
  BOTTOM w0.127: v2(128.13,108.03) 128.02,107.92 128.02,107.37 127.76,107.1 127.76,102.41 128.36,101.8 128.36,99.85 127.69,99.17 126.08,99.17 125.52,98.61 125.52,98.41 ; RX22.1 96.26,160.89 LX6.1 96.26,160.33 96.01,160.08 96.01,159.64 v2(96.14,159.51)
USB20_CAM_P7_R: length 4.3
  BOTTOM w0.127: RX22.2 96.26,162.2 LX6.2 96.26,162.88 96.01,163.12 v3(96.01,163.56) 96.01,164.33 95.71,164.64 95.71,165.18 95.8,165.28 JEDP.31
USB20_CR_N0: length 192.3
  IN2 w0.127: v2(127.05,97.74) 127.01,97.7 126.9,97.7 126.43,98.17 126.43,102.06 125.3,103.19 125.3,105.07 125.71,105.48 125.71,106.16 125.38,106.49 125.38,108.28 122.1,111.55 110.28,111.55 109.38,110.66 106.61,110.66 104.33,110.66 95.05,101.38 95.05,90.12 93.76,88.82 92.72,88.82 92.6,88.71 79.72,88.71 69.7,78.69 55.31,78.69 54.6,77.98 50.22,77.98 46.16,73.91 46.16,69.38 44.14,67.36 42.94,67.36 38.95,63.37 36.76,63.37 25.11,51.73 25.11,50.46 22.8,48.15 22.8,35.41 15.63,28.24 v2(14.27,28.24)
  BOTTOM w0.112: v2(127.05,97.74) 127.13,97.66 127.33,97.66 128.27,96.72 UC1.AR1
  BOTTOM w0.127: LR2.1 11.56,18.03 11.21,18.38 10.93,18.38 R808.1 10.71,18.17 10.09,18.8 10.09,25.18 v3(11.82,26.92) 13.14,28.24 v2(14.27,28.24)
USB20_CR_N0_R: length 1.8
  BOTTOM w0.127: UR1.2 14.81,18.75 14.47,18.41 14.4,18.41 14.01,18.03 LR2.2
USB20_CR_P0: length 192.2
  IN2 w0.127: v2(126.64,97.33) 126.64,97.52 126.11,98.04 126.11,101.93 124.99,103.06 124.99,105.2 125.4,105.61 125.4,106.03 125.06,106.36 125.06,108.15 121.97,111.24 110.41,111.24 109.51,110.34 106.74,110.34 104.46,110.34 95.37,101.24 95.37,89.99 93.89,88.51 92.85,88.51 92.73,88.39 79.85,88.39 69.83,78.37 55.44,78.37 54.73,77.66 50.35,77.66 46.48,73.78 46.48,69.25 44.27,67.04 43.07,67.04 39.09,63.06 36.89,63.06 25.43,51.6 25.43,50.33 23.12,48.02 23.12,35.28 15.77,27.92 14.53,27.92 v2(14.27,27.65)
  BOTTOM w0.112: v2(126.64,97.33) 127.2,97.33 128.14,96.39 128.75,96.39 128.85,96.29 128.85,96.09 128.68,95.92 UC1.AR2
  BOTTOM w0.127: v2(14.27,27.65) 14,27.92 13.28,27.92 10.41,25.05 10.41,18.93 10.64,18.69 11.32,18.69 11.56,18.93 LR2.4
USB20_CR_P0_R: length 1.8
  BOTTOM w0.127: LR2.3 13.96,18.93 14.15,18.73 14.34,18.73 14.86,19.25 UR1.3
USB20_JUSB1_N6: length 160.3
  TOP w0.127: LI2.4 22.74,42.42 22.98,42.18 23.39,42.18 R811.1 23.92,41.97 v2(24.82,41.97)
  IN2 w0.127: v2(124.98,94.73) 125.31,94.73 125.43,94.84 125.43,95.01 125.31,95.12 124.66,95.12 124.3,95.48 124.3,96.43 124.12,96.61 124.12,98.05 123.64,98.53 123.64,102.4 123.98,102.74 123.98,106.01 124.24,106.27 124.24,107.8 121.63,110.41 110.75,110.41 109.81,109.47 104.77,109.47 96.2,100.9 96.2,89.56 93.52,86.88 92.53,86.88 91.85,87.57 80.2,87.57 70.18,77.55 56.18,77.55 52.29,73.66 52.29,73.02 45.29,66.03 44.91,66.03 44,65.13 42.49,65.13 38.94,61.57 36.69,61.57 26.49,51.37 26.49,50 23.95,47.46 23.95,42.25 24.22,41.97 v2(24.82,41.97)
  BOTTOM w0.102: UC1.AL4 125.37,94.63 125.27,94.73 v2(124.98,94.73)
USB20_JUSB1_N6_R: length 8.6
  TOP w0.127: LI2.3 20.19,42.42 19.87,42.1 19.31,42.1 18.78,41.57 18.78,40.81 18.14,40.16 17.68,40.16 17.56,40.29 DI2.2 16.99,40.97 16.19,40.16 15.63,40.16 JUSB1.2
USB20_JUSB1_P6: length 160.2
  TOP w0.127: LI2.1 22.66,41.52 23,41.86 23.58,41.86 23.79,41.66 24.55,41.66 v2(24.82,41.39)
  IN2 w0.127: v2(125.08,95.52) 125,95.44 124.79,95.44 124.62,95.61 124.62,96.56 124.44,96.74 124.44,98.18 123.96,98.67 123.96,102.27 124.3,102.61 124.3,105.88 124.56,106.14 124.56,107.94 121.76,110.73 110.62,110.73 109.68,109.79 104.64,109.79 95.88,101.03 95.88,89.69 93.39,87.2 92.67,87.2 91.98,87.88 80.06,87.88 70.04,77.86 56.05,77.86 51.97,73.79 51.97,73.16 45.16,66.34 44.77,66.34 43.87,65.44 42.36,65.44 38.8,61.89 36.55,61.89 26.17,51.5 26.17,50.13 23.63,47.59 23.63,42.12 24.09,41.66 24.55,41.66 v2(24.82,41.39)
  BOTTOM w0.102: v2(125.08,95.52) 125.37,95.24 UC1.AL3
USB20_JUSB1_P6_R: length 8.6
  TOP w0.127: JUSB1.3 15.7,39.85 16.05,39.85 16.85,39.04 DI2.3 17.56,39.72 17.68,39.85 18.27,39.85 19.09,40.67 19.09,41.44 19.44,41.78 19.93,41.78 20.19,41.52 LI2.2
USB20_JUSB2_N1: length 102.7
  TOP w0.127: v2(182.05,42.61) 182.18,42.48 182.68,42.48 182.96,42.75 LI7.1
  IN2 w0.127: v2(182.05,42.61) 180.92,42.61 179.6,43.94 175.42,43.94 169.25,50.11 169.25,55.23 161.04,63.44 161.04,63.93 160.56,64.41 160.56,66.96 156.18,71.34 156.18,77.44 156.52,77.78 156.52,83.56 156.16,83.92 156.16,93.62 153.35,96.44 153.35,97.21 148.23,102.32 142.02,102.32 141.6,101.9 137.52,101.9 137.01,101.4 135.03,101.4 133.74,100.1 132.62,100.1 129.86,97.35 129.86,97.08 128.45,95.67 128.25,95.47 v2(128.25,94.73)
  BOTTOM w0.102: v2(128.25,94.73) 128.57,94.42 UC1.AR4
USB20_JUSB2_N1_R: length 9.2
  TOP w0.127: JIO1.22 191.34,42.76 191.05,42.47 190.76,42.47 189.67,43.56 188.4,43.56 187.45,42.61 187.13,42.61 186.98,42.76 DI3.2 186.19,43.38 186.01,43.21 186.01,42.65 185.83,42.47 185.62,42.47 185.33,42.75 LI7.2
USB20_JUSB2_P1: length 102.7
  TOP w0.127: LI7.4 182.99,41.85 182.68,42.16 182.18,42.16 v2(182.05,42.03)
  IN2 w0.127: v2(182.05,42.03) 181.78,42.3 180.79,42.3 179.47,43.62 175.29,43.62 168.93,49.98 168.93,55.1 160.73,63.3 160.73,63.8 160.24,64.28 160.24,66.83 155.86,71.21 155.86,77.58 156.2,77.92 156.2,83.43 155.84,83.79 155.84,93.49 153.03,96.3 153.03,97.07 148.1,102.01 142.15,102.01 141.73,101.59 137.65,101.59 137.15,101.08 135.16,101.08 133.87,99.78 132.75,99.78 130.18,97.21 130.18,96.95 128.57,95.33 128.57,94.98 128.81,94.74 v2(128.98,94.74)
  BOTTOM w0.102: v2(128.98,94.74) 128.78,94.74 128.57,94.95 UC1.AR3
USB20_JUSB2_P1_R: length 9.2
  TOP w0.127: JIO1.21 191.33,41.76 190.94,42.15 190.63,42.15 189.54,43.24 188.53,43.24 187.58,42.29 187.1,42.29 186.98,42.16 DI3.3 186.1,41.45 185.93,41.62 185.93,42 185.78,42.15 185.59,42.15 185.29,41.85 LI7.3
USB20_JUSB3_N2: length 109.9
  TOP w0.127: v2(182.24,38.06) 182.31,38.13 182.78,38.13 182.99,37.92 LI8.4
  IN2 w0.127: v2(127.28,96.34) 127.67,96.34 132.26,100.93 133.4,100.93 134.69,102.22 136.67,102.22 137.18,102.73 141.06,102.73 141.55,103.21 148.53,103.21 154.17,97.57 154.17,96.78 156.98,93.97 156.98,89.67 157.47,89.18 157.47,77.34 157,76.87 157,71.69 161.51,67.18 161.51,64.72 161.87,64.36 161.87,63.78 170.68,54.97 170.68,49.85 175.76,44.77 181.86,44.77 183.25,43.37 183.25,38.67 182.71,38.13 182.3,38.13 v2(182.24,38.06)
  BOTTOM w0.102: v2(127.28,96.34) 126.97,96.66 UC1.AN1
USB20_JUSB3_N2_R: length 8.8
  TOP w0.127: JIO1.18 191.23,38.76 191,38.99 190.54,38.99 190.29,39.24 188.66,39.24 187.62,38.2 187.14,38.2 186.98,38.04 DI4.3 186.14,37.39 185.95,37.58 185.95,38.05 185.81,38.19 185.63,38.19 185.36,37.92 LI8.3
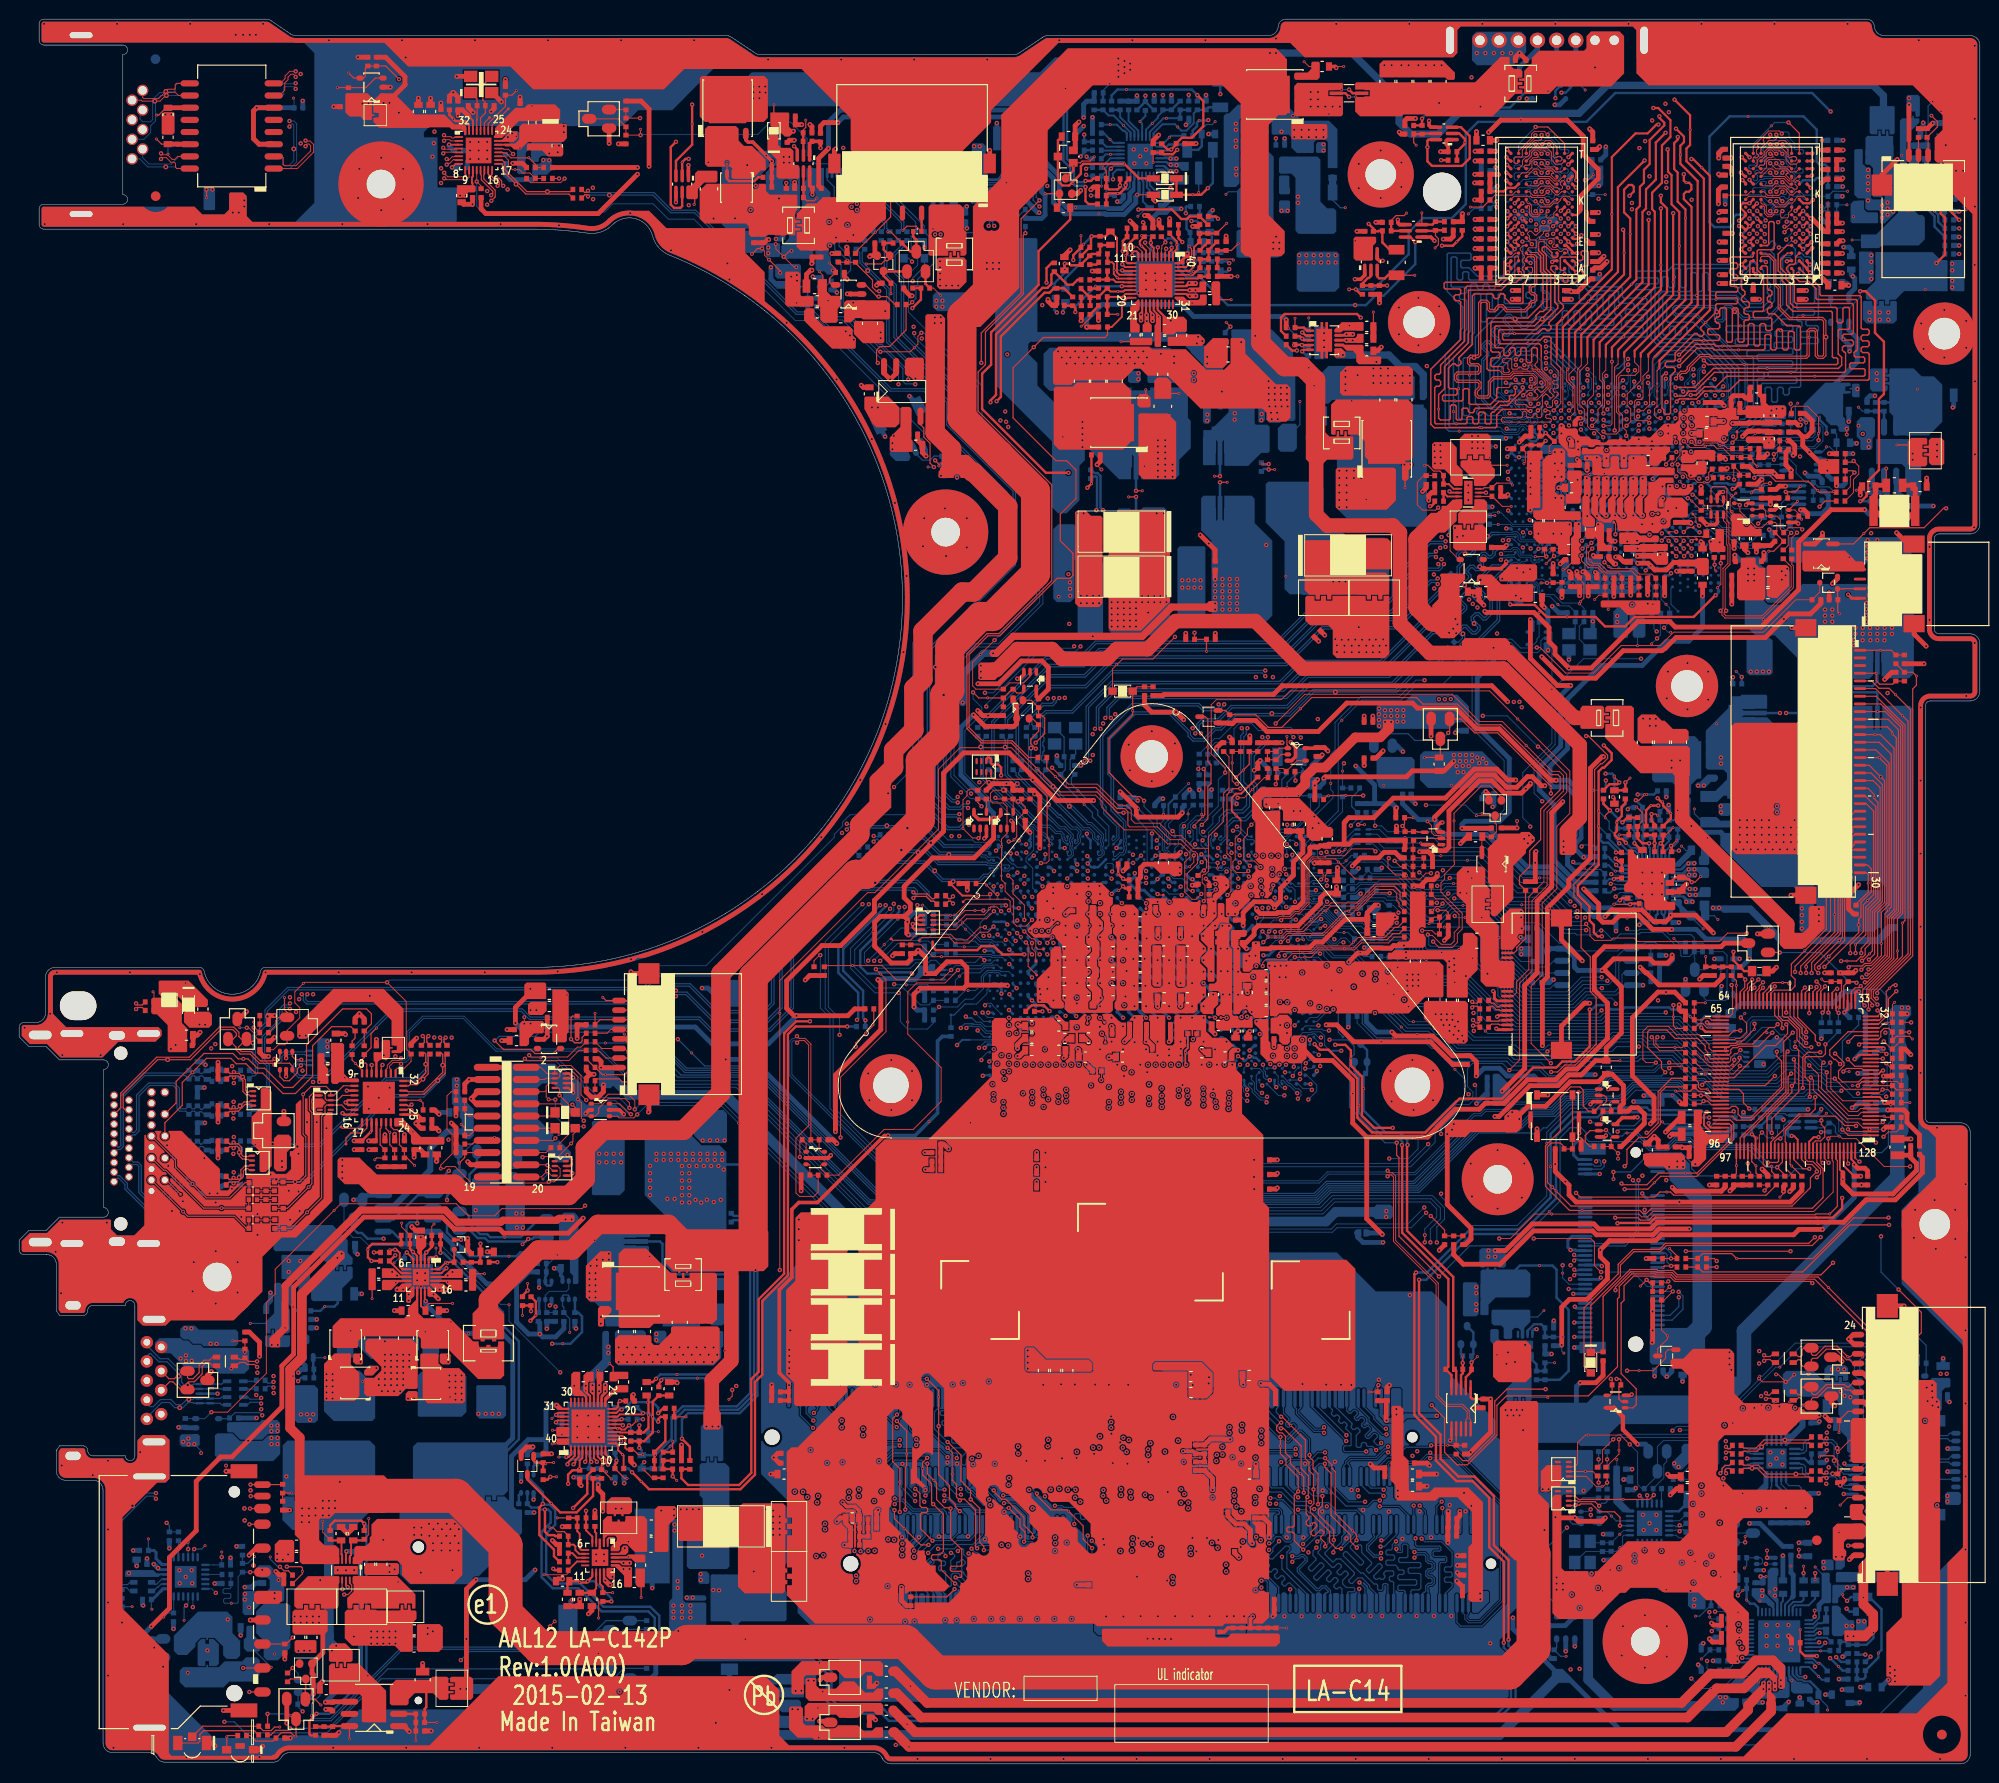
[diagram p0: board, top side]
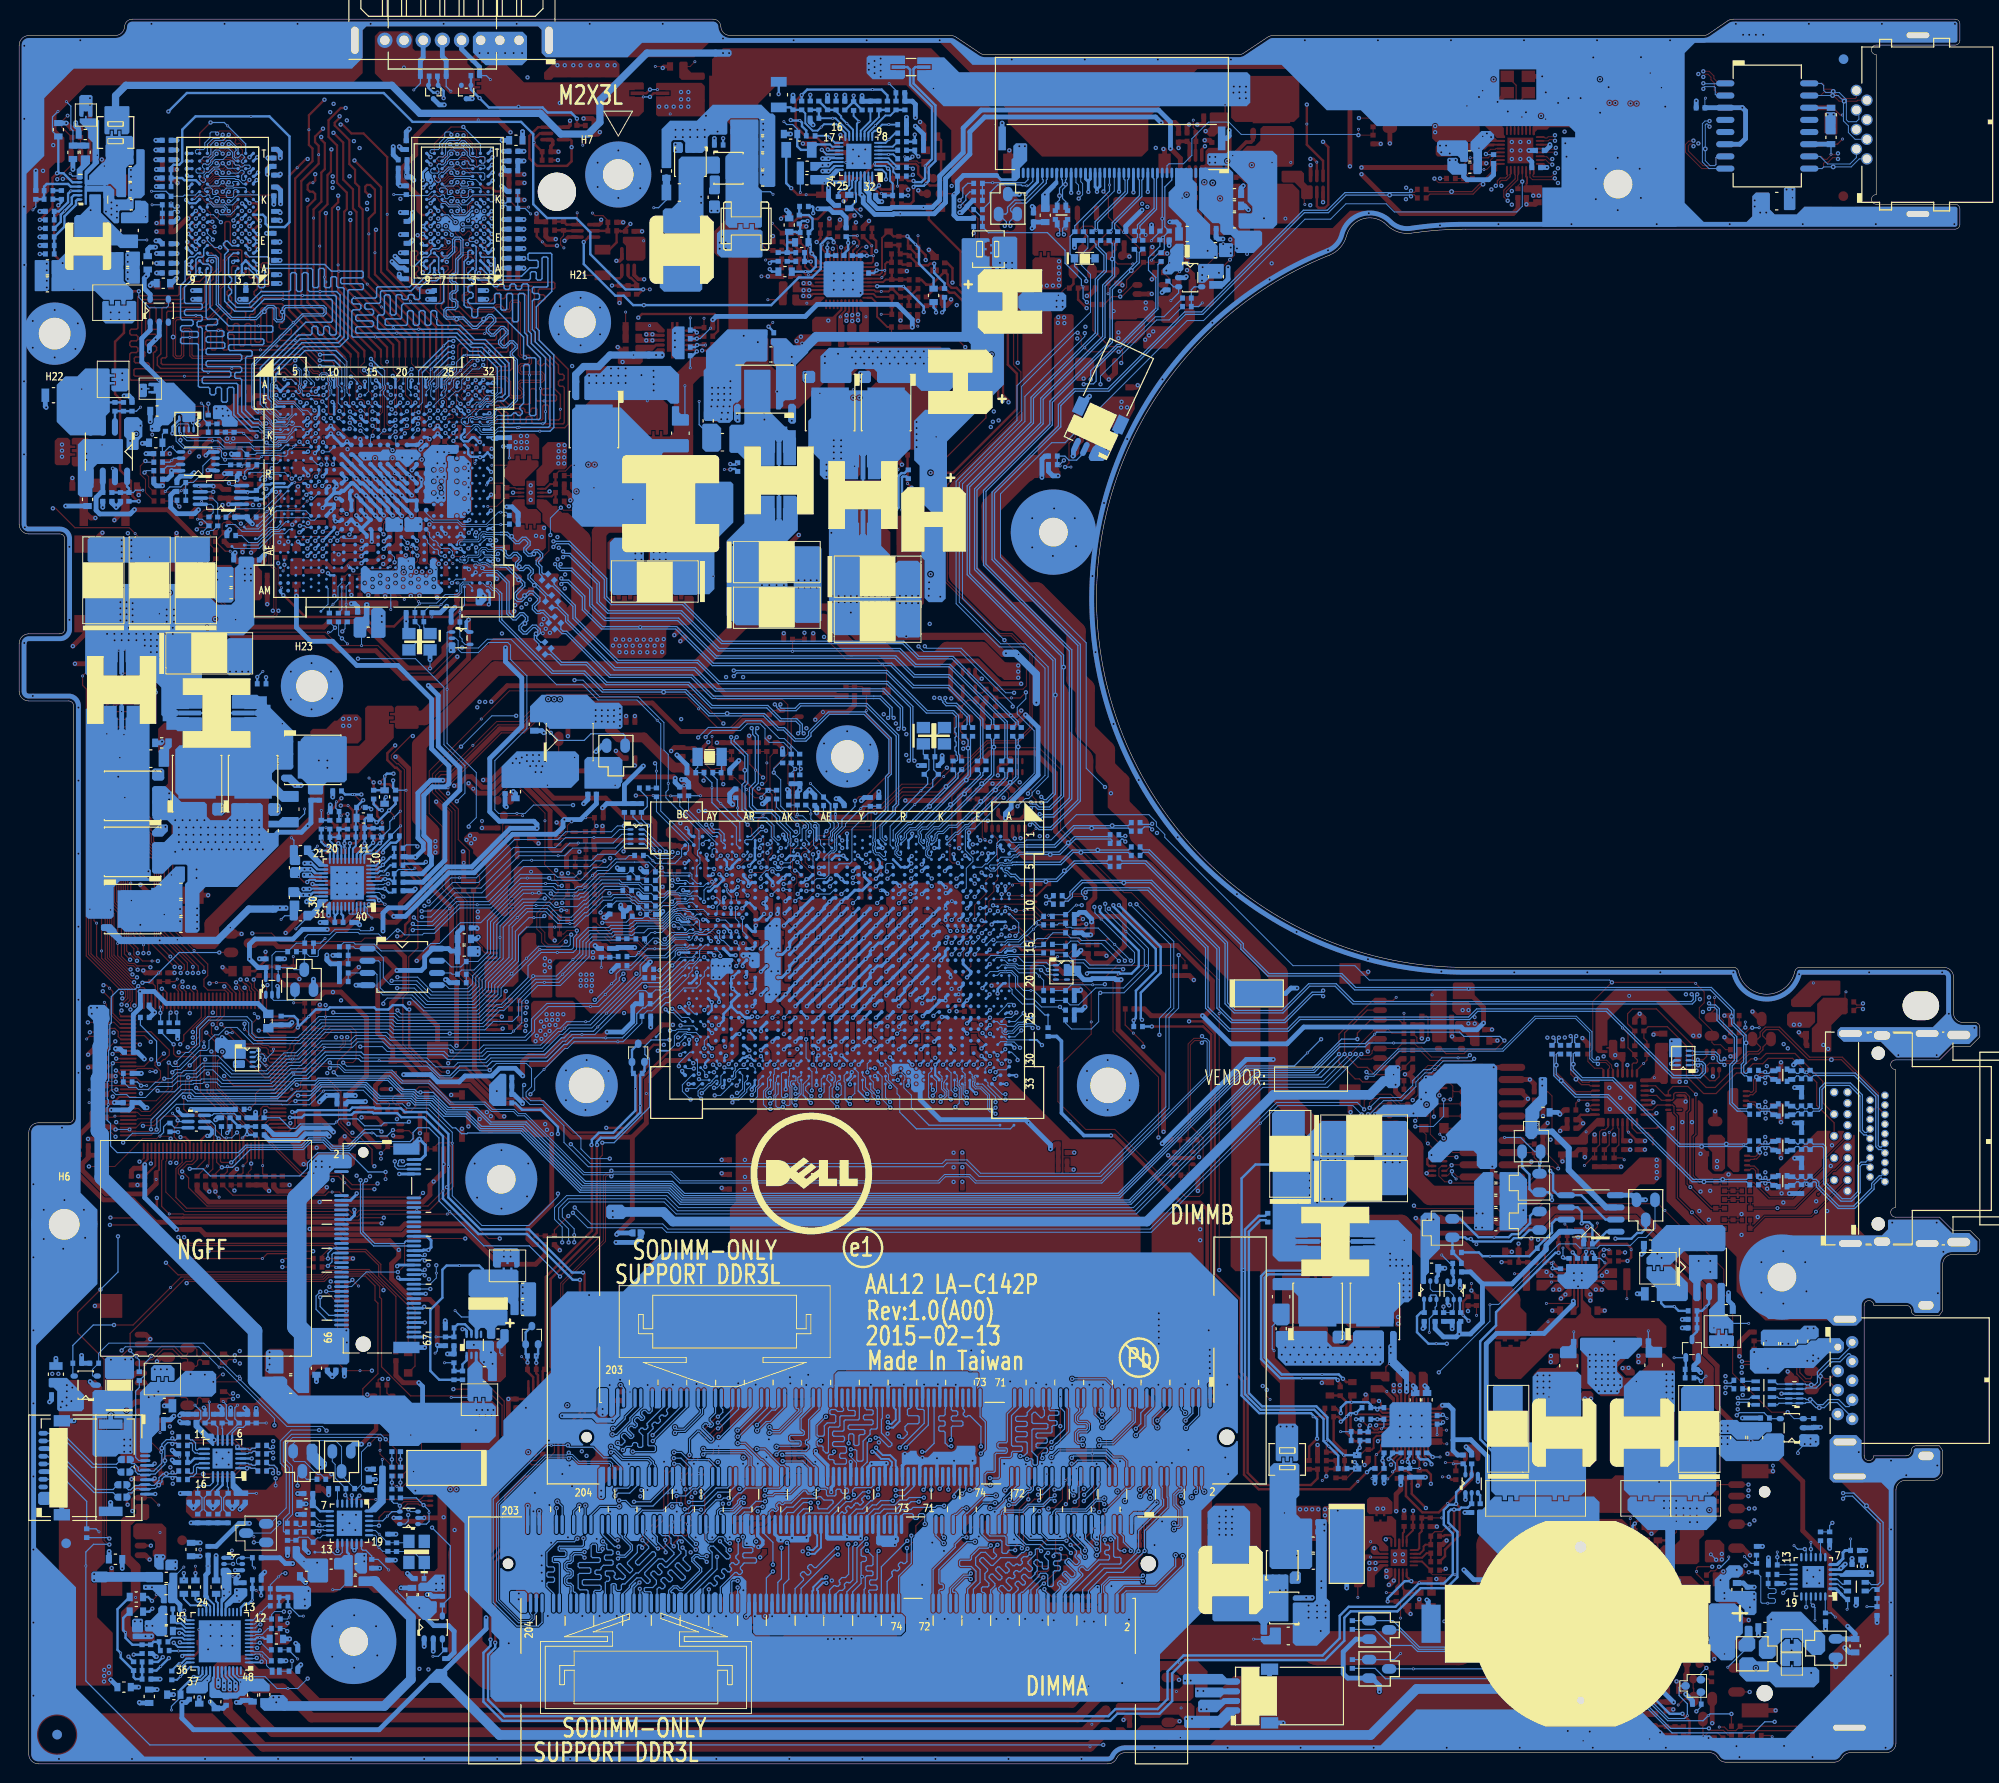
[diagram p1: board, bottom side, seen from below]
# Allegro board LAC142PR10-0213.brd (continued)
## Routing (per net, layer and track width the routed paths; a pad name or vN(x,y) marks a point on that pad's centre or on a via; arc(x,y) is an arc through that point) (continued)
USB20_JUSB3_P2: length 109.9
  TOP w0.127: v2(182.24,38.65) 182.43,38.45 182.59,38.45 182.96,38.82 LI8.1
  IN2 w0.127: v2(182.24,38.65) 182.44,38.44 182.58,38.44 182.94,38.8 182.94,43.24 181.73,44.45 175.63,44.45 170.36,49.71 170.36,54.83 161.55,63.65 161.55,64.23 161.19,64.59 161.19,67.05 156.69,71.55 156.69,77 157.16,77.47 157.16,89.05 156.67,89.54 156.67,93.83 153.85,96.65 153.85,97.44 148.4,102.9 141.68,102.9 141.2,102.41 137.31,102.41 136.8,101.9 134.82,101.9 133.53,100.61 132.39,100.61 127.8,96.02 127.52,96.02 127.45,95.94 127.15,95.94 127.07,95.86 127.07,95.73 v2(127.28,95.51)
  BOTTOM w0.102: UC1.AN2 127.19,95.92 127.28,95.83 v2(127.28,95.51)
USB20_JUSB3_P2_R: length 8.9
  TOP w0.127: LI8.2 185.29,38.82 185.6,38.51 185.81,38.51 185.97,38.67 185.97,39.17 186.12,39.32 DI4.2 186.98,38.71 187.17,38.52 187.48,38.52 188.52,39.56 190.42,39.56 190.68,39.31 190.86,39.31 191.32,39.76 JIO1.19
USB20_MINI1_N4: length 80.9
  IN2 w0.102: v2(126.49,95.02) 126.39,95.12 126,95.12 125.62,95.5 125.62,96.5 126.07,96.95 126.89,96.95 127.82,97.87 127.82,98.4 127.81,98.42 127.81,98.43
  IN2 w0.127: v2(165.36,62.84) 165.03,63.18 165.03,63.29 164.48,63.84 163.56,63.84 162.34,65.06 162.34,67.55 160.34,69.55 160.34,69.91 158.46,71.79 158.46,75.28 158.3,75.44 158.3,89.53 157.81,90.02 157.81,94.31 155,97.12 155,97.96 148.92,104.04 141.09,104.04 140.61,103.56 135.34,103.56 134.83,103.05 134.35,103.05 133.05,101.75 131.9,101.75 130.98,100.83 129.71,100.83 127.81,98.92 127.81,98.43
  BOTTOM w0.102: v2(126.49,95.02) 126.49,95.2 UC1.AM2
  BOTTOM w0.127: JNGFF.5 165.08,62.03 165.36,62.31 165.36,62.74 165.36,62.74 v2(165.36,62.84)
USB20_MINI1_P4: length 81
  IN2 w0.102: 128.12,98.43 128.12,98.42 128.11,98.4 128.11,97.75 127.01,96.66 126.19,96.66 125.91,96.38 125.91,95.62 126.12,95.42 126.78,95.42 126.85,95.49 126.85,95.83 126.76,95.93 v2(126.46,95.93)
  IN2 w0.127: v2(164.52,62.84) 164.71,63.03 164.71,63.16 164.34,63.53 163.43,63.53 162.02,64.93 162.02,67.42 160.03,69.41 160.03,69.78 158.15,71.66 158.15,75.15 157.98,75.31 157.98,89.39 157.49,89.88 157.49,94.18 154.68,96.99 154.68,97.83 148.79,103.72 141.22,103.72 140.74,103.24 135.47,103.24 134.96,102.73 134.48,102.73 133.18,101.43 132.03,101.43 131.11,100.51 129.85,100.51 128.12,98.79 128.12,98.43
  BOTTOM w0.102: UC1.AM1 126,96.16 126,96 126.17,95.83 126.36,95.83 v2(126.46,95.93)
  BOTTOM w0.127: v2(164.52,62.84) 164.67,62.99 164.86,62.99 164.97,62.89 164.97,62.68 165.05,62.6 165.05,62.44 164.95,62.34 164.36,62.34 164.18,62.52 JNGFF.3
USB20_N3: length 108
  IN2 w0.102: v2(127.33,94.01) 127.52,94.2 127.69,94.2 127.82,94.06 128.61,94.06 128.68,93.98 134.23,93.98 135.76,95.51 136.46,95.51 136.72,95.77 136.89,95.77 136.9,95.76 136.91,95.76
  IN2 w0.127: 136.91,95.76 146.79,95.76 151.08,91.47 151.08,84.47 150.95,84.34 150.95,81.49 150.5,81.04 150.5,76.67 152.43,74.74 152.43,67.95 157.87,62.52 157.87,61.74 161.73,57.88 161.73,57.64 165.82,53.55 165.82,51.16 165.41,50.75 165.41,49.46 174.26,40.61 174.26,28.66 172.33,26.73 172.33,24.76 172.71,24.38 173.11,24.38 v2(173.23,24.26)
  BOTTOM w0.102: UC1.AN4 127.02,94.32 v2(127.33,94.01)
  BOTTOM w0.112: R141.1 173.63,24.42 173.4,24.42 v2(173.23,24.26) 173.09,24.4 172.79,24.4 172.74,24.34 U69.11
USB20_N3_R: length 1.1
  BOTTOM w0.112: R141.2 175.06,24.44 175.39,24.44 R142.1
USB20_P3: length 108.1
  IN2 w0.102: 136.91,96.08 136.89,96.08 136.87,96.06 136.6,96.06 136.34,95.81 135.64,95.81 134.11,94.27 128.8,94.27 128.73,94.35 127.95,94.35 127.79,94.5 127.6,94.5 v2(127.34,94.76)
  IN2 w0.127: 136.91,96.08 146.92,96.08 151.4,91.6 151.4,84.34 151.26,84.21 151.26,81.36 150.82,80.91 150.82,76.8 152.75,74.87 152.75,68.08 158.19,62.65 158.19,61.88 162.05,58.01 162.05,57.77 166.13,53.69 166.13,51.03 165.73,50.62 165.73,49.59 174.58,40.74 174.58,28.53 172.65,26.6 172.65,24.89 172.84,24.7 173.05,24.7 v2(173.23,24.88)
  BOTTOM w0.102: v2(127.34,94.76) 126.98,95.12 UC1.AN3
  BOTTOM w0.112: U69.10 172.74,24.84 172.85,24.73 173.08,24.73 v2(173.23,24.88) 173.36,24.75 173.54,24.75 R140.1
USB20_P3_R: length 1.1
  BOTTOM w0.112: R143.1 175.35,24.77 175.11,24.77 R140.2
USB20_TOUCH_N5: length 98.1
  IN2 w0.127: v2(101.14,160.41) 101.28,160.28 101.28,159.28 99.61,157.61 99.61,154.05 104.62,149.05 104.62,145.93 107.87,142.67 107.87,117.6 110.12,115.35 124.25,115.35 129.96,109.64 129.96,107.35 v2(129.69,107.09)
  BOTTOM w0.102: UC1.AL1 125.3,96.72 125.13,96.55 125.13,96.45 125.25,96.33 125.42,96.33 125.8,96.71 125.8,97.87 126.32,98.39 126.32,98.41 126.34,98.43
  BOTTOM w0.127: JEDP.34 97.3,165.28 97.39,165.18 97.39,164.87 99.47,162.79 100.55,162.79 101.12,162.22 101.12,162 100.77,161.65 DX2.3 101.24,160.85 101.24,160.5 v2(101.14,160.41) ; v2(129.69,107.09) 129.96,106.82 129.96,106.65 128.53,105.22 128.53,102.28 128.82,101.99 128.82,99.66 127.84,98.68 126.59,98.68 126.34,98.43
USB20_TOUCH_P5: length 98.1
  IN2 w0.127: v2(130.28,107.09) 130.28,109.77 124.38,115.67 110.25,115.67 108.19,117.73 108.19,142.8 104.93,146.06 104.93,149.18 99.93,154.18 99.93,157.48 101.59,159.14 101.59,160.28 v2(101.73,160.41)
  BOTTOM w0.102: UC1.AL2 125.37,95.95 126.09,96.67 126.09,97.75 126.53,98.19 126.55,98.19 126.56,98.21
  BOTTOM w0.127: v2(101.73,160.41) 101.56,160.58 101.56,160.83 DX2.2 101.62,161.65 101.44,161.82 101.44,162.35 100.68,163.11 99.6,163.11 97.71,165 97.71,165.18 97.8,165.28 JEDP.35 ; 126.56,98.21 126.72,98.36 127.97,98.36 129.14,99.53 129.14,102.12 128.85,102.42 v3(128.85,103.63) 128.85,105.09 130.28,106.52 v2(130.28,107.09)
USB_EN#: length 279.7
  TOP w0.127: v2(194.66,45.77) 192.67,45.77 v1(188.75,49.68) 187.66,50.77 172.91,50.77 172.45,51.23 170.85,51.23 170.75,51.33 168.14,51.33 166.54,49.73 v2(166.54,49.4) ; UE1.84 179.42,70.36 179.89,69.89 179.89,68.95 v2(180.5,68.34)
  IN1 w0.127: v2(25.36,36.35) 25.36,33.31 28.63,30.04 28.63,25.25 31.83,22.05 31.83,20.31 33.31,18.83 34.98,18.83 35.32,18.49 55.66,18.49 60.42,13.73 96.31,13.73 98.59,11.44 155.33,11.44 159.15,15.27 159.15,23 161.18,25.03 161.18,32.18 164.28,35.28 164.28,45.92 166.54,48.18 v2(166.54,49.4) ; v2(194.79,69.59) 195.46,68.92 195.46,57.96 194.63,57.14 194.63,47.96 194.66,47.93 v2(194.66,45.77)
  IN2 w0.127: v2(180.5,68.34) 181.26,67.58 188.56,67.58 190.5,69.52 192.08,69.52 193.29,70.73 194.61,70.73 194.84,70.5 194.84,69.64 v2(194.79,69.59)
  BOTTOM w0.127: UI7.4 198.95,40.59 CI46.1 198.95,43.64 196.82,45.77 v2(194.66,45.77) ; v2(25.36,36.35) 25.08,36.63 22.51,36.63 CI13.1 21.89,36 UI5.4 ; v2(180.5,68.34) 180.57,68.26 RE504.1
USB_OC0#: length 172
  TOP w0.102: 124.07,95.49 124.07,96.71 125.66,98.3 125.66,101.23 126.22,101.79 126.22,105.03 R905.2 ; 124.07,95.49 124.07,93.1 123.76,92.79 123.58,92.79 123.42,92.63 123.42,91.9 123.71,91.61 123.71,90.12 v2(123.58,89.99) ; 124.07,95.49 122.56,95.49 121.24,96.81 120.27,96.81 118.97,98.11 116.4,98.11 116.02,98.49 116.02,99.47 115.51,99.97 114.67,99.97 112.46,102.18 109.47,102.18 v2(107.76,103.9) ; v2(59.04,58.22) 58.73,57.91 50.36,57.91 49.61,57.16 46.85,57.16 45.6,58.42 33.55,58.42 v1(32.86,57.72) 26.71,51.58 26.71,49.03 25.79,48.1 25.79,40.73 21.74,36.68 v2(20.05,36.68)
  IN1 w0.102: v2(98.25,101.33) 98.24,101.35 93.49,101.35 92.84,100.7 92.25,100.7 88.61,97.06 88.61,96.46 70.25,78.1 65.53,78.1 63.44,76.02 63.44,69.86 62.29,68.7 62.29,67.92 59.04,64.67 v2(59.04,58.22)
  IN2 w0.102: v2(98.25,101.33) 100.82,103.9 v2(107.76,103.9)
  BOTTOM w0.102: CI15.1 17.34,36 UI5.3 19.37,36 v2(20.05,36.68) ; v2(123.58,89.99) 123.25,90.32 UC1.AH9
USB_OC1#: length 141.3
  IN2 w0.102: v2(172.48,34.75) 170.54,36.7 170.54,38.75 163.73,45.57 163.73,53.77 161.17,56.32 151.75,56.32 149.07,59.01 149.07,64.21 150.8,65.95 150.8,72.97 146.36,77.42 146.36,78.78 147.92,80.34 147.92,83.56 149.74,85.37 149.74,87.48 149.15,88.06 149.15,89.71 148.11,90.75 146.85,90.75 145.63,91.98 140.63,91.98 138.8,90.15 137.03,90.15 136.88,90.3 136.29,90.3 135.93,89.94 134.97,89.94 134.55,89.52 132.94,89.52 132.5,89.97 130.17,89.97 130.01,89.8 127.83,89.8 126.38,91.25 125.42,91.25 124.99,90.82 124.68,90.82 124.41,91.08 124.41,93.56 123.87,94.1 123.87,95.26 122.74,96.39 122.48,96.39 122.05,96.82 v2(122.05,97.19)
  BOTTOM w0.102: v2(172.48,34.75) 172.92,35.19 176.61,35.19 181.58,40.16 v1(181.58,40.42) 181.84,40.42 185.3,43.88 195.19,43.88 196.26,42.81 CI47.1 196.91,41.14 196.91,40.51 196.84,40.45 UI7.3 ; UC1.AG1 122.05,96.83 v2(122.05,97.19)
USB_ZVSS: length 14.2
  TOP w0.102: v2(128.23,93.12) 128.08,92.96 126.99,92.96 126.63,93.33 126.63,94.11 126.87,94.35 126.87,96.52 127.46,97.11 127.46,98.43
  TOP w0.203: 127.46,98.43 v1(126.95,98.94) 126.51,99.38 126.51,100.76 126.94,101.19 127.49,101.19 R641.1
  BOTTOM w0.102: v2(128.23,93.12) 127.83,93.52 UC1.AP5
USBSS_ZVDD: length 4
  BOTTOM w0.102: 119.39,98.43 119.39,98.4 119.08,98.09 119.08,97.75 119.7,97.14 119.7,96.71 119.77,96.64 UC1.AD1
  BOTTOM w0.203: R645.1 v1(119.39,99.03) 119.39,98.43
USBSS_ZVSS: length 8.1
  BOTTOM w0.102: 119.86,98.43 119.54,98.11 119.54,97.6 119.9,97.24 119.9,96.79 120.07,96.62 120.07,95.82 UC1.AD2 ; R644.1 120.63,100.88 v1(122,102.25)
  BOTTOM w0.203: R644.1 119.9,100.11 119.9,98.47 119.86,98.43
VCIN0_PH: length 118.2
  TOP w0.127: v2(148.13,50.83) 148.13,50.86 143.95,55.03 143.95,63.23 143.71,63.47 v2(143.71,64.78) ; UE1.109 183.95,62.76 v2(183.41,62.22) 184.21,61.42 PR24.1
  TOP w0.254: v2(107.5,78.51) 106.9,79.11 105.63,79.11 PH1.1
  IN2 w0.254: v2(136.7,75.52) 136,76.22 135.1,76.22 134.86,75.98 132.67,75.98 132.36,75.66 129.12,75.66 128.93,75.85 126.65,75.85 125.35,77.15 121.27,77.15 120.89,76.77 116.33,76.77 115.64,77.46 115.64,78.22 115.39,78.47 112.53,78.47 112.15,78.85 107.84,78.85 v2(107.5,78.51)
  BOTTOM w0.127: v2(148.13,50.83) 151.33,54.03 156.07,54.03 v1(159.63,57.59) 160.75,58.72 160.75,65.29 161.81,66.34 162.96,66.34 163.46,65.85 163.46,65.21 163.77,64.9 169.14,64.9 170.07,63.97 172,63.97 172.87,64.83 174.15,64.83 174.91,64.07 180.43,64.07 182.29,62.22 v2(183.41,62.22) ; v2(136.7,75.52) 136.72,75.5 138.63,75.5 139.27,74.85 139.27,73.99 138.79,73.51 138.79,68.47 142.49,64.78 v2(143.71,64.78)
VCIN1_BATT_DROP: length 2.9
  TOP w0.127: PR36.2 179.15,81.69 v1(179.15,81.18) UE1.64
VCIN1_PH: length 16
  TOP w0.203: UE1.102 181.15,65.29 v2(180.78,65.66)
  IN2 w0.254: v2(180.78,65.66) 181.29,65.15 182.9,65.15 183.83,66.08 187.78,66.08 187.97,65.89 v2(187.98,65.89)
  BOTTOM w0.127: v2(180.78,65.66) 180.9,65.66 v1(181.29,65.28)
  BOTTOM w0.254: PR26.2 PR27.2 181.67,66.5 PR23.1 ; PR26.2 v2(180.78,65.66) 180.71,65.6 RE30.2 ; PR26.2 PC13.2 ; PR38.2 188.01,65.92 v2(187.98,65.89)
VCOUT0: length 3.6
  TOP w0.127: UE1.104 181.95,62.54 182.15,62.33 v1(182.84,62.33) 182.84,61.77 RE39.2
VCOUT0_PH#: length 245.3
  TOP w0.127: v2(162.42,59.54) 162.86,59.11 170.62,59.11 171.15,59.64 v1(171.9,59.64) 172.28,59.64 172.61,59.31 182.25,59.31 RE39.1 ; R2450.2 150.6,31.62 151.2,31.62 153.94,34.37 153.94,37.82 155.2,39.08 v2(159.25,39.08)
  TOP w0.254: v2(48.13,54.25) PC100.1 48.11,53.39 PR102.2 48.1,52.31 PR110.1 47.16,52.32 PR101.2 ; PR100.2 v2(37.01,53.34)
  IN1 w0.127: v2(162.42,59.54) 161.73,58.85 161.73,54.06 159.4,51.74 159.4,39.23 v2(159.25,39.08) 159.25,35.56 158.11,34.42 158.11,15.75 156.11,13.75 126.92,13.75 125.77,12.61 101.54,12.61 98.41,15.75 86.84,15.75 85.91,14.82 62.01,14.82 60.89,15.94 60.89,18.54 57.26,22.17 55.27,22.17 51.73,25.71 51.73,45.03 50.95,45.82 50.95,52.01 48.7,54.25 v2(48.13,54.25)
  IN2 w0.254: v2(48.13,54.25) 46.48,55.91 44.22,55.91 42.56,54.24 39.2,54.24 38.3,53.34 v2(37.01,53.34)
VCOUT1_PH: length 216.4
  TOP w0.102: v2(181.82,65.85) 181.55,65.58 UE1.103
  TOP w0.254: PR30.1 148.35,167.26 v2(148.34,167.27)
  IN1 w0.102: v2(148.34,167.27) 148.44,167.27 151.52,170.35 v2(151.52,175.89)
  IN2 w0.102: v2(181.82,65.85) 181.63,66.04 177.83,66.04 177.3,66.57 177.3,69.85 172.28,74.87 172.28,75.57 170.44,77.41 170.44,83.43 170.11,83.76 168.14,85.72 168.14,86.7 v2(167.74,87.1) 167.74,88.71 165.06,91.39 165.06,96.65 164.6,97.11 164.6,98.47 163.91,99.16 163.91,112.19 170.78,119.06 181.15,119.06 190.05,127.96 190.05,134.4 190.53,134.88 190.53,136.4 191.32,137.19 191.32,138.46 191.97,139.1 191.97,139.69 196.35,144.07 196.35,151.53 195.42,152.45 195.15,152.45 195.15,152.45 191.8,152.45 191.3,152.96 191.3,154.32 190.81,154.81 190.81,172.15 187.38,175.58 151.83,175.58 v2(151.52,175.89)
  BOTTOM w0.102: v2(167.74,87.1) 167.95,86.89 168.91,86.89 169.06,87.05 171.6,87.05 172.16,86.49 174.43,86.49 174.76,86.16 RE65.2 175.65,85.6 R1690.1 177.79,84.71 178.17,84.33 UE3.2 178.17,79.82 177.98,79.63 176.02,79.63 175.77,79.87 Q89.2 ; RE67.2 183.44,65.57 183.17,65.29 v1(182.92,65.29) 182.38,65.29 v2(181.82,65.85)
VGA_AC__BATT: length 18.9
  TOP w0.102: UV4.4 179.33,131.48 v2(179.51,131.29) 179.51,130.67 181.21,128.97 181.87,128.97 182.38,129.48 QV8.3 183.2,129.48 183.38,129.3 183.38,128.62 RV92.1
  TOP w0.127: RV92.1 184.08,127.52 RV148.2 183.05,126.48 v1(182.53,126.48)
  IN1 w0.102: 178.71,132.04 178.17,132.58 178.17,132.88 177.95,133.11 177.31,133.11 176.99,132.79 173.56,132.79 173.08,133.28 v2(172.94,133.28)
  IN1 w0.107: 178.71,132.04 179.46,131.29 v2(179.51,131.29)
  BOTTOM w0.102: UV1.T9 172.49,133.73 v2(172.94,133.28)
VGA_DMINUS: length 4.8
  BOTTOM w0.254: UV1.T2 178.23,133.56 178.35,133.44 179.18,133.44 CV9.2 179.95,132.67 UV11.3
VGA_DPLUS: length 6.1
  BOTTOM w0.254: UV11.2 179.92,132.02 CV9.1 179.04,131.9 v1(178.67,132.27) 178.22,132.72 178.22,132.88 177.93,133.17 176.48,133.17 UV1.T4
VGA_SMB_CK3: length 22
  TOP w0.102: v2(185.48,128.41) 184.93,127.86 RV166.2 ; QV1.1 177.81,131.32 177.69,131.2 175.88,131.2 RV6.2 174.72,132.36 v2(174.59,132.36)
  IN1 w0.102: v2(174.59,132.36) 176.86,132.36 179.07,130.15 183.15,130.15 183.47,129.84
  IN1 w0.107: 183.47,129.84 184.3,129.01 184.88,129.01 v2(185.48,128.41)
  BOTTOM w0.102: v2(185.48,128.41) RV164.2 184.75,129.14 185.43,129.81 v1(185.95,129.81) ; UV1.U7 174.39,132.56 v2(174.59,132.36)
VGA_SMB_CK3_R: length 2.7
  BOTTOM w0.102: RV164.1 184.31,130.49 184.31,131.16 184.52,131.37 UV11.8
VGA_SMB_DA3: length 20.5
  TOP w0.102: QV1.4 176.51,130.86 176.41,130.95 175.72,130.95 175.5,130.74 RV5.2 v1(174.51,131.7) 174.21,132.01 v2(174.09,132.01) ; RV167.2 184.08,126.61 184.56,127.09 184.56,128.08 v2(184.87,128.38)
  IN1 w0.102: v2(184.87,128.38) 184.61,128.64 184.19,128.64 183.01,129.82 178.93,129.82 177.1,131.65 174.39,131.65 174.09,131.95 v2(174.09,132.01)
  BOTTOM w0.102: UV1.U8 173.84,132.01 v2(174.09,132.01) ; v2(184.87,128.38) 184.61,128.64 184.32,128.64 RV165.2
VGA_SMB_DA3_R: length 3.5
  BOTTOM w0.102: UV11.7 184.38,132.02 183.84,131.47 RV165.1
VL: length 5.6
  TOP w0.102: PC106.1 42.39,47.67 42.74,48.02 v1(45.22,48.02)
  TOP w0.203: PU100.13 41.92,47.74 PC106.1
VR_ON: length 364.9
  TOP w0.102: UE1.121 v2(188.75,65.21) 188.99,65.46 189.96,65.46 190.2,65.21 191.66,65.21 194.57,62.31 v2(197.28,62.31)
  TOP w0.254: v2(117.25,160.78) 117.31,160.78 117.37,160.72 PR1085.1 ; v2(57.79,26.68) 59.27,28.16 59.27,29.2 59.26,29.21 59.26,30.07 PR532.1
  IN1 w0.102: v2(177.92,35.31) 176.94,34.32 176.94,20.93 175.85,19.84 171.31,19.84 164.14,12.66 164.14,11.25 v2(162.79,9.91)
  IN2 w0.102: v2(193.86,43.12) 193.86,57.2 197.28,60.62 v2(197.28,62.31) ; v2(57.79,26.68) 57.6,26.68 53.17,22.25 53.17,17.31 56.67,13.8 78.76,13.8 79.58,14.63 91.57,14.63 96.39,9.8 158.58,9.8 159.15,10.38 162.32,10.38 v2(162.79,9.91) ; v2(188.75,65.21) 187.8,64.26 178.26,64.26 175.79,66.72 175.79,67.46 172.93,70.32 172.2,70.32 167.6,74.92 167.6,81.87 164.6,84.87 164.6,88.78 162.52,90.87 162.52,94.27 162.29,94.5 162.29,97.68 158.1,101.86 158.1,105.1 153.03,110.17 147.77,110.17 147.1,110.84 147.1,113.58 146.12,114.56 146.12,128.16 149.6,131.64 149.6,133.9 149.42,134.08 149.42,137.59 148.9,138.11 148.9,138.11 147.94,139.08 147.94,142.51 141.9,148.54 141.9,149.43 139.97,151.37 134.44,151.37 127.93,157.87 123.02,157.87 120.47,160.43 120.47,161.28 120.1,161.65 118.52,161.65 117.66,160.78 v2(117.25,160.78)
  BOTTOM w0.102: v2(193.86,43.12) 193.48,43.5 185.81,43.5 v1(183.69,41.38) 183.26,41.38 177.92,36.03 v2(177.92,35.31)
VRAM_ODT0: length 54.5
  TOP w0.102: v2(165.26,138.37) 164.46,139.17 163.94,139.17 163.63,139.48 163.63,142.17 164.25,142.79 164.25,146.75 ; UV6.K1 161.71,163.5 161.1,163.5 160.77,163.17 160.77,163.06 160.51,162.79 160.11,162.79 159.7,162.39 158.79,162.39 v2(158.2,162.98)
  TOP w0.234: v2(170,161.02) 170,154.29 v1(165.52,149.81) 164.25,148.54 164.25,146.75
  IN2 w0.102: 162.21,161.94 161.76,162.39 158.33,162.39 158.2,162.52 v2(158.2,162.98)
  IN2 w0.127: v2(170,161.02) 170,161.14 169.87,161.26 169,161.26 168.87,161.14 168.87,160.58 168.75,160.45 168.49,160.45 168.36,160.58 168.36,161.12 168.24,161.24 167.98,161.24 167.86,161.12 167.86,160.58 167.73,160.45 167.48,160.45 167.35,160.58 167.35,160.88 167.22,161.01 166.97,161.01 166.84,160.88 166.84,160.58 166.71,160.45 166.46,160.45 166.33,160.58 166.33,160.88 166.21,161.01 165.95,161.01 165.82,160.88 165.82,160.58 165.7,160.45 165.44,160.45 165.32,160.58 165.32,160.88 165.19,161.01 164.94,161.01 164.81,160.88 164.81,160.58 164.68,160.45 164.43,160.45 164.3,160.58 164.3,160.88 164.17,161.01 163.73,161.01 162.81,161.94 162.21,161.94
  BOTTOM w0.089: UV1.L18 165.26,137.73 v2(165.26,138.37)
  BOTTOM w0.102: UV5.K1 155.38,162.92 155.16,162.92 155.02,163.06 155.02,163.52 155.15,163.65 157.25,163.65 157.92,162.98 v2(158.2,162.98)
VRAM_ODT1: length 55
  TOP w0.102: 166.81,146.75 166.81,146 166.45,145.65 v2(166.45,139.08) ; v2(182.68,162.98) 183.28,162.39 184.19,162.39 184.59,162.79 185,162.79 185.26,163.06 185.26,163.17 185.58,163.5 186.19,163.5 UV7.K1
  TOP w0.234: v2(172.56,161.73) v1(172.56,154.56) 172.56,153.23 166.81,147.48 166.81,146.75
  IN2 w0.102: 179.71,162.09 180.13,162.51 180.13,162.93 180.56,163.36 181.53,163.36 181.65,163.23 181.65,162.95 181.78,162.83 182.56,162.83 182.68,162.95 v2(182.68,162.98)
  IN2 w0.127: v2(172.56,161.73) 172.56,162.11 172.68,162.24 173.14,162.24 173.27,162.1 173.27,160.99 173.4,160.86 173.69,160.86 173.82,160.99 173.82,161.67 173.94,161.8 174.2,161.8 174.33,161.67 174.33,160.99 174.45,160.86 174.71,160.86 174.83,160.99 174.83,161.67 174.96,161.8 175.21,161.8 175.34,161.67 175.34,160.99 175.47,160.86 175.72,160.86 175.85,160.99 175.85,161.67 175.98,161.8 176.23,161.8 176.36,161.67 176.36,160.99 176.48,160.86 176.76,160.86 176.89,160.99 176.89,161.24 177.02,161.37 177.6,161.37 177.72,161.25 177.72,161 177.86,160.86 178.12,160.86 178.29,161.03 178.29,161.66 178.43,161.8 179.06,161.8 179.35,162.09 179.71,162.09
  BOTTOM w0.089: UV1.K16 167.09,138.48 166.49,139.08 v2(166.45,139.08)
  BOTTOM w0.102: UV8.K1 179.86,162.92 179.65,162.92 179.51,163.06 179.51,163.52 179.63,163.65 181.74,163.65 182.41,162.98 v2(182.68,162.98)
VSUM+_APU: length 17.5
  TOP w0.203: PC1053.1 114.53,159.15 114.53,155.56 114.77,155.31 PU1001.14
  TOP w0.254: PC1066.1 PR1079.1 111.82,158.31 111.82,159.26 v2(111.88,159.32) PR1071.1 113.34,159.32 PC1053.1
  BOTTOM w0.254: PR1084.1 109.15,154.94 110.67,156.46 110.67,158.11 v1(111.05,158.5) v2(111.88,159.32)
VSUM+_GFX: length 14.5
  TOP w0.203: PU500.14 62.64,34.62 62.7,34.56 PR524.1 PC516.1
  TOP w0.254: PR517.1 65.65,38.23 v1(65.65,36.39) 65.65,35.05 65.16,34.56 PC516.1 v2(64.7,35.31)
  IN1 w0.254: v2(65.21,31.47) 65.21,31.74 64.19,32.75 64.19,33.53 64.7,34.04 v2(64.7,35.31)
  BOTTOM w0.254: v2(65.21,31.47) 64.95,31.22 PC517.1 PR523.1
VSUM+_VGA: length 11.7
  TOP w0.127: v1(169.56,101.08) 168.99,100.51 v2(168.66,100.51)
  TOP w0.254: PR1126.1 166.43,100.7 v2(166.29,100.84)
  IN1 w0.254: v2(166.29,100.84) 168.33,100.84 v2(168.66,100.51)
  BOTTOM w0.203: PR1131.1 169.35,98.66 PC1126.1 169.42,98.59 PC1125.1 169.43,97.58 PR1132.1 169.43,95.75 169.74,95.44 PU1100.14
  BOTTOM w0.254: PR1131.1 169.35,99.82 v2(168.66,100.51) ; PR1126.1 166.43,100.7 v2(166.29,100.84)
VSUM-_APU: length 45.1
  TOP w0.254: PC1065.1 109.05,156.43 v2(109.09,156.47) 109.54,156.47 109.72,156.3 110.72,156.3 PC1066.2 110.8,156.4 PR1072.1 111.88,157.48 PR1066.1 112.77,157.63 PR1071.2 113.82,158.41 PC1053.2
  IN1 w0.254: v2(112.38,130.76) 112.5,130.89 112.5,132.95 104.95,140.51 104.95,149.4 109.4,153.86 109.4,156.15 v2(109.09,156.47)
  BOTTOM w0.254: v2(109.09,156.47) v1(109.09,155.87) 109.09,155.51 108.01,154.43 PR1068.1 ; v2(112.38,130.76) 112.45,130.84 112.45,134.18 112.36,134.27 112,134.27 111.79,134.06 PH1003.2
VSUM-_GFX: length 45.8
  TOP w0.254: PR524.2 PC516.2 ; PC516.2 v2(64.7,32.96) ; PC516.2 65.2,33.64 66.1,34.54 66.1,37.77 PR518.1 66.74,38.42 PC519.1
  BOTTOM w0.203: PR526.1 64.66,33.71 PR528.1
  BOTTOM w0.254: PH502.2 74.49,56.71 75.05,56.71 76.26,55.5 76.26,38.66 74.88,37.29 69.22,37.29 68.07,36.13 68.07,33.9 v1(66.36,32.19) PC517.2 64.95,32.7 v2(64.7,32.96) 64.67,32.98 PR528.1
VSUM-_VGA: length 37.2
  TOP w0.127: v2(165.96,99.44) 165.96,99.4 165.47,98.92 v1(165.47,98.67)
  TOP w0.254: v2(167.27,98.2) 167.76,98.69 PR1137.1 PR1136.1 ; PC1129.1 169.22,95.31 v2(168.52,96.01) ; PR1128.1 165.28,100.11 v2(165.96,99.44)
  IN2 w0.254: v2(178.8,113.33) 179,113.13 179,111.12 177.09,109.22 173.79,109.22 168.71,104.14 168.71,102.36 167.19,100.84 167.19,98.27 v2(167.27,98.2)
  BOTTOM w0.254: v2(168.52,96.01) PR1132.2 168.52,97.58 PC1125.2 ; PR1128.1 165.28,100.11 v2(165.96,99.44) 167.2,98.2 v2(167.27,98.2) 167.72,98.66 PC1126.2 168.35,98.66 168.51,98.5 PC1125.2 ; PC1125.2 168.49,97.58 PC1120.1 167.62,97.58 PC1119.1 ; PH1102.2 v2(178.8,113.33)
VSUMN_NB: length 42.8
  TOP w0.127: v2(130.36,135.57) v1(129.69,135.57)
  IN1 w0.254: v2(122.3,160.92) 123.33,160.92 124.2,160.05 124.2,156.11 130.3,150.01 130.3,148.06 133.71,144.64 133.71,137.08 132.07,135.45 130.49,135.45 v2(130.36,135.57)
  BOTTOM w0.254: PC1012.2 124.42,158.69 124.43,158.69 ; 124.43,158.69 124.43,159.58 PC1014.1 123.5,159.79 123.43,159.72 PR1011.2 123.07,160.54 PC1011.2 122.87,160.92 v2(122.3,160.92) ; 124.43,158.69 PR1015.1 ; PR1013.1 124.42,157.62 PR1015.1 ; v2(130.36,135.57) 130.3,135.51 129.8,135.51 PH1000.2 ; PR1014.1 PR1015.1
VSUMP_NB: length 10.7
  BOTTOM w0.254: PR1012.1 v1(122.51,155.64) 121.96,155.64 121.44,156.15 121.44,157.1 v2(121.86,157.52) 121.98,157.64 121.98,158.47 PC1012.1 122.21,159.68 PR1011.1 121.79,160.1 121.79,161.16 122.16,161.54 PC1011.1 123.16,162.4 PR1009.1
VSYNC: length 5.8
  TOP w0.127: v1(37.28,76.75) 36.71,76.17 36.71,74.69 RZ49.1 36,73.69 35.72,73.4 35.72,73.22 35.84,73.09 36.14,73.09 36.27,72.96 UZ1.7
VTTREF_1.35V: length 1.8
  TOP w0.203: PC210.1 60.06,24.19 60.2,24.06 PU200.4
WAKEB: length 3.7
  TOP w0.102: RV162.2 160.92,123.2 RV163.1 159.43,123.2 v2(159.4,123.17) v1(158.77,123.17)
  BOTTOM w0.102: UV1.AJ27 159.01,123.56 v2(159.4,123.17)
WL_OFF#: length 97.7
  TOP w0.102: QM1.3 172.03,43.19 171.76,42.93 171.76,42.29 170.87,41.4 170.86,41.4 170.47,41.01 v1(168.99,41.01) v2(167.75,41.01) ; RH42.2 147.85,89.42 148.2,89.42 v2(148.5,89.73)
  IN2 w0.102: v2(129.7,89.28) 129.78,89.28 130.26,89.76 132.42,89.76 132.86,89.32 134.64,89.32 134.85,89.53 136.62,89.53 137.03,89.95 139.82,89.95 141.52,91.65 145.49,91.65 146.86,90.28 148.06,90.28 148.5,89.85 v2(148.5,89.73) 148.82,89.4 148.82,87.92 149.41,87.34 149.41,85.51 147.59,83.7 147.59,80.48 146.03,78.91 146.03,77.28 150.47,72.84 150.47,66.08 148.74,64.35 148.74,58.87 151.61,55.99 161.04,55.99 163.4,53.63 163.4,44.79 167.18,41.01 v2(167.75,41.01)
  BOTTOM w0.102: UC1.AT12 129.47,87.82 129.82,88.17 129.82,89.16 v2(129.7,89.28)
WL_OFF#_R: length 9.7
  TOP w0.102: v2(172.52,49.27) 171.63,48.39 RM8.2 171.33,45.28 v1(171.96,44.64) 171.96,44.32 170.94,43.3 QM1.1
  BOTTOM w0.102: JNGFF.48 v2(172.52,49.27)
WLAN_CLKREQ#: length 54.8
  IN2 w0.102: v2(139.24,81.05) 139.58,81.05 140.46,80.17 140.46,67.49 145.08,62.86 145.08,57.04 146.28,55.84 148.28,55.84 152.12,52 v2(161.03,52)
  BOTTOM w0.102: v2(161.03,52) v1(161.03,51.18) 161.03,50.67 161.68,50.03 JNGFF.45 ; v2(139.24,81.05) 139.24,81.04 137.48,81.04 135.4,83.12 135.29,83.12 134.59,83.82 UC1.BB17
WLAN_WAKE#: length 38.7
  TOP w0.127: v2(178.87,68.06) 178.77,67.96 UE1.90
  IN1 w0.127: v2(161.66,49.52) 163.01,50.88 163.01,63.88 163.89,64.76 v2(163.89,66.97)
  BOTTOM w0.127: JNGFF.47 v2(161.66,49.52) ; v2(178.87,68.06) 179,67.93 RE70.2 177.37,67.39 176.26,66.27 175.7,66.27 175.23,66.74 171.66,66.74 v1(171.46,66.94) 171.13,67.27 169.23,67.27 168.51,66.55 166.78,66.55 166.48,66.85 164,66.85 v2(163.89,66.97)
WOL_EN: length 222.6
  TOP w0.127: v1(34.38,176.35) 34.91,175.83 UL3.4 35.93,175.83 36.11,176.01 36.11,176.82 RL27.2 RL38.1 38.25,177.09 v2(39.63,175.7) ; v2(184.5,74.29) 184.32,74.12 184.32,70.08 179.55,65.31 UE1.98
  IN1 w0.127: v2(94.16,148.67) 94.46,148.37 94.46,143.62 111.6,126.48 128.36,126.48 134.05,120.79 143.97,120.79 150.18,114.58 157.44,114.58 164.12,107.91 164.12,99.26 165.42,97.95 165.42,90.98 168.64,87.76 168.64,86.99 170.74,84.89 173.63,84.89 177.05,81.47 177.05,81.13 177.96,80.22 179.45,80.22 181.9,77.77 181.9,76.38 183.12,75.16 183.64,75.16 v2(184.5,74.29)
  IN2 w0.127: v2(94.16,148.67) 94.01,148.82 91.48,148.82 90.49,149.81 85.74,149.81 81.59,153.96 81.59,155.41 80.28,156.72 80.28,158.72 79.39,159.6 75.88,159.6 68.31,167.17 61.77,167.17 52.15,176.79 40.72,176.79 v2(39.63,175.7)
XTALIN: length 9.7
  BOTTOM w0.102: UV1.AM28 157.29,122.68 157.67,123.05 158.21,123.05 158.38,122.88 158.38,122.17 158.78,121.77 159.68,121.77 v1(160.53,120.92) 160.67,120.78 161.7,120.78 CV17.1 162.42,119.21 RV20.1 162.34,118.54 YV1.1
XTALIN_2168: length 2.7
  TOP w0.127: T4933.1 33.71,66.29 35.53,66.29 35.77,66.54 UZ1.17
XTALOUT: length 12.6
  BOTTOM w0.102: UV1.AK28 157.4,123.27 158.27,123.27 158.57,122.96 158.57,122.26 158.88,121.96 160.1,121.96 160.99,121.07 162.71,121.07 v1(162.78,120.99) 162.78,120.99 163.26,120.51 CV18.1 163.26,119.14 RV20.2 162.76,118.64 162.76,117.31 YV1.3
XTALOUT_2168: length 3.9
  TOP w0.127: UZ1.18 36.27,66.31 35.76,65.8 34.6,65.8 34.09,65.29 T4934.1
XTLI: length 4.3
  TOP w0.127: UL1.29 47.74,171.44 47.77,171.48 v1(47.77,171.77) CL36.1 47.77,173.64 YL2.1
XTLO: length 6.4
  TOP w0.127: UL1.28 48.14,171.68 48.63,172.17 CL37.1 48.63,173.27 48.38,173.52 48.38,175.08 YL2.3
N71037: length 2.6
  BOTTOM w0.099: UA1.8 179.96,13.38 179.85,13.49 179.23,13.49 178.61,14.11 RA130.2
N71249: length 3.3
  BOTTOM w0.203: CA62.2 188.11,14.66 187.66,14.66 187.18,14.18 UA1.27
  BOTTOM w0.254: RA12.2 188.52,15.41 188.51,15.39 CA62.2
N71261: length 6.3
  BOTTOM w0.127: v1(188.66,5.61) 188.66,5.99 187.72,6.94 CA63.2
  BOTTOM w0.203: 186.84,8.6 186.19,8.6 186.01,8.77 185.57,8.77 185.02,9.32 UA1.39
  BOTTOM w0.254: 186.84,8.6 187.72,7.72 CA63.2
N71273: length 2.3
  BOTTOM w0.203: CA64.2 178.95,13.03 179.09,13.17 v1(179.46,13.17) 179.75,13.17 179.94,12.98 UA1.7
N71383: length 3.7
  BOTTOM w0.203: CA24.1 188.08,8.76 v1(187.73,9.11) 186.73,10.11 185.91,10.11 185.82,10.02 UA1.37
N71395: length 2.5
  BOTTOM w0.203: UA1.35 187.12,10.98 187.61,10.49 v1(187.75,10.49) 187.89,10.49 188.63,9.75 CA24.2
N71399: length 5.1
  TOP w0.127: v1(185.81,14) CA25.2
  TOP w0.254: CA25.2 185.81,11.73 186.3,11.24 v2(187.54,11.24)
  BOTTOM w0.203: v2(187.54,11.24) 187.41,11.38 UA1.34
N71447: length 2.1
  BOTTOM w0.203: UA1.28 187.21,13.78 187.55,14.11 188.26,14.11 CA23.2
N71539: length 4.8
  BOTTOM w0.127: CA69.1 176.42,16.48 175.34,15.41 v1(174.9,15.41)
  BOTTOM w0.254: CA65.2 RA79.1 RA81.2 CA69.1
N71593: length 2.8
  BOTTOM w0.099: UA1.12 180.15,14.98 v1(179.32,15.81) 178.65,16.48 CA65.1
N76526: length 2.8
  BOTTOM w0.102: RA1113.2 179.18,11.68 180.04,11.68 180.13,11.78 UA1.4
N16741803: length 5.3
  TOP w0.102: v1(159.3,125.18) 159.3,125.2 160.07,125.97 v2(160.13,125.97) 160.02,126.07 RV29.2
  BOTTOM w0.102: UV1.AC22 161.93,127.6 161.93,127.37 161.25,126.69 160.96,126.69 160.81,126.54 160.81,126.17 160.61,125.97 v2(160.13,125.97)
N16751834: length 1.2
  TOP w0.102: T203.1 172.47,126.36 v2(172.88,125.95)
  BOTTOM w0.102: v2(172.88,125.95) 172.49,126.34 UV1.AE9
N16751842: length 1.4
  TOP w0.102: v2(172.88,128.5) 172.18,128.5 T211.1
  BOTTOM w0.102: UV1.AB9 172.49,128.89 v2(172.88,128.5)
N16751844: length 1.2
  TOP w0.102: v2(172.08,127.56) 172.37,127.27 T207.1
  BOTTOM w0.102: v2(172.08,127.56) 171.69,127.96 UV1.AC10
N16751854: length 1.2
  TOP w0.102: v2(174.47,127.53) 174.65,127.7 T210.1
  BOTTOM w0.102: UV1.AC7 174.09,127.91 v2(174.47,127.53)
N16751856: length 1.3
  TOP w0.102: T204.1 170.42,130.39 v2(170.38,130.36)
  BOTTOM w0.089: UV1.Y11 170.78,130.76 v2(170.38,130.36)
N16754176: length 1.8
  TOP w0.102: v2(173.66,128.48) 174.13,128.94 T212.1
  BOTTOM w0.102: v2(173.66,128.48) 173.29,128.85 UV1.AB8
N16754178: length 1.1
  TOP w0.102: T209.1 173.28,127.19 v2(173.66,127.57)
  BOTTOM w0.102: v2(173.66,127.57) 173.29,127.93 UV1.AC8
N16754180: length 1.2
  TOP w0.102: v2(173.69,125.96) 174.09,126.36 T205.1
  BOTTOM w0.102: v2(173.69,125.96) 173.3,126.36 UV1.AE8
N16754182: length 1.1
  TOP w0.102: T208.1 174.09,127.14 v2(174.48,126.75)
  BOTTOM w0.102: v2(174.48,126.75) 174.09,127.15 UV1.AD7
N16754186: length 3
  TOP w0.102: T201.1 173.27,137.03 173.27,136.51 172.93,136.18 172.93,135.99 v2(172.46,135.51)
  BOTTOM w0.102: UV1.N9 172.46,136.13 v2(172.46,135.51)
N16754188: length 4.8
  BOTTOM w0.102: T215.1 179.6,127.11 178.17,128.54 177.41,128.54 177.19,128.76 UV1.AB2
N16754190: length 7.2
  BOTTOM w0.102: T214.1 182.15,126.77 179.51,126.77 177.98,128.3 176.84,128.3 176.38,128.76 UV1.AB4
N16754196: length 1.2
  TOP w0.102: v2(172.88,126.74) 173.27,126.35 T206.1
  BOTTOM w0.102: UV1.AD9 172.49,127.13 v2(172.88,126.74)
N16754198: length 1.2
  TOP w0.102: T202.1 172.76,137.93 v2(172.85,137.84)
  BOTTOM w0.089: UV1.L9 172.49,137.48 v2(172.85,137.84)
N16754200: length 10.9
  BOTTOM w0.102: T216.1 182.78,129.26 182.01,129.26 181.29,128.54 179.37,128.54 177.94,129.97 174.39,129.97 174.13,129.72 173.73,129.72 UV1.Y8
N16754202: length 2.8
  TOP w0.102: T213.1 174.59,130.35 174.92,130.02 174.92,129.48 v2(175.27,129.13)
  BOTTOM w0.102: v2(175.27,129.13) 174.76,129.13 174.58,128.96 UV1.AB7
N16754208: length 8.1
  BOTTOM w0.102: T217.1 180.88,128.8 179.61,128.8 177.72,130.7 174.63,130.7 174.09,130.16 UV1.Y7
N16754270: length 6.6
  TOP w0.102: RV59.2 159.14,126.11 v2(159.33,125.92) 158.19,125.92 v1(158.18,125.92)
  BOTTOM w0.102: v2(159.33,125.92) 159.33,126.43 159.66,126.76 160.51,126.76 160.85,127.1 160.85,127.31 161.11,127.56 161.32,127.56 161.72,127.97 161.72,128.39 UV1.AB22
N16784339: length 2.2
  BOTTOM w0.127: RV77.1 189.12,135.34 188.32,135.34 188.09,135.57 ; U1.7 188.05,135.53 188.09,135.57 188.09,135.57 ; 188.09,135.57 188.1,135.57 188.09,135.57
N16784342: length 2.1
  BOTTOM w0.127: U1.6 188.17,136.18 188.18,136.17 188.42,136.17 v1(188.63,135.97) 188.83,135.76 RV78.1
N16808781: length 4.1
  BOTTOM w0.102: UV1.AJ11 170.89,123.2 171.29,122.8 171.29,121.46 v1(171.81,120.95) 172.19,120.56 RV157.1
N16808782: length 3.3
  BOTTOM w0.102: RV155.1 170.44,120.13 v1(170.44,120.95) 170.44,122.81 UV1.AK12
N16808783: length 2.9
  BOTTOM w0.102: RV156.1 170.89,120.37 UV1.AL11
N16814221: length 7.1
  TOP w0.102: RV60.1 175.72,128.01 171.79,128.01 v2(171.36,127.58)
  BOTTOM w0.089: v2(171.36,127.58) 170.98,127.96 UV1.AC11 170.52,127.79 169.67,127.79 UV1.AC13
N16855208: length 3.5
  TOP w0.127: R2450.1 R2448.2 ; R2450.1 149.92,33.9 149.92,33.91 U2407.7 ; R2450.1 v1(149.03,33.22)
N17019894: length 3.1
  TOP w0.102: UV7.L8 180.62,163.97 180.27,163.62 178.06,163.62 RV56.1
N17020058: length 5.4
  BOTTOM w0.102: UV8.L8 185.82,163.97 186.18,163.62 187.32,163.62 187.45,163.5 RV57.1
  BOTTOM w0.127: v1(190.75,164.02) 189.23,164.02 RV57.1
N17040769: length 5.9
  TOP w0.127: v1(187.83,32) 187.95,32.13 189.22,32.13 189.73,31.62 RI2.1 190.25,30.76 JIO1.10
N17072999: length 13.3
  TOP w0.127: v2(33.91,17.65) 34.31,17.65 34.69,18.03 34.69,18.64 34.49,18.84 U2301.12 ; C5216.1 28.07,20.13 27.63,20.13 v2(27.21,20.55)
  IN2 w0.127: v2(27.21,20.55) 30.11,17.65 v2(33.91,17.65)
  BOTTOM w0.127: v2(27.21,20.55) 26.99,20.55 26.19,21.35 v1(26.19,21.58)
N17073002: length 11.5
  TOP w0.127: U2301.10 33.69,18.24 v2(33.72,18.21) ; v2(27.92,20.56) 29.42,20.56 29.55,20.43 v1(29.55,20.07) 29.55,19.83 C5217.1
  IN2 w0.127: v2(27.92,20.56) 30.27,18.21 v2(33.72,18.21)
N17205184: length 4.5
  BOTTOM w0.127: US2.7 182.83,34.32 RS19.2 182.05,35.99 182.05,37.13 v1(181.77,37.41)
N17205187: length 4.5
  BOTTOM w0.127: RS22.2 183.44,26.43 183.44,27.76 RS20.2
  BOTTOM w0.254: RS20.2 183.89,28.51 183.33,29.07 US2.18
N17205206: length 2.3
  BOTTOM w0.127: v1(186.21,37.41) 185.6,36.8 185.6,35.98 186.04,35.55 RS25.2
N17242539: length 4
  TOP w0.102: v2(182.67,133.57) 182.01,133.57 181.76,133.32 RV58.1
  TOP w0.127: v1(180.71,132.56) 181.08,132.92 RV58.1
  BOTTOM w0.102: UV11.4 182.42,133.32 v2(182.67,133.57)
N17253873: length 7.5
  BOTTOM w0.102: R12.1 138.07,99.32 134.71,95.97 134.71,95.28 UC1.BC3
N17283477: length 6.5
  TOP w0.127: v1(60.45,15.2) 60.45,17.14 PC204.2
  TOP w0.203: PC204.2 60.2,18.29 PU200.12
  TOP w0.254: PR210.1 PC204.2
N17382836: length 6
  BOTTOM w0.254: PU800.3 28.25,47.98 v1(28.57,47.66) 28.99,47.24 PR802.2 PC803.1 PR803.1 29.51,45.1 30.03,44.58 PQ801.1
N17382859: length 4.1
  BOTTOM w0.254: PR802.1 31.43,47.24 v1(31.87,47.69) 32.89,47.69 33.24,48.04 PC801.2
N17384371: length 3.1
  BOTTOM w0.127: v1(84.4,152.62) 83.58,153.43 UX4.3 84.11,154.06 RX10.2
N17415515:
  vias: v1(95.34,160.1)
N17438484: length 2.3
  BOTTOM w0.102: RA1112.2 CA21.1
  BOTTOM w0.127: CA21.1 176.4,11.84 v1(175.49,10.93)
N17446620: length 2.9
  TOP w0.127: UZ1.28 v1(41.84,69.22) 42.14,68.91 RZ45.1
N17451409:
  vias: v1(65.78,52.93)
N17481633: length 1.4
  BOTTOM w0.127: 127.21,163.97 126.17,163.97 v1(125.9,163.7)
N17485857: length 3.5
  TOP w0.127: v1(55.76,31.42) PC523.1
  TOP w0.254: PR533.2 PC523.1 53.88,31.42 53.67,31.63 PQ504.2
N17511335: length 4.1
  BOTTOM w0.203: UA1.13 181.42,16.3
  BOTTOM w0.254: 181.42,16.3 181.02,16.7 180.6,16.7 v1(180.22,17.08) RA34.1 RA13.1
N17511724: length 2.1
  TOP w0.127: v1(22.29,44.12) C168.1 R811.2
N17580597: length 3.3
  TOP w0.127: v1(84.52,156.55) 85.17,155.91 CX52.1 84.56,154.94 84.56,154.5 84.81,154.25 UX3.4
N17734490: length 6.7
  BOTTOM w0.127: v1(49.59,65.33) 47.91,65.33 46.44,63.86 Q135.3
  BOTTOM w0.254: Q2513.3 45.94,62.57 45.83,62.69 Q135.3
N17734492: length 11.4
  BOTTOM w0.254: Q2515.3 54.24,56.85 52.32,54.93 v1(50.67,54.93) 49.14,54.93 48.82,55.24 48.06,55.24 46.92,56.39 46.92,57.15 46.46,57.61 Q2514.3
N17735595: length 5.2
  BOTTOM w0.127: Q2516.2 57.33,48.83 57.27,48.89 56.76,48.89 56.68,48.82 Q2516.3 56.68,47.77 56.83,47.62 R2635.1 56.83,47.04 57.44,46.43 v1(57.44,45)
N17854431: length 2.9
  BOTTOM w0.102: T4935.1 172.33,120.95 172.33,122.6 UV1.AL9
N17885105: length 2.6
  BOTTOM w0.089: UV1.R1 177.44,134.51 178.68,134.51 178.71,134.48
  BOTTOM w0.102: 179.18,134.35 178.84,134.35 178.71,134.48
  BOTTOM w0.127: T223.1 179.42,134.11 179.18,134.35
N17885106: length 4.2
  BOTTOM w0.089: UV1.R3 176.83,134.7 178.71,134.7
  BOTTOM w0.102: 178.71,134.7 180.43,134.7 T224.1
N18390627: length 4.4
  TOP w0.127: PQ710.2 110.72,166.99 110.9,167.17 111.72,167.17 v1(112.16,167.61)
  TOP w0.254: PQ710.2 109.98,166.17 PQ711.1
N18459489: length 4
  BOTTOM w0.127: v1(189.87,65.47) 189.49,65.85 189.49,66.43 189.09,66.83 PR38.1 188.32,66.34 PQ4.3
N19105477: length 2.3
  TOP w0.127: T27.1 15.35,60.89 JCRT.11
N19198957:
  vias: v1(17.37,81.45)
N19609367: length 5.1
  TOP w0.102: RX15.1 26.77,77.01 26.77,77.54 27.09,77.86 QX5.2
  TOP w0.127: v1(27.68,79.92) 27.68,78.65 27.95,78.38 QX5.2
N19646239: length 10.5
  IN1 w0.127: v2(182.24,20.85) 181.3,20.85 180.8,20.35 180.74,20.35 176.33,15.94 v2(176.33,15.82)
  BOTTOM w0.102: v2(176.33,15.82) 176.33,15.34 v1(176.37,15.3) 176.57,15.11 RA6.2 ; v2(182.24,20.85) 182.24,20.84 QA6.2
N19800719: length 3.9
  BOTTOM w0.102: RA5.2 QA6.6 181.69,21.49 181.87,21.31 181.87,20.95 181.76,20.84 QA6.5
  BOTTOM w0.127: RA5.2 180.22,20.65 v1(179.99,20.42)
N20135010: length 6.8
  TOP w0.127: v1(168.75,99.8) 169.32,99.23 169.32,98.3 168.84,97.82 PR1136.2
  TOP w0.254: v2(170.05,96.01) 169.35,96.01 168.85,96.51 PC1130.2 168.84,96.91 PR1136.2
  BOTTOM w0.203: PU1100.15 170.14,95.5 170.05,95.59 v2(170.05,96.01)
N20135022: length 1.9
  TOP w0.127: PC1130.1 v1(166.93,96.9)
  TOP w0.254: PC1130.1 167.95,96.91 PR1137.2
N20135024: length 5.7
  TOP w0.127: v1(175.41,92.53) 174.84,91.97 v2(174.5,91.97)
  TOP w0.254: PC1110.1 172.78,92.46 PR1114.1 173.84,92.46 174.03,92.27 174.2,92.27 v2(174.5,91.97)
  BOTTOM w0.203: PU1100.25 173.59,92.08 173.71,92.2 174.27,92.2 v2(174.5,91.97)
N20135039: length 5.6
  BOTTOM w0.127: PR1121.2 v1(164.75,97.83)
  BOTTOM w0.203: PU1100.11 168.54,94.78 168.39,94.93 167.4,94.93 165.8,96.53 PR1121.2
N20135040: length 5.1
  TOP w0.254: PC1124.1 v2(170.62,96.01) PC1122.1 PR1138.1
  BOTTOM w0.203: PU1100.16 170.54,95.51 v1(170.54,95.51) 170.62,95.59 v2(170.62,96.01) 170.62,96.32 PR1133.1
N20135043: length 5.1
  TOP w0.127: PR1139.1 171.8,96.89 v1(172.55,97.64)
  TOP w0.254: PC1131.1 171.51,95.76 v2(171.25,96.01) 171.51,96.27 PR1139.1
  BOTTOM w0.203: v2(171.25,96.01) 170.94,95.7 PU1100.17
N20135074: length 2.4
  BOTTOM w0.127: v1(174.77,99.59) 174.77,99.1 175.63,98.23 PR1125.2
N20135096: length 38.4
  TOP w0.127: v2(167.57,102.36) 167.6,102.36 v1(168.05,102.82)
  TOP w0.254: PR1126.2 166.44,101.55 PR1124.2 v2(167.57,102.36)
  IN2 w0.254: v2(183.7,109.6) 183.83,109.73 183.83,115.29 182.58,116.54 173.73,116.54 167.44,110.25 167.44,102.49 v2(167.57,102.36)
  BOTTOM w0.254: PL1103.2 v2(183.7,109.6)
N20135098: length 39.7
  TOP w0.127: v2(166.93,102.36) 166.93,102.39 v1(166.39,102.93)
  TOP w0.254: PR1128.2 165.91,102.17 166.74,102.17 v2(166.93,102.36)
  IN2 w0.254: v2(166.93,102.36) 167.06,102.49 167.06,110.4 173.57,116.92 182.73,116.92 184.21,115.44 184.21,109.73 v2(184.33,109.6)
  BOTTOM w0.254: PL1103.3 v2(184.33,109.6)
N20135126: length 13.8
  TOP w0.254: PR1120.2 v2(166.59,95.06)
  IN1 w0.254: v2(166.59,95.06) 168.33,95.06 169.03,95.76 169.03,99.19 169.18,99.34 169.18,100.77 v2(168.85,101.1)
  BOTTOM w0.254: PH1101.2 170.55,101.1 v1(169.78,101.1) v2(168.85,101.1) ; PR1121.1 164.89,96.42 165.23,96.08 165.79,96.08 166.59,95.28 v2(166.59,95.06)
N20135134: length 6.1
  BOTTOM w0.203: PR1129.2 171.19,97.49 PR1135.1 171.19,96.66 PR1133.2 PC1123.1 ; PC1123.1 172.13,96.25 171.34,95.46 PU1100.18 ; PC1123.1 172.14,96.66 PR1134.1
N20135137: length 2.8
  TOP w0.127: v1(170.95,98.87) 170.76,99.06 v2(170.3,99.06)
  TOP w0.254: PC1122.2 170.62,98.02 170.3,98.34 v2(170.3,99.06)
  BOTTOM w0.203: PR1129.1 v2(170.3,99.06)
N20135139: length 2.1
  BOTTOM w0.127: v1(171.46,100.34) 171.52,100.28 171.52,99.69 171.18,99.35 PC1128.1
  BOTTOM w0.203: PC1128.1 171.19,99.3 PR1135.2
N20135141: length 5.4
  TOP w0.127: v1(172.94,96.34) 172.36,95.76 v2(172.33,95.76)
  TOP w0.254: v2(172.33,95.76) 172.4,95.69 PR1130.1
  BOTTOM w0.203: PU1100.19 171.74,95.16 v2(172.33,95.76) 172.65,95.76 173.04,96.15 PC1123.2 173.03,96.66 PC1127.2
N20135144: length 1.9
  BOTTOM w0.127: PC1127.1 v1(173.03,99.44)
  BOTTOM w0.203: PR1134.2 PC1127.1
N20135171: length 22.9
  IN2 w0.254: v2(167.82,99.57) 167.82,100.84 169.09,102.11 169.09,103.98 173.95,108.84 177.25,108.84 179.38,110.97 179.38,113.03 v2(179.71,113.36)
  BOTTOM w0.127: v2(179.71,113.36) v1(179.13,113.94)
  BOTTOM w0.254: PH1102.1 v2(179.71,113.36) ; PR1131.2 168,99.75 v2(167.82,99.57)
N20135184: length 47.3
  IN2 w0.254: v2(165.5,103.28) 165.92,103.7 165.92,110.62 172.95,117.65 185.55,117.65 190.94,112.27 v2(190.94,111.76)
  BOTTOM w0.254: PR1104.2 166.44,101.55 PR1108.2 v1(166.43,103.04) 166.19,103.28 v2(165.5,103.28) ; PL1102.2 193.86,111.63 193.73,111.76 v2(190.94,111.76)
N20135219: length 46
  IN2 w0.254: v2(165.54,102.57) 166.3,103.33 166.3,110.46 173.11,117.27 185.4,117.27 190.3,112.36 v2(190.3,111.76)
  BOTTOM w0.127: v1(164.19,101.55) PR1110.2
  BOTTOM w0.254: v2(165.54,102.57) 165.54,101.8 PR1110.2 ; v2(190.3,111.76) 190.3,112.01 190.68,112.39 193.35,112.39 193.86,112.9 PL1102.3
N20135248: length 3.4
  BOTTOM w0.102: v1(167.75,88.21) 168.24,88.71 168.24,89.22 168.42,89.39 PU1100.40 168.54,88.71 168.62,88.63 168.85,88.63 168.94,88.72 PU1100.39
N20135251: length 3
  BOTTOM w0.102: PU1100.37 169.74,88.63 169.74,88.63 ; PU1100.38 169.34,88.71 169.42,88.63 169.74,88.63 ; 169.74,88.63 170.05,88.63 170.14,88.72 PU1100.36
N20135257: length 4
  TOP w0.127: v2(168.07,89.65) v1(166.36,89.65)
  TOP w0.254: v2(168.07,89.65) 168.14,89.73 PR1101.2
  BOTTOM w0.203: PU1100.1 167.54,90.08 167.43,89.96 167.43,89.82 167.6,89.65 v2(168.07,89.65)
N20135258: length 2.7
  TOP w0.254: PR1111.2 167.22,90.28 v2(167,90.07)
  BOTTOM w0.127: v2(167,90.07) 166.84,90.07 v1(166.45,89.67)
  BOTTOM w0.203: PU1100.2 167.34,90.48 167,90.14 v2(167,90.07)
N20135263: length 1.7
  BOTTOM w0.203: PU1100.34 170.94,88.63
  BOTTOM w0.254: PR1105.2 170.76,88.45 170.94,88.63
N20135264: length 2.7
  BOTTOM w0.203: PU1100.33 171.34,88.7 171.53,88.51 171.74,88.71 PU1100.32
  BOTTOM w0.254: PR1106.2 171.62,88.42 171.53,88.51
N20141258: length 2.9
  TOP w0.203: PR1016.2 120.03,159.54 120.77,158.8 v1(120.77,158.43) 120.77,157.99 120.36,157.58 PU1001.1
N20141272: length 39
  TOP w0.254: PH1002.2 v1(111.87,133.53) v2(111.44,133.1) ; PR1087.2 115.59,160.15 PR1080.1 115.14,158.83 v2(115.14,157.77)
  IN2 w0.254: v2(115.14,157.77) 115.14,157.22 115.69,156.67 115.69,155.64 114.99,154.94 111.17,154.94 107.8,151.57 107.8,150.29 106.76,149.24 106.76,146.51 109.73,143.54 109.73,135.66 111.44,133.96 v2(111.44,133.1)
N20141325: length 1.3
  TOP w0.254: PR1007.1 123.2,157.89 PC1007.2
N20141337: length 6.4
  TOP w0.203: PC1008.1 122.47,155.31 v1(122.22,155.31) PU1001.37
  TOP w0.254: PC1008.1 123.2,156.04 PR1007.2 124.08,156.94 PR1004.1 PR1000.2 124.09,157.89 PR1003.2
N20141361: length 8.7
  TOP w0.127: PR1003.1 124.95,159.66 v1(125.98,160.68)
  TOP w0.203: PC1007.1 122.57,158.18 122.57,156.17 122.11,155.71 PU1001.38
  TOP w0.254: PR1003.1 124.91,159.63 PR1006.2 123.16,159.63 PC1010.2 PC1007.1
N20141372: length 4.7
  TOP w0.203: PC1061.2 114.02,156.62 114.2,156.44 114.2,155.38 114.55,155.03 v1(114.55,155.03) 114.66,154.91 PU1001.15
  TOP w0.254: PR1066.2 PC1061.2
N20141380: length 0.9
  BOTTOM w0.254: PC1015.1 124.42,156.71 PR1015.2
N20141402: length 1
  TOP w0.254: PC1061.1 112.38,156.38 PR1072.2
N20141406:
  vias: v1(118.88,150.91)
N20141448: length 4.8
  TOP w0.127: v1(122.07,158.27) 122.29,158.04 122.29,156.98 122,156.69 v2(121.96,156.69)
  TOP w0.203: v2(121.96,156.69) 121.96,156.33 121.74,156.11 PU1001.39
  BOTTOM w0.254: v2(121.96,156.69) 121.97,156.71 PC1015.2 122.62,156.71 PR1013.2
N20141457: length 33.1
  TOP w0.127: v2(125.28,134.3) v1(124.69,134.3)
  IN2 w0.254: v2(126.24,155.89) 126.36,156 126.6,156 126.99,155.61 126.99,151.68 129.46,149.21 129.46,147.79 132.95,144.3 132.95,140.13 126.99,134.18 125.41,134.18 v2(125.28,134.3)
  BOTTOM w0.254: PR1012.2 126.02,155.64 126.24,155.87 v2(126.24,155.89) ; PL1002.2 v2(125.28,134.3)
N20141459: length 34.7
  TOP w0.127: v2(125.28,133.67) v1(126.03,133.67)
  IN2 w0.254: v2(126.24,156.53) 126.37,156.4 126.74,156.4 127.37,155.77 127.37,151.8 129.82,149.36 129.82,147.94 133.31,144.45 133.31,139.95 127.15,133.79 125.41,133.79 v2(125.28,133.67)
  BOTTOM w0.254: v2(126.24,156.53) 126.06,156.71 PR1014.2 ; PL1002.3 v2(125.28,133.67)
N20141467: length 30.2
  TOP w0.127: v2(116.52,132.14) v1(115.74,132.14)
  IN2 w0.254: v2(108.26,151.38) 108.39,151.26 108.39,150.37 107.11,149.09 107.11,146.79 110.09,143.82 110.09,136.19 114.01,132.27 116.39,132.27 v2(116.52,132.14)
  BOTTOM w0.254: v2(108.26,151.38) 108.01,151.64 PR1068.2 ; PL1004.3 v2(116.52,132.14)
N20141469: length 28.6
  TOP w0.127: v2(116.52,132.78) v1(117.18,132.78)
  IN2 w0.254: v2(116.52,132.78) 116.39,132.65 114.17,132.65 110.45,136.37 110.45,144.09 107.56,146.98 107.56,148.91 108.77,150.11 108.77,151.26 v2(108.9,151.38)
  BOTTOM w0.254: PR1084.2 109.15,151.89 108.9,151.64 v2(108.9,151.38) ; PL1004.2 v2(116.52,132.78)
N20141477: length 3.5
  BOTTOM w0.127: PC1013.1 133.29,139.36 133.61,139.67 v1(133.61,142.1)
N20141501: length 3.7
  TOP w0.203: PU1001.11 115.65,156.51 115.46,156.7 115.46,157.36
  TOP w0.254: 115.46,157.36 115.61,157.5 115.61,158.33 ; 115.61,158.33 v1(115.6,158.33) ; 115.61,158.33 115.61,158.38 PR1080.2
N20141511: length 5.4
  TOP w0.203: PR1047.1 114.15,154.81 114.42,154.54 115.22,154.54 115.25,154.51 PU1001.16
  TOP w0.254: PR1075.1 111.72,154.81 PC1060.1 PR1047.1 113.51,155.66 PC1059.1
N20141517: length 9
  TOP w0.203: PU1001.17 v2(115.04,154.11)
  TOP w0.254: PC1058.1 109.06,152.09 PR1069.1 110.18,151.81 v2(110.18,151.42)
  BOTTOM w0.254: v2(115.04,154.11) v1(112.3,154.11) 110.18,151.99 v2(110.18,151.42)
N20141713: length 4
  TOP w0.203: PC1008.2 122.98,154.91 PU1001.36
  TOP w0.254: PC1006.2 124.08,155.15 PR1005.1 124.06,155.12 PC1008.2
N20141719: length 1.7
  TOP w0.127: PR1074.2 v1(121.01,142.94)
N20141862: length 2.6
  TOP w0.127: PR1004.2 126.57,156.95 126.68,156.85 v1(126.68,156.84)
  TOP w0.254: PC1006.1 125,156.06 PR1004.2
N20141864: length 2.5
  TOP w0.127: v1(127.17,158.55) 126.47,157.85 PC1004.2
  TOP w0.254: PR1000.1 PC1004.2
N20141906: length 7.1
  TOP w0.203: PU1001.18 115.34,153.71 115.2,153.57 v1(114.61,153.57) 113.84,153.57 PR1047.2
  TOP w0.254: PR1073.2 111.69,152.97 PR1065.1 ; PR1065.1 111.73,152.94 PR1077.1 ; PR1065.1 111.74,153 PC1068.1 113.49,153.9 PR1047.2
N20141912: length 0.9
  TOP w0.254: PR1073.1 112.57,153.87 PC1060.2
N20141916: length 0.9
  TOP w0.254: PR1065.2 110.81,152.94 PC1037.1
N20141920: length 5.6
  TOP w0.127: v1(114.62,151.19) PR1078.1
  TOP w0.203: PU1001.19 115.42,153.31 115.12,153 PC1068.2
  TOP w0.254: PR1078.1 113.51,151.19 PC1057.2 113.51,152.1 PC1068.2
N20141926: length 2.9
  TOP w0.127: v1(110.8,149.95) 110.85,149.95 111.73,150.83 PR1077.2
  TOP w0.254: PC1057.1 112.6,152.05 PR1077.2
N20142021: length 38
  TOP w0.127: v2(130.36,135) v1(130.98,135)
  IN1 w0.254: v2(121.71,161.73) 122.03,161.42 123.37,161.42 124.58,160.21 124.58,156.27 130.65,150.2 130.65,148.2 134.18,144.67 134.18,137.01 132.23,135.06 130.42,135.06 v2(130.36,135)
  BOTTOM w0.254: PH1000.1 129.86,135.06 130.3,135.06 v2(130.36,135) ; v2(121.71,161.73) 121.71,162.36 121.79,162.43 PR1009.2
N20142108: length 39
  TOP w0.127: PR1079.2 v1(110.78,159.38)
  TOP w0.254: PR1079.2 110.78,158.15 109.98,157.35 v2(109.98,156.84)
  IN1 w0.254: v2(113.07,130.76) 112.95,130.89 112.95,133.01 105.39,140.57 105.39,149.22 109.85,153.68 109.85,156.72 v2(109.98,156.84)
  BOTTOM w0.254: PH1003.1 111.85,134.96 112.19,134.62 112.51,134.62 112.81,134.32 112.81,131.03 v2(113.07,130.76)
N20142189: length 16.3
  TOP w0.127: v2(126.37,149.9) v1(125.93,150.34)
  TOP w0.254: v2(121.35,158.72) 120.95,159.13 PR1016.1 120.94,159.65 PR1086.2
  IN1 w0.254: v2(121.35,158.72) 121,158.37 121,152.48 121.89,151.59 124.68,151.59 v2(126.37,149.9)
  BOTTOM w0.254: PH1001.2 125.82,149.35 v2(126.37,149.9)
N20265233: length 17
  BOTTOM w0.102: UC1.U30 114.17,73.14 113.67,72.64 113.67,71.99 113.49,71.82 113.17,71.82 112.92,72.06 112.47,72.06 112.15,71.75 112.15,71.35 112.25,71.25 112.25,70.52 111.47,69.74 111.47,68.45 110.71,67.7
  BOTTOM w0.127: 110.71,67.7 109.63,66.61 T173.1
N20265234: length 18
  BOTTOM w0.102: UC1.U31 114.17,72.22 113.86,71.91 113.86,71.33 112.96,70.43 112.96,69.89 112.68,69.61 112.68,67.96 112.41,67.7
  BOTTOM w0.127: T12.1 101.15,66.23 110.95,66.23 112.41,67.7
N20265235: length 1.2
  TOP w0.102: v2(127.17,73.81) 127.21,73.81 127.49,73.53 T13.1
  BOTTOM w0.102: UC1.AN30 126.97,73.61 v2(127.17,73.81)
N20272982: length 4.6
  TOP w0.127: v2(63.62,35.31) 63.95,35.31 v1(64.41,35.76)
  TOP w0.203: v2(63.62,35.31) 63.18,34.86 62.82,34.86 62.66,35.02 PU500.15
  BOTTOM w0.203: PC520.2 64.65,34.62 PR526.2 63.81,35.12 v2(63.62,35.31)
N20272994: length 2
  BOTTOM w0.127: PC520.1 v1(66.69,34.65)
  BOTTOM w0.254: PC520.1 65.59,33.73 PR528.2
N20272996: length 0.9
  BOTTOM w0.508: v2(59.11,39.43) 58.9,39.22 PC502.1
  vias: v1(59.11,38.9)
N20273008: length 31.2
  TOP w0.254: PR518.2 66.73,39.65 66.99,39.9 v2(66.99,40.03)
  BOTTOM w0.254: PL502.3 67.68,54.48 67.49,54.29 67.49,52.07 68.13,51.43 74.42,51.43 74.99,50.86 74.99,42.23 72.98,40.22 v1(70.75,40.22) 67.18,40.22 v2(66.99,40.03)
N20273009: length 31.6
  TOP w0.254: PR517.2 66.1,39.81 v2(66.44,40.16)
  BOTTOM w0.254: v2(66.44,40.16) 66.44,40.17 66.89,40.61 v1(68.62,40.61) 72.84,40.61 74.61,42.39 74.61,50.71 74.26,51.05 67.97,51.05 67.11,51.91 67.11,54.23 66.86,54.48 PL502.2
N20273011: length 3.4
  TOP w0.203: PR513.2 63.06,32.14 v1(62.94,32.26) 62.48,32.73 62.48,33.21 62.27,33.42 PU500.11
N20273012: length 16
  TOP w0.127: v1(68.6,29.55) 68.18,29.97 v2(68.18,29.98)
  TOP w0.203: v2(62.99,35.31) 62.88,35.42 PU500.16
  TOP w0.254: PC514.1 PR521.1 67.18,31.61 PC512.1 68.17,30.75 PR529.1 v2(68.18,29.98)
  IN1 w0.254: v2(62.99,35.31) 62.99,34.61 63.43,34.16 63.43,32.72 63.24,32.52 63.24,30.23 63.7,29.77 64.47,29.77 64.69,29.98 v2(68.18,29.98)
N20273015: length 3.5
  TOP w0.203: v2(62.86,35.94) 62.73,35.82 PU500.17
  BOTTOM w0.127: v1(62.41,34.94) 62.17,35.18 PC521.1
  BOTTOM w0.254: PR530.1 v2(62.86,35.94) PC521.1
N20273032: length 4.6
  TOP w0.127: v1(65.06,32.26) 64.59,32.26 64.06,32.78 PR515.2
  TOP w0.203: PU500.13 62.93,34.22 63.24,33.91 63.24,32.96 63.42,32.78 PR515.2
N20273046: length 3.7
  BOTTOM w0.127: v1(73.63,43.09) 73.82,43.28 73.82,45.63 73.35,46.1 PC511.1
N20273098: length 4.3
  TOP w0.127: PR513.1 63.18,29.77 v1(63.42,29.77)
  TOP w0.254: PR513.1 62.15,31.2 62.31,31.37 v2(62.31,31.62)
  BOTTOM w0.254: PH501.2 62.16,31.34 62.31,31.5 v2(62.31,31.62) 62.31,31.98 62.16,32.13 PR512.2
N20273106: length 13.2
  TOP w0.203: v2(65.08,36.58) 64.95,36.45 62.67,36.45 62.43,36.22 PU500.18
  TOP w0.254: PR519.2 66.27,30.76 PR521.2 PR525.1 67.42,33.66 PR522.1 66.92,36.19 66.67,35.94 v2(66.67,35.69)
  BOTTOM w0.254: v2(66.67,35.69) 66.6,35.69 v1(66.08,36.21) 65.72,36.58 v2(65.08,36.58) 64.51,37.15 PC513.1
N20273109: length 2.4
  TOP w0.127: PR519.1 66.01,29.83 v1(65.11,30.73)
  TOP w0.254: PC512.2 PR519.1
N20273111: length 2.1
  TOP w0.127: PC518.1 v1(68.18,33.64)
  TOP w0.254: PR525.2 PC518.1
N20273113: length 8
  TOP w0.203: v2(62.86,36.96) 62.67,36.96 62.33,36.62 PU500.19
  TOP w0.254: v2(66.67,36.58) 67.18,37.08 PC515.2
  BOTTOM w0.254: PR520.1 62.67,37.15 v2(62.86,36.96) 63.05,37.15 PC513.2 63.54,37.45 63.81,37.72 v1(65.54,37.72) 66.1,37.72 66.67,37.15 v2(66.67,36.58)
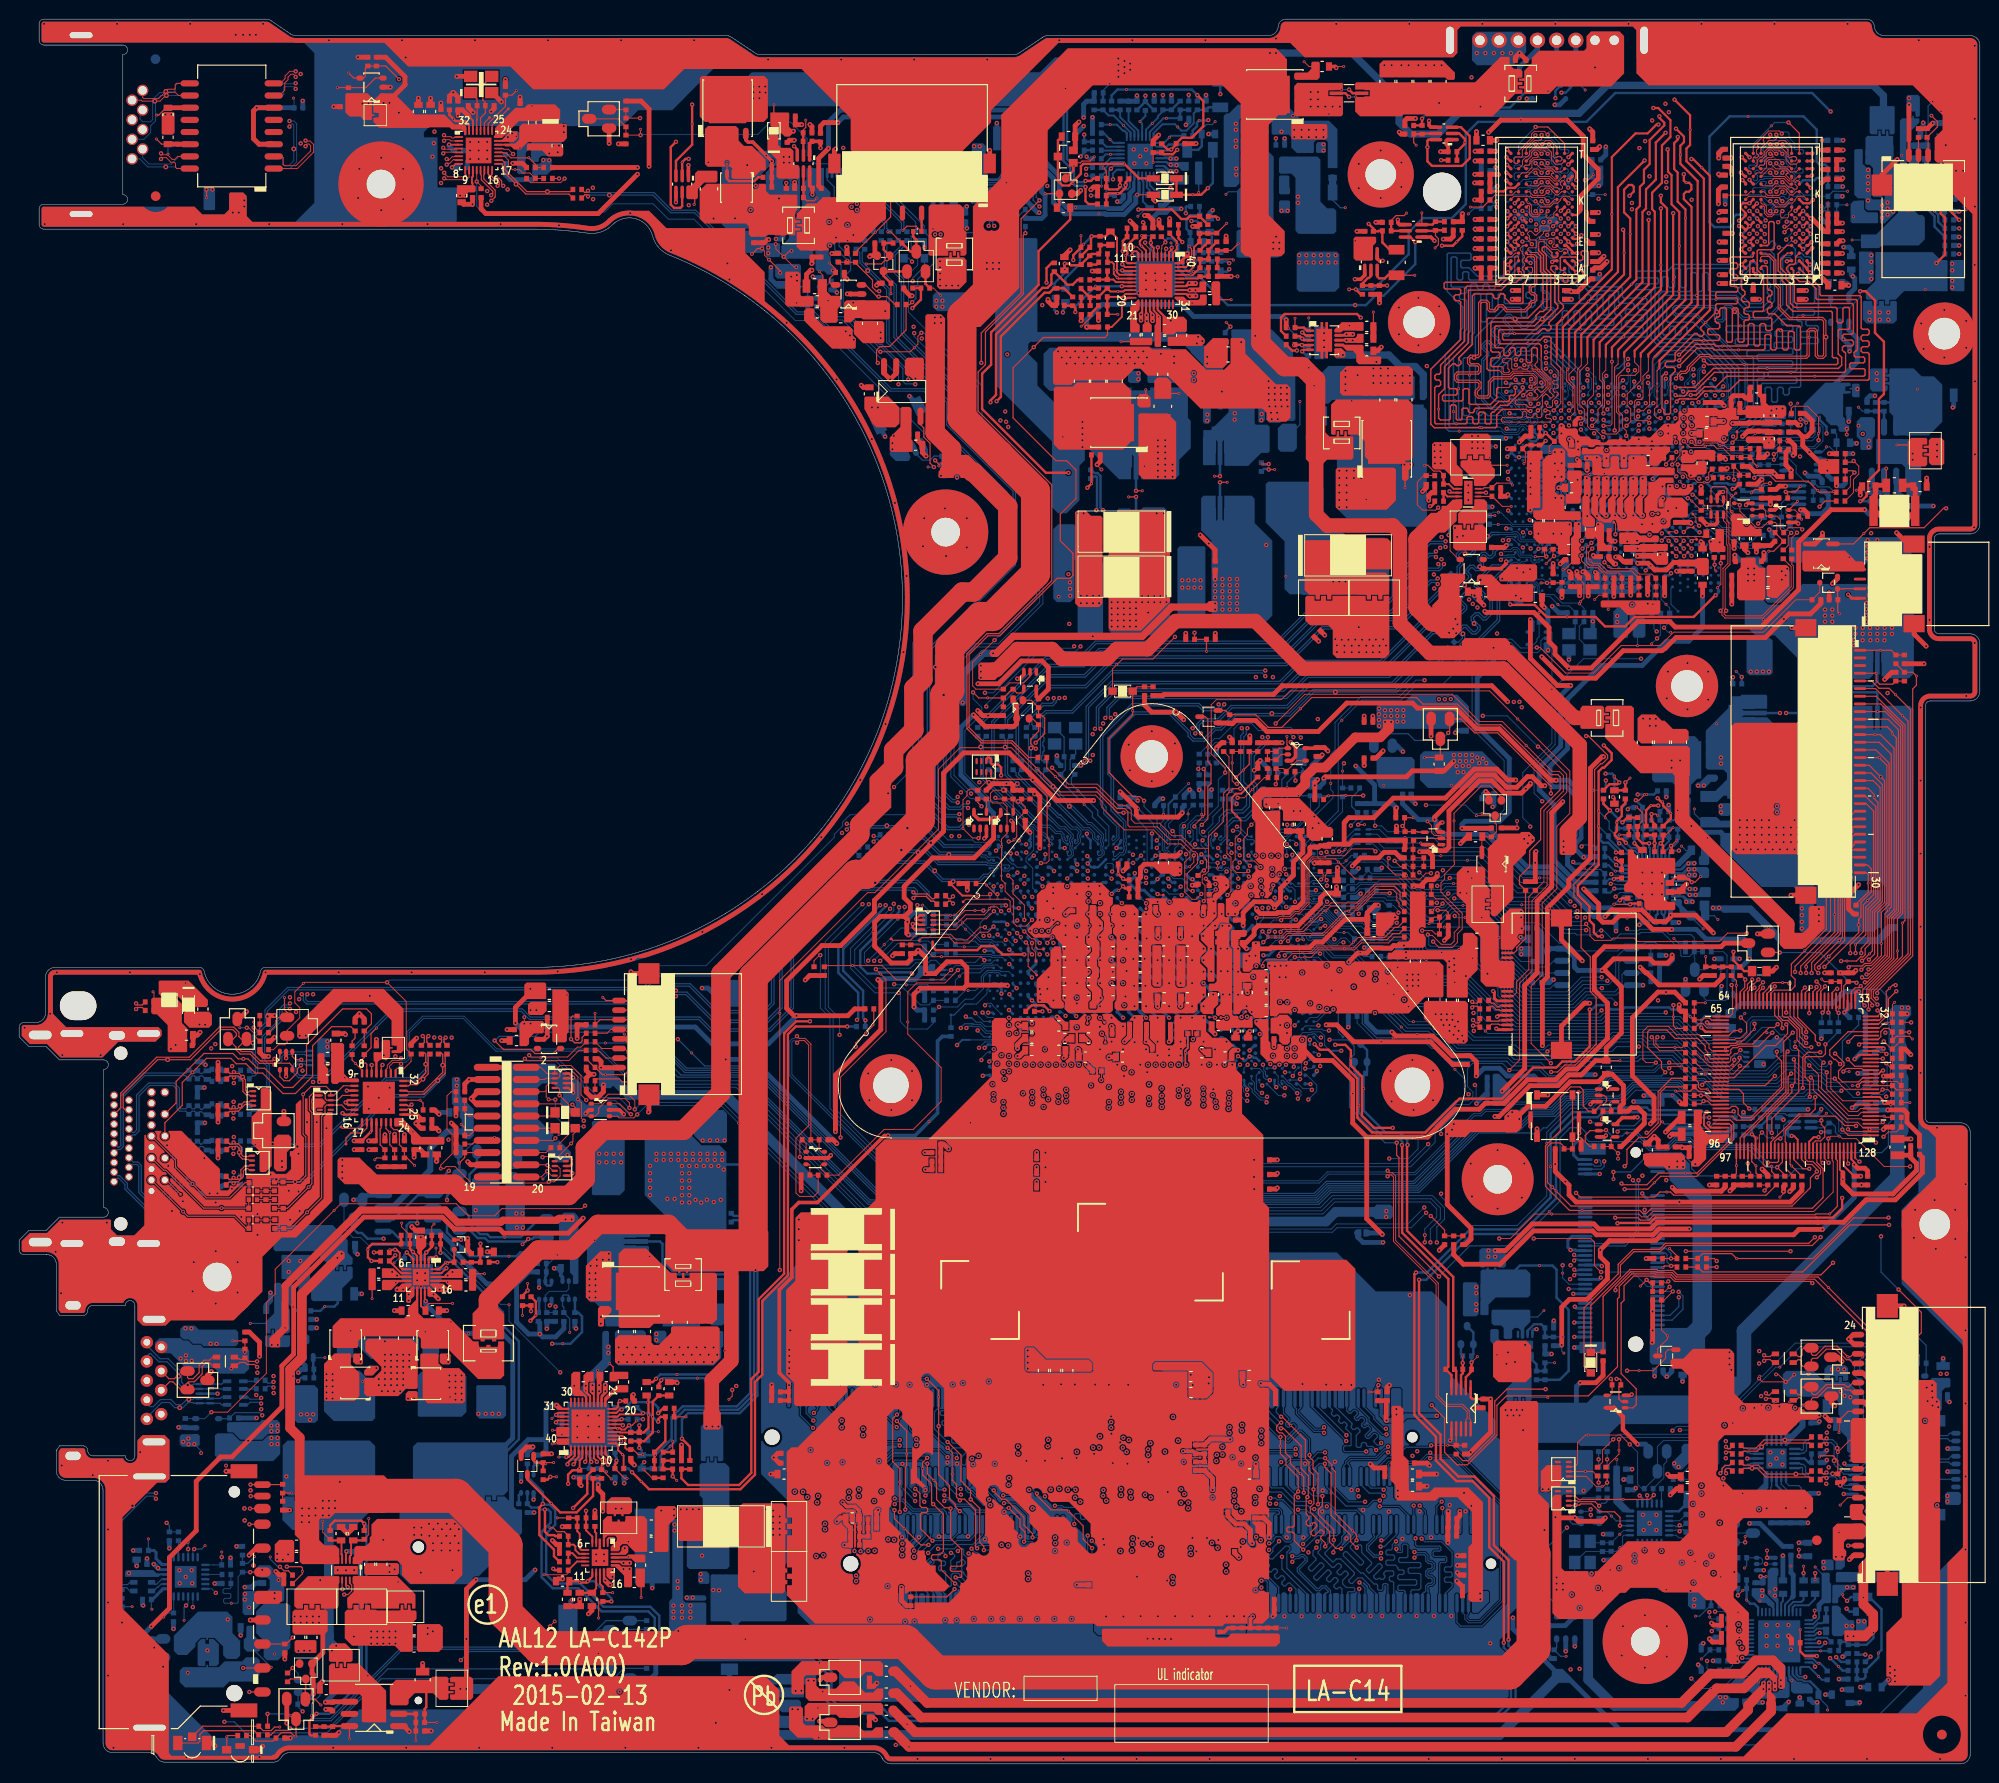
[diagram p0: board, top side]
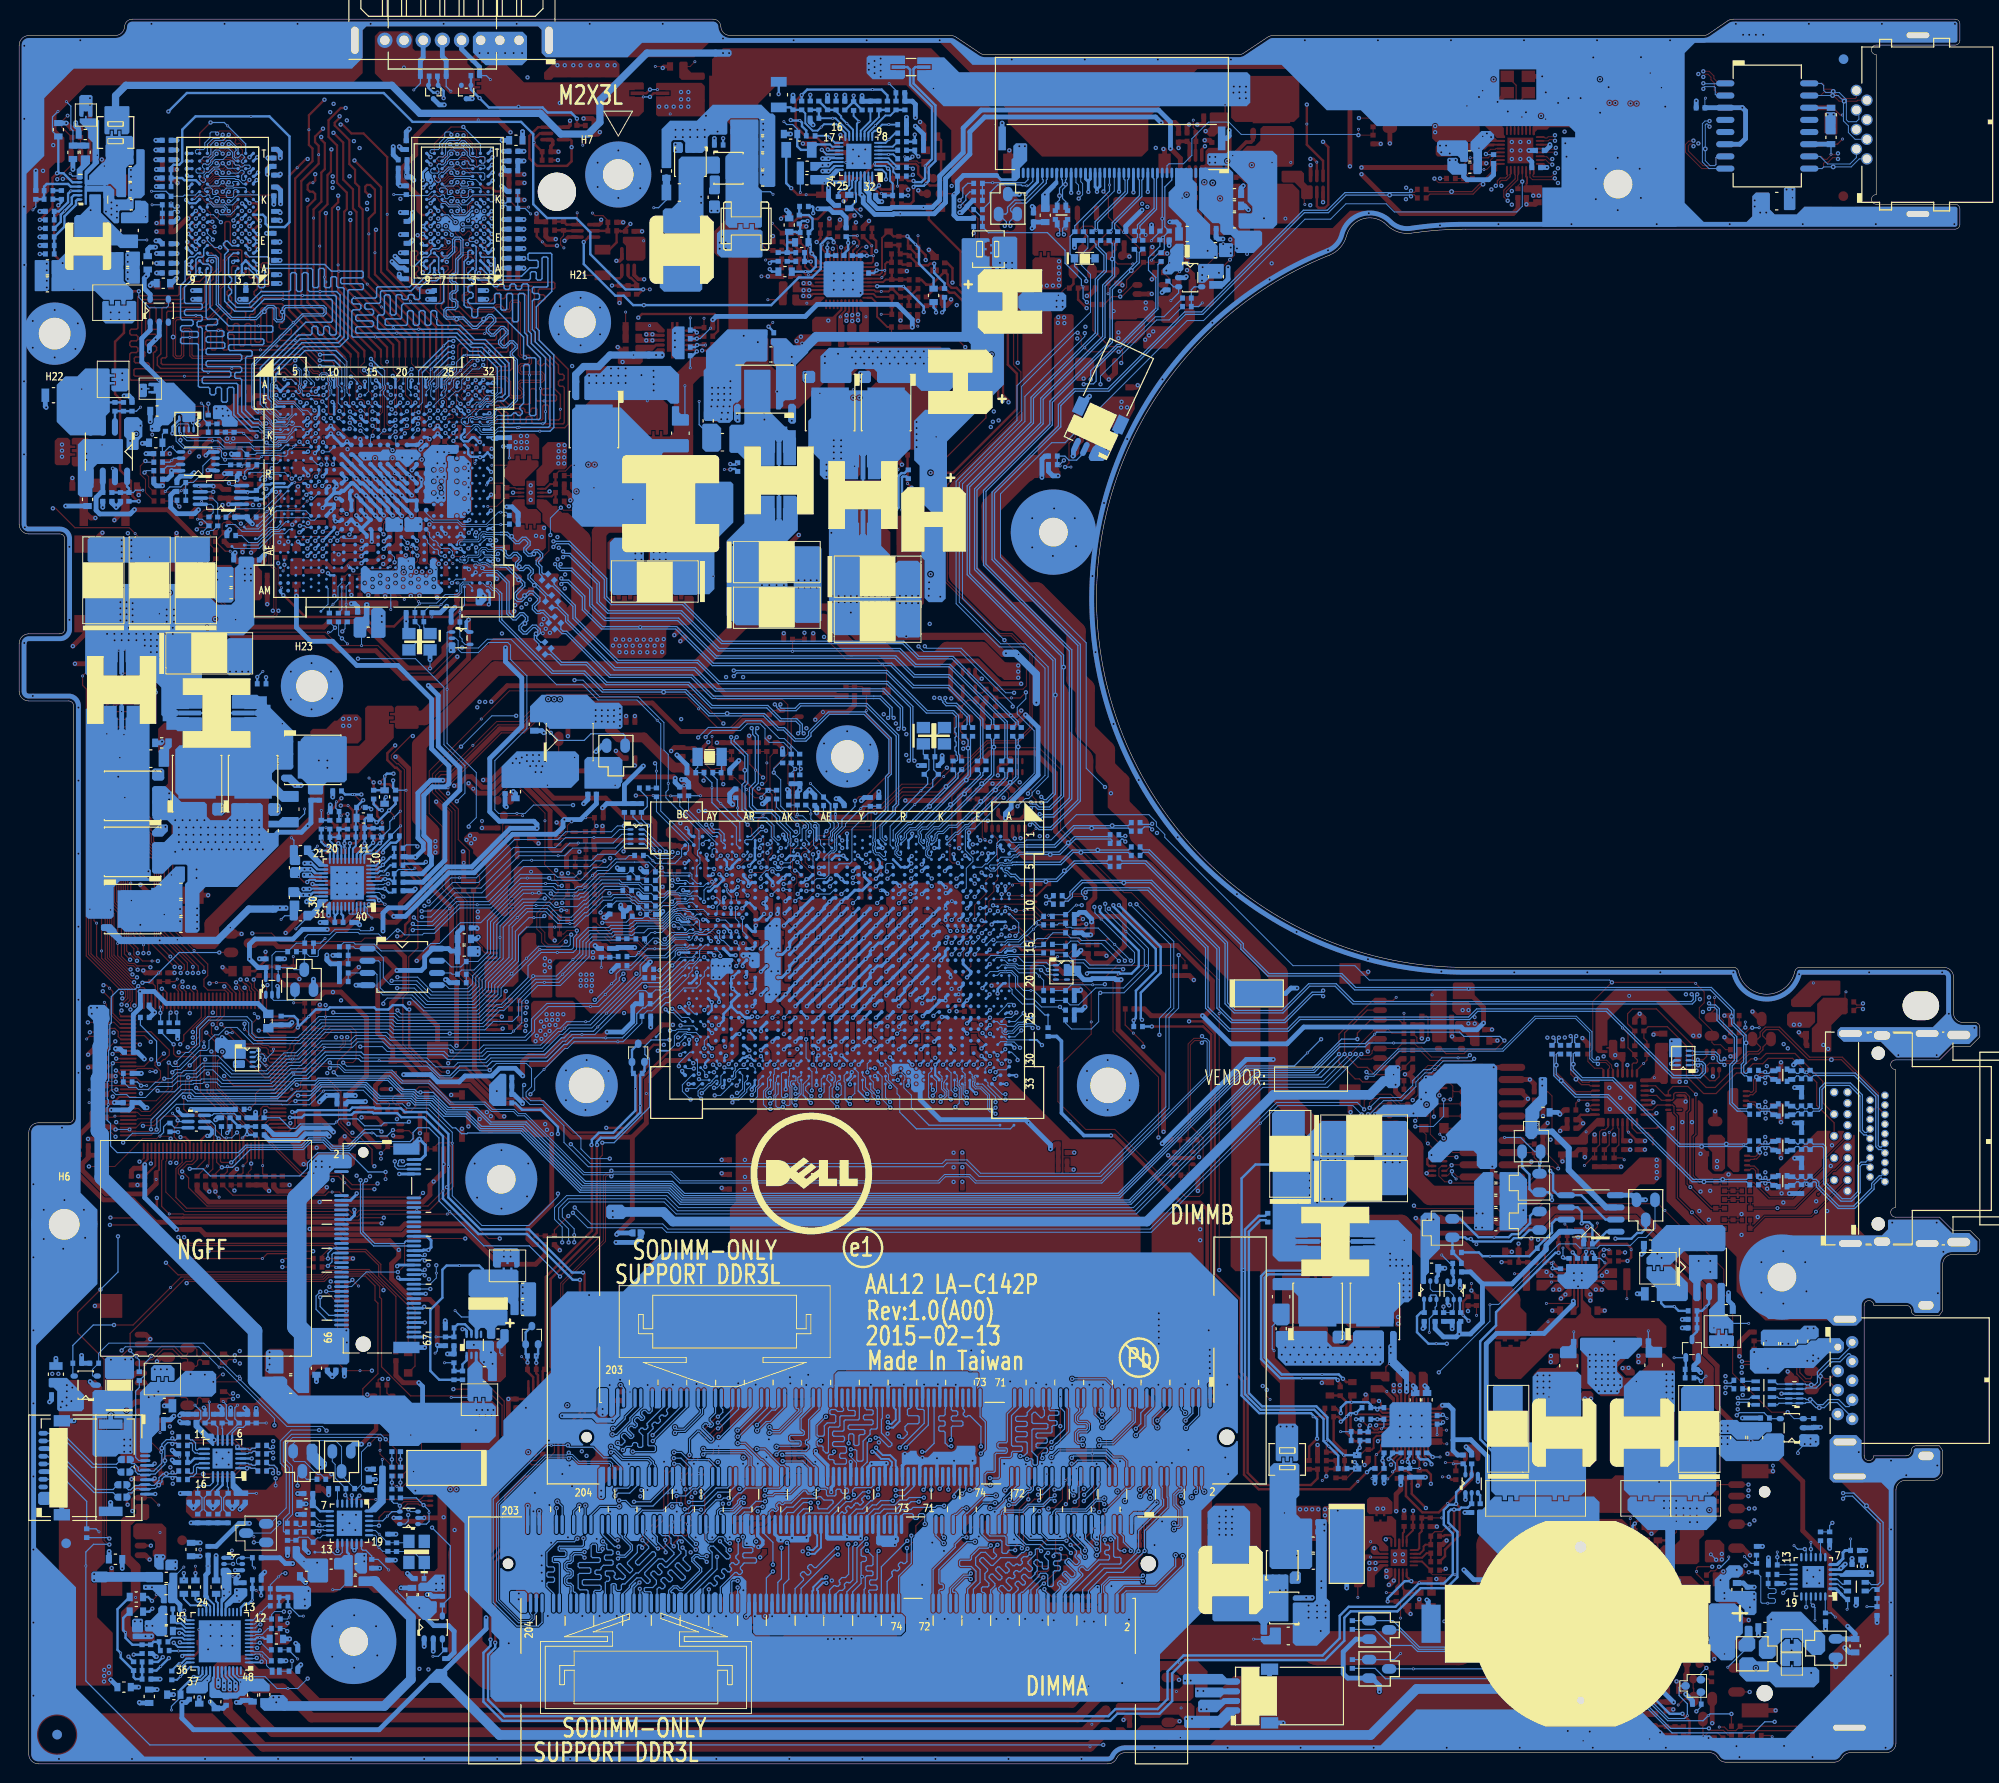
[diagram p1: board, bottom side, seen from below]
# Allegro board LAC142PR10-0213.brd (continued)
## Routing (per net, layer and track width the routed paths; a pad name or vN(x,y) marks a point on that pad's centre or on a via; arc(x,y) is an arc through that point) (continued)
N20273116: length 2.1
  TOP w0.127: PR522.2 v1(69.56,36.19)
  TOP w0.254: PC515.1 PR522.2
N20273143: length 35.3
  BOTTOM w0.254: PR523.2 66.94,32.14 v1(67.92,33.13) 68.47,33.68 68.47,35.96 69.44,36.93 75.03,36.93 76.66,38.56 76.66,55.73 75.24,57.15 74.56,57.15 PH502.1
N20273220: length 0.7
  TOP w0.127: 56.19,33.62 55.95,33.38 v1(55.61,33.38)
N20273223: length 0.5
  TOP w0.127: v1(55.64,34.8) 56.15,34.8
N20273229: length 2.7
  TOP w0.203: v2(57.08,32) 57.33,32 57.56,32.23 PU500.1
  BOTTOM w0.127: v2(57.08,32) v1(56.31,32)
  BOTTOM w0.254: PR501.2 57.51,32.44 v2(57.08,32)
N20273230: length 4
  TOP w0.203: PU500.2 57.96,32.12 57.21,31.37 v2(57.21,31.24)
  BOTTOM w0.254: v2(57.21,31.24) 57.21,31.37 57.59,31.75 58.35,31.75 58.6,32 PR504.2
N20273235: length 2.8
  TOP w0.203: PU500.34 56.19,35.82 v2(56,35.62)
  BOTTOM w0.127: PR502.2 v1(56.62,34.33)
  BOTTOM w0.254: v2(56,35.62) 56.19,35.43 PR502.2
N20273236: length 3.1
  TOP w0.203: PU500.32 56.24,36.62 v2(56.03,36.4) 56.21,36.22 PU500.33
  BOTTOM w0.127: v1(55.58,36.02) 55.96,36.4 v2(56.03,36.4)
  BOTTOM w0.254: PR503.2 56.1,36.32 v2(56.03,36.4)
N20277821: length 2.7
  TOP w0.127: v1(133.1,150.77) PR302.2
  TOP w0.254: PR302.2 134.04,149.8 134.36,149.48 PU300.1
N20277901: length 3.8
  BOTTOM w0.127: PR305.2 135.1,140.61 v1(135.1,143.74)
N20355294: length 22.1
  TOP w0.102: 142.15,90.84 141.46,90.84 139.66,89.04 139.41,89.04 138.94,88.57 138.25,88.57 136.07,86.4 132.4,86.4 131.72,85.71 v2(131.62,85.71)
  TOP w0.127: 142.15,90.84 142.94,90.84 v2(142.98,90.8) ; R449.2 149.09,88.77 148.84,89.03 v2(147.99,89.03)
  IN2 w0.127: v2(142.98,90.8) 145.38,90.8 147.16,89.03 v2(147.99,89.03)
  BOTTOM w0.102: UC1.AW14 131.87,86.21 131.8,86.15 131.79,86.15 131.68,86.04 131.68,86.03 131.62,85.97 v2(131.62,85.71)
  BOTTOM w0.127: v2(147.99,89.03) v1(147.41,89.03)
N20391319: length 4.9
  TOP w0.127: v1(34.45,2.59) PU400.8
  TOP w0.254: PR401.2 PR403.1 PC401.1 32.75,3.94 PU400.8
N20391329: length 4.6
  TOP w0.127: PR404.1 v1(41.38,2.4)
  TOP w0.254: PR404.1 PR402.2 PC404.2 PU400.2
N20391331:
  vias: v1(36.38,9.19)
N20394063: length 5.1
  BOTTOM w0.127: PR1201.2 192.64,132.6 192.4,132.84 v1(191.65,132.84)
  BOTTOM w0.254: PR1203.1 PC1201.1 PR1201.2 193.1,133.03 193.29,133.22 PU1200.8
N20394073: length 4.5
  BOTTOM w0.127: PR1204.1 192.31,141.08 v1(191.89,141.5)
  BOTTOM w0.254: PU1200.2 PC1204.2 PR1202.2 PR1204.1
N20394075: length 1.2
  TOP w0.127: 197.12,137.57 v1(195.9,137.57)
  vias: v2(197.54,136.65) v2(197.54,136.02)
N20395535: length 1.8
  BOTTOM w0.127: 157.65,38.21 v1(159.48,38.21)
N20395548: length 1.1
  BOTTOM w0.127: PC606.1 154.41,42.89 v1(154.18,42.66)
N20557240: length 2.8
  BOTTOM w0.127: UL4.3 160.4,12.14 R44.2 160.81,11.21 v1(161.38,11.21)
N20623473: length 3.2
  BOTTOM w0.127: v1(26.3,10.07) 24.31,12.06 D101.2
N20654206: length 4.7
  TOP w0.127: JKB.30 192.72,92.95 192.91,92.76 v1(192.91,91.87) 192.91,90.94 191.64,89.67 RE60.2
N21016181: length 3.9
  BOTTOM w0.127: PR769.2 v1(112.91,164.55)
  BOTTOM w0.203: PR769.2 113.35,166.05 113.35,166.47 113.95,167.07 PU703.3
N21016217: length 2.4
  BOTTOM w0.203: PU703.4 113.84,167.47 PR770.2
N21016253: length 2.2
  BOTTOM w0.203: PU703.5 v1(113.85,167.87) 113.35,167.87 PR777.2
N21016293: length 2
  BOTTOM w0.203: PU703.6 112.93,168.27 PR774.2
N21016335: length 2.2
  BOTTOM w0.203: PR775.2 113.42,168.67 PU703.7
N21017384: length 1.3
  BOTTOM w0.127: PR771.2 v1(123.06,163.89)
N21017467: length 3.1
  TOP w0.127: v1(107.03,163.77) PQ711.2
  TOP w0.254: PQ711.2 108.53,162.59 PR781.2
N21021316: length 2.8
  TOP w0.127: v1(141.28,151.42) PR303.2
  TOP w0.635: PR303.2 PC305.1
N21022260: length 1.5
  TOP w0.127: PR1008.2 v1(126.44,152.71)
N21022300: length 1.5
  TOP w0.127: PR1082.2 v1(114.95,148.33)
N21023084: length 1.5
  TOP w0.127: PC510.1 61.97,41.39 v1(61.6,41.76)
N21023991: length 6.1
  BOTTOM w0.127: PC1404.1 198.94,170.33 199.15,170.55 199.15,172.9 v1(199.62,173.37)
  BOTTOM w0.635: PC1404.1 PR1405.2
N21024525: length 1.5
  BOTTOM w0.127: PR1103.2 176.84,88.46 v1(177.22,88.07)
N21024549: length 1.4
  BOTTOM w0.127: v1(176.14,96.58) 175.89,96.33 PR1123.2
N23700319: length 6.1
  TOP w0.127: v1(90.62,159.8) 90.91,159.8 PR6.2
  TOP w0.254: PL2.1 93.27,159.28 93.59,158.97 PQ6.1 92.98,157.73 PR6.2
N26062389: length 17
  TOP w0.127: v2(186.16,19.89) v1(186.16,20.61)
  IN2 w0.254: v2(192.6,11.39) 192.65,11.43 192.65,11.44 193.4,12.19 193.4,17.28 191.81,18.87 187.18,18.87 v2(186.16,19.89)
  BOTTOM w0.254: RA82.1 191.84,11.39 v2(192.6,11.39) ; CA68.2 v2(186.16,19.89)
N26062391: length 16.2
  TOP w0.127: v2(187.37,19.89) v1(187.37,19.23)
  IN2 w0.254: v2(193.15,11.18) 193.85,11.87 193.85,17.41 192.03,19.23 188.03,19.23 v2(187.37,19.89)
  BOTTOM w0.254: CA67.2 v2(187.37,19.89) ; RA80.1 v2(193.15,11.18)
N26148842: length 5.2
  TOP w0.127: v1(33.22,174.83) RL40.2 36.16,174.83 37.16,175.83 UL3.3
N26156452: length 5.8
  TOP w0.127: v1(51.87,174.51) 51.4,174.04 RL39.2 50.73,172.87 48.94,171.08 UL1.26
N26156532: length 3
  TOP w0.127: UL1.25 49.34,170.92 T94.1
N26156534: length 1.6
  TOP w0.127: T95.1 48.54,171.16 UL1.27
N26156585: length 3.6
  TOP w0.203: UL1.31 46.94,170.93 46.79,171.07
  TOP w0.254: RL31.2 44.89,171.96 v1(45.3,171.55) 45.52,171.34 46.53,171.34 46.79,171.07
N27266810: length 18.6
  TOP w0.381: PQ718.4 75.81,169.38 76.04,169.15 76.54,169.15 v1(77.95,167.74) v2(78.52,167.17) PC744.1 PR778.2 PC742.1 ; PQ709.6 82.47,164.62 PR762.1 v2(82.76,163.66)
  IN1 w0.381: v2(78.52,167.17) 78.52,162.89 78.83,162.57 81.67,162.57 v2(82.76,163.66)
N27284163: length 4.3
  TOP w0.127: v1(83.22,163.31) 82.94,163.03 82.18,163.03 81.84,163.36 PR739.1
  TOP w0.254: PR739.1 PR746.2 PQ709.5
N27286227: length 9.5
  TOP w0.254: v2(124.01,164.35) 123.32,163.66 v1(122.45,163.66) PD704.1 120.73,163.66 PD705.1
  BOTTOM w0.254: PR743.2 124.53,164.87 v2(124.01,164.35)
N27352133: length 2.5
  TOP w0.127: R49.2 47.3,64.64 47.68,65.02 JHDT1.13
N27352135: length 3.6
  TOP w0.127: v1(45.92,62.67) 46.49,63.25 R51.2 JHDT1.15
N27352149: length 4
  TOP w0.127: JHDT1.11 47.75,66.29 46.98,65.53 R52.2 46.49,66.33 v1(46.12,66.7)
N27367990: length 0.9
  BOTTOM w0.127: C636.1 R617.2
N27535100: length 3.1
  TOP w0.127: UE1.111 184.75,62.53 v1(184.92,62.36) RE14.1
N27535635: length 1.8
  TOP w0.127: v1(197.25,68.96) CE24.1 RE16.2
N27539530: length 6.8
  TOP w0.127: v1(132.26,107.16) 132.26,106.29 132.35,106.2 UH1.1 131.47,105.93 CH16.1 RH26.2 RH25.2 RH28.1 131.68,105.28 UH1.2
N27594046: length 2.3
  BOTTOM w0.127: RE66.1 RE65.1 173.12,85.6 v1(172.64,86.08)
N27653670: length 11.5
  TOP w0.102: RV254.2 176.84,125.1 v2(176.88,125.06) 176.88,124.56 v1(177.02,124.42)
  IN2 w0.107: v2(170.1,128.21) 170.1,125.97 171.01,125.06 v2(176.88,125.06)
  BOTTOM w0.102: UV1.AB12 169.89,128.41 v2(170.1,128.21)
N27653677: length 14.4
  TOP w0.102: RV255.2 177.53,125.64 v2(177.53,125.23) 177.53,123.03 v1(177.17,122.67)
  IN2 w0.107: v2(177.53,125.23) 177.19,125.57 176.29,125.57 176.15,125.42 171.15,125.42 170.55,126.02 170.55,127.9 170.99,128.34 v2(171.38,128.34)
  BOTTOM w0.102: UV1.AB11 170.96,128.76 v2(171.38,128.34)
N27700813:
  vias: v1(24.63,64.57)
N27705118: length 3.5
  TOP w0.127: v1(146.6,104.97) R1671.2 148.27,105.09 Q83.1
N27707965: length 3.9
  TOP w0.102: v1(155.66,131.15) 154.73,131.15 154.33,131.55
  TOP w0.127: 154.33,131.55 153.68,132.21 C349.2 153.63,132.19 U15.10
N27708054: length 3.9
  TOP w0.102: 154.33,133.58 155.58,133.58 155.77,133.39 v1(155.78,133.39)
  TOP w0.127: U15.12 152.73,132.99 152.84,133.1 C343.2 154.13,133.58 154.33,133.58
N27738679: length 5.1
  BOTTOM w0.102: U69.12 172.87,23.84 173.15,23.57 173.44,23.57 R139.2 174.4,23.64 175.36,23.64 R147.2 176.54,23.32 C43.1
N27738786: length 1.6
  BOTTOM w0.102: C668.2 171.34,28.7 U69.6
N27738791: length 4.1
  BOTTOM w0.102: U69.14 170.84,22.05 171.08,21.81 171.58,21.81 171.84,22.08 T26.1
N27738995: length 4.6
  BOTTOM w0.127: U69.18 168.84,22.42 168.7,22.28 168.37,22.28 167.77,21.67 R148.1 167.1,21.32 v1(166,20.22)
N27739014: length 2
  BOTTOM w0.102: C667.1 173.21,25.34 U69.9
N27920326: length 2.8
  TOP w0.203: PU1001.13 115.15,155.71 v2(115.09,155.77)
  BOTTOM w0.127: v2(115.09,155.77) v1(114.25,155.77)
  BOTTOM w0.254: PR1081.2 115.37,155.49 v2(115.09,155.77)
N28237059:
  vias: v1(196.4,167.78)
N28237408: length 0.9
  BOTTOM w0.254: PC1408.2 201.02,164.1 PR1409.1
N28407026: length 10.4
  BOTTOM w0.102: UC1.AY18 133.07,82.62 133.07,82.17 133.47,81.77 133.47,81.34 133.89,80.92 135.2,80.92 136.73,79.4
  BOTTOM w0.127: 136.73,79.4 137.07,79.4 137.62,78.84 137.62,76.3 VDDP_SENSE.1
N28452649: length 1.9
  BOTTOM w0.127: R808.2 C157.1 v1(11.78,16.4)
N28452851: length 2.4
  BOTTOM w0.127: C160.1 R809.2 23.84,20.9 v1(24.56,21.62)
N28452956: length 1.8
  TOP w0.127: C163.1 R810.2 v1(28.42,28.24)
N28483985: length 4.8
  TOP w0.127: v1(145.6,155.26) PR5.2
  TOP w0.254: PQ1.3 141.68,155.14 141.88,154.94 142.49,154.94 142.8,155.26 PR5.2
N28484391: length 3.7
  TOP w0.127: PQ2.3 146.33,161.66 146.34,161.66 v1(146.34,161.77)
  TOP w0.254: PQ2.3 147.44,160.54 PC16.1 148.68,160.86 PR28.2
N28484395: length 4.5
  TOP w0.127: PC16.2 147.76,159.38 148.06,159.08 148.06,158.46 v1(147.72,158.11)
  TOP w0.254: PQ2.2 147.71,159.89 PC16.2 147.77,159.96 PR29.1
N28484412: length 4.5
  TOP w0.127: v1(144.75,161.75) 144.48,161.48 143.64,161.48 143.14,160.97 PR33.2
  TOP w0.254: PQ2.5 PR31.1 PR33.2
N28484439: length 3.6
  TOP w0.127: v1(145.75,168.82) 145.48,169.09 PR32.1
  TOP w0.254: PR32.1 145.5,169.98 PC14.2 146.44,170.05 PQ3.5
N28484451:
  vias: v1(139.4,158.85)
N28484508: length 4.1
  TOP w0.254: PQ3.2 150.23,170.05 150.83,169.46 v1(150.83,169.1) 150.83,168.99 PC15.1 PR30.2
N28484561: length 3.8
  BOTTOM w0.127: PR27.1 182.09,67.81 184.24,67.81 184.41,67.64 PQ4.6
N28484610: length 3.7
  TOP w0.127: PC6.1 v1(175.95,84.2)
  TOP w0.254: PC6.1 PR35.1 PR34.1 PR36.1
N28714507: length 11.5
  TOP w0.381: v2(83.6,168.53) PR763.1 83.52,169.23 PR737.1 82.47,168.99 PQ709.1
  IN2 w0.381: v2(75.95,166.75) 77.36,168.16 83.31,168.16 83.6,168.45 v2(83.6,168.53)
  vias: v1(71.89,167.03)
N28714524: length 2.1
  BOTTOM w0.203: PC750.1 117.94,164.13 117.65,164.43 117.65,165.13 117.55,165.22 PU703.27
N28714534: length 2.1
  BOTTOM w0.127: PC752.2 113.08,174.54 v1(113.79,175.25)
  BOTTOM w0.254: PC752.2 113.07,174.28 PR754.1
N28714554: length 2.4
  BOTTOM w0.203: PR727.1 113.15,170.08 v1(113.81,169.43) 114.16,169.07 PU703.8
N28714572: length 8.4
  BOTTOM w0.127: v1(124.77,171.28) 124.47,170.98 123.86,170.98 123.37,170.5 PC757.2
  BOTTOM w0.203: PU703.18 119.72,168.67 119.96,168.9
  BOTTOM w0.254: 119.96,168.9 121.3,168.9 PR743.1 121.86,168.34 122.99,168.34 123.37,168.72 PC757.2
N28714582: length 3.2
  BOTTOM w0.203: PU703.12 116.75,170.34 115.74,171.35 PR755.2
N28714583: length 5.7
  BOTTOM w0.203: PR776.1 119.33,172.37 118.79,171.84 118.79,171.68 v1(118.2,171.09) 117.55,170.44 PU703.14
  BOTTOM w0.254: PR776.1 PC759.1 120.21,172.52 PC708.1
N28714585: length 6
  BOTTOM w0.203: PU703.15 117.95,170.21 119.38,171.64 v1(119.68,171.64) PC758.1
  BOTTOM w0.254: PR742.1 PC708.2 PC758.1
N28714598: length 7.1
  TOP w0.127: PR740.2 113.42,166.14 v1(113.1,166.46)
  TOP w0.254: PC747.1 114.86,164.65 v2(114.84,164.64) 114.84,164.44 114.61,164.21 113.67,164.21 PC746.2 PR740.2
  BOTTOM w0.203: v2(114.84,164.64) 115.26,164.22 115.63,164.22 115.87,164.46 115.87,165.07 115.95,165.16 PU703.31
N28714599: length 5.3
  TOP w0.254: PR772.2 PC745.2 113.65,163.8 v1(114.6,163.8) 114.84,163.8 115.43,164.4 v2(115.43,164.66) 115.43,164.97 PC747.2
  BOTTOM w0.203: v2(115.43,164.66) 115.55,164.79 PU703.32
N28714601: length 5.3
  BOTTOM w0.127: v1(116.71,161.42) 117.54,162.25 PC750.2
  BOTTOM w0.203: PU703.28 117.15,165.17 117.29,165.04 117.29,163.84 117.24,163.79 117.24,162.95 PC750.2
N28714604: length 31.9
  TOP w0.102: 137.41,176.95 137.41,177.03 137.42,177.04 v1(138.18,177.04)
  TOP w0.381: PR773.1 137.32,177.04 137.41,176.95 v2(137.41,176.88)
  IN1 w0.381: v2(119.72,164.97) 119.18,165.51 119.18,169.16 119.56,169.54 119.56,170.43 121.09,171.96 121.09,175.26 122.59,176.76 137.28,176.76 v2(137.41,176.88)
  BOTTOM w0.203: 118.55,164.97 118.35,165.17 PU703.25
  BOTTOM w0.381: 118.55,164.97 v2(119.72,164.97)
N28714608: length 2.8
  BOTTOM w0.203: PR745.1 119.09,163.88 118.79,164.18 118.43,164.18 117.95,164.65 PU703.26
N28714612:
  vias: v1(120.55,164.9)
N28714614: length 2.8
  BOTTOM w0.203: PU703.17 119.43,169.07 120.02,169.66 v1(120.02,169.66) 120.17,169.81 PR757.2
N28714617:
  vias: v1(109.16,174.74) v2(76.55,174.93) v2(76.6,174.35) v2(76.56,173.72) v2(77.21,174.93) v2(77.26,174.35) v2(77.22,173.72) v2(77.83,174.94) v2(77.87,174.31)
N28714625: length 11.4
  IN2 w0.254: v2(131.11,169.54) 127.68,169.54 127.41,169.81 125.69,169.81 v2(124.05,171.45)
  BOTTOM w0.254: PR757.1 122.43,170.36 122.88,170.8 122.88,171.18 v1(123.11,171.41) 123.12,171.4 124,171.4 v2(124.05,171.45) ; PR779.2 v2(131.11,169.54)
N28714637: length 1.4
  TOP w0.102: PR773.2 134.55,177.04 v1(134.05,177.53)
N28714684: length 0.8
  TOP w0.127: 70.48,163.37 70.48,162.7 v1(70.41,162.64)
N28714693:
  vias: v1(136.63,172.08) v2(133.53,157.35) v2(133.53,156.59) v2(134.3,157.35) v2(134.3,156.59) v2(134.74,174.37) v2(134.74,173.61) v2(134.74,172.85) v2(135.06,157.35) v2(135.06,156.59) v2(135.5,174.37) v2(135.5,173.61) v2(135.5,172.85) v2(135.82,157.35) v2(135.82,156.59) v2(136.26,172.85) v2(136.58,157.35) v2(136.58,156.59) v2(137.03,172.85) v2(137.34,157.35) v2(137.34,156.59) v2(137.79,172.85)
N28714721: length 21.3
  TOP w0.254: PR765.2 138.36,174.24 v2(138.74,173.86)
  IN2 w0.254: v2(138.74,173.86) 138.49,174.12 138.24,174.12 136.97,175.39 122.36,175.39 122.02,175.05 v2(122.02,174.07)
  BOTTOM w0.127: v2(138.74,173.86) v1(139.44,173.86)
  BOTTOM w0.254: v2(122.02,174.07) PR742.2
N28714724: length 23.6
  TOP w0.254: v2(138.74,174.62) 139.12,174.24 PR765.3
  IN2 w0.254: v2(119.33,174.05) 119.9,174.62 121.02,174.62 122.17,175.77 137.09,175.77 138.36,174.5 138.61,174.5 v2(138.74,174.62)
  BOTTOM w0.127: v2(138.74,174.62) v1(137.97,174.62)
  BOTTOM w0.254: PR776.2 v2(119.33,174.05)
N28714743: length 3.8
  TOP w0.127: v1(82.06,171.44) 82.06,170.68 81.79,170.41 PR738.1
  TOP w0.254: PR738.1 PR737.2 81.82,169.2 PQ709.2
N28714752: length 18.8
  TOP w0.254: v2(111.25,164.47) 111.25,163 111.56,162.69 PR772.1
  BOTTOM w0.254: v2(111.25,164.47) 111.12,164.59 110.17,164.59 v1(109.95,164.81) 109.66,165.1 109.66,166.47 108.96,167.17 108.96,172.97 111.25,175.26 111.25,176.78 111.05,176.97 PR703.2
N28714753: length 16.7
  TOP w0.254: PR740.1 112.07,165.35 111.82,165.1 v2(111.25,165.1)
  BOTTOM w0.254: PR703.3 111.88,176.97 111.6,176.7 111.6,175.11 109.31,172.83 109.31,167.38 v1(110.04,166.65) 110.04,165.35 110.42,164.97 111.12,164.97 v2(111.25,165.1)
N28714782: length 4
  BOTTOM w0.127: v1(138.35,162.31) 137.84,162.31 137.03,163.12 PR766.2
  BOTTOM w0.762: PC767.1 PR766.2
N28858046: length 5.8
  TOP w0.254: v2(80.84,168.72) 81.17,168.39 PQ709.3 ; PR744.1 v2(80.03,164.9)
  IN1 w0.254: v2(80.03,164.9) 80.03,164.93 80.84,165.75 v2(80.84,168.72)
N28858050: length 65
  TOP w0.254: PQ707.3 68.52,167.19 70.21,168.88 v1(70.21,171.03) v2(70.21,173.06)
  IN2 w0.254: v2(70.21,173.06) 70.25,173.1 124.26,173.1 v2(125.32,174.16)
  BOTTOM w0.254: PR722.2 125.3,174.17 v2(125.32,174.16)
N28895147: length 3.3
  BOTTOM w0.127: v1(31.9,42.36) PQ801.2
  BOTTOM w0.254: PR801.2 PC805.1 30.68,41.21 PQ801.2
N29144266: length 3.6
  TOP w0.127: v1(189.86,34.54) 189.87,34.56 RI1.1 190.82,36.76 JIO1.16
N29189918: length 3.1
  BOTTOM w0.203: v1(116.92,171.3) 116.93,171.3 ; 116.93,171.3 116.93,171.3 117.49,171.87 PR764.2 ; 116.93,171.3 117.15,171.07 PU703.13
N37640332: length 1.7
  TOP w0.102: RV2.2 171.81,135.63 v2(171.81,135.52)
  BOTTOM w0.102: v2(171.81,135.52) 171.69,135.65 UV1.N10
N37640410: length 9.1
  BOTTOM w0.089: UV1.AA22 161.69,129.76 161.43,129.5 158.82,129.5 158.39,129.07 155.75,129.07 155.56,129.26 154.33,129.26
  BOTTOM w0.102: RV3.1 153.43,129.26 v1(154.3,129.26)
  BOTTOM w0.127: 154.33,129.26 v1(154.3,129.26)
N37817724: length 10.1
  BOTTOM w0.089: UV1.Y22 162.09,130.47 161.34,129.73 158.78,129.73 158.3,129.25 155.84,129.25 154.89,130.21
  BOTTOM w0.102: 154.89,130.21 154.55,130.54 v1(154.32,130.54) 153.75,130.54 RV1.1
N38023415: length 4.3
  BOTTOM w0.102: CV96.1 184.82,139.76 RV36.2 184.82,138.89 RV37.2
  BOTTOM w0.127: RV36.2 184.82,139.76 185.3,140.23 185.3,141.67 v1(185.55,141.92)
N38028869: length 6.5
  TOP w0.102: v2(173.66,137.94) 174.32,137.29 175.77,137.29 v1(175.91,137.42) 175.98,137.49 176.83,137.49 177.11,137.21 177.78,137.21 CV98.2
  BOTTOM w0.102: UV1.K8 173.29,138.32 v2(173.66,137.94)
N38028873: length 5.5
  TOP w0.102: CV99.2 178.24,137.17 177.9,137.52 v1(177.43,137.52) 177.18,137.76 175.77,137.76 175.53,137.52 174.83,137.52 v2(174.47,137.88)
  BOTTOM w0.089: UV1.L7 174.09,137.5 v2(174.47,137.88)
N38028878: length 2.2
  TOP w0.102: CV98.1 RV40.2
  TOP w0.127: RV40.2 180.88,135.95 180.88,135.78 v1(181.32,135.33)
N38028880: length 0.9
  TOP w0.102: CV99.1 180.58,137.17 RV41.2
N38039273: length 4.5
  BOTTOM w0.102: UV5.L8 161.5,163.97 161.9,163.57 162.64,163.57
  BOTTOM w0.127: v1(165.47,163.67) RV46.1 164.06,163.57 162.64,163.57
N38046520: length 3.4
  BOTTOM w0.127: CV102.1 RV49.2 RV48.2 151.76,162.23 v1(151.19,161.66)
N38049955: length 5.7
  TOP w0.102: UV6.L8 156.1,163.97 155.74,163.62 153.95,163.62 RV47.1
  TOP w0.127: RV47.1 153.44,163.12 152.7,162.37 v1(151.4,162.37)
N38097860: length 2.8
  BOTTOM w0.127: CV135.1 RV55.2 RV54.2 v1(190.69,162.61)
N38342282: length 9.1
  IN2 w0.127: v2(160.08,138.81) 159.65,138.38 156.22,138.38 155.57,137.73 155.06,137.73 154.73,137.4 v2(154.04,137.4)
  BOTTOM w0.089: v2(160.08,138.81) 159.69,138.42 UV1.K25
  BOTTOM w0.127: v1(153.41,136.21) RV39.2 v2(154.04,137.4)
N40812716: length 3.3
  BOTTOM w0.127: v1(13.48,23.46) CR3.2
  BOTTOM w0.305: CR3.2 14.06,22.25 14.28,22.03 14.28,21.4 14.66,21.02
N43437408: length 10.2
  BOTTOM w0.102: 140.12,84.35 140.12,84.41 v1(139.9,84.63) 138.4,86.13 137.92,86.13 137.37,85.59 137.08,85.59 136.16,86.5 134.86,86.5 134.73,86.63 134.23,86.63 134.08,86.78 133.66,86.78 133.58,86.7 133.25,86.7 132.94,87.02 UC1.AY13
  BOTTOM w0.127: R450.2 140.26,84.2 140.12,84.35
N47415217: length 1.4
  TOP w0.127: PR103.1 v1(36.82,48.51)
N47415258: length 1.1
  BOTTOM w0.127: PC103.1 v1(34.59,45.16)
N47415272: length 1.1
  BOTTOM w0.127: PC111.1 v1(42.36,45.06)
N47415370: length 1.2
  TOP w0.127: PC110.1 v1(48.55,51.12)
N47420895: length 1.1
  BOTTOM w0.127: PC207.2 v1(75.76,13)
N47445410: length 2.8
  TOP w0.203: PU100.19 44.06,51.18 v2(44.57,51.69)
  BOTTOM w0.127: v2(44.57,51.69) 44.57,52.06 v1(44.71,52.2)
  BOTTOM w0.254: v2(44.57,51.69) 44.52,51.64 PR114.1
N55201771: length 24.2
  TOP w0.102: RX12.2 24.56,75.92 24.56,76.16 23.94,76.78 v2(23.75,76.78)
  IN1 w0.107: JHDMI.13 10.7,67.52 10.7,70.28 16.02,75.6 16.02,76.24 18.28,78.5 20.51,78.5 21.04,77.97 22.56,77.97 v2(23.75,76.78)
  BOTTOM w0.127: v2(23.75,76.78) v1(23.02,76.78)
N208512623: length 5.7
  TOP w0.127: v1(73.84,167.02) PQ740.4
  TOP w0.254: PQ740.4 73.84,165.32 74.09,165.07 76.7,165.07 77.11,165.48 PR778.1

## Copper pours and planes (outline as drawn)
0.95VS_GATE on BOTTOM (solid shape): 145.58,104.7 145.58,101.75 145.54,101.71 142.04,101.71 141.76,101.98 141.76,102.25 141.61,102.41 141.61,104.68 141.95,105.02 145.27,105.02
0.95VSDGPU_OUT on TOP (solid shape): 151.57,135.98 151.62,135.98 151.62,135.97 152.28,135.97 152.28,135.98 152.32,135.98 152.32,136.46 152.77,136.46 152.77,135.98 152.82,135.98 152.82,135.97 153.42,135.97 153.58,135.8 153.58,135.4 153.96,135.03 153.96,134.24 152.99,133.27 151.86,133.27 151.78,133.36 151.78,133.91 150.37,135.33 150.37,135.84 150.45,135.92 150.46,135.92 150.51,135.97 151.08,135.97 151.08,135.98 151.12,135.98 151.12,136.46 151.57,136.46
3VS on TOP (solid shape): 33.4,19.51 33.4,18.86 33.34,18.79 33.34,16.46 33.06,16.18 31.46,16.18 31.46,16.68 30.81,16.68 30.81,16.18 30.26,16.18 30.26,16.68 29.61,16.68 29.61,16.18 28.96,16.18 28.7,16.45 28.7,18.15 30.12,19.57 33.33,19.57
5VS on TOP (solid shape): 41.34,17.68 41.34,16.24 41.29,16.18 41.01,16.18 40.99,16.21 40.99,16.7 40.97,16.72 40.49,16.72 40.44,16.67 40.44,16.21 40.42,16.18 40.21,16.18 40.19,16.21 40.19,16.69 40.16,16.72 39.69,16.72 39.64,16.67 39.64,16.22 39.6,16.19 36.75,16.19 36.72,16.21 36.72,16.69 36.69,16.72 36,16.72 35.97,16.69 35.97,16.23 35.92,16.19 35.56,16.19 35.52,16.22 35.52,16.7 35.5,16.72 34.81,16.72 34.77,16.68 34.77,16.27 34.69,16.19 34.33,16.19 34.24,16.27 34.24,17.32 34.77,17.85 34.88,17.96 34.88,18.74 34.79,18.83 34.79,19.47 34.92,19.59 39.43,19.59
+0.95VALW on TOP (solid shape): 143.41,108.8 143.41,107.72 143.22,107.53 142.4,107.53 142.27,107.66 142.27,108.86 142.33,108.92 143.29,108.92
+0.95VALW on TOP (solid shape): 149.98,137.29 149.98,135.52 150.59,134.91 150.59,133.37 150.51,133.28 149.74,133.28 149.3,133.72 149.3,134.4 148.95,134.75 148.95,134.75 148.7,135 148.3,135 148.3,135 147.64,135 147.4,135.24 147.4,137.63 147.63,137.86 149.41,137.86
+0.95VALW on TOP (solid shape): 135.15,121.32 135.8,121.32 135.8,121.83 136.35,121.83 136.35,121.32 137,121.32 137,121.83 140.48,121.83 140.48,121.32 141.13,121.32 141.13,121.83 141.68,121.83 141.68,121.32 142.33,121.32 142.33,121.83 142.89,121.83 142.94,121.78 142.94,115.77 142.49,115.32 137.47,115.32 137.04,115.75 137.04,118.28 136.57,118.74 134.68,118.74 134.17,119.25 134.17,121.67 134.34,121.83 135.15,121.83
+0.95VALW on TOP (solid shape): outline of 709 points within 125.88,88.4 131.95,99.44
+0.95VALW on BOTTOM (solid shape): outline of 114 points within 141.6,107.95 151.25,111.51
+0.95VALW on IN1 (solid shape): outline of 94 points within 137.04,107.7 145.47,117.73
+0.95VALW on IN2 (solid shape): outline of 153 points within 141.03,115.7 149.15,137.79
+0.95VALWP on TOP (solid shape): 138.87,127 138.87,125.67 140.26,124.27 142.55,124.27 142.93,123.89 142.93,121.98 142.88,121.94 142.23,121.94 142.23,121.44 141.78,121.44 141.78,121.94 141.03,121.94 141.03,121.44 140.58,121.44 140.58,121.94 136.9,121.94 136.9,121.44 136.45,121.44 136.45,121.94 135.7,121.94 135.7,121.44 135.25,121.44 135.25,121.94 134.6,121.94 134.11,122.43 134.11,127.44 134.3,127.63 138.23,127.63
+0.95VALWP on BOTTOM (solid shape): 136.07,133.1 136.07,130.43 138.74,127.76 138.74,122.43 138.3,121.98 132.56,121.98 132.01,122.53 132.01,127.51 130.04,129.48 130.04,133.48 130.3,133.73 135.44,133.73
+0.95VS on TOP (solid shape): 151.13,79.33 151.13,75.38 150.87,75.12 149.15,75.12 146.53,77.74 146.53,79.34 146.77,79.58 150.88,79.58
+0.95VS on BOTTOM (solid shape): 154.23,104.01 154.23,101.92 154.11,101.79 146.96,101.79 146.14,102.62 146.14,105.21 146.54,105.61 152.64,105.61
+0.95VS on VCC: 147.61,74.8 141.03,81.39 141.03,109.37 141.51,109.85 152.86,109.85 156.27,106.45 156.27,86.72 150.55,81 150.55,76.73 151.31,75.97 151.31,75.16 150.95,74.8 ; 1 cut-out
+0.95VS_APU_GFX on TOP (solid shape): 121.34,93.85 121.34,92.84 121.09,92.58 120.33,92.58 120.07,92.84 119.06,92.84 118.29,93.6 118.29,93.98 118.42,94.11 121.09,94.11
+0.95VS_APU_GFX on TOP (solid shape): outline of 728 points within 130.18,77.98 148.59,83.74
+0.95VS_APU_GFX on BOTTOM (solid shape): 131.15,84.05 131.4,83.92 131.66,84.05 131.86,84.05 132.01,84 132.18,84.03 132.21,84.04 132.41,83.84 132.41,81.89 132.28,81.77 131.37,81.77 130.72,82.41 130.14,82.41 130.03,82.52 130.03,82.75 130.24,82.96 130.24,83.52 130.05,83.71 130.05,83.94 130.16,84.05
+0.95VS_APU_GFX on IN1 (solid shape): outline of 1575 points within 120.8,80.2 147.05,94.53
+0.95VSDGPU on TOP (solid shape): 153.54,138.43 153.54,136.14 153.47,136.08 153.42,136.08 152.97,136.08 152.97,136.08 152.87,136.08 152.87,136.57 152.22,136.57 152.22,136.08 151.68,136.08 151.68,136.57 151.02,136.57 151.02,136.08 150.36,136.08 150.3,136.14 150.3,138.25 150.79,138.75 153.22,138.75
+0.95VSDGPU on TOP (solid shape): 161.29,136.91 161.29,133.96 161.05,133.72 160.56,133.72 160.24,133.39 160.24,132.65 160.51,132.39 161.06,132.39 161.2,132.24 161.2,130.77 161.33,130.64 162.82,130.64 162.93,130.53 162.93,129.85 162.8,129.72 158.31,129.72 157.98,130.05 157.98,130.68 158.04,130.75 158.72,130.75 158.91,130.94 158.91,135.93 159.54,136.56 159.57,136.54 159.91,136.58 159.95,136.92 159.93,136.95 160.2,137.22 160.98,137.22
+0.95VSDGPU on BOTTOM (solid shape): outline of 351 points within 158.68,131.47 162.38,137.57
+0.95VSDGPU on IN2 (solid shape): outline of 517 points within 151.25,130.7 161.77,138.87
+0.675VS on TOP (solid shape): 63.94,27.56 63.94,26.29 63.68,26.03 61.4,26.03 61.27,26.16 61.27,27.3 61.78,27.81 63.68,27.81
+0.675VS on TOP (solid shape): 144.43,36.98 144.43,32.16 144.96,31.62 144.96,28.57 145.22,28.32 147.12,28.32 147.63,28.83 151.19,28.83 152.71,27.3 152.71,17.02 152.58,16.89 151.44,16.89 151.19,17.14 151.19,22.61 151.57,22.99 151.57,26.29 150.04,27.81 148.14,27.81 147.76,27.43 143.82,27.43 143.57,27.69 143.57,29.08 143.06,29.59 143.06,31.5 143.17,31.6 143.17,32.45 143.17,32.49 143.17,32.53 143.17,33.03 143.17,33.08 143.17,33.12 143.17,37.2 143.31,37.35 144.06,37.35
+0.675VS on BOTTOM (solid shape): 144.14,30.73 144.14,27.81 143.95,27.62 143.63,27.62 143.44,27.81 143.44,30.92 143.5,30.99 143.88,30.99
+0.675VS on BOTTOM (solid shape): 153.35,17.91 153.35,16.89 152.2,15.75 151.69,15.75 151.57,15.88 151.57,17.78 151.82,18.03 153.22,18.03
+0.675VS on BOTTOM (solid shape): 144.21,39.04 144.21,36.52 143.9,36.21 143.4,36.21 143.1,36.5 143.1,38.99 143.31,39.19 144.05,39.19
+0.675VS on IN2 (solid shape): 64.19,26.92 64.19,26.23 64.06,26.1 62.1,26.1 61.91,26.29 61.91,26.8 62.22,27.11 64,27.11
+0.675VS on IN2 (solid shape): 152.96,17.78 152.96,16 152.77,15.81 152.14,15.81 151.89,16.07 151.89,17.84 152.08,18.03 152.71,18.03
+0.675VSP on TOP (solid shape): 61.84,25.27 63.24,25.27 63.24,25.84 65.14,25.84 65.53,25.46 65.53,22.16 65.46,22.1 64.22,22.1 63.58,22.73 63.58,22.75 63.42,22.91 62.92,22.91 62.68,22.67 62.68,22.31 62.53,22.16 61.78,22.16 61.72,22.22 61.72,22.66 62.35,23.29 62.35,23.62 62.16,23.81 61.4,23.81 61.11,23.52 61.11,22.67 61.04,22.61 60.95,22.61 60.89,22.67 60.89,25.4 61.33,25.84 61.84,25.84
+0.775VALW on TOP (solid shape): 27.23,44.32 27.23,43.56 27.11,43.43 26.28,43.43 26.09,43.62 26.09,44.39 26.47,44.77 26.79,44.77
+0.775VALW on TOP (solid shape): 57.95,57.15 57.95,56.64 57.82,56.51 56.17,56.51 56.11,56.58 56.11,57.15 56.24,57.28 57.82,57.28
+0.775VALW on BOTTOM (solid shape): 58.35,57.09 58.35,50.16 58.22,50.04 57.84,50.04 57.78,50.1 57.78,50.93 57.46,51.24 57.46,52.58 56.32,53.72 56.32,56.98 56.83,57.49 57.94,57.49
+0.775VALW on BOTTOM (solid shape): 26.58,44.79 26.58,44.73 27.13,44.73 27.13,45.28 27.38,45.28 27.38,44.79 27.39,44.79 27.39,44.7 28.19,44.7 28.25,44.64 28.25,43.62 28.08,43.45 25.82,43.45 25.65,43.62 25.65,44.58 25.77,44.7 26.34,44.7 26.34,45.28 26.58,45.28
+1.5VS on TOP (solid shape): 47.36,8.83 47.36,6.92 47.11,6.67 45.08,6.67 44.95,6.79 44.95,7.25 45.44,7.25 45.44,7.7 44.95,7.7 44.95,8.05 45.44,8.05 45.44,8.5 44.95,8.5 44.95,8.95 45.08,9.08 47.11,9.08
+1.5VS on BOTTOM (solid shape): 48,8.25 48,7.43 47.87,7.3 45.97,7.3 45.78,7.49 45.78,8.13 45.97,8.32 47.94,8.32
+1.5VS on BOTTOM (solid shape): 155.53,70.81 155.53,69.03 155.12,68.61 153.8,68.61 153.72,68.69 153.72,71.86 153.85,71.98 154.37,71.98
+1.5VS on BOTTOM (solid shape): 161.92,9.02 161.92,8.57 161.79,8.45 160.33,8.45 159.89,8.89 159.89,9.59 160.2,9.91 161.03,9.91
+1.5VSP on TOP (solid shape): 44.79,8.92 44.79,8.42 44.81,8.4 45.33,8.4 45.33,8.15 44.8,8.15 44.79,8.14 44.79,7.6 44.8,7.6 45.33,7.6 45.33,7.36 44.79,7.36 44.79,6.83 44.63,6.67 43.87,6.67 43.17,7.37 41.27,7.37 40.63,6.73 40.63,6.29 40.44,6.1 38.86,6.1 38.66,6.29 38.66,8.13 39.3,8.76 42.79,8.76 43.11,9.08 44.63,9.08
+1.8V_ALW on TOP (solid shape): 150.56,131.84 150.56,131.04 149.98,130.45 149.98,129.64 149.68,129.34 149.63,129.34 149.5,129.2 149.5,129.16 148.75,128.41 147.31,128.41 146.74,128.98 146.74,129.93 147.29,130.48 147.89,130.48 148.08,130.67 148.09,130.67 148.33,130.82 148.39,131.1 148.41,131.18 148.49,131.22 148.91,131.22 149.55,131.86 150.16,131.86 150.24,131.87 150.32,131.9 150.33,131.9 150.5,131.9
+1.8V_ALW on TOP (solid shape): 150.86,123.98 150.86,123.52 150.29,122.95 150.29,121.73 150.48,121.54 150.48,118.19 149.69,117.4 148.32,117.4 147.41,118.3 147.41,120.84 148.06,121.49 148.06,122.7 148.1,122.71 148.33,122.95 148.26,123.28 148.24,123.34 148.26,123.41 148.34,123.65 148.24,123.89 148.21,123.96 148.24,124.03 148.37,124.16 150.68,124.16
+1.8V_ALW on BOTTOM (solid shape): 157.79,85.17 157.79,84.26 157.72,84.18 156.59,84.18 156.39,84.38 156.39,85.15 156.55,85.31 157.66,85.31
+1.8V_ALW on BOTTOM (solid shape): 155.12,53.66 155.12,51.94 154.93,51.75 154.3,51.75 154.3,52.32 152.9,52.32 152.9,51.75 152.52,51.75 152.33,51.94 152.33,53.53 152.58,53.78 155,53.78
+1.8V_ALW on IN1 (solid shape): 156.08,54.22 156.08,52.55 155.8,52.27 152.8,52.27 152.49,52.58 152.49,54.06 152.8,54.36 155.93,54.36
+1.8V_ALW on IN1 (solid shape): 157.18,110.77 157.18,109.08 156.97,108.86 155.15,108.86 155.03,108.98 155.03,111.04 155.38,111.39 156.57,111.39
+1.8V_ALW on IN1 (solid shape): 157.19,103.71 157.19,102.22 157.16,102.18 157.16,101.05 157.09,100.99 155.28,100.99 155.1,101.17 155.1,103.96 155.31,104.18 156.72,104.18
+1.8V_ALW on IN1 (solid shape): 154.93,92.25 154.93,91.89 156.92,89.9 156.92,89.3 156.88,89.22 156.79,89.2 156.39,89.01 156.56,88.59 156.43,88.1 156.92,88.05 156.92,87.56 156.89,87.49 156.81,87.46 156.43,87.13 156.81,86.81 156.89,86.78 156.92,86.71 156.92,86.66 156.88,86.57 156.78,86.56 156.35,86.43 156.4,85.98 156.92,85.45 156.92,83.28 156.19,82.55 155.04,82.55 154.11,83.48 154.11,86.54 153.2,87.45 153.2,88.54 152.16,89.58 152.16,91.97 152.79,92.6 154.58,92.6
+1.8V_ALW on IN2 (solid shape): 151.59,118.17 151.59,117.54 150.49,116.43 149.94,116.43 148.82,117.56 148.82,118.73 149.8,119.71 150.06,119.71
+1.8V_ALW on IN2 (solid shape): 157.31,112.1 157.31,110.1 156.91,109.7 155.54,109.7 154.92,110.32 154.92,112.29 155.19,112.56 156.85,112.56
+1.8V_ALWP on BOTTOM (solid shape): 157.66,51.12 157.66,48.89 157.41,48.64 154.04,48.64 153.28,47.88 153.28,46.86 153.22,46.8 152.52,46.8 152.46,46.86 152.46,51.37 152.65,51.56 157.22,51.56
+1.8VGS on TOP (solid shape): 189.89,136.04 189.89,134.62 189.81,134.54 187.9,134.54 187.68,134.76 187.68,135.77 187.99,136.09 189.83,136.09
+1.8VGS on TOP (solid shape): 154.63,123.04 157.88,123.04 157.97,122.94 157.97,121.34 157.83,121.2 156.36,121.2 156.26,121.29 153.39,121.29 153.12,121.56 153.12,122.72 152.9,122.94 152.44,122.94 152.09,123.29 152.09,123.86 152.29,124.07 153.6,124.07
+1.8VGS on TOP (solid shape): 170.48,121.35 171.14,121.35 171.22,121.27 171.22,120.13 170.95,119.85 168.44,119.85 168.4,119.81 167.8,119.81 167.01,120.6 165.12,120.6 164.99,120.74 164.99,120.92 167.96,120.92 167.96,120.87 167.96,120.82 167.98,120.77 168,120.72 168.03,120.68 168.07,120.65 168.11,120.61 168.16,120.59 168.21,120.57 168.26,120.57 168.31,120.57 168.36,120.57 168.41,120.59 168.46,120.61 168.5,120.65 168.54,120.68 168.57,120.72 168.59,120.77 168.61,120.82 168.62,120.87 168.62,120.92 168.61,120.97 168.59,121.02 168.57,121.07 168.54,121.11 168.5,121.15 168.46,121.18 168.41,121.2 168.36,121.22 168.31,121.23 168.26,121.23 168.21,121.22 168.16,121.2 168.11,121.18 168.07,121.15 168.03,121.11 168,121.07 167.98,121.02 167.96,120.97 167.96,120.92 164.99,120.92 164.99,121.21 165.13,121.35 169.18,121.35 169.19,121.36 170.47,121.36
+1.8VGS on BOTTOM (solid shape): 156.79,122.47 156.79,121.76 156.93,121.61 156.93,120.96 156.8,120.83 156.29,120.83 155.78,121.34 155.78,121.88 156.12,122.22 156.12,122.38 156.35,122.6 156.65,122.6
+1.8VGS on BOTTOM (solid shape): 194.94,145.48 194.94,145.03 194.45,145.03 194.45,144.57 194.94,144.57 194.94,144.23 194.45,144.23 194.45,143.77 194.94,143.77 194.94,143.32 194.75,143.13 193.35,143.13 193.1,143.38 193.1,145.41 193.22,145.54 194.87,145.54
+1.8VGS on IN2 (solid shape): 194.12,145.39 194.12,144.18 193.9,143.97 192.16,143.97 191.95,144.18 191.95,145.1 192.44,145.59 193.92,145.59
+1.8VGS on IN2 (solid shape): outline of 388 points within 155.9,120.75 179.27,125.5
+1.8VGSP on BOTTOM (solid shape): 198.48,144.72 199.76,144.72 200.64,143.84 200.64,139.97 199.22,138.56 195.64,138.56 195.51,138.68 195.51,140.59 195.09,141 195.09,143.87 194.56,143.87 194.55,143.88 194.55,144.12 195.09,144.12 195.09,144.66 195.08,144.67 194.55,144.67 194.55,144.92 195.04,144.92 195.1,144.99 195.1,145.41 195.23,145.54 197.66,145.54
+1.8VS on TOP (solid shape): 151.35,67.04 151.35,65.84 150.88,65.37 148.94,65.37 148.74,65.57 148.74,66.45 149.47,67.18 151.21,67.18
+1.8VS on TOP (solid shape): 156.76,67.81 156.76,66.37 156.23,65.84 155.12,65.84 154.93,66.03 154.93,67.56 155.6,68.22 156.34,68.22
+1.8VS on TOP (solid shape): 153.03,128.91 153.03,126.62 152.96,126.55 149.89,126.55 149.6,126.84 149.6,129.16 149.68,129.24 150.49,129.24 150.56,129.24 150.56,128.73 151.01,128.73 151.01,129.24 151.36,129.24 151.36,128.73 151.81,128.73 151.81,129.19 151.87,129.25 152.69,129.25
+1.8VS on TOP (solid shape): 129.45,85.74 129.45,83.37 129.4,83.33 129.36,83.36 128.91,83.5 128.77,83.05 128.79,83.02 128.72,82.94 128.68,82.94 128.35,82.61 127.75,82.61 127.64,82.72 127.64,84.42 127.78,84.57 128.2,84.57 128.6,84.97 128.6,85.68 128.7,85.78 129.41,85.78
+1.8VS on BOTTOM (solid shape): 95.57,83.35 95.57,82.25 95.5,82.17 93.88,82.17 93.76,82.3 93.76,83.2 93.82,83.26 94.94,83.26 95.11,83.43 95.5,83.43
+1.8VS on BOTTOM (solid shape): 129.32,84.45 129.32,84.25 129.08,84.01 128.91,84.01 128.48,84.06 128.43,83.63 128.43,83.29 128.14,82.99 127.46,82.99 127.29,83.17 127.29,84.45 127.48,84.65 129.13,84.65
+1.8VS on BOTTOM (solid shape): outline of 138 points within 50.35,62.04 63.32,73.02
+1.8VS on IN1 (solid shape): 149.62,111.15 149.62,109.88 149.12,109.37 148.09,109.37 147.77,109.69 147.77,111.2 147.92,111.35 149.42,111.35
+1.8VS on IN1 (solid shape): 150.26,67.88 150.26,65.93 149.76,65.43 148.91,65.43 148.75,65.6 148.75,67.81 148.95,68.01 150.13,68.01
+1.8VS on IN1 (solid shape): 152.39,128.64 152.39,120.55 152.27,120.43 151.95,120.43 149.82,122.56 149.82,127.94 149.78,127.98 149.78,128.02 149.55,128.25 149.55,129.08 149.71,129.25 151.78,129.25
+1.8VS on IN1 (solid shape): 156.42,74.04 156.42,68.78 156.94,68.26 156.94,67.09 156.61,66.76 155.5,66.76 155.04,67.23 155.04,70.01 155.05,70.04 155.07,70.09 155.07,70.14 155.07,70.2 155.06,70.25 155.05,70.3 155.03,70.35 155,70.39 154.96,70.43 154.92,70.46 154.87,70.49 154.83,70.51 154.77,70.52 154.72,70.52 154.67,70.52 154.62,70.51 154.57,70.49 154.51,70.46 154.18,70.79 154.18,72.38 155.14,72.38 155.14,72.33 155.14,72.27 155.16,72.23 155.18,72.18 155.21,72.14 155.25,72.1 155.29,72.07 155.34,72.05 155.39,72.03 155.44,72.02 155.49,72.02 155.54,72.03 155.59,72.05 155.64,72.07 155.68,72.1 155.72,72.14 155.75,72.18 155.77,72.23 155.79,72.27 155.8,72.33 155.8,72.38 155.79,72.43 155.77,72.48 155.75,72.52 155.72,72.57 155.68,72.6 155.64,72.63 155.59,72.66 155.54,72.67 155.49,72.68 155.44,72.68 155.39,72.67 155.34,72.66 155.29,72.63 155.25,72.6 155.21,72.57 155.18,72.52 155.16,72.48 155.14,72.43 155.14,72.38 154.18,72.38 154.18,73.67 154.63,74.12 156.34,74.12
+1.8VS on IN1 (solid shape): outline of 478 points within 126.99,76.07 147.31,84.52
+1.8VS on IN2 (solid shape): 152.33,121.74 152.33,120.41 152.13,120.21 149.99,120.21 148.75,118.96 148.75,118.8 148.72,118.77 148.72,117.52 148.75,117.48 148.75,117.44 150.11,116.08 150.11,111.12 149.76,110.78 148.02,110.78 147.71,111.09 147.71,113.84 146.73,114.82 146.73,121.2 147.14,121.6 148.1,121.6 148.11,121.6 148.66,122.15 151.92,122.15
+1.8VS_LS on TOP (solid shape): 153.16,131.58 153.16,129.66 152.88,129.38 151.72,129.38 151.72,129.24 151.71,129.24 151.71,128.84 151.46,128.84 151.46,129.34 150.91,129.34 150.91,128.84 150.67,128.84 150.67,129.38 150.18,129.38 150.12,129.44 150.12,130.42 150.58,130.88 151.46,130.88 151.81,131.23 151.81,131.83 151.87,131.89 152.84,131.89
+1.35V on TOP (solid shape): outline of 11883 points within 80.07,14.35 130.41,78.26
+1.35V on BOTTOM (solid shape): 115.15,23.69 115.15,22.94 114.98,22.77 114.65,22.77 114.5,22.62 113.34,22.62 112.75,23.2 112.75,23.61 112.96,23.82 115.02,23.82
+1.35V on BOTTOM (solid shape): 119.48,40.6 119.48,39.4 119.41,39.33 104.7,39.33 104.47,39.57 104.47,40.72 104.58,40.83 105.49,40.83 105.61,40.95 119.14,40.95
+1.35V on BOTTOM (solid shape): 120.47,23.64 120.47,23.48 120.27,23.28 117.39,23.28 117.28,23.3 117.17,23.28 116.68,23.28 116.53,23.42 116.53,23.63 116.72,23.81 120.3,23.81
+1.35V on BOTTOM (solid shape): 115.9,31.41 115.9,31.12 115.82,31.04 115.53,31.04 115.4,31.08 115.27,31.04 114.93,31.04 114.8,31.08 114.67,31.04 114.53,31.04 114.46,31.11 113.92,31.11 113.83,31.2 113.83,31.45 113.96,31.58 115.72,31.58
+1.35V on BOTTOM (solid shape): 125.58,23.54 125.58,23.3 125.36,23.08 124.78,23.08 124.45,23.38 124.12,23.08 122.26,23.08 122.13,23.21 122.13,23.57 122.33,23.77 125.35,23.77
+1.35V on BOTTOM (solid shape): 126.31,15.64 126.35,15.63 126.38,15.6 126.68,15.02 127.09,15.54 127.12,15.55 127.15,15.56 127.89,15.56 127.99,15.46 127.99,15.12 127.99,15.11 127.99,13.69 127.69,13.4 112.58,13.4 112.13,13.84 112.13,15.32 112.45,15.64
+1.35V on BOTTOM (solid shape): 106.74,33.13 106.9,32.73 107.31,32.56 109.16,32.56 109.75,31.97 110.34,31.97 110.78,32.17 110.91,32.63 110.94,32.66 111.57,32.66 111.65,32.58 111.96,32.42 112.31,32.47 112.35,32.49 112.43,32.41 112.47,32.41 112.47,31.38 112.29,31.2 104.81,31.2 104.67,31.34 104.67,32 104.8,32.25 104.78,32.53 104.78,33.08 104.88,33.18 106.74,33.18
+1.35V on VCC: 112.68,14.99 111.05,16.62 111.05,22.71 109.78,23.98 109.78,24.62 109.66,24.74 109.66,25.2 108.57,26.29 107.04,26.29 106.1,27.23 106.1,27.41 105.09,28.43 105.09,29.19 103.41,30.86 102.91,30.86 101.97,31.79 101.97,52.66 106.86,57.55 106.86,64.92 111.92,69.98 112.68,69.98 113.72,71.01 113.72,77.87 114.08,78.23 129.09,78.23 129.09,71.48 128.83,71.23 128.83,68.09 129.53,67.4 129.53,59.2 129.79,58.95 129.79,39.03 126.68,35.92 126.68,34.4 126.44,34.16 125.17,34.16 124.26,33.25 124.26,26.82 125.91,25.17 125.91,21.48 127.56,19.83 127.56,15.47 127.08,14.99
+1.35V on GND: 112.12,14.73 111.05,15.8 111.05,22.15 109.66,23.55 109.66,25.71 109.08,26.29 107.55,26.29 105.77,28.07 105.27,28.07 104.32,29.01 104.32,31.68 103.56,32.44 103.56,38.68 105.14,40.26 105.32,40.26 108.51,43.46 108.51,52.09 111.44,55.01 111.44,62.51 113.21,64.28 113.21,70.34 113.1,70.45 113.85,71.19 113.85,72.08 114.1,72.34 114.1,73.23 114.54,73.66 120.91,73.66 121.67,72.9 122.41,72.9 123.17,73.66 126.12,73.66 126.55,73.23 126.55,70.69 127.06,70.18 127.06,68.76 126.12,67.82 125.94,67.82 119.18,61.07 119.18,37.74 119.33,37.59 119.51,37.59 121.47,35.63 121.47,32.06 120.71,31.29 120.71,29.79 121.61,28.89 122.69,28.89 124.15,27.43 125.23,27.43 127.18,25.47 127.18,23.87 126.55,23.23 126.55,20.27 127.18,19.63 127.18,15.17 126.75,14.73
+1.35V_MEM_GFX on TOP (solid shape): outline of 708 points within 160.59,136.28 179.42,141.42
+1.35V_MEM_GFX on BOTTOM (solid shape): 193.35,152.1 194,152.1 194,152.59 194.55,152.59 194.55,152.1 195.2,152.1 195.2,152.59 195.76,152.59 195.89,152.46 195.89,150.56 195.55,150.22 192.75,150.22 192.33,150.63 192.33,152.46 192.46,152.59 193.35,152.59
+1.35V_MEM_GFX on BOTTOM (solid shape): 161.77,166.04 161.81,166.12 161.91,166.13 161.98,166.11 162.21,165.87 162.21,165.43 162.13,165.3 162.11,165.16 162.09,165.08 162.01,165.05 161.85,164.98 161.76,164.82 161.72,164.75 161.65,164.73 161.6,164.73 161.5,164.83 161.5,164.84 161.45,164.94 161.38,165.01 161.33,165.08 161.36,165.16 161.38,165.19 161.38,165.35 161.49,165.5 161.48,165.69 161.47,165.7 161.47,165.76 161.55,165.76 161.77,165.98
+1.35V_MEM_GFX on BOTTOM (solid shape): 157.97,161.42 159.14,161.42 159.37,161.64 159.41,161.63 159.49,161.56 159.46,161.46 159.12,161.11 159.09,161.12 158.79,160.56 159.34,160.87 159.34,160.9 159.86,161.42 160.2,161.42 160.29,161.34 160.41,161.3 160.48,161.27 160.5,161.19 160.6,160.94 160.85,160.84 160.92,160.82 160.94,160.71 160.9,160.7 160.6,160.61 160.51,160.31 160.49,160.26 160.45,160.25 160.41,160.25 160.37,160.26 160.35,160.31 159.97,160.7 159.75,160.19 159.78,160.16 159.42,159.8 159.34,159.79 159.3,159.77 159.19,159.8 159.08,159.82 158.7,159.82 158.62,159.85 158.6,159.93 158.59,160.08 158.52,160.2 158.49,160.27 158.52,160.34 158.55,160.74 158.17,160.88 158.09,160.9 158.04,160.98 157.95,161.2 157.73,161.31 157.71,161.31 157.5,161.52 157.5,161.54 157.44,161.75 157.25,161.85 157.18,161.88 157.16,161.95 157.16,161.99 157.18,162.07 157.25,162.1 157.28,162.1
+1.35V_MEM_GFX on IN1 (solid shape): outline of 290 points within 154.77,136 163.37,139.88
+1.35V_MEM_GFX on VCC: 150.15,136.02 146.74,139.42 146.74,145.82 148.39,147.47 148.39,166.52 155.99,174.12 189.18,174.12 196.4,166.9 196.4,136.5 195.91,136.02
+1.35VGPUP on BOTTOM (solid shape): 200.46,156.84 201.1,156.84 201.16,156.78 201.16,153.61 196.65,153.61 195.75,152.7 195.15,152.7 195.15,152.69 195.1,152.69 195.1,152.21 194.65,152.21 194.65,152.69 194.6,152.69 194.6,152.7 193.95,152.7 193.95,152.69 193.9,152.69 193.9,152.21 193.45,152.21 193.45,152.69 193.4,152.69 193.4,152.7 192.8,152.7 192.72,152.78 192.72,152.78 192.65,152.84 192.65,153.67 193.67,154.69 193.67,157.67 199.64,157.67
+1.35VP on TOP (solid shape): 63.56,22.59 63.56,22.07 63.28,21.79 61.74,21.79 61.69,21.84 61.69,21.93 61.77,22.01 62.59,22.01 62.82,22.24 62.82,22.54 63.05,22.77 63.38,22.77
+1.35VP on TOP (solid shape): 79.94,26.92 79.94,18.03 79.69,17.78 75.69,17.78 74.99,18.48 74.99,26.67 75.49,27.18 79.69,27.18
+1.35VP on BOTTOM (solid shape): 80.57,26.29 80.57,21.46 79.94,20.83 76.38,20.83 76.13,21.08 76.13,26.29 76.76,26.92 79.94,26.92
+3VALW on TOP (solid shape): 33.97,53.28 33.97,52.77 32.82,51.63 32.63,51.63 32.12,52.13 32.12,52.32 33.33,53.53 33.71,53.53
+3VALW on TOP (solid shape): 54.98,81.35 54.98,79.82 54.92,79.76 52.89,79.76 52.7,79.95 52.7,81.26 52.94,81.5 54.83,81.5
+3VALW on TOP (solid shape): 36.8,173.79 36.8,171.47 36.78,171.44 35.96,171.44 35.59,171.81 34.46,171.81 34.03,172.25 34.03,174.13 34.15,174.25 36.34,174.25
+3VALW on TOP (solid shape): 158.48,37.67 158.48,28.23 159.59,27.11 159.59,21.48 159.34,21.22 156.01,21.22 154.47,22.76 154.47,37.13 155.19,37.85 158.3,37.85
+3VALW on TOP (solid shape): 34.79,11.81 34.79,10.79 34.62,10.63 34.11,10.63 34.11,10.11 34.09,10.09 33.86,10.09 33.86,10.64 33.31,10.64 33.31,10.09 33.06,10.09 33.06,10.63 32.48,10.63 32.31,10.79 32.31,12.26 32.63,12.57 34.03,12.57
+3VALW on TOP (solid shape): 200.84,137.99 200.84,135.64 200.65,135.45 199.51,135.45 199.23,135.72 199.23,136.38 199.17,136.44 198.68,136.44 198.68,136.7 199.2,136.7 199.22,136.72 199.22,137.23 199.21,137.24 198.68,137.24 198.68,137.5 199.22,137.5 199.22,137.5 199.22,138.05 199.47,138.3 200.53,138.3
+3VALW on TOP (solid shape): 38.66,29.46 38.66,26.67 38.16,26.16 32.95,26.16 32.38,25.59 31.44,25.59 31.3,25.45 31.3,23.34 31.84,22.8 33.01,22.8 33.39,22.42 33.39,20.89 33.33,20.83 29.52,20.83 29.27,21.08 29.27,23.37 28.76,23.88 28.76,29.84 29.01,30.1 38.03,30.1
+3VALW on BOTTOM (solid shape): 197.39,78.93 197.39,78.09 196.69,77.39 195.28,77.39 195.14,77.53 195.14,78.68 195.62,79.16 197.16,79.16
+3VALW on BOTTOM (solid shape): 32.82,13.53 32.82,12.95 33.33,12.45 33.33,12.06 32.82,11.56 32.44,11.56 31.81,12.19 31.81,13.53 31.93,13.65 32.7,13.65
+3VALW on BOTTOM (solid shape): 198.29,173.88 198.29,171.91 198.16,171.78 197.85,171.78 197.85,172.35 197.34,172.35 197.34,171.78 196.96,171.78 196.89,171.84 196.89,173.93 197.03,174.07 198.1,174.07
+3VALW on BOTTOM (solid shape): 34.28,54.61 34.28,53.28 34.79,52.77 34.79,52.2 34.63,52.04 34.13,52.04 34.11,52.02 34.11,51.52 34.08,51.49 33.86,51.49 33.86,52.03 33.85,52.04 33.33,52.04 33.31,52.02 33.31,51.49 33.06,51.49 33.06,51.98 32.99,52.05 32.28,52.05 30.85,53.47 26.73,53.47 26.54,53.66 26.54,55.88 26.85,56.2 32.7,56.2
+3VALW on BOTTOM (solid shape): 180.46,39.81 180.46,39.44 176.5,35.47 172.8,35.47 172.77,35.43 166.93,35.43 165.95,34.45 165.95,33.2 165.9,33.15 162.88,33.15 162.56,33.47 155.52,33.47 154.82,34.17 154.82,37.24 155.2,37.62 155.98,37.62 156,37.63 156,38.17 156.25,38.17 156.25,37.64 156.26,37.63 156.79,37.63 156.8,37.63 156.8,38.17 157.04,38.17 157.04,37.66 163.56,37.66 164.32,38.42 167.91,38.42 167.93,38.39 168.23,38.19 168.53,38.39 168.55,38.42 175.44,38.42 176.59,39.56 176.59,40.07 176.9,40.39 179.89,40.39
+3VALW on BOTTOM (solid shape): 183.62,75.75 183.92,75.75 184.12,75.55 184.12,74.4 183.85,74.13 183.71,74.13 183.72,74.2 183.39,74.65 183.01,74.25 183.09,74.05 183.27,73.93 183.35,73.86 183.32,73.76 183.09,73.53 180.97,73.53 180.9,73.6 180.9,75.44 180.97,75.5 182.76,75.5 183.15,75.9 183.48,75.9
+3VALW on BOTTOM (solid shape): 28.72,27.39 29.37,27.39 29.37,27.88 29.92,27.88 29.92,27.39 30.57,27.39 30.57,27.88 33.93,27.88 33.93,27.39 34.58,27.39 34.58,27.88 35.13,27.88 35.13,27.39 35.78,27.39 35.78,27.88 36.43,27.88 36.76,27.56 36.76,26.48 34.66,24.38 28.5,24.38 27.46,25.43 27.46,26.49 27.88,26.49 27.88,26.44 27.89,26.39 27.91,26.34 27.93,26.29 27.96,26.25 28,26.21 28.04,26.18 28.09,26.16 28.14,26.14 28.19,26.14 28.24,26.14 28.29,26.14 28.34,26.16 28.39,26.18 28.43,26.21 28.46,26.25 28.5,26.29 28.52,26.34 28.54,26.39 28.54,26.44 28.54,26.49 28.54,26.54 28.52,26.59 28.5,26.64 28.46,26.68 28.43,26.72 28.39,26.75 28.34,26.77 28.29,26.79 28.24,26.8 28.19,26.8 28.14,26.79 28.09,26.77 28.04,26.75 28,26.72 27.96,26.68 27.93,26.64 27.91,26.59 27.89,26.54 27.88,26.49 27.46,26.49 27.46,27.65 27.7,27.88 28.72,27.88
+3VALW on IN1 (solid shape): 157.16,37.66 157.16,36.26 156.52,35.62 155.06,35.62 154.49,36.19 154.49,37.88 154.7,38.1 156.71,38.1
+3VALW on IN1 (solid shape): 139.68,93.91 139.7,93.81 139.39,93.48 139.48,93.14 139.59,93.03 139.59,90.75 139.62,90.61 139.71,90.49 139.74,90.38 139.64,90.31 137.62,90.31 137.15,90.79 137.15,92.14 138.02,93.01 138.02,93.03 138.99,94 139.58,94
+3VALW on IN2 (solid shape): 37.08,174.05 37.08,173.48 36.51,172.91 35.74,172.91 35.55,173.1 35.55,173.8 36.25,174.5 36.63,174.5
+3VALW on IN2 (solid shape): 197.54,174.82 197.54,172.66 196.72,171.83 196.27,171.83 195.89,172.21 195.89,172.59 196.46,173.16 196.46,174.69 196.78,175.01 197.35,175.01
+3VALW on IN2 (solid shape): 201.35,138.11 201.35,135.06 201.16,134.87 199.95,134.87 199.57,135.25 199.57,138.49 199.89,138.81 200.65,138.81
+3VALW on IN2 (solid shape): 197.61,81.03 197.61,78.07 197.36,77.83 195.74,77.83 195.52,78.04 195.52,79.5 196.03,80.01 196.03,80.32 196.13,80.46 196.15,80.62 196.12,80.73 196.05,80.83 196.03,80.84 196.03,80.9 196.35,81.22 197.41,81.22
+3VALW_EC on TOP (solid shape): 175.63,68.13 175.63,68.02 175.44,67.83 175.44,66.46 175.63,66.27 175.63,66.19 176.16,65.66 176.24,65.66 176.28,65.62 177.52,65.62 177.6,65.63 177.68,65.66 178.35,65.66 178.41,65.6 178.41,65.44 177.72,64.75 176.29,64.75 176,64.47 176,63.08 175.22,62.29 174.55,62.29 174.43,62.42 174.43,62.8 174.7,63.08 174.7,68.11 174.8,68.21 175.55,68.21
+3VALWP on BOTTOM (solid shape): 37.14,33.15 37.14,28.57 36.55,27.99 35.68,27.99 35.68,27.49 35.23,27.49 35.23,27.99 34.48,27.99 34.48,27.49 34.03,27.49 34.03,27.99 30.47,27.99 30.47,27.49 30.02,27.49 30.02,27.99 29.27,27.99 29.27,27.49 28.82,27.49 28.82,27.99 28.08,27.99 27.49,28.57 27.49,33.21 28,33.72 36.57,33.72
+3VGS on BOTTOM (solid shape): 191.08,143.95 191.08,143.69 190.52,143.69 190.52,143.19 191.08,143.19 191.08,142.94 190.29,142.94 190.29,141.35 190.28,141.34 190.28,140.53 190.52,140.29 190.52,139.99 190.62,139.74 190.91,139.62 190.93,139.59 190.93,139.08 190.77,138.93 189.96,138.93 189.81,139.08 189.81,139.42 189.62,139.61 188.99,139.61 188.48,140.12 188.48,140.39 188.06,140.81 187.72,140.81 187.52,140.6 187.52,140.04 187.42,139.94 186.34,139.94 186.15,140.13 186.16,140.16 186.17,140.24 186.15,140.33 186.15,140.34 186.15,141.8 188.41,144.06 190.98,144.06
+3VGS on IN2 (solid shape): 178.06,133.15 178.06,129.62 177.36,128.92 175.74,128.92 175.59,129.06 175.59,129.09 175.5,129.37 175.22,129.46 175.2,129.46 175.08,129.58 175.08,133.44 175.28,133.64 177.56,133.64
+3VGS on IN2 (solid shape): outline of 397 points within 180.71,126.02 186.15,137.05
+3VLP on TOP (solid shape): 42.47,54.86 42.47,53.97 42.03,53.53 42.03,51.82 41.97,51.75 41.84,51.75 41.78,51.82 41.78,53.02 41.52,53.28 41.52,53.66 41.4,53.78 41.4,54.99 41.59,55.18 42.16,55.18
+3VLP on BOTTOM (solid shape): 19.42,12.52 19.81,12.52 19.81,13.03 20.28,13.03 20.83,12.47 20.83,10.44 20.58,10.19 19.81,10.19 19.81,10.72 19.42,10.72 19.42,10.19 18.74,10.19 18.61,10.31 18.61,12.64 19,13.03 19.42,13.03
+3VS on TOP (solid shape): 36.76,61.98 36.76,60.83 36.38,60.45 33.97,60.45 33.2,61.21 33.2,62.99 33.46,63.25 35.49,63.25
+3VS on TOP (solid shape): 55.03,79.39 55.03,78.55 54.59,78.11 53.27,78.11 53.08,78.29 53.08,79.19 53.37,79.48 54.94,79.48
+3VS on TOP (solid shape): 74.22,77.66 74.22,71.37 73.91,71.06 72.51,71.06 72.19,71.37 72.19,77.6 72.45,77.85 74.03,77.85
+3VS on TOP (solid shape): 96.6,150.77 96.6,148.34 96.36,148.09 94.81,148.09 94.53,148.37 94.53,151.03 94.71,151.21 96.17,151.21
+3VS on TOP (solid shape): 28.39,65.34 28.39,64.25 28.15,64.01 28.14,64 27.93,63.79 27.93,62.06 27.66,61.79 26.89,61.79 26.58,62.11 26.58,65.23 26.97,65.62 28.11,65.62
+3VS on TOP (solid shape): 30.16,16.08 30.91,16.08 30.91,16.58 31.36,16.58 31.36,16.08 31.98,16.08 32.19,15.88 32.19,13.84 31.81,13.46 28.76,13.46 28.5,13.72 28.5,15.85 28.73,16.08 29.71,16.08 29.71,16.58 30.16,16.58
+3VS on TOP (solid shape): 40.1,78.76 40.1,74.4 39.83,74.13 38.84,74.13 38.84,74.43 39.39,74.43 39.39,74.92 38.84,74.92 38.84,77.55 36.95,79.44 33.77,79.44 29.94,75.61 29.21,75.61 29,75.82 29,77.06 32.78,80.84 38.02,80.84
+3VS on TOP (solid shape): 81.51,155.4 81.51,153.2 81.63,153.09 82.84,153.09 82.87,153.05 82.87,152.06 82.8,151.98 80.17,151.98 79.91,152.23 79.91,155.52 80.03,155.64 81.27,155.64
+3VS on TOP (solid shape): 90.99,102.55 90.99,102.1 90.91,101.88 90.99,101.66 90.99,99.76 90.48,99.25 89.4,99.25 88.7,99.95 88.7,102.78 88.8,102.97 89.15,103.31 90.23,103.31
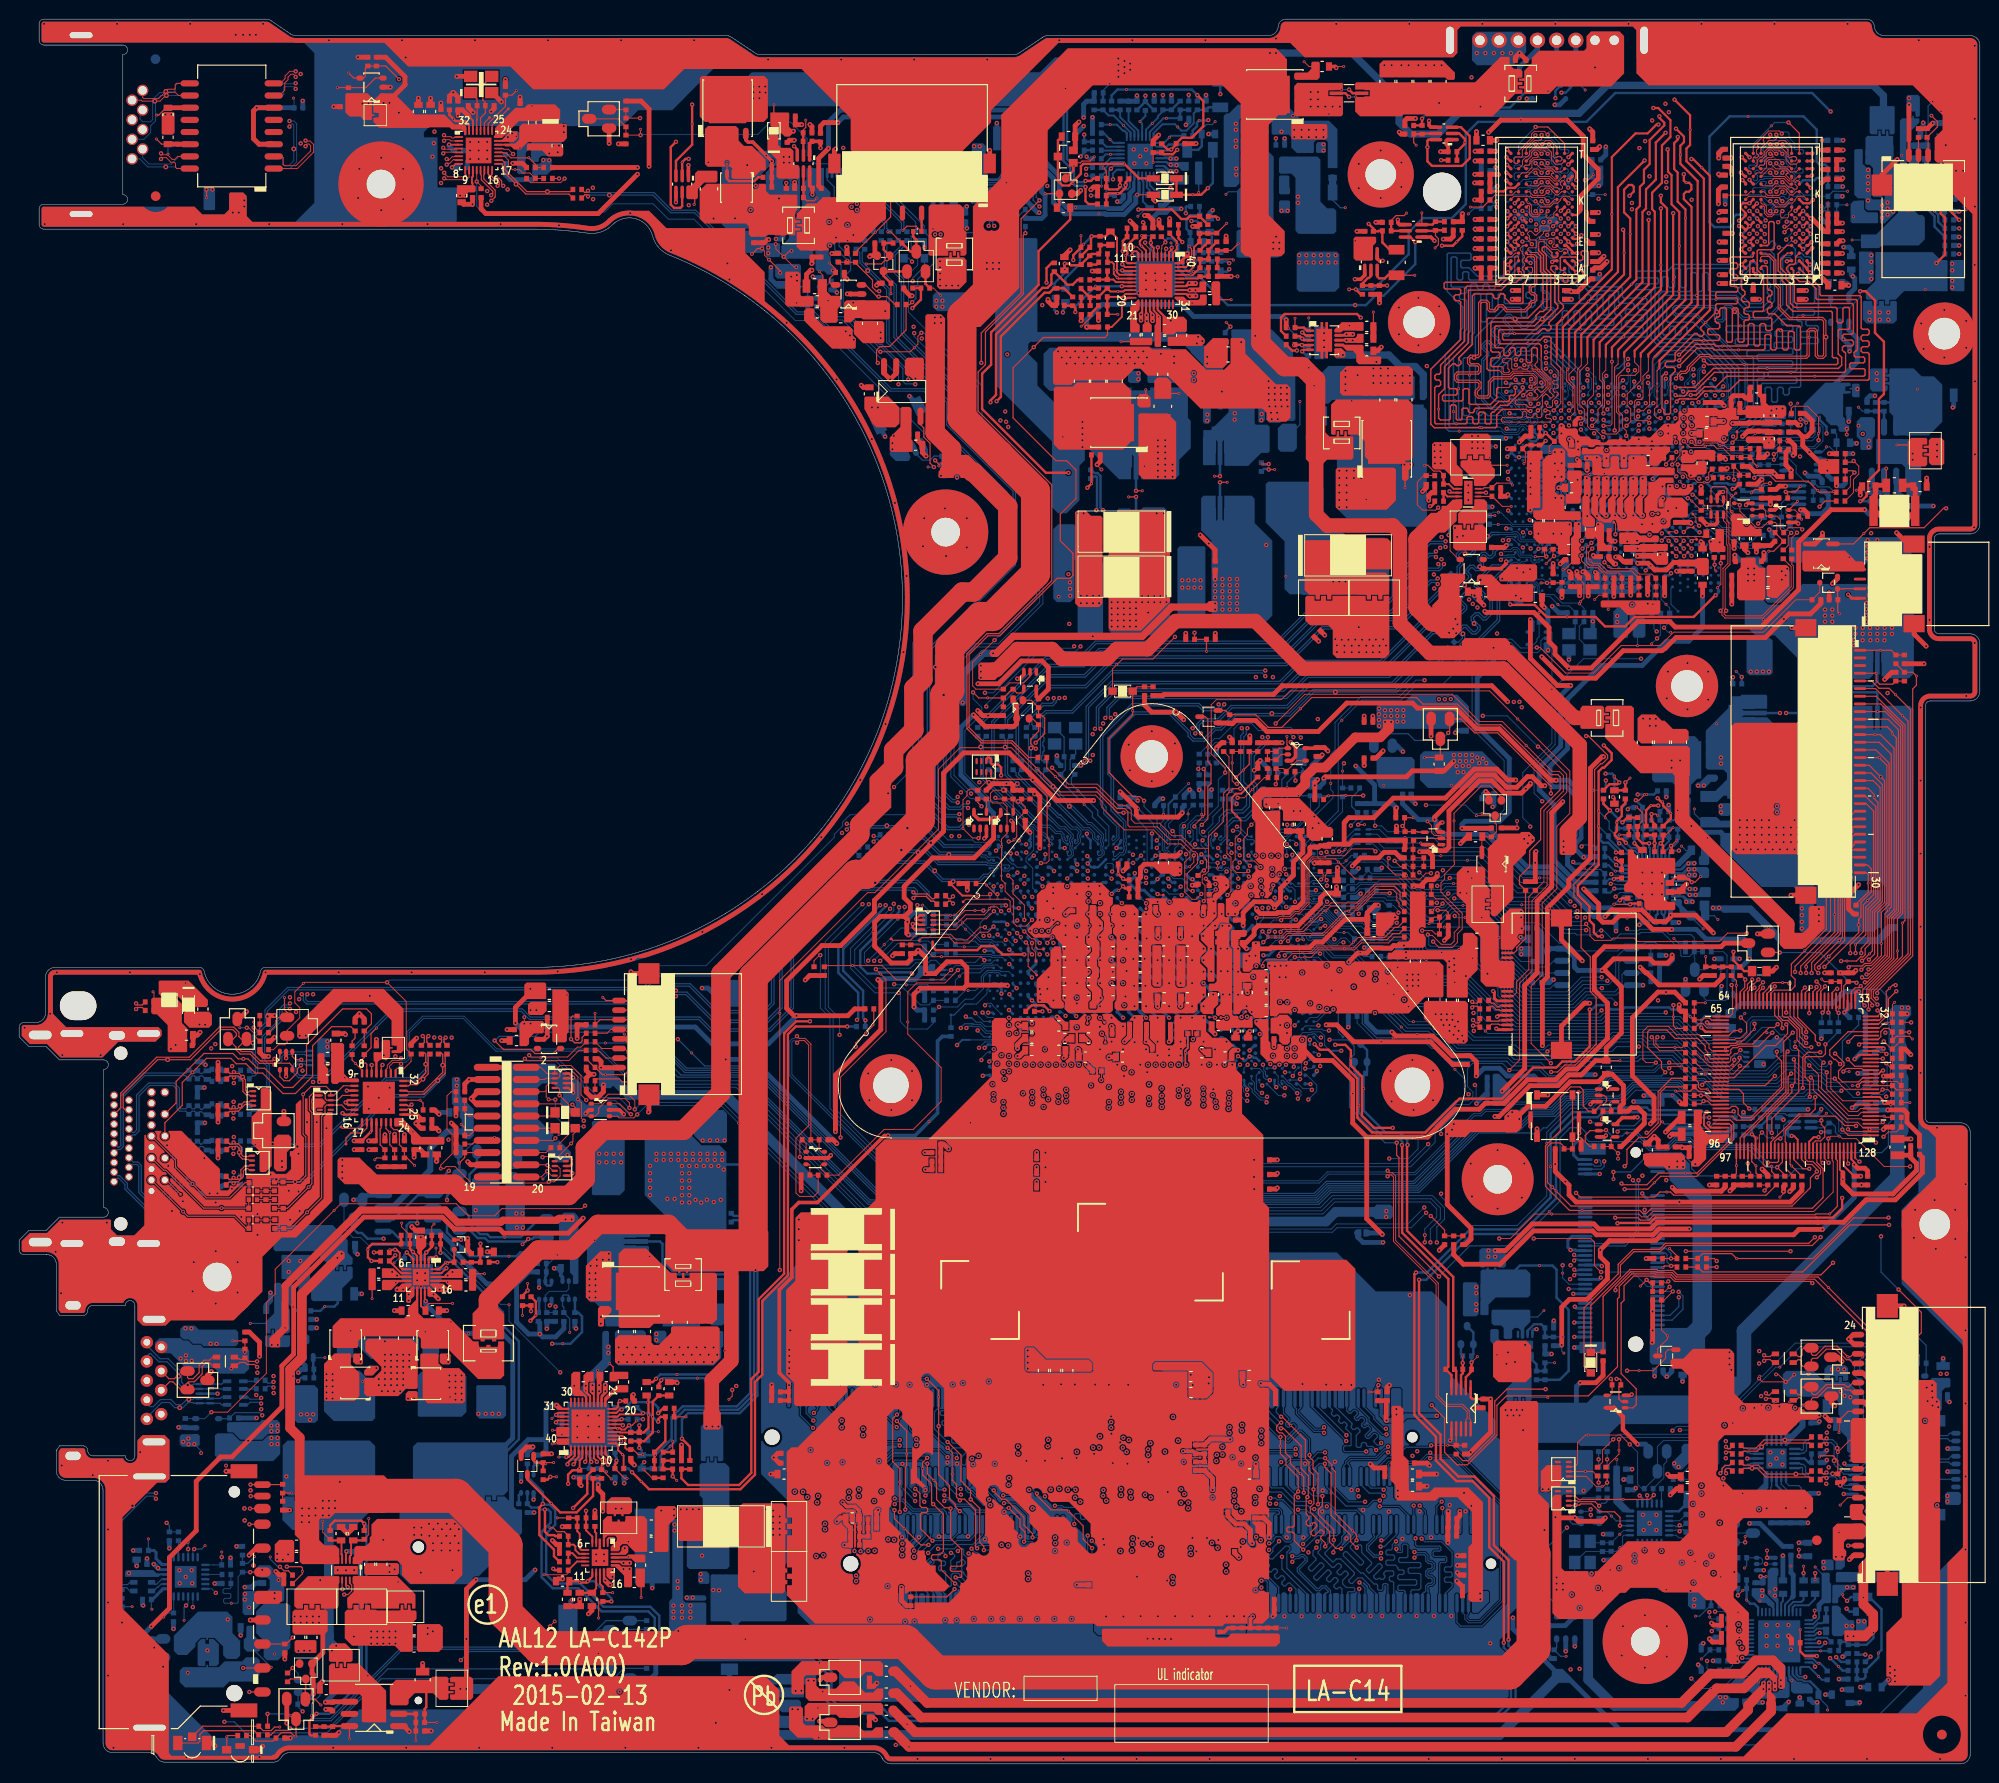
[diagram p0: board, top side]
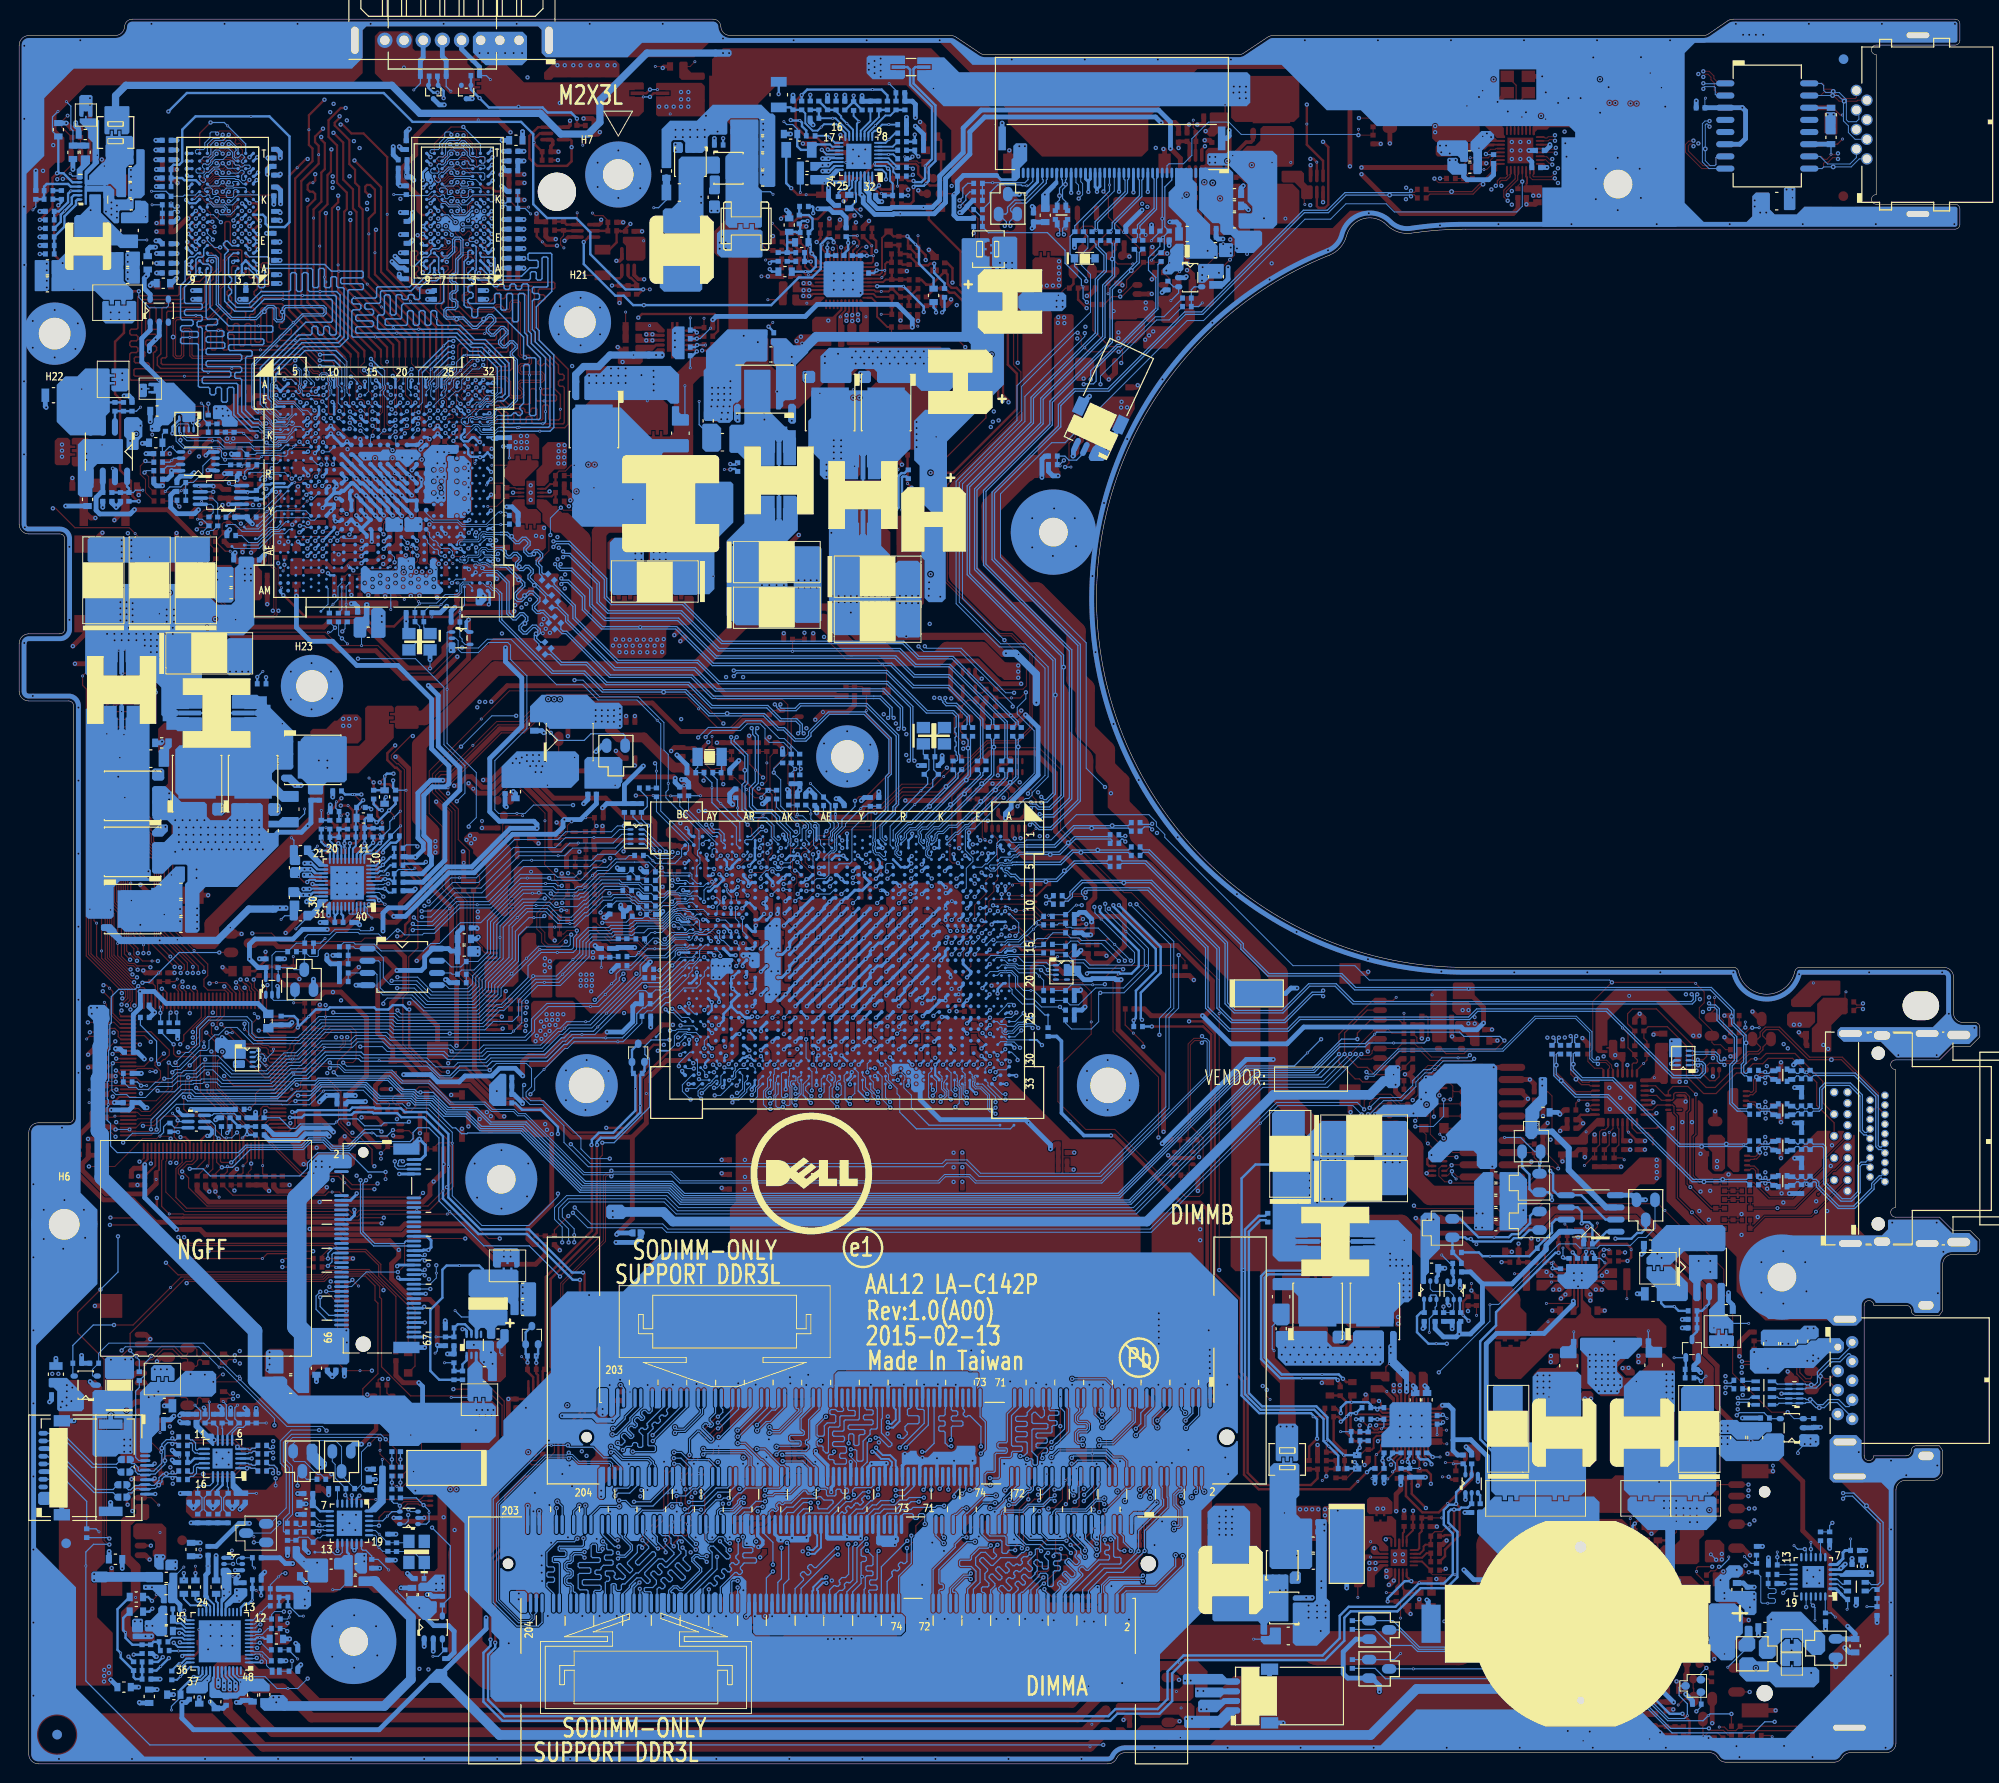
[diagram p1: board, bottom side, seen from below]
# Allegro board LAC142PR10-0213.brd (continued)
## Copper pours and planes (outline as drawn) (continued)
+3VS on TOP (solid shape): 146.73,90.93 146.73,87.19 146.59,87.19 146.58,87.2 146.02,86.97 146.47,86.56 146.56,86.55 146.6,86.47 146.64,86.33 146.73,86.21 146.73,85.52 146.73,85.52 146.73,85.33 146.51,85.11 143.86,85.11 143.76,85.22 143.76,85.65 143.89,85.78 144.89,85.78 145.09,85.98 145.09,90.94 145.14,90.99 146.68,90.99
+3VS on TOP (solid shape): 100.89,134.66 100.89,134.49 100.01,133.6 99.37,133.6 98.86,134.11 98.28,134.11 98.21,134.14 98.18,134.2 97.85,134.51 97.52,134.2 97.48,134.14 97.42,134.11 96.04,134.11 95.91,134.25 95.91,134.78 96.05,134.93 96.05,135.12 96.08,135.14 96.22,135.34 96.15,135.57 96.12,135.64 96.15,135.72 96.96,136.52 99.03,136.52
+3VS on TOP (solid shape): outline of 1357 points within 159.95,10.41 187.93,43.29
+3VS on BOTTOM (solid shape): 182.25,73.23 182.25,72.7 182.12,72.57 181.13,72.57 180.99,72.71 180.99,73.3 181.09,73.4 182.09,73.4
+3VS on BOTTOM (solid shape): 192,143.87 192,142.61 191.93,142.53 191.36,142.53 191.22,142.67 191.22,143.88 191.29,143.95 191.92,143.95
+3VS on BOTTOM (solid shape): 178.81,42.99 178.81,41.02 178.49,40.7 177.03,40.7 176.97,40.77 176.97,42.93 177.22,43.18 178.62,43.18
+3VS on BOTTOM (solid shape): 81.57,156.27 81.57,154.6 81.45,154.48 80.85,154.48 80.42,154.91 79.09,154.91 78.87,155.13 78.87,156.4 78.92,156.45 81.39,156.45
+3VS on BOTTOM (solid shape): 162.01,18.9 162.69,18.9 162.92,18.68 162.92,18.12 162.81,18.01 161.52,18.01 161.48,17.97 160.22,17.97 160.13,18.06 160.13,19.67 160.21,19.74 161.17,19.74
+3VS on BOTTOM (solid shape): 14.32,19.88 15.69,19.88 15.78,19.8 15.78,19.69 15.7,19.62 15.47,19.62 15.39,19.64 15.32,19.65 14.7,19.65 14.54,19.49 12.72,19.49 12.72,19.5 11.1,19.5 11.03,19.57 11.03,20.03 11.21,20.21 13.99,20.21
+3VS on IN1 (solid shape): 33.37,17.21 33.37,15.07 32.63,14.34 28.44,14.34 27.93,14.85 27.93,18.48 28.18,18.74 31.84,18.74
+3VS on IN1 (solid shape): 54.22,78.97 54.22,78.33 53.99,78.1 52.15,78.1 52.09,78.16 52.09,78.87 52.36,79.14 54.04,79.14
+3VS on IN1 (solid shape): 161.85,19.24 161.85,17.96 161.83,17.95 161.65,17.65 161.83,17.36 161.85,17.35 161.85,16.26 161.54,15.94 159.76,15.94 159.32,16.38 159.32,19.3 159.82,19.81 161.28,19.81
+3VS on IN1 (solid shape): outline of 150 points within 183.7,26.11 189.15,36.59
+3VS on IN1 (solid shape): outline of 320 points within 25.46,60.32 34.22,76.46
+3VS on IN1 (solid shape): outline of 434 points within 94.96,150 99.7,160.63
+3VS on IN1 (solid shape): outline of 574 points within 63.75,153.08 88.17,168.4
+3VS on IN2 (solid shape): 28.97,15.52 28.97,14.62 28.84,14.48 28.06,14.48 27.74,14.8 27.74,15.37 28,15.62 28.87,15.62
+3VS on IN2 (solid shape): outline of 405 points within 86.12,150.03 98.05,163.36
+3VS_2168 on TOP (solid shape): 38.7,75.4 38.7,73.75 38.31,73.36 38.25,73.36 38.23,73.36 37.92,73.47 37.6,73.38 37.39,73.18 37.39,71.63 37.33,71.56 37.23,71.56 37.14,71.65 37.14,73.15 36.98,73.32 36.98,74.17 37.03,74.22 37.69,74.22 37.83,74.36 37.83,75.35 37.99,75.51 38.59,75.51
+3VS_2168 on IN1 (solid shape): outline of 318 points within 32.81,61.99 43.81,76.39
+3VS_2168_AV on TOP (solid shape): 41.93,65.39 44.23,65.39 44.37,65.25 44.37,64.68 44.27,64.58 41.08,64.58 40.87,64.78 40.87,65.54 39.95,66.47 39.24,66.47 39.15,66.56 39.15,67.3 39.22,67.37 39.95,67.37
+3VS_2168_DA on TOP (solid shape): 33.9,75.03 33.9,71.98 34.39,71.49 35.34,71.49 35.45,71.39 35.45,71.18 35.36,71.09 33.39,71.09 33.2,70.9 32.73,70.9 32.54,71.09 32.54,73.02 32.55,73.08 32.54,73.13 32.54,74.01 32.57,74.14 32.54,74.27 32.54,74.31 32.51,74.34 32.51,75.15 32.55,75.2 33.73,75.2
+3VS_CAM on BOTTOM (solid shape): 96.45,166.36 96.45,165.18 97.94,163.69 97.94,161.95 97.85,161.86 97.16,161.86 97.05,161.98 97.05,163.8 96.41,164.44 96.41,164.5 96.13,164.77 96.13,165.05 96.19,165.11 96.19,165.93 96.18,166.05 96.13,166.15 96.13,166.36 96.22,166.45 96.36,166.45
+3VS_TOUCH on TOP (solid shape): 54.74,77.34 54.74,76.33 54.59,76.17 53.7,76.17 53.19,75.67 53.19,75.08 52.97,74.85 52.25,74.85 52.19,74.92 52.19,77.19 52.48,77.48 54.6,77.48
+3VS_TOUCH on TOP (solid shape): 160.89,31.05 160.89,29.07 160.61,28.79 160.01,28.79 159.61,28.38 158.81,28.38 158.74,28.45 158.74,30.53 159.37,31.15 160.79,31.15
+3VS_TOUCH on BOTTOM (solid shape): 62.08,72.4 62.08,70.85 61.7,70.47 60.78,70.47 60.47,70.78 60.47,72.69 60.64,72.86 61.63,72.86
+3VS_TOUCH on BOTTOM (solid shape): 143.31,58.07 143.31,57.05 143.07,56.81 141.5,56.81 141.22,57.1 141.22,57.92 141.62,58.32 143.06,58.32
+3VS_TOUCH on BOTTOM (solid shape): 174.55,33.13 174.55,31.76 173.48,30.68 172.81,30.68 172.43,31.06 172.43,31.43 173.42,32.42 173.42,33.08 173.73,33.39 174.3,33.39
+3VS_TOUCH on IN1 (solid shape): 61.4,74.23 61.4,70.93 61.08,70.61 60.64,70.61 60.45,70.8 60.45,73.02 57.97,75.5 57.97,76.07 57.33,76.71 52.7,76.71 52.44,76.96 52.44,77.66 52.63,77.85 57.78,77.85
+3VS_TOUCH on IN2 (solid shape): 173.4,31.48 173.4,30.86 173.02,30.48 172.36,30.48 171.53,31.31 171.53,32.12 171.71,32.3 172.59,32.3
+3VS_TOUCH on IN2 (solid shape): 143.73,57.04 143.73,55.24 143.54,55.05 142.86,55.05 142.26,55.65 142.26,57.76 142.39,57.89 142.88,57.89
+3VS_TOUCH on IN2 (solid shape): 161.95,29.96 161.95,28.52 161.68,28.26 158.16,28.26 157.84,28.57 157.84,29.92 158.16,30.24 161.67,30.24
+3VS_WLAN_NGFF on TOP (solid shape): 173.78,63.35 173.78,63.06 173.84,62.99 173.84,62.15 173.69,62 171.87,62 171.58,62.29 169.77,62.29 169.52,62.54 169.52,63.53 169.69,63.7 173.43,63.7
+3VS_WLAN_NGFF on BOTTOM (solid shape): 175.89,45.02 175.89,39.12 175.44,38.67 174.36,38.67 174.3,38.73 174.3,41.27 173.92,41.66 170.36,41.66 170.11,41.91 170.11,45.34 170.24,45.47 175.44,45.47
+3VS_WLAN_NGFF on BOTTOM (solid shape): 174.29,62.58 174.29,61.89 174.48,61.7 174.48,61.07 173.46,60.06 172.99,60.06 172.74,60.31 172.69,60.37 172.64,60.41 172.19,60.86 172.19,60.88 172.19,60.95 172.16,61.03 172.16,61.62 171.67,62.11 170.02,62.11 169.85,62.27 169.85,63.2 170.22,63.56 173.31,63.56
+5V_HDD on BOTTOM (solid shape): 202.57,28.11 202.57,27.2 202.37,27 201.05,27 200.92,27.13 200.92,28.14 201.15,28.37 202.3,28.37
+5V_HDD on BOTTOM (solid shape): 188.36,39.83 189.03,39.83 189.03,40.34 189.38,40.34 189.38,39.83 189.83,39.83 189.83,40.34 190.18,40.34 190.18,39.83 190.86,39.83 191.95,38.73 191.95,32.58 191.83,32.45 190.87,32.45 190.68,32.64 190.68,34.04 189.92,34.8 189.92,36.32 189.79,36.45 189.79,37.72 189.22,38.29 184.45,38.29 183.99,38.75 183.99,40.63 184.35,40.98 187.2,40.98
+5V_HDD on IN2 (solid shape): 192.11,39.57 192.11,38.29 191.76,37.95 190.53,37.95 189.82,38.66 189.82,39.61 190.61,40.4 191.28,40.4
+5V_HDD on IN2 (solid shape): 201.31,41.45 201.31,40.82 201.33,40.81 201.33,40.21 201.2,40.08 199.18,40.08 198.95,40.31 198.95,41.62 199.18,41.85 200.92,41.85
+5V_PVDD on BOTTOM (solid shape): 182.34,10.13 182.34,9.27 181.59,8.52 181.59,7.68 181.83,7.44 183.38,7.44 183.66,7.72 183.93,7.72 184.17,7.96 184.17,8.9 184.12,8.95 184.12,10.11 184.18,10.17 184.27,10.17 184.33,10.12 184.33,9.14 184.47,9 184.47,8.64 184.71,8.4 184.71,7.05 184.52,6.86 183.38,6.86 183.23,6.71 182.71,6.71 182.62,6.79 181.79,6.79 181.5,7.08 181.04,7.08 180.57,7.56 178.49,7.56 178.41,7.64 178.41,8.23 179.08,8.9 181.68,8.9 182.12,9.35 182.12,10.13 182.17,10.19 182.29,10.19
+5V_USB_PWR1 on BOTTOM (solid shape): 18.84,34.2 18.84,33.27 18.64,33.07 17,33.07 16.74,33.32 16.74,34.16 16.96,34.38 18.66,34.38
+5V_USB_PWR1 on BOTTOM (solid shape): 17.1,44.16 17.63,44.16 18.08,43.71 18.9,43.71 19.22,43.4 22.52,43.4 22.55,43.37 23.74,43.37 24,43.12 24,41.91 23.99,41.9 23.99,41.19 23.49,40.69 20.94,40.69 20.35,41.27 17.37,41.27 15.84,42.8 15.81,42.8 15.79,42.82 14.94,42.82 14.18,43.59 14.18,43.95 14.62,44.4 16.86,44.4
+5V_USB_PWR1 on IN1 (solid shape): 18.52,42.38 18.52,33.15 18.29,32.92 16.85,32.92 16.1,33.67 16.1,35.13 16.3,35.13 16.3,35.08 16.31,35.03 16.32,34.98 16.35,34.93 16.38,34.89 16.42,34.85 16.46,34.82 16.5,34.8 16.55,34.78 16.6,34.77 16.66,34.77 16.71,34.78 16.76,34.8 16.8,34.82 16.85,34.85 16.88,34.89 16.91,34.93 16.94,34.98 16.95,35.03 16.96,35.08 16.96,35.13 16.95,35.18 16.94,35.23 16.91,35.28 16.88,35.32 16.85,35.35 16.8,35.39 16.76,35.41 16.71,35.42 16.66,35.43 16.6,35.43 16.55,35.42 16.5,35.41 16.46,35.39 16.42,35.35 16.38,35.32 16.35,35.28 16.32,35.23 16.31,35.18 16.3,35.13 16.1,35.13 16.1,42.34 16.8,43.04 17.86,43.04
+5V_USB_PWR2 on TOP (solid shape): 193.99,35.31 193.99,31.88 193.48,31.37 191.32,31.37 191.06,31.62 191.06,35.81 191.32,36.07 193.22,36.07
+5V_USB_PWR2 on BOTTOM (solid shape): 196.91,38.73 196.91,32.26 196.69,32.04 194.46,32.04 194.18,32.32 192.82,32.32 192.72,32.42 192.72,36.03 193.65,36.03 193.65,34.83 196.35,34.83 196.35,36.03 195.36,36.03 195.36,36.5 195.1,36.76 194.81,36.76 194.6,36.55 194.6,36.25 194.64,36.21 194.64,36.03 192.72,36.03 192.72,36.83 193.02,36.83 193.02,36.8 193.03,36.75 193.04,36.7 193.07,36.66 193.1,36.61 193.14,36.58 193.18,36.55 193.22,36.52 193.27,36.51 193.32,36.5 193.38,36.5 193.43,36.51 193.48,36.52 193.52,36.55 193.57,36.58 193.6,36.61 193.63,36.66 193.66,36.7 193.67,36.75 193.68,36.8 193.68,36.86 193.67,36.91 193.66,36.96 193.63,37 193.6,37.05 193.57,37.08 193.52,37.11 193.48,37.14 193.43,37.15 193.38,37.16 193.32,37.16 193.27,37.15 193.22,37.14 193.18,37.11 193.14,37.08 193.1,37.05 193.07,37 193.04,36.96 193.03,36.91 193.02,36.86 193.02,36.83 192.72,36.83 192.72,38.86 192.84,38.99 196.65,38.99
+5VA on BOTTOM (solid shape): 188.89,19.83 188.89,18.93 189.04,18.78 189.04,16.88 188.9,16.74 188.11,16.74 188.04,16.81 188.04,19.88 188.11,19.94 188.78,19.94
+5VALW on TOP (solid shape): 56.7,37.15 57.33,37.15 57.4,37.08 57.4,36.96 57.33,36.89 56.19,36.89 55.81,37.27 55.81,37.53 55.94,37.66 56.19,37.66
+5VALW on TOP (solid shape): 138.3,148.02 140.14,148.02 140.26,147.89 140.26,147.15 140.63,146.79 142.02,146.79 142.1,146.71 142.1,146.1 141.97,145.97 139.76,145.97 139.49,146.24 139.49,147.02 139.12,147.38 138.49,147.38 138.04,147.83 137.28,147.83 137.22,147.89 137.22,148.08 137.28,148.15 138.17,148.15
+5VALW on TOP (solid shape): outline of 95 points within 34.79,18.77 46.25,25.54
+5VALW on TOP (solid shape): outline of 226 points within 194.79,8.16 200.41,40.03
+5VALW on BOTTOM (solid shape): 23.02,33.69 25.39,33.69 25.98,34.28 27.04,34.28 27.23,34.09 27.23,32.31 26.5,31.57 21.01,31.57 20.41,32.17 20.41,34.23 20.66,34.47 22.24,34.47
+5VALW on BOTTOM (solid shape): 201.48,40.13 201.48,39.37 201.35,39.24 200.97,39.24 200.59,38.86 200.59,36.96 200.4,36.77 198.05,36.77 197.8,37.02 197.8,38.48 199.57,40.26 201.35,40.26
+5VALW on BOTTOM (solid shape): outline of 116 points within 39.68,18.73 52.46,27.89
+5VALW on IN1 (solid shape): 42.22,25.02 42.22,23.75 42.09,23.62 39.68,23.62 39.43,23.88 39.43,25.4 39.68,25.65 41.59,25.65
+5VALW on IN1 (solid shape): 199.83,40 199.83,38.73 199.7,38.61 198.94,38.61 197.8,39.75 197.8,40.64 198.18,41.02 198.81,41.02
+5VALW on IN1 (solid shape): 29.52,34.11 29.52,32.41 29.17,32.05 26.87,32.05 25.95,32.97 25.95,33.93 26.23,34.21 29.42,34.21
+5VALW on IN2 (solid shape): 47.11,24.46 47.11,19.77 46.53,19.19 40.91,19.19 40.1,20 40.1,22.61 40.8,22.61 40.8,22.53 40.81,22.45 40.83,22.37 40.86,22.29 40.9,22.21 40.94,22.14 40.99,22.08 41.04,22.01 41.1,21.96 41.17,21.91 41.24,21.87 41.31,21.83 41.39,21.8 41.47,21.78 41.55,21.76 41.63,21.76 41.71,21.76 41.79,21.77 41.87,21.79 41.95,21.81 42.03,21.85 42.1,21.89 42.17,21.93 42.23,21.99 42.29,22.05 42.34,22.11 42.38,22.18 42.42,22.25 42.45,22.33 42.48,22.41 42.49,22.49 42.5,22.57 42.5,22.65 42.49,22.73 42.48,22.81 42.45,22.89 42.42,22.97 42.38,23.04 42.34,23.11 42.29,23.17 42.23,23.23 42.17,23.29 42.1,23.33 42.03,23.37 41.95,23.41 41.87,23.43 41.79,23.45 41.71,23.46 41.63,23.46 41.55,23.46 41.47,23.44 41.39,23.42 41.31,23.39 41.24,23.35 41.17,23.31 41.1,23.26 41.04,23.21 40.99,23.14 40.94,23.08 40.9,23.01 40.86,22.93 40.83,22.85 40.81,22.77 40.8,22.69 40.8,22.61 40.1,22.61 40.1,24.38 41.07,25.35 46.22,25.35
+5VALW on IN2 (solid shape): outline of 545 points within 193,2.46 201.82,39.78
+5VALWP on BOTTOM (solid shape): 50.98,33.27 50.98,28.45 50.52,27.99 49.78,27.99 49.78,27.5 49.33,27.5 49.33,27.99 48.58,27.99 48.58,27.5 48.13,27.5 48.13,27.99 44.57,27.99 44.57,27.5 44.12,27.5 44.12,27.99 43.37,27.99 43.37,27.5 42.92,27.5 42.92,27.99 41.6,27.99 41.08,28.51 41.08,33.08 41.52,33.53 50.73,33.53
+5VS on TOP (solid shape): 20.11,78.14 20.11,77.08 19.81,76.77 17.76,76.77 17.19,77.34 17.19,78.33 17.3,78.45 19.81,78.45
+5VS on TOP (solid shape): 102.16,114.68 102.16,113.41 101.8,113.04 100.21,113.04 100.07,113.18 100.07,114.68 100.26,114.87 101.97,114.87
+5VS on TOP (solid shape): 162.48,97.7 162.48,95.11 162.16,94.79 161.99,94.79 161.99,94.8 160.87,94.8 160.7,94.97 160.7,97.53 160.98,97.81 162.37,97.81
+5VS on TOP (solid shape): 91.83,141.46 91.83,139.8 91.43,139.4 89.42,139.4 88.97,139.85 88.58,140.59 88.17,141.32 88.17,142.49 88.3,142.61 90.67,142.61
+5VS on TOP (solid shape): 82.98,151.65 82.98,150.91 82.99,150.9 83.94,149.95 86.63,149.95 86.96,149.62 86.96,148.98 87.28,148.67 87.28,147.7 87.18,147.6 84.8,147.6 81.88,150.52 81.88,151.56 82.12,151.8 82.82,151.8
+5VS on TOP (solid shape): 118.88,152.67 118.88,151.73 119.67,150.94 121.47,150.94 121.82,150.59 121.82,149.45 121.74,149.36 120.74,149.36 120.47,149.09 120.47,149.08 119.51,149.08 119.28,149.32 119.28,150.98 118.66,151.6 118.66,152.68 118.72,152.75 118.8,152.75
+5VS on TOP (solid shape): 58.54,40.83 58.54,39.03 59.28,38.29 59.28,37.25 59.21,37.19 59.12,37.19 59.05,37.26 59.05,38.16 58.86,38.35 57.97,38.35 57.59,38.73 57.59,40.64 57.84,40.89 58.48,40.89
+5VS on TOP (solid shape): 158.13,96.63 158.13,96.27 157.19,95.33 157.19,94.98 155.89,93.68 155.89,90.21 154.07,88.39 153.73,88.39 153.53,88.59 153.53,89.14 153.02,89.14 153.02,89.39 153.53,89.39 153.53,89.94 153.02,89.94 153.02,90.19 153.53,90.19 153.53,91.64 153.22,91.95 153.22,95.5 154.23,96.52 154.23,96.9 154.36,97.03 155.74,97.03 155.74,97.03 156.55,97.03 156.72,97.2 157.56,97.2
+5VS on TOP (solid shape): 40.09,16.16 40.09,16.08 40.54,16.08 40.54,16.59 40.82,16.59 40.82,16 41.33,16 41.46,15.88 41.46,15.11 41.08,14.73 41.08,11.81 40.95,11.68 39.81,11.68 39.17,12.32 34.73,12.32 33.97,13.08 33.97,15.83 34.22,16.08 34.87,16.08 34.87,16.57 35.42,16.57 35.42,16.08 36.07,16.08 36.07,16.57 36.62,16.57 36.62,16.08 37.22,16.08 37.31,16 39.8,16 39.8,16.59 40.09,16.59
+5VS on BOTTOM (solid shape): 169.16,19.43 169.16,18.61 169.09,18.54 167.51,18.54 167.32,18.73 167.32,19.37 167.51,19.56 169.03,19.56
+5VS on BOTTOM (solid shape): 197.03,19.88 197.03,19.11 196.84,18.92 195.45,18.92 195.26,19.11 195.26,19.94 195.38,20.07 196.84,20.07
+5VS on BOTTOM (solid shape): 191.43,19.89 191.43,19.13 191.24,18.94 189.59,18.94 189.53,19 189.53,19.89 189.66,20.02 191.31,20.02
+5VS on BOTTOM (solid shape): 178.56,6.85 179.36,6.85 179.4,6.81 179.4,5.93 179,5.52 176.78,5.52 176.78,5.53 176.52,5.78 176.52,6.73 176.97,7.18 178.23,7.18
+5VS on BOTTOM (solid shape): 190.81,41.27 190.81,40.07 190.68,39.94 190.28,39.94 190.28,40.44 189.73,40.44 189.73,39.94 189.48,39.94 189.48,40.44 188.93,40.44 188.93,39.94 188.46,39.94 188.33,40.07 188.33,41.21 188.72,41.59 190.49,41.59
+5VS on IN1 (solid shape): 100.71,115.66 100.71,113.4 100.3,112.98 99.34,112.98 99.02,113.3 99.02,115.51 99.34,115.82 100.55,115.82
+5VS on IN1 (solid shape): 20.77,77.55 20.77,76.8 20.52,76.54 19.1,76.54 19.06,76.58 19,76.61 18.88,76.73 18.69,76.73 18.56,76.86 18.56,77.9 18.98,78.32 20,78.32
+5VS on IN1 (solid shape): 87.72,150.3 87.72,145.57 89.24,144.05 89.24,142.68 90.49,141.43 90.49,140 90.23,139.74 89.67,139.74 88.11,141.93 86.99,143.54 86.94,143.6 86.78,143.82 87.52,143.82 87.52,143.76 87.53,143.71 87.55,143.66 87.57,143.62 87.6,143.57 87.64,143.54 87.68,143.51 87.73,143.48 87.77,143.47 87.83,143.46 87.88,143.46 87.93,143.47 87.98,143.48 88.03,143.51 88.07,143.54 88.1,143.57 88.13,143.62 88.16,143.66 88.17,143.71 88.18,143.76 88.18,143.82 88.17,143.87 88.16,143.92 88.13,143.96 88.1,144 88.07,144.04 88.03,144.07 87.98,144.1 87.93,144.11 87.88,144.12 87.83,144.12 87.77,144.11 87.73,144.1 87.68,144.07 87.64,144.04 87.6,144 87.57,143.96 87.55,143.92 87.53,143.87 87.52,143.82 86.78,143.82 85.64,145.36 85.64,150.62 85.79,150.77 87.26,150.77
+5VS on IN1 (solid shape): outline of 4111 points within 20.3,1.4 202.24,97.21
+5VS_ODD on TOP (solid shape): 152.96,93.34 152.96,91.69 153.43,91.23 153.43,90.29 152.92,90.29 152.92,89.83 153.43,89.83 153.43,89.49 152.92,89.49 152.92,89.03 153.43,89.03 153.43,88.31 154.36,87.38 154.36,85.61 154.37,85.6 154.37,84.91 154.36,84.9 154.36,83.95 154.55,83.76 155.82,83.76 156.01,83.57 156.01,81.76 155.92,81.67 155.92,81 155.82,80.9 154.43,80.9 154.27,81.05 153.03,81.05 152.46,81.62 152.46,86.23 150.93,87.76 150.93,89.64 149.97,90.6 149.97,92.91 150.63,93.57 152.05,93.57 152.08,93.6 152.71,93.6
+17.4V_BATT+ on TOP (solid shape): 155.5,177.93 155.5,177.23 155.95,176.78 156.58,176.78 156.84,176.53 156.84,175.89 156.35,175.89 156.35,175.43 156.84,175.43 156.84,175.09 156.35,175.09 156.35,174.63 156.84,174.63 156.84,174.24 156.77,174.18 156.08,174.18 153.73,171.83 146.82,171.83 146.61,172.03 144.42,172.03 144.21,171.83 139.88,171.83 139.38,172.34 139.38,173.86 140.9,173.86 140.9,174.62 139.38,174.62 139.38,175.26 139.5,175.39 151.89,175.39 154.55,178.05 155.38,178.05
+17.4V_BATT++ on TOP (solid shape): 167.44,180.21 167.44,176.31 166.08,174.94 160.39,174.94 159.62,174.17 157.11,174.17 157,174.27 157,174.75 156.45,174.75 156.45,174.99 157,174.99 157,175.53 156.45,175.53 156.45,175.79 157.02,175.79 157.02,176.58 157.79,177.36 157.79,177.93 158.55,178.69 163.25,178.69 163.51,178.94 163.51,180.21 163.99,180.7 166.96,180.7
+19V_ADPIN on TOP (solid shape): outline of 232 points within 81.11,157.85 90.4,163.42
+19V_VIN on TOP (solid shape): outline of 104 points within 70.99,159.27 81.51,164.81
+19VB on TOP (solid shape): 50.6,46.93 50.6,44.39 50.48,44.26 47.43,44.26 47.3,44.39 47.3,46.99 48.06,47.75 49.78,47.75
+19VB on TOP (solid shape): 155.54,116.97 155.54,115.49 155.15,115.1 150.87,115.1 150.51,115.46 150.51,117.1 150.82,117.42 155.09,117.42
+19VB on TOP (solid shape): 73.21,36.64 73.21,35.05 73.02,34.86 71.56,34.86 71.37,35.05 71.37,36.77 71.68,37.08 72.76,37.08
+19VB on TOP (solid shape): 78.16,55.5 78.16,51.88 77.67,51.38 71.99,51.38 71.98,51.37 68.28,51.37 67.42,52.24 67.42,55.04 68.13,55.75 77.91,55.75
+19VB on TOP (solid shape): 79.19,169.76 79.19,168.87 79.51,168.55 80.46,168.55 80.79,168.22 80.79,166.9 80.93,166.76 81.24,166.76 81.4,166.6 81.4,165.46 81.27,165.33 79.23,165.33 79,165.56 79,167.37 78.06,168.31 78.06,169.67 78.28,169.89 79.06,169.89
+19VB on TOP (solid shape): 165.36,110.16 165.36,109.67 165.36,109.67 165.36,109.62 165.87,109.62 165.87,109.37 165.36,109.37 165.36,109.32 165.36,109.32 165.36,108.87 165.36,108.87 165.36,108.82 165.87,108.82 165.87,108.58 165.85,108.57 165.36,108.57 165.36,108.52 165.36,108.52 165.36,108.13 165.18,107.95 163,107.95 162.87,108.08 162.87,110.11 163.12,110.36 165.16,110.36
+19VB on TOP (solid shape): 137.7,138.46 137.71,138.46 138.24,138.46 138.25,138.47 138.25,139 138.5,139 138.5,138.47 138.51,138.47 139.08,138.47 139.19,138.36 139.19,136.21 138.99,136.02 136.45,136.02 135.88,135.45 134.87,135.45 134.23,136.08 134.23,138.62 134.61,139 136.14,139 136.69,138.45 137.45,138.45 137.45,139 137.7,139
+19VB on TOP (solid shape): outline of 117 points within 97.21,149.86 132.26,178.94
+19VB on BOTTOM (solid shape): 103.05,159.11 103.05,156.27 102.44,155.66 100.58,155.66 100.42,155.82 100.42,159.12 100.6,159.3 102.86,159.3
+19VB on BOTTOM (solid shape): 132.07,178.75 132.07,178.12 132.01,178.05 130.42,178.05 130.23,178.24 130.23,178.63 130.42,178.82 132.01,178.82
+19VB on BOTTOM (solid shape): 73.46,35.18 73.46,31.69 73.34,31.56 72.88,31.56 72.88,32.05 72.43,32.05 72.43,31.56 72.08,31.56 72.08,32.05 71.63,32.05 71.63,31.56 71.24,31.56 71.11,31.69 71.11,35.18 71.43,35.5 73.15,35.5
+19VB on BOTTOM (solid shape): 116.13,177.97 116.13,176.33 115.51,175.7 112.32,175.7 112.13,175.89 112.13,176.66 113.66,176.66 113.66,177.29 112.13,177.29 112.13,178.12 112.2,178.18 115.92,178.18
+19VB on BOTTOM (solid shape): 195.66,172.81 195.66,170.08 195.53,169.95 195.17,169.95 195.12,169.95 195.12,170.45 194.67,170.45 194.67,169.95 194.32,169.95 194.32,170.45 193.87,170.45 193.87,169.95 193.22,169.95 193.05,170.13 193.05,172.83 193.11,172.9 195.57,172.9
+19VB on BOTTOM (solid shape): 128.33,160.11 128.38,160.11 128.38,160.1 129.03,160.1 129.03,160.11 129.08,160.11 129.08,160.6 129.51,160.6 129.51,160.02 131.37,160.02 131.76,159.64 131.76,157.54 131.31,157.1 127.12,157.1 126.99,157.23 126.99,159.83 127.18,160.02 127.9,160.02 127.9,160.6 128.33,160.6
+19VB on BOTTOM (solid shape): outline of 106 points within 73.3,160.12 80.6,168.25
+19VB on IN2 (solid shape): outline of 222 points within 79.51,155.26 108.24,168.34
+19VB_1.35V on BOTTOM (solid shape): 71.98,31.46 72.03,31.46 72.03,31.45 72.48,31.45 72.48,31.46 72.53,31.46 72.53,31.95 72.78,31.95 72.78,31.46 72.79,31.46 72.79,31.37 73.65,31.37 74.1,30.92 74.1,20.57 73.84,20.32 69.91,20.32 69.65,20.57 69.65,25.46 69.78,25.59 70.86,25.59 71.3,26.03 71.3,27.69 70.99,28 70.99,31.18 71.18,31.37 71.73,31.37 71.73,31.46 71.73,31.46 71.73,31.95 71.98,31.95
+19VB_1.35VGPU on BOTTOM (solid shape): 194.22,169.8 194.77,169.8 194.77,170.34 195.01,170.34 195.01,169.8 195.46,169.8 195.51,169.75 195.51,167.39 195.6,167.3 195.6,167.28 195.69,167.1 195.87,167.01 195.89,167.01 197.22,165.67 197.22,164.78 195,164.78 194.43,164.21 194.43,163.54 194.3,163.41 193.42,163.41 193.4,163.43 193.4,166.45 193.06,166.79 192.73,166.79 192.7,166.79 192.62,166.87 192.62,169.6 192.82,169.8 193.97,169.8 193.97,170.34 194.22,170.34
+19VB_3/5V on TOP (solid shape): 41.65,49.72 41.65,47.02 42.18,46.48 44.95,46.48 47.36,44.07 47.94,44.07 47.94,43.5 49.97,43.5 49.97,44.07 50.54,44.07 50.6,44.01 50.6,40.51 50.22,40.13 47.87,40.13 44.7,43.31 42.03,43.31 41.9,43.43 41.9,44.32 41.65,44.58 35.87,44.58 35.36,44.07 35.36,43.5 35.24,43.37 32.82,43.37 32.7,43.5 32.7,45.66 33.52,46.48 40.16,46.48 40.54,46.86 40.54,47.54 41.4,48.39 41.4,49.72 41.47,49.8 41.57,49.8
+19VB_APU on TOP (solid shape): 126.21,148.55 126.21,148.07 126.09,147.95 126.09,146.06 125.62,145.59 123.88,145.59 123.63,145.85 123.63,147.78 124.55,148.7 126.05,148.7
+19VB_APU on TOP (solid shape): 116.01,143.26 116.01,137.92 115.14,137.06 108.49,137.06 107.93,137.62 107.93,143.43 108.14,143.64 109.89,143.64 110.33,144.08 115.18,144.08
+19VB_APU on BOTTOM (solid shape): 126.13,148.59 126.13,148.08 125.85,147.8 125.85,146.13 125.6,145.87 125.6,141.35 125.53,141.29 125.15,141.29 124.83,141.6 124.83,142.05 124.64,142.24 123.75,142.24 123.63,142.37 123.5,142.37 123.5,145.92 122.23,147.19 122.23,147.76 122.42,147.95 123.78,147.95 124.52,148.69 126.03,148.69
+19VB_APU on BOTTOM (solid shape): outline of 116 points within 101.82,130.43 111.18,159.13
+19VB_GPU on TOP (solid shape): 188.36,89.38 188.36,87.13 186.35,85.11 186.32,85.12 186.18,85.09 186.07,84.99 184.11,84.99 183.7,85.41 183.7,86.49 183.89,86.68 186.11,86.68 186.68,87.25 186.68,89.28 186.87,89.47 188.27,89.47
+19VB_GPU on TOP (solid shape): 168.46,110.11 168.46,106.81 169.09,106.17 174.05,106.17 174.3,105.92 174.3,103.12 174.05,102.87 172.9,102.87 172.46,103.31 169.16,103.31 165.47,107.01 165.47,108.47 165.97,108.47 165.97,108.92 165.47,108.92 165.47,109.27 165.97,109.27 165.97,109.72 165.47,109.72 165.47,110.16 165.66,110.36 168.2,110.36
+19VB_GPU on BOTTOM (solid shape): 190.68,91.12 193.92,91.12 193.92,87.19 193.52,86.79 187.65,86.79 187.51,86.93 187.51,91.82 187.25,92.07 187.25,93.54 187.32,93.6 188.21,93.6
+19VB_GPU on BOTTOM (solid shape): 175.19,106.81 175.19,102.87 174.43,102.11 174.43,101.22 174.3,101.09 172.97,101.09 172.84,101.22 172.84,101.98 172.46,102.36 170.62,102.36 170.36,102.62 170.36,107.06 170.49,107.19 174.81,107.19
+19VB_VDDP_ALWP on TOP (solid shape): 145.41,141.8 145.41,136.33 145.03,135.95 140.77,135.95 140.39,136.33 140.39,137.92 139.69,138.62 138.61,138.62 138.61,139.11 138.15,139.11 138.15,138.62 137.81,138.62 137.81,139.11 137.35,139.11 137.35,138.62 136.96,138.62 136.87,138.72 136.87,141.76 137.41,142.3 144.9,142.3
+VBUS on BOTTOM (solid shape): 170.96,21.49 171.57,21.49 171.7,21.35 171.7,20.34 171.63,20.26 170.71,20.26 170.62,20.17 170.62,18.66 170.48,18.52 169.85,18.52 169.74,18.63 169.74,21.68 169.84,21.78 170.67,21.78
+VCC_3IN1 on TOP (solid shape): 27.43,17.9 27.43,17.01 27.1,16.68 24.81,16.68 24.49,16.99 24.49,17.73 24.81,18.05 27.28,18.05
+VCC_3IN1 on BOTTOM (solid shape): 14.85,20.39 15.7,20.39 15.77,20.32 15.77,20.17 15.71,20.11 14.42,20.11 13.79,20.74 13.79,20.94 13.92,21.08 14.16,21.08
+VCC_3IN1 on BOTTOM (solid shape): 26.55,20.32 26.53,19.83 27.02,19.85 27.67,19.2 27.67,17.08 27.48,16.89 25.38,16.89 24.54,16.05 24.54,15.6 24.45,15.51 23.54,15.51 23.3,15.75 23.3,17.84 23.49,18.03 25.89,18.03 25.89,18.06 26.13,18.3 26.13,19.16 25.88,19.42 25.16,19.42 24.72,19.86 24.72,20.4 25.04,20.71 26.16,20.71
+VCC_3IN1 on IN1 (solid shape): 14.74,22.02 14.74,20.29 14.63,20.19 13.87,20.19 13.73,20.32 13.73,21.98 13.93,22.17 14.58,22.17
+VCC_3IN1 on IN1 (solid shape): 23.17,17.97 23.68,17.97 23.81,17.84 23.81,17.08 23.62,16.89 22.85,16.89 22.28,17.46 22.28,17.72 22.79,18.22 22.92,18.22
+VDD_CT on TOP (solid shape): 162.94,129.39 162.94,127.89 162.91,127.87 162.71,127.57 162.91,127.26 162.94,127.25 162.94,127.05 162.76,126.75 162.94,126.46 162.94,126.35 162.9,126.34 162.66,126.05 162.84,125.72 162.84,125.42 162.94,125.32 162.94,125.29 162.75,125.1 162,125.1 161.89,125.2 161.89,127.85 162.18,128.14 162.18,129.44 162.29,129.55 162.78,129.55
+VDD_CT on BOTTOM (solid shape): 163.3,130.01 163.6,129.81 163.9,130.01 163.92,130.04 164.19,130.04 164.35,129.87 164.35,128.65 164.2,128.49 162.69,128.49 162.47,128.71 162.47,129.84 162.67,130.04 163.29,130.04
+VDD_TOUCH on TOP (solid shape): 90.86,152.25 90.86,150.8 90.71,150.65 88.02,150.65 87.88,150.79 87.22,150.79 86.77,150.34 86.1,150.34 86.07,150.37 86.07,152.43 86.29,152.65 90.45,152.65
+VDD_TOUCH on BOTTOM (solid shape): 100.84,168.75 100.84,167.52 101.02,167.34 101.02,165.15 100.95,165.07 100.54,165.07 100.16,165.46 100.16,166.41 99.39,167.18 99.39,168.9 99.52,169.04 100.55,169.04
+VDD_TOUCH on IN1 (solid shape): outline of 221 points within 86.53,151.4 100.49,169.12
+VDDCI on TOP (solid shape): 165.08,136.21 165.08,135.24 165.22,135.1 165.81,135.1 165.89,135.17 165.9,135.18 166.01,135.29 166.01,136.22 166.2,136.4 166.78,136.4 166.91,136.27 166.91,135.2 167.05,135.06 167.73,135.06 167.88,135.21 167.88,136.28 168.07,136.47 169.55,136.47 169.85,136.18 169.85,135.58 170.17,135.26 171.62,135.26 171.81,135.19 172.01,135.26 172.25,135.26 172.41,135.19 172.58,135.2 172.61,135.22 172.72,135.11 172.72,134.6 172.51,134.39 166.75,134.39 166.25,134.39 166.24,134.39 165.9,134.39 165.89,134.39 165.18,134.39 165.17,134.39 164.92,134.39 164.3,134.39 164.11,134.57 164.11,134.58 164.11,135.81 163.97,135.95 163.33,135.95 163.24,136.04 163.24,136.39 163.34,136.49 164.8,136.49
+VDDCI on BOTTOM (solid shape): 165.17,137.09 165.23,137.06 165.27,136.99 165.6,136.68 165.93,136.99 165.96,137.06 166.03,137.09 166.61,137.09 166.84,136.85 168.99,136.85 169.17,136.68 169.17,136.44 168.67,135.94 167.83,135.94 167.75,135.98 167.74,136.07 167.43,136.52 167.11,136.07 167.1,135.98 167.02,135.94 166.01,135.94 165.93,135.98 165.91,136.07 165.6,136.5 165.28,136.07 165.27,135.98 165.19,135.94 164.87,135.94 164.22,135.28 163.93,135.28 163.26,135.96 162.98,135.96 162.91,135.99 162.88,136.05 162.82,136.22 162.68,136.33 162.64,136.35 162.64,136.64 162.79,136.78 162.8,136.79 162.89,136.85 162.96,136.95 162.96,136.96 163.09,137.09
+VDDCR_FCH_ALW on BOTTOM (solid shape): 50.09,61.66 50.09,55.69 50.03,55.63 48.06,55.63 47.24,56.45 47.24,60.96 48,61.72 50.03,61.72
+VDDCR_FCH_ALW on IN1 (solid shape): 133,89.48 133,88.65 132.77,88.42 131.16,88.42 130.88,88.7 130.88,89.41 131.86,89.41 131.86,89.36 131.86,89.3 131.88,89.26 131.9,89.21 131.93,89.17 131.97,89.13 132.01,89.1 132.06,89.08 132.11,89.06 132.16,89.05 132.21,89.05 132.26,89.06 132.31,89.08 132.36,89.1 132.4,89.13 132.44,89.17 132.47,89.21 132.49,89.26 132.51,89.3 132.52,89.36 132.52,89.41 132.51,89.46 132.49,89.51 132.47,89.56 132.44,89.6 132.4,89.63 132.36,89.66 132.31,89.69 132.26,89.7 132.21,89.71 132.16,89.71 132.11,89.7 132.06,89.69 132.01,89.66 131.97,89.63 131.93,89.6 131.9,89.56 131.88,89.51 131.86,89.46 131.86,89.41 130.88,89.41 130.88,89.92 130.98,90.02 132.47,90.02
+VDDD on BOTTOM (solid shape): 167,30.99 167,29.21 167.19,29.02 167.19,27.43 168.08,26.54 168.4,26.54 168.52,26.42 168.52,26.29 168.46,26.23 167.32,26.23 166.3,27.24 166.3,30.99 166.43,31.11 166.87,31.11
+VDDR3 on TOP (solid shape): 165.35,129.22 165.35,127.38 165.6,127.14 166.11,127.14 166.17,127.08 166.17,126.55 166.09,126.47 164.72,126.47 164.63,126.56 164.63,127.72 164.42,127.93 163.45,127.93 163.34,128.04 163.34,128.73 163.52,128.9 164.3,128.9 164.46,129.06 164.46,129.07 164.49,129.1 164.49,129.38 164.62,129.51 165.06,129.51
+VDDR3 on BOTTOM (solid shape): 165.29,130.03 165.58,129.87 165.86,130.03 166.22,130.03 166.27,129.97 166.34,129.92 166.35,129.91 166.35,128.65 166.21,128.5 164.67,128.5 164.5,128.67 164.5,129.71 164.53,129.79 164.61,129.81 164.79,129.86 164.91,130 164.93,130.03
GND on TOP (solid shape): 31.02,12.79 31.02,11.66 30.92,11.56 28.9,11.56 28.72,11.73 28.72,12.74 28.89,12.9 30.91,12.9
GND on TOP (solid shape): 39.63,20.78 39.63,19.88 39.45,19.7 36.16,19.7 36,19.85 36,20.71 36.24,20.94 39.46,20.94
GND on TOP (solid shape): 44.2,14.25 44.2,12.08 43.8,11.67 41.66,11.67 41.5,11.84 41.5,14.48 41.6,14.58 43.87,14.58
GND on TOP (solid shape): 71.43,26.8 71.43,23.37 71.3,23.24 68.89,23.24 68.76,23.37 68.76,26.8 68.89,26.92 71.3,26.92
GND on TOP (solid shape): 119.18,85.29 119.18,81.21 119.02,81.05 118.42,81.05 118.21,81.25 118.21,85.31 118.29,85.39 119.09,85.39
GND on TOP (solid shape): 121.69,85.27 121.69,81.19 121.53,81.03 120.93,81.03 120.72,81.23 120.72,85.29 120.8,85.36 121.59,85.36
GND on TOP (solid shape): 136.48,170.88 136.48,169.61 136.3,169.43 132.87,169.43 132.71,169.6 132.71,170.98 132.76,171.03 136.33,171.03
GND on TOP (solid shape): 145.41,145.41 145.41,142.88 145.22,142.68 138.11,142.68 137.79,143 137.79,145.1 138.47,145.78 145.04,145.78
GND on TOP (solid shape): 157.75,43.61 157.75,40.39 157.17,39.8 154.34,39.8 153.76,40.37 153.76,43.83 154.08,44.15 157.22,44.15
GND on TOP (solid shape): 158.36,124.93 158.36,123.65 158.06,123.34 154.53,123.34 154.41,123.46 154.41,123.92 155.61,125.12 158.17,125.12
GND on TOP (solid shape): 184.37,141.45 184.37,140.7 184.04,140.37 180.25,140.37 180.11,140.51 180.11,141.54 180.25,141.68 184.13,141.68
GND on TOP (solid shape): 184.66,124.76 184.66,122.87 183.45,121.66 182.52,121.66 182.34,121.84 182.34,124.93 182.45,125.04 184.38,125.04
GND on TOP (solid shape): 94.38,146.52 94.38,144.44 94.18,144.23 93.38,144.23 92.89,144.72 92.64,144.72 92.4,144.96 92.4,146.34 92.73,146.67 94.23,146.67
GND on TOP (solid shape): 143.19,127.38 143.19,124.71 143.06,124.59 140.26,124.59 139.38,125.48 139.38,127.7 139.5,127.83 142.74,127.83
GND on TOP (solid shape): 149.79,176.4 149.79,175.77 149.66,175.64 149.03,175.64 148.77,175.89 142.04,175.89 141.92,176.02 141.92,177.29 142.3,177.67 148.52,177.67
GND on TOP (solid shape): 89.23,150.49 90.06,150.49 90.26,150.28 90.26,148.32 90.11,148.17 88.04,148.17 87.09,149.12 87.09,150.34 87.24,150.5 89.22,150.5
GND on TOP (solid shape): 111.82,130.17 112.83,130.17 113.02,129.98 113.02,121.03 112.64,120.65 110.55,120.65 110.17,121.03 110.17,130.56 110.29,130.68 111.31,130.68
GND on TOP (solid shape): 31.86,74.04 31.86,72.9 32.25,72.5 32.25,70.99 32.19,70.93 31.2,70.93 31.11,71.02 31.11,73.97 31.25,74.1 31.79,74.1
GND on TOP (solid shape): 56.76,168.72 56.76,167.83 56.57,167.64 55.17,167.64 54.54,168.27 53.02,168.27 52.95,168.34 52.95,168.85 53.14,169.04 56.44,169.04
GND on TOP (solid shape): 60.7,23.43 60.7,22.48 60.83,22.35 61.46,22.35 61.46,20.64 59.75,20.64 59.75,22.35 60.32,22.35 60.45,22.48 60.45,23.43 60.51,23.5 60.64,23.5
GND on TOP (solid shape): 61.14,20.32 61.14,19.49 61.91,18.73 61.91,18.54 61.78,18.41 61.46,18.41 60.89,18.99 60.89,20.32 60.95,20.38 61.08,20.38
GND on TOP (solid shape): 123.69,148.59 123.69,148.21 123.37,147.89 119.88,147.89 119.82,147.95 119.82,148.78 119.88,148.84 120.64,148.84 120.9,149.1 123.18,149.1
GND on TOP (solid shape): 139.41,51.64 139.41,39.33 138.98,38.9 132,38.9 130.55,40.35 130.55,52.5 130.63,52.58 138.47,52.58
GND on TOP (solid shape): 172.04,126.25 172.04,125.23 171.86,125.05 170.82,125.05 170.19,125.69 168.67,125.69 168.58,125.78 168.58,126.17 168.72,126.3 170.99,126.3 171.07,126.39 171.9,126.39
GND on TOP (solid shape): 183.21,138.32 183.21,137.36 183.01,137.17 182.09,137.17 181.95,137.3 181.95,137.62 181.8,137.77 180.27,137.77 180.13,137.9 180.13,138.28 180.31,138.46 183.07,138.46
GND on TOP (solid shape): 28.7,23.18 28.7,21.15 28.56,21.01 27.53,21.01 27.52,21.01 26.89,21.01 26.66,21.23 26.66,22.89 27.15,23.37 28.5,23.37
GND on TOP (solid shape): 124.52,40.77 124.52,38.73 123.88,38.1 122.23,38.1 121.98,38.35 121.98,40.89 121.85,41.02 118.42,41.02 118.29,41.15 118.29,41.66 118.55,41.91 123.37,41.91
GND on TOP (solid shape): 124.78,13.98 124.78,13.32 124.96,13.14 126.03,13.14 126.49,13.6 131.36,13.6 131.53,13.44 131.53,12.64 131.11,12.22 113.56,12.22 112.96,12.83 112.96,13.97 113.09,14.1 124.67,14.1
GND on TOP (solid shape): 125.09,80.3 125.09,79.22 124.62,78.75 124.62,78.28 124.54,78.2 123.94,78.2 123.53,78.2 123.22,78.51 123.22,79.25 124.04,80.07 124.04,80.35 124.2,80.5 124.89,80.5
GND on TOP (solid shape): 68.58,26.68 68.58,25.74 67.75,24.91 67.75,22.22 67.62,22.1 66.35,22.1 66.29,22.16 66.29,25.5 66.29,25.51 66.29,26.52 66.66,26.89 68.37,26.89
GND on TOP (solid shape): 169.84,134.15 169.84,132.42 169.39,131.96 169.39,130.52 169.61,130.3 169.61,130.1 169.49,129.98 169.18,129.98 168.62,130.54 168.62,131.94 169.05,132.37 169.05,134.18 169.15,134.29 169.7,134.29
GND on TOP (solid shape): 86.42,56.9 86.41,56.89 86.41,38.78 84.95,37.32 81.05,37.32 80.84,37.53 80.84,39.74 80.01,40.57 80.01,49.41 80.98,50.37 80.98,56.96 81.55,57.53 85.78,57.53
GND on TOP (solid shape): 107.12,42.16 111.56,42.16 111.94,41.78 111.94,41.02 111.82,40.89 105.21,40.89 104.96,41.15 104.96,43.31 105.09,43.43 105.85,43.43
GND on TOP (solid shape): 162,129.42 162,128.21 161.78,128 161.78,126.35 161.55,126.12 160.65,126.12 160.54,126.23 160.54,127.02 160.3,127.25 158.58,127.25 158.21,127.62 158.21,127.63 157.98,127.86 157.98,129.35 158.21,129.58 161.84,129.58
GND on TOP (solid shape): 171.19,108.98 171.19,108.98 171.37,108.8 171.67,108.8 172.52,107.95 173.92,107.95 174.17,107.7 174.17,106.81 173.79,106.43 169.22,106.43 168.84,106.81 168.84,109.06 169.24,109.46 170.71,109.46
GND on TOP (solid shape): 73.08,45.4 73.08,42.29 72.45,41.66 62.41,41.66 62.16,41.91 62.16,44.32 62.54,44.7 65.84,44.7 65.97,44.58 65.97,43.94 66.22,43.69 66.73,43.69 68,44.96 68,45.48 68.15,45.63 72.85,45.63
GND on TOP (solid shape): 167.8,134.15 167.8,132.27 167.56,132.03 167.56,132.03 167.33,131.8 167.33,130.57 167.6,130.3 167.6,130.08 167.47,129.95 167.23,129.95 166.7,130.49 166.7,131.91 166.99,132.19 166.99,134.1 167.13,134.25 167.7,134.25
GND on TOP (solid shape): 41.59,43.69 41.59,39.24 41.46,39.12 40.32,39.12 39.55,38.35 36.25,38.35 36,38.61 36,40.13 36.12,40.26 37.01,40.26 37.78,41.02 37.78,41.4 36.12,43.05 36.12,44.07 36.38,44.32 40.95,44.32
GND on TOP (solid shape): 158.93,136.91 158.93,136.21 158.71,135.98 158.71,131.05 158.66,131 158.01,131 157.88,130.87 157.88,130.66 157.76,130.54 157.4,130.54 157.3,130.64 157.3,135.95 157.32,135.98 157.32,136.88 157.41,136.97 158.87,136.97
GND on TOP (solid shape): 136.54,97.73 136.84,97.73 137.09,97.47 137.09,96.84 136.84,96.58 136.01,96.58 135.69,96.27 134.8,96.27 134.3,96.77 134.3,97.98 133.92,98.36 131.92,98.36 131.85,98.42 131.85,99.39 131.57,99.67 130.03,99.67 129.8,99.89 129.8,100.56 129.98,100.74 133.53,100.74
GND on TOP (solid shape): 176.05,135.74 176.05,134.66 175.84,134.46 175.11,134.46 174.8,134.15 174.27,134.15 174.13,134.29 174.13,134.56 173.87,134.83 173.43,134.83 173.33,134.93 173.33,135.38 173.35,135.42 173.36,135.47 173.44,135.55 174.76,135.55 175.13,135.92 175.87,135.92
GND on TOP (solid shape): 165.92,134.22 165.92,132.23 165.54,131.85 165.54,131.45 165.54,131.44 165.54,130.67 165.54,130.66 165.54,130.57 165.81,130.3 165.81,130.07 165.71,129.96 165.42,129.96 164.85,130.52 164.85,131.94 164.9,131.98 164.9,131.99 165.05,132.14 165.05,132.14 165.1,132.2 165.1,134.18 165.22,134.29 165.85,134.29
GND on TOP (solid shape): 152.16,86.18 152.16,83.16 152.16,83.16 152.16,82.8 151.13,81.77 151.13,80.69 151.13,80.69 151.13,80 151.05,79.92 149.03,79.92 148.93,80.02 148.93,83.56 148.58,83.9 142.83,83.9 142.78,83.95 142.78,84.55 142.83,84.61 143.21,84.61 143.46,84.87 149.66,84.87 149.67,84.88 150.02,84.88 150.62,85.47 150.62,86.53 150.77,86.68 151.66,86.68
GND on TOP (solid shape): 97.29,157.14 97.3,157.13 97.82,157.13 97.84,157.16 97.84,157.68 98.09,157.68 98.09,157.14 98.11,157.13 98.56,157.13 98.84,156.84 98.84,154.56 98.08,153.8 96.04,153.8 95.75,154.09 95.75,156.93 95.92,157.1 96.51,157.1 96.54,157.13 97.05,157.13 97.04,157.13 97.04,157.65 97.06,157.68 97.29,157.68
GND on TOP (solid shape): 163.6,134.34 163.71,134.24 163.85,134.2 163.93,134.17 163.96,134.1 163.96,132.26 163.84,132.15 163.84,130.38 164.41,129.82 164.41,129.44 164.39,129.43 164.39,129.14 164.27,129.01 163.35,129.01 163.07,129.3 163.07,132.14 163.24,132.32 163.24,134.27 163.34,134.37 163.59,134.37
GND on TOP (solid shape): 168.46,95.25 168.46,95 168.97,94.49 172.65,94.49 172.78,94.36 172.78,92.96 172.65,92.84 172.01,92.84 171.63,92.46 171.63,90.3 172.01,89.92 172.65,89.92 172.78,89.79 172.78,89.15 172.65,89.03 169.86,89.03 169.54,89.34 169.54,89.98 169.28,90.23 168.9,90.23 168.2,90.93 167.57,90.93 167.44,91.06 167.44,91.69 167.82,92.07 167.82,95.38 168.33,95.38
GND on TOP (solid shape): 108.71,85.1 108.71,85.08 108.7,84.96 108.74,84.85 108.74,84.84 108.74,80.23 108.73,80.21 108.73,79.66 108.99,79.4 108.99,78.91 108.84,78.77 107.81,78.77 107.23,79.36 106.28,79.36 106.16,79.48 106.16,81.82 107.58,83.24 107.58,84.3 107.58,84.31 107.6,84.42 107.58,84.53 107.58,84.54 107.58,84.82 108.03,85.27 108.54,85.27
GND on TOP (solid shape): 169.08,128.12 169.77,128.12 169.79,128.09 170.1,127.88 170.4,128.09 170.42,128.12 170.97,128.12 171.06,128.03 171.06,127.72 171.06,127.71 171.03,127.61 171.04,127.51 171.04,127.49 170.95,127.39 169.09,127.39 168.93,127.23 167.03,127.23 166.92,127.34 166.92,128.35 167.01,128.44 168.76,128.44
GND on TOP (solid shape): 125.75,89.63 125.75,88.39 125.85,88.29 126.23,88.29 126.25,88.27 126.25,87.76 126.25,87.75 125.37,87.75 125.15,87.53 125.15,87.49 125.11,87.45 125.11,87.24 124.86,87 124.67,87 124.67,86.23 124.71,86.23 124.71,86.11 124.67,86.11 124.67,85.34 124.71,85.34 124.71,81.65 124.64,81.57 124.07,81.57 123.98,81.67 123.98,82.99 123.33,83.63 123.33,83.9 123.33,83.9 123.33,84.11 123.98,84.76 123.98,85.22 123.28,85.93 123.28,86.49 123.28,86.49 123.28,86.56 125.04,88.31 125.04,89.7 125.12,89.79 125.6,89.79
GND on TOP (solid shape): 143.57,88.76 143.67,88.55 143.88,88.46 143.92,88.44 143.93,88.4 143.93,88.1 143.85,88.02 143.82,88.03 143.49,87.95 143.41,87.62 143.42,87.59 142.46,86.63 142.46,86.43 142.39,86.36 141.65,86.36 141.54,86.47 141.54,88.7 141.65,88.81 143.56,88.81
GND on TOP (solid shape): 156.95,88.99 156.95,86.61 156.9,86.53 156.8,86.52 156.34,86.36 156.55,85.92 156.62,85.84 156.59,85.75 156.08,85.23 156.08,85.22 155.78,84.92 154.65,84.92 154.55,85.03 154.55,88.25 155.5,89.2 156.74,89.2
GND on TOP (solid shape): 172.52,133.48 172.6,133.44 172.62,133.36 172.81,132.97 173.22,133.11 173.3,133.16 173.39,133.11 173.8,132.98 173.99,133.36 174.01,133.44 174.09,133.48 174.56,133.48 174.68,133.36 174.68,132.94 174.08,132.34 174.06,132.34 173.98,132.32 173.9,132.28 172.05,132.28 171.91,132.42 171.91,133.38 172.01,133.48
GND on TOP (solid shape): 132.78,77.66 132.78,77.19 132.77,77.16 132.75,77.12 132.74,77.07 132.74,77.02 132.74,76.97 132.75,76.93 132.77,76.88 132.78,76.85 132.78,75.98 132.59,75.78 132.59,75.74 132.58,75.73 132.58,75.29 132.51,75.22 132.51,75.2 132.34,75.02 131.83,75.02 131.68,75.17 131.64,75.17 131.45,75.36 131.45,75.95 131.24,76.16 130.63,76.16 130.55,76.24 130.55,77.05 131.94,77.05 131.94,77 131.94,76.94 131.96,76.89 131.98,76.85 132.02,76.81 132.05,76.77 132.09,76.74 132.14,76.72 132.19,76.7 132.24,76.69 132.29,76.69 132.34,76.7 132.39,76.72 132.44,76.74 132.48,76.77 132.52,76.81 132.55,76.85 132.57,76.89 132.59,76.94 132.6,77 132.6,77.05 132.59,77.1 132.57,77.15 132.55,77.19 132.52,77.24 132.48,77.27 132.44,77.3 132.39,77.33 132.34,77.34 132.29,77.35 132.24,77.35 132.19,77.34 132.14,77.33 132.09,77.3 132.05,77.27 132.02,77.24 131.98,77.19 131.96,77.15 131.94,77.1 131.94,77.05 130.55,77.05 130.55,77.72 130.66,77.83 131.17,77.83 131.22,77.88 131.23,77.88 131.48,78.13 132.31,78.13
GND on TOP (solid shape): 165.26,137.39 165.36,137.34 165.34,137.23 165.6,136.68 165.85,137.23 165.84,137.34 165.93,137.39 172.16,137.39 172.24,137.31 172.24,136.91 171.81,136.48 171.81,135.98 171.73,135.91 171.43,135.91 170.92,135.39 170.18,135.39 170.06,135.51 170.06,136.45 169.95,136.57 169.61,136.57 169.6,136.58 168.03,136.58 168.02,136.57 167.81,136.57 167.74,136.49 167.74,135.27 167.66,135.19 167.13,135.19 167.07,135.25 167.07,136.49 166.99,136.57 166.04,136.57 165.93,136.45 165.93,136.28 165.91,136.26 165.91,135.34 165.81,135.24 165.23,135.24 165.21,135.27 165.21,136.48 165.12,136.57 164.87,136.57 164.84,136.59 163.3,136.59 163.27,136.57 163.12,136.57 163.02,136.66 163.02,137.17 163.14,137.28 163.6,137.28 163.75,137.13 164.27,137.13 164.54,137.39
GND on TOP (solid shape): outline of 87 points within 178.49,94.87 190.05,108.58
GND on TOP (solid shape): outline of 111 points within 107.86,139.98 132.64,148.72
GND on TOP (solid shape): outline of 81 points within 111.31,78.77 113.07,89.58
GND on TOP (solid shape): outline of 124 points within 126.43,77.79 130.38,86.97
GND on TOP (solid shape): 14.74,66.03 14.83,65.96 14.81,65.85 15.2,64.92 15.59,65.85 15.57,65.96 15.66,66.03 16.94,66.03 20.54,62.42 20.57,62.42 20.95,62.04 20.95,59.94 21.08,59.82 21.76,59.82 21.95,60.01 21.95,60.25 22.02,60.34 22.13,60.32 22.48,60.23 22.7,60.52 22.71,60.52 23.06,60.52 23.3,60.76 23.36,60.71 21.85,59.2 19.59,59.2 18.4,60.39 18.31,60.71 17.99,60.8 16.48,62.31 16.48,63.03 14.29,65.22 14.3,65.25 14.34,65.57 14.19,65.85 14.17,65.96 14.26,66.03
GND on TOP (solid shape): outline of 263 points within 113.91,78.56 116.79,89.62
GND on TOP (solid shape): outline of 84 points within 0.25,73.67 92.27,163.89
GND on TOP (solid shape): outline of 761 points within 0.25,45.72 32.68,69.41
GND on TOP (solid shape): outline of 895 points within 2.33,0.25 204.3,181.72
GND on BOTTOM (solid shape): 43.65,164.42 45.65,164.42 45.65,160.32 31.65,160.32 31.65,169.65 43.65,169.65
GND on BOTTOM (solid shape): 50.79,39.31 50.79,36.32 50.48,36 48,36 47.68,36.32 47.68,39.37 47.81,39.5 50.6,39.5
GND on BOTTOM (solid shape): 63.18,66.67 63.18,59.82 62.67,59.31 59.87,59.31 59.75,59.44 59.75,66.93 59.87,67.06 62.79,67.06
GND on BOTTOM (solid shape): 79.38,158.55 79.38,157.24 79.29,157.15 78.03,157.15 77.9,157.28 77.9,158.5 78.01,158.61 79.32,158.61
GND on BOTTOM (solid shape): 100.32,153.03 100.32,151.89 99.94,151.51 95.75,151.51 95.31,151.96 95.31,153.16 95.62,153.48 99.88,153.48
GND on BOTTOM (solid shape): 113.09,125.22 113.09,117.73 112.83,117.47 110.67,117.47 110.42,117.73 110.42,125.09 110.8,125.48 112.83,125.48
GND on BOTTOM (solid shape): 120.64,156.57 120.64,153.29 120.31,152.97 116.8,152.97 116.46,153.31 116.46,156.65 116.54,156.73 120.48,156.73
GND on BOTTOM (solid shape): 123.75,126.87 123.75,119.25 123.5,119 121.09,119 120.83,119.25 120.83,126.75 121.09,127 123.63,127
GND on BOTTOM (solid shape): 136.45,149.61 136.45,146.88 136.07,146.49 135.18,146.49 135.12,146.56 135.12,149.86 135.18,149.92 136.14,149.92
GND on BOTTOM (solid shape): 157.22,180.15 157.22,178.5 155.89,177.16 152.08,177.16 151.57,177.67 151.57,180.21 152.01,180.66 156.71,180.66
GND on BOTTOM (solid shape): 167.83,120.34 167.83,117.46 167.8,117.43 166.5,117.43 166.32,117.61 166.32,120.19 166.72,120.59 167.57,120.59
GND on BOTTOM (solid shape): 169.55,21.78 169.55,20.27 169.13,19.85 168.4,19.85 168.26,19.99 168.26,21.92 168.34,22.01 169.32,22.01
GND on BOTTOM (solid shape): 193.48,157.54 193.48,154.75 193.1,154.37 192.02,154.37 191.97,154.42 191.97,157.68 192.02,157.73 193.29,157.73
GND on BOTTOM (solid shape): 195.61,42.21 195.61,40.32 195.43,40.14 192.74,40.14 192.56,40.32 192.56,42.19 192.84,42.47 195.36,42.47
GND on BOTTOM (solid shape): 197.41,127.7 197.41,125.48 197.22,125.29 184.84,125.29 184.65,125.48 184.65,127.89 184.71,127.95 197.16,127.95
GND on BOTTOM (solid shape): 202.94,156.78 202.94,153.67 202.88,153.61 201.61,153.61 201.42,153.8 201.42,156.72 201.54,156.84 202.88,156.84
GND on BOTTOM (solid shape): 61.59,37.4 61.59,35.24 62.44,34.39 62.44,33.08 62.38,33.02 57.46,33.02 57.21,33.27 57.21,37.59 57.33,37.72 61.27,37.72
GND on BOTTOM (solid shape): 152.27,49.97 152.27,46.93 152.01,46.67 150.74,46.67 150.62,46.8 150.62,50.1 150.74,50.23 152.01,50.23
GND on BOTTOM (solid shape): 182.94,117.16 182.94,113.79 182.68,113.54 180.52,113.54 180.21,113.86 180.21,117.35 180.27,117.41 182.68,117.41
GND on BOTTOM (solid shape): 31.17,39.12 31.17,35.88 30.85,35.56 29.01,35.56 27.74,36.83 27.74,39.31 27.93,39.5 30.79,39.5
GND on BOTTOM (solid shape): 73.84,67.82 73.84,64.9 73.69,64.74 71.21,64.74 70.41,65.53 70.41,68.07 70.54,68.2 73.46,68.2
GND on BOTTOM (solid shape): 142.93,127.38 142.93,122.35 142.53,121.94 139.6,121.94 139.38,122.16 139.38,127.63 139.63,127.89 142.42,127.89
GND on BOTTOM (solid shape): 184.75,124.4 184.75,122.05 183.81,121.11 182.42,121.11 182.17,121.35 182.17,124.71 182.3,124.84 184.31,124.84
GND on BOTTOM (solid shape): 43.17,52.07 43.17,51.31 43.43,51.05 44,51.05 44.06,50.99 44.06,50.36 43.24,49.53 40.89,49.53 39.87,50.55 39.87,52.07 39.93,52.13 43.11,52.13
GND on BOTTOM (solid shape): 52.76,60.77 52.76,55.78 52.61,55.63 50.86,55.63 50.73,55.75 50.73,61.59 50.86,61.72 51.81,61.72
GND on BOTTOM (solid shape): 30.35,53.02 30.35,50.55 29.9,50.1 29.9,48.45 29.71,48.26 29.33,48.26 29.14,48.45 29.14,50.29 28.89,50.55 27.43,50.55 27.36,50.61 27.36,53.02 27.43,53.09 30.28,53.09
GND on BOTTOM (solid shape): 69.27,25.46 69.27,17.08 69.53,16.83 71.56,16.83 71.68,16.7 71.68,12.64 71.37,12.32 69.14,12.32 67.81,13.65 67.81,16.95 68.13,17.27 68.13,25.4 68.26,25.53 69.21,25.53
GND on BOTTOM (solid shape): 143.95,145.03 145.22,145.03 145.6,144.65 145.6,142.37 145.47,142.24 136.96,142.24 136.58,141.86 135.82,141.86 135.69,141.99 135.69,144.91 136.59,145.8 143.18,145.8
GND on BOTTOM (solid shape): 27.22,35.57 27.22,34.59 27.03,34.4 25.95,34.4 25.36,33.81 23.07,33.81 22.31,34.57 21.84,34.57 21.68,34.72 21.68,35.5 21.84,35.65 25.09,35.65 25.32,35.88 26.92,35.88
GND on BOTTOM (solid shape): 56.64,169.1 56.64,168.15 56.19,167.7 54.48,167.7 54.22,167.45 54.21,167.45 54.21,167.14 54.15,167.08 53.51,167.08 53.4,167.2 53.4,169.1 53.63,169.33 56.4,169.33
GND on BOTTOM (solid shape): 157.94,44.07 157.94,43.31 157.91,43.27 156.64,43.27 156.51,43.14 156.51,42.01 155.66,41.16 155.66,40.02 155.56,39.92 154.76,39.92 154.72,39.95 154.72,42.82 155.01,43.12 155.01,43.97 155.17,44.13 157.88,44.13
GND on BOTTOM (solid shape): 184.34,141.55 184.34,140.34 184.24,140.25 183.57,140.25 183.41,140.08 183.41,139.6 183.27,139.46 181.83,139.46 181.74,139.55 181.74,140.04 182.33,140.63 182.33,140.93 182.33,140.94 182.33,141.03 183.01,141.71 184.18,141.71
GND on BOTTOM (solid shape): 18.75,45.29 22.6,45.29 22.85,45.03 22.85,43.81 22.6,43.56 19.2,43.56 19.02,43.74 19.02,43.79 18.97,43.79 18.95,43.82 18.12,43.82 17.68,44.26 17.14,44.26 16.9,44.5 16.86,44.5 16.81,44.55 16.81,45.36 17.15,45.71 18.33,45.71
GND on BOTTOM (solid shape): 65.4,44.96 65.4,44.01 65.91,43.5 67.56,43.5 68.07,44.01 68.07,45.02 68.19,45.15 73.34,45.15 73.46,45.02 73.46,43.56 73.25,43.35 73.25,42.33 72.45,41.53 62.54,41.53 62.16,41.91 62.16,45.02 62.35,45.21 65.14,45.21
GND on BOTTOM (solid shape): 174.57,18.56 174.68,18.55 174.79,18.56 174.8,18.57 177.71,18.57 177.78,18.5 177.78,18.02 177.69,17.94 176.09,17.94 175.93,17.78 175.93,16.23 175.81,16.1 174.49,16.1 174.1,16.5 174.1,18.29 174.38,18.57 174.56,18.57
GND on BOTTOM (solid shape): 41.71,44.32 41.71,43.18 40.95,42.42 40.95,39.69 39.81,38.54 37.78,38.54 37.59,38.73 37.59,38.99 37.27,39.31 37.27,40.32 37.84,40.89 37.84,41.91 37.52,42.23 36.7,42.23 35.24,43.69 35.24,44.32 35.36,44.45 41.59,44.45
GND on BOTTOM (solid shape): 120.96,146.81 120.96,144.21 120.77,144.02 117.85,144.02 117.72,144.14 117.72,145.16 117.4,145.48 115.37,145.48 115.06,145.16 115.06,144.21 114.86,144.02 111.25,144.02 110.42,143.19 107.5,143.19 106.86,143.83 106.86,147.07 107.5,147.7 120.07,147.7
GND on BOTTOM (solid shape): 132.9,147.38 132.9,145.57 133.14,145.33 133.14,140.22 132.98,140.06 131.74,140.06 131.55,139.87 130.44,139.87 130.08,140.22 130.08,141.65 130.05,141.67 130.05,141.73 129.81,141.97 129.58,141.97 129.22,142.34 129.22,145.73 128.7,146.25 126.68,146.25 126.47,146.46 126.47,149.53 126.56,149.62 130.66,149.62
GND on BOTTOM (solid shape): 133.85,171.39 136.65,171.39 137.53,170.5 137.53,166.5 137.47,166.43 136.58,166.43 136.52,166.5 136.52,169.16 136.33,169.35 135.31,169.35 135.06,169.1 135.06,168.08 134.99,168.02 133.28,168.02 132.71,168.59 132.71,169.67 132.45,169.93 130.8,169.93 130.68,170.05 130.66,170.05 130.66,171.3 130.32,171.64 127.45,171.64 127.31,171.5 127.31,164.85 126.93,164.47 125.79,164.47 125.66,164.59 125.66,171.88 125.91,172.14 126.21,172.14 127.12,173.05 132.19,173.05
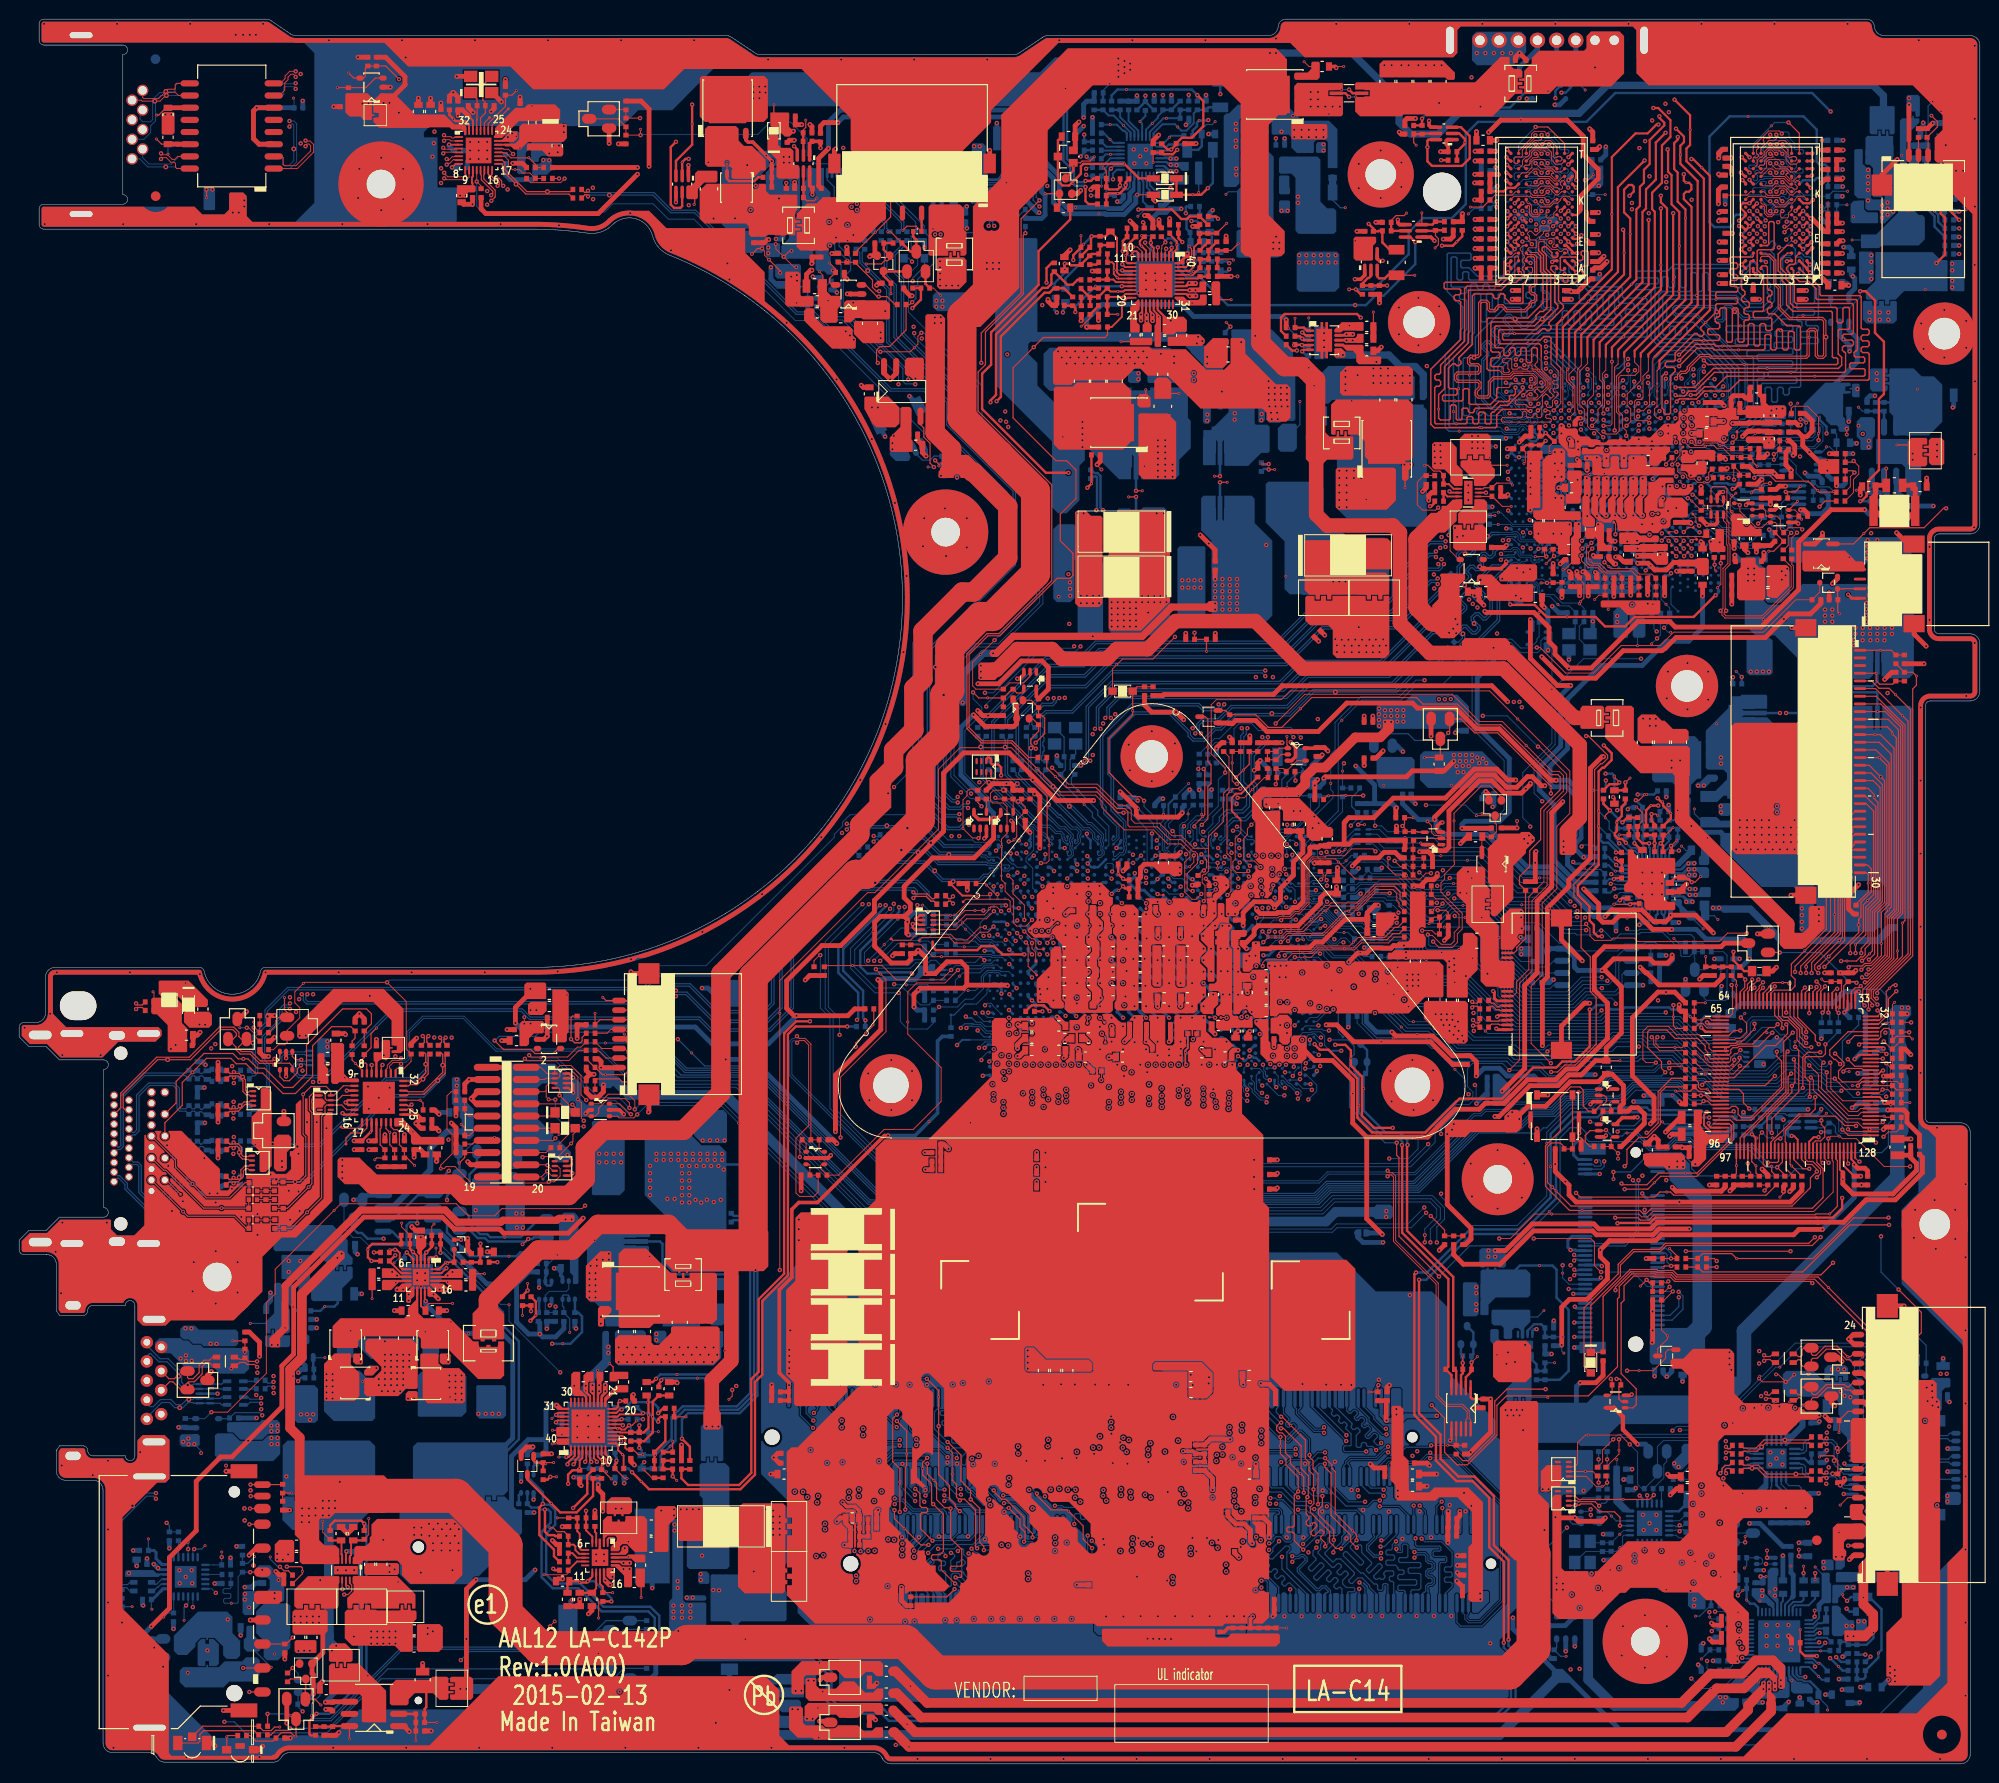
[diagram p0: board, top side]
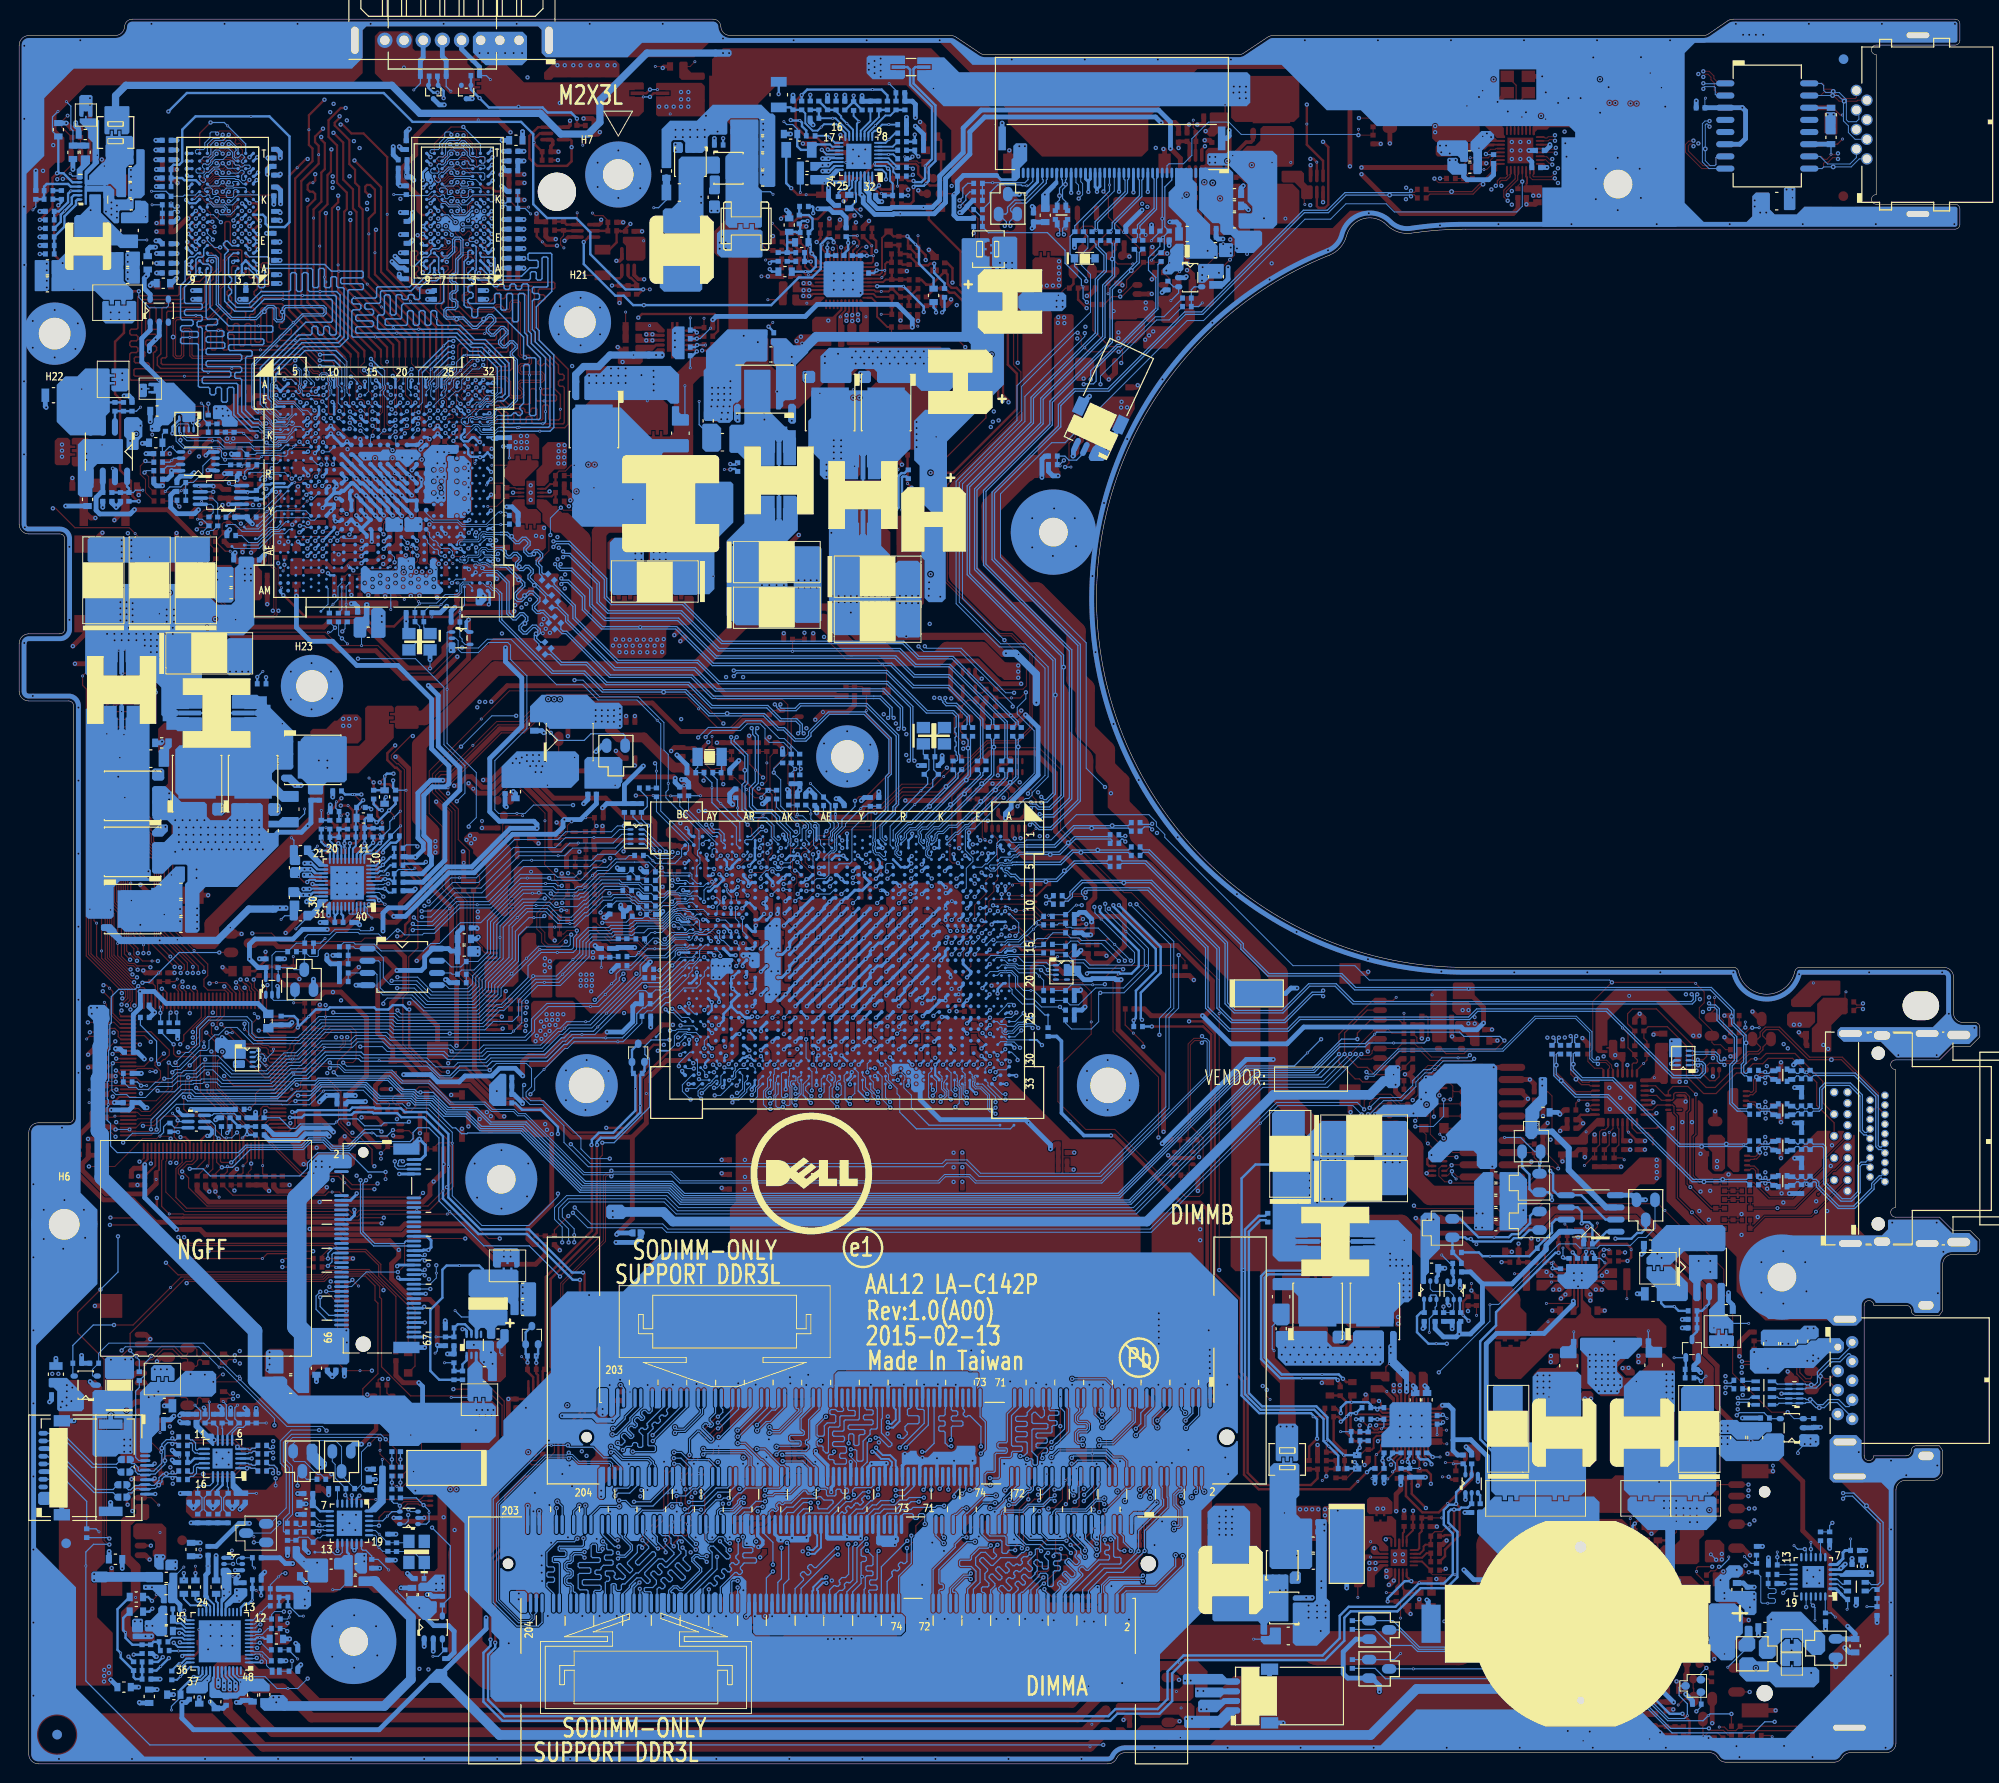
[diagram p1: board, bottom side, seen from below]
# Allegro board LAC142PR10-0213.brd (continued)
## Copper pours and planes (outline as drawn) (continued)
GND on BOTTOM (solid shape): 192.33,168.35 192.33,166.89 192.7,166.52 193.07,166.52 193.2,166.4 193.2,163.33 193.36,163.17 194.53,163.17 194.62,163.26 194.62,164.16 195.04,164.58 197.68,164.58 197.73,164.53 197.73,162.62 197.72,162.61 197.49,162.61 197.48,162.62 197.48,163.96 197.47,163.97 195.8,163.97 195.76,163.93 195.76,161.8 194.63,160.67 194.24,160.67 194.11,160.79 194.11,161.91 194,162.03 192.82,162.03 192.6,162.24 192.6,163.18 192.51,163.28 191.83,163.28 191.45,163.66 191.45,168.29 191.57,168.41 192.27,168.41
GND on BOTTOM (solid shape): 190.68,101.79 190.68,98.87 190.65,98.84 190.65,98.65 190.43,98.42 189.1,98.42 188.52,97.85 188.52,97.03 189.41,96.14 190.49,96.14 190.68,95.95 190.68,93.03 190.49,92.84 189.54,92.84 188.59,93.79 187.13,93.79 187,93.66 187,92.01 187.25,91.76 187.25,86.8 187.13,86.68 185.98,86.68 185.73,86.93 185.73,90.82 185.1,91.45 181.78,91.45 177.48,95.76 177.48,96.96 177.6,97.09 178.56,97.09 179.13,97.66 179.13,99.95 179.38,100.2 182.3,100.2 182.43,100.08 182.43,98.93 182.94,98.42 184.59,98.42 184.97,98.81 184.97,100.08 185.22,100.33 187.64,100.33 189.29,101.98 190.49,101.98
GND on BOTTOM (solid shape): 127.3,32.68 127.38,32.59 127.48,32.53 127.54,32.46 127.51,32.36 127.05,31.9 126.94,31.9 126.09,31.05 126.08,31.05 125.96,30.94 125.92,30.8 125.92,29.14 125.92,29.1 125.94,29.05 125.92,28.96 125.84,28.92 125.32,28.92 125.24,29 125.26,29.03 125.27,29.09 125.28,29.14 125.28,30.8 125.27,30.88 125.23,30.96 125.2,30.99 126.27,32.06 126.27,32.13 126.82,32.68
GND on BOTTOM (solid shape): 110.42,128.91 110.42,125.86 110.1,125.54 110.1,121.6 109.66,121.16 108.26,121.16 107.88,121.54 107.88,124.08 109.11,124.08 109.11,124.03 109.13,123.97 109.15,123.92 109.17,123.88 109.21,123.84 109.24,123.8 109.29,123.77 109.34,123.75 109.39,123.73 109.44,123.72 109.49,123.72 109.55,123.73 109.6,123.75 109.65,123.77 109.69,123.8 109.73,123.84 109.76,123.88 109.79,123.92 109.81,123.97 109.82,124.03 109.82,124.08 109.82,124.13 109.81,124.18 109.79,124.23 109.76,124.28 109.73,124.32 109.69,124.36 109.65,124.39 109.6,124.41 109.55,124.43 109.49,124.43 109.44,124.43 109.39,124.43 109.34,124.41 109.29,124.39 109.24,124.36 109.21,124.32 109.17,124.28 109.15,124.23 109.13,124.18 109.11,124.13 109.11,124.08 107.88,124.08 107.88,128.78 108.39,129.29 110.04,129.29
GND on BOTTOM (solid shape): 193.6,140.21 193.6,138.49 193.35,138.24 193.35,137.22 193.16,137.03 192.21,137.03 192.08,137.16 192.08,138.05 191.7,138.43 191.7,138.74 192,138.74 192,138.69 192.01,138.64 192.03,138.59 192.05,138.54 192.08,138.5 192.12,138.47 192.16,138.43 192.21,138.41 192.26,138.39 192.31,138.39 192.36,138.39 192.41,138.39 192.46,138.41 192.51,138.43 192.55,138.47 192.59,138.5 192.62,138.54 192.64,138.59 192.66,138.64 192.67,138.69 192.67,138.74 192.66,138.79 192.64,138.84 192.62,138.89 192.59,138.93 192.55,138.97 192.51,139 192.46,139.02 192.41,139.04 192.36,139.05 192.31,139.05 192.26,139.04 192.21,139.02 192.16,139 192.12,138.97 192.08,138.93 192.05,138.89 192.03,138.84 192.01,138.79 192,138.74 191.7,138.74 191.7,140.02 192.14,140.46 193.35,140.46
GND on BOTTOM (solid shape): 101.36,26.07 101.45,26.02 101.45,25.92 101.43,25.86 101.42,25.8 101.42,24.14 101.44,24.03 101.51,23.94 101.54,23.86 101.52,23.79 101.43,23.7 101.43,22.97 101.4,22.94 100.03,22.94 99.9,22.81 99.88,22.8 99.77,22.76 99.68,22.67 99.64,22.65 99.6,22.67 99.56,22.71 100.67,23.82 100.67,23.92 100.75,24.02 100.78,24.14 100.78,25.8 100.77,25.86 100.75,25.92 100.75,26.02 100.84,26.07
GND on BOTTOM (solid shape): 135.93,31.13 136,31.06 136.08,31 136.13,30.95 136.13,30.88 136.12,30.84 136.12,30.8 136.12,29.14 136.15,29.02 136.23,28.92 136.23,28.84 136.58,28.5 136.58,28.14 136.23,28.14 135.95,28.27 135.68,28.11 135.4,28.11 135.32,28.19 135.32,28.47 135.36,28.62 135.32,28.78 135.32,28.85 135.36,28.91 135.45,29.01 135.48,29.14 135.48,30.8 135.48,30.83 135.46,30.9 135.7,31.13
GND on BOTTOM (solid shape): 132.78,26.37 132.78,26.3 132.85,26.23 132.88,26.13 132.81,26.06 132.67,25.96 132.62,25.8 132.62,24.14 132.65,24.02 132.73,23.92 132.73,23.48 132.56,23.31 132.21,23.31 131.79,23.73 131.76,23.82 131.82,23.89 131.94,23.99 131.98,24.14 131.98,25.8 131.95,25.92 131.87,26.02 131.87,26.44 131.51,26.79 131.49,26.79 131.41,26.84 131.41,26.95 131.46,27.09 131.45,27.23 131.46,27.33 131.54,27.37 131.79,27.37
GND on BOTTOM (solid shape): 99.7,26.14 99.73,26.07 99.7,25.99 99.64,25.9 99.62,25.8 99.62,24.14 99.63,24.09 99.64,24.04 99.65,24.01 99.11,23.47 97.86,23.47 97.77,23.53 97.79,23.64 98.02,23.88 98.05,23.87 98.2,23.88 98.32,23.97 98.4,24.01 98.48,23.97 98.79,23.88 98.98,24.14 98.98,25.8 98.94,25.93 98.85,26.03 98.84,26.04 98.45,26.43 98.43,26.49 98.4,26.54 98.4,26.64 98.49,26.69 99.15,26.69
GND on BOTTOM (solid shape): 9.58,56.68 9.58,55.75 10.22,55.12 21.13,55.12 23.35,52.9 23.35,47.68 22.07,46.39 15.97,46.39 15.3,45.72 12.88,45.72 12.32,46.28 12.32,47.82 11.7,48.56 10.86,48.07 7.7,48.07 7.13,47.84 6.82,47.1 6.65,47.02 4.35,47.02 4.12,47.35 4.12,52.12 3.76,53.01 2.87,53.37 0.5,53.37 0.33,53.45 0.25,53.62 0.25,54.51 1.11,55.37 2.9,55.37 4.31,56.77 8.8,56.77 8.84,56.77 9.49,56.77
GND on BOTTOM (solid shape): 129.03,25.88 129.02,25.8 129.02,24.14 129.02,24.1 129.01,24.03 128.95,23.99 128.72,23.71 128.89,23.39 128.89,22.74 128.86,22.71 128.07,22.71 127.94,22.58 127.83,22.56 127.77,22.65 127.76,22.7 127.74,22.75 127.74,22.83 127.79,22.89 128,23.2 127.79,23.5 127.72,23.57 127.75,23.67 127.78,23.7 127.78,23.83 127.83,23.92 128.23,23.9 128.38,24.14 128.38,25.8 128.37,25.87 128.34,25.94 128.34,26.05 128.42,26.1 128.82,26.1
GND on BOTTOM (solid shape): 129.16,26.95 129.23,26.97 129.3,26.94 130.01,26.23 131.08,26.23 131.12,26.2 131.11,26.14 131.03,26.07 131.02,26.06 130.88,25.96 130.82,25.8 130.82,24.14 130.85,24.01 130.95,23.91 130.99,23.83 130.97,23.75 130.75,23.54 130.75,23.33 130.65,23.23 130.61,23.26 130.45,23.33 130.28,23.31 129.86,23.31 129.76,23.57 129.49,23.66 129.42,23.68 129.38,23.74 129.37,23.77 129.37,23.84 129.42,23.89 129.48,23.93 129.52,23.97 129.6,24.01 129.68,23.97 129.99,23.88 130.18,24.14 130.18,25.8 130.11,25.98 129.93,26.07 129.92,26.08 129.1,26.89
GND on BOTTOM (solid shape): 134.71,31.56 134.8,31.5 134.78,31.39 134.43,31.04 134.43,31.02 134.42,31.01 134.35,30.91 134.32,30.8 134.32,29.14 134.41,28.94 134.62,28.87 134.7,28.83 134.72,28.73 134.71,28.68 134.64,28.6 134.53,28.62 134.31,28.84 133.88,28.84 133.67,29.06 133.68,29.11 133.68,29.14 133.68,30.8 133.4,31.08 133.12,30.8 133.12,29.14 133.19,28.96 133.37,28.87 133.39,28.86 133.47,28.79 133.42,28.74 133.4,28.74 133.23,28.67 133.12,28.53 133.05,28.47 132.96,28.5 132.45,29.01 132.46,29.04 132.47,29.09 132.48,29.14 132.48,30.8 132.44,30.95 132.32,31.05 132.26,31.12 132.29,31.21 132.64,31.56
GND on BOTTOM (solid shape): 134.51,26.01 134.49,25.97 134.44,25.89 134.42,25.8 134.42,24.14 134.45,24.02 134.53,23.92 134.53,23.76 134.03,23.26 134,23.26 133.65,23.09 133.71,22.7 133.74,22.63 133.72,22.56 133.64,22.36 133.69,22.16 133.7,22.05 133.61,22 133.59,22 133.4,21.81 133.12,21.81 132.88,21.98 132.59,21.89 132.48,21.87 132.42,21.97 132.42,22 132.73,22.31 132.73,22.62 132.56,22.8 132.54,22.91 132.63,22.97 132.7,22.97 133.07,23.34 133.07,23.92 133.09,23.94 133.12,23.97 133.2,24.01 133.28,23.97 133.59,23.88 133.78,24.14 133.78,25.8 133.7,25.99 133.5,26.08 133.47,26.07 133.42,26.13 133.47,26.18 133.48,26.18 133.61,26.23 133.71,26.34 134.19,26.34
GND on BOTTOM (solid shape): 132.85,32.23 132.87,32.14 132.92,32.06 132.94,31.95 132.84,31.89 132.5,31.89 132.14,31.53 132.05,31.51 131.98,31.58 131.47,31.74 131.47,31.21 131.51,31.12 131.46,31.04 131.36,30.94 131.32,30.8 131.32,29.14 131.32,29.11 131.33,29.07 131.31,28.98 131.23,28.94 130.73,28.94 130.65,29.02 130.66,29.05 130.68,29.1 130.68,29.14 130.68,30.8 130.49,31.06 130.18,30.97 130.1,30.93 130.02,30.97 129.71,31.06 129.52,30.8 129.52,29.14 129.52,29.12 129.49,29.04 129.42,29.01 129.23,28.96 129.1,28.81 129.03,28.75 128.94,28.78 128.79,28.93 128.82,28.97 128.86,29.05 128.88,29.14 128.88,30.8 128.85,30.91 128.78,31.01 128.77,31.02 128.58,31.21 128.58,31.64 128.64,31.73 128.75,31.71 129.2,31.68 129.26,32.12 129.26,32.22 129.35,32.28 132.84,32.28
GND on BOTTOM (solid shape): 136,27.08 136.09,27.03 136.1,26.94 136.29,26.54 136.71,26.69 136.78,26.75 136.87,26.72 137.3,26.29 139.45,26.29 139.49,26.24 139.52,26.14 139.44,26.07 139.28,25.97 139.22,25.8 139.22,24.14 139.23,24.06 139.27,23.98 139.3,23.94 138.09,22.73 138.02,22.76 137.95,22.84 137.98,22.93 138.14,23.09 138.14,23.62 138.4,23.88 138.41,23.89 138.53,23.99 138.58,24.14 138.58,25.8 138.39,26.06 138.08,25.97 138,25.93 137.92,25.97 137.61,26.06 137.42,25.8 137.42,24.14 137.42,24.1 137.44,24.05 137.45,24.02 137.39,23.97 136.87,23.97 136.79,24 136.77,24.09 136.78,24.14 136.78,25.8 136.5,26.08 136.22,25.8 136.22,24.14 136.22,24.11 136.24,24.05 136.15,23.97 135.67,23.97 135.6,24 135.57,24.09 135.58,24.14 135.58,25.8 135.5,25.99 135.31,26.08 135.29,26.08 135.25,26.12 135.22,26.2 135.27,26.28 135.41,26.43 135.43,26.63 135.45,26.71 135.53,26.75 135.73,26.84 135.83,27.03 135.84,27.08
GND on BOTTOM (solid shape): outline of 104 points within 121.51,25.88 127.3,31.42
GND on BOTTOM (solid shape): outline of 395 points within 157.41,129.94 159.92,136.42
GND on BOTTOM (solid shape): outline of 1904 points within 0.25,0.25 204.3,181.72
GND on BOTTOM (solid shape): outline of 8655 points within 77.4,6.48 164.2,53.34
GND on IN1 (solid shape): 157.22,180.15 157.22,178.5 155.89,177.16 152.08,177.16 151.57,177.67 151.57,180.21 152.01,180.66 156.71,180.66
GND on IN1 (solid shape): 195.85,166.42 195.85,161.18 195.33,160.66 192.61,160.66 192.21,161.06 192.21,166.89 192.49,167.17 195.1,167.17
GND on IN1 (solid shape): 143.53,145.03 145.09,145.03 145.5,144.63 145.5,143.51 144.7,142.71 138.02,142.71 137.8,142.93 137.8,145.22 138.3,145.72 142.84,145.72
GND on IN1 (solid shape): 132.67,144.4 132.67,140.46 132.12,139.92 130.59,139.92 130.09,140.41 130.09,143.28 129.89,143.48 129.89,144.39 130.13,144.63 132.44,144.63
GND on IN1 (solid shape): 40.95,43.36 40.95,40.88 40.35,40.28 40.35,38.93 39.99,38.56 37.74,38.56 37.26,39.04 37.26,40.54 37.69,40.97 37.69,43.68 37.78,43.76 40.54,43.76
GND on IN1 (solid shape): 9.58,56.68 9.58,55.75 10.22,55.12 22.17,55.12 23.44,53.85 23.44,49.01 21.19,46.76 16.34,46.76 15.3,45.72 12.88,45.72 12.32,46.28 12.32,47.82 11.7,48.56 10.86,48.07 7.7,48.07 7.13,47.84 6.82,47.1 6.65,47.02 4.35,47.02 4.12,47.35 4.12,52.12 3.76,53.01 2.87,53.37 0.5,53.37 0.33,53.45 0.25,53.62 0.25,54.51 1.11,55.37 2.9,55.37 4.31,56.77 8.8,56.77 8.84,56.77 9.49,56.77
GND on IN1 (solid shape): outline of 126 points within 126.2,164.31 136.74,171.62
GND on IN1 (solid shape): 75.66,53.47 75.66,41.67 75.58,41.59 62.17,41.59 61.43,42.33 61.41,42.44 61.5,42.51 61.63,42.51 61.88,42.76 61.88,43.33 62.39,43.84 66.65,43.84 66.83,44.03 66.83,45 66.58,45.25 62.12,45.25 61.22,44.35 61.11,44.33 61.04,44.42 61.04,51.65 61.09,51.68 61.13,51.72 61.21,51.75 61.28,51.72 61.76,51.71 61.75,52.19 61.72,52.26 61.86,52.58 61.72,52.9 61.75,52.97 61.52,53.54 61.3,52.97 61.33,52.9 61.3,52.82 61.28,52.8 61.21,52.77 61.13,52.8 61.09,52.84 61.04,52.87 61.04,54.61 61.49,55.05 74.07,55.05
GND on IN1 (solid shape): outline of 448 points within 107.97,132.58 121.67,147.88
GND on IN1 (solid shape): outline of 702 points within 176.5,86.13 192.77,105.75
GND on IN1 (solid shape): 23.74,163.51 23.74,161.42 24.33,160.83 53.65,160.83 56.54,160.73 59.41,160.41 60.45,160.5 61.33,161.05 64.5,161.9 66.81,159.57 67.3,158.66 68.15,158.06 92.21,114.19 53.65,82.31 25.88,82.31 22.24,79.51 18.6,82.31 3.75,82.31 3.58,82.24 3.51,82.07 3.51,78.32 3.51,78.23 4.91,76.83 14.53,76.83 14.85,76.52 14.85,75.95 14.22,75.31 10.33,75.31 8.69,73.67 4.31,73.67 2.9,75.07 1.11,75.07 0.25,75.93 0.25,76.82 0.33,76.99 0.5,77.07 1.75,77.07 2.64,77.43 3,78.32 3,82.07 3.22,82.6 3.75,82.82 18.81,82.82 18.97,82.76 19.05,82.62 22.24,80.02 25.43,82.62 25.51,82.76 25.67,82.82 53.65,82.82 91.71,114.29 67.96,157.59 66.91,158.32 66.31,159.44 64.37,161.41 61.69,160.69 60.61,160.02 59.34,159.9 56.5,160.22 53.65,160.32 2.58,160.32 2.41,160.4 2.33,160.57 2.33,162.02 2.41,162.19 2.58,162.27 18.45,162.27 19.11,161.61 21.39,161.61 21.9,162.12 21.9,163.77 22.03,163.89 23.36,163.89
GND on IN1 (solid shape): outline of 1687 points within 0.25,0.25 204.3,181.72
GND on IN2 (solid shape): 195.85,166.43 195.85,161.16 195.32,160.63 192.64,160.63 192.58,160.69 192.58,167.2 195.09,167.2
GND on IN2 (solid shape): 117.85,147.04 117.85,146.05 117.53,145.73 109.2,145.73 107.97,146.96 107.97,147.7 108.15,147.88 117.01,147.88
GND on IN2 (solid shape): 157.22,180.15 157.22,178.5 156.1,177.38 151.86,177.38 151.57,177.67 151.57,180.21 152.01,180.66 156.71,180.66
GND on IN2 (solid shape): 158.04,43.89 158.04,40.68 157.17,39.8 154.34,39.8 153.76,40.37 153.76,43.83 154.08,44.15 157.79,44.15
GND on IN2 (solid shape): 188.52,98.51 188.52,95.4 188.23,95.11 178.75,95.11 178.39,95.47 178.39,98.54 178.58,98.73 188.31,98.73
GND on IN2 (solid shape): 132.7,144.16 132.7,140.49 132.12,139.92 130.46,139.92 129.99,140.39 129.99,143.41 129.9,143.5 129.9,144.61 129.93,144.64 132.21,144.64
GND on IN2 (solid shape): 70.34,17.84 70.36,17.73 70.27,17.67 70.14,17.64 70.04,17.57 69.96,17.53 69.89,17.57 69.32,17.34 69.89,17.11 69.96,17.14 70.04,17.11 70.24,17.01 70.46,17.06 70.56,17.07 70.62,16.98 70.62,15.28 70.39,15.05 67.9,15.05 66.92,16.03 66.92,19.15 67.11,19.34 68.84,19.34
GND on IN2 (solid shape): 9.58,56.68 9.58,55.75 10.22,55.12 14.28,55.12 14.92,54.48 14.92,47.37 15.68,46.61 15.68,46.1 15.3,45.72 12.88,45.72 12.32,46.28 12.32,47.82 11.7,48.56 10.86,48.07 7.7,48.07 7.13,47.84 6.82,47.1 6.65,47.02 4.35,47.02 4.12,47.35 4.12,52.12 3.76,53.01 2.87,53.37 0.5,53.37 0.33,53.45 0.25,53.62 0.25,54.51 1.11,55.37 2.9,55.37 4.31,56.77 8.8,56.77 8.84,56.77 9.49,56.77
GND on IN2 (solid shape): outline of 117 points within 33.32,28.83 45.36,43.8
GND on IN2 (solid shape): outline of 173 points within 61.03,41.53 75.69,55.09
GND on IN2 (solid shape): outline of 178 points within 2.33,0.25 204.3,181.72
GND on IN2 (solid shape): 23.74,163.51 23.74,161.42 24.33,160.83 53.65,160.83 56.54,160.73 59.41,160.41 60.45,160.5 61.33,161.05 64.5,161.9 66.81,159.57 67.3,158.66 68.15,158.06 92.21,114.19 53.65,82.31 25.88,82.31 22.24,79.51 18.6,82.31 3.75,82.31 3.58,82.24 3.51,82.07 3.51,78.32 3.51,78.23 4.91,76.83 14.53,76.83 14.85,76.52 14.85,75.95 14.22,75.31 10.33,75.31 8.69,73.67 4.31,73.67 2.9,75.07 1.11,75.07 0.25,75.93 0.25,76.82 0.33,76.99 0.5,77.07 1.75,77.07 2.64,77.43 3,78.32 3,82.07 3.22,82.6 3.75,82.82 18.81,82.82 18.97,82.76 19.05,82.62 22.24,80.02 25.43,82.62 25.51,82.76 25.67,82.82 53.65,82.82 91.71,114.29 67.96,157.59 66.91,158.32 66.31,159.44 64.37,161.41 61.69,160.69 60.61,160.02 59.34,159.9 56.5,160.22 53.65,160.32 2.58,160.32 2.41,160.4 2.33,160.57 2.33,162.17 2.41,162.34 2.58,162.42 18.3,162.42 19.11,161.61 21.39,161.61 21.9,162.12 21.9,163.77 22.03,163.89 23.36,163.89
GND on VCC: 146.26,88.28 148.61,88.28 148.94,87.95 148.94,85.79 148.82,85.67 148.38,85.67 147.4,86.65 146.17,86.65 146.14,86.68 146.14,88.16
GND on VCC: outline of 177 points within 0.26,0.26 204.29,181.71 ; 3 cut-outs
GND on GND: outline of 177 points within 0.26,0.26 204.29,181.71 ; 2 cut-outs
GNDA on BOTTOM (solid shape): 191.63,18.61 191.63,18.24 191.53,18.14 190.64,18.14 190.23,17.73 190.23,17.73 189.78,17.28 189.78,16.84 189.68,16.74 189.19,16.74 189.16,16.76 189.16,18.57 189.27,18.68 191.56,18.68
GNDA on BOTTOM (solid shape): 190.05,16.23 190.05,15.77 190.84,14.99 191.34,14.99 191.46,14.87 191.46,13.93 191.32,13.79 190.66,13.79 190.18,13.31 189.31,13.31 189.11,13.51 189.11,16.38 189.24,16.51 189.77,16.51
GNDA on VCC: 185.33,5.97 185.16,6.14 185.16,8.55 184.51,9.2 184.51,10.19 184.55,10.24 185.42,10.24 185.53,10.13 185.53,9.5 185.74,9.28 186.5,9.28 187.93,7.86 189.24,7.86 189.61,8.22 189.61,10.22 189.23,10.6 188.43,10.6 187.4,11.63 186.27,11.63 186.23,11.67 186.23,14.91 185.76,15.38 181.32,15.38 179.78,16.93 179.78,21.63 180.25,22.1 187.61,22.1 188.52,23.01 188.52,24.91 191.19,27.58 191.19,29.87 191.3,29.97 193.63,29.97 194.24,29.36 194.24,9.18 192.36,7.29 190.22,7.29 188.89,5.97
GNDA on GND: 185.33,5.97 185.16,6.14 185.16,8.55 184.51,9.2 184.51,10.19 184.55,10.24 185.42,10.24 185.53,10.13 185.53,9.5 185.74,9.28 186.5,9.28 187.93,7.86 189.24,7.86 189.61,8.22 189.61,10.22 189.23,10.6 188.43,10.6 187.4,11.63 186.27,11.63 186.23,11.67 186.23,14.91 185.76,15.38 181.32,15.38 179.78,16.93 179.78,21.63 180.25,22.1 187.61,22.1 188.52,23.01 188.52,24.91 190.22,26.6 194.18,26.6 194.24,26.54 194.24,9.18 192.36,7.29 190.22,7.29 188.89,5.97
VDDCR_FCH_S5 on BOTTOM (solid shape): 27.36,50.04 27.36,48.26 28.25,47.37 28.25,45.08 28.06,44.89 27.48,44.89 27.48,45.39 27.03,45.39 27.03,44.89 26.68,44.89 26.68,45.39 26.23,45.39 26.23,44.89 25.77,44.89 25.71,44.96 25.71,46.1 26.6,46.99 26.6,50.04 26.73,50.16 27.23,50.16
+APU_CORE on TOP (solid shape): 120.07,130.17 120.07,121.22 117.02,118.17 113.95,118.17 113.66,118.47 113.66,128.46 116.01,130.81 119.44,130.81
+APU_CORE on TOP (solid shape): outline of 436 points within 117.07,78.28 126.27,92.65
+APU_CORE on BOTTOM (solid shape): 120.07,130.43 120.07,118.36 119.44,117.73 114.17,117.73 113.66,118.24 113.66,126.07 113.95,126.36 113.95,126.38 114.61,127.04 114.61,130.81 114.74,130.94 115.88,130.94 116.01,130.81 116.01,128.14 117.02,128.14 117.02,130.81 117.28,131.06 119.44,131.06
+APU_CORE on IN1 (solid shape): outline of 4283 points within 100.59,78.23 124.9,122.81
+APU_CORE on IN2 (solid shape): outline of 495 points within 115.91,78.16 123.92,84.24
+APU_CORE on VCC: 116.49,78.74 116.01,79.23 116.01,89.13 113.59,91.55 113.59,93.07 112.94,93.73 106.84,93.73 106.36,94.21 106.36,102.34 105.09,103.61 105.09,129.18 106.84,130.94 119.84,130.94 120.33,130.45 120.33,123.08 120.83,122.57 120.83,121.12 123.51,118.44 123.51,114.94 126.29,112.16 126.29,91.04 125.02,89.77 125.02,88.5 124.26,87.74 124.26,78.97 124.03,78.74
+APU_CORE_GFX on TOP (solid shape): outline of 801 points within 105.22,78.32 114.37,91.91
+APU_CORE_GFX on BOTTOM (solid shape): 71.18,64.52 73.08,64.52 73.78,63.82 73.78,53.02 73.15,52.39 68.83,52.39 68.64,52.58 68.64,53.85 68.83,54.04 71.43,54.04 71.43,54.93 68.7,54.93 68.19,55.44 68.19,56.38 65.26,59.31 65.26,66.15 66.16,67.06 68.64,67.06
+APU_CORE_GFX on IN1 (solid shape): outline of 5686 points within 65.49,57.78 115.5,96.01
+APU_CORE_GFX on VCC: 67.09,57.66 65.46,59.29 65.46,69.11 89.57,93.22 112.73,93.22 113.09,92.86 113.09,91.33 115.5,88.92 115.5,79.23 115.01,78.74 104.68,78.74 103.79,79.63 102.27,79.63 100.37,81.53 96.85,81.53 87.69,72.37 87.69,67.29 78.06,57.66
+APU_CORE_NB on TOP (solid shape): 125.02,121.16 125.02,120.27 124.9,120.14 124.14,120.14 123.75,120.52 123.75,120.9 124.14,121.28 124.9,121.28
+APU_CORE_NB on TOP (solid shape): 125.61,87.63 126.36,87.63 126.54,87.45 126.54,87.19 126.24,86.89 126.24,85.24 126.54,84.94 126.54,78.2 126.73,78.01 127.09,78.01 127.17,77.98 127.2,77.91 127.39,77.59 127.76,77.66 127.83,77.69 127.9,77.67 128.23,77.64 128.42,77.92 128.45,77.99 128.52,78.01 128.56,78.01 128.68,77.89 128.68,76.8 128.66,76.78 127.2,76.78 127.16,76.78 127.11,76.78 126.54,76.78 126.23,76.46 125.18,76.46 124.87,76.77 124.87,77.5 124.9,77.52 124.98,77.57 125.04,77.63 125.11,77.68 125.19,77.65 125.39,77.59 125.57,77.69 125.66,77.69 125.68,77.66 126.3,77.81 125.68,77.99 125.57,77.99 125.38,78.09 125.1,77.98 125.03,78.02 124.97,78.08 124.9,78.12 124.87,78.13 124.87,78.81 125.32,79.26 125.32,80.36 125.08,80.6 124.17,80.6 124.1,80.68 124.1,81.3 124.18,81.38 124.69,81.38 124.93,81.62 124.93,86.84 125.25,87.16 125.25,87.49 125.41,87.65 125.61,87.65
+APU_CORE_NB on BOTTOM (solid shape): 46.03,71.5 46.03,69.66 47.43,68.26 47.43,65.53 47.05,65.15 46.54,65.15 46.16,65.53 46.16,67.2 45.96,67.39 45.96,68.01 45.14,68.83 45.14,71.5 45.27,71.63 45.9,71.63
+APU_CORE_NB on BOTTOM (solid shape): 124.83,129.67 125.72,129.67 125.72,132.27 128.58,132.27 128.9,131.95 128.9,129.41 130.74,127.57 130.74,119.76 129.72,118.74 124.64,118.74 124.39,119 124.39,127.57 123.31,128.65 123.31,132.02 123.56,132.27 124.83,132.27
+APU_CORE_NB on BOTTOM (solid shape): 126.79,87.22 126.79,86.01 126.75,85.93 126.66,85.91 126.27,85.7 126.49,85.32 126.5,85.32 126.79,85.03 126.79,83.61 126.75,83.53 126.66,83.51 126.27,83.3 126.49,82.92 126.5,82.92 126.79,82.63 126.79,81.21 126.75,81.13 126.66,81.11 126.27,80.9 126.49,80.52 126.5,80.52 126.79,80.23 126.79,79.51 126.64,79.35 126.1,79.35 125.1,80.36 125.1,81.77 125.2,81.77 125.21,81.76 125.67,82.02 125.21,82.28 125.2,82.27 125.1,82.27 125.1,84.17 125.2,84.17 125.21,84.16 125.67,84.42 125.21,84.68 125.2,84.67 125.1,84.67 125.1,88.09 125.25,88.24 125.77,88.24
+APU_CORE_NB on IN1 (solid shape): 46.73,70.87 46.73,70.36 46.6,70.23 45.65,70.23 45.33,70.55 45.33,71.44 45.52,71.63 45.97,71.63
+APU_CORE_NB on IN1 (solid shape): 126.55,87.5 126.55,80.14 126.29,79.88 125.41,79.88 125.15,80.14 125.15,82.68 125.02,82.8 125.02,86.61 125.28,86.87 125.28,87.5 125.53,87.76 126.29,87.76
+APU_CORE_NB on VCC: 125,78.74 124.77,78.97 124.77,87.52 125.53,88.29 125.53,89.56 126.8,90.83 126.8,112.37 124.02,115.15 124.02,118.65 121.34,121.34 121.34,122.8 120.83,123.3 120.83,124.23 121.32,124.71 133.3,124.71 134.04,123.97 134.04,118.89 140.52,112.42 140.52,82.02 140.03,81.53 132.03,81.53 129.24,78.74
+BIF_VDDC on TOP (solid shape): 163.02,134.78 163.02,132.38 162.93,132.29 162.93,131.59 162.77,131.44 161.38,131.44 161.33,131.49 161.33,132.35 161.44,132.45 161.63,132.45 161.83,132.65 161.83,133.69 161.51,134.01 161.51,134.83 161.6,134.91 162.89,134.91
+CHGRTC on BOTTOM (solid shape): 25.1,10.8 25.1,9.31 24.37,8.57 21.91,8.57 21.31,7.97 17.3,7.97 16.75,8.52 16.75,9.74 17.03,10.02 23.03,10.02 23.03,9.97 23.04,9.92 23.06,9.87 23.08,9.82 23.11,9.78 23.15,9.74 23.19,9.71 23.23,9.69 23.28,9.67 23.34,9.66 23.39,9.66 23.44,9.67 23.49,9.69 23.53,9.71 23.58,9.74 23.61,9.78 23.64,9.82 23.67,9.87 23.68,9.92 23.69,9.97 23.69,10.02 23.68,10.07 23.67,10.12 23.64,10.17 23.61,10.21 23.58,10.25 23.53,10.28 23.49,10.3 23.44,10.32 23.39,10.33 23.34,10.33 23.28,10.32 23.23,10.3 23.19,10.28 23.15,10.25 23.11,10.21 23.08,10.17 23.06,10.12 23.04,10.07 23.03,10.02 17.03,10.02 17.1,10.08 18.7,10.08 20.62,10.08 20.82,10.08 21.43,10.69 23.25,10.69 23.67,11.11 24.79,11.11
+CODEC_AVDD2 on BOTTOM (solid shape): 184.72,10.14 184.72,9.32 185.34,8.71 185.35,8.71 185.49,8.57 185.93,8.57 186.1,8.39 186.63,8.39 187.11,7.92 187.11,7.39 187.05,7.34 185.1,7.34 184.85,7.59 184.85,8.44 184.58,8.7 184.58,9.04 184.52,9.11 184.52,10.13 184.56,10.17 184.69,10.17
+DP_VDDC on TOP (solid shape): 172,127.17 172,126.58 171.91,126.49 170.93,126.49 170.85,126.41 167.47,126.41 167.37,126.51 167.37,127.07 167.43,127.13 168.97,127.13 168.97,127.13 169.05,127.13 169.15,127.23 171.94,127.23
+DP_VDDR on TOP (solid shape): 176.28,125.58 176.28,124.13 176.13,123.98 175.16,123.98 175.03,124.11 175.03,124.69 174.86,124.86 173.03,124.86 172.99,124.91 172.99,125.54 173.06,125.61 174.93,125.61 175.1,125.78 176.08,125.78
+FAN_POWER on TOP (solid shape): 93.09,141.33 93.09,138.14 93.22,138.01 93.22,136.93 93.12,136.83 91.04,136.83 90.82,137.05 90.82,138.34 91.93,139.45 91.93,139.76 91.93,139.76 91.93,141.37 92.09,141.53 92.89,141.53
+FAN_POWER on BOTTOM (solid shape): 92.53,137.31 92.87,136.61 92.98,136.27 92.89,136.02 92.77,135.89 91.45,135.89 90.82,136.51 90.82,137.86 90.99,138.02 91.81,138.02
+FBA_VREF0 on IN1 (solid shape): outline of 125 points within 161.04,164.13 163.58,165.66
+INV_PWR_SRC on BOTTOM (solid shape): outline of 151 points within 74.87,157.58 81.45,166.5
+LAN_REGOUT on TOP (solid shape): 56.44,172.53 56.44,171.51 56.25,171.32 52.13,171.32 50.37,169.57 49.56,169.57 49.52,169.61 49.52,169.78 49.65,169.9 49.65,170.62 50.87,171.84 51.77,172.74 52.71,172.74 53.08,173.1 55.87,173.1
+LAN_VDD10 on TOP (solid shape): 57.14,170.94 57.14,169.54 56.76,169.16 53.08,169.16 52.28,168.36 51.63,168.36 51.3,168.69 50.7,168.69 50.62,168.78 49.6,168.78 49.55,168.83 49.55,168.92 49.61,168.98 50.6,168.98 50.63,169.01 51.74,169.01 52.16,169.43 52.16,170.74 52.5,171.07 57.02,171.07
+LAN_VDD10 on IN1 (solid shape): outline of 200 points within 44.2,166.13 57.21,172.97
+LAN_VDD33 on TOP (solid shape): 47.62,164.53 47.62,164.02 47.49,163.89 46.83,163.89 46.79,163.85 46.79,163.47 46.67,163.35 45.73,163.35 45.66,163.42 45.66,164.59 45.73,164.66 47.49,164.66
+LAN_VDD33 on TOP (solid shape): 41.33,172.02 44.38,172.02 45.4,171.01 46.41,171.01 46.67,170.75 46.67,169.93 46.6,169.86 46.48,169.86 46.41,169.93 46.41,170.18 46.15,170.45 45.13,170.45 44.89,170.69 42.82,170.69 42.75,170.62 37.59,170.62 36.95,171.26 36.95,171.7 37.52,171.7 37.52,172.21 36.95,172.21 36.95,173.48 37.71,174.24 39.11,174.24
+LAN_VDD33 on BOTTOM (solid shape): 55.56,167.39 55.56,166.24 55.05,165.73 53.59,165.73 53.52,165.8 53.52,166.81 53.59,166.88 54.29,166.88 54.48,167.07 54.48,167.39 54.6,167.51 55.43,167.51
+LAN_VDD33 on IN1 (solid shape): 46.88,164.5 46.88,163.44 46.78,163.34 45.89,163.34 45.73,163.49 45.73,164.49 45.88,164.63 46.74,164.63
+LAN_VDD33 on IN1 (solid shape): 55.56,167.32 55.56,167 54.6,166.05 54.29,166.05 53.9,166.43 53.9,166.88 54.6,167.58 55.3,167.58
+LAN_VDD33 on IN2 (solid shape): 46.86,164.36 46.86,163.51 46.69,163.33 45.88,163.33 45.73,163.49 45.73,164.38 45.85,164.5 46.72,164.5
+LAN_VDD33 on IN2 (solid shape): 39.87,173.61 39.87,172.97 39.55,172.66 37.84,172.66 37.71,172.78 37.71,173.48 37.97,173.74 39.74,173.74
+LAN_VDDREG on TOP (solid shape): 52,170.18 52,169.54 51.62,169.16 49.59,169.16 49.54,169.21 49.54,169.33 49.59,169.38 50.36,169.38 51.26,170.28 51.9,170.28
+LAN_VDDREG on BOTTOM (solid shape): 53.14,169.16 53.14,168.34 52.83,168.02 52.83,165.86 52.76,165.8 52.13,165.8 51.94,165.99 51.94,168.27 50.67,169.54 50.67,169.93 51.05,170.31 52,170.31
+LCDVDD on BOTTOM (solid shape): 84.49,157.91 84.49,157.68 84.47,157.41 84.67,157.22 84.67,156.49 85.26,155.91 85.26,155.52 85.07,155.33 84.32,155.33 84.17,155.49 84.17,155.49 83.99,155.67 83.29,155.67 83.07,155.89 83.07,158.5 83.12,158.55 83.84,158.55
+LCDVDD_CONN on BOTTOM (solid shape): 83.96,166.39 83.96,164.6 84.64,163.92 84.64,162.47 82.84,160.67 82.84,157.05 82.77,156.99 79.6,156.99 79.51,157.07 79.51,158.31 80.3,159.11 80.3,160.56 81.68,161.94 81.68,163.69 82.43,163.69 82.43,163.64 82.44,163.59 82.45,163.54 82.48,163.49 82.51,163.45 82.54,163.41 82.59,163.38 82.63,163.36 82.68,163.34 82.73,163.33 82.79,163.33 82.84,163.34 82.89,163.36 82.93,163.38 82.97,163.41 83.01,163.45 83.04,163.49 83.07,163.54 83.08,163.59 83.09,163.64 83.09,163.69 83.08,163.74 83.07,163.79 83.04,163.84 83.01,163.88 82.97,163.92 82.93,163.95 82.89,163.97 82.84,163.99 82.79,164 82.73,164 82.68,163.99 82.63,163.97 82.59,163.95 82.54,163.92 82.51,163.88 82.48,163.84 82.45,163.79 82.44,163.74 82.43,163.69 81.68,163.69 81.68,164.81 82.13,165.26 82.13,166.3 82.26,166.42 83.92,166.42
+MEM_VREF on BOTTOM (solid shape): outline of 271 points within 110.1,70.05 113.54,73.03
+MPLL_PVDD on TOP (solid shape): 173.99,137.03 174.06,137 174.09,136.91 174.42,136.54 174.74,136.91 174.77,137 174.84,137.03 176.72,137.03 176.82,137.03 176.96,136.9 176.96,135.92 176.89,135.85 176.4,135.85 176.22,136.03 175.05,136.03 174.69,135.67 173.52,135.67 173.35,135.84 173.35,136.34 173.45,136.44 173.45,136.93 173.55,137.03
+RTC_APU_R on TOP (solid shape): outline of 373 points within 128.86,73.06 134.33,77.69
+RTCBATT on BOTTOM (solid shape): 28.29,16.48 28.29,13.39 28.2,13.16 28.29,12.94 28.29,12.08 27.01,10.79 25.85,10.79 25.5,11.14 25.5,12.85 24.72,13.64 24.72,13.92 24.72,13.92 24.72,15.9 25.56,16.74 28.03,16.74
+RTCVCC on BOTTOM (solid shape): 22.26,15.33 22.26,13.63 23.06,12.83 23.06,11.3 22.71,10.95 21.64,10.95 21.28,11.31 21.28,12.24 20.39,13.13 19.76,13.13 19.47,13.13 19.01,13.13 18.94,13.13 18.4,12.59 18.4,12.24 17.52,11.35 16.55,11.35 16.14,11.77 16.14,13.36 18.65,15.88 21.71,15.88
+SPLL_VDDC on IN1 (solid shape): outline of 185 points within 173.06,138.18 175.99,140.84
+TPUSB_VCC on BOTTOM (solid shape): 176.02,22.65 176.02,21.5 174.47,19.95 174.47,19.2 174.18,18.9 172.46,18.9 172.32,19.04 172.32,21.28 172.46,21.43 174.63,21.43 175.25,22.05 175.25,22.58 175.38,22.71 175.96,22.71
+TPUSB_VCC_IN on BOTTOM (solid shape): 164.15,17.33 164.15,16.74 162.44,15.03 161.77,15.03 160.98,15.82 160.98,16.87 161.07,16.96 161.55,16.96 161.88,17.3 162.13,17.3 162.34,17.51 163.97,17.51
+TSVDD on BOTTOM (solid shape): 168.59,121 168.59,119.72 168.71,119.61 169.44,119.61 169.66,119.38 169.66,117.64 169.47,117.46 168.52,117.46 168.33,117.64 168.33,118.32 168,118.65 168,121.03 168.13,121.16 168.44,121.16
+V_TP on TOP (solid shape): 57.33,80.39 57.33,76.33 57.14,76.14 57.14,75.41 56.98,75.25 55.74,75.25 55.62,75.37 55.62,80.71 55.68,80.77 56.95,80.77
+V_TS on TOP (solid shape): 84.26,154.84 84.26,153.57 84.7,153.12 85.58,153.12 85.69,153.01 85.69,152.06 85.39,151.75 85.39,150.46 85.22,150.29 83.9,150.29 83.57,150.62 83.57,151.88 83.29,152.16 83.29,154.71 83.45,154.86 84.23,154.86
+V_UV4 on TOP (solid shape): 180.16,129.81 180.18,129.71 180.12,129.64 179.99,129.09 180.53,129.22 180.61,129.29 180.7,129.26 181.15,128.82 181.74,128.82 181.8,128.76 181.8,128.1 181.72,128.03 181.69,128.03 181.69,128.03 180.8,128.03 180.8,128.03 178.65,128.03 178.65,129.54 178.54,129.64 178.54,130.17 178.77,130.41 179.56,130.41
+VDISPLAY_VCC on TOP (solid shape): 16.97,79.26 16.97,77.29 17.31,76.95 17.31,76.94 17.53,76.72 17.53,74.28 17.47,74.23 15.62,74.23 15.49,74.36 15.49,77.05 14.37,78.17 13.96,78.17 13.79,78.35 13.79,79.76 13.94,79.91 16.33,79.91
+VDISPLAY_VCC on BOTTOM (solid shape): 32.42,75.53 32.42,73.72 32.4,73.7 31.2,73.7 31.11,73.79 31.11,75.51 31.28,75.68 32.26,75.68
+VDISPLAY_VCC on IN1 (solid shape): 16.85,75.16 16.85,74.75 15.32,73.23 15.21,73.23 14.73,73.71 14.73,74.08 15.83,75.18 16.82,75.18
+VDISPLAY_VCC on IN1 (solid shape): 20.81,75.5 20.81,74.09 20.56,73.84 16.4,73.84 15.54,73.84 15.31,74.07 15.31,74.65 16.19,75.53 16.19,75.77 16.34,75.92 20.39,75.92
+VDISPLAY_VCC on IN1 (solid shape): 13.16,70.76 13.16,67.4 13.49,67.06 14.1,67.06 14.34,66.82 14.34,66.37 14.11,66.13 12.83,66.13 12.01,66.95 12.01,68.47 11.71,68.77 11.27,68.77 11.02,69.03 11.02,69.98 12.04,71 12.92,71
+VDISPLAY_VCC on IN2 (solid shape): 22.06,76.25 22.06,75.34 21.96,75.23 21.56,75.23 20.59,74.26 19.86,74.26 19.55,74.56 19.55,75.25 20.61,76.31 22,76.31
+VDISPLAY_VCC on IN2 (solid shape): 32.04,76.4 32.5,75.94 32.5,74.74 32.31,74.55 31.74,74.55 31.49,74.8 31.49,75.3 31.21,75.57 30.74,76.04 30.74,76.2 31.4,76.86 31.58,76.86
+VGA_CORE on TOP (solid shape): 181.17,125.68 181.17,125.14 181.55,124.76 182.13,124.76 182.17,124.71 182.17,121.56 181.98,121.36 179.46,121.36 179.21,121.6 179.21,124.4 179.6,124.79 179.6,125.68 179.72,125.8 181.05,125.8
+VGA_CORE on TOP (solid shape): 177.86,127.04 177.98,126.92 177.98,126.39 176.57,126.39 176.31,126.64 176.31,127.27 176.24,127.34 176.24,127.62 176.34,127.73 176.75,127.73 176.88,127.86 176.97,127.86 176.97,128.74 177.04,128.81 177.86,128.81
+VGA_CORE on TOP (solid shape): outline of 265 points within 164.02,128.33 174.09,134.29
+VGA_CORE on BOTTOM (solid shape): outline of 238 points within 180.02,107.7 197.67,125.92
+VGA_CORE on IN1 (solid shape): outline of 2789 points within 164.14,114.71 196.65,135.64
+VGA_CORE on VCC: 170.34,114.81 163.89,121.26 163.89,135.02 164.37,135.51 195.91,135.51 196.4,135.02 196.4,115.68 195.53,114.81
ACIN_CHG on TOP (solid shape): 80.35,172.14 80.35,171.5 80.32,171.48 80.32,170.75 80.54,170.54 80.93,170.54 81.04,170.42 81.04,170.21 80.87,170.03 80.68,170.03 80.37,169.72 79.86,169.72 78.94,170.65 78.58,170.65 78.38,170.85 78.38,172.2 78.42,172.24 80.24,172.24
ASGATE on BOTTOM (solid shape): 116.47,166.03 116.47,164.01 116.02,163.56 115.74,163.56 115.61,163.69 115.61,163.91 116.1,164.39 116.1,165 116.24,165.14 116.24,166.04 116.3,166.1 116.39,166.1
BST1_APU on TOP (solid shape): 116.87,152.68 116.87,151.63 116.62,151.38 116.62,150.34 116.9,150.06 116.9,149.4 116.8,149.29 116,149.29 115.9,149.38 115.9,151.92 116.73,152.75 116.81,152.75
BST1_GFX on TOP (solid shape): 63.56,39.43 63.56,38.8 63.49,38.73 62.16,38.73 61.27,37.85 61.27,37.25 61.22,37.2 61.11,37.2 61.02,37.29 61.02,38.16 62.35,39.5 63.49,39.5
BST1_VGA on BOTTOM (solid shape): 174.85,95.74 174.85,94.86 174.78,94.79 174.49,94.79 173.27,93.57 172.37,93.57 172.3,93.64 172.3,93.73 172.42,93.85 172.68,93.85 174.06,95.23 174.06,95.7 174.15,95.79 174.8,95.79
BST2_VGA on BOTTOM (solid shape): 173.47,90.04 173.47,89.55 174.04,88.98 174.79,88.98 174.92,88.86 174.92,88.07 174.8,87.96 174.15,87.96 173.2,88.91 173.2,89.21 172.45,89.97 172.37,89.97 172.31,90.03 172.31,90.13 172.37,90.19 173.32,90.19
BST_1.35V on TOP (solid shape): 65.33,21.72 65.33,21.08 65.27,21.02 64.26,21.02 63.87,21.4 61.78,21.4 61.72,21.46 61.72,21.59 61.78,21.65 63.37,21.65 63.56,21.84 65.21,21.84
BST_1.35V_R on TOP (solid shape): 65.27,20.32 65.27,18.48 65.21,18.41 64.57,18.41 64.32,18.67 64.32,20.32 64.38,20.38 65.21,20.38
BST_1.35VGPU on BOTTOM (solid shape): 198.11,167.7 198.11,166.75 198.56,166.31 198.56,165.35 198.43,165.23 198.05,165.23 197.92,165.35 197.92,166.12 197.16,166.88 197.16,167.7 197.22,167.77 198.05,167.77
BST_3V on TOP (solid shape): 40.95,50.42 40.95,50.29 40.89,50.23 39.62,50.23 38.79,49.4 37.9,49.4 37.84,49.47 37.84,50.36 37.97,50.48 40.89,50.48
BST_5V on TOP (solid shape): 46.25,50.39 46.25,49.4 46.21,49.36 45.31,49.36 44.42,50.25 42.96,50.25 42.89,50.32 42.89,50.44 42.94,50.5 46.15,50.5
BST_NB on TOP (solid shape): 123.9,153.17 123.9,152.27 123.73,152.1 121.3,152.1 120.53,152.87 120.53,152.96 120.6,153.03 121.49,153.03 121.83,152.69 123.01,152.69 123.18,152.86 123.18,153.19 123.26,153.26 123.81,153.26
BST_VDDP_ALWP on TOP (solid shape): 140.26,150.3 140.26,149.54 140.2,149.48 138.11,149.48 137.92,149.29 137.28,149.29 137.22,149.35 137.22,149.61 137.98,150.37 140.2,150.37
CMSRC on BOTTOM (solid shape): 116.87,166.03 116.87,165.14 117.01,165 117.01,163.61 116.67,163.27 116.3,163.27 116.24,163.33 116.24,163.55 116.64,163.96 116.64,166.04 116.71,166.1 116.8,166.1
DP_VSSR on BOTTOM (solid shape): outline of 997 points within 160.32,122 168.91,125.85
HDD_REXT_SATA0 on BOTTOM (solid shape): 182.49,30.48 182.49,28.77 182.17,28.45 182.17,28 182.11,27.94 180.71,27.94 180.65,28 180.65,28.45 180.71,28.51 181.22,28.51 181.98,29.27 181.98,30.29 182.24,30.54 182.43,30.54
INT-SPK-L+ on TOP (solid shape): 184.22,10.27 184.22,7.98 184.04,7.8 183.67,7.8 183.55,7.92 183.55,9.42 183.06,9.91 183.06,10.16 183.44,10.54 183.95,10.54
INT-SPK-L+ on BOTTOM (solid shape): 183.92,10.11 183.93,9.19 183.93,8.97 184,8.89 184,8.08 183.88,7.95 183.65,7.95 183.55,8.05 183.55,8.85 183.72,9.02 183.72,10.14 183.75,10.17 183.86,10.17
INT-SPK-L+ on BOTTOM (solid shape): 183.92,10.11 183.93,9.19 183.93,8.97 184,8.89 184,7.99 183.88,7.87 183.66,7.87 183.55,7.99 183.55,8.85 183.72,9.02 183.72,10.14 183.75,10.17 183.86,10.17
INT-SPK-L- on TOP (solid shape): 183.41,9.14 183.41,7.65 183.31,7.55 182.98,7.55 182.93,7.6 182.93,8.6 182.6,8.93 181.5,8.93 181.16,9.27 181.16,9.78 181.41,10.03 182.53,10.03
INT-SPK-L- on BOTTOM (solid shape): 183.53,10.12 183.53,9.04 183.4,8.91 183.4,7.66 183.31,7.57 183.04,7.57 182.95,7.66 182.95,8.74 183.27,9.06 183.27,10.09 183.36,10.18 183.48,10.18
INT-SPK-R+ on TOP (solid shape): 182.2,8.55 182.2,7.26 181.15,6.22 180.82,6.22 180.42,6.62 180.42,6.92 181.74,8.25 181.74,8.5 181.85,8.61 182.14,8.61
INT-SPK-R+ on BOTTOM (solid shape): 182.73,10.15 182.73,9.19 182.2,8.66 182.2,7.7 182.07,7.56 181.88,7.56 181.74,7.7 181.74,8.47 182.52,9.25 182.52,10.15 182.54,10.17 182.71,10.17
INT-SPK-R- on TOP (solid shape): 182.81,8.54 182.81,7.44 183.23,7.01 183.23,6.33 182.98,6.07 182.38,6.07 182.27,6.19 182.27,6.42 182.33,6.48 182.33,8.54 182.45,8.66 182.69,8.66
INT-SPK-R- on BOTTOM (solid shape): 183.12,10.13 183.12,9.11 182.8,8.78 182.8,7.7 182.67,7.57 182.47,7.57 182.34,7.7 182.34,8.6 182.92,9.18 182.92,10.13 182.97,10.18 183.07,10.18
KB_BL_PWM on TOP (solid shape): 191.62,125.43 192.31,125.43 192.55,125.18 192.55,124.43 192.47,124.36 186.24,124.36 186.02,124.57 186.02,126.38 186.19,126.54 190.5,126.54
LG1_APU on TOP (solid shape): 118.07,152.68 118.07,151.77 118.07,151.58 118.47,151.18 118.47,150.4 118.36,150.29 118.14,150.29 117.99,150.44 117.99,151.28 117.86,151.41 117.86,152.68 117.92,152.74 118.01,152.74
LG1_APU on BOTTOM (solid shape): 117.02,145.16 117.02,144.27 116.77,144.02 115.88,144.02 115.69,144.21 115.69,145.1 115.88,145.29 116.9,145.29
LG1_APU on BOTTOM (solid shape): 122.83,145.16 122.83,144.27 122.58,144.02 121.69,144.02 121.5,144.21 121.5,145.1 121.69,145.29 122.71,145.29
LG1_APU on IN1 (solid shape): 117.75,145.07 117.75,144.32 117.52,144.09 116.59,144.09 116.47,144.22 116.47,145.02 116.69,145.25 117.57,145.25
LG1_APU on IN1 (solid shape): 118.48,151.19 118.48,150.94 119.12,150.3 119.12,150.11 118.74,149.73 118.55,149.73 117.98,150.3 117.98,151.26 118.04,151.32 118.36,151.32
LG1_APU on IN1 (solid shape): 122.8,145.8 122.8,144.14 122.68,144.02 121.79,144.02 121.56,144.25 121.56,145.38 122.17,145.99 122.61,145.99
LG1_GFX on TOP (solid shape): 60.06,39.69 60.06,37.25 60,37.19 59.92,37.19 59.85,37.26 59.85,38.44 59.49,38.8 59.49,39.69 59.56,39.75 60,39.75
LG1_GFX on BOTTOM (solid shape): 67.53,44.99 67.53,44.04 67.34,43.85 66.45,43.85 66.19,44.1 66.19,44.99 66.38,45.18 67.34,45.18
LG1_GFX on BOTTOM (solid shape): 61.52,45.02 61.52,43.81 61.72,43.62 61.72,41.72 60.06,40.07 60.06,38.73 59.94,38.61 59.68,38.61 59.56,38.73 59.56,40.89 60.83,42.16 60.83,44.96 61.02,45.15 61.4,45.15
LG1_GFX on IN1 (solid shape): 66.73,44.96 66.73,44.07 66.6,43.94 62.35,43.94 61.78,43.37 61.78,42.8 61.59,42.61 61.21,42.61 61.08,42.74 61.08,44.07 62.16,45.15 66.54,45.15
LG1_VGA on BOTTOM (solid shape): 178.56,100.08 178.56,99.06 178.36,98.87 177.54,98.87 177.29,99.12 177.29,100.01 177.48,100.2 178.43,100.2
LG1_VGA on BOTTOM (solid shape): 184.4,100.11 184.4,99.09 184.21,98.9 183.38,98.9 183.13,99.16 183.13,100.04 183.32,100.23 184.27,100.23
LG1_VGA on BOTTOM (solid shape): 175.05,92.86 175.05,92.52 174.93,92.4 174.35,92.4 174.35,92.4 173.63,92.4 173.63,92.4 173.31,92.4 173.28,92.38 172.37,92.38 172.31,92.43 172.31,92.53 172.38,92.59 173.74,92.59 174.12,92.96 174.95,92.96
LG1_VGA on IN2 (solid shape): 175.76,92.84 175.76,92.33 175.63,92.2 175.06,92.2 174.81,92.46 174.11,92.46 173.98,92.58 173.98,92.84 174.11,92.96 175.63,92.96
LG1_VGA on IN2 (solid shape): 183.64,100.01 183.64,99.12 183.51,99 178.05,99 177.92,98.87 177.92,98.36 177.86,98.3 177.22,98.3 177.16,98.36 177.16,99.82 177.48,100.14 183.51,100.14
LG2_VGA on BOTTOM (solid shape): 190.68,103.63 190.68,102.74 190.49,102.55 189.6,102.55 189.41,102.74 189.41,103.63 189.6,103.82 190.49,103.82
LG2_VGA on BOTTOM (solid shape): 190.68,97.28 190.68,96.9 190.49,96.71 189.6,96.71 189.03,97.28 189.03,97.85 189.16,97.98 189.99,97.98
LG2_VGA on BOTTOM (solid shape): 174.99,91.47 175.1,91.36 175.1,91.14 174.97,91 174.14,91 173.97,91.17 172.38,91.17 172.31,91.23 172.31,91.33 172.38,91.39 174.06,91.39 174.15,91.48 174.99,91.48
LG2_VGA on IN2 (solid shape): 175.76,91.76 175.76,91.19 175.57,91 174.17,91 174.05,91.12 174.05,91.38 174.17,91.5 174.75,91.5 175.06,91.82 175.7,91.82
LG2_VGA on IN2 (solid shape): 190.62,103.63 190.62,99.25 190.11,98.74 190.11,96.9 189.92,96.71 189.86,96.71 189.83,96.74 189.26,96.74 189.03,96.96 189.03,99.31 189.48,99.76 189.48,103.63 189.67,103.82 190.43,103.82
LG_1.35V on TOP (solid shape): 62.16,20.26 62.16,19.37 62.03,19.24 61.59,19.24 61.27,19.56 61.27,20.38 61.33,20.45 61.97,20.45
LG_1.35V on BOTTOM (solid shape): 71.68,17.4 71.68,17.14 71.56,17.02 69.59,17.02 69.4,17.21 69.4,17.46 69.53,17.59 71.49,17.59
LG_1.35V on IN1 (solid shape): 62.99,19.69 62.99,19.49 62.67,19.18 61.84,19.18 61.65,19.37 61.65,20.26 61.78,20.38 62.29,20.38
LG_1.35V on IN1 (solid shape): 69.34,17.65 70.35,17.65 70.54,17.46 70.54,17.21 70.41,17.08 68.76,17.08 68.57,17.27 68.57,17.59 68.89,17.91 69.08,17.91
LG_3V on TOP (solid shape): 37.52,41.4 37.52,41.15 36.89,40.51 36.12,40.51 36,40.64 36,41.02 36.51,41.53 37.39,41.53
LG_3V on TOP (solid shape): 41.23,49.75 41.23,48.79 40.89,48.45 40.89,48.2 40.76,48.07 40.51,48.07 40.38,48.2 40.38,49.15 41.03,49.8 41.18,49.8
LG_3V on IN1 (solid shape): 41.01,48.96 41.01,47.24 40.89,47.12 40.38,47.12 40.25,47.24 40.25,47.75 40.38,47.88 40.38,49.09 40.51,49.21 40.76,49.21
LG_3V on IN1 (solid shape): 37.52,42.16 37.52,41.15 37.33,40.96 36.57,40.96 36.38,41.15 36.38,41.4 36.7,41.72 36.7,42.29 36.76,42.35 37.33,42.35
LG_5V on TOP (solid shape): 41.59,38.73 41.59,37.97 41.46,37.85 40.44,37.85 40.32,37.97 40.32,38.61 40.57,38.86 41.46,38.86
LG_5V on TOP (solid shape): 44,48.58 44,48.39 43.87,48.26 43.62,48.26 43.17,48.7 42.73,48.7 42.6,48.83 42.6,49.72 42.67,49.78 42.79,49.78
LG_5V on IN1 (solid shape): 41.46,38.93 41.46,37.97 41.33,37.85 40.44,37.85 40.32,37.97 40.32,38.73 40.7,39.12 41.27,39.12
LG_5V on IN1 (solid shape): 44,48.58 44,48.39 43.74,48.13 43.74,47.82 43.62,47.69 43.11,47.69 42.98,47.82 42.98,49.09 43.11,49.21 43.36,49.21
LG_NB on TOP (solid shape): 122.96,154.54 122.96,154.26 122.84,154.14 122,154.14 121.86,154.01 120.6,154.01 120.53,154.07 120.53,154.15 120.6,154.22 121.61,154.22 121.81,154.42 121.81,154.51 121.97,154.67 122.83,154.67
LG_NB on BOTTOM (solid shape): 129.98,141.6 129.98,140.14 129.72,139.89 129.41,139.89 129.28,140.02 129.28,141.67 129.47,141.86 129.72,141.86
LG_NB on IN1 (solid shape): 129.98,141.6 129.98,140.08 129.79,139.89 129.41,139.89 129.22,140.08 129.22,141.54 129.41,141.73 129.85,141.73
LG_NB on IN1 (solid shape): 123.63,154.88 123.63,154.31 123.5,154.18 121.98,154.18 121.85,154.31 121.85,154.56 122.04,154.75 122.8,154.75 123.06,155 123.5,155
LG_VDDP_ALWP on TOP (solid shape): 138.36,147.26 138.36,146.81 138.23,146.69 137.34,146.69 137.22,146.81 137.22,147.57 137.28,147.64 137.98,147.64
LG_VDDP_ALWP on BOTTOM (solid shape): 139.06,147.26 139.06,146.62 138.99,146.56 137.41,146.56 137.22,146.75 137.22,147.13 137.41,147.32 138.99,147.32
LG_VDDP_ALWP on BOTTOM (solid shape): 146.87,144.27 146.87,142.49 146.61,142.24 146.23,142.24 146.11,142.37 146.11,144.27 146.23,144.4 146.74,144.4
LGATE_CHG on BOTTOM (solid shape): 136.33,169.04 136.33,168.15 136.2,168.02 135.44,168.02 135.31,168.15 135.31,168.97 135.5,169.16 136.2,169.16
LGATE_CHG on BOTTOM (solid shape): 120.97,167.51 120.97,167.34 120.82,167.19 120,167.19 119.83,167.36 118.59,167.36 118.53,167.42 118.53,167.51 118.59,167.57 119.39,167.57 119.48,167.66 120.82,167.66
LGATE_CHG on IN2 (solid shape): 136.33,169.04 136.33,168.15 136.2,168.02 135.31,168.02 134.99,168.34 134.99,168.78 135.38,169.16 136.2,169.16
LGATE_CHG on IN2 (solid shape): 121.66,167.83 121.66,167.32 121.53,167.2 120.01,167.2 119.88,167.32 119.88,167.58 120.01,167.7 120.83,167.7 121.09,167.96 121.53,167.96
LX1_APU on TOP (solid shape): 120.71,139.95 120.71,134.11 120.58,133.98 117.28,133.98 116.77,134.49 116.77,140.72 116.9,140.84 119.82,140.84
LX1_APU on TOP (solid shape): 117.67,152.69 117.67,151.43 117.87,151.24 117.87,150.37 118.14,150.1 118.14,149.41 118.06,149.33 117.28,149.33 117.19,149.42 117.19,150.08 117.4,150.29 117.4,151.32 117.46,151.38 117.46,152.69 117.52,152.75 117.61,152.75
LX1_APU on BOTTOM (solid shape): outline of 89 points within 111.56,133.98 122.23,143.26
LX1_APU on IN2 (solid shape): 119.82,138.94 119.82,137.92 119.69,137.79 118.67,137.79 118.55,137.92 118.55,138.81 119.06,139.32 119.44,139.32
LX1_APU on IN2 (solid shape): 117.87,151.3 117.87,150.41 118.29,149.99 118.29,149.48 118.17,149.35 117.66,149.35 117.53,149.48 117.53,149.73 117.4,149.86 117.4,151.26 117.5,151.35 117.82,151.35
LX1_GFX on TOP (solid shape): 61.78,53.34 61.78,48.39 61.65,48.26 59.49,48.26 59.11,48.64 59.11,51.94 60.64,53.47 61.65,53.47
LX1_GFX on TOP (solid shape): 60.95,40.83 60.95,40 60.76,39.81 60.76,38.73 60.51,38.48 60.51,37.27 60.43,37.2 60.31,37.2 60.25,37.25 60.25,40.83 60.32,40.89 60.89,40.89
LX1_GFX on BOTTOM (solid shape): 65.84,56.51 65.84,55.05 65.72,54.93 63.05,54.93 63.05,54.04 65.59,54.04 65.72,53.91 65.72,52.64 67.68,50.67 73.65,50.67 73.78,50.55 73.78,49.47 73.72,49.4 71.75,49.4 71.11,48.77 71.11,45.97 71.05,45.91 61.21,45.91 61.14,45.97 61.14,47.05 60.06,48.13 59.62,48.13 59.24,48.51 59.24,55.24 60.7,56.71 65.65,56.71
LX1_GFX on IN2 (solid shape): 60.38,48.77 60.38,47.88 60,47.5 59.49,47.5 59.24,47.75 59.24,48.77 59.37,48.89 60.25,48.89
LX1_GFX on IN2 (solid shape): 61.02,40.45 61.02,40.13 60.76,39.88 60.76,38.73 60.64,38.61 60.38,38.61 60.25,38.73 60.25,40.45 60.38,40.58 60.89,40.58
LX1_VGA on BOTTOM (solid shape): 176.3,93.33 176.3,92.52 176.18,92.4 175.35,92.4 175.25,92.5 175.25,92.86 175.04,93.07 174.07,93.07 173.78,92.78 172.37,92.78 172.31,92.83 172.31,92.94 172.37,92.99 173.5,92.99 174.05,93.54 176.09,93.54
LX1_VGA on BOTTOM (solid shape): 182.37,111.38 182.37,110.05 179.76,110.05 179.76,109.16 182.37,109.16 185.29,106.24 187.83,106.24 188.27,105.79 188.27,101.35 187.89,100.96 177.79,100.96 177.16,100.33 175.44,100.33 175.38,100.39 175.38,101.41 175.44,101.47 176.97,101.47 178.17,102.68 178.17,103.31 177.79,103.7 176.14,103.7 175.95,103.89 175.95,107.76 179.7,111.51 182.24,111.51
LX1_VGA on IN2 (solid shape): 177.92,104.97 177.92,103.5 177.79,103.38 177.29,103.38 177.16,103.5 177.16,105.09 177.29,105.22 177.67,105.22
LX1_VGA on IN2 (solid shape): 175.95,93.66 175.95,93.41 175.61,93.07 174.07,93.07 173.92,93.22 173.92,93.41 174.05,93.54 175,93.54 175.32,93.85 175.76,93.85
LX2_VGA on BOTTOM (solid shape): 176.48,91.36 176.48,90.48 176.4,90.4 174.19,90.4 173.81,90.77 172.37,90.77 172.31,90.84 172.31,90.93 172.38,91 173.97,91 174.1,90.87 175.11,90.87 175.31,91.06 175.31,91.3 175.44,91.44 176.4,91.44
LX2_VGA on BOTTOM (solid shape): 193.35,107.82 194.37,107.82 194.37,110.36 197.22,110.36 197.61,109.98 197.61,88.39 197.35,88.14 194.94,88.14 194.68,88.39 194.68,91.44 194.05,92.07 190.94,92.07 190.81,92.2 190.81,93.22 190.94,93.34 190.94,109.85 191.45,110.36 193.35,110.36
LX2_VGA on IN2 (solid shape): 191.45,93.29 191.45,92.33 191.06,91.95 190.11,91.95 189.99,92.07 189.99,92.39 190.94,93.34 191.4,93.34
LX2_VGA on IN2 (solid shape): 175.32,90.68 175.76,90.68 175.89,90.55 175.89,89.98 175.82,89.92 175.25,89.92 174.81,90.36 174.17,90.36 174.05,90.49 174.05,90.74 174.17,90.87 175.13,90.87
LX_1.8V_ALWP on BOTTOM (solid shape): 157.66,47.24 157.66,46.1 157.03,45.47 157.03,44.45 156.9,44.32 156.77,44.32 156.65,44.45 156.65,45.21 156.39,45.47 156.01,45.47 155.76,45.21 155.76,44.45 155.63,44.32 155,44.32 154.87,44.45 154.87,45.47 154.62,45.72 153.85,45.72 153.6,45.97 153.6,47.24 153.73,47.37 157.54,47.37
LX_1.35V on TOP (solid shape): 62.86,20.57 63.81,20.57 63.94,20.45 63.94,18.54 63.81,18.41 63.18,18.41 63.11,18.48 63.11,19.62 62.16,20.57 61.78,20.57 61.72,20.64 61.72,20.76 61.78,20.83 62.6,20.83
LX_1.35V on BOTTOM (solid shape): 80.07,17.91 80.07,15.05 79.88,14.86 75.3,14.86 75.05,14.6 75.05,13.59 74.92,13.46 74.42,13.46 74.35,13.53 74.35,14.6 74.1,14.86 72.19,14.86 72.13,14.92 72.13,19.62 72.26,19.75 78.23,19.75
LX_1.35V on IN2 (solid shape): 73.27,18.29 73.27,17.97 73.08,17.78 71.62,17.78 71.49,17.91 71.49,18.41 71.62,18.54 73.02,18.54
LX_1.35V on IN2 (solid shape): 64.83,20.45 64.83,19.94 64.7,19.81 64.19,19.81 63.94,20.07 62.92,20.07 62.79,20.19 62.79,20.45 62.92,20.57 64.7,20.57
LX_1.35VGPU on BOTTOM (solid shape): 197.22,163.64 197.22,162.5 198.18,161.54 198.56,161.54 198.81,161.29 198.81,159 198.18,158.37 194.31,158.37 194.03,158.09 192.21,158.09 192.16,158.14 192.16,158.42 192.14,158.43 192.14,159.45 192.21,159.51 193.73,159.51 196.02,161.8 196.02,163.64 196.08,163.7 197.16,163.7
LX_3V on TOP (solid shape): 39.81,50.93 40.89,50.93 40.95,50.86 40.95,50.74 40.89,50.67 37.9,50.67 37.84,50.74 37.84,51.63 37.9,51.69 39.05,51.69
LX_3V on TOP (solid shape): 34.6,42.74 34.6,41.66 35.49,40.77 35.49,38.35 34.98,37.85 31.93,37.85 31.81,37.97 31.81,41.72 32.89,42.8 34.54,42.8
LX_3V on BOTTOM (solid shape): 37.14,39.38 37.14,36.07 36.82,35.75 32.82,35.75 31.81,36.77 31.81,40.89 31.93,41.02 35.5,41.02
LX_3V on IN2 (solid shape): 32.95,41.53 32.95,40.51 32.82,40.39 31.93,40.39 31.81,40.51 31.81,41.21 32.38,41.78 32.7,41.78
LX_3V on IN2 (solid shape): 39.68,51.05 39.68,50.8 39.52,50.64 39.27,50.64 38.92,50.29 38.35,50.29 38.16,50.48 38.16,50.93 38.79,51.56 39.17,51.56
LX_5V on TOP (solid shape): 46.28,51.56 46.28,50.74 46.22,50.67 42.96,50.67 42.89,50.74 42.89,50.83 42.96,50.89 44.28,50.89 45.01,51.63 46.22,51.63
LX_5V on TOP (solid shape): 43.74,42.67 43.74,41.78 44.25,41.27 45.9,41.27 46.54,40.64 46.54,37.85 46.28,37.59 42.6,37.59 42.09,38.1 42.09,41.02 41.84,41.27 41.84,42.67 41.97,42.8 43.62,42.8
LX_5V on BOTTOM (solid shape): 46.67,40.39 46.67,36.7 46.16,36.19 41.71,36.19 41.59,36.32 41.59,40.51 41.97,40.89 46.16,40.89
LX_5V on IN2 (solid shape): 45.78,51.12 45.78,50.55 45.46,50.23 45.01,50.23 44.44,50.8 44.44,50.99 45.01,51.56 45.33,51.56
LX_5V on IN2 (solid shape): 46.41,41.27 46.41,40.39 46.28,40.26 45.4,40.26 45.27,40.39 45.27,41.08 45.71,41.53 46.16,41.53
LX_NB on TOP (solid shape): 123.85,154.56 123.85,153.54 123.79,153.48 121.97,153.48 121.84,153.61 120.6,153.61 120.53,153.68 120.53,153.75 120.6,153.82 121.91,153.82 122.07,153.99 123.07,153.99 123.13,154.05 123.13,154.53 123.23,154.63 123.78,154.63
LX_NB on BOTTOM (solid shape): 128.9,139.81 129.04,139.67 130.24,139.67 130.46,139.46 130.46,136.89 130.3,136.73 129.57,136.73 128.23,135.38 125.79,135.38 125.72,135.45 125.72,138.05 124.83,138.05 124.83,135.51 124.77,135.45 123.56,135.45 123.5,135.51 123.5,138.3 126.17,140.97 126.17,145.35 126.23,145.41 128.9,145.41
LX_NB on IN2 (solid shape): 127.18,141.73 127.18,140.21 126.93,139.95 126.61,139.95 126.42,140.14 126.42,141.67 126.55,141.8 127.12,141.8
LX_NB on IN2 (solid shape): 124.01,153.48 124.01,152.72 123.95,152.65 123.31,152.65 123.25,152.72 123.25,153.23 122.99,153.48 121.91,153.48 121.85,153.54 121.85,153.8 121.98,153.92 123.56,153.92
LX_VDDP_ALWP on TOP (solid shape): 143.63,135 143.63,131.76 142.68,130.81 137.6,130.81 137.34,131.06 137.34,135 137.53,135.19 143.44,135.19
